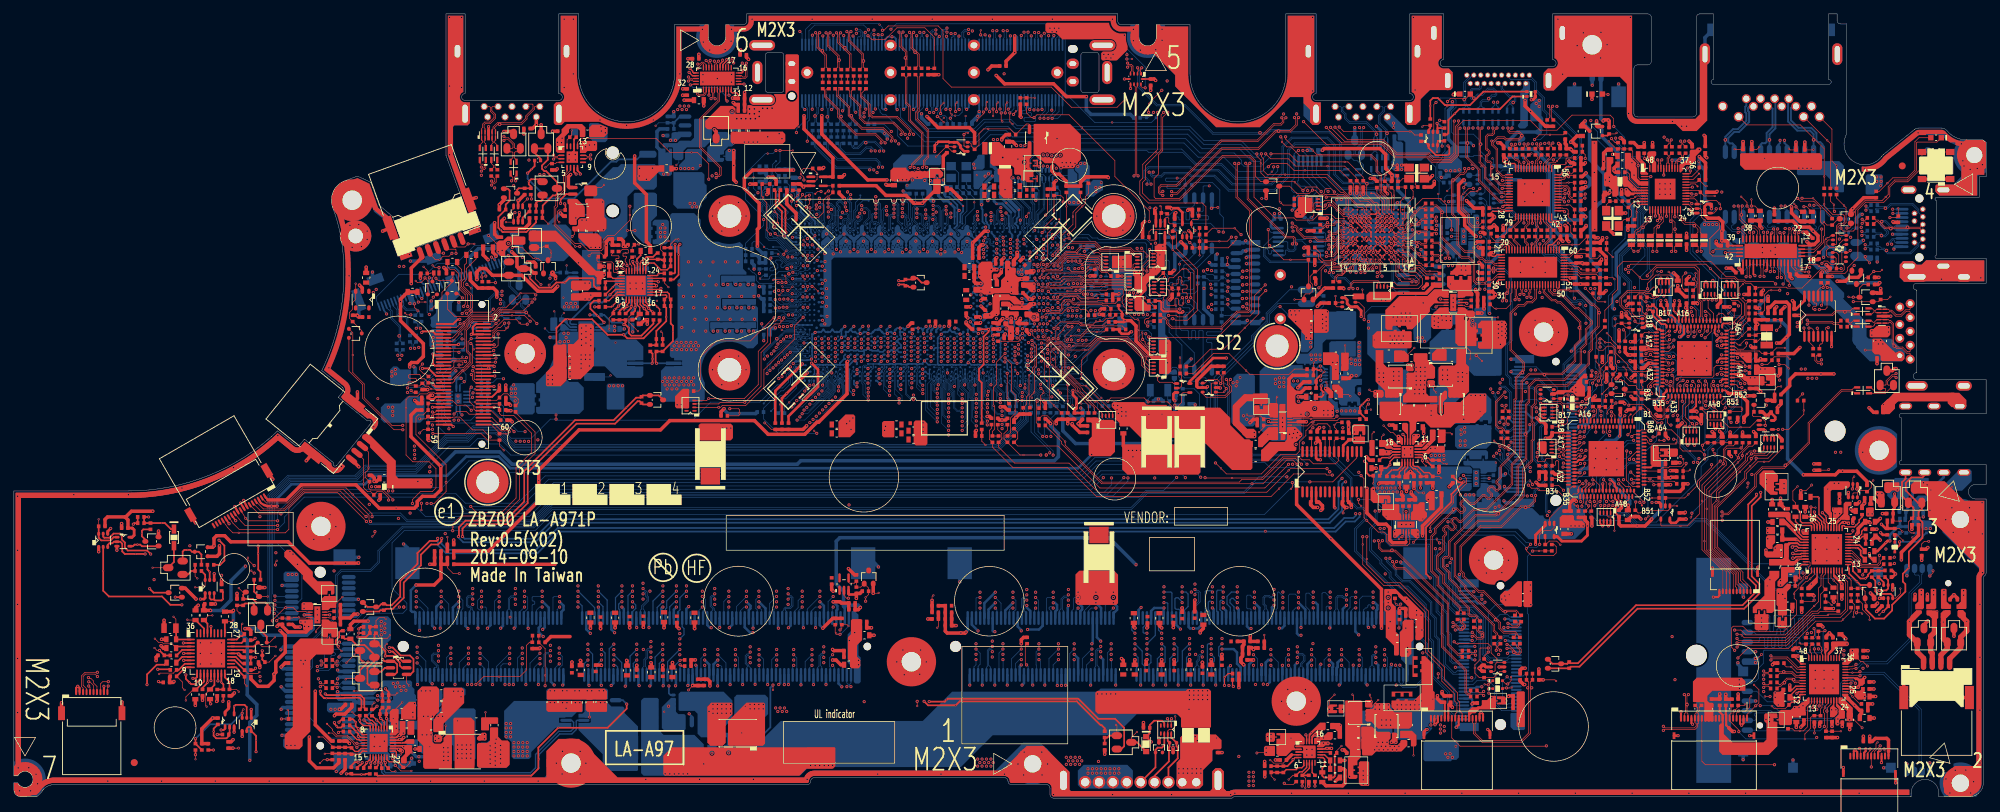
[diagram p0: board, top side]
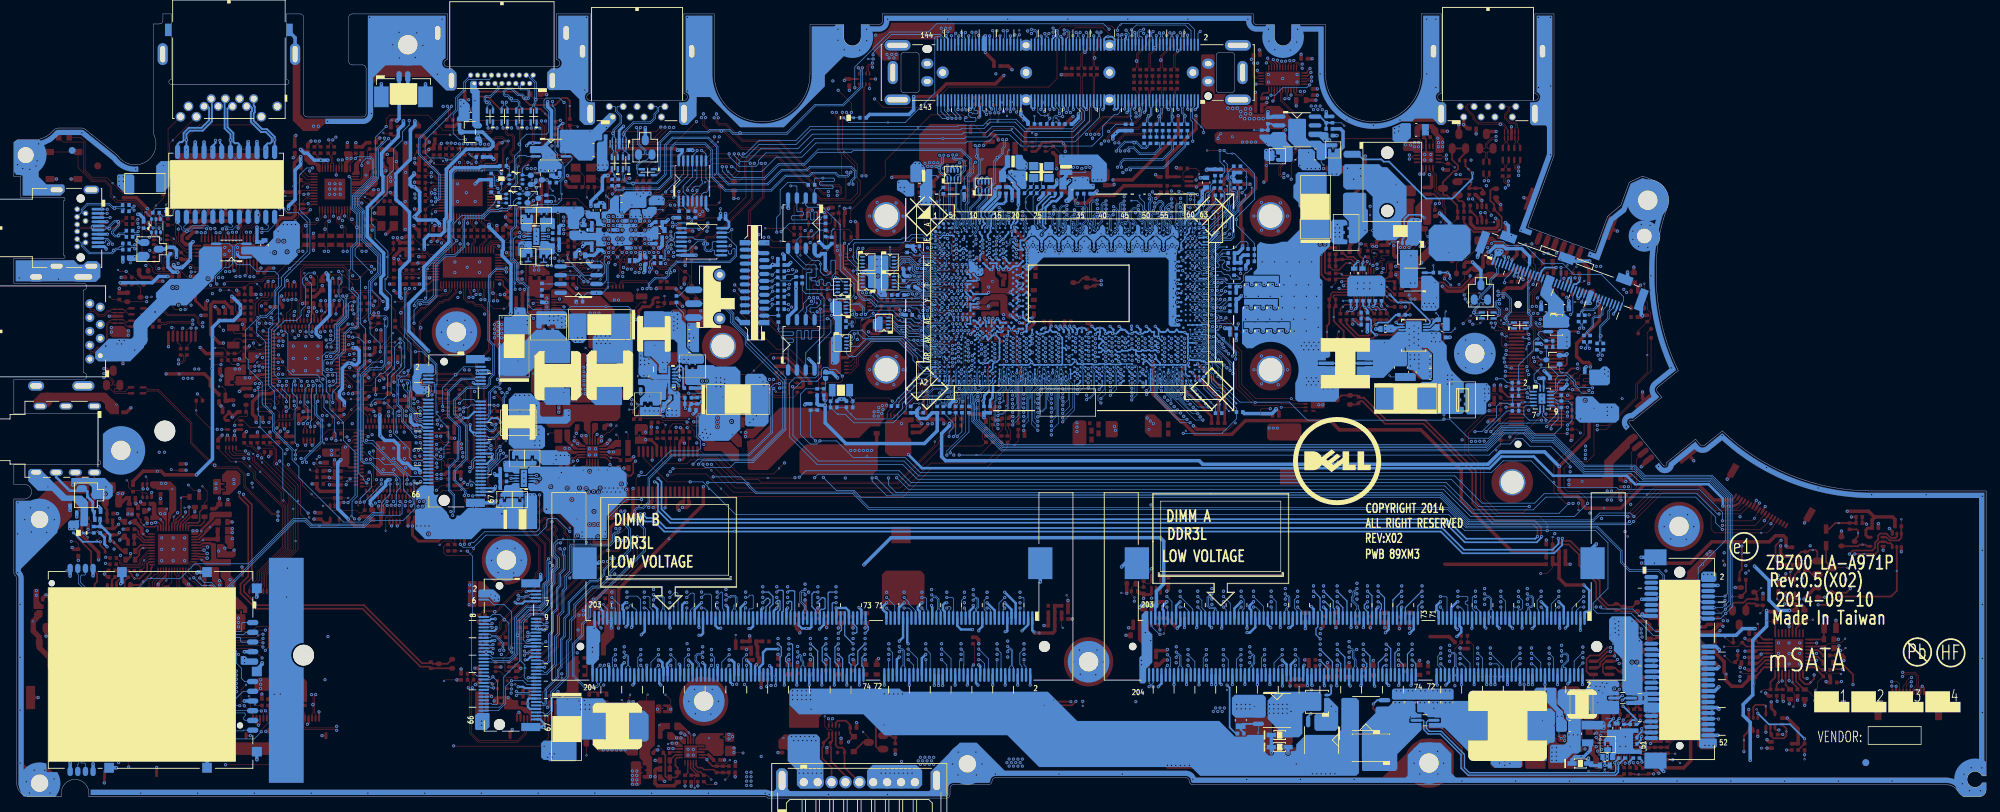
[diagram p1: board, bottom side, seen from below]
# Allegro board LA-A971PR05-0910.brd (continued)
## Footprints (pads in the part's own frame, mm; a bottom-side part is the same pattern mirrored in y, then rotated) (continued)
JUMP_43X39
  custom 0.191x0.191 smd: 1(0,0) 2(0.914,0)
JUMP_43X79
  custom 0.188x0.188 smd: 1(0,0) 2(1.1,0)
JUMP_43X79-NPM
  custom 0.188x0.188 smd: 1(0,0) 2(1.1,0)
JUMP_43X118
  custom 0.187x0.187 smd: 1(0,0) 2(1.1,0)
KC_FBMA-L1_2P-NPM
  rect 1.803x3.404 smd: 1(0,0) 2(3.8,0)
L2N7002WT1G_SC-70-3
  oval 0.711x0.889 smd: 1(0,0) 2(-0.65,-1.9) 3(0.65,-1.9)
L03ESDL5V0CC3-2_SOT23-3
  oval 1.016x1.524 smd: 1(0,0) 2(0.965,2.083) 3(-0.965,2.083)
L05ESDL5V0NA-4_SLP2510P8-10-9
  rect 0.203x0.686 smd: 1(0,0) 2(-0.5,0) 4(-1.5,0) 5(-2,0) 6(-2,-0.875) 7(-1.5,-0.875) 8(-0.5,-0.875) 9(0,-0.875)
  rect 0.406x1.549 smd: 3(-1,-0.437)
L30ESD24VC3-2_SOT23-3
  oval 1.016x1.524 smd: 1(0,0) 2(0.965,2.083) 3(-0.965,2.083)
L_5X5X3_M_2P
  rect 2.159x2.794 smd: 1(0,0) 2(4.35,0)
L_5X5X3_M_2P-NPM
  rect 2.159x2.794 smd: 1(0,0) 2(4.35,0)
LCN_AUF05-1922S10-0019_19P
  round 0.762 hole 0.508: 1(0,0) 2(0.5,1.2) 3(1,0) 4(1.5,1.2) 5(2,0) 6(2.5,1.2) 7(3,0) 8(3.5,1.2) 9(4,0) 10(4.5,1.2) 11(5,0) 12(5.5,1.2) 13(6,0) 14(6.5,1.2) 15(7,0) 16(7.5,1.2) 17(8,0) 18(8.5,1.2) 19(9,0)
  oval 1.397x2.794 hole 0.787x2.21: 20(-2.75,0.77) 21(11.75,0.77)
  oval 1.397x2.591 hole 0.787x2.007: 22(-4.75,-6.08) 23(13.75,-6.08)
LCN_DAN06-K4406-0103_204P
  round 1.092 hole 1.092 unplated: (-65.05,-4.1)
  round 1.6 hole 1.6 unplated: (1.75,-4.1)
  oval 0.356x2.007 smd: 1(0,0) 2(-0.3,-8.2) 3(-0.6,0) 4(-0.9,-8.2) 5(-1.2,0) 6(-1.5,-8.2) 7(-1.8,0) 8(-2.1,-8.2) 9(-2.4,0) 10(-2.7,-8.2) 11(-3,0) 12(-3.3,-8.2) 13(-3.6,0) 14(-3.9,-8.2) 15(-4.2,0) 16(-4.5,-8.2) 17(-4.8,0) 18(-5.1,-8.2) 19(-5.4,0) 20(-5.7,-8.2) 21(-6,0) 22(-6.3,-8.2) 23(-6.6,0) 24(-6.9,-8.2) 25(-7.2,0) 26(-7.5,-8.2) 27(-7.8,0) 28(-8.1,-8.2) 29(-8.4,0) 30(-8.7,-8.2) 31(-9,0) 32(-9.3,-8.2) 33(-9.6,0) 34(-9.9,-8.2) 35(-10.2,0) 36(-10.5,-8.2) 37(-10.8,0) 38(-11.1,-8.2) 39(-11.4,0) 40(-11.7,-8.2) 41(-12,0) 42(-12.3,-8.2) 43(-12.6,0) 44(-12.9,-8.2) 45(-13.2,0) 46(-13.5,-8.2) 47(-13.8,0) 48(-14.1,-8.2) 49(-14.4,0) 50(-14.7,-8.2) 51(-15,0) 52(-15.3,-8.2) 53(-15.6,0) 54(-15.9,-8.2) 55(-16.2,0) 56(-16.5,-8.2) 57(-16.8,0) 58(-17.1,-8.2) 59(-17.4,0) 60(-17.7,-8.2) 61(-18,0) 62(-18.3,-8.2) 63(-18.6,0) 64(-18.9,-8.2) 65(-19.2,0) 66(-19.5,-8.2) 67(-19.8,0) 68(-20.1,-8.2) 69(-20.4,0) 70(-20.7,-8.2) 71(-21,0) 72(-21.3,-8.2) 73(-24,0) 74(-24.3,-8.2) 75(-24.6,0) 76(-24.9,-8.2) 77(-25.2,0) 78(-25.5,-8.2) 79(-25.8,0) 80(-26.1,-8.2) 81(-26.4,0) 82(-26.7,-8.2) 83(-27,0) 84(-27.3,-8.2) 85(-27.6,0) 86(-27.9,-8.2) 87(-28.2,0) 88(-28.5,-8.2) 89(-28.8,0) 90(-29.1,-8.2) 91(-29.4,0) 92(-29.7,-8.2) 93(-30,0) 94(-30.3,-8.2) 95(-30.6,0) 96(-30.9,-8.2) 97(-31.2,0) 98(-31.5,-8.2) 99(-31.8,0) 100(-32.1,-8.2) 101(-32.4,0) 102(-32.7,-8.2) 103(-33,0) 104(-33.3,-8.2) 105(-33.6,0) 106(-33.9,-8.2) 107(-34.2,0) 108(-34.5,-8.2) 109(-34.8,0) 110(-35.1,-8.2) 111(-35.4,0) 112(-35.7,-8.2) 113(-36,0) 114(-36.3,-8.2) 115(-36.6,0) 116(-36.9,-8.2) 117(-37.2,0) 118(-37.5,-8.2) 119(-37.8,0) 120(-38.1,-8.2) 121(-38.4,0) 122(-38.7,-8.2) 123(-39,0) 124(-39.3,-8.2) 125(-39.6,0) 126(-39.9,-8.2) 127(-40.2,0) 128(-40.5,-8.2) 129(-40.8,0) 130(-41.1,-8.2) 131(-41.4,0) 132(-41.7,-8.2) 133(-42,0) 134(-42.3,-8.2) 135(-42.6,0) 136(-42.9,-8.2) 137(-43.2,0) 138(-43.5,-8.2) 139(-43.8,0) 140(-44.1,-8.2) 141(-44.4,0) 142(-44.7,-8.2) 143(-45,0) 144(-45.3,-8.2) 145(-45.6,0) 146(-45.9,-8.2) 147(-46.2,0) 148(-46.5,-8.2) 149(-46.8,0) 150(-47.1,-8.2) 151(-47.4,0) 152(-47.7,-8.2) 153(-48,0) 154(-48.3,-8.2) 155(-48.6,0) 156(-48.9,-8.2) 157(-49.2,0) 158(-49.5,-8.2) 159(-49.8,0) 160(-50.1,-8.2) 161(-50.4,0) 162(-50.7,-8.2) 163(-51,0) 164(-51.3,-8.2) 165(-51.6,0) 166(-51.9,-8.2) 167(-52.2,0) 168(-52.5,-8.2) 169(-52.8,0) 170(-53.1,-8.2) 171(-53.4,0) 172(-53.7,-8.2) 173(-54,0) 174(-54.3,-8.2) 175(-54.6,0) 176(-54.9,-8.2) 177(-55.2,0) 178(-55.5,-8.2) 179(-55.8,0) 180(-56.1,-8.2) 181(-56.4,0) 182(-56.7,-8.2) 183(-57,0) 184(-57.3,-8.2) 185(-57.6,0) 186(-57.9,-8.2) 187(-58.2,0) 188(-58.5,-8.2) 189(-58.8,0) 190(-59.1,-8.2) 191(-59.4,0) 192(-59.7,-8.2) 193(-60,0) 194(-60.3,-8.2) 195(-60.6,0) 196(-60.9,-8.2) 197(-61.2,0) 198(-61.5,-8.2) 199(-61.8,0) 200(-62.1,-8.2) 201(-62.4,0) 202(-62.7,-8.2) 203(-63,0) 204(-63.3,-8.2)
  rect 3.505x4.597 smd: 205(1.15,7.9) 206(-64.45,7.9)
LCN_DAN08-52406-0500_52P
  round 1.6 hole 1.6 unplated: (-0.7,4.1)
  round 1.092 hole 1.092 unplated: (24.3,4.1)
  oval 0.61x2.007 smd: 1(0,0) 2(0.4,8.2) 3(0.8,0) 4(1.2,8.2) 5(1.6,0) 6(2,8.2) 7(2.4,0) 8(2.8,8.2) 9(3.2,0) 10(3.6,8.2) 11(4,0) 12(4.4,8.2) 13(4.8,0) 14(5.2,8.2) 15(5.6,0) 16(6,8.2) 17(9.6,0) 18(10,8.2) 19(10.4,0) 20(10.8,8.2) 21(11.2,0) 22(11.6,8.2) 23(12,0) 24(12.4,8.2) 25(12.8,0) 26(13.2,8.2) 27(13.6,0) 28(14,8.2) 29(14.4,0) 30(14.8,8.2) 31(15.2,0) 32(15.6,8.2) 33(16,0) 34(16.4,8.2) 35(16.8,0) 36(17.2,8.2) 37(17.6,0) 38(18,8.2) 39(18.4,0) 40(18.8,8.2) 41(19.2,0) 42(19.6,8.2) 43(20,0) 44(20.4,8.2) 45(20.8,0) 46(21.2,8.2) 47(21.6,0) 48(22,8.2) 49(22.4,0) 50(22.8,8.2) 51(23.2,0) 52(23.6,8.2)
  rect 2.311x3.2 smd: 53(-2.85,0.6) 54(26.45,0.6)
LED_LTW-193ZDS5_2P
  rect 0.787x0.787 smd: 1(0,0) 2(1.5,0)
LED_LTW-295DSKS-5A_4P
  rect 0.508x0.406 smd: 1(0,0) 2(1.2,0) 3(0,0.7) 4(1.2,0.7)
LP2301ALT1G_SOT23-3
  oval 1.016x1.524 smd: 1(0,0) 2(0.965,2.083) 3(-0.965,2.083)
MEC5085-LZY_DQFN132_11X11
  oval 0.279x0.711 smd: A1(0,0) A2(0.5,0) A3(1,0) A4(1.5,0) A5(2,0) A6(2.5,0) A7(3,0) A8(3.5,0) A9(4,0) A10(4.5,0) A11(5,0) A12(5.5,0) A13(6,0) A14(6.5,0) A15(7,0) A16(7.5,0) A33(7.5,10.9) A34(7,10.9) A35(6.5,10.9) A36(6,10.9) A37(5.5,10.9) A38(5,10.9) A39(4.5,10.9) A40(4,10.9) A41(3.5,10.9) A42(3,10.9) A43(2.5,10.9) A44(2,10.9) A45(1.5,10.9) A46(1,10.9) A47(0.5,10.9) A48(0,10.9)
  oval 0.711x0.279 smd: A17(9.2,1.7) A18(9.2,2.2) A19(9.2,2.7) A20(9.2,3.2) A21(9.2,3.7) A22(9.2,4.2) A23(9.2,4.7) A24(9.2,5.2) A25(9.2,5.7) A26(9.2,6.2) A27(9.2,6.7) A28(9.2,7.2) A29(9.2,7.7) A30(9.2,8.2) A31(9.2,8.7) A32(9.2,9.2) A49(-1.7,9.2) A50(-1.7,8.7) A51(-1.7,8.2) A52(-1.7,7.7) A53(-1.7,7.2) A54(-1.7,6.7) A55(-1.7,6.2) A56(-1.7,5.7) A57(-1.7,5.2) A58(-1.7,4.7) A59(-1.7,4.2) A60(-1.7,3.7) A61(-1.7,3.2) A62(-1.7,2.7) A63(-1.7,2.2) A64(-1.7,1.7)
  oval 0.305x0.61 smd: B1(-0.25,0.85) B2(0.25,0.85) B3(0.75,0.85) B4(1.25,0.85) B5(1.75,0.85) B6(2.25,0.85) B7(2.75,0.85) B8(3.25,0.85) B9(3.75,0.85) B10(4.25,0.85) B11(4.75,0.85) B12(5.25,0.85) B13(5.75,0.85) B14(6.25,0.85) B15(6.75,0.85) B16(7.25,0.85) B17(7.75,0.85) B35(7.75,10.05) B36(7.25,10.05) B37(6.75,10.05) B38(6.25,10.05) B39(5.75,10.05) B40(5.25,10.05) B41(4.75,10.05) B42(4.25,10.05) B43(3.75,10.05) B44(3.25,10.05) B45(2.75,10.05) B46(2.25,10.05) B47(1.75,10.05) B48(1.25,10.05) B49(0.75,10.05) B50(0.25,10.05) B51(-0.25,10.05)
  oval 0.61x0.305 smd: B18(8.35,1.45) B19(8.35,1.95) B20(8.35,2.45) B21(8.35,2.95) B22(8.35,3.45) B23(8.35,3.95) B24(8.35,4.45) B25(8.35,4.95) B26(8.35,5.45) B27(8.35,5.95) B28(8.35,6.45) B29(8.35,6.95) B30(8.35,7.45) B31(8.35,7.95) B32(8.35,8.45) B33(8.35,8.95) B34(8.35,9.45) B52(-0.85,9.45) B53(-0.85,8.95) B54(-0.85,8.45) B55(-0.85,7.95) B56(-0.85,7.45) B57(-0.85,6.95) B58(-0.85,6.45) B59(-0.85,5.95) B60(-0.85,5.45) B61(-0.85,4.95) B62(-0.85,4.45) B63(-0.85,3.95) B64(-0.85,3.45) B65(-0.85,2.95) B66(-0.85,2.45) B67(-0.85,1.95) B68(-0.85,1.45)
  rect 5.004x5.004 smd: C1(3.75,5.45)
MHPC_NS692417_24P
  oval 0.762x2.057 smd: 1(0,0) 2(1.27,0) 3(2.54,0) 4(3.81,0) 5(5.08,0) 6(6.35,0) 7(7.62,0) 8(8.89,0) 9(10.16,0) 10(11.43,0) 11(12.7,0) 12(13.97,0) 13(13.97,9.365) 14(12.7,9.365) 15(11.43,9.365) 16(10.16,9.365) 17(8.89,9.365) 18(7.62,9.365) 19(6.35,9.365) 20(5.08,9.365) 21(3.81,9.365) 22(2.54,9.365) 23(1.27,9.365) 24(0,9.365)
MMBT3904WT1G_SC70-3
  oval 0.711x0.889 smd: 1(0,0) 2(0.65,1.9) 3(-0.65,1.9)
MMST3904-7-F_SOT323-3
  oval 0.711x0.889 smd: 1(0,0) 2(0.65,1.9) 3(-0.65,1.9)
MURAT_BLM15AG102SN1D_2P
  rect 0.457x0.508 smd: 1(0,0) 2(0.85,0)
MURAT_BLM15BB221SN1D_2P
  rect 0.508x0.762 smd: 1(0,0) 2(0.75,0)
MURAT_BLM15BD601SN1D_2P
  rect 0.508x0.762 smd: 1(0,0) 2(0.75,0)
MURAT_BLM15PX181SN1D_2P
  rect 0.508x0.762 smd: 1(0,0) 2(0.75,0)
MURAT_BLM15PX330SN1D_2P
  rect 0.508x0.762 smd: 1(0,0) 2(0.75,0)
MURAT_BLM15PX600SN1D_2P
  rect 0.457x0.508 smd: 1(0,0) 2(0.85,0)
MURAT_DLW21HN900HQ2L_4P
  rect 0.889x0.356 smd: 1(0,0) 2(1.7,0) 3(1.7,0.85) 4(0,0.85)
MURAT_LQM2MPN2R2NG0L_2P
  rect 0.787x1.803 smd: 1(0,0) 2(1.6,0)
NTGD4161PT1G_TSOP6
  oval 0.508x1.422 smd: 1(0,0) 2(0.95,0) 3(1.9,0) 4(1.9,2.35) 5(0.95,2.35) 6(0,2.35)
NTR4502PT1G_SOT23-3
  oval 1.016x1.524 smd: 1(0,0) 2(0.965,2.083) 3(-0.965,2.083)
NX3DV221GM_XQFN10U10_2X1P55
  oval 0.305x0.533 smd: 1(0,0)
  oval 0.254x0.533 smd: 2(0.526,0) 3(1.025,0) 4(1.526,0) 6(1.526,1.475) 7(1.025,1.475) 8(0.526,1.475) 9(0.025,1.475)
  oval 0.533x0.254 smd: 5(1.75,0.738) 10(-0.2,0.738)
OZ777FJ2LN_QFN48_6X6
  oval 0.203x0.889 smd: 1(0,0) 2(0.4,0) 3(0.8,0) 4(1.2,0) 5(1.6,0) 6(2,0) 7(2.4,0) 8(2.8,0) 9(3.2,0) 10(3.6,0) 11(4,0) 12(4.4,0) 25(4.4,6.1) 26(4,6.1) 27(3.6,6.1) 28(3.2,6.1) 29(2.8,6.1) 30(2.4,6.1) 31(2,6.1) 32(1.6,6.1) 33(1.2,6.1) 34(0.8,6.1) 35(0.4,6.1) 36(0,6.1)
  oval 0.889x0.203 smd: 13(5.25,0.85) 14(5.25,1.25) 15(5.25,1.65) 16(5.25,2.05) 17(5.25,2.45) 18(5.25,2.85) 19(5.25,3.25) 20(5.25,3.65) 21(5.25,4.05) 22(5.25,4.45) 23(5.25,4.85) 24(5.25,5.25) 37(-0.85,5.25) 38(-0.85,4.85) 39(-0.85,4.45) 40(-0.85,4.05) 41(-0.85,3.65) 42(-0.85,3.25) 43(-0.85,2.85) 44(-0.85,2.45) 45(-0.85,2.05) 46(-0.85,1.65) 47(-0.85,1.25) 48(-0.85,0.85)
  rect 4.343x4.343 smd: 49(2.2,3.05)
PANAS_ETQP3W2R2WFN_2P
  rect 2.362x3.505 smd: 1(0,0) 2(-6.05,0)
PANAS_ETQP4LR15AFM_4P
  custom 0.686x0.686 smd: 1(0,0) 4(8.357,0)
  rect 2.21x0.508 smd: 2(1.448,0) 3(6.909,0)
PDS5100H-13_POWERDI5-3
  rect 4.851x3.353 smd: 1(0,0)
  rect 1.397x1.397 smd: 2(3.982,-0.92) 3(3.982,0.92)
PI3C3125LEX_TSSOP14
  oval 0.381x1.626 smd: 1(0,0) 2(0.65,0) 3(1.3,0) 4(1.95,0) 5(2.6,0) 6(3.25,0) 7(3.9,0) 8(3.9,5.8) 9(3.25,5.8) 10(2.6,5.8) 11(1.95,5.8) 12(1.3,5.8) 13(0.65,5.8) 14(0,5.8)
PI3L720ZHEX_TQFN42_9X3P5
  oval 0.254x1.041 smd: 1(0,0) 2(0.5,0) 3(1,0) 4(1.5,0) 5(2,0) 6(2.5,0) 7(3,0) 8(3.5,0) 9(4,0) 10(4.5,0) 11(5,0) 12(5.5,0) 13(6,0) 14(6.5,0) 15(7,0) 16(7.5,0) 17(8,0) 22(8,3.45) 23(7.5,3.45) 24(7,3.45) 25(6.5,3.45) 26(6,3.45) 27(5.5,3.45) 28(5,3.45) 29(4.5,3.45) 30(4,3.45) 31(3.5,3.45) 32(3,3.45) 33(2.5,3.45) 34(2,3.45) 35(1.5,3.45) 36(1,3.45) 37(0.5,3.45) 38(0,3.45)
  oval 1.041x0.254 smd: 18(8.475,0.975) 19(8.475,1.475) 20(8.475,1.975) 21(8.475,2.475) 39(-0.475,2.475) 40(-0.475,1.975) 41(-0.475,1.475) 42(-0.475,0.975)
  rect 7.544x2.057 smd: 43(4,1.725)
PI3USB3102ZLEX_TQFN32_6X3
  oval 0.203x0.864 smd: 1(0,0) 2(0.4,0) 3(0.8,0) 4(1.2,0) 5(1.6,0) 6(2,0) 7(2.4,0) 8(2.8,0) 9(3.2,0) 10(3.6,0) 11(4,0) 17(4,3.126) 18(3.6,3.126) 19(3.2,3.126) 20(2.8,3.126) 21(2.4,3.126) 22(2,3.126) 23(1.6,3.126) 24(1.2,3.126) 25(0.8,3.126) 26(0.4,3.126) 27(0,3.126)
  oval 0.864x0.203 smd: 12(5.063,0.763) 13(5.063,1.163) 14(5.063,1.563) 15(5.063,1.963) 16(5.063,2.363) 28(-1.063,2.363) 29(-1.063,1.963) 30(-1.063,1.563) 31(-1.063,1.163) 32(-1.063,0.763)
  rect 5.004x2.007 smd: 33(2,1.563)
PS8338BQFN60GTR-A0_QFN60_5X9
  oval 0.203x1.016 smd: 1(0,0) 2(0.4,0) 3(0.8,0) 4(1.2,0) 5(1.6,0) 6(2,0) 7(2.4,0) 8(2.8,0) 9(3.2,0) 10(3.6,0) 11(4,0) 12(4.4,0) 13(4.8,0) 14(5.2,0) 15(5.6,0) 16(6,0) 17(6.4,0) 18(6.8,0) 19(7.2,0) 20(7.6,0) 31(7.6,4.975) 32(7.2,4.975) 33(6.8,4.975) 34(6.4,4.975) 35(6,4.975) 36(5.6,4.975) 37(5.2,4.975) 38(4.8,4.975) 39(4.4,4.975) 40(4,4.975) 41(3.6,4.975) 42(3.2,4.975) 43(2.8,4.975) 44(2.4,4.975) 45(2,4.975) 46(1.6,4.975) 47(1.2,4.975) 48(0.8,4.975) 49(0.4,4.975) 50(0,4.975)
  oval 1.016x0.203 smd: 21(8.288,0.688) 22(8.288,1.088) 23(8.288,1.488) 24(8.288,1.888) 25(8.288,2.288) 26(8.288,2.688) 27(8.288,3.088) 28(8.288,3.488) 29(8.288,3.888) 30(8.288,4.288) 51(-0.688,4.288) 52(-0.688,3.888) 53(-0.688,3.488) 54(-0.688,3.088) 55(-0.688,2.688) 56(-0.688,2.288) 57(-0.688,1.888) 58(-0.688,1.488) 59(-0.688,1.088) 60(-0.688,0.688)
  rect 7.01x2.997 smd: 61(3.8,2.488)
PS8339BQFN56GTR2-A0_QFN56_7X7
  oval 0.203x1.041 smd: 1(0,0) 2(0.4,0) 3(0.8,0) 4(1.2,0) 5(1.6,0) 6(2,0) 7(2.4,0) 8(2.8,0) 9(3.2,0) 10(3.6,0) 11(4,0) 12(4.4,0) 13(4.8,0) 14(5.2,0) 29(5.2,6.95) 30(4.8,6.95) 31(4.4,6.95) 32(4,6.95) 33(3.6,6.95) 34(3.2,6.95) 35(2.8,6.95) 36(2.4,6.95) 37(2,6.95) 38(1.6,6.95) 39(1.2,6.95) 40(0.8,6.95) 41(0.4,6.95) 42(0,6.95)
  oval 1.041x0.203 smd: 15(6.075,0.875) 16(6.075,1.275) 17(6.075,1.675) 18(6.075,2.075) 19(6.075,2.475) 20(6.075,2.875) 21(6.075,3.275) 22(6.075,3.675) 23(6.075,4.075) 24(6.075,4.475) 25(6.075,4.875) 26(6.075,5.275) 27(6.075,5.675) 28(6.075,6.075) 43(-0.875,6.075) 44(-0.875,5.675) 45(-0.875,5.275) 46(-0.875,4.875) 47(-0.875,4.475) 48(-0.875,4.075) 49(-0.875,3.675) 50(-0.875,3.275) 51(-0.875,2.875) 52(-0.875,2.475) 53(-0.875,2.075) 54(-0.875,1.675) 55(-0.875,1.275) 56(-0.875,0.875)
  rect 4.699x3.912 smd: 57(2.6,3.475)
R0402_0OHM
  rect 0.508x0.559 smd: 1(0,0) 2(0.914,0)
R0603_0OHM
  rect 0.635x0.889 smd: 1(0,0) 2(1.397,0)
R0805_0OHM
  rect 0.813x1.397 smd: 1(0,0) 2(1.702,0)
R_0402
  rect 0.508x0.559 smd: 1(0,0) 2(0.914,0)
R_0603
  rect 0.635x0.889 smd: 1(0,0) 2(1.397,0)
R_0805
  rect 0.813x1.397 smd: 1(0,0) 2(1.702,0)
R_1206
  rect 1.016x1.651 smd: 1(0,0) 2(2.667,0)
R_1206_4P-D
  custom 0.445x0.445 smd: 1(0,0) 4(5.004,0)
  custom 0.114x0.114 smd: 2(1.194,0) 3(3.81,0)
RB751S40T1G_SOD523-2
  rect 0.406x0.406 smd: 1(0,0) 2(1.4,0)
RB751V-40_SOD323-2
  rect 0.787x0.889 smd: 1(0,0) 2(2.14,0)
RP_0804_8P4R
  oval 0.66x0.254 smd: 1(0,0) 2(0,-0.5) 3(0,-1) 4(0,-1.5) 5(1.15,-1.5) 6(1.15,-1) 7(1.15,-0.5) 8(1.15,0)
RT8207MZQW_WQFN20_3X3
  oval 0.203x0.889 smd: 1(0,0) 2(0.4,0) 3(0.8,0) 4(1.2,0) 5(1.6,0) 11(1.6,3.1) 12(1.2,3.1) 13(0.8,3.1) 14(0.4,3.1) 15(0,3.1)
  oval 0.889x0.203 smd: 6(2.35,0.75) 7(2.35,1.15) 8(2.35,1.55) 9(2.35,1.95) 10(2.35,2.35) 16(-0.75,2.35) 17(-0.75,1.95) 18(-0.75,1.55) 19(-0.75,1.15) 20(-0.75,0.75)
  rect 1.702x1.702 smd: 21(0.8,1.55)
RT9818A-44GU3_SC70-3
  oval 0.61x0.787 smd: 1(0,0) 2(-0.65,-1.9) 3(0.65,-1.9)
SAMTE_BSH-030-01-L-D-A_60P
  round 1.016 hole 1.016 unplated: (-2.81,5.53) (17.316,5.53)
  oval 0.279x2.261 smd: 1(0,0) 2(0,5.728) 3(0.5,0) 4(0.5,5.728) 5(1,0) 6(1,5.728) 7(1.5,0) 8(1.5,5.728) 9(2,0) 10(2,5.728) 11(2.5,0) 12(2.5,5.728) 13(3,0) 14(3,5.728) 15(3.5,0) 16(3.5,5.728) 17(4,0) 18(4,5.728) 19(4.5,0) 20(4.5,5.728) 21(5,0) 22(5,5.728) 23(5.5,0) 24(5.5,5.728) 25(6,0) 26(6,5.728) 27(6.5,0) 28(6.5,5.728) 29(7,0) 30(7,5.728) 31(7.5,0) 32(7.5,5.728) 33(8,0) 34(8,5.728) 35(8.5,0) 36(8.5,5.728) 37(9,0) 38(9,5.728) 39(9.5,0) 40(9.5,5.728) 41(10,0) 42(10,5.728) 43(10.5,0) 44(10.5,5.728) 45(11,0) 46(11,5.728) 47(11.5,0) 48(11.5,5.728) 49(12,0) 50(12,5.728) 51(12.5,0) 52(12.5,5.728) 53(13,0) 54(13,5.728) 55(13.5,0) 56(13.5,5.728) 57(14,0) 58(14,5.728) 59(14.5,0) 60(14.5,5.728)
SANTA_130456-511_13P-T
  round 1.295 hole 0.889: 1(0,0) 2(1.02,1.1) 3(2.04,0) 4(3.06,1.1) 5(4.08,0) 6(5.1,1.1) 7(6.12,0) 8(7.14,1.1)
  round 1.397 hole 0.991: 9(-3.395,1.1) 10(-1.105,2.6) 11(8.245,2.6) 12(9.39,1.1) 13(10.535,2.6)
  oval 1.473x3.15 hole 0.711x2.388: 14(13.095,-6.42) 16(-5.955,-6.42)
  rect 0.889x1.803 smd: 15(12.32,-9.92) 17(-5.18,-9.92)
SANTA_373070-2_9P
  round 1.016 hole 0.711: 1(0,0) 2(-2.5,0) 3(-4.5,0) 4(-7,0) 5(-7.5,-1.5) 6(-5.5,-1.5) 7(-3.5,-1.5) 8(-1.5,-1.5) 9(0.5,-1.5)
  oval 1.397x3.2 hole 0.787x2.591: 10(-10.25,-0.47) 11(3.25,-0.47)
  oval 1.397x2.388 hole 0.787x1.803: 12(-11.35,-9.47) 13(4.35,-9.47)
SDMK0340L-7-F_SOD323-2
  rect 1.346x0.66 smd: 1(0,0) 2(2.4,0)
SHORTPADS
  custom 0.19x0.19 smd: 1(-0.483,0) 2(0.483,0)
SI2301CDS-T1-GE3_SOT23-3
  oval 1.016x1.524 smd: 1(0,0) 2(0.965,2.083) 3(-0.965,2.083)
SI3456DDV-T1-GE3_TSOP6
  oval 0.508x1.422 smd: 1(0,0) 2(0.95,0) 3(1.9,0) 4(1.9,2.44) 5(0.95,2.44) 6(0,2.44)
SI4835DDY-T1-GE3_SO8
  oval 0.635x1.727 smd: 1(0,0) 2(1.27,0) 3(2.54,0) 4(3.81,0) 5(3.81,5.285) 6(2.54,5.285) 7(1.27,5.285) 8(0,5.285)
SI7121DN-T1-GE3_POWERPAK8-5
  oval 0.406x0.991 smd: 1(0,0) 2(0.66,0) 3(1.32,0) 4(1.98,0)
  custom 0.559x0.559 smd: 5(0.99,2.247)
SI7716ADN-T1-GE3_POWERPAK8-5
  oval 0.406x0.991 smd: 1(0,0) 2(0.66,0) 3(1.32,0) 4(1.98,0)
  custom 0.559x0.559 smd: 5(0.99,2.247)
SINGA_2SJ3080-003111F_6P
  oval 0.991x1.905 hole 0.61x1.397: 1(0,0) 2(-9.55,5.5) 3(0,7.8) 4(-9.55,8.4) 5(-9.55,0) 6(-9.55,2.75) 7(0,4.1)
SIS412DN-T1-GE3_POWERPAK8-5
  oval 0.406x0.991 smd: 1(0,0) 2(0.66,0) 3(1.32,0) 4(1.98,0)
  custom 0.559x0.559 smd: 5(0.99,2.247)
SW_SKRBAAE010_4P
  rect 0.889x1.219 smd: 1(0,0) 2(3.9,0) 3(0,4.075) 4(3.9,4.075)
SW_SS3-CMFTQR9_3P
  oval 0.991x2.489 smd: 1(0,0) 2(2,0) 3(4,0)
  round 1.651 hole 0.889: 4(-0.15,-3.75) 5(6.15,-3.75)
SYX198DQNC_QFN10_3X3
  oval 0.254x0.61 smd: 1(0,0) 2(0.45,0) 3(0.9,0) 4(1.35,0) 5(1.8,0) 6(2.25,0)
  rect 1.168x0.254 smd: 7(2.19,-0.675)
  rect 0.914x2.007 smd: 8(2.065,-2)
  custom 0.482x0.482 smd: 9(1.103,-1.775)
  rect 0.787x1.143 smd: 10(0.113,-1.6)
T-SOL_156-2000302608_19P_NR-S
  round 0.889 hole 0.889 unplated: (-7.075,-28.925) (13.425,-1.825)
  oval 0.787x1.651 smd: 1(0,0) 2(1.4,0) 3(2.8,0) 4(4.2,0) 5(7.1,0) 6(9.9,0) 7(11.3,0) 8(12.7,0) 9(-1.4,0) 18(8.5,0) 19(14.1,0)
  oval 1.346x0.787 smd: 10(-9.2,-22.975) 11(-9.2,-24.075) 12(-9.2,-25.175) 13(-9.2,-26.275) 14(20.05,-26.275) 15(20.05,-25.175) 16(20.05,-24.075) 17(20.05,-22.975)
  rect 1.397x1.448 smd: 20(17.2,0.6) 21(5.65,0.6) 22(-6.35,0.6)
  rect 1.448x1.397 smd: 23(19.525,-6.575) 24(-8.675,-6.575) 25(19.525,-20.675) 26(-8.675,-18.825)
TAITW_PUBAUE-09FLBS1FF4H0_9P-T
  round 1.295 hole 0.711: 1(0,0) 2(-2.5,0) 3(-4.5,0) 4(-7,0) 5(-7.5,-1.5) 6(-5.5,-1.5) 7(-3.5,-1.5) 8(-1.5,-1.5) 9(0.5,-1.5)
  oval 1.397x3.2 hole 0.787x2.591: 10(4.35,-2.43) 11(-11.35,-2.43)
  oval 1.397x2.311 hole 0.787x1.702: 12(-11.35,-9.23) 13(4.35,-9.23)
TAIYO_BRC2012T4R7MD_2P
  rect 0.61x1.448 smd: 1(0,0) 2(1.6,0)
TAIYO_FBMJ4516HS720NT_2P
  rect 1.549x1.854 smd: 1(0,0) 2(3.95,0)
TC7SH08FU_SSOP5
  oval 0.406x0.787 smd: 1(0,0) 2(0.65,0) 3(1.3,0) 4(1.3,1.9) 5(0,1.9)
TOKO_FDVE1040-H-3R3M-P3_2P
  rect 3.81x3.988 smd: 1(0,0) 2(9.8,0)
TPC12
  round 0.305 smd: 1(0,0)
TPS2544RTER_WQFN16_3X3
  oval 0.254x0.889 smd: 1(0,0) 2(0.5,0) 3(1,0) 4(1.5,0) 9(1.5,3.1) 10(1,3.1) 11(0.5,3.1) 12(0,3.1)
  oval 0.889x0.254 smd: 5(2.3,0.8) 6(2.3,1.3) 7(2.3,1.8) 8(2.3,2.3) 13(-0.8,2.3) 14(-0.8,1.8) 15(-0.8,1.3) 16(-0.8,0.8)
  rect 1.651x1.651 smd: 17(0.75,1.55)
TPS22966DPUR_SON14_2X3
  oval 0.203x0.762 smd: 1(0,0) 2(0.4,0) 3(0.8,0) 4(1.2,0) 5(1.6,0) 6(2,0) 7(2.4,0) 8(2.4,2.05) 9(2,2.05) 10(1.6,2.05) 11(1.2,2.05) 12(0.8,2.05) 13(0.4,2.05) 14(0,2.05)
  rect 2.489x0.889 smd: 15(1.2,1.025)
TPS51285BRUKR_QFN20_3X3
  oval 0.203x1.016 smd: 1(0,0) 2(0.4,0) 3(0.8,0) 4(1.2,0) 5(1.6,0) 11(1.6,2.975) 12(1.2,2.975) 13(0.8,2.975) 14(0.4,2.975) 15(0,2.975)
  oval 1.016x0.203 smd: 6(2.288,0.688) 7(2.288,1.088) 8(2.288,1.488) 9(2.288,1.888) 10(2.288,2.288) 16(-0.688,2.288) 17(-0.688,1.888) 18(-0.688,1.488) 19(-0.688,1.088) 20(-0.688,0.688)
  rect 1.702x1.702 smd: 21(0.8,1.488)
TPS51622RSM_QFN32_4X4
  oval 0.203x0.914 smd: 1(0,0) 2(0.4,0) 3(0.8,0) 4(1.2,0) 5(1.6,0) 6(2,0) 7(2.4,0) 8(2.8,0) 17(2.8,4.077) 18(2.4,4.077) 19(2,4.077) 20(1.6,4.077) 21(1.2,4.077) 22(0.8,4.077) 23(0.4,4.077) 24(0,4.077)
  oval 0.914x0.203 smd: 9(3.438,0.639) 10(3.438,1.039) 11(3.438,1.438) 12(3.438,1.838) 13(3.438,2.239) 14(3.438,2.639) 15(3.438,3.039) 16(3.438,3.438) 25(-0.639,3.438) 26(-0.639,3.039) 27(-0.639,2.639) 28(-0.639,2.239) 29(-0.639,1.838) 30(-0.639,1.438) 31(-0.639,1.039) 32(-0.639,0.639)
  rect 2.794x2.794 smd: 33(1.4,2.039)
TS5A63157DCKR_SC70-6
  oval 0.406x0.889 smd: 1(0,0) 2(0.65,0) 3(1.3,0) 4(1.3,2.2) 5(0.65,2.2) 6(0,2.2)
TVNST52302AB0_SOT523-3
  oval 0.508x0.559 smd: 1(0,0) 2(-0.5,-1.4) 3(0.5,-1.4)
TYCO_2-1775293-2_2P
  oval 0.787x1.6 smd: 1(0,0) 2(-1.25,0)
  rect 2.108x2.997 smd: 3(2.55,2.9) 4(-3.8,2.9)
VMM3320BJGR_BGA_168P-NH
  round 0.279 smd: A1(0,0) A2(0.65,0) A3(1.3,0) A4(1.95,0) A5(2.6,0) A6(3.25,0) A7(3.9,0) A8(4.55,0) A9(5.2,0) A10(5.85,0) A11(6.5,0) A12(7.15,0) A13(7.8,0) A14(8.45,0) B1(0,-0.65) B2(0.65,-0.65) B3(1.3,-0.65) B4(1.95,-0.65) B5(2.6,-0.65) B6(3.25,-0.65) B7(3.9,-0.65) B8(4.55,-0.65) B9(5.2,-0.65) B10(5.85,-0.65) B11(6.5,-0.65) B12(7.15,-0.65) B13(7.8,-0.65) B14(8.45,-0.65) C1(0,-1.3) C2(0.65,-1.3) C3(1.3,-1.3) C4(1.95,-1.3) C5(2.6,-1.3) C6(3.25,-1.3) C7(3.9,-1.3) C8(4.55,-1.3) C9(5.2,-1.3) C10(5.85,-1.3) C11(6.5,-1.3) C12(7.15,-1.3) C13(7.8,-1.3) C14(8.45,-1.3) D1(0,-1.95) D2(0.65,-1.95) D3(1.3,-1.95) D4(1.95,-1.95) D5(2.6,-1.95) D6(3.25,-1.95) D7(3.9,-1.95) D8(4.55,-1.95) D9(5.2,-1.95) D10(5.85,-1.95) D11(6.5,-1.95) D12(7.15,-1.95) D13(7.8,-1.95) D14(8.45,-1.95) E1(0,-2.6) E2(0.65,-2.6) E3(1.3,-2.6) E4(1.95,-2.6) E5(2.6,-2.6) E6(3.25,-2.6) E7(3.9,-2.6) E8(4.55,-2.6) E9(5.2,-2.6) E10(5.85,-2.6) E11(6.5,-2.6) E12(7.15,-2.6) E13(7.8,-2.6) E14(8.45,-2.6) F1(0,-3.25) F2(0.65,-3.25) F3(1.3,-3.25) F4(1.95,-3.25) F5(2.6,-3.25) F6(3.25,-3.25) F7(3.9,-3.25) F8(4.55,-3.25) F9(5.2,-3.25) F10(5.85,-3.25) F11(6.5,-3.25) F12(7.15,-3.25) F13(7.8,-3.25) F14(8.45,-3.25) G1(0,-3.9) G2(0.65,-3.9) G3(1.3,-3.9) G4(1.95,-3.9) G5(2.6,-3.9) G6(3.25,-3.9) G7(3.9,-3.9) G8(4.55,-3.9) G9(5.2,-3.9) G10(5.85,-3.9) G11(6.5,-3.9) G12(7.15,-3.9) G13(7.8,-3.9) G14(8.45,-3.9) H1(0,-4.55) H2(0.65,-4.55) H3(1.3,-4.55) H4(1.95,-4.55) H5(2.6,-4.55) H6(3.25,-4.55) H7(3.9,-4.55) H8(4.55,-4.55) H9(5.2,-4.55) H10(5.85,-4.55) H11(6.5,-4.55) H12(7.15,-4.55) H13(7.8,-4.55) H14(8.45,-4.55) J1(0,-5.2) J2(0.65,-5.2) J3(1.3,-5.2) J4(1.95,-5.2) J5(2.6,-5.2) J6(3.25,-5.2) J7(3.9,-5.2) J8(4.55,-5.2) J9(5.2,-5.2) J10(5.85,-5.2) J11(6.5,-5.2) J12(7.15,-5.2) J13(7.8,-5.2) J14(8.45,-5.2) K1(0,-5.85) K2(0.65,-5.85) K3(1.3,-5.85) K4(1.95,-5.85) K5(2.6,-5.85) K6(3.25,-5.85) K7(3.9,-5.85) K8(4.55,-5.85) K9(5.2,-5.85) K10(5.85,-5.85) K11(6.5,-5.85) K12(7.15,-5.85) K13(7.8,-5.85) K14(8.45,-5.85) L1(0,-6.5) L2(0.65,-6.5) L3(1.3,-6.5) L4(1.95,-6.5) L5(2.6,-6.5) L6(3.25,-6.5) L7(3.9,-6.5) L8(4.55,-6.5) L9(5.2,-6.5) L10(5.85,-6.5) L11(6.5,-6.5) L12(7.15,-6.5) L13(7.8,-6.5) L14(8.45,-6.5) M1(0,-7.15) M2(0.65,-7.15) M3(1.3,-7.15) M4(1.95,-7.15) M5(2.6,-7.15) M6(3.25,-7.15) M7(3.9,-7.15) M8(4.55,-7.15) M9(5.2,-7.15) M10(5.85,-7.15) M11(6.5,-7.15) M12(7.15,-7.15) M13(7.8,-7.15) M14(8.45,-7.15)
W25Q32FVSSIQ_SO8
  oval 0.635x1.676 smd: 1(0,0) 2(1.27,0) 3(2.54,0) 4(3.81,0) 5(3.81,7.25) 6(2.54,7.25) 7(1.27,7.25) 8(0,7.25)
W25Q64FVSSIQ_SO8
  oval 0.635x1.676 smd: 1(0,0) 2(1.27,0) 3(2.54,0) 4(3.81,0) 5(3.81,7.25) 6(2.54,7.25) 7(1.27,7.25) 8(0,7.25)
W25X10BVSNIG_SO8
  oval 0.635x1.854 smd: 1(0,0) 2(1.27,0) 3(2.54,0) 4(3.81,0) 5(3.81,5.165) 6(2.54,5.165) 7(1.27,5.165) 8(0,5.165)
WGI217LM-QPN9-A2_QFN48_6X6
  oval 0.203x1.041 smd: 1(0,0) 2(0.4,0) 3(0.8,0) 4(1.2,0) 5(1.6,0) 6(2,0) 7(2.4,0) 8(2.8,0) 9(3.2,0) 10(3.6,0) 11(4,0) 12(4.4,0) 25(4.4,5.95) 26(4,5.95) 27(3.6,5.95) 28(3.2,5.95) 29(2.8,5.95) 30(2.4,5.95) 31(2,5.95) 32(1.6,5.95) 33(1.2,5.95) 34(0.8,5.95) 35(0.4,5.95) 36(0,5.95)
  oval 1.041x0.203 smd: 13(5.175,0.775) 14(5.175,1.175) 15(5.175,1.575) 16(5.175,1.975) 17(5.175,2.375) 18(5.175,2.775) 19(5.175,3.175) 20(5.175,3.575) 21(5.175,3.975) 22(5.175,4.375) 23(5.175,4.775) 24(5.175,5.175) 37(-0.775,5.175) 38(-0.775,4.775) 39(-0.775,4.375) 40(-0.775,3.975) 41(-0.775,3.575) 42(-0.775,3.175) 43(-0.775,2.775) 44(-0.775,2.375) 45(-0.775,1.975) 46(-0.775,1.575) 47(-0.775,1.175) 48(-0.775,0.775)
  rect 2.997x2.997 smd: 49(2.2,2.975)
Y_7V25000034_4P
  rect 1.397x1.194 smd: 1(0,0) 2(2.2,0) 3(2.2,1.8) 4(0,1.8)
Y_9H03220008_2P
  rect 0.991x1.803 smd: 1(0,0) 2(2.5,0)
Y_Q13FC135000040_2P
  rect 0.991x1.803 smd: 1(0,0) 2(2.5,0)
Y_X1E000021042600_4P
  rect 1.397x1.143 smd: 1(0,0) 2(2.2,0) 3(2.2,1.6) 4(0,1.6)
Y_X3G024000DC1H_4P
  rect 1.397x1.194 smd: 1(0,0) 2(2.2,0) 3(2.2,1.7) 4(0,1.7)

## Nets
0.675V_DDR_VTT_ON: CC110.1 PR210.1 QD1.2 RD9.2 RD14.2 UD1.4
1.05V_M_PWRGD: PR313.1 RC27.1
1.05V_MODPHY_EN: CZ25.1 QZ6.3 QZ10.3 RZ5.2
1.05V_MP_PWROK: PR313.2 PR315.2 PU300.2
1.5VSP: PC403.1 PC404.1 PJP401.1 PR402.1 PU400.3 PU400.4
1.35V_B+: PC200.1 PC201.1 PC203.1 PC206.1 PJP200.2 PQ200.5 PR206.1
1.35V_FB: PC213.1 PR205.1 PR209.1 PU200.6
3.3V_CAM_EN#: QZ1.2 RC174.1 UC1.AM4
3.3V_HDD_EN: RN6.2 RN7.1 UC1.K2 UZ8.5
3.3V_TP_EN: RPC3.7 UC1.L5
3.3V_TS_EN: QV7.2 RPC4.7 UC1.N7
3.3V_WWAN_EN: RZ40.2 UE1.B42 UZ2.3
+0.9V_LAN: CL3.1 CL4.1 CL8.1 CL9.1 CL10.1 CL11.1 CL12.1 LL1.2 UL1.8 UL1.11 UL1.16 UL1.22 UL1.37 UL1.40 UL1.43 UL1.46 UL1.47
+0.675V_DDR_VTT: CD24.1 CD25.1 CD26.1 CD27.1 CD28.1 CD29.1 CD57.1 CD58.1 CD59.1 CD60.1 CD61.1 CD62.1 JDIMM1.203 JDIMM1.204 JDIMM2.203 JDIMM2.204 PJP202.2
+0.675V_P: PC205.1 PJP202.1 PU200.2 PU200.20
+1.2V_LDO: CR9.2 CR10.2 CR13.2 CR18.2 CR19.2 CR21.2 CR22.2 UR1.1 UR1.10 UR1.28 UR1.31 UR1.36 UR1.41
+1.05V_M: CC39.1 CC61.1 CC62.1 PJP300.2 QZ6.1 QZ6.2 QZ6.5 QZ6.6 RC18.2 RC300.1 RPC21.5 RPC21.6 RPC21.7 RZ52.1 UC1.AE9 UC1.AF9 UC1.AG8 UC1.AG13 UC1.AG14 UZ7.1 UZ7.2
+1.05V_MODPHY: CZ38.1 LC1.1 LC2.1 PJP36.2 PJP51.1 QZ6.4
+1.05V_MODPHY_PCH: CC40.1 CC43.1 CC44.1 PJP51.2 UC1.K9 UC1.L10 UC1.M9
+1.05V_MP: PC304.1 PC305.1 PC306.1 PC307.1 PC308.1 PJP300.1 PL301.2 PR307.1
+1.05V_RUN: CC18.1 CC19.1 CC41.1 CC42.1 CC53.1 CC58.1 CC59.1 CC60.1 CC70.1 CC71.1 CC72.1 CC79.1 CC84.1 CC85.1 CE25.1 JXDP1.43 JXDP1.44 LC3.1 LC4.1 LC5.1 PJP23.1 PJP24.1 PJP36.1 RC117.1 RC124.1 RC125.1 RC126.1 RC127.1 RC196.2 RC197.1 RE70.1 RZ52.2 RZ53.1 UC1.AE8 UC1.AF22 UC1.AG16 UC1.AG17 UC1.H11 UC1.H15 UC1.J11 UC1.J17 UC1.N8 UC1.P9 UC1.R21 UC1.T21 UE2.B51 UV13.1 UV13.2
+1.5V_RUN: PJP401.2 RA3.1 UC1.J15
+1.5V_RUN_AUDIO: CA16.1 RA3.2 UA1.40
+1.05V_RUN_UZ7: CZ39.2 RZ53.2 UZ7.13 UZ7.14
+1.05V_RUN_VMM: LV22.1 LV23.1 PJP24.2 PJP28.1
+1.05V_VCCST: CC36.1 CC37.1 PC511.1 PJP23.2 PR527.1 PR528.1 PR529.1 RC25.1 RC114.1 RC116.1 RC199.1 RC202.2 RC204.1 RC208.1 UC1.AC22 UC1.AE22 UC1.AE23
+1.5V_VIN: PC401.1 PJP400.2 PU400.5 PU400.9
+1.05V_VMM_UV10: CV518.1 PJP28.2 UV13.13 UV13.14
+1.05V_VMM_VDD: CV82.1 CV83.1 CV84.1 CV85.1 CV86.1 CV87.1 CV88.1 CV89.1 LV22.2 UV8.C8 UV8.C9 UV8.D3 UV8.E3 UV8.E5 UV8.E6 UV8.E7 UV8.E8 UV8.E9 UV8.F12 UV8.G3 UV8.G12 UV8.H6 UV8.H7 UV8.H8 UV8.H9 UV8.J3
+1.05V_VMM_VDDTX: CV90.1 CV91.1 CV92.1 CV93.1 LV23.2 UV8.C6 UV8.C7 UV8.D12 UV8.E12 UV8.F3 UV8.J2 UV8.J10 UV8.K8 UV8.K9 UV8.K10
+1.8V_RUN_CARD: CR34.1 JSD1.14 UR1.24
+1.35V_MEM: CC23.2 CC25.1 CC26.1 CC27.1 CC28.1 CC29.1 CC30.1 CC31.1 CC32.1 CC33.1 CC34.1 CD2.1 CD3.1 CD4.1 CD7.1 CD8.1 CD9.1 CD10.1 CD11.1 CD12.1 CD13.1 CD14.1 CD15.1 CD16.1 CD17.1 CD18.1 CD19.1 CD20.1 CD30.1 CD37.1 CD38.1 CD39.1 CD40.1 CD41.1 CD42.1 CD43.1 CD44.1 CD45.1 CD46.1 CD47.1 CD48.1 CD49.1 CD50.1 CD51.1 CD52.1 CD53.1 JDIMM1.75 JDIMM1.76 JDIMM1.81 JDIMM1.82 JDIMM1.87 JDIMM1.88 JDIMM1.93 JDIMM1.94 JDIMM1.99 JDIMM1.100 JDIMM1.105 JDIMM1.106 JDIMM1.111 JDIMM1.112 JDIMM1.117 JDIMM1.118 JDIMM1.123 JDIMM1.124 JDIMM2.75 JDIMM2.76 JDIMM2.81 JDIMM2.82 JDIMM2.87 JDIMM2.88 JDIMM2.93 JDIMM2.94 JDIMM2.99 JDIMM2.100 JDIMM2.105 JDIMM2.106 JDIMM2.111 JDIMM2.112 JDIMM2.117 JDIMM2.118 JDIMM2.123 JDIMM2.124 PJP203.2 PJP204.2 QD1.1 RD2.1 RD4.1 RD18.1 RD22.1 UC1.AH26 UC1.AJ31 UC1.AJ33 UC1.AJ37 UC1.AN33 UC1.AP43 UC1.AR48 UC1.AY35 UC1.AY40 UC1.AY44 UC1.AY50 UD1.5
+1.35V_MEN_P: PC207.1 PC213.2 PC214.1 PJP201.2 PJP203.1 PJP204.1 PL200.1 PR205.2 PU200.5
+3.3V_ALW: C263.1 CC35.1 CE1.1 CE21.1 CV10.1 CZ28.1 CZ34.1 CZ48.1 JKBTP1.6 JSH1.12 PC310.1 PC805.2 PJP14.1 PJP15.1 PJP102.2 PR2.1 PR8.2 PR107.2 PR306.1 PR315.1 PR740.2 PR810.1 PR813.1 PR815.1 PR859.2 PR895.1 PU300.7 PU804.5 RC213.1 RC217.1 RE5.1 RE8.1 RE9.1 RE10.1 RE11.1 RE12.1 RE25.1 RE35.1 RE36.1 RE37.1 RE43.1 RE63.1 RE68.1 RE69.1 RE71.1 RE72.1 RE73.1 RE74.1 RE75.1 RE79.1 RE81.1 RE83.1 RE87.2 RE276.1 RPE3.7 RPE3.8 RPE4.5 RPE4.6 RPE4.7 RPE4.8 RPE5.7 RPE6.6 RPE6.7 RPE6.8 RPE7.5 RPE7.6 RPE7.7 RPE7.8 RPE9.5 RPE9.6 RPE9.7 RPE9.8 RV701.1 RZ22.1 RZ24.1 RZ31.1 UC8.5 UL3.1 UL3.2 UL3.6 UL3.7 UV24.4 UV24.5 UZ2.1 UZ2.2 UZ2.6 UZ2.7 UZ6.5 UZ7.6 UZ7.7 UZ8.1 UZ8.2 UZ9.6 UZ9.7 UZ10.5 UZ11.5
+3.3V_ALW2: PC100.2 PC810.2 PR103.2 PR819.2 PR829.1 PR846.1 PR855.1 PR864.1 PU100.3 PU806.5 R272.2 RE57.2 RZ16.1 UC6.5
+3.3V_ALW_PCH: CC57.1 CC63.1 JAPS1.1 PJP29.2 RC2.1 RC33.1 RC34.1 RC79.1 RC81.1 RC82.1 RC120.2 RC179.1 RC212.1 RC216.1 RC245.2 RPC5.1 RPC5.2 RPC5.3 RPC5.4 RPC7.1 RPC7.2 RPC7.3 RPC7.4 RPC10.1 RPC10.2 RPC10.3 RPC10.4 RPC14.5 RPC14.6 RPC14.7 RPC14.8 RPC19.5 RPC19.6 RPC19.7 RPC19.8 UC1.AA9 UC1.AC9 UC1.AE20 UC1.AE21 UC1.AH14
+3.3V_ALW_PCH_UZ7: CZ56.1 PJP29.1 UZ7.8 UZ7.9
+3.3V_ALW_UE1: CE2.1 CE3.1 CE4.1 CE5.1 CE6.1 PJP14.2 UE1.A17 UE1.A43 UE1.A54 UE1.B5 UE1.B30
+3.3V_ALW_UE2: CE13.1 CE14.1 CE15.1 CE16.1 CE17.1 CE18.1 CE19.1 CE20.1 CE22.1 CE23.1 PJP15.2 UE2.A11 UE2.A22 UE2.A26 UE2.A41 UE2.A52 UE2.A58 UE2.B3 UE2.B35
+3.3V_ALWP: PC113.1 PJP102.1 PL101.1 PR100.1
+3.3V_CAM: CZ1.1 JEDP1.11 QZ1.1
+3.3V_HDD: CN1.1 CN2.1 JMINI3.2 JMINI3.24 JMINI3.39 JMINI3.41 JMINI3.52 PJP20.2 RN1.1
+3.3V_HDD_UZ8: CZ43.1 PJP20.1 UZ8.8 UZ8.9
+3.3V_LAN: CL15.1 CL18.1 CL19.1 CL25.1 CL26.1 CL27.1 JLOM1.9 JLOM1.12 PJP12.1 RL1.1 RL2.1 RL4.2 RL5.1 RL6.1 RL8.1 RL29.1 RL30.1 UL2.5 UL4.1 UL4.4 UL4.8 UL4.14 UL4.21 UL4.30 UL4.39
+3.3V_LAN_OUT: CL7.1 RL8.2 UL1.4 UL1.5 UL1.15 UL1.19 UL1.29
+3.3V_LAN_UL3: CZ36.1 PJP12.2 UL3.13 UL3.14
+3.3V_M: CC54.1 JSPI1.16 PJP11.1 RC231.1 RZ54.2 RZ55.2 UC1.Y8
+3.3V_M_TPM: CZ4.1 CZ5.1 CZ6.1 CZ7.1 PJP11.2 UZ1.3 UZ1.10 UZ1.19 UZ1.24
+3.3V_M_UL3: CL23.1 RZ55.1 UL3.8 UL3.9
+3.3V_MMI: CR1.1 CR2.1 CR3.1 CR4.1 CR6.1 CR7.2 CR8.2 PJP26.2 RR6.1 RR15.1 UR1.9 UR1.11 UR1.13 UR1.23 UR1.27 UR1.42
+3.3V_RTC_LDO: PD3.3 PR103.1
+3.3V_RUN: CA7.1 CC17.1 CC64.1 CC66.1 CC69.1 CC85.2 CD31.1 CD32.1 CD63.1 CD64.1 CV61.1 CV62.1 CV66.1 CV69.1 CV510.1 CV511.1 CV600.1 CV601.1 CV602.1 CV603.1 CV604.1 CZ11.1 JDIMM1.199 JDIMM2.199 JEDP1.10 JLPDE1.1 JLPDE1.2 JUSH1.13 PJP10.1 PJP16.1 PJP22.2 PJP25.1 PJP26.1 PJP400.1 PR400.1 PR516.2 PR519.1 PU500.20 PU500.21 QC1.2 QC1.5 QV8.3 QZ1.3 RC66.1 RC68.1 RC95.1 RC122.1 RC155.2 RC156.2 RC158.1 RC160.1 RC163.1 RC164.1 RC176.1 RC180.1 RC247.1 RC302.1 RD27.2 RE48.1 RE51.1 RE67.1 RN3.1 RN4.1 RN6.1 RPC2.5 RPC2.6 RPC2.7 RPC2.8 RPC3.1 RPC3.2 RPC3.3 RPC3.4 RPC4.1 RPC4.2 RPC4.3 RPC4.4 RPC6.1 RPC6.2 RPC6.3 RPC6.4 RPC8.5 RPC8.6 RPC8.7 RPC8.8 RPC9.1 RPC9.2 RPC9.3 RPC9.4 RPC15.5 RPC15.6 RPC15.7 RPC15.8 RPC16.1 RPC16.2 RPC16.3 RPC16.4 RPC17.1 RPC17.2 RPC17.3 RPC17.4 RPC18.1 RPC18.2 RPC18.3 RPC18.4 RPC20.5 RPC20.8 RPE3.5 RPE3.6 RPE8.5 RPE8.6 RPE8.7 RPE8.8 RV6.1 RV8.2 RV51.1 RV54.1 RV55.1 RV56.1 RV57.1 RV58.1 RV60.1 RV68.1 RV501.1 RV507.1 RV551.1 RV555.1 RV601.1 RV602.1 RV603.1 RV604.1 RV605.1 RV610.1 RV611.1 RV612.1 RV613.1 RV614.1 RV615.1 RZ54.1 UC1.K14 UC1.K16 UC1.T9 UC1.U8 UC1.V8 UC1.W9 UC4.5 UC5.5 UC7.14 UV7.14 UV7.28 UV7.41 UV7.56 UV13.6 UV13.7 UV501.1 UV502.14 UV600.5 UV600.21 UV600.30 UV600.51 UV600.57 UZ8.6 UZ8.7
+3.3V_RUN_AUDIO: CA10.1 CA11.1 CA50.1 PJP10.2 RA1.1 RA4.1 RA18.1 RA26.1 RA29.1 RA38.2 RA45.2 UA1.3 UA1.9
+3.3V_RUN_CARD: CR31.1 JSD1.4 UR1.22
+3.3V_RUN_UZ9: CZ47.1 PJP22.1 UZ9.8 UZ9.9
+3.3V_RUN_VDDA: CV98.1 CV99.1 CV100.1 CV101.1 LV25.1 UV8.C10 UV8.H5 UV8.H12 UV8.J4 UV8.K6 UV8.K7
+3.3V_RUN_VDDIO: CV94.1 CV95.1 CV96.1 CV97.1 LV24.2 UV8.B5 UV8.B6 UV8.C3 UV8.C4 UV8.C11 UV8.C12 UV8.K3 UV8.K4 UV8.K11 UV8.K12
+3.3V_RUN_VMM: CV114.1 CV121.1 CV124.1 LV24.1 LV25.2 PJP25.2 PJP27.2 RPV1.5 RPV1.6 RPV1.7 RPV1.8 RPV2.5 RPV2.6 RPV2.7 RPV2.8 RV14.2 RV82.2 RV83.2 RV84.2 RV85.2 RV86.1 RV87.1 RV88.1 RV90.1 RV91.1 RV516.2 RV517.1 RV518.1 RV519.1 RV702.1 UV9.8 UV11.14 UV12.14
+3.3V_SPI: CC6.1 CC7.1 JSPI1.15 RC29.1 RC31.1 RC231.2 UC2.8 UC3.8
+3.3V_SUS: CI38.1 CI414.1 CI415.1 CI416.1 CI417.1 CI418.1 CI419.1 CI420.1 CZ12.1 JUSH1.8 JUSH1.9 JUSH1.10 PJP19.1 RZ8.1 RZ9.1 UI4.3 UI4.9 UI4.12 UI4.16 UI4.20 UI4.29 UI5.10
+3.3V_SUS_UZ8: CZ40.1 PJP19.2 UZ8.13 UZ8.14
+3.3V_TP: CZ27.1 JKBTP1.12 PJP16.2 RZ18.1 RZ19.1
+3.3V_TSP: CZ2.1 JEDP1.1 QV8.1
+3.3V_VMM_UV10: CV118.2 PJP27.1 UV13.8 UV13.9
+3.3V_WLAN: CZ15.1 CZ16.1 CZ17.2 CZ18.2 CZ19.1 CZ20.1 CZ66.1 JNGFF1.2 JNGFF1.4 JNGFF1.64 JNGFF1.66 PJP13.1 PJP41.1 QZ2.2 QZ2.5 RZ14.2 RZ15.2
+3.3V_WLAN_UZ2: CZ50.1 PJP13.2 PJP41.2 UZ2.8 UZ2.9
+3.3V_WWAN: CZ51.1 CZ52.1 CZ53.1 CZ54.1 CZ55.1 CZ57.1 JNGFF2.2 JNGFF2.4 JNGFF2.62 JNGFF2.64 JNGFF2.66 PJP32.1 PJP42.1 QZ11.2 RZ37.2 RZ39.1 RZ45.1 RZ45.2 RZ50.1
+3.3V_WWAN_UZ2: CZ24.1 PJP32.2 PJP42.2 UZ2.13 UZ2.14
+3V5V_PWR_SRC: PC101.1 PC102.1 PC105.1 PC106.1 PC117.1 PJP100.2 PL100.2 PQ100.5 PQ101.5 PU100.12
+5V_ALW: CI6.1 CI7.1 CI11.1 CI12.1 CI19.1 CI20.1 JLED1.6 LED7.2 LED7.4 PC400.1 PJP101.2 PR11.1 PR202.1 PR204.2 PR526.2 PR843.2 PU1.5 PU400.6 QZ9.3 QZ12.3 RD9.1 RI13.2 RZ5.1 RZ21.1 RZ32.2 UI1.2 UI1.3 UI2.2 UI2.3 UI3.1 UI3.7 UI3.8 UL3.4 UV13.4 UZ2.4 UZ7.4 UZ8.4 UZ9.1 UZ9.2 UZ9.4
+5V_ALW2: PC118.1 PU100.13
+5V_ALW_U41: CZ35.1 RZ21.2 UZ5.1
+5V_ALWP: PC115.1 PJP101.1 PL102.2 PR101.2 PU100.14
+5V_RUN: CE32.1 CV24.1 CZ10.1 CZ29.1 DE1.1 JFAN1.1 JKBTP1.5 JUSH1.14 PC509.2 PJP9.1 PJP21.1 PU501.2 QV501.2 RPE2.1 RPE2.2 RPE2.3 RPE2.4 UV10.1
+5V_RUN_AUDIO: LA5.2 PJP9.2 RA39.1
+5V_RUN_PVDD: CA45.1 CA46.1 CA47.1 CA48.1 RA39.2 UA1.41 UA1.46
+5V_RUN_UZ9: CZ44.1 PJP21.2 UZ9.13 UZ9.14
+5V_USB_CHG_PWR: CI1.1 CI3.1 JUSB1.1 UI3.12
+GND_CHASSIS: CL22.2 RL15.2 RL16.2 RL17.2 RL18.2
+V1.05S_APLLOPI: CC67.1 CC68.1 LC3.2 UC1.AA21 UC1.W21
+V1.05SP_B+: PC300.1 PC303.1 PC311.1 PJP302.2 PU300.8
+VCC_CORE: CC23.1 CC79.2 CC84.2 PC900.1 PC901.1 PC902.1 PC903.1 PC904.1 PC913.1 PC914.1 PC915.1 PC916.1 PC917.1 PC966.1 PL500.1 RC209.1 UC1.AB57 UC1.AD57 UC1.AG57 UC1.C24 UC1.C28 UC1.C32 UC1.C36 UC1.C40 UC1.C44 UC1.C48 UC1.C52 UC1.C56 UC1.E23 UC1.E25 UC1.E27 UC1.E29 UC1.E31 UC1.E33 UC1.E35 UC1.E37 UC1.E39 UC1.E41 UC1.E43 UC1.E45 UC1.E47 UC1.E49 UC1.E51 UC1.E53 UC1.E55 UC1.E57 UC1.F24 UC1.F28 UC1.F32 UC1.F36 UC1.F40 UC1.F44 UC1.F48 UC1.F52 UC1.F56 UC1.F59 UC1.G23 UC1.G25 UC1.G27 UC1.G29 UC1.G31 UC1.G33 UC1.G35 UC1.G37 UC1.G39 UC1.G41 UC1.G43 UC1.G45 UC1.G47 UC1.G49 UC1.G51 UC1.G53 UC1.G55 UC1.G57 UC1.H23 UC1.J23 UC1.K23 UC1.K57 UC1.L22 UC1.M23 UC1.M57 UC1.P57 UC1.U57 UC1.W57
+VCC_PWR_SRC: PC503.2 PC515.1 PC516.1 PC517.1 PC518.1 PC519.1 PC520.1 PC521.1 PJP500.2 PL501.2 PR511.1 PR518.1 PU501.5
+VCCIO_OUT: RC196.1 UC1.A59
+VCCIOA_OUT: RC133.1 UC1.E20
+VDDA_AVDD1: CA8.1 CA9.1 LA5.1 UA1.27
+VDDA_PVDD: CA17.1 CA18.1 RA4.2 UA1.38
GND: C33.2 C42.2 C43.2 C263.2 C310.2 C311.2 C316.2 C317.2 C318.2 C319.2 CA5.2 CA6.2 CA7.2 CA10.2 CA11.2 CA12.2 CA13.2 CA19.2 CA22.2 CA23.2 CA24.2 CA30.2 CA31.2 CA33.2 CA41.2 CA45.2 CA46.2 CA47.2 CA48.2 CA49.1 CA50.2 CA53.2 CC1.1 CC2.1 CC3.1 CC4.1 CC5.2 CC6.2 CC7.2 CC8.1 CC9.1 CC10.1 CC11.1 CC12.1 CC13.1 CC14.1 CC15.1 CC17.2 CC18.2 CC19.2 CC20.2 CC21.2 CC22.2 CC24.2 CC25.2 CC26.2 CC27.2 CC28.2 CC29.2 CC30.2 CC31.2 CC32.2 CC33.2 CC34.2 CC35.2 CC36.2 CC37.2 CC39.2 CC40.2 CC41.2 CC42.2 CC43.2 CC44.2 CC47.2 CC48.2 CC49.2 CC50.2 CC51.2 CC52.2 CC53.2 CC54.2 CC55.2 CC56.2 CC57.2 CC58.2 CC59.2 CC60.2 CC61.2 CC62.2 CC63.2 CC64.2 CC65.2 CC66.2 CC67.2 CC68.2 CC69.2 CC70.2 CC71.2 CC72.2 CC73.2 CC77.2 CC78.2 CC80.2 CC81.2 CC82.2 CC83.2 CC100.1 CC101.2 CC102.2 CC103.2 CC104.2 CC105.2 CC106.2 CC107.2 CC108.2 CC109.2 CC110.2 CC111.2 CC112.2 CD1.2 CD2.2 CD3.2 CD4.2 CD5.2 CD6.2 CD7.2 CD8.2 CD9.2 CD10.2 CD11.2 CD12.2 CD13.2 CD14.2 CD15.2 CD16.2 CD17.2 CD18.2 CD19.2 CD20.2 CD22.2 CD23.2 CD24.2 CD25.2 CD26.2 CD27.2 CD28.2 CD29.2 CD30.2 CD31.2 CD32.2 CD33.2 CD34.2 CD35.2 CD37.2 CD38.2 CD39.2 CD40.2 CD41.2 CD42.2 CD43.2 CD44.2 CD45.2 CD46.2 CD47.2 CD48.2 CD49.2 CD50.2 CD51.2 CD52.2 CD53.2 CD55.2 CD56.2 CD57.2 CD58.2 CD59.2 CD60.2 CD61.2 CD62.2 CD63.2 CD64.2 CE1.2 CE2.2 CE3.2 CE4.2 CE5.2 CE6.2 CE7.2 CE8.2 CE9.2 CE10.2 CE11.2 CE12.2 CE13.2 CE14.2 CE15.2 CE16.2 CE17.2 CE18.2 CE19.2 CE20.2 CE21.2 CE22.2 CE23.2 CE25.2 CE28.2 CE29.2 CE30.2 CE31.2 CE32.2 CE34.2 CE36.2 CE38.2 CE40.2 CE41.2 CE42.2 CE44.2 CE45.2 CI1.2 CI3.2 CI6.2 CI7.2 CI8.2 CI10.2 CI11.2 CI12.2 CI14.2 CI17.2 CI19.2 CI20.2 CI38.2 CI414.2 CI415.2 CI416.2 CI417.2 CI418.2 CI419.2 CI420.2 CL3.2 CL4.2 CL7.2 CL8.2 CL9.2 CL10.2 CL11.2 CL12.2 CL13.1 CL14.1 CL15.2 CL16.2 CL17.2 CL18.2 CL19.2 CL20.2 CL21.2 CL22.1 CL23.2 CL24.2 CL25.2 CL26.2 CL27.2 CMOS1.1 CN1.2 CN2.2 CR1.2 CR2.2 CR3.2 CR4.2 CR6.2 CR7.1 CR8.1 CR9.1 CR10.1 CR13.1 CR14.1 CR15.1 CR17.1 CR18.1 CR19.1 CR21.1 CR22.1 CR23.2 CR31.2 CR34.2 CR35.2 CV7.2 CV8.2 CV9.2 CV10.2 CV12.2 CV24.2 CV27.2 CV30.2 CV60.2 CV61.2 CV62.2 CV66.2 CV69.2 CV82.2 CV83.2 CV84.2 CV85.2 CV86.2 CV87.2 CV88.2 CV89.2 CV90.2 CV91.2 CV92.2 CV93.2 CV94.2 CV95.2 CV96.2 CV97.2 CV98.2 CV99.2 CV100.2 CV101.2 CV113.2 CV114.2 CV115.2 CV116.2 CV117.2 CV118.1 CV121.2 CV124.2 CV509.2 CV510.2 CV511.2 CV518.2 CV600.2 CV601.2 CV602.2 CV603.2 CV604.2 CV605.2 CZ1.2 CZ2.2 CZ4.2 CZ5.2 CZ6.2 CZ7.2 CZ9.2 CZ10.2 CZ11.2 CZ12.2 CZ15.2 CZ16.2 CZ17.1 CZ18.1 CZ19.2 CZ20.2 CZ23.2 CZ24.2 CZ25.2 CZ27.2 CZ28.2 CZ29.2 CZ30.2 CZ31.2 CZ34.2 CZ35.2 CZ36.2 CZ37.2 CZ38.2 CZ39.1 CZ40.2 CZ41.2 CZ42.2 CZ43.2 CZ44.2 CZ45.2 CZ46.2 CZ47.2 CZ48.2 CZ49.2 CZ50.2 CZ51.2 CZ52.2 CZ53.2 CZ54.2 CZ55.2 CZ56.2 CZ57.2 CZ60.2 CZ62.2 CZ63.2 CZ64.2 CZ65.2 CZ66.2 CZ68.2 D20.1 DA1.1 DA2.1 DA3.1 DA6.1 DA7.1 DE1.2 DI1.3 DI2.1 DI3.1 DI4.3 DI5.1 DI6.3 DV4.1 H1.1(TP-1) H2.1(TP-1) H3.1(TP-1) H4.1(TP-1) H5.1(TP-1) H6.1(TP-1) H7.1(TP-1) H8.1(TP-1) H9.1(TP-1) H10.1(TP-1) H11.1(TP-1) H12.1(TP-1) H13.1(TP-1) H14.1(TP-1) H15.1(TP-1) H16.1(TP-1) H17.1(TP-1) H18.1(TP-1) H19.1(TP-1) JAPS1.8 JAPS1.10 JAPS1.12 JAPS1.14 JAPS1.19 JAPS1.20 JDEG1.10 JDEG1.11 JDEG1.12 JDIMM1.2 JDIMM1.3 JDIMM1.8 JDIMM1.9 JDIMM1.11 JDIMM1.13 JDIMM1.14 JDIMM1.19 JDIMM1.20 JDIMM1.25 JDIMM1.26 JDIMM1.28 JDIMM1.31 JDIMM1.32 JDIMM1.37 JDIMM1.38 JDIMM1.43 JDIMM1.44 JDIMM1.46 JDIMM1.48 JDIMM1.49 JDIMM1.54 JDIMM1.55 JDIMM1.60 JDIMM1.61 JDIMM1.63 JDIMM1.65 JDIMM1.66 JDIMM1.71 JDIMM1.72 JDIMM1.127 JDIMM1.128 JDIMM1.133 JDIMM1.134 JDIMM1.136 JDIMM1.138 JDIMM1.139 JDIMM1.144 JDIMM1.145 JDIMM1.150 JDIMM1.151 JDIMM1.153 JDIMM1.155 JDIMM1.156 JDIMM1.161 JDIMM1.162 JDIMM1.167 JDIMM1.168 JDIMM1.170 JDIMM1.172 JDIMM1.173 JDIMM1.178 JDIMM1.179 JDIMM1.184 JDIMM1.185 JDIMM1.187 JDIMM1.189 JDIMM1.190 JDIMM1.195 JDIMM1.196 JDIMM1.205 JDIMM1.206 JDIMM2.2 JDIMM2.3 JDIMM2.8 JDIMM2.9 JDIMM2.11 JDIMM2.13 JDIMM2.14 JDIMM2.19 JDIMM2.20 JDIMM2.25 JDIMM2.26 JDIMM2.28 JDIMM2.31 JDIMM2.32 JDIMM2.37 JDIMM2.38 JDIMM2.43 JDIMM2.44 JDIMM2.46 JDIMM2.48 JDIMM2.49 JDIMM2.54 JDIMM2.55 JDIMM2.60 JDIMM2.61 JDIMM2.63 JDIMM2.65 JDIMM2.66 JDIMM2.71 JDIMM2.72 JDIMM2.127 JDIMM2.128 JDIMM2.133 JDIMM2.134 JDIMM2.136 JDIMM2.138 JDIMM2.139 JDIMM2.144 JDIMM2.145 JDIMM2.150 JDIMM2.151 JDIMM2.153 JDIMM2.155 JDIMM2.156 JDIMM2.161 JDIMM2.162 JDIMM2.167 JDIMM2.168 JDIMM2.170 JDIMM2.172 JDIMM2.173 JDIMM2.178 JDIMM2.179 JDIMM2.184 JDIMM2.185 JDIMM2.187 JDIMM2.189 JDIMM2.190 JDIMM2.195 JDIMM2.196 JDIMM2.205 JDIMM2.206 JDOCK1.1 JDOCK1.7 JDOCK1.8 JDOCK1.13 JDOCK1.14 JDOCK1.19 JDOCK1.20 JDOCK1.25 JDOCK1.26 JDOCK1.31 JDOCK1.32 JDOCK1.37 JDOCK1.38 JDOCK1.43 JDOCK1.44 JDOCK1.47 JDOCK1.49 JDOCK1.50 JDOCK1.51 JDOCK1.52 JDOCK1.55 JDOCK1.57 JDOCK1.58 JDOCK1.61 JDOCK1.63 JDOCK1.64 JDOCK1.69 JDOCK1.70 JDOCK1.75 JDOCK1.76 JDOCK1.81 JDOCK1.82 JDOCK1.87 JDOCK1.88 JDOCK1.91 JDOCK1.93 JDOCK1.94 JDOCK1.95 JDOCK1.96 JDOCK1.101 JDOCK1.102 JDOCK1.107 JDOCK1.108 JDOCK1.113 JDOCK1.114 JDOCK1.119 JDOCK1.120 JDOCK1.123 JDOCK1.125 JDOCK1.126 JDOCK1.131 JDOCK1.132 JDOCK1.137 JDOCK1.138 JDOCK1.145 JDOCK1.148 JDOCK1.151 JDOCK1.152 JDOCK1.153 JDOCK1.154 JDOCK1.155 JDOCK1.156 JDOCK1.157 JDOCK1.158 JDOCK1.159 JDOCK1.160 JDOCK1.161 JDOCK1.162 JEDP1.4 JEDP1.6 JEDP1.8 JEDP1.15 JEDP1.23 JEDP1.24 JEDP1.25 JEDP1.27 JEDP1.28 JEDP1.39 JEDP1.41 JEDP1.42 JEDP1.43 JEDP1.44 JEDP1.45 JFAN1.4 JFAN1.5 JFAN1.6 JHDMI1.2 JHDMI1.5 JHDMI1.8 JHDMI1.11 JHDMI1.17 JHDMI1.20 JHDMI1.21 JHDMI1.22 JHDMI1.23 JKBTP1.2 JKBTP1.3 JKBTP1.9 JKBTP1.15 JKBTP1.16 JKBTP1.17 JKBTP1.18 JLED1.7 JLED1.8 JLOM1.16 JLOM1.17 JLPDE1.9 JLPDE1.11 JLPDE1.12 JMDP1.1 JMDP1.7 JMDP1.8 JMDP1.13 JMDP1.14 JMDP1.19 JMDP1.21 JMDP1.22 JMDP1.23 JMDP1.24 JMINI3.4 JMINI3.9 JMINI3.15 JMINI3.18 JMINI3.21 JMINI3.26 JMINI3.27 JMINI3.29 JMINI3.34 JMINI3.35 JMINI3.37 JMINI3.40 JMINI3.50 JMINI3.53 JMINI3.54 JNGFF1.1 JNGFF1.7 JNGFF1.10 JNGFF1.15 JNGFF1.16 JNGFF1.21 JNGFF1.22 JNGFF1.25 JNGFF1.28 JNGFF1.31 JNGFF1.37 JNGFF1.43 JNGFF1.49 JNGFF1.55 JNGFF1.61 JNGFF1.67 JNGFF1.68 JNGFF1.69 JNGFF2.3 JNGFF2.5 JNGFF2.11 JNGFF2.19 JNGFF2.25 JNGFF2.31 JNGFF2.37 JNGFF2.43 JNGFF2.49 JNGFF2.63 JNGFF2.65 JNGFF2.68 JNGFF2.69 JRTC1.2 JRTC1.3 JRTC1.4 JSD1.3 JSD1.6 JSD1.10 JSD1.13 JSD1.17 JSD1.20 JSD1.21 JSD1.22 JSD1.23 JSD1.24 JSD1.25 JSD1.26 JSH1.2 JSH1.3 JSH1.5 JSH1.10 JSH1.13 JSH1.14 JSPI1.18 JSPI1.19 JSPI1.20 JSPI1.21 JSPI1.22 JSPI1.23 JSPI1.24 JSPK1.5 JSPK1.6 JTAG1.2 JUSB1.4 JUSB1.7 JUSB1.10 JUSB1.11 JUSB1.12 JUSB1.13 JUSB2.4 JUSB2.7 JUSB2.10 JUSB2.11 JUSB2.12 JUSB2.13 JUSB3.4 JUSB3.7 JUSB3.10 JUSB3.11 JUSB3.12 JUSB3.13 JUSH1.1 JUSH1.4 JUSH1.18 JUSH1.19 JUSH1.21 JUSH1.22 JXDP1.1 JXDP1.2 JXDP1.7 JXDP1.8 JXDP1.13 JXDP1.14 JXDP1.19 JXDP1.20 JXDP1.25 JXDP1.26 JXDP1.31 JXDP1.32 JXDP1.37 JXDP1.38 JXDP1.49 JXDP1.50 JXDP1.59 LED5.1 LED6.1 PBATT1.6 PBATT1.7 PBATT1.8 PBATT1.9 PBATT1.10 PBATT1.11 PC1.2 PC3.2 PC4.2 PC9.2 PC10.2 PC11.2 PC100.1 PC101.2 PC102.2 PC105.2 PC106.2 PC111.2 PC113.2 PC114.2 PC115.2 PC117.2 PC118.2 PC119.2 PC200.2 PC201.2 PC203.2 PC205.2 PC206.2 PC207.2 PC208.2 PC209.1 PC211.2 PC212.2 PC214.2 PC215.2 PC300.2 PC301.2 PC303.2 PC305.2 PC306.2 PC307.2 PC308.2 PC309.2 PC310.2 PC311.2 PC400.2 PC401.2 PC402.2 PC404.2 PC500.1 PC501.2 PC503.1 PC505.1 PC507.1 PC508.2 PC509.1 PC510.1 PC511.2 PC514.1 PC515.2 PC516.2 PC517.2 PC518.2 PC519.2 PC520.2 PC521.2 PC704.2 PC705.2 PC706.2 PC707.2 PC708.2 PC709.2 PC710.2 PC713.2 PC714.2 PC715.2 PC716.2 PC717.2 PC721.2 PC722.2 PC723.2 PC724.2 PC725.2 PC732.2 PC737.2 PC741.1 PC805.1 PC810.1 PC813.2 PC815.2 PC816.2 PC817.2 PC900.2 PC901.2 PC902.2 PC903.2 PC904.2 PC913.2 PC914.2 PC915.2 PC916.2 PC917.2 PC966.2 PD1.1 PD2.1 PD5.1 PJP1.2 PJP6.2 PJP701.2 PQ3.3 PQ6.6 PQ102.1 PQ102.2 PQ102.3 PQ103.1 PQ103.2 PQ103.3 PQ201.1 PQ201.2 PQ201.3 PQ704.3 PQ704.4 PQ704.5 PQ806.1 PQ806.4 PQ813.1 PQ813.4 PQ816.3 PQ817.1 PQ817.4 PQ832.3 PR12.1 PR15.2 PR16.2 PR18.2 PR102.1 PR104.2 PR105.1 PR106.1 PR114.2 PR209.2 PR303.2 PR308.2 PR310.2 PR401.2 PR403.2 PR505.1 PR506.1 PR507.1 PR508.1 PR509.1 PR510.1 PR513.2 PR525.2 PR745.2 PR814.1 PR844.2 PR858.2 PR874.2 PU1.2 PU100.21 PU200.1 PU200.3 PU200.14 PU200.21 PU300.9 PU400.1 PU500.19 PU500.22 PU500.29 PU500.33 PU501.3 PU501.9 PU700.22 PU800.5 PU800.14 PU800.23 PU800.32 PU800.37 PU804.3 PU806.3 QA1.3 QA3.1 QA3.4 QE2.1 QE2.4 QV2.3 QV7.3 QV9.3 QV10.3 QV502.3 QV700.1 QV700.4 QZ10.1 QZ10.4 R268.2 R271.2 RA35.2 RA36.2 RA37.2 RC21.2 RC80.2 RC91.1 RC123.2 RC128.1 RC129.1 RC130.2 RC131.2 RC132.2 RC139.1 RC140.2 RC141.1 RC142.1 RC152.2 RC171.2 RC174.2 RC175.2 RC178.2 RC183.2 RC184.2 RC185.2 RC186.1 RC187.2 RC188.2 RC189.2 RC190.2 RC191.2 RC198.2 RC218.2 RC240.2 RC241.2 RC242.2 RC243.2 RC303.2 RC304.2 RC305.2 RD6.2 RD7.2 RD14.1 RD15.1 RD16.1 RD20.2 RD21.2 RD24.2 RD25.2 RD28.2 RE17.1 RE20.1 RE21.1 RE24.2 RE55.1 RE56.1 RE58.2 RE65.2 RE77.2 RE78.2 RE82.1 RE85.2 RE86.1 RE88.2 RE277.1 RI14.1 RL3.1 RL9.2 RL12.2 RL13.2 RN7.2 RPC20.6 RPC20.7 RPE10.5 RPE10.6 RPE10.7 RPE10.8 RR2.1 RR5.2 RR8.2 RR11.2 RV1.2 RV2.2 RV3.1 RV50.2 RV52.2 RV61.2 RV62.2 RV63.2 RV64.2 RV65.2 RV66.2 RV67.1 RV73.2 RV74.2 RV75.2 RV76.2 RV77.2 RV78.2 RV79.2 RV89.2 RV100.2 RV502.1 RV503.1 RV504.2 RV505.1 RV508.1 RV509.1 RV550.2 RV554.1 RV600.2 RV606.1 RV607.1 RV608.1 RV609.1 RV616.2 RV617.2 RV618.2 RV619.2 RV620.2 RZ10.1 RZ27.2 RZ38.1 RZ40.1 RZ48.1 RZ48.2 ST1.1(TP-1) ST2.1(TP-1) ST3.1(TP-1) SW1.4 SW1.5 SW2.1 SW2.3 UA1.49 UC1.A11 UC1.A14 UC1.A18 UC1.A24 UC1.A28 UC1.A32 UC1.A36 UC1.A40 UC1.A44 UC1.A48 UC1.A52 UC1.A56 UC1.AA1 UC1.AA58 UC1.AB7 UC1.AB10 UC1.AB20 UC1.AB22 UC1.AC61 UC1.AD3 UC1.AD21 UC1.AD63 UC1.AE5 UC1.AE10 UC1.AE58 UC1.AF11 UC1.AF12 UC1.AF14 UC1.AF15 UC1.AF17 UC1.AF18 UC1.AG1 UC1.AG11 UC1.AG21 UC1.AG23 UC1.AG60 UC1.AG61 UC1.AG62 UC1.AG63 UC1.AH16 UC1.AH17 UC1.AH19 UC1.AH20 UC1.AH22 UC1.AH24 UC1.AH28 UC1.AH30 UC1.AH32 UC1.AH34 UC1.AH36 UC1.AH38 UC1.AH40 UC1.AH42 UC1.AH44 UC1.AH46 UC1.AH49 UC1.AH51 UC1.AH53 UC1.AH55 UC1.AH57 UC1.AJ13 UC1.AJ14 UC1.AJ23 UC1.AJ25 UC1.AJ27 UC1.AJ29 UC1.AJ35 UC1.AJ39 UC1.AJ41 UC1.AJ43 UC1.AJ45 UC1.AJ47 UC1.AJ50 UC1.AJ52 UC1.AJ54 UC1.AJ56 UC1.AJ58 UC1.AJ60 UC1.AJ63 UC1.AK3 UC1.AK23 UC1.AK52 UC1.AL10 UC1.AL13 UC1.AL17 UC1.AL20 UC1.AL22 UC1.AL23 UC1.AL26 UC1.AL29 UC1.AL31 UC1.AL33 UC1.AL36 UC1.AL39 UC1.AL40 UC1.AL45 UC1.AL46 UC1.AL51 UC1.AL52 UC1.AL54 UC1.AL57 UC1.AL60 UC1.AL61 UC1.AM1 UC1.AM17 UC1.AM23 UC1.AM31 UC1.AM52 UC1.AN7 UC1.AN17 UC1.AN23 UC1.AN31 UC1.AN32 UC1.AN35 UC1.AN36 UC1.AN39 UC1.AN40 UC1.AN42 UC1.AN43 UC1.AN45 UC1.AN46 UC1.AN48 UC1.AN49 UC1.AN51 UC1.AN52 UC1.AN60 UC1.AN63 UC1.AP3 UC1.AP10 UC1.AP17 UC1.AP20 UC1.AP22 UC1.AP23 UC1.AP26 UC1.AP29 UC1.AP31 UC1.AP38 UC1.AP39 UC1.AP48 UC1.AP52 UC1.AP54 UC1.AP57 UC1.AR5 UC1.AR11 UC1.AR15 UC1.AR17 UC1.AR23 UC1.AR31 UC1.AR33 UC1.AR39 UC1.AR43 UC1.AR49 UC1.AR52 UC1.AT13 UC1.AT35 UC1.AT37 UC1.AT40 UC1.AT42 UC1.AT43 UC1.AT46 UC1.AT49 UC1.AT61 UC1.AT62 UC1.AT63 UC1.AU1 UC1.AU16 UC1.AU18 UC1.AU20 UC1.AU22 UC1.AU24 UC1.AU26 UC1.AU28 UC1.AU30 UC1.AU33 UC1.AU51 UC1.AU53 UC1.AU55 UC1.AU57 UC1.AU59 UC1.AV8 UC1.AV14 UC1.AV16 UC1.AV20 UC1.AV24 UC1.AV28 UC1.AV33 UC1.AV34 UC1.AV36 UC1.AV39 UC1.AV41 UC1.AV43 UC1.AV46 UC1.AV49 UC1.AV51 UC1.AV55 UC1.AV59 UC1.AW4 UC1.AW16 UC1.AW24 UC1.AW33 UC1.AW35 UC1.AW37 UC1.AW40 UC1.AW42 UC1.AW44 UC1.AW47 UC1.AW50 UC1.AW51 UC1.AW59 UC1.AW60 UC1.AY4 UC1.AY6 UC1.AY11 UC1.AY16 UC1.AY18 UC1.AY22 UC1.AY24 UC1.AY26 UC1.AY30 UC1.AY33 UC1.AY51 UC1.AY53 UC1.AY57 UC1.AY59 UC1.B4 UC1.B20 UC1.B24 UC1.B26 UC1.B28 UC1.B32 UC1.B36 UC1.B40 UC1.B44 UC1.B48 UC1.B52 UC1.B56 UC1.B60 UC1.C11 UC1.C14 UC1.C18 UC1.C20 UC1.C25 UC1.C27 UC1.C38 UC1.C39 UC1.C57 UC1.D2 UC1.D5 UC1.D8 UC1.D12 UC1.D14 UC1.D18 UC1.D21 UC1.D23 UC1.D25 UC1.D26 UC1.D27 UC1.D29 UC1.D30 UC1.D31 UC1.D33 UC1.D34 UC1.D35 UC1.D37 UC1.D38 UC1.D39 UC1.D41 UC1.D42 UC1.D43 UC1.D45 UC1.D46 UC1.D47 UC1.D49 UC1.D50 UC1.D51 UC1.D53 UC1.D54 UC1.D55 UC1.D57 UC1.D59 UC1.D62 UC1.D63 UC1.E11 UC1.E17 UC1.F20 UC1.F26 UC1.F30 UC1.F34 UC1.F38 UC1.F42 UC1.F46 UC1.F50 UC1.F54 UC1.F58 UC1.F61 UC1.G3 UC1.G5 UC1.G6 UC1.G8 UC1.G18 UC1.G22 UC1.H13 UC1.H17 UC1.H57 UC1.J10 UC1.J22 UC1.J59 UC1.J63 UC1.K1 UC1.K12 UC1.L7 UC1.L13 UC1.L15 UC1.L17 UC1.L18 UC1.L20 UC1.L58 UC1.L61 UC1.M22 UC1.N3 UC1.N10 UC1.N21 UC1.P22 UC1.P59 UC1.P62 UC1.P63 UC1.R8 UC1.R10 UC1.R22 UC1.T1 UC1.T58 UC1.U9 UC1.U20 UC1.U22 UC1.U61 UC1.V3 UC1.V7 UC1.V10 UC1.V23 UC1.V58 UC1.W20 UC1.W22 UC1.Y10 UC1.Y59 UC1.Y63 UC2.4 UC3.4 UC4.3 UC5.3 UC6.3 UC7.7 UC7.15 UC8.3 UD1.3 UE1.B27 UE1.C1 UE2.B11 UE2.B18 UE2.B54 UE2.B60 UE2.B66 UE2.C1 UI1.1 UI2.1 UI3.14 UI3.17 UI4.11 UI4.21 UI4.28 UI4.33 UI5.5 UI5.6 UL1.49 UL2.3 UL3.11 UL3.15 UL4.43 UR1.49 UV7.26 UV7.35 UV7.38 UV7.43 UV7.57 UV8.C5 UV8.C13 UV8.C14 UV8.D4 UV8.D5 UV8.D6 UV8.D7 UV8.D8 UV8.D9 UV8.D10 UV8.D11 UV8.D13 UV8.D14 UV8.E4 UV8.E11 UV8.F4 UV8.F5 UV8.F6 UV8.F7 UV8.F8 UV8.F9 UV8.F10 UV8.F11 UV8.G4 UV8.G5 UV8.G6 UV8.G7 UV8.G8 UV8.G9 UV8.G10 UV8.G11 UV8.H4 UV8.H10 UV8.J5 UV8.J6 UV8.J7 UV8.J8 UV8.J9 UV8.J11 UV8.J12 UV8.K5 UV8.L6 UV8.L7 UV8.L8 UV9.4 UV10.2 UV11.7 UV12.7 UV13.11 UV13.15 UV24.2 UV501.2 UV502.7 UV600.11 UV600.19 UV600.52 UV600.61 UZ1.4 UZ1.8 UZ1.11 UZ1.18 UZ1.25 UZ2.11 UZ2.15 UZ5.2 UZ6.3 UZ7.11 UZ7.15 UZ8.11 UZ8.15 UZ9.11 UZ9.15 UZ10.3 UZ11.3 YL1.2 YL1.4 YV2.2 YV2.4
GNDA: CA1.2 CA2.2 CA3.2 CA4.2 CA8.2 CA9.2 CA16.2 CA17.2 CA18.2 CA25.2 CA26.2 CA35.1 CA51.2 CA52.2 JHP1.7 PJP6.1 QA2.1 QA2.4 RA2.2 RA35.1 RA36.1 RA37.1 RA44.2 UA1.26 UA1.37
GNDA_CHG: PC701.1 PC703.2 PC711.2 PC718.1 PC719.1 PC726.1 PC728.2 PC729.2 PJP701.1 PQ712.3 PR711.2 PR715.2 PR729.2 PR788.1 PU700.29
VCCSENSE: PR531.1 RC209.2 UC1.E63
VDD_1.35V: PC211.1 PR201.1 PR202.2 PU200.11
VSSSENSE: PR532.1 RC218.1 UC1.E62
3301_ACAV_IN_NB: PR848.1 PU800.24
3301_PWRSRC: PR860.1 PU800.15
+AUX_LDO: CR17.2 UR1.12
+BL_PWR_SRC: CV7.1 CV12.1 JEDP1.17 JEDP1.18 JEDP1.19 QV1.1 QV1.2 QV1.5 QV1.6
+CAP_LDO: CE7.1 UE1.B46
+COINCELL: JRTC1.1 PR1.1
+DC_IN: PC5.2 PC11.1 PL4.2 PQ4.1 PQ4.2 PQ4.3 PQ6.3 PR14.1 PR16.1 PR737.1 PR835.1
+DC_IN_SS: PC10.1 PD704.2 PD817.3 PQ4.5 PQ700.5 PR15.1 PR831.1
+DCIN: PC709.1 PR708.2 PU700.28
+DCIN_JACK: PC9.1 PJPDC1.2 PJPDC1.3 PL4.1
+DCPRRTC: CC52.1 UC1.AE7
+DIMM1_VREF_DQ: CD1.1 CD5.1 JDIMM1.1 RD4.2 RD5.1 RD6.1
+DIMM2_VREF_DQ: CD33.1 CD34.1 JDIMM2.1 RD22.2 RD23.1 RD24.1
+DOCK_PWR_BAR: C33.1 C317.1 C318.1 D20.2 D20.3 JDOCK1.146 JDOCK1.147 JDOCK1.149 JDOCK1.150 PD705.2 PD808.2 PD808.3 PQ810.5 PQ810.6 PQ810.7 PQ810.8 PQ826.5 PR814.2 PR832.2
+LCDVDD: CV8.1 CV9.1 JEDP1.30 JEDP1.31 UV24.1
+LOM_VCT: C316.1 JDOCK1.116 JDOCK1.118
+MIC1_VREF_OUT: DA4.2 DA5.2 UA1.30
+NBDOCK_DC_IN_SS: JDOCK1.41 PD817.2 PR863.2
+PBATT: PD702.2 PD800.2 PD800.3 PL1.2 PL2.2 PQ800.5 PQ800.6 PQ800.7 PQ800.8 PQ815.5 PQ815.6 PQ815.7 PQ815.8 PR723.2 PR838.2
+PCH_ASATA3PLL: CC55.1 CC56.1 LC2.2 RC17.2 UC1.A12 UC1.B11
+PCH_AUSB3PLL: CC47.1 CC51.1 LC1.2 RC149.1 UC1.B18 UC1.B27
+PCH_RTC_VCCSUS3_3: CC73.1 RC212.2 RC213.2 UC1.AH11
+PCH_VCC1P05: CC77.1 CC78.1 LC4.2 UC1.J18 UC1.K19
+PCH_VCCACLKPLL: CC81.1 CC82.1 LC5.2 RC69.2 UC1.A20
+PCH_VCCDSW: CC97.2 RC211.2 UC1.AG19 UC1.AG20
+PCH_VCCDSW3_3: CC80.1 CC97.1 JAPS1.3 JAPS1.7 RC92.1 RC153.2 RC216.2 RC217.2 RPC1.1 RPC1.2 RPC1.3 RPC1.4 UC1.AH10
+PCH_VCCDSW_R: CC65.1 RC211.1
+PWR_SRC: CV11.1 PC704.1 PC705.1 PC706.1 PC707.1 PC708.1 PJP100.1 PJP200.1 PJP302.1 PJP500.1 PL100.1 PL501.1 PL701.1 PR721.4 QV1.4 RV4.1
+PWR_SRC_AC: PC807.1 PD808.1 PJP700.1 PL700.2 PQ810.1 PQ810.2 PQ810.3 PR701.1 PR860.2
+RSVD_VCC3P3_1: RL6.2 UL1.1
+RTC_CELL: CC48.1 CC49.1 CC50.1 PC1.1 PD3.1 RA21.1 RC1.1 RC8.1 RC9.1 RC10.1 RC78.2 RE31.1 RE32.1 RE62.1 RPE5.5 RPE5.6 UC1.AG10
+RTC_CELL_VBAT: CE11.1 RE32.2 UE2.B64
+SD_IO_LDO: CR14.2 CR15.2 UR1.25
+SDC_IN: PC700.1 PQ700.1 PQ700.2 PQ700.3 PR701.4 PR710.2 PR847.1 PU700.3
+SIM_PWR: JNGFF2.28 JSH1.9
+SM_VREF_CA: CD36.1 RD19.2 UC1.AP49
+SM_VREF_CA_DIMM: CD22.1 CD23.1 CD55.1 CD56.1 JDIMM1.126 JDIMM2.126 RD18.2 RD19.1 RD20.1
+SM_VREF_DQ0: CD21.1 RD5.2 UC1.AR51
+SM_VREF_DQ1: CD54.1 RD23.2 UC1.AP51
+USB_RIGHT_PWR: CI8.1 CI10.1 JUSB2.1 UI2.6 UI2.7 UI2.8
+USB_SIDE_PWR: CI14.1 CI17.1 JUSB3.1 UI1.6 UI1.7 UI1.8
+V_DDR_REF: PC212.1 PU200.4
+VCHGR: PC722.1 PC723.1 PC724.1 PC725.1 PD800.1 PQ800.1 PQ800.2 PQ800.3 PR721.1
+VDISPLAY_VCC: CV509.1 JMDP1.20 UV501.3
+VHDMI_VCC: CV27.1 CV30.1 JHDMI1.18 RV7.2 RV9.2 UV10.3
+VLDOIN_1.35V: PJP201.1 PU200.19
+VR_CAP: CE31.1 UE2.B12
+VREFOUT: CA26.1 RA5.2 RA6.2 UA1.23
+Z4012: PD3.2 PR1.2
-DCIN_JACK: PJP1.1 PJPDC1.4 PJPDC1.5
/BATPRES: PR728.2 PR816.2 PU700.15
A_ON: RPE10.3 RZ42.1 UE2.A4 UL3.5
AC_DIS: PQ6.5 PQ712.2 PR828.1 UE2.A10
AC_PRESENT: RPC1.6 UC1.AJ8 UE2.A54
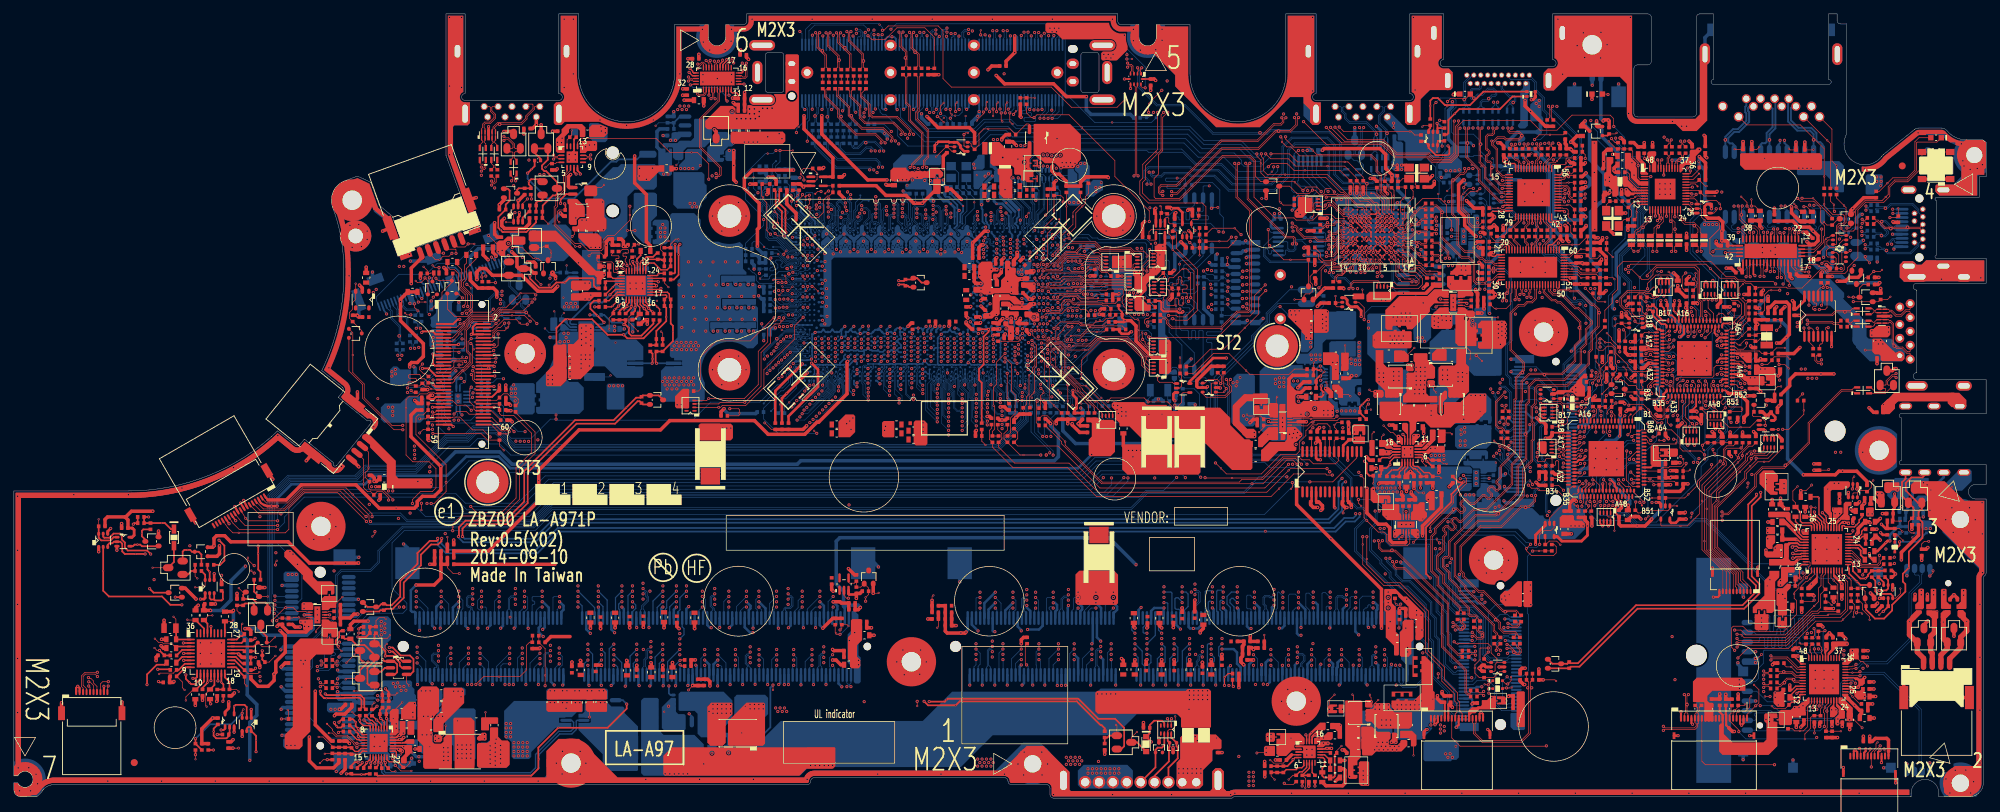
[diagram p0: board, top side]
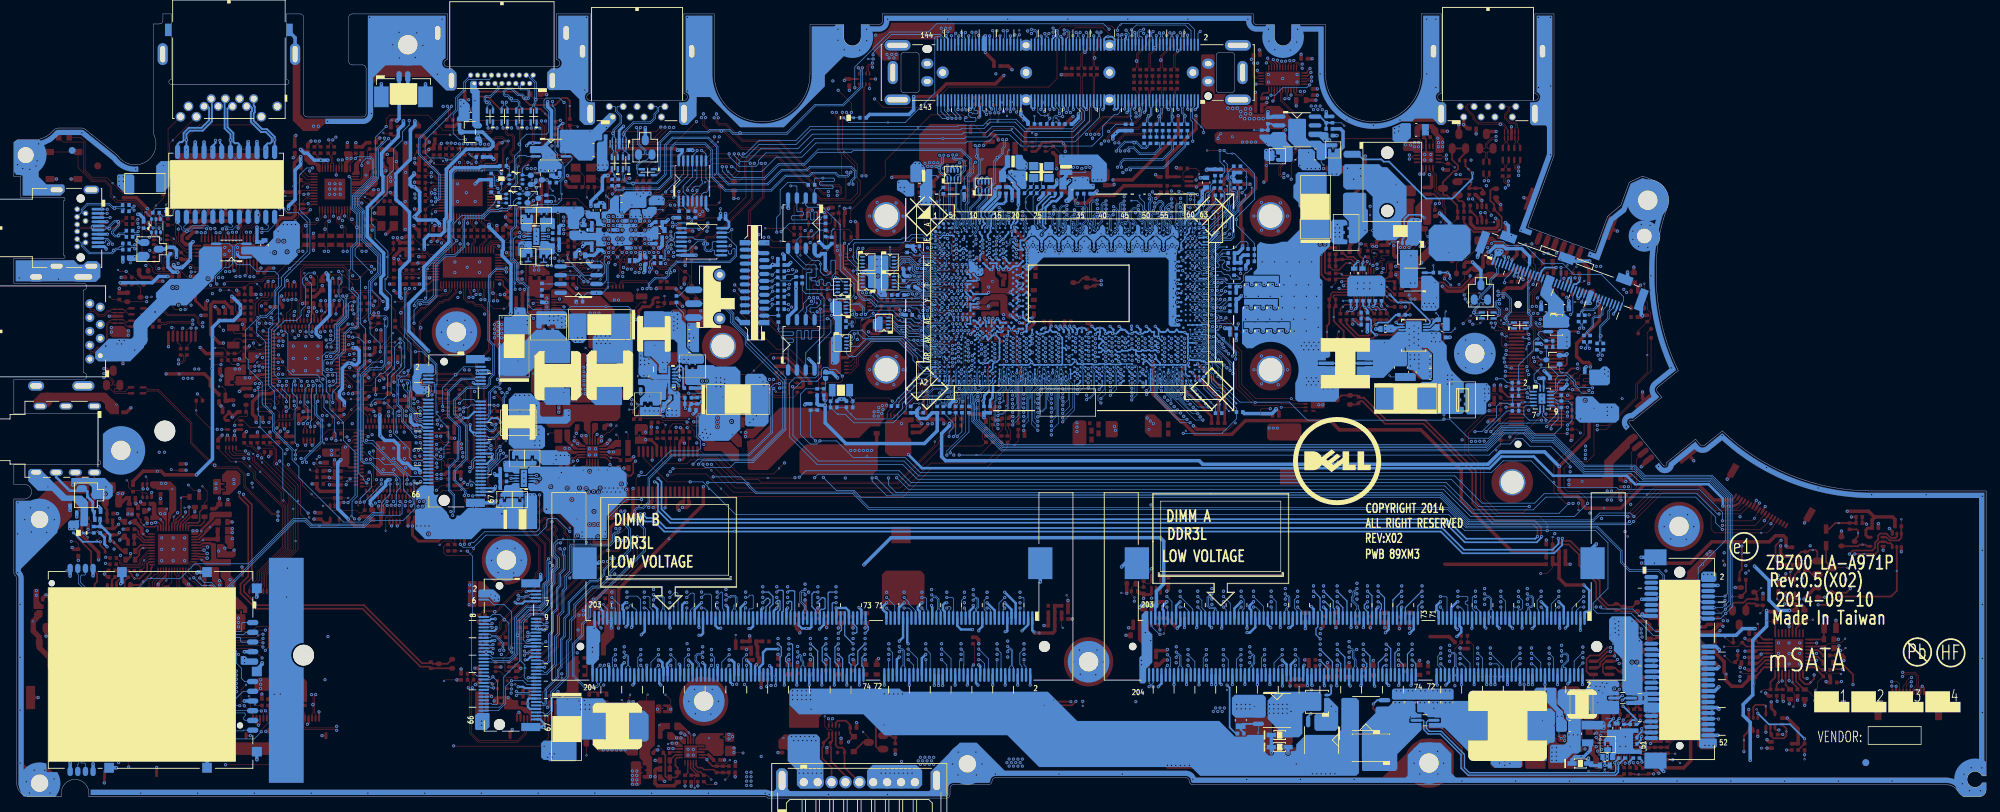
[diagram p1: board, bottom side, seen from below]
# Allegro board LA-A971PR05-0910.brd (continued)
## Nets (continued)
ACAV_DOCK_SRC#: JDOCK1.42 PR842.1 PR846.2
ACAV_IN: PQ712.1 PQ817.5 PR713.2 PR714.1 PR715.1 PR851.1 UE2.A64
ACAV_IN#: PQ817.3 PR864.2 PU806.2
ACAV_IN_NB: PR743.2 PR848.2 UE2.B20
ACAVDK_SRC: PR842.2 PU800.4
ACAVIN: PR851.2 PU800.8
ALW_PWRGD_3V_5V: PR108.1 RE283.2 RZ51.1
ALW_PWRGD_3V_5V_EC: RE283.1 UE2.A1
ALWON: PR113.1 UE2.A60
ANTCTL0: JNGFF2.51 RZ46.1
ANTCTL1: JNGFF2.53 RZ46.2
ANTCTL2: JNGFF2.55 RZ47.1
ANTCTL3: JNGFF2.57 RZ47.2
AUD_HP_NB_SENSE: CA41.1 DA2.3 JHP1.6 QA1.2 RA2.1 UE1.A41
AUD_HP_OUT_L: CA43.2 LA2.1 RA7.2 RA24.1
AUD_HP_OUT_L1: CA3.1 DA3.3 JHP1.1 LA2.2
AUD_HP_OUT_R: CA44.2 LA3.1 RA8.2 RA25.1
AUD_HP_OUT_R1: CA2.1 DA1.2 JHP1.2 LA3.2
AUD_NB_MUTE#: CA31.1 QA2.2 RA18.2 UA1.48 UE1.A39
AUD_OUT_L: RA7.1 UA1.33
AUD_OUT_R: RA8.1 UA1.32
AUD_PC_BEEP: CA27.2 CA28.2 UA1.12
AUD_SENSE_A: QA1.1 UA1.13
AUD_SENSE_B: RA27.1 RA28.1 RA38.1 UA1.14
AUX_EN_WOWL: RZ38.2 UE1.B67 UZ2.5 UZ11.1
B-RAMP: PR502.1 PR507.2 PU500.11
BAT1_LED#: QZ5.1 RZ44.1 UE2.B1
BAT1_LED#_Q: QZ5.6 RZ28.1
BAT2_LED#: QZ5.4 RZ43.1 UE2.A55
BAT2_LED#_Q: QZ5.3 RZ25.1
BATDRV#: PQ800.4 PR722.2
BATT_WHITE#: LED7.1 RZ25.2
BATT_WHITE_LED#: JLED1.5 RZ43.2
BATT_YELLOW#: LED7.3 RZ28.2
BATT_YELLOW_LED#: JLED1.4 RZ44.2
BBS_BIT: T109.1(TP-1) UC1.L8
BC_CLK_ECE1117: JKBTP1.10 UE2.A20
BC_CLK_ECE5048: UE1.A30 UE2.A43
BC_DAT_ECE1117: JKBTP1.8 RPE5.2 UE2.B21
BC_DAT_ECE5048: RE36.2 UE1.B31 UE2.B45
BC_INT#_ECE1117: JKBTP1.7 UE2.A19
BC_INT#_ECE5048: UE1.A29 UE2.A42
BCM5882_ALERT#: JUSH1.7 UE1.B62
BEEP: RA13.2 UE2.B19
BIA_PWM: DV1.1 LV1.2 RV1.1
BIA_PWM_EC: DV1.2 UE2.B25
BLUE_DOCK: JDOCK1.45 RV78.1 UV8.M8
BOARD_ID: CE40.1 RE79.2 UE2.B10
BOOT_1.35V: PR200.2 PU200.18
BOOT_1.35V_C: PC204.1 PR200.1
BQ24770_REGN: PC710.1 PR713.1 PR725.1 PR799.2 PU700.24
BREATH_LED#: JDOCK1.98 QZ7.4 RZ34.1 UE2.B57
BREATH_LED#_Q: LED3.1 QZ7.3
BREATH_WHITE_LED: LED3.2 RZ32.1
BREATH_WHITE_LED#: JLED1.2 RZ34.2
BST_3V: PR110.2 PU100.9
BST_3V_C: PC109.2 PR110.1
BST_5V: PR109.1 PU100.17
BST_5V_C: PC110.1 PR109.2
BST_+V1.05SP: PC302.1 PU300.6
BST_+V1.05SP_C: PC302.2 PR312.1
BT_LED#: JNGFF1.8 QZ2.4 RZ15.1
BT_RADIO_DIS#: DZ2.1 RE11.2 UE1.A13
BT_RADIO_DIS#_R: DZ2.2 JNGFF1.46
CAM_MIC_CBL_DET#: JEDP1.14 RPC16.5 UC1.F4
CD3301_DCIN: PC813.1 PR835.2 PU800.1
CD3301_SDC_IN: PR847.2 PU800.6
CD_PBATT_OFF: PR843.1 PU800.27
CFG0: JXDP1.9 RC183.1 UC1.AC60
CFG1: JXDP1.11 RC184.1 UC1.AC62
CFG2: JXDP1.15 UC1.AC63
CFG3: JXDP1.17 RC113.2 RC305.1 UC1.AA63
CFG3_R: JXDP1.60 RC113.1
CFG4: JXDP1.27 RC191.1 UC1.AA60
CFG5: JXDP1.29 UC1.Y62
CFG6: JXDP1.33 UC1.Y61
CFG7: JXDP1.35 UC1.Y60
CFG8: JXDP1.10 RC190.1 UC1.V62
CFG9: JXDP1.12 RC189.1 UC1.V61
CFG10: JXDP1.16 RC188.1 UC1.V60
CFG11: JXDP1.18 UC1.U60
CFG12: JXDP1.28 UC1.T63
CFG13: JXDP1.30 UC1.T62
CFG14: JXDP1.34 UC1.T61
CFG15: JXDP1.36 UC1.T60
CFG16: JXDP1.6 UC1.AA62
CFG17: JXDP1.4 UC1.AA61
CFG18: JXDP1.24 UC1.U63
CFG19: JXDP1.22 UC1.U62
CFG_RCOMP: RC185.1 UC1.V63
CHAGER_SRC: PC713.1 PC714.1 PC715.1 PC716.1 PC717.1 PC732.1 PJP700.2 PL700.1 PQ704.2
CHARGER_CELL_PIN: PR725.2 PR729.1 PU700.16
CHARGER_SMBCLK: PT2.1(TP-1) PU700.12 RPE6.3 UE2.B50
CHARGER_SMBDAT: PT1.1(TP-1) PU700.11 RPE6.2 UE2.A47
CHG_BTS: PR712.1 PU700.25
CHG_BTS_C: PC712.1 PR712.2
CHG_LGATE: PQ704.6 PU700.23
CHG_SNUB: PC721.1 PR726.1
CHG_SW: PC712.2 PL701.2 PQ704.7 PR726.2 PU700.27
CHG_UGATE: PQ704.1 PU700.26
CLK_27M_IN: CV115.1 RV80.1 UV8.K1 YV2.1
CLK_27M_OUT: RV80.2 RV81.2 UV8.L1
CLK_BIASREF: RC69.1 UC1.C26
CLK_DDC2_DOCK: JDOCK1.48 UV8.L4
CLK_KBD: JDOCK1.78 RPE2.8 UE2.A38
CLK_MSE: JDOCK1.71 RPE2.6 UE2.A39
CLK_PCI_DOCK: CC15.2 JDOCK1.121 R273.1 RC70.2
CLK_PCI_LPDEBUG: CC14.2 JLPDE1.10 JMINI3.19 RC67.2
CLK_PCI_MEC: CC13.2 RC74.2 RE66.1 UE2.A29
CLK_PCI_SIO: CC12.2 RC72.2 RE27.1 UE1.A28
CLK_PCIE_LAN: UC1.B42 UL1.44
CLK_PCIE_LAN#: UC1.C41 UL1.45
CLK_PCIE_MMI: UC1.C42 UR1.3
CLK_PCIE_MMI#: UC1.C43 UR1.2
CLK_PCIE_SATA: JNGFF2.47 UC1.A37
CLK_PCIE_SATA#: JNGFF2.45 UC1.B37
CLK_PCIE_WIGIG: JNGFF1.63 UC1.B39
CLK_PCIE_WIGIG#: JNGFF1.65 UC1.A39
CLK_PCIE_WLAN: JNGFF1.39 UC1.C37
CLK_PCIE_WLAN#: JNGFF1.41 UC1.B38
CLK_TP_SIO: CZ31.1 JKBTP1.14 RZ19.2 UE2.A37
CLKRUN#: RPC15.3 UC1.V5 UE1.B20 UE2.A32
CMPIN: PC737.1 PR737.2 PR738.1 PR745.1 PU700.13
CMPOUT: PC741.2 PR738.2 PR740.1 PR743.1 PU700.14
CONTACTLESS_DET#: JUSH1.17 RPC6.5 UC1.U6
CORE_BOOT: PC504.2 PU501.7
CORE_BOOT_C: PC504.1 PR517.2
CORE_BOOT_R: PR517.1 PU501.6
CORE_SNUB: PC508.1 PR522.2
CORE_SW: PL500.4 PR522.1 PU501.4
CPPE#: RC160.2 UC1.J1
CPU_DPB_AUX: CV79.1 RPC20.2 UC1.B5
CPU_DPB_AUX#: CV80.1 RPC20.1 UC1.C5
CPU_DPB_AUX#_C: CV80.2 UV7.51
CPU_DPB_AUX_C: CV79.2 UV7.52
CPU_DPB_CTRLCLK: RPC2.2 UC1.B9 UV7.50
CPU_DPB_CTRLDAT: RPC2.1 UC1.C9 UV7.49
CPU_DPC_AUX: CV512.2 RPC20.3 UC1.A6
CPU_DPC_AUX#: CV513.2 RPC20.4 UC1.B6
CPU_DPC_CTRLCLK: RPC2.3 UC1.D9 UV502.12
CPU_DPC_CTRLDAT: RPC2.4 UC1.D11 UV502.9
CPU_PWR_DEBUG#: JXDP1.45 RC197.2 RC198.1 UC1.H59
CPU_XDP_PRDY#: JXDP1.5 UC1.J62
CPU_XDP_PREQ#: JXDP1.3 RC126.2 UC1.K62
CPU_XDP_TCLK: JXDP1.57 RC112.1 RC119.1 RC128.2 UC1.E60
CPU_XDP_TDI: RC125.2 UC1.F63 UC7.6
CPU_XDP_TDO: RC127.2 UC1.F62 UC7.3
CPU_XDP_TMS: RC124.2 UC1.E61 UC7.8
CPU_XDP_TRST#: RC109.1 RC129.2 UC1.E59 UC7.11
CPUSB#: RPC4.6 UC1.K3
CS_1.35V: PR201.2 PU200.13
CSN1: PC502.1 PC513.1 PL500.2 PR514.2 PR515.2 PU500.18
CSP1: PC502.2 PC513.2 PH501.1 PR512.1 PR514.1 PU500.17
CSS_GC: PR702.1 PU800.10
CSSN_1: PQ701.3 PQ703.2 PR703.1 PR705.2 PR707.1
CSSP_1: PQ702.3 PQ703.5 PR703.2 PR704.2 PR706.1
D_CLKRUN#: JDOCK1.111 RPE8.4 UE1.A19
D_DLDRQ1#: JDOCK1.117 RPE8.2 UE1.B24
D_LAD0: JDOCK1.97 UE1.B29
D_LAD1: JDOCK1.99 UE1.B28
D_LAD2: JDOCK1.103 UE1.A25
D_LAD3: JDOCK1.105 UE1.A24
D_LFRAME#: JDOCK1.109 UE1.B23
D_SERIRQ: JDOCK1.115 RPE8.3 UE1.A20
DAI_12MHZ#: JDOCK1.89 R41.1 RA30.1
DAI_BCLK#: JDOCK1.77 R6.1 RA31.1
DAI_DI: JDOCK1.83 UA1.24
DAI_DO#: JDOCK1.85 RA32.1
DAI_LRCK#: JDOCK1.79 UA1.18
DAT_DDC2_DOCK: JDOCK1.46 UV8.M4
DAT_KBD: JDOCK1.80 RPE2.7 UE2.B41
DAT_MSE: JDOCK1.73 RPE2.5 UE2.B42
DAT_TP_SIO: CZ30.1 JKBTP1.13 RZ18.2 UE2.B40
DC_BLOCK_GC: PR700.2 PU800.7
DC_IN_SS: PR831.2 PU800.34
DC_TEST_A3_B3: UC1.A3 UC1.B3
DC_TEST_A4: RC192.1 UC1.A4
DC_TEST_A60: RC193.1 UC1.A60
DC_TEST_A61_B61: UC1.A61 UC1.B61
DC_TEST_A62: RC193.2 UC1.A62
DC_TEST_AV1: RC194.1 UC1.AV1
DC_TEST_AW1: RC194.2 UC1.AW1
DC_TEST_AW63: RC195.1 UC1.AW63
DC_TEST_AY2_AW2: UC1.AW2 UC1.AY2
DC_TEST_AY3_AW3: UC1.AW3 UC1.AY3
DC_TEST_AY60: RC195.2 UC1.AY60
DC_TEST_AY61_AW61: UC1.AW61 UC1.AY61
DC_TEST_AY62_AW62: UC1.AW62 UC1.AY62
DC_TEST_B62_B63: UC1.B62 UC1.B63
DC_TEST_C1_C2: UC1.C1 UC1.C2
DDI1_LANE_N0: CV72.1 UC1.C54
DDI1_LANE_N0_C: CV72.2 UV7.4
DDI1_LANE_N1: CV74.1 UC1.B58
DDI1_LANE_N1_C: CV74.2 UV7.7
DDI1_LANE_N2: CV76.1 UC1.B55
DDI1_LANE_N2_C: CV76.2 UV7.10
DDI1_LANE_N3: CV78.1 UC1.A57
DDI1_LANE_N3_C: CV78.2 UV7.13
DDI1_LANE_P0: CV71.1 UC1.C55
DDI1_LANE_P0_C: CV71.2 UV7.3
DDI1_LANE_P1: CV73.1 UC1.C58
DDI1_LANE_P1_C: CV73.2 UV7.6
DDI1_LANE_P2: CV75.1 UC1.A55
DDI1_LANE_P2_C: CV75.2 UV7.9
DDI1_LANE_P3: CV77.1 UC1.B57
DDI1_LANE_P3_C: CV77.2 UV7.12
DDI2_LANE_N0: CV508.2 UC1.C51
DDI2_LANE_N1: CV506.2 UC1.C53
DDI2_LANE_N2: CV504.2 UC1.C49
DDI2_LANE_N3: CV502.2 UC1.A53
DDI2_LANE_P0: CV507.2 UC1.C50
DDI2_LANE_P1: CV505.2 UC1.B54
DDI2_LANE_P2: CV503.2 UC1.B50
DDI2_LANE_P3: CV501.2 UC1.B53
DDR3_DRAMRST#: CD6.1 CD35.1 JDIMM1.30 JDIMM2.30 RD3.1
DDR3_DRAMRST#_CPU: CC101.1 RD2.2 RD3.2 UC1.AV15
DDR_A_BS0: JDIMM1.109 UC1.AU35
DDR_A_BS1: JDIMM1.108 UC1.AV35
DDR_A_BS2: JDIMM1.79 UC1.AY41
DDR_A_CAS#: JDIMM1.115 UC1.AU34
DDR_A_D0: JDIMM1.129 UC1.AH63
DDR_A_D1: JDIMM1.131 UC1.AH62
DDR_A_D2: JDIMM1.141 UC1.AK63
DDR_A_D3: JDIMM1.140 UC1.AK62
DDR_A_D4: JDIMM1.132 UC1.AH61
DDR_A_D5: JDIMM1.130 UC1.AH60
DDR_A_D6: JDIMM1.143 UC1.AK61
DDR_A_D7: JDIMM1.142 UC1.AK60
DDR_A_D8: JDIMM1.7 UC1.AM63
DDR_A_D9: JDIMM1.4 UC1.AM62
DDR_A_D10: JDIMM1.17 UC1.AP63
DDR_A_D11: JDIMM1.18 UC1.AP62
DDR_A_D12: JDIMM1.6 UC1.AM61
DDR_A_D13: JDIMM1.5 UC1.AM60
DDR_A_D14: JDIMM1.15 UC1.AP61
DDR_A_D15: JDIMM1.16 UC1.AP60
DDR_A_D16: JDIMM1.159 UC1.AP58
DDR_A_D17: JDIMM1.157 UC1.AR58
DDR_A_D18: JDIMM1.146 UC1.AM57
DDR_A_D19: JDIMM1.148 UC1.AK57
DDR_A_D20: JDIMM1.149 UC1.AL58
DDR_A_D21: JDIMM1.147 UC1.AK58
DDR_A_D22: JDIMM1.158 UC1.AR57
DDR_A_D23: JDIMM1.160 UC1.AN57
DDR_A_D24: JDIMM1.24 UC1.AP55
DDR_A_D25: JDIMM1.22 UC1.AR55
DDR_A_D26: JDIMM1.36 UC1.AM54
DDR_A_D27: JDIMM1.34 UC1.AK54
DDR_A_D28: JDIMM1.23 UC1.AL55
DDR_A_D29: JDIMM1.21 UC1.AK55
DDR_A_D30: JDIMM1.33 UC1.AR54
DDR_A_D31: JDIMM1.35 UC1.AN54
DDR_A_D32: JDIMM1.166 UC1.AY58
DDR_A_D33: JDIMM1.165 UC1.AW58
DDR_A_D34: JDIMM1.175 UC1.AY56
DDR_A_D35: JDIMM1.174 UC1.AW56
DDR_A_D36: JDIMM1.163 UC1.AV58
DDR_A_D37: JDIMM1.164 UC1.AU58
DDR_A_D38: JDIMM1.177 UC1.AV56
DDR_A_D39: JDIMM1.176 UC1.AU56
DDR_A_D40: JDIMM1.42 UC1.AY54
DDR_A_D41: JDIMM1.41 UC1.AW54
DDR_A_D42: JDIMM1.50 UC1.AY52
DDR_A_D43: JDIMM1.51 UC1.AW52
DDR_A_D44: JDIMM1.39 UC1.AV54
DDR_A_D45: JDIMM1.40 UC1.AU54
DDR_A_D46: JDIMM1.52 UC1.AV52
DDR_A_D47: JDIMM1.53 UC1.AU52
DDR_A_D48: JDIMM1.69 UC1.AK40
DDR_A_D49: JDIMM1.67 UC1.AK42
DDR_A_D50: JDIMM1.59 UC1.AM43
DDR_A_D51: JDIMM1.57 UC1.AM45
DDR_A_D52: JDIMM1.56 UC1.AK45
DDR_A_D53: JDIMM1.58 UC1.AK43
DDR_A_D54: JDIMM1.68 UC1.AM40
DDR_A_D55: JDIMM1.70 UC1.AM42
DDR_A_D56: JDIMM1.192 UC1.AM46
DDR_A_D57: JDIMM1.194 UC1.AK46
DDR_A_D58: JDIMM1.183 UC1.AM49
DDR_A_D59: JDIMM1.182 UC1.AK49
DDR_A_D60: JDIMM1.191 UC1.AM48
DDR_A_D61: JDIMM1.193 UC1.AK48
DDR_A_D62: JDIMM1.181 UC1.AM51
DDR_A_D63: JDIMM1.180 UC1.AK51
DDR_A_DQS0: JDIMM1.137 UC1.AJ62
DDR_A_DQS1: JDIMM1.12 UC1.AN61
DDR_A_DQS2: JDIMM1.154 UC1.AN58
DDR_A_DQS3: JDIMM1.29 UC1.AN55
DDR_A_DQS4: JDIMM1.171 UC1.AW57
DDR_A_DQS5: JDIMM1.47 UC1.AW53
DDR_A_DQS6: JDIMM1.64 UC1.AL42
DDR_A_DQS7: JDIMM1.188 UC1.AL49
DDR_A_DQS#0: JDIMM1.135 UC1.AJ61
DDR_A_DQS#1: JDIMM1.10 UC1.AN62
DDR_A_DQS#2: JDIMM1.152 UC1.AM58
DDR_A_DQS#3: JDIMM1.27 UC1.AM55
DDR_A_DQS#4: JDIMM1.169 UC1.AV57
DDR_A_DQS#5: JDIMM1.45 UC1.AV53
DDR_A_DQS#6: JDIMM1.62 UC1.AL43
DDR_A_DQS#7: JDIMM1.186 UC1.AL48
DDR_A_MA0: JDIMM1.98 UC1.AU36
DDR_A_MA1: JDIMM1.97 UC1.AY37
DDR_A_MA2: JDIMM1.96 UC1.AR38
DDR_A_MA3: JDIMM1.95 UC1.AP36
DDR_A_MA4: JDIMM1.92 UC1.AU39
DDR_A_MA5: JDIMM1.91 UC1.AR36
DDR_A_MA6: JDIMM1.90 UC1.AV40
DDR_A_MA7: JDIMM1.86 UC1.AW39
DDR_A_MA8: JDIMM1.89 UC1.AY39
DDR_A_MA9: JDIMM1.85 UC1.AU40
DDR_A_MA10: JDIMM1.107 UC1.AP35
DDR_A_MA11: JDIMM1.84 UC1.AW41
DDR_A_MA12: JDIMM1.83 UC1.AU41
DDR_A_MA13: JDIMM1.119 UC1.AR35
DDR_A_MA14: JDIMM1.80 UC1.AV42
DDR_A_MA15: JDIMM1.78 UC1.AU42
DDR_A_RAS#: JDIMM1.110 UC1.AY34
DDR_A_WE#: JDIMM1.113 UC1.AW34
DDR_B_BS0: JDIMM2.109 UC1.AL35
DDR_B_BS1: JDIMM2.108 UC1.AM36
DDR_B_BS2: JDIMM2.79 UC1.AU49
DDR_B_CAS#: JDIMM2.115 UC1.AM33
DDR_B_D0: JDIMM2.132 UC1.AY31
DDR_B_D1: JDIMM2.131 UC1.AW31
DDR_B_D2: JDIMM2.140 UC1.AY29
DDR_B_D3: JDIMM2.141 UC1.AW29
DDR_B_D4: JDIMM2.129 UC1.AV31
DDR_B_D5: JDIMM2.130 UC1.AU31
DDR_B_D6: JDIMM2.142 UC1.AV29
DDR_B_D7: JDIMM2.143 UC1.AU29
DDR_B_D8: JDIMM2.5 UC1.AY27
DDR_B_D9: JDIMM2.6 UC1.AW27
DDR_B_D10: JDIMM2.15 UC1.AY25
DDR_B_D11: JDIMM2.17 UC1.AW25
DDR_B_D12: JDIMM2.4 UC1.AV27
DDR_B_D13: JDIMM2.16 UC1.AU27
DDR_B_D14: JDIMM2.7 UC1.AV25
DDR_B_D15: JDIMM2.18 UC1.AU25
DDR_B_D16: JDIMM2.146 UC1.AM29
DDR_B_D17: JDIMM2.148 UC1.AK29
DDR_B_D18: JDIMM2.160 UC1.AL28
DDR_B_D19: JDIMM2.158 UC1.AK28
DDR_B_D20: JDIMM2.149 UC1.AR29
DDR_B_D21: JDIMM2.147 UC1.AN29
DDR_B_D22: JDIMM2.157 UC1.AR28
DDR_B_D23: JDIMM2.159 UC1.AP28
DDR_B_D24: JDIMM2.24 UC1.AN26
DDR_B_D25: JDIMM2.22 UC1.AR26
DDR_B_D26: JDIMM2.33 UC1.AR25
DDR_B_D27: JDIMM2.35 UC1.AP25
DDR_B_D28: JDIMM2.21 UC1.AK26
DDR_B_D29: JDIMM2.23 UC1.AM26
DDR_B_D30: JDIMM2.34 UC1.AK25
DDR_B_D31: JDIMM2.36 UC1.AL25
DDR_B_D32: JDIMM2.166 UC1.AY23
DDR_B_D33: JDIMM2.165 UC1.AW23
DDR_B_D34: JDIMM2.174 UC1.AY21
DDR_B_D35: JDIMM2.175 UC1.AW21
DDR_B_D36: JDIMM2.163 UC1.AV23
DDR_B_D37: JDIMM2.164 UC1.AU23
DDR_B_D38: JDIMM2.176 UC1.AV21
DDR_B_D39: JDIMM2.177 UC1.AU21
DDR_B_D40: JDIMM2.39 UC1.AY19
DDR_B_D41: JDIMM2.41 UC1.AW19
DDR_B_D42: JDIMM2.53 UC1.AY17
DDR_B_D43: JDIMM2.52 UC1.AW17
DDR_B_D44: JDIMM2.42 UC1.AV19
DDR_B_D45: JDIMM2.40 UC1.AU19
DDR_B_D46: JDIMM2.51 UC1.AV17
DDR_B_D47: JDIMM2.50 UC1.AU17
DDR_B_D48: JDIMM2.191 UC1.AR21
DDR_B_D49: JDIMM2.183 UC1.AR22
DDR_B_D50: JDIMM2.194 UC1.AL21
DDR_B_D51: JDIMM2.180 UC1.AM22
DDR_B_D52: JDIMM2.181 UC1.AN22
DDR_B_D53: JDIMM2.193 UC1.AP21
DDR_B_D54: JDIMM2.192 UC1.AK21
DDR_B_D55: JDIMM2.182 UC1.AK22
DDR_B_D56: JDIMM2.57 UC1.AN20
DDR_B_D57: JDIMM2.59 UC1.AR20
DDR_B_D58: JDIMM2.69 UC1.AK18
DDR_B_D59: JDIMM2.67 UC1.AL18
DDR_B_D60: JDIMM2.58 UC1.AK20
DDR_B_D61: JDIMM2.56 UC1.AM20
DDR_B_D62: JDIMM2.70 UC1.AR18
DDR_B_D63: JDIMM2.68 UC1.AP18
DDR_B_DQS0: JDIMM2.137 UC1.AV30
DDR_B_DQS1: JDIMM2.12 UC1.AW26
DDR_B_DQS2: JDIMM2.154 UC1.AM28
DDR_B_DQS3: JDIMM2.29 UC1.AM25
DDR_B_DQS4: JDIMM2.171 UC1.AV22
DDR_B_DQS5: JDIMM2.47 UC1.AW18
DDR_B_DQS6: JDIMM2.188 UC1.AM21
DDR_B_DQS7: JDIMM2.64 UC1.AM18
DDR_B_DQS#0: JDIMM2.135 UC1.AW30
DDR_B_DQS#1: JDIMM2.10 UC1.AV26
DDR_B_DQS#2: JDIMM2.152 UC1.AN28
DDR_B_DQS#3: JDIMM2.27 UC1.AN25
DDR_B_DQS#4: JDIMM2.169 UC1.AW22
DDR_B_DQS#5: JDIMM2.45 UC1.AV18
DDR_B_DQS#6: JDIMM2.186 UC1.AN21
DDR_B_DQS#7: JDIMM2.62 UC1.AN18
DDR_B_MA0: JDIMM2.98 UC1.AP40
DDR_B_MA1: JDIMM2.97 UC1.AR40
DDR_B_MA2: JDIMM2.96 UC1.AP42
DDR_B_MA3: JDIMM2.95 UC1.AR42
DDR_B_MA4: JDIMM2.92 UC1.AR45
DDR_B_MA5: JDIMM2.91 UC1.AP45
DDR_B_MA6: JDIMM2.90 UC1.AW46
DDR_B_MA7: JDIMM2.86 UC1.AY46
DDR_B_MA8: JDIMM2.89 UC1.AY47
DDR_B_MA9: JDIMM2.85 UC1.AU46
DDR_B_MA10: JDIMM2.107 UC1.AK36
DDR_B_MA11: JDIMM2.84 UC1.AV47
DDR_B_MA12: JDIMM2.83 UC1.AU47
DDR_B_MA13: JDIMM2.119 UC1.AK33
DDR_B_MA14: JDIMM2.80 UC1.AR46
DDR_B_MA15: JDIMM2.78 UC1.AP46
DDR_B_RAS#: JDIMM2.110 UC1.AM35
DDR_B_WE#: JDIMM2.113 UC1.AK35
DDR_CKE0_DIMMA: JDIMM1.73 UC1.AU43
DDR_CKE1_DIMMA: JDIMM1.74 UC1.AW43
DDR_CKE2_DIMMB: JDIMM2.73 UC1.AY49
DDR_CKE3_DIMMB: JDIMM2.74 UC1.AU50
DDR_CS0_DIMMA#: JDIMM1.114 UC1.AP33
DDR_CS1_DIMMA#: JDIMM1.121 UC1.AR32
DDR_CS2_DIMMB#: JDIMM2.114 UC1.AM32
DDR_CS3_DIMMB#: JDIMM2.121 UC1.AK32
DDR_PG_CTRL: CC109.1 UC1.AV61 UD1.2
DDR_XDP_WAN_SMBCLK: JDIMM1.202 JDIMM2.202 JXDP1.53 QC1.1 RN4.2
DDR_XDP_WAN_SMBDAT: JDIMM1.200 JDIMM2.200 JXDP1.51 QC1.4 RN3.2
DGPU_PWROK: RPC18.8 UC1.P4
DH_1.35V: PQ200.4 PU200.17
DIMM_DET: RC302.2 RC303.1 UC1.U4
DIS_BAT_PROCHOT#: PR812.1 UE1.B51
DISP_ON: DV2.1 JEDP1.22 RV2.1
DK_AC_OFF: PD815.3 PU800.25
DK_AC_OFF_EN: PR850.1 PU800.22
DK_CSS_GC: PR709.1 PU800.11
DK_PWRBAR: PR832.1 PU800.33
DL_1.35V: PQ201.4 PU200.15
DMIC0: CA6.1 JEDP1.7 UA1.47
DMIC_CLK: CA5.1 CA30.1 JEDP1.9 RA14.2
DMIC_CLK_L: RA14.1 UA1.2
DOCK_AC_OFF: JDOCK1.2 PD815.1 PR844.1
DOCK_AC_OFF_EC: PR850.2 PR858.1 UE1.A63
DOCK_DCIN_IS+: JDOCK1.134 PQ703.6
DOCK_DCIN_IS-: JDOCK1.136 PQ703.4
DOCK_DET#: D19.2 PQ817.2 PR853.1 R272.1 UE1.B41
DOCK_DET_R#: D19.1 JDOCK1.142 JDOCK1.144
DOCK_HP_DET: QA3.2 RA29.2 UE1.A7
DOCK_LOM_ACTLED_YEL#: JDOCK1.100 UL4.19
DOCK_LOM_SPD10LED_GRN#: JDOCK1.3 UL4.40
DOCK_LOM_SPD100LED_ORG#: JDOCK1.4 UL4.20
DOCK_LOM_TRD0+: JDOCK1.104 UL4.36
DOCK_LOM_TRD0-: JDOCK1.106 UL4.35
DOCK_LOM_TRD1+: JDOCK1.110 UL4.32
DOCK_LOM_TRD1-: JDOCK1.112 UL4.31
DOCK_LOM_TRD2+: JDOCK1.122 UL4.27
DOCK_LOM_TRD2-: JDOCK1.124 UL4.26
DOCK_LOM_TRD3+: JDOCK1.128 UL4.23
DOCK_LOM_TRD3-: JDOCK1.130 UL4.22
DOCK_MIC_DET: QA3.5 RA26.2 UE1.B8
DOCK_POR_RST#: JDOCK1.140 RE277.2 UE2.A21
DOCK_PSID: JDOCK1.135 PU1.1
DOCK_PWR_BTN#: CE44.1 JDOCK1.139 RE42.2
DOCK_PWR_SW#: CE45.1 RE42.1 RE62.2 UE2.A63
DOCK_SMB_ALERT#: JDOCK1.133 PQ1.3 RE9.2 UE1.A51
DOCK_SMB_CLK: JDOCK1.127 RPE3.1 UE2.B4
DOCK_SMB_DAT: JDOCK1.129 RPE3.2 UE2.A3
DOCK_USB3RN1: JDOCK1.84 UI4.22
DOCK_USB3RP1: JDOCK1.86 UI4.23
DOCK_USB3TN1: JDOCK1.90 UI4.24
DOCK_USB3TP1: JDOCK1.92 UI4.25
DOCK_USBP0+: JDOCK1.72 UI4.15
DOCK_USBP0-: JDOCK1.74 UI4.14
DOCK_USBP3+: JDOCK1.66 UI5.3
DOCK_USBP3-: JDOCK1.68 UI5.4
DOCKED: QV700.2 UE1.A38 UI4.10 UI4.32 UL4.13 UV13.3 UV13.5
DOCKED#: QV700.5 QV700.6 RV701.2
DOCKED_LIO_EN: UE1.B52 UI5.9
DPB_CA_DET: JDOCK1.6 QV9.2 RV508.2 UV8.M14 UV11.1 UV11.4
DPB_CA_DET#: QV9.1 RV90.2 UV11.10 UV11.13
DPB_DOCK_AUX: JDOCK1.34 UV11.3 UV11.11
DPB_DOCK_AUX#: JDOCK1.36 UV11.6 UV11.8
DPB_DOCK_HPD: C311.1 JDOCK1.40 R271.1 UV8.K14
DPB_DOCK_LANE_N0: JDOCK1.12 R261.1
DPB_DOCK_LANE_N1: JDOCK1.18 R256.1
DPB_DOCK_LANE_N2: JDOCK1.24 R264.1
DPB_DOCK_LANE_N3: JDOCK1.30 R267.1
DPB_DOCK_LANE_P0: JDOCK1.10 R260.1
DPB_DOCK_LANE_P1: JDOCK1.16 R254.1
DPB_DOCK_LANE_P2: JDOCK1.22 R262.1
DPB_DOCK_LANE_P3: JDOCK1.28 R258.1
DPB_HPD: RC142.2 UC1.C8 UV7.5
DPB_LANE_N0: C296.1 UV8.E14
DPB_LANE_N0_C: C296.2 R261.2
DPB_LANE_N1: C303.1 UV8.F14
DPB_LANE_N1_C: C303.2 R256.2
DPB_LANE_N2: C307.1 UV8.G14
DPB_LANE_N2_C: C307.2 R264.2
DPB_LANE_N3: C309.1 UV8.H14
DPB_LANE_N3_C: C309.2 R267.2
DPB_LANE_P0: C294.1 UV8.E13
DPB_LANE_P0_C: C294.2 R260.2
DPB_LANE_P1: C298.1 UV8.F13
DPB_LANE_P1_C: C298.2 R254.2
DPB_LANE_P2: C305.1 UV8.G13
DPB_LANE_P2_C: C305.2 R262.2
DPB_LANE_P3: C308.1 UV8.H13
DPB_LANE_P3_C: C308.2 R258.2
DPB_MB_P14: JMDP1.6 RV503.2
DPC_CA_DET: JDOCK1.5 QV10.2 RV509.2 UV8.A14 UV12.1 UV12.4
DPC_CA_DET#: QV10.1 RV91.2 UV12.10 UV12.13
DPC_DOCK_AUX: JDOCK1.33 UV12.3 UV12.11
DPC_DOCK_AUX#: JDOCK1.35 UV12.6 UV12.8
DPC_DOCK_HPD: C310.1 JDOCK1.39 R268.1 UV8.A6
DPC_DOCK_LANE_N0: JDOCK1.11 R252.2
DPC_DOCK_LANE_N1: JDOCK1.17 R255.2
DPC_DOCK_LANE_N2: JDOCK1.23 R263.2
DPC_DOCK_LANE_N3: JDOCK1.29 R266.2
DPC_DOCK_LANE_P0: JDOCK1.9 R259.2
DPC_DOCK_LANE_P1: JDOCK1.15 R253.2
DPC_DOCK_LANE_P2: JDOCK1.21 R257.2
DPC_DOCK_LANE_P3: JDOCK1.27 R265.2
DPC_HPD: QV501.3 UC1.A8
DPC_LANE_N0: C295.2 UV8.A7
DPC_LANE_N0_C: C295.1 R252.1
DPC_LANE_N1: C299.2 UV8.A8
DPC_LANE_N1_C: C299.1 R255.1
DPC_LANE_N2: C306.2 UV8.A9
DPC_LANE_N2_C: C306.1 R263.1
DPC_LANE_N3: C301.2 UV8.A10
DPC_LANE_N3_C: C301.1 R266.1
DPC_LANE_P0: C302.2 UV8.B7
DPC_LANE_P0_C: C302.1 R259.1
DPC_LANE_P1: C297.2 UV8.B8
DPC_LANE_P1_C: C297.1 R253.1
DPC_LANE_P2: C304.2 UV8.B9
DPC_LANE_P2_C: C304.1 R257.1
DPC_LANE_P3: C300.2 UV8.B10
DPC_LANE_P3_C: C300.1 R265.1
DSWODVREN: RC78.1 UC1.AW7
EC5048_TX: JDEG1.9 RE74.2 UE1.B2
EC_32KHZ_MEC5085: UE1.B35 UE2.B2 UZ11.2
EDP_BIA_PWM: DV1.3 UC1.B8
EDP_COMP: RC133.2 UC1.D20
EDP_CPU_AUX: CV2.1 UC1.B45
EDP_CPU_AUX#: CV1.1 UC1.A45
EDP_CPU_AUX#_C: CV1.2 JEDP1.33
EDP_CPU_AUX_C: CV2.2 JEDP1.34
EDP_CPU_HPD: JEDP1.26 RC141.2 UC1.D6
EDP_CPU_LANE_N0: CV4.1 UC1.C45
EDP_CPU_LANE_N0_C: CV4.2 JEDP1.36
EDP_CPU_LANE_N1: CV6.1 UC1.A47
EDP_CPU_LANE_N1_C: CV6.2 JEDP1.38
EDP_CPU_LANE_P0: CV3.1 UC1.B46
EDP_CPU_LANE_P0_C: CV3.2 JEDP1.35
EDP_CPU_LANE_P1: CV5.1 UC1.B47
EDP_CPU_LANE_P1_C: CV5.2 JEDP1.37
EN: PC119.1 PR113.2 PU100.6 PU100.20
EN_+V1.05SP: PR303.1 PU300.1 RZ41.2 RZ42.2
EN_DK_PWRBAR: PR857.1 PR874.1 PU800.17
EN_DOCK_PWR_BAR: PR857.2 UE1.B37
EN_I2S_NB_CODEC#: UA1.1 UE1.B36
EN_INVPWR: QV2.2 RE55.2 UE2.A25
EN_LCDPWR: DV3.1 RV3.2 UV24.3
ENVDD_PCH: DV3.3 RC139.2 UC1.C6 UE2.A7
ERC1: PC815.1 PU800.3
ERC2: PC817.1 PU800.13
ERC3: PC816.1 PU800.12
EXPRESS_DET#: T97.1(TP-1) UE1.B15
F-IMAX: PR503.1 PR508.2 PU500.10
FAN1_PWM: CE41.1 JFAN1.3 RE48.2 UE2.A24
FAN1_TACH: CE42.1 JFAN1.2 RE51.2 UE2.B22
FB_3V: PR100.2 PR102.2 PU100.4
FB_5V: PR101.1 PR104.1 PU100.2
FB_+V1.05SP: PR307.2 PR309.2 PR310.1 PU300.4
FFS_INT2: RC158.2 UC1.G2
FWP#: RE81.2 RE82.2 UE2.B65
GC6_EVENT#_Q: RPC16.7 UC1.R6
GFB: PR532.2 PU500.23
GPIO_PSID_SELECT: PU1.6 UE1.A6
GPU_GC6_FB_EN: RPC3.8 UC1.L6
GPU_SMBCLK: RPE3.4 UE2.B49
GPU_SMBDAT: RPE3.3 UE2.B48
GREEN_DOCK: JDOCK1.59 RV77.1 UV8.M7
H_CATERR#: RC114.2 UC1.K61
H_CPU_SVIDALRT#: RC207.1 UC1.L62
H_CPUPWRGD: CC83.1 RC103.1 RC123.1 UC1.C61
H_PROCHOT#: CC20.1 PC514.2 PR534.1 PR717.1 RC116.2 RC121.1 UE2.A46
H_PROCHOT#_R: RC121.2 UC1.K63
H_THERMTRIP#: QE4.3 RC25.2 RC161.1
H_THERMTRIP#_R: RC161.2 UC1.D60
H_VCCST_PWRGD: CC24.1 RC102.1 RC202.1 UC1.B59 UC8.4
H_VCCST_PWRGD_XDP: CC112.1 JXDP1.39 RC102.2 RC103.2
H_VR_EN: PR536.1 RC201.2 RE284.1 UC1.F60
H_VR_READY: PR539.2 RC199.2 RC201.1 UC1.C59
HDD_DET#: CC107.1 JMINI3.51 RPC18.6 UC1.U1
HDD_DEVSLP: JMINI3.44 RN1.2 UC1.L2
HDD_FALL_INT: RPC9.5 UC1.N4
HDMI_CEC: JHDMI1.13 RV8.1
HDMI_CLK_AUX: JHDMI1.15 RV7.1 UV7.48
HDMI_DAT_AUX#: JHDMI1.16 RV9.1 UV7.47
HDMI_HPD: JHDMI1.19 UV7.17
HDMI_LANE_N0: LV12.4 UV7.18
HDMI_LANE_N1: LV10.4 UV7.21
HDMI_LANE_N2: LV6.4 UV7.24
HDMI_LANE_N3: LV3.4 UV7.15
HDMI_LANE_P0: LV12.1 UV7.19
HDMI_LANE_P1: LV10.1 UV7.22
HDMI_LANE_P2: LV6.1 UV7.25
HDMI_LANE_P3: LV3.1 UV7.16
HOST_ALERT1_R_N: RC179.2 UC1.AD6
HOST_DEBUG_TX: JDEG1.8 RE73.2 UE2.B44
HSYNC_DOCK: JDOCK1.65 UV8.M9
HW_GPS_DISABLE2#: DZ6.1 RE12.2 UE1.A35
HW_GPS_DISABLE2#_R: DZ6.2 JNGFF2.18
I2C1_SCL_VMM: RPV2.2 UV8.A2
I2C1_SDA_VMM: RPV2.1 UV8.A1
I2S_BCLK: RA31.2 UA1.16
I2S_DO: RA32.2 UA1.17
I2S_MCLK: RA30.2 UA1.15
I_ADP: PR716.1 UE2.A12
I_BATT: PR718.1 RE64.2
I_SYS: PR720.1 UE2.A57
ILIM_SEL: RI13.1 UI3.4
ILMT_1.05V: PR306.2 PR308.1 PU300.3
IMON: PC500.2 PR501.1 PU500.13
INT_SPK_L+: CA22.1 LA6.1 UA1.42
INT_SPK_L-: CA23.1 LA7.1 UA1.43
INT_SPK_R+: CA19.1 LA8.1 UA1.45
INT_SPK_R-: CA24.1 LA9.1 UA1.44
INT_SPKR_L+: DA6.2 JSPK1.1 LA6.2
INT_SPKR_L-: DA6.3 JSPK1.2 LA7.2
INT_SPKR_R+: DA7.2 JSPK1.3 LA8.2
INT_SPKR_R-: DA7.3 JSPK1.4 LA9.2
INTRUDER#: RC9.2 UC1.AU6
IO_LDOSEL: RR6.2 RR8.1 UR1.18
IRQ_SERIRQ: RPC15.1 UC1.T4 UE1.B21 UE2.A28
JTAG_CLK: JDEG1.4 RPE7.2 UE2.B56
JTAG_RST#: CE30.1 JTAG1.1 RE63.2 RE65.1 UE2.B47
JTAG_TDI: JDEG1.2 RPE7.4 UE2.A51
JTAG_TDO: JDEG1.5 RPE7.1 UE2.B55
JTAG_TMS: JDEG1.3 RPE7.3 UE2.A53
KB_DET#: JKBTP1.1 RPC19.1 UC1.AT3
LAN_ACTLED_YEL#: QL1.6 RL14.1
LAN_ACTLED_YEL_R#: JLOM1.10 RL14.2
LAN_DISABLE#_R: RL5.2 RL7.2 RL9.1 UE1.B53 UL1.3
LAN_SMBCLK: RC30.1 UL1.28
LAN_SMBDATA: RC32.1 UL1.31
LAN_TEST_EN: RL12.1 UL1.30
LAN_TX0+: LL21.1 UL1.13
LAN_TX0+L: LL21.2 UL4.2
LAN_TX0-: LL22.1 UL1.14
LAN_TX0-L: LL22.2 UL4.3
LAN_TX1+: LL23.1 UL1.17
LAN_TX1+L: LL23.2 UL4.6
LAN_TX1-: LL24.1 UL1.18
LAN_TX1-L: LL24.2 UL4.7
LAN_TX2+: LL25.1 UL1.20
LAN_TX2+L: LL25.2 UL4.9
LAN_TX2-: LL26.1 UL1.21
LAN_TX2-L: LL26.2 UL4.10
LAN_TX3+: LL27.1 UL1.23
LAN_TX3+L: LL27.2 UL4.11
LAN_TX3-: LL28.1 UL1.24
LAN_TX3-L: LL28.2 UL4.12
LAN_WAKE#: RC153.1 UC1.AN5 UE2.B27 UL1.2
LANCLK_REQ#: RL4.1 RPC6.6 UC1.AD1 UL1.48
LCD_CBL_DET#: JEDP1.40 RPC4.5 UC1.J3
LCD_TST: JEDP1.29 RE20.2 UE1.A36
LCD_VCC_TEST_EN: DV3.2 UE1.A40
LED_10_GRN#: QL2.6 RL19.1
LED_10_GRN_R#: JLOM1.11 RL19.2
LED_100_ORG#: QL1.3 RL20.1
LED_100_ORG_R#: JLOM1.13 RL20.2
LED_SATA_DIAG_OUT#: DZ4.1 UE1.A10
LG_3V: PQ102.4 PU100.11
LG_5V: PQ103.4 PU100.15
LID_CL#: JSH1.11 RE26.1 UZ10.2
LID_CL_SIO#: CE8.1 RE25.2 RE26.2 UE1.B54
LOM_ACTLED_YEL#: UL1.26 UL4.15
LOM_SPD10LED_GRN#: UL1.25 UL2.2 UL4.42
LOM_SPD100LED_ORG#: UL1.27 UL2.1 UL4.16
LP_CTL: RV79.1 RV516.1 UV8.B2
LPC_LAD0: JLPDE1.3 JMINI3.16 UC1.AU14 UE1.A27 UE2.A30
LPC_LAD1: JLPDE1.4 JMINI3.14 UC1.AW12 UE1.A26 UE2.B32
LPC_LAD2: JLPDE1.5 JMINI3.12 UC1.AY12 UE1.B26 UE2.A31
LPC_LAD3: JLPDE1.6 JMINI3.10 UC1.AW11 UE1.B25 UE2.B33
LPC_LDRQ1#: RPE8.1 UE1.A22
LPC_LFRAME#: JLPDE1.7 JMINI3.8 UC1.AV12 UE1.A21 UE2.B31
M_CLK_DDR0: JDIMM1.101 UC1.AV37
M_CLK_DDR1: JDIMM1.102 UC1.AY36
M_CLK_DDR2: JDIMM2.101 UC1.AN38
M_CLK_DDR3: JDIMM2.102 UC1.AL38
M_CLK_DDR#0: JDIMM1.103 UC1.AU37
M_CLK_DDR#1: JDIMM1.104 UC1.AW36
M_CLK_DDR#2: JDIMM2.103 UC1.AM38
M_CLK_DDR#3: JDIMM2.104 UC1.AK38
M_ODT0: JDIMM1.116 RD10.2
M_ODT1: JDIMM1.120 RD11.2
M_ODT2: JDIMM2.116 RD12.2
M_ODT3: JDIMM2.120 RD13.2
MASK_BASE_LEDS#: QZ5.2 QZ5.5 QZ7.2 QZ7.5 QZ14.2 UZ10.4
MASK_SATA_LED#: QZ3.5 UE1.B9
MCARD_PCIE#_SATA: RPC6.7 UC1.AC1 UE2.B8
MCP_TESTLOW1: RC240.1 UC1.C35
MCP_TESTLOW2: RC241.1 UC1.C34
MCP_TESTLOW3: RC242.1 UC1.AK8
MCP_TESTLOW4: RC243.1 UC1.AL8
MDP_AUX#_C: JMDP1.18 RV501.2 UV502.6 UV502.8
MDP_AUX_C: JMDP1.16 RV502.2 UV502.3 UV502.11
MDP_CA_DET: JMDP1.4 QV502.2 RV504.1 UV502.1 UV502.4
MDP_CA_DET#: QV502.1 RV507.2 UV502.10 UV502.13
MDP_HPD: JMDP1.2 QV501.1 RV505.2
MDP_LANE_N0_C: CV508.1 JMDP1.5
MDP_LANE_N1_C: CV506.1 JMDP1.11
MDP_LANE_N2_C: CV504.1 JMDP1.17
MDP_LANE_N3_C: CV502.1 JMDP1.12
MDP_LANE_P0_C: CV507.1 JMDP1.3
MDP_LANE_P1_C: CV505.1 JMDP1.9
MDP_LANE_P2_C: CV503.1 JMDP1.15
MDP_LANE_P3_C: CV501.1 JMDP1.10
ME_FWP: RC11.1 RC301.1 SW1.3
ME_FWP_EC: RC301.2 SW1.1 UE2.B46
ME_RESET#: RC80.1 RC95.2 UC4.2
ME_SUS_PWR_ACK: RC79.2 UC1.AV4 UE2.A8
MEC_XTAL1: CE28.1 UE2.A61 YE1.1
MEC_XTAL2: CE29.1 RE61.2 YE1.2
MEC_XTAL2_R: RE61.1 UE2.A62
MEDIACARD_IRQ#: RPC5.8 UC1.AB6 UR1.16
MEDIACARD_PWREN: RR15.2 UR1.14
MEDIACARD_RST#: RPC5.7 UC1.AG6
MEM_SMBCLK: QC1.6 RPC14.3 UC1.AP2
MEM_SMBDATA: QC1.3 RPC14.4 UC1.AH1
MIC1_L: CA43.1 UA1.19
MIC1_R: CA44.1 UA1.20
MMICLK_REQ#: RPC18.7 UC1.U2 UR1.17
MPCIE_RST#: RPC18.5 UC1.V1
MPHYP_PWR_EN: QZ10.2 RC155.1 RC171.1 UC1.Y2
MPHYP_PWR_EN#: QZ10.5 QZ10.6 RZ16.2
MSATA_DEVSLP: JNGFF2.30 RZ39.2 UC1.P2
MSCLK: JDEG1.6 RE72.2 UE2.B43
MSDATA: JDEG1.7 RE75.2 RE86.2 UE2.A40
NB_LAN_TX0+: JLOM1.1 TL1.13
NB_LAN_TX0-: JLOM1.2 TL1.14
NB_LAN_TX1+: JLOM1.3 TL1.19
NB_LAN_TX1-: JLOM1.6 TL1.20
NB_LAN_TX2+: JLOM1.4 TL1.17
NB_LAN_TX2-: JLOM1.5 TL1.18
NB_LAN_TX3+: JLOM1.7 TL1.23
NB_LAN_TX3-: JLOM1.8 TL1.24
NB_PSID: PJPDC1.1 PL3.2
NB_PSID_TS5A63157: PR8.1 PR9.2 PU1.3
NFC_IRQ: RC175.1 UC1.AN3
NGFF_CONFIG_0: JNGFF2.13 RPE4.1 UE1.B12
NGFF_CONFIG_1: JNGFF2.61 RPE4.2 UE1.A18
NGFF_CONFIG_2: JNGFF2.67 RPE4.3 UE1.A44
NGFF_CONFIG_3: JNGFF2.1 RPE4.4 UE1.B34
O-USR: PR504.1 PR509.2 PU500.9
OCP-I: PR501.2 PR506.2 PR524.2 PU500.12
OUT1_CA_DET: RV606.2 UV600.43
OUT2_CA_DET: RV607.2 UV600.33
P33ALW: PR859.1 PU800.18
P33ALW2: PR855.2 PU800.9
PANEL_BKEN_EC: DV2.2 UE1.B38
PANEL_BKLEN: DV2.3 UC1.A9
PANEL_HDD_LED#: JLED1.3 QZ4.3
PBAT_PRES#: PD4.1 PR2.2 PR728.1 PRP2.3 PU804.1 UE2.A49
PBAT_PRES#_C: PBATT1.5 PD2.2 PRP2.6
PBAT_SMBCLK: PRP2.1 RE43.2 UE2.A56
PBAT_SMBCLK_C: PBATT1.3 PD1.2 PRP2.8
PBAT_SMBDAT: PRP2.2 RE37.2 UE2.B59
PBAT_SMBDAT_C: PBATT1.4 PD1.3 PRP2.7
PBATT+_C: PBATT1.1 PBATT1.2 PC3.1 PL1.1 PL2.1
PCH_ALW_ON: RPE10.4 UE2.A34 UZ7.5
PCH_AZ_BITCLK: RC23.2 UC1.AW8
PCH_AZ_CODEC_BITCLK: CC5.1 RA17.1 RC23.1 UA1.6
PCH_AZ_CODEC_RST#: RC22.1 UA1.11
PCH_AZ_CODEC_SDIN0: RA9.1 UC1.AY10
PCH_AZ_CODEC_SDOUT: RC19.1 UA1.5
PCH_AZ_CODEC_SYNC: RC20.1 UA1.10
PCH_AZ_RST#: RC22.2 UC1.AU8
PCH_AZ_SDIN0_R: RA9.2 UA1.8
PCH_AZ_SDOUT: RC11.2 RC19.2 UC1.AU11
PCH_AZ_SYNC: RC20.2 UC1.AV11
PCH_BATLOW#: RPC1.8 UC1.AN4
PCH_CL_CLK1: JNGFF1.34 UC1.AF2
PCH_CL_DATA1: JNGFF1.32 UC1.AD2
PCH_CL_RST1#: JNGFF1.30 UC1.AF4
PCH_DPWROK: UC1.AV5 UE2.A36
PCH_GPIO4: RPC8.4 UC1.F2
PCH_GPIO5: RPC8.3 UC1.F3
PCH_GPIO6: RPC8.1 UC1.G4
PCH_GPIO7: RPC8.2 UC1.F1
PCH_GPIO9: RPC5.6 UC1.AM3
PCH_GPIO10: T27.1(TP-1) UC1.AM2
PCH_GPIO14: T21.1(TP-1) UC1.AH4
PCH_GPIO16: RPC6.8 UC1.Y1
PCH_GPIO19: RC66.2 UC1.Y5
PCH_GPIO44: RPC19.4 UC1.AK4
PCH_GPIO46: RPC10.6 UC1.AG3
PCH_GPIO49: T22.1(TP-1) UC1.Y3
PCH_GPIO52: RPC3.6 UC1.L1
PCH_GPIO53: RC140.1 UC1.L4
PCH_GPIO57: RPC7.8 UC1.AP1
PCH_GPIO59: RC245.1 UC1.AT5
PCH_GPIO66: RC176.2 UC1.D3
PCH_GPIO67: RC163.2 UC1.E4
PCH_GPIO68: RC164.2 UC1.C3
PCH_GPIO69: RPC16.6 UC1.E2
PCH_GPIO73: RPC10.8 UC1.AU4
PCH_GPIO76: RPC17.5 UC1.P1
PCH_GPIO80: RPC17.7 UC1.N2
PCH_GPIO85: RPC4.8 UC1.N6
PCH_GPIO87: RPC16.8 UC1.R7
PCH_INTVRMEN: RC1.2 UC1.AV7
PCH_JTAG_JTAGX: RC18.1 RC112.2 RC115.2 UC1.AE63
PCH_JTAG_TCK: JXDP1.55 RC21.1 RC119.2 UC1.AE62
PCH_JTAG_TDI: JXDP1.56 RC99.1 RPC21.4 UC1.AD61
PCH_JTAG_TDO: RC98.1 RC118.2 RPC21.2 UC1.AE61
PCH_JTAG_TMS: JXDP1.58 RPC21.3 UC1.AD62 UC7.9
PCH_JTAG_TRST#: RC109.2 UC1.AU62
PCH_OPI_COMP: RC178.1 UC1.AW15
PCH_PCIE_RCOMP: RC149.2 UC1.A27
PCH_PCIE_WAKE#: RE274.2 RPC1.5 UC1.AJ5 UE2.A44
PCH_PLTRST#: CC104.1 RC87.2 RC88.2 RC89.2 RC219.2 UC1.AG7 UC5.1 UC5.2
PCH_PLTRST#_EC: CC103.1 JLPDE1.8 JMINI3.17 JNGFF1.44 JNGFF1.58 JNGFF2.42 RC106.1 RC304.1 UC5.4 UE1.B22 UE2.B30 UZ1.16
PCH_RSMRST#: RE88.1 UE2.A45 UZ6.1
PCH_RSMRST#_Q: RC91.2 UC1.AW6 UZ6.4
PCH_RTCRST#: CC4.2 CMOS1.2 JAPS1.9 RC8.2 UC1.AU7
PCH_RTCX1: RC4.2 RC7.1 UC1.AW5
PCH_RTCX1_R: CC1.2 RC4.1 YC1.1
PCH_RTCX2: CC2.2 RC7.2 UC1.AY5 YC1.2
PCH_SMB_ALERT#: RPC19.2 UC1.AN2
PCH_SPI_CLK: JSPI1.8 RC227.2 RZ26.1 UC1.AA3
PCH_SPI_CS0#: JSPI1.10 RC228.2 UC1.Y7
PCH_SPI_CS1#: JSPI1.2 RC224.2 UC1.Y4
PCH_SPI_CS2#: RZ17.1 UC1.AC2
PCH_SPI_CS2#_R: RZ17.2 UZ1.22
PCH_SPI_DIN: JSPI1.6 RC226.2 RZ30.1 UC1.AA4
PCH_SPI_DO: JSPI1.4 RC225.2 RZ29.1 UC1.AA2
PCH_SPI_DO2: JSPI1.12 RC229.2 UC1.Y6
PCH_SPI_DO3: JSPI1.14 RC230.2 UC1.AF1
PCI_CLK_LPC_0: RC72.1 RC74.1 UC1.AN15
PCI_CLK_LPC_1: RC67.1 RC70.1 UC1.AP15
PCIE_PRX_GLANTX_N3: CL2.2 UC1.G11
PCIE_PRX_GLANTX_N3_C: CL2.1 UL1.39
PCIE_PRX_GLANTX_P3: CL1.2 UC1.F11
PCIE_PRX_GLANTX_P3_C: CL1.1 UL1.38
PCIE_PRX_MMITX_N1: CR27.1 UC1.G17
PCIE_PRX_MMITX_N1_C: CR27.2 UR1.8
PCIE_PRX_MMITX_P1: CR26.1 UC1.F17
PCIE_PRX_MMITX_P1_C: CR26.2 UR1.7
PCIE_PRX_SATATX_N6_L0: JNGFF2.35 UC1.F5
PCIE_PRX_SATATX_N6_L1: JNGFF2.21 UC1.J6
PCIE_PRX_SATATX_P6_L0: JNGFF2.33 UC1.E5
PCIE_PRX_SATATX_P6_L1: JNGFF2.23 UC1.H6
PCIE_PRX_WIGIGTX_N5: JNGFF1.59 UC1.F10
PCIE_PRX_WIGIGTX_P5: JNGFF1.57 UC1.E10
PCIE_PRX_WLANTX_N4: JNGFF1.35 UC1.F13
PCIE_PRX_WLANTX_P4: JNGFF1.33 UC1.G13
PCIE_PTX_GLANRX_N3: CL6.1 UC1.C29
PCIE_PTX_GLANRX_N3_C: CL6.2 UL1.42
PCIE_PTX_GLANRX_P3: CL5.1 UC1.B30
PCIE_PTX_GLANRX_P3_C: CL5.2 UL1.41
PCIE_PTX_MMIRX_N1: CR25.1 UC1.C30
PCIE_PTX_MMIRX_N1_C: CR25.2 UR1.5
PCIE_PTX_MMIRX_P1: CR24.1 UC1.C31
PCIE_PTX_MMIRX_P1_C: CR24.2 UR1.6
PCIE_PTX_SATARX_N6_L0: CZ58.1 UC1.C17
PCIE_PTX_SATARX_N6_L0_C: CZ58.2 JNGFF2.39
PCIE_PTX_SATARX_N6_L1: CZ32.1 UC1.B14
PCIE_PTX_SATARX_N6_L1_C: CZ32.2 JNGFF2.27
PCIE_PTX_SATARX_P6_L0: CZ59.1 UC1.D17
PCIE_PTX_SATARX_P6_L0_C: CZ59.2 JNGFF2.41
PCIE_PTX_SATARX_P6_L1: CZ33.1 UC1.C15
PCIE_PTX_SATARX_P6_L1_C: CZ33.2 JNGFF2.29
PCIE_PTX_WIGIGRX_N5: CZ22.1 UC1.C23
PCIE_PTX_WIGIGRX_N5_C: CZ22.2 JNGFF1.53
PCIE_PTX_WIGIGRX_P5: CZ21.1 UC1.C22
PCIE_PTX_WIGIGRX_P5_C: CZ21.2 JNGFF1.51
PCIE_PTX_WLANRX_N4: CZ14.1 UC1.B29
PCIE_PTX_WLANRX_N4_C: CZ14.2 JNGFF1.29
PCIE_PTX_WLANRX_P4: CZ13.1 UC1.A29
PCIE_PTX_WLANRX_P4_C: CZ13.2 JNGFF1.27
PCIE_WAKE#: JNGFF1.47 JNGFF1.62 JNGFF2.46 RE274.1 RE275.2
PCIE_WAKE#_R: RE35.2 RE275.1 UE1.B10
PE_REXT: RR2.2 UR1.4
PECI_EC: RE60.2 UC1.N62
PECI_EC_R: RE60.1 UE2.A48
PGOOD_3V_5V: PR107.1 PR108.2 PU100.7
PLTRST_LAN#: RC89.1 UL1.36
PLTRST_MMI#: RC88.1 UR1.15
PLTRST_USH#: CZ68.1 JUSH1.15 RC87.1
PLTRST_VMM2320#: RC219.1 UV8.A13
PM_APWROK: RC26.1 UE2.A9
PM_APWROK_L: RC26.2 RC27.2 UC6.2
PM_APWROK_R: UC1.AB5 UC6.4
PM_LANPHY_ENABLE: RC92.2 RL7.1 UC1.AM7
PM_TEST_RST: CC100.2 RC300.2 UC1.AC4
POA_WAKE#: RPE5.3 UE2.B68
POWER_SW#_MB: CE10.1 JAPS1.11 RE33.2 SW2.2 SW2.4
POWER_SW_IN#: CE12.1 RE31.2 RE33.1 UE2.B67
PROC_OPI_RCOMP: RC187.1 UC1.AY15
PROCHOT_GATE: RE83.2 UE1.A50
PS8338_AUX: RV554.2 UV7.55 UV600.24
PS8338_AUX#: RV555.2 UV7.54 UV600.25
PS8338_CFG0: RV601.2 UV600.59
PS8338_HPD: UV7.32 UV600.3
PS8338_N0: CV607.1 UV7.39
PS8338_N0_C: CV607.2 UV600.7
PS8338_N1: CV609.1 UV7.36
PS8338_N1_C: CV609.2 UV600.10
PS8338_N2: CV611.1 UV7.33
PS8338_N2_C: CV611.2 UV600.13
PS8338_N3: CV613.1 UV7.30
PS8338_N3_C: CV613.2 UV600.16
PS8338_P0: CV606.1 UV7.40
PS8338_P0_C: CV606.2 UV600.6
PS8338_P1: CV608.1 UV7.37
PS8338_P1_C: CV608.2 UV600.9
PS8338_P2: CV610.1 UV7.34
PS8338_P2_C: CV610.2 UV600.12
PS8338_P3: CV612.1 UV7.31
PS8338_P3_C: CV612.2 UV600.15
PS8338_SW: RV602.2 UV600.18
PS8338B_P0: RV615.2 UV600.60
PS8338B_P1: RV100.1 RV603.2 UV600.1
PS8338B_PC10: RV614.2 RV620.1 UV600.56
PS8338B_PC11: RV613.2 RV619.1 UV600.55
PS8338B_PC20: RV612.2 RV618.1 UV600.54
PS8338B_PC21: RV611.2 RV617.1 UV600.53
PS8338B_PEQ: RV610.2 RV616.1 UV600.8
PS8339B_DP_CFG0: RV51.2 RV52.1 UV7.44
PS8339B_DP_CFG1: RV54.2 RV61.1 UV7.29
PS8339B_IN_CA_DET: RV68.2 UV7.11
PS8339B_INPUT_EQ: RV58.2 RV65.1 UV7.8
PS8339B_MODE: RV57.2 RV63.1 UV7.53
PS8339B_MODE_SW: RV550.1 RV551.2 UV7.45
PS8339B_OUT_CA_DET: RV67.2 UV7.42
PS8339B_TMDS_DDCBUF: RV60.2 RV66.1 UV7.2
PS8339B_TMDS_PRE: RV56.2 RV64.1 UV7.20
PS8339B_TMDS_RT: RV55.2 RV62.1 UV7.23
PS_ID: PU1.4 UE2.B24
PS_USBP0_D+: LI3.1 UI3.10
PS_USBP0_D-: LI3.4 UI3.11
PSID_DISABLE#: PR13.2 UE1.A37
PWM1: PU500.6 PU501.8
PWR_SRC_ON: CV11.2 QV1.3 RV4.2 RV5.1
RED_DOCK: JDOCK1.53 RV76.1 UV8.M6
REGCTL_PNP10: LL1.1 UL1.7
REM_DIODE1_N: CE24.1 CE35.1 QE3.3 UE2.B13
REM_DIODE1_P: CE24.2 CE35.2 QE3.1 QE3.2 UE2.A13
REM_DIODE2_N: CE26.1 CE37.2 CE46.2 QE5.3 QE7.1 QE7.2 UE2.B14
REM_DIODE2_P: CE26.2 CE37.1 CE46.1 QE5.1 QE5.2 QE7.3 UE2.A14
REM_DIODE4_N: CE27.1 CE39.1 QE6.3 UE2.A16
REM_DIODE4_P: CE27.2 CE39.2 QE6.1 QE6.2 UE2.B17
RES_BIAS: RL13.1 UL1.12
RESET_OUT#: CC102.1 RE56.2 UC1.AY7 UC8.2 UE2.B39
RING2: LA10.1 RA5.1 UA1.28
RING2_R: CA4.1 CA13.1 DA3.2 JHP1.3 LA10.2
RSMRST#: RZ22.2 RZ51.2 UZ5.3 UZ6.2
RUN_ON: QE2.2 RE279.2 RE280.2 RPE10.1 RZ41.1 UZ7.3 UZ9.3 UZ9.5
RUN_ON#: QE2.5 QE2.6 RE68.2
RUN_ON_EC: RE279.1 UE2.B9
RUNPWROK: QE2.3 RE67.2 UC7.1 UC7.4 UC7.10 UC7.13 UE1.A4 UE2.B26
S5_1.35V: PC215.1 PR207.2 PU200.8
SATA2_PCIE6_L1: RPC9.8 UC1.V6 UE1.A62
SATA_ACT#: QZ3.4 UC1.U3
SATA_COMP: RC17.1 UC1.C12
SATA_LED: LED6.2 RZ36.2
SATA_LED#: QZ12.2 QZ14.6
SATA_PRX_DKTX_N0: C313.2 JDOCK1.56
SATA_PRX_DKTX_N0_C: C313.1 UC1.J5
SATA_PRX_DKTX_P0: C312.2 JDOCK1.54
SATA_PRX_DKTX_P0_C: C312.1 UC1.H5
SATA_PRX_DTX_N1: CN4.2 UC1.J8
SATA_PRX_DTX_N1_C: CN4.1 JMINI3.25
SATA_PRX_DTX_P1: CN3.2 UC1.H8
SATA_PRX_DTX_P1_C: CN3.1 JMINI3.23
SATA_PTX_DKRX_N0: C315.1 JDOCK1.62
SATA_PTX_DKRX_N0_C: C315.2 UC1.B15
SATA_PTX_DKRX_P0: C314.1 JDOCK1.60
SATA_PTX_DKRX_P0_C: C314.2 UC1.A15
SATA_PTX_DRX_N1: CN5.2 UC1.A17
SATA_PTX_DRX_N1_C: CN5.1 JMINI3.31
SATA_PTX_DRX_P1: CN6.2 UC1.B17
SATA_PTX_DRX_P1_C: CN6.1 JMINI3.33
SATACLK_REQ#: JNGFF2.44 RC68.2 UC1.T2
SD/MMCCD#: CR35.1 JSD1.18 RR11.1 UR1.21
SD/MMCCLK: CR23.1 JSD1.5 RR1.2
SD/MMCCLK_R: RR1.1 UR1.43
SD/MMCCMD: JSD1.2 UR1.45
SD/MMCDAT0: JSD1.7 UR1.30 UR1.38
SD/MMCDAT1: JSD1.8 UR1.29 UR1.37
SD/MMCDAT2: RR4.1 UR1.48
SD/MMCDAT2_R: JSD1.9 RR4.2
SD/MMCDAT3: RR3.1 UR1.47
SD/MMCDAT3_R: JSD1.1 RR3.2
SD_REXT: RR5.1 UR1.26
SD_UHS2_D0N: JSD1.12 UR1.34
SD_UHS2_D0P: JSD1.11 UR1.35
SD_UHS2_D1N: JSD1.15 UR1.33
SD_UHS2_D1P: JSD1.16 UR1.32
SDWP: JSD1.19 UR1.20
SIO_EXT_SCI#: RC156.1 UC1.N5 UE2.A33
SIO_EXT_SMI#: RPC5.5 UC1.AG5 UE2.A6
SIO_EXT_WAKE#: RPC7.6 UC1.AU2 UE2.B5
SIO_PWRBTN#: JXDP1.41 UC1.AL7 UE2.B58
SIO_RCIN#: RPC15.4 UC1.V4 UE2.A27
SIO_SLP_A#: JAPS1.6 UC1.AL5 UC6.1 UE2.B28
SIO_SLP_LAN#: UC1.AJ7 UE2.B37 UL3.3
SIO_SLP_S0#: JAPS1.15 UC1.AF3
SIO_SLP_S3#: JAPS1.2 RE280.1 UC1.AT4 UE2.A35
SIO_SLP_S4#: JAPS1.5 RE282.1 T9.1(TP-1) UC1.AJ6 UE2.B36
SIO_SLP_S5#: JAPS1.4 T8.1(TP-1) UC1.AP5 UE2.A18
SIO_SLP_SUS#: UC1.AP4 UE2.B52
SIO_SLP_WLAN#: UC1.AM5 UE1.A14
SKIP#: PR520.2 PU500.7
SKIP#1: PR520.1 PU501.1
SL_BAT_PRES#: PR854.1 PU800.21
SLATE_MODE: RPC10.7 UC1.AL4
SLEEVE: LA11.1 QA2.3 RA6.1 UA1.29
SLEEVE_R: CA1.1 CA12.1 DA1.3 JHP1.4 LA11.2
SLEWA: PR500.1 PR510.2 PU500.15
SLICE_BAT_ON: PR845.2 RE17.2 UE1.A31
SLICE_BAT_PRES#: JDOCK1.141 JDOCK1.143 PR6.1 PR854.2 RE5.2 UE1.B33
SM_RCOMP0: RC130.1 UC1.AU60
SM_RCOMP1: RC131.1 UC1.AV60
SM_RCOMP2: RC132.1 UC1.AU61
SMART_DET#: T99.1(TP-1) UE1.A15
SML0_SMBCLK: RC30.2 RC33.2 UC1.AN1
SML0_SMBDATA: RC32.2 RC34.2 UC1.AK1
SML1_SMBCLK: RPC14.2 UC1.AU3 UE2.B6
SML1_SMBDATA: RPC14.1 UC1.AH3 UE2.A5
SNB_1.05V: PC301.1 PR305.2
SNUB_1.35V: PC208.1 PR203.2
SNUB_3V: PC111.1 PR111.2
SNUB_5V: PC114.1 PR112.2
SOFT_START_GC: PR17.2 PU800.2
SPI_CLK32: RC61.2 RPC12.7 UC3.6
SPI_CLK64: RC62.2 RPC11.6 UC2.6
SPI_CLKTPM: RZ26.2 RZ35.2 UZ1.21
SPI_DIN32: RPC12.5 UC3.2
SPI_DIN64: RPC11.8 UC2.2
SPI_DINTPM: RZ30.2 UZ1.26
SPI_DO32: RPC12.6 UC3.5
SPI_DO64: RPC11.7 UC2.5
SPI_DOTPM: RZ29.2 UZ1.23
SPI_PCH_CLK: JSPI1.7 RC227.1 RPC11.3 RPC12.2
SPI_PCH_CS0#: JSPI1.9 RC35.1 RC228.1
SPI_PCH_CS0#_R: RC35.2 UC2.1
SPI_PCH_CS1#: JSPI1.1 RC50.1 RC224.1
SPI_PCH_CS1#_R: RC50.2 UC3.1
SPI_PCH_DIN: JSPI1.5 RC226.1 RPC11.1 RPC12.4
SPI_PCH_DO: JSPI1.3 RC225.1 RPC11.2 RPC12.3
SPI_PCH_DO2: JSPI1.11 RC29.2 RC38.1 RC55.1 RC229.1
SPI_PCH_DO2_32: RC55.2 UC3.3
SPI_PCH_DO2_64: RC38.2 UC2.3
SPI_PCH_DO3: JSPI1.13 RC31.2 RC230.1 RPC11.4 RPC12.1
SPI_PCH_DO3_32: RPC12.8 UC3.7
SPI_PCH_DO3_64: RPC11.5 UC2.7
SPKR: RA12.2 RC180.2 UC1.V2
SRCDET: RV84.1 UV8.C2
SRTCRST#: CC3.2 RC10.2 UC1.AV6
STSTART_DCBLOCK_GC: PR811.2 PU800.16
SUS_ON: PR207.1 RE281.2 RE282.2 RPE10.2 UZ8.3
SUS_ON_EC: RE281.1 UE2.B23
SUS_STAT#/LPCPD#: RC82.2 UC1.AG4
SUSACK#: RC81.2 UC1.AK2 UE2.A23
SUSCLK: RC136.2 RZ56.1
SUSCLK_R: RC136.1 UC1.AE6
SW1: PC110.2 PL102.1 PQ101.1 PQ101.2 PQ101.3 PQ103.5 PR112.1 PU100.18
SW2: PC109.1 PL101.2 PQ100.1 PQ100.2 PQ100.3 PQ102.5 PR111.1 PU100.8
SW_1.35V: PC204.2 PL200.2 PQ200.1 PQ200.2 PQ200.3 PQ201.5 PR203.1 PU200.16
SW_10_GRN#: QL2.1 RL30.2 UL4.41
SW_100_ORG#: QL1.4 RL29.2 UL4.18
SW_+V1.05SP: PL301.1 PR305.1 PR312.2 PU300.10
SW_ACTLED_YEL#: QL1.1 UL4.17
SW_DPB_AUX: CV119.2 RV75.1 UV8.J13
SW_DPB_AUX#: CV120.2 RV82.1 UV8.J14
SW_DPB_AUX#_C: CV120.1 UV11.5
SW_DPB_AUX_C: CV119.1 UV11.2
SW_DPC_AUX: CV122.2 RV74.1 UV8.B11
SW_DPC_AUX#: CV123.2 RV85.1 UV8.A11
SW_DPC_AUX#_C: CV123.1 UV12.5
SW_DPC_AUX_C: CV122.1 UV12.2
SW_LAN_TX0+: TL1.12 UL4.38
SW_LAN_TX0-: TL1.11 UL4.37
SW_LAN_TX1+: TL1.6 UL4.34
SW_LAN_TX1-: TL1.5 UL4.33
SW_LAN_TX2+: TL1.8 UL4.29
SW_LAN_TX2-: TL1.7 UL4.28
SW_LAN_TX3+: TL1.2 UL4.25
SW_LAN_TX3-: TL1.1 UL4.24
SW_MDP_AUX#_C: CV513.1 UV502.5
SW_MDP_AUX_C: CV512.1 UV502.2
SW_USB3RN1: LI1.4 UI4.26
SW_USB3RP1: LI1.1 UI4.27
SW_USB3TN1: CI4.2 UI4.30
SW_USB3TP1: CI5.2 UI4.31
SW_USBP0+: UI3.3 UI4.19
SW_USBP0-: UI3.2 UI4.18
SW_USBP3+: LI4.1 UI5.1
SW_USBP3-: LI4.4 UI5.2
SYS_LED_MASK#: QL1.2 QL1.5 QL2.2 QZ3.2 RE21.2 UE1.B48 UZ10.1
SYS_PWROK: CC22.1 CC108.1 JXDP1.47 RC120.1 UC1.AG2 UE2.B7
SYS_RESET#: CC106.1 JAPS1.13 RC77.2 UC1.AC3 UC4.4
TDI_IREF: RC186.2 UC1.B12
TDI_XDP_R: RC99.2 RC118.1 UC7.5
TDO_XDP: JXDP1.52 RC98.2 RC115.1 RC117.2 UC7.2
THERMATRIP2#: CE36.1 QE4.1 RE69.2 UE2.B34
THERMATRIP3#: RPE6.1 UE2.A2
THSEL_STRAP: RE78.1 UE2.B29
TMDS_CON_CLK: JHDMI1.10 LV3.2
TMDS_CON_CLK#: JHDMI1.12 LV3.3
TMDS_CON_N0: JHDMI1.9 LV12.3
TMDS_CON_N1: JHDMI1.6 LV10.3
TMDS_CON_N2: JHDMI1.3 LV6.3
TMDS_CON_P0: JHDMI1.7 LV12.2
TMDS_CON_P1: JHDMI1.4 LV10.2
TMDS_CON_P2: JHDMI1.1 LV6.2
TOUCH_PANEL_INTR#: JEDP1.5 RPC3.5 UC1.P3
TOUCH_SCREEN_PD#: T96.1(TP-1) UE1.B55
TOUCHPAD_INTR#: RPC9.7 UC1.U7
TP_DC_TEST_B2: RC192.2 UC1.B2
TP_LAN_JTAG_TCK: RL2.2 UL1.35
TP_LAN_JTAG_TDI: T88.1(TP-1) UL1.32
TP_LAN_JTAG_TDO: T89.1(TP-1) UL1.34
TP_LAN_JTAG_TMS: RL1.2 UL1.33
TPM_PIRQ#: RC247.2 UC1.T3 UZ1.20
TRST#_XDP: JXDP1.54 UC7.12
UG_3V: PQ100.4 PU100.10
UG_5V: PQ101.4 PU100.16
UIM_CLK: CZ65.1 JNGFF2.24 JSH1.4
UIM_DATA: CZ63.1 JNGFF2.26 JSH1.8
UIM_DET: JNGFF2.58 JSH1.7
UIM_RESET: CZ64.1 JNGFF2.22 JSH1.6
USB3RN1: UC1.G20 UI4.5
USB3RN1_D-: DI1.1 DI1.9 JUSB1.5 LI1.3
USB3RN2: LI6.4 UC1.E18
USB3RN2_D-: DI4.1 DI4.9 JUSB3.5 LI6.3
USB3RN4: LI9.1 UC1.F15
USB3RN4_D-: DI6.1 DI6.9 JUSB2.5 LI9.2
USB3RP1: UC1.H20 UI4.4
USB3RP1_D+: DI1.2 DI1.8 JUSB1.6 LI1.2
USB3RP2: LI6.1 UC1.F18
USB3RP2_D+: DI4.2 DI4.8 JUSB3.6 LI6.2
USB3RP4: LI9.4 UC1.G15
USB3RP4_D+: DI6.2 DI6.8 JUSB2.6 LI9.3
USB3TN1: UC1.C33 UI4.2
USB3TN1_C: CI4.1 LI2.4
USB3TN1_D-: DI1.4 DI1.7 JUSB1.8 LI2.3
USB3TN2: CI16.2 UC1.B33
USB3TN2_C: CI16.1 LI5.4
USB3TN2_D-: DI4.4 DI4.7 JUSB3.8 LI5.3
USB3TN4: CI28.2 UC1.B31
USB3TN4_C: CI28.1 LI8.1
USB3TN4_D-: DI6.4 DI6.7 JUSB2.8 LI8.2
USB3TP1: UC1.B34 UI4.1
USB3TP1_C: CI5.1 LI2.1
USB3TP1_D+: DI1.5 DI1.6 JUSB1.9 LI2.2
USB3TP2: CI13.2 UC1.A33
USB3TP2_C: CI13.1 LI5.1
USB3TP2_D+: DI4.5 DI4.6 JUSB3.9 LI5.2
USB3TP4: CI27.2 UC1.A31
USB3TP4_C: CI27.1 LI8.4
USB3TP4_D+: DI6.5 DI6.6 JUSB2.9 LI8.3
USB_DB_DET#: T98.1(TP-1) UE1.A2
USB_OC0#: RPC19.3 UC1.AL3 UI3.13
USB_OC1#: RPC7.7 UC1.AT1 UI1.5
USB_OC2#: RPC10.5 UC1.AH2 UI2.5
USB_OC3#: RPC7.5 UC1.AV3
USB_PWR_EN1#: RPE9.2 UE1.B44 UI1.4
USB_PWR_EN2#: RPE9.3 UE1.A33 UI2.4
USB_PWR_SHR_EN#: RPE9.4 UE2.B38 UI3.6
USB_PWR_SHR_VBUS_EN: RPE9.1 UE1.B50 UI3.5
USBP0+: UC1.AM8 UI4.6
USBP0-: UC1.AN8 UI4.7
USBP0_R_D+: DI2.3 JUSB1.3 LI3.2
USBP0_R_D-: DI2.2 JUSB1.2 LI3.3
USBP1+: LI7.1 UC1.AT7
USBP1-: LI7.4 UC1.AR7
USBP1_R_D+: DI5.3 JUSB3.3 LI7.2
USBP1_R_D-: DI5.2 JUSB3.2 LI7.3
USBP2+: JNGFF1.3 UC1.AP8
USBP2-: JNGFF1.5 UC1.AR8
USBP3+: UC1.AT10 UI5.8
USBP3-: UC1.AR10 UI5.7
USBP3_D+: DI3.3 JUSB2.3 LI4.2
USBP3_D-: DI3.2 JUSB2.2 LI4.3
USBP4+: LV27.3 UC1.AL15
USBP4-: LV27.2 UC1.AM15
USBP4_D+: DV4.3 JEDP1.3 LV27.4
USBP4_D-: DV4.2 JEDP1.2 LV27.1
USBP5+: LZ1.1 UC1.AN13
USBP5-: LZ1.4 UC1.AM13
USBP5_D+: JEDP1.13 LZ1.2
USBP5_D-: JEDP1.12 LZ1.3
USBP6+: JUSH1.3 UC1.AN11
USBP6-: JUSH1.2 UC1.AP11
USBP7+: JNGFF2.7 UC1.AP13
USBP7-: JNGFF2.9 UC1.AR13
USBRBIAS: RC152.1 UC1.AJ10 UC1.AJ11
USH_DET#: JUSH1.20 RPC15.2 UC1.E3
USH_PWR_STATE#: JUSH1.16 RZ10.2 UE1.A34
USH_SMBCLK: JUSH1.5 RZ8.2 UE2.A50
USH_SMBDAT: JUSH1.6 RZ9.2 UE2.B53
VCI_IN2#: RPE5.4 UE2.B63
VCT_LAN_R1: RL3.2 UL1.6
VFB: PR531.2 PU500.24
VGA_ID: RE85.1 RE87.1 UE1.B59
VIDALERT_N: PR528.2 PU500.32 RC204.2 RC207.2
VIDSCLK: PR527.2 PU500.31 UC1.N63
VIDSOUT: PR529.2 PU500.1 RC208.2 UC1.L63
VMM2320_AUX: CV110.1 RV608.2 UV600.28
VMM2320_AUX#: CV111.1 RV604.2 UV600.29
VMM2320_AUX#_C: CV111.2 UV8.H2
VMM2320_AUX_C: CV110.2 UV8.H1
VMM2320_HPD: UV8.J1 UV600.38
VMM2320_N0: CV103.1 UV600.39
VMM2320_N0_C: CV103.2 UV8.G2
VMM2320_N1: CV105.1 UV600.36
VMM2320_N1_C: CV105.2 UV8.F2
VMM2320_N2: CV107.1 UV600.34
VMM2320_N2_C: CV107.2 UV8.E2
VMM2320_N3: CV109.1 UV600.31
VMM2320_N3_C: CV109.2 UV8.D2
VMM2320_P0: CV102.1 UV600.40
VMM2320_P0_C: CV102.2 UV8.G1
VMM2320_P1: CV104.1 UV600.37
VMM2320_P1_C: CV104.2 UV8.F1
VMM2320_P2: CV106.1 UV600.35
VMM2320_P2_C: CV106.2 UV8.E1
VMM2320_P3: CV108.1 UV600.32
VMM2320_P3_C: CV108.2 UV8.D1
VMM2320_VGA_DET: RV88.2 UV8.M3
VMM2320_VGA_IREF: RV89.1 UV8.M5
VMM2320_VGA_NC: T108.1(TP-1) UV8.L5
VMM_DPB_CTRLCLK: RPV1.1 UV8.K13 UV11.12
VMM_DPB_CTRLDAT: RPV1.2 UV8.L14 UV11.9
VMM_DPC_CTRLCLK: RPV2.3 UV8.B12 UV12.12
VMM_DPC_CTRLDAT: RPV2.4 UV8.A12 UV12.9
VMM_GPIO4: RV518.2 UV8.B14
VMM_GPIO5: RV519.2 UV8.B13
VMM_GPIO6: RV83.1 UV8.C1
VMM_GPIO7: RPV1.3 UV8.M12
VMM_GPIO8: RV14.1 UV8.M13
VMM_GPIO9: RV73.1 UV8.L3
VMM_SPI_CLK: UV8.B3 UV9.6
VMM_SPI_CS#: RV86.2 UV8.A4 UV9.1
VMM_SPI_DIN: UV8.B4 UV9.2
VMM_SPI_DO: UV8.A3 UV9.5
VMM_SPI_HOLD: RV87.2 UV9.7
VMM_SPI_WP#: RV517.2 UV8.B1 UV9.3
VR_HOT#: PR534.2 PU500.30
VREF: PC507.2 PH500.1 PR500.2 PR502.2 PR503.2 PR504.2 PR521.2 PU500.27
VSET_5085: CE38.1 RE77.1 UE2.A17
VSYNC_DOCK: JDOCK1.67 UV8.L9
WIGIG_32KHZ: JNGFF1.42 RZ56.2 RZ57.2
WIGIG_32KHZ_R: RZ57.1 UZ11.4
WIGIG_AUX: CV149.1 RV609.2 UV600.26
WIGIG_AUX#: CV150.1 RV605.2 UV600.27
WIGIG_AUX#_C: CV150.2 JNGFF1.12
WIGIG_AUX_C: CV149.2 JNGFF1.14
WIGIG_HPD: JNGFF1.23 UV600.48
WIGIG_LANE_N0: CV156.1 UV600.49
WIGIG_LANE_N0_C: CV156.2 JNGFF1.24
WIGIG_LANE_N1: CV152.1 UV600.46
WIGIG_LANE_N1_C: CV152.2 JNGFF1.18
WIGIG_LANE_N2: CV147.1 UV600.44
WIGIG_LANE_N2_C: CV147.2 JNGFF1.17
WIGIG_LANE_N3: CV145.1 UV600.41
WIGIG_LANE_N3_C: CV145.2 JNGFF1.11
WIGIG_LANE_P0: CV157.1 UV600.50
WIGIG_LANE_P0_C: CV157.2 JNGFF1.26
WIGIG_LANE_P1: CV153.1 UV600.47
WIGIG_LANE_P1_C: CV153.2 JNGFF1.20
WIGIG_LANE_P2: CV148.1 UV600.45
WIGIG_LANE_P2_C: CV148.2 JNGFF1.19
WIGIG_LANE_P3: CV146.1 UV600.42
WIGIG_LANE_P3_C: CV146.2 JNGFF1.13
WIGIGCLK_REQ#: JNGFF1.60 RPC9.6 UC1.U5
WIRELESS_LED#: QZ2.3 QZ2.6 QZ7.1 QZ11.6 RZ31.2 UE1.A47
WLAN_DISBL#: UE1.B68 UL2.4
WLAN_LED: LED5.2 RZ33.2
WLAN_LED#: JNGFF1.6 QZ2.1 RZ14.1
WLAN_WIGIG60GHZ_DIS#: DZ1.1 RE8.2 UE1.A1
WLAN_WIGIG60GHZ_DIS#_R: DZ1.2 JNGFF1.48
WLANCLK_REQ#: JNGFF1.45 RPC17.6 UC1.N1
WWAN_LED#: JNGFF2.10 QZ11.1 RZ37.1
WWAN_PWR_EN: JNGFF2.6 RZ50.2
WWAN_RADIO_DIS#: DZ5.1 RE10.2 UE1.A53
WWAN_RADIO_DIS#_R: DZ5.2 JNGFF2.8
WWAN_WAKE#: JNGFF2.15 RE276.2 UE1.B43
XDP_DBRESET#: CC21.1 CC105.1 JXDP1.48 RC77.1 RC122.2 UC4.1
XDP_OBS0_R: JXDP1.21 UC1.J60
XDP_OBS1_R: JXDP1.23 UC1.H60
XDP_OBS2_R: T10.1(TP-1) UC1.H61
XDP_OBS3_R: T11.1(TP-1) UC1.H62
XDP_OBS4_R: T12.1(TP-1) UC1.K59
XDP_OBS5_R: T13.1(TP-1) UC1.H63
XDP_OBS6_R: T14.1(TP-1) UC1.K60
XDP_OBS7_R: T15.1(TP-1) UC1.J61
XDP_RST#_R: CC111.1 JXDP1.46 RC106.2
XTAL24_IN: CC8.2 RC63.2 UC1.A25 YC2.3
XTAL24_OUT: RC63.1 RC65.1 UC1.B25
XTAL24_OUT_R: CC11.2 RC65.2 YC2.1
XTALI: CL14.2 RL11.2 UL1.10 YL1.1
XTALO: RL10.2 RL11.1 UL1.9
XTALO_R: CL13.2 RL10.1 YL1.3
Z2805: RL18.1 TL1.22
Z2806: RL16.1 TL1.16
Z2807: RL17.1 TL1.21
Z2808: RL15.1 TL1.15
N15115: T16.1(TP-1) UC1.AD4
N19253: T28.1(TP-1) UC1.AV63
N19255: T29.1(TP-1) UC1.AU63
N19263: T30.1(TP-1) UC1.C63
N19267: T31.1(TP-1) UC1.C62
N19275: T33.1(TP-1) UC1.A51
N19277: T34.1(TP-1) UC1.B51
N19281: T35.1(TP-1) UC1.L60
N21871: T74.1(TP-1) UC1.P60
N21873: T75.1(TP-1) UC1.P61
N21875: T76.1(TP-1) UC1.N59
N21877: T77.1(TP-1) UC1.N61
N29827: JDIMM1.197 RD15.2
N29829: JDIMM1.201 RD16.2
N33048: CD36.2 RD21.1
N33050: CD54.2 RD25.1
N33054: JDIMM2.197 RD28.1
N33058: JDIMM2.201 RD27.1
N40459: QV2.1 RV5.2
N70739: JDEG1.1 RE71.2
N70745: RE64.1 UE2.B61
N70747: CE34.1 RE66.2
N70757: RE57.1 RE58.1 UE2.A59
N73962: CZ45.1 UZ9.12
N73964: CZ46.1 UZ9.10
N75571: DZ3.2 DZ4.2 QZ3.1 QZ14.1 RZ24.2
N75591: QZ4.1 RZ27.1
N75595: DZ3.1 QZ3.3
N75597: QZ3.6 QZ4.2
N75599: QZ9.1 RZ33.1
N75603: QZ7.6 QZ9.2
N5261056: QD1.3 RD10.1 RD11.1 RD12.1 RD13.1
N10757881: CD21.2 RD7.1
N15438178: PD702.1 PD704.1 PD705.1 PR708.1
N15438627: PC711.1 PR710.1 PR711.1 PU700.6
N15439163: PR714.2 PU700.5
N15439291: PC718.2 PR716.2 PU700.7
N15439295: PC719.2 PR718.2 PU700.8
N15439512: PR720.2 PR788.2 PU700.9
N15440461: PR717.2 PU700.10
N15441413: PR722.1 PU700.18
N15441884: PC729.1 PR723.1 PU700.17
N15442134: PC726.2 PC727.1 PR721.3 PU700.20
N15442185: PC727.2 PC728.1 PR721.2 PU700.19
N17156946: PC5.1 PQ4.4 PQ6.4 PR14.2 PR17.1 PR18.1
N17156948: PQ6.1 PQ6.2
N17639884: PC505.2 PR519.2 PU500.2
N17640254: PC506.1 PR523.1 PR535.1 PU500.25
N17640267: PC512.1 PR535.2
N17640270: PC506.2 PC512.2 PR521.1 PR523.2 PU500.26
N17645088: PL500.3 PR512.2
N17680637: PR536.2 PU500.8
N17680665: PR516.1 PR539.1 PU500.3
N18325201: CL16.1 TL1.3
N18325205: CL17.1 TL1.4
N18325209: CL20.1 TL1.9
N18325213: CL21.1 TL1.10
N18328616: CL24.1 UL3.10
N18328720: CZ37.1 UL3.12
N18609334: QV7.1 QV8.2 RV6.2
N18731939: CV113.1 RV81.1 YV2.3
N19516037: CZ9.1 RZ35.1
N19540333: CZ23.1 UZ2.10
N19540335: CZ49.1 UZ2.12
N19544058: CC10.2 RC62.1
N19544059: CC9.2 RC61.1
N19638635: PR114.1 PU100.19
N19651849: CE9.1 RE27.2
N19651850: RE24.1 UE1.B19
N20106358: RV50.1 UV7.27
N20106372: CV60.1 UV7.1
N20249193: CA29.1 UA1.35
N20249194: CA29.2 UA1.36
N20249196: CA25.1 UA1.31
N20249200: CA27.1 RA12.1
N20249201: CA28.1 RA13.1
N20249202: QA2.5 QA2.6 RA21.2
N20249205: CA33.1 RA17.2
N20249232: DA5.1 RA25.2
N20249233: DA4.1 RA24.2
N20249314: QA3.3 RA27.2
N20249315: QA3.6 RA28.2
N20360585: CA49.2 UA1.34
N20361305: CA35.2 UA1.25
N20363962: CA51.1 RA44.1 UA1.21
N20363967: CA52.1 UA1.39
N20363972: CA53.1 UA1.7
N20711035: PC304.2 PR309.1
N20813044: PC809.2 PD813.1 PQ815.4 PQ826.4 PR818.1 PR822.1
N20813052: PC809.1 PQ815.1 PQ815.2 PQ815.3 PQ826.1 PQ826.2 PQ826.3 PR818.2
N20813067: PQ832.2 PR828.2
N20813069: PQ829.2 PQ832.1 PR830.2
N20813073: PD815.2 PQ829.1
N20813075: PQ829.3 PR830.1 PR895.2
N20813085: PC807.2 PQ810.4 PR811.1
N20813089: PQ813.5 PR853.2
N20826302: PC209.2 PR204.1 PU200.12
N20857922: PQ806.3 PR815.2 PR816.1
N20862119: PR518.2 PR524.1 PR525.1
N20899585: RV600.1 UV600.20
N20899609: CV605.1 UV600.17
N20935195: PR799.1 PU700.21
N20987678: PD817.1 PQ814.3 PR827.2
N20987955: PQ806.5 PQ806.6 PR813.2
N20988471: PQ817.6 PR819.1 PU806.1
N21132814: QZ12.1 RZ36.1
N21281743: CV116.1 UV13.12
N21281745: CV117.1 UV13.10
N21390508: C319.1 R273.2
N21390510: C43.1 R41.2
N21390512: C42.1 R6.2
N21414338: DA2.2 JHP1.5 RA1.2
N21423939: RC2.2 SW1.2
N21533765: JEDP1.21 LV1.1
N21656651: CZ41.1 UZ8.12
N21656676: CZ42.1 UZ8.10
N21889651: CZ62.1 UZ7.12
N21889653: CZ60.1 UZ7.10
N22916358: RA45.1 UA1.22
N23299527: RI14.2 UI3.16
N24321023: QE4.2 RE70.2 RE284.2
N24368370: QV700.3 RV702.2
N24544483: PD5.2 PD5.3 PL3.1 PQ2.1 PR7.1 PR10.2
N24571981: PC4.1 PQ1.2 PR6.2
N24571998: PD4.2 PQ1.1
N24573405: PQ700.4 PR700.1
N24606174: PC309.1 PU300.5
N48705653: PQ2.3 PR7.2 PR9.1
N48705663: PQ3.2 PR10.1 PR12.2
N48705665: PQ2.2 PQ3.1 PR11.2 PR13.1
N48708367: PR210.2 PU200.7
N48708425: PR206.2 PU200.9
N48716673: PR838.1 PU800.28
N48716693: PR845.1 PU800.26
N49522072: PC700.2 PQ701.2 PQ702.2 PR702.2
N49522215: PQ703.1 PQ703.3 PR706.2 PR707.2 PR709.2
N49522242: PC702.2 PC703.1 PR705.1 PU700.1
N49522275: PC701.2 PC702.1 PR704.1 PU700.2
N49522729: PQ701.1 PR701.2
N49522731: PQ702.1 PR701.3
N61500733: PR513.1 PU500.4
N61500909: PC510.2 PR526.1 PU500.28
N61500999: PH501.2 PR515.1
N61501245: PC501.1 PH500.2 PR505.2 PU500.14
N61501462: PR511.2 PU500.16
N66971793: PR105.2 PU100.5
N66972075: PR106.2 PU100.1
N78957489: PQ816.1 PR822.2
N78967043: PQ816.2 PU806.4
N78985854: PR810.2 PR812.2 PU804.2
N79002827: PQ806.2 PU804.4
N79023703: PR863.1 PU800.19
N79030038: PQ813.2 PQ813.3 PR829.2
N79030087: PQ813.6 PR826.2
N79030091: PQ814.2 PR826.1 PR827.1
N79030745: PD813.2 PQ814.1
N80905978: PC402.1 PR400.2 PR401.1 PU400.8
N80906026: PC403.2 PR402.2 PR403.1 PU400.2

Pads without a net: FD1 1; FD2 1; FD3 1; FD4 1; JAPS1 16 17 18; JDIMM1 77 122 125 198; JDIMM2 77 122 125 198; JEDP1 16 20 32; JHDMI1 14; JKBTP1 4 11; JLED1 1; JLOM1 14 15; JMINI3 1 3 5 6 7 11 13 20 22 28 30 32 36 38 42 43 45 46 47 48 49; JNGFF1 9 36 38 40 50 52 54 56; JNGFF2 12 14 16 17 20 32 34 36 38 40 48 50 52 54 56 59 60; JSH1 1; JSPI1 17; JUSH1 11 12; JXDP1 40 42; PD2 3; PRP2 4 5; PU200 10; PU400 7; PU500 5; PU700 4; PU800 20 29 30 31 35 36; QL2 3 4 5; QZ11 3 4 5; QZ14 3 4 5; RPC1 7; RPC17 8; RPC21 1 8; RPE5 1 8; RPE6 4 5; RPV1 4; UA1 4; UC1 A5 A21 A23 A35 A41 A43 A49 AA23 AA59 AB8 AB21 AB23 AC20 AC58 AC59 AD5 AD7 AD8 AD10 AD23 AD59 AD60 AE59 AE60 AF20 AG58 AH13 AL1 AL2 AL11 AL32 AM10 AM11 AN10 AP7 AP32 AT2 AU10 AU12 AU15 AU44 AV2 AV10 AV44 AV50 AV62 AW10 AW14 AW49 AY8 AY14 AY42 AY43 B21 B22 B23 B35 B41 B43 B49 C4 C21 C46 C47 D1 D15 D58 D61 E1 E6 E8 E13 E15 F6 F8 F22 G1 G10 H10 H18 H22 J2 J4 J13 J20 J21 J58 K4 K10 K18 K21 L3 L11 L59 M20 M21 N23 N58 N60 P20 R5 R20 R23 T23 T59 U10 U59 V21 V59 W23 Y20 Y22; UC8 1; UD1 1; UE1 A3 A5 A8 A9 A11 A12 A16 A23 A32 A42 A45 A46 A48 A49 A52 A55 A56 A57 A58 A59 A60 A61 A64 B1 B3 B4 B6 B7 B11 B13 B14 B16 B17 B18 B32 B39 B40 B45 B47 B49 B56 B57 B58 B60 B61 B63 B64 B65 B66; UE2 A15 B15 B16 B62; UI3 9 15; UI4 8 13 17; UL4 5; UR1 19 39 40 44 46; UV7 46; UV8 A5 E10 H3 H11 K2 L2 L10 L11 L12 L13 M1 M2 M10 M11; UV600 2 4 14 22 23 58; UZ1 1 2 5 6 7 9 12 13 14 15 17 27 28; YC2 2 4

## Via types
v1: diameter 0.305, hole 0.152, TOP to BOTTOM, 732 vias
v2: diameter 0.457, hole 0.203, TOP to BOTTOM, 5178 vias
v3: diameter 0.406, hole 0.203, TOP to BOTTOM, 132 vias
v4: diameter 0.508, hole 0.254, TOP to BOTTOM, 104 vias

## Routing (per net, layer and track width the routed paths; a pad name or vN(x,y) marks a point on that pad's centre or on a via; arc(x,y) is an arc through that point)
0.675V_DDR_VTT_ON: length 87.4
  TOP w0.102: PR210.1 184.15,1.94 183.06,1.94 v2(182.87,2.13) ; v2(122.61,28.37) 122.59,28.38 v1(122.59,28.9) 123.04,29.35 CC110.1 123.04,30.26 QD1.2 121.9,30.4 RD14.2 RD9.2 120.97,30.96 120.32,30.96 120.15,31.13 UD1.4
  IN2 w0.122: v2(182.87,2.13) 182.87,3.41 182.11,4.17 182.11,10.84 180.7,12.25 180.7,13.18 175.37,18.51 137.19,18.51 125.69,30.01 123.18,30.01 122.61,29.44 v2(122.61,28.37)
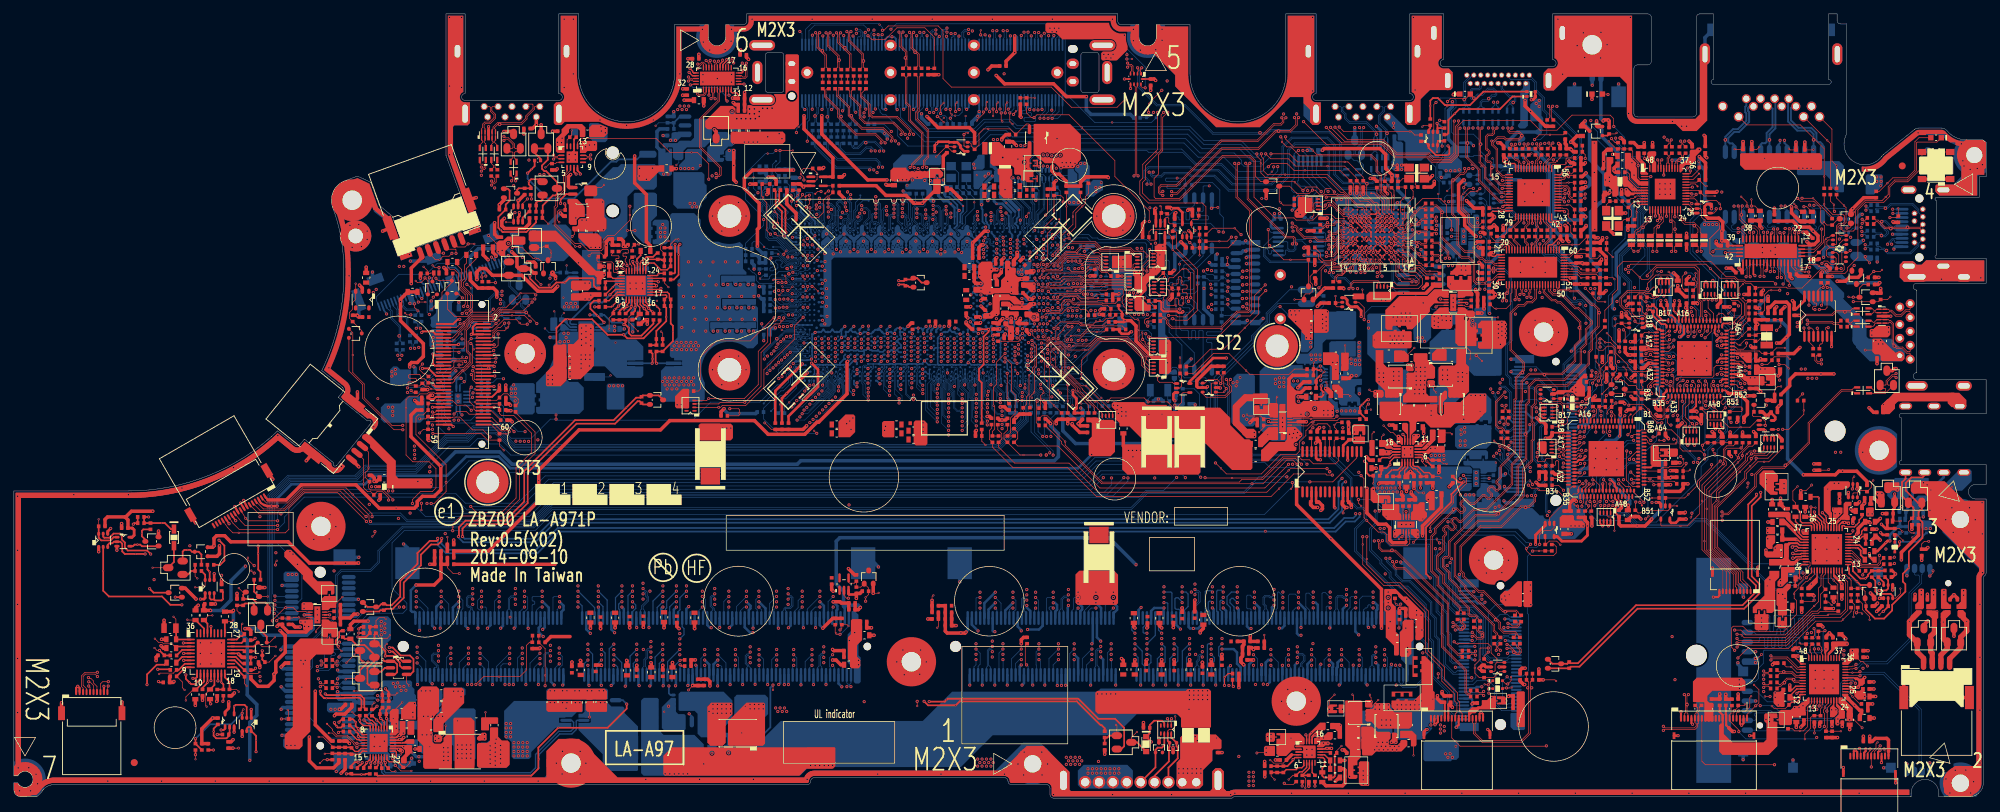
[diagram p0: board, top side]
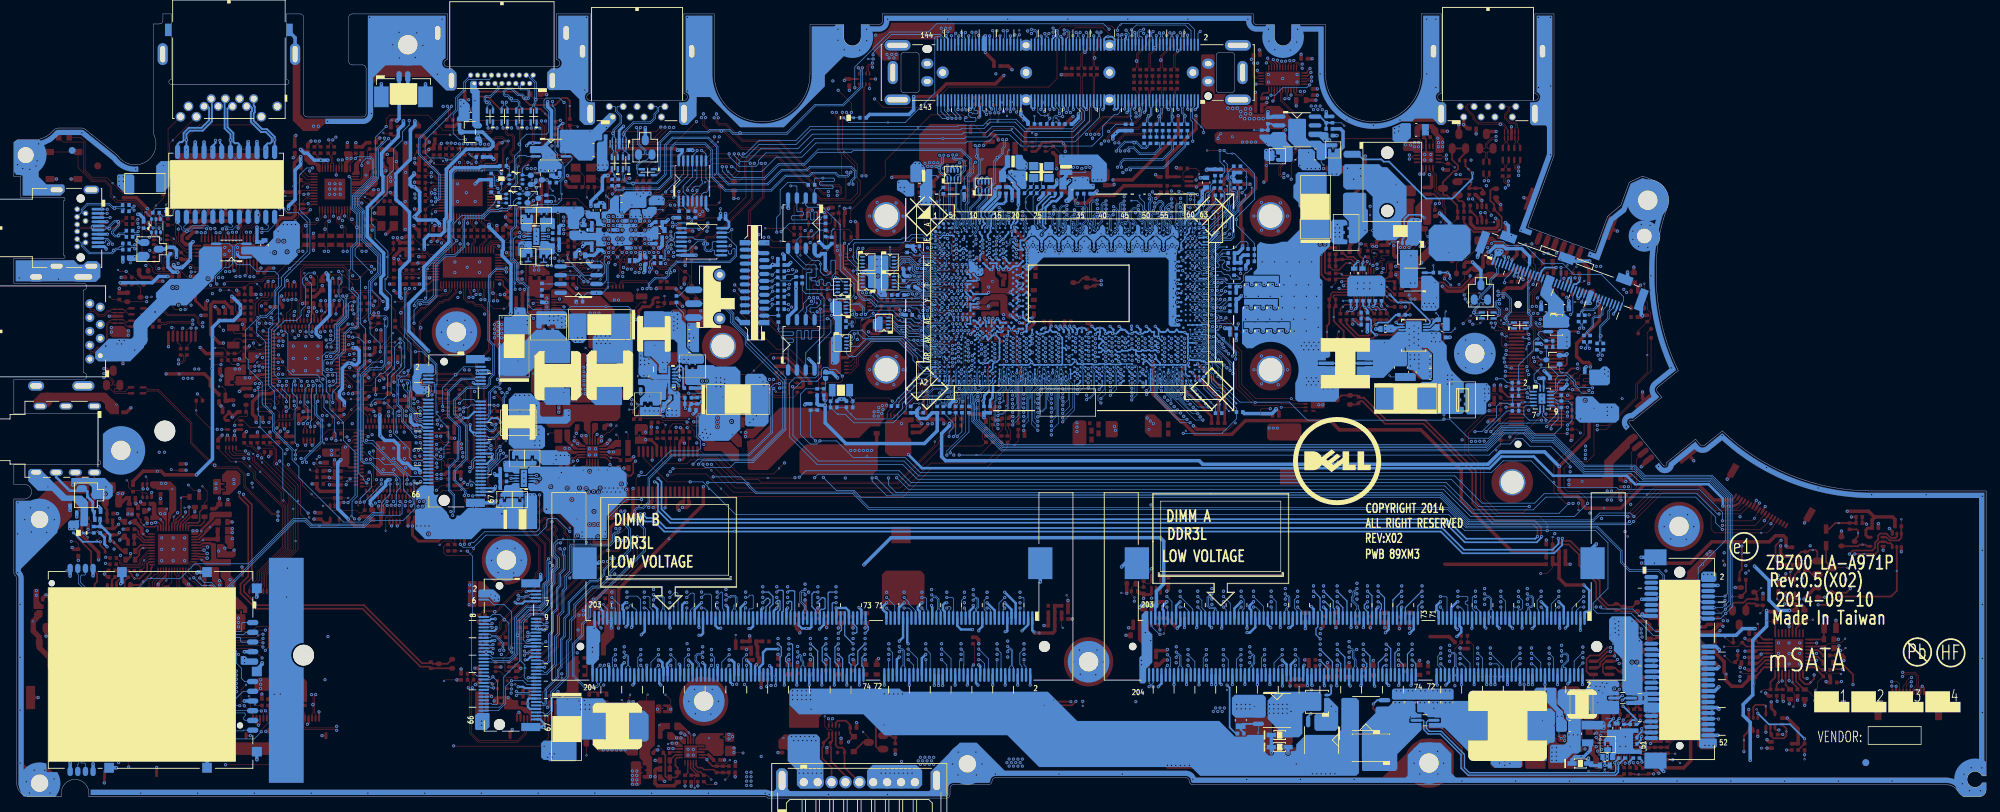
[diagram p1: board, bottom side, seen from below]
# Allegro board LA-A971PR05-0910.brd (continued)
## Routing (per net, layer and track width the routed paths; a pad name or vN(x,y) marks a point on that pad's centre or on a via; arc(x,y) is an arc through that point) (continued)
1.05V_M_PWRGD: length 20.1
  TOP w0.102: PR313.1 184.32,61.81 183.57,61.06 177.91,61.06 v1(177.37,61.6) 174.93,64.05 172.64,64.05 169.79,61.19 RC27.1
1.05V_MODPHY_EN: length 13.3
  TOP w0.102: QZ6.3 146.19,97.03 146.09,97.13 145.73,97.13 CZ25.1 143.38,96.43 v1(140.26,96.43) 139.6,96.43 138.93,95.76 138.93,94.12 RZ5.2 137.8,93.97 137.8,94.26 137.56,94.5 QZ10.3
1.05V_MP_PWROK: length 3.9
  TOP w0.102: PR313.2 187.07,62.72 v1(187.12,62.78)
  TOP w0.254: v2(188.13,61.66) 187.69,61.66 187.54,61.81 PR313.2 PR315.2
  BOTTOM w0.254: v2(188.13,61.66) 188.44,61.35 PU300.2
1.5VSP:
  vias: v1(103.62,94.34)
1.35V_B+: length 9.3
  TOP w0.102: PQ200.5 192.85,14.74 v1(192.67,14.92)
  TOP w0.254: PR206.1 v2(187.29,1.74)
  IN2 w0.254: v2(192.27,3.14) 192.27,2.4 191.61,1.74 v2(187.29,1.74)
1.35V_FB: length 6.8
  TOP w0.102: PR209.1 180.98,3.19 v1(181.5,2.67)
  TOP w0.203: PU200.6 185.69,4.67 185.39,4.37 184.85,4.37 184.58,4.1 183.15,4.1 PC213.1
  TOP w0.254: PC213.1 PR205.1 181,3.7 PR209.1
3.3V_CAM_EN#: length 128.2
  TOP w0.102: RC174.1 159.54,68.05 157.02,68.05 156.74,67.77 154.66,67.77 153.51,66.61 v1(152.17,66.61) 151.67,66.11 v2(151.67,66.02) ; v2(71.17,78.2) 71.27,78.09 QZ1.2
  IN2 w0.122: v2(151.67,66.02) 151.67,66.41 150.8,67.28 149.42,67.28 149.26,67.45 149.26,68.57 148.98,68.85 148.98,69.58 148.79,69.76 147.5,69.76 147.18,70.08 147.18,70.58 147.12,70.65 146.48,70.65 145.93,71.21 145.93,74.98 146.53,75.59 148.57,75.59 149.13,76.15 149.13,77.58 148.79,77.92 148.79,81.36 146.55,83.6 146.55,84.55 144.26,86.84 144.26,87.41 142.75,88.92 142.75,90.74 139.67,93.82 131.17,93.82 129.98,92.63 129.83,92.48 128.81,92.48 128.26,91.93 128.2,91.87 126.33,91.87 126.03,91.57 113.99,91.57 112.03,89.62 109.77,89.62 108.98,90.41 106.22,90.41 103.85,88.04 92.64,88.04 91.06,86.46 84.35,86.46 83.25,85.36 80.43,85.36 78.37,83.3 76.26,83.3 72.82,79.86 71.69,79.86 71.17,79.34 71.17,78.2 v2(71.17,78.2)
  BOTTOM w0.076: v2(151.67,66.02) 151.67,65.83 151.37,65.52 151.05,65.52 150.89,65.36 150.1,65.36 150.07,65.4 149.59,65.4 UC1.AM4
3.3V_HDD_EN: length 184.7
  TOP w0.102: UZ8.5 42.08,26 42.02,25.95 41.12,25.95 v1(41.01,26.06) 40.23,26.06 40.12,25.95 RN7.1 RN6.2 38.21,25.95 v2(37.83,25.56)
  IN2 w0.122: v2(37.83,25.56) 38.18,25.92 38.18,38.01 39.45,39.28 39.45,41.41 41.73,43.68 48.41,43.68 57.21,52.49 57.21,57.66 58.31,58.76 58.31,59.82 58.79,60.3 58.79,61.07 59.48,61.77 59.48,68.26 62.92,71.7 62.92,73.04 70.73,80.85 72.4,80.85 75.84,84.29 76.88,84.29 78.03,85.45 78.03,85.98 78.42,86.37 82.85,86.37 84.03,87.54 90.73,87.54 92.23,89.03 97.34,89.03 99.46,91.16 104.47,91.16 105.04,91.72 109.35,91.72 109.53,91.9 111.52,91.9 112.44,92.82 125.42,92.82 125.78,93.18 125.81,93.18 127.75,93.18 128.33,93.76 129.29,93.76 130.59,95.06 134.59,95.06 136.03,96.5 138.84,96.5 139.96,95.39 142.28,95.39 142.62,95.05 142.62,92.98 148.13,87.47 148.13,83.73 148.32,83.54 150.04,83.54 151.44,82.14 151.44,78.69 151.92,78.21 153.09,78.21 153.48,77.81 v2(153.48,77.39)
  BOTTOM w0.081: 152.07,77.91 151.77,77.91 151.37,77.51 151.05,77.51 UC1.K2
  BOTTOM w0.102: v2(153.48,77.39) 153.48,77.65 153.22,77.91 152.07,77.91
3.3V_TP_EN: length 17.5
  TOP w0.102: RPC3.7 162.23,77.5 162.36,77.63 162.36,78.14 162.13,78.37 161.38,78.37 160.7,79.05 156.47,79.05 155.64,79.88 151.44,79.88 v1(150.31,78.76) 149.92,78.37 149.92,77.97 148.87,76.91 v2(148.73,76.91)
  BOTTOM w0.081: UC1.L5 148.61,76.8 v2(148.73,76.91)
3.3V_TS_EN: length 115.7
  TOP w0.102: v2(147.49,75.96) 147.89,76.36 148.39,76.36 148.58,76.17 150.36,76.17 150.75,76.56 150.75,77.17 151.62,78.03 154.1,78.03 154.26,77.88 156.1,77.88 156.97,77 RPC4.7 ; QV7.2 76.24,77.01 75.49,77.76 v1(75.11,77.76) 74.73,77.76 73.16,79.32 v2(71.74,79.32)
  IN2 w0.081: v2(147.49,75.96) 147.49,76.34 147.82,76.68 147.82,77.25 148.02,77.45 148.39,77.45 148.6,77.67 148.6,80.67 148.28,81 147.75,81 147.69,81.06
  IN2 w0.122: v2(71.74,79.32) 71.96,79.54 72.85,79.54 76.36,83.05 78.48,83.05 80.46,85.03 83.28,85.03 84.45,86.21 91.16,86.21 92.74,87.79 103.95,87.79 106.33,90.16 108.87,90.16 109.67,89.37 112.14,89.37 114.09,91.32 126.14,91.32 126.43,91.62 128.3,91.62 128.37,91.69 128.91,92.23 129.94,92.23 130.23,92.52 131.28,93.57 139.57,93.57 142.5,90.64 142.5,88.79 143.82,87.48 143.82,86.81 146.19,84.43 146.19,82.56 147.69,81.06
  BOTTOM w0.081: v2(147.49,75.96) 147.31,75.79 UC1.N7
3.3V_WWAN_EN: length 53.7
  TOP w0.254: 208.65,45.5 v2(208.71,45.57) ; 208.65,45.5 206.93,43.78 206.93,42.66 203.28,39.01 v1(203.28,37.02) 203.28,32.32 v2(203.88,31.72) ; 208.65,45.5 207.96,45.5 RZ40.2
  TOP w0.305: UE1.B42 v2(228.72,45.28)
  IN3 w0.254: v2(228.72,45.28) 228.72,45.05 228.46,44.79 225.04,44.79 224.4,45.44 221.71,45.44 220.59,44.31 220.59,41.95 218.84,40.2 215.47,40.2 214.79,39.51 209.63,39.51 203.88,33.77 v2(203.88,31.72)
  BOTTOM w0.254: v2(208.71,45.57) 208.9,45.57 209,45.68 UZ2.3
+0.9V_LAN: length 11.1
  TOP w0.203: v2(236.59,83.22) 236.84,83.48 236.84,84.05 236.69,84.2 UL1.16 ; UL1.40 v2(238.69,91.92) ; UL1.11 234.04,85.96 v2(233.82,85.74) ; UL1.22 v2(239.09,83.77) ; UL1.43 v2(237.49,89.78)
  TOP w0.508: CL11.1 v2(240.78,81.38)
  BOTTOM w0.508: v2(242.62,93.45) 242.1,92.93 241.66,92.93 240.65,91.92 v2(238.69,91.92)
  vias: v2(229.67,89.46) v2(229.67,88.87) v2(232.09,87.67) v2(235.37,92.18) v2(235.95,92.18) v3(229.1,89.06)
+0.675V_DDR_VTT: length 91.7
  IN2 w1.524: 180.45,10.32 178.17,10.32 175.41,13.08 135.41,13.08 133.15,15.34 126.67,15.34 122.92,19.09
  IN3 w1.524: 200.9,19.85 200.9,18.83 199.7,17.63 183.38,17.63 181.03,15.28 181.03,10.58
  BOTTOM w0.356: JDIMM2.204 200.6,19.58 200.52,19.66 ; JDIMM2.203 200.3,24.55 v2(200.37,24.49)
  vias: v2(121.04,23.85) v2(121.59,19.85) v2(121.59,19.22) v2(180.45,8.86) v2(180.96,9.18) v2(180.96,8.55) v2(200.62,21.69) v2(200.62,21.06) v3(120.26,22.71)
+0.675V_P:
  vias: v1(183.83,8.65)
+1.2V_LDO: length 7.1
  TOP w0.102: v3(266.81,19.02) 266.18,19.66 265.86,19.66 265.28,20.24 CR19.2
  TOP w0.203: UR1.1 257.32,19.33 256.16,20.48 ; CR18.2 255.64,14.71 256.65,15.73 UR1.10
  TOP w0.508: CR21.2 v2(256.83,20.48)
  vias: v2(256.39,14.33) v2(263.88,22.21) v2(264.66,21.25) v2(265.47,15.98) v2(266.42,17.38)
+1.05V_M: length 101.5
  TOP w0.457: v2(156.34,70.31) 156.54,70.51 RC300.1
  IN3 w1.016: 95.87,55.79 95.87,55.03 102.6,48.3 148.07,48.3 152.96,43.41 174.74,43.41 182.93,51.6
  BOTTOM w0.229: UC1.AE9 UC1.AF9 v2(146.9,68.34) 146.9,68.05 146.72,67.87 UC1.AG8 ; UC1.AG14 143.15,68.92 v2(142.97,69.1) ; UC1.AG13 143.97,68.71 144.17,68.91 v2(144.17,69.15)
  vias: v2(95.48,56.68) v2(96.06,56.68) v2(150.9,91.56) v2(151.17,91.03) v2(151.49,91.56) v2(151.77,91.03) v2(152.1,91.56) v2(152.35,91.03) v2(152.75,91.46) v2(181.6,60.36) v2(181.6,59.73) v2(182.17,60.55) v2(182.17,59.92) v2(182.17,59.28) v2(182.8,60.55) v2(182.8,59.92) v2(182.8,59.28) v2(183.63,52.43) v2(184.01,51.92) v2(184.2,52.55) v2(184.39,53.12) v2(184.65,51.92) v2(184.77,52.68) v2(185.15,52.23) v3(150.17,95.03)
+1.05V_MODPHY:
  vias: v3(144.53,92.07)
+1.05V_MODPHY_PCH:
  vias: v2(144.58,75.79) v2(145.09,76.11) v2(145.09,75.48) v2(146.24,77.45) v3(146.95,81.81)
+1.05V_MP: length 10.7
  IN1 w0.254: v2(187.25,56.13) 185.34,58.04 185.34,62.46 v2(186.74,63.86)
  BOTTOM w0.254: PC304.1 PR307.1 187.31,56.2 v2(187.25,56.13)
  vias: v2(186.8,63.22) v2(187.38,63.86) v2(187.44,63.22) v2(188.01,63.86) v2(188.05,63.22) v2(188.39,69.7) v2(188.39,69) v2(188.39,68.36) v2(188.39,67.73) v2(188.9,69.32) v2(188.9,68.68) v2(188.9,68.05) v2(188.9,67.41) v3(189.09,70.08)
+1.5V_RUN: length 262.6
  TOP w0.508: v2(103.62,93.32) v3(103.62,91.16) 103.62,89.1 v2(103.97,88.75)
  IN3 w0.508: v2(103.97,88.75) 104.63,88.75 105.54,87.84 109.48,87.84 110.63,86.69 110.63,85.58 113.81,82.4 137.23,82.4 138.56,81.07 138.56,77.58 139.13,77.01 142.94,77.01 143.45,77.52 v2(143.45,77.9)
  IN3 w1.016: 104.51,93.51 107.62,93.51 109.99,95.88 111.4,95.88 112.28,96.76 122.21,96.76 123.36,97.92 130.11,97.92 130.95,97.08 152.82,97.08 153.48,96.41 165.52,96.41 171.35,90.58 178.95,90.58 180.23,91.86 191.64,91.86 192.71,92.93 197.62,92.93 197.89,93.2 202.89,93.2 205.32,95.63 216.1,95.63 216.27,95.8 221.66,95.8 222.06,95.39 225.15,95.39 227.15,93.38 228.83,93.38 229.29,93.84 232.92,93.84 233.63,93.13 236.56,93.13 236.76,92.94 238.9,92.94 239.56,92.28 239.56,90.2 239.86,89.89 239.86,84.22 242.92,81.17 246.22,81.17 247.38,80 247.38,75.86 249.03,74.21 252.07,74.21 253.38,72.9 253.38,71.69 252.89,71.2 252.89,69.59 254.6,67.88 254.6,63.74 255.88,62.46 255.88,42.89 253.35,40.36 253.35,38.52
  BOTTOM w0.254: UC1.J15 143.11,77.56 v2(143.45,77.9)
  vias: v2(102.98,93.32) v2(252.46,38.84) v2(252.46,38.25)
+1.05V_RUN: length 243.1
  TOP w0.254: 246.69,58.46 246.39,58.75 UE2.B51
  TOP w0.279: 69.76,58.65 69.67,58.65 68.84,57.82 JXDP1.44 ; CC19.1 59.86,57.51 60.44,57.51 60.75,57.82 JXDP1.43
  TOP w0.508: v2(69.89,59.51) CC18.1 69.76,58.65 ; RC117.1 71.5,54.46 v2(71.73,54.23) ; v2(139.15,68.52) 139.06,68.42 CC58.1 ; CC19.1 59.94,58.05 v2(60.25,58.05) ; v2(142.52,77.85) 142.18,77.52 CC59.1 ; v2(108.59,89.47) 109.32,89.47 109.73,89.06 RC197.1 ; v2(249.02,54.14) 249.05,54.17 CE25.1 249.54,55.33 249.54,57.11 248.37,58.29 246.85,58.29 246.69,58.46 ; RE70.1 229.27,60.03 v2(229.18,59.94) ; v2(139.19,74.13) 139.16,74.16 CC70.1 138.25,74.41 CC79.1 138.25,76.49 CC84.1 ; CC72.1 141.88,67.58 v2(141.9,67.6)
  IN2 w0.508: v2(113.14,89.39) 112.42,88.68 109.38,88.68 v2(108.59,89.47) 107.83,89.47 105.46,87.1 93.03,87.1 89.12,83.19 85.62,83.19 84.59,84.21 80.62,84.21 78.76,82.36 76.65,82.36 70.72,76.43 70,76.43 66.36,72.79 66.36,70.71 66.92,70.15 66.92,69.74 64.94,67.76 64.35,67.76 61.07,64.49 61.07,62.71 59.68,61.32 59.68,60.21 58.95,59.49 58.95,58.56 59.46,58.05 v2(60.25,58.05) ; v2(229.18,59.94) 229.27,60.03 229.27,67.42 226.92,69.77 226.92,71.32 224.82,73.43 224.82,75.84 221.04,79.62 221.04,80.55 220.27,81.33 214.75,81.33 214.74,81.32 213.44,81.32 211.86,82.91 v2(210.68,82.91)
  IN3 w1.016: 186.61,86.33 186.11,85.83 183.76,85.83 183.22,85.29 175.34,85.29 174.77,85.86 161.92,85.86 159.83,87.95 157.7,87.95 155.94,89.7 152.51,89.7 ; 195.96,86.54 196.7,86.54 197.29,85.95 197.77,85.95 198.79,84.93 199.95,84.93 200.48,84.39 201.63,84.39 201.82,84.59 205.22,84.59 205.59,84.21 206.59,84.21 207.39,83.41 209.73,83.41
  IN4 w0.508: v2(249.02,54.14) 248.38,54.77 246.81,54.77 246.18,54.14 243.86,54.14 243.04,54.97 240.91,54.97 240.11,55.77 237.3,55.77 237.09,55.98 236.02,55.98 234.75,57.25 232.34,57.25 232.08,57.51 231.02,57.51 229.18,59.35 v2(229.18,59.94) ; v2(69.89,59.51) 69.89,56.06 v2(71.73,54.23) 67.57,54.23 65.33,51.98 62.79,51.98 61.27,53.5 61.27,57.04 v2(60.25,58.05)
  BOTTOM w0.229: v2(146.84,69.3) 146.66,69.12 UC1.AE8 ; v2(142.51,78.44) 142.7,78.44 UC1.H15 ; v2(144.42,78.63) 144.68,78.37 144.68,78.36 UC1.H11 UC1.J11
  BOTTOM w0.254: UC1.AG17 141.53,67.98 v2(141.9,67.6) 142.28,67.99 UC1.AG16 ; UC1.AF22 139.08,68.44 v2(139.15,68.52) ; UC1.P9 146.21,75.31 146.39,75.49 UC1.N8 146.66,75.78 146.84,75.96 v2(146.84,75.96) ; UC1.J17 142.22,77.56 v2(142.52,77.85) ; UC1.T21 139.56,73.77 v2(139.19,74.13)
  BOTTOM w0.33: v2(139.19,74.13) 139.56,74.5 UC1.R21
  BOTTOM w0.508: RC127.1 RC125.1 108.22,89.1 v2(108.59,89.47) 108.3,89.76 RC124.1 RC126.1 ; v2(113.14,89.39) RC196.2
  vias: v2(127.33,89.1) v2(127.91,89.1) v2(128.5,89.1) v2(138.16,91.35) v2(138.29,90.78) v2(141.43,69.08) v2(147.57,90.97) v2(147.76,91.54) v2(153.15,91.03) v2(153.57,91.46) v2(154.15,91.46) v2(158.29,56.62) v2(158.8,55.97) v2(158.89,56.55) v2(158.98,55.41) v2(159.4,56.27) v2(159.49,55.7) v2(159.47,55.05) v2(160.08,55.66) v2(160.08,55.07) v2(210.68,83.54) v3(130.04,89.45)
+1.5V_RUN_AUDIO: length 3.1
  TOP w0.508: 254.56,38.58 CA16.1 254.62,37.31 256.46,37.31
  vias: v1(256.68,37.21)
+1.05V_RUN_UZ7:
  vias: v1(180.49,52.37)
+1.05V_RUN_VMM:
  vias: v3(203.26,85.01)
+1.05V_VCCST: length 123.5
  TOP w0.102: v3(82.79,78.14) 83.2,78.55 84.49,78.55 PR529.1
  TOP w0.508: CC36.1 132.78,87.74 v2(130.75,85.71) 129.53,85.71 128.4,86.84 125.53,86.84 124.13,88.24 RC202.2 ; v2(137.31,69.19) 137.08,69.42 CC37.1 ; v2(112.23,90.49) 106.33,90.49 105.14,89.31 105.14,87.86 107.28,85.72 107.28,82.21 107.03,81.97 v2(107.03,79.54) ; PR529.1 85.27,78.26 v2(85.27,79.6) 85.27,80.17 85.65,80.56 PC511.1 86.14,79.69 PR528.1 PR527.1
  IN1 w0.508: v2(107.03,79.54) 106.22,79.54 105.49,78.8 87.4,78.8 86.6,79.6 v2(85.27,79.6)
  IN2 w0.508: v2(137.31,69.19) 136.51,69.99 136.51,76.2 134.79,77.92 134.79,79.19 133.44,80.54 133.44,81.45 132.55,82.34 131.38,82.34 130.62,83.1 130.62,85.58 v2(130.75,85.71)
  IN3 w0.508: v2(112.23,90.49) 111.27,89.53 111.27,85.85 114.01,83.1 128.4,83.1 128.97,83.67 128.97,85.2 129.48,85.71 v2(130.75,85.71)
  BOTTOM w0.254: v2(137.31,69.19) 137.79,69.19 UC1.AE23 138.23,68.85 UC1.AE22 UC1.AC22
  BOTTOM w0.508: v2(112.23,90.49) 112.12,90.61 RC199.1 110.99,90.6 RC25.1 ; RC116.1 106.94,78.24 107.32,77.86 RC204.1 107.33,77.13 RC208.1 RC114.1 107.71,78.53 107.03,79.21 v2(107.03,79.54)
+1.5V_VIN: length 1.7
  BOTTOM w0.102: v1(95.38,91.24) 95.72,91.58 PC401.1
+1.05V_VMM_VDD: length 7.8
  TOP w0.203: UV8.E3 v2(198.94,79.91) 198.61,79.59 UV8.D3 ; UV8.F12 v2(192.44,80.56) ; UV8.E6 v2(196.99,79.91) ; UV8.E7 v2(196.34,79.91) ; UV8.E9 v2(195.04,80.56) 195.37,80.24 UV8.E8 ; UV8.G3 198.61,81.54 198.94,81.21 v2(198.94,81.21) ; UV8.C9 v2(194.39,78.61) ; UV8.G12 v2(192.44,81.86) ; UV8.H6 v2(196.99,82.51) ; UV8.H7 v2(196.34,82.51) ; UV8.H9 v2(194.39,82.51) ; UV8.J3 v2(198.94,83.16) ; v2(195.04,78.61) UV8.C8 ; UV8.H8 v2(195.04,82.51)
  TOP w0.254: v2(196.99,79.91) 197.31,80.24 UV8.E5
  vias: v1(193.73,81.19)
+1.05V_VMM_VDDTX: length 5.5
  TOP w0.203: v2(196.34,78.61) UV8.C7 ; UV8.J2 v2(198.94,82.51) ; UV8.E12 v2(192.44,79.91) ; UV8.F3 v2(198.94,80.56) ; UV8.D12 v2(193.09,79.91)
  TOP w0.254: UV8.J10 v2(193.74,83.16) ; UV8.K10 v2(193.74,83.81) ; UV8.K8 v2(195.04,83.81) ; UV8.K9 v2(194.39,83.81) ; v2(196.34,78.61) 196.66,78.94 UV8.C6
  BOTTOM w0.508: v2(192.44,79.91) 192.43,79.9 CV91.1
  vias: v1(195.12,84.43)
+1.8V_RUN_CARD: length 17.6
  TOP w0.102: v2(264.26,11.28) 264.9,11.28 v3(266.05,10.13)
  IN3 w0.508: v2(264.26,11.28) 265.73,9.82 271.07,9.82 v2(275.8,5.09)
  BOTTOM w0.508: JSD1.14 v2(275.8,5.09)
+1.35V_MEM: length 92.8
  TOP w0.508: RD2.1 77.3,23.28 80.06,23.28 ; RD4.1 77.9,33.7
  BOTTOM w0.178: v2(131.08,64.3) 131.34,64.56 UC1.AN33 ; v2(127.67,58.89) 127.25,59.32 UC1.AY40
  BOTTOM w0.203: v2(122,62.94) 122.32,63.26 UC1.AR48
  BOTTOM w0.229: UC1.AY50 120.95,60.03 120.92,60.01 120.92,59.64 121.3,59.27 v2(121.36,59.27)
  BOTTOM w0.254: UC1.AY35 130.4,59.92 v2(130.83,59.49) ; UC1.AY44 124.21,60.15 v2(124.67,59.69) ; UC1.AP43 125.18,63.91 v2(124.86,63.59)
  BOTTOM w0.279: UC1.AJ31 132.77,67.46 133.3,67.98 v2(133.3,68.02) ; UC1.AH26 135.78,67.74 v2(135.45,67.74) ; v2(129.32,66.9) 129.06,67.16 UC1.AJ37 ; UC1.AJ33 131.47,67.46 131.93,67.92 v2(131.93,68.02)
  BOTTOM w0.356: JDIMM1.75 82.4,24.32 v2(82.98,23.74) ; v2(91.54,16.16) 91.7,16.32 JDIMM1.106 ; JDIMM2.105 170.9,24.89 170.46,24.45 v2(169.79,24.45) 169.31,24.45 169.1,24.66 JDIMM2.99 ; v2(90.01,16.21) 89.9,16.32 JDIMM1.100 ; v2(173.91,21.47) 175.58,21.47 176.07,20.99 176.07,19.36 176.6,18.83 JDIMM2.124 ; v2(86.47,23.84) 86,24.31 JDIMM1.87 ; v2(175.12,19.09) 174.8,18.77 174.8,18.77 JDIMM2.118 ; v2(167.6,16.29) JDIMM2.94 ; JDIMM2.93 167.3,24.98 v2(167.93,24.35) ; JDIMM2.88 v2(165.8,16.29) ; v2(162.2,16.29) JDIMM2.76 ; JDIMM2.117 174.5,26.99 v2(174.08,27.4) ; v2(88.01,16.14) 88.1,16.22 JDIMM1.94 ; JDIMM1.123 96.8,27.25 v2(97.14,27.6) ; JDIMM1.82 84.5,16.32 v2(84.57,16.25) ; JDIMM1.88 86.3,16.55 v2(85.98,16.23) ; v2(173,16.29) JDIMM2.112 ; JDIMM1.105 91.4,24.6 v2(91.43,24.57) ; JDIMM2.111 172.7,27.23 v2(172.52,27.4) ; JDIMM1.93 87.8,27.25 v2(87.52,27.53) ; JDIMM1.111 93.2,27.31 v2(93.42,27.53) ; JDIMM2.81 163.7,26.96 164.14,27.4 v2(165.55,27.4) 165.5,27.35 JDIMM2.87 ; v2(164,16.29) JDIMM2.82 ; JDIMM1.112 93.5,16.23 v2(93.46,16.19) ; v2(176.1,27.4) 176.3,27.21 JDIMM2.123 ; JDIMM1.117 95,27.16 v2(95.37,27.53) ; v2(84.12,27.53) 84.2,27.45 JDIMM1.81 ; v2(95.24,16.19) 95.3,16.25 JDIMM1.118 ; JDIMM2.75 161.9,27.11 v2(162.26,27.47) ; JDIMM2.106 v2(171.2,16.29) ; JDIMM2.100 v2(169.4,16.29) ; v2(89.65,24.57) 89.6,24.62 JDIMM1.99 ; JDIMM1.124 97.1,16.31 v2(97.02,16.23) ; v2(82.79,16.25) 82.7,16.34 JDIMM1.76
  vias: v3(180.14,38.46)
+1.35V_MEN_P: length 43.3
  TOP w0.203: v2(184.14,5.56) 184.42,5.84 PU200.5
  TOP w0.254: PC214.1 PR205.2 PC213.2 183.31,4.61 184.14,5.44 v2(184.14,5.56)
  IN2 w0.254: v2(202.55,14.01) 202.55,14.96 201.85,15.66 190.42,15.66 183.82,9.05 183.82,6.01 184.14,5.69 v2(184.14,5.56)
  IN2 w0.762: v2(191.25,12.8) 191.25,14.39 191.69,14.83 201.54,14.83 201.79,14.58
  vias: v1(204.27,14.26) v2(199.12,13.44) v2(199.12,12.8) v2(199.76,13.44) v2(199.76,12.8) v2(200.39,13.44) v2(200.39,12.8) v2(201.03,13.44) v2(201.03,12.8) v2(201.66,13.44) v2(201.66,12.8) v2(201.79,14.07) v2(202.3,13.44) v2(202.3,12.8)
+3.3V_ALW: length 422.2
  TOP w0.102: v2(202.11,37.74) 202.11,37.52 v3(201.46,36.87)
  TOP w0.254: RPE3.8 243.32,74.16 v2(243.56,74.4) 243.82,74.15 RPE3.7 ; RPE4.5 219.94,56.29 v2(219.7,56.04) 219.96,55.79 RPE4.6 ; RPE7.6 252.9,52.04 v2(253.16,52.3) 253.4,52.06 RPE7.5 ; RPE9.8 229.84,39.52 v2(229.54,39.22) 229.34,39.41 RPE9.7 ; RPE9.5 228.34,39.59 v2(228.71,39.22) 228.84,39.35 RPE9.6 ; RPE6.8 245.71,53.65 v2(246.04,53.32) ; RPE6.6 244.71,53.44 v2(244.96,53.19) 245.21,53.44 RPE6.7 ; RPE7.7 252.4,52.04 v2(252.15,52.3) 251.9,52.06 RPE7.8 ; v2(246.56,74.46) 246.74,74.28 RPE5.7 ; RPE4.8 220.07,54.79 v2(219.63,55.22) 219.7,55.29 RPE4.7
  TOP w0.305: CZ28.1 206.48,13.49 JKBTP1.6 ; JSH1.12 269.85,6.71
  TOP w0.381: UZ10.5 238.38,39.84 238.56,39.66 239.23,39.66 CZ48.1 ; CZ34.1 252.95,55.5 253.54,54.9 253.54,54.58 253.38,54.42 UZ6.5 ; UC8.5 117.46,89.52 117.48,89.51 CC35.1
  TOP w0.406: v2(226.52,39.22) 226.52,37.88 225.67,37.03 222.82,37.03 222.17,37.68 UZ11.5 ; PU804.5 30.4,12.42 30.92,12.94 30.92,13.18
  TOP w0.508: PC805.2 31.24,8.11 v2(31.55,8.42) ; v2(241.18,75.15) 240.77,74.73 RE36.1 RE79.1 ; RV701.1 188.1,71.34 v2(187.63,70.87) ; RC217.1 153.52,53.64 v2(153.21,53.95) 153.8,54.54 RC213.1 ; RE81.1 254.35,70.23 v2(254.94,70.81) ; RE71.1 254.5,51.73 v2(253.92,52.3) ; PR315.1 184.09,60.92 183.54,60.38 183.54,59.32 ; v2(227.64,57.95) 227.32,57.62 RE11.1 RE35.1 ; CC35.1 117.89,92.25 113.74,96.41 v2(113.74,98.32) ; v2(232.08,55.72) 232.34,55.98 233.02,55.98 RE8.1 ; RE276.1 225.24,40.44 RE12.1 226.17,40.05 226.52,39.7 v2(226.52,39.22) ; v2(248.84,52.74) RE73.1 RE75.1 ; PR895.1 v2(32.12,29.5) ; v2(70.6,83.54) 70.24,83.18 70.24,82.46 70.62,82.08 73.52,82.08 74.22,82.78 PR8.2 ; PR740.2 46.78,5.11 46.03,4.36 43.55,4.36 42.53,5.37 v2(42.53,8.8) ; v2(207.07,13.09) 206.81,13.36 CZ28.1 ; v2(240.7,40.21) 240.69,40.19 CZ48.1 ; RE87.2 238.54,46.24 v2(238.48,46.17) RE9.1 RE10.1 ; 269.85,6.71 269.85,8.36 269.6,8.61 267.96,8.61 267.51,8.17 C263.1 v2(267.14,8.91) ; RE25.1 239.83,44.2 240.28,44.65 RE83.1 v2(240.98,45.28) ; RE69.1 233.17,57.49 v2(232.78,57.89) ; PR810.1 v2(28.6,11.53) 27.05,9.98 PR815.1 27.98,7.85 PR813.1 ; v2(250.43,52.81) 250.75,52.49 RE72.1 ; PR859.2 31.33,14.74 v2(31.74,15.15) ; RE5.1 219.56,45.06 v2(219.11,45.5) ; 184.58,58.46 185.28,58.46 185.92,59.09 PR306.1 ; 30.92,13.18 v2(30.92,13.87) ; RE74.1 247.06,52.12 RE63.1 v2(247.05,52.74) ; RE68.1 v2(231.43,69.96) ; PR107.2 205.16,46.97 v2(205.09,46.9) ; RZ22.1 251.7,55.66 v2(252.46,54.9) 252.46,55.13 CZ34.1 ; PR2.1 v2(162.6,10.88)
  IN1 w0.508: v2(70.6,83.54) 70.6,82.32 67.56,79.29 66.73,79.29 61.66,74.22 58.18,74.22 54.25,70.3 54.25,69.51 53.07,68.33 53.07,57.2 v2(53.9,56.32) ; v2(204.46,69.38) 202.74,71.1 198.58,71.1 197.5,70.01 193.98,70.01 193.13,70.87 v2(187.63,70.87)
  IN2 w0.508: v2(197.41,32.31) 194.35,32.31 193.11,33.55 166.33,33.55 154.03,45.85 154.03,49.3 153.21,50.12 v2(153.21,53.95) ; v2(266.05,84.11) 265.29,84.11 264.12,82.94 262.66,82.94 262.03,82.31 262.03,81.74 259.89,79.6 259.54,79.6 257.35,77.41 257.35,73.86 254.94,71.45 v2(254.94,70.81) ; v2(199,16.29) 201.94,16.29 203.44,14.79 203.44,13.86 204.2,13.09 v2(207.07,13.09)
  IN3 w0.508: v2(243.56,74.4) 242.49,75.48 241.48,75.48 241.18,75.18 v2(241.18,75.15) ; v2(32.12,29.5) 32.33,29.72 40.03,29.72 v2(41.77,27.98) ; v2(113.74,98.32) 113.12,97.7 111.95,97.7 111.04,96.79 109.63,96.79 108.01,95.16 103.26,95.16 101.3,93.2 99.74,93.2 98.11,91.57 93.58,91.57 90.88,88.87 84.26,88.87 82.63,87.25 73.55,87.25 73.19,86.89 73.19,85.81 72.7,85.32 71.62,85.32 70.6,84.3 v2(70.6,83.54)
  IN4 w2.032: 54.41,53.82 54.41,50.39 49.33,45.31 41.47,45.31
  IN4 w3.048: 109.72,10.58 104.89,10.58 103.19,8.88 83.73,8.88 81.33,11.28 76.92,11.28 74.4,13.8 65.89,13.8 64.95,12.86
  BOTTOM w0.508: RZ24.1 214.03,90.99 216.75,90.99 216.93,90.82 220.43,90.82 221.02,90.23 221.02,83.31 221.27,83.06 221.27,80.13 224.89,76.51 224.89,73.41 227.04,71.26 227.04,67.26 v2(224.19,64.41) ; v2(266.05,84.11) 265.8,84.11 265.23,83.54 RZ31.1
  vias: v2(41.77,27.34) v2(54.53,56.32) v2(54.53,55.74) v2(54.53,55.16) v2(109.65,12.99) v2(109.97,12.48) v2(110.29,12.99) v2(110.6,12.48) v2(110.92,12.99) v2(111.24,12.48) v2(188.56,55.84) v2(188.56,55.21) v2(189.15,55.85) v2(189.15,55.22) v2(189.79,55.85) v2(189.79,55.22) v2(196.33,44.68) v2(196.65,44.11) v2(196.96,44.68) v2(197.28,44.11) v2(197.6,44.68) v2(197.92,44.11) v2(198.21,44.68) v2(198.53,44.11) v2(198.74,38.39) v2(198.79,44.68) v2(198.81,37.76) v2(199.12,44.11) v2(202.11,38.33) v2(204.46,68.74) v2(204.46,68.11) v2(205.03,68.55) v2(205.03,67.92) v2(205.05,69.18) v2(205.54,69.51) v2(205.6,68.87) v2(206.17,69.44) v2(206.2,68.81) v2(206.81,69.44) v2(206.81,68.81) v2(238.17,50.11) v2(238.17,49.47) v2(251.45,61.82) v2(252.07,61.83) v3(52.39,57.57) v3(185.28,55.31)
+3.3V_ALW2: length 599.7
  TOP w0.203: PC100.2 200.2,46.52 200.2,47.22 200.62,47.64 PU100.3
  TOP w0.381: v2(174.55,63.41) 172.63,63.41 169.28,60.06 UC6.5
  TOP w0.406: PU806.5 17.02,37.59 17.31,37.88 17.31,38.65 17.07,38.89 17.06,38.89 17.03,38.91 PC810.2
  TOP w0.508: v2(125.68,89.08) 122.9,89.08 116.29,95.68 v2(116.29,98.34) ; PR855.1 22.42,17.46 PR864.1 22.91,16.67 v2(23.04,16.8) ; v2(196.86,24.5) 196.86,30.1 v3(189.59,37.38) 184.65,42.31 v2(184.65,44.87) ; v2(154.38,101.08) 151.5,101.08 149.66,102.92 142.61,102.92 v2(141.4,104.13) ; v2(257.1,64.93) 256.22,64.05 RE57.2 ; PR103.2 201.54,46.58 v2(201.03,47.09) 200.46,46.52 PC100.2 ; PC810.2 16.42,40.09 16,40.52 ; v2(20.47,19.81) 20.47,20.31 PR846.1 ; 16,40.52 13.48,40.52 13.12,40.16 PR819.2 ; 16,40.52 16.1,40.52 16.92,41.34 v2(19.99,41.34) ; RZ16.1 133.78,92.47 v2(133.78,90.69) ; PR829.1 v2(29.9,31.47)
  IN1 w0.508: v2(150.06,90.76) 150.06,90.65 149.69,90.28 146.41,90.28 146.05,90.64 142.56,90.64 140.98,92.22 134.09,92.22 133.78,91.91 v2(133.78,90.69) ; v2(201.03,47.09) 198.04,47.09 194.17,50.96 191.95,50.96 188.65,54.27 188.2,54.27 186.42,56.04 185.09,56.04 183.65,57.48 182.95,57.48 178.35,62.09 175.87,62.09 v2(174.55,63.41)
  IN2 w0.508: v2(20.18,31.48) 20.76,30.9 29.32,30.9 v2(29.9,31.47) ; v2(125.68,89.08) 126.71,90.11 133.53,90.11 133.78,90.36 v2(133.78,90.69) ; v2(213.96,74.08) 215.48,72.55 215.48,69.15 216.3,68.33 216.3,57.68 215.63,57.01 215.63,56.43 215,55.79 213.6,55.79 213.28,55.47 213.28,52.49 214.55,51.22 214.55,50.01 214.36,49.82 214.36,48.78 213.98,48.39 207.48,48.39 205.37,46.29 201.83,46.29 v2(201.03,47.09) ; v2(156.13,5.28) 156.23,5.18 175.5,5.18 v2(176.33,6.01) ; v2(184.65,44.87) 185.51,45.72 185.51,46.61 184.9,47.22 176.42,47.22 173.08,50.56 173.08,60.67 174.55,62.14 v2(174.55,63.41) 173.44,64.52 173.44,74.05 172.64,74.84 170.23,74.84 167.95,77.13 167.95,78.59 165.91,80.62 156.83,80.62 154.8,82.65 154.8,85.45 150.06,90.19 v2(150.06,90.76)
  IN3 w0.508: v2(176.33,6.01) 177.54,7.22 177.54,18.07 177.66,18.2 177.66,21.82 181.22,25.37 195.99,25.37 v2(196.86,24.5) ; v2(156.13,5.28) 157.58,5.28 158.27,5.97 158.27,9.97 156.32,11.91 140.48,11.91 136.41,15.98 126.8,15.98 119.75,23.02 119.75,24.7 117.59,26.86 50.71,26.86 49.76,25.9 47.29,25.9 43.85,22.47 36.75,22.47 32.82,26.4 31.02,26.4 30.21,27.21 30.21,31.15 v2(29.9,31.47) ; v2(141.4,104.13) 139.37,102.1 121.48,102.1 117.72,98.34 v2(116.29,98.34) ; v2(19.99,41.34) 19.99,39.45 19.46,38.91 19.46,36.4 20.68,35.18 20.68,33.38 20.18,32.88 v2(20.18,31.48) 20.18,20.1 v2(20.47,19.81) 23.04,17.25 v2(23.04,16.8)
  IN4 w0.508: v2(257.1,64.93) 257.1,65.58 253.64,69.04 251.98,69.04 250.09,70.94 250.09,72.43 247.97,74.55 247.97,75.02 247.28,75.7 245.75,75.7 245.17,76.28 242.98,76.28 241.7,77.56 238.28,77.56 238.07,77.77 236.32,77.77 235.78,77.23 232.07,77.23 230.91,76.07 222.94,76.07 221.98,75.12 215,75.12 v2(213.96,74.08)
  BOTTOM w0.508: R272.2 160.72,98.51 155.04,98.51 154.38,99.18 v2(154.38,101.08)
+3.3V_ALW_PCH: length 241.3
  TOP w0.254: RC82.1 159.52,70.01 159.03,70.51 RC179.1
  TOP w0.305: RC82.1 159.52,69.23 v2(159.96,68.8) ; JAPS1.1 36.57,42.96
  TOP w0.381: v2(159.96,68.8) 159.78,68.62 RC81.1
  TOP w0.508: RC2.1 148.55,54.66 v2(149.23,53.97) ; v2(150.04,53.95) 150.04,54.33 150.29,54.58 RC245.2 RC79.1 ; RC216.1 153.43,52.69 152.34,53.78 v2(152.34,53.95) ; 36.57,42.96 39.21,42.96 41.38,45.14 49.24,45.14 52.6,41.77 v1(55.03,41.77) 57.66,41.77 58.06,42.17 58.06,42.74 58.81,43.48 60.51,43.48 61.46,44.43 v2(61.46,47.79) 57.16,52.08 57.16,55.18 57.9,55.92 RC120.2 ; RC79.1 RC212.1 ; RC79.1 v2(151.7,53.95) ; 165.47,63.47 163.91,63.47 161.53,65.85 161.53,68.05 160.78,68.8 v2(159.96,68.8)
  TOP w1.016: 177.34,52.68 175.95,54.08 175.95,56.36 177.28,57.7 178.55,57.7
  IN3 w0.508: 141.99,66.91 141.99,60.81 144.47,58.34 144.47,57 147.5,53.97 v2(149.23,53.97)
  IN3 w1.016: 159.56,52.43 162.36,55.22 162.36,60.43 165.47,63.54 ; 159.56,52.43 159.56,49.19 161.34,47.41 161.34,46.01 162.67,44.68 173.03,44.68 177.09,48.74 177.09,51.85 177.66,52.43 ; 159.56,52.43 155.51,52.43 154.55,53.38 154.55,54.52 154.1,54.97 151.37,54.97
  BOTTOM w0.229: UC1.AE21 139.66,68.85 UC1.AE20 140.41,69.6 v2(140.48,69.6) ; v2(142.81,67.62) 143.12,67.3 UC1.AH14
  BOTTOM w0.254: UC1.AC9 UC1.AA9 145.25,71.2 v2(145.1,71.36)
  BOTTOM w0.508: v2(149.23,53.97) 149.23,53.65 150.36,52.53 150.36,49.2 149.77,48.62 113.27,48.62 112.76,48.11 71.7,48.11 69.92,49.89 63.55,49.89 v2(61.46,47.79)
  vias: v2(141.43,69.67) v2(165.98,65.57) v2(165.96,64.34) v2(166.06,62.72) v2(178.55,52.68) v2(178.59,52.09)
+3.3V_ALW_PCH_UZ7: length 1.5
  TOP w0.102: v1(181.85,57.82) 181.71,57.68 CZ56.1
+3.3V_ALW_UE1: length 57.7
  TOP w0.254: CE6.1 230.53,41.1 230.53,41.85 230.85,42.17 230.85,42.79 230.47,43.17 UE1.A43
  TOP w0.279: CE4.1 221.46,52.65 UE1.A17
  TOP w0.305: UE1.B30 224.62,46.9 225.42,46.9 v2(225.44,46.87) ; UE1.B5 231.22,52.26 v2(231.13,52.17) ; UE1.A54 235.65,47.65 236.08,48.08 CE2.1
  TOP w0.508: v2(231.25,55.22) 231.25,55.22 CE3.1 ; CE5.1 221.57,46.93 221.86,46.65 v2(222.4,46.65) ; CE6.1 231.06,39.48 231.32,39.22 v1(233.68,39.22) 234.81,39.22 235.7,40.11 235.7,40.14 v2(235.76,40.21) ; CE4.1 221.42,52.25 221.03,51.85 v2(220.46,51.85) ; CE2.1 v2(236.83,48.76)
  IN2 w0.508: v2(220.46,51.85) 220.75,51.56 220.75,49.17 222.4,47.52 v2(222.4,46.65)
  IN3 w0.305: v2(222.4,46.65) 222.4,46.81 222.75,47.15 224.71,47.15 224.99,46.87 v2(225.44,46.87)
  IN4 w0.508: v2(231.13,52.17) 231.59,52.17 232.82,50.95 234,50.95 234.37,50.58 v2(236.18,50.58)
  BOTTOM w0.508: v2(225.44,46.87) 225.44,47.18 225.75,47.49 226.51,47.49 227.25,48.23 227.89,48.23 228.52,48.87 228.52,50.84 229.22,51.54 230.49,51.54 v2(231.13,52.17) 231.22,52.26 231.22,55.18 v2(231.25,55.22) ; v2(236.83,48.76) 237.29,48.3 237.29,41.73 v2(235.76,40.21)
+3.3V_ALW_UE2: length 73.4
  TOP w0.279: UE2.B3 244.91,67.58 244.82,67.48 244.82,67.01 245.12,66.7 v2(245.15,66.7) ; CE19.1 242.16,56.47 UE2.A41 ; UE2.A11 240.66,69.7 240.91,69.96 240.91,70.45 240.72,70.65 v2(240.65,70.65) ; v2(235.62,62.66) 235.89,62.66 235.94,62.6 UE2.A26
  TOP w0.305: UE2.B35 237.91,58.66 237.45,58.2
  TOP w0.381: CE22.1 237.02,57.12 237.45,57.56 237.45,58.2
  TOP w0.508: CE19.1 242.18,55.75 v2(242.27,55.66) ; v2(236.33,56.62) 236.33,56.24 236.63,55.94 CE22.1 ; v2(235.62,62.66) 235.3,62.66 234.61,61.96 CE14.1 ; v2(247.02,70.79) 247,70.78 CE17.1 ; v2(240.65,70.65) 240.77,70.76 CE13.1
  IN1 w0.508: v2(247.02,70.79) 244.72,68.49 244.72,66.9 244.92,66.7 v2(245.15,66.7)
  IN2 w0.508: v2(247.02,70.79) 247.86,69.94 248.01,69.94 249.2,68.76 249.2,67.51 248.34,66.65 248.34,64.17 v2(248.89,63.61) 249.97,62.53 v2(249.97,60.56)
  IN3 w0.508: v2(240.65,70.65) 240.65,70.84 241.41,71.6 241.41,72.55 242.11,73.25 245.8,73.25 246.5,72.55 246.5,71.3 v2(247.02,70.79) ; v2(242.27,55.66) 242.29,55.69 243.42,55.69 244.27,54.84 246.3,54.84 248.02,56.55 249.61,56.55 250.19,57.14 250.19,58.79 250.61,59.21 v2(250.61,60.56)
  IN4 w0.508: v2(242.27,55.66) 241.4,55.66 240.66,56.4 237.57,56.4 237.35,56.62 v2(236.33,56.62)
  BOTTOM w0.508: v2(236.33,56.62) 236.33,57.12 237.03,57.82 237.03,58.58 236.62,58.99 236.62,61.92 235.88,62.66 v2(235.62,62.66) 235.26,62.66 235.06,62.46 234.56,62.46 234.21,62.81 234.21,64.53 234.56,64.88 v2(235.05,64.88)
  vias: v1(248.46,63.98)
+3.3V_ALWP: length 33.2
  TOP w0.102: v2(210.49,63.79) 210.53,63.79 v1(211.34,62.98)
  TOP w0.254: v2(202.48,44.68) PR100.1
  IN3 w0.254: v2(202.48,44.68) 204.19,46.39 205.85,46.39 207.76,48.3 211.33,48.3 213.42,50.38 213.42,50.97 215.63,53.19 215.63,60.32 214.36,61.59 214.36,62.46 213.03,63.79 v2(210.49,63.79)
+3.3V_CAM: length 16.8
  TOP w0.102: CZ1.1 75.11,74.78 v3(75.87,74.02)
  TOP w0.508: v2(71.68,78.71) 72.42,77.98 72.42,76.58 72.7,76.3 QZ1.1 74.16,76.3 74.8,75.65 CZ1.1
  BOTTOM w0.254: JEDP1.11 65.71,77.06
  BOTTOM w0.508: v2(71.68,78.71) 71.49,78.71 70.66,79.54 69.52,79.54 69.15,79.17 66.85,79.17 65.71,78.03 65.71,77.06
+3.3V_HDD: length 11.9
  TOP w0.508: v2(46.85,12.8) 47.05,12.8 CN1.1
  IN2 w2.032: 40.25,30.64 40.25,28.87 39.83,28.45 39.83,20.1
  vias: v2(39.29,7.59) v2(39.48,32.23) v2(39.88,7.59) v2(40.07,32.23) v2(40.46,7.59) v2(40.65,32.23) v2(41.33,19.85) v2(41.67,19.33) v2(41.94,19.85) v2(45.63,12.8) v2(46.24,12.8) v3(41.45,15.98)
+3.3V_HDD_UZ8: length 1.9
  TOP w0.102: UZ8.8 44.52,25.2 43.49,24.17 v1(43.49,23.91)
+3.3V_LAN: length 202.4
  TOP w0.254: UL4.21 258.76,79.6 CL15.1 ; CL26.1 247.38,79.61 247.4,79.6 UL4.39 ; v2(253.06,81.44) 253.06,81.41 252.89,81.24 UL4.30 ; UL4.1 248.89,75.83 CL25.1 ; CL19.1 255.39,75.76 UL4.14 ; v2(252.21,75.98) 252.39,76.17 UL4.8 ; v2(250.62,75.29) 250.39,75.51 UL4.4
  TOP w0.381: v2(244.36,84.92) 244.36,85.31 244.19,85.47 UL2.5 243.71,85.59 243.38,85.27 243.38,84.89
  TOP w0.457: RL8.1 230.58,92.76 v2(230.14,92.76)
  TOP w0.508: RL29.1 259.73,77.6 v2(258.5,77.6) ; v2(234.68,94.45) RL4.2 RL6.1 233.18,94.45 RL5.1 ; v2(243.31,95.49) 243.47,95.33 CL18.1 ; v2(258.12,80.17) 258.52,79.77 CL15.1 259.17,79.77 259.7,80.3 259.7,81.04 258.46,82.28 256.94,82.28 256.07,83.15 CL27.1 ; CL26.1 246.68,80.12 246.5,80.3 v2(245.86,80.3) v3(245.86,81.7) 245.99,81.83 245.99,83.01 245.43,83.57 243.88,83.57 243.41,84.04 243.41,84.86 243.38,84.89 ; RL30.1 261.44,76.31 v2(260.88,76.87) ; v2(248.34,76.36) 248.79,75.91 CL25.1 ; CL19.1 255.68,75.13 v2(255.96,74.85) ; RL1.1 RL2.1 243.51,91.54 v2(242.62,92.43)
  IN1 w0.508: v2(215.51,82.66) 215.49,82.66 215.49,81.98 218.52,78.95 223.81,78.95 224.87,80.01 231.98,80.01 232.46,80.49 242.18,80.49 242.53,80.85 245.31,80.85 v2(245.86,80.3)
  IN2 w0.508: v2(258.12,80.17) 255.83,77.89 255.83,77.19 ; v2(255.96,74.85) 255.96,76.17 255.83,76.3
  IN2 w1.524: JLOM1.12 259.08,99.99 260.66,99.99 261.67,98.97 261.67,97.38 260.72,96.43 245.99,96.43 ; 245.99,96.43 244.26,96.43 243.32,95.49 v2(243.31,95.49) ; 245.99,96.43 JLOM1.9
  IN3 w0.508: v2(253.06,81.44) 253.06,80.97 253.86,80.17 v2(258.12,80.17) ; v2(212.43,69.84) 212.43,70.73 212,71.16 210.05,71.16 209.03,70.14 204.46,70.14 203.82,70.78 199.44,70.78 198.94,70.27 195.93,70.27 195.43,70.78 188.46,70.78 186.04,68.36 186.04,62.84 187.38,61.51 187.38,59.21 187.88,58.7 187.88,54.97 188.52,54.33 188.9,54.33 189.41,53.82 189.41,51.03 190.68,49.76 192.14,49.76 194.81,47.09 194.81,45.69 195.69,44.81 v2(195.69,44.49)
  BOTTOM w0.508: v2(215.51,82.66) 215.51,82.28 213.47,80.24 213.47,79.02 213.61,78.87 213.61,78.16 212.34,76.89 212.34,69.93 v2(212.43,69.84) ; v2(242.62,92.43) 242.62,91.27 243.42,90.47 243.42,86.25 244.36,85.31 v2(244.36,84.92) ; v2(258.12,80.17) 258.5,79.79 v2(258.5,77.6) 259.66,76.43 260.62,76.43 260.88,76.69 v2(260.88,76.87)
+3.3V_LAN_OUT: length 2.8
  TOP w0.203: UL1.15 v2(236.29,83.87) ; UL1.29 241.43,87.16 v2(241.54,87.05) ; UL1.19 v2(237.89,83.84)
  vias: v2(232.92,91.57) v3(233.22,89.76)
+3.3V_LAN_UL3:
  vias: v1(197.54,40.61)
+3.3V_M: length 98.7
  TOP w0.508: CC54.1 146.16,71.9 v3(146.23,71.9) 146.58,71.9 v2(146.84,72.15)
  IN1 w0.508: v2(172.07,77.17) 172.4,77.5 176.68,77.5 177.16,77.02 v2(177.43,77.02)
  IN2 w0.508: v2(172.07,77.17) 172.21,77.17 174.07,75.31 174.07,64.84 175.18,63.73 175.18,62.01 179.95,57.25 179.95,51.03 181.03,49.95 186.11,49.95 186.74,50.58 186.74,51.47 187.06,51.79 192.01,51.79 v2(192.96,52.74) 193.6,52.11 193.6,48.53 192.94,47.87 192.94,44.49 194.7,42.72 203.29,42.72 v2(203.59,43.03)
  IN3 w0.508: v2(172.07,77.17) 171.61,77.17 167.48,73.04 166.65,73.04 165.09,71.48 153.85,71.48 152.72,72.6 151.77,72.6
  BOTTOM w0.254: v2(146.84,72.15) 146.66,71.98 UC1.Y8
  BOTTOM w0.508: RC231.1 172.44,76.81 v2(172.07,77.17) ; JSPI1.16 v2(177.43,77.02)
+3.3V_M_TPM: length 33.3
  TOP w0.102: v3(191.34,41.08) 191.34,41.34 v2(191.88,41.88)
  TOP w0.381: UZ1.19 191.35,50.8 CZ7.1 ; CZ4.1 186.8,42.78 UZ1.3 ; CZ6.1 188,51.47 188,51.21 188.1,51.11 UZ1.24 ; UZ1.10 191.35,42.76 CZ5.1
  TOP w0.508: v2(191.88,41.88) 191.63,41.88 191.24,42.28 CZ5.1 ; CZ4.1 186.66,42.28 187.06,41.88 v2(187.67,41.88) ; v2(187.38,51.16) 187.62,51.4 CZ6.1 ; CZ7.1 v2(192.96,51.65)
  IN2 w0.508: v2(192.96,51.65) 192.62,51.31 192.62,48.45 192.3,48.13 192.3,45.31 191.88,44.9 v2(191.88,41.88) 191.25,42.52 188.3,42.52 v2(187.67,41.88)
  IN4 w0.508: v2(187.38,51.16) 192.47,51.16 v2(192.96,51.65)
+3.3V_M_UL3:
  vias: v1(202.83,40.22)
+3.3V_MMI: length 5.3
  TOP w0.102: v2(259.18,10.26) v3(259.18,9.39)
  TOP w0.203: UR1.11 256.9,15.33 v2(256.67,15.09) ; UR1.9 256.49,16.13 255.96,15.6 CR2.1
  TOP w0.508: RR6.1 v2(259.18,10.26) ; CR2.1 v2(255.64,16.29)
  vias: v2(256.34,13.06) v2(256.97,13.06) v2(257.54,13.31) v2(260.85,21.5) v2(262.56,11.4) v2(262.56,10.77) v2(266.43,14.64)
+3.3V_RTC_LDO: length 89.6
  TOP w0.102: v2(201.54,44.61) 202.17,43.98 v3(202.93,43.98)
  TOP w0.508: PR103.1 v2(201.54,44.61) ; PD3.3 227.93,96.76 227.83,96.87 v2(227.83,97.57)
  IN2 w0.508: v2(201.54,44.61) 201.54,44.77 202.43,45.66 205.64,45.66 207.57,47.59 215.53,47.59 216.3,48.37 216.3,56.79 216.97,57.45 216.97,68.92 v2(216.14,69.74)
  IN4 w0.508: v2(230.4,70.5) 230.4,70.41 229.13,69.14 224.38,69.14 222.69,70.83 218.75,70.83 218.09,70.18 216.58,70.18 v2(216.14,69.74)
  BOTTOM w0.508: v2(230.4,70.5) 230.29,70.5 230.12,70.66 230.12,71.89 231.08,72.85 231.08,74.97 230.67,75.38 230.67,78.53 233.03,80.9 233.03,85.11 230.77,87.37 230.77,89.61 230.98,89.81 230.98,92.93 228.56,95.34 228.56,96.28 227.83,97.02 v2(227.83,97.57)
+3.3V_RUN: length 479.2
  TOP w0.203: 212.61,72.99 213.46,73.84 213.46,74.41 213.74,74.69 UV600.30 ; PU500.21 92.24,74.09 v2(92.51,73.82) 92.38,73.69 PU500.20 ; UV7.56 222.65,89.83 222.9,90.08 222.9,90.4 223.48,90.97 224.27,90.97 CV69.1 ; UV600.51 223.56,74.69 224.19,74.07 CV603.1 ; CV62.1 212.86,84.56 214.71,84.56 214.79,84.63 UV7.28 ; UV7.14 216.16,91.29 216.01,91.44 214.6,91.44 214.33,91.72 214.33,92.42 214.45,92.54 ; CV604.1 224.13,77.11 224.11,77.09 UV600.57 ; CV600.1 221.43,79.73 221,79.73 220.85,79.58 UV600.5 ; CV66.1 222.08,82.38 222.08,82.78 221.89,82.97 221.13,82.97 220.96,83.13 UV7.41 ; UV600.21 213.47,78.29 213.25,78.08 212.81,78.08 212.55,78.33 CV601.1
  TOP w0.254: RPE3.5 244.82,74.34 v2(244.56,74.59) 244.32,74.35 RPE3.6
  TOP w0.305: JLPDE1.1 8.96,15.88 v2(9.2,16.12) 9.46,15.85 JLPDE1.2 ; CZ11.1 245.55,12.41 245.98,11.98 JUSH1.13 245.98,10.22
  TOP w0.381: v2(159.08,72.68) 159,72.61 RC180.1 ; QC1.2 173.47,59.16 173.53,59.09 v2(173.69,59.09) ; UC4.5 165.69,79.81 v2(165.39,79.51) ; UV502.14 257.75,71.68 256.54,70.47 CV511.1 ; v2(171.82,59.28) 171.69,59.16 QC1.5 ; v2(166.65,84.91) 166.74,85 167.59,85 168.2,84.39 UC5.5
  TOP w0.406: 170.28,59.32 170.45,59.16 QC1.5
  TOP w0.508: RV56.1 212.69,82.22 v2(213.06,82.59) 213.49,82.16 RV54.1 ; v2(210.76,75.83) 210.92,75.67 RV605.1 ; RZ54.1 205.5,41.95 202.77,39.22 v2(202.77,37.79) ; RV611.1 v2(225.51,74.07) CV603.1 ; v2(210.43,79.96) 210.64,80.17 RV602.1 ; RV501.1 v2(261.73,75.17) ; RD27.2 199.44,27.28 v2(199.5,27.34) 200.23,27.34 CD63.1 CD64.1 ; v2(226.3,90.07) 226.29,90.07 225.79,89.57 RV555.1 ; v2(268.59,74.27) 268.34,74.02 RV507.1 ; v2(256.02,71.67) 256.27,71.41 CV511.1 ; RV58.1 224.49,93.13 v2(224.17,93.45) 224.03,93.59 RV60.1 223.48,94.14 223.32,94.3 RV8.2 ; RV613.1 v2(229.19,77.76) 229.19,78.02 228.35,78.85 RV610.1 RV615.1 RV601.1 ; v2(213,78.59) 212.63,78.59 CV601.1 ; RC180.1 RC66.1 ; v2(226.25,83.76) 226.15,83.86 RV551.1 RV51.1 ; RV57.1 225.71,87.92 226.08,87.92 v2(226.27,88.11) ; v2(157.53,89.41) 157.42,89.52 RC164.1 154.31,89.52 153.53,88.75 RC163.1 RC176.1 151.5,88.87 150.47,89.9 149.9,89.9 149.43,90.37 149.43,90.99 v2(149.53,91.1) ; RV55.1 212.49,83.1 v2(213.13,83.73) 212.8,84.06 CV62.1 ; CV602.1 212.9,72.11 213.27,72.48 v2(213.27,72.57) 212.85,72.99 RV604.1 ; v2(232.16,70.95) 232.47,71.27 RE67.1 ; v2(125.53,88.43) 125.65,88.31 CC85.2 ; RV612.1 v2(229.83,74.07) ; 170.28,59.32 170.28,60.16 172.34,62.22 RN3.1 RN4.1 ; CV61.1 214.45,92.39 214.81,92.04 v2(214.83,92.04) ; v2(142.13,76.14) 142.13,75.73 141.69,75.29 CC66.1 141.25,74.88 141.49,74.64 CC64.1 ; CV604.1 v2(225.75,77.11) 225.85,77.01 RV614.1 ; 42.52,24.41 42.05,23.94 39.47,23.94 38.65,24.76 RN6.1 38.16,25.03 v2(37.88,24.75) ; v2(71.54,55.83) 70.91,55.83 RC122.1 ; RE48.1 v2(232.65,63.86) 232.33,63.86 231.95,64.24 RE51.1 ; v2(78.28,73.76) 77.57,73.05 75.4,73.05 73.11,75.34 QZ1.3 68.89,75.34 67.91,76.31 67.13,76.31 66.61,75.79 CA7.1 66.61,74.76 v2(66.66,74.71) ; v2(228.05,80.75) 227.62,80.75 RV603.1 ; CV66.1 v2(222.64,82.52) ; v2(223.86,91.8) 224.11,91.54 224.47,91.54 CV69.1 ; v2(121.85,27.47) 121.53,27.15 CD32.1 CD31.1 ; v2(222.97,80.24) 222.64,80.57 CV600.1 ; RC156.2 154.95,75.27 v2(154.91,75.23) ; v2(166.65,84.91) 166.46,85.1 RC95.1
  IN1 w0.508: v2(84.98,75.42) 85.56,74.84 90.86,74.84 91.87,73.82 v2(92.51,73.82)
  IN1 w1.524: 253.1,25.95 253.1,27.05 248.29,31.86 248.29,46.32 249.75,47.78 251.17,47.78 256.18,52.79 256.18,59.13 257.04,59.98
  IN2 w0.457: v2(202.77,37.79) 208.14,37.79 210.55,40.2 213.57,40.2 217.58,44.21 219.7,44.21 220.81,45.31 220.81,47.9 219.88,48.84 219.88,50.03 219.53,50.37 219.48,50.37 v2(219.45,50.39)
  IN2 w0.508: v2(229.83,74.07) v2(231.83,74.07) 232.65,73.24 232.65,71.12 232.49,70.95 232.45,70.95 ; v2(187,22.26) 195.49,22.26 195.64,22.41 197.22,22.41 200.94,18.69 201.52,18.69 204.15,16.06 208.83,16.06 211.02,13.87 214.63,13.87 v2(214.77,14.01) ; v2(232.65,63.86) 233.32,64.53 233.32,67.06 232.68,67.7 232.68,70.72 232.45,70.95 ; 232.45,70.95 v2(232.16,70.95) ; v2(219.99,72.14) 220.02,72.14 223.53,68.62 223.53,61.98 221.65,60.1 221.65,59.2 220.37,57.93 220.37,53.67 219.45,52.75 v2(219.45,51.03) v2(219.45,50.39)
  IN3 w0.508: v2(199.5,27.34) 198.62,26.45 198.62,23.66 197.9,22.95 195.39,22.95 194.71,22.26 v2(187,22.26) ; v2(64.38,60.49) 64.06,60.17 64.06,58.87 67.71,55.22 70.54,55.22 71.15,55.83 v2(71.54,55.83) ; v2(223.86,91.8) 224.17,92.11 v2(224.17,93.45) 216.24,93.45 v2(214.83,92.04)
  IN4 w0.508: v2(159.08,72.68) 157.47,72.68 156.5,73.65 ; v2(223.86,91.8) 224.55,91.8 226.28,90.07 v2(226.3,90.07) ; v2(37.88,24.75) 35.14,24.75 33.45,23.06 33.45,19.67 32.25,18.47 23.69,18.47 23.04,17.82 13.34,17.82 12.33,16.81 12.33,16.03 11.75,15.44 9.83,15.44 9.2,16.08 v2(9.2,16.12) ; v2(244.56,74.59) 244.14,75.01 242.45,75.01 241.18,76.29 237.76,76.29 237.54,76.5 236.89,76.5 236.28,75.89 234.31,75.89 232.48,74.07 v2(231.83,74.07)
  BOTTOM w0.254: UC1.K14 UC1.K16 142.45,76.46 v2(142.13,76.14) ; v2(66.66,74.71) 66.85,74.9 66.85,75.44 66.66,75.93 ; UC1.W9 146.21,72.19 UC1.V8 146.84,72.81 v2(146.84,73.11) ; RPC2.5 143.57,89.14 v2(143.82,89.38) 144.07,89.12 RPC2.6 ; UC1.T9 v2(146.84,74.06) 146.66,73.88 UC1.U8 ; RPC2.7 v2(144.57,89.38) 144.64,89.38 145.07,88.95 RPC2.8 ; RPC20.5 148.02,90.68 148.17,90.83 v2(148.17,91.08) ; UC7.14 63.69,60.49 CC17.1 ; v2(149.53,91.1) 149.52,91.08 RPC20.8
  BOTTOM w0.356: v2(199.5,27.34) 199.1,26.94 JDIMM2.199 ; JDIMM1.199 119.6,27.47
  BOTTOM w0.508: v2(261.73,75.17) 263.07,75.17 263.97,74.27 v2(268.59,74.27) ; v2(226.3,90.07) 226.3,89.85 226.87,89.27 226.87,88.39 226.59,88.11 v2(226.27,88.11) 225.48,87.32 225.48,84.56 226.25,83.78 v2(226.25,83.76) 225.79,83.3 223.15,83.3 222.64,82.78 v2(222.64,82.52) ; CC17.1 v2(64.38,60.49) ; 119.43,27.8 121.52,27.8 v2(121.85,27.47) ; 119.43,27.8 119.43,27.63 119.6,27.47 ; 119.43,27.8 119.43,29.82 118.38,30.87 118.38,37.01 118.88,37.52 157.64,37.52 v2(161.53,33.63) ; RV68.1 215.18,92.38 v2(214.83,92.04) ; RC68.1 155.82,76.2 RC247.1 155.82,75.41 155.63,75.23 v2(154.91,75.23) ; 92.95,93.45 92.57,93.83 92.57,96.05 92.94,96.42 PR400.1 ; RC160.1 155.32,79.53 RC158.1 154.46,79.14 v2(154.1,78.78) ; UV501.1 262.06,79.1 261.8,79.36 CV510.1 260.86,79.36 260.5,79 v2(260.5,77.93)
  vias: v2(41.31,25.39) v2(41.83,24.75) v2(41.92,25.37) v2(42.43,24.71) v2(57.66,50.72) v2(57.67,50.11) v2(57.68,49.5) v2(57.7,48.92) v2(72.26,51.43) v2(72.89,51.42) v2(73.48,51.41) v2(74.09,51.4) v2(81.27,77.13) v2(93.52,89.92) v2(94.16,89.92) v2(159.07,77.6) v2(159.06,76.63) v2(159.66,77.6) v2(159.66,76.63) v2(161.29,75.69) v2(161.85,75.86) v2(165.37,78.93) v2(210.15,79.29) v2(213.69,68.24) v2(213.69,67.6) v2(213.69,66.97) v2(213.69,66.33) v2(214.2,68.55) v2(214.2,67.92) v2(214.2,67.28) v2(214.2,66.65) v2(214.72,68.24) v2(214.72,67.6) v2(214.72,66.97) v2(214.72,66.33) v2(252.21,11.34) v2(252.72,11.66) v2(252.72,11.02) v2(254.3,24.79) v2(254.93,24.79) v2(258.24,60.49) v2(258.85,60.49) v2(259.51,60.49) v3(213.98,65.38)
+3.3V_RUN_AUDIO: length 48.8
  TOP w0.381: RA38.2 270.37,32.8 v2(270.88,32.3) 270.43,31.85 RA26.1
  TOP w0.508: RA4.1 v2(253.1,43.03) ; RA45.2 v2(268.17,38.75) ; RA29.1 268.9,27.65 v2(268.15,26.9) ; RA1.1 273.22,39.38 v2(273.22,38.73)
  IN1 w0.508: v2(263.13,30.84) 267.39,30.84 268.85,32.3 v2(270.88,32.3) 272.5,33.92 272.5,37.97 273.22,38.68 v2(273.22,38.73)
  IN2 w0.508: v2(273.22,38.73) 273.1,38.85 268.28,38.85 v2(268.17,38.75)
  IN3 w0.508: v2(253.1,43.03) 252.52,43.03 251.38,41.88 251.38,34.72 251.71,34.38 251.71,30.57 252.92,29.36 v2(254.61,29.36) ; 263.32,29.88 266.31,26.9 v2(268.15,26.9)
  vias: v2(254.95,28.76) v2(258.75,30.84) v3(254,29.49)
+3.3V_RUN_CARD: length 16.9
  TOP w0.102: v2(250.69,20.1) 250.98,20.1 v3(251.57,20.7)
  IN3 w1.016: 261.48,11.47 254.5,11.47 250.69,15.28 250.69,18.64
  vias: v2(250.69,19.52) v2(261.67,12.72) v2(262.28,12.72)
+3.3V_RUN_UZ9: length 3.5
  TOP w0.102: 210.1,69.27 v1(213.64,69.27)
+3.3V_RUN_VDDA: length 7.3
  TOP w0.203: UV8.K7 v2(196.34,83.81) ; UV8.H5 v2(197.64,82.51) ; UV8.J4 v2(198.29,83.16) ; UV8.C10 v2(193.74,78.61) ; UV8.H12 v2(192.44,82.51) ; UV8.K6 v2(196.99,83.81)
  BOTTOM w0.102: CV101.1 198.22,86.33 v1(198.59,86.7)
  BOTTOM w0.457: CV98.1 191.71,83.02 192.05,82.67 192.11,82.67 192.27,82.51 v2(192.44,82.51)
  BOTTOM w0.508: LV25.1 194.04,77.44 193.74,77.75 v2(193.74,78.61)
+3.3V_RUN_VDDIO: length 10.2
  TOP w0.203: UV8.B6 v2(196.99,77.96) 197.31,78.29 UV8.B5 ; v2(198.29,78.61) UV8.C4 ; UV8.K12 v2(192.44,83.81) ; UV8.K11 v2(193.09,83.81) ; UV8.C12 v2(192.44,78.61) ; UV8.K3 198.61,83.49 v2(198.29,83.81) UV8.K4 ; UV8.C11 v2(193.09,78.61) ; v2(198.94,78.61) UV8.C3
  BOTTOM w0.102: 191.95,84.78 190.52,84.78 v1(190.42,84.68)
  BOTTOM w0.508: CV95.1 193.09,78.03 v2(193.09,78.61) ; CV94.1 200.38,78.21 199.81,78.78 CV97.1 199.29,78.97 v2(198.94,78.61)
+3.3V_RUN_VMM: length 45.2
  TOP w0.508: RV91.1 v2(187.26,76.76) ; v2(185.7,79.27) 185.78,79.35 RV518.1 RV519.1 ; RV82.2 186.22,81.75 v2(186.17,81.7) ; v2(191.44,73.41) 191.36,73.49 RV85.2 ; RV88.1 198.38,88.95 v2(198.38,89.71) 198.38,89.81 197.47,90.72 197.47,92.75 196.63,93.59 188.6,93.59 v2(188.37,93.36)
  IN4 w0.508: v2(200.84,85.25) 200.12,84.53 198.63,84.53 197.35,85.81 197.22,85.81 196.61,86.42 191.22,86.42 v2(191.07,86.27)
  IN4 w1.016: 185.98,84.49 189.85,84.49 190.68,85.32
  BOTTOM w0.381: CV124.1 187.71,93.01 188.18,92.54 UV11.14 ; UV12.14 181.17,82.12 180.96,82.33 180.96,82.98 CV121.1
  BOTTOM w0.508: v2(188.37,93.36) 188.34,93.38 CV124.1 ; v2(200.84,85.25) 200.84,85.97 199.19,87.62 199.19,89.38 198.86,89.71 v2(198.38,89.71) ; CV121.1 v2(181.46,84.23)
  vias: v2(184.75,84.52) v2(185.17,84.09) v2(190.42,86.21) v2(196.86,71.78) v2(197.47,71.76) v2(206.5,76.72) v2(207.09,76.72) v3(200.03,72.76)
+3.3V_SPI: length 26.1
  TOP w0.102: v2(174.68,76.89) v3(174.68,77.89)
  TOP w0.508: v2(166.99,76.05) 166.61,75.67 RC31.1
  IN2 w0.508: v2(171.31,73.44) 169.49,73.44 166.99,75.94 v2(166.99,76.05)
  IN3 w0.508: v2(174.68,76.89) 174.12,76.89 171.31,74.08 v2(171.31,73.44)
  BOTTOM w0.508: CC7.1 RC231.2 174.6,76.81 v2(174.68,76.89) 175.04,76.52 JSPI1.15 ; v2(166.99,76.05) 167.12,76.17 CC6.1 167.63,78.45 167.93,78.14 168.33,78.14 168.64,78.46 UC2.8 ; RC29.1 v2(171.31,73.44) 171.31,70.49 172.45,69.35 UC3.8
+3.3V_SUS: length 388.1
  TOP w0.203: v2(104.9,104.86) 104.9,104.61 104.78,104.48 UI4.16 ; UI4.20 102.06,105.7 102.62,106.26 v2(102.62,106.43) ; UI4.12 v2(105.11,102.88) ; v2(97.19,104.57) 97.68,104.08 UI4.29 ; v2(102.67,100.44) 102.46,100.65 UI4.9 ; v2(100.06,101.29) UI4.3
  TOP w0.254: CI38.1 UI5.10
  TOP w0.508: CI419.1 104.53,107.72 v2(104.61,107.8) ; v2(98.6,107.17) CI417.1 ; v2(96.48,100.57) CI420.1 ; CI414.1 CI416.1 CI415.1 v2(105.18,101.7) ; CI38.1 164.15,103.62 v2(164.35,103.42) ; CI418.1 v2(96.28,102.2)
  IN2 w1.016: 249.03,17.61 249.03,25.82 248.12,26.74 248.12,46.24 249.82,47.94 250.98,47.94 256.59,53.55 256.59,60.24 257.16,60.81
  IN3 w0.508: 164.53,100.35 164.53,103.24 v2(164.35,103.42)
  IN3 w1.016: 257.42,62.78 255.74,64.45 255.74,70.12 259.36,73.74 259.36,78.65 259.63,78.92 259.63,80.67 259.37,80.93 259.37,81.91 257.51,83.76 247.41,83.76 246.58,84.59 246.58,85.42 245.96,86.05 244.32,86.05 242.69,87.68 242.69,90.79 241.69,91.78 241.69,93.87 242.05,94.22 242.05,95 241.48,95.57 239.35,95.57 238.8,96.12 232.2,96.12 229.82,98.5 219.15,98.5 218.32,99.34 204.19,99.34 203.25,98.4 203.25,96.94 201.9,95.58 199.52,95.58 198.87,96.24 196.79,96.24 196.29,95.74 191.9,95.74 191.19,95.03 184.53,95.03 183.42,96.15 182,96.15 180.82,94.97 178.08,94.97 177.23,94.12 171.31,94.12 167.23,98.2 167.23,99.31 166.19,100.35 162.81,100.35 161.55,99.1 154.79,99.1 154.01,99.87 151.68,99.87 149.83,101.73 148.24,101.73 143.5,106.46 114.67,106.46 111.16,109.97 106.01,109.97 104.61,108.57 v2(104.61,107.8) ; 54.85,75.86 53.44,75.86 50.47,72.88 50.47,58.01 53.26,55.22 53.26,49.69 49.14,45.57 43.29,45.57 40.12,42.39 40.12,36.74 ; v2(102.67,100.44) 101.96,99.73 101.96,96.19 100.64,94.87 98.95,94.87 97.33,93.26 92.82,93.26 90.86,91.29 89.4,91.29 88.76,90.65 83.68,90.65 81.97,88.94 76.38,88.94
  IN4 w1.016: 57.07,76.49 58.73,76.49 59.8,77.57 64.5,77.57 68.31,81.38 68.31,86.4 65.74,88.97 65.74,91.38 66.6,92.24 69.11,92.24 70.32,91.03 75.3,91.03
  vias: v2(39.74,35.53) v2(40.18,35.15) v2(55.49,76.62) v2(56.12,76.62) v2(75.7,89.85) v2(76.3,89.86) v2(248.37,17.06) v2(248.39,16.41) v2(248.4,15.8) v2(257.29,61.82) v2(257.87,61.82) v3(40.82,33.69)
+3.3V_SUS_UZ8: length 1.7
  TOP w0.102: CZ40.1 46.17,27.86 v1(47.3,28.99)
+3.3V_TP: length 12
  TOP w0.102: v1(222,16.88) 221.83,17.04 v2(220.14,17.04)
  TOP w0.508: RZ18.1 v2(220.14,17.04) ; RZ19.1 216.83,16.87 217.32,16.37 v2(217.48,16.37)
  IN4 w0.508: v2(212.75,14.48) 213,14.48 213.79,15.26 216.37,15.26 v2(217.48,16.37) 218.15,17.04 v2(220.14,17.04)
+3.3V_TSP: length 2.3
  TOP w0.102: CZ2.1 69.47,79.91 v3(68.31,81.06)
  vias: v2(69.72,78.73) v2(70.28,78.9)
+3.3V_VMM_UV10: length 1.1
  BOTTOM w0.102: 206.31,79.01 v1(205.55,78.24)
+3.3V_WLAN: length 3.6
  TOP w0.432: RZ15.2 211.87,18.9 QZ2.5 ; QZ2.2 v2(213.79,18.9)
  TOP w0.508: RZ15.2 211.37,19.14 v2(210.93,18.71) 211.37,18.27 RZ14.2
  vias: v1(215.25,29.31) v2(204.03,49.38) v2(204.62,49.38) v2(205.22,49.38) v2(205.35,10.54) v2(205.35,9.96) v2(205.36,9.37) v2(205.85,49.38) v2(205.85,48.78) v2(205.91,10.32) v2(205.91,9.69) v2(214.17,28.68) v2(214.62,29.12) v2(214.74,28.55) v2(216.59,11.09) v2(216.59,10.49)
+3.3V_WLAN_UZ2:
  vias: v1(213.32,48.35)
+3.3V_WWAN: length 210
  TOP w0.508: RZ45.1 RZ45.2 55.65,71.89 v3(55.65,71.55) 55.65,68.78 58.94,65.49 58.94,63.64 58.06,62.76 57.24,62.76 56.97,62.5 v2(56.97,62.12)
  IN3 w0.508: v2(56.97,62.12) 56.97,61.1 58.7,59.38 58.7,58.85 59.25,58.3 59.25,53.21 57.04,51.01 57.04,44.09 57.71,43.42 65.28,43.42 69.35,39.34 183.46,39.34 186.62,42.49 193.05,42.49 193.42,42.13 201.1,42.13 201.92,41.32 212.01,41.32
  IN3 w1.524: 223.25,59.28 220.4,59.28 217.09,55.98 217.09,49.63 215.51,48.04
  vias: v2(213.09,41.31) v2(213.22,41.88) v2(213.79,42.07) v2(224.15,39.22) v2(224.33,58.76) v2(224.73,39.22) v2(224.82,59.14) v2(224.85,58.48) v2(225.32,39.22) v2(225.9,39.22)
+3V5V_PWR_SRC:
  vias: v1(211.06,55.73) v2(204.01,55.79) v2(204.01,55.16) v2(208.71,56.55) v2(208.71,55.92) v2(208.71,55.22) v2(208.71,54.58) v2(209.75,58.03) v2(210.39,58.03) v2(211.09,58.03) v2(211.71,58.05)
+5V_ALW: length 536.4
  TOP w0.203: UL3.4 200.4,36.93 ; UZ7.4 184.75,54.14 184.84,54.23 ; UZ8.4 v2(41.78,26.4)
  TOP w0.254: v2(81.53,89.92) 81.53,90.02 81.13,90.42 UI3.8 ; UI3.7 80.63,90.22 v2(80.94,89.92)
  TOP w0.381: v2(72.58,86.13) PU1.5 ; LED7.4 LED7.2 219,100.94 218.68,100.62 v2(218.43,100.62)
  TOP w0.508: v2(33.26,24.42) 33.83,24.42 34.09,24.16 PR843.2 ; RD9.1 121.01,32.18 v2(120.13,33.06) ; RZ5.1 138.29,95.87 137.54,96.62 133.03,96.62 v2(131.44,98.21) ; QZ9.3 264.44,84.68 v2(264.7,84.94) 266.28,86.51 RZ32.2 ; v2(57.2,74.14) 57.2,76.36 58.56,77.72 JLED1.6 ; PR204.2 191.43,4.21 191.61,4.04 v2(191.61,3.09) 191.61,2.13 191.25,1.78 188.87,1.78 PR202.1 ; v2(210.49,80.94) 210.42,80.94 208.84,82.52 208.84,83.79 207.96,84.67 207.96,88.37 208.65,89.05 v2(208.76,89.05) ; v2(72.58,86.13) 72.68,86.13 73.51,86.96 PR11.1 ; v2(194.77,44.63) 194.77,41.09 196.39,39.47 197.53,39.47 198.04,38.96 198.04,37.2 198.44,36.8 200.28,36.8 200.4,36.93 ; v2(89.36,92.52) 89.36,88.66 91.05,86.97 91.05,80.17 91.62,79.6 PR526.2 ; v2(261.99,61.12) v3(260.12,61.12) 256.46,61.12 255.63,60.29 255.63,59.41 RZ21.1 ; v2(78.21,90.66) 78.05,90.51 RI13.2 ; 184.84,54.23 v2(186.04,54.23)
  IN1 w0.508: v2(78.21,90.66) 75.64,90.66 72.58,87.61 v2(72.58,86.13) 71.95,86.13 69.96,84.15 69.96,82.59 67.39,80.01 66.55,80.01 62.37,75.83 58.51,75.83 57.2,74.52 v2(57.2,74.14) 54.25,71.2 54.22,71.2 52.38,69.35 52.38,56.93 53.92,55.38 53.92,49.46 48.81,44.35 48.81,37.88 46.72,35.79 46.72,29.37 45.33,27.98 43.36,27.98 v2(41.78,26.4) ; v2(218.43,100.62) 218.43,100.11 217.54,99.22 207.85,99.22 207.07,100 v2(207.07,100.35)
  IN2 w0.508: v2(191.61,3.09) 190.45,3.09 189.5,4.04 182.87,4.04 182.55,4.36 182.55,11.02 181.14,12.43 181.14,16.73 180.85,17.02 177.7,17.02 175.73,18.99 175.73,20.04 174.49,20.04 173.41,18.95 147.32,18.95 146.23,20.04 146.23,21.95 144.95,23.23 135.24,23.23 133.88,24.59 131.92,24.59 125.1,31.41 121.78,31.41 v2(120.13,33.06) ; v2(131.44,98.21) 131.15,97.91 125.98,97.91 124.83,99.06 124.83,99.73 124.13,100.43 121.59,100.43 118.35,97.19 110.56,97.19 108.54,95.16 102.01,95.16 101.07,94.22 95.79,94.22 v2(95.24,94.78) ; v2(198.55,69.32) 194.92,69.32 193.62,70.62 188.26,70.62 186.07,68.43 186.07,59.44 185.06,58.43 184.43,58.43 183.95,57.95 183.95,55.74 185.45,54.23 v2(186.04,54.23) 186.78,54.97 187.16,54.97 187.92,54.2 193.03,54.2 194.49,52.74 194.49,50.27 195.36,49.39 195.36,47.65 194.77,47.06 v2(194.77,44.63) 194.77,44 195.41,43.36 202.57,43.36 202.93,43.73 204.6,43.73 206.9,46.02 v2(208.2,46.02) ; v2(264.7,84.94) 263.34,83.58 260.93,83.58 260.13,84.38 260.13,85.65 258.22,87.57 246.09,87.57 v2(245.85,87.32)
  IN3 w0.508: v2(120.13,33.06) 55.11,33.06 53.26,31.22 48.31,31.22 45.26,28.17 43.55,28.17 v2(41.78,26.4) ; v2(264.7,84.94) 264.7,82.06 263.66,81.03 263.66,74.17 262.31,72.81 262.31,61.44 v2(261.99,61.12)
  BOTTOM w0.203: v2(208.2,46.02) 208.23,46.04 208.93,46.04 208.97,46.08 UZ2.4 ; UV13.4 v2(210.49,80.94)
  BOTTOM w0.457: QZ12.3 209.11,88.43 208.76,88.77 v2(208.76,89.05)
  BOTTOM w0.508: PU400.6 95.2,95.66 PC400.1 ; v2(207.07,100.35) 207.07,99.63 206.51,99.07 206.51,94.92 207.61,93.83 207.61,93.66 ; v2(33.26,24.42) 35.04,24.42 35.99,23.47 42.15,23.47 43.05,24.37 43.05,25.81 42.46,26.4 v2(41.78,26.4)
  vias: v2(78.23,94.5) v2(78.24,93.87) v2(78.83,94.45) v2(78.92,95.08) v2(78.85,93.85) v2(94.54,94.78) v2(95.56,99.21) v2(95.87,99.72) v2(96.19,99.21) v2(96.51,99.72) v2(96.83,99.21) v2(97.14,99.72) v2(149.14,110.93) v2(149.45,110.43) v2(149.77,110.93) v2(150.09,110.43) v2(150.42,110.93) v2(156.9,107.16) v2(157.21,106.65) v2(157.53,107.16) v2(157.91,106.65) v2(158.23,107.16) v2(159.86,109.93) v2(199.06,68.74) v2(199.19,69.32) v2(199.7,69.89) v2(199.7,68.74) v2(199.82,69.32) v2(200.33,69.89) v2(200.33,68.74) v2(200.46,69.32) v2(200.97,69.89) v2(200.97,68.74) v2(201.09,69.32) v2(206.17,90.4) v2(206.81,90.4) v2(207.44,90.4) v2(208.05,90.53) v2(243.37,82.65) v2(243.95,82.65) v2(244.54,82.65) v2(245.12,82.65) v3(198.67,70.8) v3(202.87,71.35)
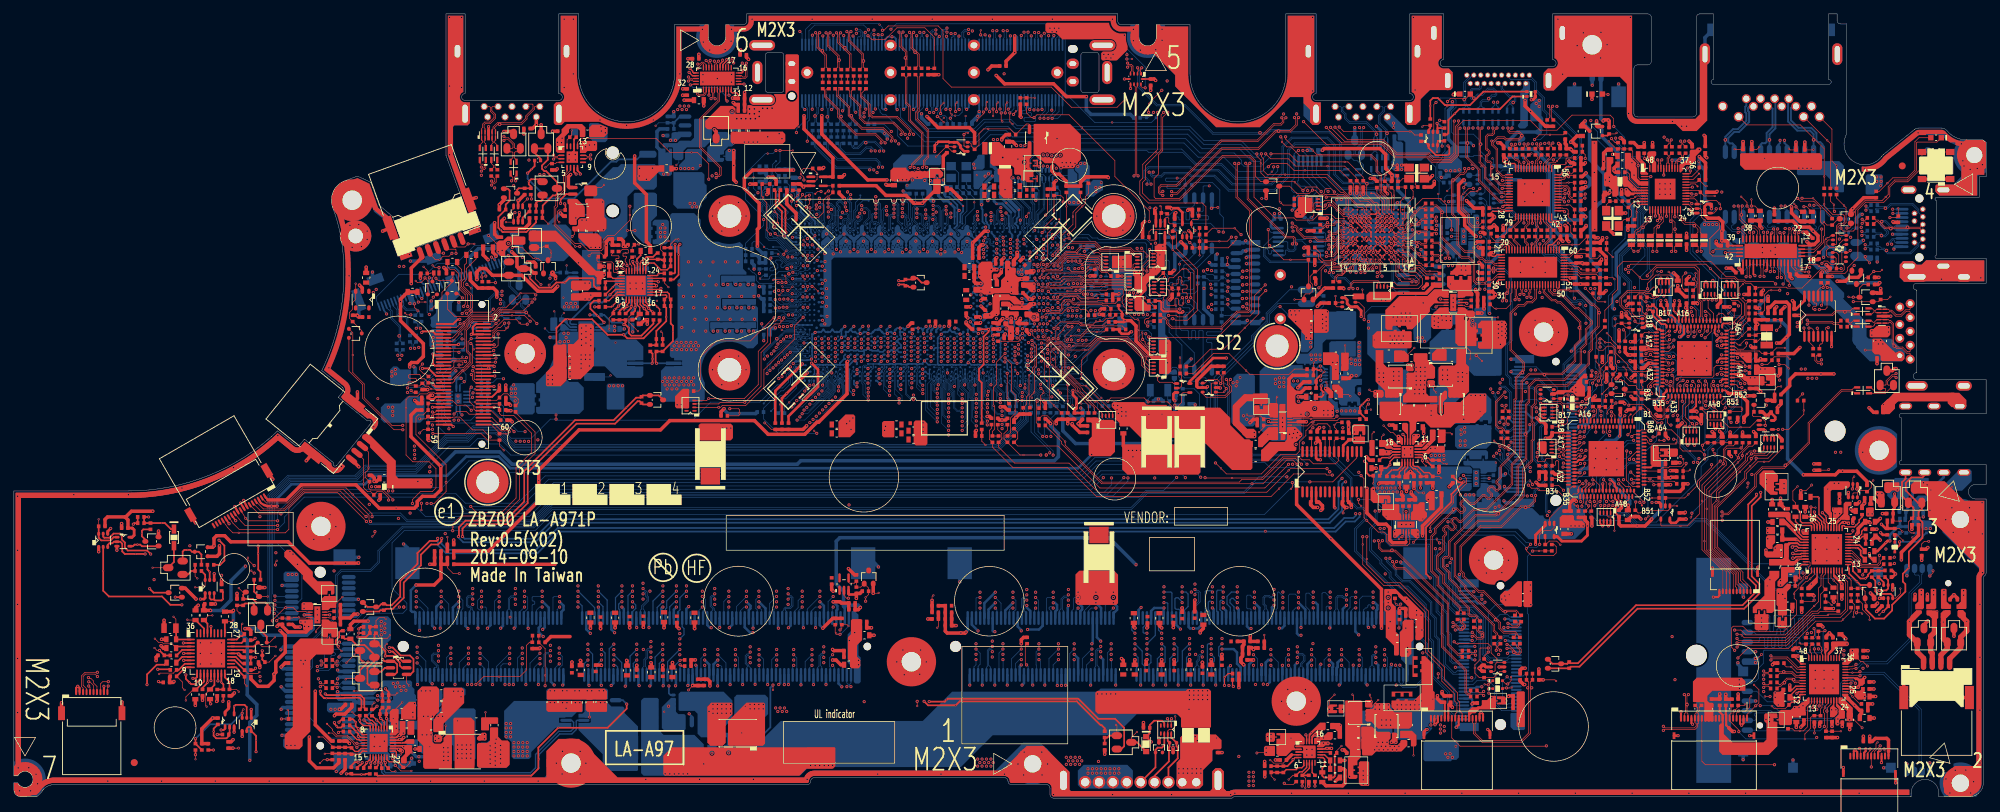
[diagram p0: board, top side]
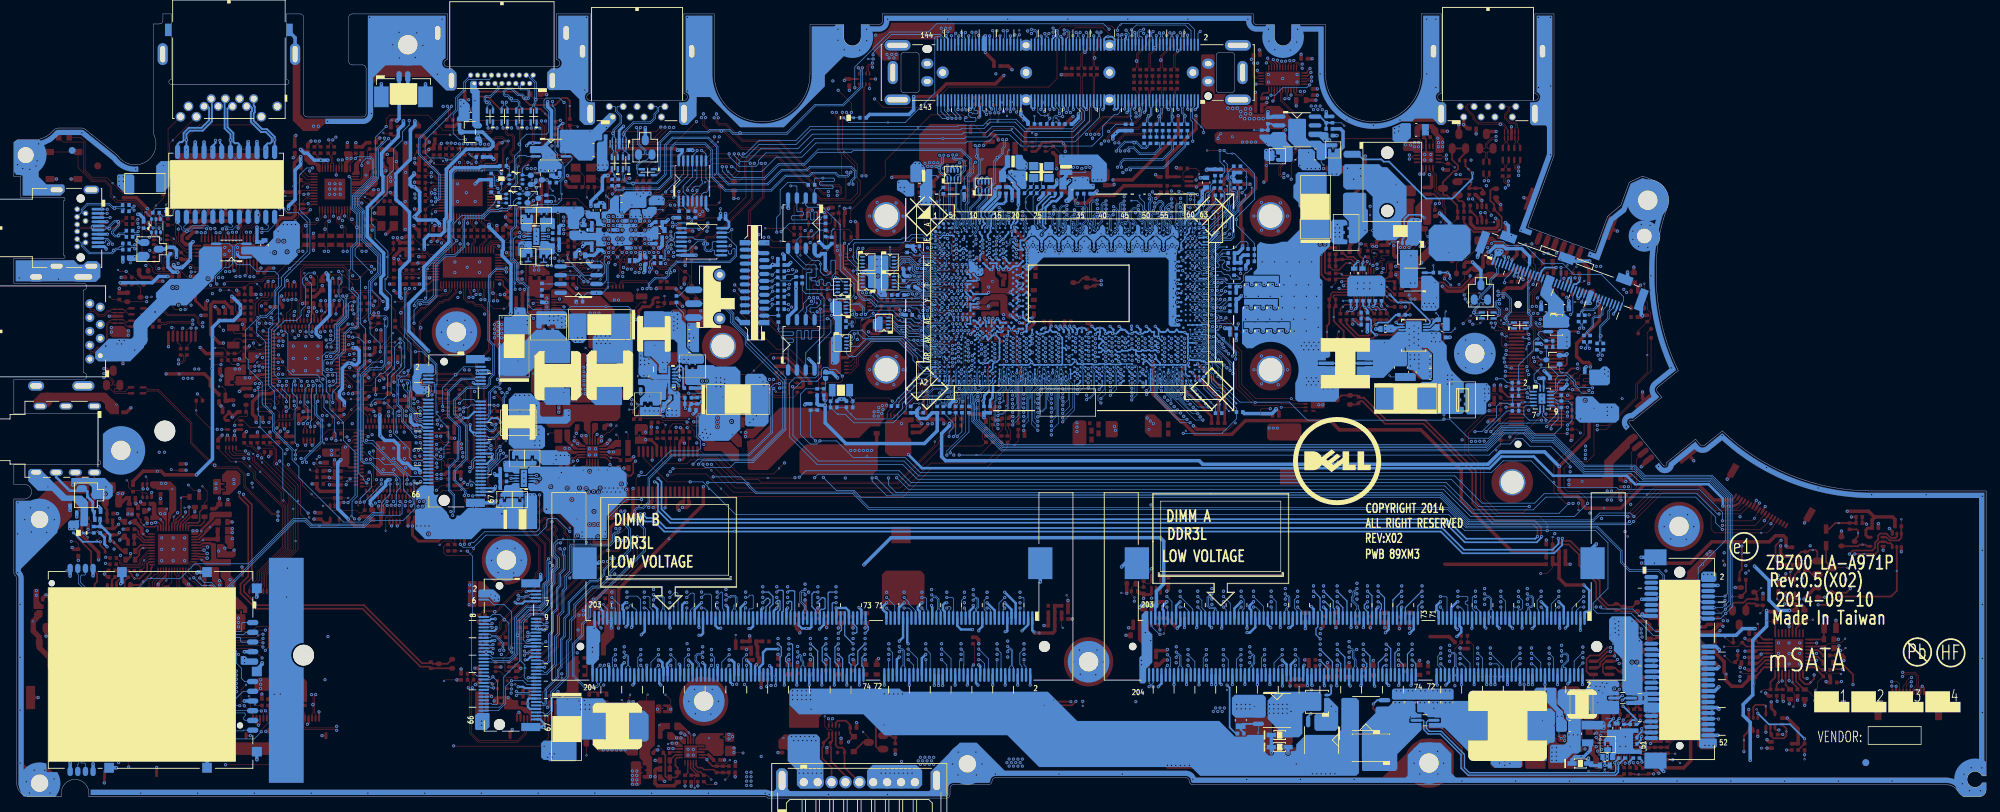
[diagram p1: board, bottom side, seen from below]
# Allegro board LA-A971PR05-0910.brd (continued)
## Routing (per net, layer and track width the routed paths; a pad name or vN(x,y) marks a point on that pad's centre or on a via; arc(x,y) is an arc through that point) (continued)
+5V_ALW_U41: length 3.9
  TOP w0.102: v1(254.38,59.32) 253.91,59.32 253.45,58.86 RZ21.2
  TOP w0.508: UZ5.1 252.97,57.32 253.1,57.2 CZ35.1 RZ21.2
+5V_ALWP: length 48.6
  TOP w0.203: v2(199.95,52.41) 200.22,52.14 PU100.14
  TOP w0.254: v2(199.5,44.68) 199.5,45.36 PR101.2
  IN2 w0.254: v2(195,68.68) 194.46,68.15 194.46,53.66 195.06,53.06 195.06,50.52 196.77,48.81 196.77,47.41 v2(199.5,44.68)
  IN3 w0.508: v2(195,67.73) 194.74,67.73 194.36,67.35 194.36,54.01 195.38,53 199.36,53 v2(199.95,52.41)
  vias: v1(195.82,66.01) v2(198.11,66.59) v2(198.11,65.51) v2(198.43,66.01) v2(198.74,66.59) v2(198.74,65.51) v2(199.06,66.01) v2(199.38,66.59) v2(199.38,65.51) v2(199.7,66.01) v2(200.01,66.59) v2(200.01,65.51)
+5V_RUN: length 522.7
  TOP w0.254: RPE2.2 241.21,51.1 v2(240.96,50.85) 240.71,51.09 RPE2.1 ; RPE2.4 242.21,51.15 v2(241.91,50.85) 241.71,51.04 RPE2.3
  TOP w0.305: CZ29.1 205.98,13.76 JKBTP1.5 ; 246.87,10.11 246.48,10.5 JUSH1.14 246.48,12.02 246.43,12.06 CZ10.1
  TOP w0.508: QV501.2 265.88,75.43 265.48,75.03 264.21,75.03 263.66,74.48 v2(262.46,74.48) ; v2(247.65,9.6) 247.39,9.6 246.88,10.11 246.87,10.11 ; CZ29.1 205.42,13.82 204.91,14.33 v2(204.91,14.76)
  IN1 w0.508: v2(252.26,56.62) 253.02,57.38 253.92,57.38 255,58.46 255,61.63 255.8,62.43 258.58,62.43 259.13,61.89 261.73,61.89 262.44,62.59 262.44,74.47 v2(262.46,74.48)
  IN2 w0.508: v2(204.91,14.76) 204.48,14.76 201.29,17.95 178.42,17.95 177.66,18.71 177.66,21.54 173.97,25.23 137.46,25.23 135.75,26.94 131.53,26.94 129.33,29.14 129.33,33.14 v2(120.22,42.25) ; v2(241.91,50.85) 242.66,51.6 244.03,51.6 244.4,51.97 249.09,51.97 249.8,52.68 249.8,54.15 v2(252.26,56.62) ; v2(251.57,24.68) 251.57,23.92 254.05,21.45 254.05,16.17 254.75,15.47 254.75,13.31 254.13,12.69 250.01,12.69 247.73,10.4 247.73,9.85 247.65,9.78 v2(247.65,9.6)
  IN2 w1.016: 209.04,74.61 207.56,73.13 205.16,73.13 203.12,71.09 198.75,71.09 198.55,70.9 194.96,70.9 194.07,71.79 188.96,71.79 188.52,72.24 180.26,72.24 178.87,70.84 178.87,67.67 178.36,67.16 178.36,63.66 180.39,61.63 184.07,61.63
  IN3 w0.508: v2(208.97,76.68) 209.4,76.68 212.93,80.21 214.62,80.21 215.67,79.16 224.76,79.16 v2(224.83,79.1) ; v2(241.91,50.85) 242.61,50.14 243.57,50.14 245.01,48.7 245.01,47.39 244.17,46.54 244.17,43.96 249.67,38.46 249.67,27.85 v2(251.57,25.95)
  IN3 w1.016: 85.59,67.6 84.32,66.33 84.32,54.08 96.15,42.25 v2(120.22,42.25) 176.12,42.25 181.09,47.22 186.74,47.22 187.19,47.66 187.19,49.44 186.49,50.14 186.49,52.55 184.9,54.14 184.9,55.85 185.79,56.74 185.79,59.66
  IN4 w0.508: v2(262.46,74.48) 263.69,75.72 263.69,76.69 261.67,78.71 258.31,78.71 257.31,77.72 251.7,77.72 249.99,79.44 246.2,79.44 246.01,79.63 244.71,79.63 243.59,80.75 240.55,80.75 240.2,81.1 233.39,81.1 231.77,79.49 225.22,79.49 v2(224.83,79.1) ; v2(241.91,50.85) v2(240.96,50.85)
  IN4 w1.016: 60.95,45.5 62.41,45.5 66.15,49.25 74.33,49.25 85.52,60.44 85.52,65.32 86.47,66.27
  BOTTOM w0.508: CV24.1 219.76,96.26 UV10.1 216.45,95.97 214.94,94.46 214.94,93.97 215.42,93.48 218.78,93.48 221.65,90.61 221.65,83.57 221.91,83.32 221.91,81.67 222.47,81.11 224.18,81.11 224.83,80.47 v2(224.83,79.1)
  vias: v2(60.06,45.82) v2(60.06,45.19) v2(86.47,67.98) v2(86.47,67.35) v2(184.2,60.11) v2(184.8,60.11) v2(208.36,76.68) v2(208.36,76.1) v2(208.99,76.07) v2(251.57,25.31) v3(58.15,45.63)
+5V_RUN_AUDIO: length 23.2
  TOP w0.508: LA5.2 265.38,42.39 v2(265.67,42.68)
  IN3 w0.508: v2(265.67,42.68) 265.67,42.14 266.09,41.72 266.09,35.25 263.89,33.06 254.37,33.06 v2(252.78,31.47)
  vias: v1(252.4,30.58)
+5V_RUN_PVDD:
  vias: v1(256.88,34.33)
+5V_USB_CHG_PWR: length 2.2
  TOP w0.508: CI3.1 74.66,96.48 v2(75.22,97.04) 75.2,97.06 JUSB1.1
  vias: v2(81.69,94.45) v2(81.71,93.85) v2(82.3,94.44) v2(82.3,93.85) v2(82.84,94.11) v3(83.59,94.14)
+GND_CHASSIS:
  vias: v1(252.02,92.18) v2(256.93,90.77) v2(257.52,90.75) v2(258.13,90.74) v2(258.71,90.74)
+V1.05S_APLLOPI: length 3.8
  TOP w0.508: CC68.1 139.47,71.97 v2(139.18,71.69)
  BOTTOM w0.102: v1(150.86,89.45) 151.12,89.7 LC3.2
  BOTTOM w0.254: v2(139.19,72.51) 139.56,72.14 UC1.W21 139.56,72.06 v2(139.18,71.69) 139.56,71.32 UC1.AA21
  vias: v2(151.96,85.83) v2(152.59,85.83) v2(153.21,85.83)
+V1.05SP_B+: length 1.9
  BOTTOM w0.102: 193.75,56.82 194.59,55.98 v1(195.34,55.98)
+VCC_CORE: length 65.6
  TOP w0.508: RC209.1 111.27,85.61 112.59,84.28 112.59,83.29
  BOTTOM w0.127: UC1.F40 127.45,79.91 ; UC1.F40 126.94,79.91 ; UC1.F40 126.94,79.4 ; UC1.F40 127.45,79.4 ; 124.91,79.1 125.15,79.1 UC1.G43 ; UC1.G25 136.86,79 136.86,79 ; UC1.G25 136.42,79.22 v2(136.42,78.61) ; UC1.G25 136.71,79.5 136.86,79.5 ; UC1.G25 136.44,79.41 136.44,79.74 ; 127.83,79.74 127.88,79.68 UC1.G39 ; 122.51,79 122.84,79.33 UC1.G47 ; 116.48,78.93 116.47,78.94 116.47,79.32 ; UC1.J23 UC1.H23 ; UC1.J23 137.76,77.79 ; UC1.J23 UC1.K23 ; UC1.H23 137.69,78.6 ; UC1.H23 138.13,79.02 138.17,79.07 UC1.G23 ; 131.89,79.04 131.8,79.04 UC1.G33 ; UC1.G49 121.37,79.21 121.37,78.83 v2(121.49,78.72) ; UC1.G49 121.71,79.1 121.99,79.1 ; UC1.G49 121.8,79.64 121.8,79.67 ; UC1.G49 121.37,79.44 121.37,79.82 ; UC1.G27 135.07,79.66 135.07,79.67 ; UC1.G27 135.47,79.26 v2(135.47,78.68) ; UC1.G27 135.53,79.45 135.53,79.77 ; UC1.G27 135.18,79.1 135.07,79.1 ; UC1.G55 117.83,79.33 117.56,79.06 ; UC1.G55 118,79.17 118,78.87 ; UC1.G55 117.85,79.34 117.56,79.63 ; UC1.G55 117.94,79.42 117.94,79.76 ; UC1.G39 127.48,79.33 127.45,79.29 ; UC1.G39 127.88,79.22 127.64,78.98 ; 131.47,79.76 131.47,79.38 UC1.G33 ; UC1.G43 125.1,79.6 ; UC1.G43 125.48,79.43 125.48,79.8 ; UC1.G43 125.5,79.2 125.5,78.84 v2(125.37,78.72) ; 132.63,79.59 132.9,79.33 UC1.G31 ; UC1.G51 120.48,79.45 120.48,79.76 ; UC1.G51 120.48,79.21 120.48,78.84 v2(120.36,78.72) ; UC1.G51 120.35,79.33 120.11,79.57 ; UC1.G51 120.36,79.32 120.1,79.06 ; UC1.G57 116.49,79.33 116.73,79.57 ; UC1.G57 116.29,79.51 116.29,79.69 ; UC1.G57 116.47,79.32 ; UC1.G41 126.39,79.44 126.39,79.72 126.46,79.8 ; UC1.G41 126.5,79.33 126.39,79.21 126.39,78.83 v2(126.5,78.72) ; UC1.G41 126.81,79.64 ; UC1.G41 126.66,79.17 126.94,79.17 ; UC1.M23 138.13,76.58 UC1.K23 ; UC1.M23 UC1.L22 UC1.K23 ; UC1.M23 137.71,76.17 ; 122.58,79.63 122.87,79.34 UC1.G47 ; 138.12,79.67 138.12,79.53 UC1.G23 ; 132.46,79.4 UC1.F32 ; UC1.F32 131.95,79.4 ; UC1.F32 131.95,79.91 ; UC1.F32 132.46,79.91 ; 123.87,79.8 123.87,79.45 UC1.G45 ; UC1.F28 134.46,79.91 ; UC1.F28 134.97,79.91 ; UC1.F28 134.46,79.4 ; UC1.F28 134.97,79.4 ; UC1.G23 137.69,79.1 137.54,79.1 ; UC1.G23 137.61,79.63 ; 134.31,79.67 134.31,79.61 UC1.G29 ; UC1.G47 122.99,79.45 122.99,79.77 ; UC1.G47 122.96,79.24 122.96,78.81 v2(122.87,78.72) ; UC1.F56 117.42,79.4 ; UC1.F56 117.42,79.91 ; UC1.F56 116.91,79.4 ; UC1.F56 116.91,79.91 ; UC1.F52 119.41,79.4 ; UC1.F52 119.92,79.4 ; UC1.F52 119.92,79.91 ; UC1.F52 119.41,79.91 ; UC1.F44 124.43,79.91 ; UC1.F44 124.94,79.4 ; UC1.F44 124.43,79.4 ; UC1.F44 124.94,79.91 ; v2(130.39,78.72) 130.56,78.89 130.56,79.16 UC1.G35 ; UC1.F24 136.97,79.91 ; UC1.F24 137.48,79.91 ; UC1.F24 137.48,79.4 ; UC1.F24 136.97,79.4 ; UC1.G31 132.88,79.33 132.56,79.01 ; UC1.G31 v2(132.9,78.72) ; UC1.G31 132.99,79.42 132.99,79.77 ; UC1.G33 131.52,79.33 131.47,79.28 131.47,78.77 v2(131.52,78.72) ; UC1.G33 131.75,79.56 ; UC1.G37 129.01,79.33 129.31,79.63 ; UC1.G37 v2(129.01,78.72) ; UC1.G37 128.93,79.41 128.93,79.76 ; UC1.G37 129.04,79.33 129.31,79.06 ; 133.9,79.8 133.9,79.45 UC1.G29 ; UC1.G45 123.9,79.23 123.9,78.81 v2(123.99,78.72) ; UC1.G45 124.22,79.1 124.46,79.1 ; UC1.G45 124.27,79.61 ; UC1.F36 129.44,79.91 ; UC1.F36 129.95,79.4 ; UC1.F36 129.95,79.91 ; UC1.F36 129.44,79.4 ; UC1.G35 130.05,79.67 130.05,79.67 ; UC1.G35 130.56,79.5 130.56,79.74 ; UC1.G35 130.1,79.04 129.92,79.04 ; 118.89,79.76 118.89,79.41 UC1.G53 ; UC1.K23 137.71,76.98 ; 119.27,79.06 119.01,79.33 UC1.G53 ; UC1.G29 134.25,79.1 134.43,79.1 ; UC1.G29 133.9,79.21 133.9,78.84 v2(134.02,78.72) ; UC1.F48 122.43,79.91 ; UC1.F48 121.92,79.91 ; UC1.F48 121.92,79.4 ; UC1.F48 122.43,79.4 ; 116.73,79.06 116.47,79.32 ; UC1.G53 119.27,79.62 119.27,79.63 ; UC1.G53 v2(118.98,78.72)
  BOTTOM w0.229: UC1.F59 115.22,79.42 v2(114.92,79.72)
  BOTTOM w0.254: v2(116.8,74.61) 116.71,74.7 UC1.P57 ; v2(116.99,72.14) 116.95,72.1 UC1.W57 ; UC1.M57 116.72,76 v2(116.73,76.01) ; v2(116.73,68.33) 116.6,68.2 UC1.AG57 ; v2(116.76,77.32) 116.75,77.3 UC1.K57 ; v2(116.99,70.87) 116.92,70.8 UC1.AB57 ; v2(116.99,73.41) 116.98,73.4 UC1.U57 ; v2(117.05,69.41) 116.96,69.5 UC1.AD57
  vias: v2(93.4,60.05) v2(93.71,60.55) v2(93.71,59.54) v2(94.03,60.05) v2(94.03,58.97) v2(94.35,60.55) v2(94.35,59.54) v2(94.73,64.62) v2(94.73,60.05) v2(94.73,58.97) v2(95.05,65.16) v2(95.05,60.55) v2(95.05,59.54) v2(95.43,65.67) v2(95.43,64.62) v2(95.43,60.05) v2(95.43,58.97) v2(95.75,65.16) v2(95.75,60.55) v2(95.75,59.54) v2(95.76,73.96) v2(96.14,70.66) v2(96.14,67.83) v2(96.06,65.67) v2(96.13,64.62) v2(96.13,60.05) v2(96.38,72.3) v2(96.44,65.16) v2(96.44,60.55) v2(96.44,59.54) v2(96.76,65.67) v2(96.83,64.62) v2(96.83,60.05) v2(97.09,77.26) v2(97.14,65.16) v2(97.14,60.55) v2(97.14,59.54) v2(97.54,73.96) v2(97.46,65.66) v2(97.52,64.62) v2(97.52,60.05) v2(97.84,72.3) v2(97.84,65.16) v2(97.84,60.55) v2(97.84,59.54) v2(97.86,70.66) v2(97.86,67.29) v2(98.03,69) v2(98.16,65.66) v2(98.22,64.62) v2(98.54,65.16) v2(98.87,77.26) v2(99.32,73.96) v2(99.62,72.3) v2(99.57,70.66) v2(99.6,67.29) v2(99.68,69) v2(100.65,77.26) v2(101.09,73.96) v2(101.29,70.66) v2(101.31,67.29) v2(101.4,72.3) v2(101.4,69) v2(102.43,77.26) v2(102.76,74) v2(103.05,72.3) v2(103,70.66) v2(103.02,67.29) v2(103.11,69) v2(104.21,77.26) v2(104.55,73.98) v2(104.71,70.66) v2(104.74,67.29) v2(104.76,72.3) v2(104.83,69) v2(106.38,73.98) v2(106.43,70.66) v2(106.54,72.3) v2(106.45,67.29) v2(106.6,69) v2(116.73,78.49) v2(117.94,78.42) v2(119.8,80.25) v2(122.31,80.25) v2(124.82,80.25) v2(127.33,80.25) v2(127.91,78.65) v2(129.83,80.25) v2(132.22,80.24) v2(133.43,78.4) v2(134.85,80.25) v2(137.21,80.23) v3(100.15,75.25)
+VCC_PWR_SRC: length 24.3
  TOP w0.254: PR511.1 92.95,68.57 90.64,66.26 88.29,66.26 v2(87.78,66.76) 85.47,66.76 83.24,69 v1(79.68,69) 79.36,69 78.09,67.73 78.09,64.62 78.28,64.43
  BOTTOM w0.254: v2(87.78,66.76) 87.95,66.76 88.52,67.33 88.52,68.85 88.77,69.1 PR518.1
  vias: v2(76.89,60.93) v2(76.89,60.3) v2(76.89,59.66) v2(77.52,60.93) v2(77.52,60.3) v2(77.52,59.66) v2(78.63,65.75) v2(79.17,66.98) v2(79.24,65.76) v2(79.49,66.36) v2(79.79,66.98) v2(79.82,65.81)
+VCCIO_OUT: length 6.9
  BOTTOM w0.305: UC1.A59 115.34,83.07 114.62,83.79 113.97,83.79 113.27,84.49 113.27,85.54
  BOTTOM w0.508: 113.27,85.54 113.27,85.83 112.83,86.28 v1(112.83,86.84) 112.83,87.44 RC196.1
+VCCIOA_OUT: length 4
  TOP w0.076: v2(139.51,79.71) 139.98,79.71 140.16,79.54 v1(140.16,79.3)
  TOP w0.508: v2(139.51,79.71) 139.29,79.71 138.93,79.35 RC133.1
  BOTTOM w0.254: UC1.E20 140.07,80.13 139.65,79.71 v2(139.51,79.71)
+VDDA_AVDD1:
  vias: v1(262.76,40.17)
+VDDA_PVDD:
  vias: v1(256.91,38.52)
GND: length 3986.5
  TOP w0.102: v2(180.26,6.58) 179.01,6.58 v3(178.93,6.5) ; v2(275.8,32.01) 276.26,32.47 v3(276.26,32.77) ; RC132.2 109.03,53.12 v3(108.09,54.06) ; v3(173.3,85.11) 172.52,85.11 v2(172.4,84.99) ; v2(31.53,7.2) v3(32.35,7.2)
  TOP w0.152: v2(195.69,78.61) 195.69,78.62 195.69,79.26 UV8.D7
  TOP w0.203: UV8.F8 UV8.G8 v2(195.04,81.86) ; UV8.F6 v2(196.99,80.56) 197.31,80.89 UV8.F5 ; v2(218.54,79.86) 218.45,79.77 UV600.11 ; UI4.11 103.26,101.76 103.41,101.61 104.05,101.61 104.27,101.39 CI415.2 ; UV8.G11 v2(193.09,81.86) ; UV8.G5 197.31,81.54 v2(196.99,81.86) UV8.G6 ; v2(197.64,78.61) UV8.C5 UV8.D6 ; UV8.J7 v2(196.34,83.16) ; UV8.D4 v2(198.29,79.26) ; UV8.H4 v2(198.29,82.51) ; UZ9.11 209.03,71.41 v2(209.16,71.28) ; v2(102.02,106.32) 102.02,106.15 101.66,105.78 UI4.21 ; UV600.19 215.25,79.51 214.98,79.78 214.32,79.78 v2(214.08,79.54) ; UV8.F4 v2(198.29,80.56) ; PU700.22 54.93,6.75 55.04,6.64 55.04,6.01 54.72,5.69 v2(54.53,5.69) v2(54.53,6.27) ; UV8.E11 193.41,80.24 v2(193.09,80.56) UV8.F11 ; UV8.J5 v2(197.64,83.16) ; v2(214.33,85.24) 214.52,85.43 UV7.26 ; UV8.D9 v2(194.39,79.26) ; UV8.J8 v2(195.04,83.16) ; UZ8.11 v2(45.45,26.4) ; PU500.19 92.99,73.29 v2(93.14,73.44) ; UV8.D5 v2(197.64,79.26) ; UI4.28 97.85,104.48 97.7,104.63 97.7,104.76 v2(97.32,105.14) ; UV8.D10 v2(193.74,79.26) 193.42,79.59 UV8.D11 ; v2(223.22,84.49) 223.08,84.63 UV7.43 ; UV8.F9 v2(194.39,80.56) 194.07,80.89 UV8.F10 ; UV8.D8 v2(195.04,79.26) ; UV8.F7 v2(196.34,80.56) ; UV8.K5 v2(197.64,83.81) ; UV600.52 223.91,75.09 v2(224.05,74.95) ; UL3.11 v2(200.4,41.3) ; UV7.38 v2(219.76,82.87) ; UV8.G4 v2(198.29,81.86) ; UV8.J12 v2(192.44,83.16) ; UV8.E4 v2(198.29,79.91) ; v2(193.09,83.16) UV8.J11 UV8.H10 ; UV8.L6 196.66,84.14 v2(196.34,84.46) UV8.L7 UV8.L8 ; v2(218.59,82.84) 218.56,82.86 UV7.35 ; UV8.G7 v2(196.34,81.86) ; UV8.G10 194.07,81.54 v2(194.39,81.86) UV8.G9 ; PU500.29 89.35,76.79 89.12,77.02 89.12,77.29 v2(89.09,77.32) ; v2(92.76,74.4) 92.66,74.49 PU500.22 ; v2(180.58,54.27) 180.7,54.14 UZ7.11 ; UV8.J9 v2(194.39,83.16) ; UV8.J6 v2(196.99,83.16)
  TOP w0.254: JAPS1.12 v2(31.93,39.98) ; UI3.17 80.38,93 80.63,93.25 UI3.14 80.63,94.93 RI14.1 ; v2(32.37,20.74) 32.26,20.85 PU800.23 ; PU800.32 v2(28.36,24.73) ; JXDP1.13 63.94,65.32 v2(64,65.37) ; RPE10.5 238.28,74.66 v2(238.02,74.92) 237.78,74.68 RPE10.6 ; UI5.6 v2(160.74,102.25) ; RPE10.8 236.78,74.61 v2(237.08,74.92) 237.28,74.72 RPE10.7 ; JAPS1.14 v2(30.98,39.53) ; PU800.14 v2(28.36,16.93) ; UV8.D14 191.14,79.26 v2(191.08,79.26) ; PU800.5 v2(24.44,20.85) ; UV8.C13 v2(191.79,78.61) ; UV8.D13 v2(191.79,79.26) ; UI5.5 v2(159.87,103.62) ; v2(191.14,78.61) UV8.C14
  TOP w0.279: JXDP1.2 66.51,68.32 66.07,67.88 66.07,67.05 v2(65.84,66.82) JXDP1.8 ; JXDP1.49 v2(60.26,56.32) ; JXDP1.20 69.03,63.82 v2(69.14,63.93) ; JXDP1.26 69.02,62.32 v2(69.14,62.2) ; JXDP1.14 v2(69.14,65.32) ; JXDP1.31 60.78,60.82 59.69,61.91 v2(58.8,61.91) ; JXDP1.1 63.23,68.32 63.9,68.98 v2(64.19,68.98) ; JXDP1.59 62.97,53.82 v2(63.25,53.54) ; v2(58.71,67.11) 58.86,67.25 60.28,67.25 60.71,66.82 JXDP1.7 ; JXDP1.25 60.58,62.32 60.35,62.55 v2(60.35,63.99) 60.53,63.82 JXDP1.19 ; JXDP1.32 v2(69.21,60.82) ; v2(69.12,56.32) JXDP1.50 ; JXDP1.38 v2(69.11,59.32)
  TOP w0.305: JUSH1.4 241.48,10.81 v2(241.64,10.64) ; JKBTP1.3 204.98,10.97 v2(204.57,10.57) 204.48,10.66 JKBTP1.2 ; v2(268.83,5.12) 268.85,5.13 JSH1.10 ; v2(241,67.17) 240.91,67.26 UE2.B11 ; UE1.B27 224.95,48.4 225.29,48.74 225.79,48.74 226.17,49.12 v2(226.17,49.25) ; UE2.B66 246.18,66.35 246.16,66.37 245.54,66.37 245.15,65.98 v2(245.15,65.82) ; v2(244.64,28.97) 245.29,28.97 245.5,29.18 JDEG1.10 ; JKBTP1.16 211.48,12.09 v2(211.2,12.37) 210.98,12.15 JKBTP1.15 ; v2(245.21,62.85) 245.21,62.97 245.59,63.35 246.5,63.35 UE2.B60 ; JSH1.5 266.35,6.56 266.56,6.77 v2(266.56,7.09) ; JLPDE1.9 v2(12.96,16.11) ; JSH1.2 264.85,6.77 v2(265.04,6.96) 265.35,6.64 JSH1.3 ; v2(168.26,70.08) 168.12,69.94 167.65,69.94 167.45,70.14 165.47,70.14 165.18,70.43 165.18,71.44 164.97,71.64 RC303.2 ; JXDP1.37 60.67,59.32 v2(60.35,59.64) ; v2(207.63,10.21) 207.98,10.56 JKBTP1.9 ; JAPS1.8 v2(32.63,42.52) ; UE2.B18 237.1,67.35 236.92,67.54 236.54,67.54 v2(235.78,68.3) ; JUSH1.19 248.98,10.78 v2(248.7,10.5) 248.48,10.73 JUSH1.18 ; JAPS1.10 v2(31.8,42.01) ; v2(245.65,60.03) 245.98,60.35 UE2.B54 ; JUSH1.1 v2(239.98,12.43) ; JUSH1.22 v2(249.85,9)
  TOP w0.381: RC175.2 RC174.2 159.13,67.23 159.47,66.9 160.45,66.9 160.73,67.18 v2(160.9,67.18) ; CZ5.2 192,42.8 UZ1.11 ; v2(167.12,57.23) 166.91,57.44 166.91,58.23 167.12,58.44 UC6.3 ; v2(190.17,41.82) 190.05,41.94 UZ1.8 ; v2(188.07,48.74) 187.69,48.74 187.45,48.99 UZ1.25 ; v2(251.08,33.3) 251,33.22 JDEG1.11 ; DI1.3 v2(68.33,96.73) ; RC152.2 141.06,66.76 v2(140.91,66.61) ; v2(169.12,81.75) 169.5,81.37 UC5.3 ; UC4.3 164.39,84.16 RC80.2 ; QZ10.1 136.79,93.2 136.26,93.73 136.26,94.03 135.79,94.5 QZ10.4 134.64,94.5 134.56,94.57 133.09,94.57 v3(132.81,94.29) 132.56,94.04 v2(132.56,93.15) ; RC140.2 v2(159.53,75.22) ; PQ806.1 v2(34.17,12.79) ; QE2.1 234.68,67.78 v2(235.19,68.3) ; UZ1.4 187.45,42.77 CZ4.2 ; YV2.2 200.48,91.21 v2(199.76,91.21) ; RV73.2 197.35,87.47 v2(197.75,87.06) ; UC8.3 113.85,88.22 v2(113.68,88.05) ; UZ1.18 192,48.71 v2(192.01,48.7) ; v2(72.76,84.37) 72.76,83.86 72.58,83.68 PU1.2 ; v2(212.17,9.89) 212.48,9.58 JKBTP1.18 ; RD14.1 121.12,29.34 120.25,29.34 120.15,29.44 UD1.3 ; UZ6.3 251.91,53.12 v2(252.12,52.91) ; UL2.3 241.72,84.29 v2(241.23,84.78) ; PQ813.4 v2(28.83,32.34) ; v2(26.85,28.68) 27.36,28.68 27.53,28.85 PQ813.1 ; UV502.7 v2(261.65,65.04)
  TOP w0.406: UZ10.3 237.08,42.38 236.84,42.62 v2(236.39,42.62) ; JSH1.13 v2(263.35,4.42) ; JKBTP1.17 202.98,9.57 203.3,9.89 v2(203.43,9.89) ; v2(13.93,38.86) 13.5,38.43 PQ817.4 ; DI4.3 v2(270.18,69.44) ; PU806.3 v2(14.82,35.71) ; PU804.3 v2(31.7,9.5) ; JSH1.14 v2(270.88,2.19) ; JUSH1.21 v2(239.56,9) ; 52.63,44.87 v2(52.07,44.87) ; QV700.4 191.6,72.1 191.92,71.78 191.92,71.25 192.37,70.8 QV700.1 193.37,70.8 193.94,70.23 v2(193.94,69.39) ; UZ11.3 220.42,39.28 219.05,37.91 v2(219.05,36.58)
  TOP w0.457: v2(199.12,91.21) 199.14,91.19 CV113.2 ; v2(57.73,7.09) PC710.2 ; JDEG1.12 244.5,33.12 v2(244.51,33.13) ; v2(156.24,69.73) 156.26,69.71 156.78,69.71 CC100.1 ; v2(142.24,54.48) 142.77,54.48 CC14.1 ; PQ806.4 v2(32.87,8.9) ; v2(232.07,69.89) 232.07,69.53 QE2.4 ; v2(261.93,27.33) 261.9,27.3 260.81,27.3 CA33.2 ; PQ817.1 v2(12.2,35.5) ; QA3.1 268.56,28.81 v2(268.55,28.79) ; PR745.2 47.94,8.23 v2(48.31,7.86) ; v2(270.45,30) QA3.4
  TOP w0.508: CE29.2 250.74,68.01 v2(251,68.27) 250.68,68.59 CE45.2 250.7,68.93 CE44.2 CE11.2 ; v2(255.89,85.19) 255.89,84.31 257.11,83.1 CL17.2 CL16.2 ; CV69.2 225.57,92.23 CV60.2 ; CV69.2 226.02,91.36 v2(226.21,91.54) ; CV69.2 225.57,90.48 RV554.1 ; PC301.2 192.2,60.49 v2(192.58,60.87) ; v2(173.91,20.71) 173.89,20.69 CD41.2 ; CD13.2 93.59,24.57 v2(93.59,24.56) ; RE56.1 239.66,53.56 v2(240.14,54.05) ; CD7.2 84.45,24.43 v2(84.46,24.42) ; v2(248,54.15) 248.13,54.28 CE25.2 ; CL12.2 229.35,93.45 228.84,92.94 v2(228.84,91.73) 228.84,90.79 CL3.2 ; RD6.2 CD5.2 CD1.2 v2(59.87,33.7) ; v2(192.52,41.88) 192.52,42.28 CZ5.2 ; JFAN1.4 v2(49.64,47.74) ; CZ25.2 142.8,95.61 142.2,95.01 v2(142.2,94.84) ; JSPK1.5 v2(280.42,14.49) ; CE40.2 242.26,71.34 v2(242.35,71.25) ; CC110.2 121.79,29.49 RD14.1 v2(121.27,28.78) ; v2(171.08,19.57) 171.09,19.55 CD42.2 ; RE78.2 233.27,61.01 v2(232.82,60.55) ; CZ12.2 CZ11.2 v2(245.55,15) ; v2(241.14,94.67) 241.59,94.21 CL9.2 ; v2(204.2,89.7) 203.76,89.25 YV2.4 ; v2(227.15,39.22) 227.15,40.35 RE20.1 ; UV24.2 50.15,73.51 v2(49.75,73.91) ; CI38.2 v2(163.64,101.98) ; CE19.2 242.24,54.84 242.9,54.18 ; v2(117.85,21.42) 118.02,21.25 CD25.2 CD24.2 ; v2(228.53,77.65) 228.53,77.5 228.3,77.27 RV619.2 RV620.2 ; CE10.2 249.77,72.59 CE12.2 v2(249.03,72.57) ; PQ816.3 v2(20.82,38.47) ; CC105.2 167.09,84.19 v2(167.26,84.35) ; v2(228.65,62.78) 228.66,62.79 CZ65.2 ; v2(226.23,84.89) 226.15,84.81 RV550.2 ; PC3.2 v2(173.91,6.57) ; v2(128.71,67.98) 129.18,68.45 CC27.2 ; CZ55.2 CZ51.2 223.96,41.53 223.96,42.5 224.4,42.94 224.73,42.94 v2(224.9,42.77) ; RE58.2 251.57,63.15 v2(251.43,63.29) 251.18,63.04 CE15.2 CE20.2 ; RV74.2 188.72,73.49 188.57,73.34 ; CZ35.2 254.37,56.79 v2(254.08,56.5) 253.86,56.28 CZ34.2 ; v2(217.54,18.72) 217.09,18.72 216.83,18.45 CZ31.2 ; PQ6.6 79.96,87.98 79.82,88.12 79.82,89.53 v2(80.14,89.85) ; v2(84.58,19.13) 84.55,19.17 CD10.2 ; CC104.2 168.72,79.44 168.02,80.14 v2(168.01,80.14) ; JLPDE1.11 v2(15.56,13.84) ; v2(231.06,67.47) RE277.1 ; CA30.2 v2(257.35,26.77) ; v2(245.36,72.35) 245.68,72.03 245.68,71.46 245.24,71.02 CE17.2 ; v2(211.65,70.5) 211.59,70.55 RV607.1 CV602.2 ; DA6.1 274.96,24.98 v2(275.5,25.53) ; CZ7.2 192.14,52.63 v2(192.14,53.45) 192.14,54.09 CZ9.2 ; CD45.2 159.69,19.85 v2(159.44,20.1) ; v2(226.29,57.53) 226.33,57.53 226.77,57.97 CZ52.2 CZ53.2 ; v2(142.34,69.09) 141.82,68.57 CC49.2 141.43,68.37 141.3,68.5 CC72.2 ; RV75.2 188.96,83.54 v2(189.03,83.6) ; v2(142.24,54.48) 141.87,54.48 CC13.1 ; v2(138.54,52.99) 138.42,52.87 CC65.2 ; v2(207.2,101.36) 207.29,101.45 LED6.1 ; v2(238.43,47.19) 239.3,47.19 RE85.2 ; C311.2 R271.2 v2(133.13,104.24) ; RL12.2 245.04,87.3 v2(245.16,87.42) ; CD12.2 97.97,24.45 v2(98,24.42) ; v2(100.19,16.17) 100.19,16.8 99.86,17.13 CD22.2 CD23.2 ; CD6.2 75.64,21.55 v2(75.72,21.63) ; v2(52.55,42.93) 52.73,43.1 CE41.2 ; v2(215.14,14.66) 215.21,14.73 CZ16.2 CZ17.1 CZ15.2 ; RC128.1 59.61,51.66 v2(59.74,51.54) ; CD52.2 161.34,19.92 v2(161.37,19.95) ; PC505.1 v2(84.98,76.63) ; v2(100.83,96.3) 101.08,96.05 D20.1 ; RD25.2 v2(131.56,25.81) ; CE6.2 231.4,41.83 v2(231.4,42.11) ; v2(209.11,86.08) 209.12,86.08 210.19,85.01 RV50.2 CV62.2 ; CD38.2 166.9,24.58 v2(166.9,24.58) ; CI420.2 v2(99.3,99.75) ; v2(229.73,87.29) 229.54,87.1 CL4.2 228.83,86.89 CL13.1 ; v2(91.7,19.52) 91.75,19.46 CD17.2 ; v2(247.23,49.21) 246.91,49.53 RE86.1 ; RN7.2 40.09,25.03 40.48,24.65 v2(41.2,24.65) ; CC15.1 143.97,54.55 v2(144.26,54.84) 144.76,55.34 RC243.2 RC242.2 ; v2(259.94,10.34) 259.94,10.83 RR8.2 ; CE14.2 RE55.1 232.77,62.91 v2(232.65,63.03) ; v2(187.4,74.07) 187.4,74.82 RV509.1 ; v2(140.49,72.9) 140.49,73.75 CC64.2 ; PC117.2 202.93,53.31 v2(202.93,52.55) ; v2(206.62,44.87) 207.12,45.38 RZ40.1 ; UZ5.2 v2(249.58,57.97) ; v2(246.43,14.96) CZ10.2 246.44,14.25 CZ68.2 ; RV61.2 v2(214.38,82.51) ; v2(78.66,84.3) 79.11,83.86 PR18.2 ; v2(137.73,70.84) 137.68,70.79 CC37.2 ; DA7.1 v2(279.27,23.33) ; CE38.2 RE77.2 v2(232.71,65.77) ; JLPDE1.12 v2(6.86,13.73) ; CD4.2 88.64,24.56 v2(88.65,24.55) ; v2(148.26,57.19) 148.48,56.97 RC91.1 ; CA10.2 v2(256.02,26.9) ; v2(222.36,94.32) 222.59,94.1 RV66.2 ; CE36.2 235.02,58.41 v2(235.15,58.27) ; v2(196.46,45.27) 196.62,45.44 PR106.1 PR104.2 ; C319.2 144.87,98.23 v2(144.98,98.11) ; CR35.2 RR11.2 v2(262.51,8.72) ; CD30.2 117.72,30.03 v2(117.94,29.82) ; CV115.2 204.08,88.05 204.46,88.43 v2(204.46,88.87) ; CD29.2 v2(123.82,23.46) ; QV502.3 268.15,72.82 268.21,72.76 RV504.2 v2(268.72,73.44) ; CC112.2 v2(59.56,58.86) ; v2(165.23,24.52) 164.9,24.85 CD47.2 ; PC1.2 224.99,95.4 v2(224.11,94.53) 224.35,94.53 RV65.2 ; v2(81.54,19.85) 81.59,19.8 CD19.2 ; v2(139.03,75.31) 139.05,75.29 CC66.2 ; JTAG1.2 245.91,52.5 v2(245.53,52.88) ; CZ62.2 CZ60.2 178.43,54.58 v2(177.95,54.11) ; JAPS1.19 v2(37.26,45.95) ; CD16.2 94.8,19.52 v2(94.81,19.53) ; CC48.2 143.56,68.55 v2(143.56,69.15) ; v2(263.7,22.97) 263.07,23.6 CR9.1 ; v2(270.5,83.05) 270.6,82.96 RV503.1 ; CD44.2 162.99,19.84 v2(163.1,19.95) ; CI418.2 v2(96.27,101.28) ; PC214.2 v2(180.05,5.28) ; v2(38.47,18.9) 39.04,19.47 CN2.2 ; v2(226.31,82.51) 226.31,82.37 225.83,81.89 RV52.2 RV67.1 ; v2(168.17,27.4) 168.17,27.4 CD40.2 ; v2(231.89,56.84) 231.68,57.04 CE3.2 ; 159.94,50.52 159.71,50.76 CC60.2 ; CI414.2 CI416.2 103.85,99.92 v2(103.54,100.23) ; PR874.2 29.27,14.02 v2(29.19,13.94) ; CR23.2 260.13,24.95 v2(260.4,24.68) ; CE13.2 240.57,72.26 239.66,73.16 CE31.2 v2(239.51,73.85) ; v2(201.16,44.11) 201.16,43.86 201.73,43.28 CL23.2 CL24.2 ; CN1.2 48.64,13.11 47.65,12.12 46.38,12.12 v2(46.14,11.87) ; v2(113.68,88.05) 113.21,88.51 RC123.2 113.02,88.51 CC83.2 ; RD24.2 CD34.2 CD33.2 v2(135.62,24.86) ; CR14.1 v2(267.8,11.54) ; v2(116.45,24.49) 117.86,25.9 RD16.1 RD15.1 ; 188.57,73.34 187.06,71.84 QV10.3 ; 188.57,73.34 v2(188.57,73.35) ; RD7.2 v2(63.31,37.19) ; CL10.2 v2(231.43,87.67) ; PR12.1 v2(69.89,85.51) 70.54,86.16 PQ3.3 ; v2(197.98,53.76) 198.55,53.76 PC118.2 ; CC106.2 162.47,82.77 v2(162.78,83.07) ; CA50.2 v2(263.13,28.68) ; 242.9,54.18 v2(242.9,53.95) ; 242.9,54.18 242.91,54.19 RE88.2 ; v2(245.05,80.24) 245.05,79.93 245.37,79.61 CL26.2 ; v2(142.71,66.87) 142.55,66.71 CC50.2 ; v2(93.4,19.13) 93.4,19.13 CD8.2 ; v2(105.95,88.45) 105.98,88.48 RC198.2 ; v2(164.37,84.99) 164.24,84.86 RC80.2 ; CD39.2 163.18,24.61 v2(163.1,24.52) ; v2(145.1,70.72) 145.1,70.73 CC52.2 ; CR22.1 v2(267.75,16.75) ; PC212.2 v2(181.6,5.5) ; RE82.1 253.47,70.5 v2(253.75,70.79) ; CC102.2 116.43,90.73 v2(116.57,90.87) ; CD11.2 80.32,19.59 v2(80.33,19.6) ; CI417.2 v2(97.03,106.54) ; DI5.1 270.4,61.59 270.69,61.89 v2(270.94,61.89) ; CE30.2 RE65.2 244.77,52.5 v2(244.46,52.81) ; v2(253.15,19.22) 253.38,19.46 RR2.1 ; CC19.2 CC22.2 58.15,56.87 v2(57.71,57.31) ; CZ42.2 48.39,25.96 48.94,26.51 v2(49.51,26.51) ; CZ42.2 CZ43.2 ; CZ42.2 CZ41.2 CZ40.2 ; RV100.2 228.29,80.05 RV616.2 228.35,80.14 228.68,80.47 v2(228.68,80.75) ; PC817.2 v2(27.15,14.11) ; CL11.2 v2(240.78,78.94) ; CC9.1 166.73,72.1 v2(166.42,71.79) ; CC35.2 119.24,89.51 v2(119.56,89.83) ; CL8.2 v2(235.89,94.46) ; PR308.2 185.66,59.98 v2(184.82,59.14) ; RV63.2 225.65,88.75 v2(226.23,88.75) ; RE17.1 CE5.2 220.45,46.98 CE9.2 v2(219.57,45.95) ; PC4.2 v2(157.02,6.32) ; v2(132.61,67.98) 132.67,68.03 CC26.2 ; v2(246.49,76.36) 247.24,76.36 CL25.2 ; v2(71.49,56.62) 71.29,56.81 CC21.2 70.82,56.82 CC111.2 ; v2(69.2,82.91) 69.2,81.25 69.63,80.82 CZ2.2 ; v2(21.18,21.96) 21.53,21.61 PC815.2 ; CA19.2 278.71,28.74 v2(279.27,29.3) 279.77,28.8 CA24.2 ; LED5.1 v2(227.17,100.69) ; CD15.2 82.99,24.49 v2(83,24.48) ; CE21.2 254.23,61.09 v2(253.97,60.84) ; RC132.2 RC131.2 RC130.2 113.59,53.12 v2(114.12,53.64) ; CC18.2 v2(70.8,59.51) ; CE18.2 CE16.2 251.01,59.02 v2(251.45,58.58) ; CD26.2 CD27.2 v2(123.45,24.54) ; CV603.2 224.08,74.98 v2(224.05,74.95) ; v2(259.12,29.15) 258.97,29.3 CA11.2 ; v2(210.91,77.2) 211.4,76.71 RV609.1 ; CR3.2 v2(267.75,15.73) ; CR13.1 v2(266.9,21.25) ; RL9.2 231.8,94.69 231.38,95.11 v2(231.22,95.11) ; v2(253.54,14.52) CR18.1 ; v2(89.66,19.13) 89.65,19.13 CD9.2 ; v2(251.61,82.14) 251.32,82.43 CL20.2 CL21.2 ; RV78.2 v2(192.39,87.16) ; v2(170.77,23.82) 170.77,24.01 171.22,24.46 CD46.2 ; v2(180.26,86.4) 180.26,87.51 QV9.3 ; PD1.1 v2(166.87,7.28) ; CZ47.2 v2(211.32,69.89) ; CC59.2 143.09,76.19 v2(143.15,76.14) ; CD3.2 90.61,24.62 v2(90.62,24.61) ; CC40.2 145.28,77.85 v2(145.28,77.92) ; CZ1.2 75.11,77 74.88,77.23 v2(73.92,77.23) ; CR34.2 v2(264.26,9.88) ; v2(267.99,14.65) CR1.2 ; CR19.1 v2(266.81,20.29) ; JLED1.8 v2(53.07,81.7) ; RC139.1 149.71,87.75 RC141.1 149.72,88.67 v2(150.02,88.97) ; v2(230.65,60.42) 231.18,60.94 CE34.2 ; v2(58.52,74.92) 58.52,75.54 RV1.2 ; CZ54.2 v2(224.21,38.07) ; v2(168.97,84.71) 169.08,84.81 RC304.2 CC103.2 ; JSPK1.6 v2(272.05,16.6) ; RC218.2 108.57,87.15 v2(108.4,86.98) ; PC119.2 v2(196.1,47.54) ; RV608.1 v2(210.74,74.78) ; CZ6.2 187.62,53.04 v2(187.95,53.37) ; CE23.2 v2(232.7,64.82) ; v2(260.32,75.79) 260.15,75.62 RV502.1 ; CE7.2 232.82,40.57 RE21.1 233.85,40.57 v2(234.2,40.22) ; v2(91.17,68.3) PC501.2 90.77,68.91 90.22,68.36 PC500.1 ; CE22.2 237.01,55.04 236.64,55.04 v2(236.38,55.29) ; CC28.2 134.67,68.11 v2(134.58,68.01) ; v2(257.55,81.54) 258.07,81.54 CL15.2 ; PR209.2 v2(180.06,3.07) ; CV604.2 v2(225.62,78.03) ; CD48.2 161.21,24.68 v2(161.37,24.52) ; v2(188.14,41.46) 188.37,41.69 188.37,42.14 187.86,42.65 CZ4.2 ; v2(117.85,19.9) 118.35,19.9 119.03,19.22 CD28.2 ; v2(219.2,54.79) 219.76,54.23 220.11,54.23 220.51,53.83 RE24.2 CE4.2 ; CD51.2 165.21,19.94 v2(165.23,19.95) ; RV617.2 RV618.2 228.3,72.82 RV606.1 228.8,72.73 v2(229.19,73.13) ; PC511.2 87.43,80.56 87.74,80.24 v2(87.74,79.5) 88.18,79.5 PC514.1 ; CE42.2 51.51,46.51 51.87,46.15 v2(51.87,45.63) 52.18,45.63 CE32.2 ; PC810.1 v2(15.51,39.56) ; PC209.1 v2(191.59,5.44) ; v2(184.87,57.82) PC309.2 ; CR7.1 v2(256.58,10.21) ; CR17.1 v2(253.99,13.44) ; C263.2 v2(266.23,8.91) ; RZ48.1 67.55,78.27 v2(68.25,77.57) ; v2(95.75,24.42) 95.43,24.73 CD2.2 ; CE28.2 250.23,64.92 v2(250,65.15) ; CD50.2 169.25,19.94 v2(169.24,19.95) ; QV7.3 77.97,75.18 v2(77.97,74.84) ; CV601.2 RV600.2 210.9,79.29 v2(210.78,79.4) ; CI3.2 v2(73.41,95.71) ; PC100.1 v2(200.46,44.17) ; RD28.2 197.85,29.7 v2(197.83,29.69) ; v2(61.9,76.45) 62.27,76.08 RV2.2 ; CA22.2 273.67,28.66 v2(273.67,29.36) ; CR4.2 260.9,23.35 v2(261.34,23.79) 261.85,23.29 CR10.1 ; CC58.2 139.04,69.34 v2(139.16,69.22) ; CZ30.2 v2(219.52,18.6) ; v2(102.22,56.11) 101.79,55.68 RC191.2 ; v2(140.1,54.99) 140.46,54.99 CC12.1 ; CL19.2 256.88,75.2 v2(258.49,75.2) ; JFAN1.6 v2(42.09,48.62) ; JAPS1.20 v2(26.15,39.66) ; v2(141.99,56.35) 142.04,56.4 142.58,56.4 143.05,55.93 CC101.2 ; CZ64.2 229.9,62.72 v2(229.92,62.7) 229.92,62.22 CZ63.2 ; CA49.1 v2(257.86,41.25) ; JFAN1.5 49.45,57.6 v2(49.45,58.52) ; v2(261.99,28.26) 261.99,28.28 261.93,28.35 CA53.2 ; CD56.2 178.42,19.92 v2(178.44,19.9) ; QA1.3 267.78,29.02 v2(267.25,29.55) ; v2(243.69,92.28) 243.47,92.49 CL18.2 ; PC211.2 190.77,2.97 v2(190.22,2.43) ; v2(202.88,73.47) 203.39,73.98 203.39,74.04 RV79.2 ; v2(238.18,51.79) 237.74,52.22 RZ38.1 ; v2(199.76,44.11) 199.76,43.73 199.96,43.53 CZ37.2 CZ36.2 ; RV77.2 v2(193.31,87.18) ; v2(117.94,28.29) 118.93,28.29 119.11,28.11 CD31.2 CD32.2 ; CV605.2 211.67,81.34 211.51,81.51 v2(211.09,81.51) ; v2(136.39,86.27) 134.92,87.74 CC36.2 ; PR102.1 PR105.1 v2(204.25,44.66) ; v2(195.25,89.3) 195.79,89.3 RV89.2 ; v2(232.02,84.3) 231.35,84.3 YL1.2 ; PC9.2 v2(95.36,90.72) ; v2(240.59,41.19) 240.51,41.1 CZ48.2 ; CC78.2 140.4,76.48 v2(140.7,76.17) ; CR31.2 v2(261.72,10.33) ; CI17.2 v2(268.2,62.6) ; CZ27.2 210.05,13.7 v2(209.92,13.58) ; v2(86.55,24.55) 86.54,24.56 CD14.2 ; CV61.2 214.45,93.94 213.97,94.42 v2(213.63,94.42) ; v2(194.25,87.03) 194.25,87.21 194.23,87.22 RV76.2 ; CE8.2 v2(238.48,45.16) ; PC737.2 PR745.2 ; CA13.2 267.7,55.59 v2(267.06,56.24) ; v2(194.68,49.19) 195.18,48.69 PR114.2 ; v2(232.33,81.83) CL14.1 RL13.2 ; CE2.2 v2(237.74,48.74) ; RA36.2 v2(274.63,34.26) ; PC206.2 191.86,6.58 191.49,6.95 v2(191.21,6.95) ; RZ48.2 68.95,78.64 69.39,78.19 v2(69.39,78.08) ; CV600.2 223.55,80.49 v2(223.85,80.19) ; JLED1.7 v2(66.54,86.52) ; CC57.2 139.81,70.29 v2(139.21,70.88) ; v2(35.4,18.81) 35.4,19.11 35.22,19.29 PR844.2 ; v2(223.29,82.52) 223.55,82.26 CV66.2 ; CE1.2 v2(239.83,48.33) ; CZ28.2 CZ29.2 205.59,15.06 v2(205.59,15.35) ; CL7.2 230.35,90.8 v2(230.35,90.4) 230.57,90.18 RL3.1 ; v2(257.22,10.23) 257.67,10.68 CR8.1 ; PQ832.3 v2(36.12,30.34) ; CD49.2 172.36,19.93 v2(172.35,19.95) ; CA7.2 65.7,74.6 66.8,73.49 CA5.2 CA6.2 69.02,73.49 69.52,73 v2(69.52,72.19) ; v2(167.01,19.95) 167.03,19.93 CD43.2 ; CV10.2 49.64,69.32 v2(49.45,69.51) 49.39,69.57 RV3.1 ; v2(210.41,73.3) 210.41,73.06 210.69,72.78 CZ44.2 CZ45.2 CZ46.2 ; PR858.2 32.83,20.28 v2(32.37,20.74) ; CA41.2 274.18,37.88 271.7,35.41 v2(271.7,34.33) ; v2(103.44,100.86) 103.85,100.86 103.9,100.81 CI415.2 ; v2(170.01,28.55) 169.98,28.51 CD37.2 ; CL27.2 v2(253.42,85) ; v2(119.53,86.4) 118.81,87.12 CC24.2 ; PD5.1 v2(75.9,97.01) ; v2(144.87,69.13) 144.87,68.93 CC73.2 144.58,68.38 CC80.2 ; RV505.1 v2(268.47,75.03) ; CI419.2 105.45,106.76 v2(105.75,106.45) ; CC68.2 139.65,72.88 v2(139.21,73.32) 139.14,73.25 CC70.2 ; CR6.2 v2(263.2,10.32) ; SW2.3 v2(275.66,89.2) ; v2(47.1,3.59) 47.67,4.16 PC741.1 ; v2(230.38,81.27) 230.29,81.27 229.21,82.34 YL1.4 ; CD35.2 145.35,23.16 145.01,22.83 v2(145.01,22.24) ; RZ10.1 v2(248.21,15) ; CD55.2 RD20.2 178.16,21.69 v2(178.44,21.42) 178.65,21.63 RD21.2 ; v2(256.97,21.63) 256.37,21.63 CR21.1 ; CA23.2 v2(275.45,29.37) ; v2(144.32,94.04) 143.78,94.59 CZ38.2 ; CV9.2 v2(50.71,76.5) ; CI19.2 v2(77.53,96.09) ; v2(88.2,19.85) 88.26,19.8 CD18.2 ; PR814.1 v2(29.01,27.98) ; PC813.2 v2(21.26,22.88) ; v2(140.22,104.95) 140.76,105.49 C316.2 ; PD2.1 v2(164.83,8.61) ; PC816.2 v2(26.12,13.36) ; SW2.1 v2(277.76,89.2) ; DI2.1 71.58,96.05 v2(70.54,96.05) ; v2(267.56,13.57) RR5.2 CR15.1 ; RA37.2 v2(259.09,48.16) ; PC215.2 v2(186.4,1.73) ; PC805.1 v2(31.53,7.2) ; CV511.2 v2(256.98,69.56)
  GND1 w0.203: JUSB2.4 190.69,98.83 ; JUSB2.4 190.69,97.45 ; JUSB2.4 191.23,97.6 ; JUSB2.4 191.23,98.68 ; JUSB2.4 190.15,98.68 ; JUSB2.4 190.15,97.6 ; JUSB2.4 190,98.14 ; JUSB2.4 191.38,98.14 ; H4.1 221.54,65.81 ; H4.1 218.86,65.81 ; H4.1 220.2,65.32 ; H4.1 218.86,68.49 ; H4.1 218.37,67.15 ; H4.1 221.54,68.49 ; H4.1 222.03,67.15 ; H4.1 220.2,68.98 ; JUSB1.4 68.89,98.14 ; JUSB1.4 68.2,98.83 ; JUSB1.4 68.74,98.68 ; JUSB1.4 68.74,97.61 ; JUSB1.4 68.2,97.46 ; JUSB1.4 67.66,98.68 ; JUSB1.4 67.66,97.61 ; JUSB1.4 67.51,98.14 ; H14.1 160.46,61.73 ; H14.1 158.32,63.86 ; H14.1 159.88,63.29 ; H14.1 159.88,60.17 ; H14.1 156.76,60.17 ; H14.1 156.76,63.29 ; H14.1 156.19,61.73 ; H14.1 158.32,59.6 ; SW1.4 183.3,69.09 ; SW1.4 182.3,70.1 ; SW1.4 182.3,68.09 ; SW1.4 181.54,69.86 ; SW1.4 183.06,69.86 ; SW1.4 181.54,68.33 ; SW1.4 181.3,69.09 ; SW1.4 183.06,68.33 ; 138.2,103.5 JDOCK1.157 ; JDOCK1.157 137.4,103.75 ; JDOCK1.157 137.4,105.35 ; JDOCK1.157 138.2,105.6 ; JDOCK1.157 137.15,104.55 ; JDOCK1.157 139,105.35 ; JDOCK1.157 139,103.75 ; JDOCK1.157 139.25,104.55 ; 154.64,108.48 JDOCK1.162 ; JDOCK1.162 158.76,108.48 ; JDOCK1.162 158.76,109.42 ; JDOCK1.162 158.76,107.53 ; JDOCK1.162 154.64,109.42 ; JDOCK1.162 156.7,109.42 ; 107.02,102.7 JDOCK1.145 ; JDOCK1.145 106.11,102.7 ; JDOCK1.145 106.11,104.55 ; JDOCK1.145 106.11,106.4 ; JDOCK1.145 107.02,106.4 ; JMDP1.24 272.75,88.43 ; JMDP1.24 274.06,87.66 ; JMDP1.24 274.06,88.43 ; JMDP1.24 272.75,86.88 ; JMDP1.24 271.44,88.43 ; JMDP1.24 271.44,86.88 ; JMDP1.24 271.44,87.66 ; JMDP1.7 274.05,82.69 ; JMDP1.7 273.13,82.69 ; JMDP1.7 273.59,82.57 ; JMDP1.7 274.17,83.16 ; JMDP1.7 274.05,83.62 ; JMDP1.7 273.13,83.62 ; JMDP1.7 273.01,83.16 ; 137.15,101.6 JDOCK1.153 ; JDOCK1.153 137.15,99.65 ; JDOCK1.153 137.15,100.62 ; JDOCK1.153 139.25,100.62 ; JDOCK1.153 139.25,99.65 ; JDOCK1.153 139.25,101.6 ; JDOCK1.153 138.2,99.65 ; JDOCK1.153 138.2,101.6 ; 203.52,111.72 JHDMI1.22 ; JHDMI1.22 205.28,108.78 ; JHDMI1.22 205.28,110.25 ; JHDMI1.22 204.4,111.72 ; JHDMI1.22 205.28,111.72 ; JHDMI1.22 203.52,108.78 ; JHDMI1.22 203.52,110.25 ; JHDMI1.22 204.4,108.78 ; 273.13,81.62 JMDP1.13 ; JMDP1.13 274.05,80.69 ; JMDP1.13 273.59,81.74 ; JMDP1.13 274.05,81.62 ; JMDP1.13 273.13,80.69 ; JMDP1.13 273.01,81.16 ; JMDP1.13 274.17,81.16 ; 62.97,106.24 JUSB1.12 ; JUSB1.12 63.85,106.24 ; JUSB1.12 62.97,108.99 ; JUSB1.12 63.85,108.99 ; JUSB1.12 62.97,107.61 ; 225.86,107.21 H18.1 ; H18.1 229.03,108.55 ; H18.1 228.54,109.89 ; H18.1 227.2,106.72 ; H18.1 228.54,107.21 ; H18.1 225.37,108.55 ; H18.1 227.2,110.38 ; H18.1 225.86,109.89 ; JUSB1.13 79.55,108.99 ; JUSB1.13 79.55,106.24 ; JUSB1.13 80.43,106.24 ; JUSB1.13 80.43,107.61 ; JUSB1.13 80.43,108.99 ; 101.44,63.29 H16.1 ; H16.1 101.44,60.17 ; H16.1 103,63.86 ; H16.1 100.86,61.73 ; H16.1 104.56,60.17 ; H16.1 104.56,63.29 ; H16.1 105.13,61.73 ; H16.1 103,59.6 ; 153.39,1.49 PBATT1.9 ; PBATT1.9 154.2,1.22 ; PBATT1.9 154.2,3.38 ; PBATT1.9 153.12,2.3 ; PBATT1.9 155.01,3.11 ; PBATT1.9 155.01,1.49 ; PBATT1.9 153.39,3.11 ; 193.65,99.1 JUSB2.7 ; JUSB2.7 194.88,99.64 ; JUSB2.7 194.19,98.95 ; JUSB2.7 194.73,99.1 ; JUSB2.7 193.5,99.64 ; 156.7,99.68 JDOCK1.154 ; JDOCK1.154 156.7,101.57 ; JDOCK1.154 158.76,101.57 ; JDOCK1.154 158.76,100.62 ; JDOCK1.154 154.64,100.62 ; JDOCK1.154 158.76,99.68 ; JDOCK1.154 154.64,99.68 ; 214.15,103.61 JHDMI1.11 ; JHDMI1.11 214.6,104.62 ; JHDMI1.11 213.7,104.62 ; JHDMI1.11 214.15,104.73 ; JHDMI1.11 213.7,103.72 ; JHDMI1.11 214.6,103.72 ; H6.1 184.6,15.8 ; H6.1 184.6,12.14 ; H6.1 183.26,15.31 ; H6.1 183.26,12.63 ; H6.1 185.94,12.63 ; H6.1 182.77,13.97 ; H6.1 185.94,15.31 ; H6.1 186.43,13.97 ; H12.1 50.53,86.15 ; H12.1 47.36,87.49 ; H12.1 48.7,84.32 ; H12.1 46.87,86.15 ; H12.1 48.7,87.98 ; H12.1 47.36,84.81 ; H12.1 50.04,87.49 ; H12.1 50.04,84.81 ; H17.1 73.6,65.88 ; H17.1 74.94,62.71 ; H17.1 73.6,62.22 ; H17.1 74.94,65.39 ; H17.1 72.26,62.71 ; H17.1 71.77,64.05 ; H17.1 72.26,65.39 ; H17.1 75.43,64.05 ; 205.52,101.82 JHDMI1.20 ; JHDMI1.20 205.52,103.4 ; JHDMI1.20 206.4,101.82 ; JHDMI1.20 207.28,104.98 ; JHDMI1.20 207.28,103.4 ; JHDMI1.20 207.28,101.82 ; JHDMI1.20 205.52,104.98 ; JHDMI1.20 206.4,104.98 ; 276.44,87.66 JMDP1.23 ; JMDP1.23 276.44,88.43 ; JMDP1.23 276.44,86.88 ; JMDP1.23 277.75,88.43 ; JMDP1.23 279.06,88.43 ; JMDP1.23 279.06,87.66 ; 278.52,40.15 H2.1 ; H2.1 281.44,41.39 ; H2.1 280.2,41.83 ; H2.1 280.2,38.47 ; H2.1 278.96,38.91 ; H2.1 281.44,38.91 ; H2.1 278.96,41.39 ; H2.1 281.88,40.15 ; H8.1 130.54,20.99 ; H8.1 127.37,19.65 ; H8.1 127.86,18.31 ; H8.1 131.03,19.65 ; H8.1 129.2,17.82 ; H8.1 130.54,18.31 ; H8.1 129.2,21.48 ; H8.1 127.86,20.99 ; 155.39,3.11 PBATT1.8 ; PBATT1.8 157.01,1.49 ; PBATT1.8 156.2,1.22 ; PBATT1.8 156.2,3.38 ; PBATT1.8 155.39,1.49 ; PBATT1.8 157.01,3.11 ; H5.1 214.34,32.96 ; H5.1 214.83,34.3 ; H5.1 213,36.13 ; H5.1 214.34,35.64 ; H5.1 211.66,32.96 ; H5.1 211.66,35.64 ; H5.1 211.17,34.3 ; H5.1 213,32.47 ; JUSB3.7 272.97,68.08 ; JUSB3.7 272.33,66.62 ; JUSB3.7 272.14,67.25 ; JUSB3.7 272.33,67.89 ; JUSB3.7 272.97,66.42 ; 105.64,100.62 JDOCK1.151 ; JDOCK1.151 107.7,101.57 ; JDOCK1.151 109.76,100.62 ; JDOCK1.151 109.76,99.68 ; JDOCK1.151 105.64,101.57 ; 276.44,76.66 JMDP1.21 ; JMDP1.21 277.75,75.88 ; JMDP1.21 276.44,75.88 ; JMDP1.21 276.44,77.43 ; JMDP1.21 279.06,76.66 ; JMDP1.21 279.06,75.88 ; PBATT1.11 173.33,4.43 ; PBATT1.11 174.3,0.67 ; PBATT1.11 174.3,2.55 ; PBATT1.11 172.35,0.67 ; PBATT1.11 172.35,4.43 ; PBATT1.11 173.33,0.67 ; PBATT1.11 172.35,2.55 ; PBATT1.11 174.3,4.43 ; 271.47,69.92 JUSB3.4 ; JUSB3.4 272.1,70.12 ; JUSB3.4 271.47,71.58 ; JUSB3.4 270.83,71.39 ; JUSB3.4 270.83,70.12 ; JUSB3.4 270.64,70.75 ; 200.06,96.83 JUSB2.11 ; JUSB2.11 201.82,96.83 ; JUSB2.11 200.06,98.61 ; JUSB2.11 201.82,98.61 ; JUSB2.11 200.94,96.83 ; JUSB2.11 201.82,100.39 ; 186.56,100.39 JUSB2.10 ; JUSB2.10 186.56,96.83 ; JUSB2.10 186.56,98.61 ; JUSB2.10 188.32,96.83 ; JUSB2.10 188.32,98.61 ; JUSB2.10 187.44,96.83 ; 274.33,84.39 JMDP1.1 ; JMDP1.1 274.33,85.32 ; JMDP1.1 275.37,84.86 ; JMDP1.1 275.25,84.39 ; JMDP1.1 274.79,85.44 ; JMDP1.1 274.21,84.86 ; JMDP1.1 275.25,85.32 ; 49.2,79.51 H19.1 ; H19.1 49.2,82.49 ; H19.1 48.1,79.9 ; H19.1 50.69,81 ; H19.1 47.71,81 ; H19.1 48.1,82.1 ; H19.1 50.3,82.1 ; H19.1 50.3,79.9 ; 180.33,63.63 ST2.1 ; ST2.1 183.37,66.67 ; ST2.1 181.85,67.23 ; ST2.1 179.77,65.15 ; ST2.1 180.33,66.67 ; ST2.1 183.37,63.63 ; ST2.1 181.85,63.07 ; ST2.1 183.93,65.15 ; JDOCK1.158 151,103.75 ; JDOCK1.158 150.2,103.5 ; JDOCK1.158 151.25,104.55 ; JDOCK1.158 149.4,103.75 ; JDOCK1.158 149.15,104.55 ; JDOCK1.158 150.2,105.6 ; JDOCK1.158 149.4,105.35 ; JDOCK1.158 151,105.35 ; 42.37,39.15 H10.1 ; H10.1 45.54,37.81 ; H10.1 45.54,40.49 ; H10.1 42.86,40.49 ; H10.1 46.03,39.15 ; H10.1 42.86,37.81 ; H10.1 44.2,37.32 ; H10.1 44.2,40.98 ; JUSB3.11 275.68,75.98 ; JUSB3.11 275.68,75.1 ; JUSB3.11 273.9,75.98 ; JUSB3.11 272.12,75.1 ; JUSB3.11 272.12,74.22 ; 68.21,43.44 ST3.1 ; ST3.1 68.21,47.6 ; ST3.1 66.69,47.04 ; ST3.1 66.69,44 ; ST3.1 69.73,44 ; ST3.1 70.29,45.52 ; ST3.1 66.13,45.52 ; ST3.1 69.73,47.04 ; JHDMI1.23 223.78,111.72 ; JHDMI1.23 222.9,111.72 ; JHDMI1.23 222.02,110.25 ; JHDMI1.23 223.78,110.25 ; JHDMI1.23 222.02,111.72 ; JHDMI1.23 222.9,108.78 ; JHDMI1.23 223.78,108.78 ; JHDMI1.23 222.02,108.78 ; JDOCK1.148 158.29,102.7 ; JDOCK1.148 158.29,104.55 ; JDOCK1.148 157.37,102.7 ; 103,81.74 H15.1 ; H15.1 104.56,85.43 ; H15.1 104.56,82.31 ; H15.1 101.44,85.43 ; H15.1 105.13,83.87 ; H15.1 101.44,82.31 ; H15.1 100.86,83.87 ; H15.1 103,86 ; JUSB3.10 275.68,59.4 ; JUSB3.10 272.12,59.4 ; JUSB3.10 272.12,60.28 ; H9.1 80.2,6.88 ; H9.1 82.03,5.05 ; H9.1 81.54,6.39 ; H9.1 78.86,6.39 ; H9.1 81.54,3.71 ; H9.1 78.37,5.05 ; H9.1 78.86,3.71 ; H9.1 80.2,3.22 ; PBATT1.10 151.08,4.43 ; PBATT1.10 152.05,2.55 ; PBATT1.10 151.08,0.67 ; PBATT1.10 150.1,2.55 ; PBATT1.10 150.1,4.43 ; PBATT1.10 150.1,0.67 ; PBATT1.10 152.05,0.67 ; 212.65,102.41 JHDMI1.8 ; JHDMI1.8 213.1,102.52 ; JHDMI1.8 213.1,103.42 ; JHDMI1.8 212.2,102.52 ; JHDMI1.8 212.65,103.53 ; JHDMI1.8 212.2,103.42 ; JUSB2.13 202.92,107.61 ; JUSB2.13 202.04,108.98 ; JUSB2.13 202.92,108.98 ; JUSB2.13 202.04,106.24 ; JUSB2.13 202.92,106.24 ; 77.57,96.84 JUSB1.11 ; JUSB1.11 78.45,96.84 ; JUSB1.11 79.33,96.84 ; JUSB1.11 79.33,98.61 ; JUSB1.11 77.57,98.61 ; JUSB1.11 79.33,100.39 ; 274.79,78.87 JMDP1.19 ; JMDP1.19 274.21,79.46 ; JMDP1.19 274.33,79.92 ; JMDP1.19 274.33,78.99 ; JMDP1.19 275.25,78.99 ; JMDP1.19 275.25,79.92 ; JMDP1.19 275.37,79.46 ; 220.02,101.82 JHDMI1.21 ; JHDMI1.21 220.9,101.82 ; JHDMI1.21 221.78,104.98 ; JHDMI1.21 221.78,101.82 ; JHDMI1.21 220.02,103.4 ; JHDMI1.21 220.02,104.98 ; JHDMI1.21 220.9,104.98 ; JHDMI1.21 221.78,103.4 ; 209.2,103.42 JHDMI1.2 ; JHDMI1.2 209.2,102.52 ; JHDMI1.2 210.1,102.52 ; JHDMI1.2 209.65,103.53 ; JHDMI1.2 209.65,102.41 ; JHDMI1.2 209.09,102.97 ; JHDMI1.2 210.1,103.42 ; JUSB3.13 282.03,59.84 ; JUSB3.13 282.03,59.4 ; JUSB3.13 279.37,59.4 ; H13.1 158.32,86 ; H13.1 158.32,81.74 ; H13.1 159.88,82.31 ; H13.1 156.76,85.43 ; H13.1 156.19,83.87 ; H13.1 156.76,82.31 ; H13.1 160.46,83.87 ; H13.1 159.88,85.43 ; JHDMI1.17 217.6,103.72 ; JHDMI1.17 216.7,103.72 ; JHDMI1.17 217.15,103.61 ; JHDMI1.17 217.15,104.73 ; JHDMI1.17 217.6,104.62 ; JHDMI1.17 216.7,104.62 ; PBATT1.7 159.01,1.49 ; PBATT1.7 158.2,1.22 ; PBATT1.7 157.39,1.49 ; PBATT1.7 157.39,3.11 ; PBATT1.7 159.01,3.11 ; PBATT1.7 158.2,3.38 ; JDOCK1.159 109.76,108.48 ; JDOCK1.159 105.64,109.42 ; JDOCK1.159 105.64,108.48 ; JDOCK1.159 107.7,109.42 ; JDOCK1.159 107.7,107.53 ; JDOCK1.159 109.76,109.42 ; JDOCK1.159 105.64,107.53 ; 125.4,103.75 JDOCK1.156 ; JDOCK1.156 126.2,105.6 ; JDOCK1.156 126.2,103.5 ; JDOCK1.156 127.25,104.55 ; JDOCK1.156 127,103.75 ; JDOCK1.156 125.4,105.35 ; JDOCK1.156 127,105.35 ; JDOCK1.156 125.15,104.55 ; 137.15,109.45 JDOCK1.161 ; JDOCK1.161 137.15,108.48 ; JDOCK1.161 138.2,107.5 ; JDOCK1.161 139.25,109.45 ; JDOCK1.161 137.15,107.5 ; JDOCK1.161 139.25,108.48 ; JDOCK1.161 139.25,107.5 ; JDOCK1.161 138.2,109.45 ; 125.15,108.48 JDOCK1.160 ; JDOCK1.160 126.2,107.5 ; JDOCK1.160 125.15,107.5 ; JDOCK1.160 125.15,109.45 ; JDOCK1.160 127.25,108.48 ; JDOCK1.160 127.25,107.5 ; JDOCK1.160 127.25,109.45 ; JDOCK1.160 126.2,109.45 ; H7.1 147.89,3.7 ; H7.1 144.97,4.94 ; H7.1 145.41,3.7 ; H7.1 147.89,6.18 ; H7.1 148.33,4.94 ; H7.1 146.65,6.62 ; H7.1 145.41,6.18 ; H7.1 146.65,3.26 ; 64.07,100.39 JUSB1.10 ; JUSB1.10 64.07,98.61 ; JUSB1.10 64.95,96.84 ; JUSB1.10 65.83,96.84 ; JUSB1.10 64.07,96.84 ; JUSB1.10 65.83,98.61 ; JDOCK1.155 115.25,104.55 ; JDOCK1.155 115,103.75 ; JDOCK1.155 114.2,105.6 ; JDOCK1.155 113.4,105.35 ; JDOCK1.155 113.15,104.55 ; JDOCK1.155 114.2,103.5 ; JDOCK1.155 115,105.35 ; JDOCK1.155 113.4,103.75 ; SW1.5 183.06,76.16 ; SW1.5 183.3,75.4 ; SW1.5 182.3,76.4 ; SW1.5 181.54,76.16 ; SW1.5 181.3,75.4 ; SW1.5 182.3,74.39 ; SW1.5 181.54,74.63 ; SW1.5 183.06,74.63 ; H3.1 281.88,2.15 ; H3.1 281.44,0.91 ; H3.1 281.44,3.39 ; H3.1 278.96,0.91 ; H3.1 278.52,2.15 ; H3.1 280.2,3.83 ; H3.1 278.96,3.39 ; 271.44,76.66 JMDP1.22 ; JMDP1.22 274.06,76.66 ; JMDP1.22 271.44,77.43 ; JMDP1.22 271.44,75.88 ; JMDP1.22 272.75,77.43 ; 186.34,106.24 JUSB2.12 ; JUSB2.12 186.34,108.98 ; JUSB2.12 185.46,107.61 ; JUSB2.12 185.46,108.98 ; JUSB2.12 185.46,106.24 ; 71.01,99.64 JUSB1.7 ; JUSB1.7 72.39,99.64 ; JUSB1.7 72.24,99.11 ; JUSB1.7 71.16,99.11 ; JUSB1.7 71.7,98.96 ; PBATT1.6 161.01,1.49 ; PBATT1.6 161.01,3.11 ; PBATT1.6 160.2,3.38 ; PBATT1.6 159.39,3.11 ; PBATT1.6 160.2,1.22 ; PBATT1.6 159.39,1.49 ; 281.03,93.82 H1.1 ; H1.1 282.2,91.06 ; H1.1 283.37,93.82 ; H1.1 283.37,91.48 ; H1.1 282.2,94.24 ; H1.1 281.03,91.48 ; H1.1 280.61,92.65 ; 125.15,101.6 JDOCK1.152 ; JDOCK1.152 125.15,99.65 ; JDOCK1.152 127.25,99.65 ; JDOCK1.152 126.2,99.65 ; JDOCK1.152 127.25,100.62 ; JDOCK1.152 127.25,101.6 ; JDOCK1.152 125.15,100.62 ; JDOCK1.152 126.2,101.6 ; 279.37,75.1 JUSB3.12 ; JUSB3.12 282.03,75.98 ; JUSB3.12 279.37,75.98 ; JUSB3.12 282.03,75.1 ; JUSB3.12 280.7,75.98 ; JHDMI1.5 211.6,104.62 ; JHDMI1.5 211.15,104.73 ; JHDMI1.5 210.7,104.62 ; JHDMI1.5 211.6,103.72 ; JHDMI1.5 210.7,103.72 ; JHDMI1.5 211.15,103.61
  IN1 w0.508: v2(257.86,41.25) 257.86,39.79 259.32,38.33 v2(259.32,37.5)
  GND2 w0.203: 114.2,103.5 JDOCK1.155 ; JDOCK1.155 113.15,104.55 ; JDOCK1.155 113.4,105.35 ; JDOCK1.155 114.2,105.6 ; JDOCK1.155 115.25,104.55 ; JDOCK1.155 113.4,103.75 ; JDOCK1.155 115,103.75 ; JDOCK1.155 115,105.35 ; 213.7,104.62 JHDMI1.11 ; JHDMI1.11 213.7,103.72 ; JHDMI1.11 214.6,104.62 ; JHDMI1.11 214.15,103.61 ; JHDMI1.11 214.15,104.73 ; JHDMI1.11 214.6,103.72 ; 204.4,108.78 JHDMI1.22 ; JHDMI1.22 204.4,111.72 ; JHDMI1.22 203.52,111.72 ; JHDMI1.22 203.52,110.25 ; JHDMI1.22 205.28,111.72 ; JHDMI1.22 205.28,108.78 ; JHDMI1.22 203.52,108.78 ; JHDMI1.22 205.28,110.25 ; 209.2,102.52 JHDMI1.2 ; JHDMI1.2 209.65,102.41 ; JHDMI1.2 209.09,102.97 ; JHDMI1.2 210.1,103.42 ; JHDMI1.2 209.2,103.42 ; JHDMI1.2 209.65,103.53 ; JHDMI1.2 210.1,102.52 ; JHDMI1.20 207.28,103.4 ; JHDMI1.20 206.4,104.98 ; JHDMI1.20 205.52,104.98 ; JHDMI1.20 205.52,101.82 ; JHDMI1.20 206.4,101.82 ; JHDMI1.20 207.28,104.98 ; JHDMI1.20 207.28,101.82 ; JHDMI1.20 205.52,103.4 ; 78.37,5.05 H9.1 ; H9.1 78.86,6.39 ; H9.1 82.03,5.05 ; H9.1 80.2,6.88 ; H9.1 80.2,3.22 ; H9.1 78.86,3.71 ; H9.1 81.54,3.71 ; H9.1 81.54,6.39 ; 185.46,108.98 JUSB2.12 ; JUSB2.12 185.46,107.61 ; JUSB2.12 186.34,106.24 ; JUSB2.12 185.46,106.24 ; JUSB2.12 186.34,108.98 ; JDOCK1.153 139.25,101.6 ; JDOCK1.153 138.2,99.65 ; JDOCK1.153 139.25,100.62 ; JDOCK1.153 137.15,100.62 ; JDOCK1.153 139.25,99.65 ; JDOCK1.153 137.15,99.65 ; JDOCK1.153 138.2,101.6 ; JDOCK1.153 137.15,101.6 ; JUSB3.11 275.68,75.1 ; JUSB3.11 273.9,75.98 ; JUSB3.11 272.12,75.1 ; JUSB3.11 275.68,75.98 ; JUSB3.11 272.12,74.22 ; JHDMI1.8 213.1,103.42 ; JHDMI1.8 212.2,102.52 ; JHDMI1.8 212.65,102.41 ; JHDMI1.8 212.2,103.42 ; JHDMI1.8 213.1,102.52 ; JHDMI1.8 212.65,103.53 ; 100.86,83.87 H15.1 ; H15.1 104.56,85.43 ; H15.1 101.44,85.43 ; H15.1 104.56,82.31 ; H15.1 103,81.74 ; H15.1 105.13,83.87 ; H15.1 103,86 ; H15.1 101.44,82.31 ; JMDP1.7 274.05,82.69 ; JMDP1.7 273.01,83.16 ; JMDP1.7 273.13,82.69 ; JMDP1.7 273.59,82.57 ; JMDP1.7 274.05,83.62 ; JMDP1.7 273.13,83.62 ; JMDP1.7 274.17,83.16 ; 274.79,78.87 JMDP1.19 ; JMDP1.19 274.33,78.99 ; JMDP1.19 275.37,79.46 ; JMDP1.19 275.25,79.92 ; JMDP1.19 275.25,78.99 ; JMDP1.19 274.33,79.92 ; JMDP1.19 274.21,79.46 ; JDOCK1.152 127.25,101.6 ; JDOCK1.152 126.2,99.65 ; JDOCK1.152 126.2,101.6 ; JDOCK1.152 125.15,101.6 ; JDOCK1.152 127.25,100.62 ; JDOCK1.152 125.15,100.62 ; JDOCK1.152 125.15,99.65 ; JDOCK1.152 127.25,99.65 ; 181.54,74.63 SW1.5 ; SW1.5 183.3,75.4 ; SW1.5 181.54,76.16 ; SW1.5 183.06,76.16 ; SW1.5 181.3,75.4 ; SW1.5 183.06,74.63 ; SW1.5 182.3,74.39 ; SW1.5 182.3,76.4 ; 105.64,101.57 JDOCK1.151 ; JDOCK1.151 109.76,99.68 ; JDOCK1.151 109.76,100.62 ; JDOCK1.151 105.64,100.62 ; JDOCK1.151 107.7,101.57 ; 276.44,87.66 JMDP1.23 ; JMDP1.23 276.44,86.88 ; JMDP1.23 279.06,88.43 ; JMDP1.23 279.06,87.66 ; JMDP1.23 277.75,88.43 ; JMDP1.23 276.44,88.43 ; 274.21,84.86 JMDP1.1 ; JMDP1.1 274.33,84.39 ; JMDP1.1 275.37,84.86 ; JMDP1.1 275.25,85.32 ; JMDP1.1 274.79,85.44 ; JMDP1.1 275.25,84.39 ; JMDP1.1 274.33,85.32 ; 222.02,111.72 JHDMI1.23 ; JHDMI1.23 222.9,108.78 ; JHDMI1.23 222.02,108.78 ; JHDMI1.23 222.9,111.72 ; JHDMI1.23 223.78,111.72 ; JHDMI1.23 223.78,108.78 ; JHDMI1.23 223.78,110.25 ; JHDMI1.23 222.02,110.25 ; 149.15,104.55 JDOCK1.158 ; JDOCK1.158 149.4,103.75 ; JDOCK1.158 151,105.35 ; JDOCK1.158 150.2,105.6 ; JDOCK1.158 150.2,103.5 ; JDOCK1.158 151,103.75 ; JDOCK1.158 151.25,104.55 ; JDOCK1.158 149.4,105.35 ; H13.1 159.88,85.43 ; H13.1 160.46,83.87 ; H13.1 156.76,85.43 ; H13.1 156.76,82.31 ; H13.1 158.32,81.74 ; H13.1 159.88,82.31 ; H13.1 158.32,86 ; H13.1 156.19,83.87 ; 125.4,103.75 JDOCK1.156 ; JDOCK1.156 126.2,103.5 ; JDOCK1.156 127,105.35 ; JDOCK1.156 125.4,105.35 ; JDOCK1.156 127.25,104.55 ; JDOCK1.156 125.15,104.55 ; JDOCK1.156 127,103.75 ; JDOCK1.156 126.2,105.6 ; PBATT1.6 160.2,3.38 ; PBATT1.6 161.01,1.49 ; PBATT1.6 161.01,3.11 ; PBATT1.6 159.39,1.49 ; PBATT1.6 159.39,3.11 ; PBATT1.6 160.2,1.22 ; 77.57,96.84 JUSB1.11 ; JUSB1.11 79.33,96.84 ; JUSB1.11 77.57,98.61 ; JUSB1.11 79.33,100.39 ; JUSB1.11 78.45,96.84 ; JUSB1.11 79.33,98.61 ; 272.33,66.62 JUSB3.7 ; JUSB3.7 272.14,67.25 ; JUSB3.7 272.97,68.08 ; JUSB3.7 272.33,67.89 ; JUSB3.7 272.97,66.42 ; 270.83,71.39 JUSB3.4 ; JUSB3.4 272.1,70.12 ; JUSB3.4 270.64,70.75 ; JUSB3.4 271.47,71.58 ; JUSB3.4 271.47,69.92 ; JUSB3.4 270.83,70.12 ; 271.44,87.66 JMDP1.24 ; JMDP1.24 272.75,88.43 ; JMDP1.24 274.06,87.66 ; JMDP1.24 271.44,88.43 ; JMDP1.24 274.06,88.43 ; JMDP1.24 271.44,86.88 ; JMDP1.24 272.75,86.88 ; JUSB1.7 72.39,99.64 ; JUSB1.7 71.7,98.96 ; JUSB1.7 71.01,99.64 ; JUSB1.7 71.16,99.11 ; JUSB1.7 72.24,99.11 ; 278.96,3.39 H3.1 ; H3.1 281.44,3.39 ; H3.1 278.52,2.15 ; H3.1 278.96,0.91 ; H3.1 281.44,0.91 ; H3.1 280.2,3.83 ; H3.1 281.88,2.15 ; H12.1 50.53,86.15 ; H12.1 48.7,84.32 ; H12.1 48.7,87.98 ; H12.1 47.36,87.49 ; H12.1 46.87,86.15 ; H12.1 50.04,84.81 ; H12.1 47.36,84.81 ; H12.1 50.04,87.49 ; 182.3,68.09 SW1.4 ; SW1.4 181.54,69.86 ; SW1.4 181.54,68.33 ; SW1.4 183.06,68.33 ; SW1.4 183.3,69.09 ; SW1.4 182.3,70.1 ; SW1.4 181.3,69.09 ; SW1.4 183.06,69.86 ; JUSB2.13 202.92,107.61 ; JUSB2.13 202.04,108.98 ; JUSB2.13 202.92,106.24 ; JUSB2.13 202.04,106.24 ; JUSB2.13 202.92,108.98 ; 154.64,108.48 JDOCK1.162 ; JDOCK1.162 158.76,107.53 ; JDOCK1.162 154.64,109.42 ; JDOCK1.162 158.76,108.48 ; JDOCK1.162 156.7,109.42 ; JDOCK1.162 158.76,109.42 ; 218.86,68.49 H4.1 ; H4.1 221.54,65.81 ; H4.1 218.86,65.81 ; H4.1 221.54,68.49 ; H4.1 222.03,67.15 ; H4.1 220.2,68.98 ; H4.1 220.2,65.32 ; H4.1 218.37,67.15 ; 137.4,103.75 JDOCK1.157 ; JDOCK1.157 137.15,104.55 ; JDOCK1.157 139,103.75 ; JDOCK1.157 139,105.35 ; JDOCK1.157 138.2,103.5 ; JDOCK1.157 138.2,105.6 ; JDOCK1.157 139.25,104.55 ; JDOCK1.157 137.4,105.35 ; JUSB2.4 191.23,98.68 ; JUSB2.4 190.69,98.83 ; JUSB2.4 191.38,98.14 ; JUSB2.4 191.23,97.6 ; JUSB2.4 190.15,98.68 ; JUSB2.4 190.15,97.6 ; JUSB2.4 190.69,97.45 ; JUSB2.4 190,98.14 ; 193.5,99.64 JUSB2.7 ; JUSB2.7 194.19,98.95 ; JUSB2.7 194.73,99.1 ; JUSB2.7 193.65,99.1 ; JUSB2.7 194.88,99.64 ; JMDP1.21 279.06,76.66 ; JMDP1.21 276.44,77.43 ; JMDP1.21 276.44,75.88 ; JMDP1.21 279.06,75.88 ; JMDP1.21 277.75,75.88 ; JMDP1.21 276.44,76.66 ; H19.1 50.3,82.1 ; H19.1 48.1,79.9 ; H19.1 49.2,82.49 ; H19.1 49.2,79.51 ; H19.1 50.69,81 ; H19.1 47.71,81 ; H19.1 50.3,79.9 ; H19.1 48.1,82.1 ; H2.1 280.2,41.83 ; H2.1 278.52,40.15 ; H2.1 278.96,41.39 ; H2.1 278.96,38.91 ; H2.1 280.2,38.47 ; H2.1 281.44,38.91 ; H2.1 281.88,40.15 ; H2.1 281.44,41.39 ; 273.13,80.69 JMDP1.13 ; JMDP1.13 273.01,81.16 ; JMDP1.13 273.13,81.62 ; JMDP1.13 274.17,81.16 ; JMDP1.13 274.05,81.62 ; JMDP1.13 273.59,81.74 ; JMDP1.13 274.05,80.69 ; PBATT1.10 152.05,0.67 ; PBATT1.10 152.05,2.55 ; PBATT1.10 150.1,2.55 ; PBATT1.10 150.1,0.67 ; PBATT1.10 150.1,4.43 ; PBATT1.10 151.08,4.43 ; PBATT1.10 151.08,0.67 ; 180.33,63.63 ST2.1 ; ST2.1 183.37,63.63 ; ST2.1 181.85,63.07 ; ST2.1 181.85,67.23 ; ST2.1 183.93,65.15 ; ST2.1 183.37,66.67 ; ST2.1 180.33,66.67 ; ST2.1 179.77,65.15 ; JDOCK1.148 158.29,102.7 ; JDOCK1.148 157.37,102.7 ; JDOCK1.148 158.29,104.55 ; 145.41,3.7 H7.1 ; H7.1 146.65,6.62 ; H7.1 148.33,4.94 ; H7.1 147.89,3.7 ; H7.1 146.65,3.26 ; H7.1 144.97,4.94 ; H7.1 145.41,6.18 ; H7.1 147.89,6.18 ; 67.51,98.14 JUSB1.4 ; JUSB1.4 68.2,98.83 ; JUSB1.4 68.74,98.68 ; JUSB1.4 68.74,97.61 ; JUSB1.4 67.66,97.61 ; JUSB1.4 68.89,98.14 ; JUSB1.4 67.66,98.68 ; JUSB1.4 68.2,97.46 ; JUSB1.13 80.43,107.61 ; JUSB1.13 80.43,108.99 ; JUSB1.13 79.55,106.24 ; JUSB1.13 80.43,106.24 ; JUSB1.13 79.55,108.99 ; 154.64,100.62 JDOCK1.154 ; JDOCK1.154 158.76,100.62 ; JDOCK1.154 158.76,99.68 ; JDOCK1.154 156.7,99.68 ; JDOCK1.154 154.64,99.68 ; JDOCK1.154 158.76,101.57 ; JDOCK1.154 156.7,101.57 ; JUSB3.13 282.03,59.84 ; JUSB3.13 282.03,59.4 ; JUSB3.13 279.37,59.4 ; 225.37,108.55 H18.1 ; H18.1 227.2,106.72 ; H18.1 225.86,107.21 ; H18.1 228.54,109.89 ; H18.1 227.2,110.38 ; H18.1 225.86,109.89 ; H18.1 229.03,108.55 ; H18.1 228.54,107.21 ; 107.02,102.7 JDOCK1.145 ; JDOCK1.145 106.11,106.4 ; JDOCK1.145 107.02,106.4 ; JDOCK1.145 106.11,102.7 ; JDOCK1.145 106.11,104.55 ; ST3.1 69.73,44 ; ST3.1 66.69,47.04 ; ST3.1 66.69,44 ; ST3.1 70.29,45.52 ; ST3.1 69.73,47.04 ; ST3.1 66.13,45.52 ; ST3.1 68.21,43.44 ; ST3.1 68.21,47.6 ; 216.7,104.62 JHDMI1.17 ; JHDMI1.17 217.6,104.62 ; JHDMI1.17 216.7,103.72 ; JHDMI1.17 217.15,103.61 ; JHDMI1.17 217.15,104.73 ; JHDMI1.17 217.6,103.72 ; JUSB1.10 65.83,96.84 ; JUSB1.10 64.07,100.39 ; JUSB1.10 64.07,98.61 ; JUSB1.10 65.83,98.61 ; JUSB1.10 64.95,96.84 ; JUSB1.10 64.07,96.84 ; 105.64,109.42 JDOCK1.159 ; JDOCK1.159 105.64,108.48 ; JDOCK1.159 109.76,108.48 ; JDOCK1.159 107.7,107.53 ; JDOCK1.159 105.64,107.53 ; JDOCK1.159 107.7,109.42 ; JDOCK1.159 109.76,109.42 ; PBATT1.7 159.01,1.49 ; PBATT1.7 158.2,3.38 ; PBATT1.7 159.01,3.11 ; PBATT1.7 157.39,3.11 ; PBATT1.7 158.2,1.22 ; PBATT1.7 157.39,1.49 ; 272.12,59.4 JUSB3.10 ; JUSB3.10 275.68,59.4 ; JUSB3.10 272.12,60.28 ; H1.1 282.2,94.24 ; H1.1 281.03,91.48 ; H1.1 281.03,93.82 ; H1.1 283.37,91.48 ; H1.1 283.37,93.82 ; H1.1 280.61,92.65 ; H1.1 282.2,91.06 ; JUSB2.11 201.82,100.39 ; JUSB2.11 200.06,98.61 ; JUSB2.11 201.82,98.61 ; JUSB2.11 200.94,96.83 ; JUSB2.11 200.06,96.83 ; JUSB2.11 201.82,96.83 ; 211.17,34.3 H5.1 ; H5.1 211.66,35.64 ; H5.1 214.34,32.96 ; H5.1 213,32.47 ; H5.1 211.66,32.96 ; H5.1 214.34,35.64 ; H5.1 213,36.13 ; H5.1 214.83,34.3 ; JDOCK1.160 127.25,109.45 ; JDOCK1.160 126.2,109.45 ; JDOCK1.160 126.2,107.5 ; JDOCK1.160 127.25,108.48 ; JDOCK1.160 127.25,107.5 ; JDOCK1.160 125.15,108.48 ; JDOCK1.160 125.15,109.45 ; JDOCK1.160 125.15,107.5 ; 210.7,103.72 JHDMI1.5 ; JHDMI1.5 211.15,104.73 ; JHDMI1.5 211.6,103.72 ; JHDMI1.5 211.6,104.62 ; JHDMI1.5 211.15,103.61 ; JHDMI1.5 210.7,104.62 ; JUSB3.12 282.03,75.1 ; JUSB3.12 279.37,75.98 ; JUSB3.12 282.03,75.98 ; JUSB3.12 279.37,75.1 ; JUSB3.12 280.7,75.98 ; H6.1 185.94,12.63 ; H6.1 185.94,15.31 ; H6.1 183.26,15.31 ; H6.1 182.77,13.97 ; H6.1 184.6,12.14 ; H6.1 186.43,13.97 ; H6.1 183.26,12.63 ; H6.1 184.6,15.8 ; 173.33,0.67 PBATT1.11 ; PBATT1.11 174.3,0.67 ; PBATT1.11 172.35,0.67 ; PBATT1.11 174.3,4.43 ; PBATT1.11 174.3,2.55 ; PBATT1.11 173.33,4.43 ; PBATT1.11 172.35,2.55 ; PBATT1.11 172.35,4.43 ; 220.02,104.98 JHDMI1.21 ; JHDMI1.21 220.9,104.98 ; JHDMI1.21 221.78,101.82 ; JHDMI1.21 220.02,103.4 ; JHDMI1.21 220.9,101.82 ; JHDMI1.21 221.78,103.4 ; JHDMI1.21 221.78,104.98 ; JHDMI1.21 220.02,101.82 ; H10.1 44.2,40.98 ; H10.1 42.86,37.81 ; H10.1 45.54,40.49 ; H10.1 42.86,40.49 ; H10.1 42.37,39.15 ; H10.1 44.2,37.32 ; H10.1 46.03,39.15 ; H10.1 45.54,37.81 ; 156.76,60.17 H14.1 ; H14.1 159.88,60.17 ; H14.1 159.88,63.29 ; H14.1 158.32,63.86 ; H14.1 160.46,61.73 ; H14.1 156.19,61.73 ; H14.1 158.32,59.6 ; H14.1 156.76,63.29 ; H8.1 131.03,19.65 ; H8.1 129.2,17.82 ; H8.1 127.86,20.99 ; H8.1 127.37,19.65 ; H8.1 129.2,21.48 ; H8.1 127.86,18.31 ; H8.1 130.54,20.99 ; H8.1 130.54,18.31 ; PBATT1.9 155.01,1.49 ; PBATT1.9 155.01,3.11 ; PBATT1.9 153.39,3.11 ; PBATT1.9 154.2,1.22 ; PBATT1.9 154.2,3.38 ; PBATT1.9 153.39,1.49 ; PBATT1.9 153.12,2.3 ; JDOCK1.161 139.25,109.45 ; JDOCK1.161 137.15,108.48 ; JDOCK1.161 138.2,109.45 ; JDOCK1.161 137.15,107.5 ; JDOCK1.161 139.25,107.5 ; JDOCK1.161 139.25,108.48 ; JDOCK1.161 138.2,107.5 ; JDOCK1.161 137.15,109.45 ; JUSB1.12 63.85,108.99 ; JUSB1.12 63.85,106.24 ; JUSB1.12 62.97,108.99 ; JUSB1.12 62.97,106.24 ; JUSB1.12 62.97,107.61 ; H17.1 75.43,64.05 ; H17.1 73.6,65.88 ; H17.1 73.6,62.22 ; H17.1 72.26,62.71 ; H17.1 72.26,65.39 ; H17.1 74.94,65.39 ; H17.1 74.94,62.71 ; H17.1 71.77,64.05 ; H16.1 105.13,61.73 ; H16.1 103,59.6 ; H16.1 103,63.86 ; H16.1 100.86,61.73 ; H16.1 104.56,63.29 ; H16.1 101.44,60.17 ; H16.1 101.44,63.29 ; H16.1 104.56,60.17 ; JMDP1.22 272.75,77.43 ; JMDP1.22 271.44,77.43 ; JMDP1.22 271.44,76.66 ; JMDP1.22 274.06,76.66 ; JMDP1.22 271.44,75.88 ; 156.2,1.22 PBATT1.8 ; PBATT1.8 157.01,3.11 ; PBATT1.8 156.2,3.38 ; PBATT1.8 157.01,1.49 ; PBATT1.8 155.39,1.49 ; PBATT1.8 155.39,3.11 ; 187.44,96.83 JUSB2.10 ; JUSB2.10 188.32,98.61 ; JUSB2.10 188.32,96.83 ; JUSB2.10 186.56,100.39 ; JUSB2.10 186.56,98.61 ; JUSB2.10 186.56,96.83
  VCC w0.203: 127.86,18.31 H8.1 ; H8.1 130.54,20.99 ; H8.1 129.2,21.48 ; H8.1 131.03,19.65 ; H8.1 130.54,18.31 ; H8.1 127.86,20.99 ; H8.1 127.37,19.65 ; H8.1 129.2,17.82 ; 271.44,76.66 JMDP1.22 ; JMDP1.22 274.06,76.66 ; JMDP1.22 271.44,77.43 ; JMDP1.22 271.44,75.88 ; JMDP1.22 272.75,77.43 ; JUSB2.4 191.23,98.68 ; JUSB2.4 190,98.14 ; JUSB2.4 191.38,98.14 ; JUSB2.4 190.15,97.6 ; JUSB2.4 190.69,97.45 ; JUSB2.4 190.69,98.83 ; JUSB2.4 191.23,97.6 ; JUSB2.4 190.15,98.68 ; JHDMI1.5 211.6,103.72 ; JHDMI1.5 210.7,103.72 ; JHDMI1.5 211.15,103.61 ; 71.7,98.96 JUSB1.7 ; JUSB1.7 72.24,99.11 ; JUSB1.7 71.16,99.11 ; 270.83,70.12 JUSB3.4 ; JUSB3.4 270.64,70.75 ; JUSB3.4 270.83,71.39 ; JUSB3.4 271.47,69.92 ; JUSB3.4 272.1,70.12 ; JUSB3.4 271.47,71.58 ; 272.12,75.1 JUSB3.11 ; JUSB3.11 272.12,74.22 ; JUSB3.11 273.9,75.98 ; JUSB3.11 275.68,75.98 ; JHDMI1.20 207.28,101.82 ; JHDMI1.20 205.52,101.82 ; JHDMI1.20 207.28,103.4 ; JHDMI1.20 205.52,103.4 ; JHDMI1.20 206.4,101.82 ; 200.06,98.61 JUSB2.11 ; JUSB2.11 200.06,96.83 ; JUSB2.11 201.82,98.61 ; JUSB2.11 201.82,96.83 ; JUSB2.11 200.94,96.83 ; JUSB2.13 202.92,107.61 ; JUSB2.13 202.92,108.98 ; JUSB2.13 202.04,106.24 ; JUSB2.13 202.92,106.24 ; JUSB2.13 202.04,108.98 ; 273.13,82.69 JMDP1.7 ; JMDP1.7 274.05,83.62 ; JMDP1.7 273.59,82.57 ; JMDP1.7 274.17,83.16 ; JMDP1.7 273.01,83.16 ; JMDP1.7 273.13,83.62 ; JMDP1.7 274.05,82.69 ; 185.46,107.61 JUSB2.12 ; JUSB2.12 185.46,108.98 ; JUSB2.12 186.34,108.98 ; JUSB2.12 185.46,106.24 ; JUSB2.12 186.34,106.24 ; 225.86,109.89 H18.1 ; H18.1 227.2,106.72 ; H18.1 227.2,110.38 ; H18.1 229.03,108.55 ; H18.1 228.54,109.89 ; H18.1 225.37,108.55 ; H18.1 225.86,107.21 ; H18.1 228.54,107.21 ; JHDMI1.2 210.1,103.42 ; JHDMI1.2 209.65,102.41 ; JHDMI1.2 209.09,102.97 ; JHDMI1.2 209.2,102.52 ; JHDMI1.2 209.2,103.42 ; JHDMI1.2 209.65,103.53 ; JHDMI1.2 210.1,102.52 ; JMDP1.13 274.05,80.69 ; JMDP1.13 274.17,81.16 ; JMDP1.13 273.01,81.16 ; JMDP1.13 274.05,81.62 ; JMDP1.13 273.59,81.74 ; JMDP1.13 273.13,81.62 ; JMDP1.13 273.13,80.69 ; 216.7,103.72 JHDMI1.17 ; JHDMI1.17 217.15,103.61 ; JHDMI1.17 217.6,103.72 ; JUSB3.13 282.03,59.84 ; JUSB3.13 282.03,59.4 ; JUSB3.13 279.37,59.4 ; ST3.1 70.29,45.52 ; ST3.1 68.21,43.44 ; ST3.1 66.13,45.52 ; ST3.1 66.69,44 ; ST3.1 69.73,47.04 ; ST3.1 68.21,47.6 ; ST3.1 69.73,44 ; JMDP1.1 275.37,84.86 ; JMDP1.1 274.79,85.44 ; JMDP1.1 275.25,84.39 ; JMDP1.1 275.25,85.32 ; JMDP1.1 274.33,84.39 ; JMDP1.1 274.21,84.86 ; JMDP1.1 274.33,85.32 ; JHDMI1.23 223.78,110.25 ; JHDMI1.23 222.9,108.78 ; JHDMI1.23 222.9,111.72 ; JHDMI1.23 223.78,108.78 ; JHDMI1.23 223.78,111.72 ; JUSB3.12 282.03,75.98 ; JUSB3.12 280.7,75.98 ; JUSB3.12 279.37,75.98 ; 276.44,75.88 JMDP1.21 ; JMDP1.21 279.06,76.66 ; JMDP1.21 277.75,75.88 ; JMDP1.21 279.06,75.88 ; JMDP1.21 276.44,76.66 ; 212.2,103.42 JHDMI1.8 ; JHDMI1.8 212.2,102.52 ; JHDMI1.8 213.1,102.52 ; JHDMI1.8 212.65,102.41 ; JHDMI1.8 213.1,103.42 ; JHDMI1.8 212.65,103.53 ; JUSB1.11 79.33,96.84 ; JUSB1.11 77.57,98.61 ; JUSB1.11 79.33,98.61 ; JUSB1.11 77.57,96.84 ; JUSB1.11 78.45,96.84 ; JUSB1.10 65.83,96.84 ; JUSB1.10 65.83,98.61 ; JUSB1.10 64.07,96.84 ; JUSB1.10 64.07,98.61 ; JUSB1.10 64.95,96.84 ; 220.9,101.82 JHDMI1.21 ; JHDMI1.21 220.02,101.82 ; JHDMI1.21 221.78,103.4 ; JHDMI1.21 220.02,103.4 ; JHDMI1.21 221.78,101.82 ; JUSB1.4 68.74,98.68 ; JUSB1.4 68.89,98.14 ; JUSB1.4 68.74,97.61 ; JUSB1.4 67.51,98.14 ; JUSB1.4 67.66,97.61 ; JUSB1.4 68.2,98.83 ; JUSB1.4 67.66,98.68 ; JUSB1.4 68.2,97.46 ; 186.56,98.61 JUSB2.10 ; JUSB2.10 186.56,96.83 ; JUSB2.10 188.32,96.83 ; JUSB2.10 188.32,98.61 ; JUSB2.10 187.44,96.83 ; 203.52,108.78 JHDMI1.22 ; JHDMI1.22 203.52,110.25 ; JHDMI1.22 204.4,108.78 ; JHDMI1.22 203.52,111.72 ; JHDMI1.22 204.4,111.72 ; 272.14,67.25 JUSB3.7 ; JUSB3.7 272.33,67.89 ; JUSB3.7 272.33,66.62 ; JMDP1.24 274.06,88.43 ; JMDP1.24 271.44,87.66 ; JMDP1.24 271.44,88.43 ; JMDP1.24 272.75,86.88 ; JMDP1.24 272.75,88.43 ; JMDP1.24 274.06,87.66 ; JMDP1.24 271.44,86.88 ; 272.12,60.28 JUSB3.10 ; JUSB3.10 275.68,59.4 ; JUSB3.10 272.12,59.4 ; 274.33,78.99 JMDP1.19 ; JMDP1.19 275.25,78.99 ; JMDP1.19 274.79,78.87 ; JMDP1.19 274.33,79.92 ; JMDP1.19 275.25,79.92 ; JMDP1.19 275.37,79.46 ; JMDP1.19 274.21,79.46 ; JMDP1.23 279.06,87.66 ; JMDP1.23 279.06,88.43 ; JMDP1.23 276.44,87.66 ; JMDP1.23 277.75,88.43 ; JMDP1.23 276.44,88.43 ; JHDMI1.11 214.6,103.72 ; JHDMI1.11 214.15,103.61 ; JHDMI1.11 213.7,103.72 ; 78.86,3.71 H9.1 ; H9.1 78.86,6.39 ; H9.1 80.2,6.88 ; H9.1 78.37,5.05 ; H9.1 80.2,3.22 ; JUSB1.13 79.55,108.99 ; JUSB1.13 79.55,106.24 ; JUSB1.13 79.99,108.99 ; 63.41,106.24 JUSB1.12 ; JUSB1.12 63.85,108.99 ; JUSB1.12 63.85,106.24 ; 193.65,99.1 JUSB2.7 ; JUSB2.7 194.19,98.95 ; JUSB2.7 194.73,99.1
  IN4 w0.508: v2(262.22,49.83) v2(262.98,49.83) v2(266.14,49.83)
  GND3 w0.203: PBATT1.7 158.2,3.38 ; PBATT1.7 158.2,1.22 ; PBATT1.7 157.39,3.11 ; PBATT1.7 157.39,1.49 ; PBATT1.7 159.01,1.49 ; PBATT1.7 159.01,3.11 ; 274.33,78.99 JMDP1.19 ; JMDP1.19 274.21,79.46 ; JMDP1.19 275.25,79.92 ; JMDP1.19 275.37,79.46 ; JMDP1.19 275.25,78.99 ; JMDP1.19 274.33,79.92 ; JMDP1.19 274.79,78.87 ; H10.1 46.03,39.15 ; H10.1 44.2,40.98 ; H10.1 42.86,40.49 ; H10.1 42.86,37.81 ; H10.1 45.54,40.49 ; H10.1 42.37,39.15 ; H10.1 45.54,37.81 ; H10.1 44.2,37.32 ; 187.44,96.83 JUSB2.10 ; JUSB2.10 188.32,98.61 ; JUSB2.10 186.56,100.39 ; JUSB2.10 188.32,96.83 ; JUSB2.10 186.56,96.83 ; JUSB2.10 186.56,98.61 ; 62.97,108.99 JUSB1.12 ; JUSB1.12 62.97,107.61 ; JUSB1.12 62.97,106.24 ; JUSB1.12 63.85,108.99 ; JUSB1.12 63.85,106.24 ; JUSB3.13 282.03,59.4 ; JUSB3.13 282.03,59.84 ; JUSB3.13 279.37,59.4 ; JHDMI1.17 217.15,104.73 ; JHDMI1.17 217.15,103.61 ; JHDMI1.17 216.7,104.62 ; JHDMI1.17 216.7,103.72 ; JHDMI1.17 217.6,103.72 ; JHDMI1.17 217.6,104.62 ; 153.39,1.49 PBATT1.9 ; PBATT1.9 154.2,1.22 ; PBATT1.9 155.01,1.49 ; PBATT1.9 153.12,2.3 ; PBATT1.9 155.01,3.11 ; PBATT1.9 153.39,3.11 ; PBATT1.9 154.2,3.38 ; H18.1 228.54,109.89 ; H18.1 229.03,108.55 ; H18.1 227.2,106.72 ; H18.1 225.86,107.21 ; H18.1 225.86,109.89 ; H18.1 228.54,107.21 ; H18.1 227.2,110.38 ; H18.1 225.37,108.55 ; 125.15,101.6 JDOCK1.152 ; JDOCK1.152 125.15,99.65 ; JDOCK1.152 126.2,101.6 ; JDOCK1.152 127.25,100.62 ; JDOCK1.152 127.25,99.65 ; JDOCK1.152 126.2,99.65 ; JDOCK1.152 127.25,101.6 ; JDOCK1.152 125.15,100.62 ; JHDMI1.20 207.28,101.82 ; JHDMI1.20 205.52,103.4 ; JHDMI1.20 206.4,101.82 ; JHDMI1.20 207.28,104.98 ; JHDMI1.20 205.52,101.82 ; JHDMI1.20 205.52,104.98 ; JHDMI1.20 207.28,103.4 ; JHDMI1.20 206.4,104.98 ; 209.65,102.41 JHDMI1.2 ; JHDMI1.2 209.2,103.42 ; JHDMI1.2 210.1,103.42 ; JHDMI1.2 210.1,102.52 ; JHDMI1.2 209.65,103.53 ; JHDMI1.2 209.09,102.97 ; JHDMI1.2 209.2,102.52 ; 127.37,19.65 H8.1 ; H8.1 130.54,18.31 ; H8.1 127.86,18.31 ; H8.1 127.86,20.99 ; H8.1 130.54,20.99 ; H8.1 129.2,21.48 ; H8.1 129.2,17.82 ; H8.1 131.03,19.65 ; PBATT1.10 152.05,2.55 ; PBATT1.10 151.08,0.67 ; PBATT1.10 150.1,2.55 ; PBATT1.10 152.05,0.67 ; PBATT1.10 150.1,4.43 ; PBATT1.10 151.08,4.43 ; PBATT1.10 150.1,0.67 ; H3.1 281.44,0.91 ; H3.1 281.44,3.39 ; H3.1 281.88,2.15 ; H3.1 278.96,3.39 ; H3.1 278.96,0.91 ; H3.1 278.52,2.15 ; H3.1 280.2,3.83 ; SW1.4 183.06,69.86 ; SW1.4 182.3,68.09 ; SW1.4 182.3,70.1 ; SW1.4 183.06,68.33 ; SW1.4 181.54,69.86 ; SW1.4 181.3,69.09 ; SW1.4 183.3,69.09 ; SW1.4 181.54,68.33 ; 273.01,81.16 JMDP1.13 ; JMDP1.13 273.59,81.74 ; JMDP1.13 274.05,81.62 ; JMDP1.13 273.13,80.69 ; JMDP1.13 274.17,81.16 ; JMDP1.13 273.13,81.62 ; JMDP1.13 274.05,80.69 ; JMDP1.21 279.06,76.66 ; JMDP1.21 276.44,76.66 ; JMDP1.21 276.44,75.88 ; JMDP1.21 277.75,75.88 ; JMDP1.21 276.44,77.43 ; JMDP1.21 279.06,75.88 ; H2.1 281.44,41.39 ; H2.1 281.44,38.91 ; H2.1 278.52,40.15 ; H2.1 280.2,41.83 ; H2.1 281.88,40.15 ; H2.1 280.2,38.47 ; H2.1 278.96,38.91 ; H2.1 278.96,41.39 ; JDOCK1.156 127.25,104.55 ; JDOCK1.156 127,105.35 ; JDOCK1.156 126.2,105.6 ; JDOCK1.156 125.4,103.75 ; JDOCK1.156 126.2,103.5 ; JDOCK1.156 125.4,105.35 ; JDOCK1.156 127,103.75 ; JDOCK1.156 125.15,104.55 ; 64.07,100.39 JUSB1.10 ; JUSB1.10 64.95,96.84 ; JUSB1.10 65.83,98.61 ; JUSB1.10 64.07,98.61 ; JUSB1.10 65.83,96.84 ; JUSB1.10 64.07,96.84 ; JDOCK1.151 107.7,101.57 ; JDOCK1.151 105.64,100.62 ; JDOCK1.151 109.76,99.68 ; JDOCK1.151 109.76,100.62 ; JDOCK1.151 105.64,101.57 ; 145.41,3.7 H7.1 ; H7.1 146.65,3.26 ; H7.1 146.65,6.62 ; H7.1 147.89,3.7 ; H7.1 147.89,6.18 ; H7.1 148.33,4.94 ; H7.1 144.97,4.94 ; H7.1 145.41,6.18 ; H15.1 104.56,85.43 ; H15.1 105.13,83.87 ; H15.1 104.56,82.31 ; H15.1 101.44,82.31 ; H15.1 103,81.74 ; H15.1 103,86 ; H15.1 100.86,83.87 ; H15.1 101.44,85.43 ; JDOCK1.157 139,105.35 ; JDOCK1.157 139,103.75 ; JDOCK1.157 139.25,104.55 ; JDOCK1.157 137.4,105.35 ; JDOCK1.157 137.15,104.55 ; JDOCK1.157 138.2,103.5 ; JDOCK1.157 137.4,103.75 ; JDOCK1.157 138.2,105.6 ; 78.86,6.39 H9.1 ; H9.1 82.03,5.05 ; H9.1 80.2,6.88 ; H9.1 78.37,5.05 ; H9.1 81.54,6.39 ; H9.1 78.86,3.71 ; H9.1 80.2,3.22 ; H9.1 81.54,3.71 ; 77.57,96.84 JUSB1.11 ; JUSB1.11 79.33,98.61 ; JUSB1.11 79.33,100.39 ; JUSB1.11 78.45,96.84 ; JUSB1.11 77.57,98.61 ; JUSB1.11 79.33,96.84 ; 218.86,65.81 H4.1 ; H4.1 222.03,67.15 ; H4.1 220.2,65.32 ; H4.1 221.54,65.81 ; H4.1 221.54,68.49 ; H4.1 220.2,68.98 ; H4.1 218.37,67.15 ; H4.1 218.86,68.49 ; JUSB2.4 190.69,98.83 ; JUSB2.4 191.38,98.14 ; JUSB2.4 190.15,98.68 ; JUSB2.4 190,98.14 ; JUSB2.4 190.15,97.6 ; JUSB2.4 191.23,97.6 ; JUSB2.4 190.69,97.45 ; JUSB2.4 191.23,98.68 ; JUSB2.12 186.34,108.98 ; JUSB2.12 186.34,106.24 ; JUSB2.12 185.46,108.98 ; JUSB2.12 185.46,107.61 ; JUSB2.12 185.46,106.24 ; PBATT1.11 174.3,4.43 ; PBATT1.11 172.35,4.43 ; PBATT1.11 173.33,0.67 ; PBATT1.11 172.35,2.55 ; PBATT1.11 174.3,2.55 ; PBATT1.11 173.33,4.43 ; PBATT1.11 174.3,0.67 ; PBATT1.11 172.35,0.67 ; 137.15,108.48 JDOCK1.161 ; JDOCK1.161 138.2,107.5 ; JDOCK1.161 137.15,107.5 ; JDOCK1.161 139.25,108.48 ; JDOCK1.161 139.25,109.45 ; JDOCK1.161 137.15,109.45 ; JDOCK1.161 139.25,107.5 ; JDOCK1.161 138.2,109.45 ; JUSB3.11 273.9,75.98 ; JUSB3.11 275.68,75.98 ; JUSB3.11 272.12,74.22 ; JUSB3.11 272.12,75.1 ; JUSB3.11 275.68,75.1 ; 279.37,75.1 JUSB3.12 ; JUSB3.12 280.7,75.98 ; JUSB3.12 282.03,75.98 ; JUSB3.12 279.37,75.98 ; JUSB3.12 282.03,75.1 ; JUSB2.7 194.88,99.64 ; JUSB2.7 194.19,98.95 ; JUSB2.7 193.65,99.1 ; JUSB2.7 193.5,99.64 ; JUSB2.7 194.73,99.1 ; 106.11,102.7 JDOCK1.145 ; JDOCK1.145 107.02,106.4 ; JDOCK1.145 106.11,106.4 ; JDOCK1.145 107.02,102.7 ; JDOCK1.145 106.11,104.55 ; JUSB1.13 79.55,108.99 ; JUSB1.13 79.55,106.24 ; JUSB1.13 80.43,108.99 ; JUSB1.13 80.43,106.24 ; JUSB1.13 80.43,107.61 ; JDOCK1.154 156.7,101.57 ; JDOCK1.154 158.76,101.57 ; JDOCK1.154 158.76,100.62 ; JDOCK1.154 158.76,99.68 ; JDOCK1.154 154.64,99.68 ; JDOCK1.154 154.64,100.62 ; JDOCK1.154 156.7,99.68 ; 276.44,87.66 JMDP1.23 ; JMDP1.23 279.06,88.43 ; JMDP1.23 276.44,86.88 ; JMDP1.23 277.75,88.43 ; JMDP1.23 279.06,87.66 ; JMDP1.23 276.44,88.43 ; 212.65,102.41 JHDMI1.8 ; JHDMI1.8 213.1,103.42 ; JHDMI1.8 212.2,102.52 ; JHDMI1.8 212.65,103.53 ; JHDMI1.8 212.2,103.42 ; JHDMI1.8 213.1,102.52 ; H12.1 50.04,87.49 ; H12.1 47.36,87.49 ; H12.1 48.7,84.32 ; H12.1 46.87,86.15 ; H12.1 48.7,87.98 ; H12.1 47.36,84.81 ; H12.1 50.04,84.81 ; H12.1 50.53,86.15 ; JDOCK1.162 158.76,107.53 ; JDOCK1.162 158.76,108.48 ; JDOCK1.162 156.7,109.42 ; JDOCK1.162 154.64,108.48 ; JDOCK1.162 158.76,109.42 ; JDOCK1.162 154.64,109.42 ; 68.21,43.44 ST3.1 ; ST3.1 66.69,44 ; ST3.1 66.13,45.52 ; ST3.1 69.73,47.04 ; ST3.1 68.21,47.6 ; ST3.1 70.29,45.52 ; ST3.1 69.73,44 ; ST3.1 66.69,47.04 ; 107.7,107.53 JDOCK1.159 ; JDOCK1.159 109.76,108.48 ; JDOCK1.159 107.7,109.42 ; JDOCK1.159 109.76,109.42 ; JDOCK1.159 105.64,108.48 ; JDOCK1.159 105.64,107.53 ; JDOCK1.159 105.64,109.42 ; 200.06,98.61 JUSB2.11 ; JUSB2.11 201.82,98.61 ; JUSB2.11 200.94,96.83 ; JUSB2.11 201.82,100.39 ; JUSB2.11 200.06,96.83 ; JUSB2.11 201.82,96.83 ; JHDMI1.21 221.78,104.98 ; JHDMI1.21 220.02,104.98 ; JHDMI1.21 221.78,103.4 ; JHDMI1.21 221.78,101.82 ; JHDMI1.21 220.9,104.98 ; JHDMI1.21 220.02,103.4 ; JHDMI1.21 220.02,101.82 ; JHDMI1.21 220.9,101.82 ; 156.76,63.29 H14.1 ; H14.1 159.88,60.17 ; H14.1 158.32,59.6 ; H14.1 156.19,61.73 ; H14.1 158.32,63.86 ; H14.1 160.46,61.73 ; H14.1 156.76,60.17 ; H14.1 159.88,63.29 ; JDOCK1.158 151,103.75 ; JDOCK1.158 151,105.35 ; JDOCK1.158 149.15,104.55 ; JDOCK1.158 149.4,103.75 ; JDOCK1.158 150.2,105.6 ; JDOCK1.158 151.25,104.55 ; JDOCK1.158 149.4,105.35 ; JDOCK1.158 150.2,103.5 ; 270.64,70.75 JUSB3.4 ; JUSB3.4 270.83,71.39 ; JUSB3.4 271.47,71.58 ; JUSB3.4 270.83,70.12 ; JUSB3.4 272.1,70.12 ; JUSB3.4 271.47,69.92 ; 273.13,82.69 JMDP1.7 ; JMDP1.7 274.17,83.16 ; JMDP1.7 273.59,82.57 ; JMDP1.7 273.13,83.62 ; JMDP1.7 274.05,83.62 ; JMDP1.7 273.01,83.16 ; JMDP1.7 274.05,82.69 ; JHDMI1.22 205.28,108.78 ; JHDMI1.22 205.28,111.72 ; JHDMI1.22 204.4,111.72 ; JHDMI1.22 203.52,110.25 ; JHDMI1.22 203.52,111.72 ; JHDMI1.22 203.52,108.78 ; JHDMI1.22 204.4,108.78 ; JHDMI1.22 205.28,110.25 ; 158.32,81.74 H13.1 ; H13.1 160.46,83.87 ; H13.1 156.76,85.43 ; H13.1 158.32,86 ; H13.1 159.88,85.43 ; H13.1 159.88,82.31 ; H13.1 156.19,83.87 ; H13.1 156.76,82.31 ; 71.01,99.64 JUSB1.7 ; JUSB1.7 71.16,99.11 ; JUSB1.7 71.7,98.96 ; JUSB1.7 72.24,99.11 ; JUSB1.7 72.39,99.64 ; JDOCK1.153 139.25,100.62 ; JDOCK1.153 137.15,99.65 ; JDOCK1.153 139.25,101.6 ; JDOCK1.153 139.25,99.65 ; JDOCK1.153 137.15,100.62 ; JDOCK1.153 138.2,99.65 ; JDOCK1.153 137.15,101.6 ; JDOCK1.153 138.2,101.6 ; SW1.5 183.06,76.16 ; SW1.5 182.3,76.4 ; SW1.5 181.54,76.16 ; SW1.5 181.54,74.63 ; SW1.5 181.3,75.4 ; SW1.5 182.3,74.39 ; SW1.5 183.06,74.63 ; SW1.5 183.3,75.4 ; PBATT1.8 157.01,1.49 ; PBATT1.8 156.2,1.22 ; PBATT1.8 155.39,3.11 ; PBATT1.8 156.2,3.38 ; PBATT1.8 157.01,3.11 ; PBATT1.8 155.39,1.49 ; 281.03,91.48 H1.1 ; H1.1 282.2,91.06 ; H1.1 282.2,94.24 ; H1.1 280.61,92.65 ; H1.1 281.03,93.82 ; H1.1 283.37,91.48 ; H1.1 283.37,93.82 ; 180.33,66.67 ST2.1 ; ST2.1 183.93,65.15 ; ST2.1 181.85,67.23 ; ST2.1 181.85,63.07 ; ST2.1 180.33,63.63 ; ST2.1 183.37,63.63 ; ST2.1 179.77,65.15 ; ST2.1 183.37,66.67 ; 47.71,81 H19.1 ; H19.1 48.1,82.1 ; H19.1 49.2,82.49 ; H19.1 48.1,79.9 ; H19.1 50.3,82.1 ; H19.1 50.3,79.9 ; H19.1 49.2,79.51 ; H19.1 50.69,81 ; JUSB2.13 202.92,107.61 ; JUSB2.13 202.92,106.24 ; JUSB2.13 202.92,108.98 ; JUSB2.13 202.04,106.24 ; JUSB2.13 202.04,108.98 ; H17.1 74.94,65.39 ; H17.1 73.6,65.88 ; H17.1 72.26,65.39 ; H17.1 71.77,64.05 ; H17.1 73.6,62.22 ; H17.1 75.43,64.05 ; H17.1 72.26,62.71 ; H17.1 74.94,62.71 ; 272.12,59.4 JUSB3.10 ; JUSB3.10 275.68,59.4 ; JUSB3.10 272.12,60.28 ; JHDMI1.11 214.6,103.72 ; JHDMI1.11 214.15,104.73 ; JHDMI1.11 213.7,103.72 ; JHDMI1.11 214.6,104.62 ; JHDMI1.11 214.15,103.61 ; JHDMI1.11 213.7,104.62 ; 183.26,12.63 H6.1 ; H6.1 184.6,15.8 ; H6.1 184.6,12.14 ; H6.1 185.94,12.63 ; H6.1 185.94,15.31 ; H6.1 183.26,15.31 ; H6.1 186.43,13.97 ; H6.1 182.77,13.97 ; 274.21,84.86 JMDP1.1 ; JMDP1.1 275.25,84.39 ; JMDP1.1 274.79,85.44 ; JMDP1.1 275.37,84.86 ; JMDP1.1 274.33,85.32 ; JMDP1.1 275.25,85.32 ; JMDP1.1 274.33,84.39 ; JHDMI1.5 211.6,103.72 ; JHDMI1.5 211.15,104.73 ; JHDMI1.5 210.7,104.62 ; JHDMI1.5 210.7,103.72 ; JHDMI1.5 211.6,104.62 ; JHDMI1.5 211.15,103.61 ; H16.1 104.56,63.29 ; H16.1 101.44,60.17 ; H16.1 103,63.86 ; H16.1 103,59.6 ; H16.1 105.13,61.73 ; H16.1 101.44,63.29 ; H16.1 104.56,60.17 ; H16.1 100.86,61.73 ; JDOCK1.160 127.25,109.45 ; JDOCK1.160 126.2,107.5 ; JDOCK1.160 127.25,108.48 ; JDOCK1.160 125.15,109.45 ; JDOCK1.160 125.15,108.48 ; JDOCK1.160 125.15,107.5 ; JDOCK1.160 126.2,109.45 ; JDOCK1.160 127.25,107.5 ; JUSB1.4 68.74,97.61 ; JUSB1.4 67.66,97.61 ; JUSB1.4 68.89,98.14 ; JUSB1.4 68.74,98.68 ; JUSB1.4 67.66,98.68 ; JUSB1.4 68.2,98.83 ; JUSB1.4 67.51,98.14 ; JUSB1.4 68.2,97.46 ; 271.44,86.88 JMDP1.24 ; JMDP1.24 271.44,88.43 ; JMDP1.24 274.06,87.66 ; JMDP1.24 272.75,86.88 ; JMDP1.24 274.06,88.43 ; JMDP1.24 271.44,87.66 ; JMDP1.24 272.75,88.43 ; 271.44,77.43 JMDP1.22 ; JMDP1.22 271.44,75.88 ; JMDP1.22 271.44,76.66 ; JMDP1.22 272.75,77.43 ; JMDP1.22 274.06,76.66 ; 114.2,103.5 JDOCK1.155 ; JDOCK1.155 113.4,103.75 ; JDOCK1.155 115,105.35 ; JDOCK1.155 115,103.75 ; JDOCK1.155 114.2,105.6 ; JDOCK1.155 113.4,105.35 ; JDOCK1.155 115.25,104.55 ; JDOCK1.155 113.15,104.55 ; 160.2,1.22 PBATT1.6 ; PBATT1.6 161.01,1.49 ; PBATT1.6 159.39,1.49 ; PBATT1.6 161.01,3.11 ; PBATT1.6 160.2,3.38 ; PBATT1.6 159.39,3.11 ; H5.1 214.34,32.96 ; H5.1 211.66,35.64 ; H5.1 211.17,34.3 ; H5.1 213,32.47 ; H5.1 214.83,34.3 ; H5.1 211.66,32.96 ; H5.1 213,36.13 ; H5.1 214.34,35.64 ; JDOCK1.148 158.29,104.55 ; JDOCK1.148 158.29,102.7 ; JDOCK1.148 157.37,102.7 ; 272.97,66.42 JUSB3.7 ; JUSB3.7 272.97,68.08 ; JUSB3.7 272.33,66.62 ; JUSB3.7 272.33,67.89 ; JUSB3.7 272.14,67.25 ; 222.02,110.25 JHDMI1.23 ; JHDMI1.23 223.78,110.25 ; JHDMI1.23 223.78,108.78 ; JHDMI1.23 222.02,108.78 ; JHDMI1.23 222.02,111.72 ; JHDMI1.23 222.9,111.72 ; JHDMI1.23 222.9,108.78 ; JHDMI1.23 223.78,111.72
  BOTTOM w0.076: UC1.AY26 135.58,59.56 135.38,59.37 v2(135.38,59.31)
  BOTTOM w0.102: v2(69.14,62.2) 68.92,61.99 v3(68.33,61.99) ; v3(110.16,95.74) 110.57,95.34 v2(110.57,95.02) ; 61.49,9.73 61.49,8.94 v3(61.16,8.61) ; v2(213.63,94.42) 213.36,94.69 v3(212.73,94.69) ; v2(77.97,74.84) v3(77.05,73.93) ; v3(163.52,85.06) 163.57,85.01 164.34,85.01 v2(164.37,84.99) ; v2(180.26,86.4) v3(179.62,86.4) ; v2(87.74,79.5) v3(88.32,79.5) ; v2(182.18,84.25) v3(182.18,84.94)
  BOTTOM w0.127: 126.91,62.49 126.86,62.45 126.86,61.97 126.5,61.6 UC1.AV41 ; 125.24,62.49 125.29,62.44 125.29,61.97 124.92,61.6 UC1.AV43 ; UC1.AV46 123.35,61.6 123.71,61.97 123.71,62.23 123.7,62.25 123.7,62.56 ; UC1.AV39 128.07,61.6 128.44,61.97 128.44,62.47 128.42,62.49 ; UC1.AV36 129.65,61.6 130.01,61.97 130.01,62.42 129.94,62.49
  BOTTOM w0.152: v2(148.6,69.29) 148.96,69.65 148.96,69.74 149.16,69.93 149.55,69.93 149.88,69.6 UC1.AD3
  BOTTOM w0.178: UC1.AU30 132.63,62.43 132.61,62.45 UC1.AU33 ; v2(142.11,59.47) 142.11,60.42 UC1.AY16 142.02,60.51 UC1.AW16 UC1.AV16 ; v2(118.72,59.27) 118.72,59.63 118.91,59.82 UC1.AY53 ; UC1.D2 150.52,80.7 150.14,81.09 149.63,81.09 v2(149.51,81.21) ; 128.42,62.49 128.67,62.49 ; UC1.AJ63 112.93,66.81 112.24,66.81 111.98,66.55 v2(111.76,66.55) ; UC1.AV24 UC1.AW24 UC1.AY24 136.93,59.62 v2(136.85,59.54) ; UC1.AT46 UC1.AT43 ; v2(112.1,69.62) 112.6,69.62 UC1.AD63 ; v2(131.08,63) 130.81,62.73 UC1.AT35 ; v2(111.75,64.24) 111.91,64.39 UC1.AN63 ; v2(112.02,71.73) 112.14,71.85 UC1.Y63 ; UC1.AR52 119.46,63.46 119.46,63.71 UC1.AP52 ; UC1.AY30 133.14,59.63 v2(133.07,59.56) ; UC1.AY18 140.71,59.62 v2(140.64,59.55) ; UC1.AY33 UC1.AW33 ; UC1.AW33 131.79,61.72 UC1.AV33 ; UC1.AW33 131.55,61.13 UC1.AV34 ; UC1.AY57 116.48,59.57 v2(116.41,59.5) ; UC1.AY59 115.16,59.57 v2(115.12,59.54) ; v2(114.92,75.22) 114.92,75.11 UC1.P59 ; v2(120.84,58.15) 120.26,58.73 UC1.AY51 UC1.AW51 UC1.AV51 ; UC1.AV59 UC1.AW59 ; UC1.AY22 138.28,59.59 v2(138.34,59.53)
  BOTTOM w0.203: UC1.B52 UC1.A52 ; UC1.J63 112.16,77.85 v2(112.04,77.97) ; v2(149.61,63.23) 149.94,63.56 UC1.AP3 ; UC1.A56 UC1.B56 ; UC1.AY6 147.87,59.71 v2(147.79,59.63) ; v2(147.94,64.94) 147.75,64.94 UC1.AN7 ; v2(149.52,59.45) 149.32,59.65 UC1.AY4 149.27,60.2 UC1.AW4 ; UC1.U61 113.92,73.42 v2(113.62,73.72) ; v2(149.67,72.19) 149.67,72.33 UC1.V3 ; UC1.AN49 121.34,64.56 121.23,64.45 120.86,64.45 120.75,64.56 UC1.AN51 120.41,64.56 120.28,64.43 119.9,64.43 119.77,64.56 UC1.AN52 ; v2(113.62,70.73) 113.62,70.62 113.92,70.32 UC1.AC61 ; UC1.A44 UC1.B44 ; v2(148.6,69.29) 148.6,68.83 UC1.AE5 ; UC1.AM1 151.75,65.07 v2(151.91,65.22) ; UC1.N3 149.94,75.48 v2(150.24,75.18) ; v2(151.77,77.34) 151.59,77.34 151.3,77.06 UC1.K1 ; UC1.AK3 149.94,66.56 v2(149.59,66.21) ; UC1.AW60 114.92,60.8 UC1.AW59 ; UC1.F58 115.87,80.04 115.34,80.56 UC1.D59 ; UC1.T1 v2(151.82,74.06) ; v2(113.62,79.72) 113.92,79.42 UC1.F61 ; UV13.11 v2(206.94,80.94)
  BOTTOM w0.229: v2(145.28,77.92) 145.64,77.56 UC1.J10 ; UC1.M22 138.64,75.7 v2(139.03,75.31) ; v2(129.24,61.1) 128.94,60.8 UC1.AW37 ; UC1.AH40 127.15,67.72 v2(127.57,67.72) ; v2(120.92,79.07) 120.92,79.07 UC1.F50 ; UC1.W22 138.54,72.51 UC1.V23 138.13,72.9 v2(137.75,72.52) ; 137.63,65.86 UC1.AL23 ; 137.63,65.86 v2(137.3,66.19) 137.63,66.51 ; 137.63,65.86 v2(137.3,65.54) 137.63,65.21 UC1.AM23 ; UC1.AV55 117.7,61.3 v2(117.73,61.27) ; v2(128.44,79.07) 128.45,79.07 UC1.F38 ; UC1.AL33 131.34,65.86 v2(131.08,65.6) ; UC1.AK23 137.63,66.51 ; 137.63,66.51 v2(137.3,66.84) 137.32,66.86 UC1.AH24 ; v2(135.4,63.59) 135.72,63.91 UC1.AP26 ; UC1.AP54 118.57,63.91 v2(118.24,63.59) ; UC1.AF15 142.75,68.68 v2(142.34,69.09) 141.93,68.68 UC1.AF17 ; UC1.AL22 138.47,65.86 v2(138.15,65.54) ; UC1.AH32 132.01,67.37 v2(132.01,66.84) ; UC1.AN48 122.68,64.56 v2(122.95,64.84) 123.22,64.56 UC1.AN46 123.55,64.45 124.26,64.45 UC1.AN45 124.63,64.3 125.09,64.3 UC1.AN43 ; UC1.AN48 UC1.AP48 122.29,63.91 v2(121.96,63.58) ; UC1.AN48 122.22,64.39 121.66,64.39 UC1.AN49 ; UC1.F30 133.46,79.07 v2(133.46,79.07) ; UC1.AV49 121.47,61.15 v2(121.36,61.15) 121.01,60.8 UC1.AW50 ; UC1.F46 123.43,79.07 v2(123.43,79.07) ; v2(143.48,78.61) 143.88,78.21 UC1.H13 ; UC1.D18 141.14,80.88 141.48,80.54 v2(141.48,80.54) 141.6,80.54 UC1.E17 ; UC1.AH22 139.26,67.63 UC1.AG21 139.29,67.21 v2(139.46,67.04) 139.72,67.3 UC1.AH20 ; UC1.AJ29 133.82,67.16 v2(133.49,66.84) 132.98,66.33 UC1.AL31 UC1.AM31 UC1.AN31 ; UC1.AJ39 127.57,66.69 127.7,66.56 UC1.AL39 ; UC1.AJ39 127.93,67.16 128.22,66.88 v2(128.22,66.84) ; UC1.AJ39 v2(127.57,67.72) ; UC1.AJ41 125.98,67.16 v2(125.74,66.93) ; v2(140.05,63.59) 140.38,63.91 UC1.AP20 ; UC1.AN35 130.45,64.56 v2(130.12,64.24) ; UC1.AV14 142.99,61.87 142.99,62.52 v2(142.65,62.86) ; UC1.AJ45 123.44,66.93 v2(122.95,66.93) 122.72,67.16 UC1.AJ47 122.37,67.16 122.13,66.93 v2(121.83,66.93) ; v2(130.95,79.07) 130.95,79.07 UC1.F34 ; UC1.AJ43 125.21,66.93 v2(125.74,66.93) ; UC1.AV39 127.95,61.45 v2(127.66,61.15) 127.3,60.8 UC1.AW40 ; v2(127.57,67.72) 127.99,67.72 UC1.AH38 ; UC1.AP22 138.47,63.91 v2(138.15,63.59) ; v2(145.19,66.3) 145.48,66 UC1.AL10 ; UC1.AU24 136.45,62.43 136.4,62.47 136.1,62.47 136.06,62.43 UC1.AU26 135.2,62.43 135.16,62.47 134.85,62.47 134.81,62.43 UC1.AU28 133.91,62.43 133.87,62.47 133.56,62.47 133.52,62.43 UC1.AU30 132.98,62.59 UC1.AR31 UC1.AP31 UC1.AN31 ; UC1.AG60 UC1.AG61 UC1.AG62 UC1.AG63 112.85,68.26 112.09,68.26 v2(111.91,68.08) ; UC1.AW35 130.75,61.15 v2(130.81,61.15) 130.81,61.16 131.1,61.45 UC1.AV34 ; v2(139.03,75.31) 138.66,74.95 UC1.P22 ; v2(139.03,75.31) 139.07,75.35 UC1.N21 ; UC1.AL52 119.53,65.86 119.21,65.54 v2(119.21,65.54) 119.54,65.21 119.6,65.21 ; v2(119.17,64.31) 119.26,64.31 119.51,64.56 UC1.AN52 ; v2(142.65,62.86) 142.4,62.86 142.02,63.23 UC1.AR17 UC1.AP17 UC1.AN17 UC1.AM17 UC1.AL17 142.02,66.2 142.71,66.89 v2(142.71,66.87) ; v2(142.65,62.86) 142.89,62.86 UC1.AR15 143.34,63.08 UC1.AT13 143.76,62.66 v2(144.4,62.66) 144.76,62.66 145.02,62.92 UC1.AR11 ; UC1.AJ60 114.89,66.45 114.94,66.41 114.94,66.1 114.89,66.06 UC1.AL60 ; UC1.AL54 118.65,65.86 v2(119.14,66.35) ; v2(135.96,79.07) 135.97,79.07 UC1.F26 ; UC1.AP38 128.54,63.91 v2(128.22,63.59) UC1.AR39 ; UC1.AH42 125.62,67.04 v2(125.74,66.93) ; UC1.AN36 129.34,64.56 v2(129.17,64.39) ; UC1.AL20 140.44,65.86 v2(140.05,65.47) ; UC1.AL29 133.82,65.86 v2(133.49,65.54) ; UC1.AV8 146.31,61.45 v2(145.99,61.77) ; UC1.AH34 130.59,67.72 v2(130.17,67.72) ; UC1.AH34 v2(131.31,67.98) ; UC1.AH34 130.82,67.06 v2(130.98,66.91) ; UC1.AV46 123.29,61.45 v2(122.93,61.1) 122.64,60.8 UC1.AW47 ; UC1.AF11 145.5,68.81 145.68,68.81 145.68,68.82 UC1.AE10 ; UC1.AF11 144.78,68.09 ; UC1.AF11 144.81,68.87 144.81,69.06 v2(144.87,69.13) ; UC1.D5 148.68,81.05 148.69,81.05 148.74,81.09 149.39,81.09 v2(149.51,81.21) ; UC1.U20 140.07,73.32 v2(140.49,72.9) 140.1,72.51 UC1.W20 ; v2(134.58,68.01) 134.72,67.86 UC1.AH28 ; v2(144.87,59.46) UC1.AY11 ; v2(143.56,69.15) UC1.AF14 ; v2(142.71,66.87) 142.93,66.65 UC1.AJ14 143.15,66.52 UC1.AL13 143.79,66.12 143.79,66.47 UC1.AJ13 144.06,66.65 v2(144.42,66.3) ; v2(142.71,66.87) 142.34,67.24 UC1.AH16 142.16,67.12 141.71,67.12 UC1.AH17 ; UC1.AJ25 136.67,67.06 136.47,66.86 v2(136.21,66.86) 136.13,66.93 135.61,66.93 UC1.AJ27 ; v2(116.37,74.17) 116.25,74.05 UC1.T58 ; v2(119.14,66.35) 119.3,66.51 UC1.AK52 119.77,66.62 UC1.AJ52 ; v2(119.14,66.35) 119.12,66.37 UC1.AH53 ; UC1.AE58 v2(116.42,68.85) ; v2(130.17,67.72) 129.76,67.72 UC1.AH36 ; v2(130.17,67.72) UC1.AJ35 ; v2(113.63,76.71) 113.92,76.42 UC1.L61 ; UC1.AL60 UC1.AL61 113.77,65.61 v2(113.73,65.57) ; UC1.AL60 114.89,65.24 114.94,65.19 114.94,64.81 114.89,64.76 UC1.AN60 114.89,63.91 114.94,63.87 114.94,63.4 v2(114.81,63.27) ; v2(146.77,71.22) 146.93,71.22 147.31,70.84 UC1.AB7 ; UC1.AN31 132.65,64.89 132.42,64.66 UC1.AN32 ; UC1.AU59 115.61,62.43 115.65,62.47 115.96,62.47 116,62.43 UC1.AU57 116.86,62.43 116.9,62.47 117.2,62.47 117.25,62.43 UC1.AU55 118.15,62.43 118.19,62.47 118.5,62.47 118.54,62.43 UC1.AU53 119.39,62.43 119.44,62.47 119.7,62.47 119.74,62.47 119.79,62.42 119.88,62.33 120.17,62.33 UC1.AU51 ; UC1.AL46 123.71,65.59 v2(123.9,65.59) 124.1,65.59 124.37,65.86 UC1.AL45 ; UC1.E11 144.78,80.16 144.54,80.4 v2(144.41,80.4) 144.51,80.49 UC1.D12 ; UC1.AG11 144.78,68.09 ; 144.78,68.09 UC1.AF12 ; UC1.R22 138.64,73.9 v2(139.21,73.32) UC1.U22 ; v2(133.49,63.59) 133.82,63.91 UC1.AP29 ; v2(119.16,64.91) 119.3,64.91 119.6,65.21 ; 119.6,65.21 UC1.AM52 ; UC1.AR33 131.34,63.26 v2(131.08,63) 131.63,62.45 UC1.AU33 ; v2(118.41,79.07) 118.42,79.07 UC1.F54 ; UC1.AL57 116.66,65.86 v2(116.34,65.54) ; v2(135.4,65.54) 135.72,65.86 UC1.AL26 ; UC1.AP10 145.63,64.05 v2(145.94,63.74) ; v2(116.34,63.59) 116.66,63.91 UC1.AP57 ; UC1.AB20 140.41,71.23 v2(140.53,71.23) ; v2(125.93,79.07) 125.94,79.07 UC1.F42 ; v2(134.39,61.27) 134.36,61.3 UC1.AV28 ; UC1.AW42 125.75,60.8 v2(126.09,61.14) 126.4,61.45 UC1.AV41 ; UC1.AH49 121.72,67.04 v2(121.83,66.93) ; UC1.AN23 137.63,64.56 v2(137.3,64.24) 137.63,63.91 UC1.AP23 ; v2(121.83,66.93) 121.37,66.93 121.14,67.16 UC1.AJ50 ; v2(141.48,78.53) 141.64,78.53 141.97,78.21 UC1.H17 ; UC1.AL36 129.34,65.86 v2(129.17,65.69) ; UC1.AP39 127.44,64.24 UC1.AN40 ; UC1.AV20 139.49,61.3 v2(139.53,61.27) ; UC1.AG1 151.62,68.06 v2(151.77,67.92) ; UC1.AA58 v2(116.42,71.45) ; v2(120.09,65.54) 120.42,65.86 UC1.AL51 ; UC1.AR43 125.18,63.26 v2(124.86,62.94) 124.51,62.59 UC1.AT43 124.58,62.49 126.01,62.49 UC1.AT42 126.47,62.56 126.54,62.49 126.91,62.49 126.97,62.56 UC1.AT40 127.73,62.49 128.66,62.49 128.74,62.56 UC1.AT37 129.87,62.56 129.94,62.49 130.31,62.49 130.38,62.56 UC1.AT35 ; UC1.AN40 127.44,64.89 UC1.AN39 ; UC1.AN40 127.05,64.56 v2(126.72,64.24) 126.4,64.56 UC1.AN42 ; v2(140.67,83.24) 140.64,83.2 UC1.A18 ; v2(137.38,62.74) 137.5,62.74 137.81,62.43 UC1.AU22 138.65,62.43 138.69,62.47 139,62.47 139.04,62.43 UC1.AU20 139.94,62.43 139.99,62.47 140.29,62.47 140.34,62.43 UC1.AU18 141.19,62.43 141.23,62.47 141.54,62.47 141.58,62.43 UC1.AU16 ; v2(116.42,72.75) UC1.V58 ; v2(139.21,70.88) UC1.AB22 ; UC1.AW44 124.17,60.8 v2(124.52,61.14) 124.66,61.14 124.92,61.4 UC1.AV43
  BOTTOM w0.254: JDOCK1.75 132.95,99.68 132.78,99.51 v2(132.78,99.24) ; UC1.D18 140.74,81.4 UC1.C18 ; UC1.G18 141.02,78.84 141.33,78.53 v2(141.48,78.53) ; UC1.AU1 151.71,62.12 v2(151.84,61.99) ; JDOCK1.102 v2(140.45,109.83) ; v2(122.63,99.28) 122.63,99.32 122.45,99.5 JDOCK1.37 ; UC1.AN39 127.7,65.27 UC1.AL40 ; v2(149.7,109.89) 149.7,109.68 149.45,109.43 JDOCK1.138 ; UC1.AJ29 134.4,67.16 UC1.AH28 135.05,67.16 UC1.AJ27 ; UC1.D8 147.09,80.65 v2(147.24,80.49) ; UC1.AA1 151.64,71.06 v2(151.76,71.18) ; v2(144.98,98.11) 144.83,98.27 144.83,99.61 144.95,99.72 JDOCK1.119 ; UC1.AH51 120.09,67.16 UC1.AJ52 ; UC1.AH51 120.74,67.16 UC1.AJ50 ; UC1.AH51 v2(120.91,67.98) ; UC1.U9 145.77,72.66 UC1.V10 143.83,72.63 v2(143.59,72.87) ; UC1.J59 115.22,77.85 114.89,78.17 v2(114.89,78.16) ; v2(121.08,63.01) 121.33,62.76 UC1.AT49 ; v2(121.08,63.01) 121.33,63.26 UC1.AR49 ; v2(121.08,63.01) 120.85,63.01 UC1.AU51 ; JDOCK1.61 129.45,99.26 v2(129.49,99.22) 129.95,99.69 JDOCK1.63 ; UC1.AH19 140.76,67.26 140.76,66.76 v2(140.91,66.61) ; UC1.AF18 UC1.AF17 ; UC1.G8 147.06,79.18 v2(147.18,79.18) 147.37,79.18 UC1.G6 147.91,78.86 v2(148.22,79.17) 148.54,78.86 UC1.G5 ; v2(64.5,55.22) 64.19,55.53 UC7.7 ; v2(147.4,76.9) 147.31,76.8 UC1.L7 ; JDOCK1.43 123.95,99.35 v2(124.01,99.3) ; UC1.F54 UC1.D54 ; JEDP1.27 58.92,72.36 v2(58.73,71.98) 58.7,71.98 58.41,72.27 JEDP1.28 ; UC1.H57 116.16,78.68 v2(115.74,79.1) 115.87,79.23 UC1.F58 ; UC1.AH32 v2(132.61,67.98) ; JDOCK1.87 135.95,99.34 v2(136.07,99.22) ; v2(120.8,109.81) 120.95,109.66 JDOCK1.32 ; JDOCK1.101 v2(140.45,98.91) ; UC1.AR5 148.4,63.34 v2(148.81,63.34) ; v2(213.9,54.14) 213.9,54.37 214.29,54.77 215.13,54.77 215.75,54.15 JNGFF2.25 ; UC1.AL40 127.44,66.19 UC1.AL39 ; UC1.AL40 126.72,65.47 126.72,65.47 v2(126.7,65.48) ; JDOCK1.113 143.45,99.58 v2(143.14,99.27) ; UC1.AJ43 124.64,67.49 UC1.AH44 ; UC1.R8 UC1.R10 145.33,74.54 v2(145.09,74.78) 145.77,75.46 UC1.N10 ; JDOCK1.132 147.95,109.76 v2(147.88,109.83) ; v2(61.9,76.45) 63.51,76.45 63.98,75.98 63.98,75.96 JEDP1.15 ; RPC20.6 148.52,90.67 148.77,90.92 v2(148.77,91.03) 149.02,90.78 RPC20.7 ; UC1.AH49 v2(122.21,67.98) ; JDOCK1.64 v2(129.95,109.85) ; JDOCK1.47 124.95,99.42 125.13,99.24 v2(125.52,99.24) 125.45,99.31 JDOCK1.49 ; UC1.P62 UC1.P63 v2(112.09,74.85) ; v2(123.81,110.02) 123.81,109.58 123.95,109.44 JDOCK1.44 ; JEDP1.25 59.31,74.06 58.96,74.06 58.52,74.46 v2(58.52,74.92) ; UC1.AR23 137.7,63.26 137.38,62.93 v2(137.38,62.74) 137.06,62.43 UC1.AU24 ; v2(147.63,72.11) 147.31,72.43 UC1.V7 ; v2(133.21,109.76) 132.95,109.5 JDOCK1.76 ; UC1.B20 139.53,82.28 v2(139.88,82.28) 139.88,81.99 139.73,81.85 UC1.C20 ; v2(136.04,109.8) 135.95,109.71 JDOCK1.88 ; UC1.D46 UC1.F46 ; v2(124.81,67.98) UC1.AH44 ; UC1.AH44 123.99,67.49 UC1.AJ45 ; v2(114.81,63.27) 114.68,63.14 UC1.AT61 114.19,63.09 UC1.AT62 113.08,63.09 112.92,62.93 UC1.AT63 112.48,62.93 v2(112.17,62.62) ; v2(53.65,69.76) 53.27,70.3 JEDP1.39 ; UC1.L17 141.52,76.17 v2(141.49,76.17) 141.48,76.17 UC1.L18 140.7,76.31 v2(140.7,76.17) 140.46,76.17 UC1.L20 ; JDOCK1.107 v2(141.95,99.29) ; JEDP1.6 68.25,77.35 v2(68.25,77.57) ; UC1.B48 UC1.A48 ; UC1.G3 149.94,78.54 v2(150.3,78.18) ; UC1.AH30 v2(133.91,67.98) ; UC1.D34 UC1.F34 ; UC1.AH40 126.78,67.35 v2(126.78,66.94) 126.5,66.94 UC1.AJ41 ; JEDP1.4 69.27,77.51 69.27,77.95 v2(69.39,78.08) ; JDOCK1.1 113.45,99.61 v2(113.85,99.21) ; JDOCK1.91 136.95,99.44 v2(137.15,99.24) 137.45,99.54 JDOCK1.93 ; UC1.B4 148.9,82.13 v2(148.86,82.17) ; JDOCK1.123 145.95,99.5 v2(146.23,99.22) 146.23,99.35 146.45,99.57 JDOCK1.125 ; UC1.D12 144.86,81.35 144.86,81.56 UC1.C11 ; v2(146.45,109.83) JDOCK1.126 ; JDOCK1.120 144.95,109.82 v2(145.02,109.89) ; v2(134.25,109.77) 134.25,109.56 134.45,109.36 JDOCK1.82 ; UZ2.11 v2(212.35,46.08) ; UC1.D26 UC1.F26 ; v2(145.1,71.99) 145.46,71.99 UC1.Y10 ; UC1.AU59 UC1.AV59 ; JDOCK1.51 126.95,99.4 v2(127.15,99.2) ; UC1.AU53 118.91,62.69 119.48,63.26 UC1.AR52 ; v2(119.28,99.03) 119.45,99.2 JDOCK1.25 ; UC1.B40 UC1.A40 ; v2(134.16,99.24) 134.16,99.35 134.45,99.64 JDOCK1.81 ; v2(114.93,72.2) 114.93,72.16 115.22,71.88 UC1.Y59 ; JDOCK1.131 147.95,99.27 v2(148.01,99.22) ; JDOCK1.58 v2(128.45,109.84) ; JDOCK1.19 117.95,99.46 v2(117.71,99.22) ; JDOCK1.31 120.95,99.06 v2(121.18,98.82) ; UC1.B28 UC1.A28 ; v2(139.16,69.22) 139.56,69.62 UC1.AD21 ; JDOCK1.7 114.95,99.29 v2(114.92,99.26) ; UC1.D59 115.34,80.9 114.73,81.51 114.73,81.97 UC1.B60 ; UC1.D50 UC1.F50 ; v2(112.07,80.8) UC1.D63 112.67,80.74 UC1.D62 ; JDOCK1.57 128.45,99.61 v2(128.09,99.25) 127.95,99.39 JDOCK1.55 ; JDOCK1.14 v2(116.45,109.83) ; v2(123.02,68.01) UC1.AH46 ; v2(128.71,67.98) UC1.AH38 ; JDOCK1.52 126.95,109.43 126.68,109.7 v2(126.4,109.7) 125.78,109.7 125.45,109.37 JDOCK1.50 ; UC1.K12 143.91,76.63 UC1.L13 143.38,76.14 v2(143.15,76.14) 142.93,76.36 UC1.L15 ; v2(143.45,80.5) 143.72,80.77 UC1.D14 143.72,81.18 UC1.C14 143.33,81.6 143.33,82.31 143.21,82.42 UC1.A14 143.21,83.91 v2(142.81,84.31) ; UC1.AH42 v2(126.11,67.98) ; JDOCK1.114 v2(143.45,109.83) ; v2(67.93,75.22) 67.93,75.35 JEDP1.8 ; v2(137.67,68.63) 138.13,68.17 UC1.AG23 UC1.AJ23 138.5,67.22 138.78,66.94 v2(138.84,66.94) ; JDOCK1.13 116.45,99.35 v2(116.32,99.22) ; v2(122.56,110.34) 122.45,110.23 JDOCK1.38 ; UC1.AN42 126.1,64.36 125.92,64.36 125.84,64.29 v2(125.86,64.29) ; UC1.F38 UC1.D38 ; JDOCK1.26 v2(119.45,109.87) ; UC1.AJ60 115.06,66.82 v2(115.34,67.1) 115.4,67.16 UC1.AJ58 116.19,67.16 UC1.AH57 116.84,67.16 UC1.AJ56 117.49,67.16 UC1.AH55 118.14,67.16 UC1.AJ54 118.79,67.16 UC1.AH53 v2(119.61,67.98) ; JDOCK1.69 131.45,99.28 v2(131.39,99.23) ; v2(131.45,109.85) JDOCK1.70 ; JDOCK1.137 149.45,99.18 v2(149.4,99.13) ; JDOCK1.8 v2(114.95,109.93) ; v2(144.88,83.29) UC1.A11 ; JDOCK1.20 v2(117.95,109.91) ; JEDP1.24 59.74,74.33 59.74,74.9 v2(59.8,74.97) 60.09,74.97 JEDP1.23 ; v2(138.95,98.93) JDOCK1.95 ; UC1.F42 UC1.D42 ; UC1.AB10 145.1,70.73 v2(145.1,70.72) ; UC1.D23 138.51,80.35 UC1.D21 139.01,79.38 UC1.G22 139.55,79.01 v2(139.58,79.04) 140.05,79.51 UC1.F20 ; JDOCK1.108 v2(141.95,109.83) ; UC1.B24 UC1.A24 ; UC1.D30 UC1.F30
  BOTTOM w0.279: UC1.L20 139.99,76.65 139.38,76.65 UC1.J22 ; v2(116.39,76.65) UC1.L58
  BOTTOM w0.305: JNGFF1.49 210.38,15.85 210.57,16.04 v2(211.32,16.04) ; JNGFF2.65 214.98,44.15 214.55,44.57 v2(214.55,44.92) 214.82,44.65 JNGFF2.63 ; v2(211.76,28.23) 211.57,28.04 210.68,28.04 210.37,28.35 JNGFF1.7 ; JNGFF2.11 217.59,59.65 v2(217.79,59.86) ; JNGFF1.16 215.25,24.1 215.24,24.09 214.74,24.09 214.48,24.36 v2(214.48,24.59) ; JNGFF2.31 217.83,52.65 218.22,53.05 v2(218.22,53.81) ; JNGFF1.22 215.25,22.6 215.15,22.71 v2(214.68,22.71) ; v2(210.3,19.91) 209.98,19.91 209.55,20.35 JNGFF1.31 ; JNGFF2.49 215.8,48.15 215.03,48.92 v2(215.03,49.52) 215.16,49.65 JNGFF2.43 ; v2(207.51,18.85) JNGFF1.37 ; JNGFF1.55 209.77,14.35 209.92,14.2 v2(209.92,13.58) 209.92,13.18 209.59,12.85 JNGFF1.61 ; JNGFF1.21 209.54,22.85 209.66,22.72 v2(209.92,22.72) ; v2(219.2,54.79) 218.48,54.79 217.62,55.65 JNGFF2.19 ; v2(214.62,25.82) 215.19,25.82 215.41,25.6 JNGFF1.10 ; JNGFF1.15 207.94,24.35 207.82,24.23 v2(207.49,24.23) ; JNGFF1.25 v2(210.3,21.85) ; v2(210.15,29.74) 210.04,29.85 JNGFF1.1 ; JNGFF1.43 v2(209.86,17.35) ; JNGFF2.37 215.66,51.15 v2(215.51,51.3) ; v2(215,20.87) 215.23,21.1 JNGFF1.28 ; JNGFF2.3 215.71,61.65 v2(215.51,61.44) 215.8,61.15 JNGFF2.5 ; JNGFF1.67 208.15,11.35 207.63,10.83 207.63,10.25
  BOTTOM w0.356: v2(150.2,16.23) JDIMM2.44 ; JDIMM2.38 v2(148.4,16.29) ; v2(98.16,19.15) 98.3,19.01 JDIMM1.128 ; v2(185.28,23.47) 184.96,23.47 184.7,23.73 JDIMM2.151 ; JDIMM1.178 v2(113.3,16.32) ; JDIMM1.20 v2(63.5,16.36) ; v2(184.75,19.52) 184.4,19.17 JDIMM2.150 ; JDIMM1.196 118.7,16.52 v2(119.18,16.04) ; JDIMM1.151 105.2,24.62 105.97,23.85 v2(106.39,23.85) ; v2(138.78,24.1) 137.9,24.98 JDIMM2.3 ; v2(99.44,19.9) 100.1,19.24 JDIMM1.134 ; JDIMM2.48 v2(151.4,16.26) ; JDIMM2.187 195.5,24.98 v2(195.8,24.68) ; JDIMM2.179 193.1,24.01 v2(193.59,23.52) ; JDIMM2.66 156.8,19.98 v2(156.44,20.34) ; JDIMM1.153 105.8,27.11 106.03,27.34 106.03,27.71 v2(105.45,28.29) ; v2(100.38,24.55) 100.19,24.55 99.8,24.95 JDIMM1.133 ; v2(72.01,24.49) 72.2,24.68 JDIMM1.49 ; JDIMM1.170 v2(110.9,16.36) ; v2(141.27,29.67) 139.7,28.1 JDIMM2.9 ; JDIMM2.49 151.7,27.41 v2(151.8,27.77) ; v2(178.57,28.17) 179.3,27.43 JDIMM2.133 ; JDIMM1.189 116.6,27.71 v2(116.02,28.29) ; JDIMM2.61 155.3,22.37 ; v2(107.24,28.29) 108.2,27.33 JDIMM1.161 ; JDIMM2.156 186.2,19.3 v2(186.8,19.9) ; v2(117.94,28.29) 118.54,27.69 118.54,27.19 118.4,27.04 JDIMM1.195 ; JDIMM1.14 v2(61.7,16.36) ; JDIMM1.71 78.8,26.82 79.12,27.15 79.12,27.73 78.56,28.29 v2(78.56,28.29) ; JDIMM1.31 v2(66.8,24.49) ; JDIMM2.155 185.9,27.18 v2(184.92,28.17) ; v2(61.37,24.49) 61.4,24.51 JDIMM1.13 ; JDIMM1.61 75.8,24.8 75.55,24.54 75.55,23.92 v2(76.19,23.28) ; JDIMM1.168 110.3,16.57 v2(110.1,16.37) ; JDIMM1.28 v2(65.9,16.36) ; JDIMM1.48 v2(71.9,16.36) ; v2(145.91,24.29) 147.56,24.29 148.1,24.83 JDIMM2.37 ; JDIMM1.156 v2(106.7,16.39) ; v2(149.61,28.15) 149.85,28.15 150.16,27.83 150.16,27.15 149.9,26.88 JDIMM2.43 ; v2(61.51,28.29) 60.8,27.58 JDIMM1.11 ; JDIMM1.185 v2(115.4,24.57) ; v2(191.83,27.78) 191.3,27.25 JDIMM2.173 ; JDIMM1.46 v2(71.3,16.36) ; JDIMM2.26 144.8,18.98 v2(145.01,19.19) ; JDIMM1.167 110,24.53 v2(110.05,24.48) ; v2(111.49,24.55) 111.8,24.86 JDIMM1.173 ; JDIMM2.172 191,16.52 v2(190.78,16.3) ; v2(65.3,16.36) JDIMM1.26 ; JDIMM2.168 189.8,18.81 189.89,18.91 189.89,19.34 v2(189.34,19.9) ; JDIMM2.63 155.9,23.17 v2(156.44,22.62) ; v2(74.04,24.47) 74,24.51 JDIMM1.55 ; JDIMM1.65 77,27.44 76.15,28.29 v2(76.04,28.29) ; v2(60.21,16.47) 59.9,16.78 JDIMM1.8 ; JDIMM2.162 188,19.17 v2(188.13,19.29) ; v2(76.12,24.32) 76.4,24.59 JDIMM1.63 ; v2(143.81,28.15) 142.7,27.04 JDIMM2.19 ; JDIMM2.72 v2(158.6,16.29) ; JDIMM2.13 140.9,24.1 141.03,23.98 v2(141.21,23.98) ; JDIMM2.128 177.8,19.26 v2(178.44,19.9) ; JDIMM1.60 v2(75.5,16.36) ; JDIMM2.184 194.6,16.52 v2(194.81,16.31) ; JDIMM2.190 196.4,19.16 v2(196.04,19.52) ; v2(77.78,16.29) 77.3,16.77 JDIMM1.66 ; JDIMM2.178 v2(192.8,19.15) ; JDIMM1.187 116,24.94 v2(116.45,24.49) ; v2(67.1,16.36) JDIMM1.32 ; JDIMM2.134 v2(179.6,19.21) ; JDIMM2.161 187.7,27.85 187.38,28.17 v2(187.04,28.17) ; v2(65.36,24.44) 65,24.8 JDIMM1.25 ; v2(102.98,24.55) 103.4,24.96 JDIMM1.145 ; v2(146.66,16.29) 146.6,16.35 JDIMM2.32 ; JDIMM2.46 v2(150.8,16.23) ; v2(64.05,28.29) 64.04,28.29 63.2,27.46 JDIMM1.19 ; JDIMM1.9 60.2,24.86 v2(60.57,24.49) ; JDIMM1.2 v2(58.1,16.37) ; JDIMM2.195 v2(197.9,24.5) ; JDIMM1.179 113.6,24.6 v2(113.65,24.55) ; JDIMM2.167 189.5,24.6 v2(189.42,24.52) ; JDIMM2.144 v2(182.6,19.13) ; JDIMM1.172 v2(111.5,16.36) ; JDIMM2.25 144.5,24.73 145.01,24.22 v2(145.01,24.1) ; v2(101.33,19.9) 100.7,19.27 JDIMM1.136 ; JDIMM1.139 v2(101.6,24.59) ; JDIMM1.138 v2(101.3,16.17) ; v2(70.07,24.49) 70.4,24.82 JDIMM1.43 ; JDIMM2.55 153.5,26.92 153.77,27.19 153.77,27.56 v2(153.19,28.15) ; JDIMM1.155 v2(106.4,24.49) ; v2(181.4,27.78) 181.1,27.49 JDIMM2.139 ; v2(155.75,28.15) 156.5,27.4 JDIMM2.65 ; JDIMM2.153 185.3,24.61 v2(185.28,24.59) ; JDIMM1.3 v2(58.4,24.17) ; JDIMM2.54 153.2,20.15 v2(152.63,20.72) ; v2(108.5,16.36) JDIMM1.162 ; JDIMM2.14 v2(141.2,16.29) ; v2(182.16,24.49) 182.55,24.49 182.9,24.84 JDIMM2.145 ; JDIMM1.190 v2(116.9,16.36) ; JDIMM1.38 v2(68.9,16.36) ; JDIMM2.8 v2(139.4,16.29) ; v2(115.1,16.36) JDIMM1.184 ; v2(158.27,28.15) 158.8,27.61 158.8,27.14 158.3,26.64 JDIMM2.71 ; JDIMM2.2 v2(137.6,16.29) ; JDIMM2.31 146.3,26.97 145.8,27.47 v2(145.8,27.77) ; JDIMM2.127 177.5,24.75 177.81,24.44 v2(178.09,24.44) ; v2(70.7,16.36) JDIMM1.44 ; v2(79,16.29) 79.1,16.39 JDIMM1.72 ; JDIMM1.37 68.6,24.91 v2(68.17,24.48) ; JDIMM2.11 140.3,27.18 v2(141.27,28.15) ; JDIMM2.28 145.4,16.57 v2(145.12,16.29) ; JDIMM1.127 v2(98,24.42) ; JDIMM2.60 v2(155,16.29) ; v2(198.3,19.28) 198.3,19.02 198.2,18.93 JDIMM2.196 ; v2(73.7,16.36) JDIMM1.54 ; JDIMM2.138 180.8,16.72 v2(180.44,16.36) ; JDIMM2.20 v2(143,16.29)
  BOTTOM w0.381: v2(155.16,72.59) 155.26,72.49 RC171.2 ; CC4.1 167.31,57.42 v2(167.12,57.23) ; JDIMM2.170 190.4,18.75 190.55,18.9 190.55,19.53 190.92,19.9 ; v2(195.66,28.17) 195.89,28.17 196.27,27.79 196.27,27.22 196.1,27.05 JDIMM2.189 ; v2(195,24.6) 194.9,24.7 JDIMM2.185 ; v2(180.94,19.9) 180.56,19.9 180.2,19.53 JDIMM2.136 ; v2(184.01,84.72) 184.28,84.99 UV11.7 ; v2(186.17,55.35) 186.04,55.35 185.71,55.68 PR310.2 ; v2(104.9,16.36) JDIMM1.150 ; v2(210.11,94) 209.69,94.42 UI2.1 ; JDIMM1.144 v2(103.1,16.36) ; v2(251.7,78.59) 251.7,78.27 251.36,77.93 UI1.1
  BOTTOM w0.406: DI6.3 196.76,96.19 v2(196.14,96.81) ; JMDP1.14 v2(270.43,81.26) ; JMDP1.8 v2(270.5,83.05)
  BOTTOM w0.457: RZ27.2 206.55,85.97 v2(206.53,85.94) ; v2(156.24,69.73) 155.94,69.73 155.83,69.62 CC108.2 ; CC107.2 154,73.49 153.78,73.49 v2(153.45,73.16)
  BOTTOM w0.508: DV4.1 72.72,76.03 v2(73.92,77.23) ; 207.63,10.25 v2(207.63,10.21) 207.67,10.25 JNGFF1.69 ; JMINI3.35 46.89,15.05 v2(46.6,15.34) 46.58,15.33 46.58,14.5 46.84,14.25 JMINI3.37 ; v2(78.66,84.3) 77.2,82.84 ST1.1 ; v2(196.99,81.86) 197.01,81.89 CV88.2 ; JMINI3.21 47.13,20.65 v2(46.81,20.33) ; v2(107.32,73.71) RC189.2 RC190.2 ; CC2.1 165.11,57.5 v2(164.75,57.5) 164.36,57.5 CC1.1 ; CV117.2 205.41,79.62 CV118.1 v2(205.4,78.9) ; CC5.2 149.21,56.7 148.73,57.19 v2(148.26,57.19) ; v2(38.47,18.9) 38.72,18.65 JMINI3.26 ; JNGFF2.68 v2(215.51,63.25) ; JSD1.26 268.35,31.08 v2(268.53,30.9) ; JSD1.6 v2(250.74,14) ; v2(73.21,77.94) 73.21,78.14 73.14,78.21 JEDP1.41 ; CV7.2 60.06,71.6 v2(60.09,71.63) ; PC402.2 PR401.2 v2(94.98,98.91) ; JSD1.13 v2(275.8,32.01) ; v2(89.08,67.18) 89.05,67.21 PR525.2 ; JMINI3.4 v2(38.6,30.65) ; CC17.2 62.78,60.74 v2(63.62,61.57) ; RC240.2 128.38,87.1 v2(128,87.48) ; CV85.2 195.64,79.26 v2(195.04,79.26) ; JNGFF2.69 214.78,42.55 v2(214.49,42.84) ; JEDP1.43 59.98,77.38 v2(57.07,77.38) ; CV8.2 57.79,61.94 v2(57.58,62.14) ; v2(173.22,78.4) 173.01,78.19 CC7.2 ; CI12.2 205.33,89.59 v2(205.47,89.45) 206.15,89.45 CI11.2 ; v2(125.72,94.97) 125.72,95.35 v3(125.3,95.76) 124.89,96.18 R268.2 C310.2 ; RC187.2 RC178.2 v2(144.26,54.84) ; CC109.2 106.78,55.41 102.78,55.41 102.22,55.97 v2(102.22,56.11) ; v2(106.56,76.22) 106.56,76.78 106.25,77.09 CC20.2 ; JRTC1.2 v2(227.2,102.72) ; JLOM1.16 243.42,109.58 244.2,110.35 JLOM1.17 ; UV9.4 200.76,76.62 201.27,77.13 v2(201.27,77.39) ; JDIMM2.205 v2(136.15,31.15) ; JEDP1.42 68.76,82.46 v2(69.2,82.91) ; v2(165.34,60.55) 166.1,61.32 166.95,61.32 CMOS1.1 ; UC3.4 168.64,62.46 v2(169.47,63.28) ; v2(49.45,69.51) 49.64,69.69 JEDP1.45 ; UV501.2 265.82,80.06 266.13,80.37 v2(266.24,80.37) ; v2(184.82,59.14) 184.89,59.08 PR303.2 ; CZ50.2 CZ23.2 ; CZ23.2 CZ49.2 CZ24.2 ; CZ23.2 214.51,46.52 v2(214.72,46.73) ; RC241.2 131.73,86.65 v2(132.36,86.02) ; v2(51.61,75.79) 51.61,75.17 JEDP1.44 ; JSD1.3 v2(250.72,21.09) ; PU400.1 102.74,98.2 102.85,98.09 PR403.2 v2(103.38,98.91) ; JMINI3.34 39.06,15.45 v2(38.47,16.04) ; CI6.2 248.07,80.12 CI7.2 v2(248.91,82.27) ; v2(138.95,98.93) 138.95,98.46 v3(138.74,98.25) 138.72,98.25 137.91,97.43 C43.2 ; JSPI1.23 177.04,80.02 v2(177.32,80.3) 177.6,80.02 JSPI1.24 ; v2(147.1,86.14) RC142.1 ; JMINI3.40 38.72,13.05 v2(38.47,12.8) ; v2(193.22,75.74) 193.09,75.86 193.09,76.86 CV95.2 ; CV87.2 201.89,83.27 v2(201.83,83.33) ; QV2.3 60.54,63.81 v2(60.35,63.99) ; JSD1.21 248.93,18.55 248.17,19.3 v2(248.17,19.51) ; CV97.2 CV89.2 201.6,79.92 v2(202.04,79.48) ; v2(208.08,32.24) 208.08,31.48 208.61,30.95 JNGFF1.68 ; v2(46.6,18.45) 46.8,18.25 JMINI3.27 ; v2(196.34,83.16) 195.75,83.16 CV84.2 ; v2(190.47,55.74) 190.47,56.06 190.26,56.27 PC310.2 189.41,57.53 PC311.2 ; v2(207.19,71.41) 207.84,71.41 CV114.2 ; CV82.2 190.58,82.2 CV98.2 190.06,83.02 v2(189.73,83.35) ; v2(179.82,69.13) 179.21,68.52 JSPI1.22 ; CV90.2 199.56,85.79 v2(199.15,85.79) 198.91,85.55 CV100.2 ; CV116.2 205.4,81.43 CV518.2 205.21,82.52 v2(204.78,82.52) ; v2(256.1,5.5) JSD1.23 ; v2(124.45,33.31) 123.91,33.85 JDIMM1.206 ; CV509.2 v2(268.22,77.25) ; RC305.2 64.13,65.51 v2(64,65.37) ; RC186.1 140.61,88.06 140.21,87.65 CC82.2 v2(140.21,86.09) ; JRTC1.4 v2(224.65,102.91) ; JMINI3.9 v2(49.58,28.65) ; v2(182.18,84.25) 182.18,83.67 CV121.2 ; CV93.2 CV86.2 v2(201.32,81.87) ; v2(216.75,94.27) 216.75,94.69 UV10.2 ; JMINI3.53 v2(49.65,34.7) ; v2(46.6,17.18) 46.86,17.45 JMINI3.29 ; v2(257.54,32.45) 257.42,32.57 JSD1.24 ; CC8.1 135.74,86.92 v2(136.39,86.27) ; PC509.1 v2(87.87,67.6) ; CV12.2 64.05,70.6 v2(64.05,71.46) ; CA12.2 v2(275.81,41.46) ; JSD1.25 v2(269.15,4.37) ; v2(77.18,66.41) 77.2,66.38 PC503.1 ; JSD1.20 v2(248.93,5.54) ; RV62.2 RV64.2 216.89,89.1 v2(217.49,88.5) ; JSD1.17 v2(272.5,4.93) ; CV124.2 186.23,93.38 v2(186.17,93.32) ; RC185.2 RC21.2 109.54,67.67 v2(109.62,67.76) ; JSPI1.20 177.52,79.02 v2(177.34,78.84) 176.96,78.84 176.64,78.52 JSPI1.19 ; CC3.1 169.9,56.82 v2(170.05,56.67) ; v2(177.41,77.88) 177.55,78.02 JSPI1.18 ; v2(49.51,26.51) 49.24,26.25 JMINI3.15 ; v2(172.4,84.99) 172.45,85.05 UC2.4 ; v2(202.55,79.03) 203.06,78.52 CV94.2 ; v2(46.41,3.85) 47.6,5.04 JMINI3.54 ; v2(107.19,72.37) 107.64,71.93 RC188.2 RC184.2 RC183.2 ; v2(260.32,75.79) 261.01,75.79 261.72,76.5 261.72,78.08 CV510.2 ; v2(191.08,79.26) 190.91,79.26 190.58,79.6 CV91.2 CV83.2 ; JDIMM2.206 199.8,33.85 v2(199.64,34.01) ; JMINI3.18 38.89,21.85 v2(38.42,21.37) ; JRTC1.3 v2(231,102.91) ; DI3.1 v2(193.01,96.61) ; JMINI3.50 v2(38.59,9.05) ; C42.2 131.52,97.14 130.65,98.01 v2(130.65,98.6) ; v2(60.35,59.64) 60.35,59.5 60.86,58.99 RC129.1 ; v2(56.1,36.61) 56.65,36.06 JDIMM1.205 ; JSD1.10 v2(272.5,32.04) ; PC300.2 v2(193.68,58.27) ; v2(189.03,83.6) 188.98,83.65 RV508.1 ; v2(177.55,68.83) 177.23,68.52 JSPI1.21 ; JSD1.22 248.93,29.01 v2(248.98,28.96) ; PC400.2 v2(93.45,95.47) ; v2(168.01,80.14) 167.95,80.14 167.17,79.36 CC6.2 166.71,79.36 CC10.1 ; UV12.7 v2(185.71,78.22)
  vias: v2(0.53,43.5) v2(0.53,35.7) v2(0.53,27.91) v2(0.53,20.12) v2(0.53,12.33) v2(0.62,4.36) v2(0.81,1.05) v2(2.15,4.38) v2(2.4,1.05) v2(3.19,3.44) v2(3.42,2.07) v2(8.62,43.73) v2(13.51,2.45) v2(16.48,43.73) v2(21.26,2.45) v2(24.19,44.68) v2(26.84,22.38) v2(26.84,20.85) v2(26.84,19.33) v2(28.36,22.38) v2(28.36,20.85) v2(28.36,19.33) v2(29,2.45) v2(29.89,22.38) v2(29.89,20.85) v2(29.89,19.33) v2(31.61,47.63) v2(36.75,2.45) v2(37.99,52.24) v2(42.09,39.12) v2(42.98,40.84) v2(43.17,37.28) v2(43.68,27.22) v2(43.68,26.4) v2(43.68,25.56) v2(43.68,18.96) v2(43.84,17.18) v2(44.49,2.45) v2(45.35,62) v2(45.39,37.35) v2(45.52,40.84) v2(46.34,39.12) v2(47.17,47.79) v2(48.24,75.26) v2(48.37,82.52) v2(48.69,79.35) v2(49.64,82.65) v2(50.03,79.48) v2(50.85,81.7) v2(50.85,80.49) v2(51.8,53.5) v2(52.24,2.45) v2(55.55,63.22) v2(56.12,27.53) v2(56.95,78.33) v2(57.43,12.36) v2(57.43,11.69) v2(57.92,29.82) v2(57.92,28.29) v2(58.05,21.76) v2(58.05,20.24) v2(58.28,64.93) v2(59.87,47.03) v2(59.98,2.45) v2(61.12,22.02) v2(61.12,19.73) v2(61.07,11.79) v2(61.51,29.82) v2(61.71,11.79) v2(62.09,38.11) v2(62.71,112.49) v2(62.71,102.6) v2(62.71,92.7) v2(62.9,21.63) v2(62.9,20.11) v2(63.3,15.4) v2(63.93,57.95) v2(63.94,57.19) v2(63.93,15.4) v2(64.05,29.82) v2(64.44,112.49) v2(64.44,102.4) v2(64.57,15.4) v2(65.44,21.63) v2(65.44,20.11) v2(66.05,30.2) v2(66.05,27.91) v2(66.94,81.82) v2(67.1,21.63) v2(67.1,20.11) v2(67.3,89.74) v2(67.32,29.82) v2(67.32,28.29) v2(67.73,2.45) v2(68.55,7.53) v2(68.55,6.9) v2(68.55,6.26) v2(68.55,5.63) v2(68.55,4.99) v2(69.2,87.92) v2(69.29,7.9) v2(69.29,7.26) v2(69.29,6.63) v2(69.29,5.99) v2(69.29,5.36) v2(69.29,4.72) v2(69.86,29.82) v2(69.86,28.29) v2(70.05,7.58) v2(70.05,6.95) v2(70.05,6.31) v2(70.05,5.68) v2(70.05,5.04) v2(71.17,64.05) v2(71.37,21.63) v2(71.37,20.11) v2(71.93,88.24) v2(72.19,65.95) v2(72.19,30.2) v2(72.19,27.91) v2(72.5,61.89) v2(73.18,21.63) v2(73.18,20.11) v2(73.5,29.82) v2(73.5,28.29) v2(74.92,66.01) v2(74.92,62.01) v2(75.47,2.45) v2(75.72,20.11) v2(76,64.05) v2(76.04,29.82) v2(77.23,22.02) v2(77.23,19.73) v2(77.2,15.47) v2(77.84,15.47) v2(78.09,5.02) v2(78.5,21.63) v2(78.5,20.11) v2(78.92,3.47) v2(78.98,15.47) v2(78.98,6.74) v2(79.21,112.24) v2(79.21,102.4) v2(79.62,15.47) v2(79.93,92.75) v2(79.92,91.93) v2(80.06,63.22) v2(80.06,62.59) v2(80.06,61.44) v2(80.06,60.81) v2(80.54,112.24) v2(80.54,104.35) v2(80.81,92.75) v2(80.82,91.95) v2(80.76,15.47) v2(81.2,30.58) v2(81.2,29.05) v2(81.2,27.53) v2(81.39,15.47) v2(81.52,6.74) v2(81.52,3.47) v2(81.65,63.86) v2(81.65,63.22) v2(81.65,62.59) v2(81.65,61.95) v2(81.71,67.73) v2(81.71,66.9) v2(81.71,66.08) v2(81.71,65.25) v2(82.22,71.92) v2(82.35,68.05) v2(82.35,67.22) v2(82.35,66.4) v2(82.35,65.57) v2(82.28,63.86) v2(82.28,63.22) v2(82.34,5.02) v2(82.54,15.47) v2(82.62,22.18) v2(82.62,20.66) v2(82.62,19.13) v2(82.8,71.92) v2(82.92,63.86) v2(82.92,63.22) v2(83.05,72.49) v2(83.05,67.67) v2(83.05,66.84) v2(83.05,66.01) v2(83.05,65.19) v2(83.07,79.34) v2(83.17,15.47) v2(83.72,79.35) v2(84.12,30.58) v2(84.12,29.05) v2(84.32,79.35) v2(84.25,15.47) v2(84.37,97.71) v2(84.51,96.75) v2(84.57,96.11) v2(84.58,22.18) v2(84.58,20.66) v2(84.89,15.47) v2(85.14,96.49) v2(85.14,95.86) v2(85.71,59.41) v2(86.35,59.41) v2(86.36,21.42) v2(86.36,19.9) v2(86.79,76.3) v2(86.98,59.41) v2(87.52,30.58) v2(87.52,29.05) v2(87.62,59.41) v2(87.68,76.94) v2(88.2,96.94) v2(88.7,74.21) v2(88.73,73.38) v2(89.05,30.58) v2(89.05,29.05) v2(89.05,27.53) v2(89.55,74.21) v2(89.58,73.39) v2(89.66,22.18) v2(89.66,20.66) v2(90.48,74.21) v2(90.51,73.38) v2(90.57,30.96) v2(90.57,28.67) v2(90.61,21.42) v2(90.96,2.7) v2(91.56,29.82) v2(91.7,22.56) v2(91.7,20.28) v2(92.03,97.71) v2(93.08,82.14) v2(93.08,81.51) v2(93.08,80.87) v2(93.4,82.65) v2(93.42,30.58) v2(93.42,29.05) v2(93.4,22.18) v2(93.4,20.66) v2(93.71,82.14) v2(93.71,81.51) v2(93.71,80.87) v2(95.37,30.58) v2(95.37,29.05) v2(95.86,104.35) v2(95.86,23.71) v2(95.86,22.18) v2(95.86,20.66) v2(95.97,90.72) v2(96.56,90.72) v2(96.82,30.58) v2(96.82,29.05) v2(97.14,90.72) v2(97.33,85.7) v2(97.73,90.72) v2(97.65,85.19) v2(97.97,85.7) v2(98.29,85.19) v2(98.7,2.7) v2(99.11,110.78) v2(99.1,29.82) v2(99.1,28.29) v2(99.24,108.94) v2(99.19,104.25) v2(99.19,103.19) v2(99.44,21.42) v2(100.17,107.78) v2(100.52,89.66) v2(100.57,83.87) v2(100.57,61.73) v2(100.68,67.29) v2(100.88,30.2) v2(100.88,27.91) v2(101.26,103.68) v2(101.33,21.42) v2(101.58,85.77) v2(101.58,63.63) v2(101.9,81.71) v2(101.9,59.57) v2(102.03,53.31) v2(102.11,74.03) v2(102.39,107.85) v2(102.36,70.66) v2(102.39,67.29) v2(102.62,53.31) v2(102.91,29.82) v2(102.91,28.29) v2(103.24,109.07) v2(103.2,53.31) v2(103.3,110.78) v2(103.31,104.28) v2(103.3,103.16) v2(103.91,74) v2(103.87,21.42) v2(103.87,19.9) v2(104.08,70.66) v2(104.1,67.29) v2(104.32,85.83) v2(104.32,81.83) v2(104.32,63.69) v2(104.32,59.69) v2(105.14,94.53) v2(105.39,83.87) v2(105.39,61.73) v2(105.45,29.82) v2(105.7,73.99) v2(105.78,94.53) v2(105.79,70.66) v2(105.82,67.29) v2(105.99,21.8) v2(105.99,19.52) v2(106.26,112.24) v2(106.41,94.53) v2(106.45,2.7) v2(107.05,94.53) v2(107.24,29.82) v2(107.26,21.42) v2(107.26,19.9) v2(109.05,64.03) v2(109.29,62) v2(109.78,29.82) v2(109.78,28.29) v2(109.8,21.42) v2(109.8,19.9) v2(109.98,65.43) v2(110.51,63.12) v2(110.94,61.36) v2(111.3,76.3) v2(111.45,30.2) v2(111.45,27.91) v2(111.56,75.54) v2(112.25,21.42) v2(112.25,19.9) v2(112.33,56.81) v2(113.14,54.93) v2(113.55,58.14) v2(113.48,29.82) v2(113.48,28.29) v2(114.14,56.31) v2(114.19,2.7) v2(114.91,112.24) v2(114.88,21.42) v2(114.88,19.9) v2(115.39,57.75) v2(115.51,85.45) v2(115.5,55.02) v2(115.95,86.43) v2(116.02,29.82) v2(116.58,21.8) v2(116.58,19.52) v2(116.88,56.4) v2(117.01,81.31) v2(117.27,86.33) v2(117.67,84.82) v2(118.26,57.78) v2(119.49,81.29) v2(119.88,84.65) v2(119.88,53.95) v2(120,87.35) v2(120.32,54.33) v2(120.76,54.77) v2(122.42,84.35) v2(122.38,81.3) v2(122.99,58.49) v2(123.55,112.24) v2(124.07,86.65) v2(124.08,84.88) v2(124.26,90.14) v2(124.33,3.46) v2(124.87,81.29) v2(125.34,53) v2(125.46,53.57) v2(125.67,84.06) v2(126.07,59.32) v2(126.69,84.88) v2(127.09,19.62) v2(127.37,94.27) v2(127.39,81.3) v2(127.89,84.94) v2(127.98,21.34) v2(128.17,17.78) v2(128.64,95.1) v2(129.34,89.06) v2(129.9,81.3) v2(130.01,84.89) v2(130.16,90.72) v2(130.39,17.85) v2(130.52,21.34) v2(130.88,54.08) v2(130.88,53.45) v2(130.88,52.81) v2(131.12,89) v2(131.24,84.75) v2(131.34,19.62) v2(132.2,112.24) v2(132.41,81.3) v2(132.77,84.44) v2(132.92,57.75) v2(132.93,56.01) v2(133.47,3.46) v2(134.24,84.17) v2(134.55,56.2) v2(134.55,53.64) v2(134.55,52.34) v2(134.92,81.3) v2(136.51,56.89) v2(136.51,54.94) v2(137.42,81.3) v2(137.97,110.54) v2(138.54,56.89) v2(138.52,55) v2(138.5,22.24) v2(138.5,20.72) v2(138.76,83.34) v2(139.07,29.67) v2(139.07,28.15) v2(139.81,89.62) v2(140.14,56.81) v2(140.3,89.95) v2(140.85,112.24) v2(140.84,22.62) v2(140.84,20.34) v2(142.37,22.24) v2(142.37,20.72) v2(142.6,3.46) v2(143.59,73.63) v2(143.64,70.91) v2(143.81,29.67) v2(144.54,4.91) v2(144.61,65.34) v2(145.01,20.72) v2(145.34,3.34) v2(145.43,6.63) v2(145.8,30.05) v2(146.04,65.64) v2(147.07,29.67) v2(147.07,28.15) v2(147.55,22.24) v2(147.55,20.72) v2(147.97,6.63) v2(148.01,3.34) v2(148.61,49.44) v2(148.79,4.91) v2(149.4,92.56) v2(149.49,112.24) v2(149.61,29.67) v2(149.65,0.51) v2(150.36,22.24) v2(150.36,20.72) v2(151.8,30.05) v2(152.63,22.24) v2(153.04,70.28) v2(152.97,69.45) v2(153.19,29.67) v2(154.61,4.23) v2(154.61,3.59) v2(155.17,22.24) v2(155.17,20.72) v2(155.25,4.23) v2(155.25,3.59) v2(155.74,87.97) v2(155.74,87.39) v2(155.75,29.67) v2(155.89,83.87) v2(155.89,61.73) v2(155.88,4.23) v2(155.88,3.59) v2(156.33,87.97) v2(156.52,4.23) v2(156.52,3.59) v2(156.91,85.77) v2(156.91,63.63) v2(157.23,81.71) v2(157.23,59.57) v2(157.15,4.23) v2(157.15,3.59) v2(157.79,4.23) v2(157.79,3.59) v2(157.95,22.24) v2(157.95,20.72) v2(158.14,112.24) v2(158.15,0.51) v2(158.27,29.67) v2(158.42,4.23) v2(158.42,3.59) v2(159.06,4.23) v2(159.06,3.59) v2(159.64,85.83) v2(159.64,81.83) v2(159.64,63.69) v2(159.64,59.69) v2(160.44,50.1) v2(160.72,83.87) v2(160.72,61.73) v2(161.03,50.1) v2(161.15,110.78) v2(161.15,109.13) v2(161.37,23) v2(161.37,21.47) v2(161.61,50.1) v2(162.15,107.77) v2(162.22,50.1) v2(162.83,50.1) v2(163.1,23) v2(163.1,21.47) v2(163.44,50.1) v2(164.37,107.83) v2(165.23,23) v2(165.23,21.47) v2(165.28,110.78) v2(165.28,109.19) v2(165.55,30.45) v2(165.55,28.93) v2(166.65,0.51) v2(167.01,23) v2(167.01,21.47) v2(168.17,30.45) v2(168.17,28.93) v2(169.09,71.6) v2(169.24,23) v2(169.24,21.47) v2(169.5,29.69) v2(170.01,30.83) v2(170.1,20.71) v2(171.08,21.86) v2(171.81,76.16) v2(171.95,70.74) v2(172.35,23) v2(172.35,21.47) v2(172.52,30.45) v2(172.52,28.93) v2(173.91,23) v2(174.08,30.45) v2(174.08,28.93) v2(174.9,16.23) v2(175.15,0.51) v2(175.5,59.85) v2(175.75,0.71) v2(175.95,59.41) v2(176.07,59.98) v2(176.1,30.45) v2(176.1,28.93) v2(176.81,75.04) v2(176.84,71.98) v2(176.9,75.92) v2(176.87,73.95) v2(176.9,73) v2(176.92,70.81) v2(177.03,55.09) v2(177.47,54.58) v2(178.57,29.69) v2(180.26,7.21) v2(180.94,21.42) v2(181.4,30.07) v2(182.49,13.94) v2(182.63,54.78) v2(182.63,54.14) v2(182.63,53.51) v2(182.67,29.69) v2(182.67,28.17) v2(182.77,98.58) v2(183.38,15.66) v2(183.48,21.42) v2(183.48,19.9) v2(183.57,12.1) v2(183.76,70.21) v2(183.88,69.63) v2(183.92,0.71) v2(184.14,81.7) v2(184.07,48.11) v2(184.39,70.21) v2(184.52,69.63) v2(184.52,68.68) v2(184.65,98.59) v2(184.75,21.8) v2(184.92,29.69) v2(185.03,70.21) v2(185.79,12.17) v2(185.92,15.66) v2(186.11,7.02) v2(186.11,6.2) v2(186.74,68.17) v2(186.74,67.54) v2(186.68,66.9) v2(186.68,66.27) v2(186.68,65.63) v2(186.68,65) v2(186.74,13.94) v2(186.8,21.42) v2(186.94,112.49) v2(186.94,101.89) v2(186.87,7.02) v2(186.87,6.2) v2(187.04,29.69) v2(188.81,75.98) v2(189.03,7.15) v2(189.34,21.42) v2(189.41,47.03) v2(189.48,29.69) v2(189.48,28.17) v2(189.66,78.68) v2(189.66,7.15) v2(189.92,80.81) v2(191.12,21.42) v2(191.12,19.9) v2(191.83,30.07) v2(192.09,0.71) v2(192.49,63.27) v2(192.52,62.61) v2(193.1,63.09) v2(193.1,62.46) v2(193.22,60.87) v2(193.16,29.69) v2(193.16,28.17) v2(193.41,73.41) v2(193.64,65) v2(193.64,64.36) v2(193.64,63.73) v2(193.66,65.62) v2(193.71,63.09) v2(193.71,62.46) v2(193.66,21.42) v2(193.66,19.9) v2(194.93,85.45) v2(195.66,29.69) v2(195.83,37.06) v2(195.89,6.96) v2(196.04,21.8) v2(196.14,76.46) v2(196.2,7.47) v2(196.39,8.04) v2(196.52,6.96) v2(196.84,7.47) v2(196.94,75.21) v2(197.03,8.04) v2(197.16,6.96) v2(197.31,21.42) v2(197.31,19.9) v2(197.47,7.47) v2(197.66,8.04) v2(197.83,28.17) v2(197.79,6.96) v2(198.11,7.47) v2(198.43,6.96) v2(198.53,91.21) v2(198.74,7.47) v2(199.06,6.96) v2(199.38,7.47) v2(199.78,90.6) v2(199.77,39.42) v2(200.18,50.34) v2(200.18,49.45) v2(200.26,0.71) v2(200.4,39.42) v2(201.04,39.42) v2(201.07,50.34) v2(201.07,49.45) v2(201.46,112.49) v2(201.71,102.03) v2(201.66,58.9) v2(201.66,58.27) v2(201.85,62.08) v2(201.85,61.44) v2(201.85,60.81) v2(201.85,60.17) v2(201.85,59.54) v2(201.92,27.03) v2(201.92,26.39) v2(202.11,66.33) v2(202.3,58.9) v2(202.3,58.27) v2(202.43,65.82) v2(202.49,62.08) v2(202.49,61.44) v2(202.49,60.81) v2(202.49,60.17) v2(202.49,59.54) v2(202.57,26.36) v2(202.74,66.33) v2(202.68,24.23) v2(202.93,58.9) v2(202.93,58.27) v2(203.06,65.82) v2(203.12,62.08) v2(203.12,61.44) v2(203.12,60.81) v2(203.09,60.17) v2(203.09,59.54) v2(206.11,6.39) v2(206.43,5.88) v2(206.74,6.39) v2(207.06,5.88) v2(207.19,72.05) v2(207.19,70.78) v2(208.43,0.71) v2(208.7,81.71) v2(208.7,80.94) v2(208.7,80.18) v2(208.99,43.69) v2(209.58,43.69) v2(210.05,96.56) v2(210.02,90.72) v2(209.99,68.81) v2(210.01,68.21) v2(210.16,43.69) v2(210.49,46.9) v2(210.49,46.08) v2(210.49,45.31) v2(210.89,34.27) v2(211.78,35.99) v2(211.97,32.43) v2(212.27,96.56) v2(212.59,58.95) v2(213.73,20.7) v2(214.19,32.5) v2(214.29,60.35) v2(214.32,35.99) v2(214.36,96.56) v2(215.14,34.27) v2(216.6,0.71) v2(216.87,77.25) v2(216.87,75.73) v2(217.49,85.96) v2(218.09,67.12) v2(218.3,30.71) v2(218.3,29.82) v2(218.36,27.88) v2(218.59,94.27) v2(218.65,76.49) v2(218.76,87.23) v2(218.98,68.84) v2(219.14,100.1) v2(219.17,65.28) v2(219.29,49.78) v2(219.57,100.49) v2(219.57,99.67) v2(220.03,88.5) v2(220.03,85.96) v2(220.36,94.34) v2(220.43,77.25) v2(220.43,75.73) v2(221.39,65.35) v2(221.52,68.84) v2(222.11,99.67) v2(222.26,112.24) v2(222.34,67.12) v2(223.79,86.02) v2(224.77,0.71) v2(225.03,108.43) v2(225.92,110.27) v2(226.11,106.72) v2(227.5,94.39) v2(227.51,90.16) v2(227.51,47.6) v2(227.57,85.97) v2(227.57,81.95) v2(227.69,50.43) v2(227.69,48.9) v2(228.4,106.65) v2(228.46,110.34) v2(229.22,50.43) v2(229.22,48.9) v2(229.22,47.32) v2(229.35,108.56) v2(230.74,50.43) v2(230.74,48.9) v2(230.74,47.32) v2(232.44,98.65) v2(232.69,112.49) v2(232.94,0.71) v2(236.93,88.52) v2(236.93,87.76) v2(236.93,87) v2(237.55,95.24) v2(237.68,88.52) v2(237.69,87.76) v2(237.71,86.99) v2(238.44,87.77) v2(238.45,88.52) v2(238.45,87) v2(238.75,97.51) v2(240.08,96.81) v2(240.13,65.13) v2(240.13,63.35) v2(240.13,61.58) v2(240.78,96.81) v2(241.11,0.71) v2(241.91,65.13) v2(241.91,63.35) v2(241.91,61.58) v2(242.56,48.93) v2(243.69,65.13) v2(243.69,63.35) v2(243.69,61.58) v2(245.92,40.06) v2(247.61,85.29) v2(249.28,0.71) v2(251.7,79.35) v2(251.88,17.13) v2(251.88,15.35) v2(252.23,45.9) v2(252.23,45.31) v2(252.21,35.72) v2(252.89,78.85) v2(253.54,79.35) v2(253.54,78.33) v2(253.54,36.02) v2(253.54,15.15) v2(254.31,31.34) v2(254.31,30.71) v2(254.43,35.6) v2(254.98,82.08) v2(257.45,0.71) v2(258.75,23.85) v2(259.32,35.85) v2(259.32,34.2) v2(259.31,18.4) v2(259.31,17.13) v2(259.31,15.86) v2(259.77,21.5) v2(260.58,18.4) v2(260.58,17.13) v2(260.58,15.86) v2(260.97,37.5) v2(260.97,35.85) v2(260.97,34.2) v2(261.85,18.4) v2(261.85,17.13) v2(261.85,15.86) v2(262.62,37.5) v2(262.62,35.85) v2(262.62,34.2) v2(263.26,20.04) v2(265.62,0.71) v2(265.93,82.24) v2(266.18,18.71) v2(266.37,90.65) v2(267.45,67.35) v2(267.45,66.71) v2(268.15,89.51) v2(268.15,88.87) v2(268.78,89.51) v2(268.78,88.87) v2(269.86,67.79) v2(269.86,67.16) v2(270.65,44.84) v2(271.11,44.4) v2(274.12,95.86) v2(274.89,45.44) v2(275.41,45.14) v2(277.48,74.78) v2(278.09,40.12) v2(278.12,2.77) v2(278.69,0.74) v2(278.98,41.84) v2(279.17,38.28) v2(279.46,4.01) v2(280.34,94.27) v2(280.56,91.83) v2(280.72,91.08) v2(280.98,4.04) v2(281.39,38.34) v2(281.52,41.84) v2(281.61,90.59) v2(281.67,0.74) v2(282.11,2.36) v2(282.34,40.12) v2(282.63,90.72) v2(283.01,27.91) v2(283.01,20.29) v2(283.01,12.67) v2(283.01,5.05) v2(283.14,74.96) v2(283.32,42.58) v2(283.38,91.27) v2(283.36,38.07) v2(283.39,32.49) v3(57.68,13.63) v3(64.36,14.6) v3(69.42,8.5) v3(71.43,26.07) v3(82.86,62.27) v3(87.05,74.02) v3(98.79,91.16) v3(108.51,95.29) v3(120.51,53.12) v3(128.58,88.3) v3(140.83,89.64) v3(143.05,74.46) v3(156.52,88.68) v3(161.09,49.19) v3(176.52,60.62) v3(186.04,66.33) v3(193.73,86.72) v3(198.11,25.44) v3(198.93,90.59) v3(200.5,28.66) v3(207.57,7.47) v3(222.94,104.3) v3(268.72,88.24)
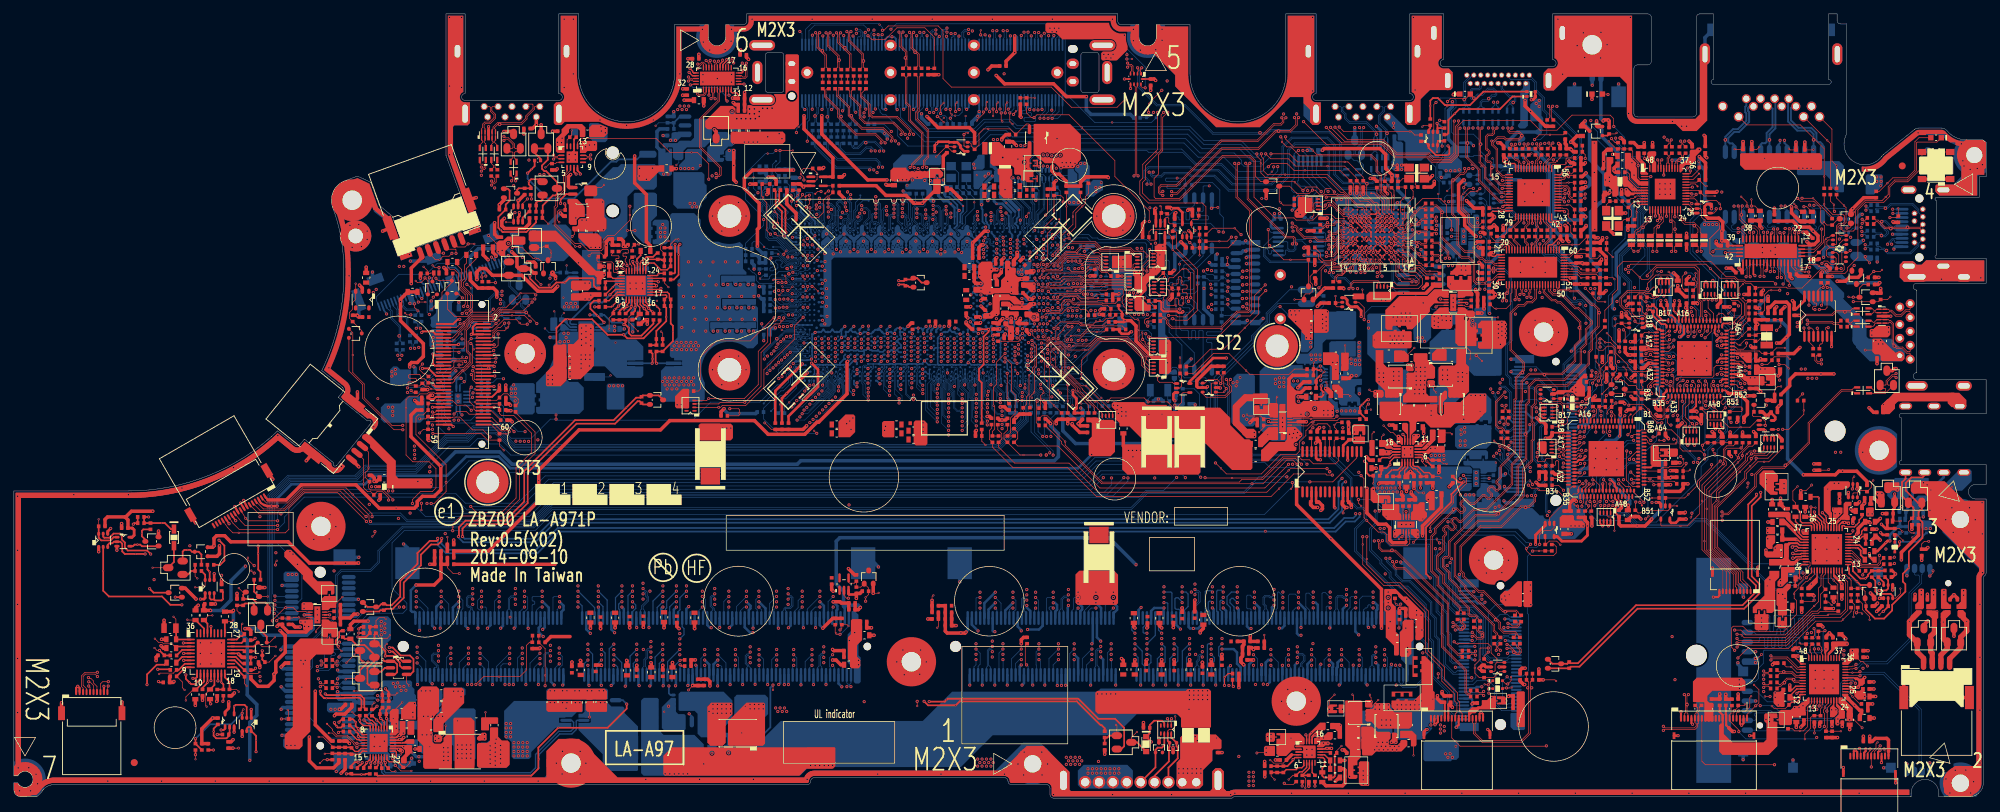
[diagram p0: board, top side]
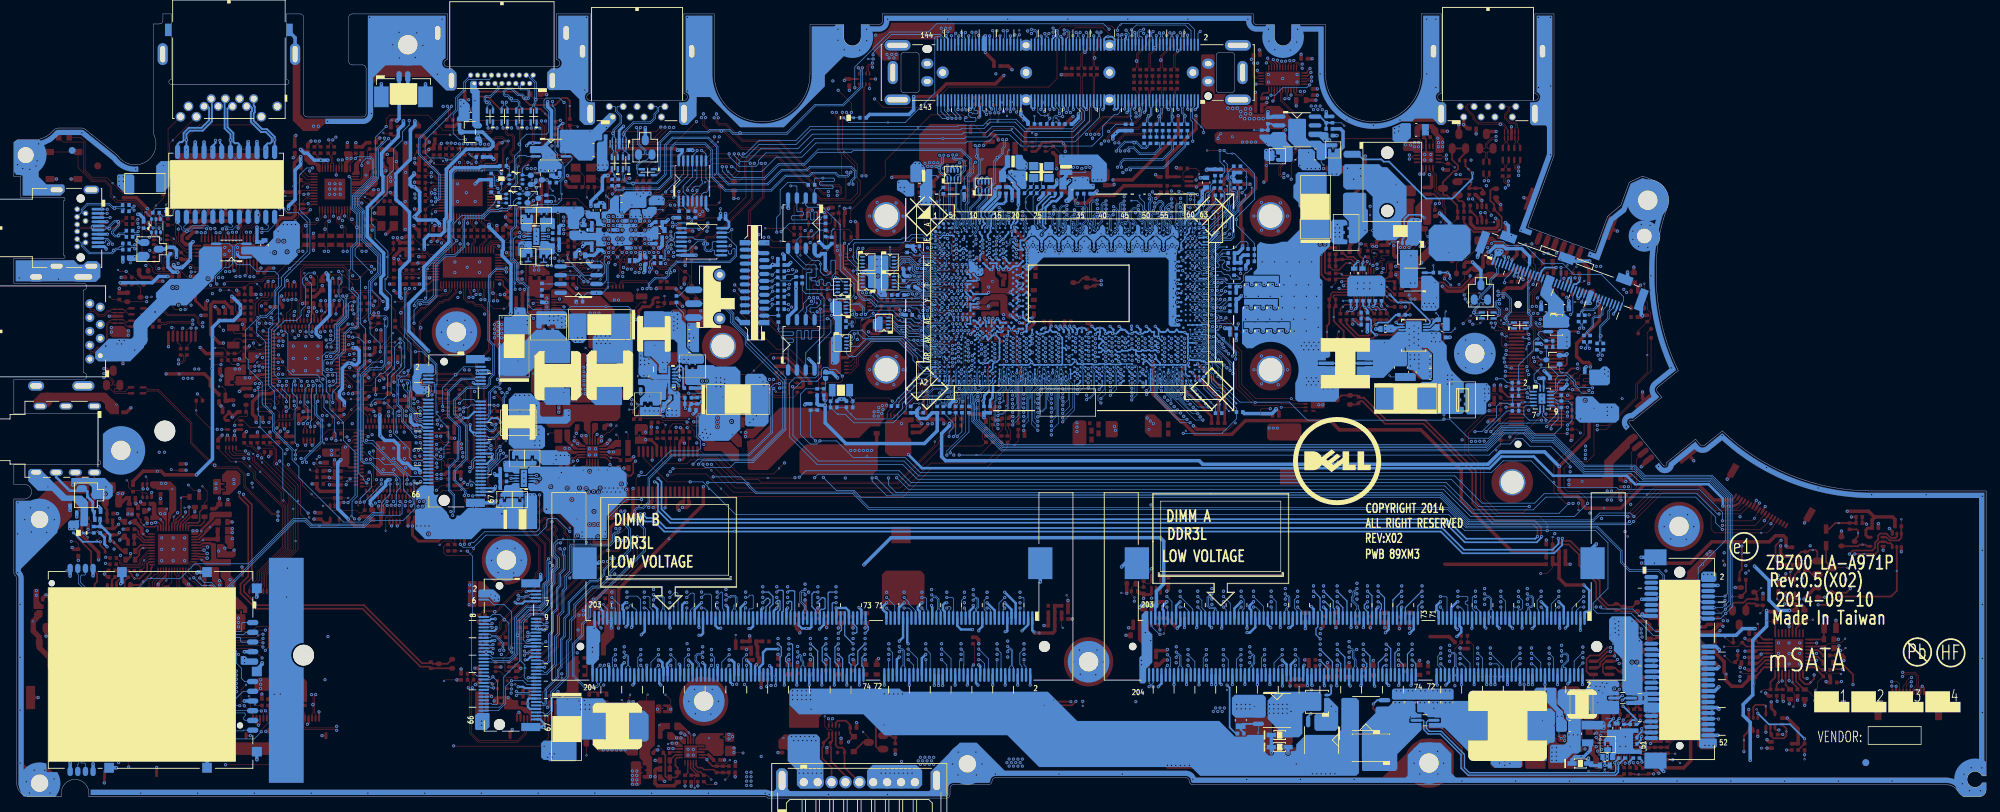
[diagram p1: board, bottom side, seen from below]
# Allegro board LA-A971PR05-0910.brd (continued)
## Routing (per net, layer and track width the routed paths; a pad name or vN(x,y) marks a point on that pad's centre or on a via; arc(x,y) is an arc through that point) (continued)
GNDA: length 63.2
  TOP w0.102: v2(257.23,44.3) 257.98,44.3 v3(258.79,45.11) ; RA37.1 261.15,47.24 v3(261.25,47.35) ; v3(275.64,36.99) 275.01,36.99 274.63,36.61 RA36.1
  TOP w0.432: QA2.4 v2(264.07,44.04) ; v2(265.29,44.55) 265.37,44.63 QA2.1
  TOP w0.508: v2(264.72,39.6) 264.72,40.19 CA8.2 ; CA35.1 266.04,42.14 v2(266.33,42.43) 266.41,42.51 CA4.2 ; RA37.1 v2(259.12,47.24) ; CA9.2 264.68,41.38 v2(264.43,41.63) ; v2(275.51,36.11) 275.27,35.86 RA36.1 ; v2(268.27,28.09) 267.84,27.66 RA2.2 ; CA3.2 v2(268.97,41) ; CA17.2 254.93,41.71 CA18.2 v2(254.31,43.22) ; CA26.2 268.17,39.81 v2(268.67,40.31) ; RA44.2 267.47,37.2 CA51.2 268.15,37.69 v2(268.66,37.19) ; CA52.2 v2(252.49,39.79) ; CA16.2 v2(252.46,37.38) ; CA25.2 v2(257.23,44.3)
  GND1 w0.203: 275.27,56.48 JHP1.7 ; JHP1.7 276.4,57.15 ; JHP1.7 275.27,57.15 ; JHP1.7 277.54,55.81 ; JHP1.7 276.4,55.81 ; JHP1.7 277.54,57.15 ; JHP1.7 275.27,55.81 ; JHP1.7 277.54,56.48
  GND2 w0.203: JHP1.7 277.54,55.81 ; JHP1.7 275.27,55.81 ; JHP1.7 277.54,56.48 ; JHP1.7 275.27,57.15 ; JHP1.7 276.4,55.81 ; JHP1.7 277.54,57.15 ; JHP1.7 275.27,56.48 ; JHP1.7 276.4,57.15
  IN2 w0.508: v2(269.48,35.89) 269.48,28.68 268.9,28.09 v2(268.27,28.09)
  VCC w0.203: JHP1.7 277.54,56.48 ; JHP1.7 275.27,56.48 ; JHP1.7 276.4,57.15 ; JHP1.7 277.54,57.15 ; JHP1.7 275.27,57.15
  GND3 w0.203: 275.27,57.15 JHP1.7 ; JHP1.7 275.27,56.48 ; JHP1.7 276.4,57.15 ; JHP1.7 275.27,55.81 ; JHP1.7 276.4,55.81 ; JHP1.7 277.54,56.48 ; JHP1.7 277.54,57.15 ; JHP1.7 277.54,55.81
  BOTTOM w0.508: CA1.2 v2(274.85,40.53) ; CA2.2 271.42,41.71 v2(271.73,42.01)
  vias: v2(254.81,45.31) v2(254.81,44.61) v2(257.54,38.52) v2(258.13,38.52) v2(263.51,39.73) v2(264.08,39.6)
GNDA_CHG: length 43.7
  TOP w0.508: v2(26.21,28.69) 26.21,28.7 24.66,30.25 PQ712.3
  IN2 w0.508: v2(26.21,28.69) 26.21,28.98 26.66,29.43 30.34,29.43 32.5,27.27 34.05,27.27 37.81,23.51 37.81,18.45 39.22,17.04 39.22,15.94 48.88,6.27 50.7,6.27 v2(51.87,7.44)
  BOTTOM w0.102: PC703.2 55.39,9.53 v1(55.45,9.59)
  vias: v2(51.93,8.84) v2(52.69,7.44) v2(53.33,8.2)
VCCSENSE: length 31.7
  TOP w0.254: RC209.2 110.18,87.43 110.18,85.71 111.06,84.82 v1(111.06,83.6) 111.06,81.58 v2(111.13,81.52) ; v2(95.17,79.8) 95.17,75.73 95.05,75.61 PR531.1
  IN1 w0.254: v2(111.13,81.52) 111.13,81.71 110.49,82.34 106.87,82.34 104.57,80.04 97.92,80.04 97.33,80.62 95.97,80.62 95.17,79.82 v2(95.17,79.8)
  BOTTOM w0.203: UC1.E63 112.1,80.13 111.01,81.22 111.01,81.4 v2(111.13,81.52)
VDD_1.35V: length 10
  TOP w0.102: v1(191.11,7.52) 190.42,6.83 PR201.1
  TOP w0.203: PU200.11 188.44,5.84 188.67,5.61 188.67,5.44
  TOP w0.254: PR201.1 190.13,6.22 190.13,3.15 189.95,2.97 PC211.1 188.6,2.97 188.34,3.23 PR202.2 188.34,4.34 188.67,4.67 188.67,5.44
VSSSENSE: length 32.4
  TOP w0.254: PR532.1 94.99,74.72 95.68,75.41 v1(95.68,78.33) 95.68,79.61 v2(95.87,79.8) ; v2(110.56,81.52) 110.56,84.54 109.67,85.43 109.67,87.43 RC218.1
  IN1 w0.254: v2(110.56,81.52) 110.56,81.58 110.3,81.83 107.19,81.83 104.89,79.53 97.66,79.53 97.08,80.11 96.18,80.11 v2(95.87,79.8)
  BOTTOM w0.203: v2(110.56,81.52) 110.7,81.38 110.7,81.1 112.08,79.72 112.89,79.72 UC1.E62
3301_ACAV_IN_NB: length 2
  TOP w0.254: PR848.1 33,21.35 PU800.24
3301_PWRSRC: length 5.3
  TOP w0.102: v1(27.75,13.18) 27.61,13.32 27.61,15.04 PR860.1
  TOP w0.254: PU800.15 28.86,16.29 PR860.1
+AUX_LDO: length 5.8
  TOP w0.102: v1(253.05,13.26) 253.38,12.93 255.02,12.93 CR17.2
  TOP w0.203: CR17.2 255.91,13.82 256.64,13.82 257.09,14.27 257.09,14.87 257.14,14.93 UR1.12
+BL_PWR_SRC: length 2.3
  BOTTOM w0.102: QV1.2 63.7,68.17 63.97,67.89 64.47,67.89 64.8,68.22 v3(64.8,68.52)
+CAP_LDO: length 7.9
  TOP w0.305: UE1.B46 230.72,44.67 230.42,44.97 230.42,45.32 229.87,45.87 v2(229.76,45.87)
  TOP w0.508: CE7.1 232.39,41.53 v2(232.39,42.2)
  BOTTOM w0.508: v2(232.39,42.2) 232.59,42.4 232.59,42.84 230.38,45.05 230.38,45.56 230.07,45.87 v2(229.76,45.87)
+COINCELL: length 8.5
  TOP w0.508: v2(228.78,97.57) 228.93,97.73 229.49,97.73 v1(229.53,97.69) 229.64,97.58 PR1.1
  BOTTOM w0.508: JRTC1.1 228.45,97.9 v2(228.78,97.57)
+DC_IN: length 130.2
  TOP w0.102: PR14.1 80.7,81.25 v3(80.37,80.92)
  TOP w0.508: PR737.1 45.71,8.23 43.38,10.55 v2(43.38,15.4) ; PR835.1 v2(21.62,25.63)
  IN2 w0.508: v2(43.38,15.4) 43.04,15.4 42.47,15.98 42.47,18.26 42.66,18.45 42.66,21.95 47.93,27.22 47.93,33.92 49.68,35.67 50.53,35.67 54.66,39.8 54.66,41.75 57.52,44.61 57.52,47.65 59.07,49.2 59.07,56.15 60.05,57.12 60.63,57.12 61.27,57.76 61.27,60.19 61.71,60.64 61.71,64.23 64.61,67.13 65.21,67.13 68.39,70.31 68.39,72.48 69.93,74.02 69.93,74.53 72.02,76.62 74.18,76.62 75.68,78.12 75.68,80.49 76.76,81.57 80.06,81.57 v2(81.78,83.29)
  IN3 w0.508: v2(43.38,15.4) 35.06,15.4 32.55,17.92 27.3,17.92 26.02,16.64 24.98,16.64 22.78,18.83 22.78,24.46 v2(21.62,25.63)
  vias: v2(82.41,83.29) v3(84.76,85.89) v3(84.89,81.89)
+DC_IN_SS: length 186.6
  TOP w0.508: v2(26.53,27.79) 26.15,27.41 PR831.1 ; PD817.3 28.6,36.15 v2(28.8,36.35) 28.8,37.44 29.17,37.81 30.34,37.81 31.22,36.93 39.48,36.93 42.56,33.86 v3(47.74,33.86) 49.58,33.86 v2(49.61,33.88)
  IN1 w0.508: v2(58.34,5.31) 59.45,5.31 61.34,3.42 74.23,3.42 78.82,8 81.66,8 83.19,6.47 v2(100.49,6.47) ; v2(28.8,36.35) 28.8,33.57 27.46,32.22 27.46,28.21 27.04,27.79 v2(26.53,27.79)
  IN2 w0.508: v2(49.61,33.88) 50.81,33.88 56.02,39.09 56.02,42.21 58.15,44.35 58.15,47.38 61.14,50.37 61.14,56.25 62.15,57.26 62.15,58.71 63.42,59.98 63.42,60.45 67.3,64.32 67.3,65.06 68.34,66.1 69.79,66.1 74.12,70.43 76.35,70.43 80.12,74.21 v2(82.22,74.21) ; v2(26.53,27.79) 28.88,25.44 34.09,25.44 36.46,23.06 36.46,16.71 49.64,3.53 57.59,3.53 58.34,4.28 v2(58.34,5.31)
  BOTTOM w0.508: v2(100.49,6.47) PD704.2
  vias: v2(82.84,74.21)
+DCIN: length 2
  TOP w0.102: v1(55.91,13.79) 54.95,12.84 PC709.1
  vias: v2(55.04,10.71) v2(55.04,10.07)
+DCIN_JACK:
  vias: v2(90.03,89.64) v3(90.07,90.74) v3(91.05,89.17) v3(91.92,90.77)
+DCPRRTC: length 0.5
  BOTTOM w0.229: UC1.AE7 147.31,69.22 v2(147.38,69.3)
  vias: v1(147.24,69.8)
+DIMM1_VREF_DQ: length 17.9
  TOP w0.102: v3(64.12,32.36) 63.23,32.36 62.4,33.19 RD4.2
  TOP w0.508: CD1.1 61.47,31.68 60.5,30.71 v2(57.9,30.71) ; CD1.1 CD5.1 RD6.1 ; CD1.1 RD4.2 RD5.1
  BOTTOM w0.356: v2(57.9,30.71) 57.14,29.95 57.14,27.03 57.33,26.83 57.65,26.83 57.8,26.68 JDIMM1.1
+DIMM2_VREF_DQ: length 9.9
  TOP w0.508: v2(137.06,23.92) 136.92,23.79 v3(136.32,23.79) 134.35,23.79 134.07,24.07 CD33.1 CD34.1 RD24.1 RD22.2 RD23.1
  BOTTOM w0.356: JDIMM2.1 137.3,24.17 v2(137.06,23.92)
+DOCK_PWR_BAR: length 11.2
  TOP w0.508: v2(28.3,27.04) 28.28,27.05 PR832.2 27.36,27.86 PR814.2
  BOTTOM w0.508: v2(28.3,27.04) 29.74,27.04 31.24,28.54 31.24,31.33 v2(33.34,33.43)
  vias: v2(100.64,13.5) v2(100.64,12.86) v2(100.64,12.23) v2(101.27,13.5) v2(101.27,12.86) v2(101.27,12.23) v2(101.91,13.5) v2(101.91,12.86) v2(101.91,12.23) v2(102.54,13.5) v2(102.54,12.86) v2(102.54,12.23) v2(103.18,13.5) v2(103.18,12.86) v2(103.18,12.23) v3(100.06,12.48) v4(104.06,97.9) v4(104.7,97.9) v4(105.36,97.89) v4(105.89,99.3) v4(105.89,98.61) v4(106.03,97.89) v4(106.59,99.3) v4(106.59,98.61) v4(106.73,97.89) v4(107.29,98.92) v4(107.29,98.22) v4(107.8,99.4) v4(108.46,99.38) v4(109.14,99.42)
+LCDVDD: length 10.3
  TOP w0.102: v2(57.65,71.22) 57.65,70.71 v3(58.15,70.21)
  IN4 w1.016: 56.19,70.97 54.15,68.94 54.15,63.28 54.53,62.9
  vias: v2(51.74,72.86) v2(52.16,73.3) v2(54.41,61.44) v2(54.41,60.81) v2(54.92,61.76) v2(54.92,61.12) v2(57.01,71.28)
+LOM_VCT: length 4.9
  TOP w0.508: C316.1 142.83,106.19 v3(144.07,107.43) v2(144.07,109.83)
+MIC1_VREF_OUT: length 21.8
  TOP w0.203: v2(260.33,41.12) v1(260.89,40.56) 260.89,39.8 261.17,39.52 UA1.30
  TOP w0.254: DA4.2 270.75,35.73 271.45,36.42 v2(271.45,36.93)
  IN4 w0.254: v2(271.45,36.93) 270.65,37.73 264.81,37.73 262.94,39.6 261.4,39.6 260.33,40.67 v2(260.33,41.12)
  BOTTOM w0.254: v2(271.45,36.93) 273.98,36.93 275.26,38.21 DA5.2
+NBDOCK_DC_IN_SS: length 170.7
  TOP w0.508: v2(29.59,36.35) 29.59,35.2 29.23,34.85 PD817.2 ; PR863.2 34.11,17.16 35.15,16.12 36.61,16.12 37.45,16.96 v3(37.45,17.86) 37.45,17.87 37.71,18.12 37.71,19.66 39.05,21.01 39.05,23.41 v2(38.32,24.14)
  IN2 w0.508: v2(123.68,98.79) 123.68,98.31 121.93,96.56 111.02,96.56 109.21,94.74 108.38,93.92 104.73,93.92 104.12,94.53 102.27,94.53 101.33,93.59 93.34,93.59 90.74,90.99 88.97,90.99 88.48,90.5 83.86,90.5 81.93,88.57 76.68,88.57 75.05,86.94 72.23,86.94 68.59,83.31 68.59,81.45 61.19,74.05 58.2,74.05 55.49,71.33 55.49,65.71 53.8,64.03 53.8,59.19 55.14,57.84 55.14,54.86 54.27,53.99 54.27,51.23 47.91,44.87 36.31,44.87 34.02,42.58 34.02,40.3 30.07,36.35 v2(29.59,36.35)
  IN4 w0.508: v2(29.59,36.35) 32.82,36.35 37.85,31.32 37.85,30.37 38.58,29.63 38.58,24.41 v2(38.32,24.14)
  BOTTOM w0.254: JDOCK1.41 123.45,99.01 v2(123.68,98.79)
+PBATT: length 99.1
  TOP w0.508: v2(31.6,27.04) 31.43,26.87 PR838.2
  IN3 w0.508: v2(57.25,5.75) 55.37,3.87 49.12,3.87 48.37,4.62 34.79,4.62 v2(33.96,5.45)
  IN3 w0.762: v2(99.3,4.93) 95.3,8.93 78.98,8.93 73.88,3.82 58.19,3.82 57.25,4.76 v2(57.25,5.75)
  BOTTOM w0.508: v2(33.96,5.45) 33.96,10.92 34.96,11.92 34.96,13.5 33.59,14.87 33.59,22.77 31.6,24.76 v2(31.6,27.04) ; v2(57.25,5.75) 57.25,5.03 PD702.2 56.93,4.71 PR723.2
  vias: v2(93.75,3.52) v2(94.41,3.49) v2(95.07,3.48) v2(95.72,3.5) v2(96.34,3.49) v2(96.98,3.49) v2(114.68,4.71) v2(115.34,4.7) v2(115.99,4.7) v2(116.65,4.7) v2(117.26,4.71) v2(117.84,4.72) v2(155.99,15.01) v2(156.63,15.01) v2(157.26,15.01) v2(157.9,15.01) v2(158.6,15.01) v2(169.22,15.47) v2(169.22,14.83) v2(169.22,14.2) v2(169.85,15.47) v2(169.85,14.83) v2(169.85,14.2) v2(170.49,15.47) v2(170.49,14.83) v2(170.49,14.2) v2(171.12,15.47) v2(171.12,14.83) v2(171.12,14.2) v2(171.82,15.47) v2(171.82,14.83) v2(171.82,14.2) v3(169.15,12.8)
+PCH_ASATA3PLL: length 7.6
  BOTTOM w0.254: UC1.B11 144.55,82.36 UC1.A12 144.35,83 144.35,83.49 144.66,83.79 v1(144.66,84.77)
  BOTTOM w0.508: RC17.2 142.29,88.06 v2(142.67,87.68) 142.67,86.75 v1(144.66,84.77)
+PCH_AUSB3PLL: length 8.5
  BOTTOM w0.254: RC149.1 134,86.74 134.1,86.64 134.62,86.64 135.81,85.45 135.81,84.95 v2(136.07,84.68) 135.81,84.42 135.81,82.53 UC1.B27 ; v2(139.91,84.01) 139.91,83.13 140.1,82.94 140.1,82.77 140.37,82.5 UC1.B18
  vias: v1(138.61,89.76)
+PCH_RTC_VCCSUS3_3: length 18.5
  TOP w0.381: v2(152.45,58.75) 152.45,58.08 152.96,57.57 v1(152.96,56.62) 152.96,56.16 152.66,55.85 RC212.2 RC213.2
  TOP w0.508: CC73.1 144.45,67.02 v2(144.42,66.99)
  IN3 w0.381: 145.16,65.58 145.21,65.53 145.21,61.1 146.01,60.3 149.81,60.3 151.08,59.03 152.18,59.03 v2(152.45,58.75)
  BOTTOM w0.229: v2(144.42,66.99) 144.73,67.3 144.77,67.3
  BOTTOM w0.254: UC1.AH11 144.77,67.3
+PCH_VCC1P05: length 25.4
  TOP w0.508: CC78.1 141.32,77.72 v2(141.48,77.88)
  IN2 w0.508: v2(131.94,89) 135.5,85.45 135.5,81.06 139.4,77.16 140.75,77.16 v2(141.48,77.88)
  BOTTOM w0.102: v1(129.67,90.28) 129.78,90.17 LC4.2
  BOTTOM w0.229: UC1.K19 140.66,77.08 141.02,77.44 UC1.J18 141.02,77.66 141.25,77.88 v2(141.48,77.88)
  BOTTOM w0.508: LC4.2 132.45,89.64 132.89,89.19 CC77.1 132.39,88.56 v2(131.94,89)
+PCH_VCCACLKPLL: length 21.8
  IN2 w0.508: v2(133.78,89.06) 133.78,88.43 135.24,86.97 137.85,86.97 v2(139.31,85.51)
  BOTTOM w0.102: LC5.2 140.87,93.17 v1(140.67,93.37)
  BOTTOM w0.254: UC1.A20 139.43,83.07 139.43,84.81 139.31,84.94 v2(139.31,85.51)
  BOTTOM w0.508: RC69.2 134.15,88.06 133.78,88.43 v2(133.78,89.06) ; v2(139.31,85.51) 139.29,85.52 CC82.1 139.29,87.65 139.94,88.3 139.94,88.68 140.83,89.57 CC81.1 141.59,90.4 140.87,91.12 LC5.2
+PCH_VCCDSW: length 16.9
  TOP w0.254: CC97.2 140.28,67.56 v2(140.31,67.54) 140.31,67.2 139.59,66.49 139.59,62.49 138.93,61.82 138.93,60.24 139.32,59.85 v1(139.32,56.24) RC211.2
  BOTTOM w0.229: UC1.AG20 139.9,67.94 v2(140.31,67.54) 140.72,67.94 UC1.AG19
+PCH_VCCDSW3_3: length 161.6
  TOP w0.305: 35.99,42.24 35.55,42.52 JAPS1.3 ; JAPS1.7 v2(33.07,42.9)
  TOP w0.381: v2(37.9,42.07) v3(37.07,42.07) 36.51,42.07 35.99,42.24
  TOP w0.508: CC97.1 137.9,67.56 137.07,68.39 v2(137.07,68.6) ; v2(146.19,66.83) 145.78,67.25 CC80.1
  IN3 w0.254: v2(146.19,66.83) 145.85,67.18 145.85,67.8 145.49,68.16 142.56,68.16 141.9,68.82 141.9,70.12 141.68,70.33 137.77,70.33 136.82,69.38 136.82,68.86 v2(137.07,68.6)
  IN3 w0.381: v2(33.07,42.9) 33.9,42.07 v2(37.9,42.07)
  IN3 w0.508: 151.02,65.57 151.02,61.65 156.12,56.54 v2(156.12,53.96)
  BOTTOM w0.254: UC1.AH10 145.72,67.3 v2(146.19,66.83)
  BOTTOM w0.381: v2(37.9,42.07) 37.9,43.17 39.96,45.24 50.53,45.24 51.75,46.46 62.34,46.46 65.1,49.21 69.78,49.21 71.46,47.54 153.18,47.54 v2(155.15,49.5)
+PCH_VCCDSW_R: length 2.5
  TOP w0.102: v1(139.87,50.89) 139.33,51.42 CC65.1
  TOP w0.254: RC211.1 139.32,52.19 CC65.1
+PWR_SRC: length 45.7
  IN2 w3.048: 52.25,27.53 52.25,28.9 58.81,35.47 58.81,38.48 63.49,43.15 63.49,50.35 66.68,53.55
  IN4 w1.27: 194.3,55.79 201.92,55.79 204.71,53 206.81,53
  vias: v2(60.35,66.4) v2(60.35,65.76) v2(60.35,65.13) v2(70.87,10.74) v2(70.87,10.11) v2(70.87,9.47) v2(70.87,8.84) v2(71.5,10.74) v2(71.5,10.11) v2(71.5,9.47) v2(71.5,8.84) v2(71.6,58.97) v2(71.6,58.33) v2(71.93,59.54) v2(71.98,7.99) v2(71.98,7.35) v2(71.98,6.72) v2(71.98,6.08) v2(72.19,58.97) v2(72.19,58.33) v2(72.16,57.24) v2(72.62,7.99) v2(72.62,7.35) v2(72.62,6.72) v2(72.62,6.08) v2(73.25,7.99) v2(73.25,7.35) v2(73.25,6.72) v2(73.25,6.08) v2(73.89,7.99) v2(73.89,7.35) v2(73.89,6.72) v2(73.89,6.08) v2(77.2,13.75) v2(77.84,13.75) v2(78.98,13.75) v2(79.62,13.75) v2(80.82,13.75) v2(81.46,13.75) v2(138.74,5.63) v2(138.74,4.61) v2(139.05,5.12) v2(139.37,5.63) v2(139.37,4.61) v2(139.69,5.12) v2(140.01,5.63) v2(140.01,4.61) v2(140.32,5.12) v2(140.64,5.63) v2(140.64,4.61) v2(140.96,5.12) v2(151.5,5.88) v2(151.5,4.86) v2(151.82,5.37) v2(152.13,5.88) v2(152.13,4.86) v2(152.45,5.37) v2(152.77,5.88) v2(152.77,4.86) v2(153.09,5.37) v2(153.4,5.88) v2(153.4,4.86) v2(153.72,5.37) v2(177.79,3.72) v2(177.79,3.09) v2(177.79,2.45) v2(177.79,1.82) v2(178.42,3.72) v2(178.42,3.09) v2(178.42,2.45) v2(178.42,1.82) v2(191.12,55.79) v2(191.76,55.79) v2(192.39,55.79) v2(193.03,55.79) v2(194.23,3.91) v2(194.23,3.28) v2(194.23,2.64) v2(194.23,2.01) v2(194.87,3.91) v2(194.87,3.28) v2(194.87,2.64) v2(194.87,2.01) v2(208.2,51.47) v2(208.2,50.84) v2(208.33,53.06) v2(208.33,52.43) v2(208.84,53.38) v2(208.84,52.74) v2(208.9,51.47) v2(208.9,50.84) v3(79.49,12.93)
+PWR_SRC_AC: length 29.5
  TOP w0.254: v2(28.33,13.59) 28.23,13.68 PR860.2
  IN3 w0.254: v2(28.33,13.59) 28.33,14.08 28.76,14.52 30.96,14.52 32.1,13.37 47.73,13.37 50.89,16.53 v2(54.61,16.53)
  vias: v1(105.27,13.22) v2(54.93,16.03) v2(55.25,16.6) v2(55.56,16.09) v2(55.74,15.52) v2(56.15,16.09) v2(56.43,15.54) v2(105.97,13.5) v2(105.97,12.86) v2(106.6,13.5) v2(106.6,12.86) v2(107.24,13.5) v2(107.24,12.86) v2(107.87,13.5) v2(107.87,12.86)
+RSVD_VCC3P3_1:
  vias: v1(234.09,91.93)
+RTC_CELL: length 244.1
  TOP w0.254: RPE5.6 247.24,74.4 v2(247.31,74.47) 247.74,74.03 RPE5.5
  TOP w0.508: RA21.1 266.75,45.63 265.28,47.1 v3(263.25,47.1) 262.71,47.1 262.19,46.58 v2(257.61,46.58) ; RE62.1 250.81,70.59 v2(251.29,70.59) ; RE32.1 v2(252.51,72.3) ; RE31.1 251.56,72.92 v2(251.83,73.19) ; v2(226.17,97.57) 225.71,97.11 PC1.1 226.13,96.8 PD3.1
  IN3 w0.381: v2(143.49,66.98) 143.49,67.34 143.8,67.64 v2(145.17,67.64)
  IN3 w0.508: v2(153.57,56.21) 151.9,56.21 149.66,58.46 146.99,58.46 145.33,60.12 144.59,60.12 143.83,60.88 143.83,61.89 143.49,62.23 v2(143.49,66.98) ; v2(251.83,73.19) 248.58,73.19 v2(247.31,74.47) ; v2(167.12,56.62) 168.52,56.62 169.07,56.06 182.38,56.06 183.44,57.12 183.44,61.25 182.77,61.92 180.42,61.92 178.42,63.92 178.42,68.81 181.51,71.89 188.13,71.89 188.3,71.72 195.74,71.72 196.3,71.15 198.49,71.15 199.11,71.77 204.34,71.77 205.35,72.79 208.29,72.79 209.14,71.93 212.12,71.93 213.06,70.99 215.11,70.99 215.48,71.36 215.48,72.75 216.86,74.12 221.74,74.12 223.22,72.64 224.92,72.64 225.5,72.06 228.13,72.06 v2(228.14,72.05)
  IN4 w0.508: v2(247.31,74.47) 247.31,74.73 246.96,75.07 245.49,75.07 244.91,75.65 242.71,75.65 241.44,76.92 238.02,76.92 237.81,77.14 236.62,77.14 236.02,76.53 234.05,76.53 232.22,74.7 229.32,74.7 228.33,73.71 228.33,72.24 v2(228.14,72.05) ; v2(252.51,72.3) 252.51,72.5 v2(251.83,73.19)
  BOTTOM w0.229: UC1.AG10 145.51,67.99 v2(145.17,67.64)
  BOTTOM w0.508: RC78.2 153.94,55.52 RC9.1 ; RC78.2 153.92,55.86 v2(153.57,56.21) ; RC78.2 153.92,55.1 153.53,54.71 152.51,54.71 151.7,55.52 RC1.1 150.99,52.93 152.83,51.09 164.14,51.09 167.12,54.08 v2(167.12,56.62) 168.06,56.62 RC10.1 RC8.1 ; v2(252.51,72.3) 251.29,71.08 v2(251.29,70.59) 251.29,69.79 252.27,68.81 254.31,68.81 255.32,67.79 255.32,48.87 v2(257.61,46.58) ; v2(228.14,72.05) 228.36,72.27 228.36,76.1 226.95,77.51 226.95,84.43 228.24,85.72 228.33,85.72 228.91,86.29 228.91,89.96 226.82,92.05 226.82,96.3 226.17,96.95 v2(226.17,97.57)
+RTC_CELL_VBAT: length 21.4
  TOP w0.305: v2(245.83,65.19) 245.99,65.35 UE2.B64
  TOP w0.508: CE11.1 RE32.2 252.78,70.71 253.54,71.48 255.17,71.48 255.58,71.07 255.58,66.82 v1(255.13,66.37) 254.32,65.57 v2(253.73,65.57)
  IN1 w0.508: v2(253.73,65.57) 253.73,64.54 253.18,63.98 250.06,63.98 249.25,64.79 246.54,64.79 246.13,65.19 v2(245.83,65.19)
+SD_IO_LDO: length 3.8
  TOP w0.508: 264.02,14.33 v1(264.97,13.37) 265.73,12.62 CR15.2 265.96,12.2 265.72,11.96 CR14.2
+SDC_IN: length 64.4
  TOP w0.203: PU700.3 52.9,10.58 v2(52.23,11.25) 51.62,11.86 PR710.2
  TOP w0.254: v2(19.16,16.36) 19.16,17.82 20.56,19.21 21.68,19.21 PR847.1
  TOP w0.508: v2(50.98,25.5) 48.95,25.5 48.44,24.99 PC700.1
  IN2 w0.254: v2(52.23,11.25) 52.23,11.82 49.05,15 49.05,22.05 49.66,22.66 v2(49.91,22.66)
  IN3 w0.254: v2(19.16,16.36) 24.69,10.83 34.44,10.83 38.86,6.41 41.19,6.41 43.29,8.52 47.51,8.52 49,10.01 49,11.14 49.71,11.85 50.79,11.85 51.39,11.25 v2(52.23,11.25)
  vias: v1(79.11,72.11) v2(52.88,25.44) v2(52.88,24.8) v2(52.88,24.17) v2(52.88,23.53) v2(53.39,25.12) v2(53.39,24.49) v2(53.39,23.85) v2(79.24,70.78) v2(79.55,71.28) v2(79.87,70.78) v2(80.19,71.28) v2(80.51,70.78) v2(80.82,71.28) v2(81.14,70.78)
+SIM_PWR: length 109.5
  TOP w0.102: v3(244.86,49.62) 244.58,49.9 v2(244.58,50.24)
  TOP w0.305: v2(268.63,6.91) 268.35,6.63 JSH1.9
  IN1 w0.508: v2(244.58,50.24) 245.01,49.81 245.01,47.56 244.17,46.72 244.17,39.7 245.33,38.54 245.33,28.46 236.12,19.25 236.12,6.3 238.53,3.89 255.59,3.89 257.69,5.99 267.71,5.99 v2(268.63,6.91)
  IN4 w0.508: v2(244.58,50.24) 243.14,51.68 240.42,51.68 239.16,52.93 237.11,52.93 236.73,53.31 234.43,53.31 234.24,53.5 227.51,53.5 226.79,54.22 v2(226.79,55.22)
  BOTTOM w0.254: 225.79,53.76 225.35,53.76 224.99,53.4 JNGFF2.28
  BOTTOM w0.508: 225.79,53.76 226.3,53.76 226.79,54.25 v2(226.79,55.22)
+SM_VREF_CA: length 86
  TOP w0.508: v2(178,23.39) 177.96,23.35 RD19.2 CD36.1
  IN2 w0.508: v2(178,23.39) 174.61,26.77 138.1,26.77 133.53,31.34 133.53,33.57 122.16,44.93 122.16,61.95 121.84,62.27
  BOTTOM w0.279: v2(121.04,63.62) 121.34,63.91 UC1.AP49
+SM_VREF_CA_DIMM: length 92.4
  TOP w0.102: v3(97.1,15.58) 97.7,16.18 v2(97.7,16.22)
  TOP w0.508: v2(177.03,19.22) 177.02,19.22 176.61,19.63 CD56.1 176.61,20.19 176.86,20.45 CD55.1 RD20.1 176.86,21.92 177.05,22.11 RD19.1 RD18.2 ; v2(97.7,16.22) 97.7,16.22 CD23.1 CD22.1
  IN4 w0.508: v2(177.03,19.22) 177.03,18.45 176.58,18.01 159.78,18.01 159.1,17.33 135.04,17.33 132.62,14.92 99.01,14.92 v2(97.7,16.22)
  BOTTOM w0.356: JDIMM2.126 177.2,19.04 v2(177.03,19.22) ; JDIMM1.126 v2(97.7,16.22)
+SM_VREF_DQ0: length 76.5
  TOP w0.508: RD5.2 CD21.1 68.3,35.6 75.55,42.85 v1(75.55,45.76) 75.55,47.25 81.36,53.06 93.08,53.06 94.41,54.39 106.6,54.39 108.57,52.43 113.85,52.43 115.61,54.18 115.86,54.18 119.93,58.26 119.93,62.85 v2(120.01,62.94)
  BOTTOM w0.254: UC1.AR51 120.16,62.94 v2(120.01,62.94)
+SM_VREF_DQ1: length 44.2
  TOP w0.102: v1(132.36,29.22) 132.17,29.03 v2(132.17,28.49)
  TOP w0.508: CD54.1 RD23.2 v2(132.17,28.49)
  IN2 w0.508: v2(120.09,63.59) 119.79,63.59 119.34,63.14 119.34,57.43 119.11,57.2 119.11,45.69 132.17,32.64 v2(132.17,28.49)
  BOTTOM w0.254: v2(120.09,63.59) 120.42,63.91 UC1.AP51
+USB_RIGHT_PWR: length 0.7
  TOP w0.102: v2(198.6,97.27) v3(198.6,96.61)
+USB_SIDE_PWR: length 11
  TOP w0.102: CI14.1 v3(266.5,64.55)
  BOTTOM w2.032: 261.73,72.11 265.67,68.17 265.67,66.08 266.5,65.25
  vias: v2(268.02,65.95) v2(268.4,65.44) v2(268.72,65.95) v2(269.04,65.44)
+V_DDR_REF: length 4.8
  TOP w0.102: v1(180.85,5.47) 180.91,5.47 181.34,5.04 182.74,5.04 183.19,5.49 PC212.1
  TOP w0.203: PU200.4 183.93,6.24
  TOP w0.508: 183.93,6.24 PC212.1
+VCHGR: length 1.4
  TOP w0.102: PC722.1 v3(82.87,11.67)
  vias: v2(83.81,13.75) v2(84.44,13.75) v2(85.08,13.75)
+VDISPLAY_VCC: length 7.1
  TOP w0.102: v2(266.51,78.02) 266.51,77.75 v3(267.13,77.13)
  IN2 w0.508: v2(266.51,78.02) 267.51,78.02 268.6,79.1 v2(270.62,79.1)
  BOTTOM w0.406: JMDP1.20 270.85,79.46 270.62,79.23 v2(270.62,79.1)
+VHDMI_VCC: length 6
  TOP w0.508: v2(217.54,100.49) 217.54,99.73 v3(218.33,98.94) 220.47,96.8 RV9.2 RV7.2
+VLDOIN_1.35V: length 8.8
  TOP w0.102: v1(190.11,14.91) 189.34,14.15 v2(189.34,12.8)
  TOP w0.203: PU200.19 186.09,9.01 v2(185.98,9.12)
  IN2 w0.762: v2(185.98,9.12) 185.98,10.01 188.77,12.8 v2(189.34,12.8)
+VR_CAP: length 14.6
  TOP w0.102: v1(238.2,75.82) 238.35,75.67 v2(238.94,75.67)
  TOP w0.305: v2(239.76,66.47) 239.95,66.47 240.41,66.92 UE2.B12
  TOP w0.508: v2(238.94,75.67) 239.51,75.09 CE31.1
  BOTTOM w0.508: v2(238.94,75.67) 238.69,75.42 238.69,74.71 238.43,74.45 238.43,69.57 240.38,67.62 240.38,66.92 239.93,66.47 v2(239.76,66.47)
+VREFOUT: length 12.1
  TOP w0.203: UA1.23 264.87,37.65 v1(265.27,38.05)
  TOP w0.508: RA5.2 v2(262.79,43.17) RA6.2 ; v2(267.2,39.66) 267.04,39.81 CA26.1 266.45,39.81 265.48,38.85 265.48,38.26 v1(265.27,38.05)
  IN4 w0.508: v2(267.2,39.66) 266.88,39.66 266.31,40.23 266.31,41.03 264.17,43.17 v2(262.79,43.17)
+Z4012: length 2.2
  TOP w0.102: PR1.2 230.56,95.71 v1(230.72,95.87)
  TOP w0.254: PR1.2 229.39,95.46 PD3.2
-DCIN_JACK: length 1.1
  TOP w0.102: v2(89.4,81.8) v3(88.32,81.8)
/BATPRES: length 28.5
  TOP w0.102: v2(26.14,6.25) v1(26.14,5.6)
  TOP w0.203: v2(50.79,5.12) 51.14,5.47 51.23,5.47 51.3,5.54 PU700.15
  TOP w0.254: v2(50.79,5.12) 50.79,4.99 50.36,4.56 PR728.2 ; PR816.2 v2(26.14,6.25)
  IN3 w0.254: v2(50.79,5.12) 50.79,5.19 49.95,6.03 26.35,6.03 v2(26.14,6.25)
A_ON: length 129.3
  TOP w0.102: RPE10.3 237.78,72.62 v2(237.5,72.35) ; UE2.A4 244.16,69.66 243.7,70.12 v2(243.48,70.12) ; RZ42.1 194.67,56.46 v2(194.98,56.78) ; v2(193.93,46.47) 194.34,46.05 194.34,40.39 v3(194.75,39.98) 196.41,38.33 197.22,38.33 197.61,37.93 197.61,37.02 198.26,36.37 200.57,36.37 200.94,36.74 200.94,37.65 200.8,37.79 UL3.5
  IN1 w0.084: v2(194.98,56.78) 194.8,56.6 190,56.6 188.25,58.34 v2(186.77,58.34)
  IN2 w0.122: v2(243.48,70.12) 242.71,70.12 239.64,73.19 238.34,73.19 v2(237.5,72.35)
  IN4 w0.084: v2(237.5,72.35) 237.67,72.51 237.67,73.06 236.78,73.95 235.16,73.95 234.75,73.54 234.75,72.67 232.63,70.56 231.86,70.56 231.27,71.15 229.94,71.15 228.57,69.77 224.65,69.77 222.95,71.47 218.48,71.47 217.83,70.81 212.56,70.81 211.06,72.32 209.32,72.32 208.74,72.89 205.16,72.89 203.87,71.6 199.21,71.6 198.36,70.75 188.38,70.75 188.05,70.42 186.96,70.42 185.41,68.87 185.41,59.7 v2(186.77,58.34)
  BOTTOM w0.102: v2(186.77,58.34) 184.79,58.34 184.46,58.01 184.46,56.11 185.6,54.97 185.6,52.04 185.09,51.54 185.09,50.39 185.45,50.04 189.37,50.04 192.94,46.47 v2(193.93,46.47)
AC_DIS: length 297.5
  TOP w0.102: v2(241.47,70.09) 241.47,70.01 241.16,69.7 UE2.A10
  TOP w0.254: PQ712.2 v2(23.23,28.95) ; PR828.1 35.5,32.6 35.17,32.93 v1(35.17,35.24) v2(35.17,36.32) ; v2(78.7,85.7) 78.7,86.24 79.49,87.03 PQ6.5
  IN2 w0.254: v2(35.17,36.32) 32.64,33.79 32.64,32.23 30.4,30 25.5,30 24.46,28.95 v2(23.23,28.95)
  IN3 w0.122: v2(241.47,70.09) 241.08,69.7 239.55,69.7 238.21,71.03 238.21,72.46 236.08,74.58 236.08,76.78 234.98,77.89 234.98,79.38 234.34,80.02 232.73,80.02 232.23,79.52 228.32,79.52 225.98,81.86 225.64,81.86 223.8,83.7 223.07,83.7 222.08,84.69 217.58,84.69 216.07,86.2 213.83,86.2 213.54,86.49 210.47,86.49 209.69,87.27 208.1,87.27 207.28,88.1 202.35,88.1 202.01,88.45 200.03,88.45 199.3,89.18 199.3,90.08 198.64,90.73 198.04,90.73 197.62,91.16 193.33,91.16 192.34,90.17 184.41,90.17 183.11,88.86 170.46,88.86 164.61,94.72 152.58,94.72 152.08,95.22 144.32,95.22 144.23,95.31 138.68,95.31 138.09,94.71 131.73,94.71 131.69,94.68 131.26,94.24 130.85,93.83 128.79,93.83 126.99,95.64 126.79,95.64 126.78,95.64 123.7,95.64 121.89,93.82 111.39,93.82 109.45,91.88 100.24,91.88 97.25,88.89 93.16,88.89 91.94,87.67 84.73,87.67 83.12,86.05 79.05,86.05 v2(78.7,85.7)
  IN3 w0.254: v2(35.17,36.32) 38.19,36.32 39.93,34.58 42.06,34.58 43.23,35.75 46.06,35.75 48.6,38.3 48.6,41.09 51.1,43.59 51.56,43.59 53.96,45.98 53.96,47.4 54.28,47.72 54.28,54.11 55.17,55 55.17,56.62 54.98,56.81 53.62,56.81 51.53,58.9 51.53,70.75 58.54,77.76 65.78,77.76 70.43,82.41 72.19,82.41 74.68,84.9 76.07,84.9 76.3,85.13 77.84,85.13 78.41,85.7 v2(78.7,85.7)
AC_PRESENT: length 165.1
  TOP w0.081: v2(146.44,67.41) 146.63,67.21 146.63,66.71 147.31,66.04 148.44,66.04 148.75,65.73 149.04,65.73 149.45,65.32 150.44,65.32 151.24,64.52 151.24,61.54 153.82,58.97
  TOP w0.102: RPC1.6 157.67,55.42 155.98,57.11 v1(155.59,57.11) 155.58,57.11 153.82,58.87 153.82,58.97 ; UE2.A54 248.05,62.1 v2(248.07,62.08)
  IN1 w0.084: v2(248.07,62.08) 246.9,63.26 244.35,63.26 242.03,65.57 242.03,65.63 241.41,66.25 241.41,67.73 242.04,68.35 242.04,70.67 240.6,72.11 240.58,72.11 240.13,72.56 238.93,72.56 238.5,72.99 235.62,72.99 235.37,72.74 231.74,72.74 231.19,72.2 231.19,70.64 226.65,66.09 226.65,64.03 220.59,57.97 219.61,57.97 217.39,55.75 217.39,53.55 215.91,52.07 215.91,49.83 214.69,48.61 213.94,48.61 213.4,48.07 211.61,48.07 211.05,47.51 210.19,47.51 209.79,47.11 207.41,47.11 205.6,45.29 197.33,45.29 196.58,46.05 194.87,46.05 194.47,45.65 193.59,45.65 189.04,50.2 183.8,50.2 181.75,52.25 181.75,54.03 178.77,57.01 172.04,57.01 171.77,57.28 169.07,57.28 168.4,57.95 166.98,57.95 166.13,57.1 163.57,57.1 162,58.67 162,62.61 159.28,65.33 156.93,65.33 152.85,61.25 148.51,61.25 147.16,62.59 147.16,65.86 146.6,66.43 146.6,67.25 v2(146.44,67.41)
  BOTTOM w0.081: UC1.AJ8 146.44,67.13 v2(146.44,67.41)
ACAV_DOCK_SRC#: length 168.9
  TOP w0.102: v2(20.96,21.28) 20.59,21.28 v1(20.24,21.63)
  TOP w0.254: v2(20.96,21.28) 21.65,20.59 PR846.2 21.67,20.56 PR842.1
  IN1 w0.254: v2(20.96,21.28) 20.43,21.81 20.43,29.06 23.1,31.72 23.1,34.14 v2(25.32,36.36)
  IN2 w0.122: v2(25.32,36.36) 27.99,39.03 28.23,39.03 35.66,46.46 46.87,46.46 53.01,52.6 53.01,64.45 54.47,65.91 54.47,72.87 59.11,77.51 63.67,77.51 67.65,81.49 67.65,84.21 70.99,87.55 70.99,89.77 73.61,92.38 74.52,92.38 75.57,91.34 78.52,91.34 79.24,90.63 82.49,90.63 83.6,91.74 87.52,91.74 89.23,93.46 90.72,93.46 94.31,97.05 107.65,97.05 108.93,98.34 110.96,98.34 113.54,100.91 117.41,100.91 123.39,106.9 123.39,110.24 v2(123.81,110.65)
  BOTTOM w0.102: JDOCK1.42 123.45,109.68 123.37,109.77 123.37,110.21 v2(123.81,110.65)
ACAV_IN: length 371.8
  TOP w0.102: v2(248.02,67.32) 247.81,67.1 UE2.A64
  TOP w0.254: v2(44.82,15.02) 45,14.85 v1(47.03,14.85) 49.9,14.85 50.43,14.32 50.43,13.04 PR714.1 ; PQ712.1 20.1,29.6 v2(19.53,30.17) ; v2(19.69,35.17) 19.18,35.67 16.4,35.67 15.98,36.09 15.98,36.82 15.53,37.27 15.53,37.86 15.28,38.11 14.35,38.11 13.75,37.52 13.02,37.52 12.85,37.68 PQ817.5 ; v2(20.7,18.57) 22.42,18.57 PR851.1 ; 48.57,4.43 48.57,4.67 49.07,5.17 v2(49.56,5.17)
  IN1 w0.254: v2(51.16,42.32) 50.22,41.38 50.22,37.72 47.92,35.43 47.92,26.57 45.35,24 45.35,15.55 v2(44.82,15.02) 44.82,8.8 46.34,7.28 48.57,7.28 49.56,6.28 v2(49.56,5.17)
  IN3 w0.122: v2(248.02,67.32) 247.41,67.32 246.13,68.6 237.23,68.6 236.3,69.53 236.3,71.47 235.57,72.2 235.57,72.83 235.83,73.1 235.83,76.66 234.72,77.77 234.72,79.26 234.21,79.77 232.84,79.77 232.33,79.27 228.22,79.27 225.87,81.61 225.54,81.61 223.7,83.45 222.96,83.45 221.98,84.43 217.49,84.43 215.97,85.95 213.73,85.95 213.43,86.24 210.37,86.24 209.59,87.02 208,87.02 207.17,87.85 202.25,87.85 201.9,88.2 199.93,88.2 199.05,89.07 199.05,89.97 198.54,90.49 197.94,90.49 197.52,90.91 193.43,90.91 192.45,89.92 184.51,89.92 183.21,88.62 170.36,88.62 164.51,94.46 152.45,94.46 151.94,94.97 143.34,94.97 142.8,94.43 142.43,94.43 142.03,94.43 142.03,94.43 141.19,94.43 131.8,94.43 131.5,94.14 131.5,94.13 130.95,93.58 128.69,93.58 126.89,95.39 123.81,95.39 121.99,93.57 111.51,93.57 109.57,91.63 100.34,91.63 97.35,88.64 93.26,88.64 92.03,87.41 84.83,87.41 83.22,85.8 80.48,85.8 79.43,84.75 78.5,84.75 77.51,83.76 74.9,83.76 72.86,81.72 70.72,81.72 65.94,76.94 58.7,76.94 52.23,70.46 52.23,59.81 53.26,58.78 54.64,58.78 55.17,58.24 55.17,57.93 55.93,57.17 55.93,54.78 54.97,53.82 54.97,47.44 54.65,47.12 54.65,45.65 51.33,42.32 v2(51.16,42.32)
  IN3 w0.254: v2(19.69,35.17) 19.53,35.01 v2(19.53,30.17) 19.42,30.06 19.42,19.71 20.56,18.57 v2(20.7,18.57) 21.64,17.63 21.64,16.8 22.43,16.01 26.12,16.01 27.51,17.41 32.34,17.41 34.85,14.9 44.69,14.9 v2(44.82,15.02)
  BOTTOM w0.254: PR715.1 49.56,5.44 v2(49.56,5.17)
ACAV_IN#: length 27.2
  TOP w0.254: PQ817.3 13.5,36.48 13.75,36.73 14.17,36.73 14.39,36.94 PU806.2 15.32,36.94 15.6,36.66 15.6,35.55 15.96,35.18 v1(17.54,35.18) v2(18.9,35.18) ; PR864.2 20.94,16.67 v2(20.82,16.8)
  IN3 w0.254: v2(20.82,16.8) 19,18.62 19,35.08 v2(18.9,35.18)
ACAV_IN_NB: length 306.6
  TOP w0.102: v2(45.1,5.54) 44.54,5.54 v1(44.06,5.05) ; UE2.B20 237.62,66.35 237.95,66.69 v2(238.29,66.69)
  TOP w0.254: PR743.2 v2(45.1,5.54) ; PR848.2 v2(34.71,21.17)
  IN1 w0.254: v2(34.71,21.17) 34.71,21.87 35.87,23.02 35.87,28.36 36.63,29.12 36.63,34.05 37.71,35.13 v2(37.71,35.36)
  IN2 w0.254: v2(34.71,21.17) 35.94,19.94 35.94,16.41 40.25,12.1 40.25,9.75 44.46,5.54 v2(45.1,5.54)
  IN3 w0.122: v2(37.71,35.36) 37.82,35.36 39.36,33.82 42.6,33.82 43.62,34.84 46.19,34.84 49.3,37.95 49.3,40.8 50.38,41.88 52.25,41.88 54.18,43.82 54.71,43.82 55.4,44.51 55.4,46.81 55.72,47.13 55.72,51.59 56.69,52.56 56.69,57.46 55.93,58.22 55.93,58.61 55,59.54 53.77,59.54 52.97,60.34 52.97,70.04 56.23,73.3 56.95,73.3 57.77,74.12 57.77,74.95 58.36,75.54 65.6,75.54 70.99,80.94 73.49,80.94 75.5,82.95 78.86,82.95 80.91,85 83.82,85 85.47,86.65 92.6,86.65 93.75,87.79 97.6,87.79 100.68,90.87 109.87,90.87 111.24,92.23 111.58,92.58 111.82,92.82 111.82,92.82 131.38,92.82 132.24,93.68 141.5,93.68 143.66,93.68 143.9,93.44 146.65,93.44 147.28,94.06 147.42,94.21 151.53,94.21 152.04,93.7 164.19,93.7 164.34,93.55 170.04,87.86 183.51,87.86 184.82,89.17 193.47,89.17 194.38,90.08 196.99,90.08 199.62,87.45 201.35,87.45 201.7,87.1 206.87,87.1 208.51,85.46 213.16,85.46 214.27,84.35 216.51,84.35 217.18,83.68 220.85,83.68 222.49,82.04 224.05,82.04 225.23,80.87 225.55,80.87 227.99,78.43 232.95,78.43 234.19,77.19 234.19,70.46 234.54,70.11 234.54,68.1 235.1,67.53 236.53,67.53 237.37,66.69 v2(238.29,66.69)
ACAVDK_SRC: length 2.4
  TOP w0.254: PU800.4 24.22,21.35 PR842.2
ACAVIN: length 5.2
  TOP w0.102: v1(20.9,17.88) 21.03,18.01 22.96,18.01 PR851.2
  TOP w0.254: PU800.8 24.6,19.35 23.72,18.48 PR851.2
ALW_PWRGD_3V_5V: length 97.4
  TOP w0.102: RE283.2 247.9,71.27 v2(248.26,70.92) ; RZ51.1 256.74,57.51 v2(257.48,58.24)
  TOP w0.254: PR108.1 204.17,47.78 v2(203.39,48.56)
  IN2 w0.122: v2(213.89,72.54) 213.65,72.3 213.65,70.35 215.71,68.3 215.71,65.46 215,64.75 215,59.09 215.32,58.78 215.32,57.67 214.77,57.12 213.67,57.12 212.84,56.3 212.84,49.89 211.79,48.84 207.29,48.84 206.25,47.79 205.28,47.79 204.51,48.56 v2(203.39,48.56)
  IN4 w0.084: v2(257.48,58.24) 256.25,59.47 256.25,65.77 253.4,68.62 251.81,68.62 249.56,70.87 248.31,70.87 v2(248.26,70.92) 245.97,73.21 238.12,73.21 236.95,74.37 234.98,74.37 232.88,72.26 230.47,72.26 228.4,70.19 225.75,70.19 222.17,73.77 216.98,73.77 215.56,72.35 214.09,72.35 v2(213.89,72.54)
ALW_PWRGD_3V_5V_EC: length 4.9
  TOP w0.102: UE2.A1 245.66,69.12 245.8,69.26 245.98,69.26 246.42,68.82 247.13,68.82 247.64,69.33 RE283.1 247.31,70.36 v1(246.77,69.82)
ALWON: length 122.6
  TOP w0.102: v1(195.68,45.34) PR113.1 ; v2(249.42,65.57) 249.42,65.13 248.97,64.68 248.15,64.68 247.88,64.95 247.86,64.95 247.7,65.1 UE2.A60
  TOP w0.254: v2(194.42,48.55) 194.74,48.23 194.74,46.84 195.12,46.46 PR113.1
  IN2 w0.122: v2(211.04,73.33) 211.23,73.14 211.23,72.66 208.9,70.33 199,70.33 198.87,70.2 194.67,70.2 193.81,71.06 188.71,71.06 188.23,71.54 187.17,71.54 185.63,69.99 185.63,59.95 185.29,59.61 184.7,59.61 183.19,58.09 183.19,51.09 183.76,50.52 185.92,50.52 186.23,50.84 186.23,51.66 187.31,52.74 192.14,52.74 192.58,53.19 193.35,53.19 194.04,52.49 194.04,49 194.42,48.61 v2(194.42,48.55)
  IN4 w0.084: v2(211.04,73.33) 211.23,73.14 211.23,72.8 211.89,72.14 215.65,72.14 217.07,73.56 222.09,73.56 225.66,69.98 228.48,69.98 230.55,72.05 232.96,72.05 235.07,74.16 236.87,74.16 238.03,73 245.58,73 248.34,70.23 249.2,70.23 250.3,69.13 250.3,66.59 249.42,65.7 v2(249.42,65.57)
ANTCTL0: length 208.1
  TOP w0.102: v2(64.74,70.85) 64.74,70.96 64.97,71.19 64.97,72.52 64,73.5 64,75.57 63.4,76.17 62.79,76.17 62.41,76.56 RZ46.1 ; v1(213.07,51.5) 213.11,51.5 v2(213.92,50.69)
  IN3 w0.122: v2(213.92,50.69) 214.24,50.36 214.24,49.15 212.18,47.09 211.32,47.09 211,46.77 211,43.54 209.58,42.11 202.77,42.11 202.06,42.82 194.82,42.82 193.96,43.68 186.38,43.68 182.86,40.16 95.91,40.16 83.75,52.32 70.11,52.32 69.73,52.7 62.54,52.7 61.81,53.44 61.81,57.57 58.34,61.04 58.34,62.43 57.94,62.83 56.7,62.83 56.36,63.17 56.36,63.88 55.68,64.57 55.68,67.54 58.34,70.21 60.63,70.21 61.27,70.85 v2(64.74,70.85)
  BOTTOM w0.102: v2(213.92,50.69) 214.52,50.09 214.52,48.97 215.83,47.65 JNGFF2.51
ANTCTL1: length 202
  TOP w0.102: v2(65.32,70.84) 65.32,72.5 64.22,73.6 64.22,74.57 64.44,74.78 v1(64.44,75.67) 64.44,76.18 63.81,76.81 RZ46.2
  IN3 w0.122: v2(213.83,50.11) 213.83,50.11 213.83,49.09 212.14,47.41 210.11,47.41 209.66,46.96 209.66,45.06 208.84,44.23 207.92,44.23 206.05,42.36 202.96,42.36 202.26,43.07 194.95,43.07 194.09,43.93 186.12,43.93 182.68,40.49 95.94,40.49 83.19,53.24 69.55,53.24 68.75,54.03 66.33,54.03 64.47,55.9 63.94,55.9 62.06,57.78 62.06,59.28 59.3,62.04 59.3,63.37 58.9,63.77 56.83,63.77 55.99,64.6 55.99,67.47 57.44,68.92 59.69,68.92 61.18,70.4 64.89,70.4 v2(65.32,70.84)
  BOTTOM w0.102: JNGFF2.53 215.72,47.15 215.61,47.26 215.61,47.55 214.29,48.87 214.29,49.65 v2(213.83,50.11)
ANTCTL2: length 201.9
  TOP w0.102: RZ47.1 65.14,77.08 64.88,76.83 64.88,74.9 64.45,74.47 64.45,73.69 65.73,72.41 65.73,70.67 65.39,70.33 65.04,70.33 v2(64.52,69.82)
  IN3 w0.122: v2(213.41,49.7) 213.44,49.67 213.44,49.05 212.09,47.71 210.03,47.71 209.41,47.09 209.41,45.25 208.64,44.48 207.81,44.48 205.94,42.61 203.16,42.61 202.45,43.32 195.12,43.32 194.25,44.18 185.93,44.18 182.74,41 95.78,41 83.29,53.48 69.65,53.48 68.86,54.28 66.43,54.28 64.57,56.14 64.04,56.14 62.31,57.88 62.31,59.41 59.55,62.17 59.55,63.47 59.55,63.48 59.01,64.02 56.94,64.02 56.31,64.64 56.31,67.35 57.61,68.65 59.77,68.65 60.95,69.82 v2(64.52,69.82)
  BOTTOM w0.102: v2(213.41,49.7) 213.75,49.7 v1(213.94,49.5) 213.94,48.89 215.38,47.46 215.38,47.17 215.9,46.65 JNGFF2.55
ANTCTL3: length 200.5
  TOP w0.102: v2(65.16,69.86) 65.24,69.86 66.03,70.64 66.03,72.44 64.69,73.77 64.69,74.27 65.14,74.71 65.14,76.3 v1(65.65,76.81) 66.54,77.7 RZ47.2
  IN3 w0.122: v2(213.02,49.27) 213.02,48.99 212.01,47.98 209.86,47.98 209.16,47.28 209.16,45.38 208.51,44.73 207.71,44.73 206.67,43.69 195.1,43.69 194.36,44.43 185.73,44.43 182.54,41.24 95.89,41.24 83.4,53.73 69.76,53.73 68.96,54.53 66.54,54.53 64.67,56.39 64.15,56.39 62.56,57.99 62.56,59.54 59.8,62.29 59.8,63.57 59.11,64.26 57.05,64.26 56.63,64.68 56.63,67.22 57.77,68.36 59.84,68.36 60.88,69.4 64.69,69.4 v2(65.16,69.86)
  BOTTOM w0.102: v2(213.02,49.27) 213.35,48.93 213.47,48.93 215.15,47.26 215.15,46.72 215.72,46.15 JNGFF2.57
AUD_HP_NB_SENSE: length 77.4
  TOP w0.102: v2(230.18,42.77) 229.8,42.77 229.47,43.1 UE1.A41 ; RA2.1 266.61,28.09 266.48,28.22 QA1.2 266.48,29.77 v2(266.05,30.2)
  TOP w0.254: RA2.1 266.61,27.16 267.91,25.87 269.2,25.87 270.37,27.04 270.37,27.85 272.28,29.76 272.28,30.84 271.92,31.19 271.92,32.32 v1(272.78,33.18) 272.78,35.53 274.74,37.49 274.74,39.75 CA41.1 274.18,41.24 274.64,41.69 DA2.3 274.09,42.56 272.33,44.32 272.33,45.39 273.15,46.21 274.75,46.21 275.05,46.52 JHP1.6
  BOTTOM w0.102: v2(230.18,42.77) 230.75,42.2 230.75,41.14 230.94,40.94 232.14,40.94 233.62,39.47 241.02,39.47 241.82,40.27 243.67,40.27 250.18,33.77 257.85,33.77 259.96,31.66 264.59,31.66 v2(266.05,30.2)
AUD_HP_OUT_L: length 11.3
  TOP w0.102: v1(271.86,38.4) 271.41,38.85 RA24.1
  TOP w0.381: CA43.2 267.59,34.35 267.09,34.85 v2(267.09,35.24) ; LA2.1 269.68,38.85 RA7.2 ; v2(268.82,39.47) 269.44,38.85 RA7.2 ; RA7.2 RA24.1
  IN1 w0.381: v2(268.82,39.47) 268.11,39.47 267.44,38.8 267.44,35.58 v2(267.09,35.24)
AUD_HP_OUT_L1: length 25.4
  TOP w0.102: v1(271.58,39.92) LA2.2
  TOP w0.381: LA2.2 270.51,40 CA3.1 270.51,41.62 270.74,41.85 DA3.3 v2(270.74,43.83)
  IN3 w0.381: v2(270.74,43.83) 269.8,43.83 265.16,48.46 265.16,52.31 269.33,56.48 JHP1.1
AUD_HP_OUT_R: length 7.6
  TOP w0.381: v2(270.05,37.06) 269.72,37.06 269.47,36.8 ; CA44.2 268.25,35.58 269.47,36.8 ; v1(269.47,36.82) 269.47,36.8
  BOTTOM w0.381: RA8.2 271.26,39.13 270.05,37.92 v2(270.05,37.06) ; RA8.2 271.49,39.15 LA3.1 ; RA8.2 RA25.1
AUD_HP_OUT_R1: length 10.7
  BOTTOM w0.381: JHP1.2 277.8,46.24 v1(275.95,44.39) 275.84,44.28 274.42,44.28 DA1.2 273.77,44.6 273.32,44.14 273.32,43.43 272.57,42.68 272.57,41.46 CA2.1 272.34,40.26 LA3.2
AUD_NB_MUTE#: length 62.8
  TOP w0.102: v1(264.91,46.33) 264.72,46.14 264.72,45.25 ; v2(228.32,42.75) 228.47,42.9 UE1.A39
  TOP w0.203: UA1.48 257.38,33.65 257.04,33.31 257.04,31.83 v2(257.15,31.71) 256.48,31.71 CA31.1 256.46,31.15 256.41,31.1 RA18.2
  TOP w0.254: 264.72,45.25 264.72,44.61 v2(264.66,44.55)
  IN1 w0.254: v2(257.15,31.71) 257.04,31.83 257.04,41.76 259.83,44.55 v2(264.66,44.55)
  BOTTOM w0.102: v2(228.32,42.75) 228.02,42.46 228.02,41.03 228.33,40.72 232.05,40.72 233.52,39.24 241.11,39.24 241.91,40.04 243.58,40.04 253.45,30.17 254.53,30.17 255.44,31.09 256.53,31.09 v2(257.15,31.71)
AUD_OUT_L: length 17
  TOP w0.102: v1(259.33,41.85) 258.79,41.85 v2(258.69,41.95)
  TOP w0.203: UA1.33 259.97,39.27 259.9,39.34 259.9,39.63 258.69,40.85 v2(258.69,41.95)
  TOP w0.381: RA7.1 269.02,37.93 v2(268.72,38.24)
  IN4 w0.381: v2(268.72,38.24) 268.66,38.18 267.08,38.18 266.31,38.95 266.31,38.96 263.32,41.95 v2(258.69,41.95)
AUD_OUT_R: length 18.7
  TOP w0.203: v2(259.19,41.24) 259.19,40.93 v1(259.57,40.55) 260.23,39.88 260.23,39.47 260.37,39.33 UA1.32
  IN4 w0.381: v2(259.19,41.24) 259.19,41 261.16,39.03 262.88,39.03 265.37,36.54 269.75,36.54 270.07,36.22 v2(270.48,36.22)
  BOTTOM w0.381: RA8.1 271.48,38.18 270.85,37.55 270.85,36.59 v2(270.48,36.22)
AUD_PC_BEEP: length 4.3
  TOP w0.102: UA1.12 263.17,32.36 263.31,32.22 263.63,32.22 v1(264.12,31.72) 264.47,31.38 CA27.2 CA28.2
AUD_SENSE_A: length 5
  TOP w0.203: 264.17,33.08 264.17,33.11 264.02,33.26 UA1.13
  TOP w0.254: 264.17,33.08 264.17,32.36 v1(265.32,31.22) 265.83,30.71 QA1.1
AUD_SENSE_B: length 7.5
  TOP w0.203: 264.72,33.77 264.44,34.05 UA1.14
  TOP w0.254: RA38.1 269.29,32.75 RA28.1 RA27.1 267.45,32.74 266.88,32.17 266.88,31.99 v1(266.54,31.65) 265.8,31.65 264.72,32.73 264.72,33.77
AUX_EN_WOWL: length 85.8
  TOP w0.102: RZ38.2 236.32,52.04 v2(235.95,52.04) ; v2(232.91,52.1) 233.21,52.4 UE1.B67 ; UZ11.1 221.72,39.02 221.26,38.56 220.24,38.56 219.63,37.95 v2(219.63,36.56) ; v2(203.89,38.42) v1(203.89,38.95) 203.89,39.19 207.23,42.54 207.23,43.48 209.12,45.36 209.12,46.04 v2(208.66,46.5)
  IN3 w0.122: v2(232.91,52.1) 232.53,51.73 229.61,51.73 229.29,52.06 229.29,52.07 229.29,53 228.59,53.7 226.94,53.7 226.43,54.2 224.65,54.2 224.14,54.71 224.14,55.82 222.52,57.44 221.66,57.44 220.05,55.82 220.05,55.05 218.3,53.3 218.3,49.19 216.98,47.86 216.98,46.63 216.52,46.17 216.52,43.25 214.09,40.82 209.09,40.82 207.35,39.09 205.16,39.09 204.48,38.42 v2(203.89,38.42)
  IN4 w0.084: v2(232.91,52.1) 232.96,52.04 v2(235.95,52.04)
  BOTTOM w0.102: UZ2.5 209.01,46.48 208.99,46.5 v2(208.66,46.5) ; v2(219.63,36.56) 219.63,36.55 219.23,36.14 217.69,36.14 215.94,37.9 208.46,37.9 207.19,39.17 207.19,40.08 206.96,40.31 205.78,40.31 v2(203.89,38.42)
B-RAMP: length 4.5
  TOP w0.203: PU500.11 88.95,70.94 v2(88.85,70.84)
  TOP w0.254: PR502.1 88.85,70.62 v2(88.85,70.84)
  BOTTOM w0.102: v1(87.81,70.37) 88.46,70.37 88.85,70.77 v2(88.85,70.84)
  BOTTOM w0.254: PR507.2 88.81,70.88 v2(88.85,70.84)
BAT1_LED#: length 69.7
  TOP w0.254: RZ44.1 203.07,94.64 QZ5.1 203.63,93.7 204.69,92.65 v1(206.44,92.65) 206.63,92.84 206.63,93.79 v2(206.44,93.98) ; UE2.B1 245.91,68.24 246.06,68.4 v2(247.03,68.4)
  IN3 w0.254: v2(247.03,68.4) 247.03,68.65 248.76,70.37 248.76,71.4 248.48,71.68 247.86,71.68 247.35,72.2 247.35,72.45 245.42,74.38 245.42,78.56 244.08,79.9 237.09,79.9 234.35,82.64 234.35,83.48 231.43,86.4 229.29,86.4 228.78,86.91 228.78,89.89 228.02,90.65 223.73,90.65 221.85,92.53 217.07,92.53 215.19,90.65 213.37,90.65 211.28,92.75 207.68,92.75 206.45,93.98 v2(206.44,93.98)
BAT1_LED#_Q: length 2.3
  TOP w0.102: RZ28.1 202.93,96.94 v1(202.74,96.75)
  TOP w0.254: RZ28.1 203.89,96.56 203.63,96.3 QZ5.6
BAT2_LED#: length 78.5
  TOP w0.254: v2(248.63,62.26) 248.28,62.6 UE2.A55 ; v2(204.86,97.21) 204.92,97.16 QZ5.4 204.93,96.54 RZ43.1
  IN3 w0.254: v2(248.63,62.26) 248.63,62.5 250.52,64.39 250.52,70.81 249.26,72.07 248.01,72.07 247.73,72.35 247.73,72.61 245.8,74.54 245.8,78.72 244.21,80.3 237.22,80.3 234.73,82.79 234.73,83.63 231.56,86.8 229.53,86.8 229.16,87.18 229.16,90.08 228.21,91.03 223.89,91.03 222.01,92.91 216.92,92.91 215.04,91.03 213.56,91.03 211.47,93.13 208.14,93.13 206.74,94.53 206.17,94.53 v2(205.6,93.95)
  BOTTOM w0.254: v2(204.86,97.21) 205.01,97.21 v1(205.6,96.62) v2(205.6,93.95)
BAT2_LED#_Q: length 2.6
  TOP w0.102: QZ5.3 204.93,93.77 204.85,93.69 v1(204.85,93.1)
  TOP w0.254: QZ5.3 204.97,94.7 RZ25.1
BATDRV#: length 44.5
  TOP w0.254: v2(88.21,13.55) 88.21,12.89 85.46,10.13 v1(78.35,10.13) 75.49,7.28 75.49,4.25 74.46,3.23 52.36,3.23 PR722.2
  BOTTOM w0.254: v2(88.21,13.55) 87.66,14.11 PQ800.4
BATT_WHITE#: length 15.3
  TOP w0.254: RZ25.2 206.31,95.62 206.49,95.8 206.49,97.7 v1(207.41,98.62) 208.08,99.29 213.92,99.29 215.73,101.1 LED7.1
BATT_WHITE_LED#: length 167.2
  TOP w0.102: 59.74,78.92 59.93,78.33 60.69,77.57 v1(61.27,77.57) 61.77,78.08 62.63,78.08 v2(63.06,78.5) ; RZ43.2 205.71,97.66 v2(205.23,97.66)
  IN3 w0.122: v2(63.06,78.5) 63.56,79 65.87,79 68.24,81.37 68.24,82.57 73.37,87.69 82.45,87.69 84.14,89.38 89.19,89.38 89.86,90.06 91.44,90.06 93.4,92.02 97.93,92.02 99.56,93.64 101.12,93.64 103.08,95.6 107.83,95.6 109.45,97.23 110.85,97.23 111.77,98.15 112.92,98.15 113.55,98.78 116.57,98.78 120.33,102.54 139.19,102.54 141.22,104.57 141.58,104.57 146.16,99.99 149.18,99.99 151,98.16 153.13,98.16 153.94,97.36 166.03,97.36 170.88,92.51 177.66,92.51 178.65,93.5 181.32,93.5 182.02,92.8 191.25,92.8 192.32,93.87 197.22,93.87 197.5,94.14 202.5,94.14 205.44,97.08 205.44,97.46 v2(205.23,97.66)
BATT_YELLOW#: length 17.9
  TOP w0.254: LED7.3 211.54,101.8 209.6,99.86 205.99,99.86 204.98,100.88 204.27,100.88 203.89,100.49 v1(203.89,99.73) RZ28.2
BATT_YELLOW_LED#: length 164.9
  TOP w0.102: v2(190.78,96.7) 191.42,96.06 v1(200.98,96.06) 201.15,96.06 201.65,95.55 RZ44.2 ; v2(163.35,98.81) 163.35,100.1 v2(165.24,101.99) ; v2(61.84,78.52) 61.27,78.52 JLED1.4
  IN3 w0.122: v2(163.35,98.81) 162.4,97.86 154.26,97.86 153.46,98.66 151.21,98.66 149.38,100.48 147.02,100.48 142.57,104.93 141.23,104.93 139.08,102.79 120.15,102.79 117.16,99.8 113.84,99.8 112.43,98.4 111.67,98.4 110.75,97.48 109.35,97.48 107.72,95.85 102.97,95.85 101.01,93.89 99.45,93.89 97.83,92.26 93.29,92.26 91.33,90.31 89.76,90.31 89.08,89.63 84.03,89.63 82.35,87.94 73.26,87.94 67.99,82.67 67.99,81.48 65.77,79.25 63.2,79.25 62.47,78.52 v2(61.84,78.52) ; v2(190.78,96.7) 190.78,96.68 190.04,95.95 184.6,95.95 183.7,96.85 181.71,96.85 180.53,95.66 177.79,95.66 176.94,94.82 171.6,94.82 167.95,98.47 167.95,99.58 165.54,101.99 v2(165.24,101.99)
BBS_BIT: length 9.7
  TOP w0.102: T109.1 150.48,83.08 148.82,81.42 148.82,77.88 148.26,77.32 148.03,77.32 147.79,77.09 147.79,76.72 147.56,76.49 147.26,76.49 v2(146.84,76.92)
  BOTTOM w0.081: v2(146.84,76.92) 146.66,76.74 UC1.L8
BC_CLK_ECE1117: length 97.4
  TOP w0.102: v2(194.75,37.67) v1(194.75,34.45) 194.75,33.65 197.37,31.03 199.54,31.03 203.61,26.96 203.61,21.2 205.95,18.85 205.95,17.03 207.81,15.17 207.81,14.15 208.13,13.83 208.13,12.53 208.48,12.18 JKBTP1.10 ; v2(235.11,65.5) 235.45,65.83 235.97,65.83 236.2,65.6 UE2.A20
  IN1 w0.084: v2(194.75,37.67) 195.22,37.67 195.45,37.89 197.85,37.89 198.58,37.15 203.78,37.15 205.34,38.72 207.13,38.72 209.02,40.6 213.66,40.6 217.76,44.7 218.88,44.7 219.99,45.81 219.99,47.39 221.25,48.65 221.25,50.26 222.74,51.76 223.21,51.76 224.79,53.34 229.21,53.34 230.37,54.5 230.37,56.1 232.72,58.45 232.72,58.94 233.22,59.45 233.22,60.93 235.34,63.05 236.55,63.05 237.45,63.96 237.45,65.82 237.26,66.01 235.63,66.01 v2(235.11,65.5)
BC_CLK_ECE5048: length 31.8
  TOP w0.102: v2(223,46.04) 223.11,46.15 UE1.A30 ; v2(243.53,56.55) 243.16,56.92 UE2.A43
  IN1 w0.084: v2(243.53,56.55) 243.11,56.12 240.48,56.12 239.05,57.55 237.89,57.55 237.41,57.08 237.41,55.54 236.72,54.84 236.72,51.92 235.76,50.96 235.76,49.69 234.48,48.41 231.36,48.41 231.07,48.12 228.59,48.12 227.67,47.2 227.24,47.2 226.51,46.48 224.74,46.48 224.33,46.07 223.03,46.07 v2(223,46.04)
BC_DAT_ECE1117: length 115.5
  TOP w0.102: JKBTP1.8 207.48,12.15 207.72,12.39 207.72,13.66 207.4,13.98 207.4,15 205.55,16.86 205.55,18.69 203.2,21.03 203.2,26.8 199.37,30.63 197.2,30.63 194.17,33.66 v1(194.17,36.55) v2(194.17,37.67) ; v2(238.34,66.07) 238.12,65.85 UE2.B21 ; RPE5.2 246.74,72.24 247.28,71.7 248.18,71.7 248.7,71.18 248.7,69.75 247.64,68.68 v2(247.64,68.43)
  IN1 w0.084: v2(238.34,66.07) 237.84,65.57 237.84,63.74 235.7,61.6 234.51,61.6 233.61,60.7 233.61,59.29 233.35,59.02 233.35,56.74 232.78,56.17 231.19,56.17 230.81,55.79 230.81,54.39 230.12,53.7 230.12,52.04 229.93,51.85 226.81,51.85 226.62,51.66 224.97,51.66 224.67,51.37 222.9,51.37 221.64,50.1 221.64,48.48 220.38,47.22 220.38,45.65 219.04,44.31 217.92,44.31 213.82,40.21 209.18,40.21 207.29,38.33 205.5,38.33 203.94,36.76 198.08,36.76 197.35,37.5 195.61,37.5 195.31,37.2 194.63,37.2 v2(194.17,37.67)
  IN4 w0.084: v2(247.64,68.43) 246.93,67.72 240.71,67.72 240.4,67.41 240.4,66.27 240.14,66.01 239.64,66.01 239.13,66.52 238.75,66.52 238.34,66.11 v2(238.34,66.07)
BC_DAT_ECE5048: length 58.8
  TOP w0.102: v2(240.65,75.67) 240.16,75.17 240.16,73.5 240.47,73.18 RE36.2 ; UE1.B31 225.67,46.4 226.11,46.84 v2(226.11,46.87) ; v2(242.52,60.07) 242.65,60.07 242.91,59.81 UE2.B45
  IN1 w0.084: v2(226.11,46.87) 226.21,46.87 227.44,48.1 228,48.1 228.41,48.51 230.91,48.51 231.65,49.25 233.92,49.25 234.94,50.27 234.94,51.85 236.14,53.06 236.14,54.2 235.77,54.58 235.77,56.82 236.02,57.07 236.63,57.07 237.5,57.94 240.03,57.94 241.45,56.51 242.67,56.51 243.06,56.9 243.06,56.92 243.07,56.93 243.07,58.78 242.91,58.93 242.91,59.68 v2(242.52,60.07)
  BOTTOM w0.102: v2(240.65,75.67) 241.51,75.67 242.37,74.81 242.37,74.14 241.95,73.72 241.95,70.88 242.56,70.27 242.56,69.51 243.26,68.81 244.9,68.81 246.44,67.26 246.44,61.1 245.85,60.5 242.95,60.5 v2(242.52,60.07)
BC_INT#_ECE1117: length 89.6
  TOP w0.102: v2(220.6,7.53) 220.55,7.48 208.18,7.48 206.98,8.68 JKBTP1.7 ; v1(235.31,40.61) 235.29,40.61 234.91,40.23 v2(234.87,40.23) ; v2(235.13,66.41) 235.44,66.1 UE2.A19
  IN1 w0.084: v2(220.6,7.53) 220.6,32.51 221.38,33.29 226.92,33.29 233.04,39.41 234.05,39.41 v2(234.87,40.23)
  BOTTOM w0.102: v2(234.87,40.23) 235.22,40.58 235.22,42.74 234.48,43.48 234.48,61.65 233.52,62.62 233.52,65.63 234.3,66.41 v2(235.13,66.41)
BC_INT#_ECE5048: length 29.8
  TOP w0.102: v2(242.66,57.07) UE2.A42 ; UE1.A29 223.02,46.65 v2(223.01,46.65)
  IN1 w0.084: v2(223.01,46.65) 223.38,46.65 224.08,47.35 226.09,47.35 227.24,48.49 227.84,48.49 228.75,49.4 230.98,49.4 232.02,50.44 233.66,50.44 234.49,51.26 234.49,53.92 235.22,54.65 235.22,56.96 235.71,57.46 236.47,57.46 237.68,58.66 241.06,58.66 v2(242.66,57.07)
BCM5882_ALERT#: length 79.6
  TOP w0.102: v2(232.57,48.81) 232.57,48.91 233.56,49.9 UE1.B62 ; JUSH1.7 242.98,5.32 243.48,4.81 v2(253.44,4.81) ; v2(252.81,14.64) v1(252.06,14.64)
  IN4 w0.084: v2(253.44,4.81) 253.42,4.84 253.42,11.98 252.81,12.59 v2(252.81,14.64) 252.81,15.75 254.18,17.12 254.18,21.57 253.03,22.72 253.03,27.62 250.01,30.63 250.01,41.75 243.78,47.98 241.58,47.98 240.83,48.73 238.32,48.73 237.84,49.21 232.96,49.21 v2(232.57,48.81)
BEEP: length 64.7
  TOP w0.102: v2(238.31,67.29) 238.1,67.29 237.66,66.85 UE2.B19 ; v1(266.05,26.58) 265.93,26.71 v2(265.23,26.71) 265.42,26.9 RA13.2
  IN3 w0.122: v2(265.23,26.71) 264.59,26.07 254.75,26.07 250.5,30.33 250.5,38.25 247.51,41.24 247.51,48.17 244.02,51.66 244.02,53.44 243.07,54.39 241.54,54.39 240.96,54.98 240.96,55.78 242.11,56.93 242.11,57.31 242.94,58.14 242.94,60.49 242.49,60.93 241.61,60.93 241.19,61.35 241.19,63.19 239.57,64.81 239.57,66.04 v2(238.31,67.29)
BIA_PWM: length 3.5
  TOP w0.102: DV1.1 60.25,74.98 60.45,75.18 LV1.2 60,75.67 59.93,75.6 RV1.1 59.5,76.03 v1(58.97,76.57)
BIA_PWM_EC: length 215.1
  TOP w0.102: UE2.B25 238.08,63.85 v2(238.3,63.63) ; v1(57.84,74.52) 58.09,74.27 58.6,74.27 59.17,74.84 v2(59.17,74.97) 59.6,74.54 DV1.2
  IN3 w0.122: v2(238.3,63.63) 239.32,64.66 239.32,65.37 239.15,65.54 238.16,65.54 236.42,67.28 235,67.28 234.29,68 234.29,70.01 233.94,70.35 233.94,77.09 232.85,78.18 227.88,78.18 225.44,80.62 225.13,80.62 223.95,81.79 222.39,81.79 220.75,83.43 217.08,83.43 216.41,84.1 214.16,84.1 213.06,85.21 208.41,85.21 206.77,86.84 201.6,86.84 201.24,87.2 199.52,87.2 196.89,89.83 194.48,89.83 193.58,88.92 184.93,88.92 183.61,87.6 169.94,87.6 164.09,93.45 151.94,93.45 151.43,93.96 147.53,93.96 146.9,93.34 146.76,93.19 143.78,93.19 143.54,93.43 141.62,93.43 133.72,93.43 132.85,92.57 112.34,92.57 112.34,92.57 111.92,92.57 111.92,92.57 111.49,92.13 109.96,90.61 103.4,90.61 100.33,87.55 93.85,87.55 92.64,86.33 85.51,86.33 83.93,84.75 81.01,84.75 78.97,82.7 76.33,82.7 70.52,76.9 67.31,76.9 65.7,75.29 63.36,75.29 62.53,74.46 59.68,74.46 v2(59.17,74.97)
BLUE_DOCK: length 82.8
  TOP w0.102: UV8.M8 195.36,85.59 194.93,86.02 193.79,86.02 192.85,86.96 192.85,88.49 RV78.1 190.89,90.45 v1(185.85,90.45) 184.26,90.45 183.26,91.45 181.05,91.45 180.58,90.98 v2(180.59,90.98)
  BOTTOM w0.102: v2(180.59,90.98) 180.36,90.98 179.65,90.27 176.24,90.27 174.16,92.35 170.48,92.35 168.43,94.4 146.86,94.4 146.61,94.65 143.5,94.65 142.57,95.58 140.55,95.58 138.93,93.95 128.69,93.95 127.17,95.47 127.17,96.82 125.52,98.46 125.08,98.46 124.69,98.86 124.69,99.11 124.45,99.35 JDOCK1.45
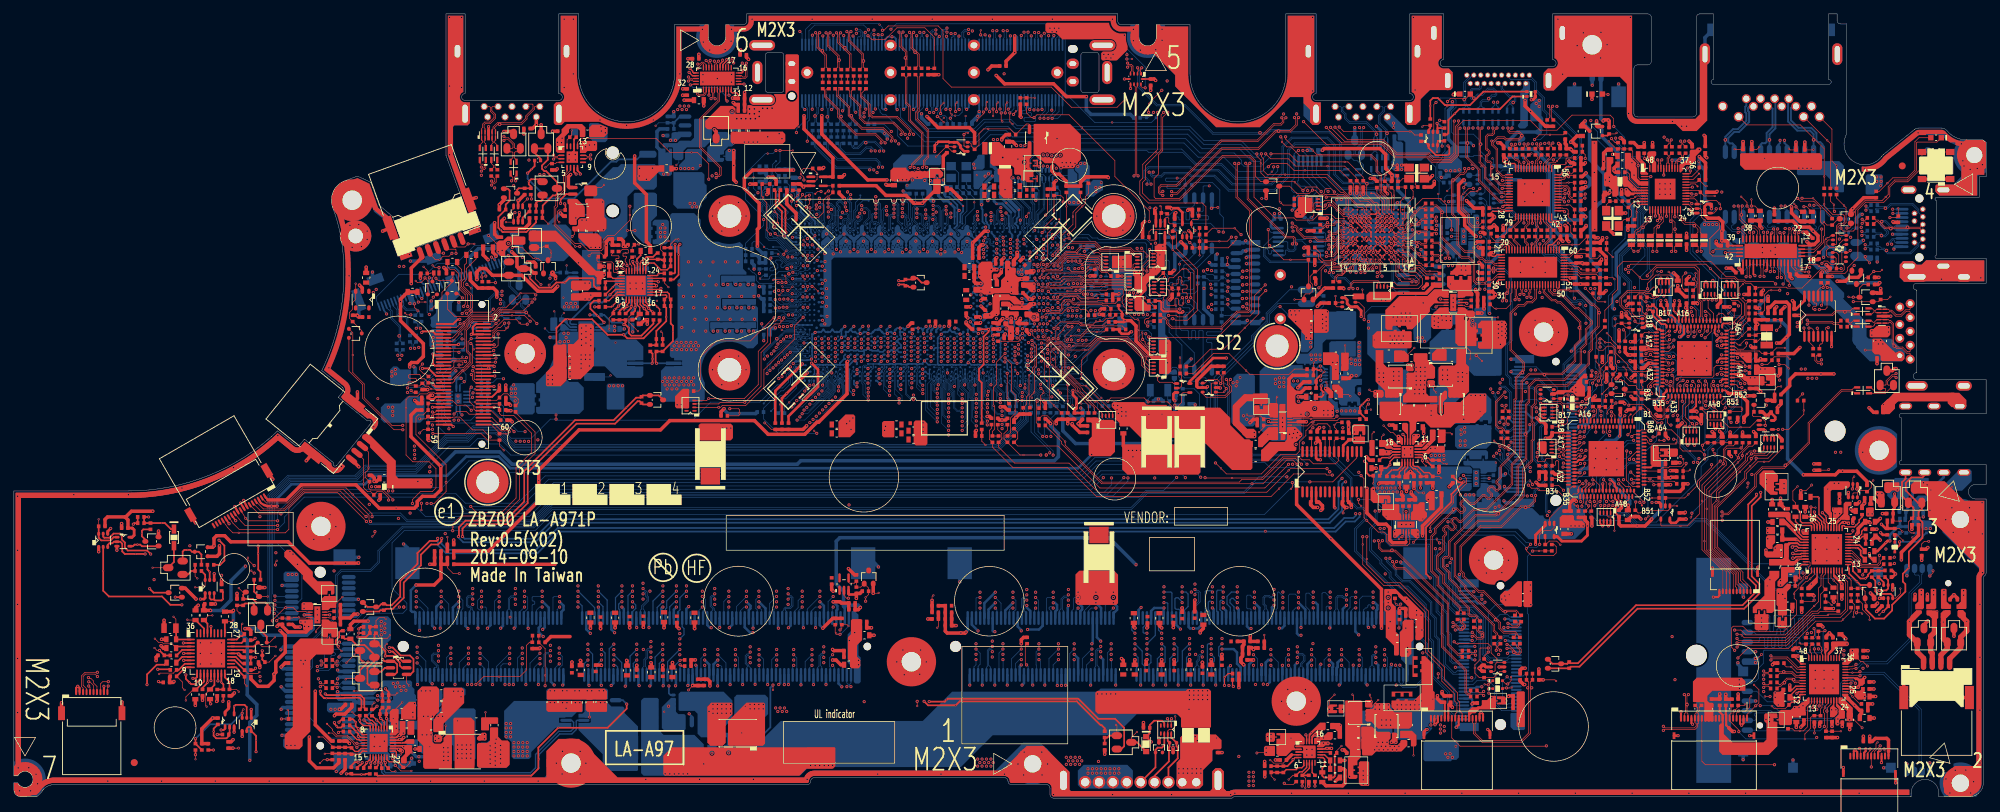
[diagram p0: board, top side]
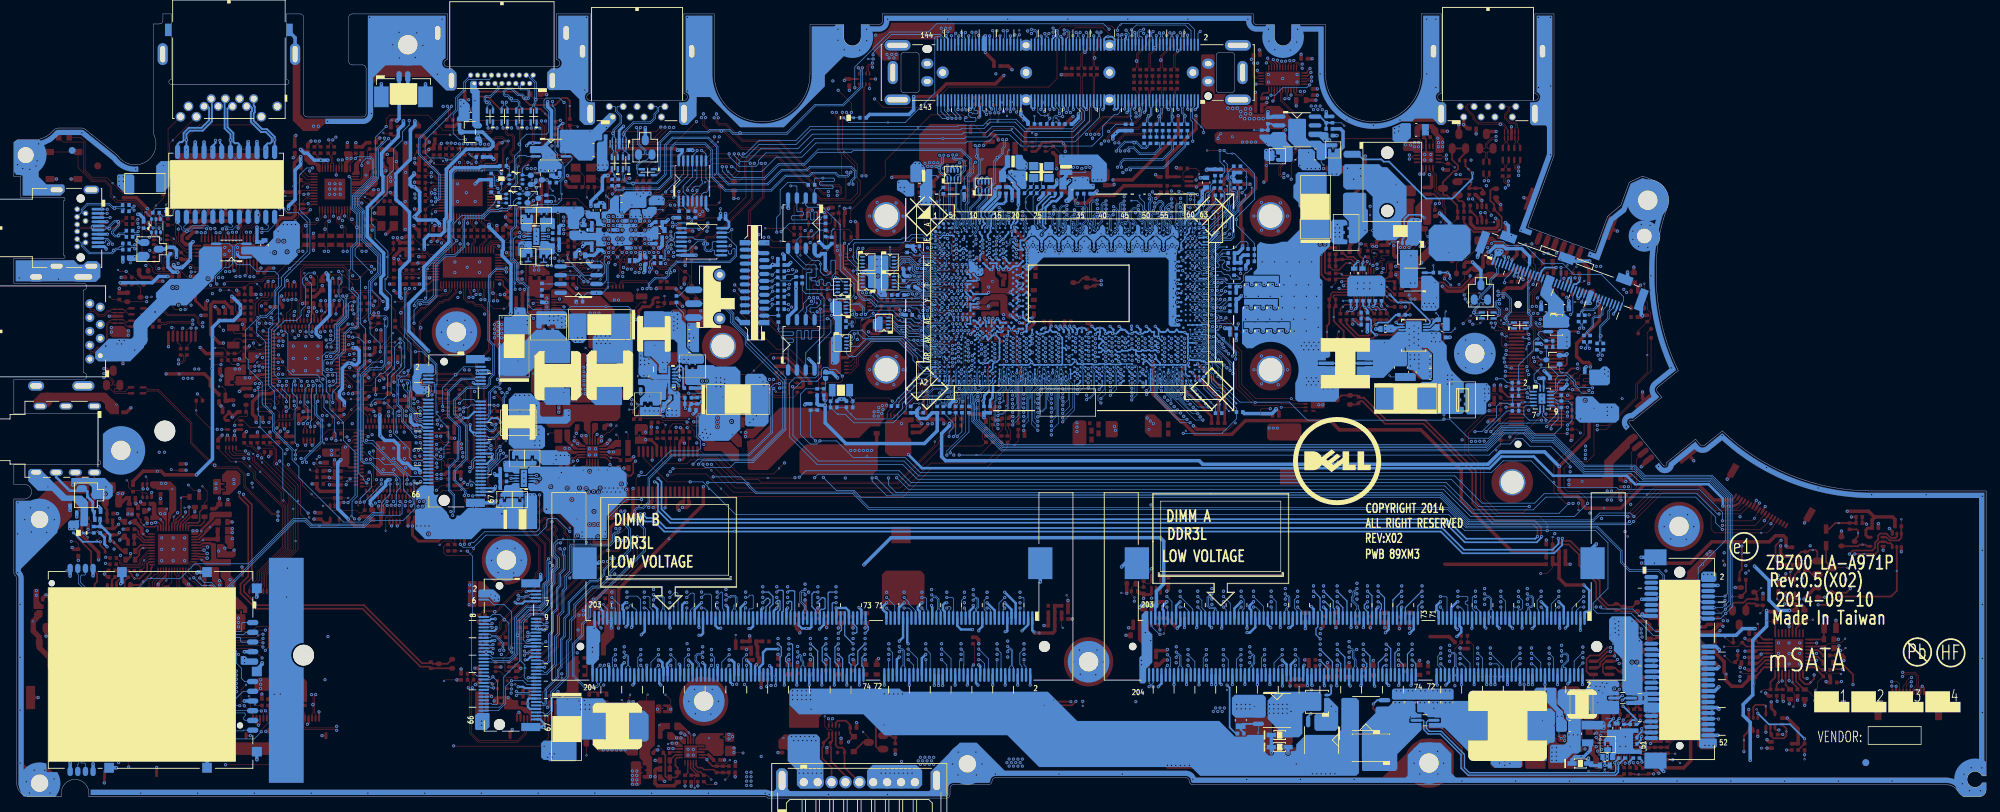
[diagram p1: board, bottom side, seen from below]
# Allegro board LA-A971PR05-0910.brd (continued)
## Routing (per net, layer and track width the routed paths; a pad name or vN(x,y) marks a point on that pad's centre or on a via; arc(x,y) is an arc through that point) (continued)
BOARD_ID: length 14.5
  TOP w0.102: CE40.1 RE79.2 242.18,73.64 242.18,74.43 v2(241.8,74.8) 241.8,74.85 242.07,75.12 v1(242.07,75.63) ; v2(240.99,66.52) 241.09,66.52 241.41,66.84 UE2.B10
  BOTTOM w0.102: v2(240.99,66.52) 241.1,66.52 241.43,66.85 241.43,68.22 241.06,68.59 241.06,74.06 v2(241.8,74.8)
BOOT_1.35V:
  vias: v1(186.74,9.44)
BOOT_1.35V_C:
  vias: v1(190.97,10.5)
BQ24770_REGN: length 15.2
  TOP w0.254: v2(47.87,3.49) 47.89,3.52 PR713.1 48.68,3.4 v1(50.03,3.4) 50.57,3.4 50.66,3.49 PR725.1
  IN1 w0.254: v2(47.87,3.49) 53.48,3.49 53.98,3.99 53.98,6.84 54.72,7.59 55.93,7.59 v2(56.12,7.4)
BREATH_LED#: length 192.4
  TOP w0.102: v2(139.17,109.98) 139.17,110.62 v1(139.18,110.63) ; v2(245.78,61.89) 246.23,61.89 246.26,61.85 UE2.B57 ; v2(208.18,96.53) 207.98,96.33 207.98,92.64 206.91,91.58 204.13,91.58 203.45,92.26 198.79,92.26 196.88,94.18 188.94,94.18 v2(185.65,97.47)
  IN2 w0.122: v2(208.18,96.53) 208.18,96.79 208.75,97.36 218.33,97.36 220.64,95.05 224.65,95.05 226.8,92.9 228.6,92.9 231.51,89.99 236.59,89.99 237.29,89.29 239.22,89.29 239.69,88.82 239.69,86.74 240.35,86.08 243.14,86.08 243.27,86.2 246.11,86.2 246.51,86.6 255.96,86.6 256.63,85.93 258.01,85.93 v2(258.5,85.45) 258.81,85.13 258.81,79.92 256.53,77.63 256.53,74.25 255.75,73.47 255.51,73.47 254.5,72.46 254.5,63.22 254.51,63.21 254.51,60.57 v2(254.18,60.24)
  IN4 w0.084: v2(139.17,109.98) 140.07,109.08 152.96,109.08 153.66,109.78 157.94,109.78 159.32,108.39 159.32,104.51 159.68,104.15 166.33,104.15 166.56,103.92 166.56,101.93 172.67,95.81 179.42,95.81 182.68,99.07 185.19,99.07 185.42,98.84 185.42,97.7 v2(185.65,97.47) ; v2(254.18,60.24) 252.21,60.24 249.73,62.71 247.38,62.71 246.56,61.89 v2(245.78,61.89)
  BOTTOM w0.102: v2(139.17,109.98) 139.45,109.7 JDOCK1.98 ; QZ7.4 262.8,83.72 262.99,83.91 RZ34.1 262.5,83.86 261.29,83.86 260.97,84.18 260.97,84.68 260.66,85 258.94,85 v2(258.5,85.45)
BREATH_LED#_Q: length 25.6
  TOP w0.102: v2(263,82.14) 263,82.06 263.37,81.7 264.78,81.7 265.1,82.02 265.1,84.73 266.45,86.08 268.91,86.08 v1(269.45,86.62) 269.81,86.98 269.81,88.12 270.75,89.06 272.55,89.06 273.88,90.38 273.88,94.42 273.98,94.52 276.82,94.52 LED3.1
  BOTTOM w0.102: v2(263,82.14) 263,81.98 262.8,81.78 QZ7.3
BREATH_WHITE_LED: length 13.5
  TOP w0.102: RZ32.1 268.52,87.43 v1(269.69,88.6) 270.47,89.38 272.54,89.38 273.65,90.49 273.65,94.58 274.23,95.16 275.93,95.16 LED3.2
BREATH_WHITE_LED#: length 250.5
  TOP w0.102: JLED1.2 63.55,79.74 63.88,79.41 64.95,79.41 v2(65.39,79.86) v1(66.28,79.86)
  IN2 w0.122: v2(255.32,72.69) 256.91,74.28 256.91,77.59 259.1,79.78 259.1,85.39 v2(259.12,85.41)
  IN3 w0.122: v2(65.39,79.86) 66.02,79.86 67.74,81.58 67.74,82.77 73.16,88.19 82.24,88.19 83.99,89.94 89.04,89.94 89.66,90.56 91.23,90.56 93.19,92.51 97.72,92.51 99.35,94.14 100.91,94.14 102.87,96.1 107.54,96.1 109.17,97.73 110.59,97.73 111.52,98.65 112.33,98.65 113.73,100.05 117.06,100.05 120.04,103.04 138.98,103.04 141.12,105.18 143.45,105.18 147.84,100.78 149.44,100.78 151.31,98.91 153.59,98.91 154.4,98.1 162.02,98.1 163.16,99.24 164.81,99.24 165.06,98.98 165.06,98.42 165.25,98.23 165.86,98.23 171.01,93.08 177.53,93.08 178.47,94.02 191.77,94.02 192.22,94.48 197.13,94.48 197.29,94.64 202.29,94.64 204.2,96.55 204.2,97.94 204.65,98.39 217.92,98.39 218.76,97.56 221.59,97.56 222.33,96.81 228.43,96.81 229.13,96.11 230.88,96.11 231.81,95.18 235.99,95.18 237.28,93.89 239.28,93.89 240.5,92.67 240.5,90.61 240.8,90.31 240.8,84.61 243.31,82.11 246.61,82.11 251.18,77.54 253.35,77.54 255.1,75.79 255.1,72.91 v2(255.32,72.69)
  BOTTOM w0.102: RZ34.2 263.91,84.54 263.47,84.98 261,84.98 260.57,85.41 v2(259.12,85.41)
BST_3V:
  vias: v1(203.57,50.84)
BST_3V_C: length 1.5
  TOP w0.102: v1(207.01,52.44) 206.82,52.62 PR110.1 205.59,52.62
BST_5V: length 1.4
  TOP w0.102: PR109.1 196.89,52.08 v1(197.18,52.37)
BST_5V_C: length 1.8
  TOP w0.102: PR109.2 195.49,52.47 v1(195.76,52.74)
BST_+V1.05SP: length 1
  TOP w0.102: v1(188.9,59.92) 189.03,59.79 189.03,59.22 v2(188.84,59.03)
BST_+V1.05SP_C: length 1.5
  TOP w0.102: PC302.2 192.14,58.14 v1(192.39,57.89)
BT_LED#: length 11.1
  TOP w0.102: QZ2.4 212.14,19.55 RZ15.1 211.63,20.45 v2(212.23,21.04)
  BOTTOM w0.102: v2(212.23,21.04) 212.65,21.46 212.65,25.18 213.92,26.45 215.01,26.45 215.36,26.1 JNGFF1.8
BT_RADIO_DIS#: length 69.4
  TOP w0.102: DZ2.1 212.3,16.34 v2(212.24,16.34) 211.77,16.34 v1(211.71,16.4) ; RE11.2 227.39,56.41 227.83,55.98 227.83,55.49 v2(227.43,55.09) 226.97,54.63 UE1.A13
  IN3 w0.122: v2(212.24,16.34) 211.76,16.81 211.76,17.12 212.01,17.37 213.09,17.37 215.85,20.13 215.85,31.99 220.73,36.87 227.83,36.87 232.54,41.58 236.09,41.58 236.83,42.32 236.83,47.05 235.19,48.68 235.19,50.2 236.4,51.41 236.4,52.74 v2(235.19,53.95)
  IN4 w0.084: v2(235.19,53.95) 228.02,53.95 227.43,54.54 v2(227.43,55.09)
BT_RADIO_DIS#_R: length 3.5
  TOP w0.102: DZ2.2 214.76,16.45 v2(215.04,16.45) 215.52,16.93 v1(215.52,17.45)
  BOTTOM w0.102: v2(215.04,16.45) 215.19,16.6 JNGFF1.46
CAM_MIC_CBL_DET#: length 122.8
  TOP w0.102: v2(163.48,79.03) 163.48,78.74 163.77,78.45 RPC16.5 ; v1(65.84,73.44) 65.27,74.02 v2(65.2,74.02)
  IN1 w0.084: v2(149.53,79.67) 151,78.2 163.11,78.2 163.48,78.57 v2(163.48,79.03)
  IN2 w0.081: 146.99,84.94 146.99,83.79 148.14,82.64 149.05,82.64 149.97,81.71 149.97,80.48 149.53,80.04 v2(149.53,79.67)
  IN2 w0.122: v2(65.2,74.02) 65.21,74.02 65.21,74.7 66.73,76.22 68.42,76.22 70.73,78.52 70.73,80.13 70.95,80.36 72.61,80.36 76.05,83.79 77.21,83.79 78.63,85.21 79.44,85.21 80.09,85.86 83.05,85.86 84.23,87.04 90.94,87.04 92.43,88.53 102.76,88.53 103.73,89.51 104.58,89.51 105.99,90.92 109.73,90.92 109.97,91.16 112.86,91.16 113.78,92.07 125.78,92.07 126.12,92.42 128.04,92.42 128.06,92.43 128.6,92.98 129.63,92.98 130.97,94.32 139.88,94.32 143.25,90.95 143.25,89.13 144.99,87.39 144.99,86.94 146.99,84.94
  BOTTOM w0.081: v2(149.53,79.67) 149.29,79.44 UC1.F4
  BOTTOM w0.102: JEDP1.14 v2(65.2,74.02)
CD3301_DCIN: length 5.5
  TOP w0.102: PR835.2 23.32,25.79 v1(22.97,26.14)
  TOP w0.254: PR835.2 23.35,24.45 PC813.1 23.38,22.85 PU800.1
CD3301_SDC_IN: length 2.4
  TOP w0.254: PR847.2 24.21,20.35 PU800.6
CD_PBATT_OFF: length 3.9
  TOP w0.102: PR843.1 32.75,24.07 32.75,24.99 v1(32.88,25.12)
  TOP w0.254: PU800.27 32.07,22.85 32.56,23.34 32.87,23.34 PR843.1
CFG0: length 68.2
  TOP w0.102: v2(74.98,71.92) 73.19,71.92 v1(72.45,71.18) 71.69,70.42 69.88,70.42 68.85,69.39 65.9,69.39 64.88,68.37 64.88,68.1 63.1,66.32 JXDP1.9
  IN2 w0.122: v2(74.98,71.92) 75.65,71.92 75.84,72.11 75.84,74.25 79.16,77.57 88.61,77.57 88.93,77.89 105.7,77.89 107.83,75.75 107.83,71.8 109.49,70.14 111.3,70.14 111.51,69.94 v2(111.51,69.62)
  BOTTOM w0.076: UC1.AC60 114.2,69.95 113.87,69.95 113.8,70.02 113.79,70.02 113.75,70.06 113,70.06 112.85,69.91 112.4,69.91 112.3,70.01 111.9,70.01 v2(111.51,69.62)
  BOTTOM w0.102: RC183.1 108.94,70.06 110.77,70.06 111.21,69.62 v2(111.51,69.62)
CFG1: length 65
  TOP w0.102: v2(74.6,71.48) v1(74.11,70.99) 73.31,70.19 69.97,70.19 68.94,69.16 66,69.16 65.11,68.27 65.11,68.01 64.06,66.95 64.06,66.78 63.1,65.82 JXDP1.11
  IN2 w0.122: v2(74.6,71.48) 74.18,71.89 74.18,72.93 79.06,77.81 88.51,77.81 88.83,78.14 105.8,78.14 108.08,75.86 108.08,71.9 109.37,70.61 v2(109.62,70.61)
  BOTTOM w0.076: 110.84,70.25 111,70.08 111.54,70.08 111.65,70.19 112.36,70.19 112.47,70.07 112.5,70.07 112.73,70.07 112.75,70.07 113.03,70.35 UC1.AC62
  BOTTOM w0.081: 109.93,70.3 109.99,70.25 110.84,70.25
  BOTTOM w0.102: 109.93,70.3 v2(109.62,70.61) 109.2,71.04 RC184.1
CFG2: length 64.3
  TOP w0.102: JXDP1.15 64.71,64.82 64.92,65.03 64.92,67.49 65.34,67.91 65.34,68.18 66.09,68.93 69.04,68.93 70.07,69.96 73.72,69.96 v1(74.19,69.49) 75.27,68.42 v2(75.27,68.38)
  IN4 w0.084: v2(75.27,68.38) 75.54,68.38 85.08,77.93 104.41,77.93 104.97,77.37 106.41,77.37 107.93,75.86 107.93,72.33 109.1,71.16 110.32,71.16 v2(110.73,70.74)
  BOTTOM w0.076: UC1.AC63 111.12,70.35
  BOTTOM w0.081: 111.12,70.35 v2(110.73,70.74)
CFG3: length 89.6
  TOP w0.102: v2(64.07,64.23) 63.98,64.32 JXDP1.17 ; v1(70.52,50.11) 69.9,50.74 RC113.2 68.2,51.59 67.25,52.54 v2(60.32,52.54)
  IN2 w0.122: v2(110.24,71.88) 110.24,71.67 109.99,71.42 109.43,71.42 108.58,72.27 108.58,76.06 106.01,78.64 88.63,78.64 88.3,78.31 78.85,78.31 73.15,72.61 73.15,72.28 69.82,68.94 69.82,68.22 69.13,67.54 69.13,67.52 65.84,64.23 v2(64.07,64.23) 63.17,64.23 62.15,63.22 62.15,60.46 61.71,60.01 61.71,57.44 60.7,56.43 60.7,52.92 v2(60.32,52.54)
  BOTTOM w0.076: v2(110.24,71.88) 110.81,71.32 111.46,71.32 111.8,70.97 112.49,70.97 UC1.AA63
  BOTTOM w0.102: RC305.1 64.42,64.59 v2(64.07,64.23)
CFG3_R: length 4
  TOP w0.102: v1(70.9,52.46) 70.87,52.5 RC113.1 69.9,52.61 68.69,53.82 JXDP1.60
CFG4: length 83.8
  TOP w0.102: v2(103.05,56.11) 104.32,56.11 104.45,55.98 v1(104.45,55.47) 104.45,55.22 104.32,55.09 RC191.1 ; JXDP1.27 62.91,61.82 63.33,62.24 63.33,62.77 63.42,62.86 64.51,62.86 64.64,62.74 64.64,62.54 64.51,62.41 v2(64.07,62.41)
  IN1 w0.084: v2(103.05,56.11) 102.65,55.71 100.92,55.71 97.62,52.41 71.41,52.41 70.47,51.47 68.27,51.47 67.23,52.51 67.23,53.61 67.32,53.69 68.42,53.69 68.5,53.78 68.5,54.2 68.42,54.28 67.32,54.28 67.23,54.37 67.23,54.79 67.32,54.87 68.42,54.87 68.5,54.96 68.5,55.38 68.42,55.47 67.32,55.47 67.23,55.55 67.23,59.79 66.48,60.54 65.78,60.54 64.07,62.25 v2(64.07,62.41)
  IN2 w0.122: v2(103.05,56.11) 104.98,56.11 113.05,64.17 113.05,67.19 114.27,68.41 v2(114.27,70.73)
  BOTTOM w0.081: UC1.AA60 114.57,71.03 v2(114.27,70.73)
CFG5: length 67.5
  TOP w0.102: JXDP1.29 62.78,61.32 63.47,62.01 64.69,62.01 65.55,62.87 65.55,63.89 65.15,64.29 65.15,67.39 65.72,67.96 65.72,68.23 66.19,68.7 69.13,68.7 69.99,69.56 v1(71.72,69.56) 73.48,69.56 v2(74.32,68.71)
  IN4 w0.084: v2(74.32,68.71) 74.6,68.99 75.55,68.99 84.9,78.35 104.59,78.35 105.14,77.79 106.59,77.79 108.5,75.87 108.5,73.16 109.25,72.41 111.2,72.41 111.42,72.19 v2(111.42,71.92)
  BOTTOM w0.076: UC1.Y62 113.03,71.85 112.91,71.73 112.91,71.73 112.74,71.56 112.74,71.56 112.72,71.55 112.41,71.55 112.2,71.34 111.91,71.34 111.42,71.83 v2(111.42,71.92)
CFG6: length 69.2
  TOP w0.102: JXDP1.33 63.13,60.32 64.59,61.78 64.79,61.78 65.24,62.23 65.78,62.77 65.78,63.98 65.38,64.39 65.38,65.75 v2(65.83,66.2)
  IN2 w0.122: v2(65.83,66.2) 66.05,66.43 66.05,66.44 71.22,71.6 71.22,75.19 72.21,76.18 74.36,76.18 78.23,80.05 87.79,80.05 88.45,79.38 106.61,79.38 106.61,79.37 106.86,79.12 106.89,79.12 113.58,72.44 v2(113.58,72.22)
  BOTTOM w0.081: v2(113.58,72.22) 113.61,72.22 113.92,71.91 UC1.Y61
  BOTTOM w0.102: v2(65.83,66.2) 66.5,66.2 v1(66.7,66.41)
CFG7: length 71.7
  TOP w0.102: JXDP1.35 63.15,59.82 63.43,60.1 63.43,60.3 64.69,61.55 64.88,61.55 65.46,62.13 66.01,62.68 66.01,65.28 v2(65.78,65.51)
  IN2 w0.122: v2(110.82,71.91) 110.12,72.61 109.32,72.61 109.08,72.85 109.08,76.27 106.21,79.13 88.42,79.13 88.1,78.81 77.34,78.81 74.46,75.93 72.31,75.93 71.47,75.09 71.47,71.5 66.42,66.45 66.42,66.14 v2(65.78,65.51)
  BOTTOM w0.076: UC1.Y60 114.27,71.52 113.8,71.52 113.76,71.56 112.97,71.56 112.81,71.39 112.8,71.39 112.79,71.38 112.48,71.38 112.27,71.17 111.84,71.17 111.46,71.55 111.18,71.55 v2(110.82,71.91)
  BOTTOM w0.102: v1(66.2,64.66) 66.2,65.09 v2(65.78,65.51)
CFG8: length 63.5
  TOP w0.102: JXDP1.10 68.75,66.32 68.95,66.52 68.95,67.05 69.73,67.83 70.04,67.83 v2(70.65,68.44)
  IN4 w0.084: v2(70.65,68.44) 71.02,68.06 72.81,68.06 74.16,69.41 75.19,69.41 77.01,71.23 77.01,74.08 76.56,74.53 76.56,75.15 77.86,76.45 81.2,76.45 81.81,77.06 81.97,77.06 82.41,76.62 82.59,76.62 82.82,76.86 82.82,77.04 81.89,77.97 81.89,78.09 82.12,78.32 82.24,78.32 83.2,77.36 83.32,77.36 84.73,78.77 104.76,78.77 105.32,78.21 106.76,78.21 108.93,76.05 108.93,73.97 109.5,73.4 v2(109.5,73.03)
  BOTTOM w0.076: UC1.V62 112.81,72.14 112.5,72.14 112.48,72.12 111.81,72.12 111.55,72.38 111.11,72.38
  BOTTOM w0.102: 111.11,72.38 110.14,72.38 v2(109.5,73.03) 109.06,73.03 RC190.1 ; v1(70.87,67.74) 70.65,67.96 v2(70.65,68.44)
CFG9: length 63.7
  TOP w0.102: JXDP1.12 68.88,65.82 69.18,66.12 69.18,66.95 69.57,67.35 70.64,67.35 v1(71.12,67.83) 71.24,67.95 v2(71.24,68.46)
  IN4 w0.084: v2(71.24,68.46) 71.43,68.65 73.1,68.65 74.08,69.62 75.1,69.62 76.79,71.32 76.79,73.99 76.34,74.45 76.34,75.23 77.78,76.66 80.1,76.66 82.09,78.65 82.36,78.65 83.28,77.73 83.39,77.73 83.62,77.96 83.62,78.08 83.14,78.56 83.14,78.68 83.37,78.91 83.48,78.91 83.97,78.42 84.09,78.42 84.64,78.98 104.85,78.98 105.41,78.42 106.85,78.42 109.14,76.13 109.14,74.06 110.06,73.14 v2(110.08,73.14)
  BOTTOM w0.076: UC1.V61 113.66,72.89 113.15,72.89 112.91,72.66 112.91,72.48 112.75,72.32 112.75,72.32 112.73,72.32 112.5,72.32 112.5,72.32 112.26,72.32 112.23,72.29 111.88,72.29 111.55,72.62 110.98,72.62 110.98,72.62 110.6,72.62 v2(110.08,73.14)
  BOTTOM w0.081: 109.93,73.29 v2(110.08,73.14)
  BOTTOM w0.102: 109.93,73.29 109.51,73.71 RC189.1
CFG10: length 67.8
  TOP w0.102: v2(69.71,66.89) 69.71,65.25 69.37,64.91 68.86,64.91 68.77,64.82 JXDP1.16
  IN2 w0.081: v2(110.18,70.66) 110.18,70.91 110.05,71.04 109.88,71.04
  IN2 w0.122: 109.88,71.04 109.46,71.04 109.46,71.04 108.33,72.17 108.33,75.96 105.9,78.39 88.73,78.39 88.41,78.06 78.96,78.06 73.4,72.51 73.4,72.18 72.22,71 72.22,70.82 72.78,70.27 72.78,70.1 72.5,69.82 72.33,69.82 71.78,70.38 71.6,70.38 71.33,70.11 71.33,69.93 71.89,69.38 71.89,69.21 71.61,68.93 71.44,68.93 70.89,69.49 70.71,69.49 70.16,68.93 70.16,67.33 v2(69.71,66.89)
  IN4 w0.089: v2(114.18,72.21) 114.18,72 112.45,70.27 110.56,70.27 v2(110.18,70.66)
  BOTTOM w0.081: 109.93,70.9 v2(110.18,70.66) ; v2(114.18,72.21) 114.18,72.25 114.57,72.63 UC1.V60
  BOTTOM w0.102: RC188.1 108.91,71.93 109.93,70.9 ; v1(69.02,66.53) 69.36,66.53 v2(69.71,66.89)
CFG11: length 64
  TOP w0.076: v2(110.69,73.15) 110.69,72.98 v1(110.19,72.48)
  TOP w0.102: v2(69.08,64.51) 68.89,64.32 JXDP1.18
  IN4 w0.084: v2(69.08,64.51) 68.74,64.84 68.74,66.48 70.25,67.99 70.25,68.6 70.5,68.86 73.01,68.86 73.99,69.83 75.01,69.83 76.58,71.41 76.58,73.91 76.12,74.37 76.12,75.31 77.81,77 80.14,77 83.16,80.02 88.16,80.02 88.99,79.19 104.94,79.19 105.45,78.68 106.92,78.68 109.35,76.25 109.35,74.15 109.86,73.63 110.2,73.63 v2(110.69,73.15)
  BOTTOM w0.076: v2(110.69,73.15) 111.05,72.78 111.58,72.78 111.88,73.08 112.24,73.08 112.43,72.89 112.81,72.89 112.97,73.06 113.76,73.06 113.83,72.98 114.24,72.98 UC1.U60
CFG12: length 72.9
  TOP w0.076: v1(111,75.27) 111.13,75.14 v2(111.13,74.29)
  TOP w0.102: JXDP1.28 66.46,61.82 v2(66.11,62.17)
  IN4 w0.084: v2(111.13,74.29) 111.13,74.47 110.3,75.3 110.3,77.3 107.63,79.97 100.78,79.97 95.11,85.65 91.03,85.65 88.79,83.4 84.33,83.4 82.88,81.96 76.98,81.96 75.48,80.46 75.48,74.1 75.95,73.63 75.95,71.67 74.75,70.47 73.73,70.47 72.75,69.49 70.24,69.49 69.55,68.79 69.23,68.79 67.62,67.17 67.62,63.67 v2(66.11,62.17)
  BOTTOM w0.076: v2(111.13,74.29) 111.41,74.02 111.72,74.02 111.72,74.01 111.86,74.01 111.86,74.02 112.53,74.02 UC1.T63
CFG13: length 66.5
  TOP w0.076: v2(110.57,74.29) 110.57,74.55 110.37,74.75 109.88,74.75
  TOP w0.102: JXDP1.30 69.02,61.32 v2(69.2,61.51) ; 109.88,74.75 109.42,74.75 v1(109.32,74.65)
  IN4 w0.084: v2(69.2,61.51) 68.32,62.39 68.32,66.65 69.83,68.16 69.83,68.78 70.33,69.28 72.84,69.28 73.81,70.25 74.84,70.25 76.16,71.58 76.16,73.72 75.69,74.19 75.69,75.48 77.64,77.42 79.97,77.42 82.99,80.45 95.92,80.45 96.76,79.61 105.13,79.61 105.63,79.11 107.1,79.11 110.01,76.2 110.01,74.85 v2(110.57,74.29)
  BOTTOM w0.076: v2(110.57,74.29) 111.08,73.79 112.96,73.79
  BOTTOM w0.081: UC1.T62 112.96,73.79
CFG14: length 77.6
  TOP w0.076: v2(114.26,73.72) 114.26,73.35 v1(113.98,73.08)
  TOP w0.102: v2(66.04,61.59) 66.26,61.37 66.26,60.38 66.33,60.32 JXDP1.34
  IN4 w0.084: v2(114.26,73.72) 114.26,73.93 114.02,74.17 111.79,74.17 110.64,75.31 110.64,77.26 107.71,80.19 100.86,80.19 95.19,85.86 85.67,85.86 84.13,84.31 84.13,83.54 82.77,82.19 76.9,82.19 75.2,80.49 75.2,74.07 75.74,73.54 75.74,71.75 74.66,70.68 73.64,70.68 72.66,69.7 70.16,69.7 69.46,69 69.15,69 67.36,67.22 67.36,64.01 65.71,62.36 65.71,61.92 v2(66.04,61.59)
  BOTTOM w0.081: UC1.T61 114.26,73.79 v2(114.26,73.72)
CFG15: length 79.5
  TOP w0.076: v2(114.89,73.72) 115.06,73.72 v1(115.75,73.04)
  TOP w0.102: v2(65.85,61.03) 66.04,60.85 66.04,60.28 66.5,59.82 JXDP1.36
  IN4 w0.084: v2(114.89,73.72) 114.19,74.42 111.78,74.42 110.89,75.31 110.89,77.32 107.8,80.4 100.95,80.4 95.29,86.07 85.58,86.07 83.87,84.36 83.87,83.6 82.66,82.4 76.81,82.4 74.99,80.57 74.99,73.96 75.53,73.43 75.53,71.84 74.57,70.89 73.55,70.89 72.58,69.91 70.07,69.91 69.37,69.22 69.06,69.22 67.15,67.31 67.15,64.1 65.5,62.45 65.5,61.38 v2(65.85,61.03)
  BOTTOM w0.081: v2(114.89,73.72) 114.89,73.81 UC1.T60
CFG16: length 56.1
  TOP w0.102: JXDP1.6 68.9,67.32 70.51,68.94 72.34,68.94 v1(72.8,68.48) 72.99,68.29 v2(73.9,68.29)
  IN4 w0.084: v2(73.9,68.29) 74.01,68.17 74.5,68.17 75.11,68.78 75.63,68.78 84.99,78.14 104.5,78.14 105.06,77.58 106.5,77.58 108.18,75.9 108.18,72.44 109.21,71.41 110.6,71.41 v2(111.28,70.73)
  BOTTOM w0.076: UC1.AA62 113.21,71.04 113.21,71.05 112.81,70.64 111.36,70.64 v2(111.28,70.73)
CFG17: length 57.9
  TOP w0.102: v1(69.84,68.85) 69.4,68.41 v2(69.4,68.4) 68.82,67.82 JXDP1.4
  IN2 w0.122: v2(109.6,71.84) 109.6,71.98 108.83,72.75 108.83,76.17 106.11,78.88 88.52,78.88 88.2,78.56 78.75,78.56 72.91,72.72 72.91,72.38 69.4,68.88 v2(69.4,68.4)
  BOTTOM w0.076: UC1.AA61 113.64,71.14 113.39,71.39 113.15,71.39 112.97,71.22 112.97,71.05 112.74,70.81 111.71,70.81 111.41,71.11 110.33,71.11 109.93,71.51
  BOTTOM w0.102: 109.93,71.51 v2(109.6,71.84)
CFG18: length 62.7
  TOP w0.102: JXDP1.24 68.65,62.82 v2(69.32,62.82)
  IN4 w0.084: v2(69.32,62.82) 68.53,63.61 68.53,66.57 70.04,68.08 70.04,68.69 70.42,69.07 72.93,69.07 73.9,70.04 74.92,70.04 76.37,71.49 76.37,73.82 75.91,74.28 75.91,75.39 77.73,77.21 80.06,77.21 83.08,80.24 88.25,80.24 89.08,79.4 105.03,79.4 105.54,78.89 107.01,78.89 109.58,76.33 109.58,74.73 v2(110.01,74.29)
  BOTTOM w0.076: v2(110.01,74.29) 110.05,74.29 v1(110.63,73.71) 110.78,73.56 112.41,73.56
  BOTTOM w0.081: UC1.U63 112.41,73.56
CFG19: length 61.9
  TOP w0.076: v1(112.08,73.7) 111.53,73.15 v2(111.39,73.15)
  TOP w0.102: JXDP1.22 69.31,63.32 v2(69.39,63.4)
  IN4 w0.084: v2(69.39,63.4) 69.92,63.93 69.92,66.51 71.27,67.85 72.9,67.85 74.25,69.2 75.27,69.2 77.22,71.14 77.22,74.17 76.77,74.61 76.77,75.06 77.95,76.24 82.5,76.24 84.82,78.56 104.67,78.56 105.23,78 106.67,78 108.72,75.96 108.72,73.24 109.34,72.62 110.86,72.62 v2(111.39,73.15)
  BOTTOM w0.076: UC1.U62 113.03,73.35 112.74,73.06 112.5,73.06 112.25,73.31 111.54,73.31 v2(111.39,73.15)
CFG_RCOMP: length 12.1
  IN2 w0.381: v2(107.94,65.91) 109.01,66.98 109.01,68.23 109.4,68.62 112,68.62 112.76,69.38 112.76,72.07 112.15,72.68 v2(112.04,72.68)
  BOTTOM w0.178: UC1.V63 112.12,72.6 v2(112.04,72.68)
  BOTTOM w0.381: RC185.1 v2(107.94,65.91)
CHAGER_SRC:
  vias: v1(59.87,7.4) v2(58.65,15.46) v2(58.79,9.12) v2(58.98,11.79) v2(59.28,15.46) v2(59.42,9.12) v2(59.61,11.79) v2(59.92,15.46) v2(60.06,9.12) v2(60.25,11.79) v2(61.86,7.26) v2(61.87,6.64) v2(61.87,6.03) v2(61.87,5.42) v2(62.48,7.25) v2(62.5,6.62) v2(62.51,6.01) v2(62.5,5.42)
CHARGER_CELL_PIN: length 2.7
  TOP w0.203: PU700.16 51.7,5.46 51.37,5.13 v2(51.37,5.03)
  TOP w0.254: v2(51.37,5.03) 51.37,4.55 PR725.2
  BOTTOM w0.254: PR729.1 50.83,5.78 51.37,5.23 v2(51.37,5.03)
CHARGER_SMBCLK: length 251.8
  TOP w0.102: PU700.12 49.61,7.55 v2(49.37,7.31) 49.37,7.31 48.92,7.76 48.92,7.85 47.94,8.83 46.41,8.83 45.86,9.37 PT2.1 ; v2(244.71,55.73) RPE6.3 ; v2(245.27,59.45) 245.41,59.32 UE2.B50
  IN1 w0.084: v2(244.71,55.73) 244.52,55.92 244.34,55.92 244.15,55.73 244.15,54.16 242.22,52.23 241.78,52.23 239.38,49.83 239.38,44.74 238.15,43.51 233.37,43.51 233.05,43.19 233.05,42 232.36,41.31 224.03,41.31 219.97,37.25 210.87,37.25 209.28,35.67 209.28,32.3 205.36,28.38 205.36,20.39 200.34,15.36 190.19,15.36 185.88,11.05 181.86,11.05 176.22,16.69 136.13,16.69 132.66,13.23 118.92,13.23 114.39,17.76 52.36,17.76 51.03,16.43 51.03,10.57 50.56,10.11 50.56,8 50.12,7.56 49.62,7.56 v2(49.37,7.31)
  BOTTOM w0.102: v2(244.71,55.73) 244.25,56.18 244.25,57.93 245.27,58.95 v2(245.27,59.45)
CHARGER_SMBDAT: length 249.9
  TOP w0.102: PT1.1 45.86,9.92 45.86,9.71 46.52,9.05 48.01,9.05 49.17,7.9 v2(49.37,7.9) 49.45,7.82 49.89,7.82 50.01,7.95 PU700.11 ; UE2.A47 245.16,56.8 v2(244.72,56.36) 245.21,55.87 RPE6.2
  IN1 w0.084: v2(244.72,56.36) 244.48,56.13 244.25,56.13 243.93,55.81 243.93,54.25 242.13,52.45 241.7,52.45 239.17,49.92 239.17,44.83 238.07,43.73 233.29,43.73 232.84,43.28 232.84,42.09 232.27,41.52 223.94,41.52 219.88,37.46 210.78,37.46 209.07,35.75 209.07,32.38 205.15,28.46 205.15,20.47 200.25,15.57 190.1,15.57 185.79,11.26 181.94,11.26 176.3,16.9 136.04,16.9 132.58,13.44 119.01,13.44 114.48,17.97 52.27,17.97 50.82,16.51 50.82,10.66 50.35,10.19 50.35,8.09 50.03,7.77 49.5,7.77 v2(49.37,7.9)
CHG_BTS:
  vias: v1(55.78,7.95)
CHG_LGATE: length 15.1
  TOP w0.102: v1(55.66,6.27) 55.93,6.54 v2(55.93,6.77)
  IN4 w1.016: 55.8,4.74 56.39,4.15 66.4,4.15 67.23,4.99 67.23,7.51
  vias: v2(55.36,7.02) v2(67.74,9.18) v2(67.74,8.55)
CHG_SNUB: length 1.7
  TOP w0.102: v1(67.88,12.37) PR726.1
CHG_SW: length 7.6
  IN1 w0.889: 63.37,8.56 61.67,10.26 56.88,10.26 56.57,9.94
  vias: v1(63.87,11.14) v2(55.49,9.04) v2(56.06,9.37) v2(63.87,7.66) v2(63.87,7.02) v2(63.87,6.39) v2(63.87,5.75) v2(64.5,7.66) v2(64.5,7.02) v2(64.5,6.39) v2(64.5,5.75) v2(65.14,7.66) v2(65.14,7.02) v2(65.14,6.39) v2(65.14,5.75) v2(65.77,7.66) v2(65.77,7.02) v2(65.77,6.39) v2(65.77,5.75)
CHG_UGATE: length 5.2
  TOP w0.102: PQ704.1 61.42,8.61 62.15,9.35 v1(62.15,10.44)
  IN4 w1.016: 57.07,8.48 57.84,8.48 58.34,7.98 59.87,7.98
  vias: v2(55.55,8.46) v2(56.12,8.74) v2(60.67,8.91) v2(60.67,8.29)
CLK_27M_IN: length 9.7
  TOP w0.102: YV2.1 201.79,89.61 201.79,88.35 CV115.1 RV80.1 201.23,87.67 201.42,87.48 v1(201.42,86.55) 201.42,86.47 200.2,85.26 200.2,83.64 200.06,83.49 UV8.K1
CLK_27M_OUT: length 5.4
  TOP w0.102: RV81.2 199.34,88.05 RV80.2 200.32,86.72 v1(200,86.41) 199.62,86.02 199.62,84.43 UV8.L1
CLK_BIASREF: length 7.3
  BOTTOM w0.102: UC1.C26 135.97,81.36 135.61,81.72 135.61,81.92 136.2,82.51 136.2,82.97
  BOTTOM w0.254: 136.2,82.97 136.26,83.03 136.26,84.18 136.64,84.56 v1(136.64,85.32) 134.86,87.1 RC69.1
CLK_DDC2_DOCK: length 94.1
  TOP w0.102: v2(182.36,95.29) 182.55,95.1 v1(182.55,94.53) 183.24,93.83 183.83,93.83 185.13,92.53 195.27,92.53 196.08,91.73 196.08,90.27 196.66,89.69 196.66,87.22 197.64,86.24 197.64,84.46 UV8.L4
  IN1 w0.084: v2(124.99,110.01) 124.26,109.27 124.26,103.82 124.8,103.28 145.83,103.28 147.12,102 151.3,102 153.81,99.48 160,99.48 160.54,100.02 167.91,100.02 172.21,95.72 181.93,95.72 v2(182.36,95.29)
  BOTTOM w0.102: JDOCK1.48 124.95,109.6 124.81,109.74 124.81,109.83 v2(124.99,110.01)
CLK_KBD: length 166.8
  TOP w0.102: UE2.A38 240.66,57 240.17,56.51 240.17,54.64 240.77,54.04 240.77,53.77 v2(240.58,53.58) 240.71,53.44 RPE2.8
  IN2 w0.122: v2(134.32,110.95) 134.4,110.86 136.18,110.86 136.84,110.2 136.84,107.98 137.66,107.16 141.12,107.16 147.39,100.89 149.69,100.89 150.83,99.76 151.28,99.76 153.96,97.08 166.94,97.08 173.07,90.95 178.94,90.95 180.03,92.04 188.86,92.04 189.44,92.62 204.38,92.62 205.52,91.48 210.28,91.48 213.23,88.53 214.52,88.53 216.63,86.41 216.63,86.09 217.4,85.32 221.71,85.32 223.09,83.94 224.19,83.94 227.8,80.33 238.79,80.33 240.75,78.37 241.73,78.37 246.88,73.22 246.88,71.44 246.43,71 246.43,68.36 247.38,67.42 247.38,55.74 245.53,53.89 244.95,53.89 243.56,52.49 241.18,52.49 240.72,52.96 240.72,53.43 v2(240.58,53.58)
  BOTTOM w0.102: JDOCK1.78 133.45,109.36 133.62,109.52 133.62,109.93 133.49,110.06 133.49,110.54 133.71,110.76 134.12,110.76 v2(134.32,110.95)
CLK_MSE: length 163.2
  TOP w0.102: UE2.A39 241.16,56.8 240.65,56.3 240.65,54.84 241.35,54.14 241.44,54.14 v2(241.62,53.95) 241.85,53.73 241.85,53.32 241.71,53.19 RPE2.6
  IN2 w0.122: v2(241.62,53.95) 241.62,53.93 242.3,53.25 243.25,53.25 244.71,54.71 245.29,54.71 245.92,55.35 245.92,56.81 246.63,57.51 246.63,67.04 245.66,68.01 245.66,71.3 246.12,71.77 246.12,72.86 245.73,73.25 243.86,73.25 243.11,74.01 241.66,74.01 237.98,77.68 236.04,77.68 234.2,79.53 227.45,79.53 223.79,83.19 222.69,83.19 221.31,84.57 216.42,84.57 214.96,86.02 213.99,86.02 210.26,89.76 206.1,89.76 203.99,91.87 191.96,91.87 191.38,91.29 184.45,91.29 183.37,90.2 172.76,90.2 166.63,96.33 153.64,96.33 150.97,99.01 150.52,99.01 149.54,99.99 147.16,99.99 143.66,103.49 134.51,103.49 132.07,101.05 132.07,99.04 v2(131.82,98.79)
  BOTTOM w0.102: JDOCK1.71 131.95,99.68 132.09,99.54 132.09,99.06 v2(131.82,98.79)
CLK_PCI_DOCK: length 128.2
  TOP w0.102: CC15.2 144.5,52.7 144.5,51.8 143.97,51.27 RC70.2 144.5,50.74 150.27,50.74 156.32,44.69 180.08,44.69 v2(183.48,48.09) ; R273.1 145.77,98.73 146.44,98.06 v2(146.85,98.06) 147.26,98.46 151.88,98.46 v1(153.72,96.62) 158.48,91.86 158.48,89.57 163.44,84.62 v2(163.44,83.08)
  IN4 w0.084: v2(183.48,48.09) 182.55,49.03 182.55,52.87 183.06,53.38 183.06,54.91 179.25,58.72 179.25,60.36 176.49,63.12 176.49,67.84 175.4,68.93 175.4,72.17 175.08,72.49 174.55,72.49 174.18,72.86 174.18,75.87 168.55,81.51 166.87,81.51 165.42,82.96 163.56,82.96 v2(163.44,83.08)
  BOTTOM w0.102: v2(146.85,98.06) 146.96,98.06 147.09,97.93 147.09,97.62 146.96,97.5 145.54,97.5 145.41,97.63 145.41,97.96 145.5,98.05 146.13,98.05 146.48,98.4 146.48,98.65 146.32,98.82 146.08,98.82 145.86,98.6 145.25,98.6 145.14,98.72 145.14,98.97 145.26,99.1 145.56,99.1 145.66,99.2 145.66,99.41 145.45,99.62 JDOCK1.121
CLK_PCI_LPDEBUG: length 180.5
  TOP w0.102: v2(147.82,49.44) v1(145.34,49.44) 144.85,49.44 RC67.2 143.01,51.27 142.52,51.76 142.52,52.53 143.01,53.02 CC14.2 ; JLPDE1.10 13.46,16.04 v2(13.58,16.15)
  IN3 w0.122: v2(43.69,18.36) 43.35,18.36 42.61,17.62 37.38,17.62 36.65,16.89 v2(35.45,16.89)
  IN4 w0.084: v2(35.45,16.89) 31.03,16.89 29.31,15.18 18.49,15.18 17.51,16.15 v2(13.58,16.15) ; v2(55.49,27.53) 57.12,29.17 57.12,39.53 59.07,41.47 59.07,44.21 59.25,44.39 59.25,47.11 v2(59.87,47.73)
  BOTTOM w0.102: v2(55.49,27.53) 55.21,27.25 50.86,27.25 47.62,24.02 46.06,24.02 44.69,22.64 44.69,18.91 44.49,18.71 44.03,18.71 v2(43.69,18.36) 45.26,18.36 45.63,18.73 45.63,20.42 45.76,20.55 46.14,20.55 46.27,20.67 46.27,20.84 46.14,20.97 45.56,20.97 45.43,21.09 45.43,21.32 45.56,21.45 JMINI3.19 ; v2(147.82,49.44) 147.8,49.43 71.53,49.43 69.93,51.03 68.5,51.03 67.71,51.82 66.76,51.82 65.65,50.7 62.68,50.7 59.87,47.89 v2(59.87,47.73)
CLK_PCI_MEC: length 117.3
  TOP w0.102: UE2.A29 235.92,61.1 234.87,60.05 RE66.1 234.3,59.47 234.49,59.28 234.49,58.97 234.37,58.84 233.86,58.84 233.6,59.09 233.6,59.32 233.48,59.44 232.43,59.44 231.71,60.16 v2(231.26,60.16) ; v2(189.03,47.47) 183.75,47.47 v1(183.5,47.22) 180.36,44.08 156.07,44.08 151.88,48.27 144.06,48.27 141.75,50.58 RC74.2 142.2,51.72 142.2,52.53 141.63,53.1 CC13.2
  IN4 w0.084: v2(231.26,60.16) 231.26,60.53 230.83,60.96 230.15,60.96 229.54,61.57 228.38,61.57 227.97,61.98 226.98,61.98 223.05,58.05 223.05,57.05 222.77,56.76 222.77,55.73 214.75,47.72 214.1,47.72 212.95,46.57 212.28,46.57 211.54,45.83 211.54,45.35 210.87,44.68 206.99,44.68 205.96,43.65 195.15,43.65 194.12,44.68 191.26,44.68 190.61,45.32 190.61,46.58 189.73,47.47 v2(189.03,47.47)
CLK_PCI_SIO: length 99.7
  TOP w0.102: v2(189.79,46.54) 189,46.54 188.84,46.71 184.22,46.71 v1(182.12,44.6) 180.99,43.47 155.82,43.47 151.63,47.66 143.78,47.66 140.86,50.58 RC72.2 140.42,51.7 140.42,52.98 140.72,53.28 CC12.2 ; UE1.A28 222.5,47.15 222.37,47.28 222.37,48.49 222.25,48.62 222.05,48.62 221.92,48.49 221.92,48.01 221.79,47.89 RE27.1 221.42,48.81 221.29,48.93 220.59,48.93 220.46,48.81 220.46,48.64 220.33,48.51 219.42,48.51 219.29,48.64 v2(219.29,49.19)
  IN4 w0.084: v2(189.79,46.54) 189.79,45.31 191.02,44.09 193.88,44.09 194.9,43.06 200.95,43.06 201.38,42.63 205.78,42.63 207.24,44.09 211.31,44.09 214.35,47.13 215,47.13 217.2,49.33 219.15,49.33 v2(219.29,49.19)
CLK_PCIE_LAN: length 127.4
  TOP w0.102: UL1.44 237.09,91.35 237.05,91.4 237.05,91.8 v2(237.2,91.96)
  IN1 w0.084: v2(126.69,84.28) 126.9,84.07 127.14,84.07 127.26,84.18 127.26,86.35 127.88,86.97 128.06,86.97 131.89,90.81 131.89,91.74 134.28,94.13 138.46,94.13 140.51,96.18 149.55,96.18 149.55,96.18 150.99,96.18 152.41,94.76 167.62,94.76 172.82,89.55 183.09,89.55 184.3,90.75 185.84,90.75 186.31,91.23 195.91,91.23 197.23,92.55 204.08,92.55 204.63,91.99 211.81,91.99 212.73,91.08 227.2,91.08 228.48,92.36 230.54,92.36 230.94,92.77 236.54,92.77 236.98,92.33 236.98,92.19 v2(237.2,91.96)
  BOTTOM w0.102: v2(126.69,84.28) 126.52,84.12 126.26,84.12 125.96,83.81 125.96,81.88 125.93,81.86 125.93,81.81 UC1.B42
CLK_PCIE_LAN#: length 127.1
  TOP w0.102: v2(236.62,91.96) 236.78,91.8 236.78,91.41 236.69,91.33 UL1.45
  IN1 w0.084: v2(126.69,83.7) 126.88,83.89 127.21,83.89 127.43,84.11 127.43,86.28 127.95,86.8 128.13,86.8 132.07,90.73 132.07,91.67 134.35,93.95 138.53,93.95 140.58,96 149.62,96 150.92,96 152.33,94.59 167.54,94.59 172.75,89.38 183.16,89.38 184.37,90.58 185.91,90.58 186.38,91.06 195.98,91.06 197.3,92.37 204.01,92.37 204.56,91.82 211.74,91.82 212.65,90.91 227.27,90.91 228.55,92.19 230.61,92.19 231.01,92.6 236.47,92.6 236.81,92.26 236.81,92.15 v2(236.62,91.96)
  BOTTOM w0.102: UC1.C41 126.5,81.7 126.21,81.99 126.21,83.71 126.37,83.87 126.52,83.87 v2(126.69,83.7)
CLK_PCIE_MMI: length 202.1
  TOP w0.102: UR1.3 257.04,18.53 256.99,18.57 256.69,18.57 255.2,20.06 253.07,20.06 v2(252.92,19.91)
  IN4 w0.084: v2(252.92,19.91) 252.67,20.17 252.54,20.17 252.32,20.39 252.32,27.41 249.38,30.35 249.38,41.48 243.56,47.3 239.4,47.3 239,47.7 234.08,47.7 233.61,48.17 232.11,48.17 230.69,49.59 227.44,49.59 226.46,50.56 224.3,50.56 223.44,51.43 222.45,51.43 222.22,51.19 221.63,51.19 221.2,50.77 221.2,49.07 220.05,47.92 218.67,47.92 218.49,48.1 217.78,48.1 214.99,45.32 214.28,45.32 211.61,42.65 207.54,42.65 206.29,41.4 200.87,41.4 200.44,41.83 193.14,41.83 192.68,42.28 188.88,42.28 185.79,45.38 185.79,46.33 184.79,47.33 183.02,47.33 181.72,48.62 181.72,54.66 178.48,57.91 178.48,60.04 175.72,62.8 175.72,67.07 174.17,68.63 174.17,71.79 173.41,72.54 173.41,75.56 172.37,76.6 170.69,76.6 165.1,82.19 162.65,82.19 162.09,82.75 162.09,85.27 159.84,87.52 156.8,87.52 155.93,86.65 154.48,86.65 154.19,86.94 148.86,86.94 147.99,87.82 144,87.82 142.77,89.05 138.65,89.05 137.97,88.37 128.25,88.37 126.16,86.27 126.16,85 126.02,84.86 125.82,84.86 v2(125.61,84.64)
  BOTTOM w0.081: v2(125.61,84.64) 125.43,84.82 125.34,84.82 125.15,84.63 125.15,83.22 125.08,83.15 125.08,82.71 125.14,82.59 125.14,82.37 125.12,82.28 125.11,82.27 125.09,82.22 125.08,82.22 125.08,82.21 125.08,82.08 125.11,81.98 125.32,81.77 125.5,81.77 125.67,81.6 125.75,81.46 UC1.C42
CLK_PCIE_MMI#: length 201.9
  TOP w0.102: v2(252.92,20.5) 253.09,20.33 255.31,20.33 256.8,18.84 256.98,18.84 257.07,18.93 UR1.2
  IN4 w0.084: v2(125.61,85.23) 125.8,85.03 125.95,85.03 125.99,85.07 125.99,86.35 128.18,88.54 137.89,88.54 138.58,89.22 142.84,89.22 144.07,87.99 148.06,87.99 148.94,87.12 154.26,87.12 154.55,86.82 155.86,86.82 156.73,87.69 159.91,87.69 162.26,85.34 162.26,82.83 162.72,82.37 165.17,82.37 170.76,76.78 172.44,76.78 173.59,75.63 173.59,72.62 174.34,71.86 174.34,68.7 175.9,67.14 175.9,62.87 178.65,60.12 178.65,57.98 181.9,54.73 181.9,48.69 183.09,47.5 184.86,47.5 185.96,46.4 185.96,45.45 188.96,42.45 192.76,42.45 193.21,42 200.51,42 200.94,41.57 206.22,41.57 207.47,42.83 211.54,42.83 214.2,45.49 214.92,45.49 217.7,48.28 218.56,48.28 218.75,48.09 219.98,48.09 221.03,49.14 221.03,50.84 221.56,51.36 222.14,51.36 222.38,51.6 223.51,51.6 224.37,50.74 226.53,50.74 227.51,49.76 230.76,49.76 232.18,48.34 233.68,48.34 234.16,47.87 239.07,47.87 239.47,47.47 243.63,47.47 249.55,41.55 249.55,30.42 252.49,27.48 252.49,20.46 252.61,20.34 252.76,20.34 v2(252.92,20.5)
  BOTTOM w0.081: v2(125.61,85.23) 125.43,85.05 125.25,85.05 124.92,84.72 124.92,83.31 124.92,83.31 124.92,82.68 124.98,82.5 124.98,82.4 124.93,82.28 124.93,82.27 124.92,82.24 124.92,82.06 124.96,81.9 125.06,81.75 UC1.C43
CLK_PCIE_SATA: length 132
  IN4 w0.084: v2(127.96,85.59) 128.15,85.79 129.36,85.79 130.63,87.05 138.46,87.05 139.18,87.77 141.74,87.77 142.48,87.03 143.25,87.03 143.74,86.54 147.36,86.54 148.24,85.67 150.26,85.67 150.91,85.02 152.67,85.02 157.32,80.36 165.12,80.36 171.77,73.71 171.77,72.16 172.07,71.86 172.27,71.86 172.89,71.23 172.89,68.1 173.81,67.18 173.81,62.91 177.21,59.52 177.21,57.36 179.71,54.85 179.71,54.19 180.33,53.58 180.33,48.21 188.77,39.77 195.63,39.77 195.98,40.12 198.19,40.12 198.8,40.73 206.52,40.73 207.81,42.02 211.88,42.02 213.92,44.06 214.64,44.06 217.87,47.3 218.03,47.3 v2(218.28,47.05)
  BOTTOM w0.081: 128.78,84.87 128.78,84.86 128.79,84.85 128.79,83.56 128.96,83.39 128.96,83.2 128.83,83.07 128.7,83.07 128.64,83.01 128.64,82.7 128.8,82.54 128.88,82.54 129.01,82.67 UC1.A37
  BOTTOM w0.102: 128.78,84.87 128.78,85.69 128.56,85.91 128.27,85.91 v2(127.96,85.59) ; JNGFF2.47 217.57,48.65 217.73,48.49 217.73,47.6 v2(218.28,47.05)
CLK_PCIE_SATA#: length 132.3
  IN4 w0.084: v2(127.96,86.18) 128.17,85.96 129.29,85.96 130.56,87.22 138.38,87.22 139.11,87.95 141.81,87.95 142.55,87.21 143.32,87.21 143.82,86.71 147.44,86.71 148.31,85.84 150.33,85.84 150.98,85.19 152.74,85.19 157.39,80.54 165.19,80.54 171.94,73.78 171.94,72.23 172.14,72.03 172.34,72.03 173.07,71.31 173.07,68.17 173.99,67.25 173.99,62.98 177.38,59.59 177.38,57.43 179.88,54.92 179.88,54.27 180.5,53.65 180.5,48.29 188.84,39.95 195.56,39.95 195.91,40.29 198.11,40.29 198.73,40.91 206.45,40.91 207.73,42.19 211.81,42.19 213.85,44.23 214.56,44.23 217.8,47.47 218.11,47.47 v2(218.28,47.64)
  BOTTOM w0.081: UC1.B37 129.01,82.32 129.34,82.65 129.34,82.91 129.21,83.03 129.21,83.49 129.03,83.67 129.03,84.85 129.04,84.86 129.04,84.87
  BOTTOM w0.102: v2(127.96,86.18) 128.67,86.18 129.04,85.8 129.04,84.87 ; JNGFF2.45 217.45,49.15 218,48.6 218,47.71 218.07,47.64 v2(218.28,47.64)
CLK_PCIE_WIGIG: length 145.5
  IN4 w0.084: v2(126.69,85.47) 126.8,85.58 127.25,85.58 127.49,85.82 127.49,86.4 127.82,86.73 129.29,86.73 130.25,87.69 138.19,87.69 138.91,88.41 142.5,88.41 143.73,87.18 147.73,87.18 148.6,86.31 153.65,86.31 154.2,85.76 155.95,85.76 157.07,86.88 159.57,86.88 161.45,85.01 161.45,82.49 162.38,81.56 164.82,81.56 171.67,74.71 172.28,74.71 172.78,74.22 172.78,72.28 173.53,71.52 173.53,68.36 175.09,66.81 175.09,62.54 177.84,59.78 177.84,57.64 181.03,54.46 181.03,48.42 182.75,46.69 183.4,46.69 185.13,44.96 185.31,44.96 189.85,40.41 195.05,40.41 195.39,40.76 196.16,40.76 196.35,40.95 196.35,41.17 v2(196.54,41.36)
  BOTTOM w0.081: UC1.B39 127.88,82.34 127.15,83.07 127.15,83.95 127.14,83.96 127.14,83.98
  BOTTOM w0.102: 127.14,83.98 127.14,85.44 127,85.58 126.8,85.58 v2(126.69,85.47) ; JNGFF1.63 207.77,12.35 207.54,12.12 207.17,12.12 206.62,12.67 206.62,15.32 204.38,17.56 204.38,22.58 203.92,23.04 203.92,25.61 203.29,26.24 203.29,27.91 200.65,30.55 199.58,30.55 198.23,31.89 198.23,32.55 196.91,33.87 196.91,34.28 195.43,35.77 195.43,38.74 196.22,39.53 196.22,41.05 v2(196.54,41.36)
CLK_PCIE_WIGIG#: length 145.3
  IN4 w0.084: v2(126.69,86.05) 126.98,85.75 127.18,85.75 127.31,85.89 127.31,86.47 127.75,86.91 129.22,86.91 130.18,87.86 138.12,87.86 138.84,88.58 142.57,88.58 143.8,87.35 147.8,87.35 148.67,86.48 153.72,86.48 154.27,85.94 155.88,85.94 157,87.06 159.64,87.06 161.62,85.08 161.62,82.56 162.45,81.73 164.9,81.73 171.74,74.89 172.35,74.89 172.95,74.29 172.95,72.35 173.7,71.6 173.7,68.43 175.26,66.88 175.26,62.61 178.02,59.85 178.02,57.71 181.2,54.53 181.2,48.49 182.82,46.87 183.47,46.87 185.21,45.13 185.38,45.13 189.92,40.58 194.97,40.58 195.32,40.93 196.09,40.93 196.18,41.02 196.18,41.14 v2(195.96,41.36)
  BOTTOM w0.081: 127.39,83.98 127.39,83.96 127.38,83.95 127.38,83.17 127.77,82.78 UC1.A39
  BOTTOM w0.102: JNGFF1.65 207.06,11.85 206.35,12.56 206.35,15.21 204.11,17.45 204.11,22.47 203.66,22.93 203.66,25.5 203.02,26.13 203.02,27.8 200.54,30.28 199.47,30.28 197.97,31.78 197.97,32.44 196.64,33.76 196.64,34.17 195.16,35.66 195.16,38.85 195.96,39.64 v2(195.96,41.36) ; 127.39,83.98 127.39,85.54 127.11,85.83 126.9,85.83 v2(126.69,86.05)
CLK_PCIE_WLAN: length 135.8
  IN4 w0.084: v2(197.26,38.87) 197.26,39.5 197.1,39.66 196.18,39.66 195.83,39.31 188.58,39.31 179.8,48.08 179.8,53.39 179.16,54.03 179.16,54.74 175.69,58.21 175.69,58.84 174.82,59.71 174.56,59.71 173.35,60.92 173.35,66.98 171.41,68.92 171.41,71.71 171.27,71.86 171.27,72.91 169.48,74.7 169.48,75.35 167.01,77.81 165.92,77.81 163.93,79.8 157.23,79.8 152.66,84.37 150.86,84.37 150.06,85.17 146.69,85.17 146.12,85.74 144.02,85.74 143.18,86.59 142.16,86.59 141.44,87.31 139.38,87.31 138.47,86.4 137.21,86.4 136.69,85.88 136.21,85.88 135.5,86.59 130.82,86.59 128.47,84.24 128.01,84.24 v2(127.89,84.36)
  BOTTOM w0.081: 128.55,83.67 128.55,83.66 128.54,83.65 128.54,83.35 128.45,83.26 128.45,82.65 128.69,82.4 128.69,81.98 128.77,81.91 128.77,81.72 UC1.C37
  BOTTOM w0.102: v2(197.26,38.87) 196.94,38.55 196.94,38.41 197.01,38.34 197.4,38.34 197.73,38.01 197.73,37.06 198.19,36.59 203.71,36.59 203.95,36.36 203.95,32.65 204.59,32.01 204.59,30.34 204.99,29.94 204.99,26.95 205.63,26.32 205.63,23.75 206.1,23.28 206.1,19.29 207.27,18.12 207.54,18.12 207.77,18.35 JNGFF1.39 ; 128.55,83.67 128.55,83.92 128.28,84.2 128.06,84.2 v2(127.89,84.36)
CLK_PCIE_WLAN#: length 135.9
  IN4 w0.084: v2(196.67,38.87) 197.08,39.28 197.08,39.42 197.03,39.48 196.25,39.48 195.9,39.14 188.5,39.14 179.63,48.01 179.63,53.32 178.99,53.96 178.99,54.67 175.52,58.14 175.52,58.77 174.75,59.54 174.49,59.54 173.18,60.85 173.18,66.91 171.24,68.85 171.24,71.64 171.09,71.78 171.09,72.84 169.3,74.63 169.3,75.27 166.94,77.64 165.85,77.64 163.86,79.62 157.16,79.62 152.59,84.19 150.79,84.19 149.98,85 146.62,85 146.05,85.57 143.95,85.57 143.11,86.42 142.09,86.42 141.37,87.14 139.45,87.14 138.54,86.22 137.28,86.22 136.76,85.71 136.13,85.71 135.43,86.41 130.89,86.41 128.55,84.07 128.18,84.07 v2(127.89,83.78)
  BOTTOM w0.081: 128.29,83.67 128.29,83.66 128.3,83.65 128.3,83.45 128.2,83.36 128.2,82.55 128.45,82.3 128.45,82.21 128.38,82.14 128.3,82.14 128.03,81.88 128.03,81.76 128.15,81.64 128.28,81.64 UC1.B38
  BOTTOM w0.102: JNGFF1.41 207.16,17.85 205.83,19.18 205.83,23.17 205.36,23.64 205.36,26.2 204.72,26.84 204.72,29.83 204.33,30.23 204.33,31.9 203.68,32.54 203.68,36.25 203.6,36.33 198.08,36.33 197.46,36.95 197.46,37.9 197.29,38.07 196.9,38.07 196.67,38.3 v2(196.67,38.87) ; v2(127.89,83.78) 128.05,83.93 128.17,83.93 128.29,83.81 128.29,83.67
CLK_TP_SIO: length 78.7
  TOP w0.102: v2(240.16,57.19) UE2.A37 ; CZ31.1 RZ19.2 218.06,16.73 218.06,16.05 v2(217.91,15.9) 218.06,15.74 218.06,9.39 216.95,8.28 211.45,8.28 210.34,9.38 210.34,10.72 210.48,10.86 JKBTP1.14
  IN1 w0.084: v2(217.91,15.9) 218.06,16.05 218.06,18.83 219.09,19.85 219.09,32.38 220.68,33.97 226.64,33.97 234.07,41.4 237.65,41.4 241.98,45.72 241.98,48.18 v2(241.78,48.38)
  BOTTOM w0.102: v2(240.16,57.19) 240.34,57.01 240.34,55.35 239.48,54.5 239.48,51.31 241.9,48.89 241.9,48.49 v2(241.78,48.38)
CLKRUN#: length 147.5
  TOP w0.076: v2(148.02,73.11) 148.29,73.37 149.18,73.37 149.21,73.39 152.27,73.39
  TOP w0.102: UE1.B20 225.27,51.9 v2(225.46,52.09) ; RPC15.3 160.47,70.84 160.26,71.06 160.26,71.28 160.02,71.52 160.02,72.05 160.18,72.21 160.18,73.4 159.74,73.84 157.16,73.84 157.02,73.7 v1(155.5,73.7) 154.18,73.7 154.01,73.53 152.41,73.53 152.27,73.39 ; UE2.A32 236.07,59.6 236.02,59.56 236.02,59.35 236.42,58.94 v2(236.42,58.27)
  IN3 w0.081: 154.36,73.49 153.9,73.49 153.82,73.57 152.4,73.57 152.19,73.36 148.28,73.36 v2(148.02,73.11)
  IN3 w0.122: v2(236.42,58.27) 235.93,58.76 233.67,58.76 230.31,62.12 229.63,62.12 229.22,62.53 229.22,66.01 228.83,66.41 228.83,72.36 228.45,72.75 225.79,72.75 225.2,73.33 223.5,73.33 222.02,74.82 216.57,74.82 215.11,73.35 212.81,73.35 212.08,72.62 209.43,72.62 208.57,73.48 204.96,73.48 203.95,72.47 188.62,72.47 188.49,72.6 187.05,72.6 182.96,76.68 178.74,76.68 177.96,77.46 176.09,77.46 175.57,77.98 171.44,77.98 169.19,75.73 167.47,75.73 164.98,73.25 162.78,73.25 162.54,73.49 154.36,73.49
  IN4 w0.084: v2(236.42,58.27) 236,58.69 230.43,58.69 229.76,59.36 229.76,59.95 229.17,60.54 227.24,60.54 225.68,58.98 225.68,58.2 223.75,56.26 223.75,53.8 v2(225.46,52.09)
  BOTTOM w0.081: UC1.V5 148.61,72.63 148.5,72.63 v2(148.02,73.11)
CMPIN: length 7.7
  TOP w0.102: PR737.2 45.91,7.42 44.51,8.81 v1(43.88,8.81)
  TOP w0.203: PU700.13 50,7.15 49.58,6.73 49.1,6.73 PR738.1
  TOP w0.254: PR737.2 PC737.1 PR745.1 48.51,7.32 PR738.1
CMPOUT: length 6
  TOP w0.102: v1(44.76,6.39) 44.82,6.45 PR743.1
  TOP w0.203: PU700.14 50.17,6.75 49.75,6.32 PR738.2
  TOP w0.254: PR743.1 45.87,6.42 PR740.1 PC741.2 48.49,6.42 PR738.2
CONTACTLESS_DET#: length 169.6
  TOP w0.102: JUSH1.17 247.98,12.25 v2(248.29,12.56) 249.3,12.56 249.89,13.14 249.89,14.49 v1(250.08,14.68)
  IN1 w0.076: 150.37,74.56 150.86,75.06 153.63,75.06
  IN1 w0.084: v2(162.46,75.53) 162.45,75.53 162,75.08 161.31,75.08 160.23,75.08 159.65,75.67 156.26,75.67 155.16,74.56 154.42,74.56 153.92,75.06 153.63,75.06 ; v2(148.12,74.08) 148.6,74.56 150.37,74.56
  IN3 w0.122: v2(248.29,12.56) 249.07,13.34 249.07,23.44 247.19,25.31 247.19,36.99 242.29,41.88 241.61,41.88 238.94,44.55 238.94,50.39 239.34,50.79 239.34,51.92 237.87,53.39 237.87,55.07 237.09,55.85 237.09,59.58 236.71,59.96 234.56,59.96 230.34,64.19 230.34,67.58 229.41,68.5 229.41,71.11 229.42,71.11 229.42,72.02 229.64,72.24 229.64,73.29 228.44,74.48 227.05,74.48 223.57,77.97 216.43,77.97 213.78,75.32 210.58,75.32 209.98,74.72 204.88,74.72 204.28,75.32 199.82,75.32 198.2,73.71 194.74,73.71 194.12,74.33 190.87,74.33 190.39,74.81 188.69,74.81 187.66,75.84 185.56,75.84 183.48,77.93 180.6,77.93 177.82,80.72 177.15,80.72 176.43,80 171.7,80 169.31,77.61 165.88,77.61 163.8,75.53 v2(162.46,75.53)
  BOTTOM w0.081: UC1.U6 148.08,73.7 148.08,74.04 v2(148.12,74.08)
  BOTTOM w0.102: RPC6.5 162.07,75.15 v2(162.46,75.53)
CORE_BOOT: length 1.1
  BOTTOM w0.102: v1(79.17,69.89) 78.8,69.52 PC504.2
CORE_BOOT_C: length 1.3
  BOTTOM w0.102: v1(77.78,70.14) 77.89,70.03 PC504.1
CORE_BOOT_R: length 3.1
  BOTTOM w0.102: PR517.1 78.87,67.8 78.17,67.09 77.01,67.09 v1(76.44,67.67)
CORE_SNUB: length 1.7
  BOTTOM w0.102: v1(85.89,60.91) 85.67,60.69 PR522.2
CORE_SW:
  vias: v1(86.6,65.63)
CPPE#: length 4.4
  BOTTOM w0.102: RC160.2 154.74,78.62 v1(154.36,78.23) 154.26,78.14 151.68,78.14 151.35,77.81 UC1.J1
CPU_DPB_AUX: length 95.7
  TOP w0.102: CV79.1 226.06,86.91 v2(226.2,87.04)
  IN1 w0.091: v2(226.2,87.04) 226.16,87.04 225.78,86.66 225.22,86.66 224.05,85.49 221.99,85.49 219.52,87.97 215.96,87.97 215.39,88.54 207.43,88.54 206.54,87.65 199.77,87.65 199.01,88.41 197.11,88.41 196.62,88.9 194.86,88.9 194.47,89.3 187.24,89.3 186.76,88.82 185.1,88.82 183.89,87.62 172.02,87.62 166.81,92.83 151.4,92.83 151,93.22 150.47,93.22 150.25,93 150.25,92.84 v2(150.04,92.63)
  BOTTOM w0.081: UC1.B5 148.14,82.1 148.28,82.1 148.33,82.15 148.33,82.35 148.28,82.41 148.22,82.41 148.17,82.46 148.17,83.08 149.13,84.04 149.13,85.52 149.12,85.53 149.12,85.54
  BOTTOM w0.102: v2(150.04,92.63) 150.1,92.58 150.1,91.48 150.51,91.07 150.51,90.28 150.05,89.83 149.28,89.83 149.02,89.57 RPC20.2 149.02,88.88 149.12,88.77 149.12,85.54
CPU_DPB_AUX#: length 95.5
  TOP w0.102: v2(226.16,86.46) 225.95,86.46 225.58,86.09 CV80.1
  IN1 w0.091: v2(226.16,86.46) 226.13,86.49 225.29,86.49 224.12,85.32 221.92,85.32 219.44,87.79 215.89,87.79 215.32,88.37 207.5,88.37 206.62,87.48 199.7,87.48 198.94,88.24 197.04,88.24 196.55,88.73 194.79,88.73 194.4,89.12 187.31,89.12 186.84,88.65 185.17,88.65 183.96,87.44 171.95,87.44 166.74,92.65 151.33,92.65 150.93,93.05 150.55,93.05 150.42,92.93 150.42,92.84 v2(150.63,92.63)
  BOTTOM w0.081: UC1.C5 148.5,81.61 148.5,82.46 148.37,82.6 148.37,83 149.33,83.96 149.33,85.51 149.34,85.52 149.34,85.54
  BOTTOM w0.102: v2(150.63,92.63) 150.32,92.32 150.32,91.57 150.74,91.15 v4(150.74,90.84) 150.74,90.21 150.14,89.61 149.59,89.61 149.52,89.53 RPC20.1 149.52,88.81 149.34,88.63 149.34,85.54
CPU_DPB_AUX#_C: length 4
  TOP w0.102: CV80.2 224.38,86.31 224.14,86.31 223.77,86.68 v4(223.77,87.21) 223.77,87.77 223.45,88.09 223.12,88.09 222.87,87.83 UV7.51
CPU_DPB_AUX_C: length 4
  TOP w0.102: UV7.52 222.92,88.23 222.99,88.3 223.54,88.3 223.98,87.86 223.98,87.49 224,87.48 224,86.94 223.98,86.93 223.98,86.77 224.23,86.52 224.32,86.52 224.67,86.87 CV79.2
CPU_DPB_CTRLCLK: length 99.9
  TOP w0.102: UV7.50 223.05,87.43 v2(223.29,87.67)
  IN1 w0.091: v2(223.29,87.67) 223.03,87.41 222.36,87.41 220.07,89.7 207.68,89.7 206.28,88.3 200.07,88.3 199.24,89.13 197.53,89.13 196.71,89.94 186.93,89.94 186.46,89.47 184.83,89.47 183.63,88.26 172.29,88.26 167.08,93.47 151.66,93.47 151.27,93.87 146.63,93.87 145.81,94.69 145.34,94.69 145.14,94.49 145.14,94.25 v2(144.94,94.04)
  BOTTOM w0.081: 146.13,84.92 146.13,84.48 146.26,84.35 146.26,83.6 146.08,83.43 146.08,82.66 145.56,82.14 UC1.B9
  BOTTOM w0.102: v2(144.94,94.04) 145.12,93.86 145.12,92.77 145.1,92.75 145.1,92.29 144.81,92 144.81,89.86 145.58,89.09 145.58,88.22 145.47,88.11 144.77,88.11 144.57,87.92 RPC2.2 144.57,87.23 144.74,87.06 144.74,86.31 146.13,84.92
CPU_DPB_CTRLDAT: length 99.6
  TOP w0.102: v2(223.29,87.08) 223.23,87.03 UV7.49
  IN1 w0.091: v2(223.29,87.08) 223.13,87.24 222.29,87.24 220,89.53 207.75,89.53 206.35,88.13 200,88.13 199.17,88.96 197.45,88.96 196.64,89.77 187,89.77 186.53,89.3 184.9,89.3 183.7,88.09 172.22,88.09 167.01,93.3 151.59,93.3 151.2,93.7 146.56,93.7 145.74,94.51 145.41,94.51 145.32,94.42 145.32,94.25 v2(145.52,94.04)
  BOTTOM w0.081: 146.28,85.08 146.29,85.06 146.29,85.05 146.33,85.01 146.33,84.84 146.32,84.83 146.32,84.56 146.45,84.43 146.45,83.51 146.25,83.31 146.25,82.59 145.89,82.23 UC1.C9
  BOTTOM w0.102: 146.28,85.08 144.96,86.4 144.96,86.98 145.07,87.1 RPC2.1 145.07,87.85 145.15,87.92 145.58,87.92 145.8,88.13 145.8,89.18 145.02,89.95 145.02,91.91 145.34,92.23 v4(145.34,92.49) 145.34,93.86 v2(145.52,94.04)
CPU_DPC_AUX: length 150.8
  TOP w0.102: v2(260.2,62.57) 260.12,62.65 259.64,62.65 259.25,63.04 259.25,63.6 CV512.2
  IN1 w0.091: v2(260.2,62.57) 260.95,62.57 261.16,62.78 261.16,66.96 259.99,68.13 259.99,68.85 257.08,71.76 257.08,77.29 254.44,79.92 247.45,79.92 245.67,81.7 242.53,81.7 239.04,85.19 232.65,85.19 231.95,85.89 228.17,85.89 226.68,84.4 225.5,84.4 225.19,84.09 221.09,84.09 217.86,87.32 208.44,87.32 208.13,87.01 199.34,87.01 198.62,87.73 196.7,87.73 196.18,88.25 194.55,88.25 194.15,88.65 187.54,88.65 187.07,88.18 185.37,88.18 184.16,86.97 171.76,86.97 166.55,92.18 159.85,92.18 159.8,92.13 148.81,92.13 148.58,92.37 148.58,92.5 v2(148.76,92.68)
  BOTTOM w0.081: UC1.A6 147.49,82.65 147.6,82.55 147.72,82.55 147.83,82.66 147.83,83.01 147.5,83.34 147.5,84.05 148.39,84.93 148.39,85.54
  BOTTOM w0.102: 148.39,85.54 148.39,88.62 148.52,88.75 RPC20.3 148.52,89.51 148.2,89.83 147.87,89.83 147.17,90.53 147.17,91.62 147.5,91.95 148.58,91.95 148.76,92.13 v2(148.76,92.68)
CPU_DPC_AUX#: length 150.7
  TOP w0.102: v2(260.2,63.15) 259.91,62.86 259.73,62.86 259.46,63.13 259.46,63.74 259.56,63.84 CV513.2
  IN1 w0.091: v2(148.18,92.68) 148.4,92.46 148.4,92.29 148.74,91.96 159.87,91.96 159.92,92.01 166.47,92.01 171.68,86.8 184.23,86.8 185.44,88.01 187.14,88.01 187.62,88.48 194.08,88.48 194.48,88.08 196.11,88.08 196.63,87.56 198.54,87.56 199.27,86.84 208.2,86.84 208.51,87.15 217.79,87.15 221.02,83.92 225.26,83.92 225.57,84.23 226.75,84.23 228.24,85.72 231.88,85.72 232.58,85.02 238.97,85.02 242.46,81.53 245.6,81.53 247.37,79.75 254.37,79.75 256.91,77.21 256.91,71.69 259.82,68.78 259.82,68.06 260.99,66.89 260.99,62.85 260.88,62.74 260.61,62.74 v2(260.2,63.15)
  BOTTOM w0.081: 148.17,85.54 148.17,85.53 148.18,85.52 148.18,85.45 148.19,85.44 148.19,85.01 147.31,84.13 147.31,83.06 147.17,82.92 147.17,82.59 147.31,82.46 147.31,82.32 UC1.B6
  BOTTOM w0.102: v2(148.18,92.68) 148.55,92.32 148.55,92.22 148.49,92.16 147.41,92.16 146.95,91.71 146.95,90.44 147.78,89.61 147.94,89.61 148.02,89.53 RPC20.4 148.02,88.75 148.17,88.59 148.17,85.54
CPU_DPC_CTRLCLK: length 154.2
  TOP w0.102: v2(259.26,70.4) 259,70.4 258.92,70.48 258.92,70.71 259.05,70.84 259.39,70.84 259.51,70.97 259.51,71.22 259.39,71.35 259.19,71.35 259.05,71.49 UV502.12
  IN1 w0.091: v2(141.59,94.89) 141.42,95.06 141.42,95.25 141.53,95.36 150.65,95.36 152.07,93.94 167.28,93.94 172.49,88.73 183.43,88.73 184.64,89.94 186.24,89.94 186.72,90.41 196.54,90.41 197.85,91.73 203.75,91.73 204.3,91.18 211.48,91.18 212.39,90.27 221.69,90.27 224.43,87.53 228.6,87.53 229.43,86.71 235.13,86.71 235.87,85.97 238.93,85.97 241.85,83.05 245.29,83.05 247.94,80.41 254.63,80.41 257.56,77.47 257.56,73.37 259.64,71.3 259.64,70.71 259.33,70.4 v2(259.26,70.4)
  BOTTOM w0.081: 145.05,85.34 145.05,85.34 145.05,85.32 145.28,85.09 145.28,83.68 145.5,83.47 145.5,82.53 145.24,82.26 145.24,82.01 145.53,81.72 145.53,81.55 146.08,80.99 UC1.D9
  BOTTOM w0.102: 145.05,85.34 143.97,86.42 143.97,86.99 144.07,87.1 RPC2.3 144.07,87.79 143.82,88.05 143.49,88.05 142.86,88.67 142.86,91.78 v4(142.34,92.3) 141.72,92.93 141.72,93.64 141.4,93.95 141.4,94.71 v2(141.59,94.89)
CPU_DPC_CTRLDAT: length 154.3
  TOP w0.102: UV502.9 261,70.68 260.72,70.4 v2(259.89,70.4)
  IN1 w0.091: v2(141,94.89) 141.24,95.14 141.24,95.32 141.46,95.53 150.72,95.53 152.14,94.12 167.35,94.12 172.56,88.91 183.36,88.91 184.56,90.11 186.17,90.11 186.65,90.59 196.46,90.59 197.78,91.9 203.82,91.9 204.37,91.35 211.55,91.35 212.46,90.44 221.77,90.44 224.5,87.71 228.68,87.71 229.5,86.89 235.2,86.89 235.94,86.14 239,86.14 241.92,83.23 245.36,83.23 248.01,80.58 254.7,80.58 257.73,77.54 257.73,73.44 259.81,71.37 259.81,70.48 v2(259.89,70.4)
  BOTTOM w0.081: UC1.D11 145.45,80.94 145.57,80.94 145.66,81.03 145.66,81.14 145.33,81.47 145.33,81.64 145.04,81.93 145.04,82.35 145.3,82.61 145.3,83.38 145.09,83.6 145.09,85.01 144.96,85.14 144.92,85.18 144.9,85.18 144.89,85.19
  BOTTOM w0.102: 144.89,85.19 143.75,86.33 143.75,86.92 143.57,87.1 RPC2.4 143.57,87.66 142.65,88.58 142.65,91.69 142.41,91.93 142.38,91.93 141.99,92.33 141.99,92.35 141.5,92.84 141.5,93.55 141.19,93.86 141.19,94.71 v2(141,94.89)
CPU_PWR_DEBUG#: length 93.8
  TOP w0.102: JXDP1.45 63.1,57.32 63.81,56.62 65.11,56.62 v2(65.84,55.89) ; RC197.2 107.72,88.49 RC198.1 107.63,88.4 107.63,86.77 v1(107.81,86.59) 107.81,86.36 108.38,85.79 108.38,81.79 v2(108.91,81.26)
  IN4 w0.084: v2(108.91,81.26) 106.67,83.5 106.67,84.89 104.38,87.18 100.41,87.18 100.15,86.91 85.23,86.91 83.12,84.8 80.6,84.8 79.16,83.37 76.59,83.37 74.15,80.92 74.15,78.02 73.14,77.01 73.14,71.38 72.3,70.54 69.81,70.54 69.11,69.85 68.8,69.85 66.52,67.57 66.52,65.51 65.64,64.62 65.44,64.62 64.53,63.71 64.53,62.82 65.29,62.05 65.29,60.94 66.6,59.63 66.6,56.24 66.25,55.89 v2(65.84,55.89)
  BOTTOM w0.076: UC1.H59 114.93,78.92 113.86,78.92 113.74,79.04 112.94,79.04 112.8,78.9 111.86,78.9 111.86,78.9
  BOTTOM w0.081: 111.86,78.9 110.85,79.91
  BOTTOM w0.102: v2(108.91,81.26) 109.34,80.83 109.93,80.83 110.85,79.91
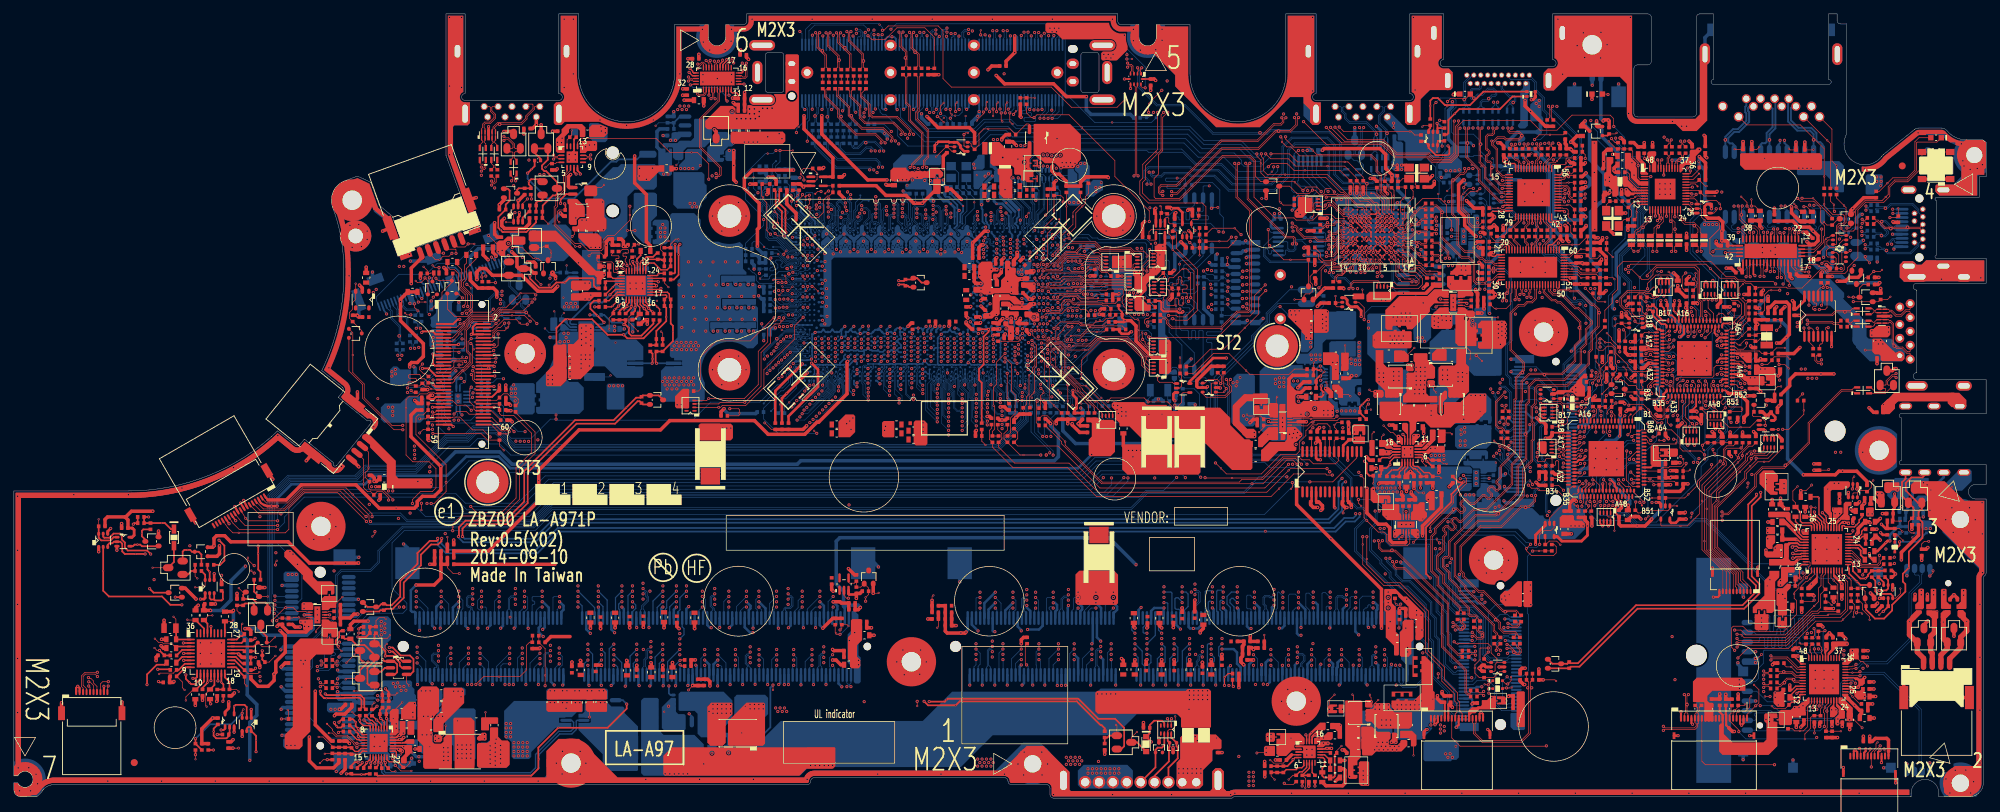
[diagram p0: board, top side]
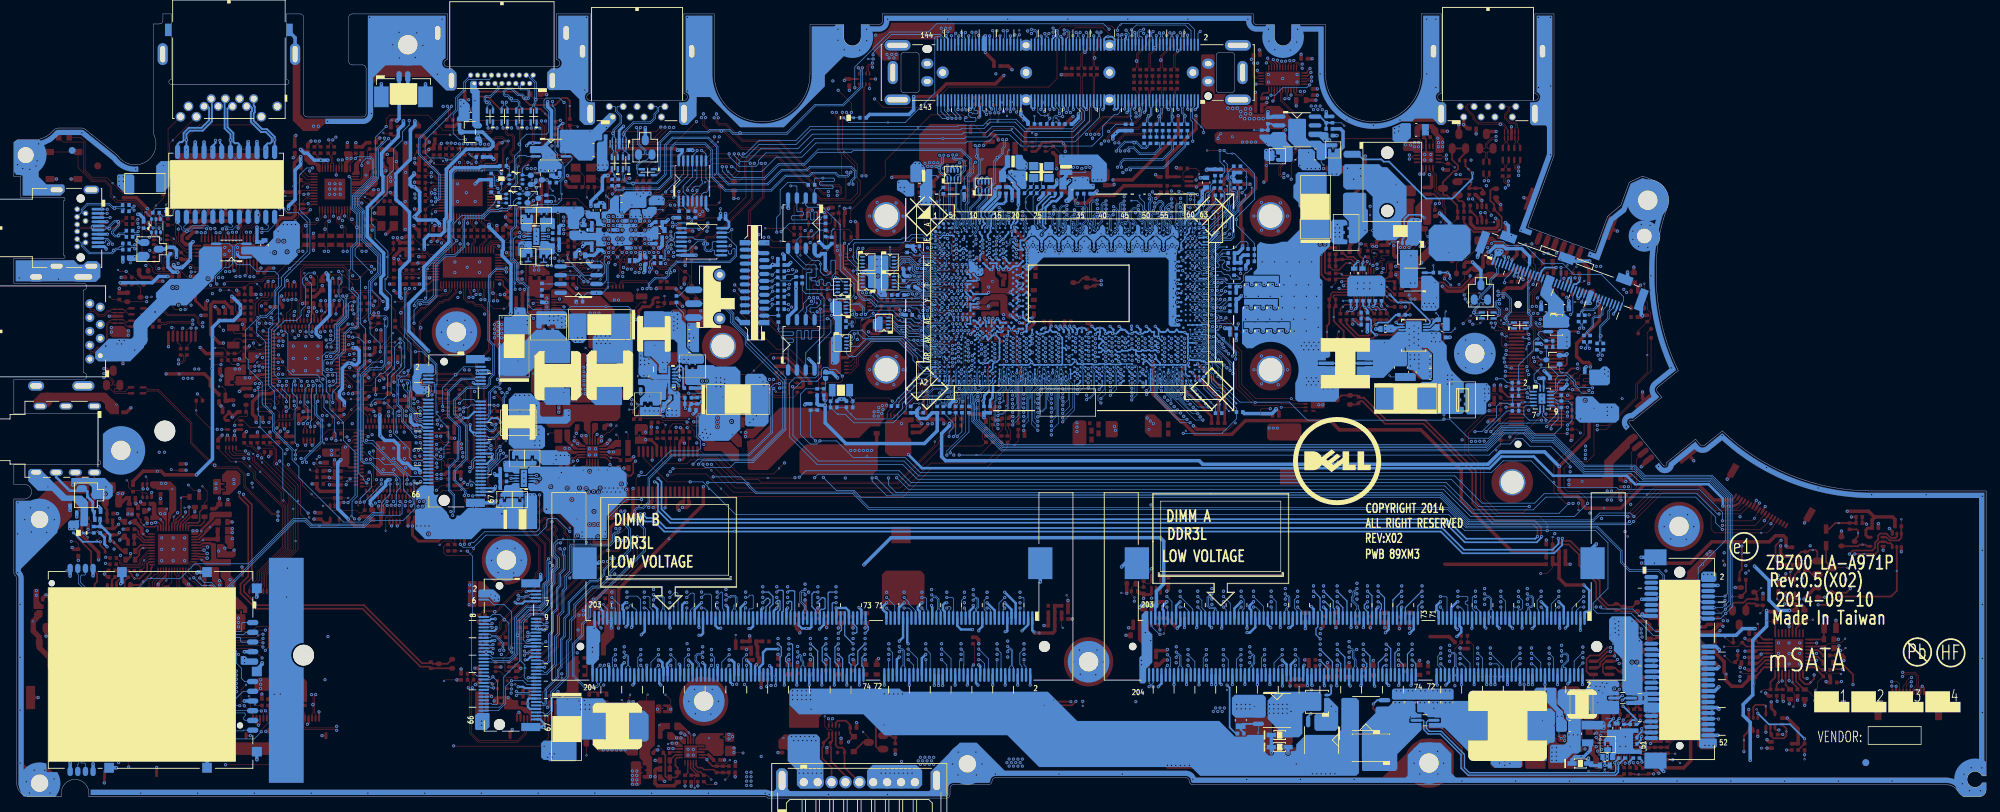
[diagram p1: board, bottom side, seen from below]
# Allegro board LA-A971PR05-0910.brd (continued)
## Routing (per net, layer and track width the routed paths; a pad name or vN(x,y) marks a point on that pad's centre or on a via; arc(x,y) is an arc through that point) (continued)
CPU_XDP_PRDY#: length 69.1
  TOP w0.102: JXDP1.5 63.78,67.32 64.66,68.2 64.66,68.46 65.81,69.62 68.75,69.62 69.78,70.65 70.82,70.65 v1(72.93,72.76) 74.86,72.76 v2(75.12,72.5)
  IN4 w0.084: v2(111.4,77.98) 111.31,77.89 110.62,77.89 107.89,80.62 101.04,80.62 95.37,86.28 85.49,86.28 83.62,84.4 83.62,83.67 82.56,82.61 76.73,82.61 74.78,80.66 74.78,72.84 v2(75.12,72.5)
  BOTTOM w0.076: UC1.J62 113.03,77.85 112.76,77.57 112.74,77.55 111.83,77.55 v2(111.4,77.98)
CPU_XDP_PREQ#: length 78.7
  TOP w0.102: JXDP1.3 63.7,67.82 v2(64.25,68.36)
  IN1 w0.084: v2(64.25,68.36) 64.43,68.36 65.1,69.03 66.8,69.03 68.23,70.45 68.23,70.78 68.69,71.24 69.34,71.24 69.98,70.59 70.88,70.59 72.4,72.12 72.4,74.48 79.07,81.15 79.07,84.1 80.75,85.78 83.26,85.78 84.96,87.48 93.25,87.48 94.28,88.51 101.97,88.51 102.73,89.27 104.57,89.27 106.61,87.23 v2(107.11,87.23)
  IN2 w0.122: v2(107.11,87.23) 108.45,85.9 108.45,78.33 v2(108.96,77.82)
  BOTTOM w0.076: UC1.K62 113.27,76.9 112.99,76.63 112.37,76.63 112.12,76.88 111.23,76.88 110.09,78.02 109.88,78.02
  BOTTOM w0.102: v2(107.11,87.23) 106.48,87.86 v1(106.48,89.45) 106.48,90.19 RC126.2 ; 109.88,78.02 109.16,78.02 v2(108.96,77.82)
CPU_XDP_TCLK: length 94.1
  TOP w0.102: RC128.2 RC119.1 59.78,54.23 60.66,54.23 60.75,54.32 JXDP1.57 ; RC128.2 58.93,53.14 v3(58.41,52.62) ; RC128.2 v2(60.25,53.14)
  IN1 w0.084: v2(60.25,53.14) 61.76,54.65 61.76,64 63.93,66.17 v2(64.51,66.17) 64.51,66.65 65.69,67.83 67.4,67.83 68.83,69.26 70.94,69.26 73.39,71.71 73.39,73.38 80.28,80.27 80.28,83.6 81.25,84.58 83.76,84.58 85.45,86.27 93.74,86.27 94.78,87.31 104.74,87.31 107.39,84.66 111.7,84.66 114.23,82.14 v2(114.23,80.62)
  BOTTOM w0.081: UC1.E60 114.57,80.28 v2(114.23,80.62)
  BOTTOM w0.102: v2(64.51,66.17) 64.82,66.17 65.18,65.81 65.18,64.52 67.3,62.39 RC112.1
CPU_XDP_TDI: length 87
  TOP w0.102: v3(109.53,82.33) 109.39,82.47 v2(109.39,83.06)
  IN1 w0.084: v2(64,54.46) 63.55,54.9 63.23,54.9 62.64,55.5 62.64,63.37 65.29,66.02 65.29,66.83 65.87,67.41 67.58,67.41 69,68.83 71.11,68.83 73.81,71.53 73.81,73.2 83.49,82.88 83.49,83.71 85.63,85.85 93.91,85.85 94.95,86.88 104.57,86.88 107.21,84.24 108.2,84.24 v2(109.39,83.06)
  BOTTOM w0.081: 109.88,82.02 110.09,81.81 110.09,81.28 112.02,79.34 UC1.F63
  BOTTOM w0.102: RC125.2 107.75,87.45 107.75,86.01 108.51,85.24 108.51,84.62 109.39,83.75 v2(109.39,83.06) 109.39,82.51 109.88,82.02 ; v2(64,54.46) 65.77,54.46 66.54,55.22 66.54,56.3 66.27,56.57 UC7.6
CPU_XDP_TDO: length 86.7
  TOP w0.076: v3(110.99,81) 109.93,81 109.88,81.05
  TOP w0.102: v2(109.58,81.35) 109.88,81.05
  IN4 w0.084: v2(109.58,81.35) 108.85,82.08 108.45,82.08 106.92,83.6 106.92,84.93 104.47,87.39 99.68,87.39 99.42,87.13 85.15,87.13 83.03,85.01 80.51,85.01 79.07,83.58 76.51,83.58 73.94,81.01 73.94,78.11 72.92,77.09 72.92,71.47 72.21,70.76 69.8,70.76 69.39,71.16 68.54,71.16 64.91,67.53 64.91,64.39 64.32,63.79 64.32,62.73 65.08,61.97 65.08,60.85 66.35,59.58 66.35,58.65 v2(66.09,58.39)
  BOTTOM w0.076: 113.02,79.34 112.73,79.06 112.03,79.06 111.93,79.15
  BOTTOM w0.081: 109.88,81.05 110.03,81.05 111.93,79.15 ; UC1.F62 113.02,79.34
  BOTTOM w0.102: UC7.3 65.7,58.07 66.03,58.39 v2(66.09,58.39) ; 109.88,81.05 v2(109.58,81.35) 108.98,81.95 108.98,83.83 108.26,84.55 108.26,85.18 107.52,85.91 107.52,87.74 RC127.2
CPU_XDP_TMS: length 90.3
  TOP w0.076: 109.88,84.14 109.92,84.09 v2(109.92,82.82)
  TOP w0.102: v3(109.53,84.49) 109.88,84.14
  IN1 w0.076: 109.88,83.14 109.88,82.87 v2(109.92,82.82)
  IN1 w0.084: 109.88,83.14 108.56,84.45 107.3,84.45 104.66,87.1 94.86,87.1 93.83,86.06 85.54,86.06 83.28,83.8 83.28,82.97 73.6,73.29 73.6,71.62 71.02,69.05 68.91,69.05 67.49,67.62 65.78,67.62 65.08,66.92 65.08,66.14 64.7,65.77 63.83,65.77 62.43,64.37 62.43,55.26 63.23,54.46 v2(63.36,54.46)
  BOTTOM w0.081: 111.78,81.52 112.04,81.25 112.22,81.25 112.34,81.13 112.75,81.13 112.76,81.13 112.93,81.13 113.01,81.05 113.39,81.05 113.72,80.72 113.72,80.33 UC1.E61
  BOTTOM w0.102: RC124.2 109,90.34 109,89.84 109.04,89.8 109.04,89.2 108.71,88.87 108.71,87.57 108.57,87.43 108.14,87.43 107.98,87.26 107.98,86.1 108.8,85.28 108.8,84.65 109.92,83.53 v2(109.92,82.82) 110.16,82.59 110.71,82.59 111.78,81.52 ; UC7.8 63.69,55.6 63.87,55.42 63.87,55.09 63.36,54.58 v2(63.36,54.46)
CPU_XDP_TRST#: length 89.4
  TOP w0.076: v3(115.32,81.06) 115.32,81.05 v2(114.88,80.62)
  IN1 w0.084: v2(60.25,53.76) 61.55,55.06 61.55,64.08 65.51,68.04 67.22,68.04 68.65,69.47 70.85,69.47 73.18,71.8 73.18,73.46 80.07,80.35 80.07,83.69 81.16,84.79 83.67,84.79 85.36,86.48 93.65,86.48 94.69,87.52 104.83,87.52 107.47,84.87 112.19,84.87 114.88,82.18 v2(114.88,80.62)
  BOTTOM w0.081: v2(114.88,80.62) 115.22,80.28 UC1.E59
  BOTTOM w0.102: UC7.11 62.09,57.57 61.73,57.21 RC109.1 ; RC109.1 60.14,57.21 59.61,56.68 59.61,54.39 v2(60.25,53.76) ; RC109.1 RC129.2
CPUSB#: length 8.7
  TOP w0.102: v2(150.31,76.68) 150.31,77.05 151.6,78.35 v1(153.49,78.35) 154.14,78.35 154.37,78.12 156.25,78.12 156.86,77.5 RPC4.6
  BOTTOM w0.081: UC1.K3 149.94,77.05 v2(150.31,76.68)
CS_1.35V: length 1.5
  TOP w0.203: PR201.2 189.38,6.64 PU200.13
CSN1: length 17.1
  TOP w0.203: PC502.1 94.35,72.06 94.35,72.62 94.07,72.89 PU500.18
  TOP w0.254: PC502.1 PC513.1 94.55,68.38 94.87,68.06 v1(94.87,67.18) 94.87,65.84 PR515.2 PR514.2 92.38,64.24 92.38,62.79 v2(92.51,62.66)
  BOTTOM w0.254: PL500.2 v2(92.51,62.66)
CSP1: length 11.3
  TOP w0.203: PU500.17 93.84,72.49 93.97,72.36 93.97,72.19 PC502.2
  TOP w0.254: PR512.1 PR514.1 92.48,65.29 PH501.1 92.48,67.31 93.9,68.73 v1(93.9,69.32) 93.9,70.64 PC513.2 PC502.2
CSS_GC: length 27.9
  TOP w0.102: v2(46.69,21.88) 46.69,21.66 v1(47.17,21.18)
  TOP w0.254: PR702.1 47.05,24.12 46.83,23.89 46.83,23.22 46.34,22.73 46.34,22.23 v2(46.69,21.88) ; PU800.10 26.36,17.46 26.15,17.25 v2(25.77,17.25)
  IN3 w0.254: v2(25.77,17.25) 26.95,18.43 33.74,18.43 34.7,19.38 39.97,19.38 41.29,20.7 44.68,20.7 45.86,21.88 v2(46.69,21.88)
CSSN_1: length 20
  TOP w0.102: PR703.1 54.88,14.85 v1(55.19,15.16)
  TOP w0.254: PQ703.2 53.4,18.77 52.86,18.23 PQ701.3 51.9,19.06 52.25,19.41 v2(52.82,19.41) ; PR705.2 53.95,14.85 PR703.1 53.95,15.29 v2(53.49,15.75) ; PR707.1 v2(49.64,23.79)
  IN1 w0.254: v2(52.82,19.41) 52.11,20.12 50.9,20.12 48.94,22.08 48.94,23.47 49.25,23.79 v2(49.64,23.79)
  IN4 w0.254: v2(53.49,15.75) 52.44,16.8 52.44,19.21 52.63,19.41 v2(52.82,19.41)
CSSP_1: length 19
  TOP w0.102: v1(54.13,23.48) 54.13,23.42 53.75,23.04 52.74,23.04 52.45,23.33 52.45,23.44 PR706.1
  TOP w0.254: PR706.1 51.9,23.55 PQ702.3 52.41,22.23 53.47,21.16 v2(53.47,20.48) 54.6,20.48 55.55,19.53 55.55,19.09 55.87,18.77 PQ703.5 ; v2(52.81,15.68) 53.03,15.46 PR703.2 53.06,14.82 PR704.2
  IN4 w0.254: v2(53.47,20.48) 52.57,20.48 52.06,19.98 52.06,16.43 v2(52.81,15.68)
D_CLKRUN#: length 126.6
  TOP w0.102: UE1.A19 222.96,51.65 v2(222.46,52.15) 222.46,51.63 222.1,51.27 RPE8.4 ; v2(142.71,98.73) 142.71,99.96 v1(142.99,100.24)
  IN2 w0.122: v2(222.46,52.15) 222.46,52.08 222.87,51.66 223.32,51.66 224.17,52.51 224.17,57.2 225.3,58.33 225.3,61.36 226.54,62.6 226.54,64.52 225.87,65.19 225.87,68.67 223.45,71.09 223.45,73.77 221.54,75.68 221.54,77.43 220.81,78.17 214.74,78.17 212.47,80.44 210.2,80.44 209.95,80.69 209.95,81.54 206.08,85.41 201.62,85.41 200.93,86.11 199.98,86.11 199.63,86.45 199.2,86.45 197.32,88.33 194.93,88.33 194.72,88.54 185.94,88.54 184.72,87.31 171.49,87.31 165.21,93.58 152.51,93.58 150.84,95.25 150.83,95.25 150.69,95.4 145.44,95.4 142.71,98.13 v2(142.71,98.73)
  BOTTOM w0.102: v2(142.71,98.73) 142.71,99.42 142.95,99.66 JDOCK1.111
D_DLDRQ1#: length 129.2
  TOP w0.102: v2(143.9,98.51) 143.9,98.61 v1(144.26,98.97) ; UE1.B24 224.92,49.9 225.14,50.12 v2(225.66,50.12) ; v2(222.44,50.29) 222.42,50.27 RPE8.2
  IN2 w0.122: v2(143.9,98.51) 143.9,97.64 145.64,95.9 150.89,95.9 151.04,95.75 152.71,94.08 165.42,94.08 171.69,87.81 184.51,87.81 185.74,89.04 194.93,89.04 195.14,88.83 197.53,88.83 199.41,86.95 199.93,86.95 200.27,86.6 201.13,86.6 201.38,86.36 207.17,86.36 209.22,84.3 209.22,83.11 210.12,82.21 211.57,82.21 213.44,80.35 214.76,80.35 216.4,78.7 220.98,78.7 222.04,77.64 222.04,75.88 223.95,73.98 223.95,71.29 225.9,69.34 226.38,69.34 227.1,68.62 227.1,62.45 225.82,61.18 225.82,58.14 224.66,56.98 224.66,51.12 v2(225.66,50.12)
  IN4 w0.084: v2(222.44,50.29) 222.88,49.85 223.73,49.85 224.02,49.57 225.11,49.57 v2(225.66,50.12)
  BOTTOM w0.102: JDOCK1.117 144.45,99.07 143.9,98.52 v2(143.9,98.51)
D_LAD0: length 135.5
  TOP w0.102: v2(139.58,98.85) 139.58,98.61 v1(138.61,97.64) ; UE1.B29 225.69,47.4 226.12,47.83 v2(226.12,48.24)
  IN2 w0.122: v2(139.58,98.85) 139.58,97.81 140.7,96.68 142.75,96.68 143.9,95.53 143.9,93.78 144.06,93.63 151.06,93.63 152.09,92.59 164.8,92.59 171.16,86.23 177.47,86.23 178.13,85.57 186.55,85.57 186.9,85.92 189.55,85.92 190.31,86.69 192.1,86.69 192.17,86.62 196.07,86.62 198.34,84.34 205.74,84.34 207.44,82.64 207.44,80.04 209.61,77.87 213.63,77.87 216.67,74.84 220.95,74.84 222.45,73.34 222.45,70.68 224.87,68.25 224.87,62.34 222.34,59.81 222.34,57.21 221.2,56.06 221.2,49.4 222.04,48.55 222.71,48.55 222.95,48.79 223.96,48.79 224.96,47.79 225.87,47.79 226.12,48.04 v2(226.12,48.24)
  BOTTOM w0.102: JDOCK1.97 139.45,98.99 v2(139.58,98.85)
D_LAD1: length 131.9
  TOP w0.102: v1(140.07,100.3) 139.97,100.2 v2(139.97,99.29) ; UE1.B28 225.21,47.9 v2(225.52,48.21)
  IN2 w0.122: v2(139.97,99.29) 140.01,99.26 140.01,98.15 141.05,97.1 142.68,97.1 145.2,94.59 150.44,94.59 150.53,94.51 152.2,92.84 164.91,92.84 171.26,86.48 177.57,86.48 178.23,85.82 186.44,85.82 186.79,86.17 189.45,86.17 190.21,86.94 190.49,86.94 191.34,87.79 194.41,87.79 194.62,87.58 195.45,87.58 198.44,84.59 205.84,84.59 207.69,82.74 207.69,80.14 209.71,78.12 213.74,78.12 216.77,75.09 221.07,75.09 222.7,73.46 222.7,70.78 225.12,68.36 225.12,62.24 222.59,59.71 222.59,55.42 221.45,54.27 221.45,49.5 222.14,48.8 222.61,48.8 222.85,49.04 224.7,49.04 v2(225.52,48.21)
  BOTTOM w0.102: JDOCK1.99 139.95,99.31 v2(139.97,99.29)
D_LAD2: length 129.5
  TOP w0.102: UE1.A25 223.41,48.65 223.16,48.9 222.82,48.9 v2(222.47,49.25) ; v2(140.95,99.29) v1(140.95,98.28)
  IN2 w0.122: v2(222.47,49.25) 222.04,49.25 221.69,49.6 221.69,54.17 222.84,55.31 222.84,59.6 225.37,62.14 225.37,68.46 222.95,70.88 222.95,73.57 221.04,75.47 221.04,77.23 220.6,77.67 214.54,77.67 213.15,79.06 211.56,79.06 210.87,78.37 209.81,78.37 207.94,80.24 207.94,82.84 205.95,84.84 198.55,84.84 195.55,87.83 194.72,87.83 194.51,88.04 188,88.04 187.62,87.66 187.62,87.36 186.34,86.07 181.18,86.07 180.44,86.81 171.28,86.81 165.01,93.09 152.3,93.09 150.63,94.76 150.54,94.84 145.29,94.84 142.49,97.64 141.46,97.64 140.95,98.15 v2(140.95,99.29)
  BOTTOM w0.102: JDOCK1.103 140.95,99.3 v2(140.95,99.29)
D_LAD3: length 128.8
  TOP w0.102: v1(141.66,100.24) 141.45,100.03 v2(141.45,98.91) ; v2(223.04,49.45) 223.35,49.15 UE1.A24
  IN2 w0.122: v2(223.04,49.45) 222.83,49.67 222.2,49.67 221.94,49.93 221.94,54.03 223.09,55.17 223.09,59.5 225.62,62.03 225.62,68.56 223.2,70.99 223.2,73.67 221.29,75.58 221.29,77.33 220.7,77.92 214.64,77.92 213.25,79.31 211.42,79.31 210.92,78.82 209.96,78.82 209.7,79.08 209.7,81.44 205.97,85.16 201.52,85.16 200.88,85.8 199.91,85.8 199.5,86.21 197.53,86.21 195.66,88.08 194.83,88.08 194.62,88.29 187.87,88.29 187.38,87.79 187.38,87.46 186.24,86.32 181.28,86.32 180.54,87.06 171.38,87.06 165.11,93.34 152.4,93.34 150.73,95.01 150.64,95.1 145.39,95.1 142.6,97.89 141.72,97.89 141.45,98.16 v2(141.45,98.91)
  BOTTOM w0.102: JDOCK1.105 v2(141.45,98.91)
D_LFRAME#: length 128.2
  TOP w0.102: UE1.B23 225.21,50.4 v2(226.01,51.2) ; v1(142.29,97.51) 142.12,97.68 v2(142.12,98.73)
  IN2 w0.122: v2(142.12,98.73) 142.12,98.8 142.61,99.29 142.61,99.55 142.75,99.69 143.31,99.69 144.32,98.68 144.32,97.58 145.75,96.15 151,96.15 151.14,96 152.82,94.33 165.52,94.33 171.8,88.06 184.41,88.06 185.63,89.29 192.35,89.29 192.78,89.72 196.99,89.72 199.51,87.2 200.03,87.2 200.38,86.85 201.4,86.85 201.6,86.65 207.22,86.65 209.47,84.41 209.47,83.22 210.22,82.46 211.67,82.46 213.54,80.6 214.86,80.6 216.5,78.96 221.08,78.96 222.29,77.74 222.29,75.99 224.19,74.08 224.19,71.4 226.01,69.59 226.48,69.59 227.35,68.72 227.35,62.35 226.09,61.09 226.09,58.05 224.91,56.88 224.91,51.97 225.22,51.66 225.79,51.66 226.01,51.45 v2(226.01,51.2)
  BOTTOM w0.102: JDOCK1.109 142.45,99.06 v2(142.12,98.73)
D_SERIRQ: length 125.9
  TOP w0.102: v2(143.36,98.73) 143.36,97.52 v1(143.75,97.13) ; UE1.A20 223.25,51.15 v2(223.07,50.97) 222.82,51.22 222.37,51.22 222.09,50.93 221.83,50.93 221.66,50.77 RPE8.3
  IN2 w0.122: v2(223.07,50.97) 224.41,52.32 224.41,57.09 225.56,58.24 225.56,61.27 226.85,62.56 226.85,68.52 226.28,69.09 225.8,69.09 223.7,71.19 223.7,73.88 221.79,75.78 221.79,77.54 220.91,78.42 216.33,78.42 214.66,80.1 213.33,80.1 211.47,81.97 209.88,81.97 206.17,85.67 201.71,85.67 201.03,86.36 200.17,86.36 199.82,86.7 199.3,86.7 197.43,88.58 195.03,88.58 194.82,88.79 185.84,88.79 184.61,87.56 171.59,87.56 165.32,93.83 152.61,93.83 150.94,95.5 150.79,95.65 145.54,95.65 143.36,97.83 v2(143.36,98.73)
  BOTTOM w0.102: JDOCK1.115 143.95,99.32 143.36,98.73 v2(143.36,98.73)
DAI_12MHZ#: length 216.5
  TOP w0.102: RA30.1 266.14,32.33 v2(266.14,32.16)
  IN1 w0.084: v2(266.14,32.16) 265.93,31.94 262.34,31.94 259.99,29.59 255.79,29.59 255.07,30.31 253.38,30.31 250.36,33.33 250.36,44.61 257.92,52.17 257.92,54.53 263.61,60.22 263.61,75 262.01,76.59 262.01,77.37 258.6,80.79 258.6,82.12 257.55,83.17 246.74,83.17 245.43,84.48 244.17,84.48 243.08,85.57 243.08,87.4 242.55,87.93 242.55,88.44 240.21,90.78 240.21,91.7 239.11,92.8 238.79,92.8 237.19,94.4 236.72,94.4 236.25,94.87 232.69,94.87 232.44,94.61 229.78,94.61 229.35,95.05 223.7,95.05 222.35,93.7 212.45,93.7 211.61,94.54 205.4,94.54 205.08,94.22 184.4,94.22 183.59,93.41 180.95,93.41 180.31,94.05 171.61,94.05 168.68,96.98 153.33,96.98 150.38,99.93 139.11,99.93 137.15,97.97 v2(134.8,97.97)
  BOTTOM w0.102: JDOCK1.89 136.45,99.67 136.51,99.61 136.51,98.84 136,98.34 v1(135.5,98.34) 135.16,98.34 v2(134.8,97.97) 134.8,97.75 135.2,97.34 R41.1
DAI_BCLK#: length 225
  TOP w0.102: v2(270.7,33.81) 270.6,33.71 RA31.1 ; v1(133.85,97.38) 133.02,98.21 v2(132.93,98.21)
  IN1 w0.084: v2(132.93,98.21) 133.62,98.21 133.87,98.46 135.87,98.46 136.58,99.17 136.58,101 137.29,101.71 144.11,101.71 145.42,100.41 150.56,100.41 153.52,97.44 168.87,97.44 171.8,94.51 180.5,94.51 181.14,93.87 183.39,93.87 184.2,94.68 204.82,94.68 205.14,95 216.72,95 217.25,95.53 231.42,95.53 231.62,95.33 236.44,95.33 236.91,94.86 237.38,94.86 238.98,93.26 239.3,93.26 243.01,89.55 243.01,88.12 243.55,87.59 243.55,86.32 243.84,86.03 245.25,86.03 247.65,83.63 257.74,83.63 259.11,82.27 259.11,80.94 264.07,75.97 264.07,60.03 258.38,54.34 258.38,51.93 252.65,46.2 252.65,44.65 250.83,42.82 250.83,35.39 256.16,30.06 259.7,30.06 262.05,32.41 265.28,32.41 265.56,32.69 268.12,32.69 269.51,34.07 270.44,34.07 v2(270.7,33.81)
  BOTTOM w0.102: JDOCK1.77 133.45,99.63 133.19,99.36 133.19,99.01 132.96,98.78 132.96,98.23 v2(132.93,98.21) 133.54,98.21 133.69,98.36 134.01,98.36 134.3,98.07 134.3,97.57 134.35,97.52 R6.1
DAI_DI: length 216
  TOP w0.102: v2(134.78,99.24) 134.78,98.72 v1(135.01,98.49) ; v2(264.72,38.52) 264.72,38.31 264.47,38.05 UA1.24
  IN1 w0.084: v2(134.78,99.24) 134.78,100.96 136.26,102.44 144.47,102.44 145.76,101.15 150.95,101.15 153.95,98.15 169.18,98.15 172.04,95.29 180.98,95.29 181.6,94.68 183.01,94.68 183.8,95.47 204.35,95.47 204.61,95.74 216.35,95.74 216.87,96.26 231.69,96.26 231.88,96.07 238.58,96.07 239.44,95.22 239.44,94.13 243.73,89.84 243.73,88.45 244.55,87.63 244.55,86.87 244.61,86.81 245.49,86.81 247.91,84.39 258.17,84.39 259.84,82.73 259.84,81.22 265.39,75.67 265.39,60.35 259.09,54.05 259.09,51.51 253.5,45.92 253.5,44.35 251.66,42.51 251.66,35.7 256.15,31.22 258.05,31.22 258.37,31.53 259.16,31.53 261.8,34.18 261.8,35.9 264.41,38.52 v2(264.72,38.52)
  BOTTOM w0.102: JDOCK1.83 134.95,99.41 v2(134.78,99.24)
DAI_DO#: length 219.3
  TOP w0.102: v2(270.69,34.71) 270.59,34.61 RA32.1 ; v2(135.56,98.93) 135.56,100.05 v1(135.75,100.24)
  IN1 w0.084: v2(135.56,98.93) 135.56,100.98 136.6,102.02 144.3,102.02 145.59,100.72 150.78,100.72 153.77,97.73 169.01,97.73 171.86,94.87 180.77,94.87 181.39,94.26 183.19,94.26 183.98,95.05 204.52,95.05 204.79,95.31 216.52,95.31 217.05,95.84 231.52,95.84 231.7,95.65 238.41,95.65 239.01,95.05 239.01,93.96 243.31,89.66 243.31,88.28 244.13,87.45 244.13,86.7 244.44,86.39 245.32,86.39 247.74,83.97 258,83.97 259.41,82.55 259.41,81.05 264.38,76.08 264.38,59.93 258.67,54.22 258.67,51.72 253,46.05 253,44.56 251.17,42.74 251.17,35.51 256.27,30.4 259.59,30.4 261.99,32.8 265.27,32.8 265.44,32.98 268,32.98 269.41,34.38 270.36,34.38 v2(270.69,34.71)
  BOTTOM w0.102: v2(135.56,98.93) 135.45,99.04 JDOCK1.85
DAI_LRCK#: length 227.1
  TOP w0.102: UA1.18 264.55,35.65 265.85,34.35 265.85,33.84 266.01,33.68 268.24,33.68 268.49,33.93 268.49,34.91 v2(268.55,34.98) ; v1(133.85,100.18) 133.4,99.73 v2(133.4,98.65)
  IN1 w0.084: v2(268.55,34.98) 268.49,34.91 268.49,33.9 268.14,33.54 265.57,33.54 265.09,33.06 261.54,33.06 259.77,31.28 258.43,31.28 258.12,30.96 256.08,30.96 251.42,35.62 251.42,42.67 253.25,44.5 253.25,45.99 258.88,51.62 258.88,54.14 265.18,60.43 265.18,75.58 259.62,81.13 259.62,82.64 258.08,84.18 247.83,84.18 245.41,86.6 244.52,86.6 244.34,86.78 244.34,87.54 243.52,88.36 243.52,89.75 239.23,94.05 239.23,95.13 238.49,95.86 231.79,95.86 231.6,96.05 216.96,96.05 216.44,95.52 204.7,95.52 204.43,95.26 183.89,95.26 183.1,94.47 181.51,94.47 180.9,95.08 171.95,95.08 169.09,97.94 153.86,97.94 150.86,100.94 145.67,100.94 144.39,102.23 136.47,102.23 135.17,100.94 135.17,99.03 134.93,98.78 133.78,98.78 133.65,98.65 v2(133.4,98.65)
  BOTTOM w0.102: v2(133.4,98.65) 133.53,98.78 133.53,99.21 133.95,99.63 JDOCK1.79
DAT_DDC2_DOCK: length 93.9
  TOP w0.102: v2(183.06,95.29) 183.06,94.97 184.23,93.8 186.49,93.8 v1(186.98,93.3) 187.52,92.76 195.37,92.76 196.3,91.83 196.3,90.37 196.89,89.78 196.89,87.31 197.96,86.24 UV8.M4
  IN1 w0.084: v2(183.06,95.29) 182.66,94.89 181.69,94.89 181.07,95.51 172.13,95.51 167.82,99.81 160.63,99.81 160.09,99.27 153.72,99.27 151.21,101.78 147.03,101.78 145.75,103.07 124.71,103.07 124.05,103.73 124.05,109.65 v2(124.41,110.01)
  BOTTOM w0.102: JDOCK1.46 124.45,109.6 124.59,109.74 124.59,109.83 v2(124.41,110.01)
DAT_KBD: length 167.1
  TOP w0.102: RPE2.7 v2(241.21,53.5) ; UE2.B41 240.91,59.36 v2(240.82,59.45)
  IN2 w0.122: v2(241.21,53.5) 241.07,53.5 240.97,53.41 240.97,53.06 241.29,52.74 243.46,52.74 244.85,54.13 245.42,54.13 247.13,55.84 247.13,67.31 246.18,68.26 246.18,71.1 246.63,71.54 246.63,73.12 241.63,78.12 240.65,78.12 238.69,80.08 227.7,80.08 224.08,83.69 222.99,83.69 221.61,85.07 217.3,85.07 216.38,85.98 216.38,86.31 214.41,88.28 213.13,88.28 210.18,91.23 205.42,91.23 204.27,92.37 189.55,92.37 188.96,91.79 180.13,91.79 179.04,90.71 172.97,90.71 166.84,96.84 153.85,96.84 151.18,99.51 150.72,99.51 149.59,100.65 147.28,100.65 141.02,106.91 137.56,106.91 136.59,107.88 136.59,110.1 136.09,110.6 134.55,110.6 v2(134.32,110.37)
  BOTTOM w0.102: v2(240.82,59.45) 240.82,59.27 241.06,59.03 241.06,54.47 241.21,54.31 v2(241.21,53.5) ; JDOCK1.80 133.95,109.37 133.85,109.47 133.85,110.03 133.72,110.15 133.72,110.45 133.8,110.53 134.14,110.53 134.32,110.35 v2(134.32,110.37)
DAT_MSE: length 163.6
  TOP w0.102: UE2.B42 241.41,59.4 v2(241.48,59.47) ; RPE2.5 242.21,53.19 242.08,53.32 242.08,53.78 v2(242.26,53.95)
  IN2 w0.122: v2(242.26,53.95) 242.26,53.65 242.41,53.5 243.15,53.5 244.61,54.96 245.18,54.96 245.67,55.45 245.67,56.91 246.38,57.61 246.38,66.94 245.41,67.91 245.41,71.41 245.87,71.87 245.87,72.76 245.63,73 243.76,73 243,73.76 241.55,73.76 237.88,77.43 235.94,77.43 234.1,79.28 227.35,79.28 223.69,82.94 222.58,82.94 221.21,84.32 216.31,84.32 214.86,85.78 213.89,85.78 210.15,89.51 206,89.51 203.89,91.62 192.06,91.62 191.48,91.04 184.56,91.04 183.47,89.95 172.65,89.95 166.52,96.08 153.54,96.08 150.87,98.76 150.41,98.76 149.43,99.74 147.05,99.74 143.55,103.24 134.61,103.24 132.32,100.94 132.32,98.88 v2(132.4,98.79)
  BOTTOM w0.102: v2(241.48,59.47) 242,58.95 242,56.78 241.57,56.35 241.57,54.64 v2(242.26,53.95) ; v2(132.4,98.79) 132.31,98.88 132.31,99.54 132.45,99.68 JDOCK1.73
DAT_TP_SIO: length 83.6
  TOP w0.102: JKBTP1.13 209.98,10.86 210.12,10.72 210.12,9.29 211.35,8.05 217.04,8.05 218.29,9.3 218.29,15.69 v2(218.49,15.9) 218.29,16.1 218.29,16.73 RZ18.2 CZ30.1 ; UE2.B40 240.41,59.62 240.83,60.05 v2(240.92,60.05)
  IN1 w0.084: v2(242.37,48.38) 242.19,48.2 242.19,45.63 237.74,41.19 234.16,41.19 226.73,33.76 220.76,33.76 219.3,32.29 219.3,19.76 218.28,18.74 218.28,16.11 v2(218.49,15.9)
  BOTTOM w0.102: v2(242.37,48.38) 242.13,48.62 242.13,48.99 239.71,51.4 239.71,54.4 240.58,55.26 240.58,58.09 240.34,58.33 240.34,59.56 240.82,60.05 v2(240.92,60.05)
DC_BLOCK_GC: length 113.6
  TOP w0.254: PU800.7 v2(24.44,19.85)
  IN3 w0.254: v2(24.44,19.85) 25.07,20.48 25.07,23.44 21.07,27.44 21.07,32.33 22.18,33.44 29.93,33.44 31.36,34.87 37.73,34.87 39.23,33.38 42.72,33.38 43.61,34.26 46.13,34.26 49.63,37.77 49.63,40.65 50.52,41.54 54.06,41.54 56.53,44.01 56.53,51.22 58.74,53.42 58.74,58.09 58.19,58.64 58.19,59.13 56.46,60.85 56.46,61.04 54.15,63.35 54.15,68.23 56.57,70.65 59.8,70.65 61.71,72.55 66.65,72.55 68.85,74.76 77.02,74.76 v2(77.17,74.9)
  BOTTOM w0.254: PR700.2 v1(77.52,75.73) 77.17,75.38 v2(77.17,74.9)
DC_IN_SS: length 3.6
  TOP w0.102: v1(24.96,25.72) 25.02,25.65 PR831.2
  TOP w0.254: PR831.2 27.36,24.44 PU800.34
DC_TEST_A3_B3: length 0.7
  BOTTOM w0.081: UC1.B3 149.99,82.66 UC1.A3
DC_TEST_A4: length 4.6
  BOTTOM w0.081: UC1.A4 150.1,83.53 150.1,85.54
  BOTTOM w0.102: 150.1,85.54 RC192.1
DC_TEST_A60: length 5.8
  BOTTOM w0.102: UC1.A60 114.14,83.16 113.72,83.16 110.95,85.93 RC193.1
DC_TEST_A61_B61: length 0.7
  BOTTOM w0.081: UC1.B61 113.86,82.19 UC1.A61
DC_TEST_A62: length 5.4
  BOTTOM w0.102: UC1.A62 113.21,83.35 110.04,86.52 RC193.2
DC_TEST_AV1: length 8.8
  BOTTOM w0.102: RC194.1 157.59,56.49 156.83,57.25 156.83,57.38 v1(156.53,57.68) 154.48,59.73 154.48,60.3 153.66,61.12 151.71,61.12 151.38,61.46 UC1.AV1
DC_TEST_AW1: length 7.4
  BOTTOM w0.102: RC194.2 156.52,56.67 156.52,57.04 v1(154.94,58.61) 153.76,59.79 152.58,59.79 151.63,60.74 UC1.AW1
DC_TEST_AW63: length 6.6
  BOTTOM w0.102: RC195.1 110.3,55.75 v1(110.3,56.73) 110.3,57.13 110.7,57.53 111.1,57.53 112.62,59.04 UC1.AW63
DC_TEST_AY2_AW2: length 0.7
  BOTTOM w0.081: UC1.AW2 150.58,60.27 UC1.AY2
DC_TEST_AY3_AW3: length 0.7
  BOTTOM w0.081: UC1.AW3 149.98,60.76 UC1.AY3
DC_TEST_AY60: length 6.2
  BOTTOM w0.102: RC195.2 110.93,56.36 v1(111.6,57.03) 114.5,59.92 UC1.AY60
DC_TEST_AY61_AW61: length 0.7
  BOTTOM w0.081: UC1.AW61 113.84,60.72 UC1.AY61
DC_TEST_AY62_AW62: length 0.7
  BOTTOM w0.081: UC1.AY62 113.18,60.72 UC1.AW62
DC_TEST_B62_B63: length 0.7
  BOTTOM w0.081: UC1.B63 112.75,82.05 UC1.B62
DC_TEST_C1_C2: length 0.7
  BOTTOM w0.081: UC1.C1 151.12,81.52 UC1.C2
DDI1_LANE_N0: length 131.2
  TOP w0.102: CV72.1 221.13,93.93 221.13,94.2 v2(220.95,94.39)
  IN4 w0.091: v2(220.95,94.39) 221.15,94.19 221.15,93.37 220.87,93.1 214.84,93.1 213.99,92.24 194.41,92.24 193.72,91.55 184.3,91.55 184.16,91.68 180.16,91.68 179.25,90.77 175.44,90.77 175.28,90.93 175.28,91.7 175.08,91.89 174.63,91.89 174.43,91.7 174.43,90.86 174.34,90.77 174.03,90.77 173.94,90.86 173.94,91.89 173.74,92.08 171.36,92.08 167,96.44 156.35,96.44 156.24,96.55 154.39,96.55 152.33,98.61 150.73,98.61 148.91,100.44 147.82,100.44 146.49,101.77 128.91,101.77 125.98,98.84 124.58,98.84 122.86,97.12 122.58,97.12 118.75,93.29 118.75,84.75 118.03,84.03 117.48,84.03 117.24,84.27 v2(117.24,84.47)
  BOTTOM w0.076: UC1.C54 118.14,81.6 117.97,81.77 117.8,81.77 117.59,81.98 117.56,82.08 117.56,82.21 117.58,82.27 117.58,82.27 117.6,82.28 117.62,82.37 117.62,82.59 117.5,82.84 117.5,83.04 117.85,83.4 117.85,84.16 117.62,84.39 117.32,84.39 v2(117.24,84.47)
DDI1_LANE_N0_C: length 2.5
  TOP w0.102: UV7.4 220.16,91.4 221.06,92.3 221.06,92.42 CV72.2
DDI1_LANE_N1: length 131.1
  TOP w0.102: v2(219.2,94.28) 219.38,94.09 219.38,93.96 CV74.1
  IN4 w0.091: v2(219.2,94.28) 219.44,94.52 219.44,95.14 219.07,95.51 206.59,95.51 205.09,94.01 171.92,94.01 167.73,98.2 157.07,98.2 156.96,98.31 155.12,98.31 153.06,100.37 151.46,100.37 149.64,102.2 148.57,102.2 145.17,105.6 129.87,105.6 127.18,102.91 124.7,102.91 115.12,93.32 115.12,84.6 115.3,84.42 115.38,84.42 115.48,84.51 115.64,84.51 115.75,84.62 115.75,84.81 115.65,84.91 v2(115.5,84.91)
  BOTTOM w0.076: v2(115.5,84.91) 115.78,84.63 115.93,84.63 116.19,84.37 116.19,83.22 116.02,83.05 116.02,82.23 116.19,82.06 116.19,81.63 116.13,81.57 116.01,81.57 115.91,81.67 UC1.B58
DDI1_LANE_N1_C: length 2.3
  TOP w0.102: UV7.7 218.96,91.38 219.06,91.48 219.06,91.87 219.39,92.2 219.39,92.31 CV74.2
DDI1_LANE_N2: length 131.1
  TOP w0.102: CV76.1 217.51,93.92 217.51,94.14 v2(217.39,94.26)
  IN4 w0.091: v2(117.21,85.75) 117.21,85.69 117.53,85.36 117.88,85.36 118.11,85.59 118.11,88.44 117.98,88.57 116.83,88.57 116.6,88.8 116.6,89.28 116.83,89.51 117.58,89.51 117.67,89.6 117.67,93.12 122.31,97.76 122.55,97.76 123,98.21 123,99.12 125.65,101.77 128,101.77 128.64,102.42 146.77,102.42 148.11,101.08 149.17,101.08 151,99.26 152.6,99.26 154.66,97.19 156.5,97.19 156.61,97.08 167.26,97.08 171.63,92.72 178.28,92.72 178.51,92.5 178.51,91.54 178.64,91.41 178.98,91.41 179.11,91.54 179.11,92.13 179.3,92.33 184.43,92.33 184.5,92.26 193.51,92.26 194.14,92.89 212.08,92.89 212.21,93.02 212.21,94.16 212.43,94.39 212.92,94.39 213.15,94.16 213.15,93.02 213.28,92.89 213.62,92.89 213.75,93.02 213.75,93.91 214.04,94.2 214.89,94.2 215.35,93.74 217.44,93.74 217.61,93.91 217.61,94.04 v2(217.39,94.26)
  BOTTOM w0.081: UC1.B55 117.94,82.21 117.98,82.21 118.33,82.57 118.33,83.01 118.26,83.08 118.26,83.97 118.28,83.98 118.28,83.99
  BOTTOM w0.102: 118.28,83.99 118.28,85.08 117.68,85.67 117.28,85.67 v2(117.21,85.75)
DDI1_LANE_N2_C: length 2.4
  TOP w0.102: UV7.10 217.76,91.23 217.93,91.39 217.93,91.63 217.44,92.11 217.44,92.41 CV76.2
DDI1_LANE_N3: length 131.1
  TOP w0.102: v2(215.55,94.21) 215.67,94.1 215.67,93.93 CV78.1
  IN4 w0.091: v2(116,85.13) 116,85.31 116.35,85.66 116.5,85.66 116.77,85.92 116.77,87.78 116.55,88 116.26,88 116.13,88.13 116.13,89.91 116.26,90.03 116.97,90.03 117.2,90.26 117.2,91.31 117.01,91.5 116.51,91.5 116.38,91.63 116.38,91.97 116.51,92.1 117.01,92.1 117.2,92.29 117.2,93.59 121.97,98.36 121.97,99.19 125.03,102.24 127.8,102.24 128.44,102.89 146.97,102.89 148.3,101.55 149.37,101.55 151.2,99.73 152.79,99.73 154.86,97.66 156.7,97.66 156.8,97.56 167.46,97.56 171.65,93.36 184.06,93.36 184.68,92.75 193.33,92.75 193.95,93.36 206.96,93.36 207.15,93.55 207.15,94.74 207.28,94.86 207.63,94.86 207.75,94.74 207.75,93.55 207.95,93.36 208.51,93.36 208.7,93.55 208.7,94.65 208.83,94.78 209.17,94.78 209.3,94.65 209.3,93.59 209.53,93.36 210.46,93.36 210.68,93.59 210.68,94.74 210.81,94.86 215.68,94.86 215.91,94.63 215.91,94.57 v2(215.55,94.21)
  BOTTOM w0.076: 116.49,84.44 116.49,83.27 116.19,82.97 116.19,82.55 116.26,82.48 116.38,82.48 116.47,82.57 UC1.A57
  BOTTOM w0.102: 116.49,84.44 116.48,84.45 116.48,85.36 116.36,85.48 116.17,85.48 115.95,85.27 115.95,85.18 v2(116,85.13)
DDI1_LANE_N3_C: length 2.6
  TOP w0.102: CV78.2 216.14,91.87 216.36,91.87 216.56,91.67 UV7.13
DDI1_LANE_P0: length 131.3
  TOP w0.102: CV71.1 221.35,93.93 221.35,94.2 v2(221.53,94.39)
  IN4 w0.091: v2(117.24,83.72) 117.38,83.86 118.11,83.86 118.92,84.67 118.92,93.22 122.65,96.94 122.93,96.94 124.65,98.67 126.05,98.67 128.98,101.6 146.42,101.6 147.75,100.26 148.84,100.26 150.66,98.44 152.26,98.44 154.32,96.37 156.17,96.37 156.28,96.27 166.92,96.27 171.29,91.91 173.67,91.91 173.76,91.81 173.76,90.79 173.96,90.59 174.41,90.59 174.61,90.79 174.61,91.62 174.7,91.72 175.01,91.72 175.1,91.62 175.1,90.86 175.37,90.59 179.32,90.59 180.24,91.51 184.09,91.51 184.22,91.37 193.79,91.37 194.48,92.07 214.06,92.07 214.92,92.92 220.94,92.92 221.32,93.3 221.32,94.18 v2(221.53,94.39)
  BOTTOM w0.076: v2(117.24,83.72) 117.09,83.87 117.09,83.99 117.2,84.1 117.4,84.1 117.49,84.19 117.54,84.19 117.65,84.08 117.65,83.48 117.31,83.13 117.31,82.76 117.39,82.68 117.46,82.5 117.46,82.4 117.41,82.28 117.41,82.27 117.39,82.24 117.39,82.06 117.44,81.9 117.59,81.67 117.59,81.57 117.53,81.52 117.53,81.45 117.63,81.36 117.73,81.36 UC1.C55
DDI1_LANE_P0_C: length 2.4
  TOP w0.102: CV71.2 221.32,92.31 221.32,92.25 220.56,91.5 UV7.3
DDI1_LANE_P1: length 131.2
  TOP w0.102: CV73.1 219.6,93.9 219.6,94.09 v2(219.78,94.28)
  IN4 w0.091: v2(219.78,94.28) 219.62,94.44 219.62,95.21 219.14,95.68 206.52,95.68 205.01,94.18 171.99,94.18 167.8,98.37 157.14,98.37 157.03,98.48 155.2,98.48 153.13,100.55 151.54,100.55 149.71,102.37 148.64,102.37 145.24,105.77 129.8,105.77 127.11,103.08 124.63,103.08 114.95,93.4 114.95,84.53 115.23,84.25 115.43,84.25 v2(115.57,84.11)
  BOTTOM w0.076: UC1.C58 115.91,81.37 115.57,81.71 115.57,81.96 115.71,82.1 115.72,82.1 115.83,82.21 115.83,83.13 116,83.3 116,84.29 115.85,84.44 115.64,84.44 115.57,84.37 v2(115.57,84.11)
DDI1_LANE_P1_C: length 2.3
  TOP w0.102: UV7.6 219.36,91.38 219.27,91.48 219.27,91.78 219.6,92.11 219.6,92.38 CV73.2
DDI1_LANE_P2: length 131.1
  TOP w0.102: CV75.1 217.72,93.94 217.72,94.01 v2(217.97,94.26)
  IN4 w0.091: v2(117.21,85.16) 117.24,85.19 117.95,85.19 118.28,85.52 118.28,88.51 118.05,88.74 116.9,88.74 116.77,88.87 116.77,89.21 116.9,89.34 117.65,89.34 117.85,89.53 117.85,93.05 122.38,97.59 122.62,97.59 123.17,98.14 123.17,99.05 125.72,101.6 128.07,101.6 128.71,102.24 146.7,102.24 148.03,100.91 149.1,100.91 150.93,99.08 152.52,99.08 154.59,97.02 156.43,97.02 156.54,96.91 167.19,96.91 171.55,92.55 178.21,92.55 178.34,92.42 178.34,91.47 178.57,91.24 179.05,91.24 179.28,91.47 179.28,92.06 179.37,92.15 184.36,92.15 184.43,92.08 193.58,92.08 194.22,92.72 212.15,92.72 212.38,92.95 212.38,94.09 212.51,94.22 212.85,94.22 212.98,94.09 212.98,92.95 213.21,92.72 213.7,92.72 213.92,92.95 213.92,93.84 214.11,94.03 214.82,94.03 215.28,93.57 217.51,93.57 217.78,93.84 217.78,94.07 v2(217.97,94.26)
  BOTTOM w0.081: UC1.A55 117.79,82.72 117.79,82.47 117.85,82.41 117.9,82.41 118.13,82.65 118.13,82.93 118.07,83 118.07,83.97 118.06,83.98 118.06,83.99
  BOTTOM w0.102: 118.06,83.99 118.06,84.99 117.59,85.46 117.48,85.46 117.37,85.35 117.3,85.35 117.21,85.25 v2(117.21,85.16)
DDI1_LANE_P2_C: length 2.3
  TOP w0.102: UV7.9 218.16,91.27 218.14,91.29 218.14,91.72 217.66,92.2 217.66,92.27 CV75.2
DDI1_LANE_P3: length 131
  TOP w0.102: v2(216.14,94.21) 215.92,94 215.92,93.9 CV77.1
  IN4 w0.091: v2(216.14,94.21) 216.08,94.27 216.08,94.71 215.75,95.04 210.74,95.04 210.51,94.81 210.51,93.66 210.38,93.53 209.6,93.53 209.47,93.66 209.47,94.72 209.24,94.95 208.75,94.95 208.53,94.72 208.53,93.63 208.43,93.53 208.02,93.53 207.93,93.63 207.93,94.81 207.7,95.04 207.21,95.04 206.98,94.81 206.98,93.63 206.89,93.53 193.88,93.53 193.26,92.92 184.75,92.92 184.13,93.53 171.73,93.53 167.53,97.73 156.88,97.73 156.77,97.84 154.93,97.84 152.86,99.9 151.27,99.9 149.44,101.73 148.37,101.73 147.04,103.06 128.37,103.06 127.73,102.42 124.95,102.42 121.8,99.26 121.8,98.43 117.03,93.66 117.03,92.36 116.94,92.27 116.44,92.27 116.21,92.05 116.21,91.56 116.44,91.33 116.94,91.33 117.03,91.24 117.03,90.33 116.9,90.21 116.18,90.21 115.96,89.98 115.96,88.06 116.18,87.83 116.47,87.83 116.59,87.71 116.59,85.99 116.43,85.83 v2(115.95,85.83)
  BOTTOM w0.076: 116.7,84.61 116.7,84.6 116.7,83.21
  BOTTOM w0.081: 116.7,83.21 116.7,83.2 116.7,83.03 116.75,82.97 116.75,82.58 116.47,82.29 UC1.B57 ; 116.7,84.61 116.7,84.62
  BOTTOM w0.102: 116.7,84.62 116.7,85.45 116.45,85.7 116.08,85.7 v2(115.95,85.83)
DDI1_LANE_P3_C: length 2.6
  TOP w0.102: CV77.2 216.05,92.5 216.05,92.27 216.23,92.09 216.45,92.09 216.78,91.76 216.78,91.57 216.96,91.38 UV7.12
DDI2_LANE_N0: length 173.6
  IN4 w0.091: v2(266.6,85.3) 266.4,85.11 266.1,85.11 264.93,83.94 246.15,83.94 245.59,84.51 243.55,84.51 241.81,86.25 235.27,86.25 234.55,86.97 230.86,86.97 228.51,89.32 225.56,89.32 225.12,88.89 222.22,88.89 221.38,89.72 218.18,89.72 217.68,90.22 215.49,90.22 214.9,89.63 206.23,89.63 204.64,88.04 199.44,88.04 197.36,90.12 172.4,90.12 166.73,95.79 156.08,95.79 155.98,95.9 154.13,95.9 152.08,97.95 150.48,97.95 149.7,98.73 145.33,98.73 144.19,99.87 139.7,99.87 139.49,99.65 137.67,99.65 136.87,100.46 129.86,100.46 128.2,98.8 126.94,98.8 126.34,98.19 124.85,98.19 123.13,96.47 122.97,96.47 120.5,94 120.5,87.82 120.91,87.41 120.91,86.88 120.75,86.72 120.68,86.72 v2(120.45,86.95)
  BOTTOM w0.081: UC1.C51 120.04,81.75 119.95,81.9 119.9,82.06 119.9,82.24 119.91,82.28 119.92,82.28 119.96,82.4 119.96,82.54 119.87,82.73 119.87,83 120.36,83.48 120.36,84.46 120.35,84.47 120.35,84.54 120.34,84.55 120.34,84.56
  BOTTOM w0.102: 120.34,84.56 120.33,84.56 120.33,85.69 120.04,85.99 120.04,86.54 v2(120.45,86.95) ; v2(266.6,85.3) 266.78,85.12 266.99,85.12 CV508.2
DDI2_LANE_N1: length 173.7
  TOP w0.102: CV506.2 266.48,83.03 266.27,83.03 v2(266.06,82.82)
  IN4 w0.091: v2(119.7,85.18) 119.92,85.4 120.59,85.4 121.84,86.65 121.84,87.73 121.32,88.26 121.32,93.66 123.32,95.66 123.47,95.66 125.19,97.38 126.68,97.38 127.28,97.98 128.54,97.98 128.84,98.28 129.97,98.28 130.23,98.54 130.23,99.29 130.58,99.64 136.22,99.64 136.51,99.35 136.51,98.97 136.82,98.67 138.4,98.67 138.79,98.28 141.27,98.28 141.6,97.95 143.72,97.95 144.16,97.51 146.29,97.51 146.67,97.13 151.74,97.13 153.79,95.08 155.64,95.08 155.75,94.98 166.39,94.98 172.06,89.3 194.12,89.3 194.7,88.73 197.56,88.73 199.07,87.23 204.98,87.23 206.13,88.38 214.87,88.38 215.89,89.39 217.35,89.39 217.84,88.9 220.65,88.9 221.48,88.07 225.48,88.07 226.05,87.49 228.44,87.49 229.78,86.16 234.11,86.16 235.65,84.62 239.13,84.62 240.08,83.67 245.17,83.67 245.79,83.05 265.82,83.05 v2(266.06,82.82)
  BOTTOM w0.081: 118.71,83.92 118.71,83.91 118.7,83.9 118.7,81.96 118.71,81.95 118.71,81.75 UC1.C53
  BOTTOM w0.102: v2(119.7,85.18) 118.97,85.9 118.79,85.9 118.59,85.69 118.59,85.51 118.92,85.18 118.92,84.75 118.71,84.53 118.71,83.92
DDI2_LANE_N2: length 172.3
  IN4 w0.091: v2(266.5,79.75) 266.33,79.58 257.56,79.58 256.85,80.29 246.68,80.29 245.37,81.6 242.37,81.6 242.02,81.96 233.03,81.96 231.42,80.34 226.52,80.34 220.1,86.76 215.83,86.76 214.97,85.9 212.34,85.9 211.5,86.74 206.13,86.74 205.5,86.11 200.43,86.11 199.71,85.39 198.98,85.39 197.7,86.66 197.58,86.66 196.64,87.61 193.98,87.61 193.4,88.19 171.6,88.19 165.93,93.86 155.29,93.86 155.18,93.97 153.32,93.97 151.35,95.94 146.24,95.94 146.05,96.14 143.96,96.14 143.26,96.83 140.93,96.83 140.61,97.16 138.33,97.16 137.94,97.55 134.18,97.55 133.8,97.16 129.35,97.16 129.05,96.86 127.88,96.86 126.68,95.66 125.05,95.66 123.94,94.54 123.78,94.54 122.43,93.19 122.43,88.8 123.05,88.18 123.05,84.05 122.93,83.93 121.84,83.93 121.75,84.02 v2(121.75,84.27)
  BOTTOM w0.081: UC1.C49 121.49,81.65 121.2,81.93 121.2,82.89 121.4,83.1 121.78,83.1 122.1,83.41 122.1,83.93 v2(121.75,84.27)
  BOTTOM w0.102: v2(266.5,79.75) 266.66,79.58 266.97,79.58 CV504.2
DDI2_LANE_N3: length 172
  IN4 w0.091: v2(119.06,83.67) 119.24,83.86 119.96,83.86 122.49,86.39 122.49,88.03 121.96,88.56 121.96,93.39 123.58,95.01 123.74,95.01 125.46,96.73 126.94,96.73 127.55,97.33 128.85,97.33 129.15,97.63 133.6,97.63 134.34,98.37 135.33,98.37 135.68,98.02 138.14,98.02 138.52,97.63 140.8,97.63 141.13,97.31 143.45,97.31 143.93,96.83 146.02,96.83 146.44,96.42 151.54,96.42 153.52,94.44 155.38,94.44 155.48,94.33 166.12,94.33 171.8,88.66 193.62,88.66 194.2,88.08 197.3,88.08 198.8,86.58 205.25,86.58 205.88,87.21 215.32,87.21 215.77,87.67 220.49,87.67 222.83,85.34 228.25,85.34 228.42,85.51 231.96,85.51 234.82,82.65 242,82.65 242.57,82.08 245.56,82.08 246.88,80.76 260.84,80.76 261.03,80.96 261.03,81.2 261.17,81.33 261.35,81.33 261.49,81.2 261.49,80.96 261.68,80.76 262.04,80.76 262.56,81.28 265.81,81.28 v2(266.02,81.07)
  BOTTOM w0.081: v2(119.06,83.67) 118.93,83.8 118.93,83.93 119.05,84.05 119.49,84.05 119.54,84.1 119.87,84.1 119.99,83.97 119.99,83.64 119.83,83.48 119.49,83.48 119.3,83.29 119.3,82.78 119.14,82.62 119.03,82.62 118.98,82.67 UC1.A53
  BOTTOM w0.102: 266.8,80.87 266.44,81.24 266.18,81.24 v2(266.02,81.07)
DDI2_LANE_P0: length 173.5
  IN4 w0.091: v2(120.45,86.36) 120.63,86.54 120.82,86.54 121.08,86.81 121.08,87.48 120.67,87.89 120.67,93.93 123.05,96.3 123.2,96.3 124.92,98.02 126.41,98.02 127.01,98.63 128.27,98.63 129.93,100.29 136.79,100.29 137.6,99.48 139.56,99.48 139.78,99.69 144.12,99.69 145.26,98.56 149.63,98.56 150.41,97.77 152.01,97.77 154.05,95.73 155.9,95.73 156.01,95.62 166.66,95.62 172.33,89.95 197.29,89.95 199.36,87.87 204.71,87.87 206.3,89.46 214.97,89.46 215.56,90.05 217.61,90.05 218.11,89.55 221.31,89.55 222.14,88.71 225.19,88.71 225.63,89.15 228.44,89.15 230.79,86.8 234.48,86.8 235.2,86.08 241.74,86.08 243.48,84.34 245.51,84.34 246.08,83.77 265,83.77 266.17,84.94 266.38,84.94 v2(266.6,84.72)
  BOTTOM w0.081: 120.55,84.56 120.55,83.4 120.07,82.92 120.07,82.71 120.13,82.59 120.13,82.37 120.1,82.28 120.1,82.28 120.09,82.27 120.07,82.21 120.07,82.08 120.1,81.98 120.3,81.77 120.48,81.77 120.81,81.44 120.85,81.44 120.92,81.37 UC1.C50
  BOTTOM w0.102: 120.55,84.56 120.55,84.56 120.55,85.78 120.26,86.08 120.26,86.27 120.35,86.36 v2(120.45,86.36) ; CV507.2 266.99,84.9 266.78,84.9 v2(266.6,84.72)
DDI2_LANE_P1: length 173.6
  TOP w0.102: v2(266.06,83.4) 266.21,83.25 266.45,83.25 CV505.2
  IN4 w0.091: v2(266.06,83.4) 265.88,83.22 245.86,83.22 245.24,83.84 240.15,83.84 239.2,84.79 235.72,84.79 234.18,86.33 229.85,86.33 228.51,87.67 226.12,87.67 225.55,88.24 221.56,88.24 220.72,89.07 217.91,89.07 217.42,89.57 215.82,89.57 214.8,88.55 206.06,88.55 204.91,87.4 199.14,87.4 197.64,88.9 194.77,88.9 194.19,89.48 172.13,89.48 166.46,95.15 155.82,95.15 155.71,95.26 153.86,95.26 151.81,97.3 146.74,97.3 146.36,97.68 144.23,97.68 143.79,98.12 141.67,98.12 141.34,98.45 138.86,98.45 138.48,98.84 136.89,98.84 136.68,99.05 136.68,99.42 136.29,99.81 130.51,99.81 130.05,99.36 130.05,98.61 129.89,98.45 128.77,98.45 128.47,98.15 127.21,98.15 126.61,97.55 125.12,97.55 123.4,95.83 123.24,95.83 121.14,93.73 121.14,88.19 121.67,87.66 121.67,86.73 120.52,85.57 119.89,85.57 v2(119.7,85.76)
  BOTTOM w0.081: 118.49,83.92 118.49,83.91 118.5,83.9 118.5,82.29 118.22,82.01 118.22,81.87 118.29,81.8 UC1.B54
  BOTTOM w0.102: v2(119.7,85.76) 119.42,85.76 119.06,86.12 118.7,86.12 118.37,85.78 118.37,85.42 118.71,85.09 118.71,84.84 118.49,84.62 118.49,83.92
DDI2_LANE_P2: length 172.3
  IN4 w0.091: v2(121.5,83.75) 123,83.75 123.23,83.98 123.23,88.25 122.61,88.87 122.61,93.12 123.85,94.37 124.01,94.37 125.12,95.48 126.75,95.48 127.96,96.69 129.12,96.69 129.42,96.99 133.87,96.99 134.25,97.38 137.87,97.38 138.26,96.99 140.53,96.99 140.86,96.66 143.19,96.66 143.88,95.96 145.98,95.96 146.17,95.77 151.27,95.77 153.25,93.79 155.11,93.79 155.22,93.69 165.85,93.69 171.53,88.01 193.33,88.01 193.91,87.43 196.57,87.43 197.51,86.49 197.63,86.49 198.91,85.21 199.78,85.21 200.5,85.94 205.57,85.94 206.2,86.57 211.43,86.57 212.27,85.72 215.04,85.72 215.9,86.59 220.03,86.59 226.44,80.17 231.49,80.17 233.1,81.78 241.95,81.78 242.3,81.43 245.3,81.43 246.61,80.12 256.77,80.12 257.49,79.4 266.26,79.4 v2(266.5,79.16)
  BOTTOM w0.081: UC1.B50 120.88,81.76 120.73,81.76 120.63,81.86 120.63,82.06 120.7,82.13 120.93,82.13 121.01,82.21 121.01,82.98 121.32,83.29 121.7,83.29 121.9,83.49 121.9,83.81 121.83,83.88 121.62,83.88 v2(121.5,83.75)
  BOTTOM w0.102: CV503.2 266.97,79.37 266.7,79.37 v2(266.5,79.16)
DDI2_LANE_P3: length 172
  IN4 w0.091: v2(266.02,81.66) 265.81,81.45 262.49,81.45 261.97,80.94 261.75,80.94 261.66,81.03 261.66,81.27 261.43,81.5 261.09,81.5 260.86,81.27 260.86,81.03 260.77,80.94 246.95,80.94 245.64,82.25 242.64,82.25 242.07,82.82 234.89,82.82 232.03,85.68 228.35,85.68 228.18,85.51 222.9,85.51 220.57,87.84 215.7,87.84 215.24,87.38 205.81,87.38 205.17,86.75 198.87,86.75 197.37,88.25 194.28,88.25 193.7,88.83 171.87,88.83 166.19,94.5 155.55,94.5 155.45,94.61 153.59,94.61 151.61,96.59 146.51,96.59 146.1,97 144,97 143.52,97.48 141.2,97.48 140.87,97.81 138.6,97.81 138.21,98.19 135.76,98.19 135.41,98.54 134.27,98.54 133.53,97.81 129.08,97.81 128.78,97.51 127.48,97.51 126.87,96.9 125.38,96.9 123.67,95.19 123.51,95.19 121.79,93.46 121.79,88.48 122.32,87.96 122.32,86.46 119.89,84.03 119.45,84.03 119.26,84.22 v2(119.26,84.41)
  BOTTOM w0.081: v2(119.26,84.41) 119.37,84.29 119.95,84.29 120.19,84.06 120.19,83.56 119.91,83.28 119.57,83.28 119.5,83.21 119.5,82.7 118.98,82.18 UC1.B53
  BOTTOM w0.102: v2(266.02,81.66) 266.22,81.45 266.49,81.45 CV501.2
DDR3_DRAMRST#: length 101.9
  TOP w0.102: CD35.1 145.59,22 145.59,19.38 v2(145.78,19.19) ; v2(66.5,16.38) 67.62,17.5 v1(69.84,17.5) 72.82,17.5 73.77,18.45 73.77,22.01 74.23,22.46 CD6.1 74.65,22.49 RD3.1
  IN4 w0.084: v2(66.5,16.38) 67.32,17.21 96.07,17.21 96.42,16.86 101.88,16.86 103.19,15.55 132.36,15.55 134.77,17.96 144.96,17.96 145.78,18.78 v2(145.78,19.19)
  BOTTOM w0.102: v2(145.78,19.19) 146,18.97 JDIMM2.30 ; v2(66.5,16.38) JDIMM1.30
DDR3_DRAMRST#_CPU: length 159.2
  TOP w0.102: CC101.1 142.99,57.11 v2(142.99,61.21) ; v2(76.47,16.2) v1(76.47,17.69) 76.47,21.53 RD2.2 75.57,22.45 RD3.2
  IN4 w0.084: v2(76.47,16.2) 77.27,16.99 95.99,16.99 96.33,16.65 101.79,16.65 103.1,15.34 132.45,15.34 134.86,17.75 158.93,17.75 160.52,19.34 160.52,35.41 148.21,47.71 148.21,49.61 148.01,49.82 148.01,51.62 147.69,51.94 147.69,54.08 144.77,57 144.77,59.05 144.45,59.37 144.45,59.92 144.84,60.3 144.84,60.48 144.57,60.75 144.39,60.75 143.94,60.29 143.76,60.29 143.56,60.49 143.56,60.67 143.88,61 143.88,61.6 143.98,61.7 144.32,61.7 144.45,61.82 144.45,62.08 144.32,62.2 143.75,62.2 143.62,62.33 143.62,64.05 143.5,64.17 143.18,64.17 143.05,64.05 143.05,62.52 142.93,62.39 142.35,62.39 142.23,62.26 142.23,62.03 142.35,61.9 143.24,61.9 143.37,61.77 143.37,61.32 143.26,61.21 v2(142.99,61.21)
  BOTTOM w0.081: UC1.AV15 142.75,61.45 v2(142.99,61.21)
DDR_A_BS0: length 76.1
  IN4 w0.089: v2(130.83,58.29) 130.83,55.01 129.88,54.06 129.88,51.37
  IN4 w0.132: v2(93.42,28.29) 93.42,28.22 92.96,27.76 92.96,24.27 93.08,24.14 94.22,24.14 94.35,24.27 94.35,25.12 94.22,25.25 93.72,25.25 93.59,25.38 93.59,25.66 93.72,25.79 94.22,25.79 94.35,25.92 94.35,26.27 94.22,26.4 93.62,26.4 93.49,26.53 93.49,26.81 93.62,26.94 94.22,26.94 94.35,27.07 94.35,27.35 94.22,27.48 93.96,27.48 93.83,27.6 93.83,27.93 93.96,28.06 94.22,28.06 94.38,28.22 94.38,30.8 95.02,31.44 112.06,31.44 114.52,33.9 116.01,33.9 129.88,47.78 129.88,51.37
  BOTTOM w0.076: v2(130.83,58.29) 129.94,59.19 129.94,61.32 130.1,61.49 130.1,61.76 130.35,62 UC1.AU35
  BOTTOM w0.17: JDIMM1.109 92.6,27.47 v2(93.42,28.29)
DDR_A_BS1: length 75.8
  IN4 w0.089: v2(130.83,58.85) 131.19,58.49 131.19,54.99 130.29,54.09 130.29,51.37
  IN4 w0.132: 130.29,51.37 130.29,47.6 115.99,33.3 115.8,33.3 115.61,33.49 115.43,33.49 115.23,33.29 115.23,33.11 115.42,32.92 115.42,32.73 115.23,32.54 115.04,32.54 114.48,33.1 114.3,33.1 114.04,32.84 114.04,32.65 114.6,32.09 114.6,31.91 114.4,31.71 114.22,31.71 113.66,32.27 113.47,32.27 113.28,32.07 113.28,31.89 113.75,31.41 113.75,31.23 113.55,31.03 113.37,31.03 112.89,31.51 112.71,31.51 112.23,31.03 95.22,31.03 94.79,30.61 94.79,24.04 93.95,23.19 93.95,21.97 v2(93.4,21.42)
  BOTTOM w0.076: UC1.AV35 130.1,61.16 130.1,59.58 v2(130.83,58.85)
  BOTTOM w0.17: JDIMM1.108 92.3,20.32 v2(93.4,21.42)
DDR_A_BS2: length 73.6
  IN4 w0.089: v2(126.07,59.88) 125.65,59.88 125.56,59.78 125.56,57.39 120.39,52.23 120.39,51.37
  IN4 w0.132: v2(81.2,29.82) 81.2,29.69 81.33,29.57 81.56,29.57 81.69,29.69 81.69,30.69 81.2,31.17 81.2,31.32 89.38,39.49 98.63,39.49 98.76,39.62 98.76,40.07 98.89,40.2 99.17,40.2 99.3,40.07 99.3,39.62 99.42,39.49 99.71,39.49 99.84,39.62 99.84,40.07 99.96,40.2 100.25,40.2 100.37,40.07 100.37,39.62 100.5,39.49 100.79,39.49 100.91,39.62 100.91,40.07 101.04,40.2 101.32,40.2 101.45,40.07 101.45,39.62 101.58,39.49 101.86,39.49 101.99,39.62 101.99,40.07 102.12,40.2 102.4,40.2 102.53,40.07 102.53,39.62 102.65,39.49 102.94,39.49 103.07,39.62 103.07,40.07 103.19,40.2 103.48,40.2 103.6,40.07 103.6,39.62 103.73,39.49 104.02,39.49 104.14,39.62 104.14,40.07 104.27,40.2 104.55,40.2 104.68,40.07 104.68,39.62 104.81,39.49 105.09,39.49 105.22,39.62 105.22,40.07 105.35,40.2 109.39,40.2 120.39,51.2 120.39,51.37
  BOTTOM w0.081: UC1.AY41 126.34,60.15 v2(126.07,59.88)
  BOTTOM w0.17: JDIMM1.79 83.6,27.44 81.23,29.82 v2(81.2,29.82)
DDR_A_CAS#: length 75.4
  IN4 w0.089: 131.53,51.37 131.53,52.1 132.1,52.67 132.1,60.52 v2(130.82,61.8)
  IN4 w0.132: v2(95.37,28.29) 95.68,27.98 96.59,27.98 96.72,27.85 96.72,27.41 96.59,27.28 95.71,27.28 95.59,27.15 95.59,26.82 95.71,26.69 96.09,26.69 96.22,26.56 96.22,26.15 96.09,26.03 95.33,26.03 95.2,25.9 95.2,25.55 95.33,25.42 96.63,25.42 96.76,25.55 96.76,26.56 96.88,26.69 97.6,26.69 97.73,26.82 97.73,28.09 97.86,28.22 98.14,28.22 98.27,28.09 98.27,26.82 98.4,26.69 113.9,26.69 114.31,27.11 114.31,29.88 131.53,47.09 131.53,51.37
  BOTTOM w0.081: v2(130.82,61.8) 131.12,62.1 UC1.AU34
  BOTTOM w0.17: JDIMM1.115 94.4,27.56 95.13,28.29 v2(95.37,28.29)
DDR_A_D0: length 59.1
  IN1 w0.084: v2(99.1,27.53) 99.1,26.9 98.98,26.77 98.73,26.77 98.6,26.9 98.6,30.09 98.73,30.21 99.32,30.21 99.44,30.34 99.44,30.58 99.32,30.7 98.83,30.7 98.7,30.83 98.7,31.07 98.83,31.19 99.32,31.19 99.44,31.32 99.44,31.56 99.32,31.68 98.83,31.68 98.7,31.81 98.7,32.05 98.83,32.17 99.32,32.17 99.44,32.3 99.44,32.54 99.32,32.66 98.83,32.66 98.7,32.79 98.7,33.03 98.83,33.15 99.32,33.15 99.44,33.28 99.44,33.52 99.32,33.65 98.83,33.65 98.7,33.77 98.7,38.88 98.83,39 99.32,39 99.44,39.13 99.44,39.37 99.32,39.49 98.83,39.49 98.7,39.62 98.7,39.86 98.83,39.98 99.32,39.98 99.44,40.11 99.44,40.35 99.32,40.47 98.83,40.47 98.7,40.6 98.7,40.87 98.83,41 99.32,41 99.44,41.12 99.44,41.89 103.85,46.3 103.85,57.7 106.37,60.22 106.37,63.72 110.21,67.56 v2(110.21,67.95)
  BOTTOM w0.076: UC1.AH63 112.45,67.5 112.32,67.37 110.64,67.37 v1(110.54,67.47) 110.21,67.81 v2(110.21,67.95)
  BOTTOM w0.102: JDIMM1.129 98.6,27.03 v2(99.1,27.53)
DDR_A_D1: length 59.7
  IN1 w0.084: v2(110.77,67.95) 110.77,67.66 106.69,63.58 106.69,60.09 104.15,57.55 104.15,46.17 99.74,41.77 99.74,38.81 99.62,38.68 99.13,38.68 99,38.56 99,38.32 99.13,38.19 99.62,38.19 99.74,38.06 99.74,37.83 99.62,37.7 99.13,37.7 99,37.57 99,37.34 99.13,37.21 99.62,37.21 99.74,37.08 99.74,36.71 99.62,36.59 99.13,36.59 99,36.46 99,36.22 99.13,36.1 100.18,36.1 100.3,35.97 100.3,35.73 100.18,35.61 99.13,35.61 99,35.48 99,35.24 99.13,35.12 100.18,35.12 100.3,34.99 100.3,34.73 100.18,34.6 99.13,34.6 99,34.48 99,34.24 99.13,34.11 100.18,34.11 100.3,33.99 100.3,33.75 100.18,33.62 99.87,33.62 99.74,33.5 99.74,28.99 99.62,28.87 99.29,28.87 v2(99.1,29.05)
  BOTTOM w0.076: v2(110.77,67.95) 111.15,67.56 112.18,67.56 112.42,67.79 112.69,67.79 112.86,67.7 113.07,67.5 UC1.AH62
  BOTTOM w0.102: JDIMM1.131 99.2,27.02 99.53,27.35 99.53,28.62 v2(99.1,29.05)
DDR_A_D2: length 58
  IN1 w0.084: v2(102.91,29.05) 103.5,29.05 103.63,29.18 103.63,30.13 103.5,30.26 102.79,30.26 102.66,30.38 102.66,30.62 102.79,30.75 103.5,30.75 103.63,30.87 103.63,31.11 103.5,31.24 102.79,31.24 102.66,31.36 102.66,31.6 102.79,31.73 103.5,31.73 103.63,31.85 103.63,32.09 103.5,32.22 102.79,32.22 102.66,32.34 102.66,32.58 102.79,32.71 103.5,32.71 103.63,32.83 103.63,33.07 103.5,33.2 102.79,33.2 102.66,33.32 102.66,33.56 102.79,33.69 103.5,33.69 103.63,33.81 103.63,34.16 103.54,34.24 102.75,34.24 102.66,34.32 102.66,34.65 102.75,34.73 103.54,34.73 103.63,34.81 103.63,35.14 103.54,35.22 103.11,35.22 102.98,35.35 102.98,35.58 103.11,35.71 103.54,35.71 103.63,35.79 103.63,42.12 106.55,45.03 106.55,56.45 109.43,59.34 109.43,60.77 112.72,64.06 112.72,64.94 111.87,65.78 v2(110.4,65.78)
  BOTTOM w0.076: UC1.AK63 112.49,66.02 112.22,66.02 111.98,65.78 110.4,65.78 v2(110.4,65.78)
  BOTTOM w0.102: JDIMM1.141 102.2,28.34 v2(102.91,29.05)
DDR_A_D3: length 58.9
  IN1 w0.084: v2(101.33,19.13) 102.36,20.17 102.36,35.39 103.33,36.35 103.33,42.27 106.23,45.17 106.23,56.59 109.11,59.47 109.11,60.73 112.46,64.08 112.46,64.69 112.21,64.94 v2(109.73,64.94)
  BOTTOM w0.076: v2(109.73,64.94) 110.12,64.94 110.79,65.61 112.04,65.61 112.29,65.86 112.74,65.86 113.03,66.15 UC1.AK62
  BOTTOM w0.102: v2(101.33,19.13) 101.73,19.13 101.9,18.96 JDIMM1.140
DDR_A_D4: length 60.1
  IN1 w0.084: v2(99.44,19.13) 99.04,19.53 99.04,25.14 100.06,26.16 100.06,32.26 100.15,32.34 100.48,32.34 100.6,32.47 100.6,32.71 100.48,32.83 100.15,32.83 100.06,32.92 100.06,33.24 100.15,33.32 100.48,33.32 100.6,33.45 100.6,36.27 100.48,36.4 100.19,36.4 100.06,36.53 100.06,41.54 104.45,45.93 104.45,57.4 107.01,59.96 107.01,63.44 111.34,67.78 v2(111.34,67.95)
  BOTTOM w0.076: UC1.AH61 113.54,67.88 112.88,67.88 112.73,67.96 112.35,67.96 112.11,67.72 111.56,67.72 v2(111.34,67.95)
  BOTTOM w0.102: v2(99.44,19.13) 99.5,19.07 JDIMM1.132
DDR_A_D5: length 60.5
  IN1 w0.084: v2(111.22,66.5) 111.14,66.59 110.61,66.59 107.32,63.3 107.32,59.83 104.75,57.25 104.75,45.78 100.38,41.41 100.38,36.82 100.51,36.7 100.78,36.7 100.9,36.57 100.9,32.05 100.82,31.97 100.46,31.97 100.38,31.88 100.38,31.56 100.46,31.48 100.82,31.48 100.9,31.39 100.9,31.07 100.82,30.99 100.46,30.99 100.38,30.9 100.38,25.44 99.98,25.04 99.98,21.2 v2(99.44,20.66)
  BOTTOM w0.076: v2(111.22,66.5) 111.53,66.2 111.93,66.2 112.08,66.35 112.17,66.35 112.41,66.59 112.74,66.59 112.77,66.58 112.77,66.58 112.88,66.53 113.01,66.53 113.11,66.58 113.11,66.58 113.16,66.61 113.37,66.61 113.42,66.58 113.42,66.58 113.51,66.54 113.53,66.53 113.71,66.53 113.73,66.55 114.11,66.55 114.12,66.53 114.36,66.53 114.57,66.74 UC1.AH60
  BOTTOM w0.102: v2(99.44,20.66) 98.9,20.12 JDIMM1.130
DDR_A_D6: length 59.1
  IN1 w0.084: v2(110.81,66.14) 110.87,66.08 112.09,66.08 112.98,65.19 112.98,64.04 109.72,60.78 109.72,59.17 106.85,56.3 106.85,44.89 103.93,41.97 103.93,24.42 103.8,24.29 103.56,24.29 103.44,24.42 103.44,25.46 103.35,25.55 102.75,25.55 102.66,25.63 102.66,25.95 102.75,26.04 103.35,26.04 103.44,26.12 103.44,26.44 103.35,26.53 102.75,26.53 102.66,26.61 102.66,26.93 102.75,27.02 103.35,27.02 103.44,27.1 103.44,27.4 103.31,27.53 v2(102.91,27.53)
  BOTTOM w0.076: UC1.AK61 113.57,66.26 113.44,66.39 113.33,66.44 113.21,66.44 113.04,66.36 112.84,66.36 112.7,66.43 112.48,66.43 112.24,66.19 112.15,66.19 111.92,65.95 111,65.95 v2(110.81,66.14)
  BOTTOM w0.102: JDIMM1.143 102.8,27.42 v2(102.91,27.53)
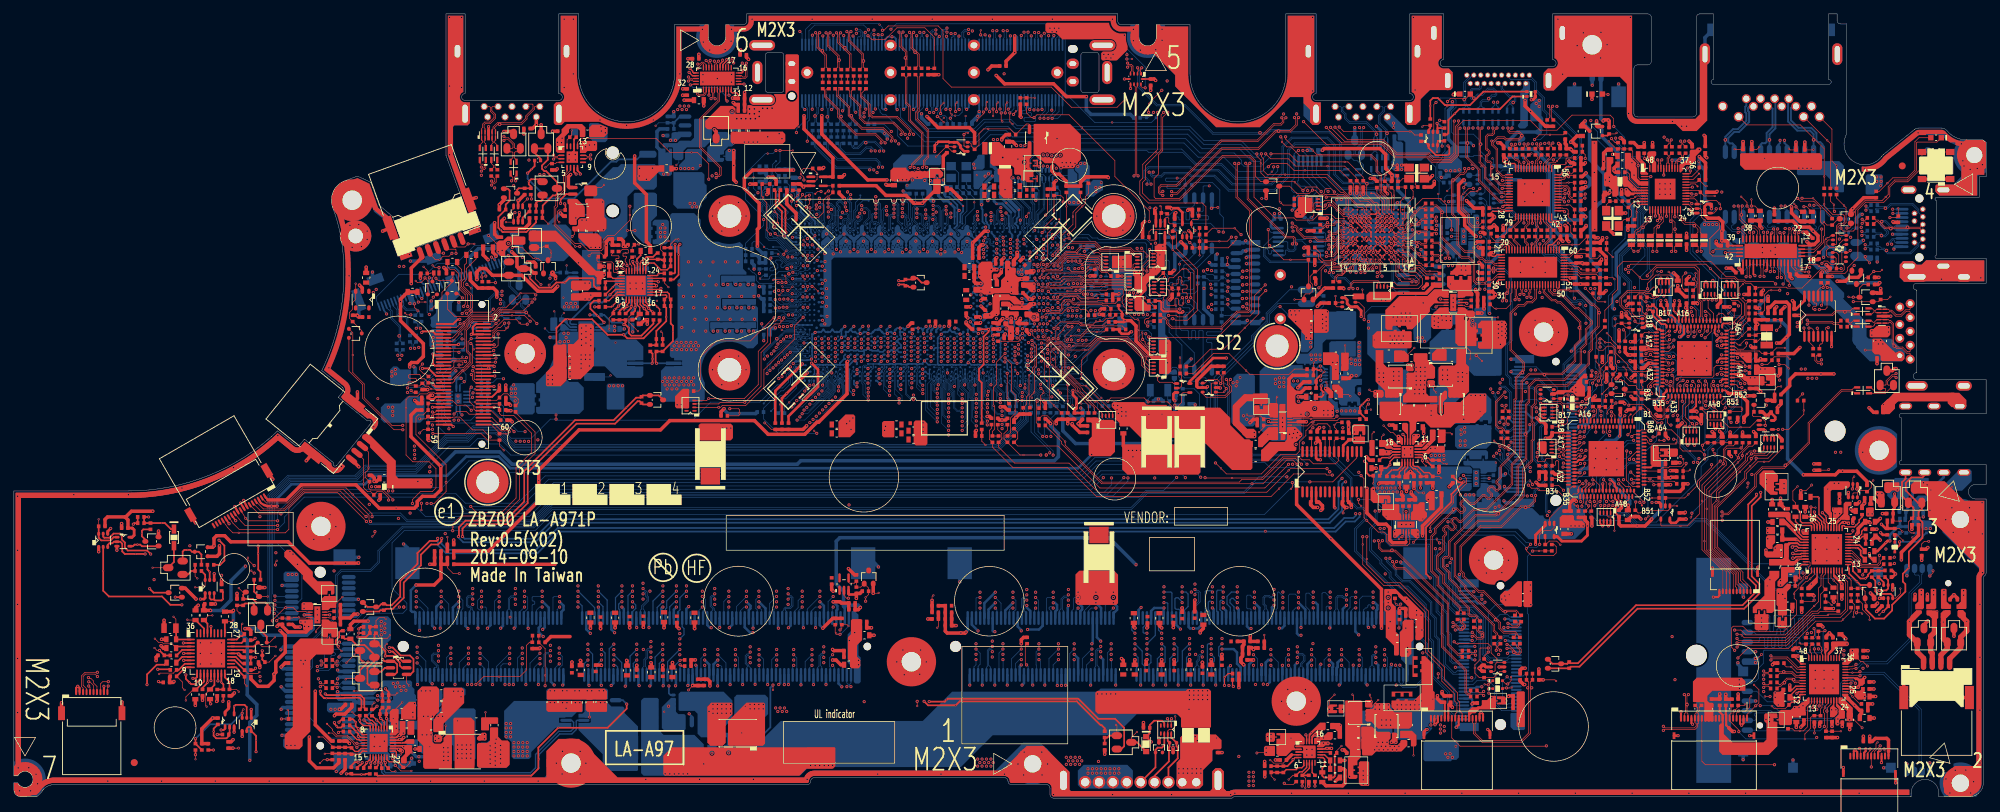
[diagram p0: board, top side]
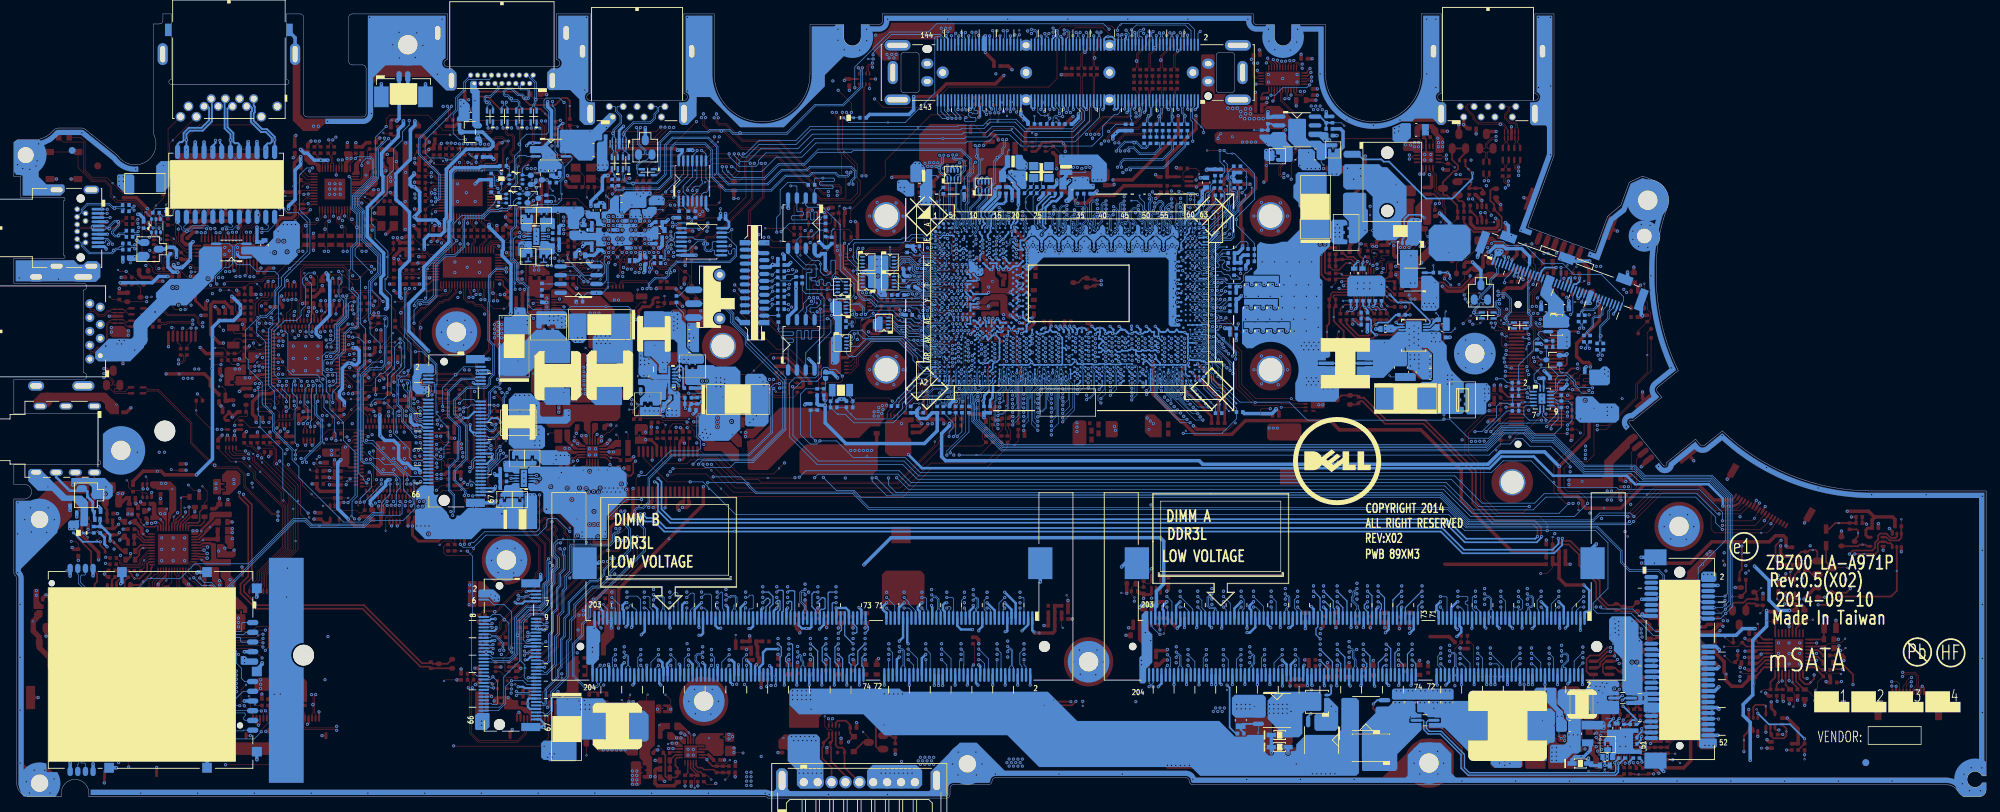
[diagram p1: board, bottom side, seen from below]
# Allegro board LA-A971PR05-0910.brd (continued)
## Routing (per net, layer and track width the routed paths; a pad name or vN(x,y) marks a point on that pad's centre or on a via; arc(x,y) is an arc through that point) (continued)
DDR_A_D7: length 60.5
  IN1 w0.084: v2(101.33,20.66) 102.06,21.39 102.06,35.51 103.03,36.47 103.03,42.41 105.91,45.3 105.91,56.72 108.8,59.6 108.8,60.84 110.44,62.48 110.59,62.48 112.11,64 112.11,64.39 111.81,64.68 110.2,64.68 109.95,64.43 v2(109.41,64.43)
  BOTTOM w0.076: UC1.AK60 114.33,66.26 114.04,65.96 113.49,65.96 113.39,65.86 112.97,65.86 112.81,65.69 112.36,65.69 112.11,65.45 110.99,65.45 110.25,64.7 110.06,64.7 109.79,64.43 v2(109.41,64.43)
  BOTTOM w0.102: JDIMM1.142 102.5,19.49 v2(101.33,20.66)
DDR_A_D8: length 84.6
  IN4 w0.084: v2(57.92,29.05) 58.19,29.05 58.32,28.93 58.32,27.96 58.44,27.83 58.91,27.83 59.04,27.96 59.04,29.48 58.95,29.56 58.44,29.56 58.32,29.69 58.32,29.93 58.44,30.05 58.95,30.05 59.04,30.14 59.04,30.46 58.95,30.55 58.42,30.55 58.3,30.67 58.3,30.91 58.42,31.04 58.95,31.04 59.04,31.12 59.04,31.6 64.7,37.27 64.82,37.27 64.95,37.13 65.07,37.13 65.3,37.36 65.3,37.48 65.17,37.61 65.17,37.73 65.39,37.96 65.51,37.96 65.65,37.82 65.77,37.82 65.99,38.05 65.99,38.17 65.86,38.31 65.86,38.42 66.09,38.65 66.21,38.65 66.34,38.52 66.46,38.52 66.69,38.75 66.69,38.87 66.55,39 66.55,39.12 66.78,39.35 66.9,39.35 67.03,39.21 67.15,39.21 67.38,39.44 67.38,39.56 67.25,39.69 67.25,39.81 67.48,40.04 67.59,40.04 67.73,39.91 67.85,39.91 68.08,40.13 68.08,40.25 67.94,40.39 67.94,40.51 68.17,40.73 68.29,40.73 68.42,40.6 68.54,40.6 68.77,40.83 68.77,40.95 68.63,41.08 68.63,41.2 68.86,41.43 68.98,41.43 69.12,41.29 69.23,41.29 69.46,41.52 69.46,41.64 69.38,41.72 69.38,41.9 69.55,42.07 69.73,42.07 69.81,41.99 69.93,41.99 70.16,42.21 70.16,42.33 70.07,42.42 70.07,42.59 70.24,42.76 70.42,42.76 70.5,42.68 70.62,42.68 84.22,56.28 100.25,56.28 101.41,57.44 104.16,57.44 107.09,60.37 107.09,61.04 108.86,62.8 110.06,62.8 v2(110.08,62.79)
  BOTTOM w0.076: v2(110.08,62.79) 110.08,63.44 110.59,63.96 110.59,64.22 110.6,64.22 110.6,64.25 111.29,64.94 112.34,64.94 112.34,64.94 112.49,64.94 UC1.AM63
  BOTTOM w0.102: JDIMM1.7 59.6,27.37 v2(57.92,29.05)
DDR_A_D9: length 85.4
  IN4 w0.084: v2(58.05,19.48) 59.19,19.48 59.31,19.6 59.31,19.98 59.23,20.07 58.53,20.07 58.44,20.15 58.44,20.47 58.53,20.56 59.23,20.56 59.31,20.64 59.31,24.74 59.94,25.37 59.94,31.15 64.35,35.56 64.78,35.56 84.6,55.38 100.62,55.38 101.77,56.52 104.53,56.52 108.83,60.83 v2(108.83,61.63)
  BOTTOM w0.076: 108.99,62.64 108.99,62.86 110.42,64.29 110.43,64.29 110.43,64.29 110.43,64.32 111.22,65.1 112.24,65.1 112.5,65.36 112.74,65.36 113.03,65.07 UC1.AM62
  BOTTOM w0.102: v2(108.83,61.63) 108.83,62.48 108.99,62.64 ; JDIMM1.4 58.7,18.82 v2(58.05,19.48)
DDR_A_D10: length 83.6
  IN4 w0.084: v2(61.51,29.05) 62.05,29.05 62.18,29.18 62.18,30.05 70.89,38.76 70.89,38.88 70.7,39.07 70.7,39.25 70.87,39.42 71.05,39.42 71.24,39.23 71.36,39.23 71.58,39.46 71.58,39.57 71.28,39.88 71.28,40 71.51,40.23 71.63,40.23 71.93,39.92 72.05,39.92 72.28,40.15 72.28,40.27 71.97,40.57 71.97,40.69 72.2,40.92 72.32,40.92 72.62,40.61 72.74,40.61 72.97,40.84 72.97,40.96 72.67,41.27 72.67,41.39 72.89,41.61 73.01,41.61 73.32,41.31 73.44,41.31 73.7,41.58 73.7,41.76 73.43,42.03 73.43,42.15 73.66,42.38 73.78,42.38 74.05,42.1 74.23,42.1 74.4,42.27 74.4,42.45 74.12,42.73 74.12,42.84 74.35,43.07 74.47,43.07 74.75,42.8 74.92,42.8 75.09,42.96 75.09,43.14 74.82,43.42 74.82,43.54 75.04,43.77 75.16,43.77 75.44,43.49 75.62,43.49 75.79,43.66 75.79,43.84 75.51,44.11 75.51,44.23 75.74,44.46 75.86,44.46 76.13,44.18 76.31,44.18 76.48,44.35 76.48,44.53 76.2,44.81 76.2,44.92 76.43,45.15 76.55,45.15 76.83,44.88 77,44.88 77.17,45.04 77.17,45.22 76.9,45.5 76.9,45.62 77.13,45.85 77.24,45.85 77.52,45.57 77.7,45.57 77.87,45.74 77.87,45.92 77.59,46.19 77.59,46.31 77.82,46.54 77.94,46.54 78.21,46.26 78.39,46.26 78.56,46.43 78.56,46.61 78.28,46.89 78.28,47 78.51,47.23 78.63,47.23 78.91,46.96 79.08,46.96 79.25,47.12 79.25,47.3 78.98,47.58 78.98,47.7 79.21,47.93 79.32,47.93 79.6,47.65 79.78,47.65 79.94,47.82 79.94,48 79.67,48.27 79.67,48.39 85.2,53.92 101.23,53.92 101.77,54.46 104.71,54.46 110.56,60.32 v2(110.56,60.75)
  BOTTOM w0.076: v2(110.56,60.75) 110.56,62.04 112.25,63.72 UC1.AP63
  BOTTOM w0.102: JDIMM1.17 62.6,27.97 v2(61.51,29.05)
DDR_A_D11: length 84.4
  IN4 w0.084: v2(111.35,61.77) 111.35,60.65 104.86,54.16 101.9,54.16 101.35,53.62 85.33,53.62 80.24,48.54 80.24,47.69 62.5,29.94 62.5,23.02 62.41,22.93 61.73,22.93 61.65,22.85 61.65,22.53 61.73,22.44 62.41,22.44 62.5,22.36 62.5,22.05 62.37,21.93 61.84,21.93 61.71,21.8 61.71,21.56 61.84,21.44 62.37,21.44 62.5,21.31 62.5,21.07 62.37,20.95 61.84,20.95 61.71,20.82 61.71,20.58 61.84,20.46 62.37,20.46 62.5,20.33 62.5,20.09 62.37,19.97 61.84,19.97 61.71,19.84 61.71,19.48 61.84,19.35 v2(62.9,19.35)
  BOTTOM w0.081: v2(111.35,61.77) 111.35,62.56 112.22,63.43 112.74,63.43 113.03,63.72 UC1.AP62
  BOTTOM w0.102: JDIMM1.18 62.9,19.35 v2(62.9,19.35)
DDR_A_D12: length 85.8
  IN4 w0.084: v2(58.05,21) 58.87,21 58.99,21.12 58.99,21.54 58.91,21.63 58.53,21.63 58.44,21.71 58.44,22.03 58.53,22.12 58.91,22.12 58.99,22.2 58.99,24.85 59.64,25.49 59.64,31.3 64.2,35.86 64.65,35.86 84.47,55.68 100.5,55.68 101.64,56.82 104.4,56.82 104.67,57.09 108.43,60.86 108.43,61.17 v2(108.43,61.17)
  BOTTOM w0.076: 108.99,63.11 109.88,63.99 109.88,64.02 111.13,65.27 112.17,65.27 112.43,65.53 112.81,65.53 112.97,65.36 113.39,65.36 113.79,64.96 UC1.AM61
  BOTTOM w0.102: JDIMM1.6 59.3,19.74 v2(58.05,21) ; 108.99,63.11 108.43,62.54 v2(108.43,61.17)
DDR_A_D13: length 86.3
  IN4 w0.084: v2(109.69,62.4) 108.91,62.4 107.41,60.9 107.41,60.26 104.27,57.12 101.52,57.12 100.38,55.98 84.35,55.98 64.53,36.16 64.05,36.16 59.34,31.45 59.34,25.61 59.21,25.49 57.71,25.49 57.58,25.61 57.58,25.88 57.71,26.01 58.72,26.01 58.85,26.14 58.85,26.47 58.76,26.56 57.65,26.56 57.52,26.69 57.52,26.92 57.65,27.05 58.76,27.05 58.85,27.13 58.85,27.4 58.72,27.53 v2(57.92,27.53)
  BOTTOM w0.076: v2(109.69,62.4) 110.21,62.4 110.48,62.68 110.74,62.68 112.24,64.18 112.71,64.18 112.87,64.1 113.01,64.1 113.12,64.15 113.17,64.18 113.37,64.18 113.49,64.12 113.53,64.1 114.36,64.1 114.57,64.31 UC1.AM60
  BOTTOM w0.102: v2(57.92,27.53) 58.48,27.53 59,27.01 JDIMM1.5
DDR_A_D14: length 84.6
  IN4 w0.084: v2(110.1,60.45) 108.99,59.34 108.99,59.17 104.59,54.76 101.65,54.76 101.11,54.22 85.08,54.22 70.1,39.25 70.1,39.13 70.41,38.82 70.41,38.71 70.18,38.48 70.06,38.48 69.75,38.78 69.64,38.78 69.41,38.55 69.41,38.43 69.71,38.13 69.71,38.01 69.48,37.78 69.37,37.78 69.06,38.09 68.94,38.09 68.71,37.86 68.71,37.74 69.02,37.44 69.02,37.32 68.79,37.09 68.67,37.09 68.37,37.39 68.25,37.39 68.02,37.17 68.02,37.05 68.32,36.74 68.32,36.63 68.1,36.4 67.98,36.4 67.67,36.7 67.56,36.7 67.33,36.47 67.33,36.35 67.63,36.05 67.63,35.93 67.4,35.7 67.28,35.7 66.98,36.01 66.86,36.01 66.63,35.78 66.63,35.66 66.94,35.36 66.94,35.24 66.71,35.01 66.59,35.01 66.29,35.31 66.17,35.31 65.94,35.09 65.94,34.97 66.24,34.66 66.24,34.54 66.02,34.32 65.9,34.32 65.59,34.62 65.48,34.62 65.25,34.39 65.25,34.27 65.55,33.97 65.55,33.85 65.32,33.62 65.2,33.62 64.9,33.93 64.78,33.93 64.55,33.7 64.55,33.58 64.86,33.28 64.86,33.16 64.63,32.93 64.51,32.93 64.21,33.23 64.09,33.23 63.86,33.01 63.86,32.89 64.16,32.58 64.16,32.46 63.94,32.24 63.82,32.24 63.51,32.54 63.4,32.54 63.09,32.23 63.09,32.12 63.4,31.81 63.4,31.69 63.17,31.46 63.05,31.46 62.74,31.77 62.63,31.77 62.25,31.4 62.25,31.28 62.56,30.98 62.56,30.86 62.33,30.63 62.21,30.63 61.91,30.93 61.79,30.93 61.1,30.24 61.1,27.95 v2(61.51,27.53)
  BOTTOM w0.076: v2(110.1,60.45) 110.1,61.81 112.3,64.01 112.67,64.01 112.83,63.93 113.04,63.93 113.21,64.01 113.33,64.01 113.44,63.96 113.68,63.72 UC1.AP61
  BOTTOM w0.102: v2(61.51,27.53) 61.7,27.53 62,27.23 JDIMM1.15
DDR_A_D15: length 85.1
  IN4 w0.084: v2(111.79,62.14) 111.79,60.64 105.01,53.86 102.02,53.86 101.48,53.32 85.45,53.32 80.54,48.42 80.54,47.57 62.81,29.84 62.81,24.09 62.9,24.01 63.74,24.01 63.87,23.88 63.87,23.65 63.74,23.52 62.9,23.52 62.81,23.44 62.81,23.11 62.9,23.03 63.74,23.03 63.87,22.9 63.87,22.67 63.74,22.54 62.9,22.54 62.81,22.46 62.81,22.16 62.94,22.03 63.61,22.03 63.74,21.9 63.74,21 63.61,20.87 v2(62.9,20.87)
  BOTTOM w0.081: UC1.AP60 114.34,63.49 114.11,63.49 114.04,63.43 112.98,63.43 112.82,63.26 112.29,63.26 111.79,62.76 v2(111.79,62.14)
  BOTTOM w0.102: JDIMM1.16 62.3,20.28 v2(62.9,20.87)
DDR_A_D16: length 53.7
  IN1 w0.084: v2(115.39,63.59) 115.76,63.21 115.76,61.89 114.59,60.72 114.23,60.72 110.67,57.16 110.67,54.96 109.77,54.06 109.77,43.73 108.18,42.14 108.18,31.16 108.1,31.08 107.61,31.08 107.49,30.95 107.49,30.72 107.61,30.59 108.1,30.59 108.18,30.51 108.18,28.64 108.1,28.56 107.76,28.56 107.64,28.43 107.64,28.19 107.76,28.07 108.1,28.07 108.18,27.98 108.18,23.86 108.05,23.73 107.82,23.73 107.69,23.86 107.69,25.49 107.61,25.58 107.31,25.58 107.19,25.71 107.19,25.94 107.31,26.07 107.61,26.07 107.69,26.15 107.69,26.47 107.61,26.56 107.31,26.56 107.19,26.69 107.19,26.92 107.31,27.05 107.61,27.05 107.69,27.13 107.69,27.4 107.56,27.53 v2(107.24,27.53)
  BOTTOM w0.081: UC1.AP58 115.71,63.91 v2(115.39,63.59)
  BOTTOM w0.102: JDIMM1.159 107.6,27.17 v2(107.24,27.53)
DDR_A_D17: length 53
  IN1 w0.084: v2(107.24,29.05) 107.82,29.05 107.88,29.12 107.88,30.08 107.75,30.21 107.31,30.21 107.19,30.33 107.19,31.38 107.27,31.46 107.8,31.46 107.88,31.55 107.88,31.87 107.8,31.95 107.27,31.95 107.19,32.04 107.19,32.36 107.27,32.44 107.8,32.44 107.88,32.53 107.88,32.85 107.8,32.93 107.27,32.93 107.19,33.02 107.19,33.34 107.27,33.42 107.8,33.42 107.88,33.51 107.88,33.83 107.8,33.92 107.27,33.92 107.19,34 107.19,34.32 107.27,34.41 107.8,34.41 107.88,34.49 107.88,34.81 107.8,34.9 107.27,34.9 107.19,34.98 107.19,35.3 107.27,35.39 107.8,35.39 107.88,35.47 107.88,35.79 107.8,35.88 107.27,35.88 107.19,35.96 107.19,36.28 107.27,36.37 107.8,36.37 107.88,36.45 107.88,36.77 107.8,36.86 107.27,36.86 107.19,36.94 107.19,37.26 107.27,37.35 107.8,37.35 107.88,37.43 107.88,37.75 107.8,37.84 107.27,37.84 107.19,37.92 107.19,38.24 107.27,38.33 107.8,38.33 107.88,38.41 107.88,38.73 107.8,38.82 107.27,38.82 107.19,38.9 107.19,39.22 107.27,39.31 107.8,39.31 107.88,39.39 107.88,39.71 107.8,39.8 107.62,39.8 107.49,39.92 107.49,40.16 107.62,40.29 107.8,40.29 107.88,40.37 107.88,42.26 109.45,43.83 109.45,54.16 110.49,55.2 110.49,57.25 114.14,60.9 114.52,60.9 115.39,61.76 v2(115.39,62.94)
  BOTTOM w0.081: UC1.AR58 115.71,63.26 v2(115.39,62.94)
  BOTTOM w0.102: v2(107.24,29.05) 106.81,28.62 106.81,27.31 107,27.12 JDIMM1.157
DDR_A_D18: length 56.4
  IN1 w0.084: v2(116.34,64.89) 115.77,65.45 115.77,66.33 115.54,66.56 115.21,66.56 114.7,66.05 114.7,65.24 112.75,63.3 112.75,61.99 110.7,59.93 110.7,59.07 109.3,57.67 109.3,57.47 107.64,55.8 107.64,44.53 104.74,41.63 104.74,20 v2(103.87,19.13)
  BOTTOM w0.081: v2(116.34,64.89) 116.66,65.21 UC1.AM57
  BOTTOM w0.102: JDIMM1.146 103.7,18.97 v2(103.87,19.13)
DDR_A_D19: length 57.4
  IN1 w0.084: v2(116.29,66.19) 115.74,66.73 115.07,66.73 114.45,66.11 114.45,65.25 112.57,63.38 112.57,62.15 110.43,60.01 110.43,59.2 107.34,56.1 107.34,44.68 104.42,41.76 104.42,22.5 104.33,22.41 103.75,22.41 103.62,22.29 103.62,22.05 103.75,21.92 104.33,21.92 104.42,21.84 104.42,20.79 104.29,20.66 v2(103.87,20.66)
  BOTTOM w0.081: UC1.AK57 116.61,66.51 v2(116.29,66.19)
  BOTTOM w0.102: v2(103.87,20.66) 104.3,20.23 JDIMM1.148
DDR_A_D20: length 55.7
  IN1 w0.084: v2(115.4,65.54) 115.4,65.41 113.12,63.13 113.12,61.63 111.15,59.66 111.15,58.94 109.76,57.54 109.76,57.02 108.24,55.5 108.24,44.26 105.99,42.02 105.99,23.7 105.87,23.57 105.12,23.57 105.03,23.66 105.03,23.98 105.12,24.06 105.38,24.06 105.5,24.19 105.5,24.43 105.38,24.55 105.12,24.55 105.03,24.64 105.03,24.96 105.12,25.04 105.38,25.04 105.5,25.17 105.5,25.41 105.38,25.53 105.12,25.53 105.03,25.62 105.03,25.94 105.12,26.03 105.38,26.03 105.5,26.15 105.5,26.39 105.38,26.52 105.12,26.52 105.03,26.6 105.03,26.92 105.12,27.01 105.37,27.01 105.45,27.09 v2(105.45,27.53)
  BOTTOM w0.081: UC1.AL58 115.72,65.86 v2(115.4,65.54)
  BOTTOM w0.102: JDIMM1.149 104.6,27.01 105.12,27.53 v2(105.45,27.53)
DDR_A_D21: length 56.6
  IN1 w0.084: v2(105.45,29.05) 105.16,29.05 105.03,29.18 105.03,30.17 105.16,30.3 105.57,30.3 105.69,30.42 105.69,30.66 105.57,30.79 105.14,30.79 105.05,30.87 105.05,31.19 105.14,31.28 105.57,31.28 105.69,31.4 105.69,31.64 105.57,31.77 105.14,31.77 105.05,31.85 105.05,32.17 105.14,32.26 105.57,32.26 105.69,32.39 105.69,32.62 105.57,32.75 105.14,32.75 105.05,32.83 105.05,33.15 105.14,33.24 105.57,33.24 105.69,33.37 105.69,33.6 105.57,33.73 105.14,33.73 105.05,33.81 105.05,34.14 105.14,34.22 105.57,34.22 105.69,34.35 105.69,34.58 105.57,34.71 105.14,34.71 105.05,34.79 105.05,35.12 105.14,35.2 105.57,35.2 105.69,35.33 105.69,35.56 105.57,35.69 105.14,35.69 105.05,35.77 105.05,36.1 105.14,36.18 105.57,36.18 105.69,36.31 105.69,36.54 105.57,36.67 105.14,36.67 105.05,36.75 105.05,37.08 105.14,37.16 105.57,37.16 105.69,37.29 105.69,37.52 105.57,37.65 105.14,37.65 105.05,37.73 105.05,38.06 105.14,38.14 105.57,38.14 105.69,38.27 105.69,38.5 105.57,38.63 105.14,38.63 105.05,38.71 105.05,39.04 105.14,39.12 105.57,39.12 105.69,39.25 105.69,39.48 105.57,39.61 105.14,39.61 105.05,39.7 105.05,40.11 105.18,40.23 105.57,40.23 105.69,40.36 105.69,42.14 107.94,44.38 107.94,55.65 109.54,57.26 109.54,57.62 110.93,59 110.93,59.79 112.93,61.8 112.93,63.21 114.96,65.23 114.96,65.76 v2(115.39,66.19)
  BOTTOM w0.081: UC1.AK58 115.71,66.51 v2(115.39,66.19)
  BOTTOM w0.102: v2(105.45,29.05) 104,27.6 JDIMM1.147
DDR_A_D22: length 53.9
  IN1 w0.084: v2(116.34,62.94) 116.57,62.7 116.57,62.2 114.71,60.34 114.37,60.34 111.03,57 111.03,54.56 110.4,53.94 110.4,43.49 108.78,41.87 108.78,24.74 108.91,24.61 109.4,24.61 109.53,24.49 109.53,22.42 109.4,22.29 108.91,22.29 108.78,22.16 108.78,20.24 108.7,20.15 107.75,20.15 107.66,20.07 107.66,19.75 107.75,19.66 108.7,19.66 108.78,19.58 108.78,19.26 108.65,19.13 v2(107.26,19.13)
  BOTTOM w0.081: v2(116.34,62.94) 116.66,63.26 UC1.AR57
  BOTTOM w0.102: v2(107.26,19.13) 107.3,19.1 JDIMM1.158
DDR_A_D23: length 55.5
  IN1 w0.084: v2(107.26,20.66) 108.35,20.66 108.48,20.79 108.48,21.08 108.35,21.21 107.79,21.21 107.66,21.33 107.66,21.57 107.79,21.7 108.4,21.7 108.48,21.78 108.48,22.67 108.56,22.76 109.06,22.76 109.14,22.84 109.14,23.16 109.06,23.25 108.56,23.25 108.48,23.33 108.48,23.65 108.56,23.74 109.06,23.74 109.14,23.82 109.14,24.14 109.06,24.23 108.56,24.23 108.48,24.31 108.48,41.99 110.09,43.6 110.09,53.95 110.85,54.71 110.85,57.07 114.29,60.52 114.64,60.52 115.96,61.84 115.96,63.86 v2(116.34,64.24)
  BOTTOM w0.081: UC1.AN57 116.66,64.56 v2(116.34,64.24)
  BOTTOM w0.102: v2(107.26,20.66) 107.9,20.02 JDIMM1.160
DDR_A_D24: length 80.2
  IN4 w0.084: v2(117.29,63.63) 116.91,63.25 116.91,62.76 115.04,60.88 113.88,60.88 105.23,52.23 86.78,52.23 64.95,30.41 64.95,19.83 v2(65.44,19.35)
  BOTTOM w0.081: v2(117.29,63.63) 117.57,63.91 UC1.AP55
  BOTTOM w0.102: v2(65.44,19.35) 65.29,19.35 64.7,18.76 JDIMM1.24
DDR_A_D25: length 79.6
  IN4 w0.084: v2(65.44,20.87) 65.84,21.27 65.84,24.52 65.27,25.09 65.27,30.28 86.93,51.93 105.38,51.93 114.15,60.71 115.11,60.71 117.28,62.88 v2(117.28,62.94)
  BOTTOM w0.081: UC1.AR55 117.62,63.26 117.29,62.93 v2(117.28,62.94)
  BOTTOM w0.102: JDIMM1.22 64.1,19.54 v2(65.44,20.87)
DDR_A_D26: length 82.1
  IN4 w0.084: v2(67.1,20.87) 68.67,22.44 68.67,31.16 86.3,48.79 92.86,48.79 94.24,50.17 106.24,50.17 111.62,55.55 111.92,55.55 116.29,59.93 117.34,59.93 118.83,61.42 118.83,63.77 118.62,63.98 118.62,65.16 v2(118.24,65.54)
  BOTTOM w0.081: v2(118.24,65.54) 118.57,65.21 UC1.AM54
  BOTTOM w0.102: JDIMM1.36 68.3,19.67 v2(67.1,20.87)
DDR_A_D27: length 83.1
  IN4 w0.084: v2(67.1,19.35) 67.37,19.35 68.97,20.95 68.97,31.04 86.42,48.49 92.98,48.49 94.36,49.87 106.39,49.87 111.12,54.61 111.69,54.61 116.14,59.06 117.18,59.06 119.08,60.96 119.08,63.88 118.79,64.17 118.79,65.65 v2(118.26,66.19)
  BOTTOM w0.081: UC1.AK54 118.58,66.51 v2(118.26,66.19)
  BOTTOM w0.102: v2(67.1,19.35) 67.7,18.75 JDIMM1.34
DDR_A_D28: length 81.7
  IN4 w0.084: v2(117.29,65.54) 116.74,64.98 116.74,62.83 115.63,61.72 114.15,61.72 109.88,57.45 109.88,57.44 109.18,56.74 104.97,52.53 86.63,52.53 86.32,52.23 86.2,52.23 85.93,52.5 85.75,52.5 85.58,52.34 85.58,52.16 85.86,51.88 85.86,51.76 85.63,51.53 85.51,51.53 85.23,51.81 85.05,51.81 84.89,51.64 84.89,51.46 85.16,51.19 85.16,51.07 84.93,50.84 84.82,50.84 84.54,51.12 84.36,51.12 84.19,50.95 84.19,50.77 84.47,50.49 84.47,50.38 84.24,50.15 84.12,50.15 83.85,50.42 83.67,50.42 83.5,50.26 83.5,50.08 83.78,49.8 83.78,49.68 83.55,49.45 83.43,49.45 83.15,49.73 82.97,49.73 82.81,49.56 82.81,49.38 83.08,49.11 83.08,48.99 82.85,48.76 82.74,48.76 82.46,49.04 82.28,49.04 82.11,48.87 82.11,48.69 82.39,48.41 82.39,48.3 82.16,48.07 82.04,48.07 81.77,48.34 81.59,48.34 81.42,48.17 81.42,48 81.7,47.72 81.7,47.6 64.63,30.54 64.63,28.8 64.51,28.67 64.18,28.67 64.05,28.8 v2(64.05,29.05)
  BOTTOM w0.081: v2(117.29,65.54) 117.62,65.86 UC1.AL55
  BOTTOM w0.102: JDIMM1.23 64.4,27.07 64.63,27.3 64.63,28.48 v2(64.05,29.05)
DDR_A_D29: length 82.6
  IN4 w0.084: v2(64.05,27.53) 64.05,24.99 63.93,24.87 63.54,24.87 63.41,24.99 63.41,29.74 81.03,47.36 81.03,48.21 85.65,52.83 104.82,52.83 109.65,57.66 114.07,62.08 115.05,62.08 115.77,62.79 115.77,66.51 116.02,66.77 117.03,66.77 117.24,66.55 v2(117.24,66.19)
  BOTTOM w0.081: UC1.AK55 117.57,66.51 v2(117.24,66.19)
  BOTTOM w0.102: v2(64.05,27.53) 63.8,27.28 JDIMM1.21
DDR_A_D30: length 80.2
  IN4 w0.084: v2(67.32,29.05) 67.32,28.8 67.44,28.67 67.94,28.67 68.07,28.8 68.07,30.12 67.99,30.21 67.39,30.21 67.26,30.33 67.26,30.57 67.39,30.7 67.99,30.7 68.07,30.78 68.07,31.44 86.02,49.39 90.4,49.39 90.52,49.52 90.52,50.69 90.61,50.77 90.93,50.77 91.01,50.69 91.01,49.52 91.14,49.39 91.38,49.39 91.5,49.52 91.5,50.69 91.59,50.77 91.91,50.77 91.99,50.69 91.99,49.52 92.12,49.39 92.36,49.39 92.48,49.52 92.48,50.69 92.57,50.77 92.89,50.77 92.97,50.69 92.97,50.25 93.1,50.12 93.34,50.12 93.46,50.25 93.46,50.69 93.55,50.77 105.94,50.77 107.65,52.48 111.28,56.11 111.28,56.74 114.49,59.95 115.81,59.95 118.24,62.39 v2(118.24,62.94)
  BOTTOM w0.081: UC1.AR54 118.57,63.26 v2(118.24,62.94)
  BOTTOM w0.102: JDIMM1.33 67.4,27.05 67.33,27.12 67,27.12 66.73,27.4 66.73,28.46 v2(67.32,29.05)
DDR_A_D31: length 81.4
  IN4 w0.084: v2(118.24,64.24) 118.24,64.11 118.63,63.73 118.63,61.51 117.25,60.13 116.24,60.13 111.99,55.88 111.5,55.88 106.09,50.47 94.12,50.47 92.73,49.09 86.15,49.09 68.37,31.31 68.37,25.71 68.24,25.58 66.75,25.58 66.66,25.66 66.66,25.98 66.75,26.07 67.75,26.07 67.88,26.2 67.88,26.43 67.75,26.56 66.75,26.56 66.66,26.64 66.66,26.96 66.75,27.05 67.75,27.05 67.88,27.18 67.88,27.4 67.75,27.53 v2(67.32,27.53)
  BOTTOM w0.081: UC1.AN54 118.57,64.56 v2(118.24,64.24)
  BOTTOM w0.102: v2(67.32,27.53) 67.87,27.53 68,27.4 68,26.72 JDIMM1.35
DDR_A_D32: length 46.8
  IN1 w0.084: v2(109.8,19.13) 109.41,19.53 109.41,21.69 109.53,21.82 110.5,21.82 110.62,21.94 110.62,27.85 110.53,27.95 110.53,40.66 111.6,41.74 111.6,56.72 113.54,58.66 v2(113.84,58.66)
  BOTTOM w0.076: UC1.AY58 115.69,60.03 115.69,59.33 115.02,58.66 v2(113.84,58.66)
  BOTTOM w0.102: JDIMM1.166 109.7,19.03 v2(109.8,19.13)
DDR_A_D33: length 47.9
  IN1 w0.084: v2(114.19,59.08) 113.71,59.08 111.38,56.76 111.38,54.14 111.3,54.06 111.3,41.89 110.23,40.81 110.23,33.94 110.15,33.86 109.91,33.86 109.78,33.73 109.78,33.49 109.91,33.37 110.15,33.37 110.23,33.28 110.23,32.96 110.15,32.88 109.65,32.88 109.57,32.79 109.57,32.47 109.65,32.39 110.15,32.39 110.23,32.3 110.23,31.98 110.15,31.9 109.65,31.9 109.57,31.81 109.57,31.49 109.65,31.41 110.15,31.41 110.23,31.32 110.23,31 110.15,30.92 109.65,30.92 109.57,30.83 109.57,30.51 109.65,30.43 110.15,30.43 110.23,30.34 110.23,27.82 110.32,27.73 110.32,25.01 110.2,24.88 109.91,24.88 109.78,25.01 v2(109.78,27.53)
  BOTTOM w0.076: v2(114.19,59.08) 115.21,59.08 115.51,59.39 115.51,60.51 UC1.AW58
  BOTTOM w0.102: JDIMM1.165 109.4,27.15 v2(109.78,27.53)
DDR_A_D34: length 47.7
  IN1 w0.084: v2(113.48,29.05) 113.77,29.05 113.9,29.18 113.9,30.21 113.82,30.3 113.42,30.3 113.29,30.42 113.29,30.66 113.42,30.79 113.82,30.79 113.9,30.87 113.9,31.19 113.82,31.28 113.42,31.28 113.29,31.4 113.29,31.64 113.42,31.77 113.82,31.77 113.9,31.85 113.9,32.17 113.82,32.26 113.42,32.26 113.29,32.39 113.29,32.62 113.42,32.75 113.82,32.75 113.9,32.83 113.9,33.15 113.82,33.24 113.42,33.24 113.29,33.37 113.29,33.6 113.42,33.73 113.82,33.73 113.9,33.81 113.9,34.14 113.82,34.22 113.42,34.22 113.29,34.35 113.29,34.58 113.42,34.71 113.82,34.71 113.9,34.79 113.9,35.12 113.82,35.2 113.42,35.2 113.29,35.33 113.29,35.56 113.42,35.69 113.82,35.69 113.9,35.77 113.9,36.07 113.77,36.19 113.42,36.19 113.29,36.32 113.29,36.58 113.39,36.68 113.77,36.68 113.9,36.81 113.9,37.07 113.8,37.18 113.42,37.18 113.29,37.3 113.29,37.56 113.39,37.67 113.77,37.67 113.9,37.79 113.9,38.05 113.8,38.16 113.42,38.16 113.29,38.28 113.29,38.54 113.39,38.65 113.77,38.65 113.9,38.77 113.9,39.08 113.82,39.17 113.37,39.17 113.29,39.25 113.29,39.57 113.37,39.66 113.82,39.66 113.9,39.74 113.9,40.02 113.77,40.15 113.42,40.15 113.29,40.27 113.29,40.51 113.42,40.64 113.77,40.64 113.9,40.76 113.9,52.58 113.48,53 113.48,53.99 115.85,56.36 v2(115.85,58.21)
  BOTTOM w0.076: UC1.AY56 117.16,59.97 117.14,59.95 117.14,59.07 116.77,58.71 116.77,58.57 116.44,58.24 115.88,58.24 v2(115.85,58.21)
  BOTTOM w0.102: v2(113.48,29.05) 112.89,28.46 112.89,27.44 112.4,26.95 JDIMM1.175
DDR_A_D35: length 48.8
  IN1 w0.084: v2(112.25,19.13) 112.83,19.71 112.83,23.18 112.7,23.31 112.4,23.31 112.32,23.4 112.32,23.72 112.4,23.8 113.34,23.8 113.46,23.93 113.46,24.17 113.34,24.29 112.4,24.29 112.32,24.38 112.32,28.15 112.99,28.83 112.99,40.63 113.6,41.24 113.6,52.44 113.25,52.79 113.25,54.13 114.96,55.84 114.96,57.26 v2(114.93,57.29)
  BOTTOM w0.076: v2(114.93,57.29) 115.45,57.29 116.24,58.08 116.51,58.08 116.93,58.5 116.93,58.64 117.3,59.01 117.3,59.88 117.45,60.03 117.45,60.27 117.16,60.56 UC1.AW56
  BOTTOM w0.102: v2(112.25,19.13) 112.1,18.99 JDIMM1.174
DDR_A_D36: length 48.6
  IN1 w0.084: v2(114.57,59.47) 113.84,59.47 111.2,56.84 111.2,54.27 111,54.06 111,42.37 110.87,42.24 109.84,42.24 109.72,42.11 109.72,41.88 109.84,41.75 110.25,41.75 110.38,41.62 110.38,41.39 110.25,41.26 109.35,41.26 109.27,41.17 109.27,40.68 109.35,40.6 109.85,40.6 109.93,40.52 109.93,40.19 109.85,40.11 109.35,40.11 109.27,40.03 109.27,39.58 109.35,39.5 109.8,39.5 109.93,39.37 109.93,39.14 109.8,39.01 109.35,39.01 109.27,38.93 109.27,38.6 109.35,38.52 109.8,38.52 109.93,38.39 109.93,38.16 109.8,38.03 109.35,38.03 109.27,37.95 109.27,37.62 109.35,37.54 109.8,37.54 109.93,37.41 109.93,37.18 109.8,37.05 109.35,37.05 109.27,36.97 109.27,36.64 109.35,36.56 109.8,36.56 109.93,36.43 109.93,36.2 109.8,36.07 109.35,36.07 109.27,35.99 109.27,35.66 109.35,35.58 109.8,35.58 109.93,35.45 109.93,35.22 109.8,35.09 109.35,35.09 109.27,35 109.27,34.68 109.35,34.6 109.74,34.6 109.87,34.47 109.87,34.24 109.74,34.11 109.35,34.11 109.27,34.02 109.27,29.56 v2(109.78,29.05)
  BOTTOM w0.076: v2(114.57,59.47) 114.57,59.63 114.82,59.88 114.82,60.36 115.3,60.83 115.37,60.83 115.54,61 115.54,61.07 115.58,61.12 115.58,61.23 UC1.AV58
  BOTTOM w0.102: v2(109.78,29.05) 108.8,28.07 JDIMM1.163
DDR_A_D37: length 49.7
  IN1 w0.084: v2(109.8,20.66) 110.92,21.78 110.92,27.98 110.83,28.07 110.83,40.54 111.92,41.63 111.92,56.32 v2(111.96,56.36)
  BOTTOM w0.076: UC1.AU58 116.57,62.1 116.57,62.1 116.61,62.1 116.77,61.94 116.77,61.59 116.76,61.57 116.76,61.33 116.77,61.31 116.77,61.06 116.77,61.04 116.72,60.95 116.7,60.9 116.7,60.7 116.72,60.65 116.77,60.55 116.77,60.55 116.78,60.54 116.78,60.41 116.73,60.3 116.72,60.3 116.7,60.25 116.7,59.96 116.81,59.85 116.81,59.34 116.58,59.11 116.21,59.11 113.46,56.36 v2(111.96,56.36)
  BOTTOM w0.102: v2(109.8,20.66) 109.1,19.95 JDIMM1.164
DDR_A_D38: length 49.3
  IN1 w0.084: v2(113.48,27.53) 113.71,27.3 113.71,27.09 113.63,27.01 112.74,27.01 112.62,26.88 112.62,26.64 112.74,26.52 113.63,26.52 113.71,26.43 113.71,26.11 113.63,26.03 112.74,26.03 112.62,25.9 112.62,24.8 112.74,24.68 113.02,24.68 113.14,24.8 113.14,25.41 113.27,25.54 113.63,25.54 113.71,25.45 113.71,25.07 113.84,24.94 114.07,24.94 114.2,25.07 114.2,52.71 113.72,53.19 113.72,53.89 117.27,57.44 117.27,57.71 v2(116.31,58.67)
  BOTTOM w0.076: v2(116.31,58.67) 116.59,58.95 116.65,58.95 116.97,59.27 116.97,59.92 116.87,60.03 116.87,60.21 116.92,60.32 116.94,60.34 116.94,60.58 116.92,60.63 116.88,60.72 116.87,60.72 116.87,60.73 116.87,60.87 116.89,60.92 116.92,60.97 117.05,61.11 UC1.AV56
  BOTTOM w0.102: JDIMM1.177 113,27.05 v2(113.48,27.53)
DDR_A_D39: length 50.4
  IN1 w0.084: v2(114.58,56.77) 114.58,55.8 113.03,54.25 113.03,52.62 113.3,52.36 113.3,41.37 112.67,40.74 112.67,28.96 112.02,28.3 112.02,23.41 111.89,23.28 111.68,23.28 111.56,23.15 111.56,22.73 111.68,22.6 112.44,22.6 112.53,22.52 112.53,22.2 112.44,22.11 111.68,22.11 111.56,21.99 111.56,20.79 111.68,20.66 v2(112.25,20.66)
  BOTTOM w0.076: v2(114.58,56.77) 115.16,56.77 116.23,57.83 116.5,57.83 117.1,58.43 117.1,58.57 117.47,58.94 117.47,59.81 117.62,59.96 117.62,60.76 117.34,61.03 117.34,61.32 117.34,61.33 117.34,61.57 117.18,61.74 117.18,61.97 UC1.AU56
  BOTTOM w0.102: v2(112.25,20.66) 112.7,20.21 JDIMM1.176
DDR_A_D40: length 75.2
  IN4 w0.084: v2(71.37,19.35) 70.61,20.1 70.61,22.51 70.82,22.72 70.82,31.35 86.87,47.4 96.95,47.4 98.34,48.78 107.04,48.78 112.73,54.47 v2(112.74,54.47)
  BOTTOM w0.076: UC1.AY54 118.11,60.02 118.11,59.75 117.96,59.61 117.96,58.73 117.6,58.36 117.6,58.23 113.84,54.47 v2(112.74,54.47)
  BOTTOM w0.102: JDIMM1.42 70.1,19.05 70.4,19.35 v2(71.37,19.35)
DDR_A_D41: length 76
  IN4 w0.084: v2(113.47,55.39) 113.07,55.39 111.8,54.12 111.8,53.99 106.89,49.08 98.21,49.08 96.83,47.7 86.75,47.7 70.52,31.47 70.52,24.22 70.39,24.09 69.77,24.09 69.65,24.22 69.65,25.13 69.77,25.26 69.94,25.26 70.03,25.34 70.03,25.67 69.94,25.75 69.54,25.75 69.46,25.83 69.46,26.31 69.59,26.44 69.92,26.44 70.03,26.55 70.03,26.8 69.9,26.93 69.57,26.93 69.46,27.04 69.46,27.4 69.59,27.53 v2(69.86,27.53)
  BOTTOM w0.076: v2(113.47,55.39) 114.25,55.39 116.27,57.41 116.54,57.41 117.43,58.3 117.43,58.43 117.8,58.8 117.8,59.68 117.95,59.82 117.95,60.27 118.24,60.56 UC1.AW54
  BOTTOM w0.102: JDIMM1.41 69.8,27.47 v2(69.86,27.53)
DDR_A_D42: length 75.7
  IN4 w0.084: v2(115.96,55.48) 115.43,55.48 113.74,53.8 113.74,52.89 107.88,47.02 104.33,47.02 102.95,45.64 87.63,45.64 73.08,31.09 73.08,27.77 72.78,27.48 72.78,23.75 72.87,23.66 73.56,23.66 73.65,23.57 73.65,23.26 73.56,23.17 72.87,23.17 72.78,23.08 72.78,21.27 v2(73.18,20.87)
  BOTTOM w0.076: v2(115.96,55.48) 116.63,55.48 116.93,55.78 117.16,55.78 119.44,58.06 119.44,59.52 119.46,59.54 119.46,60.02 UC1.AY52
  BOTTOM w0.102: JDIMM1.50 72.5,20.19 v2(73.18,20.87)
DDR_A_D43: length 76.7
  IN4 w0.084: v2(73.5,27.53) 73.9,27.53 73.99,27.44 73.99,27.09 73.9,27 73.17,27 73.08,26.92 73.08,26.6 73.17,26.51 73.9,26.51 73.99,26.43 73.99,26.11 73.9,26.02 73.17,26.02 73.08,25.94 73.08,25.63 73.18,25.53 73.51,25.53 73.64,25.41 73.64,24.2 73.76,24.08 74.35,24.08 74.48,24.2 74.48,31.62 87.88,45.02 106.77,45.02 114.44,52.69 114.44,52.98 115.04,53.58 v2(115.04,54.56)
  BOTTOM w0.076: UC1.AW52 119.8,60.58 119.8,60.37 119.83,60.32 119.84,60.29 119.88,60.2 119.88,59.73 119.61,59.45 119.61,57.99 116.18,54.56 v2(115.04,54.56)
  BOTTOM w0.102: JDIMM1.51 72.8,26.83 v2(73.5,27.53)
DDR_A_D44: length 76.3
  IN4 w0.084: v2(113.74,55.91) 113.27,55.91 111.33,53.97 111.33,53.97 109.84,52.48 107.45,50.09 106.74,49.38 97.51,49.38 97.43,49.3 97.43,48.72 97.3,48.59 97.06,48.59 96.94,48.72 96.94,49.3 96.85,49.38 96.53,49.38 96.44,49.3 96.44,48.13 96.32,48 96.08,48 95.95,48.13 95.95,49.3 95.87,49.38 95.55,49.38 95.46,49.3 95.46,48.13 95.34,48 95.1,48 94.97,48.13 94.97,49.3 94.89,49.38 94.57,49.38 94.48,49.3 94.48,48.13 94.36,48 86.62,48 70.22,31.6 70.22,31.32 70.09,31.19 69.82,31.19 69.69,31.07 69.69,30.83 69.82,30.7 70.09,30.7 70.22,30.58 70.22,30.34 70.09,30.21 69.59,30.21 69.46,30.09 69.46,29.18 69.59,29.05 v2(69.86,29.05)
  BOTTOM w0.076: v2(113.74,55.91) 114.54,55.91 116.22,57.59 116.49,57.59 117.26,58.37 117.26,58.5 117.63,58.87 117.63,59.74 117.78,59.89 117.78,60.76 118.34,61.32 UC1.AV54
  BOTTOM w0.102: JDIMM1.39 69.2,28.4 v2(69.86,29.05)
DDR_A_D45: length 77.8
  IN4 w0.084: v2(71.37,20.87) 70.94,21.3 70.94,22.41 71.12,22.59 71.12,31.22 87,47.1 97.08,47.1 98.46,48.48 107.19,48.48 107.77,49.07 110.51,51.81 112.62,53.91 112.69,53.91 117.47,58.68 v2(118.7,58.68)
  BOTTOM w0.076: v2(118.7,58.68) 119.11,59.1 119.11,59.72 119.13,59.74 119.13,60.25 119.16,60.3 119.16,60.31 119.21,60.41 119.21,60.54 119.2,60.55 119.2,60.55 119.15,60.65 119.13,60.7 119.13,60.9 119.17,60.99 119.2,61.04 119.21,61.06 119.21,61.9 119,62.1 UC1.AU54
  BOTTOM w0.102: JDIMM1.40 69.5,19 v2(71.37,20.87)
DDR_A_D46: length 76.9
  IN4 w0.084: v2(116.42,55.94) 115.63,55.94 113.41,53.72 113.41,53.01 107.73,47.32 104.21,47.32 102.82,45.94 87.48,45.94 72.75,31.21 72.75,27.89 72.47,27.61 72.47,21.57 72.38,21.48 71.89,21.48 71.8,21.4 71.8,21.13 71.89,21.04 72.38,21.04 72.47,20.95 72.47,19.48 72.59,19.35 v2(73.18,19.35)
  BOTTOM w0.076: v2(116.42,55.94) 117.09,55.94 119.28,58.13 119.28,59.59 119.3,59.61 119.3,60.21 119.35,60.32 119.37,60.37 119.37,60.58 119.35,60.63 119.31,60.72 119.3,60.72 119.3,60.73 119.3,60.87 119.32,60.92 119.35,60.97 119.48,61.11 UC1.AV52
  BOTTOM w0.102: v2(73.18,19.35) 73.1,19.26 JDIMM1.52
DDR_A_D47: length 77.6
  IN4 w0.084: v2(114.58,54.1) 114.58,53.51 114.06,53 114.06,52.76 108.03,46.72 107.34,46.72 107.25,46.64 107.25,45.93 107.13,45.8 106.89,45.8 106.76,45.93 106.76,46.64 106.68,46.72 106.36,46.72 106.27,46.64 106.27,45.45 106.15,45.32 105.91,45.32 105.78,45.45 105.78,46.64 105.7,46.72 105.38,46.72 105.29,46.64 105.29,45.45 105.17,45.32 104.93,45.32 104.8,45.45 104.8,46.52 104.68,46.65 104.44,46.65 104.31,46.52 104.31,45.45 104.19,45.32 87.73,45.32 74.18,31.77 74.18,30.83 74.05,30.7 73.5,30.7 73.38,30.58 73.38,30.34 73.5,30.21 74.05,30.21 74.18,30.09 74.18,28.8 74.05,28.67 73.63,28.67 73.5,28.8 v2(73.5,29.05)
  BOTTOM w0.076: v2(114.58,54.1) 115.96,54.1 119.77,57.91 119.77,59.38 119.77,59.38 120.05,59.66 120.05,60.25 120.02,60.3 120.02,60.3 120,60.35 119.97,60.4 119.97,61.72 UC1.AU52
  BOTTOM w0.102: JDIMM1.53 73.4,26.73 73.96,27.3 73.96,28.93 73.84,29.05 v2(73.5,29.05)
DDR_A_D48: length 85.4
  IN4 w0.084: v2(126.73,66.23) 126.79,66.23 127.31,65.71 127.31,62.76 126.71,62.16 124.39,62.16 124,61.77 124,57.15 122.41,55.55 120.91,55.55 118.71,53.36 118.71,51.77 108.48,41.54 98.33,41.54 97.62,40.83 88.62,40.83 79.7,31.91 79.7,24.7 79.57,24.57 78.53,24.57 78.44,24.65 78.44,24.98 78.53,25.06 79.13,25.06 79.21,25.14 79.21,25.47 79.13,25.55 78.53,25.55 78.44,25.63 78.44,25.96 78.53,26.04 79.13,26.04 79.21,26.12 79.21,26.45 79.13,26.53 78.53,26.53 78.44,26.61 78.44,26.94 78.53,27.02 79.13,27.02 79.21,27.1 79.21,27.4 79.08,27.53 v2(78.56,27.53)
  BOTTOM w0.081: v2(126.73,66.23) 127.01,66.51 UC1.AK40
  BOTTOM w0.102: v2(78.56,27.53) 78.2,27.17 JDIMM1.69
DDR_A_D49: length 84.7
  IN4 w0.084: v2(125.81,66.24) 126.19,65.86 126.88,65.86 127.11,65.63 127.11,62.81 126.68,62.38 124.36,62.38 123.75,61.77 123.75,57.23 122.45,55.93 120.83,55.93 118.4,53.49 118.4,51.87 108.36,41.84 97.92,41.84 97.79,41.71 97.79,41.42 97.66,41.29 97.43,41.29 97.3,41.42 97.3,41.71 97.17,41.84 96.94,41.84 96.81,41.71 96.81,41.26 96.68,41.13 96.45,41.13 96.32,41.26 96.32,41.71 96.19,41.84 95.96,41.84 95.83,41.71 95.83,41.26 95.7,41.13 95.46,41.13 95.34,41.26 95.34,41.71 95.21,41.84 94.97,41.84 94.85,41.71 94.85,41.26 94.72,41.13 94.48,41.13 94.36,41.26 94.36,41.5 94.23,41.63 93.99,41.63 93.87,41.5 93.87,41.26 93.74,41.13 88.5,41.13 79.4,32.04 79.4,31.14 79.27,31.01 78.57,31.01 78.44,30.89 78.44,30.65 78.57,30.52 79.27,30.52 79.4,30.4 79.4,30.16 79.27,30.03 78.57,30.03 78.44,29.91 78.44,29.67 78.57,29.54 79.27,29.54 79.4,29.42 79.4,28.8 79.27,28.68 78.68,28.68 78.56,28.8 v2(78.56,29.05)
  BOTTOM w0.081: UC1.AK42 126.08,66.51 v2(125.81,66.24)
  BOTTOM w0.102: v2(78.56,29.05) 77.77,29.05 77.6,28.88 JDIMM1.67
DDR_A_D50: length 82.6
  IN4 w0.084: v2(76.04,27.53) 75.74,27.53 75.61,27.4 75.61,27.11 75.74,26.98 76.02,26.98 76.15,26.85 76.15,26.62 76.02,26.49 75.74,26.49 75.61,26.36 75.61,26.13 75.74,26 76.02,26 76.15,25.87 76.15,25.55 76.02,25.43 75.76,25.43 75.68,25.34 75.68,23.85 75.81,23.72 76.51,23.72 76.64,23.85 76.64,31.81 87.72,42.89 92.76,42.89 93.49,43.62 107.58,43.62 116.56,52.6 116.56,54.25 119.79,57.48 119.79,58.56 120.94,59.72 120.94,61.81 121.32,62.19 121.76,62.19 122.39,62.81 122.39,63.71 122.76,64.08 123.35,64.08 123.84,64.56 124.37,64.56 v2(124.8,64.99)
  BOTTOM w0.081: UC1.AM43 125.05,65.21 124.87,65.02 124.83,65.02 v2(124.8,64.99)
  BOTTOM w0.102: JDIMM1.59 75.2,27.06 75.67,27.53 v2(76.04,27.53)
DDR_A_D51: length 81.8
  IN4 w0.084: v2(123.9,64.94) 123.26,64.3 122.55,64.3 122.2,63.96 121.8,63.96 121.5,63.66 121.5,62.87 120.74,62.11 120.74,60.36 120.43,60.05 120.43,59.93 120.57,59.78 120.57,59.66 120.35,59.44 120.23,59.44 120.08,59.58 119.96,59.58 119.56,59.18 119.56,57.67 116.24,54.36 116.24,52.72 107.45,43.93 93.08,43.93 92.95,43.81 92.95,43.53 92.83,43.4 92.59,43.4 92.46,43.53 92.46,43.81 92.34,43.93 92.1,43.93 91.97,43.81 91.97,43.32 91.85,43.19 91.61,43.19 91.48,43.32 91.48,43.81 91.35,43.93 91.12,43.93 90.99,43.81 90.99,43.32 90.86,43.19 90.63,43.19 90.5,43.32 90.5,43.81 90.37,43.93 90.14,43.93 90.01,43.81 90.01,43.32 89.88,43.19 89.65,43.19 89.52,43.32 89.52,43.81 89.39,43.93 89.16,43.93 89.03,43.81 89.03,43.32 88.9,43.19 88.67,43.19 88.54,43.32 88.54,43.65 88.41,43.78 88.18,43.78 88.05,43.65 88.05,43.32 87.92,43.19 87.59,43.19 76.34,31.94 76.34,31.32 76.21,31.19 75.74,31.19 75.61,31.07 75.61,30.83 75.74,30.7 76.21,30.7 76.34,30.58 76.34,30.34 76.21,30.21 75.76,30.21 75.63,30.09 75.63,28.75 75.71,28.67 75.92,28.67 76.04,28.8 v2(76.04,29.05)
  BOTTOM w0.081: v2(123.9,64.94) 124.17,65.21 UC1.AM45
  BOTTOM w0.102: v2(76.04,29.05) 74.73,29.05 74.6,28.93 74.6,28.5 74.7,28.4 74.85,28.4 74.98,28.27 74.98,28.01 74.85,27.89 74.7,27.89 74.6,27.79 JDIMM1.57
DDR_A_D52: length 82.8
  IN4 w0.084: v2(75.72,20.87) 75.39,20.87 75.31,20.95 75.31,22.21 75.4,22.3 75.56,22.3 75.68,22.42 75.68,22.66 75.56,22.79 75.4,22.79 75.31,22.88 75.31,31.34 88.21,44.23 107.28,44.23 115.04,52 115.04,52.7 115.93,53.59 115.93,54.33 119.33,57.73 119.33,59.36 120.51,60.54 120.51,62.27 120.69,62.44 120.69,63.78 121.04,64.13 122.13,64.13 122.48,64.48 123.19,64.48 123.43,64.72 123.43,65.7 v2(123.92,66.18)
  BOTTOM w0.081: v2(123.92,66.18) 124.25,66.51 UC1.AK45
  BOTTOM w0.102: v2(75.72,20.87) 74.3,19.45 JDIMM1.56
DDR_A_D53: length 84
  IN4 w0.084: v2(75.72,19.35) 74.97,20.1 74.97,31.42 88.09,44.53 107.13,44.53 114.64,52.04 114.64,52.76 115.52,53.64 115.52,54.21 119.13,57.82 119.13,59.57 120.22,60.66 120.22,62.42 120.51,62.72 120.51,63.85 120.97,64.3 121.97,64.3 122.48,64.81 122.48,66.2 122.82,66.54 124.49,66.54 v2(124.8,66.23)
  BOTTOM w0.081: UC1.AK43 125.08,66.51 v2(124.8,66.23)
  BOTTOM w0.102: JDIMM1.58 74.9,18.84 75.41,19.35 v2(75.72,19.35)
DDR_A_D54: length 83.7
  IN4 w0.084: v2(126.72,64.86) 126.29,64.43 126.29,62.97 125.89,62.56 124.29,62.56 123.55,61.82 123.55,57.35 122.41,56.21 120.68,56.21 118.08,53.61 118.08,51.98 117.47,51.37 108.23,42.14 94.08,42.14 93.37,41.43 88.35,41.43 78.14,31.23 78.14,24.4 78.27,24.27 79.55,24.27 79.68,24.14 79.68,19.48 79.55,19.35 v2(78.5,19.35)
  BOTTOM w0.081: UC1.AM40 127.07,65.21 v2(126.72,64.86)
  BOTTOM w0.102: v2(78.5,19.35) 77.9,18.75 JDIMM1.68
DDR_A_D55: length 83.6
  IN4 w0.084: v2(125.81,64.98) 125.81,64.97 124.78,63.94 124.67,63.94 124.48,63.75 124.48,63.03 123.32,61.87 123.32,61.7 123.09,61.47 122.79,61.47 122.52,61.2 122.52,57.23 121.91,56.62 120.68,56.62 117.76,53.7 117.76,52.09 108.13,42.45 93.97,42.45 93.25,41.73 88.2,41.73 77.8,31.33 77.8,24.1 77.93,23.97 79.25,23.97 79.38,23.84 79.38,23.53 79.25,23.41 78.79,23.41 78.66,23.28 78.66,23 78.79,22.87 79.25,22.87 79.38,22.74 79.38,21 79.25,20.87 v2(78.5,20.87)
  BOTTOM w0.081: UC1.AM42 126.04,65.21 v2(125.81,64.98)
  BOTTOM w0.102: v2(78.5,20.87) 78.93,20.44 78.93,19.17 78.5,18.74 JDIMM1.70
DDR_A_D56: length 58.9
  IN1 w0.084: v2(117.85,20.66) 117.85,20.4 117.72,20.28 117.42,20.28 117.29,20.4 117.29,21.7 117.42,21.83 119.29,21.83 119.41,21.96 119.41,22.2 119.29,22.32 117.93,22.32 117.8,22.45 117.8,23.6 117.93,23.72 118.29,23.72 118.42,23.6 118.42,22.94 118.54,22.81 119.24,22.81 119.37,22.94 119.37,42.36 118.24,43.49 118.24,53.92 120.25,55.93 120.25,62.05 120.81,62.61 121.19,62.61 121.54,62.96 121.54,63.69 122,64.15 122.04,64.15 122.55,64.66 122.55,65.09 v2(122.95,65.49)
  BOTTOM w0.081: v2(122.95,65.49) 123.22,65.21 UC1.AM46
  BOTTOM w0.102: v2(117.85,20.66) 117.42,20.23 117.42,18.96 117.5,18.88 JDIMM1.192
DDR_A_D57: length 58.8
  IN1 w0.084: v2(122.95,66.14) 123.33,65.76 123.33,64.68 122.36,63.71 122.36,62.79 122.35,62.78 122.35,62.76 122.03,62.44 120.89,62.44 120.44,61.99 120.44,55.74 118.54,53.85 118.54,43.61 119.71,42.44 119.71,21.22 119.59,21.1 118.73,21.1 118.61,20.97 118.61,20.73 118.73,20.61 119.59,20.61 119.71,20.48 119.71,20.24 119.59,20.12 118.37,20.12 118.25,19.99 118.25,19.75 118.37,19.62 119.59,19.62 119.71,19.5 119.71,19.26 119.59,19.13 v2(117.85,19.13)
  BOTTOM w0.081: v2(122.95,66.14) 123.33,66.51 UC1.AK46
  BOTTOM w0.102: v2(117.85,19.13) 118.1,18.88 JDIMM1.194
DDR_A_D58: length 56.4
  IN1 w0.084: v2(116.02,27.53) 116.02,25.56 116.15,25.44 116.61,25.44 116.74,25.56 116.74,35.45 116.61,35.58 115.84,35.58 115.71,35.71 115.71,36.13 115.8,36.21 116.62,36.21 116.75,36.34 116.75,36.58 116.62,36.7 115.8,36.7 115.71,36.79 115.71,37.11 115.8,37.19 116.4,37.19 116.48,37.28 116.48,37.6 116.4,37.68 115.8,37.68 115.71,37.77 115.71,38.09 115.8,38.17 116.4,38.17 116.48,38.26 116.48,38.58 116.4,38.66 115.8,38.66 115.71,38.75 115.71,39.07 115.8,39.15 116.4,39.15 116.48,39.24 116.48,39.56 116.4,39.64 115.8,39.64 115.71,39.73 115.71,40.05 115.8,40.13 116.4,40.13 116.48,40.22 116.48,40.54 116.4,40.62 115.8,40.62 115.71,40.71 115.71,41.03 115.8,41.11 116.4,41.11 116.48,41.2 116.48,54.04 119.27,56.83 119.27,61.76 119.07,61.96 119.07,63.69 119.88,64.5 120.14,64.5 120.55,64.91 v2(121.05,64.91)
  BOTTOM w0.081: UC1.AM49 121.35,65.21 v2(121.05,64.91)
  BOTTOM w0.102: v2(116.02,27.53) 115.37,27.53 114.8,26.96 114.8,26.03 JDIMM1.183
DDR_A_D59: length 55.8
  IN1 w0.084: v2(121.05,66.17) 120.34,66.88 118.2,66.88 117.66,66.34 117.66,62.24 118.12,61.78 118.12,58.46 118.62,57.97 118.62,57.37 114.81,53.57 114.81,24.99 114.19,24.36 114.19,19.83 v2(114.88,19.13)
  BOTTOM w0.081: v2(121.05,66.17) 121.39,66.51 UC1.AK49
  BOTTOM w0.102: v2(114.88,19.13) 114.5,18.75 JDIMM1.182
DDR_A_D60: length 58
  IN1 w0.084: v2(117.94,29.05) 118.57,29.05 118.66,29.14 118.66,30.2 118.53,30.33 118.07,30.33 117.94,30.45 117.94,30.78 118.02,30.86 118.59,30.86 118.68,30.95 118.68,31.27 118.59,31.35 118.02,31.35 117.94,31.44 117.94,31.76 118.02,31.84 118.59,31.84 118.68,31.93 118.68,32.25 118.59,32.33 118.02,32.33 117.94,32.42 117.94,32.74 118.02,32.82 118.59,32.82 118.68,32.91 118.68,33.23 118.59,33.31 118.02,33.31 117.94,33.4 117.94,33.72 118.02,33.8 118.59,33.8 118.68,33.89 118.68,34.21 118.59,34.29 118.02,34.29 117.94,34.38 117.94,34.7 118.02,34.78 118.59,34.78 118.68,34.87 118.68,35.19 118.59,35.27 118.02,35.27 117.94,35.36 117.94,35.68 118.02,35.76 118.59,35.76 118.68,35.85 118.68,36.17 118.59,36.25 118.02,36.25 117.94,36.34 117.94,36.66 118.02,36.74 118.59,36.74 118.68,36.83 118.68,37.15 118.59,37.23 117.77,37.23 117.64,37.36 117.64,37.6 117.77,37.72 118.59,37.72 118.68,37.81 118.68,38.13 118.59,38.22 117.77,38.22 117.64,38.34 117.64,38.7 117.72,38.78 118.59,38.78 118.68,38.87 118.68,39.19 118.59,39.27 117.72,39.27 117.64,39.36 117.64,39.68 117.72,39.76 118.59,39.76 118.68,39.85 118.68,40.17 118.59,40.25 117.72,40.25 117.64,40.34 117.64,53.97 119.87,56.2 119.87,62.24 120.47,62.85 120.47,63.81 120.83,64.16 121.45,64.16 122,64.71 v2(122,64.89)
  BOTTOM w0.081: UC1.AM48 122.32,65.21 v2(122,64.89)
  BOTTOM w0.102: JDIMM1.191 117.2,28.32 v2(117.94,29.05)
DDR_A_D61: length 57.3
  IN1 w0.084: v2(122,66.12) 122.26,66.12 122.37,66.01 122.37,64.73 121.98,64.34 121.91,64.34 121.56,63.98 120.9,63.98 120.9,63.98 120.69,63.77 120.69,63.77 120.65,63.73 120.65,62.75 120.04,62.14 120.04,56.04 117.94,53.94 117.94,42.64 118.07,42.51 118.79,42.51 118.92,42.39 118.92,42.15 118.79,42.02 118.07,42.02 117.94,41.9 117.94,41.66 118.07,41.53 118.92,41.53 119.05,41.41 119.05,41.17 118.92,41.04 118.07,41.04 117.94,40.92 117.94,40.68 118.07,40.55 118.85,40.55 118.98,40.43 118.98,28.66 118.89,28.57 118.42,28.57 118.34,28.48 118.34,28.16 118.42,28.07 118.89,28.07 118.98,27.98 118.98,24.83 118.85,24.7 118.61,24.7 118.48,24.83 118.48,25.49 118.39,25.58 117.99,25.58 117.91,25.66 117.91,25.98 117.99,26.07 118.39,26.07 118.48,26.15 118.48,26.47 118.39,26.56 117.99,26.56 117.91,26.64 117.91,26.96 117.99,27.05 118.39,27.05 118.48,27.13 118.48,27.4 118.35,27.53 v2(117.94,27.53)
  BOTTOM w0.081: UC1.AK48 122.39,66.51 v2(122,66.12)
  BOTTOM w0.102: v2(117.94,27.53) 117.8,27.39 JDIMM1.193
DDR_A_D62: length 55
  IN1 w0.084: v2(120.06,64.94) 119.61,65.39 119.61,65.73 119.45,65.9 118.98,65.9 118.7,65.62 118.7,62.05 119.08,61.67 119.08,56.97 116.18,54.07 116.18,42 115.41,41.23 115.41,35.41 115.54,35.28 116.31,35.28 116.44,35.15 116.44,34.84 116.36,34.75 115.5,34.75 115.41,34.67 115.41,34.35 115.5,34.26 116.36,34.26 116.44,34.18 116.44,33.86 116.36,33.77 115.5,33.77 115.41,33.69 115.41,33.37 115.5,33.28 116.36,33.28 116.44,33.2 116.44,32.88 116.36,32.79 115.5,32.79 115.41,32.71 115.41,32.39 115.5,32.3 116.36,32.3 116.44,32.22 116.44,31.9 116.36,31.81 115.5,31.81 115.41,31.73 115.41,31.41 115.5,31.32 116.36,31.32 116.44,31.24 116.44,30.92 116.36,30.83 115.5,30.83 115.41,30.75 115.41,30.43 115.5,30.34 116.36,30.34 116.44,30.26 116.44,29.47 v2(116.02,29.05)
  BOTTOM w0.081: v2(120.06,64.94) 120.33,65.21 UC1.AM51
  BOTTOM w0.102: JDIMM1.181 114.2,27.23 v2(116.02,29.05)
DDR_A_D63: length 54.5
  IN1 w0.084: v2(120.09,66.19) 119.57,66.71 118.27,66.71 117.83,66.27 117.83,62.36 118.3,61.89 118.3,58.56 118.79,58.08 118.79,57.05 115.11,53.37 115.11,24.84 114.49,24.22 114.49,21.06 v2(114.88,20.66)
  BOTTOM w0.081: UC1.AK51 120.18,66.19 v2(120.09,66.19)
  BOTTOM w0.102: v2(114.88,20.66) 113.9,19.67 JDIMM1.180
DDR_A_DQS0: length 59.5
  IN1 w0.091: v2(100.88,28.67) 100.88,28.93 101,29.05 101.39,29.05 101.57,29.23 101.57,36.31 101.66,36.4 102.25,36.4 102.48,36.63 102.48,37.01 102.25,37.24 101.17,37.24 101.05,37.37 101.05,37.61 101.17,37.74 102.31,37.74 102.53,37.97 102.53,38.36 102.31,38.58 101.17,38.58 101.05,38.71 101.05,38.95 101.17,39.08 102.31,39.08 102.53,39.31 102.53,39.7 102.31,39.92 101.59,39.92 101.46,40.05 101.46,40.3 101.59,40.42 102.31,40.42 102.53,40.65 102.53,41.04 102.31,41.27 101.69,41.27 101.57,41.39 101.57,41.66 101.7,41.78 102.25,41.78 102.48,42.01 102.48,42.56 105.42,45.5 105.42,56.92 108.03,59.53 108.03,61.47 108.78,62.22 108.78,62.81 108.44,63.16 108.44,63.65 v2(108.48,63.69)
  BOTTOM w0.076: 110.62,66.73 110.93,67.04 112.7,67.04 112.77,67.07 112.77,67.07 112.88,67.12 113.01,67.12 113.11,67.07 113.11,67.07 113.16,67.04 113.36,67.04 113.53,67.12 113.66,67.12 113.76,67.07 113.84,66.99 113.84,66.9 113.77,66.82 UC1.AJ62
  BOTTOM w0.081: 110.62,66.73 110.62,66.72 110.61,66.7
  BOTTOM w0.102: v2(108.48,63.69) 108.28,63.69 108.07,63.9 108.07,64.17 109.73,65.82 109.78,65.82 110.15,66.19 110.15,66.24 110.61,66.7 ; JDIMM1.137 101,26.91 100.8,27.11 100.8,27.35 100.42,27.73 100.42,28.9 100.55,29.03 100.77,29.03 100.88,28.92 v2(100.88,28.67)
DDR_A_DQS1: length 85
  IN4 w0.091: v2(61.12,20.49) 60.91,20.7 60.61,20.7 60,21.32 60,24.73 60.43,25.16 60.43,30.52 84.8,54.89 100.83,54.89 101.37,55.43 104.14,55.43 111.45,62.74 111.45,63.2 111.16,63.49 v2(110.95,63.49)
  BOTTOM w0.076: UC1.AN61 114.02,64.62 113.78,64.62 113.62,64.78 113.2,64.78 113.04,64.85 112.84,64.85 112.7,64.79 112.68,64.78 112.41,64.78 112.41,64.77 111.38,64.77 110.82,64.21 110.82,63.85 110.95,63.72 v2(110.95,63.49)
  BOTTOM w0.102: JDIMM1.12 61.1,18.81 61.07,18.84 61.07,19.09 60.31,19.86 60.31,20.52 60.49,20.71 60.9,20.71 v2(61.12,20.49)
DDR_A_DQS2: length 55
  IN1 w0.091: v2(115.39,64.24) 115.39,64.37 115.28,64.48 114.97,64.48 114.33,63.84 114.33,62.06 113.02,60.74 113.02,60.18 110.21,57.37 110.21,55.62 108.96,54.37 108.96,44.04 106.69,41.77 106.69,25.01 106.97,24.73 106.97,23.34 107.08,23.24 107.76,23.24 107.99,23.01 107.99,22.44 107.76,22.21 106.87,22.21 106.77,22.11 106.77,20.83 106.58,20.64 106.07,20.64 105.99,20.56 v2(105.99,20.28)
  BOTTOM w0.081: UC1.AN58 115.71,64.56 v2(115.39,64.24)
  BOTTOM w0.102: JDIMM1.154 106.1,18.71 105.78,19.03 105.78,19.15 105.48,19.46 105.48,20.42 105.61,20.56 105.71,20.56 v2(105.99,20.28)
DDR_A_DQS3: length 80.8
  IN4 w0.091: v2(66.05,28.67) 66.05,28.86 66.23,29.05 66.66,29.05 66.87,29.26 66.87,29.93 66.62,30.18 66.62,30.67 67.15,31.19 67.34,31.19 67.58,31.43 67.58,31.64 85.82,49.88 87.11,49.88 87.35,50.12 87.35,51.14 87.47,51.27 87.72,51.27 87.84,51.14 87.84,50.08 88.04,49.88 88.5,49.88 88.69,50.08 88.69,51.18 88.78,51.27 89.09,51.27 89.19,51.18 89.19,50.08 89.38,49.88 89.84,49.88 90.03,50.08 90.03,51.18 90.12,51.27 105.74,51.27 110.71,56.24 110.71,56.6 114.29,60.17 115.75,60.17 117.82,62.25 117.82,64.48 117.89,64.55 117.89,64.81 117.97,64.89 v2(118.24,64.89)
  BOTTOM w0.081: v2(118.24,64.89) 118.01,64.89 UC1.AN55
  BOTTOM w0.102: JDIMM1.29 66.2,26.92 65.97,27.15 65.97,27.41 65.72,27.66 65.48,27.66 65.33,27.8 65.33,28.83 65.46,28.96 65.96,28.96 66.05,28.88 v2(66.05,28.67)
DDR_A_DQS4: length 48.5
  IN1 w0.091: v2(112.69,57.28) 112.93,57.28 113.14,57.06 113.14,56.35 112.19,55.4 112.19,52.63 112.63,52.18 112.63,41.65 112,41.02 112,39.75 111.91,39.66 111.63,39.66 111.4,39.43 111.4,39.04 111.63,38.81 111.91,38.81 112,38.72 112,38.41 111.91,38.32 111.55,38.32 111.32,38.09 111.32,37.7 111.55,37.47 111.91,37.47 112,37.38 112,37.07 111.91,36.98 111.55,36.98 111.32,36.75 111.32,36.36 111.55,36.13 111.91,36.13 112,36.04 112,35.73 111.91,35.63 111.55,35.63 111.32,35.41 111.32,35.02 111.55,34.79 111.91,34.79 112,34.7 112,34.38 111.91,34.29 111.55,34.29 111.32,34.07 111.32,33.68 111.55,33.45 111.91,33.45 112,33.36 112,33.04 111.91,32.95 111.55,32.95 111.32,32.72 111.32,32.34 111.55,32.11 111.91,32.11 112,32.02 112,31.7 111.91,31.61 111.55,31.61 111.32,31.38 111.32,31 111.55,30.77 111.91,30.77 112,30.68 112,29.24 111.9,29.14 111.75,29.14 v2(111.45,29.44)
  BOTTOM w0.076: UC1.AW57 116.48,61.3 116.4,61.38 116.32,61.38 116.23,61.3 116.19,61.19 116.19,61.06 116.26,60.89 116.26,60.7 116.24,60.65 116.24,60.65 116.2,60.56 116.19,60.54 116.19,60.41 116.21,60.35 116.24,60.3 116.24,60.3 116.26,60.25 116.26,59.96 116.02,59.72 116.02,59.17 114.88,58.04 114.64,58.04 113.76,57.16 113.23,57.16 113.07,57.32 112.73,57.32 v2(112.69,57.28)
  BOTTOM w0.102: JDIMM1.171 111.2,26.93 111.05,27.08 111.05,27.25 111.11,27.31 111.78,27.31 112.15,27.68 112.15,28.91 111.91,29.15 111.74,29.15 v2(111.45,29.44)
DDR_A_DQS5: length 76.6
  IN4 w0.091: v2(72.19,28.67) 72.19,28.92 72.06,29.05 71.81,29.05 71.61,29.25 71.61,31.02 87.2,46.61 97.65,46.61 97.77,46.73 97.77,47.1 98,47.33 98.39,47.33 98.62,47.1 98.62,46.73 98.74,46.61 98.99,46.61 99.11,46.73 99.11,47.76 99.34,47.99 99.73,47.99 99.96,47.76 99.96,46.73 100.08,46.61 100.33,46.61 100.46,46.73 100.46,47.8 100.65,47.99 101.11,47.99 101.3,47.8 101.3,46.73 101.43,46.61 101.67,46.61 101.8,46.73 101.8,47.8 101.99,47.99 102.45,47.99 102.64,47.8 102.64,47.35 102.77,47.22 103.01,47.22 103.14,47.35 103.14,47.8 103.33,47.99 107.4,47.99 112.45,53.04 112.45,53.3 116.71,57.57 117.15,57.57 117.53,57.19 117.67,57.19 v2(117.8,57.32)
  BOTTOM w0.076: UC1.AW53 118.69,60.91 118.69,60.7 118.67,60.65 118.67,60.65 118.63,60.56 118.62,60.54 118.62,60.4 118.64,60.35 118.66,60.3 118.67,60.3 118.67,60.3 118.69,60.25 118.69,59.94 118.44,59.68 118.44,59.55 118.3,59.41 118.3,58.59 117.93,58.22 117.93,58.09 117.38,57.54 117.38,57.38 117.51,57.25 117.73,57.25 v2(117.8,57.32)
  BOTTOM w0.102: v2(72.19,28.67) 71.93,28.93 71.62,28.93 71.36,28.68 71.36,27.22 71.6,26.98 JDIMM1.47
DDR_A_DQS6: length 83.5
  IN4 w0.091: v2(125.81,65.59) 125.64,65.59 125.43,65.38 125.43,64.84 124.81,64.22 123.98,64.22 123.56,63.79 123.56,62.65 123.3,62.39 122.67,62.39 122.16,61.89 122.16,57.62 121.79,57.25 120.38,57.25 117.24,54.11 117.24,52.27 107.92,42.95 93.77,42.95 93.04,42.22 87.99,42.22 77.31,31.54 77.31,23.89 78.02,23.18 78.02,20.99 77.82,20.79 77.53,20.79 v2(77.23,20.49)
  BOTTOM w0.081: UC1.AL42 126.08,65.86 v2(125.81,65.59)
  BOTTOM w0.102: JDIMM1.64 76.7,18.79 76.49,19.01 76.49,20.62 76.67,20.8 76.92,20.8 v2(77.23,20.49)
DDR_A_DQS7: length 56.7
  IN1 w0.091: v2(121.05,65.56) 121.42,65.19 121.42,64.75 121.21,64.54 120.55,64.54 120.18,64.18 119.91,64.18 119.33,63.59 119.33,61.98 119.44,61.87 119.44,61.84 119.45,61.83 119.45,56.76 119.44,56.75 119.44,56.49 116.97,54.02 116.97,37.05 117.24,36.78 117.24,24.2 117.11,24.07 116.25,24.07 116.02,23.84 116.02,23.26 116.25,23.03 117.01,23.03 117.14,22.91 117.14,22.54 117.01,22.42 115.59,22.42 115.32,22.14 115.32,21 115.59,20.72 116.33,20.72 116.58,20.48 v2(116.58,20.28)
  BOTTOM w0.081: v2(121.05,65.56) 121.35,65.86 UC1.AL49
  BOTTOM w0.102: v2(116.58,20.28) 116.58,20.49 116.46,20.61 116.27,20.61 116.09,20.43 116.09,19.1 116.3,18.9 JDIMM1.188
DDR_A_DQS#0: length 59.5
  IN1 w0.091: v2(108.03,63.27) 108.08,63.27 108.61,62.74 108.61,62.29 107.85,61.54 107.85,59.6 105.24,56.99 105.24,45.57 102.3,42.63 102.3,42.08 102.18,41.96 101.63,41.96 101.4,41.73 101.4,41.32 101.62,41.09 102.23,41.09 102.36,40.97 102.36,40.72 102.23,40.6 101.52,40.6 101.29,40.37 101.29,39.98 101.52,39.75 102.23,39.75 102.36,39.63 102.36,39.38 102.23,39.25 101.1,39.25 100.87,39.03 100.87,38.64 101.1,38.41 102.23,38.41 102.36,38.28 102.36,38.04 102.23,37.91 101.1,37.91 100.87,37.68 100.87,37.3 101.1,37.07 102.18,37.07 102.31,36.94 102.31,36.7 102.18,36.57 101.59,36.57 101.4,36.38 101.4,29.3 101.32,29.23 101.09,29.23 v2(100.88,29.44)
  BOTTOM w0.076: UC1.AJ61 114.09,66.82 114.01,66.91 114.01,67.06 113.92,67.15 113.86,67.21 113.69,67.29 113.49,67.29 113.43,67.26 113.32,67.21 113.2,67.21 113.16,67.23 113.16,67.23 113.04,67.28 112.84,67.28 112.79,67.26 112.79,67.26 112.68,67.21 110.86,67.21 110.5,66.85
  BOTTOM w0.081: 110.47,66.84 110.49,66.85 110.5,66.85
  BOTTOM w0.102: v2(108.03,63.27) 108.03,63.66 107.88,63.82 107.88,64.25 v4(109.82,66.19) 110.47,66.84 ; v2(100.88,29.44) 100.67,29.22 100.47,29.22 100.23,28.98 100.23,27.65 100.61,27.27 100.61,27.1 100.4,26.9 JDIMM1.135
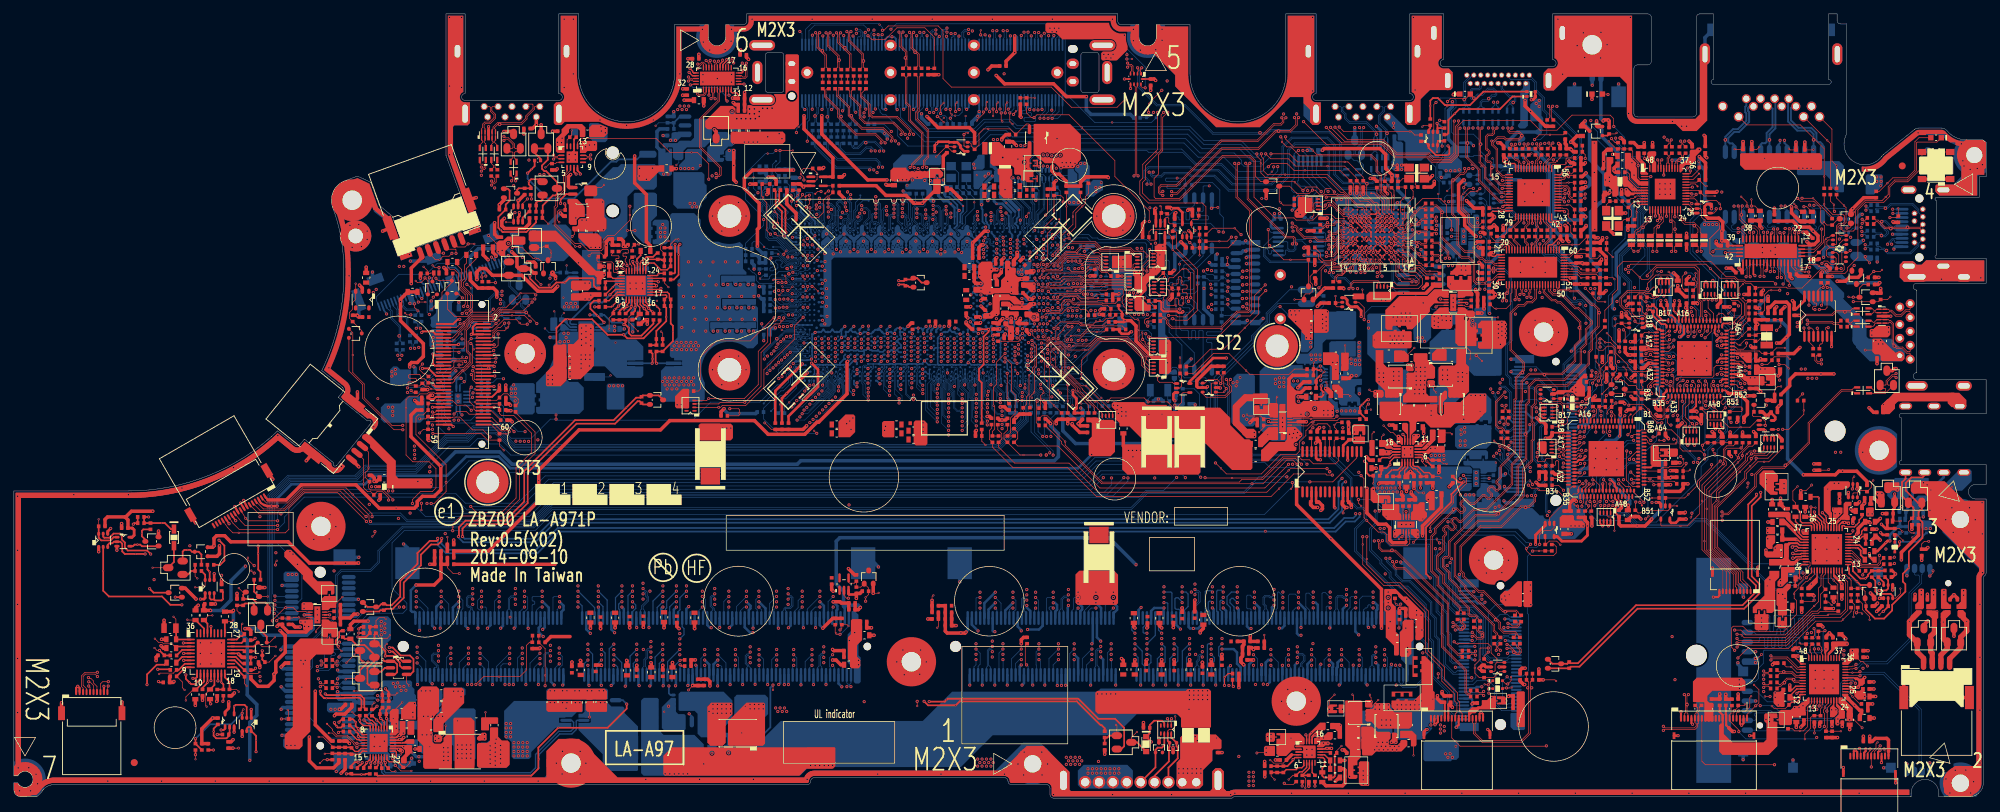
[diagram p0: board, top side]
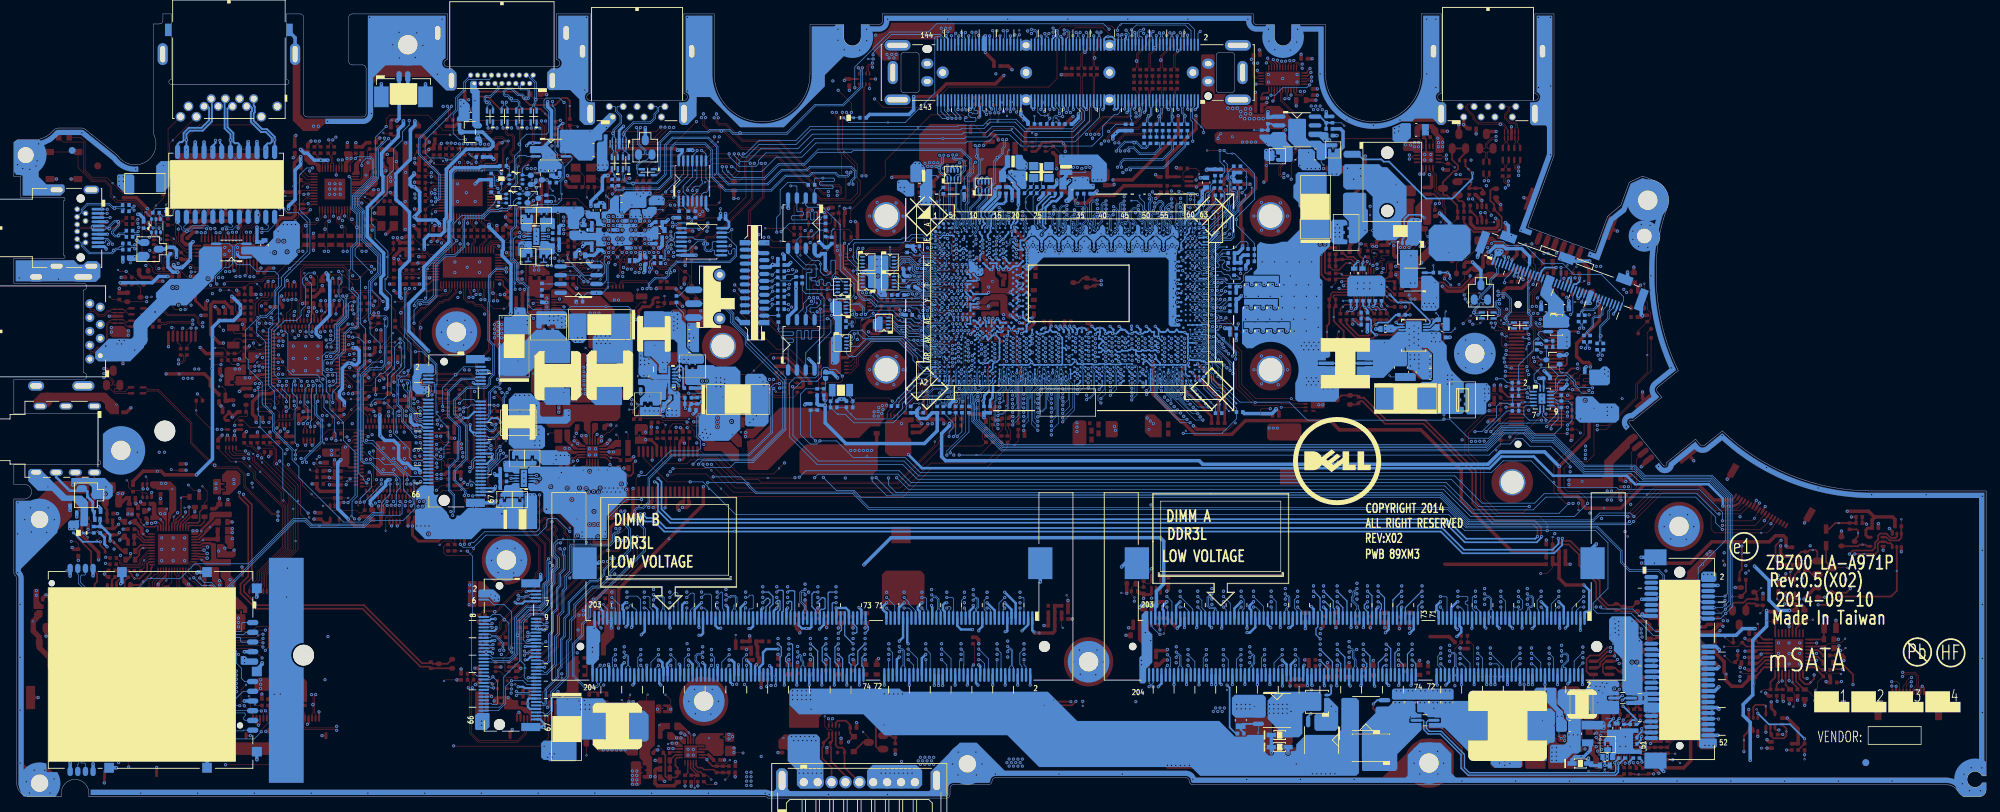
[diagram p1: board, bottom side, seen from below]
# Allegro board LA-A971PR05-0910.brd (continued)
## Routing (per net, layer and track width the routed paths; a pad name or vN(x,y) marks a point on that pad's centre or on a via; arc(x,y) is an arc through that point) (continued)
DDR_A_DQS#1: length 84.9
  IN4 w0.091: v2(61.12,21.25) 61.12,20.99 61,20.87 60.68,20.87 60.17,21.39 60.17,24.65 60.6,25.09 60.6,30.45 84.87,54.72 100.9,54.72 101.44,55.26 104.21,55.26 111.62,62.67 111.62,63.27 111.3,63.59 111.3,63.84 v2(111.34,63.87)
  BOTTOM w0.076: v2(111.34,63.87) 111.05,63.87 111,63.93 111,64.14 111.47,64.61 112.71,64.61 112.76,64.64 112.85,64.68 112.88,64.69 113.01,64.69 113.03,64.68 113.11,64.64 113.17,64.61 113.53,64.61 113.64,64.51 113.64,64.44 UC1.AN62
  BOTTOM w0.102: JDIMM1.10 60.5,18.79 60.56,18.84 60.81,18.84 60.88,18.91 60.88,19.01 60.11,19.78 60.11,20.6 60.41,20.9 61.02,20.9 61.12,21 v2(61.12,21.25)
DDR_A_DQS#2: length 54.9
  IN1 w0.091: v2(105.99,21.04) 106.22,20.81 106.51,20.81 106.6,20.91 106.6,22.18 106.8,22.38 107.69,22.38 107.81,22.51 107.81,22.94 107.69,23.06 107.01,23.06 106.8,23.27 106.8,24.65 106.52,24.94 106.52,41.85 108.79,44.11 108.79,54.44 110.04,55.69 110.04,57.44 112.84,60.25 112.84,60.82 114.16,62.13 114.16,63.91 114.9,64.65 115.15,64.65 v2(115.39,64.89)
  BOTTOM w0.081: UC1.AM58 115.71,65.21 v2(115.39,64.89)
  BOTTOM w0.102: JDIMM1.152 105.5,18.83 105.59,18.92 105.59,19.07 105.27,19.39 105.27,20.51 105.53,20.76 105.71,20.76 v2(105.99,21.04)
DDR_A_DQS#3: length 80.8
  IN4 w0.091: v2(66.05,29.44) 66.26,29.22 66.59,29.22 66.7,29.33 66.7,29.86 66.45,30.11 66.45,30.74 67.07,31.36 67.26,31.36 67.4,31.5 67.4,31.71 85.75,50.06 87.04,50.06 87.17,50.19 87.17,51.21 87.4,51.44 87.79,51.44 88.02,51.21 88.02,50.15 88.11,50.06 88.42,50.06 88.52,50.15 88.52,51.25 88.71,51.44 89.17,51.44 89.36,51.25 89.36,50.15 89.45,50.06 89.77,50.06 89.86,50.15 89.86,51.25 90.05,51.44 105.66,51.44 110.54,56.32 110.54,56.67 114.22,60.34 115.68,60.34 117.65,62.32 117.65,64.55 117.72,64.62 117.72,64.94 117.64,65.01 117.42,65.01 v2(117.29,64.89)
  BOTTOM w0.081: UC1.AM55 117.68,65.08 117.48,64.89 v2(117.29,64.89)
  BOTTOM w0.102: JDIMM1.27 65.6,26.96 65.78,27.14 65.78,27.33 65.64,27.47 65.4,27.47 65.14,27.72 65.14,28.91 65.38,29.15 65.96,29.15 66.05,29.24 v2(66.05,29.44)
DDR_A_DQS#4: length 48.5
  IN1 w0.091: v2(111.45,28.67) 111.74,28.97 111.97,28.97 112.18,29.17 112.18,30.75 111.98,30.94 111.62,30.94 111.5,31.07 111.5,31.31 111.62,31.44 111.98,31.44 112.18,31.63 112.18,32.09 111.98,32.28 111.62,32.28 111.5,32.41 111.5,32.65 111.62,32.78 111.98,32.78 112.18,32.97 112.18,33.43 111.98,33.62 111.62,33.62 111.5,33.75 111.5,33.99 111.62,34.12 111.98,34.12 112.18,34.31 112.18,34.77 111.98,34.96 111.62,34.96 111.5,35.09 111.5,35.33 111.62,35.46 111.98,35.46 112.18,35.65 112.18,36.11 111.98,36.3 111.62,36.3 111.5,36.43 111.5,36.68 111.62,36.8 111.98,36.8 112.18,37 112.18,37.45 111.98,37.65 111.62,37.65 111.5,37.77 111.5,38.02 111.62,38.14 111.98,38.14 112.18,38.34 112.18,38.79 111.98,38.99 111.7,38.99 111.57,39.11 111.57,39.36 111.7,39.49 111.98,39.49 112.18,39.68 112.18,40.95 112.81,41.57 112.81,52.26 112.36,52.7 112.36,55.33 113.32,56.28 113.32,57.13 113.03,57.42 113.03,57.62 v2(113.15,57.74)
  BOTTOM w0.076: UC1.AV57 116.48,61.62 116.4,61.54 116.25,61.54 116.16,61.45 116.1,61.39 116.02,61.23 116.02,61.03 116.05,60.96 116.1,60.86 116.1,60.73 116.08,60.69 116.08,60.69 116.02,60.58 116.02,60.37 116.05,60.32 116.05,60.32 116.1,60.21 116.1,60.03 115.85,59.78 115.85,59.26 114.81,58.22 114.56,58.22 113.69,57.34 113.31,57.34 113.15,57.5 v2(113.15,57.74)
  BOTTOM w0.102: v2(111.45,28.67) 111.73,28.95 111.83,28.95 111.96,28.83 111.96,27.76 111.7,27.5 111.03,27.5 110.86,27.33 110.86,27.15 110.6,26.89 JDIMM1.169
DDR_A_DQS#5: length 76.7
  IN4 w0.091: v2(72.19,29.44) 71.97,29.22 71.89,29.22 71.79,29.32 71.79,30.95 87.27,46.43 97.72,46.43 97.95,46.66 97.95,47.03 98.07,47.15 98.32,47.15 98.44,47.03 98.44,46.66 98.67,46.43 99.06,46.43 99.29,46.66 99.29,47.69 99.41,47.82 99.66,47.82 99.78,47.69 99.78,46.66 100.01,46.43 100.4,46.43 100.63,46.66 100.63,47.73 100.72,47.82 101.03,47.82 101.13,47.73 101.13,46.66 101.35,46.43 101.74,46.43 101.97,46.66 101.97,47.73 102.06,47.82 102.38,47.82 102.47,47.73 102.47,47.27 102.7,47.05 103.08,47.05 103.31,47.27 103.31,47.73 103.4,47.82 107.47,47.82 112.62,52.97 112.62,53.23 116.78,57.4 117.08,57.4 117.34,57.14 v2(117.34,56.86)
  BOTTOM w0.076: v2(117.34,56.86) 117.34,57.18 117.21,57.31 117.21,57.61 117.76,58.16 117.76,58.3 118.13,58.66 118.13,59.48 118.28,59.63 118.28,59.75 118.53,60 118.53,60.2 118.49,60.29 118.45,60.37 118.45,60.58 118.51,60.69 118.51,60.69 118.53,60.73 118.53,61.22 118.64,61.33 118.64,61.5 UC1.AV53
  BOTTOM w0.102: JDIMM1.45 71,27.04 71.17,27.22 71.17,28.76 71.54,29.13 71.88,29.13 v2(72.19,29.44)
DDR_A_DQS#6: length 83.5
  IN4 w0.091: v2(77.23,21.25) 77.52,20.96 77.74,20.96 77.85,21.06 77.85,23.11 77.13,23.82 77.13,31.61 87.92,42.4 92.97,42.4 93.69,43.12 107.85,43.12 117.07,52.34 117.07,54.18 120.31,57.42 121.72,57.42 121.99,57.7 121.99,61.96 122.6,62.57 123.23,62.57 123.38,62.72 123.38,63.86 123.91,64.39 124.73,64.39 125.26,64.91 125.26,65.39 124.98,65.66 v2(124.86,65.66)
  BOTTOM w0.081: v2(124.86,65.66) 125.05,65.86 UC1.AL43
  BOTTOM w0.102: JDIMM1.62 76.1,18.81 76.3,19.01 76.3,20.7 76.59,21 76.97,21 v2(77.23,21.25)
DDR_A_DQS#7: length 56.7
  IN1 w0.091: v2(122,65.54) 121.94,65.6 121.55,65.6 121.48,65.52 121.48,65.38 121.59,65.26 121.59,64.68 121.28,64.37 120.62,64.37 120.26,64.01 119.98,64.01 119.5,63.52 119.5,62.07 119.61,61.96 119.61,61.91 119.62,61.9 119.62,56.69 119.61,56.68 119.61,56.41 117.15,53.95 117.15,37.12 117.41,36.85 117.41,24.13 117.18,23.89 116.32,23.89 116.19,23.77 116.19,23.33 116.32,23.21 117.08,23.21 117.31,22.98 117.31,22.47 117.08,22.24 115.66,22.24 115.49,22.07 115.49,21.07 115.66,20.89 116.43,20.89 v2(116.58,21.04)
  BOTTOM w0.081: v2(122,65.54) 122.32,65.86 UC1.AL48
  BOTTOM w0.102: v2(116.58,21.04) 116.58,20.98 116.41,20.8 116.19,20.8 115.9,20.51 115.9,19.02 115.7,18.82 JDIMM1.186
DDR_A_MA0: length 74.2
  IN4 w0.084: 126.77,51.37 126.77,51.64
  IN4 w0.089: 126.77,51.64 126.92,51.79 126.92,54.17 128.68,55.93 128.68,61.32 v2(129.24,61.89)
  IN4 w0.132: 126.77,51.37 126.77,49.07 125.8,48.1 124.31,48.1 110.77,34.56 92.4,34.56 88.62,30.77 88.62,26.19 90.09,24.73 90.09,20.32 v2(89.66,19.9)
  BOTTOM w0.081: v2(129.24,61.89) 129.46,62.1 UC1.AU36
  BOTTOM w0.17: JDIMM1.98 89.3,18.78 89.16,18.92 89.16,19.4 v2(89.66,19.9)
DDR_A_MA1: length 74.9
  IN4 w0.084: 127.59,51.37 127.59,54.16
  IN4 w0.089: 127.59,54.16 129.06,55.63 129.06,58.94 v2(129.24,59.12)
  IN4 w0.132: v2(89.05,28.29) 89.34,28.29 89.47,28.17 89.47,26.34 89.6,26.22 89.96,26.22 90.09,26.08 90.09,25.31 90.22,25.18 90.5,25.18 90.63,25.31 90.63,26.08 90.76,26.22 91.05,26.22 91.17,26.09 91.17,25.31 91.3,25.18 91.62,25.18 91.75,25.31 91.75,26.63 91.62,26.75 90.18,26.75 90.05,26.88 90.05,31.04 92.75,33.73 111.11,33.73 121.29,43.92 121.58,43.92 122.02,43.47 122.34,43.47 127.59,48.73 127.59,51.37
  BOTTOM w0.081: v2(129.24,59.12) 128.82,59.54 UC1.AY37
  BOTTOM w0.17: JDIMM1.97 89,26.82 89.51,27.34 89.51,27.83 v2(89.05,28.29)
DDR_A_MA2: length 77.6
  IN4 w0.089: 126.11,53.12 126.11,54.28 128.15,56.31 128.15,57.89 127.31,58.72 127.31,59.69 127.65,60.03 127.7,60.03 128.22,60.55 v2(128.22,62.94)
  IN4 w0.132: v2(89.66,21.42) 87.77,23.31 87.38,23.31 86.97,23.72 86.97,26.71 86.45,27.23 86.45,31.32 87.76,32.63 88.74,32.63 91.89,35.79 110.26,35.79 124.19,49.73 124.19,52.11 124.59,52.51 125.5,52.51 126.11,53.12
  BOTTOM w0.081: v2(128.22,62.94) 128.54,63.26 UC1.AR38
  BOTTOM w0.17: v2(89.66,21.42) 88.7,20.46 JDIMM1.96
DDR_A_MA3: length 75.8
  IN4 w0.089: v2(129.17,63.74) 129.57,63.34 129.57,62.71 129.65,62.62 129.65,61.73 129.42,61.49 129.11,61.49 128.86,61.24 128.86,55.78 127.36,54.28
  IN4 w0.132: v2(89.05,29.82) 89.3,29.57 89.52,29.57 89.64,29.68 89.64,31.21 92.57,34.14 110.94,34.14 121.44,44.64 121.62,44.64 122.18,44.08 122.36,44.08 122.57,44.28 122.57,44.46 122,45.02 122,45.21 122.2,45.4 122.38,45.4 122.95,44.84 123.13,44.84 123.33,45.04 123.33,45.22 122.77,45.78 122.77,45.97 122.96,46.16 123.15,46.16 123.71,45.6 123.89,45.6 124.09,45.8 124.09,45.98 123.53,46.55 123.53,46.73 123.72,46.93 123.91,46.93 124.47,46.37 124.65,46.37 124.85,46.57 124.85,46.75 124.29,47.31 124.29,47.49 124.48,47.69 124.67,47.69 125.23,47.13 125.41,47.13 127.18,48.9 127.18,54.1 127.36,54.28
  BOTTOM w0.081: v2(129.17,63.74) 129.34,63.91 UC1.AP36
  BOTTOM w0.17: v2(89.05,29.82) 88.4,29.17 JDIMM1.95
DDR_A_MA4: length 75.4
  IN4 w0.089: v2(127.66,61.85) 126.95,61.15 126.95,58.57 127.79,57.73 127.79,56.77 123.37,52.35
  IN4 w0.132: 123.37,52.35 123.37,50.07 109.92,36.61 91.55,36.61 88.39,33.46 87.42,33.46 85.52,31.56 85.52,20.79 85.65,20.66 v2(86.36,20.66)
  BOTTOM w0.081: UC1.AU39 127.91,62.1 v2(127.66,61.85)
  BOTTOM w0.17: JDIMM1.92 87.5,19.52 v2(86.36,20.66)
DDR_A_MA5: length 76.7
  IN4 w0.084: 126.36,51.67 126.36,51.37
  IN4 w0.089: 126.36,51.67 126.67,51.98 126.67,54.23 128.5,56.06 128.5,62.18 129.17,62.85 v2(129.17,63.09)
  IN4 w0.132: v2(87.52,28.29) 87.1,27.87 87.1,27.16 87.42,26.84 87.42,23.85 87.55,23.72 88.08,23.72 88.21,23.85 88.21,30.94 92.23,34.97 110.6,34.97 124.14,48.51 125.63,48.51 126.36,49.24 126.36,51.37
  BOTTOM w0.081: v2(129.17,63.09) 129.34,63.26 UC1.AR36
  BOTTOM w0.17: v2(87.52,28.29) 87.4,28.29 87.06,27.94 87.06,27.28 87.2,27.14 JDIMM1.91
DDR_A_MA6: length 76.2
  IN4 w0.089: v2(127.43,56.93) 127.43,56.83 122.96,52.36
  IN4 w0.132: 122.96,52.36 122.96,50.24 109.74,37.02 91.38,37.02 88.22,33.87 87.25,33.87 85.11,31.73 85.11,20.37 85.23,20.25 85.81,20.25 85.94,20.12 85.94,19.81 85.81,19.68 85.2,19.68 85.08,19.56 85.08,19.26 85.2,19.13 v2(86.36,19.13)
  BOTTOM w0.076: UC1.AV40 126.95,61.16 126.95,58.87 127.85,57.98 127.85,57.35 v2(127.43,56.93)
  BOTTOM w0.17: JDIMM1.90 86.9,18.9 86.66,19.13 v2(86.36,19.13)
DDR_A_MA7: length 75.7
  IN4 w0.089: 123.78,51.85 123.78,52.44 127.97,56.62 127.97,57.81 127.13,58.65 127.13,59.98 v2(127.66,60.5)
  IN4 w0.132: v2(86.36,22.18) 87.55,22.18 87.68,22.31 87.68,22.71 87.55,22.83 86.06,22.83 85.93,22.96 85.93,31.39 87.59,33.05 88.56,33.05 91.72,36.2 110.09,36.2 123.78,49.9 123.78,51.85
  BOTTOM w0.081: UC1.AW39 127.95,60.8 v2(127.66,60.5)
  BOTTOM w0.17: v2(86.36,22.18) 85.7,21.53 JDIMM1.86
DDR_A_MA8: length 74.1
  IN4 w0.089: 126.23,52.17 126.39,52.34 126.39,54.25 128.32,56.18 128.32,59.34 128.12,59.55 v2(127.67,59.55)
  IN4 w0.132: v2(87.52,29.82) 87.52,29.59 87.4,29.46 86.97,29.46 86.86,29.58 86.86,31.15 87.17,31.46 87.35,31.46 87.65,31.17 87.83,31.17 88.03,31.36 88.03,31.55 87.73,31.84 87.73,32.03 87.93,32.22 88.12,32.22 88.41,31.93 88.61,31.93 92.06,35.38 110.43,35.38 123.97,48.92 125.46,48.92 125.59,49.05 125.59,49.33 125.46,49.46 124.73,49.46 124.61,49.59 124.61,49.87 124.73,50 125.82,50 125.95,50.13 125.95,50.41 125.82,50.54 124.73,50.54 124.61,50.67 124.61,50.95 124.73,51.08 125.81,51.08 125.95,51.21 125.95,51.48 125.81,51.62 124.73,51.62 124.61,51.74 124.61,52.04 124.73,52.17 126.23,52.17
  BOTTOM w0.081: v2(127.67,59.55) 127.67,59.75 UC1.AY39
  BOTTOM w0.17: v2(87.52,29.82) 86.6,28.89 JDIMM1.89
DDR_A_MA9: length 75.6
  IN4 w0.089: v2(127.43,57.56) 127.43,57.82 127.3,57.95 127.11,57.95 126.98,57.82 126.98,56.81 122.55,52.38
  IN4 w0.132: v2(84.12,29.82) 84.12,29.58 84.25,29.46 84.57,29.46 84.7,29.58 84.7,30.71 84.19,31.22 84.19,31.39 87.37,34.58 87.55,34.58 87.85,34.28 88.02,34.28 88.23,34.48 88.23,34.66 87.93,34.95 87.93,35.14 88.13,35.33 88.32,35.33 88.62,35.03 88.8,35.03 89,35.23 89,35.41 88.7,35.71 88.7,35.9 88.89,36.1 89.08,36.1 89.38,35.79 89.56,35.79 89.76,35.99 89.76,36.17 89.45,36.48 89.45,36.66 89.66,36.87 89.84,36.87 90.16,36.55 90.32,36.55 91.21,37.44 106.39,37.44 106.52,37.56 106.52,38.01 106.65,38.14 106.93,38.14 107.06,38.01 107.06,37.56 107.19,37.44 107.47,37.44 107.6,37.56 107.6,38.01 107.73,38.14 108,38.14 108.14,38.01 108.14,37.56 108.26,37.44 108.55,37.44 108.68,37.56 108.68,38.01 108.81,38.14 109.08,38.14 109.21,38.01 109.21,37.61 109.34,37.49 109.63,37.49 109.75,37.61 109.75,38.01 109.88,38.14 110.28,38.14 122.55,50.41 122.55,52.38
  BOTTOM w0.076: v2(127.43,57.56) 126.79,58.2 126.79,61.32 126.79,61.33 126.79,61.41 127.2,61.81 UC1.AU40
  BOTTOM w0.17: JDIMM1.85 85.4,28.54 v2(84.12,29.82)
DDR_A_MA10: length 75.4
  IN4 w0.089: v2(130.12,63.59) 129.83,63.59 129.75,63.51 129.75,62.78 129.93,62.6 129.93,60.32 130.43,59.82 130.43,58.11 130.53,58.01 130.53,55.09 129.47,54.03 129.47,51.37
  IN4 w0.132: 129.47,51.37 129.47,47.95 119.65,38.12 119.46,38.12 119.12,38.46 118.94,38.46 118.74,38.26 118.74,38.08 119.08,37.74 119.08,37.56 118.89,37.36 118.7,37.36 118.14,37.92 117.96,37.92 117.76,37.72 117.76,37.54 118.32,36.98 118.32,36.79 118.13,36.6 117.94,36.6 117.38,37.16 117.2,37.16 117,36.96 117,36.78 117.56,36.22 117.56,36.03 117.36,35.84 117.18,35.84 116.61,36.4 116.44,36.4 116.23,36.2 116.23,36.02 116.8,35.46 116.8,35.27 116.6,35.08 116.41,35.08 115.85,35.64 115.67,35.64 115.47,35.44 115.47,35.26 116.03,34.69 116.03,34.51 115.84,34.31 115.65,34.31 115.09,34.87 114.91,34.87 111.89,31.85 94.8,31.85 93.97,31.03 93.97,29.61 93.82,29.46 93.55,29.46 93.42,29.59 v2(93.42,29.82)
  BOTTOM w0.081: v2(130.12,63.59) 130.45,63.91 UC1.AP35
  BOTTOM w0.17: JDIMM1.107 92,28.4 v2(93.42,29.82)
DDR_A_MA11: length 74.6
  IN4 w0.089: v2(126.09,60.49) 126.6,59.99 126.6,57.24 121.73,52.37
  IN4 w0.132: 121.73,52.37 121.73,50.79 109.9,38.97 106.31,38.97 105.61,38.26 89.89,38.26 82.92,31.29 82.92,25.15 83.05,25.03 83.9,25.03 84.03,24.9 84.03,21.5 84.11,21.42 v2(84.58,21.42)
  BOTTOM w0.081: UC1.AW41 126.4,60.8 v2(126.09,60.49)
  BOTTOM w0.17: v2(84.58,21.42) 85.1,20.9 JDIMM1.84
DDR_A_MA12: length 74.9
  IN4 w0.089: v2(126.08,61.79) 126.77,61.09 126.77,57.01 122.14,52.37
  IN4 w0.132: v2(84.12,28.29) 84.57,28.29 84.7,28.17 84.7,27.24 84.57,27.11 84,27.11 83.87,26.98 83.87,26.64 84,26.51 84.56,26.51 84.7,26.38 84.7,26.1 84.56,25.97 84,25.97 83.87,25.84 83.87,25.56 83.74,25.44 83.46,25.44 83.33,25.56 83.33,31.12 90.06,37.85 105.78,37.85 106.48,38.55 110.07,38.55 122.14,50.62 122.14,52.37
  BOTTOM w0.081: UC1.AU41 126.39,62.1 v2(126.08,61.79)
  BOTTOM w0.17: JDIMM1.83 84.8,27.62 v2(84.12,28.29)
DDR_A_MA13: length 75.9
  IN4 w0.089: 130.71,51.37 130.71,52.02 131.4,52.71 131.4,59.46 130.97,59.89 130.86,59.89 130.2,60.55 130.2,62.86 v2(130.12,62.94)
  IN4 w0.132: 130.71,51.37 130.71,47.43 113.89,30.62 105.12,30.62 105,30.49 105,29.31 104.87,29.18 104.59,29.18 104.46,29.31 104.46,30.49 104.33,30.62 104.05,30.62 103.92,30.49 103.92,29.31 103.79,29.18 103.51,29.18 103.38,29.31 103.38,30.49 103.26,30.62 102.1,30.62 101.97,30.49 101.97,29.25 101.85,29.12 101.56,29.12 101.43,29.25 101.43,30.49 101.3,30.62 100.33,30.62 100.19,30.49 100.19,29.25 100.07,29.12 99.78,29.12 99.66,29.25 99.66,30.49 99.52,30.62 98.81,30.62 98.68,30.49 98.68,29.31 98.55,29.18 98.27,29.18 98.14,29.31 98.14,30.49 98.02,30.62 97.65,30.62 97.52,30.49 97.52,29.94 97.4,29.82 v2(96.82,29.82)
  BOTTOM w0.081: v2(130.12,62.94) 130.45,63.26 UC1.AR35
  BOTTOM w0.17: JDIMM1.119 95.6,26.85 95.88,27.13 95.88,28.87 v2(96.82,29.82)
DDR_A_MA14: length 74.9
  IN4 w0.089: 121.31,52.36 126.42,57.47 126.42,58.33 v2(126.05,58.69)
  IN4 w0.132: v2(84.58,19.9) 83.62,20.86 83.62,22.51 82.51,23.62 82.51,31.46 89.72,38.67 105.43,38.67 106.14,39.38 109.73,39.38 121.31,50.96 121.31,52.36
  BOTTOM w0.081: v2(126.05,58.69) 125.37,59.37 125.37,61.15 UC1.AV42
  BOTTOM w0.17: JDIMM1.80 83.9,19.22 v2(84.58,19.9)
DDR_A_MA15: length 75.4
  IN4 w0.089: v2(126.05,58.04) 126.05,57.51 120.9,52.36
  IN4 w0.132: v2(82.62,21.42) 83.21,22 83.21,22.34 82.1,23.45 82.1,31.63 89.55,39.08 105.26,39.08 105.97,39.79 109.56,39.79 120.9,51.13 120.9,52.36
  BOTTOM w0.081: v2(126.05,58.04) 126.05,58.03 125.2,58.88 125.2,61.32 125.3,61.41 125.3,61.59 125.62,61.91 UC1.AU42
  BOTTOM w0.17: v2(82.62,21.42) 83.3,20.74 JDIMM1.78
DDR_A_RAS#: length 75.3
  IN4 w0.132: v2(132.92,54.22) 132.92,53.16 131.94,52.17 131.94,46.92 114.73,29.71 114.73,26.93 114.07,26.28 97.29,26.28 97.17,26.15 97.17,25.14 97.04,25.01 95.33,25.01 95.2,24.88 95.2,22.29 95.08,22.16 94.48,22.16 94.36,22.03 94.36,21.75 94.48,21.62 95.08,21.62 95.2,21.49 95.2,21.21 95.08,21.08 93.97,21.08 93.84,20.95 93.84,20.67 93.97,20.54 95.08,20.54 95.2,20.42 95.2,20.08 95.08,19.95 93.46,19.95 v2(93.4,19.9)
  BOTTOM w0.081: v2(132.92,54.22) 131.22,55.92 UC1.AY34
  BOTTOM w0.17: JDIMM1.110 92.9,19.4 v2(93.4,19.9)
DDR_A_WE#: length 76.4
  IN4 w0.089: 131.12,51.37 131.12,52.11 131.83,52.82 131.83,59.82 131.15,60.49 v2(130.82,60.49)
  IN4 w0.132: 131.12,51.37 131.12,47.26 113.9,30.05 113.9,27.28 113.73,27.1 106.68,27.1 106.54,27.23 106.54,28.36 106.42,28.49 106.13,28.49 106.01,28.36 106.01,27.23 105.87,27.1 104.07,27.1 103.94,27.23 103.94,28.23 103.81,28.36 103.53,28.36 103.4,28.23 103.4,27.23 103.28,27.1 102.15,27.1 102.02,27.23 102.02,28.23 101.89,28.36 101.61,28.36 101.48,28.23 101.48,27.23 101.35,27.1 100.34,27.1 100.2,27.23 100.2,28.23 100.08,28.36 99.79,28.36 99.67,28.23 99.67,27.23 99.53,27.1 98.81,27.1 98.68,27.23 98.68,28.51 98.55,28.63 96.52,28.63 96.4,28.76 96.4,29.69 96.27,29.82 v2(95.37,29.82)
  BOTTOM w0.081: UC1.AW34 131.12,60.8 v2(130.82,60.49)
  BOTTOM w0.17: JDIMM1.113 93.8,27.25 93.97,27.42 93.97,28.42 v2(95.37,29.82)
DDR_B_BS0: length 96.6
  IN1 w0.089: 127.82,51.37 127.82,54.36 128.35,54.89 128.35,62.33 128.59,62.57 128.59,66.97 128.96,67.34 129.52,67.34 129.73,67.13 129.73,65.93 v2(130.12,65.54)
  IN1 w0.132: 127.82,51.37 127.82,47.61 140.04,35.39 166.16,35.39 167.17,34.38 168.61,34.38 170.29,32.7 170.29,32.09 171.13,31.26 171.13,29.65 170.71,29.23 170.71,28.23 170.6,28.12 169.72,28.12 169.59,28 169.59,27.71 169.72,27.59 170.58,27.59 170.71,27.46 170.71,27.17 170.58,27.05 169.72,27.05 169.59,26.92 169.59,25.7 169.72,25.57 171.01,25.57 171.14,25.44 171.14,24.06 171.4,23.8 172.07,23.8 172.33,23.53 172.68,23.53 173.47,24.32 173.47,26.11 173.35,26.24 172.67,26.24 172.54,26.36 172.54,26.79 172.1,27.23 172.1,28.04 172.23,28.17 v2(172.52,28.17)
  BOTTOM w0.081: v2(130.12,65.54) 130.45,65.86 UC1.AL35
  BOTTOM w0.17: v2(172.52,28.17) 172.32,28.37 172.07,28.37 171.93,28.23 171.93,27.17 172.1,27 JDIMM2.109
DDR_B_BS1: length 97.1
  IN1 w0.089: 128.65,51.37 128.65,54.15 129.12,54.63 129.12,58.47 129.23,58.57 129.73,58.57 129.86,58.7 129.86,61.88 129.56,62.18 129.56,64.91 129.43,65.04 v2(129.17,65.04)
  IN1 w0.132: 128.65,51.37 128.65,47.95 140.39,36.21 166.5,36.21 167.51,35.21 168.95,35.21 171.12,33.04 171.12,32.45 172.95,30.62 172.95,26.72 173.03,26.65 173.68,26.65 173.88,26.44 173.88,25.66 174.01,25.53 174.3,25.53 174.42,25.66 174.42,26.44 174.55,26.57 175.91,26.57 176.04,26.44 176.04,24.66 175.91,24.53 175.63,24.53 175.5,24.66 175.5,25.9 175.37,26.03 175.09,26.03 174.96,25.9 174.96,25.12 174.83,24.99 174.01,24.99 173.88,24.87 173.88,24.58 174.01,24.45 174.8,24.45 174.93,24.33 174.93,24.04 174.8,23.92 173.65,23.92 172.99,23.26 172.99,22 172.87,21.88 172.47,21.88 172.35,22 v2(172.35,22.24)
  BOTTOM w0.081: v2(129.17,65.04) 129.34,65.21 UC1.AM36
  BOTTOM w0.17: JDIMM2.108 171.8,22.09 171.94,22.24 v2(172.35,22.24)
DDR_B_BS2: length 92.5
  IN1 w0.089: 120.93,51.37 120.93,52.48 122.17,53.73 122.17,61.63 122.08,61.72 v2(121.37,61.72)
  IN1 w0.132: v2(163.1,23.76) 162.7,23.76 162.62,23.85 162.62,25.62 162.47,25.77 160.86,25.77 159.78,24.7 146.84,24.7 145.96,25.57 138.54,25.57 132.47,31.64 132.47,31.83 133.12,32.48 133.12,32.67 132.93,32.86 132.74,32.86 132.09,32.21 131.9,32.21 131.71,32.41 131.71,32.59 132.36,33.24 132.36,33.43 132.16,33.63 131.98,33.63 131.33,32.97 131.14,32.97 130.95,33.17 130.95,33.36 131.6,34.01 131.6,34.19 131.4,34.39 131.22,34.39 130.56,33.74 130.38,33.74 130.18,33.93 130.18,34.12 130.83,34.77 130.83,34.96 130.59,35.2 130.41,35.2 129.76,34.55 129.57,34.55 129.37,34.74 129.37,34.93 130.03,35.58 130.03,35.76 129.83,35.96 129.64,35.96 128.99,35.31 128.81,35.31 128.61,35.5 128.61,35.69 129.26,36.34 129.26,36.53 129.07,36.72 128.88,36.72 128.23,36.07 128.04,36.07 127.85,36.26 127.85,36.45 128.5,37.1 128.5,37.29 128.31,37.48 128.12,37.48 127.47,36.83 127.28,36.83 127.09,37.03 127.09,37.21 127.74,37.86 127.74,38.05 127.47,38.32 127.29,38.32 126.64,37.66 126.45,37.66 126.26,37.86 126.26,38.05 126.91,38.7 126.91,38.88 120.93,44.86 120.93,51.37
  BOTTOM w0.081: v2(121.37,61.72) 121.37,61.79 121.68,62.1 UC1.AU49
  BOTTOM w0.17: v2(163.1,23.76) 162.7,23.76 162.55,23.91 162.55,24.61 163.1,25.16 JDIMM2.79
DDR_B_CAS#: length 96.7
  IN1 w0.089: v2(131.08,64.95) 130.81,64.95 130.69,64.83 130.69,62.73 130.43,62.47 130.43,56.64 130.34,56.55 130.03,56.55 129.95,56.48 129.95,56.29 130.05,56.18 130.7,56.18 130.81,56.07 130.81,55.92 130.72,55.83 129.97,55.83 129.86,55.72 129.86,55.57 129.97,55.47 130.74,55.47 130.81,55.4 130.81,55.09 130.69,54.97 130.04,54.97 129.91,54.84 129.91,54.58 130.1,54.39 130.1,54.08 130.04,54.01 129.72,54.01 129.59,53.89 129.59,53.7 129.72,53.57 130.04,53.57 130.16,53.44 130.16,52.74 130.54,52.36 130.54,51.37
  IN1 w0.132: 130.54,51.37 130.54,47.81 139.93,38.42 144.85,38.42 144.98,38.29 144.98,37.57 145.11,37.45 145.39,37.45 145.52,37.57 145.52,38.29 145.65,38.42 145.93,38.42 146.06,38.29 146.06,37.57 146.18,37.45 146.47,37.45 146.6,37.57 146.6,38.29 146.72,38.42 147.01,38.42 147.13,38.29 147.13,37.57 147.26,37.45 147.55,37.45 147.67,37.57 147.67,38.29 147.8,38.42 148.08,38.42 148.21,38.29 148.21,37.57 148.34,37.45 148.62,37.45 148.75,37.57 148.75,38.29 148.88,38.42 149.16,38.42 149.29,38.29 149.29,37.57 149.42,37.45 149.7,37.45 149.83,37.57 149.83,38.29 149.95,38.42 150.24,38.42 150.37,38.29 150.37,37.57 150.49,37.45 150.78,37.45 150.9,37.57 150.9,38.29 151.03,38.42 151.32,38.42 151.44,38.29 151.44,37.57 151.57,37.45 151.85,37.45 151.98,37.57 151.98,38.29 152.11,38.42 152.39,38.42 152.52,38.29 152.52,37.57 152.65,37.45 167.46,37.45 167.59,37.32 167.59,36.87 167.72,36.75 168,36.75 168.13,36.87 168.13,37.32 168.25,37.45 168.54,37.45 168.67,37.32 168.67,36.57 168.79,36.44 169.54,36.44 175.26,30.72 175.26,29.95 175.68,29.53 175.68,27.57 175.5,27.39 174.69,27.39 174.08,28 v2(174.08,28.17)
  BOTTOM w0.081: v2(131.08,64.95) 131.34,65.21 UC1.AM33
  BOTTOM w0.17: v2(174.08,28.17) 174.08,28.36 173.95,28.5 173.75,28.5 173.62,28.37 173.62,27.15 173.9,26.87 JDIMM2.115
DDR_B_D0: length 79.7
  IN1 w0.084: v2(178.44,20.66) 179.36,21.58 179.36,30.55 177.09,32.82 176.49,32.82 169.51,39.8 154.34,39.8 152.31,41.82 139.9,41.82 132.92,48.79 132.92,52.94 133.47,53.49 133.47,56.08 v2(132.92,56.62)
  BOTTOM w0.076: UC1.AY31 132.47,60.02 132.08,59.63 132.08,57.47 v2(132.92,56.62)
  BOTTOM w0.102: v2(178.44,20.66) 179,20.1 JDIMM2.132
DDR_B_D1: length 80.8
  IN1 w0.084: v2(132.92,55.43) 133.21,55.43 133.3,55.35 133.3,53.56 132.61,52.87 132.61,48.66 139.75,41.52 152.19,41.52 154.21,39.5 169.39,39.5 176.36,32.52 176.97,32.52 179.06,30.43 179.06,23.28 178.93,23.15 178.7,23.15 178.57,23.28 v2(178.57,27.4)
  BOTTOM w0.076: UC1.AW31 132.47,60.6 132.27,60.4 132.27,60.38 132.19,60.23 132.19,60.11 132.18,60.09 132.18,59.96 131.92,59.7 131.92,56.44 v2(132.92,55.43)
  BOTTOM w0.102: v2(178.57,27.4) 178.7,27.27 JDIMM2.131
DDR_B_D2: length 79.9
  IN1 w0.084: v2(180.94,19.13) 181.64,19.83 181.64,26.47 182.26,27.09 182.26,30.2 177.87,34.58 177.22,34.58 170.11,41.68 154.94,41.68 153.04,43.58 140.68,43.58 134.78,49.48 134.78,52.04 134.92,52.18 134.92,53.92 v2(134.55,54.29)
  BOTTOM w0.076: UC1.AY29 133.82,59.14 133.7,59.02 133.7,55.14 v2(134.55,54.29)
  BOTTOM w0.102: JDIMM2.140 181.4,18.67 v2(180.94,19.13)
DDR_B_D3: length 81.2
  IN1 w0.084: v2(182.67,28.93) 182.67,28.68 182.79,28.55 182.94,28.55 183.07,28.68 183.07,29.85 177.84,35.08 177.72,35.08 177.53,34.88 177.35,34.88 177.18,35.05 177.18,35.23 177.38,35.42 177.38,35.54 177.15,35.77 177.03,35.77 176.83,35.57 176.65,35.57 176.48,35.74 176.48,35.92 176.68,36.12 176.68,36.24 176.45,36.46 176.34,36.46 176.14,36.26 175.96,36.26 175.79,36.43 175.79,36.61 175.99,36.81 175.99,36.93 175.76,37.16 175.64,37.16 175.44,36.96 175.26,36.96 175.1,37.13 175.1,37.31 175.3,37.5 175.3,37.62 175.07,37.85 174.95,37.85 174.75,37.65 174.57,37.65 174.4,37.82 174.4,38 174.6,38.2 174.6,38.32 174.37,38.55 174.26,38.55 174.06,38.35 173.88,38.35 173.71,38.51 173.71,38.69 173.91,38.89 173.91,39.01 173.68,39.24 173.56,39.24 173.36,39.04 173.18,39.04 173.02,39.21 173.02,39.39 173.1,39.47 173.1,39.65 172.93,39.82 172.75,39.82 172.67,39.73 172.49,39.73 170.24,41.98 155.06,41.98 153.16,43.88 140.83,43.88 135.09,49.61 135.09,51.35 135.1,51.36 135.1,55.25 134.99,55.36 134.87,55.36 134.55,55.04 v2(134.55,54.94)
  BOTTOM w0.076: v2(134.55,54.94) 134.15,54.94 133.87,55.22 133.87,58.94 133.99,59.05 133.99,59.9 134.11,60.03 134.11,60.27 133.82,60.56 UC1.AW29
  BOTTOM w0.102: JDIMM2.141 181.7,27.18 181.91,27.39 181.91,29.63 181.98,29.7 182.08,29.7 182.67,29.11 v2(182.67,28.93)
DDR_B_D4: length 81.1
  IN1 w0.084: v2(132.92,54.78) 132.29,54.15 132.29,48.53 139.6,41.22 150.08,41.22 150.16,41.14 150.16,40.66 150.29,40.53 150.52,40.53 150.65,40.66 150.65,41.14 150.74,41.22 151.06,41.22 151.14,41.14 151.14,40.29 151.27,40.17 151.51,40.17 151.63,40.29 151.63,41.1 151.76,41.22 152,41.22 152.12,41.1 152.12,40.29 152.25,40.17 153.12,40.17 154.09,39.2 169.26,39.2 176.42,32.04 176.54,32.04 176.72,32.22 176.84,32.22 177.07,31.99 177.07,31.88 176.89,31.69 176.89,31.57 177.12,31.35 177.23,31.35 177.42,31.53 177.54,31.53 177.76,31.3 177.76,31.18 177.61,31.03 177.61,30.85 177.78,30.68 177.96,30.68 178.11,30.84 178.23,30.84 178.68,30.39 178.68,30.21 178.55,30.09 178.12,30.09 177.99,29.96 177.99,28.67 178.12,28.54 178.44,28.54 178.57,28.67 v2(178.57,28.93)
  BOTTOM w0.076: UC1.AV31 132.09,61.07 132.09,60.4 132.03,60.3 132.03,60.3 132.01,60.26 131.94,60.12 131.47,59.65 131.47,56.24 v2(132.92,54.78)
  BOTTOM w0.102: JDIMM2.129 178.1,27.15 177.97,27.28 177.6,27.28 177.47,27.41 177.47,29.12 177.6,29.25 177.98,29.25 178.11,29.12 178.11,29.05 178.23,28.93 v2(178.57,28.93)
DDR_B_D5: length 82.4
  IN1 w0.084: v2(132.88,57.19) 133.7,56.37 133.7,53.48 133.24,53.02 133.24,48.92 140.05,42.12 152.43,42.12 154.46,40.1 169.64,40.1 176.61,33.12 177.27,33.12 179.66,30.73 179.66,20.36 v2(178.44,19.13)
  BOTTOM w0.076: v2(132.88,57.19) 132.9,57.19 133.37,57.65 133.37,59.2 133.47,59.3 133.47,59.71 133.36,59.81 133.36,60.25 133.39,60.3 133.39,60.3 133.39,60.3 133.44,60.41 133.44,60.54 133.36,60.7 133.36,60.9 133.39,60.95 133.43,61.04 133.44,61.06 133.44,61.25 133.42,61.26 133.42,61.64 133.44,61.65 133.44,61.9 133.23,62.1 UC1.AU31
  BOTTOM w0.102: v2(178.44,19.13) 178.4,19.1 JDIMM2.130
DDR_B_D6: length 81.7
  IN1 w0.084: v2(134.55,52.99) 134.16,52.6 134.16,52.14 134.46,51.84 134.46,49.35 140.53,43.28 152.92,43.28 154.81,41.38 169.99,41.38 177.09,34.28 177.75,34.28 181.96,30.07 181.96,27.21 181.34,26.6 181.34,21.06 v2(180.94,20.66)
  BOTTOM w0.076: v2(134.55,52.99) 133.53,54.01 133.53,59.09 133.63,59.19 133.63,59.78 133.53,59.88 133.53,60.21 133.58,60.32 133.6,60.37 133.6,60.58 133.55,60.7 133.54,60.71 133.54,60.89 133.58,60.97 133.71,61.11 UC1.AV29
  BOTTOM w0.102: JDIMM2.142 182,19.6 v2(180.94,20.66)
DDR_B_D7: length 82.1
  IN1 w0.084: v2(182.67,27.4) 182.67,26.71 182.58,26.62 182.21,26.62 182.09,26.5 182.09,26.26 182.21,26.13 182.58,26.13 182.67,26.05 182.67,25.73 182.58,25.64 182.06,25.64 181.94,25.52 181.94,25.28 182.06,25.15 182.58,25.15 182.67,25.07 182.67,24.8 182.79,24.68 183.24,24.68 183.37,24.8 183.37,29.98 173.23,40.12 172.53,40.12 172.18,40.47 170.36,42.28 155.19,42.28 153.29,44.18 140.98,44.18 135.43,49.73 135.43,55.35 135.19,55.59 v2(134.55,55.59)
  BOTTOM w0.076: v2(134.55,55.59) 134.04,56.1 134.04,58.85 134.15,58.96 134.15,59.83 134.28,59.96 134.28,60.34 134.11,60.5 134.11,60.92 134.01,61.03 134.01,61.6 133.71,61.89 UC1.AU29
  BOTTOM w0.102: JDIMM2.143 182.3,27.04 v2(182.67,27.4)
DDR_B_D8: length 48.3
  IN4 w0.084: v2(134.55,56.89) 134.99,56.45 134.99,52.08 134.51,51.61 134.51,34.5 134.72,34.29 134.72,34.17 134.42,33.87 134.42,33.69 134.59,33.52 134.77,33.52 135.07,33.82 135.19,33.82 135.42,33.6 135.42,33.48 134.42,32.48 134.42,32.3 134.59,32.14 134.77,32.14 135.76,33.13 135.88,33.13 136.11,32.9 136.11,32.78 135.03,31.7 135.03,31.52 135.19,31.35 135.37,31.35 136.46,32.44 136.58,32.44 136.8,32.21 136.8,32.09 136.38,31.67 136.38,31.49 136.55,31.32 136.73,31.32 137.12,31.71 137.3,31.71 137.52,31.49 137.52,31.31 136.52,30.31 136.52,30.02 138.25,28.3 138.46,28.3 v2(139.07,28.91)
  BOTTOM w0.076: UC1.AY27 134.77,60.02 134.77,59.75 134.66,59.64 134.66,58.91 135.11,58.46 135.11,57.45 v2(134.55,56.89)
  BOTTOM w0.102: v2(139.07,28.91) 138.59,28.91 138.5,28.81 JDIMM2.5
DDR_B_D9: length 49.4
  IN4 w0.084: v2(134.55,57.54) 134.16,57.15 134.16,51.83 134.12,51.79 134.12,32 138.01,28.12 138.01,27.83 138.13,27.7 138.55,27.7 138.68,27.57 138.68,27.32 138.56,27.21 138.13,27.21 138.01,27.08 138.01,26.83 138.12,26.72 138.65,26.72 138.77,26.59 138.77,26.34 138.66,26.23 138.13,26.23 138.01,26.1 138.01,25.85 138.12,25.74 138.65,25.74 138.77,25.61 138.77,25.04 139.18,24.63 139.18,21.61 139.05,21.48 v2(138.5,21.48)
  BOTTOM w0.076: v2(134.55,57.54) 134.94,57.93 134.94,58.37 134.49,58.82 134.49,59.71 134.61,59.82 134.61,60.27 134.9,60.56 UC1.AW27
  BOTTOM w0.102: v2(138.5,21.48) 139.09,20.88 139.09,19.29 138.8,19 JDIMM2.6
DDR_B_D10: length 48.5
  IN4 w0.084: v2(136.51,54.29) 135.81,53.59 135.81,52.08 136.04,51.85 136.04,35.04 140.73,30.35 140.73,23.6 140.86,23.47 141.63,23.47 141.76,23.6 141.76,24.23 141.63,24.36 141.4,24.36 141.27,24.49 141.27,24.74 141.4,24.87 141.63,24.87 141.76,24.99 141.76,25.25 141.63,25.37 141.4,25.37 141.27,25.5 141.27,25.75 141.4,25.88 141.63,25.88 141.76,26 141.76,26.24 141.63,26.37 141.35,26.37 141.22,26.49 141.22,26.73 141.35,26.86 141.63,26.86 141.76,26.98 141.76,27.26 141.63,27.38 v2(141.27,27.38)
  BOTTOM w0.076: UC1.AY25 136.15,60.05 136.15,59.25 136.15,59.09 136.42,58.82 136.44,58.82 136.93,58.32 v1(136.93,57.12) 136.93,54.72 v2(136.51,54.29)
  BOTTOM w0.102: v2(141.27,27.38) 141.5,27.15 JDIMM2.15
DDR_B_D11: length 49.3
  IN4 w0.084: v2(136.51,53.64) 136.12,53.26 136.12,52.2 136.34,51.98 136.34,36.23 136.59,35.97 136.59,35.85 136.34,35.59 136.34,35.41 136.5,35.25 136.68,35.25 137,35.57 137.18,35.57 137.43,35.33 137.43,35.15 136.95,34.67 136.95,34.55 137.18,34.32 137.3,34.32 137.77,34.8 137.95,34.8 138.12,34.63 138.12,34.45 137.64,33.98 137.64,33.86 137.87,33.63 137.99,33.63 138.47,34.11 138.65,34.11 138.81,33.94 138.81,33.76 138.34,33.28 138.34,33.17 138.57,32.94 138.68,32.94 139.16,33.41 139.34,33.41 139.51,33.25 139.51,33.07 139.03,32.59 139.03,32.47 139.26,32.24 139.38,32.24 139.85,32.72 140.03,32.72 140.2,32.55 140.2,32.37 139.72,31.9 139.72,31.78 139.95,31.55 140.07,31.55 140.55,32.03 140.73,32.03 140.89,31.86 140.89,31.68 140.42,31.2 140.42,31.09 140.65,30.86 140.76,30.86 141.24,31.33 141.42,31.33 141.59,31.17 141.59,30.99 141.11,30.51 141.11,30.39 141.67,29.83 141.67,29.31 v2(141.27,28.91)
  BOTTOM w0.076: UC1.AW25 136.47,60.58 136.47,60.37 136.51,60.28 136.51,60.28 136.54,60.21 136.54,60.03 136.32,59.8 136.32,59.29 137.25,58.36 137.25,54.38 v2(136.51,53.64)
  BOTTOM w0.102: v2(141.27,28.91) 142.1,28.08 JDIMM2.17
DDR_B_D12: length 50.1
  IN4 w0.084: v2(134.55,58.19) 133.91,57.55 133.91,52.08 133.76,51.93 133.76,31.94 137.71,27.99 137.71,25.44 137.79,25.35 138.16,25.35 138.29,25.23 138.29,24.99 138.16,24.86 137.79,24.86 137.71,24.78 137.71,24.46 137.79,24.37 138.3,24.37 138.39,24.29 138.39,23.97 138.3,23.88 137.79,23.88 137.71,23.8 137.71,23.48 137.79,23.39 138.29,23.39 138.42,23.27 138.42,23.03 138.29,22.9 137.85,22.9 137.72,22.78 137.72,20.08 137.85,19.96 v2(138.5,19.96)
  BOTTOM w0.076: UC1.AV27 135.01,61.32 134.61,60.92 134.61,60.51 134.44,60.35 134.44,59.89 134.32,59.76 134.32,58.43 v2(134.55,58.19)
  BOTTOM w0.102: JDIMM2.4 138.2,18.91 138.5,19.21 v2(138.5,19.96)
DDR_B_D13: length 50.5
  IN4 w0.084: v2(142.37,21.48) 142.67,21.48 142.8,21.35 142.8,20.99 142.93,20.87 143.24,20.87 143.37,20.99 143.37,21.8 142.43,22.74 142.43,31.17 136.95,36.65 136.95,57.09 v2(136.51,57.54)
  BOTTOM w0.076: v2(136.51,57.54) 135.79,58.25 135.79,60.25 135.87,60.41 135.87,60.54 135.82,60.65 135.82,60.65 135.79,60.7 135.79,60.9 135.82,60.95 135.86,61.04 135.87,61.06 135.87,61.9 135.66,62.1 UC1.AU27
  BOTTOM w0.102: v2(142.37,21.48) 141.8,20.91 JDIMM2.16
DDR_B_D14: length 50
  IN4 w0.084: v2(136.51,58.19) 135.17,56.85 135.17,51.94 134.83,51.61 134.83,34.6 137.98,31.46 137.98,31.34 136.89,30.25 136.89,30.07 137.06,29.91 137.24,29.91 138.33,30.99 138.44,30.99 138.67,30.76 138.67,30.65 137.59,29.56 137.59,29.38 137.75,29.21 137.93,29.21 139.02,30.3 139.14,30.3 139.57,29.87 139.57,25.18 139.44,25.06 139.2,25.06 139.07,25.18 v2(139.07,27.38)
  BOTTOM w0.076: v2(136.51,58.19) 135.96,58.74 135.96,60.21 136.01,60.31 136.04,60.34 136.04,60.58 136.01,60.63 135.96,60.73 135.96,60.74 135.96,60.87 136.01,60.97 136.25,61.21 UC1.AV25
  BOTTOM w0.102: v2(139.07,27.38) 139.1,27.36 JDIMM2.7
DDR_B_D15: length 51
  IN4 w0.084: v2(142.37,19.96) 141.46,19.96 141.34,20.08 141.34,20.52 141.42,20.61 141.85,20.61 141.97,20.73 141.97,20.97 141.85,21.1 141.42,21.1 141.34,21.18 141.34,21.56 141.42,21.64 141.72,21.64 141.85,21.77 141.85,22 141.72,22.13 141.42,22.13 141.34,22.21 141.34,22.77 141.46,22.9 141.93,22.9 142.06,23.02 142.06,31.12 136.65,36.52 136.65,52.11 136.51,52.26 v2(136.51,52.99)
  BOTTOM w0.076: UC1.AU25 136.54,61.81 136.54,61.06 136.63,60.97 136.63,60.42 136.67,60.34 136.69,60.3 136.69,60.3 136.71,60.25 136.71,59.96 136.48,59.73 136.48,59.36 137.44,58.4 137.44,53.92 v2(136.51,52.99)
  BOTTOM w0.102: JDIMM2.18 142.4,19.93 v2(142.37,19.96)
DDR_B_D16: length 88.4
  IN1 w0.084: v2(183.48,20.66) 184.09,20.66 184.22,20.79 184.22,21.08 184.09,21.21 183.96,21.21 183.88,21.29 183.88,21.62 183.96,21.7 184.09,21.7 184.22,21.83 184.22,22.2 184.13,22.29 183.51,22.29 183.38,22.41 183.38,22.65 183.51,22.78 184.13,22.78 184.22,22.86 184.22,30.24 173.55,40.91 172.86,40.91 172.74,41.03 170.69,43.07 155.51,43.07 153.62,44.97 141.33,44.97 136.28,50.02 136.28,51.89 135.78,52.4 135.78,55.49 135.1,56.17 135.1,58.42 134.87,58.65 134.87,58.65 132.89,60.63 132.89,64.29 v2(133.49,64.89)
  BOTTOM w0.081: UC1.AM29 133.82,65.21 v2(133.49,64.89)
  BOTTOM w0.102: v2(183.48,20.66) 183.05,20.23 183.05,18.86 183.2,18.71 JDIMM2.146
DDR_B_D17: length 90.3
  IN1 w0.084: v2(133.49,66.19) 132.7,65.4 132.7,60.57 134.93,58.35 134.93,56.1 135.6,55.42 135.6,52.3 135.94,51.96 135.94,49.91 141.18,44.67 153.49,44.67 155.39,42.77 170.57,42.77 172.53,40.81 172.73,40.61 173.43,40.61 183.9,30.14 183.9,24.29 183.77,24.17 182.74,24.17 182.61,24.04 182.61,23.78 182.74,23.65 183.79,23.65 183.92,23.52 183.92,23.29 183.79,23.16 183.21,23.16 183.08,23.03 183.08,19.53 v2(183.48,19.13)
  BOTTOM w0.081: UC1.AK29 133.82,66.51 v2(133.49,66.19)
  BOTTOM w0.102: v2(183.48,19.13) 183.8,18.81 JDIMM2.148
DDR_B_D18: length 89.2
  IN1 w0.084: v2(186.8,20.66) 187.47,20.66 187.59,20.79 187.59,21.91 188.07,22.39 188.07,30.45 183.29,35.24 182.56,35.24 172.37,45.43 156.49,45.43 154.59,47.33 146.61,47.33 146.2,47.73 142.1,47.73 138.81,51.02 138.81,51.63 137.79,52.66 137.79,60.02 135.02,62.78 135.02,65.69 134.92,65.79 134.55,65.79 134.44,65.69 v2(134.44,65.54)
  BOTTOM w0.081: v2(134.44,65.54) 134.77,65.86 UC1.AL28
  BOTTOM w0.102: v2(186.8,20.66) 187.4,20.06 JDIMM2.160
DDR_B_D19: length 90
  IN1 w0.084: v2(186.8,19.13) 187.91,20.25 187.91,21.77 188.39,22.26 188.39,30.56 183.41,35.54 182.68,35.54 172.49,45.73 156.62,45.73 154.72,47.63 146.73,47.63 146.33,48.03 142.25,48.03 139.13,51.15 139.13,51.6 137.96,52.77 137.96,60.18 135.79,62.36 135.79,66.27 135.5,66.56 134.77,66.56 v2(134.39,66.19)
  BOTTOM w0.081: v2(134.39,66.19) 134.72,66.51 UC1.AK28
  BOTTOM w0.102: JDIMM2.158 v2(186.8,19.13)
DDR_B_D20: length 86.4
  IN1 w0.084: v2(184.92,27.4) 184.65,27.4 184.52,27.28 184.52,24.31 184.65,24.18 185.56,24.18 185.69,24.31 185.69,24.97 185.61,25.06 185.14,25.06 185.01,25.18 185.01,25.42 185.14,25.55 185.61,25.55 185.69,25.63 185.69,25.95 185.61,26.04 185.14,26.04 185.01,26.16 185.01,26.4 185.14,26.53 185.61,26.53 185.69,26.61 185.69,29.62 171.64,43.67 155.76,43.67 153.86,45.57 145.88,45.57 145.47,45.97 141.22,45.97 136.92,50.28 136.92,51.89 136.15,52.65 136.15,58.68 135.8,59.03 135.8,59.46 134.86,60.4 134.86,60.61 134.6,60.87 134.23,60.87 133.49,61.6 v2(133.49,62.94)
  BOTTOM w0.081: UC1.AR29 133.82,63.26 v2(133.49,62.94)
  BOTTOM w0.102: JDIMM2.149 184.1,26.99 184.51,27.4 v2(184.92,27.4)
DDR_B_D21: length 88
  IN1 w0.084: v2(184.92,28.93) 184.79,28.8 184.65,28.8 184.52,28.93 184.52,29.85 184.71,30.04 184.71,30.18 173.53,41.35 173.41,41.35 173.26,41.21 173.08,41.21 172.92,41.37 172.92,41.55 173.07,41.7 173.07,41.82 172.84,42.05 172.72,42.05 172.52,41.85 172.34,41.85 172.17,42.01 172.17,42.19 172.37,42.39 172.37,42.51 172.14,42.74 172.03,42.74 171.83,42.54 171.65,42.54 171.48,42.71 171.48,42.89 171.62,43.03 171.62,43.21 171.45,43.37 171.25,43.37 171.1,43.23 170.96,43.23 170.81,43.37 155.64,43.37 153.74,45.27 145.52,45.27 145.43,45.36 145.43,45.59 145.35,45.67 145.03,45.67 144.94,45.59 144.94,45.36 144.86,45.27 144.54,45.27 144.45,45.36 144.45,45.59 144.37,45.67 144.05,45.67 143.96,45.59 143.96,45.37 143.86,45.27 143.49,45.27 143.39,45.37 143.39,45.57 143.29,45.67 143,45.67 142.9,45.57 142.9,45.37 142.8,45.27 142.51,45.27 142.41,45.37 142.41,45.57 142.31,45.67 142.02,45.67 141.92,45.57 141.92,45.37 141.82,45.27 141.53,45.27 141.43,45.37 141.43,45.59 141.35,45.67 141.08,45.67 136.6,50.15 136.6,51.96 135.97,52.58 135.97,55.88 135.83,56.02 135.52,56.02 135.32,56.22 135.32,56.42 135.41,56.52 135.9,56.52 135.97,56.6 135.97,56.92 135.88,57.01 135.39,57.01 135.32,57.09 135.32,57.43 135.4,57.51 135.9,57.51 135.97,57.59 135.97,57.92 135.87,58.03 135.41,58.03 135.32,58.12 135.32,58.45 134.09,59.68 134.09,59.79 134.45,60.15 134.45,60.33 134.28,60.5 134.1,60.5 133.76,60.16 133.61,60.16 133.12,60.65 133.12,60.8 133.53,61.21 133.53,61.32 133.08,61.76 133.08,64.05 133.27,64.24 v2(133.49,64.24)
  BOTTOM w0.081: v2(133.49,64.24) 133.82,64.56 UC1.AN29
  BOTTOM w0.102: JDIMM2.147 183.5,29.23 183.67,29.4 184.45,29.4 v2(184.92,28.93)
DDR_B_D22: length 86.4
  IN1 w0.084: v2(134.44,62.94) 134.44,62.86 135.42,61.89 135.42,61.77 135.29,61.64 135.29,61.52 135.52,61.29 135.64,61.29 135.77,61.43 135.88,61.43 136.34,60.96 136.34,60.85 135.86,60.37 135.86,60.25 136.09,60.02 136.21,60.02 136.69,60.5 136.81,60.5 137.43,59.88 137.43,59.5 137.08,59.16 137.08,58.99 137.43,58.65 137.43,52.49 138.18,51.74 138.18,50.75 141.8,47.13 145.96,47.13 146.36,46.73 154.34,46.73 156.24,44.83 172.12,44.83 182.61,34.34 182.73,34.34 182.98,34.58 183.1,34.58 183.32,34.36 183.32,34.24 183.08,33.99 183.08,33.87 183.31,33.65 183.43,33.65 183.67,33.89 183.79,33.89 184.02,33.66 184.02,33.54 183.77,33.3 183.77,33.18 184,32.95 184.12,32.95 184.36,33.2 184.48,33.2 184.71,32.97 184.71,32.85 184.47,32.6 184.47,32.49 184.69,32.26 184.81,32.26 185.06,32.5 185.18,32.5 185.4,32.28 185.4,32.16 185.16,31.91 185.16,31.79 185.39,31.56 185.51,31.56 185.75,31.81 185.87,31.81 186.1,31.58 186.1,31.46 185.85,31.22 185.85,31.1 186.08,30.87 186.2,30.87 186.44,31.12 186.56,31.12 186.79,30.89 186.79,30.77 186.55,30.52 186.55,30.41 186.77,30.18 186.89,30.18 187.14,30.42 187.26,30.42 187.44,30.24 187.44,28.87 187.38,28.8 187.16,28.8 v2(187.04,28.93)
  BOTTOM w0.081: UC1.AR28 134.77,63.26 v2(134.44,62.94)
  BOTTOM w0.102: v2(187.04,28.93) 186.43,29.53 186.09,29.53 185.98,29.42 185.98,27.61 186.5,27.08 JDIMM2.157
DDR_B_D23: length 87.4
  IN1 w0.084: v2(134.44,63.59) 134.84,63.19 134.84,62.71 137.61,59.94 137.61,52.56 138.5,51.67 138.5,50.88 141.95,47.43 146.08,47.43 146.48,47.03 154.47,47.03 156.37,45.13 172.24,45.13 182.43,34.94 183.16,34.94 187.76,30.35 187.76,23.47 187.63,23.34 187.39,23.34 187.27,23.47 187.27,24.35 187.18,24.43 186.96,24.43 186.88,24.51 186.88,24.84 186.96,24.92 187.18,24.92 187.27,25 187.27,25.33 187.18,25.41 186.96,25.41 186.88,25.49 186.88,25.82 186.96,25.9 187.18,25.9 187.27,25.98 187.27,26.31 187.18,26.39 186.96,26.39 186.88,26.47 186.88,26.8 186.96,26.88 187.18,26.88 187.27,26.96 187.27,27.18 v2(187.04,27.4)
  BOTTOM w0.081: UC1.AP28 134.77,63.91 v2(134.44,63.59)
  BOTTOM w0.102: v2(187.04,27.4) 187.1,27.34 JDIMM2.159
DDR_B_D24: length 52.2
  IN4 w0.084: v2(145.01,19.96) 144.37,19.96 144.22,20.1 144.22,29.82 143.54,30.5 143.54,31.6 142.76,32.38 142.76,33.56 138.04,38.28 138.04,52.07 137.53,52.58 137.53,58.32 136.45,59.41 136.45,60.36 135.04,61.77 135.04,63.88 v2(135.4,64.24)
  BOTTOM w0.081: UC1.AN26 135.72,64.56 v2(135.4,64.24)
  BOTTOM w0.102: JDIMM2.24 144.2,19.41 144.75,19.96 v2(145.01,19.96)
DDR_B_D25: length 51.2
  IN4 w0.084: v2(135.4,62.94) 135.4,61.65 137.23,59.82 137.23,58.88 137.71,58.4 137.71,52.65 138.34,52.01 138.34,38.43 143.06,33.71 143.06,32.51 143.84,31.73 143.84,30.63 144.57,29.9 144.57,23.63 144.71,23.49 145.03,23.49 145.17,23.34 145.17,23.08 145.03,22.93 144.71,22.93 144.57,22.79 144.57,21.93 v2(145.01,21.48)
  BOTTOM w0.081: UC1.AR26 135.72,63.26 v2(135.4,62.94)
  BOTTOM w0.102: JDIMM2.22 143.6,20.07 v2(145.01,21.48)
DDR_B_D26: length 50.5
  IN4 w0.084: v2(136.35,62.94) 136.35,62.05 138.91,59.48 138.91,52.89 139.5,52.3 139.5,40.31 143.18,36.63 143.18,36.3 142.74,35.85 142.74,35.72 146.87,31.58 146.87,30.45 146.38,29.96 146.38,27.35 146.29,27.26 145.34,27.26 145.21,27.14 145.21,26.9 145.34,26.77 146.25,26.77 146.38,26.64 146.38,26.41 146.25,26.28 145.34,26.28 145.21,26.15 145.21,25.92 145.34,25.79 146.95,25.79 147.07,25.92 v2(147.07,27.38)
  BOTTOM w0.081: v2(136.35,62.94) 136.67,63.26 UC1.AR25
  BOTTOM w0.102: JDIMM2.33 146.9,27.21 v2(147.07,27.38)
DDR_B_D27: length 51.5
  IN4 w0.084: v2(136.35,63.59) 136.75,63.19 136.75,61.97 139.14,59.58 139.14,53.01 139.8,52.35 139.8,40.45 143.74,36.52 143.74,36.4 143.2,35.86 143.2,35.68 143.37,35.51 143.55,35.51 144.09,36.05 144.21,36.05 144.43,35.82 144.43,35.7 143.89,35.17 143.89,34.99 144.06,34.82 144.24,34.82 144.78,35.36 144.9,35.36 145.13,35.13 145.13,35.01 144.59,34.47 144.59,34.29 144.75,34.12 144.93,34.12 145.47,34.66 145.59,34.66 145.82,34.44 145.82,34.32 145.28,33.78 145.28,33.6 145.45,33.43 145.63,33.43 146.15,33.95 146.33,33.95 146.5,33.78 146.5,33.6 145.98,33.08 145.98,32.9 146.35,32.53 146.53,32.53 146.83,32.82 147,32.82 147.17,32.66 147.17,32.48 146.85,32.15 146.85,32.03 147.17,31.71 147.17,30.33 146.68,29.84 146.68,29.31 v2(147.07,28.91)
  BOTTOM w0.081: v2(136.35,63.59) 136.67,63.91 UC1.AP25
  BOTTOM w0.102: v2(147.07,28.91) 147.5,28.48 JDIMM2.35
DDR_B_D28: length 53.9
  IN4 w0.084: v2(135.35,66.19) 134.93,66.6 134.18,66.6 133.98,66.4 133.98,62.34 136,60.31 136,59.28 137.19,58.1 137.19,52.2 137.44,51.94 137.44,36.85 142.92,31.37 142.92,24.29 143.05,24.17 143.68,24.17 143.81,24.29 v2(143.81,27.38)
  BOTTOM w0.081: v2(135.35,66.19) 135.67,66.51 UC1.AK26
  BOTTOM w0.102: JDIMM2.21 143.3,27.13 143.55,27.38 v2(143.81,27.38)
DDR_B_D29: length 53
  IN4 w0.084: v2(135.4,64.89) 134.87,64.35 134.87,61.69 136.28,60.28 136.28,59.33 137.36,58.24 137.36,52.4 137.74,52.02 137.74,38.15 138.18,37.71 138.18,37.42 137.83,37.07 137.83,36.89 138.03,36.69 138.21,36.69 138.65,37.13 138.77,37.13 138.99,36.9 138.99,36.78 138.52,36.31 138.52,36.19 138.75,35.97 138.87,35.97 139.34,36.44 139.46,36.44 139.69,36.21 139.69,36.09 139.22,35.62 139.22,35.5 139.45,35.27 139.56,35.27 140.03,35.74 140.15,35.74 140.38,35.51 140.38,35.4 139.91,34.93 139.91,34.81 140.14,34.58 140.26,34.58 140.73,35.05 140.85,35.05 141.07,34.82 141.07,34.7 140.6,34.23 140.6,34.11 140.83,33.89 140.95,33.89 141.42,34.36 141.54,34.36 141.77,34.13 141.77,34.01 141.3,33.54 141.3,33.42 141.53,33.19 141.64,33.19 142.11,33.66 142.23,33.66 142.46,33.43 142.46,33.32 141.99,32.85 141.99,32.73 143.24,31.48 143.24,29.12 143.45,28.91 v2(143.81,28.91)
  BOTTOM w0.081: v2(135.4,64.89) 135.72,65.21 UC1.AM26
  BOTTOM w0.102: JDIMM2.23 143.9,26.87 144.13,27.09 144.13,27.09 144.24,27.21 144.24,28.48 v2(143.81,28.91)
DDR_B_D30: length 54.2
  IN4 w0.084: v2(136.3,66.19) 136.88,65.6 136.88,65.34 137.75,64.48 137.75,61.66 139.62,59.78 139.62,53.17 140.4,52.39 140.4,40.75 147.95,33.2 147.95,21.88 v2(147.55,21.48)
  BOTTOM w0.081: v2(136.3,66.19) 136.62,66.51 UC1.AK25
  BOTTOM w0.102: JDIMM2.34 147.2,19.13 147.15,19.18 147.15,21.07 v2(147.55,21.48)
DDR_B_D31: length 53.8
  IN4 w0.084: v2(147.55,19.96) 147.05,19.96 146.93,20.08 146.93,22.83 147.47,23.38 147.47,33.23 140.1,40.6 140.1,52.38 139.38,53.1 139.38,59.68 136.98,62.08 136.98,63.25 136.81,63.42 136.81,65.08 v2(136.35,65.54)
  BOTTOM w0.081: UC1.AL25 136.67,65.86 v2(136.35,65.54)
  BOTTOM w0.102: v2(147.55,19.96) 147.8,19.71 JDIMM2.36
DDR_B_D32: length 82.3
  IN1 w0.084: v2(189.34,19.13) 188.96,19.13 188.88,19.22 188.88,23.64 189.25,24.01 189.57,24.01 190.44,24.88 190.44,28.3 190.24,28.5 190.24,30.25 183.86,36.63 183.13,36.63 172.94,46.82 172.51,46.82 172.09,47.24 156.65,47.24 155.17,48.72 147.18,48.72 146.78,49.12 142.91,49.12 139.08,52.95 139.08,54.24 138.89,54.44 138.89,55.24 v2(138.54,55.59)
  BOTTOM w0.076: UC1.AY23 137.6,59.89 137.61,59.88 137.61,59.17 137.94,58.84 137.94,57.8 138.14,57.59 138.14,55.98 v2(138.54,55.59)
  BOTTOM w0.102: JDIMM2.166 189.2,18.99 v2(189.34,19.13)
DDR_B_D33: length 83.5
  IN1 w0.084: v2(138.54,54.34) 138.91,53.97 138.91,52.67 142.76,48.82 146.66,48.82 147.06,48.42 155.04,48.42 156.53,46.94 171.97,46.94 172.39,46.52 172.82,46.52 183.01,36.33 183.74,36.33 189.92,30.15 189.92,28.4 190.14,28.17 190.14,25.05 190.02,24.92 189.01,24.92 188.88,25.05 188.88,25.28 189.01,25.41 189.52,25.41 189.65,25.54 189.65,25.77 189.52,25.9 189.01,25.9 188.88,26.03 188.88,26.26 189.01,26.39 189.52,26.39 189.65,26.52 189.65,26.77 189.52,26.9 189.01,26.9 188.88,27.03 188.88,27.28 189.01,27.4 v2(189.48,27.4)
  BOTTOM w0.076: v2(138.54,54.34) 137.98,54.9 137.98,55.91 137.98,55.92 137.98,57.52 137.77,57.73 137.77,58.78 137.45,59.1 137.45,59.81 137.31,59.95 137.31,60.22 137.39,60.36 137.4,60.39 137.6,60.59 UC1.AW23
  BOTTOM w0.102: JDIMM2.165 188.9,27.53 189.03,27.66 189.22,27.66 v2(189.48,27.4)
DDR_B_D34: length 82.3
  IN1 w0.084: v2(191.12,19.13) 191.12,19.24 191.87,19.99 191.87,26.73 192.63,27.48 192.63,30.36 180.49,42.49 179.76,42.49 173.25,49 157.59,49 155.7,50.88 152.47,50.88 152.2,51.16 143.39,51.16 142.56,51.99 142.29,51.99 140.51,53.77 140.51,53.94 v2(140.14,54.32)
  BOTTOM w0.076: v2(140.14,54.32) 139.24,55.22 139.24,58.52 139.08,58.67 139.08,60.02 UC1.AY21
  BOTTOM w0.102: JDIMM2.174 191.6,18.65 v2(191.12,19.13)
DDR_B_D35: length 83.2
  IN1 w0.076: 152.49,51.37 152.39,51.47 143.5,51.47
  IN1 w0.084: v2(140.14,55.6) 141.58,55.6 141.71,55.48 141.71,55.17 141.63,55.09 140.77,55.09 140.64,54.97 140.64,54.73 140.77,54.6 141.63,54.6 141.71,54.52 141.71,54.19 141.63,54.11 140.96,54.11 140.83,53.99 140.83,53.75 140.96,53.62 141.63,53.62 141.71,53.54 141.71,52.88 142.33,52.26 142.71,52.26 143.5,51.47 ; v2(193.16,28.93) 193.16,28.73 193.43,28.46 193.63,28.46 193.71,28.54 193.71,29.69 180.3,43.1 180.18,43.1 179.97,42.89 179.79,42.89 179.62,43.06 179.62,43.24 179.84,43.45 179.84,43.57 179.61,43.8 179.49,43.8 179.28,43.58 179.1,43.58 178.93,43.75 178.93,43.93 179.14,44.14 179.14,44.26 178.92,44.49 178.8,44.49 178.58,44.28 178.4,44.28 178.24,44.44 178.24,44.62 178.32,44.71 178.32,44.89 178.15,45.05 177.97,45.05 177.89,44.97 177.71,44.97 173.38,49.3 157.8,49.3 155.91,51.18 152.68,51.18 152.49,51.37
  BOTTOM w0.076: v2(140.14,55.6) 139.4,56.34 139.4,58.59 139.25,58.74 139.25,60.27 138.95,60.56 UC1.AW21
  BOTTOM w0.102: v2(193.16,28.93) 193.03,29.05 192.52,29.05 192.34,28.88 192.34,27.47 191.9,27.03 JDIMM2.175
DDR_B_D36: length 84
  IN1 w0.084: v2(138.54,53.64) 138.16,53.26 138.16,52.84 138.81,52.19 138.94,52.19 142.61,48.52 146.53,48.52 146.93,48.12 154.92,48.12 156.4,46.64 157.05,46.64 157.18,46.51 157.18,46.35 157.31,46.22 157.54,46.22 157.67,46.35 157.67,46.51 157.8,46.64 158.21,46.64 158.33,46.51 158.33,46.35 158.46,46.22 158.7,46.22 158.82,46.35 158.82,46.51 158.95,46.64 160.61,46.64 160.7,46.56 160.7,46.35 160.83,46.22 161.06,46.22 161.19,46.35 161.19,46.56 161.27,46.64 161.59,46.64 161.68,46.56 161.68,46.35 161.81,46.22 162.04,46.22 162.17,46.35 162.17,46.56 162.25,46.64 163.27,46.64 163.4,46.51 163.4,46.41 163.53,46.29 163.76,46.29 163.89,46.41 163.89,46.51 164.02,46.64 164.47,46.64 164.55,46.56 164.55,46.35 164.68,46.22 164.92,46.22 165.04,46.35 165.04,46.56 165.13,46.64 165.45,46.64 165.53,46.56 165.53,46.35 165.66,46.22 165.9,46.22 166.02,46.35 166.02,46.56 166.11,46.64 166.43,46.64 166.51,46.56 166.51,46.35 166.64,46.22 166.88,46.22 167,46.35 167,46.56 167.09,46.64 167.66,46.64 167.74,46.56 167.74,46.35 167.87,46.22 168.11,46.22 168.23,46.35 168.23,46.56 168.32,46.64 168.91,46.64 168.99,46.56 168.99,46.35 169.12,46.22 169.35,46.22 169.48,46.35 169.48,46.56 169.56,46.64 169.89,46.64 169.97,46.56 169.97,46.35 170.1,46.22 170.33,46.22 170.46,46.35 170.46,46.56 170.54,46.64 171.84,46.64 171.95,46.54 171.95,46.33 172.05,46.22 172.69,46.22 182.89,36.03 183.61,36.03 189.09,30.55 189.09,30.2 188.88,29.99 188.88,28.67 189.01,28.54 189.35,28.54 189.48,28.67 v2(189.48,28.93)
  BOTTOM w0.076: UC1.AV23 137.22,61.07 137.22,60.4 137.17,60.3 137.17,60.3 137.15,60.26 137.15,59.88 137.28,59.74 137.28,59.03 137.61,58.71 137.61,57.66 137.8,57.47 137.8,54.38 v2(138.54,53.64)
  BOTTOM w0.102: JDIMM2.163 188.3,29.47 188.46,29.63 188.78,29.63 v2(189.48,28.93)
DDR_B_D37: length 84.9
  IN1 w0.084: v2(189.34,20.66) 189.92,21.24 189.92,23.94 190.74,24.76 190.74,28.42 190.56,28.61 190.56,30.36 183.99,36.93 183.26,36.93 173.07,47.12 172.64,47.12 172.22,47.54 156.77,47.54 155.29,49.02 147.31,49.02 146.9,49.42 143.06,49.42 139.28,53.21 139.28,54.3 139.06,54.52 139.06,55.72 v2(138.54,56.24)
  BOTTOM w0.076: UC1.AU23 138.37,62.1 138.64,61.82 138.64,61.66 138.55,61.57 138.55,61.26 138.57,61.25 138.57,61.06 138.56,61.04 138.5,60.9 138.5,60.7 138.52,60.65 138.52,60.65 138.57,60.54 138.57,60.41 138.52,60.3 138.52,60.3 138.5,60.25 138.5,59.96 138.73,59.73 138.73,58.56 138.91,58.38 138.91,56.38 138.77,56.24 v2(138.54,56.24)
  BOTTOM w0.102: v2(189.34,20.66) 188.6,19.92 JDIMM2.164
DDR_B_D38: length 83.8
  IN1 w0.084: v2(191.12,20.66) 191.52,21.06 191.52,26.87 192.33,27.68 192.33,30.23 180.37,42.19 179.64,42.19 173.13,48.7 157.46,48.7 155.58,50.58 152.26,50.58 152.01,50.84 143.29,50.84 142.37,51.75 142.15,51.75 140.14,53.77 v2(140.12,53.77)
  BOTTOM w0.076: v2(140.12,53.77) 140.12,53.79 139.07,54.84 139.07,58.45 138.91,58.61 138.91,59.78 138.66,60.03 138.66,60.21 138.71,60.31 138.74,60.34 138.74,60.58 138.71,60.63 138.71,60.63 138.66,60.73 138.66,60.74 138.66,60.87 138.69,60.92 138.71,60.97 138.85,61.11 UC1.AV21
  BOTTOM w0.102: v2(191.12,20.66) 192.2,19.58 JDIMM2.176
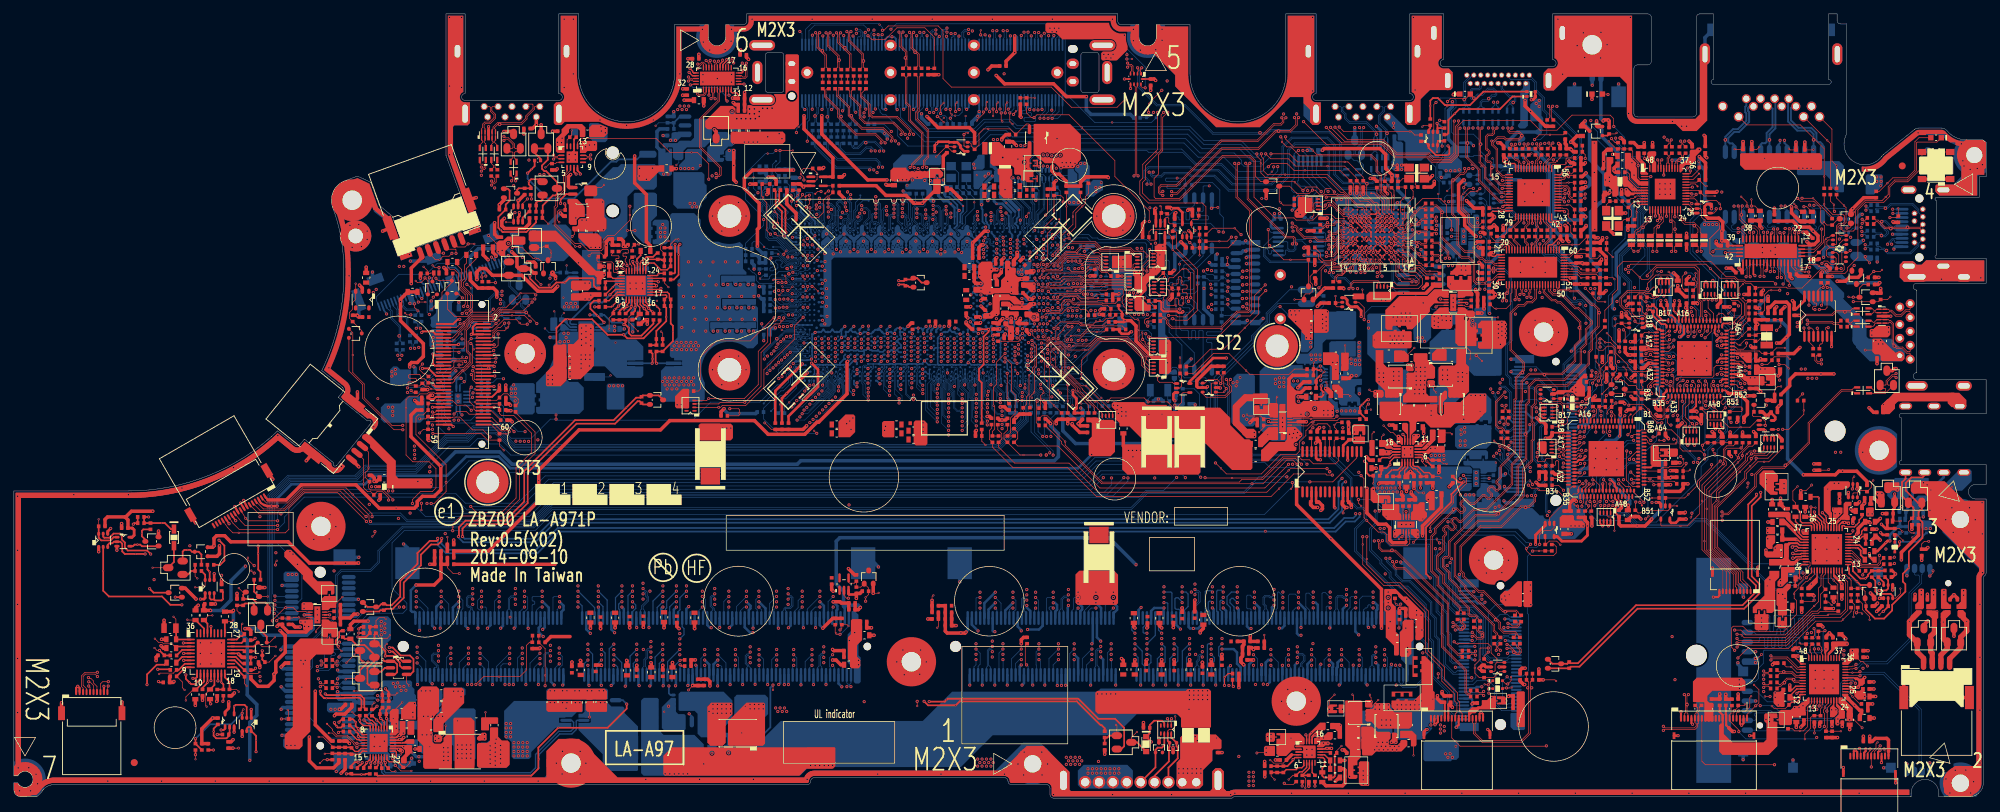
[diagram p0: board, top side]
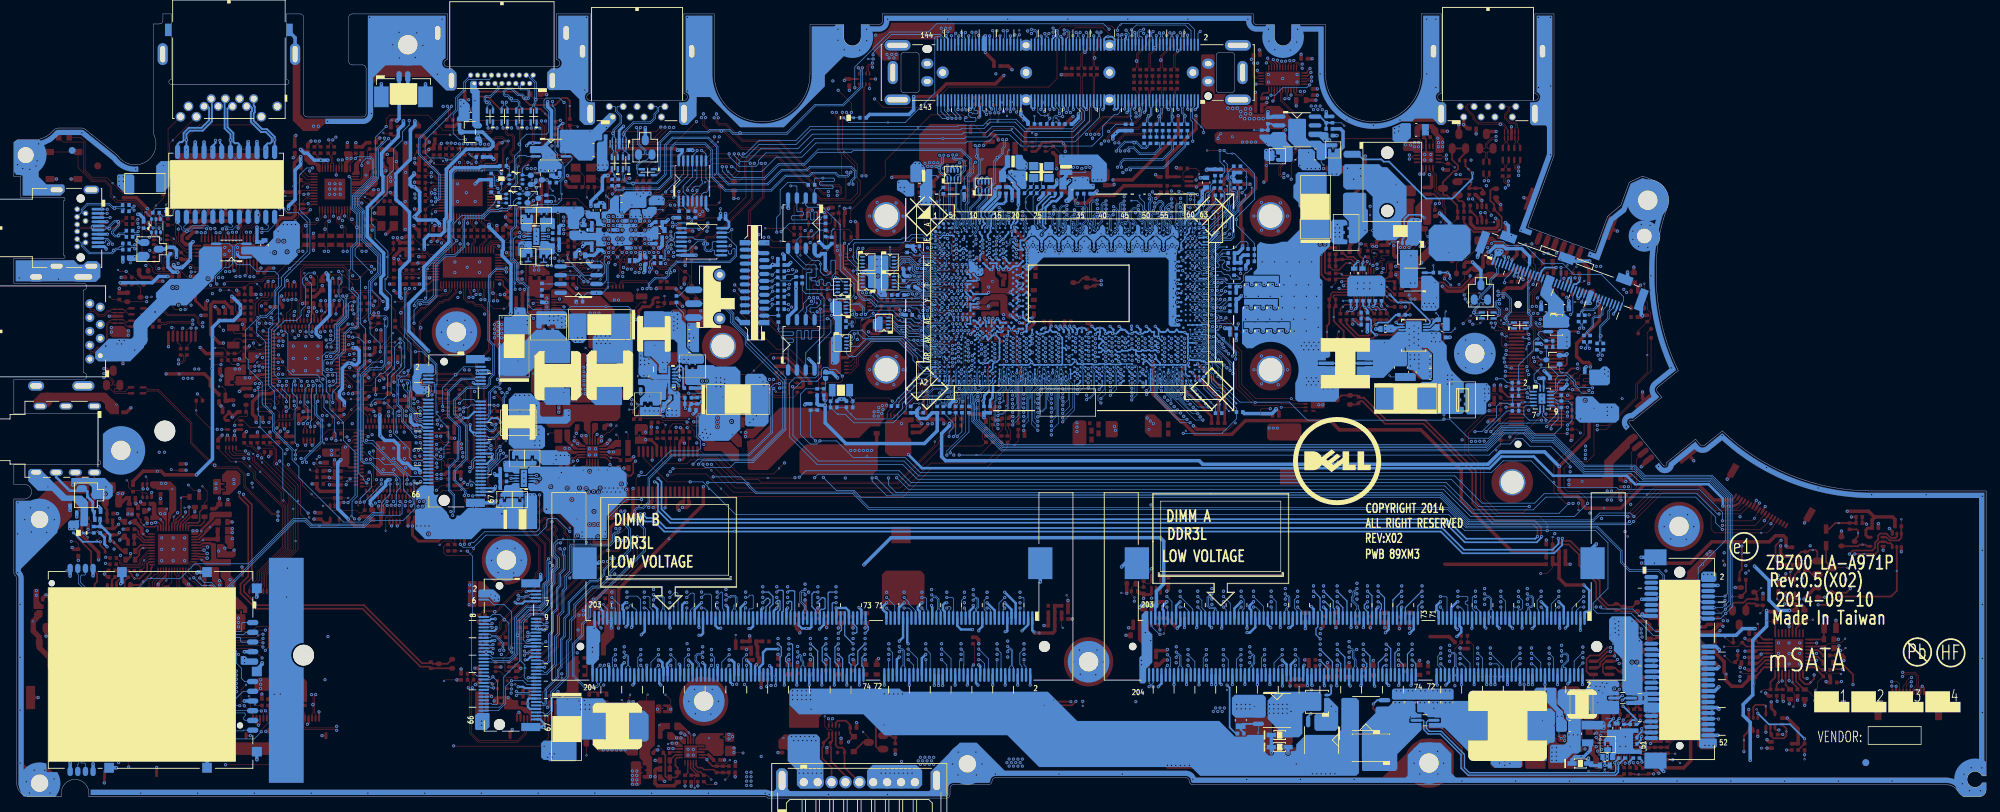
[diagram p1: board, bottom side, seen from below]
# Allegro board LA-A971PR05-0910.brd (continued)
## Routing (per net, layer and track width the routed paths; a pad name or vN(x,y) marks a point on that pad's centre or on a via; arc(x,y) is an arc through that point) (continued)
DDR_B_D39: length 84.1
  IN1 w0.084: v2(193.16,27.4) 192.99,27.4 192.19,26.6 192.19,24.76 192.29,24.66 192.56,24.66 192.66,24.76 192.66,26.2 193.7,27.24 193.7,28.08 194.03,28.41 194.03,29.8 178.48,45.35 177.75,45.35 173.5,49.6 157.92,49.6 156.04,51.48 152.82,51.48 152.58,51.73 143.75,51.73 142.99,52.49 142.41,52.49 141.88,53.01 141.88,55.9 141.53,56.25 v2(140.14,56.25)
  BOTTOM w0.076: v2(140.14,56.25) 139.57,56.82 139.57,58.65 139.41,58.81 139.41,60.34 139.25,60.5 139.25,60.92 139.12,61.05 139.12,61.31 139.14,61.33 139.14,61.57 138.85,61.86 UC1.AU21
  BOTTOM w0.102: JDIMM2.177 192.5,27 192.91,27.4 v2(193.16,27.4)
DDR_B_D40: length 48.5
  IN4 w0.084: v2(149.61,28.91) 149.61,28.71 150.04,28.28 150.04,27.72 150.17,27.6 150.44,27.6 150.57,27.72 150.57,28.61 150.16,29.02 150.16,29.94 150.03,30.07 149.17,30.07 149.04,30.19 149.04,30.43 149.17,30.56 150.03,30.56 150.16,30.68 150.16,30.92 150.03,31.05 149.17,31.05 149.04,31.18 149.04,31.41 149.17,31.54 150.03,31.54 150.16,31.67 150.16,31.9 150.03,32.03 149.17,32.03 149.04,32.16 149.04,32.39 149.17,32.52 149.74,32.52 149.86,32.65 149.86,32.88 149.74,33.01 149.17,33.01 149.04,33.14 149.04,33.71 141.49,41.26 141.49,52.34 140.99,52.84 140.99,57.88 v2(140.27,58.61)
  BOTTOM w0.076: UC1.AY19 139.91,60.02 139.91,59.13 140.27,58.77 v2(140.27,58.61)
  BOTTOM w0.102: JDIMM2.39 148.7,27.02 148.64,27.08 148.64,28.78 148.77,28.91 v2(149.61,28.91)
DDR_B_D41: length 49.1
  IN4 w0.084: v2(140.15,58.06) 140.8,57.41 140.8,52.73 141.19,52.33 141.19,41.11 148.74,33.56 148.74,23.15 148.83,23.06 149.47,23.06 149.61,23.21 v2(149.61,27.38)
  BOTTOM w0.076: v2(140.15,58.06) 139.9,58.31 139.9,58.79 139.74,58.95 139.74,60.67 139.87,60.8 UC1.AW19
  BOTTOM w0.102: JDIMM2.41 149.3,26.99 149.02,27.27 149.02,27.45 149.19,27.63 149.37,27.63 v2(149.61,27.38)
DDR_B_D42: length 47.9
  IN4 w0.084: v2(141.99,58.19) 142.55,57.64 142.55,56.36 142.84,56.07 142.84,54.35 143.85,53.33 143.85,43.73 151.06,36.52 151.06,35.02 152.57,33.52 152.57,31.28 153.91,29.94 153.91,23.6 153.78,23.47 153.32,23.47 153.19,23.6 v2(153.19,27.38)
  BOTTOM w0.076: UC1.AY17 141.38,59.83 141.37,59.81 141.37,59 141.99,58.38 v2(141.99,58.19)
  BOTTOM w0.102: JDIMM2.53 152.9,27.1 v2(153.19,27.38)
DDR_B_D43: length 48.6
  IN4 w0.084: v2(152.63,19.96) 153.03,20.36 153.03,22.69 152.77,22.95 152.77,30.07 151.97,30.87 151.97,33.27 147.18,38.05 147.18,39.5 143.25,43.43 143.25,53.12 142.52,53.85 v2(142.25,53.85)
  BOTTOM w0.076: UC1.AW17 141.38,60.54 141.62,60.31 141.63,60.3 141.64,60.27 141.65,60.26 141.68,60.21 141.68,60.03 141.55,59.9 141.55,59.19 142.39,58.35 142.39,57.31 142.64,57.05 142.64,54.24 142.25,53.85 v2(142.25,53.85)
  BOTTOM w0.102: JDIMM2.52 152.6,19.92 v2(152.63,19.96)
DDR_B_D44: length 49.5
  IN4 w0.084: v2(140.18,57.44) 140.55,57.07 140.55,52.71 140.89,52.36 140.89,40.96 148.44,33.41 148.44,20.62 149.11,19.96 v2(150.36,19.96)
  BOTTOM w0.076: UC1.AV19 140.14,61.32 139.58,60.76 139.58,58.88 139.73,58.72 139.73,57.89 v2(140.18,57.44)
  BOTTOM w0.102: v2(150.36,19.96) 149.6,19.19 JDIMM2.42
DDR_B_D45: length 50.8
  IN4 w0.084: v2(141.99,56.97) 141.3,56.29 141.3,52.79 141.79,52.3 141.79,41.38 150.48,32.69 150.48,29.13 150.87,28.74 150.87,21.98 v2(150.36,21.48)
  BOTTOM w0.076: v2(141.99,56.97) 141.67,56.97 v1(141.43,57.21) 141.43,58.43 141.04,58.82 141.04,59.8 140.93,59.91 140.93,60.25 141,60.41 141,60.54 140.95,60.65 140.95,60.64 140.95,60.65 140.93,60.7 140.93,60.9 140.95,60.95 140.98,61.02 141,61.06 141,61.9 140.8,62.1 UC1.AU19
  BOTTOM w0.102: JDIMM2.40 149,20.12 v2(150.36,21.48)
DDR_B_D46: length 49.2
  IN4 w0.084: v2(141.99,57.56) 142.08,57.56 142.37,57.26 142.37,56.29 142.63,56.03 142.63,54.14 143.55,53.23 143.55,43.58 148.1,39.03 148.1,38.91 147.52,38.32 147.52,38.14 147.68,37.98 147.86,37.98 148.45,38.56 148.57,38.56 148.8,38.33 148.8,38.22 148.21,37.63 148.21,37.45 148.38,37.28 148.56,37.28 149.14,37.87 149.26,37.87 149.49,37.64 149.49,37.52 148.9,36.94 148.9,36.76 149.07,36.59 149.25,36.59 149.84,37.18 149.96,37.18 150.18,36.95 150.18,36.83 149.6,36.24 149.6,36.06 149.76,35.9 149.94,35.9 150.42,36.37 150.6,36.37 150.77,36.2 150.77,36.02 150.29,35.55 150.29,35.37 152.27,33.39 152.27,31.15 153.59,29.83 153.59,29.31 v2(153.19,28.91)
  BOTTOM w0.076: v2(141.99,57.56) 141.6,57.95 141.6,58.49 141.2,58.89 141.2,59.87 141.09,59.98 141.09,60.21 141.14,60.32 141.17,60.37 141.17,60.58 141.14,60.63 141.14,60.63 141.11,60.72 141.1,60.72 141.09,60.74 141.09,60.87 141.14,60.97 141.38,61.21 UC1.AV17
  BOTTOM w0.102: JDIMM2.51 152.3,27.02 152.54,27.26 152.54,28.78 152.67,28.91 v2(153.19,28.91)
DDR_B_D47: length 50.1
  IN4 w0.084: v2(152.63,21.48) 152.23,21.88 152.23,27.06 152.28,27.1 152.28,30.13 151.67,30.74 151.67,33.15 146.88,37.93 146.88,39.35 142.95,43.28 142.95,52.91 142.62,53.24 v2(142.24,53.24)
  BOTTOM w0.076: v2(142.24,53.24) 142.81,53.8 142.81,57.12 142.55,57.38 142.55,58.42 141.72,59.26 141.72,59.84 141.85,59.96 141.85,60.24 141.82,60.3 141.81,60.3 141.8,60.34 141.68,60.6 141.68,61.81 UC1.AU17
  BOTTOM w0.102: JDIMM2.50 152,20.85 v2(152.63,21.48)
DDR_B_D48: length 88
  IN1 w0.084: v2(139.1,62.94) 139.1,62.79 140.26,61.63 140.45,61.63 140.71,61.89 140.88,61.89 141.09,61.69 141.09,61.51 140.85,61.28 140.85,61.1 141.02,60.93 141.2,60.93 141.35,61.08 141.53,61.08 141.7,60.91 141.7,60.73 141.58,60.62 141.58,60.44 141.75,60.27 141.93,60.27 142.16,60.5 142.27,60.5 143.82,58.96 143.82,57.17 146.55,54.43 147.06,54.43 147.15,54.34 147.15,53.97 147.23,53.89 147.55,53.89 147.64,53.97 147.64,54.34 147.72,54.43 148.04,54.43 148.13,54.34 148.13,53.97 148.21,53.89 148.54,53.89 148.62,53.97 148.62,54.34 148.7,54.43 150.39,54.43 150.47,54.34 150.47,53.84 150.56,53.76 150.88,53.76 150.96,53.84 150.96,54.34 151.05,54.43 153.95,54.43 154.03,54.34 154.03,54.16 154.16,54.03 154.39,54.03 154.52,54.16 154.52,54.34 154.6,54.43 154.93,54.43 155.01,54.34 155.01,54.16 155.14,54.03 155.37,54.03 155.5,54.16 155.5,54.34 155.58,54.43 156.7,54.43 158.54,52.59 169.36,52.59 169.48,52.46 169.48,52.28 169.61,52.15 169.85,52.15 169.97,52.28 169.97,52.46 170.1,52.59 170.34,52.59 170.46,52.46 170.46,52.25 170.55,52.17 170.87,52.17 170.95,52.25 170.95,52.46 171.08,52.59 171.32,52.59 171.44,52.46 171.44,52.28 171.57,52.15 171.81,52.15 171.94,52.28 171.94,52.46 172.06,52.59 172.3,52.59 172.43,52.46 172.43,52.28 172.55,52.15 172.79,52.15 172.92,52.28 172.92,52.46 173.04,52.59 173.28,52.59 173.41,52.46 173.41,52.28 173.53,52.15 173.77,52.15 173.9,52.28 173.9,52.46 174.02,52.59 174.26,52.59 174.39,52.46 174.39,52.28 174.51,52.15 175.41,52.15 197.25,30.3 197.25,28.68 197.39,28.54 197.7,28.54 197.83,28.67 v2(197.83,28.93)
  BOTTOM w0.081: v2(139.1,62.94) 139.43,63.26 UC1.AR21
  BOTTOM w0.102: v2(197.83,28.93) 196.7,27.8 JDIMM2.191
DDR_B_D49: length 89.1
  IN1 w0.084: v2(138.15,62.94) 138.15,62.12 139.37,60.9 140.07,60.9 141.28,59.69 141.87,59.1 142.37,59.1 143.23,58.23 143.23,56.68 146.79,53.12 153.02,53.12 153.28,52.87 156.61,52.87 158.06,51.43 167.18,51.43 167.62,50.99 174.92,50.99 196.06,29.85 196.06,26.72 195.4,26.05 195.4,23.28 195.27,23.15 194.69,23.15 194.56,23.28 194.56,26.3 v2(195.66,27.4)
  BOTTOM w0.081: UC1.AR22 138.47,63.26 v2(138.15,62.94)
  BOTTOM w0.102: v2(195.66,27.4) 195.45,27.4 195.33,27.53 195.33,27.73 195.2,27.85 195.02,27.85 194.9,27.73 194.9,27.57 194.74,27.4 194.57,27.4 194.3,27.13 JDIMM2.183
DDR_B_D50: length 91.4
  IN1 w0.084: v2(139.1,65.54) 139.65,64.98 139.65,62.81 140.18,62.28 140.98,62.28 144.23,59.03 144.23,57.32 146.52,55.03 156.95,55.03 158.79,53.19 175.32,53.19 198.64,29.87 198.64,22.72 198.55,22.64 197.47,22.64 197.35,22.51 197.35,22.28 197.47,22.15 197.85,22.15 197.98,22.02 197.98,21.33 v2(197.31,20.66)
  BOTTOM w0.081: UC1.AL21 139.43,65.86 v2(139.1,65.54)
  BOTTOM w0.102: JDIMM2.194 197.6,18.81 197.75,18.96 197.75,20.23 v2(197.31,20.66)
DDR_B_D51: length 91.6
  IN1 w0.084: v2(138.15,64.89) 137.43,64.89 136.93,64.39 136.93,62.04 137.5,61.47 138.2,61.47 140.92,58.75 142.22,58.75 142.83,58.14 142.83,55.35 145.43,52.74 152.77,52.74 153.24,52.27 156.37,52.27 157.82,50.81 163.71,50.81 164.13,50.39 173.83,50.39 178.08,46.14 178.83,46.14 194.84,30.14 194.84,27.08 194.24,26.49 194.24,24.75 194.16,24.67 193.57,24.67 193.49,24.58 193.49,24.26 193.57,24.18 194.16,24.18 194.24,24.09 194.24,19.28 194.1,19.13 v2(193.66,19.13)
  BOTTOM w0.081: UC1.AM22 138.47,65.21 v2(138.15,64.89)
  BOTTOM w0.102: JDIMM2.180 193.4,18.88 v2(193.66,19.13)
DDR_B_D52: length 90.4
  IN1 w0.084: v2(195.66,28.93) 195.66,28.66 195.55,28.55 195.27,28.55 195.14,28.68 195.14,30.28 178.61,46.81 178.49,46.81 178.25,46.57 178.07,46.57 177.91,46.74 177.91,46.92 178.15,47.16 178.15,47.34 177.98,47.51 177.8,47.51 177.55,47.25 177.43,47.25 177.21,47.48 177.21,47.6 177.46,47.85 177.46,48.03 177.29,48.2 177.11,48.2 176.86,47.95 176.74,47.95 176.51,48.18 176.51,48.29 176.76,48.55 176.76,48.73 176.6,48.89 176.42,48.89 176.17,48.64 176.05,48.64 175.82,48.87 175.82,48.99 176.07,49.24 176.07,49.42 175.9,49.59 175.72,49.59 175.48,49.34 175.3,49.34 175.07,49.58 175.07,49.7 175.37,50 175.37,50.12 175.14,50.35 175.02,50.35 174.72,50.04 174.6,50.04 173.95,50.69 167.31,50.69 167.18,50.82 167.18,51 167.06,51.13 166.77,51.13 166.65,51 166.65,50.82 166.52,50.69 166.28,50.69 166.15,50.82 166.15,51.04 166.07,51.13 165.75,51.13 165.66,51.04 165.66,50.82 165.54,50.69 165.3,50.69 165.17,50.82 165.17,51.04 165.09,51.13 164.77,51.13 164.68,51.04 164.68,50.82 164.56,50.69 164.32,50.69 164.19,50.82 164.19,51.04 164.11,51.13 157.93,51.13 156.49,52.57 153.26,52.57 152.9,52.93 146.55,52.93 145.51,53.97 145.39,53.97 145.07,53.65 144.95,53.65 144.73,53.87 144.73,53.99 145.05,54.31 145.05,54.43 144.82,54.66 144.7,54.66 144.38,54.34 144.25,54.34 143.03,55.56 143.03,58.19 142.3,58.92 141.8,58.92 140,60.72 139.3,60.72 137.77,62.25 137.77,64.07 137.95,64.25 v2(138.12,64.25)
  BOTTOM w0.081: v2(138.12,64.25) 138.43,64.56 UC1.AN22
  BOTTOM w0.102: v2(195.66,28.93) 195.49,29.1 194.16,29.1 193.7,28.65 JDIMM2.181
DDR_B_D53: length 89.3
  IN1 w0.084: v2(139.1,63.59) 139.47,63.21 139.47,62.74 140.11,62.1 140.92,62.1 144.01,59.01 144.01,57.25 146.53,54.73 156.82,54.73 158.66,52.89 175.19,52.89 198.32,29.76 198.32,23.15 198.19,23.02 197.39,23.02 197.26,23.15 197.26,25.88 197.83,26.45 v2(197.83,27.4)
  BOTTOM w0.081: v2(139.1,63.59) 139.43,63.91 UC1.AP21
  BOTTOM w0.102: JDIMM2.193 197.3,27.32 197.38,27.4 v2(197.83,27.4)
DDR_B_D54: length 91.5
  IN1 w0.084: v2(197.31,19.13) 197.71,19.53 197.71,20.63 197.88,20.8 198.6,20.8 198.96,21.16 198.96,29.97 175.44,53.49 158.91,53.49 157.07,55.33 146.5,55.33 144.46,57.36 144.46,59.05 140.96,62.55 140.67,62.55 140.43,62.8 140.43,65.72 140.26,65.89 139.34,65.89 v2(139.1,66.12)
  BOTTOM w0.081: UC1.AK21 139.49,66.51 v2(139.1,66.12)
  BOTTOM w0.102: JDIMM2.192 197,18.82 v2(197.31,19.13)
DDR_B_D55: length 92.2
  IN1 w0.084: v2(193.66,20.66) 193.19,21.13 193.19,22.47 193.27,22.55 193.6,22.55 193.73,22.68 193.73,22.92 193.6,23.04 193.27,23.04 193.19,23.13 193.19,25.88 194.52,27.21 194.52,30 178.68,45.84 177.95,45.84 173.71,50.09 164.01,50.09 163.59,50.51 157.7,50.51 156.24,51.97 153.16,51.97 152.64,52.49 145.26,52.49 142.62,55.13 142.62,58.09 142.14,58.57 140.86,58.57 138.13,61.3 137.42,61.3 136.75,61.97 136.75,64.45 137.77,65.48 137.77,65.81 v2(138.15,66.19)
  BOTTOM w0.081: UC1.AK22 138.47,66.51 v2(138.15,66.19)
  BOTTOM w0.102: JDIMM2.182 194,18.82 194.09,18.91 194.09,20.23 v2(193.66,20.66)
DDR_B_D56: length 56.9
  IN4 w0.084: v2(140.05,64.24) 139.69,63.88 139.69,61.98 141.71,59.96 141.71,59.31 141.96,59.05 142.35,59.05 143.12,58.28 143.12,56.62 143.52,56.21 143.52,54.78 144.98,53.32 144.98,44.2 152.72,36.46 152.72,36.34 152.15,35.77 152.15,35.59 152.32,35.43 152.5,35.43 153.06,35.99 153.18,35.99 153.41,35.76 153.41,35.64 152.79,35.02 152.79,34.84 152.95,34.67 153.13,34.67 153.76,35.3 153.88,35.3 154.1,35.07 154.1,34.95 153.47,34.31 153.47,34.16 153.66,33.97 153.66,32.65 153.78,32.52 154.23,32.52 154.36,32.39 154.36,32.16 154.23,32.03 153.85,32.03 153.72,31.9 153.72,31.67 153.85,31.54 155.77,31.54 155.9,31.41 155.9,31.18 155.77,31.05 154.83,31.05 154.7,30.92 154.7,30.68 154.83,30.56 155.77,30.56 155.9,30.43 155.9,30.19 155.77,30.07 155.27,30.07 155.14,29.94 155.14,28.64 155.24,28.53 155.65,28.53 155.75,28.64 v2(155.75,28.91)
  BOTTOM w0.081: v2(140.05,64.24) 140.38,64.56 UC1.AN20
  BOTTOM w0.102: JDIMM2.57 154.1,27.01 155.14,28.05 155.14,28.29 v2(155.75,28.91)
DDR_B_D57: length 55.6
  IN4 w0.084: v2(155.75,27.38) 155.75,26.07 155.88,25.95 156.12,25.95 156.24,26.07 156.24,31.67 156.07,31.84 154.8,31.84 154.67,31.97 154.67,32.2 154.8,32.33 156.11,32.33 156.24,32.46 156.24,32.69 156.11,32.82 154.08,32.82 153.96,32.95 153.96,33.18 154.08,33.31 155.82,33.31 155.94,33.44 155.94,33.67 155.82,33.8 154.63,33.8 154.48,33.95 154.48,35.15 154.23,35.39 145.28,44.35 145.28,54.52 144.01,55.79 144.01,56.03 143.31,56.73 143.31,58.37 142.6,59.08 142.6,59.55 140.05,62.09 v2(140.05,62.94)
  BOTTOM w0.081: v2(140.05,62.94) 140.38,63.26 UC1.AR20
  BOTTOM w0.102: v2(155.75,27.38) 155.08,27.38 154.7,27 JDIMM2.59
DDR_B_D58: length 57.8
  IN4 w0.084: v2(140.97,66.06) 141.43,65.59 141.43,65.38 141.84,64.98 141.84,61.81 143.79,59.86 143.79,59.51 144.45,58.85 144.45,57.07 147.42,54.1 147.42,45.71 156.8,36.33 156.8,36.21 156.71,36.11 156.71,35.94 156.87,35.77 157.05,35.77 157.15,35.86 157.27,35.86 157.49,35.63 157.49,35.52 157.4,35.42 157.4,35.24 157.57,35.08 157.75,35.08 157.84,35.17 157.96,35.17 158.19,34.94 158.19,34.82 158.1,34.74 158.1,34.56 159,33.66 159,23.6 158.87,23.47 158.4,23.47 158.27,23.6 v2(158.27,27.38)
  BOTTOM w0.081: v2(140.97,66.06) 141.4,66.48 UC1.AK18
  BOTTOM w0.102: v2(158.27,27.38) 157.7,26.82 JDIMM2.69
DDR_B_D59: length 57.4
  IN4 w0.084: v2(158.27,28.91) 158.54,28.91 158.68,29.05 158.68,30.12 158.6,30.21 158.23,30.21 158.15,30.29 158.15,30.61 158.23,30.7 158.6,30.7 158.68,30.78 158.68,31.1 158.6,31.19 158.23,31.19 158.15,31.27 158.15,31.59 158.23,31.68 158.6,31.68 158.68,31.76 158.68,32.08 158.6,32.17 158.23,32.17 158.15,32.25 158.15,32.57 158.23,32.66 158.6,32.66 158.68,32.74 158.68,33.06 158.55,33.18 158.28,33.18 158.15,33.31 158.15,34.07 156.2,36.02 156.2,36.14 156.32,36.26 156.32,36.38 156.09,36.61 155.98,36.61 155.85,36.49 155.73,36.49 155.51,36.71 155.51,36.83 155.63,36.96 155.63,37.07 155.4,37.3 155.28,37.3 155.16,37.18 155.04,37.18 154.81,37.41 154.81,37.53 154.94,37.65 154.94,37.77 154.71,38 154.59,38 154.47,37.87 154.35,37.87 154.12,38.1 154.12,38.22 154.24,38.34 154.24,38.46 154.01,38.69 153.9,38.69 153.77,38.57 153.65,38.57 153.43,38.79 153.43,38.91 153.55,39.04 153.55,39.15 153.32,39.38 153.2,39.38 153.08,39.26 152.96,39.26 152.73,39.49 152.73,39.61 152.86,39.73 152.86,39.85 152.63,40.08 152.51,40.08 152.39,39.95 152.27,39.95 151.98,40.24 151.98,40.36 152.11,40.48 152.11,40.6 151.88,40.83 151.76,40.83 151.63,40.7 151.52,40.7 151.29,40.93 151.29,41.05 151.41,41.17 151.41,41.29 151.18,41.52 151.07,41.52 150.94,41.4 150.82,41.4 150.59,41.62 150.59,41.74 150.72,41.87 150.72,41.99 150.49,42.21 150.37,42.21 150.25,42.09 150.13,42.09 149.9,42.32 149.9,42.44 150.03,42.56 150.03,42.68 149.8,42.91 149.68,42.91 149.55,42.78 149.44,42.78 149.21,43.01 149.21,43.13 149.33,43.25 149.33,43.37 149.1,43.6 148.99,43.6 148.86,43.48 148.74,43.48 148.51,43.7 148.51,43.82 148.64,43.95 148.64,44.07 148.41,44.29 148.29,44.29 148.17,44.17 148.05,44.17 147.82,44.4 147.82,44.52 147.95,44.64 147.95,44.76 147.72,44.99 147.6,44.99 147.49,44.88 147.31,44.88 147.15,45.04 147.15,45.22 147.26,45.33 147.26,45.45 147.08,45.62 147.08,54.19 144.22,57.05 144.22,58.83 143.59,59.46 143.59,59.81 141.63,61.77 141.63,64.85 v2(141.01,65.47)
  BOTTOM w0.081: v2(141.01,65.47) 141.39,65.86 UC1.AL18
  BOTTOM w0.102: JDIMM2.67 157.1,27.74 v2(158.27,28.91)
DDR_B_D60: length 58.4
  IN4 w0.084: v2(155.17,19.96) 154.4,20.73 154.4,30.14 153.06,31.48 153.06,33.72 151.56,35.22 151.56,36.72 144.34,43.93 144.34,53.26 143.12,54.49 143.12,56.11 142.74,56.49 142.74,58.08 142.17,58.65 141.74,58.65 141.3,59.08 141.3,59.66 140.11,60.86 139.35,60.86 138.67,61.53 138.67,66.2 138.95,66.48 139.82,66.48 v2(140.05,66.25)
  BOTTOM w0.081: v2(140.05,66.25) 140.31,66.51 UC1.AK20
  BOTTOM w0.102: v2(155.17,19.96) 154.4,19.18 JDIMM2.58
DDR_B_D61: length 57.6
  IN4 w0.084: v2(155.17,21.48) 154.82,21.48 154.7,21.61 154.7,23.15 154.78,23.24 155.24,23.24 155.37,23.36 155.37,23.6 155.24,23.73 154.78,23.73 154.7,23.81 154.7,24.13 154.78,24.22 155.24,24.22 155.37,24.34 155.37,24.58 155.24,24.71 154.78,24.71 154.7,24.79 154.7,30.27 153.36,31.61 153.36,33.85 151.85,35.35 151.85,36.87 144.66,44.06 144.66,53.4 143.32,54.73 143.32,56.16 142.94,56.53 142.94,58.15 142.24,58.85 141.86,58.85 141.51,59.21 141.51,59.91 139.52,61.9 139.52,64.35 v2(140.05,64.89)
  BOTTOM w0.081: UC1.AM20 140.38,65.21 v2(140.05,64.89)
  BOTTOM w0.102: JDIMM2.56 153.8,20.11 v2(155.17,21.48)
DDR_B_D62: length 54.1
  IN4 w0.084: v2(141.01,62.94) 141.01,61.91 143.24,59.67 143.24,59.32 143.88,58.69 143.88,56.91 146.44,54.34 146.44,44.88 157.53,33.79 157.53,23.98 157.4,23.85 157.15,23.85 157.02,23.72 157.02,22.78 157.15,22.65 157.45,22.65 157.53,22.56 157.53,22.24 157.45,22.16 157.21,22.16 157.09,22.03 157.09,21.79 157.21,21.67 157.45,21.67 157.53,21.58 157.53,20.38 v2(157.95,19.96)
  BOTTOM w0.081: UC1.AR18 141.33,63.26 v2(141.01,62.94)
  BOTTOM w0.102: v2(157.95,19.96) 158,19.91 JDIMM2.70
DDR_B_D63: length 55.1
  IN4 w0.084: v2(157.95,21.48) 158.29,21.48 158.42,21.61 158.42,22.8 158.29,22.93 157.56,22.93 157.43,23.05 157.43,23.29 157.56,23.42 157.72,23.42 157.85,23.54 157.85,33.92 146.76,45.01 146.76,54.27 144.05,56.98 144.05,58.76 143.42,59.39 143.42,59.74 141.4,61.76 141.4,63.19 v2(141.01,63.59)
  BOTTOM w0.081: v2(141.01,63.59) 141.33,63.91 UC1.AP18
  BOTTOM w0.102: JDIMM2.68 157.4,20.93 v2(157.95,21.48)
DDR_B_DQS0: length 80.9
  IN1 w0.091: v2(132.92,58.33) 133.1,58.5 133.43,58.5 133.6,58.67 133.71,58.67 133.97,58.4 133.97,53.37 133.74,53.13 133.74,49.13 140.25,42.62 152.64,42.62 154.54,40.72 169.71,40.72 176.82,33.62 177.47,33.62 180.15,30.93 180.15,26.95 180.38,26.73 180.77,26.73 181,26.95 181,28.66 181.11,28.77 181.17,28.77 v2(181.4,28.55)
  BOTTOM w0.081: v2(132.92,58.33) 132.77,58.49 132.55,58.49 132.3,58.73 132.3,59.54 132.76,60 132.76,60.21 132.71,60.32 132.71,60.32 132.69,60.37 132.69,60.58 132.74,60.69 132.74,60.69 132.76,60.73 132.76,61.22 132.92,61.37 132.92,61.55 UC1.AV30
  BOTTOM w0.102: JDIMM2.137 180.5,27.06 180.27,27.29 180.27,27.73 180,27.99 180,28.85 180.14,29 180.66,29 180.79,28.86 181.08,28.86 v2(181.4,28.55)
DDR_B_DQS1: length 49.5
  IN4 w0.091: v2(136.51,56.24) 136.51,56.05 136.4,55.94 136.07,55.94 135.37,55.24 135.37,34.77 140.06,30.07 140.06,21.71 140.3,21.47 140.7,21.47 140.84,21.33 v2(140.84,21.1)
  BOTTOM w0.076: UC1.AW26 135.36,60.91 135.36,60.7 135.33,60.65 135.33,60.65 135.29,60.56 135.28,60.54 135.28,60.41 135.31,60.35 135.33,60.3 135.33,60.3 135.36,60.25 135.36,59.83 134.99,59.47 134.99,59.09 135.45,58.63 135.45,56.26 135.82,55.89 136.16,55.89 v2(136.51,56.24)
  BOTTOM w0.102: v2(140.84,21.1) 140.84,21.34 140.75,21.43 140.52,21.43 140.31,21.22 140.31,19.15 140.6,18.86 JDIMM2.12
DDR_B_DQS2: length 88.4
  IN1 w0.091: v2(134.44,64.89) 134.44,64.88 134.22,64.65 134.04,64.65 133.86,64.46 133.86,62.34 135.07,61.13 135.07,60.48 136.91,58.64 136.91,52.51 137.47,51.96 137.47,50.52 141.52,46.47 145.68,46.47 146.08,46.06 154.07,46.06 155.97,44.17 171.84,44.17 186.21,29.79 186.21,21.79 185.23,20.8 184.99,20.8 v2(184.75,21.04)
  BOTTOM w0.081: UC1.AM28 134.77,65.21 v2(134.44,64.89)
  BOTTOM w0.102: JDIMM2.154 185.6,18.77 185.6,18.77 185.41,18.96 185.41,19.34 185.85,19.78 185.85,20.52 185.55,20.82 184.97,20.82 v2(184.75,21.04)
DDR_B_DQS3: length 52.7
  IN4 w0.091: v2(145.8,28.53) 145.51,28.82 145.31,28.82 145.14,28.99 145.14,30.46 145.05,30.55 144.61,30.55 144.38,30.78 144.38,31.17 144.61,31.4 145.54,31.4 145.67,31.52 145.67,31.84 145.54,31.97 144.3,31.97 143.55,32.71 143.55,33.91 141.86,35.6 141.86,35.92 142.31,36.37 142.31,36.55 142.1,36.76 141.92,36.76 141.47,36.32 141.15,36.32 140.88,36.59 140.88,36.91 141.32,37.36 141.32,37.54 141.15,37.71 140.97,37.71 140.52,37.27 140.2,37.27 139.93,37.54 139.93,37.86 140.38,38.31 140.38,38.49 140.2,38.66 140.02,38.66 139.58,38.22 139.25,38.22 138.98,38.49 138.98,38.81 139.39,39.22 139.39,39.48 138.84,40.03 138.84,51.88 137.99,52.73 137.99,58.64 137.61,59.02 137.61,59.89 135.79,61.71 135.79,64.46 135.98,64.65 136.22,64.65 136.35,64.78 v2(136.35,64.89)
  BOTTOM w0.081: v2(136.35,64.89) 136.67,65.21 UC1.AM25
  BOTTOM w0.102: v2(145.8,28.53) 145.59,28.74 145.36,28.74 145.25,28.63 145.25,27.53 145.51,27.27 145.51,26.95 145.7,26.76 JDIMM2.29
DDR_B_DQS4: length 83.5
  IN1 w0.091: v2(191.83,28.55) 191.6,28.78 191.27,28.78 191.06,29 191.06,29.68 191.2,29.83 191.2,30.41 183.89,37.73 183.76,37.73 183.62,37.59 183.3,37.59 183.02,37.86 183.02,38.19 183.16,38.33 183.16,38.46 182.94,38.68 182.81,38.68 182.67,38.54 182.35,38.54 182.07,38.81 182.07,39.14 182.21,39.28 182.21,39.4 181.99,39.63 181.86,39.63 181.72,39.49 181.4,39.49 181.12,39.76 181.12,40.09 181.26,40.22 181.26,40.35 181.04,40.58 180.91,40.58 180.77,40.44 180.45,40.44 180.18,40.71 180.18,41.03 180.31,41.17 180.31,41.3 180.09,41.52 179.96,41.52 179.82,41.39 179.5,41.39 173.27,47.62 172.84,47.62 172.42,48.03 157.18,48.03 155.3,49.92 154.89,49.92 154.8,49.83 154.8,49.73 154.59,49.51 154.16,49.51 153.93,49.74 153.93,49.81 153.83,49.92 153.46,49.92 153.37,49.82 153.37,49.74 153.14,49.51 152.76,49.51 152.53,49.74 152.53,49.82 152.44,49.92 152.12,49.92 152.03,49.82 152.03,49.74 151.8,49.51 151.42,49.51 151.19,49.74 151.19,49.82 151.1,49.92 150.78,49.92 150.69,49.82 150.69,49.74 150.46,49.51 150.08,49.51 149.85,49.74 149.85,49.82 149.5,50.17 143.01,50.17 140.29,52.89 140.06,52.89 139.51,53.43 139.51,56.09 139.32,56.28 139.32,57 139.62,57.29 139.62,57.91 139.51,58.02 139.24,58.02 138.93,57.72 138.72,57.72 v2(138.54,57.54)
  BOTTOM w0.076: UC1.AV22 138.28,61.78 137.88,61.38 137.88,61.37 137.82,61.23 137.82,61.02 137.84,60.97 137.89,60.85 137.89,60.73 137.84,60.62 137.84,60.63 137.82,60.58 137.82,60.37 137.84,60.32 137.84,60.32 137.89,60.21 137.89,60.03 137.78,59.91 137.78,59.3 138.1,58.98 138.1,57.98 v2(138.54,57.54)
  BOTTOM w0.102: JDIMM2.171 190.7,27.07 190.49,27.28 190.49,28.85 190.63,28.99 191.17,28.99 191.38,28.78 191.59,28.78 v2(191.83,28.55)
DDR_B_DQS5: length 49.3
  IN4 w0.091: v2(142.25,55.77) 142.25,55.57 142.15,55.47 141.85,55.47 141.61,55.24 141.61,53.05 142.29,52.38 142.29,43.01 142.69,42.61 142.69,42.48 142.29,42.08 142.29,41.75 142.56,41.48 142.88,41.48 143.28,41.88 143.41,41.88 143.63,41.66 143.63,41.53 143.15,41.04 143.15,40.72 143.42,40.45 143.75,40.45 144.23,40.93 144.36,40.93 144.58,40.71 144.58,40.58 144.1,40.09 144.1,39.77 144.37,39.5 144.7,39.5 145.18,39.98 145.31,39.98 145.53,39.76 145.53,39.63 145.05,39.14 145.05,38.82 145.32,38.55 145.64,38.55 145.86,38.77 146.04,38.77 146.22,38.59 146.22,38.41 146,38.2 146,37.87 151,32.87 151,29.3 151.4,28.91 151.65,28.91 151.79,28.77 v2(151.79,28.53)
  BOTTOM w0.076: v2(142.25,55.77) 142.25,55.61 142.09,55.46 141.6,55.46 140.88,56.18 140.88,58.78 140.26,59.4 140.26,59.73 140.49,59.96 140.49,60.25 140.47,60.3 140.46,60.3 140.41,60.41 140.41,60.54 140.42,60.56 140.46,60.65 140.47,60.65 140.49,60.7 140.49,60.91 UC1.AW18
  BOTTOM w0.102: JDIMM2.47 151.1,26.98 150.93,27.15 150.93,28.62 151.24,28.93 151.5,28.93 151.79,28.64 v2(151.79,28.53)
DDR_B_DQS6: length 89.9
  IN1 w0.091: v2(196.04,20.28) 195.76,20.56 195.68,20.56 195.47,20.77 195.47,22.14 196.2,22.87 196.2,26.06 196.59,26.45 196.59,30.03 175.13,51.48 169.33,51.48 168.9,51.92 158.26,51.92 156.82,53.37 146.91,53.37 143.43,56.84 143.43,58.76 142.3,59.89 141.43,59.89 139.45,61.87 139.44,61.87 139.43,61.88 139.12,61.88 138.54,62.46 138.54,64.46 138.72,64.63 138.96,64.63 139.08,64.76 v2(139.08,64.96)
  BOTTOM w0.081: v2(139.08,64.96) 139.33,65.21 UC1.AM21
  BOTTOM w0.102: v2(196.04,20.28) 196.04,20.41 195.93,20.52 195.74,20.52 195.6,20.38 195.6,19.1 195.8,18.9 JDIMM2.188
DDR_B_DQS7: length 56.4
  IN4 w0.091: v2(156.44,21.1) 156.44,21.23 156.35,21.32 156.09,21.32 155.86,21.54 155.86,24.97 156.74,25.84 156.74,33.61 145.77,44.57 145.77,54.52 143.52,56.77 143.52,58.51 142.88,59.15 142.88,59.53 140.42,61.99 140.42,64.46 140.6,64.64 140.76,64.64 v2(141.01,64.89)
  BOTTOM w0.081: v2(141.01,64.89) 141.33,65.21 UC1.AM18
  BOTTOM w0.102: JDIMM2.64 156.2,18.87 155.92,19.15 155.92,21.2 156.03,21.32 156.23,21.32 v2(156.44,21.1)
DDR_B_DQS#0: length 80.8
  IN1 w0.091: v2(181.4,29.31) 181.46,29.24 181.46,29.06 181.34,28.94 181.04,28.94 180.82,28.73 180.82,27.03 180.7,26.9 180.45,26.9 180.33,27.03 180.33,31.01 177.54,33.79 176.89,33.79 169.79,40.89 154.61,40.89 152.71,42.79 140.32,42.79 133.91,49.2 133.91,53.06 134.15,53.3 134.15,58.48 133.78,58.84 133.53,58.84 133.36,58.67 133.04,58.67 132.92,58.79 v2(132.92,58.98)
  BOTTOM w0.081: v2(132.92,58.98) 132.92,58.8 132.8,58.68 132.61,58.68 132.49,58.79 132.49,59.5 132.93,59.94 132.93,60.25 132.9,60.3 132.9,60.3 132.85,60.41 132.85,60.54 132.9,60.65 132.9,60.65 132.93,60.7 132.93,61.02 133.03,61.13 UC1.AW30
  BOTTOM w0.102: v2(181.4,29.31) 181.15,29.06 180.87,29.06 180.74,29.19 180.06,29.19 179.81,28.93 179.81,27.91 180.07,27.65 180.07,27.22 179.9,27.04 JDIMM2.135
DDR_B_DQS#1: length 49.5
  IN4 w0.091: v2(140.84,21.86) 140.63,21.65 140.37,21.65 140.24,21.78 140.24,30.14 135.54,34.84 135.54,55.15 136.15,55.76 136.34,55.76 v2(136.51,55.59)
  BOTTOM w0.076: UC1.AV26 135.35,61.55 135.35,61.37 135.19,61.22 135.19,60.73 135.17,60.69 135.17,60.69 135.12,60.58 135.12,60.37 135.14,60.32 135.14,60.32 135.19,60.21 135.19,59.9 134.82,59.53 134.82,59.02 135.28,58.56 135.28,56.19 135.75,55.73 136.37,55.73 v2(136.51,55.59)
  BOTTOM w0.102: JDIMM2.10 140,18.85 140.12,18.97 140.12,21.3 140.44,21.62 140.67,21.62 140.84,21.79 v2(140.84,21.86)
DDR_B_DQS#2: length 88.4
  IN1 w0.091: v2(184.75,20.28) 184.75,20.47 184.9,20.63 185.3,20.63 186.39,21.72 186.39,29.87 171.91,44.34 156.04,44.34 154.14,46.24 146.15,46.24 145.75,46.64 141.59,46.64 137.64,50.59 137.64,52.03 137.08,52.58 137.08,58.71 135.24,60.55 135.24,61.2 134.03,62.42 134.03,64.39 134.11,64.48 134.2,64.48 v2(134.44,64.24)
  BOTTOM w0.081: v2(134.44,64.24) 134.77,64.56 UC1.AN28
  BOTTOM w0.102: JDIMM2.152 185,18.8 185.22,19.02 185.22,19.42 185.66,19.86 185.66,20.44 185.47,20.63 184.88,20.63 184.75,20.5 v2(184.75,20.28)
DDR_B_DQS#3: length 52.6
  IN4 w0.091: v2(136.35,64.24) 136.35,64.34 136.21,64.48 136.05,64.48 135.96,64.39 135.96,61.78 137.78,59.96 137.78,59.09 138.16,58.72 138.16,52.8 139.01,51.95 139.01,40.1 139.56,39.55 139.56,39.15 139.15,38.74 139.15,38.56 139.32,38.39 139.5,38.39 139.95,38.83 140.27,38.83 140.55,38.56 140.55,38.24 140.1,37.79 140.1,37.61 140.27,37.44 140.45,37.44 140.9,37.89 141.22,37.89 141.5,37.61 141.5,37.29 141.05,36.84 141.05,36.66 141.22,36.49 141.4,36.49 141.85,36.94 142.17,36.94 142.49,36.62 142.49,36.3 142.04,35.85 142.04,35.68 143.73,33.99 143.73,32.78 144.37,32.14 145.62,32.14 145.84,31.91 145.84,31.45 145.62,31.22 144.68,31.22 144.56,31.1 144.56,30.85 144.68,30.73 145.12,30.73 145.31,30.53 145.31,29.07 145.38,28.99 145.51,28.99 v2(145.8,29.29)
  BOTTOM w0.081: UC1.AN25 136.52,64.56 136.35,64.39 v2(136.35,64.24)
  BOTTOM w0.102: v2(145.8,29.29) 145.44,28.93 145.28,28.93 145.06,28.71 145.06,27.45 145.31,27.19 145.31,26.92 145.1,26.71 JDIMM2.27
DDR_B_DQS#4: length 83.5
  IN1 w0.091: v2(191.83,29.31) 191.83,29.13 191.66,28.95 191.34,28.95 191.23,29.07 191.23,29.61 191.38,29.76 191.38,30.48 183.96,37.9 183.69,37.9 183.55,37.76 183.37,37.76 183.19,37.94 183.19,38.12 183.33,38.25 183.33,38.53 183.01,38.85 182.74,38.85 182.6,38.71 182.42,38.71 182.25,38.89 182.25,39.07 182.38,39.2 182.38,39.48 182.06,39.8 181.79,39.8 181.65,39.66 181.47,39.66 181.3,39.83 181.3,40.01 181.43,40.15 181.43,40.43 181.11,40.75 180.84,40.75 180.7,40.61 180.52,40.61 180.35,40.78 180.35,40.96 180.49,41.1 180.49,41.37 180.16,41.7 179.89,41.7 179.75,41.56 179.57,41.56 173.34,47.79 172.91,47.79 172.49,48.21 157.26,48.21 155.37,50.09 154.81,50.09 154.63,49.91 154.63,49.8 154.52,49.69 154.23,49.69 154.1,49.81 154.1,49.89 153.9,50.09 153.39,50.09 153.2,49.9 153.2,49.81 153.07,49.69 152.83,49.69 152.7,49.81 152.7,49.9 152.51,50.09 152.05,50.09 151.86,49.9 151.86,49.81 151.73,49.69 151.49,49.69 151.36,49.81 151.36,49.9 151.17,50.09 150.71,50.09 150.52,49.9 150.52,49.81 150.39,49.69 150.15,49.69 150.02,49.81 150.02,49.9 149.57,50.34 143.08,50.34 140.37,53.06 140.13,53.06 139.69,53.5 139.69,56.16 139.5,56.35 139.5,56.93 139.79,57.22 139.79,57.98 139.58,58.19 139.16,58.19 138.86,57.89 138.63,57.89 138.54,57.98 v2(138.54,58.19)
  BOTTOM w0.076: UC1.AW22 138.28,61.25 138.2,61.33 138.06,61.33 138.03,61.3 137.98,61.19 137.98,61.06 138.03,60.95 138.06,60.89 138.06,60.7 138.04,60.65 138.03,60.65 137.99,60.56 137.98,60.54 137.98,60.41 138.01,60.35 138.03,60.3 138.04,60.3 138.04,60.3 138.04,60.3 138.06,60.25 138.06,59.96 137.94,59.84 137.94,59.37 138.27,59.04 138.27,58.33 138.41,58.19 v2(138.54,58.19)
  BOTTOM w0.102: v2(191.83,29.31) 191.83,29.07 191.74,28.98 191.46,28.98 191.25,29.18 190.55,29.18 190.3,28.93 190.3,27.19 190.1,27 JDIMM2.169
DDR_B_DQS#5: length 49.4
  IN4 w0.091: v2(151.79,29.29) 151.57,29.08 151.47,29.08 151.17,29.37 151.17,32.94 146.17,37.94 146.17,38.12 146.39,38.34 146.39,38.67 146.11,38.94 145.79,38.94 145.57,38.72 145.39,38.72 145.22,38.89 145.22,39.07 145.71,39.56 145.71,39.83 145.38,40.15 145.11,40.15 144.62,39.67 144.44,39.67 144.27,39.84 144.27,40.02 144.76,40.51 144.76,40.78 144.43,41.1 144.16,41.1 143.67,40.62 143.5,40.62 143.32,40.79 143.32,40.97 143.81,41.46 143.81,41.73 143.48,42.05 143.21,42.05 142.81,41.65 142.63,41.65 142.46,41.82 142.46,42 142.86,42.4 142.86,42.68 142.46,43.08 142.46,52.45 141.78,53.12 141.78,55.17 141.92,55.3 142.06,55.3 v2(142.25,55.12)
  BOTTOM w0.076: UC1.AV18 140.48,61.55 140.48,61.37 140.33,61.22 140.33,60.73 140.31,60.69 140.3,60.69 140.25,60.58 140.25,60.37 140.27,60.32 140.28,60.32 140.33,60.21 140.33,60.03 140.09,59.79 140.09,59.33 140.7,58.71 140.7,56.11 141.53,55.28 142.08,55.28 v2(142.25,55.12)
  BOTTOM w0.102: JDIMM2.45 150.5,27.03 150.74,27.27 150.74,28.7 151.16,29.12 151.62,29.12 v2(151.79,29.29)
DDR_B_DQS#6: length 89.8
  IN1 w0.091: v2(139.1,64.2) 139.1,64.33 138.97,64.46 138.79,64.46 138.71,64.38 138.71,62.53 139.2,62.05 139.5,62.05 139.51,62.04 139.52,62.04 141.5,60.07 142.38,60.07 143.61,58.83 143.61,56.91 146.98,53.54 156.89,53.54 158.33,52.09 168.97,52.09 169.41,51.66 175.2,51.66 196.76,30.1 196.76,26.38 196.37,25.99 196.37,22.8 195.64,22.06 195.64,20.84 195.75,20.73 195.97,20.73 196.04,20.81 v2(196.04,21.04)
  BOTTOM w0.081: UC1.AN21 139.46,64.56 v2(139.1,64.2)
  BOTTOM w0.102: JDIMM2.186 195.2,18.89 195.41,19.1 195.41,20.46 195.66,20.71 195.95,20.71 196.04,20.81 v2(196.04,21.04)
DDR_B_DQS#7: length 56.4
  IN4 w0.091: v2(156.44,21.86) 156.44,21.59 156.35,21.5 156.16,21.5 156.04,21.62 156.04,24.9 156.91,25.77 156.91,33.68 145.94,44.65 145.94,54.59 143.69,56.84 143.69,58.58 143.05,59.22 143.05,59.6 140.59,62.06 140.59,64.38 140.67,64.47 140.77,64.47 v2(141.01,64.24)
  BOTTOM w0.081: v2(141.01,64.24) 141.33,64.56 UC1.AN18
  BOTTOM w0.102: JDIMM2.62 155.6,18.86 155.73,18.99 155.73,21.28 155.95,21.51 156.32,21.51 156.44,21.63 v2(156.44,21.86)
DDR_B_MA0: length 81.8
  IN1 w0.089: 125.04,51.37 125.04,52.13 124.97,52.2 124.97,58.62 125.21,58.86 125.21,62.84 125.34,62.96 125.34,63.04 125.62,63.32 126.02,63.32 126.28,63.59 v2(126.72,63.59)
  IN1 w0.132: 125.04,51.37 125.04,46.57 138.92,32.69 148.31,32.69 148.85,32.15 152.87,32.15 153.16,31.86 159.69,31.86 159.86,31.7 166.07,31.7 166.8,30.97 166.8,26.08 169.67,23.21 169.67,21.16 169.67,21.16 169.67,21.13 v2(169.24,20.71)
  BOTTOM w0.081: v2(126.72,63.59) 127.05,63.91 UC1.AP40
  BOTTOM w0.17: JDIMM2.98 168.8,20.27 v2(169.24,20.71)
DDR_B_MA1: length 81.3
  IN1 w0.089: 125.87,51.37 125.87,52.37 126.05,52.55 126.05,57.24 125.67,57.62 125.67,62.28 126.32,62.94 v2(126.72,62.94)
  IN1 w0.132: 125.87,51.37 125.87,46.91 139.27,33.51 153.48,33.51 153.61,33.38 153.61,32.81 153.74,32.69 154.02,32.69 154.15,32.81 154.15,33.38 154.28,33.51 154.56,33.51 154.69,33.38 154.69,32.81 154.81,32.69 155.1,32.69 155.23,32.81 155.23,33.38 155.35,33.51 155.64,33.51 155.76,33.38 155.76,32.81 155.89,32.69 156.18,32.69 156.3,32.81 156.3,33.38 156.43,33.51 156.71,33.51 156.84,33.38 156.84,32.81 156.97,32.69 157.25,32.69 157.38,32.81 157.38,33.38 157.51,33.51 157.79,33.51 157.92,33.38 157.92,32.81 158.05,32.69 158.33,32.69 158.46,32.81 158.46,33.38 158.58,33.51 158.87,33.51 159,33.38 159,32.81 159.12,32.69 159.41,32.69 159.53,32.81 159.53,33.12 159.66,33.25 159.95,33.25 160.07,33.12 160.07,32.65 160.2,32.52 166.41,32.52 167.88,31.05 167.88,30.84 167.62,30.57 167.62,29.46 167.75,29.33 168.04,29.33 168.17,29.46 v2(168.17,29.69)
  BOTTOM w0.081: v2(126.72,62.94) 127.05,63.26 UC1.AR40
  BOTTOM w0.17: v2(168.17,29.69) 168.74,29.69 169.02,29.4 169.02,27.61 168.5,27.09 JDIMM2.97
DDR_B_MA2: length 84.2
  IN1 w0.089: 124.63,52.01 124.63,59.16 124.11,59.69 124.11,62.29 124.44,62.62 124.44,63.73 124.65,63.95 125.61,63.95 v2(125.83,63.73)
  IN1 w0.132: v2(169.24,22.24) 168.83,22.24 168.52,22.55 168.52,22.83 168.87,23.18 168.87,23.43 168.32,23.98 168.13,23.98 168.01,23.86 167.24,23.86 167.12,23.98 167.12,24.17 167.33,24.37 167.33,24.97 166.38,25.91 166.38,30.8 165.9,31.28 159.69,31.28 159.52,31.45 152.98,31.45 152.7,31.74 148.68,31.74 148.14,32.28 138.75,32.28 124.63,46.4 124.63,52.01
  BOTTOM w0.081: v2(125.83,63.73) 126.01,63.91 UC1.AP42
  BOTTOM w0.17: v2(169.24,22.24) 168.2,21.19 JDIMM2.96
DDR_B_MA3: length 83.3
  IN1 w0.089: v2(125.75,62.94) 125.44,62.63 125.44,54.39 125.84,53.99 125.84,52.74 125.46,52.35 125.46,51.37
  IN1 w0.132: v2(168.17,28.17) 167.86,28.17 167.75,28.05 167.75,26.96 167.87,26.83 168.25,26.83 168.38,26.71 168.38,25.81 168.2,25.63 167.83,25.63 167.21,26.26 167.21,31.14 166.24,32.11 160.03,32.11 159.86,32.28 153.33,32.28 153.2,32.4 153.2,32.97 153.07,33.1 152.79,33.1 152.66,32.97 152.66,32.69 152.53,32.56 152.25,32.56 152.12,32.69 152.12,32.97 151.99,33.1 151.71,33.1 151.58,32.97 151.58,32.69 151.46,32.56 151.17,32.56 151.04,32.69 151.04,32.97 150.92,33.1 150.64,33.1 150.51,32.97 150.51,32.69 150.37,32.56 150.1,32.56 149.97,32.69 149.97,32.97 149.84,33.1 149.56,33.1 149.43,32.97 149.43,32.69 149.3,32.56 149.02,32.56 148.89,32.69 148.89,32.97 148.76,33.1 139.09,33.1 125.46,46.74 125.46,51.37
  BOTTOM w0.081: v2(125.75,62.94) 125.98,62.94 UC1.AR42
  BOTTOM w0.17: JDIMM2.95 167.9,27 167.69,27.21 167.31,27.21 167.13,27.38 167.13,28.71 167.3,28.87 167.59,28.87 168.17,28.29 v2(168.17,28.17)
DDR_B_MA4: length 88.3
  IN1 w0.089: 124.22,51.37 124.22,52.13 124.38,52.3 124.38,59.05 123.93,59.51 v2(123.93,63.04)
  IN1 w0.132: v2(167.01,22.24) 167.31,22.24 167.44,22.11 167.44,20.41 167.56,20.28 168.7,20.28 168.82,20.41 168.82,20.69 168.7,20.82 168.12,20.82 167.98,20.95 167.98,21.23 168.12,21.36 168.6,21.36 168.72,21.48 168.72,21.77 168.6,21.9 168.12,21.9 167.98,22.03 167.98,22.88 168.13,23.03 168.13,23.28 167.97,23.45 166.61,23.45 166.48,23.58 166.48,25.23 165.97,25.74 165.97,30.63 165.73,30.87 159.52,30.87 159.35,31.04 152.81,31.04 152.53,31.33 148.51,31.33 147.97,31.86 138.58,31.86 124.22,46.23 124.22,51.37
  BOTTOM w0.081: UC1.AR45 124.15,63.26 v2(123.93,63.04)
  BOTTOM w0.17: JDIMM2.92 167,19.21 167.54,19.75 167.54,21.71 v2(167.01,22.24)
DDR_B_MA5: length 87.1
  IN1 w0.089: 123.81,51.37 123.81,52.39 124.19,52.78 124.19,58.94 123.7,59.43 123.7,62.1 123.58,62.23 123.47,62.23 123.34,62.35 123.34,63.79 123.47,63.92 123.7,63.92 v2(123.95,63.67)
  IN1 w0.132: 123.81,51.37 123.81,46.06 138.41,31.45 147.8,31.45 148.34,30.91 152.36,30.91 152.64,30.63 158.95,30.63 159.12,30.46 159.63,30.46 159.76,30.33 159.76,29.88 159.63,29.76 159.23,29.76 159.1,29.63 159.1,29.25 159.23,29.13 160.17,29.13 160.3,29.26 160.3,30.33 160.43,30.46 160.71,30.46 160.84,30.33 160.84,29.25 160.96,29.13 161.25,29.13 161.38,29.25 161.38,30.33 161.5,30.46 161.79,30.46 161.91,30.33 161.91,29.25 162.04,29.13 162.33,29.13 162.45,29.25 162.45,30.33 162.58,30.46 162.86,30.46 162.99,30.33 162.99,29.25 163.12,29.13 163.4,29.13 163.53,29.25 163.53,30.33 163.66,30.46 163.94,30.46 164.07,30.33 164.07,28.83 164.2,28.7 164.48,28.7 164.61,28.83 164.61,30.33 164.73,30.46 165.02,30.46 165.15,30.33 165.15,29.82 165.27,29.69 v2(165.55,29.69)
  BOTTOM w0.081: UC1.AP45 124.19,63.91 v2(123.95,63.67)
  BOTTOM w0.17: v2(165.55,29.69) 166.55,29.69 166.7,29.54 JDIMM2.91
DDR_B_MA6: length 91.9
  IN1 w0.089: 122.99,51.37 122.99,52.43 123.69,53.14 123.69,58.86 123.12,59.43 122.79,59.43 122.57,59.65 122.57,60.08 v2(122.93,60.45)
  IN1 w0.132: v2(167.01,20.71) 166.51,21.21 166.51,22.15 166.07,22.59 166.07,25.06 165.56,25.57 165.56,26.8 164.48,27.88 163.73,27.88 163.31,28.3 158.82,28.3 158.69,28.18 158.69,26.88 158.56,26.75 154.38,26.75 154.25,26.89 154.25,27.5 154.12,27.63 153.83,27.63 153.71,27.5 153.71,26.89 153.58,26.75 152.89,26.75 152.77,26.88 152.77,29.61 152.64,29.74 152.35,29.74 152.22,29.61 152.22,26.88 152.09,26.75 151.49,26.75 151.36,26.88 151.36,27.7 151.24,27.83 150.42,27.83 150.29,27.96 150.29,28.24 150.42,28.37 151.24,28.37 151.36,28.49 151.36,28.78 151.24,28.91 150.16,28.91 150.04,29.03 150.04,29.32 150.16,29.44 151.24,29.44 151.36,29.57 151.36,29.96 151.24,30.09 148,30.09 147.46,30.63 138.07,30.63 122.99,45.71 122.99,51.37
  BOTTOM w0.081: UC1.AW46 123.29,60.8 v2(122.93,60.45)
  BOTTOM w0.17: v2(167.01,20.71) 166.4,20.1 JDIMM2.90
DDR_B_MA7: length 91.3
  IN1 w0.089: 122.57,51.37 122.57,52.42 123.42,53.26 123.42,58.6 v2(122.97,59.05)
  IN1 w0.132: 122.57,51.37 122.57,45.54 137.9,30.22 144.96,30.22 145.36,29.81 145.36,27.44 145.59,27.22 146.65,27.22 147.52,26.34 148.53,26.34 148.65,26.47 148.65,26.83 148.52,26.96 147.82,26.96 147.69,27.09 147.69,27.37 147.82,27.5 148.52,27.5 148.65,27.63 148.65,27.94 148.53,28.06 147.69,28.06 147.56,28.19 147.56,28.48 147.69,28.6 148.53,28.6 148.65,28.73 148.65,29.01 148.53,29.14 147.69,29.14 147.56,29.27 147.56,29.55 147.69,29.68 149.07,29.68 149.19,29.55 149.19,27.09 149.32,26.96 150.08,26.96 150.2,27.09 150.2,27.29 150.33,27.42 150.8,27.42 150.93,27.29 150.93,26.47 151.05,26.34 158.98,26.34 159.1,26.47 159.1,27.76 159.23,27.89 163.13,27.89 163.56,27.47 164.31,27.47 165.15,26.63 165.15,25.4 165.65,24.89 165.65,22.66 v2(165.23,22.24)
  BOTTOM w0.081: v2(122.97,59.05) 123.35,59.42 UC1.AY46
  BOTTOM w0.17: JDIMM2.86 165.2,19.08 165.71,19.59 165.71,21.75 v2(165.23,22.24)
DDR_B_MA8: length 89.9
  IN1 w0.089: v2(122.94,59.8) 123.3,59.8 123.45,59.65 123.45,59.37 123.97,58.85 123.97,52.93 123.4,52.36 123.4,51.37
  IN1 w0.132: v2(165.55,28.17) 165.23,28.49 164.96,28.49 164.77,28.29 163.9,28.29 163.48,28.71 158.82,28.71 158.69,28.84 158.69,30.09 158.56,30.22 157.97,30.22 157.85,30.09 157.85,27.29 157.72,27.16 157.4,27.16 157.28,27.29 157.28,30.09 157.15,30.22 156.84,30.22 156.71,30.09 156.71,27.29 156.59,27.16 156.3,27.16 156.18,27.29 156.18,30.09 156.05,30.22 155.46,30.22 155.33,30.09 155.33,27.29 155.21,27.16 154.92,27.16 154.79,27.29 154.79,30.09 154.67,30.22 154.38,30.22 154.26,30.09 154.26,28.17 154.13,28.04 153.84,28.04 153.72,28.17 153.72,30.09 153.59,30.22 152.47,30.22 152.19,30.5 148.17,30.5 147.63,31.04 138.24,31.04 123.4,45.89 123.4,51.37
  BOTTOM w0.081: v2(122.94,59.8) 122.59,60.15 UC1.AY47
  BOTTOM w0.17: v2(165.55,28.17) 165.98,28.17 166.1,28.04 JDIMM2.89
DDR_B_MA9: length 93.3
  IN1 w0.089: 122.16,51.37 122.16,52.42 122.99,53.26 v2(122.99,57.37)
  IN1 w0.132: 122.16,51.37 122.16,45.37 135.7,31.84 135.7,31.01 136,30.7 136.83,30.7 137.73,29.81 138.48,29.81 138.65,29.64 138.65,27.21 138.9,26.96 139.75,26.96 139.88,27.09 139.88,29.68 140.01,29.81 140.51,29.81 140.64,29.68 140.64,27.09 140.77,26.96 141.56,26.96 141.69,27.09 141.69,29.68 141.82,29.81 143.24,29.81 143.37,29.68 143.37,27.09 143.5,26.96 144.1,26.96 144.23,27.09 144.23,28.93 144.36,29.06 144.83,29.06 144.95,28.93 144.95,27.09 145.24,26.8 146.48,26.8 147.35,25.93 159.23,25.93 159.51,26.22 159.51,27.34 159.65,27.48 161.65,27.48 162.08,27.05 164.15,27.05 164.74,26.46 164.74,24.41 165.23,23.93 v2(165.23,23.76)
  BOTTOM w0.081: UC1.AU46 123.23,62.26 122.77,62.26 122.64,62.39 122.35,62.39 122.13,62.17 122.13,61.36 122.05,61.28 122.05,59.77 122.23,59.6 122.23,58.14 v2(122.99,57.37)
  BOTTOM w0.17: JDIMM2.85 164.9,24.92 164.77,24.8 164.77,24.21 v2(165.23,23.76)
DDR_B_MA10: length 96.2
  IN1 w0.089: 128.23,51.37 128.23,54.28 128.77,54.82 128.77,66.49 128.87,66.59 129.02,66.59 129.15,66.46 v2(129.15,66.34)
  IN1 w0.132: v2(172.52,29.69) 172.52,29.69 172.39,29.82 172.21,29.82 172.08,29.69 172.08,29.01 171.69,28.62 171.69,27.06 172.13,26.62 172.13,25.95 172.25,25.82 172.93,25.82 173.06,25.7 173.06,25.41 172.93,25.29 172.25,25.29 172.13,25.16 172.13,24.87 172.25,24.75 172.92,24.75 173.04,24.62 173.04,24.48 172.61,24.04 172.41,24.04 172.24,24.21 171.7,24.21 171.55,24.36 171.55,25.96 171.42,26.09 170.13,26.09 170,26.21 170,26.5 170.13,26.62 170.99,26.62 171.12,26.75 171.12,29.06 171.54,29.48 171.54,30.17 171.67,30.3 171.97,30.3 172.1,30.42 172.1,30.71 171.97,30.83 171.67,30.83 171.54,30.96 171.54,31.43 170.7,32.26 170.7,32.87 168.78,34.8 167.34,34.8 166.33,35.8 140.22,35.8 128.23,47.78 128.23,51.37
  BOTTOM w0.081: UC1.AK36 129.32,66.51 v2(129.15,66.34)
  BOTTOM w0.17: JDIMM2.107 171.5,29.75 171.63,29.88 172.33,29.88 v2(172.52,29.69)
DDR_B_MA11: length 92.2
  IN1 w0.089: 121.75,51.37 121.75,52.43 122.71,53.39 122.71,56.78 122.6,56.9 122.6,57.53 v2(122.99,57.93)
  IN1 w0.132: v2(165.23,20.71) 164.8,20.71 164.64,20.87 164.64,23.93 164.33,24.24 164.33,26.28 164.01,26.6 161.71,26.6 161.58,26.72 161.58,26.94 161.46,27.07 161.17,27.07 161.05,26.94 161.05,26.72 160.92,26.6 160.58,26.6 160.45,26.72 160.45,26.94 160.33,27.07 160.05,27.07 159.93,26.94 159.93,26 159.44,25.52 147.18,25.52 146.3,26.39 143.06,26.39 142.77,26.68 142.77,29.27 142.65,29.4 142.36,29.4 142.24,29.27 142.24,26.52 142.11,26.39 138.89,26.39 137.78,27.5 137.78,27.69 138.24,28.15 138.24,28.33 138.04,28.53 137.86,28.53 137.4,28.07 137.21,28.07 137.01,28.26 137.01,28.45 137.67,29.11 137.67,29.29 137.47,29.49 137.29,29.49 136.63,28.83 136.45,28.83 136.25,29.03 136.25,29.21 136.91,29.87 136.91,30.05 136.71,30.25 136.53,30.25 135.87,29.59 135.69,29.59 135.44,29.84 135.44,30.02 135.69,30.26 135.69,30.44 135.29,30.84 135.29,31.67 121.75,45.2 121.75,51.37
  BOTTOM w0.081: UC1.AV47 122.23,61.15 122.23,59.96 122.54,59.65 122.54,58.38 v2(122.99,57.93)
  BOTTOM w0.17: JDIMM2.84 164.6,20.09 v2(165.23,20.71)
DDR_B_MA12: length 89
  IN1 w0.089: 121.34,51.37 121.34,52.45 122.43,53.54 122.43,56.7 122.37,56.76 122.37,61.46 122.81,61.9 v2(122.95,61.9)
  IN1 w0.132: v2(163.1,22.24) 163.56,21.77 163.56,20.61 163.69,20.48 164.1,20.48 164.23,20.61 164.23,22.55 164.1,22.67 163.65,22.67 163.52,22.8 163.52,23.09 163.65,23.21 164.1,23.21 164.23,23.34 164.23,23.72 164.1,23.85 163.75,23.85 163.63,23.98 163.63,24.95 163.5,25.08 163.15,25.08 163.03,25.2 163.03,25.49 163.15,25.61 163.76,25.61 163.89,25.74 163.89,26.06 163.76,26.19 160.69,26.19 159.61,25.11 147.01,25.11 146.13,25.98 138.71,25.98 134.72,29.98 134.72,30.16 134.95,30.4 134.95,30.59 134.76,30.78 134.57,30.78 134.34,30.55 134.15,30.55 133.96,30.74 133.96,30.93 134.61,31.58 134.61,31.76 134.36,32.01 134.18,32.01 133.53,31.36 133.34,31.36 133.15,31.55 133.15,31.74 133.8,32.39 133.8,32.58 121.34,45.03 121.34,51.37
  BOTTOM w0.081: v2(122.95,61.9) 122.9,61.9 122.69,62.1 UC1.AU47
  BOTTOM w0.17: JDIMM2.83 164.3,23.44 v2(163.1,22.24)
DDR_B_MA13: length 97
  IN1 w0.089: 130.95,51.37 130.95,52.21 130.4,52.76 130.4,54.19 131,54.79 131,56.35 131.12,56.47 131.34,56.47 131.45,56.57 131.45,56.72 131.34,56.82 130.73,56.82 130.66,56.9 130.66,57.1 130.74,57.18 131.34,57.18 131.45,57.28 131.45,57.43 131.34,57.54 130.72,57.54 130.66,57.59 130.66,57.82 130.73,57.89 131.34,57.89 131.45,57.99 131.45,66.06 131.26,66.25 v2(131.05,66.25)
  IN1 w0.132: v2(176.1,29.69) 175.68,30.12 175.68,30.89 168.71,37.86 153.53,37.86 152.56,38.83 149.54,38.83 149.35,39.02 149.35,39.58 149.22,39.71 148.93,39.71 148.81,39.58 148.81,38.91 148.68,38.78 148.4,38.78 148.27,38.91 148.27,39.75 148.14,39.89 147.86,39.89 147.73,39.75 147.73,38.91 147.6,38.78 147.32,38.78 147.19,38.91 147.19,39.75 147.06,39.89 146.79,39.89 146.65,39.75 146.65,38.91 146.53,38.78 146.24,38.78 146.11,38.91 146.11,39.75 145.98,39.89 145.71,39.89 145.58,39.75 145.58,38.91 145.45,38.78 145.16,38.78 145.04,38.91 145.04,39.75 144.91,39.89 144.63,39.89 144.5,39.75 144.5,38.96 144.37,38.83 144.09,38.83 143.96,38.96 143.96,39.75 143.83,39.89 143.55,39.89 143.42,39.75 143.42,38.96 143.3,38.83 143.01,38.83 142.88,38.96 142.88,39.75 142.75,39.89 142.48,39.89 142.35,39.75 142.35,38.96 142.22,38.83 141.93,38.83 141.81,38.96 141.81,39.75 141.67,39.89 141.4,39.89 141.27,39.75 141.27,38.96 141.14,38.83 140.86,38.83 140.73,38.96 140.73,39.75 140.6,39.89 140.32,39.89 140.19,39.75 140.19,39.28 140.06,39.15 139.78,39.15 139.65,39.28 139.65,39.75 139.52,39.89 139.04,39.89 130.95,47.98 130.95,51.37
  BOTTOM w0.081: UC1.AK33 131.32,66.51 v2(131.05,66.25)
  BOTTOM w0.17: JDIMM2.119 175.1,27.49 174.63,27.96 174.63,29.06 175.26,29.69 v2(176.1,29.69)
DDR_B_MA14: length 93.6
  IN1 w0.089: 120.52,51.37 120.52,52.61 121.97,54.06 121.97,60.42 121.69,60.71 121.18,60.71 120.99,60.9 120.99,61.92 121.16,62.09 122.22,62.09 122.91,62.78 v2(122.91,63.07)
  IN1 w0.132: v2(163.1,20.71) 162.67,20.71 162.55,20.59 162.55,19.79 162.42,19.66 161.98,19.66 161.85,19.79 161.85,21.16 161.98,21.28 162.54,21.28 162.68,21.42 162.68,21.69 162.54,21.82 161.92,21.82 161.79,21.95 161.79,22.23 161.92,22.36 162.54,22.36 162.68,22.49 162.68,22.77 162.54,22.9 162.34,22.9 162.2,23.03 162.2,25.13 161.98,25.36 161.03,25.36 159.95,24.28 146.67,24.28 145.79,25.16 138.37,25.16 125.58,37.95 125.58,38.14 126.23,38.79 126.23,38.98 126.04,39.17 125.85,39.17 125.2,38.52 125.01,38.52 124.82,38.71 124.82,38.9 125.47,39.55 125.47,39.74 125.27,39.93 125.09,39.93 124.44,39.28 124.25,39.28 124.06,39.48 124.06,39.66 124.71,40.31 124.71,40.5 124.51,40.7 124.33,40.7 123.67,40.04 123.49,40.04 123.29,40.24 123.29,40.43 123.94,41.08 123.94,41.26 120.52,44.69 120.52,51.37
  BOTTOM w0.081: UC1.AR46 123.25,63.07 v2(122.91,63.07)
  BOTTOM w0.17: v2(163.1,20.71) 163.46,20.71 163.68,20.5 163.68,19.53 163.4,19.25 JDIMM2.80
DDR_B_MA15: length 94.5
  IN1 w0.089: v2(122.93,63.72) 122.54,63.33 122.54,62.69 122.12,62.26 121.03,62.26 120.76,62 120.76,60.81 121.1,60.47 121.62,60.47 121.77,60.32 121.77,54.3 120.11,52.63 120.11,51.37
  IN1 w0.132: 120.11,51.37 120.11,44.52 122.88,41.74 122.88,40.01 138.14,24.75 141.77,24.75 141.89,24.62 141.89,24 142.02,23.87 142.3,23.87 142.43,24 142.43,24.62 142.56,24.75 142.84,24.75 142.97,24.62 142.97,24 143.1,23.87 143.38,23.87 143.51,24 143.51,24.62 143.64,24.75 143.92,24.75 144.05,24.62 144.05,24 144.17,23.87 144.46,23.87 144.59,24 144.59,24.62 144.71,24.75 145.34,24.75 145.47,24.62 145.47,24 145.59,23.87 159.87,23.87 160,23.75 160,23.42 159.87,23.29 159.32,23.29 159.2,23.16 159.2,22.88 159.32,22.75 159.87,22.75 160,22.63 160,22.26 159.87,22.14 159.32,22.14 159.2,22.01 159.2,21.66 159.32,21.54 160.41,21.54 160.54,21.66 160.54,24.29 161.2,24.95 161.68,24.95 161.79,24.84 161.79,22.82 161.37,22.4 v2(161.37,22.24)
  BOTTOM w0.081: v2(122.93,63.72) 123.25,63.72 UC1.AP46
  BOTTOM w0.17: v2(161.37,22.24) 162.42,21.19 162.42,19.34 162.8,18.96 JDIMM2.78
DDR_B_RAS#: length 97.1
  IN1 w0.084: 129.06,51.37 129.06,54.16 129.42,54.52
  IN1 w0.089: 129.42,54.52 129.42,56.52 130.05,57.16 130.05,61.94 129.74,62.25 129.74,64.46 130.12,64.84 v2(130.12,64.89)
  IN1 w0.132: 129.06,51.37 129.06,48.12 140.56,36.62 166.67,36.62 167.68,35.62 169.12,35.62 171.53,33.22 171.53,32.62 173.41,30.75 173.41,27.17 173.52,27.06 173.84,27.06 173.92,26.98 176.08,26.98 176.45,26.61 176.45,24.49 175.43,23.47 173.78,23.47 173.41,23.09 173.41,21.5 173.09,21.18 173.09,20.42 173.22,20.29 175.25,20.29 175.37,20.16 175.37,19.66 175.25,19.53 171.72,19.53 171.59,19.66 171.59,20.59 171.72,20.71 v2(172.35,20.71)
  BOTTOM w0.081: v2(130.12,64.89) 130.45,65.21 UC1.AM35
  BOTTOM w0.17: JDIMM2.110 172.4,19.35 172.81,19.76 172.81,20.25 v2(172.35,20.71)
DDR_B_WE#: length 96.2
  IN1 w0.089: 130.04,52.49 129.34,52.49 129.27,52.55 129.27,53.98 129.68,54.39 129.68,56.5 130.24,57.06 130.24,62.53 130.51,62.8 130.51,65.13 130.67,65.28 130.67,66.4 130.54,66.52 130.23,66.52 130.1,66.4 v2(130.1,66.19)
  IN1 w0.132: v2(174.08,29.69) 174.68,29.1 174.68,27.99 174.8,27.86 175.14,27.86 175.27,27.99 175.27,29.36 174.8,29.82 174.8,30.6 174.23,31.17 174.05,31.17 173.89,31.02 173.71,31.02 173.51,31.22 173.51,31.4 173.66,31.55 173.66,31.74 173.47,31.93 173.28,31.93 173.13,31.78 172.95,31.78 172.75,31.98 172.75,32.16 172.9,32.32 172.9,32.5 172.71,32.7 172.52,32.7 172.37,32.54 172.19,32.54 171.99,32.75 171.99,32.93 172.14,33.08 172.14,33.26 169.37,36.03 167.85,36.03 166.84,37.04 144.7,37.04 144.57,37.16 144.57,37.88 144.44,38.01 144.16,38.01 144.03,37.88 144.03,37.16 143.9,37.04 143.62,37.04 143.49,37.16 143.49,37.88 143.37,38.01 143.08,38.01 142.95,37.88 142.95,37.16 142.83,37.04 142.54,37.04 142.42,37.16 142.42,37.88 142.29,38.01 142,38.01 141.88,37.88 141.88,37.16 141.75,37.04 141.47,37.04 141.34,37.16 141.34,37.88 141.21,38.01 140.93,38.01 140.8,37.88 140.8,37.5 140.67,37.38 140.39,37.38 140.26,37.5 140.26,37.88 140.13,38.01 139.76,38.01 130.13,47.63 130.13,48.06 130,48.2 129.6,48.2 129.47,48.32 129.47,48.61 129.6,48.74 130,48.74 130.13,48.87 130.13,49.14 130,49.27 129.6,49.27 129.47,49.4 129.47,49.69 129.6,49.81 130,49.81 130.13,49.94 130.13,50.22 130,50.35 129.6,50.35 129.47,50.48 129.47,50.76 129.6,50.89 130,50.89 130.13,51.02 130.13,51.3 130,51.43 129.53,51.43 129.4,51.55 129.4,51.84 129.53,51.97 130.04,51.97 130.16,52.09 130.16,52.36 130.04,52.49
  BOTTOM w0.081: v2(130.1,66.19) 130.43,66.51 UC1.AK35
  BOTTOM w0.17: v2(174.08,29.69) 174.08,29.69 173.81,29.95 173.29,29.95 173.14,29.81 173.14,26.95 173.3,26.79 JDIMM2.113
DDR_CKE0_DIMMA: length 74.4
  IN4 w0.089: v2(124.54,61.79) 125.28,61.05 125.28,57.49 119.98,52.2
  IN4 w0.132: 119.98,52.2 119.98,51.37 109.22,40.61 98.71,40.61 98.01,39.9 89.21,39.9 80.72,31.42 80.72,25.07 80.85,24.95 81.52,24.95 81.65,25.07 81.65,27.84 v2(81.2,28.29)
  BOTTOM w0.081: UC1.AU43 124.85,62.1 v2(124.54,61.79)
  BOTTOM w0.17: v2(81.2,28.29) 81.8,27.69 JDIMM1.73
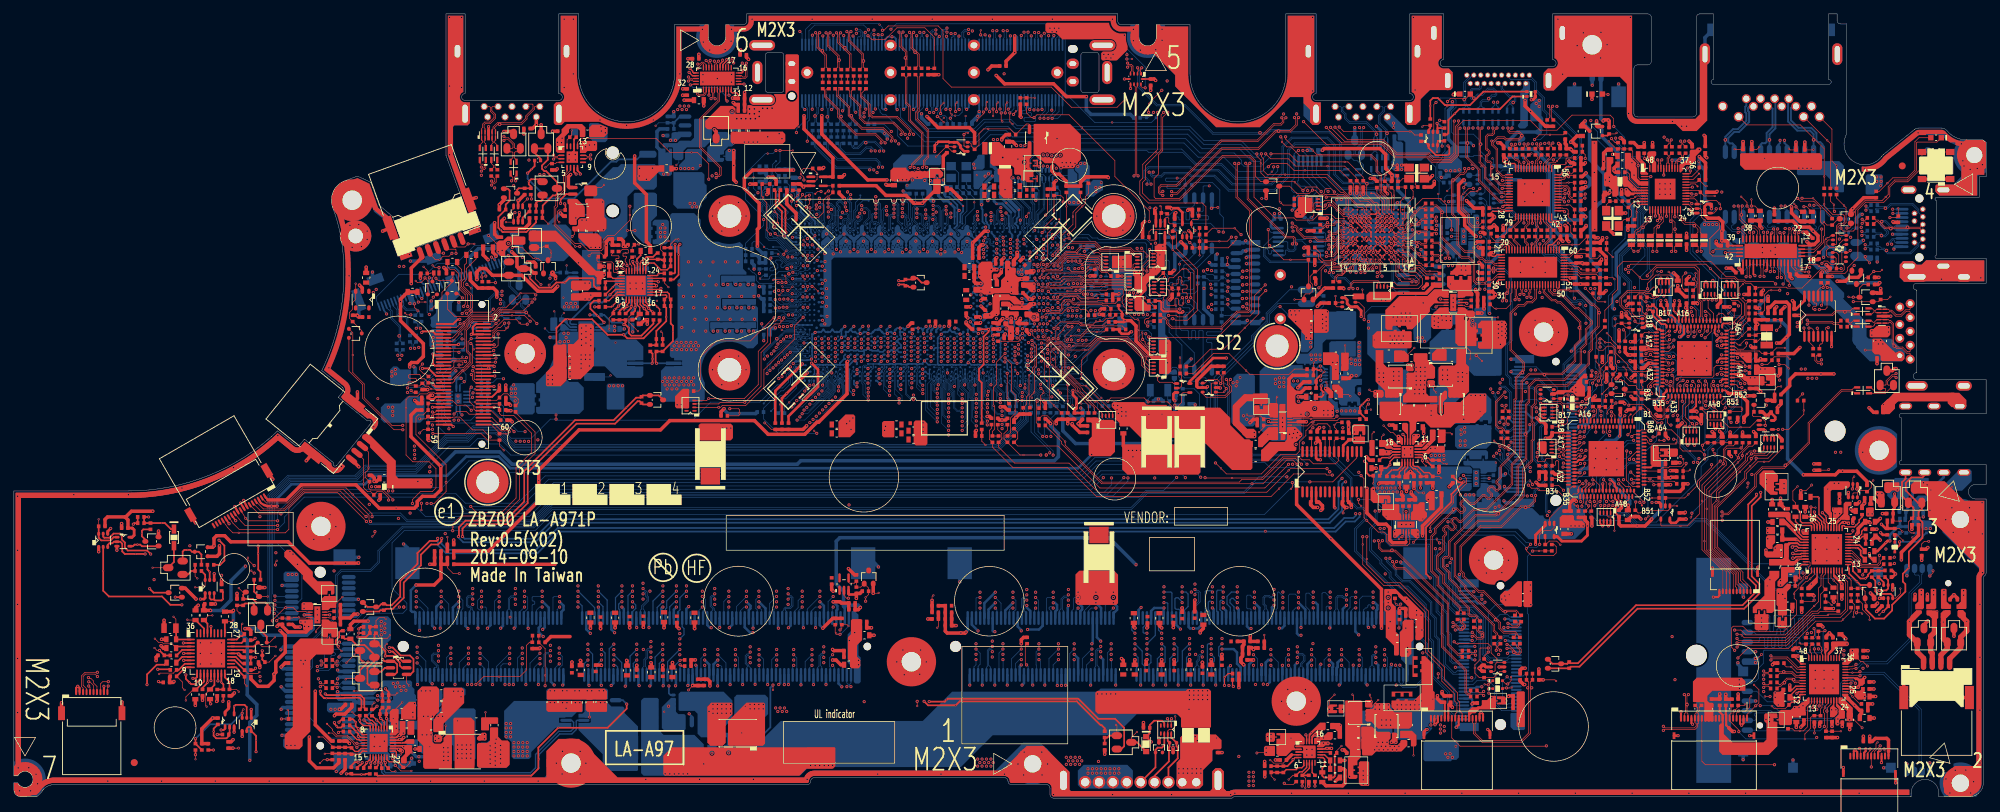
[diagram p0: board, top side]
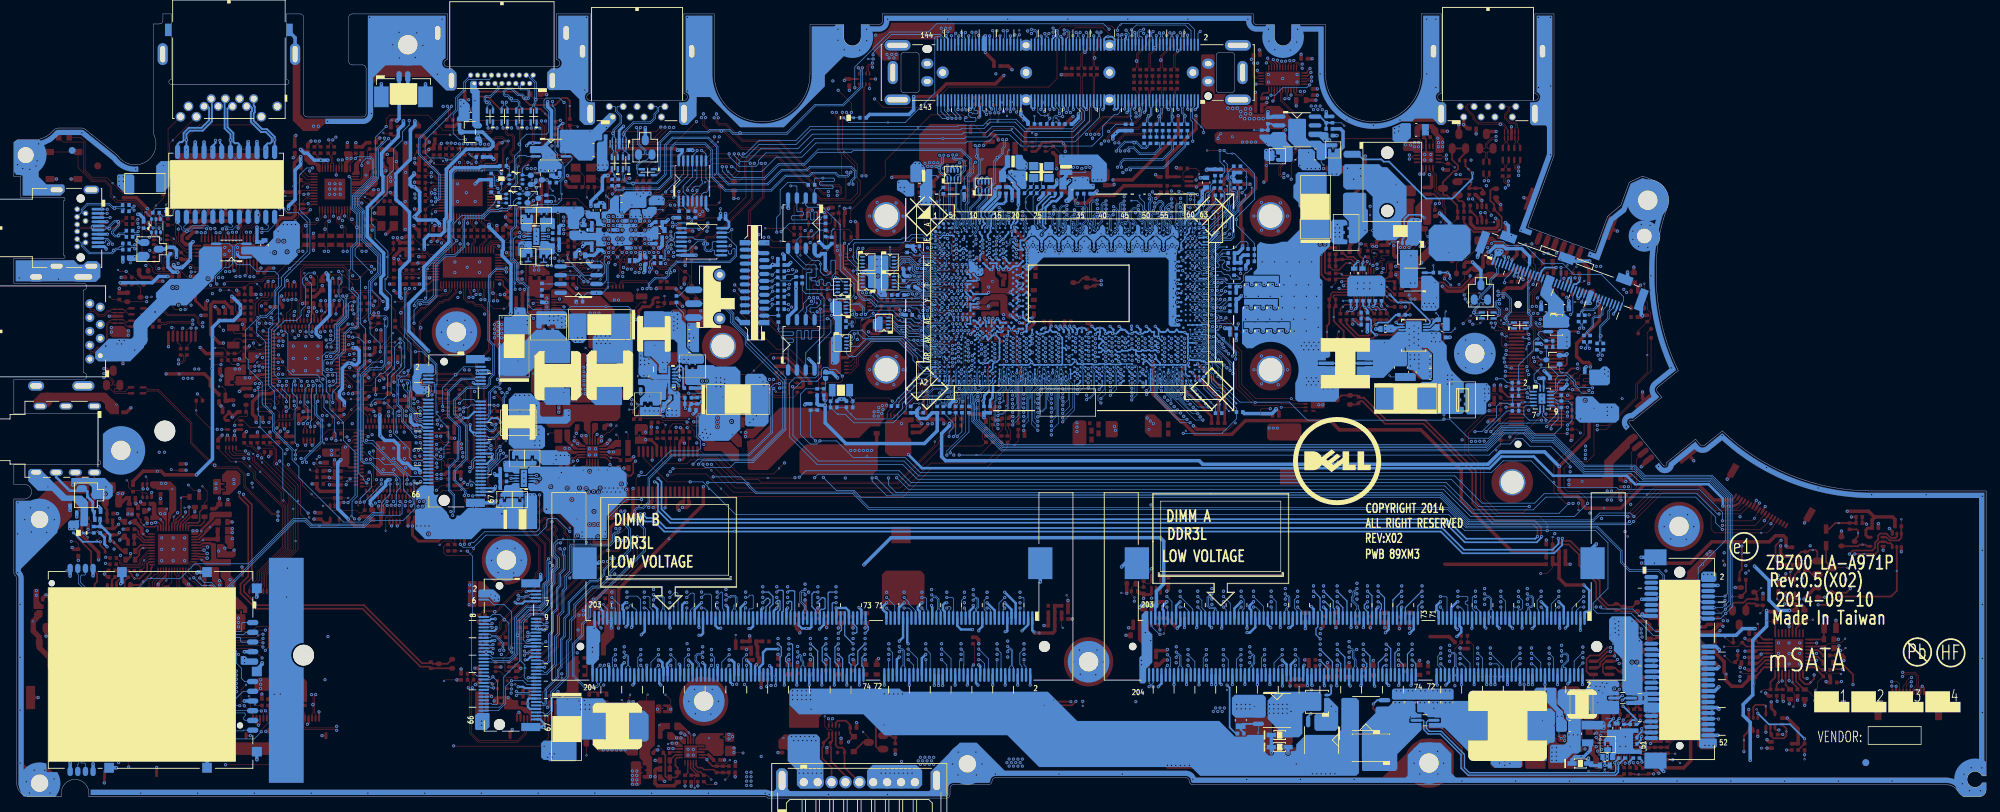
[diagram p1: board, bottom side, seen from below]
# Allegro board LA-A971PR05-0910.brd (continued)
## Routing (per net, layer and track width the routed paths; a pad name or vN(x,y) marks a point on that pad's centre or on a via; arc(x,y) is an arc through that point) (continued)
DDR_CKE1_DIMMA: length 74.1
  IN4 w0.089: v2(124.53,60.52) 124.31,60.29 124.31,56.9 119.57,52.16
  IN4 w0.132: 119.57,52.16 119.57,51.55 109.04,41.02 98.54,41.02 97.84,40.32 89.04,40.32 80.31,31.59 80.31,24.9 81.44,23.78 81.44,21.08 v2(82.62,19.9)
  BOTTOM w0.081: v2(124.53,60.52) 124.82,60.8 UC1.AW43
  BOTTOM w0.17: JDIMM1.74 82.1,19.37 v2(82.62,19.9)
DDR_CKE2_DIMMB: length 77.1
  IN1 w0.089: v2(121.37,59.82) 120.99,59.45 120.99,59.13 121.5,58.62 121.5,54.5 119.69,52.7 119.69,51.37
  IN1 w0.132: 119.69,51.37 119.69,44.35 122.47,41.57 122.47,39.82 138.82,23.46 139.81,23.46 139.94,23.59 139.94,24.21 140.07,24.34 140.35,24.34 140.48,24.21 140.48,23.59 140.61,23.46 158.66,23.46 158.78,23.33 158.78,21.25 158.91,21.12 160.82,21.12 160.95,21.25 160.95,23.63 161.08,23.76 v2(161.37,23.76)
  BOTTOM w0.081: v2(121.37,59.82) 121.69,60.15 UC1.AY49
  BOTTOM w0.17: JDIMM2.73 161.3,25.09 160.92,24.71 160.92,24.21 v2(161.37,23.76)
DDR_CKE3_DIMMB: length 78.5
  IN1 w0.089: 119.28,51.37 119.28,52.71 121.21,54.63 121.21,58.39 v2(120.89,58.71)
  IN1 w0.132: 119.28,51.37 119.28,44.18 122.06,41.4 122.06,39.65 138.66,23.04 156.84,23.04 156.97,22.92 156.97,22.01 157.09,21.88 157.38,21.88 157.51,22.01 157.51,22.92 157.63,23.04 158.25,23.04 158.37,22.92 158.37,20.84 158.5,20.71 v2(161.37,20.71)
  BOTTOM w0.081: UC1.AU50 120.84,61.76 120.65,61.57 120.65,61.4 120.63,61.13 120.57,61.07 120.52,60.98 120.49,60.9 120.49,60.7 120.51,60.64 120.56,60.54 120.56,60.41 120.49,60.25 120.49,59.11 v2(120.89,58.71)
  BOTTOM w0.17: v2(161.37,20.71) 161.82,20.26 161.82,19.05 161.6,18.83 JDIMM2.74
DDR_CS0_DIMMA#: length 76.8
  IN4 w0.089: v2(132,63.65) 132.45,63.2 132.45,61.53 133.68,60.3 133.68,53 132.76,52.08 132.76,51.37
  IN4 w0.132: 132.76,51.37 132.76,46.58 116.51,30.33 116.51,27.42 114.54,25.46 98.55,25.46 98.42,25.33 98.42,24.95 98.55,24.82 99.68,24.82 99.81,24.69 99.81,24.41 99.68,24.28 98.55,24.28 98.42,24.15 98.42,21.55 98.29,21.42 v2(95.86,21.42)
  BOTTOM w0.081: UC1.AP33 131.74,63.91 v2(132,63.65)
  BOTTOM w0.17: v2(95.86,21.42) 94.1,19.66 JDIMM1.114
DDR_CS1_DIMMA#: length 77.6
  IN4 w0.089: 132.35,51.37 132.35,52.14 133.46,53.25 133.46,59.97 132.03,61.4 v2(132.03,62.96)
  IN4 w0.132: v2(95.86,22.94) 96.15,22.94 96.28,22.82 96.28,22.02 96.41,21.9 96.69,21.9 96.82,22.02 96.82,22.82 96.94,22.94 97.27,22.94 97.4,22.82 97.4,22.01 97.52,21.88 97.9,21.88 98.01,21.99 98.01,23.47 97.88,23.6 96.4,23.6 96.28,23.72 96.28,24.01 96.4,24.14 97.45,24.14 97.58,24.26 97.58,25.74 97.71,25.87 114.24,25.87 115.14,26.76 115.14,29.54 132.35,46.75 132.35,51.37
  BOTTOM w0.081: UC1.AR32 132.12,62.96 v2(132.03,62.96)
  BOTTOM w0.17: JDIMM1.121 96.2,24.68 96.46,24.42 96.46,23.55 v2(95.86,22.94)
DDR_CS2_DIMMB#: length 85.5
  IN1 w0.089: 131.78,52.66 131.78,54.16 132.02,54.41 132.02,62.41 132.45,62.84 132.45,64.49 132.04,64.89 v2(132.04,64.9)
  IN1 w0.132: v2(173.91,22.24) 174.78,22.24 177.47,24.93 177.47,30.26 169.05,38.68 153.87,38.68 152.9,39.65 150.44,39.65 149.38,40.71 139.38,40.71 131.78,48.32 131.78,52.66
  BOTTOM w0.081: v2(132.04,64.9) 132.36,65.21 UC1.AM32
  BOTTOM w0.17: JDIMM2.114 173.6,20.35 173.43,20.52 173.43,21.76 v2(173.91,22.24)
DDR_CS3_DIMMB#: length 83.8
  IN1 w0.089: 131.36,51.37 131.36,54.21 131.66,54.5 131.66,54.78 131.58,54.86 131.26,54.86 131.19,54.93 131.19,55.24 131.26,55.31 131.59,55.31 131.64,55.36 131.64,55.6 131.58,55.66 131.27,55.66 131.19,55.74 131.19,56.12 131.26,56.18 131.58,56.18 131.64,56.25 131.64,65.94 v2(131.98,66.28)
  IN1 w0.132: v2(176.1,28.17) 176.4,28.17 176.52,28.04 176.52,27.12 176.65,26.99 176.94,26.99 177.06,27.12 177.06,28.66 176.93,28.79 176.66,28.79 176.52,28.92 176.52,29.2 176.66,29.33 176.94,29.33 177.06,29.46 177.06,29.82 176.94,29.95 176.71,29.95 176.58,30.07 176.58,30.57 168.88,38.27 153.7,38.27 152.73,39.24 150.27,39.24 149.21,40.3 139.21,40.3 131.36,48.15 131.36,51.37
  BOTTOM w0.081: UC1.AK32 132.21,66.51 v2(131.98,66.28)
  BOTTOM w0.17: v2(176.1,28.17) 176.1,28.19 175.5,28.79 175.29,28.79 175.06,28.56 175.06,28.14 175.64,27.56 175.64,27.07 175.7,27.01 JDIMM2.121
DDR_PG_CTRL: length 47
  TOP w0.076: v2(115.57,52.56) 115.55,52.56 115.19,52.92 v1(115.19,52.93)
  TOP w0.102: UD1.2 119.5,29.18 119.88,28.8 v2(120.13,28.8)
  IN2 w0.081: 115.57,51.37 v2(115.57,52.56)
  IN2 w0.122: v2(120.13,28.8) 115.57,33.36 115.57,51.37
  BOTTOM w0.081: 111.78,60.93 111.78,61.07 112.48,61.77 112.75,61.77 112.79,61.81 113.86,61.81 UC1.AV61
  BOTTOM w0.102: v2(115.57,52.56) 109.99,52.56 107.91,54.64 CC109.1 107.91,56.18 110.42,58.69 110.77,58.69 111.78,59.7 111.78,60.93
DDR_XDP_WAN_SMBCLK: length 264.1
  TOP w0.102: RN4.2 174.05,61.19 174.05,59.99 174.17,59.88 174.17,59.37 v2(174.52,59.01) 174.52,58.87 v1(174.24,58.58) 174.13,58.47 173.34,58.47 173.31,58.51 QC1.1 ; JXDP1.53 60.75,55.32 60.7,55.27 60.47,55.27 v2(60.25,55.05)
  IN1 w0.084: v2(199.5,19.15) 199.31,18.96 199.31,18.52 198.81,18.02 178.05,18.02 177.82,18.25 133.34,18.25 130.22,15.13 124.05,15.13 122.39,16.78 120.57,16.78 120.26,16.46 120.26,16.3 v2(120.49,16.06)
  IN4 w0.084: v2(120.49,16.06) 120.31,16.25 120.31,17.07 119.84,17.53 96.96,17.53 96.62,17.88 58.34,17.88 57.39,18.83 57.39,24.61 54.65,27.35 54.65,40.62 58.64,44.61 58.64,47.58 59.11,48.04 59.11,54.58 59.74,55.22 60.07,55.22 v2(60.25,55.05)
  BOTTOM w0.102: v2(120.49,16.06) 120.31,16.24 120.31,16.41 120.5,16.6 JDIMM1.202 ; v2(174.52,59.01) 174.7,58.83 174.7,52.65 178.02,49.33 189.08,49.33 192.38,46.02 192.38,42.6 193.31,41.67 194.19,41.67 194.42,41.43 194.42,40.28 193.01,38.86 193.01,35.56 200.9,27.66 200.9,26.03 201.93,25 201.93,23.47 203.28,22.13 203.28,17.72 201.72,16.17 200.02,16.17 199.82,16.36 199.82,16.48 200,16.66 JDIMM2.202 200,18.66 v2(199.5,19.15)
DDR_XDP_WAN_SMBDAT: length 267.4
  TOP w0.102: v2(60.25,55.63) 60.38,55.5 60.53,55.5 60.85,55.82 JXDP1.51 ; RN3.2 173.33,61.3 173.83,60.81 173.83,59.83 v2(173.72,59.73) 173.72,59.82 173.24,60.3 171.95,60.3 171.45,59.81 QC1.4
  IN1 w0.084: v2(119.91,16.06) 120.05,16.2 120.05,16.55 120.49,16.99 122.48,16.99 124.13,15.34 130.13,15.34 133.25,18.46 177.9,18.46 178.14,18.23 198.73,18.23 199.1,18.6 199.1,18.94 v2(198.89,19.15)
  IN4 w0.084: v2(119.91,16.06) 120.09,16.25 120.09,16.98 119.75,17.32 96.88,17.32 96.53,17.67 58.26,17.67 57.18,18.75 57.18,24.52 54.44,27.27 54.44,40.71 58.43,44.7 58.43,47.66 58.9,48.13 58.9,54.67 59.66,55.43 60.05,55.43 v2(60.25,55.63)
  BOTTOM w0.102: v2(119.91,16.06) 120.09,16.24 120.09,16.41 119.9,16.6 JDIMM1.200 ; v2(173.72,59.73) 174.38,59.73 174.93,59.18 174.93,52.74 178.12,49.55 189.17,49.55 192.61,46.12 192.61,42.69 193.4,41.9 194.28,41.9 194.65,41.53 194.65,40.18 193.24,38.77 193.24,35.65 201.13,27.76 201.13,26.13 202.16,25.09 202.16,23.56 203.51,22.22 203.51,17.63 201.82,15.94 199.92,15.94 199.59,16.27 199.59,16.52 199.4,16.72 JDIMM2.200 199.4,18.65 v2(198.89,19.15)
DGPU_PWROK: length 10.9
  BOTTOM w0.076: UC1.P4 149.6,74.46 150.02,74.46 150.13,74.35 150.88,74.35 151.05,74.52 151.37,74.52 151.45,74.6 151.46,74.6 151.48,74.63 151.85,74.63 152.71,75.48
  BOTTOM w0.081: 152.71,75.48 153.02,75.48 153.11,75.57 153.82,75.57
  BOTTOM w0.102: RPC18.8 157.23,75.79 156.68,76.34 156.68,76.38 155.9,77.16 v1(155.68,77.16) 155.04,77.16 154.52,76.65 154.52,75.99 154.19,75.66 153.98,75.66 153.88,75.57 153.82,75.57
DH_1.35V: length 8
  TOP w0.102: v1(195.2,14.9) 195.2,14.64 195.38,14.46 v2(195.38,13.88)
  IN4 w1.016: 188.36,10.23 189.41,11.28 192.33,11.28 194.11,13.06
  vias: v2(187.31,9.12) v2(187.88,9.37) v2(194.74,13.88)
DIMM_DET: length 20.5
  TOP w0.102: v2(162.71,72.1) 162.74,72.07 162.74,72.07 163.17,71.64 RC303.1 163.39,71.64 RC302.2 ; v1(151.63,73.05) 152.78,73.05 v2(152.9,73.16)
  IN4 w0.076: 154.36,73.41 153.94,73.41 153.81,73.55 153.18,73.55 152.9,73.26 v2(152.9,73.16)
  IN4 w0.084: 154.36,73.41 155.5,73.41 157.04,71.86 159.55,71.86 159.78,72.1 159.78,73.09 160.25,73.56 162.07,73.56 162.71,72.91 v2(162.71,72.1)
  BOTTOM w0.076: v2(152.9,73.16) 152.73,73 151.83,73 151.68,72.85 150.1,72.85 150.05,72.9 149.66,72.9 149.29,73.26 UC1.U4
DIS_BAT_PROCHOT#: length 253.2
  TOP w0.102: v2(234.64,42.62) 233.22,44.04 UE1.B51 ; v2(34.6,32.42) 34.52,32.42 v1(34.16,32.78)
  TOP w0.254: PR812.1 v2(29.27,9.17)
  IN1 w0.254: v2(34.6,32.42) 34.6,24.36 33.07,22.83 33.07,14.58 29.27,10.78 v2(29.27,9.17)
  IN3 w0.122: v2(234.64,42.62) 234.64,42.63 233.52,43.74 224.41,43.74 223.89,43.22 223.89,42.07 220.37,38.56 210.07,38.56 205.66,34.15 205.66,32.21 202.91,29.46 200.2,29.46 199.96,29.7 199.96,30.78 200.2,31.03 200.2,34.84 196.71,38.33 196.39,38.33 195.48,39.24 187.08,39.24 185.42,37.58 67.64,37.58 64.61,40.61 58.66,40.61 57.79,41.49 55.6,41.49 54.49,40.37 53.3,40.37 50.86,37.93 50.86,37.36 47.14,33.64 47.14,32.32 45.66,30.84 39.36,30.84 37.77,32.42 v2(34.6,32.42)
DISP_ON: length 10
  TOP w0.102: v2(60.76,74.9) 61.1,74.56 DV2.1 ; RV2.1 63.18,75.04 63.04,74.9 DV2.1 ; DV2.1 63.04,74.31 61.62,72.88 61.62,71.98 v1(60.1,70.46)
  BOTTOM w0.102: v2(60.76,74.9) 60.69,74.84 60.69,74.78 JEDP1.22
DK_AC_OFF: length 7
  TOP w0.102: v1(37.72,21.82) 35.74,21.82 35.1,22.45 PD815.3
  TOP w0.254: PD815.3 34.54,21.85 PU800.25
DK_AC_OFF_EN: length 2.3
  TOP w0.254: PU800.22 31.93,20.35 32.89,19.39 PR850.1
DK_CSS_GC: length 32.5
  TOP w0.254: PR709.1 49.95,24.68 v2(49.64,24.37) ; v2(24.75,17.75) 24.75,17.18 v1(25.26,16.67) 25.51,16.42 26.09,16.42 26.86,17.2 PU800.11
  IN3 w0.254: v2(49.64,24.37) 47.74,24.37 44.45,21.08 41.13,21.08 39.81,19.76 34.54,19.76 33.59,18.81 26.79,18.81 25.74,17.75 v2(24.75,17.75)
DK_PWRBAR: length 3.6
  TOP w0.102: v1(28.56,26.33) 28.03,26.33 PR832.1
  TOP w0.254: PU800.33 27.86,25.14 PR832.1
DL_1.35V: length 9
  TOP w0.102: v1(189.71,7.8) 189.6,7.91 v2(189.15,7.91)
  IN4 w1.016: 190.3,7.91 194.3,7.91 195.31,8.93 198.3,8.93
  vias: v2(188.51,7.92) v2(198.3,8.04) v2(198.93,8.04)
DMIC0: length 292.6
  TOP w0.102: v2(69.32,74.27) 68.45,74.27 CA6.1 ; v2(247.7,21.3) 247.24,21.75 247.24,24.51 247.5,24.76 248.88,24.76 249.64,24 254.78,24 255.8,25.02 255.8,25.66 256.59,26.45 256.59,28.49 256.27,28.8 v1(256.27,29.44) 256.27,29.63 256.85,30.2 256.85,30.78 257.56,31.49 257.56,31.89 258.31,32.64 258.31,33.25 258.56,33.5 258.56,33.95 258.45,34.05 UA1.47
  IN4 w0.084: v2(247.7,21.3) 244.21,17.8 215.99,17.8 215.24,17.06 214.54,17.06 214.06,17.54 210.96,17.54 210.08,16.66 203.05,16.66 201.74,17.97 182.62,17.97 179.92,15.28 178.36,15.28 176.77,16.87 135.41,16.87 133,14.45 98.23,14.45 95.9,16.78 77.69,16.78 76.71,15.8 65.19,15.8 63.78,17.21 57.31,17.21 54.79,19.73 54.79,25.82 53.75,26.86 53.75,40.69 57.95,44.9 57.95,47.84 58.43,48.32 58.43,54.91 59.3,55.78 59.3,57.99 59.97,58.66 59.97,59.05 59.88,59.14 59.88,60.82 59.95,60.89 59.95,68.37 64.96,73.38 68.43,73.38 v2(69.32,74.27)
  BOTTOM w0.102: JEDP1.7 68.33,75.73 69.32,74.73 v2(69.32,74.27)
DMIC_CLK: length 286.3
  TOP w0.102: RA14.2 CA30.1 258.92,28.31 v2(259.14,28.54) ; v1(67.56,75.67) 67.36,75.46 v2(67.36,75.09) 67.42,75.03 CA5.1
  IN1 w0.084: v2(259.14,28.54) 256.18,28.54 254.87,29.85 253.19,29.85 249.9,33.14 249.9,44.82 257.45,52.38 257.45,54.73 263.14,60.41 263.14,74.8 261.54,76.4 261.54,76.8 260.85,77.49 260.23,77.49 257.54,80.18 257.54,80.74 258.05,81.25 258.05,81.91 257.26,82.7 246.55,82.7 245.25,84 243.99,84 242.62,85.37 242.62,87.2 242.08,87.74 242.08,88.21 239.7,90.59 239.7,91.55 238.92,92.33 238.59,92.33 237,93.93 223.32,93.93 222.59,93.2 205.04,93.2 204.49,93.76 187.19,93.76 185.54,92.11 183.21,92.11 182.68,91.58 180.11,91.58 179.47,90.94 177.14,90.94 176.79,91.3 176.79,91.93 176.43,92.29 170.88,92.29 167.95,95.22 152.6,95.22 151.18,96.64 149.36,96.64 139.52,96.64 138.99,96.11 127.13,96.11 126.68,95.66 116.47,95.66 114.7,93.88 102.97,93.88 102.21,93.13 91.92,93.13 89.14,90.35 83.77,90.35 82.07,88.65 78.15,88.65 75.74,86.24 75.74,83.89 71.12,79.26 71.12,78.73 68.55,76.16 68.31,76.16 67.36,75.21 v2(67.36,75.09)
  BOTTOM w0.102: JEDP1.9 67.36,75.46 v2(67.36,75.09)
DMIC_CLK_L: length 3.5
  TOP w0.102: RA14.1 257.35,30.6 257.97,31.22 258.18,31.22 v1(258.58,31.62) 259.17,32.21 UA1.2
DOCK_AC_OFF: length 153.9
  TOP w0.102: PR844.1 36.74,19.6 v1(37.64,20.5)
  TOP w0.254: PR844.1 35.75,19.98 PD815.1 v2(35.75,21.23)
  IN1 w0.084: v2(113.14,110.46) 113.14,107.97 115.47,105.65 115.47,103.19 114.35,102.07 114.35,96.88 113.89,96.42 108.89,96.42 108.31,95.83 103.01,95.83 102.46,95.29 94.42,95.29 93.57,94.44 89.89,94.44 87.11,91.66 83.34,91.66 82.41,90.73 79.71,90.73 79.01,90.03 77.62,90.03 75.43,87.83 74.1,87.83 73.01,86.74 73.01,85.06 73.18,84.9 73.18,84.17 67.82,78.82 66.85,78.82 61.71,73.67 58.23,73.67 54.72,70.17 54.72,69.38 53.75,68.41 53.75,58.93 54.95,57.73 54.95,54.97 54.35,54.36 54.35,49.28 49.24,44.17 49.24,37.7 47.15,35.61 47.15,29.2 44.5,26.55 44.5,24.93 43.49,23.91 39.17,23.91 36.49,21.23 v2(35.75,21.23)
  BOTTOM w0.102: v2(113.14,110.46) 113.45,110.16 JDOCK1.2
DOCK_AC_OFF_EC: length 243.2
  TOP w0.102: UE1.A63 235.02,52.15 v2(235.64,51.54) ; v2(37.66,33.6) 37.66,34.02 v1(37.85,34.21)
  TOP w0.254: v2(34.79,20.28) PR858.1 PR850.2
  IN1 w0.254: v2(37.66,33.6) 37.01,32.95 37.01,28.96 36.25,28.2 36.25,22.87 35.19,21.81 35.19,20.69 v2(34.79,20.28)
  IN3 w0.122: v2(37.66,33.6) 37.66,32.92 39.48,31.09 45.54,31.09 46.89,32.44 46.89,33.81 50.57,37.49 50.57,38.02 53.2,40.65 54.42,40.65 55.5,41.74 57.92,41.74 58.79,40.87 64.7,40.87 67.74,37.83 185.23,37.83 186.89,39.49 198.59,39.49 202.04,36.03 202.04,32.97 203.71,31.3 204.05,31.3 204.9,32.15 204.9,34.34 209.76,39.2 220,39.2 223.25,42.46 223.25,43.54 224.2,44.48 232.76,44.48 233.93,45.65 233.93,49.39 235.45,50.91 235.45,51.29 235.64,51.47 v2(235.64,51.54)
DOCK_DCIN_IS+: length 179.7
  TOP w0.102: v2(54.09,21.12) 53.95,21.12 53.42,21.65 53.42,21.95 v1(53.7,22.22)
  TOP w0.254: v2(54.09,21.12) 54.54,21.12 55.93,19.72 PQ703.6
  IN1 w0.254: v2(148.32,110.21) 147.21,111.33 134.97,111.33 134.74,111.56 134.12,111.56 133.9,111.33 115.51,111.33 114.44,110.26 114.44,107.67 116.18,105.93 116.18,102.94 115.81,102.57 115.81,97.07 113.74,95 111.67,95 110.92,95.74 109.17,95.74 108.48,95.05 103.2,95.05 101.88,93.73 91.5,93.73 88.68,90.91 83.55,90.91 81.85,89.2 77.88,89.2 75.13,86.46 75.13,85.04 68.14,78.04 67.07,78.04 61.69,72.66 60.09,72.66 59.6,72.17 59.6,71.21 58.59,70.19 56.93,70.19 54.75,68.01 54.75,63.22 55.98,61.99 55.98,54.64 55.37,54.03 55.37,45.63 56.27,44.73 56.27,39.22 54.25,37.2 54.25,22.38 54.55,22.08 54.55,21.46 54.2,21.12 v2(54.09,21.12)
  BOTTOM w0.102: v2(148.32,110.21) 148.45,110.08 JDOCK1.134
DOCK_DCIN_IS-: length 185.4
  TOP w0.102: v1(56.91,16.22) 56.53,16.59 PQ703.4
  TOP w0.254: v2(54.04,21.7) 54.53,21.7 55.68,20.55 57.01,20.55 57.52,20.04 57.52,18.26 57.08,17.82 PQ703.4
  IN1 w0.254: v2(54.04,21.7) 53.87,21.86 53.87,37.43 55.85,39.41 55.85,44.53 54.98,45.4 54.98,54.24 55.58,54.84 55.58,61.8 54.36,63.02 54.36,68.21 56.74,70.6 58.39,70.6 59.21,71.41 59.21,72.34 60,73.13 61.58,73.13 66.9,78.45 67.98,78.45 73.5,83.96 73.5,85 73.31,85.19 73.31,86.53 74.14,87.36 75.37,87.36 77.71,89.7 79.1,89.7 79.81,90.41 82.51,90.41 83.42,91.31 87.33,91.31 90.16,94.14 101.74,94.14 103.06,95.47 108.36,95.47 109.01,96.12 111.08,96.12 111.8,95.4 113.46,95.4 115.43,97.37 115.43,102.73 115.8,103.1 115.8,105.77 114.05,107.52 114.05,110.54 115.23,111.72 133.75,111.72 133.97,111.94 134.9,111.94 135.12,111.72 147.5,111.72 148.95,110.27 v2(148.95,109.86)
  BOTTOM w0.102: JDOCK1.136 v2(148.95,109.86)
DOCK_DET#: length 355.5
  TOP w0.102: v2(227.28,45.86) 227.47,45.86 228.22,45.11 UE1.B41
  TOP w0.254: PQ817.2 12.85,36.19 v1(12.85,32.74) 12.85,29.88 13.68,29.06 21.32,29.06 22.52,27.85 v2(24.18,27.85) ; v2(29.53,37.16) 30.3,36.38 30.3,34.23 29.69,33.62 PR853.1
  IN1 w0.254: v2(24.18,27.85) 24.63,28.3 24.63,33.5 28.28,37.16 v2(29.53,37.16)
  IN2 w0.122: v2(29.53,37.16) 30.12,37.76 30.85,37.76 33.58,40.49 33.58,43.09 36,45.51 46.28,45.51 53.36,52.59 53.36,64.44 54.72,65.81 54.72,72.42 57.68,75.38 61.9,75.38 67.96,81.44 67.96,84.17 71.18,87.39 74.87,87.39 76.5,89.01 81.71,89.01 83.64,90.94 88.3,90.94 88.79,91.43 90.56,91.43 94.35,95.22 95.42,95.22 95.98,94.67 100.89,94.67 101.83,95.61 108.35,95.61 110.39,97.64 117.24,97.64 121.33,101.73 132.04,101.73 136.14,105.83 141.08,105.83 v2(142.55,104.37)
  IN3 w0.122: v2(230.57,95.1) 230.1,95.56 228.44,95.56 227.67,96.33 222.46,96.33 221.48,97.31 218.66,97.31 217.82,98.14 204.75,98.14 204.44,97.84 204.44,96.44 202.39,94.39 197.39,94.39 197.24,94.23 192.33,94.23 191.87,93.77 181.46,93.77 181.43,93.75 178.55,93.75 177.6,92.8 170.94,92.8 165.76,97.98 164.69,97.98 164.05,98.63 v2(164.05,98.81) 162.85,97.61 154.07,97.61 153.26,98.41 151.1,98.41 149.28,100.24 146.27,100.24 142.55,103.96 v2(142.55,104.37)
  BOTTOM w0.102: v2(230.57,95.1) 230.57,94.77 231.65,93.69 231.65,89.35 234.45,86.54 234.45,85.29 233.69,84.52 233.69,80.52 231.35,78.18 231.35,75.64 232.59,74.4 232.59,69.83 232.23,69.48 230.34,69.48 230.07,69.22 230.07,68.01 230.34,67.74 230.34,62.4 231.05,61.7 232.59,61.7 233.57,60.72 233.57,51.39 233.33,51.15 232.38,51.15 229.5,48.27 229.07,48.27 227.28,46.47 v2(227.28,45.86) ; v2(164.05,98.81) 163.27,98.03 D19.2 R272.1
DOCK_DET_R#: length 26.4
  BOTTOM w0.102: 150.95,109.75 150.62,109.75 150.45,109.58 JDOCK1.142 ; 150.95,109.75 JDOCK1.144 ; 150.95,109.75 151.17,109.75 151.33,109.59 151.33,101.61 155.59,97.36 v1(158.09,97.36) 163.76,97.36 D19.1
DOCK_HP_DET: length 66
  TOP w0.102: v1(268.52,26.42) 269,26.9 v2(269.1,26.9) ; UE1.A7 v2(229.97,55.08)
  TOP w0.254: QA3.2 269.8,27.67 RA29.2 269.81,27.61 v2(269.1,26.9)
  IN1 w0.084: v2(269.1,26.9) 269.1,27.41 268.85,27.66 265.61,27.66 265.43,27.83 253.88,27.83 249.22,32.5 249.22,45.67 v2(250.18,46.63)
  IN4 w0.084: v2(250.18,46.63) 249.98,46.63 247.84,48.77 247.84,49.87 247.29,50.42 246.1,50.42 243.79,52.73 240.85,52.73 239.02,54.57 237.86,54.57 237.54,54.89 236.15,54.89 234.87,56.17 231.06,56.17 v2(229.97,55.08)
DOCK_LOM_ACTLED_YEL#: length 156.2
  TOP w0.102: UL4.19 259.02,78.6 260.46,80.04 260.46,80.87 260.64,81.05 260.64,82.45 260.09,83 260.09,85.01 259.1,86 257.18,86 v2(256.78,86.4) ; v2(190.17,96.67) 191.97,94.87 197.16,94.87 199.08,92.95 203.73,92.95 204.42,92.26 206.62,92.26 207.29,92.94 207.29,97.5 v2(207.35,97.56)
  IN2 w0.122: v2(256.78,86.4) 256.33,86.85 246.4,86.85 246.01,86.46 243.17,86.46 243.04,86.33 240.46,86.33 239.94,86.85 239.94,88.92 238.62,90.25 231.61,90.25 228.71,93.15 226.9,93.15 224.75,95.3 220.74,95.3 218.43,97.61 208.65,97.61 208.15,97.12 207.8,97.12 v2(207.35,97.56)
  IN3 w0.122: v2(190.17,96.67) 190.17,96.48 189.9,96.21 184.69,96.21 183.81,97.1 181.61,97.1 180.43,95.91 177.69,95.91 176.84,95.06 171.7,95.06 168.2,98.57 168.2,99.69 165.21,102.68 165.21,104.43 163.89,105.74 161.69,105.74 v1(160.93,106.5) v2(160.21,106.5)
  IN4 w0.084: v2(160.21,106.5) 159.55,107.16 159.55,108.49 158.03,110.01 153.56,110.01 152.86,109.31 140.4,109.31 139.8,109.91 v2(139.8,109.98)
  BOTTOM w0.102: v2(139.8,109.98) 139.95,109.83 JDOCK1.100 ; v2(160.21,106.5) v1(160.93,106.5)
DOCK_LOM_SPD10LED_GRN#: length 153
  TOP w0.102: UL4.40 244.95,79.1 v2(244.57,78.72)
  IN3 w0.122: v2(112.65,95.9) 122.33,95.9 123.65,97.22 129.83,97.22 130.66,96.39 145.13,96.39 145.25,96.27 152.61,96.27 153.16,95.72 165.02,95.72 170.84,89.89 182.72,89.89 184,91.16 191.93,91.16 193,92.23 197.9,92.23 198.18,92.5 205.03,92.5 205.55,91.98 209.73,91.98 213.18,88.53 216.14,88.53 218.01,86.65 220.62,86.65 221.83,85.44 223.67,85.44 224.66,84.45 226.5,84.45 227,83.95 227,81.89 227.41,81.48 229.53,81.48 230.24,80.77 235.76,80.77 237.12,79.4 243.82,79.4 244.5,78.72 v2(244.57,78.72)
  BOTTOM w0.102: JDOCK1.3 113.95,99.69 114.26,99.38 114.26,98.02 v1(112.97,96.73) 112.65,96.4 v2(112.65,95.9)
DOCK_LOM_SPD100LED_ORG#: length 188
  TOP w0.102: v2(160.01,100.75) 158.8,99.54 152.24,99.54 149.33,102.45 134.96,102.45 133.74,103.67 133.74,110.57 133.05,111.26 125.87,111.26 125.25,110.64 v2(125.03,110.64) ; UL4.20 259.2,79.1 260.23,80.13 v2(260.23,81.99) ; v2(207.95,97.57) 207.95,97.24 207.52,96.8 207.52,92.84 206.71,92.04 204.32,92.04 203.64,92.72 198.98,92.72 197.07,94.64 191.54,94.64 v2(189.54,96.65)
  IN2 w0.122: v2(207.95,97.57) 208.24,97.87 218.54,97.87 220.85,95.55 224.85,95.55 227,93.4 228.82,93.4 231.71,90.51 238.73,90.51 240.2,89.05 240.2,86.95 240.57,86.58 242.94,86.58 243.07,86.71 245.9,86.71 246.3,87.11 258.05,87.11 259.69,85.47 259.69,84.19 260.23,83.65 v2(260.23,81.99)
  IN3 w0.122: v2(189.54,96.65) 189.13,97.05 188.63,97.05 188.34,96.77 184.84,96.77 184.01,97.59 181.4,97.59 180.22,96.41 177.48,96.41 176.63,95.56 171.91,95.56 168.69,98.78 168.69,100 166.01,102.68 v2(166.01,103.34)
  IN4 w0.084: v2(166.01,103.34) 165.62,103.34 163.73,101.45 160.71,101.45 v2(160.01,100.75)
  BOTTOM w0.102: v2(125.03,110.64) 125.03,111.03 v1(124.61,111.45) 124.44,111.62 114.8,111.62 113.95,110.77 JDOCK1.4
DOCK_LOM_TRD0+: length 127.6
  TOP w0.089: v2(249.85,81.54) 249.99,81.41 249.99,81.11 249.89,81.02 UL4.36
  IN2 w0.102: v2(249.85,81.54) 250.05,81.74 250.05,81.97 249.35,82.68 247.8,82.68 246.65,81.52 242.85,81.52 242.05,80.72 240.37,80.72 239.95,81.14 236.13,81.14 231.97,85.31 225.38,85.31 225.07,85 223.15,85 221.63,86.52 217.45,86.52 211.79,92.18 205.7,92.18 204.63,93.24 189.19,93.24 188.6,92.66 183.72,92.66 183.13,93.24 171.66,93.24 167.2,97.7 154.21,97.7 151.54,100.38 151.08,100.38 149.95,101.51 148.94,101.51 141.02,109.43 141.02,110.46 141.01,110.47 141.01,110.48 v2(140.91,110.58)
  BOTTOM w0.089: v2(140.91,110.58) 141.02,110.47 141.02,109.52 140.95,109.45 JDOCK1.104
DOCK_LOM_TRD0-: length 127.7
  TOP w0.089: v2(250.44,81.54) 250.3,81.41 250.3,81.16 250.39,81.07 UL4.35
  IN2 w0.102: v2(250.44,81.54) 250.3,81.67 250.3,82.08 249.45,82.93 247.7,82.93 246.54,81.77 242.75,81.77 241.95,80.97 240.48,80.97 240.06,81.39 236.24,81.39 232.07,85.56 225.27,85.56 224.97,85.25 223.26,85.25 221.73,86.78 217.55,86.78 211.9,92.43 205.8,92.43 204.74,93.5 189.08,93.5 188.5,92.91 183.82,92.91 183.24,93.5 171.76,93.5 167.3,97.96 154.32,97.96 151.64,100.63 151.19,100.63 150.05,101.77 149.05,101.77 141.28,109.54 141.28,110.36 v2(141.49,110.58)
  BOTTOM w0.089: JDOCK1.106 141.45,109.44 141.34,109.55 141.34,110.43 v2(141.49,110.58)
DOCK_LOM_TRD1+: length 128.6
  TOP w0.089: v2(251.85,81.54) 251.95,81.44 251.95,81.08 251.89,81.02 UL4.32
  IN2 w0.102: v2(251.85,81.54) 252.02,81.71 252.02,82.3 250.78,83.54 247.33,83.54 246.88,83.08 243.12,83.08 242.33,82.3 236.27,82.3 232.19,86.38 227.44,86.38 226.37,87.45 224.57,87.45 222.51,89.51 216.27,89.51 212.46,93.32 207.68,93.32 206.6,94.4 204.25,94.4 203.95,94.11 172.01,94.11 166.69,99.43 163.39,99.43 162.53,98.57 154.57,98.57 151.9,101.24 151.44,101.24 150.31,102.38 149.3,102.38 144.65,107.02 144.65,108.5 144.19,108.97 143.33,108.97 142.55,109.75 142.55,110.44 v2(142.41,110.58)
  BOTTOM w0.089: v2(142.41,110.58) 142.55,110.44 142.55,109.58 142.45,109.49 JDOCK1.110
DOCK_LOM_TRD1-: length 128.6
  TOP w0.089: v2(252.44,81.54) 252.28,81.38 252.28,81.02 252.39,80.9 UL4.31
  IN2 w0.102: v2(252.44,81.54) 252.27,81.71 252.27,82.41 250.89,83.79 247.23,83.79 246.77,83.34 243.01,83.34 242.22,82.55 236.38,82.55 232.29,86.63 227.55,86.63 226.48,87.7 224.68,87.7 222.62,89.76 216.38,89.76 212.57,93.57 207.79,93.57 206.71,94.65 204.14,94.65 203.85,94.36 172.12,94.36 166.8,99.68 163.28,99.68 162.42,98.82 154.68,98.82 152,101.5 151.55,101.5 150.41,102.63 149.4,102.63 144.91,107.13 144.91,108.61 144.3,109.22 143.43,109.22 142.8,109.85 142.8,110.39 v2(142.99,110.58)
  BOTTOM w0.089: JDOCK1.112 142.95,109.51 142.86,109.6 142.86,110.45 v2(142.99,110.58)
DOCK_LOM_TRD2+: length 128.5
  TOP w0.089: UL4.27 254.39,81.15 254.43,81.19 254.43,81.27 v2(254.23,81.48)
  IN2 w0.102: v2(145.41,110.36) 145.59,110.18 145.59,107.31 149.66,103.24 150.67,103.24 151.8,102.11 152.25,102.11 154.93,99.43 162.16,99.43 163.03,100.3 167.04,100.3 172.37,94.97 180.69,94.97 181.41,95.69 184.39,95.69 185.11,94.97 203.42,94.97 203.71,95.26 206.97,95.26 207.76,94.47 212.53,94.47 214.38,92.62 219.35,92.62 221.39,90.59 224,90.59 225.27,89.32 226.5,89.32 227.63,88.19 232.2,88.19 236.1,84.29 239.2,84.29 240.3,83.2 241.82,83.2 242.59,83.96 246.33,83.96 246.77,84.4 251.14,84.4 252.89,82.65 253.83,82.65 254.32,82.16 254.32,81.57 v2(254.23,81.48)
  BOTTOM w0.089: v2(145.41,110.36) 145.54,110.23 145.54,109.72 145.45,109.63 JDOCK1.122
DOCK_LOM_TRD2-: length 128.5
  TOP w0.089: v2(254.81,81.48) 254.75,81.42 254.75,81.21 254.89,81.06 UL4.26
  IN2 w0.102: v2(254.81,81.48) 254.57,81.72 254.57,82.26 253.93,82.91 253,82.91 251.25,84.66 246.67,84.66 246.22,84.21 242.48,84.21 241.72,83.45 240.4,83.45 239.31,84.54 236.21,84.54 232.31,88.44 227.74,88.44 226.61,89.57 225.38,89.57 224.11,90.84 221.49,90.84 219.46,92.87 214.49,92.87 212.63,94.73 207.86,94.73 207.08,95.52 203.61,95.52 203.31,95.22 185.22,95.22 184.49,95.95 181.31,95.95 180.58,95.22 172.48,95.22 167.14,100.56 162.92,100.56 162.05,99.69 155.03,99.69 152.36,102.36 151.91,102.36 150.77,103.5 149.76,103.5 145.85,107.41 145.85,110.22 v2(145.99,110.36)
  BOTTOM w0.089: JDOCK1.124 145.95,109.63 145.86,109.72 145.86,110.23 v2(145.99,110.36)
DOCK_LOM_TRD3+: length 132
  TOP w0.089: UL4.23 256.39,81.13 256.46,81.2 256.46,81.37 v2(256.35,81.48)
  IN2 w0.102: v2(256.35,81.48) 256.59,81.72 256.59,82.4 255.48,83.51 253.25,83.51 251.04,85.72 247.37,85.72 246.98,85.33 244.06,85.33 243.56,84.84 242.23,84.84 241.5,84.11 240.71,84.11 239.61,85.22 236.5,85.22 232.64,89.08 230.68,89.08 228.93,90.83 225.62,90.83 222.94,93.51 215.29,93.51 213.33,95.47 208,95.47 207.34,96.13 203.24,96.13 202.95,95.83 185.87,95.83 185.12,96.58 180.84,96.58 180.09,95.83 172.73,95.83 167.35,101.22 160.82,101.22 159.18,102.85 159.18,108.94 158.38,109.74 151.66,109.74 150.74,108.81 147.79,108.81 147.12,109.48 147.12,110.13 v2(146.93,110.31)
  BOTTOM w0.089: v2(146.93,110.31) 147.05,110.19 147.05,109.58 146.95,109.47 JDOCK1.128
DOCK_LOM_TRD3-: length 131.9
  TOP w0.089: UL4.22 256.89,81.02 256.78,81.13 256.78,81.33 v2(256.94,81.48)
  IN2 w0.102: v2(256.94,81.48) 256.85,81.57 256.85,82.51 255.58,83.77 253.36,83.77 251.15,85.98 247.27,85.98 246.88,85.58 243.95,85.58 243.46,85.09 242.12,85.09 241.4,84.37 240.82,84.37 239.71,85.47 236.6,85.47 232.74,89.33 230.79,89.33 229.04,91.08 225.72,91.08 223.04,93.76 215.39,93.76 213.44,95.72 208.11,95.72 207.45,96.38 203.14,96.38 202.84,96.09 185.98,96.09 185.23,96.84 180.73,96.84 179.98,96.09 172.84,96.09 167.45,101.47 160.92,101.47 159.44,102.96 159.44,109.04 158.48,109.99 151.56,109.99 150.63,109.07 147.89,109.07 147.37,109.59 147.37,110.17 v2(147.51,110.31)
  BOTTOM w0.089: JDOCK1.130 147.45,109.51 147.37,109.58 147.37,110.17 v2(147.51,110.31)
DOCK_MIC_DET: length 62.5
  TOP w0.102: UE1.B8 v2(229.72,52.83) ; v2(249.62,45.39) 249.62,44.87 v1(249.52,44.77)
  TOP w0.254: RA26.2 269.8,31.39 QA3.5 269.8,30.19 269.54,29.93 v2(268.52,29.93)
  IN1 w0.084: v2(268.52,29.93) 268.5,29.95 266.56,29.95 265.8,29.18 262.03,29.18 260.89,28.04 253.97,28.04 249.43,32.59 249.43,45.19 v2(249.62,45.39)
  IN4 w0.084: v2(229.72,52.83) 236.62,52.83 236.94,52.51 238.99,52.51 240.53,50.97 240.53,50.58 240.75,50.36 243.85,50.36 244.46,49.75 245.37,49.75 249.62,45.5 v2(249.62,45.39)
DOCK_POR_RST#: length 146.6
  TOP w0.102: UE2.A21 235.95,65.1 v2(235.71,65.35) ; v2(231.17,64.31) 231.17,64.88 RE277.2 229.96,66.09 229.96,66.34 v1(229.31,66.99) ; v2(230.3,96.77) 230.24,96.84 230.24,97.96 229.78,98.41 224.29,98.41 222.12,96.24 219.68,96.24 218.29,97.64 208.67,97.64 207.75,96.71 207.75,92.73 206.82,91.81 204.23,91.81 203.54,92.49 198.89,92.49 196.97,94.41 191.15,94.41 v2(188.93,96.63)
  IN3 w0.122: v2(188.93,96.63) 188.81,96.52 184.74,96.52 183.91,97.34 181.51,97.34 180.32,96.16 177.59,96.16 176.74,95.31 171.8,95.31 168.45,98.67 168.45,99.79 165.46,102.78 165.46,104.53 164,105.99 161.82,105.99 160.71,107.11 v2(160.22,107.11)
  IN4 w0.084: v2(235.71,65.35) 235.71,64.69 235.5,64.48 233.95,64.48 233.78,64.31 v2(231.17,64.31)
  BOTTOM w0.102: v2(160.22,107.11) 160.22,107.4 157.6,110.02 150.55,110.02 149.95,109.42 JDOCK1.140 ; v2(231.17,64.31) 231.17,65.48 232.63,66.94 232.63,68.64 232.82,68.83 232.82,74.49 231.58,75.73 231.58,78.08 233.92,80.43 233.92,84.43 234.68,85.19 234.68,86.64 231.88,89.44 231.88,95.2 v2(230.3,96.77)
DOCK_PSID: length 94.6
  TOP w0.102: v1(70.83,82.99) 71.86,82.99 PU1.1 71.93,84.17 v2(72.12,84.37)
  IN2 w0.122: v2(148.28,97.95) 147.73,97.39 146.41,97.39 146.01,97.79 146.01,98.5 145.56,98.95 145.56,99.92 143.11,102.37 137.57,102.37 136.62,101.42 136.62,99.13 136,98.51 135.29,98.51 135.08,98.73 134.42,98.73 132.75,97.05 127.16,97.05 126.99,97.22 123.57,97.22 122.21,95.86 113.78,95.86 113.57,95.86 112.04,94.33 111.84,94.33 111.56,94.05 109.49,94.05 109.28,93.84 108.67,93.23 104.45,93.23 103.84,93.84 102.84,93.84 101.9,92.9 93.63,92.9 90.78,90.05 89.75,90.05 89.21,89.51 83.88,89.51 82.25,87.88 77.32,87.88 74.9,85.46 72.9,85.46 72.12,84.68 v2(72.12,84.37)
  BOTTOM w0.102: JDOCK1.135 148.95,98.97 148.28,98.3 v2(148.28,97.95)
DOCK_PWR_BTN#: length 136.3
  TOP w0.102: RE42.2 251.55,69.83 CE44.1 252.02,70.3 252.02,72.55 252.65,73.18 v1(252.97,73.18) v2(254.19,73.18)
  IN3 w0.122: v2(254.19,73.18) 254.19,74.17 254.85,74.83 254.85,75.18 252.77,77.25 251.11,77.25 246.51,81.86 243.2,81.86 240.56,84.51 240.56,90.18 240.25,90.49 240.25,92.57 239.19,93.63 237.04,93.63 236.85,93.83 233.97,93.83 233.26,94.54 229.11,94.54 227.57,96.09 222.35,96.09 221.46,96.97 205.68,96.97 202.6,93.89 197.6,93.89 197.33,93.62 192.42,93.62 191.35,92.55 181.92,92.55 181.22,93.25 178.76,93.25 177.76,92.25 170.75,92.25 165.9,97.11 153.8,97.11 153,97.91 150.9,97.91 150.41,98.4 149.32,98.4 v2(148.87,97.95)
  BOTTOM w0.102: v2(148.87,97.95) 149.5,98.58 149.5,98.65 149.95,99.1 JDOCK1.139
DOCK_PWR_SW#: length 5.4
  TOP w0.102: UE2.A63 247.91,66.6 248.84,67.54 v1(248.84,67.94) 249.77,68.87 CE45.1 RE42.1 RE62.2
DOCK_SMB_ALERT#: length 455
  TOP w0.102: RE9.2 235.69,46.17 v2(235.5,45.99) 235.34,46.15 UE1.A51
  TOP w0.254: PQ1.3 159.42,7.07 159.82,7.47 159.82,10.13 158.52,11.43 156.11,11.43 153.21,14.33 134.42,14.33 v1(134.23,14.13) 133.99,13.9 v2(131.75,13.9)
  IN1 w0.084: v2(131.75,13.9) 132.38,13.9 135.85,17.37 176.52,17.37 178.61,15.27 180.36,15.27 181.8,16.71 200.73,16.71 204.69,20.67 204.69,29.41 208.18,32.9 208.18,35.51 210.59,37.93 219.69,37.93 223.96,42.2 223.96,43.5 224.82,44.36 227.95,44.36 228.31,44.72 228.31,45.98 228.67,46.33 233.11,46.33 233.46,45.99 v2(235.5,45.99)
  IN2 w0.122: v2(29.9,32.11) 34.5,36.71 34.5,41.53 37.39,44.43 48.1,44.43 54.71,51.04 54.71,53.8 55.59,54.68 55.59,58.02 55.33,58.28 55.33,61.93 54.59,62.67 54.59,64.2 55.93,65.53 55.93,71.14 58.27,73.48 61.25,73.48 69.83,82.07 69.83,83.93 71.62,85.71 74.8,85.71 77.21,88.13 82.15,88.13 83.78,89.76 88.95,89.76 89.49,90.3 90.68,90.3 93.52,93.15 101.8,93.15 102.74,94.09 103.94,94.09 104.55,93.47 108.56,93.47 109.24,94.15 109.39,94.3 111.46,94.3 111.74,94.58 111.94,94.58 113.47,96.11 113.47,96.11 113.88,96.11 113.88,96.11 122.11,96.11 123.47,97.47 127.1,97.47 127.26,97.3 132.64,97.3 133.85,98.5 133.85,98.84 133.72,98.97 133.72,100.37 135.97,102.62 143.21,102.62 145.81,100.02 145.81,99.05 146.33,98.53 146.33,97.82 146.51,97.64 147.38,97.64 v2(147.7,97.96)
  IN3 w0.254: v2(131.75,13.9) 130.18,15.47 123.43,15.47 119.3,19.6 119.3,22.42 118.24,23.48 118.24,25.49 117.39,26.34 50.91,26.34 49.97,25.4 47.56,25.4 44.12,21.96 40.93,21.96 39.77,20.8 37.7,20.8 32.75,25.76 30.38,25.76 29.71,26.43 29.71,29.31 29.26,29.76 29.26,31.61 29.76,32.11 v2(29.9,32.11)
  BOTTOM w0.102: JDOCK1.133 148.45,99.03 147.7,98.28 v2(147.7,97.96)
DOCK_SMB_CLK: length 121
  TOP w0.102: v2(243.45,66.33) 243.45,66.34 244.33,67.23 244.33,67.61 244.41,67.69 UE2.B4 ; RPE3.1 243.32,72.24 243.38,72.17 243.38,71.91 v2(243.3,71.82)
  IN2 w0.122: v2(146.84,99.16) 146.99,99.01 146.99,98.75 147.27,98.46 149.64,98.46 150.1,98.01 150.55,98.01 151.56,97 151.56,97 153.23,95.33 166.06,95.33 172.19,89.2 183.78,89.2 184.87,90.29 191.93,90.29 192.42,90.77 197.99,90.77 199.07,89.69 199.07,89.06 199.92,88.2 205.52,88.2 205.66,88.34 207.12,88.34 208.58,86.89 211.71,86.89 214.14,84.46 215.11,84.46 216,83.57 219.72,83.57 221.52,81.76 223.77,81.76 227.02,78.51 232.17,78.51 234,76.68 236.98,76.68 238.69,74.97 239.28,74.97 241.31,72.94 242.58,72.94 243.45,72.07 243.45,71.98 v2(243.3,71.82) 243.68,71.44 243.9,71.44 244.16,71.19 244.16,68.56 243.19,67.6 243.19,67.04 243.45,66.79 v2(243.45,66.33)
  BOTTOM w0.102: JDOCK1.127 146.95,99.61 147.05,99.5 147.05,99.38 v2(146.84,99.16)
DOCK_SMB_DAT: length 115.8
  TOP w0.102: RPE3.2 243.82,72.24 243.7,72.12 243.7,72.04 v2(243.89,71.86) 243.89,70.61 244.66,69.84 UE2.A3
  IN2 w0.122: v2(243.89,71.86) 243.71,72.03 243.71,72.16 242.68,73.19 241.41,73.19 239.38,75.22 238.79,75.22 237.08,76.93 234.11,76.93 232.27,78.76 227.13,78.76 223.88,82.01 221.63,82.01 219.82,83.81 216.11,83.81 215.21,84.71 214.24,84.71 211.82,87.13 208.68,87.13 207.23,88.59 205.56,88.59 205.42,88.45 200.03,88.45 199.31,89.16 199.31,89.8 198.09,91.02 192.32,91.02 191.83,90.54 184.76,90.54 183.68,89.45 172.29,89.45 166.16,95.58 153.33,95.58 151.66,97.25 150.66,98.26 150.2,98.26 149.75,98.71 147.37,98.71 147.24,98.85 147.24,98.98 v2(147.42,99.16)
  BOTTOM w0.102: v2(147.42,99.16) 147.32,99.26 147.32,99.5 147.45,99.63 JDOCK1.129
DOCK_USB3RN1: length 51.4
  TOP w0.102: v2(101.41,106.19) 101.41,106.19 101.14,105.92 101.14,105.8 101.26,105.69 UI4.22
  IN4 w0.091: v2(134.91,110.17) 135.32,109.76 135.32,109.14 134.15,107.97 128.96,107.97 128.26,107.27 120.18,107.27 110.17,97.26 103.87,97.26 103.56,97.58 103.56,98.12 104.18,98.74 104.18,101.21 102.68,102.71 102.68,103.85 101,105.53 101,105.77 v2(101.41,106.19)
  BOTTOM w0.102: JDOCK1.84 134.95,109.59 135.01,109.65 135.14,109.65 135.23,109.74 135.23,109.85 v2(134.91,110.17)
DOCK_USB3RP1: length 51.3
  TOP w0.102: v2(100.83,106.19) 100.93,106.09 100.93,105.7 100.86,105.63 UI4.23
  IN4 w0.091: v2(135.49,110.17) 135.49,110.17 135.49,109.07 134.22,107.8 129.04,107.8 128.34,107.1 120.25,107.1 110.24,97.09 103.8,97.09 103.38,97.51 103.38,98.19 104.01,98.81 104.01,101.14 102.51,102.64 102.51,103.78 100.83,105.46 100.83,106.18 v2(100.83,106.19)
  BOTTOM w0.102: JDOCK1.86 135.45,109.46 135.45,109.46 135.45,110.12 v2(135.49,110.17)
DOCK_USB3TN1: length 56.2
  TOP w0.102: v2(100.23,106.28) 100.18,106.22 100.18,106.04 100.46,105.76 UI4.24
  IN4 w0.091: v2(100.23,106.28) 100.05,106.09 100.05,103.71 102.22,101.54 102.22,97.86 103.46,96.62 110.44,96.62 120.45,106.63 128.53,106.63 129.2,107.3 135.62,107.3 136.67,108.35 136.67,110.29 136.93,110.55 137.22,110.55 v2(137.42,110.76)
  BOTTOM w0.102: JDOCK1.90 136.45,110.33 136.88,110.76 v2(137.42,110.76)
DOCK_USB3TP1: length 56.4
  TOP w0.102: v2(99.65,106.28) 99.96,105.96 99.96,105.95 100.06,105.85 UI4.25
  IN4 w0.091: v2(137.42,110.17) 137.22,110.38 137,110.38 136.84,110.22 136.84,108.28 135.69,107.12 129.27,107.12 128.6,106.45 120.52,106.45 110.51,96.44 103.39,96.44 102.05,97.79 102.05,101.47 99.88,103.64 99.88,106.05 v2(99.65,106.28)
  BOTTOM w0.102: v2(137.42,110.17) 137.07,110.53 136.96,110.53 136.73,110.3 136.73,109.66 136.95,109.44 JDOCK1.92
DOCK_USBP0+: length 38.3
  TOP w0.102: v2(104.86,105.9) 105.32,105.44 105.32,104.05 105.17,103.9 104.94,103.9 104.76,104.08 UI4.15
  IN4 w0.091: v2(132.72,110.69) 132.51,110.48 132.01,110.48 131.06,111.44 107.51,111.44 105.04,108.97 105.04,106.09 v2(104.86,105.9)
  BOTTOM w0.102: JDOCK1.72 131.95,110.44 132.2,110.69 v2(132.72,110.69)
DOCK_USBP0-: length 38.1
  TOP w0.102: UI4.14 105.26,103.68 105.54,103.96 105.54,105.53 105.44,105.63 v2(105.44,105.9)
  IN4 w0.091: v2(132.72,110.1) 132.51,110.31 131.94,110.31 130.99,111.26 107.59,111.26 105.21,108.89 105.21,106.13 v2(105.44,105.9)
  BOTTOM w0.102: JDOCK1.74 132.45,109.35 132.45,109.35 132.45,109.41 132.32,109.54 132.26,109.54 132.17,109.63 132.17,110.35 132.29,110.47 132.35,110.47 v2(132.72,110.1)
DOCK_USBP3+: length 39.2
  TOP w0.102: UI5.3 161.24,104.6 161.1,104.74 161.1,105.48 160.86,105.71 160.51,105.71 v2(160.31,105.91)
  IN1 w0.091: v2(160.31,105.91) 160.51,105.71 160.76,105.71 160.95,105.91 160.95,106.95 158.23,109.67 154.5,109.67 153.84,109.01 139.18,109.01 138.65,109.54 137.35,109.54 136.9,109.09 130.91,109.09 130.61,109.39 130.61,110.13 v2(130.41,110.33)
  BOTTOM w0.102: JDOCK1.66 130.45,109.6 130.59,109.74 130.59,110.15 v2(130.41,110.33)
DOCK_USBP3-: length 39.1
  TOP w0.102: v2(160.31,105.32) 160.49,105.5 160.77,105.5 160.88,105.39 160.88,104.78 160.74,104.64 UI5.4
  IN1 w0.091: v2(160.31,105.32) 160.31,105.33 160.52,105.54 160.73,105.54 160.74,105.54 160.83,105.54 161.13,105.84 161.13,107.02 158.31,109.84 154.43,109.84 153.77,109.18 139.26,109.18 138.72,109.71 137.27,109.71 136.82,109.27 130.98,109.27 130.79,109.46 130.79,110.13 v2(130.99,110.33)
  BOTTOM w0.102: v2(130.99,110.33) 130.81,110.15 130.81,109.74 130.95,109.6 JDOCK1.68
DOCKED: length 339.3
  TOP w0.102: UI4.10 102.86,101.37 v2(102.95,101.28) ; v2(227.57,42.14) 227.91,42.48 227.91,43.05 227.97,43.11 UE1.A38 ; v2(97.37,102.77) 97.63,102.77 97.74,102.88 UI4.32 ; QV700.2 193.6,71.45 194.37,70.68 v2(194.37,68.95) ; UL4.13 254.89,75.39 255,75.29 255,74.84 v1(255.32,74.52) 255.58,74.27 v2(255.58,73.89)
  IN2 w0.122: v2(227.57,42.14) 228.17,41.54 230.27,41.54 230.62,41.88 230.62,42.85 231,43.23 238.23,43.23 239.91,44.91 239.91,46.22 241.37,47.68 241.37,48.55 242.89,50.08 243.13,50.08 244.58,51.53 249.75,51.53 251.15,52.94 251.15,54.89 253.12,56.85 253.12,62.59 254.17,63.64 254.17,72.48 v2(255.58,73.89)
  IN3 w0.122: v2(255.58,73.89) 255.51,73.95 255.51,75.73 253.45,77.79 251.28,77.79 246.71,82.36 246.15,82.36 245.16,83.35 243.26,83.35 241.12,85.48 241.12,88.52 241.99,89.39 241.99,90.5 240.81,91.68 240.81,92.71 239.37,94.16 237.37,94.16 236.1,95.43 231.91,95.43 230.99,96.35 229.24,96.35 228.53,97.06 222.44,97.06 221.69,97.8 218.87,97.8 218.03,98.64 204.48,98.64 203.95,98.11 203.95,96.65 202.19,94.89 197.19,94.89 197.03,94.73 192.12,94.73 191.66,94.27 178.37,94.27 177.45,93.36 171.09,93.36 166.52,97.92 166.52,99 166.03,99.49 162.99,99.49 161.85,98.35 154.5,98.35 153.69,99.16 151.41,99.16 149.54,101.03 147.95,101.03 143.27,105.71 135.5,105.71 133.07,103.29 119.94,103.29 116.96,100.3 113.63,100.3 112.23,98.9 111.42,98.9 110.49,97.97 109.07,97.97 107.44,96.35 104.03,96.35 103.49,96.89 103.49,98.26 104.11,98.88 104.11,100.8 103.63,101.28 v2(102.95,101.28)
  IN4 w0.084: v2(211.13,80.87) 213.73,80.87 215.93,78.67 222.5,78.67 222.97,78.2 224.85,78.2 225.48,78.83 232.08,78.83 233.72,80.47 239.93,80.47 240.28,80.12 243.07,80.12 244.13,79.06 244.13,78.59 244.52,78.2 249.82,78.2 251.26,76.76 253.97,76.76 255.51,75.22 255.51,73.95 v2(255.58,73.89)
  BOTTOM w0.102: v2(102.95,101.28) 102.35,101.28 101.27,102.36 97.78,102.36 v2(97.37,102.77) ; v2(194.37,68.95) 194.46,69.04 194.46,69.85 195.44,70.83 203.73,70.83 204.19,70.37 209.18,70.37 209.77,70.95 209.77,73.57 210.55,74.36 210.98,74.36 211.34,74.72 211.34,77.14 211.98,77.77 211.98,80.58 211.68,80.87 v2(211.13,80.87) ; UV13.5 210.17,80.54 210.22,80.49 210.75,80.49 v2(211.13,80.87) ; v2(211.13,80.87) 210.56,81.44 210.34,81.44 210.24,81.34 UV13.3
DOCKED#: length 3.4
  TOP w0.102: RV701.2 190.25,70.99 190.44,70.8 QV700.6 ; RV701.2 190.53,71.34 190.64,71.45 QV700.5 ; RV701.2 v1(190.25,72.34)
DOCKED_LIO_EN: length 400.2
  TOP w0.102: UE1.B52 233.01,44.9 232.11,45.81 232.11,49.5 232.17,49.57 v2(232.17,50.02) ; v2(162.85,102.35) 162.46,102.35 162.24,102.57 UI5.9
  IN1 w0.084: v2(74.14,91.94) 73.09,91.94 70.54,89.38 70.54,87.88 68.17,85.52 68.17,82.03 66.94,80.81 65.71,80.81 64.12,79.22 61.77,79.22 60.38,77.83 59.21,77.83 51.63,70.25 51.63,56.09 52.87,54.85 52.87,49.89 47.76,44.78 47.76,38.32 46.09,36.65 v2(46.09,32.74)
  IN2 w0.122: v2(74.14,91.94) 74.56,91.94 75.41,91.08 78.41,91.08 79.16,90.33 82.56,90.33 83.66,91.43 87.65,91.43 89.38,93.16 91.79,93.16 95.4,96.77 107.83,96.77 109.08,98.02 111.09,98.02 113.69,100.62 117.52,100.62 123.69,106.79 123.69,108.09 126.25,110.65 v2(126.25,110.79)
  IN3 w0.122: v2(232.17,50.02) 230.71,51.48 229.49,51.48 228.39,52.57 228.39,53 227.95,53.44 226.81,53.44 226.36,53.89 224.52,53.89 223.83,54.58 223.83,55.78 222.49,57.12 221.9,57.12 220.3,55.52 220.3,54.94 218.58,53.22 218.58,49.07 217.23,47.72 217.23,46.52 216.78,46.07 216.78,43.15 214.2,40.57 209.19,40.57 207.46,38.84 205.5,38.84 204.56,37.91 203.8,37.91 203.34,38.37 203.34,38.41 201.26,40.49 186.05,40.49 184.46,38.9 68.08,38.9 65.1,41.88 62.09,41.88 61.07,42.9 55.96,42.9 54.28,41.22 50.65,41.22 49.96,40.54 49.96,37.63 46.09,33.76 v2(46.09,32.74)
  BOTTOM w0.102: v2(162.85,102.35) 162.85,105.35 157.8,110.4 152.27,110.4 151.09,111.58 127.03,111.58 v2(126.25,110.79)
DPB_CA_DET: length 117.5
  TOP w0.102: v2(166.09,98.81) 165.37,98.09 165.37,93.28 164.78,92.7 164.78,89.94 164.14,89.29 164.14,86.61 164.35,86.4 167.75,86.4 173.95,92.6 177.97,92.6 178.74,91.83 178.74,89.59 179.51,88.83 QV9.2 184.31,88.83 v1(184.39,88.74) v2(185.57,87.57) 186.05,88.05 187.55,88.05 v2(188.18,87.41) ; UV8.M14 191.77,85.09 191.77,86.34 191.47,86.64 188.96,86.64 v2(188.91,86.59)
  IN1 w0.084: v2(166.09,98.81) 165.3,99.6 160.71,99.6 160.17,99.06 153.63,99.06 151.12,101.57 146.95,101.57 145.66,102.86 124.62,102.86 123.37,104.11 123.37,110.35 v2(123.01,110.71)
  IN2 w0.122: v2(188.91,86.59) 188.18,87.32 v2(188.18,87.41)
  BOTTOM w0.102: v2(185.57,87.57) 185.57,87.32 185.95,86.94 186.15,86.94 186.23,86.86 UV11.4 ; RV508.2 188.14,84.97 188.18,85.01 UV11.1 v2(188.18,87.41) ; v2(123.01,110.71) 122.33,111.39 115.28,111.39 114.45,110.56 JDOCK1.6
DPB_CA_DET#: length 24.6
  TOP w0.102: v2(190.08,87.33) 189.55,87.86 188.9,87.86 188.65,87.6 188.65,87.22 188.4,86.97 187.95,86.97 187.31,87.6 v2(186.93,87.6) 186.42,87.1 184.71,87.1 183.63,88.18 QV9.1 182.14,86.02 v1(182.35,85.81) 182.72,85.45 RV90.2
  BOTTOM w0.102: v2(190.08,87.33) 190.08,87.39 187.53,89.94 UV11.13 ; UV11.10 185.58,89.3 186.93,87.95 v2(186.93,87.6)
DPB_DOCK_AUX: length 89.8
  IN1 w0.091: v2(121.27,110.19) 121.74,110.19 121.82,110.12 121.82,104.21 124.94,101.09 124.94,98.56 126.17,97.33 137.85,97.33 138.43,97.91 144.15,97.91 144.8,98.56 150.84,98.56 153.06,96.34 168.41,96.34 171.34,93.4 177.23,93.4 178.58,92.05 182.49,92.05 183.01,92.57 185,92.57 185.33,92.9 185.33,93.09 v2(185.55,93.32)
  BOTTOM w0.102: v2(121.27,110.19) 121.58,110.5 121.75,110.5 121.93,110.33 121.93,109.85 121.78,109.7 121.55,109.7 121.45,109.6 JDOCK1.34 ; v2(185.55,93.32) 185.55,93.2 186.23,92.52 UV11.11 186.23,89.51 187.57,88.18 187.57,87.38 186.88,86.69 UV11.3
DPB_DOCK_AUX#: length 89.7
  IN1 w0.091: v2(184.92,93.32) 185.03,93.32 185.15,93.19 185.15,92.98 184.92,92.75 182.94,92.75 182.41,92.22 178.65,92.22 177.3,93.58 171.41,93.58 168.48,96.51 153.13,96.51 150.91,98.73 144.73,98.73 144.08,98.08 138.35,98.08 137.77,97.5 126.24,97.5 125.11,98.63 125.11,101.16 121.99,104.28 121.99,110.19 121.81,110.37 121.68,110.37 v2(121.27,110.78)
  BOTTOM w0.102: UV11.6 184.93,86.94 184.58,87.29 184.2,87.29 183.95,87.54 183.95,88.95 184.28,89.29 UV11.8 184.28,92.81 184.79,93.32 v2(184.92,93.32) ; JDOCK1.36 121.95,109.57 122.15,109.76 122.15,110.42 121.84,110.72 121.33,110.72 v2(121.27,110.78)
DPB_DOCK_HPD: length 120.8
  TOP w0.102: C311.1 R271.1 132.49,109.64 131.13,111 127.11,111 125.44,109.32 v1(123.81,109.32) 123.48,109.32 v2(122.95,109.86) ; v2(165.51,98.81) 165.14,98.44 165.14,93.38 162.9,91.14 162.9,89.16 162.48,88.74 162.48,87.15 163.47,86.17 167.84,86.17 174.04,92.37 177.88,92.37 178.52,91.73 178.52,86.59 181.51,83.6 184.26,83.6 184.58,83.29 187.01,83.29 187.84,84.11 189.66,84.11 190.29,83.49 UV8.K14
  IN1 w0.084: v2(122.95,109.86) 122.95,104.23 124.53,102.65 145.57,102.65 146.86,101.36 151.03,101.36 153.55,98.85 160.26,98.85 160.8,99.39 164.92,99.39 v2(165.51,98.81)
  BOTTOM w0.102: v2(122.95,109.86) JDOCK1.40
DPB_DOCK_LANE_N0: length 7.9
  TOP w0.102: R261.1 116.95,105.34 116.95,107.1 v4(116.38,107.67) 116,108.05 115.81,108.24 115.81,110.11 v2(115.99,110.29)
  BOTTOM w0.102: JDOCK1.12 115.95,109.6 115.81,109.74 115.81,110.11 v2(115.99,110.29)
DPB_DOCK_LANE_N1: length 8
  TOP w0.102: v2(117.49,110.28) 117.3,110.09 117.3,108.46 118.8,106.97 v4(118.8,106.34) 118.8,105.27 R256.1
  BOTTOM w0.102: v2(117.49,110.28) 117.31,110.09 117.31,109.74 117.45,109.6 JDOCK1.18
DPB_DOCK_LANE_N2: length 8.1
  TOP w0.102: R264.1 120.51,105.34 120.51,107.23 v4(119.62,108.11) 118.8,108.93 118.8,110.07 v2(119,110.27)
  BOTTOM w0.102: v2(119,110.27) 118.81,110.08 118.81,109.74 118.95,109.6 JDOCK1.24
DPB_DOCK_LANE_N3: length 8.5
  TOP w0.102: R267.1 122.29,105.34 v4(122.29,106.21) 122.29,107.23 120.33,109.19 120.33,110.28 v2(120.49,110.45)
  BOTTOM w0.102: v2(120.49,110.45) 120.35,110.31 120.31,110.26 120.31,109.74 120.45,109.6 JDOCK1.30
DPB_DOCK_LANE_P0: length 7.9
  TOP w0.102: v2(115.41,110.29) 115.6,110.1 115.6,108.15 116.03,107.71 116.03,107.69 116.41,107.32 116.43,107.32 116.74,107.01 116.74,105.27 R260.1
  BOTTOM w0.102: JDOCK1.10 115.45,109.6 115.59,109.74 115.59,110.11 v2(115.41,110.29)
DPB_DOCK_LANE_P1: length 8
  TOP w0.102: v2(116.91,110.28) 117.09,110.1 117.09,108.37 118.58,106.88 118.58,106.61 118.57,106.6 118.57,106.07 118.58,106.06 118.58,105.33 R254.1
  BOTTOM w0.102: JDOCK1.16 116.95,109.6 117.09,109.74 117.09,110.09 v2(116.91,110.28)
DPB_DOCK_LANE_P2: length 8.1
  TOP w0.102: R262.1 120.29,105.27 120.29,107.14 120.18,107.25 119.66,107.77 119.65,107.77 119.27,108.14 119.27,108.16 118.59,108.84 118.59,110.1 v2(118.41,110.27)
  BOTTOM w0.102: JDOCK1.22 118.45,109.6 118.6,109.75 118.6,110.08 v2(118.41,110.27)
DPB_DOCK_LANE_P3: length 8.5
  TOP w0.102: R258.1 122.07,105.27 122.07,105.93 122.06,105.94 122.06,106.48 122.07,106.49 122.07,107.14 120.11,109.1 120.11,110.24 v2(119.91,110.45)
  BOTTOM w0.102: v2(119.91,110.45) 120.09,110.26 120.09,109.74 119.95,109.6 JDOCK1.28
DPB_HPD: length 90.1
  TOP w0.102: UV7.5 v2(219.76,91.6)
  IN4 w0.084: v2(219.76,91.6) 218.91,92.45 216.98,92.45 216.13,91.6 194.68,91.6 193.88,90.8 182.12,90.8 v2(181.93,90.99)
  BOTTOM w0.081: 147.56,85.54 147.56,84.87 147.13,84.44 147.13,83.16 147,83.03 147,82.65 146.71,82.36 UC1.C8
  BOTTOM w0.102: 147.56,85.54 147.56,87.54 RC142.2 147.1,89.42 146.34,90.18 146.34,92.03 147.61,93.29 163.09,93.29 163.33,93.05 v1(164.38,93.05) 168.23,93.05 170.08,91.21 173.76,91.21 175.79,89.18 180.75,89.18 181.93,90.36 v2(181.93,90.99)
DPB_LANE_N0: length 91.1
  TOP w0.102: UV8.E14 191.34,80.37 191.27,80.37 191.16,80.26 191.16,80 191.05,79.9 190.86,79.9 190.34,79.38 190.34,78.71 189.9,78.27 189.31,78.27 v2(188.94,78.64) ; C296.1 117.02,102.21 116.89,102.08 116.89,101.13 118.8,99.22 118.8,98.21 121.25,95.76 124.08,95.76 v2(125.42,94.42)
  IN4 w0.091: v2(125.42,94.42) 125.13,94.13 125.13,94.03 125.26,93.89 125.46,93.89 126.59,92.76 130.44,92.76 132.26,94.58 139.44,94.58 140.78,93.24 142.24,93.24 142.5,92.97 147.26,92.97 148.5,91.73 149.9,91.73 151,90.63 153.9,90.63 154.55,91.28 164.86,91.28 170.57,85.57 177.72,85.57 181.82,81.47 182.74,81.47 183.71,80.49 184.9,80.49 185.22,80.17 185.22,79.03 185.41,78.84 187.88,78.84 188.4,78.33 188.63,78.33 v2(188.94,78.64)
DPB_LANE_N0_C: length 0.9
  TOP w0.102: R261.2 C296.2
DPB_LANE_N1: length 87.8
  TOP w0.102: v2(189.29,79.72) 189.48,79.54 189.86,79.54 191.11,80.79 191.36,80.79 UV8.F14 ; v2(126.89,94.68) 126.52,95.05 126.52,95.26 125.2,96.58 122.14,96.58 120.32,98.4 120.32,99.61 118.67,101.26 118.67,102.34 118.74,102.4 118.91,102.4 C303.1
  IN4 w0.091: v2(126.89,94.68) 126.48,94.27 126.48,94.13 127.21,93.4 130.17,93.4 131.99,95.23 139.8,95.23 141.15,93.88 142.5,93.88 142.74,93.64 150.91,93.64 152.52,92.03 154.39,92.03 154.5,91.92 165.12,91.92 170.83,86.21 177.99,86.21 182.09,82.11 183,82.11 183.98,81.13 185.34,81.13 185.92,80.56 185.92,80.14 186.51,79.54 188.38,79.54 188.61,79.31 188.88,79.31 v2(189.29,79.72)
DPB_LANE_N1_C: length 0.9
  TOP w0.102: R256.2 C303.2
DPB_LANE_N2: length 85.6
  TOP w0.102: UV8.G14 191.46,81.61 191.36,81.72 191.09,81.72 191,81.62 191,81.51 191.1,81.41 191.1,81.26 191.03,81.2 190.89,81.2 190.12,80.43 187.76,80.43 187.31,80.87 185.79,80.87 184.84,81.82 184.84,82.21 184.55,82.49 184.38,82.49 v2(184.01,82.86) ; v2(128.3,95.64) 128.05,95.9 128.05,96.03 126.78,97.3 126.67,97.41 122.56,97.41 121.91,98.06 121.91,99.8 120.54,101.16 120.54,101.88 C307.1
  IN4 w0.091: v2(184.01,82.86) 183.66,82.51 183.52,82.51 183.27,82.76 182.36,82.76 178.26,86.86 171.1,86.86 165.39,92.57 154.76,92.57 154.65,92.68 152.79,92.68 150.81,94.65 145.71,94.65 145.51,94.85 143.42,94.85 142.72,95.54 140.4,95.54 140.07,95.87 137.79,95.87 137.41,96.26 134.72,96.26 134.33,95.87 131.72,95.87 130.37,94.52 128.39,94.52 128.02,94.89 128.02,95.36 v2(128.3,95.64)
DPB_LANE_N2_C: length 0.9
  TOP w0.102: R264.2 C307.2
DPB_LANE_N3: length 82.9
  TOP w0.102: v2(189.33,81.59) 189.49,81.43 190.23,81.43 190.87,82.07 190.87,82.46 190.93,82.52 191.11,82.52 191.44,82.19 UV8.H14 ; C309.1 122.06,101.61 122.06,101.17 123.25,99.98 123.25,98.64 123.65,98.23 127.15,98.23 129.13,96.26 129.13,96.01 v2(129.5,95.64)
  IN4 w0.091: v2(129.5,95.64) 129.19,95.34 129.19,95.29 129.32,95.16 130.1,95.16 131.46,96.52 134.06,96.52 134.45,96.9 137.67,96.9 138.06,96.52 140.34,96.52 140.66,96.19 142.99,96.19 143.69,95.49 145.78,95.49 145.97,95.3 151.08,95.3 153.06,93.32 154.92,93.32 155.03,93.21 165.66,93.21 171.37,87.5 180.65,87.5 185.27,82.89 186.16,82.89 187.72,81.33 189.06,81.33 v2(189.33,81.59)
DPB_LANE_N3_C: length 0.9
  TOP w0.102: R267.2 C309.2
DPB_LANE_P0: length 91.2
  TOP w0.102: UV8.E13 191.83,79.96 191.42,79.96 191.13,79.67 190.93,79.67 190.55,79.29 190.55,78.62 189.99,78.06 v2(188.94,78.06) ; C294.1 116.68,101.97 116.68,101.04 118.58,99.13 118.58,98.12 119.95,96.75 121.16,95.54 123.99,95.54 124.83,94.7 v2(124.83,94.42)
  IN4 w0.091: v2(124.83,94.42) 124.96,94.3 124.96,93.95 125.19,93.72 125.38,93.72 126.52,92.59 130.51,92.59 132.33,94.41 139.36,94.41 140.71,93.07 142.16,93.07 142.43,92.8 147.19,92.8 148.43,91.56 149.83,91.56 150.93,90.46 153.97,90.46 154.62,91.11 164.79,91.11 170.49,85.4 177.65,85.4 181.75,81.29 182.66,81.29 183.64,80.32 184.83,80.32 185.04,80.1 185.04,78.96 185.34,78.67 187.81,78.67 188.33,78.15 188.84,78.15 v2(188.94,78.06)
DPB_LANE_P0_C: length 0.9
  TOP w0.102: R260.2 C294.2
DPB_LANE_P1: length 87.8
  TOP w0.102: C298.1 118.45,101.97 118.45,101.17 120.1,99.52 120.1,98.31 122.05,96.37 125.12,96.37 126.31,95.18 v2(126.31,94.68) ; UV8.F13 191.8,80.57 191.2,80.57 189.95,79.32 189.48,79.32 v2(189.29,79.14)
  IN4 w0.091: v2(126.31,94.68) 126.31,94.06 127.14,93.23 130.24,93.23 132.06,95.05 139.73,95.05 141.07,93.71 142.43,93.71 142.67,93.47 150.84,93.47 152.45,91.86 154.32,91.86 154.43,91.75 165.05,91.75 170.76,86.04 177.92,86.04 182.02,81.94 182.93,81.94 183.91,80.96 185.27,80.96 185.74,80.48 185.74,80.06 186.44,79.37 188.31,79.37 188.54,79.14 v2(189.29,79.14)
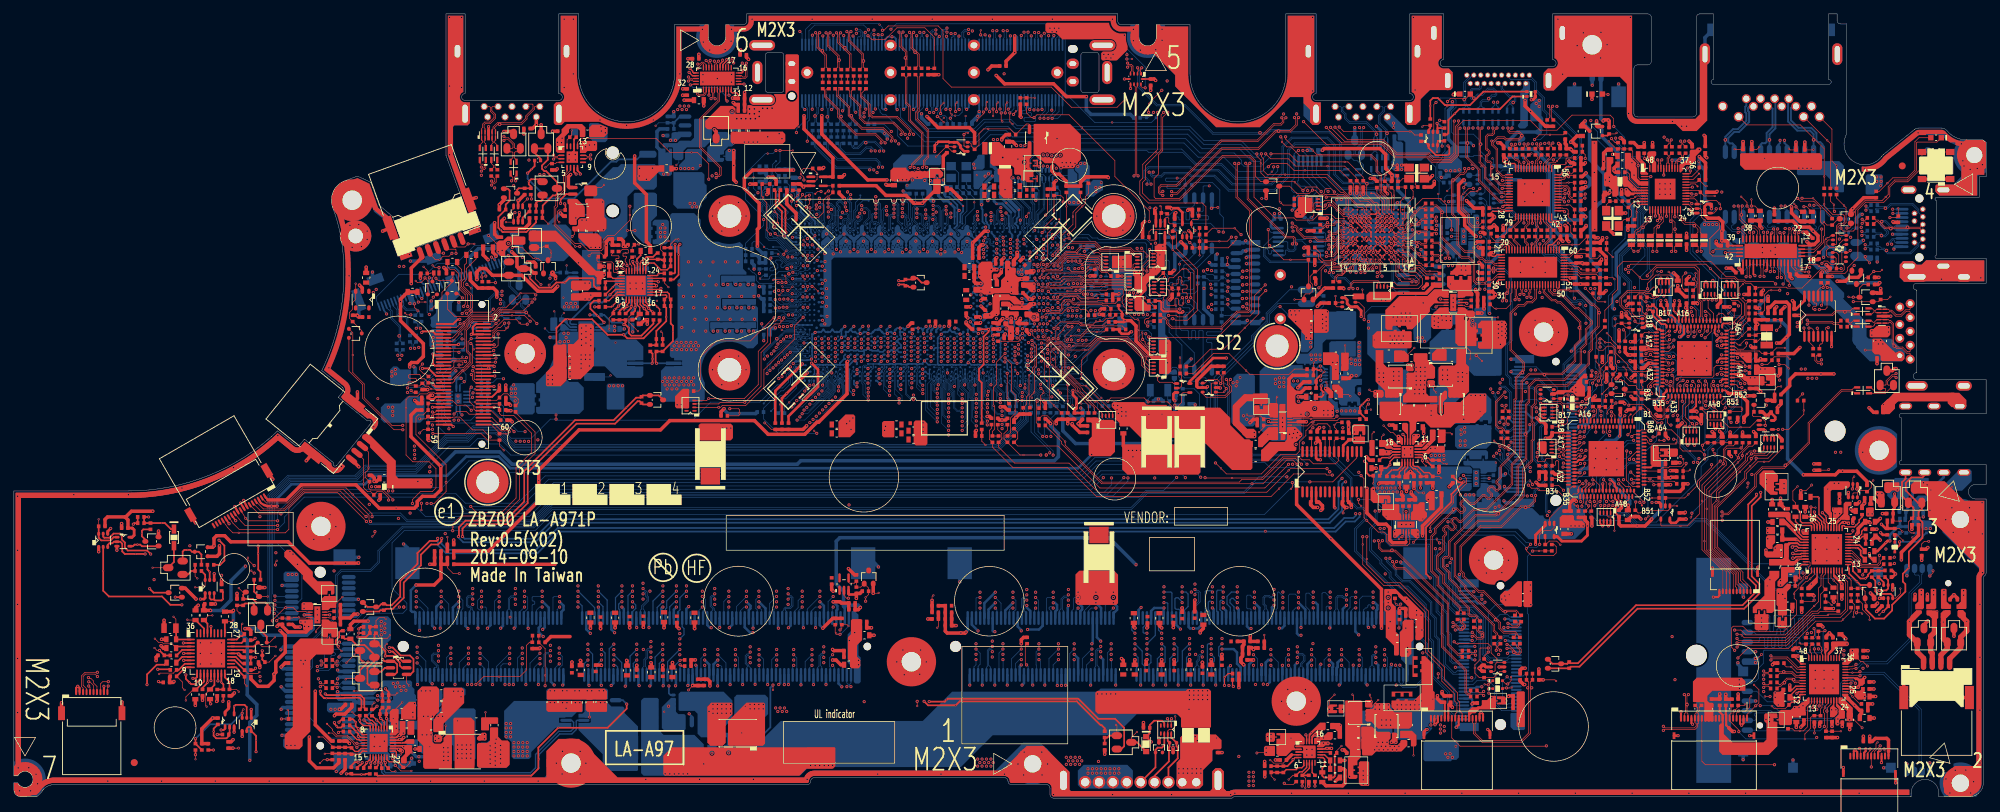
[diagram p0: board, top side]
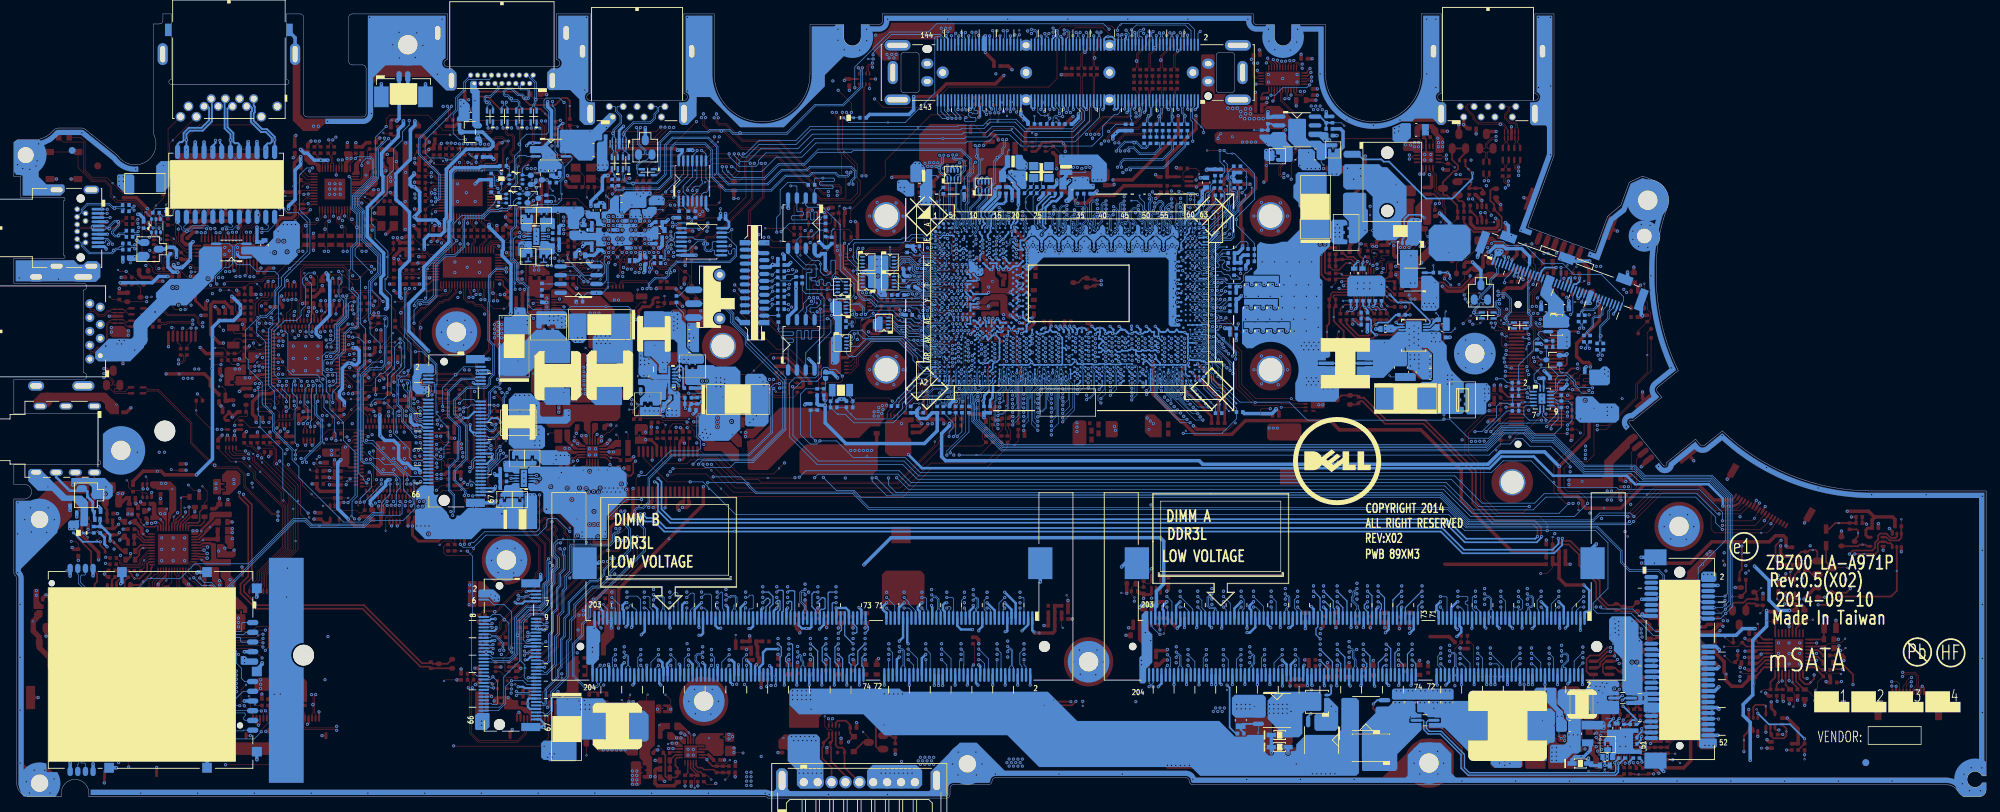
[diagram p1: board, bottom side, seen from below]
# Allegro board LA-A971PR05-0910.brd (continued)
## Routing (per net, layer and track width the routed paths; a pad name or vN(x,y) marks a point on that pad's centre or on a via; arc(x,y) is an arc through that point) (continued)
DPB_LANE_P1_C: length 0.9
  TOP w0.102: R254.2 C298.2
DPB_LANE_P2: length 85.7
  TOP w0.102: v2(184.01,82.27) 184.46,82.27 184.62,82.12 184.62,81.73 185.7,80.66 187.22,80.66 187.67,80.21 190.21,80.21 190.97,80.98 191.12,80.98 191.38,81.24 191.81,81.24 UV8.G13 ; C305.1 120.33,101.88 120.33,101.07 121.69,99.71 121.69,97.97 122.47,97.19 126.58,97.19 126.63,97.15 127.83,95.94 127.83,95.75 v2(127.72,95.64)
  IN4 w0.091: v2(127.72,95.64) 127.85,95.51 127.85,94.82 128.32,94.34 130.44,94.34 131.8,95.7 134.4,95.7 134.79,96.09 137.33,96.09 137.72,95.7 140,95.7 140.33,95.37 142.65,95.37 143.35,94.67 145.44,94.67 145.64,94.48 150.74,94.48 152.72,92.5 154.58,92.5 154.69,92.4 165.32,92.4 171.03,86.69 178.19,86.69 182.29,82.59 183.2,82.59 183.45,82.33 183.95,82.33 v2(184.01,82.27)
DPB_LANE_P2_C: length 0.9
  TOP w0.102: R262.2 C305.2
DPB_LANE_P3: length 83
  TOP w0.102: v2(128.91,95.64) 128.91,96.17 127.06,98.02 123.56,98.02 123.04,98.55 123.04,99.89 121.84,101.08 121.84,102.14 C308.1 ; UV8.H13 191.86,82.19 191.58,81.91 191.02,81.91 190.32,81.22 189.54,81.22 v2(189.33,81.01)
  IN4 w0.091: v2(189.33,81.01) 189.19,81.15 187.65,81.15 186.09,82.71 185.2,82.71 180.58,87.33 171.3,87.33 165.59,93.04 154.95,93.04 154.85,93.15 152.98,93.15 151.01,95.13 145.9,95.13 145.71,95.32 143.62,95.32 142.92,96.02 140.59,96.02 140.27,96.34 137.99,96.34 137.6,96.73 134.52,96.73 134.13,96.34 131.53,96.34 130.17,94.99 129.25,94.99 129.02,95.22 129.02,95.53 v2(128.91,95.64)
DPB_LANE_P3_C: length 0.9
  TOP w0.102: R258.2 C308.2
DPB_MB_P14: length 4.2
  TOP w0.102: v1(271.26,85) RV503.2 271.04,83.66 v2(270.05,83.66)
  BOTTOM w0.102: JMDP1.6 v2(270.05,83.66)
DPC_CA_DET: length 111.1
  TOP w0.102: UV8.A14 191.44,77.64 190.82,77.02 v2(190.11,77.02) 190.05,76.96 188.67,76.96 187.57,75.86 RV509.2 186.59,75.17 186.59,74.37 186.91,74.05 186.91,73.04 186.52,72.65 185.95,72.65 185.71,72.41 QV10.2 v1(184.35,71.84)
  IN2 w0.122: v2(114.21,94.65) 122.81,94.65 123.54,95.39 127.24,95.39 128.09,94.53 129.01,94.53 130.28,95.81 134.28,95.81 135.72,97.25 139.15,97.25 140.27,96.13 142.59,96.13 143.37,95.36 143.37,93.51 143.75,93.13 146.67,93.13 147.71,92.09 163.84,92.09 171.82,84.11 179.44,84.11 182.61,80.94 184.26,80.94 v2(185.28,81.95)
  IN4 w0.084: v2(190.11,77.02) 190.06,77.07 190.06,79.62 189.44,80.24 v2(186.61,80.24) 186.61,80.62 v2(185.28,81.95)
  BOTTOM w0.102: v2(185.28,81.95) 185.45,82.12 UV12.1 ; v2(186.61,80.24) 186.68,80.17 UV12.4 ; v2(114.21,94.65) 114.21,97.41 114.49,97.69 114.49,99.58 114.45,99.62 JDOCK1.5
DPC_CA_DET#: length 15.5
  TOP w0.102: v2(180.56,81.91) 180.56,79.81 v2(180.77,79.6) 182.8,77.57 v1(183.76,77.57) RV91.2 186.35,75.35 186.36,75.34 QV10.1
  BOTTOM w0.102: v2(180.56,81.91) 181,81.47 UV12.13 ; UV12.10 180.85,79.52 v2(180.77,79.6)
DPC_DOCK_AUX: length 86.1
  TOP w0.102: v2(184.05,79.86) 184.23,80.04 184.23,80.62 184.13,80.72 183.1,80.72 177.53,86.29 177.53,91.27 v2(177.32,91.48)
  IN1 w0.091: v2(122.38,98.16) 122.79,98.57 123.01,98.57 124.9,96.68 138.11,96.68 138.69,97.26 151.22,97.26 152.79,95.69 168.14,95.69 171.08,92.76 176.96,92.76 177.73,91.99 177.73,91.89 v2(177.32,91.48)
  BOTTOM w0.102: JDOCK1.33 121.45,99.19 121.59,99.05 121.59,98.4 121.83,98.16 v2(122.38,98.16) ; UV12.11 183.25,80.17 183.38,80.05 183.38,79.22 183.63,78.97 184.15,78.97 184.33,79.15 184.33,79.58 184.19,79.72 v2(184.05,79.86) 184.28,80.09 184.28,80.25 184.52,80.49 185.85,80.49 186.18,80.82 UV12.3
DPC_DOCK_AUX#: length 86.1
  TOP w0.102: v2(177.91,91.48) 177.74,91.32 177.74,86.38 183.19,80.94 184.22,80.94 184.45,80.71 184.45,80.04 v2(184.63,79.86)
  IN1 w0.091: v2(122.38,98.75) 123.08,98.75 124.97,96.86 138.04,96.86 138.62,97.44 151.29,97.44 152.86,95.86 168.21,95.86 171.15,92.93 177.03,92.93 177.91,92.06 v2(177.91,91.48)
  BOTTOM w0.102: UV12.8 182.89,78.22 183.06,78.4 183.06,78.9 183.12,78.97 183.32,78.97 183.54,78.75 184.24,78.75 184.54,79.06 184.54,79.77 v2(184.63,79.86) 184.49,80 184.49,80.16 184.61,80.28 185.45,80.28 186.85,78.87 UV12.6 ; JDOCK1.35 121.95,99.54 121.88,99.47 121.73,99.47 121.67,99.41 121.67,99.28 121.81,99.14 121.81,98.49 121.92,98.38 122.01,98.38 v2(122.38,98.75)
DPC_DOCK_HPD: length 96.4
  TOP w0.102: UV8.A6 196.66,77.53 197.32,76.87 v2(197.36,76.87)
  IN2 w0.122: v2(197.36,76.87) 197.36,75.04 197.05,74.73 191.55,74.73 189.34,76.94 189.09,76.94 188.27,77.76 188.27,84.43 187.38,85.32 178.03,85.32 177.37,85.98 171.06,85.98 164.7,92.34 151.99,92.34 150.95,93.38 143.96,93.38 143.62,93.72 143.62,95.46 142.7,96.38 140.37,96.38 139.25,97.5 135.62,97.5 134.18,96.06 v2(126.3,96.06)
  BOTTOM w0.102: JDOCK1.39 122.95,99.55 123.15,99.35 v1(123.15,98.27) 123.15,97.87 122.98,97.7 C310.1 R268.1 125.27,97.09 v2(126.3,96.06)
DPC_DOCK_LANE_N0: length 3.8
  BOTTOM w0.102: R252.2 115.52,97.43 115.52,97.95 115.54,97.97 115.54,98.42 115.8,98.68 115.8,99.5 115.95,99.65 JDOCK1.11
DPC_DOCK_LANE_N1: length 3.7
  BOTTOM w0.102: JDOCK1.17 117.45,99.54 117.3,99.4 117.3,98.44 117.32,98.42 117.32,97.85 117.3,97.83 117.3,97.43 R255.2
DPC_DOCK_LANE_N2: length 3.8
  BOTTOM w0.102: JDOCK1.23 118.95,99.5 118.8,99.35 118.8,98.78 119.08,98.5 v4(119.08,98.21) 119.08,97.43 R263.2
DPC_DOCK_LANE_N3: length 3.9
  BOTTOM w0.102: R266.2 120.86,97.43 120.86,98.01 v4(120.55,98.31) 120.3,98.56 120.3,99.45 120.45,99.6 JDOCK1.29
DPC_DOCK_LANE_P0: length 3.8
  BOTTOM w0.102: JDOCK1.9 115.45,99.61 115.6,99.47 115.6,98.78 115.31,98.5 v4(115.31,98.28) 115.31,97.43 R259.2
DPC_DOCK_LANE_P1: length 3.7
  BOTTOM w0.102: JDOCK1.15 116.95,99.5 117.09,99.36 v4(117.09,98.16) 117.09,97.43 R253.2
DPC_DOCK_LANE_P2: length 3.8
  BOTTOM w0.102: R257.2 118.87,97.43 118.87,97.91 118.85,97.93 118.85,98.43 118.6,98.69 118.6,99.35 118.45,99.5 JDOCK1.21
DPC_DOCK_LANE_P3: length 3.9
  BOTTOM w0.102: JDOCK1.27 119.95,99.6 120.09,99.46 120.09,98.45 120.39,98.15 120.64,97.9 120.64,97.43 R265.2
DPC_HPD: length 154.9
  TOP w0.102: QV501.3 264.58,76.41 v2(264.91,76.75)
  IN4 w0.084: v2(264.91,76.75) 265.8,76.75 267.39,78.33 267.39,85.51 266.94,85.95 266.28,85.95 264.74,84.41 264.34,84.41 263.76,84.99 260.45,84.99 259.88,84.41 257.87,84.41 255.55,86.74 250.54,86.74 249.71,85.91 244.35,85.91 241.14,89.13 239.83,89.13 238.5,90.45 233.93,90.45 233.57,90.82 231.32,90.82 231.21,90.92 226.17,90.92 224.8,92.3 223.48,92.3 222.11,90.92 218.67,90.92 217.34,92.24 217.06,92.24 216.21,91.39 206.46,91.39 204.33,89.26 204.3,89.26 204.01,88.98 204.01,88.62 203.91,88.51 199.82,88.51 199.25,89.08 199.25,89.57 198.23,90.59 181.71,90.59 v2(181.34,90.96)
  BOTTOM w0.081: 146.96,85.54 146.96,83.37 146.71,83.11 UC1.A8
  BOTTOM w0.102: v2(181.34,90.96) 181.34,90.52 v1(181.08,90.26) 180.23,89.41 175.88,89.41 173.85,91.44 170.17,91.44 168.09,93.52 147.51,93.52 146.11,92.12 146.11,90.09 146.63,89.57 146.63,85.91 146.96,85.58 146.96,85.54
DPC_LANE_N0: length 96.9
  TOP w0.102: v2(196.26,75.73) 196.46,75.73 196.54,75.82 196.54,77.05 196.35,77.25 196.2,77.25 196.14,77.19 196.03,77.19 195.95,77.27 195.95,77.57 UV8.A7
  IN4 w0.091: v2(196.26,75.73) 196.26,75.73 194.57,74.04 188.36,74.04 187.47,74.93 185.62,74.93 182.4,78.15 180.61,78.15 176.1,82.66 166.81,82.66 165.74,83.73 164.78,83.73 160.17,88.34 156.78,88.34 156.57,88.55 155.51,88.55 154.89,87.93 149.03,87.93 148.33,88.63 146.13,88.63 144.81,89.96 141.31,89.96 140.61,90.66 139.71,90.66 138.37,92 133.99,92 131.66,89.67 123.72,89.67 123.36,90.02 123.36,90.12 v2(123.78,90.53)
  BOTTOM w0.102: C295.2 115.67,94.53 115.5,94.53 115.43,94.46 115.43,93.94 118.44,90.93 123.37,90.93 v2(123.78,90.53)
DPC_LANE_N0_C: length 0.9
  BOTTOM w0.102: C295.1 R252.1
DPC_LANE_N1: length 93.8
  TOP w0.102: v2(195.02,76.22) 195.64,76.84 195.64,77 195.45,77.2 195.35,77.2 195.26,77.28 195.26,77.54 UV8.A8
  IN4 w0.091: v2(195.02,76.22) 195.04,76.22 195.33,75.93 195.33,75.71 194.3,74.68 188.63,74.68 187.74,75.57 185.89,75.57 182.67,78.79 180.88,78.79 176.37,83.3 167.07,83.3 164.74,85.64 163.79,85.64 160.44,88.98 157.29,88.98 157.07,89.19 155.24,89.19 154.62,88.57 149.3,88.57 148.6,89.28 146.4,89.28 145.07,90.6 141.58,90.6 140.88,91.3 139.98,91.3 138.63,92.65 133.72,92.65 131.39,90.31 124.9,90.31 124.7,90.51 124.7,90.57 v2(125.04,90.91)
  BOTTOM w0.102: v2(125.04,90.91) 124.67,91.28 124.67,91.64 124.17,92.14 118.58,92.14 117.21,93.51 117.21,94.44 117.3,94.53 117.45,94.53 C299.2
DPC_LANE_N1_C: length 0.9
  BOTTOM w0.102: C299.1 R255.1
DPC_LANE_N2: length 90.9
  TOP w0.102: v2(193.9,75.73) 194.27,76.1 194.27,76.32 194.86,76.91 194.86,77.26 194.77,77.35 194.65,77.35 194.54,77.46 194.54,77.57 194.62,77.64 UV8.A9
  IN4 w0.091: v2(193.9,75.73) 194.11,75.52 194.11,75.4 194.03,75.33 188.9,75.33 188.01,76.22 186.16,76.22 182.2,80.18 180.41,80.18 176.64,83.95 168.48,83.95 166.14,86.28 164.05,86.28 160.71,89.63 158.18,89.63 157.82,89.99 155.12,89.99 154.47,89.34 150.47,89.34 150.09,89.71 149.07,89.71 148.86,89.92 146.67,89.92 145.34,91.25 141.85,91.25 141.14,91.95 140.24,91.95 138.9,93.29 133.45,93.29 131.62,91.46 125.4,91.46 125.12,91.74 124.12,91.74 123.58,92.28 123.58,92.84 v2(123.99,93.26)
  BOTTOM w0.102: v2(123.99,93.26) 123.42,93.83 122.67,93.83 121.81,92.96 119.72,92.96 118.99,93.7 118.99,94.4 119.05,94.46 119.29,94.46 C306.2
DPC_LANE_N2_C: length 0.9
  BOTTOM w0.102: C306.1 R263.1
DPC_LANE_N3: length 87.4
  TOP w0.102: v2(193.7,76.87) 193.84,76.72 193.95,76.72 194.21,76.98 194.21,77.22 194.11,77.32 193.87,77.32 193.73,77.46 193.73,77.87 193.81,77.96 193.91,77.96 194.06,77.81 UV8.A10
  IN4 w0.091: v2(193.7,76.87) 193.29,76.45 193.14,76.45 192.63,76.96 191.61,76.96 191.07,76.43 189.22,76.43 187.82,77.82 185.47,77.82 182.47,80.82 180.69,80.82 176.92,84.59 170.63,84.59 165.84,89.38 163.41,89.38 162.16,90.63 154.85,90.63 154.2,89.98 150.74,89.98 150.36,90.36 149.56,90.36 149.35,90.57 147.35,90.57 145.59,92.32 141.88,92.32 141.61,92.59 140.51,92.59 139.17,93.94 132.53,93.94 130.7,92.11 125.72,92.11 125.44,92.39 125.19,92.39 124.87,92.7 124.87,92.91 v2(125.2,93.23)
  BOTTOM w0.102: v2(125.2,93.23) 125.01,93.42 125.01,93.64 124,94.65 122.95,94.65 122.94,94.67 122.31,94.67 122.3,94.65 121.44,93.79 120.98,93.79 120.86,93.91 120.86,94 C301.2
DPC_LANE_N3_C: length 0.9
  BOTTOM w0.102: R266.1 C301.1
DPC_LANE_P0: length 96.9
  TOP w0.102: UV8.B7 196.38,77.92 196.38,77.52 196.76,77.14 196.76,75.65 v2(196.26,75.15)
  IN4 w0.091: v2(196.26,75.15) 195.92,75.15 194.64,73.87 188.29,73.87 187.4,74.76 185.55,74.76 182.33,77.98 180.54,77.98 176.03,82.48 166.73,82.48 165.66,83.56 164.71,83.56 160.1,88.16 156.71,88.16 156.5,88.38 155.58,88.38 154.96,87.75 148.96,87.75 148.26,88.46 146.06,88.46 144.74,89.78 141.24,89.78 140.54,90.48 139.64,90.48 138.29,91.83 134.06,91.83 131.73,89.5 123.64,89.5 123.19,89.95 v2(123.19,90.53)
  BOTTOM w0.102: C302.2 115.22,94.1 115.22,93.85 118.35,90.72 123,90.72 v2(123.19,90.53)
DPC_LANE_P0_C: length 0.9
  BOTTOM w0.102: C302.1 R259.1
DPC_LANE_P1: length 93.9
  TOP w0.102: UV8.B8 195.64,78.01 195.64,77.31 195.86,77.09 195.86,76.75 195.6,76.49 v2(195.6,76.22)
  IN4 w0.091: v2(195.6,76.22) 195.5,76.12 195.5,75.64 194.37,74.51 188.56,74.51 187.67,75.4 185.82,75.4 182.6,78.62 180.81,78.62 176.3,83.13 167,83.13 164.67,85.46 163.71,85.46 160.37,88.81 157.22,88.81 157,89.02 155.31,89.02 154.69,88.4 149.23,88.4 148.53,89.1 146.33,89.1 145,90.43 141.51,90.43 140.8,91.13 139.9,91.13 138.56,92.47 133.79,92.47 131.46,90.14 124.83,90.14 124.53,90.44 124.53,90.83 v2(124.45,90.91)
  BOTTOM w0.102: C297.2 116.99,94.1 116.99,93.42 118.49,91.92 124.08,91.92 124.45,91.55 v2(124.45,90.91)
DPC_LANE_P1_C: length 0.9
  BOTTOM w0.102: C297.1 R253.1
DPC_LANE_P2: length 91
  TOP w0.102: UV8.B9 194.71,78.03 195.07,77.67 195.07,76.82 194.48,76.23 v2(194.48,75.73)
  IN4 w0.091: v2(123.41,93.26) 123.41,92.21 124.05,91.57 125.04,91.57 125.33,91.28 131.69,91.28 133.52,93.12 138.83,93.12 140.17,91.77 141.07,91.77 141.77,91.07 145.27,91.07 146.6,89.75 148.79,89.75 149,89.54 150.02,89.54 150.4,89.16 154.54,89.16 155.19,89.82 157.75,89.82 158.11,89.45 160.64,89.45 163.98,86.11 166.07,86.11 168.4,83.78 176.56,83.78 180.34,80 182.13,80 186.09,76.05 187.94,76.05 188.83,75.16 194.1,75.16 194.28,75.33 194.28,75.53 v2(194.48,75.73)
  BOTTOM w0.102: v2(123.41,93.26) 123.41,93.53 123.33,93.61 122.76,93.61 121.9,92.75 119.63,92.75 118.77,93.61 118.77,94.1 C304.2
DPC_LANE_P2_C: length 0.9
  BOTTOM w0.102: C304.1 R257.1
DPC_LANE_P3: length 87.4
  TOP w0.102: v2(193.7,76.28) 193.93,76.51 194.03,76.51 194.42,76.9 194.42,77.31 194.34,77.39 194.34,78.01 UV8.B10
  IN4 w0.091: v2(124.61,93.23) 124.7,93.15 124.7,92.63 125.12,92.21 125.37,92.21 125.65,91.94 130.78,91.94 132.6,93.76 139.1,93.76 140.44,92.42 141.54,92.42 141.81,92.15 145.52,92.15 147.27,90.39 149.28,90.39 149.49,90.19 150.29,90.19 150.66,89.81 154.28,89.81 154.93,90.46 162.09,90.46 163.34,89.21 165.77,89.21 170.56,84.42 176.84,84.42 180.61,80.65 182.4,80.65 185.4,77.65 187.75,77.65 189.15,76.26 191.14,76.26 191.68,76.79 192.56,76.79 193.07,76.28 v2(193.7,76.28)
  BOTTOM w0.102: v2(124.61,93.23) 124.8,93.42 124.8,93.55 123.91,94.44 v4(122.63,94.44) 122.39,94.44 121.53,93.57 120.89,93.57 120.64,93.82 120.64,94.01 C300.2
DPC_LANE_P3_C: length 0.9
  BOTTOM w0.102: C300.1 R265.1
DSWODVREN: length 10
  BOTTOM w0.076: UC1.AW7 147.41,60.51 147.41,60.02 147.24,59.84 147.24,59.1 147.68,58.66 148.59,58.66 148.81,58.44 149.84,58.44 150.45,57.82 152.12,57.82 152.39,57.55 v1(152.39,56.59) 152.39,56.16 RC78.1
EC5048_TX: length 42.8
  TOP w0.102: UE1.B2 232.72,52.75 v2(232.33,52.36) ; JDEG1.9 246,32.79 243,35.79 v1(243,42.84) 243,45.11 v2(246.07,48.18) 246.07,50.27 246.57,50.76 247.51,50.76 RE74.2
  IN4 w0.084: v2(232.33,52.36) 232.52,52.55 236.6,52.55 236.85,52.3 238.9,52.3 240.32,50.88 240.32,50.39 240.56,50.15 243.76,50.15 244.38,49.54 245.25,49.54 246.07,48.72 v2(246.07,48.18)
EC_32KHZ_MEC5085: length 47.3
  TOP w0.102: v2(245.4,67.29) 245.41,67.3 UE2.B2 ; v1(236.83,51.56) 236.86,51.54 v2(237.54,51.54) ; v2(225.86,45.31) 225.71,45.31 225.22,44.82 UE1.B35 225.22,44.05 225.01,43.84 224.52,43.84 221.07,40.39 UZ11.2
  IN1 w0.084: v2(237.54,51.54) 237.67,51.41 237.67,50.2 235.02,47.56 232.4,47.56 231.64,46.8 228.48,46.8 228.17,46.5 227.85,46.17 227.85,44.91 227.76,44.83 226.34,44.83 v2(225.86,45.31)
  BOTTOM w0.102: v2(237.54,51.54) 237.54,52.55 237.78,52.79 237.78,54.77 239.27,56.27 239.27,57.87 239.43,58.04 239.43,59.64 239.87,60.07 239.87,60.63 240.22,60.99 243.83,60.99 244.46,61.62 244.46,66.9 244.85,67.29 v2(245.4,67.29)
EDP_BIA_PWM: length 105.1
  TOP w0.102: v2(60.38,72.17) 60.78,72.58 DV1.3
  IN3 w0.122: v2(60.38,72.17) 61.27,73.06 66.72,73.06 69.55,75.9 73.69,75.9 80.41,82.62 83.09,82.62 83.6,83.13 91.28,83.13 94.38,86.24 100.84,86.24 103.93,89.33 107.38,89.33 108.18,88.53 109.65,88.53 109.67,88.56 112.44,91.32 133.37,91.32 134.21,92.16 142.92,92.16 143.19,91.89 145.2,91.89 v2(145.47,91.63)
  BOTTOM w0.081: UC1.B8 146.42,82.2 146.42,83.09 146.67,83.35 146.67,84.81 146.68,84.82 146.68,85.54
  BOTTOM w0.102: v2(145.47,91.63) 145.78,91.31 v1(145.78,90.72) 145.78,90.1 146.41,89.47 146.41,85.81 146.68,85.54
EDP_COMP: length 5.8
  TOP w0.508: RC133.2 v1(138.01,79.99) 139.7,81.69 v2(140.24,81.69)
  BOTTOM w0.254: UC1.D20 v2(140.24,81.69)
EDP_CPU_AUX: length 88.7
  IN1 w0.091: v2(124.08,86.04) 123.99,85.95 123.74,85.95 123.57,86.12 123.57,87.03 121.21,89.38 118.88,89.38 115.59,92.66 92.12,92.66 89.33,89.88 83.96,89.88 82.26,88.18 78.35,88.18 76.27,86.1 76.27,82.72 69.09,75.55 68.84,75.55 67.56,74.27 66.21,74.27 65.78,74.7 64.55,74.7 61.08,71.23 60.42,71.23 57.96,68.77 57.96,67.74 v2(57.93,67.7)
  BOTTOM w0.081: UC1.B45 123.99,82.37 124.34,82.71 124.53,82.71 124.72,82.9 124.72,84.85 124.73,84.86 124.73,84.87
  BOTTOM w0.102: v2(57.93,67.7) 58.09,67.87 58.09,68.35 CV2.1 ; 124.73,84.87 124.73,85.62 124.52,85.83 124.3,85.83 v2(124.08,86.04)
EDP_CPU_AUX#: length 88.6
  IN1 w0.091: v2(124.08,85.46) 123.76,85.78 123.67,85.78 123.4,86.05 123.4,86.96 121.14,89.21 118.8,89.21 115.52,92.49 92.19,92.49 89.4,89.71 84.03,89.71 82.34,88.01 78.42,88.01 76.44,86.03 76.44,82.65 69.16,75.37 68.91,75.37 67.63,74.1 66.14,74.1 65.71,74.52 64.62,74.52 61.16,71.05 60.49,71.05 58.14,68.7 58.14,68.08 v2(58.51,67.7)
  BOTTOM w0.081: UC1.A45 123.87,82.65 123.75,82.65 123.69,82.71 123.69,82.97 123.81,83.1 124.13,83.1 124.32,82.91 124.45,82.91 124.52,82.98 124.52,84.84 124.51,84.85 124.51,84.87
  BOTTOM w0.102: v2(58.51,67.7) 58.31,67.91 58.31,68.31 CV1.1 ; v2(124.08,85.46) 124.24,85.61 124.43,85.61 124.51,85.53 124.51,84.87
EDP_CPU_AUX#_C: length 4.4
  BOTTOM w0.102: CV1.2 58.35,69.9 58.35,70.14 58.01,70.47 56.54,70.47 56.32,70.7 56.08,70.93 56.08,70.94 56.07,70.97 56.06,71.02 56.14,71.2 JEDP1.33
EDP_CPU_AUX_C: length 4.3
  BOTTOM w0.102: JEDP1.34 55.67,71.03 55.85,70.94 55.86,70.93 55.88,70.88 55.88,70.87 55.9,70.8 56.17,70.54 56.45,70.26 57.92,70.26 58.13,70.05 58.13,69.94 CV2.2
EDP_CPU_HPD: length 121.9
  TOP w0.102: v2(148.01,81.49) 148.3,81.78 148.3,82.24 149.72,83.67 v1(149.72,84.68) RC141.2 150.72,86.83 151.05,86.5 v2(151.05,85.89)
  IN2 w0.122: v2(59.8,69.7) 59.8,70.05 61.79,72.03 61.79,72.61 70.53,81.35 71.75,81.35 74.68,84.28 75.13,84.28 75.72,84.87 77.73,86.88 82.66,86.88 83.83,88.05 90.54,88.05 93.21,90.72 94.35,90.72 94.91,90.15 97.75,90.15 99.25,91.65 104.26,91.65 104.83,92.22 109.14,92.22 109.32,92.4 111.32,92.4 112.25,93.34 122.55,93.34 123.13,93.92 123.34,93.92 123.34,93.92 125.79,93.92 125.99,93.71 127.58,93.71 128.15,94.29 129.11,94.29 130.39,95.56 134.39,95.56 135.83,97 139.04,97 140.16,95.88 142.49,95.88 143.12,95.26 143.12,93.19 150.42,85.89 v2(151.05,85.89)
  BOTTOM w0.076: UC1.D6 147.88,81.35 v2(148.01,81.49)
  BOTTOM w0.102: 59.14,73.19 59.43,72.41 59.49,72.35 59.49,70.01 v2(59.8,69.7)
EDP_CPU_LANE_N0: length 91.4
  IN1 w0.091: v2(57.1,64.81) 57.1,65.71 57.97,66.59 58.81,66.59 59.13,66.91 59.13,68.36 64.27,73.5 67.74,73.5 69.12,74.89 69.34,74.89 76.92,82.47 76.92,85.84 78.62,87.54 82.53,87.54 84.23,89.23 90.34,89.23 93.12,92.02 114.45,92.02 117.73,88.74 120.95,88.74 122.92,86.76 122.92,85.83 123.5,85.25 123.5,84.23 123.61,84.11 123.91,84.11 v2(124.07,84.27)
  BOTTOM w0.076: UC1.C45 123.36,81.48 123.15,81.69 123.15,82.96 123.41,83.22 123.41,84.08 123.6,84.26 124.06,84.26 v2(124.07,84.27)
  BOTTOM w0.102: CV4.1 57.3,65.46 57.3,65.01 v2(57.1,64.81)
EDP_CPU_LANE_N0_C: length 6.5
  BOTTOM w0.102: CV4.2 57.37,67.02 57.37,67.08 56.5,67.94 56.5,69.06 56.31,69.25 55.59,69.25 55.14,69.7 55.14,70.37 54.67,70.84 54.67,70.84 JEDP1.36
EDP_CPU_LANE_N1: length 91
  IN1 w0.091: v2(122.04,85.37) 121.7,85.37 121.49,85.57 121.49,87.28 120.68,88.09 117.35,88.09 114.09,91.35 93.71,91.35 90.95,88.59 84.5,88.59 82.8,86.89 78.88,86.89 78.05,86.05 78.05,85.33 77.6,84.88 77.6,81.74 71.07,75.21 70.83,75.21 69.49,73.87 69.02,73.87 68,72.85 64.54,72.85 59.78,68.09 59.78,66.48 58.92,65.62 58.92,64.52 58.69,64.29 56.68,64.29 56.46,64.51 55.64,64.51 55.36,64.24 55.36,63.9 v2(55.26,63.8)
  BOTTOM w0.076: v2(122.04,85.37) 122.31,85.09 122.78,85.09 123.24,84.63 123.24,83.59 122.54,82.89 122.54,82.77 122.66,82.65 122.8,82.65 122.87,82.71 UC1.A47
  BOTTOM w0.102: CV6.1 55.44,64.27 55.44,63.99 v2(55.26,63.8)
EDP_CPU_LANE_N1_C: length 6.6
  BOTTOM w0.102: CV6.2 55.46,65.87 v4(55.46,66.6) 55.46,67.88 54.24,69.1 54.24,70.1 53.97,70.37 53.92,70.37 53.74,70.55 JEDP1.38
EDP_CPU_LANE_P0: length 91.2
  IN1 w0.091: v2(57.68,64.81) 57.27,65.22 57.27,65.64 58.04,66.41 58.88,66.41 59.3,66.83 59.3,68.29 64.34,73.33 67.81,73.33 69.19,74.71 69.42,74.71 77.1,82.4 77.1,85.77 78.69,87.36 82.6,87.36 84.3,89.06 90.41,89.06 93.19,91.85 114.37,91.85 117.66,88.56 120.88,88.56 122.75,86.69 122.75,85.75 123.32,85.18 123.32,84.16 123.54,83.94 123.85,83.94 v2(124.07,83.72)
  BOTTOM w0.076: UC1.B46 123.43,81.76 123.53,81.67 123.79,81.67 123.88,81.76 123.88,81.85 123.72,82.01 123.72,82.07 123.64,82.14 123.56,82.14 123.5,82.08 123.4,82.08 123.34,82.14 123.34,82.88 123.6,83.14 123.6,84 123.67,84.07 123.77,84.07 124.07,83.77 v2(124.07,83.72)
  BOTTOM w0.102: v2(57.68,64.81) 57.52,64.97 57.52,65.37 CV3.1
EDP_CPU_LANE_P0_C: length 6.6
  BOTTOM w0.102: 54.91,71.65 55.23,70.71 55.23,70.59 55.36,70.46 55.36,69.79 55.68,69.47 56.4,69.47 56.72,69.15 56.72,68.03 57.58,67.17 57.58,66.98 CV3.2
EDP_CPU_LANE_P1: length 91.1
  IN1 w0.091: v2(55.84,63.8) 55.53,64.11 55.53,64.16 55.71,64.34 56.39,64.34 56.61,64.12 58.76,64.12 59.09,64.45 59.09,65.55 59.95,66.41 59.95,68.02 64.61,72.68 68.07,72.68 69.09,73.7 69.56,73.7 70.9,75.04 71.14,75.04 77.78,81.67 77.78,84.81 78.22,85.25 78.22,85.98 78.96,86.72 82.87,86.72 84.57,88.42 91.02,88.42 93.79,91.18 114.02,91.18 117.27,87.92 120.61,87.92 121.32,87.21 121.32,85.5 v2(122.04,84.78)
  BOTTOM w0.076: UC1.B47 122.87,82.28 122.69,82.46 122.58,82.46 122.35,82.69 122.35,82.97 123.05,83.67 123.05,84.55 122.7,84.9 122.16,84.9 v2(122.04,84.78)
  BOTTOM w0.102: CV5.1 55.66,64.27 55.66,63.99 v2(55.84,63.8)
EDP_CPU_LANE_P1_C: length 6.6
  BOTTOM w0.102: CV5.2 55.68,65.84 55.68,66.32 55.69,66.33 55.69,66.86 55.68,66.88 55.68,67.97 54.46,69.19 54.46,70.19 54.19,70.46 54.19,70.71 JEDP1.37
EN: length 11.3
  TOP w0.102: v1(203.25,47.88) 202.76,48.37 v2(202.76,48.63)
  TOP w0.203: v2(198.09,48.04) 198.09,48.49 198.69,49.09 PU100.20 ; PU100.6 202.62,49.09 202.76,48.95 v2(202.76,48.63)
  TOP w0.254: v2(198.09,48.04) 197.59,47.54 PC119.1 196.82,46.68 PR113.2
  IN1 w0.254: v2(202.76,48.63) 202.17,48.04 v2(198.09,48.04)
EN_+V1.05SP: length 19.8
  TOP w0.254: RZ41.2 193.75,55.52 RZ42.2 193.75,56.37 v1(194.17,56.79) 194.78,57.4 v2(194.98,57.4)
  IN1 w0.254: v2(188.07,62.25) 188.38,62.25 189.36,61.28 189.36,57.66 190.12,56.9 194.22,56.9 194.73,57.4 v2(194.98,57.4)
  BOTTOM w0.254: PU300.1 188.72,61.8 188.27,62.25 v2(188.07,62.25) 187.88,62.25 187.57,61.94 187.57,59.26 PR303.1
EN_DK_PWRBAR: length 3.3
  TOP w0.254: PR874.1 PR857.1 30.16,16.38 v1(29.86,16.67) PU800.17
EN_DOCK_PWR_BAR: length 237.8
  TOP w0.102: v2(226.75,45.28) 226.75,45.15 226.22,44.61 UE1.B37 ; v1(33.68,34.65) 33.68,34.37 34.54,33.5 v2(34.6,33.5)
  TOP w0.254: v2(30.08,13.95) 30.16,14.03 PR857.2
  IN1 w0.254: v2(30.08,13.95) 30.08,16.16 31.36,17.44 31.36,23.91 33.33,25.88 33.33,32.23 v2(34.6,33.5)
  IN3 w0.122: v2(34.6,33.5) 35.11,34.01 38.08,34.01 38.53,33.57 38.53,32.42 39.55,31.41 45.45,31.41 46.58,32.54 46.58,33.88 50.29,37.59 50.29,38.16 53.05,40.92 54.34,40.92 55.4,41.99 58.05,41.99 58.92,41.12 64.8,41.12 67.85,38.08 184.96,38.08 186.62,39.74 198.85,39.74 201.94,36.66 204.37,36.66 205.81,38.09 207.76,38.09 209.5,39.83 214.59,39.83 215.32,40.55 218.62,40.55 220.02,41.95 220.02,44.42 220.71,45.12 220.71,46.53 222.88,48.69 223.94,48.69 225.1,47.54 226.03,47.54 226.75,46.82 v2(226.75,45.28)
EN_I2S_NB_CODEC#: length 45.3
  TOP w0.102: v2(226.3,45.69) 226.34,45.65 226.34,45.11 226.04,44.81 225.92,44.81 225.72,44.61 UE1.B36 ; UA1.1 258.77,32.52 v2(258.01,31.75)
  BOTTOM w0.102: v2(226.3,45.69) 226.3,43.34 226.17,43.22 226.17,41.69 227.89,39.98 232.46,39.98 233.43,39.01 241.21,39.01 242.01,39.81 243.48,39.81 253.35,29.95 254.62,29.95 255.32,30.64 256.9,30.64 v2(258.01,31.75)
EN_INVPWR: length 237
  TOP w0.102: RE55.2 234.63,62.91 v2(234.92,63.2) 235.65,63.2 235.75,63.1 UE2.A25
  IN3 w0.122: v2(56.65,59.11) 55.66,60.11 53.96,60.11 53.54,60.53 53.54,68.61 55.67,70.73 55.67,71.05 57.42,72.8 60,72.8 60.76,73.56 62.34,73.56 63.57,74.79 65.91,74.79 67.51,76.4 70.73,76.4 76.53,82.21 79.24,82.21 80.22,83.19 81.09,83.19 81.6,83.7 83.58,83.7 85.7,85.82 92.83,85.82 94.06,87.05 100.56,87.05 103.63,90.11 110.17,90.11 111.98,91.93 112.13,92.07 133.06,92.07 133.92,92.93 143.33,92.93 143.58,92.68 146.99,92.68 147.73,93.42 151.22,93.42 151.69,92.95 163.88,92.95 169.75,87.09 183.79,87.09 184.98,88.27 187.53,88.27 187.68,88.42 197.59,88.42 199.31,86.7 199.53,86.7 200.03,86.2 205.29,86.2 206.09,85.41 207.09,85.41 207.79,84.71 212.85,84.71 213.96,83.61 215.61,83.61 217.07,82.15 221.33,82.15 222.18,81.29 223.74,81.29 224.92,80.12 225.21,80.12 227.01,78.32 227.01,78.17 228.4,76.78 231.28,76.78 232.05,77.55 232.77,77.55 233.44,76.89 233.44,74.68 231.22,72.45 231.22,70.35 230.94,70.08 230.94,69.66 232.77,67.84 232.77,66.69 233.77,65.69 233.77,63.75 234.32,63.2 v2(234.92,63.2)
  BOTTOM w0.102: QV2.2 61.39,61.57 v1(61.11,61.28) 60.34,61.28 59.14,60.08 59.14,59.61 58.71,59.18 56.72,59.18 v2(56.65,59.11)
EN_LCDPWR: length 8.3
  TOP w0.102: DV3.1 50.07,67.35 RV3.2 48.31,69.11 48.31,69.99 48.73,70.41 48.73,71.39 49.2,71.86 UV24.3 v1(49.2,74.13)
ENVDD_PCH: length 267.7
  TOP w0.102: RC139.2 148.78,84.26 v2(148.53,84) ; UE2.A7 242.66,69.32 242.79,69.44 242.79,71.43 242.43,71.78 242.43,75.93 241.88,76.48 236.51,76.48 235.95,75.91 235.95,75.43 235.26,74.74 234.34,74.74 v1(234.05,75.03) 232.88,76.2 v2(232,76.2) ; DV3.3 48.22,61.55 50.2,59.58 50.2,57.59 54.71,53.09 55.97,53.09 v2(55.98,53.07)
  IN2 w0.122: v2(55.98,53.07) 56.83,53.92 56.83,57.66 58.01,58.84 58.01,63.51 59.23,64.73 59.23,68.36 62.67,71.8 62.67,73.14 70.63,81.1 72.3,81.1 72.45,81.25 77.82,86.62 82.75,86.62 83.93,87.79 90.64,87.79 92.12,89.28 97.23,89.28 99.36,91.4 104.37,91.4 104.72,91.76 104.93,91.97 109.24,91.97 109.42,92.15 111.42,92.15 112.36,93.09 122.65,93.09 123.24,93.67 125.68,93.67 125.91,93.45 127.66,93.45 128.25,94.04 129.21,94.04 130.49,95.31 134.49,95.31 135.93,96.75 138.94,96.75 140.06,95.64 142.39,95.64 142.87,95.15 142.87,93.09 148.46,87.49 148.46,84.07 v2(148.53,84)
  IN3 w0.122: v2(148.53,84) 148.53,85.32 149.73,86.52 153.47,86.52 154.48,85.51 154.48,81.57 156.45,79.6 160.58,79.6 162.1,81.13 174.61,81.13 175.35,81.86 177.73,81.86 180.91,78.68 183.79,78.68 185.18,77.28 188.34,77.28 189.45,76.17 190.08,76.17 191.18,75.07 194.43,75.07 195.05,74.46 197.89,74.46 199.51,76.07 204.59,76.07 205.19,75.47 209.1,75.47 210.41,76.78 211.8,76.78 213.73,78.72 223.93,78.72 225.07,77.57 226.52,77.57 228.05,76.03 231.84,76.03 v2(232,76.2)
  BOTTOM w0.081: UC1.C6 147.47,81.91 148,82.44 148,83.48 v2(148.53,84)
ERC1: length 5.9
  TOP w0.102: PC815.1 23.35,21.66 22.77,22.24 21.54,22.24 21.35,22.43 20.84,22.43 v1(20.29,22.97)
  TOP w0.254: PU800.3 23.59,21.85 PC815.1
ERC2: length 2.6
  TOP w0.254: PC817.1 27.15,15.9 27.86,16.61 v1(27.86,16.67) PU800.13
ERC3: length 5.2
  TOP w0.102: v1(24.75,14.07) 24.75,14.58 25.82,15.64 PC816.1 26.21,15.64
  TOP w0.254: PU800.12 27.36,16.8 26.21,15.64
EXPRESS_DET#: length 4.1
  TOP w0.102: v2(226.03,52.78) 226.22,52.96 UE1.B15 ; T97.1 225.25,55.32 v2(225.41,55.16)
  IN4 w0.084: v2(225.41,55.16) 225.41,53.39 v2(226.03,52.78)
F-IMAX: length 5.8
  TOP w0.203: PU500.10 88.55,71.4 88.27,71.11 v2(88.27,70.84)
  TOP w0.254: v2(88.27,70.84) 88.01,70.58 87.61,70.58 87.17,70.14 PR503.1
  BOTTOM w0.102: v2(88.27,70.84) 87.64,70.84 87.21,70.41 v1(86.46,70.41)
  BOTTOM w0.254: PR508.2 87.92,71.19 v2(88.27,70.84)
FAN1_PWM: length 260.8
  TOP w0.102: RE48.2 234.56,63.61 235.27,63.61 v2(235.58,63.92) 235.89,63.6 UE2.A24 ; v2(53.94,42.95) 53.94,43.28 53.06,44.16 52.27,44.16 CE41.1 51.36,44.16 50.91,44.16 50.34,44.73 v1(50.34,45.31) 50.34,48.8 JFAN1.3
  IN3 w0.122: v2(53.94,42.95) 54.43,43.45 55.02,43.45 55.65,44.08 55.65,46.7 55.97,47.02 55.97,51.45 58.17,53.66 58.17,57.75 57.89,58.03 56.48,58.03 56.21,58.29 56.21,58.78 55.2,59.79 53.9,59.79 53.29,60.4 53.29,68.71 55.42,70.84 55.42,71.72 56.75,73.05 59.7,73.05 60.46,73.81 62.23,73.81 63.46,75.04 65.8,75.04 67.41,76.65 70.62,76.65 76.43,82.46 79.07,82.46 81.11,84.5 84.03,84.5 85.61,86.09 92.74,86.09 93.95,87.3 100.44,87.3 103.5,90.36 110.07,90.36 111.73,92.03 112.03,92.32 112.03,92.32 132.96,92.32 133.82,93.18 143.44,93.18 143.67,92.94 146.86,92.94 147.15,93.23 147.63,93.71 151.32,93.71 151.83,93.2 163.99,93.2 169.84,87.35 183.71,87.35 185.03,88.67 197.69,88.67 199.41,86.95 201.07,86.95 201.5,86.52 206.74,86.52 208.3,84.96 212.96,84.96 214.06,83.85 215.71,83.85 217.17,82.4 221.43,82.4 222.29,81.54 223.85,81.54 225.02,80.37 225.32,80.37 227.26,78.43 227.26,78.28 228.51,77.03 231.18,77.03 231.95,77.8 232.88,77.8 233.69,76.98 233.69,74.58 231.47,72.35 231.47,71.02 232.12,70.37 232.67,70.37 233.78,69.26 233.78,67.75 234.5,67.04 234.5,64.84 234.88,64.46 235.23,64.46 235.58,64.11 v2(235.58,63.92)
FAN1_TACH: length 264.7
  TOP w0.102: v2(54.55,42.97) 54.55,43.04 53.21,44.39 51.36,44.39 51.04,44.7 51.04,45.16 51.19,45.31 CE42.1 50.57,46.21 50.57,46.88 51.04,47.35 v1(51.04,47.6) 51.04,49.86 JFAN1.2 ; v2(238.96,66.01) 238.36,65.41 237.75,65.41 237.7,65.35 UE2.B22 ; v2(231.7,67.47) 231.95,67.23 RE51.2
  IN3 w0.122: v2(54.55,42.97) 54.98,42.97 55.9,43.88 55.9,46.6 56.22,46.92 56.22,51.35 58.42,53.55 58.42,57.93 57.75,58.61 57.75,58.86 56.22,60.39 54.23,60.39 53.84,60.79 53.84,68.43 56.06,70.65 56.06,71.09 57.52,72.55 60.1,72.55 60.86,73.31 66.61,73.31 69.45,76.15 70.83,76.15 76.64,81.96 79.4,81.96 80.31,82.87 82.98,82.87 83.5,83.38 91.17,83.38 94.28,86.49 100.74,86.49 103.83,89.58 107.48,89.58 108.28,88.78 109.54,88.78 112.34,91.57 133.27,91.57 134.1,92.41 143.02,92.41 143.29,92.14 150.89,92.14 151.19,92.44 163.67,92.44 169.52,86.59 169.55,86.59 175.03,86.59 175.63,85.98 182.93,85.98 183.47,86.52 184.44,86.52 185.04,87.12 187.09,87.12 187.88,87.92 196.3,87.92 197.58,86.65 198.66,86.65 199.1,86.21 199.32,86.21 199.86,85.67 205.12,85.67 205.88,84.91 206.88,84.91 207.58,84.21 210.67,84.21 211.81,83.06 214.45,83.06 215.86,81.65 221.12,81.65 221.98,80.8 223.06,80.8 223.41,80.45 223.41,79.79 223.6,79.6 225.03,79.6 226.51,78.12 226.51,77.97 228.2,76.28 231.49,76.28 232.24,77.04 232.59,77.04 232.94,76.68 232.94,75.61 232.38,75.06 231.86,75.06 230.65,73.84 230.65,72.54 229.92,71.81 229.92,68.93 230.91,67.93 231.24,67.93 v2(231.7,67.47)
  IN4 w0.084: v2(231.7,67.47) 231.89,67.67 236.18,67.67 238.22,65.63 238.58,65.63 v2(238.96,66.01)
FB_3V: length 3.7
  TOP w0.203: PU100.4 201.02,47.9 201.46,47.46 201.74,47.46 v1(201.95,47.25) 202.48,46.72 PR100.2
  TOP w0.254: PR100.2 PR102.2
FB_5V: length 3.3
  TOP w0.203: PU100.2 200.22,47.74 v1(199.78,47.31) 199.43,46.95 PR101.1
  TOP w0.254: PR101.1 PR104.1
FB_+V1.05SP: length 9.2
  IN2 w0.254: v2(184.9,57.19) 187.12,57.19 187.69,57.76 187.69,59.8 v2(188.1,60.21)
  BOTTOM w0.254: PU300.4 188.49,60.45 188.25,60.21 v2(188.1,60.21) ; PR310.1 186.63,56.58 PR307.2 186.39,56.79 PR309.2 185.29,56.79 v2(184.9,57.19)
FFS_INT2: length 3.9
  BOTTOM w0.102: UC1.G2 150.89,78.26 151.44,78.26 151.71,78.53 v1(153.09,78.53) 153.55,78.99 RC158.2
FWP#: length 13.5
  TOP w0.102: UE2.B65 245.76,65.85 v2(245.75,65.86) ; v2(253.73,67.41) v1(254.28,67.96) 254.35,68.03 RE81.2 RE82.2
  IN1 w0.084: v2(253.73,67.41) 253.73,68.08 253.13,68.68 249.95,68.68 247.13,65.86 v2(245.75,65.86)
GC6_EVENT#_Q: length 19.3
  TOP w0.102: v2(147.7,74.98) 147.7,75.14 v1(148.02,75.46) ; RPC16.7 163.25,77.45 162.52,76.72 v2(162.52,76.11)
  IN1 w0.084: v2(147.7,74.98) 148.07,75.35 148.51,75.35 148.81,75.64 154.08,75.64 154.36,75.92 160.12,75.92 160.73,76.53 162.1,76.53 v2(162.52,76.11)
  BOTTOM w0.081: UC1.R6 147.7,74.79 v2(147.7,74.98)
GFB: length 3.4
  TOP w0.102: v1(94.22,73.63) 93.62,74.23 PR532.2
  TOP w0.203: PU500.23 93.45,74.89 PR532.2
GPIO_PSID_SELECT: length 242.1
  TOP w0.102: v2(71.23,83.98) 71.23,84.24 71.93,84.94 PU1.6 ; v1(56.31,69.89) 56.57,69.63 v2(57.14,69.63) ; v2(229.96,55.66) 230.47,55.16 UE1.A6
  IN3 w0.122: v2(229.96,55.66) 228.88,54.58 225.29,54.58 224.84,55.03 224.84,57.38 225.54,58.08 225.54,59.47 224.78,60.24 219.82,60.24 215.95,56.36 215.95,49.83 215.13,49.01 214.45,49.01 212.28,46.84 211.51,46.84 211.32,46.65 211.32,43.47 209.71,41.86 202.57,41.86 201.87,42.57 194.72,42.57 193.86,43.43 186.64,43.43 183.12,39.92 95.81,39.92 83.65,52.07 70.01,52.07 69.63,52.45 62.44,52.45 61.56,53.34 61.56,57.46 58.09,60.93 58.09,62.33 57.84,62.59 55.42,62.59 54.47,63.54 54.47,66.96 v2(57.14,69.63)
  IN4 w0.084: v2(71.23,83.98) 71.23,83.3 61,73.06 60.38,73.06 58.91,71.6 58.91,71.41 v2(57.14,69.63)
GPU_GC6_FB_EN: length 16.1
  TOP w0.102: v2(148.18,76.9) 148.55,76.53 148.95,76.53 149.52,77.1 149.77,77.1 151.45,78.78 152.82,78.78 153.59,79.55 v1(154.09,79.55) 155.63,79.55 156.36,78.82 160.61,78.82 161.42,78 RPC3.8
  BOTTOM w0.081: v2(148.18,76.9) 147.96,76.68 UC1.L6
GPU_SMBCLK: length 14.6
  TOP w0.102: v2(245.05,71.76) 244.92,71.89 244.87,71.94 244.87,72.19 244.82,72.24 RPE3.4 ; v2(244.69,59.47) 244.69,59.36 244.91,59.14 UE2.B49
  IN2 w0.122: v2(245.05,71.76) 244.91,71.62 244.91,67.86 244.73,67.68 244.73,60.81 245.16,60.38 245.16,59.94 v2(244.69,59.47)
GPU_SMBDAT: length 14.6
  TOP w0.102: UE2.B48 244.41,59.12 244.28,59.24 244.28,59.69 v2(244.65,60.05) ; RPE3.3 244.32,72.32 244.64,71.99 244.64,71.94 v2(244.47,71.76)
  IN2 w0.122: v2(244.47,71.76) 244.66,71.57 244.66,67.96 244.48,67.78 244.48,60.7 244.76,60.42 244.76,60.16 v2(244.65,60.05)
GREEN_DOCK: length 79.2
  TOP w0.102: UV8.M7 196.01,85.38 195.12,86.27 194.4,86.27 193.78,86.89 193.78,88.48 RV77.1 193.31,89.32 191.57,91.06 v1(189.09,91.06) 184.52,91.06 183.45,92.13 180.91,92.13 v2(180.2,92.84)
  BOTTOM w0.102: JDOCK1.59 128.95,99.6 129.08,99.47 129.08,97.51 131.41,95.17 138.42,95.17 140.05,96.8 143.08,96.8 144,95.87 147.17,95.87 147.37,95.67 168.95,95.67 171.05,93.57 176.39,93.57 178.24,91.72 179.32,91.72 180.2,92.59 v2(180.2,92.84)
H_CATERR#: length 6.1
  BOTTOM w0.076: v1(110.04,78.37) 111.36,77.05 112.23,77.05 112.48,76.8 112.79,76.8 112.94,76.96 112.94,77.28 113.05,77.39 113.66,77.39 UC1.K61
  BOTTOM w0.102: v1(110.04,78.37) 109.88,78.53 RC114.2
H_CPU_SVIDALRT#: length 7.8
  BOTTOM w0.102: RC207.1 107.87,75.34 v1(107.4,74.87) 107.49,74.78 108.64,74.78 108.76,74.9 108.76,75.09 109.08,75.41 109.65,75.41 110.1,75.86 111.37,75.86 111.49,75.98 111.81,75.98 111.98,76.15 112.28,76.15 112.45,75.98 112.9,75.98 UC1.L62
H_CPUPWRGD: length 83.4
  TOP w0.102: v2(57.18,58.75) 57.46,58.47 RC103.1 ; RC123.1 113.02,87.59 ; 113.02,87.59 CC83.1 ; 113.02,87.59 113.02,87.1 v2(111.95,86.02)
  IN1 w0.084: v2(57.18,58.75) 58.03,58.75 59.01,59.73 59.01,60.65 60.95,62.59 60.95,64.33 65.26,68.64 66.96,68.64 68.61,70.29 68.61,70.62 68.85,70.85 69.18,70.85 69.82,70.21 71.04,70.21 72.79,71.96 72.79,74.32 79.46,80.99 79.46,83.94 80.91,85.39 83.42,85.39 85.11,87.08 93.4,87.08 94.44,88.12 105.08,88.12 107.11,86.09 111.89,86.09 v2(111.95,86.02)
  BOTTOM w0.076: UC1.C61 114.24,81.96 114.26,81.98 114.26,82.3 114.4,82.44 114.75,82.44 114.85,82.54 114.85,82.92 114.41,83.35 113.78,83.35 111.95,85.18 111.95,85.54
  BOTTOM w0.102: 111.95,85.54 v2(111.95,86.02)
H_PROCHOT#: length 337.9
  TOP w0.102: v2(89.97,79.86) 89.84,79.73 PC514.2 89,79.41 PR534.1 ; UE2.A46 v2(244.66,57.12) ; v2(46.72,9.46) 46.86,9.6 PR717.1
  IN1 w0.084: v2(46.72,9.46) 48.15,9.46 49.14,10.45 49.14,17.19 50.78,18.83 56.34,18.83 57.25,19.75 57.25,22.67 54.83,25.09 54.83,37.07 59.07,41.31 59.07,48.2 66.63,55.77 66.63,59.54 66.24,59.94 65.54,59.94 64.35,61.12 63.5,61.12 63.22,61.41 63.22,62.82 65.34,64.94 66.03,64.94 67.19,66.11 69.51,66.11 74.2,70.8 74.2,73.04 81.4,80.24 89.59,80.24 v2(89.97,79.86) 90.16,79.67 93.57,79.67 95.11,81.21 97.46,81.21 98.16,80.51 104.37,80.51 107.23,83.36 v2(107.93,83.36)
  IN4 w0.084: v2(109.7,93.32) 110.1,93.71 114.05,93.71 118.5,98.16 118.5,100.93 123.55,105.98 128.8,105.98 129.44,106.63 145.6,106.63 149,103.23 150.07,103.23 151.89,101.4 153.49,101.4 155.35,99.54 159.88,99.54 160.64,100.3 167.63,100.3 172.51,95.43 180.36,95.43 181.15,96.21 185.01,96.21 185.79,95.43 203.7,95.43 206.63,98.36 227.71,98.36 228.24,97.83 228.24,95.89 230.18,93.95 231.1,93.95 232.43,92.62 239.1,92.62 v2(240.93,90.8)
  BOTTOM w0.102: CC20.1 RC116.2 RC121.1 105.34,79.96 107.93,82.55 v2(107.93,83.36) 107.93,83.64 105.3,86.27 105.3,89.98 108.19,92.87 v1(108.51,92.87) 109.26,92.87 v2(109.7,93.32) ; v2(240.93,90.8) 241.77,90.8 242.76,89.81 242.76,84.76 241.29,83.29 241.29,78.57 244.97,74.89 244.97,73.7 245.8,72.87 245.8,68.48 246.85,67.43 246.85,59.64 244.66,57.45 v2(244.66,57.12)
H_PROCHOT#_R: length 8.8
  BOTTOM w0.076: UC1.K63 112.49,77.22 111.56,77.22 111.41,77.37 111.28,77.37 110.45,78.19 110.45,78.46 109.88,79.04
  BOTTOM w0.102: RC121.2 106.25,79.96 106.53,80.24 107.25,80.24 108,79.49 v1(108,79.41) 108.2,79.21 108.45,79.21 108.6,79.06 109.86,79.06 109.88,79.04
H_THERMTRIP#: length 184.2
  TOP w0.102: v2(110.28,93.32) v1(112.13,93.32) ; QE4.3 231.67,58.29 v2(231.83,58.13)
  IN4 w0.084: v2(110.28,93.32) 114.2,93.32 118.89,98 118.89,100.77 123.72,105.6 128.96,105.6 129.6,106.24 145.44,106.24 148.83,102.84 149.9,102.84 151.73,101.02 153.33,101.02 155.19,99.15 160.04,99.15 160.8,99.92 167.47,99.92 172.35,95.04 180.52,95.04 181.31,95.82 184.85,95.82 185.63,95.04 203.86,95.04 206.79,97.97 226.67,97.97 v2(227,97.64)
  BOTTOM w0.102: RC161.1 110.2,89.59 RC25.2 109.64,90.14 109.64,91.06 110.28,91.7 v2(110.28,93.32) ; v2(227,97.64) 227,96.98 227.95,96.03 227.95,94.84 229.27,93.52 229.27,90.49 230.16,89.6 230.16,87.12 232.42,84.86 232.42,82.8 231.93,82.31 231.93,80.65 230.06,78.79 230.06,75.13 230.47,74.72 230.47,73.32 229.51,72.36 229.51,62.36 230.68,61.19 231.13,61.19 231.83,60.49 v2(231.83,58.13)
H_THERMTRIP#_R: length 13.1
  BOTTOM w0.081: UC1.D60 114.37,80.98 113.93,81.42 113.93,81.65 113.6,81.98 113.6,82.23 113.44,82.38 113.03,82.38 112.76,82.65
  BOTTOM w0.102: 112.76,82.65 112.14,82.65 111.94,82.86 111.94,83.08 112.4,83.54 112.4,83.72 112.22,83.9 112.04,83.9 111.49,83.35 111.38,83.35 110.99,83.74 110.99,83.88 111.44,84.34 111.44,84.48 111.23,84.7 111.08,84.7 110.63,84.24 110.48,84.24 109.91,84.82 109.91,85.86 109.58,86.19 109.58,87.22 110.2,87.84 RC161.2
H_VCCST_PWRGD: length 98.6
  TOP w0.102: RC102.1 59.22,61.21 58.91,61.21 58.38,61.74 58.38,62.1 58.81,62.53 v2(58.81,62.55) ; v2(114.58,85.06) 114.58,83.95 114.86,83.67 115.81,83.67 116.51,84.37 116.51,86.15 117.12,86.75 117.36,86.75 CC24.1 RC202.1 117.88,88.22 UC8.4
  IN1 w0.089: v2(58.81,62.55) 59.87,63.6 59.87,64.08 60.2,64.41 60.37,64.41 61.71,65.76 61.71,69.12 63.64,71.05 64.22,71.05 65.39,72.21 68.27,72.21 69.29,73.23 69.75,73.23 69.96,73.44 70.7,73.44 78.26,81.01 78.26,84.51 78.63,84.87 79.19,84.87 80.56,86.25 83.07,86.25 84.77,87.95 92.91,87.95 94.32,89.36 98.46,89.36 99.49,90.39 104.57,90.39 106.85,88.11 111.3,88.11 114.35,85.06 v2(114.58,85.06)
  BOTTOM w0.076: UC1.B59 115.24,82.13 115.18,82.19 115.18,82.4 115.24,82.46 115.53,82.46 115.66,82.59 115.66,83.19 115.84,83.37 115.84,83.59 115.76,83.67 115.56,83.67 115.44,83.55 115.26,83.55 114.99,83.81 114.99,83.99 115.18,84.18 115.18,84.56 115.05,84.68 114.8,84.68 114.67,84.56 114.67,84.13 114.62,84.07 114.22,84.07 114.1,84.2 114.1,84.49
  BOTTOM w0.102: v2(114.58,85.06) 114.9,85.06 115.03,85.19 115.03,87.16 114.9,87.29 114.1,87.29 113.97,87.16 v1(113.97,86.21) 113.97,85.41 113.56,85 113.56,84.75 113.69,84.62 113.97,84.62 114.1,84.49
H_VCCST_PWRGD_XDP: length 12.8
  TOP w0.102: JXDP1.39 60.78,58.82 60.66,58.94 v1(60.07,58.94) 59.65,59.36 59.23,59.36 58.81,59.78 CC112.1 58.39,59.38 RC103.2 57.72,59.52 56.8,59.52 56.72,59.6 56.72,59.85 56.84,59.98 57.84,59.98 57.96,60.11 57.96,60.36 57.84,60.49 56.95,60.49 56.82,60.62 56.82,60.93 56.95,61.06 58.38,61.06 58.51,60.93 58.51,60.57 58.66,60.41 59.11,60.41 RC102.2
H_VR_EN: length 419.9
  TOP w0.076: v2(114.27,79.72) 114.27,79.8 v1(113.68,80.39)
  TOP w0.102: v2(253.61,74.09) 253.28,74.42 249.33,74.42 249.09,74.66 248.2,74.66 247.73,75.13 246.47,75.13 244.26,77.34 231.66,77.34 230.82,76.5 230.82,73.27 230.09,72.53 230.09,71.35 229.02,70.28 RE284.1
  TOP w0.254: PR536.1 v2(83.61,70.78)
  IN1 w0.084: v2(253.61,74.09) 253.92,74.09 254.86,73.15 256.11,73.15 256.44,72.82 256.44,71.5 259.07,68.87 259.07,63.77 258.15,62.86 255.63,62.86 254.58,61.81 254.58,58.63 253.75,57.8 252.85,57.8 251.31,56.26 251.31,51.6 249.48,49.77 249.48,48.82 247.23,46.58 247.23,19.57 245.24,17.58 239.62,17.58 v2(239.12,17.07) ; v2(83.61,70.78) 84.38,71.55 84.38,76.87 85.89,78.38 91.7,78.38 92,78.08 107.11,78.08 108.19,79.16 113.71,79.16 v2(114.27,79.72) 114.73,80.17 115.18,80.17 115.43,80.43 115.43,83.24 113.73,84.94 ; v2(122.4,13.9) 120.27,13.9 115.74,18.43 58.21,18.43 57.65,19 57.65,22.82 56.59,23.88 56.59,38.29 69.04,50.74 74.54,50.74 v2(75.43,51.62)
  IN1 w0.089: v2(111.88,86.79) 111.88,86.79 113.73,84.94
  IN4 w0.084: v2(75.43,51.62) 75.43,53.02 73.34,55.1 73.34,59.18 70.68,61.84 70.68,66.37 71.53,67.22 74.97,67.22 77.46,69.71 81.67,69.71 82.75,70.78 v2(83.61,70.78) ; v2(122.4,13.9) 129.05,13.9 129.51,13.44 132.41,13.44 132.53,13.56 176.77,13.56 178.27,15.07 180.01,15.07 182.63,17.69 201.72,17.69 202.96,16.45 210.17,16.45 211.05,17.33 213.97,17.33 214.45,16.84 215.33,16.84 216.08,17.59 238.59,17.59 v2(239.12,17.07)
  BOTTOM w0.081: UC1.F60 114.57,79.42 v2(114.27,79.72)
  BOTTOM w0.102: RC201.2 111.1,87.82 111.88,87.04 v2(111.88,86.79)
H_VR_READY: length 69.5
  TOP w0.254: PR539.2 83.86,73.45 83.49,73.82 83.49,74.78 83.36,74.91 79.94,74.91 v1(79.33,74.3) 78.1,74.3 77.36,73.56 75.61,73.56 74.28,74.88 v2(74.28,75.25)
  IN1 w0.089: v2(112.65,85.38) 110.13,85.38 109.81,85.7 106.95,85.7 104.92,87.73 94.6,87.73 93.56,86.69 85.28,86.69 83.58,85 81.08,85 79.85,83.78 79.85,80.44 74.66,75.25 v2(74.28,75.25)
  BOTTOM w0.076: UC1.C59 115.06,81.76 115.06,81.88 115.01,81.92 115.01,82.98 114.48,83.51 113.85,83.51 112.65,84.71 v2(112.65,85.38)
  BOTTOM w0.081: 112.5,85.54 v2(112.65,85.38)
  BOTTOM w0.102: RC199.2 111,88.93 RC201.1 111.63,88.3 111.63,87.61 111.95,87.29 112.13,87.29 112.38,87.03 112.38,85.65 112.5,85.54
HDD_DET#: length 235.2
  TOP w0.102: v1(183.85,44.56) 184.03,44.75 v2(184.03,45.46)
  IN2 w0.122: v2(153.1,74.11) 153.54,74.55 154.61,74.55 154.83,74.33 162.41,74.33 167.31,69.43 167.31,67.09 166.48,66.27 166.48,62.65 169.29,59.84 169.29,55 171.34,52.94 171.34,48.74 174.63,45.46 v2(184.03,45.46)
  BOTTOM w0.076: 153.78,74.52 153.81,74.52 153.82,74.51 ; v2(153.1,74.11) 152.76,73.77 152.55,73.77 152.13,73.35 151.29,73.35 UC1.U1
  BOTTOM w0.081: 153.78,74.52 153.51,74.52 v2(153.1,74.11)
  BOTTOM w0.102: 153.82,74.51 154.02,74.31 154.48,74.31 CC107.1 155.21,73.58 156.27,73.58 156.84,74.15 RPC18.6 ; JMINI3.51 45.54,8.65 41.81,12.38 41.81,17.7 42.98,18.87 42.98,22.58 46.53,26.14 46.53,32.04 47.17,32.68 51.36,32.68 52.63,33.95 52.63,35.56 56.01,38.94 74.86,38.94 77.52,41.61 160.87,41.61 163.13,43.88 177.12,43.88 178.7,45.46 v2(184.03,45.46)
HDD_DEVSLP: length 228.5
  TOP w0.102: v1(39.42,12.7) 39.54,12.59 RN1.2 v2(38.51,11.4)
  IN2 w0.122: v2(152.31,77.39) 152.76,76.94 154.02,76.94 154.74,76.21 159.74,76.21 161.13,74.83 164.32,74.83 167.25,71.91 167.25,70.33 167.82,69.76 167.82,66.78 166.99,65.95 166.99,62.9 170.04,59.86 170.04,57.33 172.24,55.14 172.24,49.62 175.56,46.3 v2(183.23,46.3)
  BOTTOM w0.076: v2(152.31,77.39) 152.31,77.24 151.94,76.87 151.47,76.87 151.29,76.69 151.05,76.69 150.67,76.31 UC1.L2
  BOTTOM w0.102: v2(38.51,11.4) 38.56,11.45 JMINI3.44 41.18,11.45 41.58,11.85 41.58,17.79 42.75,18.96 42.75,22.67 46.3,26.23 46.3,32.14 47.07,32.91 51.26,32.91 52.4,34.04 52.4,35.65 55.92,39.17 74.76,39.17 77.43,41.84 160.77,41.84 163.04,44.11 177.03,44.11 179.21,46.3 v2(183.23,46.3)
HDD_FALL_INT: length 12.2
  TOP w0.102: v2(149.61,75.12) 149.95,74.78 150.57,74.78 150.92,75.13 v1(153.62,75.13) 153.85,75.13 154.23,74.75 159.72,74.75 160.11,75.15 RPC9.5
  BOTTOM w0.081: v2(149.61,75.12) 149.29,75.43 UC1.N4
HDMI_CEC: length 19.4
  TOP w0.102: v2(218.9,94.89) 219.58,95.58 v1(221.12,95.58) 223.02,95.58 RV8.1
  BOTTOM w0.102: JHDMI1.13 215.15,103.84 215.44,103.54 218.45,103.54 218.92,103.08 218.92,102 220.07,100.84 220.07,99.1 220.66,98.51 220.66,95.81 219.75,94.89 v2(218.9,94.89)
HDMI_CLK_AUX: length 28.4
  TOP w0.102: RV7.1 221.31,98.01 221.31,99.5 v2(221.5,99.69) ; v2(223.2,86.5) 223.14,86.44 222.91,86.44 222.71,86.63 UV7.48
  IN4 w0.091: v2(221.5,99.69) 221.29,99.9 221.29,100.35 220.85,100.79 220.4,100.79 219.17,102.03 219.17,103.12 218.83,103.46 218.18,103.46 217.97,103.67 217.36,103.67 217.21,103.52 216.8,103.52 JHDMI1.15
  BOTTOM w0.102: v2(223.2,86.5) 222.99,86.28 222.91,86.28 222.75,86.45 222.75,89.8 225.65,92.71 225.65,95.05 221.31,99.39 221.31,99.51 v2(221.5,99.69)
HDMI_DAT_AUX#: length 27.9
  TOP w0.102: v2(220.91,99.69) 221.09,99.51 221.09,98.09 RV9.1 ; v2(223.2,85.91) 222.91,86.21 222.26,86.21 UV7.47
  IN4 w0.091: JHDMI1.16 217.03,103.35 217.28,103.35 217.43,103.5 217.9,103.5 218.11,103.29 218.75,103.29 219,103.04 219,101.96 220.33,100.62 220.78,100.62 221.12,100.28 221.12,99.9 v2(220.91,99.69)
  BOTTOM w0.102: v2(220.91,99.69) 221.1,99.51 221.1,99.3 225.44,94.96 225.44,92.8 222.53,89.89 222.53,86.36 222.82,86.07 223.05,86.07 v2(223.2,85.91)
HDMI_HPD: length 30
  TOP w0.102: v2(214.27,89) 214.3,89.03 UV7.17
  IN3 w0.122: v2(214.27,89) 218.66,89 v2(221.62,91.96)
  BOTTOM w0.102: v1(219.63,93.71) 219.63,93.24 220.92,91.96 v2(221.62,91.96) 221.89,92.24 224.02,92.24 224.7,92.92 224.7,94.79 220.3,99.19 220.3,100.94 219.15,102.09 219.15,103.17 JHDMI1.19
HDMI_LANE_N0: length 12.7
  TOP w0.102: UV7.18 214.61,88.63 214.46,88.48 214.03,88.48 212.75,89.76 212.75,90.63 212.76,90.64 v4(212.76,90.87) 212.76,91.16 212.75,91.17 212.75,91.58 212.53,91.8 212.2,91.8 212.05,91.95 212.05,92.46 212.15,92.56 212.21,92.56 212.48,92.84 212.48,93.22 212.21,93.5 212.15,93.5 212.05,93.6 212.05,95.27 212.24,95.47 212.85,95.47 213.12,95.73 213.12,96.2 213.3,96.37 213.31,96.37 v2(213.49,96.55)
  BOTTOM w0.102: v2(213.49,96.55) 213.49,96.7 213.7,96.91 LV12.4
HDMI_LANE_N1: length 12.8
  TOP w0.102: v2(211.33,96.55) 211.13,96.35 211.13,94.49 211.14,94.47 v4(211.14,94.23) 211.14,93.9 211.13,93.89 211.13,91.67 211.9,90.89 211.9,89.45 214.01,87.34 214.52,87.34 214.61,87.43 UV7.21
  BOTTOM w0.102: v2(211.33,96.55) 211.33,96.55 211.6,96.82 LV10.4
HDMI_LANE_N2: length 14.8
  TOP w0.102: v2(209.43,96.55) 209.22,96.35 209.22,94.61 209.23,94.6 v4(209.23,94.39) 209.23,94.08 209.22,94.07 209.22,92.4 211.05,90.57 211.05,88.98 213.93,86.09 214.47,86.09 214.61,86.23 UV7.24
  BOTTOM w0.102: v2(209.43,96.55) 209.35,96.63 209.35,96.81 209.5,96.97 LV6.4
HDMI_LANE_N3: length 15
  TOP w0.102: v2(215.65,96.55) 215.64,96.55 215.29,96.2 215.29,96.11 215.38,96.02 216.74,96.02 217.08,95.68 v4(217.08,95.45) 217.08,95.17 216.74,94.83 214.71,94.83 214.46,95.07 213.63,95.07 212.93,94.37 212.93,94.2 213.59,93.53 213.59,90.44 214.34,89.69 214.59,89.69 214.74,89.83 UV7.15
  BOTTOM w0.102: LV3.4 215.79,96.97 215.57,96.75 215.57,96.63 v2(215.65,96.55)
HDMI_LANE_P0: length 12.8
  TOP w0.102: UV7.19 214.61,88.23 214.58,88.26 213.94,88.26 212.53,89.67 212.53,91.49 212.45,91.58 212.11,91.58 211.84,91.86 211.84,92.55 212.06,92.78 212.12,92.78 212.27,92.92 212.27,93.14 212.12,93.28 212.06,93.28 211.84,93.51 211.84,95.36 212.15,95.68 212.76,95.68 212.91,95.82 v2(212.91,96.55)
  BOTTOM w0.102: v2(212.91,96.55) 212.85,96.61 LV12.1
HDMI_LANE_P1: length 13
  TOP w0.102: v2(210.75,96.55) 210.91,96.4 210.91,91.58 211.68,90.8 211.68,89.36 213.92,87.12 214.52,87.12 214.61,87.03 UV7.22
  BOTTOM w0.102: LV10.1 v2(210.75,96.55)
HDMI_LANE_P2: length 15.1
  TOP w0.102: UV7.25 214.61,85.83 214.56,85.88 214.56,85.88 213.84,85.88 210.83,88.89 210.83,90.48 209,92.31 209,96.39 v2(208.84,96.55)
  BOTTOM w0.102: v2(208.84,96.55) 208.65,96.74 LV6.1
HDMI_LANE_P3: length 15.1
  TOP w0.102: UV7.16 214.73,89.43 214.69,89.47 214.25,89.47 213.37,90.35 213.37,93.45 212.71,94.11 212.71,94.46 213.54,95.29 214.55,95.29 214.8,95.05 216.65,95.05 216.85,95.25 216.85,95.61 216.65,95.81 215.29,95.81 215.07,96.02 215.07,96.54 v2(215.06,96.55)
  BOTTOM w0.102: v2(215.06,96.55) 214.94,96.68 LV3.1
HOST_ALERT1_R_N: length 13.4
  TOP w0.102: RC179.2 159.03,71.77 158.51,71.25 156.78,71.25 156.68,71.35 152.51,71.35 152.03,71.83 151.33,71.83 v1(151.12,71.61) 150.82,71.32 150.82,70.61 150.48,70.27 149.4,70.27 148.99,70.68 148.67,70.68 v2(148.24,70.25)
  BOTTOM w0.081: v2(148.24,70.25) 147.96,69.97 UC1.AD6
HOST_DEBUG_TX: length 43.2
  TOP w0.102: UE2.B44 242.41,59.32 v2(242.49,59.41) ; JDEG1.8 246.5,32.61 243.36,35.76 v1(243.36,37.03) 243.36,44.86 246.49,47.99 246.49,48.44 246.3,48.63 246.3,50.16 246.56,50.42 248.59,50.42 v2(248.63,50.45) 248.84,50.67 RE73.2
  IN4 w0.084: v2(242.49,59.41) 243.06,58.85 243.06,56.23 244.3,54.98 245.83,54.98 246.53,55.68 248.67,55.68 249.96,54.39 249.96,51.79 248.63,50.45 v2(248.63,50.45)
HSYNC_DOCK: length 76.4
  TOP w0.102: UV8.M9 194.71,85.11 194.21,85.61 193.31,85.61 189.08,89.84 v1(182.99,89.84) 180.44,89.84 179.91,90.37 179.91,92.1 179.58,92.43 v2(179.58,92.84)
  BOTTOM w0.102: JDOCK1.65 130.45,99.61 129.77,98.93 129.77,97.68 131.41,96.03 138.42,96.03 139.79,97.41 143.33,97.41 144.26,96.48 147.51,96.48 147.69,96.3 169.18,96.3 171.29,94.19 176.63,94.19 178.47,92.35 179.02,92.35 179.51,92.84 v2(179.58,92.84)
HW_GPS_DISABLE2#: length 27.5
  TOP w0.102: RE12.2 226.7,41.89 v2(226.7,42.11) 226.62,42.11 v1(226.3,42.43) 226.3,42.68 226.47,42.85 UE1.A35 ; DZ6.1 224.27,55.77 v2(225.41,55.77)
  IN4 w0.084: v2(232.72,49.81) 232.53,49.62 232,49.62 231.15,50.48 231.15,50.58 230.43,51.3 227.65,51.3 226.55,52.41 226.55,53.23 225.86,53.92 225.86,55.32 v2(225.41,55.77)
  BOTTOM w0.102: v2(226.7,42.11) 226.43,42.38 226.43,43.03 227.83,44.42 227.83,46.7 229.17,48.04 230.52,48.04 231.41,48.93 232.08,48.93 232.72,49.57 v2(232.72,49.81)
HW_GPS_DISABLE2#_R: length 2.2
  TOP w0.102: DZ6.2 225.55,56.4 v2(225.65,56.3)
  BOTTOM w0.102: v2(225.65,56.3) 225.29,56.3 224.89,55.9 JNGFF2.18
I2C1_SCL_VMM: length 11.1
  TOP w0.102: UV8.A2 199.47,77.43 199.47,76.33 v1(199.76,76.05) 200.51,75.29 201.66,75.29 202.27,74.68 202.27,74.22 201.97,73.91 199.1,73.91 198.74,74.27 197.47,74.27 197.21,74.01 RPV2.2
I2C1_SDA_VMM: length 10.8
  TOP w0.102: UV8.A1 199.91,76.66 200.79,75.78 201.86,75.78 v1(202.45,75.18) 202.77,74.86 202.77,74.02 202.17,73.42 198.81,73.42 198.52,73.7 RPV2.1
I2S_BCLK: length 6.3
  TOP w0.102: RA31.2 268.68,33.22 265.77,33.22 265.39,33.6 265.39,34.01 v1(265.15,34.25) 264.55,34.85 UA1.16
I2S_DO: length 6.9
  TOP w0.102: RA32.2 268.72,34.18 268.72,33.81 268.36,33.45 265.91,33.45 265.62,33.74 265.62,34.25 264.62,35.25 UA1.17
I2S_MCLK: length 2.6
  TOP w0.102: UA1.15 264.48,34.45 265.16,33.77 265.16,33.24 RA30.2
I_ADP: length 288.5
  TOP w0.102: UE2.A12 240.16,69.2 240.31,69.34 v2(240.31,70.11)
  TOP w0.254: v2(44.12,15.4) 44.12,14.93 44.65,14.4 v1(45.01,14.4) 47.56,14.4 47.63,14.46 49.75,14.46 50.04,14.17 50.04,13.05 PR716.1
  IN1 w0.254: v2(51.49,44.87) 49.53,42.92 49.53,37.58 47.54,35.59 47.54,26.73 44.97,24.16 44.97,15.87 44.5,15.4 v2(44.12,15.4)
  IN3 w0.122: v2(51.49,44.87) 51.42,44.93 51.42,46.65 53.96,49.19 53.96,55.54 51.21,58.28 51.21,70.88 58.41,78.08 65.65,78.08 70.3,82.73 72.06,82.73 74.55,85.21 75.81,85.21 76.89,86.3 83.01,86.3 84.63,87.92 91.84,87.92 93.05,89.14 97.14,89.14 100.18,92.18 107.97,92.18 109.89,94.1 112.9,94.1 113.87,95.07 122.66,95.07 124.07,96.48 129.52,96.48 130.35,95.64 133.13,95.64 133.81,94.96 137.98,94.96 138.58,95.56 144.33,95.56 144.42,95.48 152.2,95.48 152.71,94.97 164.71,94.97 170.54,89.14 183.03,89.14 184.31,90.42 192.24,90.42 193.23,91.4 198.14,91.4 198.46,91.73 204.74,91.73 205.29,91.18 205.29,90.34 207.2,88.43 207.3,88.43 208.2,87.52 209.79,87.52 209.96,87.35 210.26,87.35 210.55,87.64 210.55,87.96 210.85,88.26 212.4,88.26 213.3,87.35 215.27,87.35 217.68,84.94 222.19,84.94 223.17,83.95 223.9,83.95 225.74,82.11 226.08,82.11 228.42,79.77 232.13,79.77 232.63,80.27 234.44,80.27 235.24,79.47 235.24,77.99 236.33,76.9 236.33,74.69 238.62,72.4 238.62,71.41 239.32,70.71 239.83,70.71 240.31,70.23 v2(240.31,70.11)
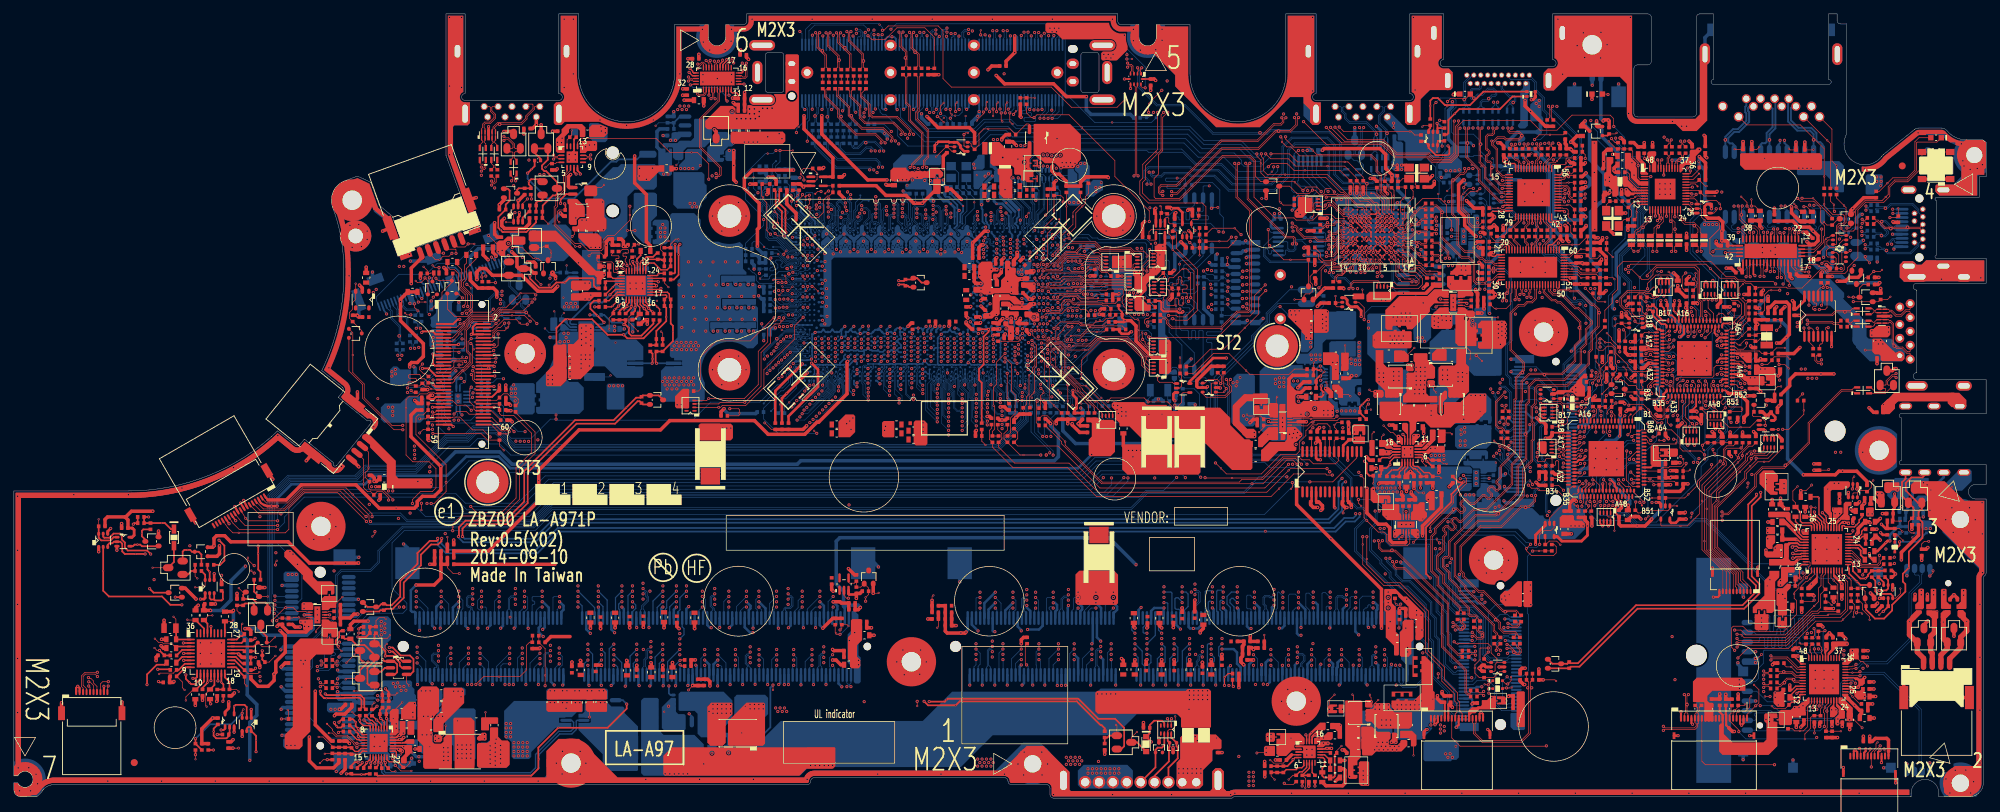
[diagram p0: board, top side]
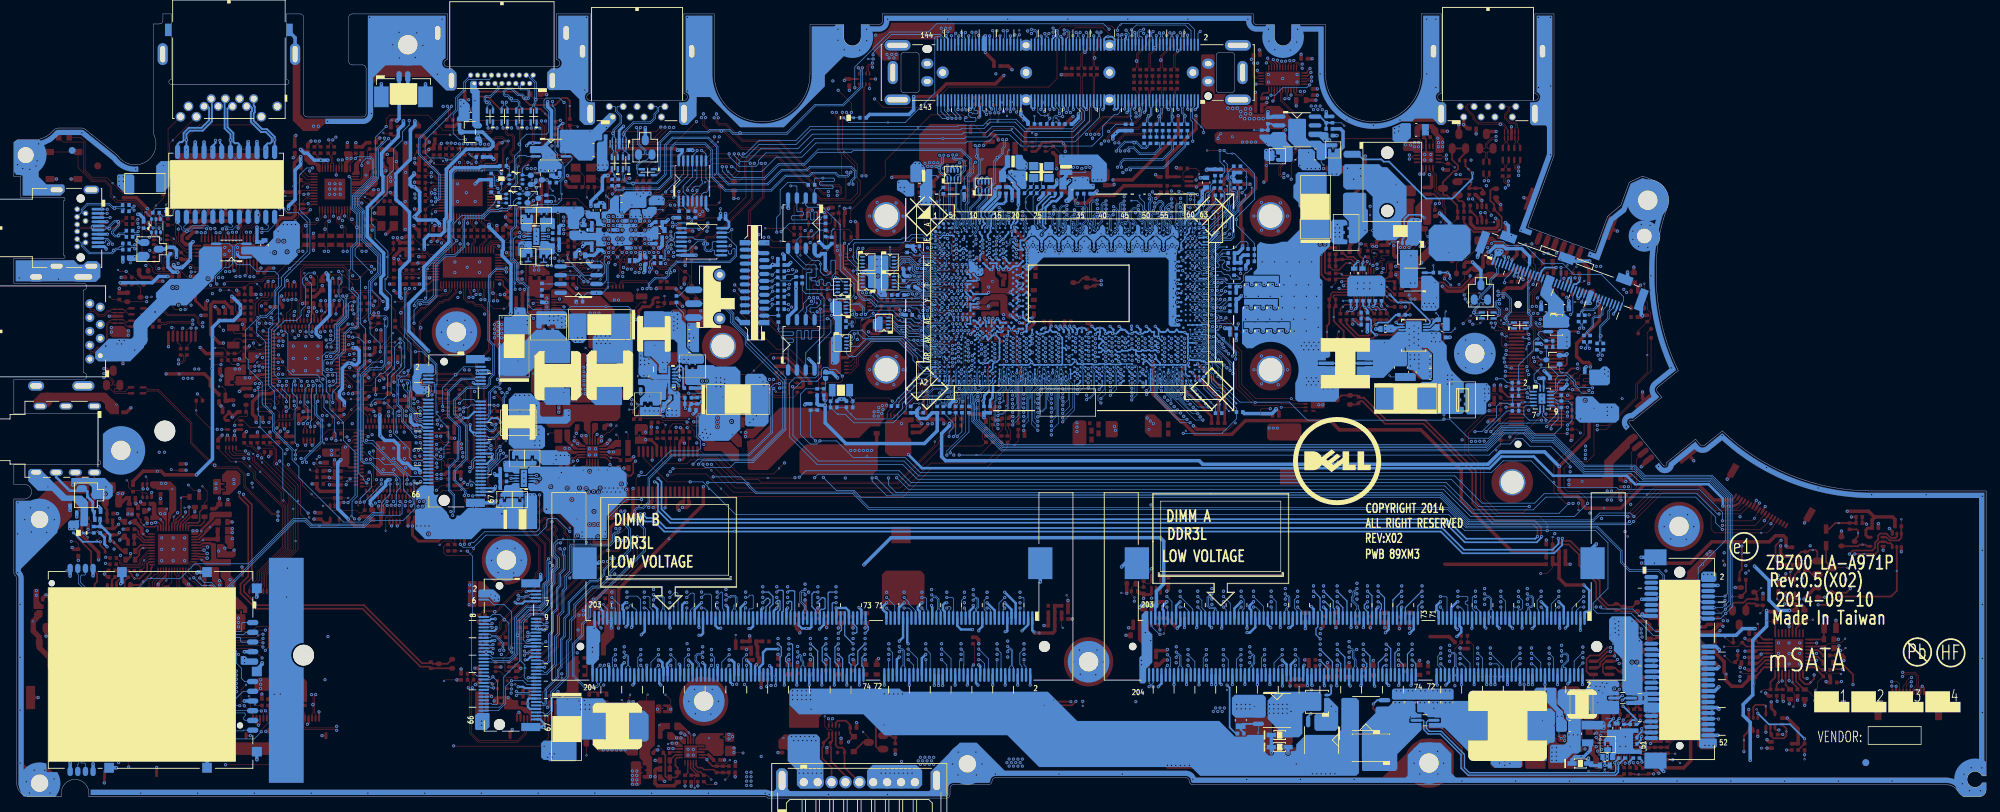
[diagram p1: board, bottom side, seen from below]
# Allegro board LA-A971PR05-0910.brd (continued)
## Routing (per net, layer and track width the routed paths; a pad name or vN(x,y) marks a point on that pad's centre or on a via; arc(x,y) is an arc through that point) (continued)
I_BATT: length 305.5
  TOP w0.102: v1(255.49,61.91) 254.93,62.47 v2(254.09,62.47) 253.99,62.57 RE64.2
  TOP w0.254: v2(46.79,10.93) 47.23,11.38 PR718.1
  IN1 w0.084: v2(54.53,44.26) 53.36,43.09 53.36,42.45 52.84,41.92 52.84,40.41 50.88,38.44 50.88,37.67 48.56,35.35 48.56,13.3 46.79,11.53 v2(46.79,10.93)
  IN3 w0.122: v2(54.53,44.26) 55.15,44.88 55.15,46.91 55.47,47.23 55.47,51.7 56.44,52.67 56.44,54.55 56.44,54.56 56.44,57.36 55.68,58.13 55.68,58.49 54.88,59.28 53.65,59.28 52.72,60.21 52.72,70.25 58.26,75.79 65.49,75.79 70.93,81.22 73.07,81.22 75.07,83.22 78.73,83.22 80.75,85.25 83.37,85.25 85.02,86.9 92.23,86.9 93.47,88.14 97.55,88.14 100.54,91.13 109.77,91.13 111.72,93.07 122.2,93.07 122.8,93.67 125.35,93.67 125.81,93.21 125.96,93.07 131.14,93.07 132,93.93 141.4,93.93 141.4,93.93 141.82,93.93 143.01,93.93 143.3,94.22 143.54,94.46 151.69,94.46 152.2,93.95 164.31,93.95 170.16,88.11 183.41,88.11 184.72,89.42 192.65,89.42 193.56,90.32 197.1,90.32 199.72,87.7 201.7,87.7 202.04,87.35 206.97,87.35 207.79,86.52 209.35,86.52 210.13,85.74 213.23,85.74 214.37,84.6 216.61,84.6 217.28,83.93 221.78,83.93 222.75,82.96 223.49,82.96 225.33,81.11 225.67,81.11 228.07,78.71 232.49,78.71 233.05,79.27 233.96,79.27 234.21,79.02 234.21,77.53 234.44,77.3 234.44,72.62 235.8,71.26 235.8,69.33 237.03,68.1 245.92,68.1 246.74,67.28 246.74,61.74 247.42,61.06 249.29,61.06 249.63,61.41 253.32,61.41 254.09,62.18 v2(254.09,62.47)
I_SYS: length 297.6
  TOP w0.102: v2(248.13,63.47) 247.99,63.6 UE2.A57
  TOP w0.254: v2(46.14,10.88) 46.14,10.7 46.47,10.38 v1(46.47,10.32) 46.62,10.17 47.1,10.17 PR720.1
  IN1 w0.084: v2(53.92,44.26) 53.15,43.49 53.15,42.53 52.63,42.01 52.63,40.53 50.62,38.52 50.62,37.71 48.35,35.44 48.35,13.39 46.14,11.18 v2(46.14,10.88)
  IN3 w0.122: v2(248.13,63.47) 247.52,63.47 247,63.98 247,67.38 246.03,68.35 237.13,68.35 236.05,69.43 236.05,71.36 235.32,72.1 235.32,72.94 235.59,73.2 235.59,76.53 234.46,77.65 234.46,79.16 234.1,79.52 232.94,79.52 232.38,78.96 228.17,78.96 225.77,81.36 225.43,81.36 223.59,83.2 222.86,83.2 221.88,84.18 217.38,84.18 215.87,85.7 213.62,85.7 213.33,85.99 210.27,85.99 209.48,86.77 207.9,86.77 207.07,87.6 202.15,87.6 201.8,87.95 199.83,87.95 198.8,88.97 198.8,89.87 198.44,90.24 197.83,90.24 197.5,90.57 193.45,90.57 192.55,89.67 184.62,89.67 183.31,88.37 170.25,88.37 164.41,94.21 152.32,94.21 151.82,94.71 143.43,94.71 143.05,94.32 142.9,94.18 141.93,94.18 132.11,94.18 131.9,94.18 131.04,93.32 126.06,93.32 125.45,93.92 122.69,93.92 122.1,93.32 111.61,93.32 109.67,91.38 100.44,91.38 97.45,88.39 93.36,88.39 92.13,87.16 84.93,87.16 83.32,85.56 80.62,85.56 78.57,83.51 75,83.51 72.96,81.47 70.82,81.47 65.39,76.04 58.15,76.04 52.47,70.36 52.47,60.01 53.45,59.03 54.76,59.03 55.42,58.37 55.42,58.03 56.19,57.26 56.19,54.66 55.22,53.7 55.22,47.33 54.9,47.01 54.9,45.24 v2(53.92,44.26)
ILIM_SEL: length 2.6
  TOP w0.102: v1(76.49,90.88) 76.58,90.88 77.13,91.43 RI13.1 77.97,91.43 78.16,91.62 UI3.4
ILMT_1.05V: length 3.8
  TOP w0.102: 188.09,60.87 188.09,60.88 v1(188.65,61.44)
  TOP w0.254: 188.09,60.87 v2(188.09,60.81) 187.93,60.81 187.45,60.32 PR308.1 PR306.2
  BOTTOM w0.254: PU300.3 188.18,60.9 v2(188.09,60.81)
IMON: length 3.7
  TOP w0.203: PU500.13 89.75,71.05 90.09,70.71 PC500.2
  TOP w0.254: PR501.1 89.24,68.91 PC500.2
INT_SPK_L+: length 25.8
  TOP w0.203: UA1.42 256.9,36.05 256.65,36.3 256.15,36.3 v4(256.02,36.17)
  IN4 w0.762: 274.47,28.32 272.03,25.88 267.83,25.88 267.2,26.52 267.2,27.87 264.34,30.72 264.34,31.47 262.94,32.87 259.61,32.87 258.58,33.9 258.58,35.7 258.23,36.05
  vias: v2(274.57,29.93) v2(274.57,29.3)
INT_SPK_L-: length 27.9
  TOP w0.203: v4(256.53,35.72) 256.6,35.65 UA1.43
  IN4 w0.762: 276.25,27.83 273.29,24.87 267.32,24.87 266.18,26.01 266.18,27.45 263.87,29.76 263.17,29.76 261.07,31.85 259.19,31.85 257.29,33.75 257.29,35.47
  vias: v2(276.35,29.91) v2(276.35,29.3)
INT_SPK_R+: length 34.4
  TOP w0.203: v4(256.08,34.58) 256.34,34.58 256.53,34.77 257.27,34.77 257.35,34.85 UA1.45
  IN4 w0.762: 277.83,28.31 277.83,24.91 276.03,23.11 267.41,23.11 264.43,26.09 262.12,26.09 260.43,27.79 258.82,27.79 256.4,30.2 256.4,32.78 255.77,33.41 255.77,33.88
  vias: v2(277.83,29.92) v2(277.81,29.3)
INT_SPK_R-: length 40.3
  TOP w0.203: UA1.44 257.29,35.25 257.19,35.15 256.18,35.15 v4(256.08,35.25)
  IN4 w0.762: 280.75,28.33 280.75,26.39 276.45,22.1 266.99,22.1 264.01,25.08 261.7,25.08 260.01,26.77 258.4,26.77 255.38,29.78 255.38,32.36 254.69,33.06 254.69,34.77 255.26,35.34
  vias: v2(280.66,29.9) v2(280.67,29.23)
INT_SPKR_L+: length 7.7
  TOP w0.762: JSPK1.1 274.9,20.15 273.99,21.06 DA6.2 272.86,23.55 v1(272.86,25.42) 273.43,26
INT_SPKR_L-: length 6.6
  TOP w0.762: JSPK1.2 276.15,20.88 275.92,21.11 DA6.3 275.92,23.34 276.45,23.88 276.45,25.74
  vias: v1(276.85,26.9)
INT_SPKR_R+: length 7.3
  TOP w0.762: JSPK1.3 277.4,20.63 278.31,21.54 DA7.2 277.75,22.97 v1(277.75,25.36) 277.75,26.07
INT_SPKR_R-: length 7.8
  TOP w0.762: 280.58,26 v1(281.11,25.46) 281.11,24.08 280.24,23.2 DA7.3 280.24,21.69 278.65,20.1 JSPK1.4
INTRUDER#: length 10.8
  BOTTOM w0.076: UC1.AU6 148.26,61.75 148.26,61.28 148.16,61.19 148.16,60.27 148.16,60.27 148.16,60.03 148.16,59.32 148.88,58.6 149.91,58.6 150.52,57.99 152.18,57.99 153.32,56.85 v1(153.64,56.85) 153.82,56.85
  BOTTOM w0.102: 153.82,56.85 154.38,56.85 RC9.2
IO_LDOSEL: length 7.3
  TOP w0.102: v1(257.81,8.5) 257.81,9.25 258.64,10.07 258.64,11.58 258.92,11.87 RR6.2 RR8.1 260.07,12.85 260.27,13.05 260.27,13.46 260.38,13.56 UR1.18
IRQ_SERIRQ: length 127.2
  TOP w0.102: v2(228.32,66.17) 228.56,66.17 v1(229.07,65.66) 229.81,65.66 230.59,64.87 230.59,64.13 232.34,62.39 232.34,62.11 232.97,61.48 234.98,61.48 235.1,61.6 UE2.A28 ; UE1.B21 224.96,51.4 225.22,51.66 225.63,51.66 v2(226.04,52.08) ; v2(161.18,72.82) 161.18,72.01 161.01,71.84 RPC15.1
  IN2 w0.081: v2(148.88,74.99) 149.56,75.67 150.38,75.67 150.69,75.36 150.69,73.49 151.74,72.44 153.1,72.44 153.62,71.92 153.82,71.92
  IN2 w0.122: v2(161.18,72.82) 160.5,72.14 156.74,72.14 156.52,71.92 153.82,71.92
  IN3 w0.122: v2(161.18,72.82) 161.18,72.96 161.45,73.24 162.44,73.24 162.67,73 165.09,73 165.57,73.48 167.29,73.48 171.54,77.73 175.47,77.73 176.76,76.44 182.86,76.44 186.95,72.35 188.38,72.35 188.51,72.22 204.12,72.22 205.13,73.23 208.47,73.23 209.33,72.37 212.19,72.37 212.91,73.1 215.21,73.1 216.67,74.56 221.92,74.56 223.4,73.09 225.1,73.09 225.69,72.5 228.34,72.5 228.58,72.26 228.58,66.6 228.32,66.34 v2(228.32,66.17)
  BOTTOM w0.081: UC1.T4 149.29,74.21 148.88,74.63 v2(148.88,74.99)
  BOTTOM w0.102: v2(228.32,66.17) 228.24,66.17 227.64,65.57 227.64,62.03 228.76,60.9 228.76,56.62 228.06,55.92 228.06,54.25 226.62,52.81 226.62,52.65 v2(226.04,52.08)
JTAG_CLK: length 42.4
  TOP w0.102: RPE7.2 252.4,50.02 252,49.61 v2(250.11,49.61) 249.57,49.06 249.57,48.67 245.11,44.21 v1(245.11,42.89) 244.54,42.32 244.54,35.87 248.03,32.38 248.03,30.8 248.5,30.33 JDEG1.4 ; UE2.B56 246.18,61.35 246.05,61.48 245.62,61.48 v2(245.19,61.06)
  IN4 w0.084: v2(245.19,61.06) 247.75,58.5 247.75,56.9 250.83,53.82 250.83,52.12 250.11,51.41 v2(250.11,49.61)
JTAG_RST#: length 16.4
  TOP w0.102: v2(243.49,60.1) 243.8,59.78 243.8,59.04 243.91,58.93 UE2.B47 ; v1(243.28,50.16) 243.07,50.38 v2(243.07,50.84) 243.44,51.21 CE30.1 RE65.1 244.79,51.19 JTAG1.1 245.93,51.21 RE63.2
  BOTTOM w0.102: v2(243.07,50.84) 243.43,51.2 243.43,56.06 243.13,56.36 243.13,57.69 243.8,58.37 243.8,59.78 v2(243.49,60.1)
JTAG_TDI: length 41.3
  TOP w0.102: RPE7.4 253.4,49.87 252.51,48.98 v2(250.79,48.98) 250.79,48.67 v1(249.94,47.82) 249.16,47.04 249.16,46.13 245,41.97 245,36.11 248.54,32.57 248.54,31.36 249.5,30.39 JDEG1.2 ; UE2.A51 248.37,60.6 249.16,59.81 v2(249.16,59.73)
  IN4 w0.084: v2(249.16,59.73) 249.98,58.91 249.98,55.56 251.51,54.04 251.51,49.69 v2(250.79,48.98)
JTAG_TDO: length 40.8
  TOP w0.102: RPE7.1 251.9,50.09 251.84,50.02 v2(250.56,50.02) 249.88,50.02 v1(249.46,49.59) 249.24,49.37 249.24,48.66 244.31,43.73 244.31,35.78 247.8,32.29 247.8,30.48 248,30.28 JDEG1.5 ; UE2.B55 246.33,60.85 246.11,61.07 v2(245.83,61.07)
  IN4 w0.084: v2(250.56,50.02) 250.56,51.56 251.09,52.08 251.09,53.86 247.96,56.99 247.96,58.94 v2(245.83,61.07)
JTAG_TMS: length 42.8
  TOP w0.102: UE2.A53 247.85,61.6 247.88,61.58 v2(248.58,61.58) ; JDEG1.3 249,30.28 248.25,31.03 248.25,32.48 244.77,35.97 244.77,42.06 245.44,42.73 245.44,44.02 v1(248.44,47.02) 250.09,48.67 v2(250.09,48.93) 250.54,49.38 252.34,49.38 252.9,49.94 RPE7.3
  IN4 w0.084: v2(250.09,48.93) 251.3,50.14 251.3,53.95 248.17,57.08 248.17,61.17 v2(248.58,61.58)
KB_DET#: length 103.3
  TOP w0.102: v2(205.04,17.91) v1(205.04,17.33) ; JKBTP1.1 v2(203.98,10.54)
  IN1 w0.084: v2(203.98,10.54) 203.98,16.86 v2(205.04,17.91)
  IN2 w0.122: v2(154.34,65.99) 154.34,60.67 156.82,58.19 159.19,58.19 164.71,52.68 164.71,46.61 v2(164.22,46.13)
  IN4 w0.084: v2(164.22,46.13) 164.22,45.04 168.48,40.78 170.61,40.78 179.82,31.57 179.82,25.25 182.87,22.2 186.17,22.2 187.05,23.08 191.59,23.08 192.01,22.66 198.05,22.66 202.8,17.91 v2(205.04,17.91)
  BOTTOM w0.076: 153.82,65.34 153.67,65.19 153.08,65.19 152.13,64.24 151.56,64.24 151.35,64.02 151.03,64.02 150.86,63.86 150.43,63.86 150.24,63.67 150.24,63.29 149.94,62.99 UC1.AT3
  BOTTOM w0.102: RPC19.1 157.29,67.74 156.41,66.86 155.84,66.86 154.96,65.99 v2(154.34,65.99) 154.34,65.86 153.82,65.34
LAN_ACTLED_YEL#: length 10.5
  TOP w0.102: QL1.6 262.29,79.78 262.35,79.83 262.35,82.44 262.69,82.78 263.27,82.78 263.51,83.03 263.51,83.88 263.3,84.1 261.81,84.1 260.59,85.32 v1(260.59,85.57) RL14.1
LAN_ACTLED_YEL_R#: length 19.9
  TOP w0.102: JLOM1.10 249.45,97 257.16,97 260.59,93.57 v1(260.59,89.57) RL14.2
LAN_DISABLE#_R: length 62.1
  TOP w0.102: v1(229.58,94.64) 230.68,93.54 RL7.2 RL9.1 232.69,93.54 RL5.2 233.03,93.2 233.03,92.3 233.81,91.52 v2(233.81,91.15) 233.81,89.44 234.09,89.16 UL1.3 ; UE1.B53 v2(233.09,45.4)
  BOTTOM w0.102: v2(233.09,45.4) 233.54,45.85 233.54,46.09 234.25,46.8 234.25,61.56 233.29,62.52 233.29,67.64 233.99,68.34 233.99,74.98 235.12,76.11 235.12,79.27 234.38,80.01 234.38,84.24 235.14,85 235.14,86.82 232.33,89.63 232.33,91.89 232.62,92.17 233.23,92.17 233.81,91.58 v2(233.81,91.15)
LAN_SMBCLK: length 110.8
  TOP w0.102: RC30.1 165.37,69.3 165.74,69.3 166.14,68.9 166.14,68.47 166.72,67.89 173.76,67.89 176.04,70.17 177.64,70.17 177.9,70.43 177.9,84.57 175.92,86.55 175.92,91.28 v2(175.74,91.46) ; UL1.28 241.22,86.76 241.37,86.61 241.82,86.61 242.15,86.94 v2(242.15,86.99)
  IN1 w0.084: v2(242.15,86.99) 242.15,87.01 241.62,87.54 241.12,87.54 237.84,90.82 237.84,92.13 236.73,93.24 226.19,93.24 225.47,92.53 204.76,92.53 204.27,93.01 197.04,93.01 195.72,91.69 186.11,91.69 185.64,91.22 184.07,91.22 182.99,90.14 176.69,90.14 175.92,90.91 175.92,91.28 v2(175.74,91.46)
LAN_SMBDATA: length 109.2
  TOP w0.102: UL1.31 241.54,87.96 v2(241.62,88.03) ; RC32.1 165.37,69.07 165.64,69.07 165.91,68.8 165.91,68.37 166.62,67.67 173.86,67.67 176.14,69.95 177.73,69.95 178.13,70.34 178.13,84.66 176.15,86.64 176.15,91.28 v2(176.32,91.46)
  IN1 w0.084: v2(176.32,91.46) 176.13,91.27 176.13,90.99 176.77,90.35 182.91,90.35 183.98,91.43 185.55,91.43 186.02,91.9 195.63,91.9 196.95,93.22 204.36,93.22 204.85,92.74 225.38,92.74 226.1,93.45 236.82,93.45 238.05,92.22 238.05,90.91 240.92,88.03 v2(241.62,88.03)
LAN_TEST_EN: length 4.5
  TOP w0.102: v1(244.84,86.77) 243.31,86.77 RL12.1 242.52,87.55 241.42,87.55 241.41,87.56 UL1.30
LAN_TX0+: length 5.2
  TOP w0.089: UL1.13 235.49,84.21 235.55,84.16 235.55,83.71 v4(235.24,83.4) 233.8,81.97 233.63,81.97 233.27,81.61 233.27,81.18 233.1,81.01 LL21.1
LAN_TX0+L: length 21.4
  TOP w0.089: v2(233.2,78.79) 232.84,79.15 LL21.2 ; v2(249.35,75.13) 249.49,75.26 249.49,76.37 249.39,76.46 UL4.2
  IN1 w0.084: v2(249.35,75.13) 249.45,75.23 249.45,75.34 249.3,75.49 247.03,75.49 246.96,75.42 241.48,75.42 240.79,76.11 237.82,76.11 237.37,76.56 234.97,76.56 233.38,78.16 233.38,78.62 v2(233.2,78.79)
LAN_TX0-: length 5.3
  TOP w0.089: UL1.14 235.89,84.19 235.86,84.16 235.86,83.58 v4(234.52,82.23) 233.93,81.65 233.76,81.65 233.59,81.48 233.59,81.2 233.79,81.01 LL22.1
LAN_TX0-L: length 21.4
  TOP w0.089: v2(233.79,78.79) 234.2,79.2 LL22.2 ; UL4.3 249.89,76.46 249.8,76.37 249.8,75.26 v2(249.94,75.13)
  IN1 w0.084: v2(233.79,78.79) 233.76,78.76 233.76,78.31 235.13,76.94 237.53,76.94 237.98,76.49 240.95,76.49 241.64,75.81 246.8,75.81 246.87,75.87 249.46,75.87 249.83,75.5 249.83,75.23 v2(249.94,75.13)
LAN_TX1+: length 4.5
  TOP w0.089: UL1.17 237.09,84.18 237.13,84.14 v4(237.13,83.58) 237.13,83.2 236.09,82.16 236.09,81.38 235.72,81.01 LL23.1
LAN_TX1+L: length 21
  TOP w0.089: UL4.6 251.39,76.46 251.49,76.37 251.49,75.3 v2(251.35,75.17) ; v2(235.92,78.78) 235.92,79.37 LL23.2
  IN1 w0.084: v2(235.92,78.78) 236.06,78.64 236.06,78.18 236.66,77.57 237.99,77.57 238.47,77.09 241.24,77.09 241.93,76.4 245.95,76.4 246.32,76.77 249.4,76.77 250.49,75.68 251.27,75.68 251.45,75.5 251.45,75.27 v2(251.35,75.17)
LAN_TX1-: length 4.6
  TOP w0.089: 236.72,82.33 237.45,83.06 237.45,84.13 237.49,84.18 UL1.18 ; 236.72,82.33 v4(236.72,82.33) ; 236.72,82.33 236.41,82.02 236.41,81.32 236.72,81.01 LL24.1
LAN_TX1-L: length 21
  TOP w0.089: UL4.7 251.89,76.46 251.8,76.37 251.8,75.3 v2(251.94,75.17) ; v2(236.5,78.78) 236.5,79.32 LL24.2
  IN1 w0.084: v2(236.5,78.78) 236.44,78.71 236.44,78.34 236.82,77.95 238.14,77.95 238.63,77.47 241.4,77.47 242.09,76.78 245.79,76.78 246.16,77.15 249.56,77.15 250.65,76.06 251.43,76.06 251.83,75.66 251.83,75.27 v2(251.94,75.17)
LAN_TX2+: length 4.2
  TOP w0.089: UL1.20 238.29,84.07 238.33,84.03 238.33,83.3 v4(238.52,83.12) 238.8,82.84 238.8,81.52 LL25.1
LAN_TX2+L: length 18.8
  TOP w0.089: LL25.2 238.52,79.73 238.76,79.49 238.76,78.91 v2(238.63,78.78) ; v2(252.84,75.87) 252.97,76 252.97,76.48 252.89,76.56 UL4.9
  IN1 w0.084: v2(252.84,75.87) 252.94,75.97 252.94,76.13 252.41,76.66 250.89,76.66 249.81,77.74 245.91,77.74 245.55,77.38 242.34,77.38 241.65,78.07 239.08,78.07 238.75,78.4 238.75,78.65 v2(238.63,78.78)
LAN_TX2-: length 4.2
  TOP w0.089: UL1.21 238.69,84.07 238.65,84.03 238.65,83.42 239.12,82.96 v4(239.12,81.98) 239.12,81.54 LL26.1
LAN_TX2-L: length 18.9
  TOP w0.089: LL26.2 239.34,79.73 239.08,79.46 239.08,78.91 v2(239.21,78.78) ; UL4.10 253.39,76.56 253.29,76.45 253.29,76 v2(253.42,75.87)
  IN1 w0.084: v2(253.42,75.87) 253.32,75.97 253.32,76.29 252.57,77.04 251.05,77.04 249.97,78.12 245.75,78.12 245.39,77.76 242.49,77.76 241.81,78.45 239.24,78.45 239.13,78.55 239.13,78.69 v2(239.21,78.78)
LAN_TX3+: length 5.9
  TOP w0.089: LL27.1 242.42,81.53 242.42,81.96 v4(241.89,82.48) 241.73,82.65 240.52,82.65 239.53,83.64 239.53,84.03 239.49,84.07 UL1.23
LAN_TX3+L: length 18.5
  TOP w0.089: UL4.11 253.89,76.46 253.98,76.37 253.98,75.14 v2(253.85,75) ; v2(242.31,78.79) 242.44,78.92 242.44,79.5 242.21,79.73 LL27.2
  IN1 w0.084: v2(242.31,78.79) 242.74,78.36 243.61,78.36 244.42,79.18 245.14,79.18 245.32,79 246.57,79 246.85,78.71 250.24,78.71 251.32,77.63 252.81,77.63 254.01,76.43 254.01,75.62 253.86,75.47 253.86,75.01 v2(253.85,75)
LAN_TX3-: length 5.9
  TOP w0.089: LL28.1 242.74,81.55 242.74,82.09 241.86,82.97 240.65,82.97 v4(240.22,83.4) 239.85,83.77 239.85,84.03 239.89,84.07 UL1.24
LAN_TX3-L: length 18.4
  TOP w0.089: LL28.2 243.07,79.73 242.76,79.41 242.76,78.92 v2(242.89,78.79) ; UL4.12 254.39,76.46 254.3,76.36 254.3,75.13 v2(254.43,75)
  IN1 w0.084: v2(242.89,78.79) 242.94,78.74 243.45,78.74 244.27,79.56 245.3,79.56 245.48,79.38 246.73,79.38 247.01,79.1 250.4,79.1 251.48,78.02 252.97,78.02 254.4,76.59 254.4,75.47 254.24,75.31 254.24,75.19 v2(254.43,75)
LAN_WAKE#: length 154.9
  TOP w0.081: 153.82,57.5 152.82,58.5 152.82,59.04 v1(149.5,62.36) 149.21,62.65 149.21,64.26 v2(148.81,64.66)
  TOP w0.102: RC153.1 154.68,56.64 153.82,57.5 ; UE2.B27 238.03,62.85 v2(238.2,62.69) ; UL1.2 v2(235.64,89.56)
  IN1 w0.084: v2(148.81,64.66) 149.17,64.3 150.49,64.3 151,64.81 152.13,64.81 152.73,65.4 154.43,65.4 156.2,67.17 160.01,67.17 164.06,63.12 166.52,63.12 169.51,60.13 173.89,60.13 174.28,59.73 174.29,59.73 174.36,59.66 174.8,59.66 175.5,58.97 179.51,58.97 182.35,56.13 183.09,56.13 184.21,55.01 184.21,54.55 186.69,52.07 188.06,52.07 193.18,46.95 v2(193.6,46.95)
  IN4 w0.084: v2(193.6,46.95) 194.01,46.95 195.05,45.91 196.79,45.91 197.4,45.29 205.73,45.29 207.95,47.51 212.76,47.51 214.63,49.39 214.63,49.69 214.82,49.88 214.82,51.17 215.35,51.7 217.59,51.7 220.44,54.54 220.44,56.58 226.64,62.78 228.02,62.78 228.43,63.19 230,63.19 230.4,62.79 230.4,62.68 231.53,61.56 236.11,61.56 237.25,62.69 v2(238.2,62.69)
  BOTTOM w0.081: UC1.AN5 148.38,64.66 v2(148.81,64.66)
  BOTTOM w0.102: v2(238.2,62.69) 236.41,64.48 236.41,66.9 235.48,67.83 234.78,67.83 234.49,68.12 234.49,72.15 235.65,73.3 235.65,76.03 235.41,76.28 235.41,79.34 234.61,80.14 234.61,84.15 235.37,84.91 235.37,89.29 v2(235.64,89.56)
LANCLK_REQ#: length 121.4
  TOP w0.102: RL4.1 234.68,92.22 v2(234.75,92.16) 235.49,91.41 UL1.48
  IN3 w0.122: v2(232.42,75.77) 232.4,75.79 226.46,75.79 223.77,78.47 213.83,78.47 211.88,76.52 210.5,76.52 209.2,75.22 205.09,75.22 204.49,75.82 199.61,75.82 198,74.21 194.95,74.21 194.33,74.83 191.08,74.83 190.59,75.31 188.89,75.31 187.86,76.34 185.77,76.34 183.68,78.43 180.81,78.43 177.62,81.62 175.45,81.62 174.71,80.87 167.06,80.87 166.15,79.97 v2(164.33,79.97)
  BOTTOM w0.081: 152.67,69.83 151.59,69.83 151.32,69.56 UC1.AD1
  BOTTOM w0.102: v2(234.75,92.16) 234.51,92.4 232.52,92.4 232.11,91.99 232.11,89.54 234.91,86.73 234.91,85.1 234.15,84.34 234.15,79.73 234.79,79.1 234.79,78.13 v2(232.42,75.77) ; 152.67,69.83 153.38,69.83 153.6,70.05 153.6,70.3 153.93,70.63 154.6,70.63 154.76,70.78 159.88,70.78 160.78,71.69 161.64,71.69 162.47,72.52 162.47,74.41 ; 162.47,74.41 162.23,74.65 RPC6.6 ; 162.47,74.41 v1(164.31,76.25) 164.45,76.39 164.45,79.84 v2(164.33,79.97)
LCD_CBL_DET#: length 130.4
  TOP w0.102: v2(149.72,76.68) 149.72,76.76 151.55,78.59 152.96,78.59 153.59,79.22 154.91,79.22 v1(155.54,78.6) 156.17,78.6 156.77,78 RPC4.5
  IN2 w0.122: v2(149.72,76.68) 149.34,77.06 149.34,77.67 149.11,77.9 149.11,81.34 146.8,83.65 146.8,84.68 144.74,86.74 144.74,87.28 143,89.02 143,90.84 139.78,94.07 131.07,94.07 129.73,92.73 128.71,92.73 128.13,92.15 126.23,92.15 125.9,91.82 113.89,91.82 112.97,90.91 110.1,90.91 109.86,90.66 106.13,90.66 104.69,89.22 103.84,89.22 102.9,88.29 92.54,88.29 91.04,86.79 84.33,86.79 83.15,85.61 80.34,85.61 79.69,84.96 78.74,84.96 78.15,84.37 78.15,84.1 77.6,83.55 76.15,83.55 72.71,80.11 71.34,80.11 v2(71.17,79.93)
  BOTTOM w0.081: UC1.J3 149.66,77.49 149.66,76.74 v2(149.72,76.68)
  BOTTOM w0.102: v2(71.17,79.93) 70.93,80.17 69.52,80.17 68.95,79.6 66.28,79.6 63.74,77.06 60.95,77.06 59.36,75.48 55.42,75.48 52.18,72.24 52.18,71.73 JEDP1.40
LCD_TST: length 227.1
  TOP w0.102: v1(59.23,71.48) v2(58.22,71.48) ; UE1.A36 226.97,43.12 226.87,43.03 v2(226.87,42.73) 227.13,42.48 227.13,41.43 RE20.2
  IN1 w0.084: v2(55.36,40.3) 55.36,44.58 54.56,45.38 54.56,54.27 55.16,54.88 55.16,57.82 53.96,59.02 53.96,68.32 54.94,69.29 54.94,70.08 56.65,71.79 57.9,71.79 v2(58.22,71.48)
  IN3 w0.122: v2(55.36,40.3) 55.93,39.73 64.44,39.73 67.81,36.36 185.94,36.36 188.08,38.5 194.51,38.5 195.17,37.84 195.17,33.42 199.87,28.71 203.22,28.71 206.64,32.13 206.64,32.5 211.95,37.81 220.89,37.81 223.7,40.61 225.16,40.61 226.24,41.69 226.24,42.46 226.52,42.73 v2(226.87,42.73)
  BOTTOM w0.102: JEDP1.29 v2(58.22,71.48)
LCD_VCC_TEST_EN: length 222.2
  TOP w0.102: DV3.2 48.78,67.06 v1(48.78,63.84) 48.78,61.32 50.43,59.67 50.43,57.69 54.41,53.71 v2(55.97,53.71) ; v2(229.25,42.74) 228.97,43.02 UE1.A40
  IN1 w0.084: v2(57.04,41.07) 56.72,41.39 56.72,44.74 56.43,45.03 56.43,53.25 v2(55.97,53.71)
  IN3 w0.122: v2(57.04,41.07) 57.81,40.3 64.57,40.3 67.75,37.12 185.5,37.12 187.37,38.99 195.28,38.99 196.27,38.01 196.68,38.01 197.42,37.27 197.42,35.86 196.9,35.34 196.9,33.82 199.7,31.03 199.7,29.61 200.1,29.21 203.02,29.21 205.91,32.1 205.91,34.05 210.17,38.31 220.57,38.31 224.14,41.88 224.14,43.03 224.55,43.43 228.56,43.43 v2(229.25,42.74)
LED_10_GRN#: length 10.2
  TOP w0.102: v2(264.34,78.9) 264.05,78.61 QL2.6 ; RL19.1 261.48,86.02 v1(261.99,85.51) 261.99,84.63 v2(262.08,84.54)
  IN1 w0.084: v2(262.08,84.54) 262.38,84.54 263.45,83.48 263.45,79.79 v2(264.34,78.9)
LED_10_GRN_R#: length 11.9
  TOP w0.102: RL19.2 261.48,94.32 v1(261.03,94.77) JLOM1.11
LED_100_ORG#: length 8.3
  TOP w0.102: QL1.3 262.87,81.08 262.58,81.37 262.58,82.31 262.81,82.55 263.36,82.55 263.74,82.93 263.74,85.09 v1(263.45,85.38) 262.37,86.46 RL20.1
LED_100_ORG_R#: length 11.3
  TOP w0.102: RL20.2 v1(262.37,91.13) 261.71,91.8 261.71,96.39 JLOM1.13
LED_SATA_DIAG_OUT#: length 46.6
  TOP w0.102: UE1.A10 v2(228.47,55.13)
  IN3 w0.122: v2(228.47,55.13) 227.89,55.7 227.89,57.06 227.12,57.83 227.12,58.57 224.89,60.8 224.89,65.34 225.29,65.73 225.29,70.72 224.64,71.37 v2(224.64,72.03)
  BOTTOM w0.102: v2(224.64,72.03) 224.46,72.21 224.46,76.33 220.84,79.95 220.84,82.88 220.59,83.13 220.59,90.05 220.26,90.39 v1(216.55,90.39) 216.43,90.5 214.27,90.5 DZ4.1
LG_3V: length 6
  TOP w0.102: v2(204.33,59.41) 204.33,58.85 v1(204.74,58.44)
  IN1 w1.016: 201.85,53.06 201.85,55.41 203.63,57.19
  vias: v2(201.54,52.23) v2(202.17,52.23) v2(203.7,59.41)
LG_5V: length 12.2
  TOP w0.102: v2(199.31,52.11) 199.1,52.11 198.54,52.67 198.18,52.67 v1(197.17,53.68)
  IN1 w1.016: 200.97,61.44 200.71,61.19 200.71,57.31 198.93,55.54 198.93,52.87
  vias: v2(199.31,51.47) v2(200.65,62.39) v2(201.28,62.39)
LID_CL#: length 93.2
  TOP w0.102: UZ10.2 237.73,43.24 RE26.1 240.52,43.25 v1(241.05,43.78) 242.35,45.08 242.35,45.68 244.39,47.71 v2(244.39,48.04) ; JSH1.11 269.35,6.96 v2(269.23,7.09)
  IN1 w0.084: v2(269.23,7.09) 269.23,6.91 267.88,5.56 257.86,5.56 255.77,3.47 238.35,3.47 235.62,6.2 235.62,19.35 243.5,27.22 243.5,47 244.39,47.89 v2(244.39,48.04)
LID_CL_SIO#: length 8.3
  TOP w0.102: v2(236.06,45.16) 236.07,45.16 CE8.1 RE25.2 RE26.2 v1(235.77,43.25) ; UE1.B54 232.89,45.9 v2(232.85,45.94)
  IN4 w0.084: v2(236.06,45.16) 236.06,45.34 235.83,45.57 233.6,45.57 233.24,45.94 v2(232.85,45.94)
LOM_ACTLED_YEL#: length 29.3
  TOP w0.102: v2(241.54,85.66) 241.24,85.96 UL1.26 ; UL4.15 255.89,76.55 256.51,75.94 257.32,75.94 257.43,75.83 v1(257.81,75.83) 258.34,75.83 v2(258.37,75.81)
  IN3 w0.122: v2(241.54,85.66) 243.4,83.8 245.9,83.8 246.92,82.78 257.01,82.78 258.37,81.41 258.37,80.56 258.56,80.37 258.56,79.87 257.71,79.02 257.71,76.47 v2(258.37,75.81)
LOM_SPD10LED_GRN#: length 16
  TOP w0.102: UL4.42 244.57,78.1 244.13,78.54 244.13,80.63 245.53,82.03 245.53,82.84 245.26,83.11 243.54,83.11 v1(243.4,83.25) 242.94,83.71 242.94,84.77 242.77,84.94 UL2.2 241.68,84.94 241.07,85.56 UL1.25
LOM_SPD100LED_ORG#: length 30.1
  TOP w0.102: UL1.27 241.96,86.36 242.29,86.03 UL2.1 243.09,85.59 243.6,86.1 245.07,86.1 v1(245.52,85.65) 245.65,85.53 v2(245.65,84.92) ; v2(258.5,76.45) 258.16,76.45 257.92,76.21 256.65,76.21 256.39,76.47 UL4.16
  IN3 w0.122: v2(245.65,84.92) 245.65,84.4 246.98,83.07 257.22,83.07 258.67,81.62 258.67,80.64 258.92,80.39 258.92,79.71 257.96,78.75 257.96,76.99 v2(258.5,76.45)
LP_CTL: length 6.9
  TOP w0.102: UV8.B2 199.59,77.96 200.01,77.96 200.26,77.71 200.26,76.88 200.88,76.26 v1(201.22,76.26) 202.06,76.26 203.38,74.94 RV79.1 RV516.1
LPC_LAD0: length 298.2
  TOP w0.076: v2(145.13,57.33) 144.64,57.33 v1(144.49,57.17)
  TOP w0.102: v2(223,47.7) 223.04,47.65 UE1.A27 ; UE2.A30 236.28,60.6 235.15,59.47 235.15,59.19 235.76,58.57 v2(235.76,58.29) ; JLPDE1.3 9.96,15.84 9.74,16.05 9.74,17.63 10.23,18.12 v2(12.01,18.12)
  IN1 w0.084: v2(235.76,58.29) 235.73,58.29 234.8,57.35 234.8,54.82 234.05,54.08 234.05,51.47 233.45,50.87 231.86,50.87 230.81,49.82 227.67,49.82 226.49,48.64 224.78,48.64 223.84,47.7 v2(223,47.7) 222.59,47.7 221.61,46.71 221.61,44.4 216.19,38.98 209.69,38.98 205.83,35.12 194.91,35.12 188.93,41.1 188.93,43.75 185.91,46.77 183,46.77 177.94,51.83 177.94,52.27 176.13,54.08 159.16,54.08 157.32,55.92 154.43,55.92 153.78,56.57 145.88,56.57 v2(145.13,57.33)
  IN4 w0.084: v2(37.48,26.61) 34.45,26.61 31.23,23.39 16.61,23.39 12.01,18.8 v2(12.01,18.12)
  BOTTOM w0.076: UC1.AU14 143.71,61.81 143.71,60.79 143.66,60.74 143.66,59.82 143.83,59.65 143.83,59.05 144.58,58.3 144.58,57.87 v2(145.13,57.33)
  BOTTOM w0.102: v2(145.13,57.33) 144.96,57.16 144.96,54.54 141.37,50.95 72.16,50.95 69.71,53.4 66.2,53.4 65.01,52.22 62.04,52.22 57.8,47.98 50.57,47.98 49.11,46.52 39.43,46.52 36.56,43.65 36.56,27.53 v2(37.48,26.61) 38.25,25.85 JMINI3.16
LPC_LAD1: length 297.7
  TOP w0.102: v2(12.03,17.53) 11.68,17.87 10.3,17.87 9.97,17.54 9.97,16.26 10.46,15.77 JLPDE1.4 ; UE2.B32 237.65,60.35 v2(237.92,60.08) ; UE1.A26 223.18,48.15 v2(223.05,48.28)
  IN1 w0.084: v2(237.92,60.08) 236.56,58.72 235.04,58.72 234.59,58.27 234.59,54.99 233.79,54.2 233.79,51.54 233.38,51.12 230.88,51.12 229.78,50.03 227.58,50.03 226.4,48.85 224.7,48.85 224.12,48.28 v2(223.05,48.28) 222.9,48.13 222.73,48.13 221.4,46.8 221.4,44.49 218.56,41.65 216.94,41.65 214.49,39.19 209.6,39.19 205.74,35.33 195,35.33 189.14,41.19 189.14,43.85 186.01,46.98 183.14,46.98 178.15,51.97 178.15,52.36 176.22,54.29 159.25,54.29 157.41,56.13 154.52,56.13 153.87,56.78 146.24,56.78 v2(145.14,57.88)
  IN4 w0.084: v2(37.52,27.22) 34.76,27.22 31.14,23.6 16.52,23.6 11.61,18.69 11.61,17.94 v2(12.03,17.53)
  BOTTOM w0.076: UC1.AW12 144,60.8 143.82,60.62 143.82,60.04 144,59.85 144,59.31 144.75,58.56 144.75,58.48 144.77,58.46 144.77,58.25 v2(145.14,57.88)
  BOTTOM w0.102: JMINI3.14 38.09,26.65 v2(37.52,27.22) 36.79,27.95 36.79,43.55 39.53,46.29 49.21,46.29 50.67,47.75 57.9,47.75 62.14,51.99 65.11,51.99 66.29,53.17 69.61,53.17 72.06,50.72 141.47,50.72 145.31,54.57 v1(145.31,56.03) 145.31,56.99 145.5,57.18 145.5,57.51 v2(145.14,57.88)
LPC_LAD2: length 292.1
  TOP w0.102: v2(225.48,49.29) 225.26,49.29 224.87,48.9 UE1.B26 ; v2(10.77,16.15) 10.96,15.97 JLPDE1.5 ; v2(235.61,59.3) 235.61,59.56 236.16,60.1 UE2.A31
  IN1 w0.084: v2(145.16,58.42) 145.8,57.78 148.22,57.78 149.01,56.99 153.96,56.99 154.57,56.38 157.45,56.38 159.33,54.51 176.3,54.51 177.64,53.17 178.63,53.17 179.13,52.67 179.13,51.29 183.23,47.19 186.09,47.19 189.35,43.93 189.35,41.28 195.08,35.54 205.65,35.54 209.52,39.4 214.36,39.4 216.85,41.89 218.5,41.89 221.19,44.58 221.19,46.89 222.54,48.24 222.54,48.43 222.96,48.84 223.3,48.84 223.74,49.29 v2(225.48,49.29) 225.88,49.69 226.51,49.69 226.75,49.93 226.75,50.08 227.7,51.03 230.43,51.03 230.75,51.35 231.32,51.35 231.83,51.85 231.83,53.4 234.37,55.95 234.37,58.35 235.32,59.3 v2(235.61,59.3)
  IN4 w0.084: v2(10.77,16.15) 10.77,16.17 11.39,16.79 11.39,18.77 16.44,23.81 31.05,23.81 35.07,27.83 v2(37.56,27.83)
  BOTTOM w0.076: v2(145.16,58.42) 145.12,58.42 144.26,59.28 144.26,60.01 UC1.AY12
  BOTTOM w0.102: v2(145.16,58.42) 145.71,57.88 145.71,57.07 145.62,56.98 145.62,56.75 145.62,54.55 141.56,50.49 71.97,50.49 69.52,52.95 66.39,52.95 65.2,51.76 62.23,51.76 57.88,47.41 50.65,47.41 49.3,46.06 39.62,46.06 37.02,43.46 37.02,28.37 v2(37.56,27.83) 37.94,27.45 JMINI3.12
LPC_LAD3: length 300.8
  TOP w0.076: v2(145.53,59.1) v1(145.53,59.66)
  TOP w0.102: v2(226.3,50.11) 225.88,49.69 225.2,49.69 224.9,49.4 UE1.B25 ; v2(10.77,16.76) 10.92,16.76 11.46,16.23 JLPDE1.6 ; UE2.B33 237.54,59.85 237.8,59.6 238.02,59.6 238.24,59.82 238.31,59.82 v2(238.52,60.04)
  IN1 w0.084: v2(238.52,60.04) 238.52,60.1 238.12,60.5 237.76,60.5 236.95,59.69 235.42,59.69 234.16,58.44 234.16,56.04 231.62,53.49 231.62,51.94 231.26,51.59 230.59,51.59 230.24,51.24 227.43,51.24 v2(226.3,50.11) 225.89,50.52 224.67,50.52 223.21,49.06 222.87,49.06 222.33,48.51 222.33,48.33 220.98,46.98 220.98,44.66 218.45,42.14 216.76,42.14 214.24,39.61 209.43,39.61 206.15,36.34 204.37,36.34 204.2,36.17 194.76,36.17 189.56,41.36 189.56,44.02 186.18,47.4 183.31,47.4 179.34,51.38 179.34,52.75 178.72,53.38 177.73,53.38 176.39,54.72 161.58,54.72 159.28,57.01 158.13,57.01 157.71,56.59 154.65,56.59 154.01,57.23 149.17,57.23 148.2,58.2 146.42,58.2 v2(145.53,59.1)
  IN4 w0.084: v2(37.58,28.5) 35.44,28.5 30.97,24.03 16.35,24.03 11.15,18.83 11.15,17.14 v2(10.77,16.76)
  BOTTOM w0.081: UC1.AW11 144.87,60.6 145.17,60.31 145.17,59.71 145.53,59.34 v2(145.53,59.1)
  BOTTOM w0.102: v2(37.58,28.5) 37.83,28.25 JMINI3.10 40.96,28.25 41.45,28.74 41.45,33.18 37.48,37.16 37.48,43.27 39.81,45.6 49.92,45.6 51.14,46.82 57.94,46.82 62.42,51.31 65.39,51.31 66.57,52.49 69.33,52.49 71.78,50.04 141.75,50.04 146,54.29 146,56.75 146.19,56.94 146.19,58.19 145.53,58.84 v2(145.53,59.1)
LPC_LDRQ1#: length 2.7
  TOP w0.102: UE1.A22 223.46,50.15 223.16,49.86 v1(222.72,49.86) 222.52,49.66 221.73,49.66 221.62,49.77 RPE8.1
LPC_LFRAME#: length 298.7
  TOP w0.076: v1(144.13,61.73) 144.48,61.38 v2(144.48,61.18)
  TOP w0.102: v2(223.03,50.3) 223.38,50.65 UE1.A21 ; UE2.B31 237.64,60.85 237.74,60.95 v2(238.03,60.95) ; JLPDE1.7 11.96,16.1 11.44,16.61 11.44,16.89 11.09,17.25 10.86,17.25 v2(10.73,17.37)
  IN1 w0.084: v2(144.48,61.18) 144.48,60.96 146.93,58.52 148.13,58.52 149.21,57.44 154.1,57.44 154.74,56.8 157.62,56.8 158.04,57.22 159.98,57.22 162.28,54.93 176.48,54.93 177.81,53.59 178.8,53.59 179.55,52.84 179.55,51.46 183.4,47.61 186.27,47.61 189.77,44.11 189.77,41.45 194.85,36.38 204.1,36.38 205.67,37.94 207.45,37.94 209.34,39.83 214.11,39.83 216.66,42.38 218.39,42.38 220.77,44.75 220.77,47.06 222.05,48.34 222.05,49.5 222.19,49.65 222.68,49.65 223.03,50 v2(223.03,50.3) 223.5,50.77 226.43,50.77 227.12,51.46 230.09,51.46 230.51,51.88 230.51,52.68 233.95,56.12 233.95,58.53 235.33,59.9 236.87,59.9 237.91,60.95 v2(238.03,60.95)
  IN4 w0.084: v2(37.58,29.11) 35.75,29.11 30.88,24.24 16.26,24.24 10.73,18.71 v2(10.73,17.37)
  BOTTOM w0.076: v2(144.48,61.18) 144.48,59.76 144.45,59.73 144.45,59.35
  BOTTOM w0.081: UC1.AV12 144.21,61.45 v2(144.48,61.18)
  BOTTOM w0.102: 144.45,59.35 144.96,58.84 145.27,58.84 145.96,58.14 145.96,56.98 145.81,56.83 145.81,54.42 141.66,50.27 71.87,50.27 69.42,52.72 66.48,52.72 65.3,51.54 62.33,51.54 57.85,47.05 50.62,47.05 49.4,45.83 39.72,45.83 37.25,43.36 37.25,29.44 v2(37.58,29.11) 37.64,29.05 JMINI3.8
M_CLK_DDR0: length 76.4
  IN4 w0.091: v2(129.49,58.07) 129.91,57.65 129.91,55.71 128.28,54.09 128.28,48.44 122.34,42.5 122.02,42.5 121.5,43.02 121.37,43.02 121.15,42.79 121.15,42.66 121.67,42.15 121.67,41.82 121.39,41.55 121.07,41.55 120.79,41.83 120.61,41.83 120.44,41.65 120.44,41.47 120.72,41.2 120.72,40.87 120.44,40.6 120.12,40.6 119.6,41.12 119.47,41.12 119.25,40.9 119.25,40.77 119.76,40.26 119.76,39.94 119.48,39.66 119.16,39.66 118.65,40.17 118.52,40.17 111.4,33.04 94.3,33.04 93.84,32.58 93.56,32.58 93.15,32.98 92.97,32.98 92.8,32.81 92.8,32.63 93.21,32.22 93.21,31.95 92.89,31.63 92.61,31.63 92.21,32.03 92.03,32.03 91.85,31.86 91.85,31.68 92.26,31.27 92.26,31 91.81,30.55 91.81,30.38 92.17,30.01 92.17,28.84 91.94,28.61 91.17,28.61 90.94,28.84 90.94,29.74 90.87,29.81 90.8,29.81 90.57,29.58 v2(90.57,29.44)
  BOTTOM w0.081: v2(129.49,58.07) 129.49,57.91 129.35,57.76 128.99,57.76 128.53,58.23 128.53,61.16 UC1.AV37
  BOTTOM w0.102: JDIMM1.101 90.2,27.09 90.36,27.25 90.36,27.72 91.15,28.5 91.15,28.89 90.95,29.09 90.95,29.61 90.85,29.71 90.68,29.71 90.57,29.6 v2(90.57,29.44)
M_CLK_DDR1: length 74.8
  IN4 w0.091: v2(129.25,59.82) 129.25,60.04 129.32,60.11 129.54,60.11 129.91,59.74 129.91,58.07 130.1,57.88 130.1,55.41 128.78,54.09 128.78,48.23 119.7,39.15 118.21,39.15 111.6,32.54 94.51,32.54 92.72,30.75 92.72,28.49 92.34,28.12 90.8,28.12 90.57,27.89 90.57,27.5 90.8,27.27 92.14,27.27 92.26,27.15 92.26,21.62 92.14,21.49 92.01,21.49 v2(91.7,21.8)
  BOTTOM w0.081: UC1.AY36 129.57,60.15 v2(129.25,59.82)
  BOTTOM w0.102: JDIMM1.102 90.5,18.8 90.69,18.99 90.69,19.97 90.99,20.27 90.99,21.29 91.23,21.52 91.42,21.52 v2(91.7,21.8)
M_CLK_DDR2: length 86.8
  IN1 w0.091: v2(128.22,64.24) 128,64.45 127.83,64.45 127.75,64.37 127.75,62.52 127.24,62.02 127.24,58.52 128.02,57.74 128.02,56.43 127.83,56.23 127.38,56.23 127.29,56.14 127.29,55.83 127.38,55.74 127.83,55.74 128.02,55.54 128.02,55.09 127.83,54.89 127.43,54.89 127.31,54.77 127.31,47.4 139.83,34.87 160.62,34.87 160.81,34.68 160.81,34.31 160.94,34.18 161.18,34.18 161.31,34.31 161.31,34.68 161.5,34.87 161.96,34.87 162.15,34.68 162.15,34.01 162.28,33.88 162.52,33.88 162.65,34.01 162.65,34.68 162.84,34.87 163.3,34.87 163.49,34.68 163.49,34.01 163.62,33.88 163.86,33.88 163.99,34.01 163.99,34.64 164.22,34.87 164.61,34.87 164.83,34.64 164.83,34.01 164.96,33.88 165.21,33.88 165.33,34.01 165.33,34.64 165.56,34.87 165.95,34.87 166.18,34.64 166.18,34.01 166.3,33.88 167.05,33.88 167.64,33.29 167.75,33.29 168.2,33.74 168.52,33.74 168.83,33.44 168.83,33.11 168.37,32.66 168.37,32.48 168.54,32.31 168.72,32.31 169.18,32.76 169.5,32.76 169.77,32.49 169.77,32.17 169.32,31.71 169.32,31.53 169.49,31.36 169.67,31.36 169.85,31.53 170.12,31.53 170.61,31.04 170.61,29.86 170.42,29.67 170.21,29.67 170.01,29.47 v2(170.01,29.31)
  BOTTOM w0.081: UC1.AN38 128.54,64.56 v2(128.22,64.24)
  BOTTOM w0.102: v2(170.01,29.31) 170.01,29.52 170.17,29.68 170.44,29.68 170.55,29.57 170.55,28.36 169.89,27.71 169.89,27.19 169.7,27 JDIMM2.101
M_CLK_DDR3: length 87.8
  IN1 w0.091: v2(171.08,21.09) 171.08,20.84 170.99,20.76 170.79,20.76 170.67,20.89 170.67,21.26 170.49,21.44 170.49,22.21 170.61,22.34 171.72,22.34 171.94,22.56 171.94,23.03 171.69,23.28 170.49,23.28 170.36,23.41 170.36,24.82 170.13,25.05 169.21,25.05 169.07,25.19 169.07,30.83 166.69,33.21 160.96,33.21 159.97,34.2 139.55,34.2 126.63,47.12 126.63,57.15 126.85,57.37 126.85,62.19 127.31,62.64 127.31,64.93 127.66,65.29 127.66,65.61 127.79,65.74 128.18,65.74 128.22,65.7 v2(128.22,65.54)
  BOTTOM w0.081: v2(128.22,65.54) 128.54,65.86 UC1.AL38
  BOTTOM w0.102: JDIMM2.102 170,18.86 170.2,19.06 170.2,19.72 170.46,19.97 170.46,20.49 170.69,20.72 170.9,20.72 171.08,20.9 v2(171.08,21.09)
M_CLK_DDR#0: length 76.4
  IN4 w0.091: v2(129.49,57.42) 129.74,57.17 129.74,55.78 128.11,54.16 128.11,48.51 122.27,42.67 122.09,42.67 121.57,43.19 121.3,43.19 120.98,42.87 120.98,42.59 121.49,42.07 121.49,41.89 121.32,41.72 121.14,41.72 120.86,42 120.54,42 120.27,41.73 120.27,41.4 120.55,41.13 120.55,40.95 120.37,40.77 120.19,40.77 119.67,41.29 119.4,41.29 119.08,40.97 119.08,40.69 119.59,40.19 119.59,40.01 119.41,39.83 119.23,39.83 118.73,40.34 118.45,40.34 111.32,33.21 94.23,33.21 93.76,32.75 93.63,32.75 93.23,33.16 92.9,33.16 92.63,32.88 92.63,32.56 93.04,32.15 93.04,32.02 92.82,31.8 92.69,31.8 92.28,32.21 91.95,32.21 91.68,31.93 91.68,31.61 92.09,31.2 92.09,31.07 91.64,30.62 91.64,30.31 92,29.94 92,28.91 91.87,28.79 91.24,28.79 91.11,28.91 91.11,29.81 90.94,29.98 90.78,29.98 90.57,30.19 v2(90.57,30.2)
  BOTTOM w0.081: v2(129.49,57.42) 129.31,57.6 128.93,57.6 128.36,58.16 128.36,61.31 128.53,61.47 128.53,61.57 128.77,61.81 UC1.AU37
  BOTTOM w0.102: JDIMM1.103 90.8,27.03 90.58,27.25 90.58,27.63 91.36,28.41 91.36,28.98 91.16,29.18 91.16,29.7 90.93,29.93 90.84,29.93 v2(90.57,30.2)
M_CLK_DDR#1: length 74.9
  IN4 w0.091: v2(129.25,60.47) 129.44,60.28 129.61,60.28 130.08,59.81 130.08,58.14 130.27,57.95 130.27,55.34 128.95,54.02 128.95,48.16 119.77,38.98 118.28,38.98 111.67,32.37 94.58,32.37 92.89,30.68 92.89,28.42 92.41,27.94 90.87,27.94 90.74,27.82 90.74,27.57 90.87,27.45 92.21,27.45 92.44,27.22 92.44,21.55 92.21,21.32 91.98,21.32 v2(91.7,21.04)
  BOTTOM w0.081: UC1.AW36 129.57,60.8 v2(129.25,60.47)
  BOTTOM w0.102: v2(91.7,21.04) 91.43,21.31 91.32,21.31 91.21,21.2 91.21,20.18 90.91,19.88 90.91,18.99 91.1,18.79 JDIMM1.104
M_CLK_DDR#2: length 86.8
  IN1 w0.091: v2(170.01,30.07) 170.24,29.84 170.35,29.84 170.44,29.94 170.44,30.97 170.05,31.36 169.92,31.36 169.74,31.19 169.42,31.19 169.15,31.46 169.15,31.78 169.6,32.24 169.6,32.42 169.43,32.59 169.25,32.59 168.8,32.14 168.47,32.14 168.2,32.41 168.2,32.73 168.65,33.19 168.65,33.37 168.45,33.57 168.27,33.57 167.82,33.12 167.56,33.12 166.98,33.71 166.23,33.71 166,33.94 166,34.57 165.88,34.7 165.63,34.7 165.5,34.57 165.5,33.94 165.28,33.71 164.89,33.71 164.66,33.94 164.66,34.57 164.53,34.7 164.29,34.7 164.16,34.57 164.16,33.94 163.94,33.71 163.55,33.71 163.32,33.94 163.32,34.61 163.23,34.7 162.91,34.7 162.82,34.61 162.82,33.94 162.59,33.71 162.21,33.71 161.98,33.94 161.98,34.61 161.89,34.7 161.57,34.7 161.48,34.61 161.48,34.24 161.25,34.01 160.87,34.01 160.64,34.24 160.64,34.61 160.55,34.7 139.76,34.7 127.13,47.33 127.13,54.84 127.36,55.07 127.76,55.07 127.85,55.16 127.85,55.47 127.76,55.56 127.31,55.56 127.11,55.76 127.11,56.21 127.31,56.41 127.76,56.41 127.85,56.5 127.85,57.67 127.07,58.45 127.07,62.09 127.58,62.6 127.58,64.44 127.76,64.62 127.95,64.62 128.22,64.89 v2(128.22,64.89)
  BOTTOM w0.081: UC1.AM38 128.54,65.21 v2(128.22,64.89)
  BOTTOM w0.102: v2(170.01,30.07) 170.18,29.9 170.53,29.9 170.76,29.66 170.76,28.28 170.1,27.62 170.1,27.19 170.3,26.99 JDIMM2.103
M_CLK_DDR#3: length 87.8
  IN1 w0.091: v2(128.22,66.19) 128.28,66.13 128.28,66.02 128.18,65.91 127.72,65.91 127.48,65.68 127.48,65.36 127.13,65.01 127.13,62.71 126.68,62.26 126.68,57.44 126.46,57.22 126.46,47.05 139.48,34.03 159.9,34.03 160.89,33.04 166.62,33.04 168.9,30.76 168.9,25.12 169.14,24.88 170.06,24.88 170.19,24.75 170.19,23.33 170.42,23.11 171.62,23.11 171.77,22.95 171.77,22.64 171.64,22.51 170.54,22.51 170.31,22.28 170.31,21.37 170.49,21.18 170.49,20.81 170.72,20.59 170.82,20.59 v2(171.08,20.33)
  BOTTOM w0.081: UC1.AK38 128.54,66.51 v2(128.22,66.19)
  BOTTOM w0.102: v2(171.08,20.33) 170.9,20.51 170.78,20.51 170.67,20.4 170.67,19.88 170.41,19.63 170.41,19.15 170.6,18.97 JDIMM2.104
M_ODT0: length 3.3
  TOP w0.17: RD10.2 95.95,19.92 v2(95.89,19.85)
  BOTTOM w0.17: JDIMM1.116 94.7,18.66 v2(95.89,19.85)
M_ODT1: length 2.2
  TOP w0.17: RD11.2 96.09,19.03 v2(95.9,19.21)
  BOTTOM w0.17: JDIMM1.120 v2(95.9,19.21)
M_ODT2: length 4.1
  TOP w0.17: v2(174.27,16.23) v1(174.27,17.41) 174.8,17.94 RD12.2
  BOTTOM w0.17: v2(174.27,16.23) 174.2,16.3 JDIMM2.116
M_ODT3: length 2.7
  TOP w0.17: v2(175.54,16.09) 175.43,16.2 RD13.2
  BOTTOM w0.17: v2(175.54,16.09) 175.54,16.2 175.4,16.34 JDIMM2.120
MASK_BASE_LEDS#: length 156
  TOP w0.102: UZ10.4 237.08,39.36 237.22,39.22 v1(239.9,39.22) 240.89,39.22 242.62,40.94 242.62,45.55 v2(245.64,48.57) ; QZ5.2 QZ5.5 204.28,96.3 204.39,96.42 204.39,99.92 v2(204.71,100.24)
  IN2 w0.122: v2(245.64,48.57) 248.1,51.03 249.95,51.03 251.65,52.73 251.65,54.68 255.89,58.92 255.89,69.7 259,72.81 259,73.76 259.37,74.13 259.37,77.55 262.38,80.56 v2(262.78,80.56)
  IN3 w0.122: v2(262.78,80.56) 260.75,82.58 259.72,82.58 257.14,85.17 257.14,85.41 256.33,86.21 248.59,86.21 248.06,86.74 244.61,86.74 243.38,87.97 243.38,91.08 243.23,91.23 243.23,94.88 241.74,96.37 239.54,96.37 239.08,96.82 232.49,96.82 230.11,99.2 219.44,99.2 218.56,100.08 214.68,100.08 213.88,100.88 205.35,100.88 v2(204.71,100.24)
  BOTTOM w0.102: QZ14.2 212.12,89.13 211.86,89.38 211.86,92.46 211,93.32 211,94.78 210.11,95.67 207.24,95.67 206.95,95.96 206.95,98.89 207.59,99.54 207.59,100.56 207.28,100.88 205.35,100.88 v2(204.71,100.24) ; QZ7.5 QZ7.2 263.45,81.24 262.78,80.57 v2(262.78,80.56)
MASK_SATA_LED#: length 49.4
  TOP w0.102: UE1.B9 229.22,52.71 229.67,52.26 229.7,52.26 v2(229.7,52.25)
  IN3 w0.122: v2(229.7,52.25) 229.7,52.26 229.67,52.26 229.67,52.25 229.69,52.25 229.73,52.2 230.15,52.2 230.49,52.55 230.49,55.77 227.8,58.46 227.58,58.46 225.14,60.91 225.14,65.24 225.54,65.64 225.54,71.06 v2(225.43,71.17)
  BOTTOM w0.102: v2(225.43,71.17) 224.13,71.17 223,72.3 223,76.75 221.67,78.08 220.36,78.08 219.02,79.41 219.02,83.25 218.78,83.5 216.32,83.5 215.34,84.48 214.06,84.48 213.92,84.62 v1(213.83,84.62) 212.91,84.62 212.01,85.51 212.01,85.95 211.57,86.4 QZ3.5
MCARD_PCIE#_SATA: length 149
  TOP w0.102: v2(241.85,66.49) 241.94,66.49 242.26,66.81 242.26,67.5 242.41,67.64 UE2.B8
  IN2 w0.081: 153.52,69.9 152.73,69.9 v2(152.4,70.23)
  IN2 w0.122: 153.52,69.9 153.78,69.9 157.05,66.62 159.21,66.62 162.41,63.42 162.41,57.51 166.9,53.03 166.9,51.02 168.13,49.79 168.13,45.4 174.26,39.27 194.69,39.27 195.61,40.19 201,40.19 201.58,40.77 206.73,40.77 208.09,42.13 211.64,42.13 214,44.49 215.94,44.49 217.52,46.07 218.22,46.07 218.81,46.66 218.81,48.09 218.26,48.65 218.26,53.25 218.64,53.64 218.64,54 218.28,54.35 218.28,56.01 219.63,57.36 219.63,61.08 v2(219.02,61.7)
  IN4 w0.084: v2(219.02,61.7) 219.02,62.8 220.52,64.3 222.56,64.3 225.32,67.07 232.01,67.07 232.4,67.45 236.09,67.45 238.13,65.42 239.29,65.42 239.45,65.57 240.88,65.57 241.81,66.49 v2(241.85,66.49)
  BOTTOM w0.081: v2(152.4,70.23) 152.04,70.59 151.52,70.59 UC1.AC1
  BOTTOM w0.102: RPC6.7 162.18,74.15 162.24,74.08 162.24,72.62 161.55,71.92 160.61,71.92 159.7,71.01 v1(153.29,71.01) 153.19,71.01 v2(152.4,70.23)
MCP_TESTLOW1: length 6.3
  BOTTOM w0.076: 129.38,85.08 129.78,85.48 129.78,85.54
  BOTTOM w0.081: UC1.C35 130.07,81.75 129.98,81.9 129.93,82.06 129.93,82.24 129.94,82.28 129.95,82.28 129.99,82.4 129.99,82.5 129.93,82.67 129.93,82.67 129.38,83.22 129.38,85.08
  BOTTOM w0.102: 129.78,85.54 v1(129.78,85.88) 129.78,86.99 RC240.1
MCP_TESTLOW2: length 8
  BOTTOM w0.076: 129.87,85.28 131,85.28 131.17,85.45 131.17,85.54
  BOTTOM w0.081: UC1.C34 130.68,81.6 130.51,81.77 130.33,81.77 130.14,81.97 130.13,81.98 130.1,82.08 130.1,82.21 130.13,82.28 130.13,82.28 130.14,82.3 130.16,82.37 130.16,82.53 130.12,82.64 130.11,82.69 130.05,82.84 129.61,83.29 129.61,85.02 129.87,85.28
  BOTTOM w0.102: 131.17,85.54 131.17,86.11 v1(131.13,86.14) 130.81,86.46 RC241.1
MCP_TESTLOW3: length 10.9
  TOP w0.102: RC242.1 146.24,57.82 v1(146.88,58.46) 146.94,58.52 146.94,61.95 147.22,62.23 147.22,65.26 v2(146.54,65.94)
  BOTTOM w0.081: v2(146.54,65.94) 146.94,66.33 UC1.AK8
MCP_TESTLOW4: length 10.4
  TOP w0.102: RC243.1 145.74,56.71 145.74,57.79 146.13,58.18 v1(146.13,60.93) 146.65,61.45 146.65,62 146.96,62.32 146.96,64.93 v2(146.57,65.32)
  BOTTOM w0.081: UC1.AL8 146.93,65.68 v2(146.57,65.32)
MDP_AUX#_C: length 26.5
  TOP w0.102: UV502.6 261,67.32 260.78,67.54 260.78,67.72 260.85,67.79 v2(261.16,67.79) ; RV501.2 260.78,73.94 260.78,73.82 v2(261.04,73.57) 261.48,73.57 261.65,73.4 UV502.8
  IN2 w0.114: v2(261.16,67.79) 260.91,67.79 259.96,68.74 259.96,69.38 260.84,70.26 260.84,73.38 v2(261.04,73.57)
  IN4 w0.091: v2(270.3,79.81) 270.1,79.61 270.1,79.33 268.53,77.76 268.08,77.76 263.95,73.63 262.09,73.63 261.69,74.03 260.92,74.03 260.85,73.95 260.85,73.76 v2(261.04,73.57)
  BOTTOM w0.102: JMDP1.18 270.81,80.05 270.69,80.17 270.69,80.38 270.62,80.44 270.5,80.44 270.14,80.08 270.14,79.97 v2(270.3,79.81)
MDP_AUX_C: length 26.5
  TOP w0.102: UV502.11 259.7,73.19 260.08,73.57 v2(260.45,73.57) 260.53,73.65 260.53,73.88 RV502.2 ; UV502.3 259.05,67.44 258.76,67.73 v2(258.4,67.73)
  IN2 w0.114: v2(260.45,73.57) 260.65,73.38 260.65,70.35 259.77,69.47 259.77,69.1 v2(258.4,67.73)
  IN4 w0.091: v2(269.72,79.81) 269.93,79.6 269.93,79.4 268.46,77.93 268.01,77.93 263.88,73.8 262.17,73.8 261.77,74.2 260.85,74.2 260.67,74.02 260.67,73.79 v2(260.45,73.57)
  BOTTOM w0.102: v2(269.72,79.81) 269.93,80.02 269.93,80.17 270.41,80.66 JMDP1.16
MDP_CA_DET: length 37.4
  TOP w0.102: UV502.4 259.7,67.61 v2(259.6,67.71) ; v2(257.67,67.73) 257.75,67.65 UV502.1 ; v2(264.78,71.54) 264.8,71.52 QV502.2 268.4,71.52 RV504.1 269.72,71.84 v1(270.12,72.24)
  IN4 w0.084: v2(257.67,67.73) 258.18,67.22 259.11,67.22 v2(259.6,67.71) 260.38,67.71 262.24,69.57 262.24,71.03 262.75,71.54 v2(264.78,71.54) 268.34,71.54 269.48,72.68 269.48,76.75 271.58,78.84 271.58,83.16 v2(270.48,84.26)
  BOTTOM w0.102: JMDP1.4 v2(270.48,84.26)
MDP_CA_DET#: length 14
  TOP w0.102: v1(264.08,72.24) 264.15,72.17 v2(264.78,72.17) QV502.1 265.67,73.51 266.18,74.02 RV507.2 ; UV502.10 260.35,71.17 v2(260.21,71.03) ; UV502.13 v2(258.4,71.03)
  IN4 w0.084: v2(264.78,72.17) 262.75,72.17 261.61,71.03 v2(260.21,71.03) v2(258.4,71.03)
MDP_HPD: length 17.3
  TOP w0.102: v1(268.91,76.11) 268.69,75.89 v2(267.74,75.89) 267.71,75.89 266.93,75.11 RV505.2 266.55,75.03 265.6,74.08 QV501.1
  IN2 w0.122: v2(267.74,75.89) 268.43,75.89 271.45,78.9 271.45,83.98 270.58,84.86 v2(270.45,84.86)
  BOTTOM w0.102: JMDP1.2 v2(270.45,84.86)
MDP_LANE_N0_C: length 7.9
  BOTTOM w0.102: JMDP1.5 274.21,84.34 274.21,84.84 273.36,85.68 270.11,85.68 269.66,85.23 268.47,85.23 268.24,85.45 CV508.1
MDP_LANE_N1_C: length 7.8
  TOP w0.102: CV506.1 268.07,83.07 268.26,83.07 269.28,82.05 v4(270.18,82.05) 272.31,82.05 272.33,82.03 272.86,82.03 272.87,82.05 274.4,82.05 JMDP1.11
MDP_LANE_N2_C: length 7.9
  BOTTOM w0.102: JMDP1.17 273.65,80.12 273.89,80.12 273.99,80.02 273.99,79.65 272.99,78.65 269.82,78.65 v4(269.55,78.91) 269.22,79.25 268.85,79.25 268.61,79.49 268.2,79.49 268.1,79.59 268.1,79.79 CV504.1
MDP_LANE_N3_C: length 7.9
  BOTTOM w0.102: CV502.1 268.05,81.21 268.68,81.21 v4(268.83,81.05) 269.01,80.88 269.38,80.88 269.82,81.32 269.82,81.67 269.09,82.4 268.9,82.59 268.9,82.77 269.17,83.04 269.35,83.04 270.34,82.05 270.66,82.05 270.85,81.86 JMDP1.12
MDP_LANE_P0_C: length 7.9
  BOTTOM w0.102: JMDP1.3 273.65,84.19 273.92,84.19 273.99,84.26 273.99,84.75 273.27,85.46 270.2,85.46 269.73,85 v4(269.41,85) 268.08,85 267.99,84.91 267.99,84.82 CV507.1
MDP_LANE_P1_C: length 7.8
  TOP w0.102: CV505.1 268.03,83.29 268.35,83.29 269.37,82.26 269.83,82.26 269.85,82.28 270.44,82.28 270.46,82.26 v4(272.59,82.26) 274.4,82.26 JMDP1.9
MDP_LANE_P2_C: length 7.9
  BOTTOM w0.102: CV503.1 269.11,79.03 269.71,78.43 273.08,78.43 274.21,79.56 274.21,79.97 JMDP1.15
MDP_LANE_P3_C: length 7.9
  BOTTOM w0.102: JMDP1.10 270.81,82.46 270.62,82.26 270.43,82.26 269.44,83.25 269.06,83.25 v4(268.88,83.07) 268.69,82.88 268.69,82.5 268.94,82.25 269.33,81.86 269.34,81.86 269.61,81.58 269.61,81.41 269.29,81.09 269.12,81.09 268.78,81.43 268.05,81.43 CV501.1
ME_FWP: length 85.9
  TOP w0.102: v2(184.71,48.11) 184.11,48.7 183.21,48.7 179.81,45.3 v3(178.22,45.3) 156.58,45.3 150.83,51.05 150.83,51.35 RC11.1
  BOTTOM w0.102: v2(184.71,48.11) 184.71,47.98 184.39,47.66 180.77,47.66 180.07,48.36 177.47,48.36 172.77,53.06 172.77,60.62 178.17,66.01 178.17,66.61 180.26,68.71 180.26,69.89 183.62,73.24 SW1.3 187.27,73.24 188.15,72.36 RC301.1
ME_FWP_EC: length 115.1
  TOP w0.102: UE2.B46 243.41,59.32 243.39,59.34 v2(243.39,59.52)
  IN4 w0.084: v2(186.14,48.11) 190.38,48.11 192.8,45.69 196.7,45.69 197.32,45.08 205.82,45.08 208.04,47.3 212.84,47.3 213.86,48.31 214.51,48.31 220.65,54.45 220.65,56.49 226.73,62.57 228.22,62.57 228.59,62.2 229.74,62.2 230.37,61.58 231.21,61.58 231.44,61.35 236.75,61.35 237.57,62.17 240.49,62.17 241.73,60.93 242.37,60.93 242.92,60.38 242.92,59.99 v2(243.39,59.52)
  BOTTOM w0.102: v2(186.14,48.11) 185.41,48.84 177.63,48.84 173.23,53.25 173.23,59.93 178.63,65.33 178.63,66.42 180.72,68.52 180.72,69.7 181.85,70.83 v2(182.27,70.83) 183.36,69.74 183.36,69.49 183.67,69.19 184.78,69.19 184.84,69.24 SW1.1 187.3,69.24 187.52,69.46 187.52,69.91 188.52,70.92 RC301.2
ME_RESET#: length 3.5
  TOP w0.102: UC4.2 165.04,84.2 RC80.1 ; v1(165.05,85.31) 165.15,85.2 RC80.1 ; RC80.1 165.89,84.31 RC95.2
ME_SUS_PWR_ACK: length 132.4
  TOP w0.102: v2(241.47,70.67) 241.77,70.67 242.16,70.29 UE2.A8 ; v2(151.7,59.56) v1(151.7,57.25) RC79.2
  IN1 w0.084: v2(151.7,59.56) 151.7,59.81 157.01,65.11 159.2,65.11 161.74,62.58 161.74,58.64 163.48,56.89 166.22,56.89 167.06,57.74 168.31,57.74 168.98,57.07 171.68,57.07 171.95,56.8 178.69,56.8 181.54,53.94 181.54,52.16 183.71,49.99 188.95,49.99 193.5,45.44 194.55,45.44 194.95,45.84 196.49,45.84 197.25,45.08 205.68,45.08 207.5,46.9 209.88,46.9 210.28,47.3 211.14,47.3 211.7,47.86 213.49,47.86 214.03,48.4 214.77,48.4 216.12,49.74 216.12,51.98 217.6,53.46 217.6,55.66 219.7,57.76 220.67,57.76 226.87,63.96 226.87,66.02 231.4,70.55 231.4,72.11 231.83,72.53 235.46,72.53 235.71,72.78 238.41,72.78 238.84,72.35 240.04,72.35 241.47,70.92 v2(241.47,70.67)
  BOTTOM w0.081: 149.65,59.94 149.65,60.01 149.65,60.01 149.65,60.29 149.65,60.29 149.65,60.62 149.59,60.67 149.59,61 149.27,61.32 UC1.AV4
  BOTTOM w0.102: 149.65,59.94 150.03,59.56 v2(151.7,59.56)
MEC_XTAL1: length 6.5
  TOP w0.102: YE1.1 252.32,65.9 252.04,66.18 251.36,66.18 251.02,65.84 CE28.1 250.42,66.1 249.25,66.1 248.53,65.38 v1(248.53,65.29) 248.22,65.29 248.08,65.43 248.06,65.43 247.88,65.6 UE2.A61
MEC_XTAL2: length 3.4
  TOP w0.102: YE1.2 252.32,67.14 252.15,66.97 250.99,66.97 CE29.1 RE61.2
MEC_XTAL2_R: length 3.1
  TOP w0.102: RE61.1 249.78,67.61 v1(248.8,66.63) 248.27,66.1 UE2.A62
MEDIACARD_IRQ#: length 188.3
  TOP w0.102: v2(160.2,69.86) 160.45,69.86 161.34,68.97 v1(161.77,68.97) 161.98,68.77 161.98,66.01 163.68,64.31 RPC5.8 ; UR1.16 259.58,13.6 259.44,13.46 259.44,12.88 v2(259.52,12.79)
  IN1 w0.084: v2(160.2,69.86) 158.92,68.58 151.66,68.58 150.48,69.76 148.07,69.76 147.63,70.21 v2(147.63,70.27)
  IN4 w0.084: v2(251.38,13.32) 250.83,12.76 248.79,12.76 247.76,13.79 247.76,20.47 249.14,21.85 249.14,26.38 247.2,28.31 247.2,40.58 243.97,43.81 225.08,43.81 224.09,44.8 222,44.8 220.08,42.88 217.52,40.32 215.44,40.32 214.75,39.63 209.67,39.63 206.49,36.45 206.49,35.14 205.27,33.93 201.01,33.93 199.41,32.32 198.09,32.32 197.47,31.7 193.35,31.7 192.89,32.17 187.23,32.17 170.17,49.22 170.17,52.4 168.59,53.98 165.2,53.98 162.4,56.78 162.4,60.32 164.06,61.98 164.06,70.33 163.61,70.78 160.88,70.78 160.2,70.09 v2(160.2,69.86)
  BOTTOM w0.081: v2(147.63,70.27) 147.96,70.6 UC1.AB6
  BOTTOM w0.102: v2(259.52,12.79) 259.37,12.64 253.95,12.64 253.26,13.32 v2(251.38,13.32)
MEDIACARD_PWREN: length 7.2
  TOP w0.102: UR1.14 258.78,13.68 258.18,13.08 258.18,10.26 257.61,9.69 v1(257.09,9.69) 256.32,9.69 256.02,9.99 RR15.2
MEDIACARD_RST#: length 20.1
  TOP w0.102: RPC5.7 163.5,64.81 162.84,65.47 162.84,65.73 v2(162.48,66.09) 162.48,66.31 162.42,66.37 v1(162.42,67.09)
  IN1 w0.084: v2(162.48,66.09) 161.79,66.79 161.79,67.07 161.26,67.6 155.8,67.6 154.83,66.63 150,66.63 148.64,67.98 148.58,67.98 v2(148.22,68.34)
  BOTTOM w0.081: v2(148.22,68.34) 148.22,68.13 147.96,67.87 UC1.AG6
MEM_SMBCLK: length 44.1
  TOP w0.102: QC1.6 171.12,58.26 171.63,57.76 174.42,57.76 175.25,58.58 175.25,59.35 174.93,59.67 174.93,60.13 v2(175.12,60.32)
  IN1 w0.084: v2(161.92,69.67) 161.72,69.48 161.72,68.91 163.04,67.6 163.31,67.6 164.73,66.18 169.48,66.18 174.94,60.72 174.94,60.5 v2(175.12,60.32)
  IN4 w0.084: v2(161.92,69.67) 160.61,68.36 153.21,68.36 152.6,67.75 152.6,65.34 151.86,64.6 151.86,64.45 151.82,64.4 v2(151.82,63.86)
  BOTTOM w0.081: v2(151.82,63.86) 151.12,63.86 150.83,63.57 UC1.AP2
  BOTTOM w0.102: v2(161.92,69.67) 161.73,69.86 161.73,70.6 162.23,71.09 163.56,71.09 163.69,70.96 RPC14.3
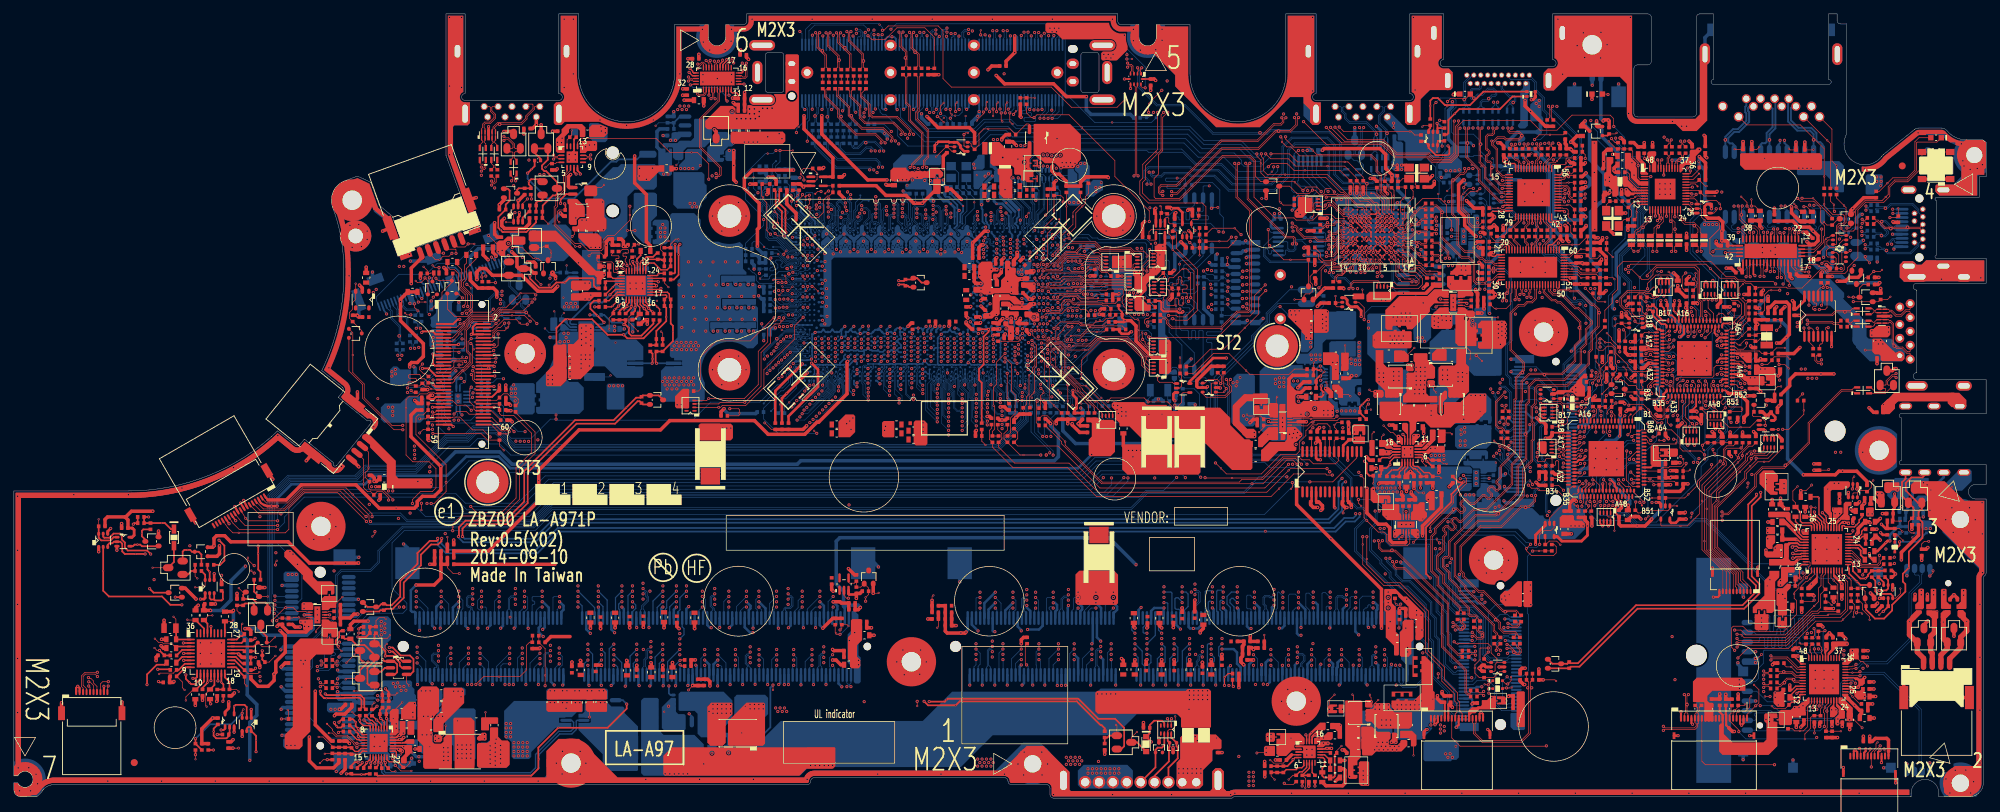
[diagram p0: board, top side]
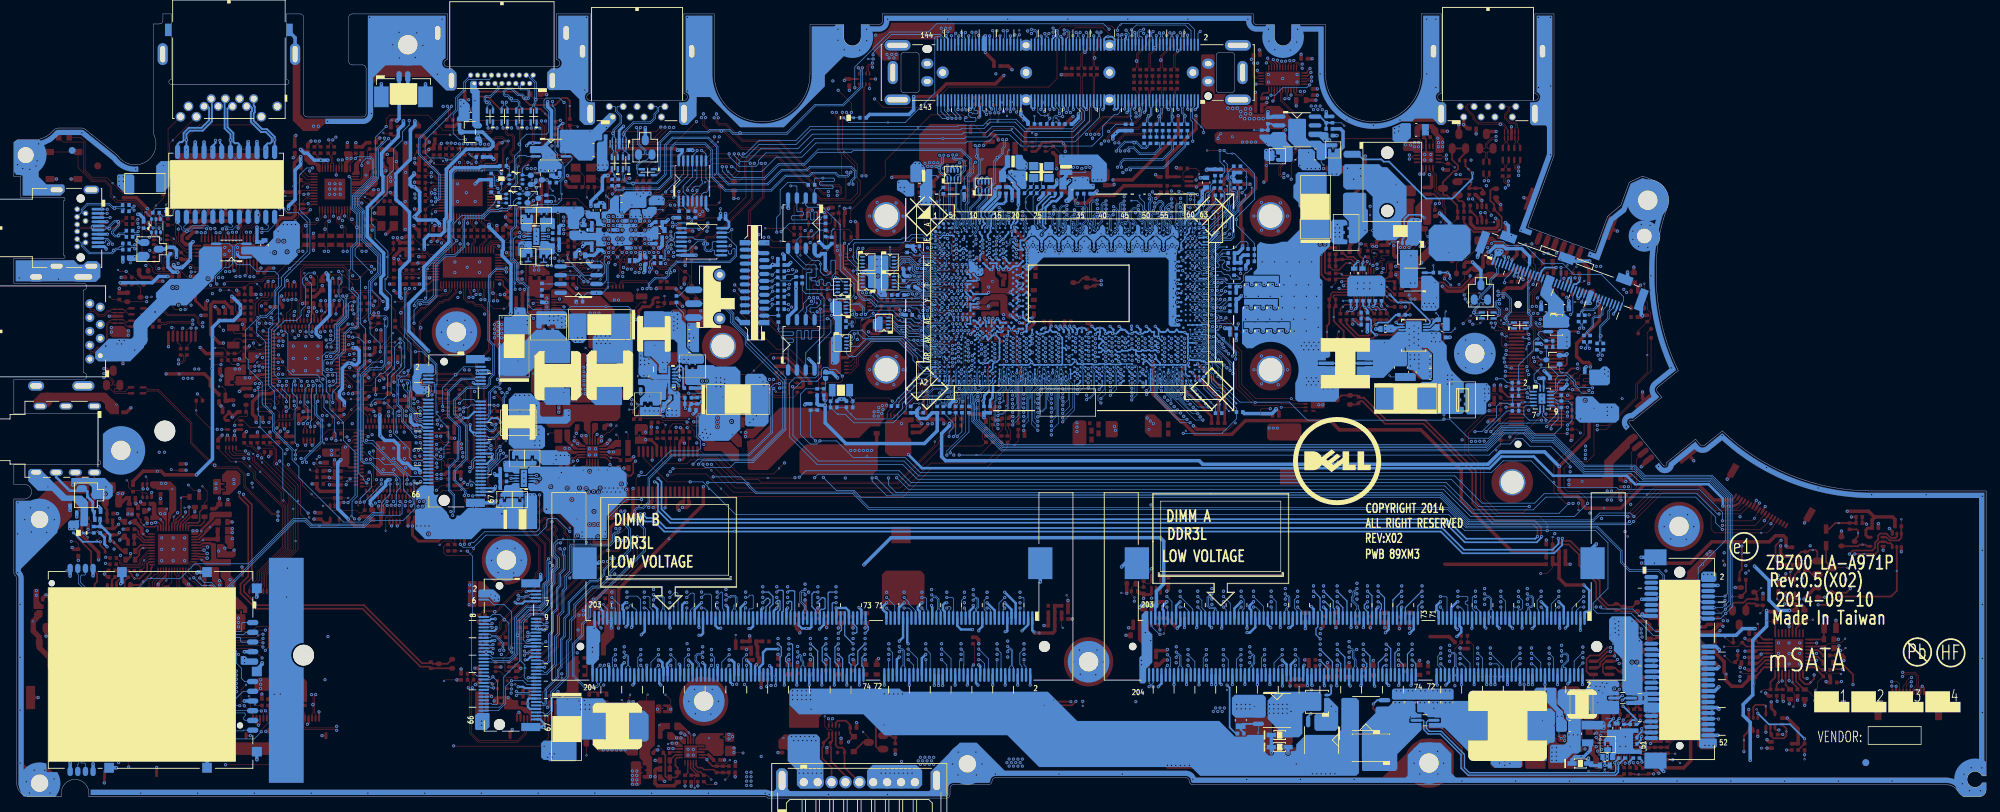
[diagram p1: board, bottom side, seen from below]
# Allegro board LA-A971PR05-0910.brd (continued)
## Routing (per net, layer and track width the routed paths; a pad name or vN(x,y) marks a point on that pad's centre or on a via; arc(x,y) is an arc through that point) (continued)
MEM_SMBDATA: length 40.5
  TOP w0.102: v2(174.54,60.32) 174.7,60.16 174.7,59.58 175.02,59.26 175.02,58.68 174.33,57.99 172.71,57.99 172.39,58.31 172.39,59.73 172.47,59.81 QC1.3
  IN1 w0.084: v2(161.32,69.67) 161.51,69.48 161.51,68.83 162.95,67.39 163.22,67.39 164.64,65.97 169.4,65.97 174.73,60.64 174.73,60.52 v2(174.54,60.32)
  BOTTOM w0.076: UC1.AH1 152.17,67.32 153.34,68.49 153.64,68.49 v1(153.67,68.47) 153.72,68.52 153.82,68.52
  BOTTOM w0.102: RPC14.4 163.81,71.46 163.67,71.32 162.14,71.32 161.5,70.69 161.5,69.86 v2(161.32,69.67) 160.69,70.3 157.4,70.3 156.41,69.32 156.11,69.32 155.85,69.06 154.72,69.06 154.18,68.52 153.82,68.52
MIC1_L: length 3.6
  TOP w0.203: UA1.19 265.22,36.05 265.27,36 v1(265.27,36.03)
  TOP w0.254: v1(265.27,36.03) 265.48,36.03 265.85,35.66 265.85,35.03 266.45,34.43 CA43.1
MIC1_R: length 2.8
  TOP w0.203: UA1.20 265.18,36.45
  TOP w0.254: CA44.1 266.42,35.7 265.67,36.45 265.18,36.45
MMICLK_REQ#: length 173.7
  TOP w0.102: v2(259.87,13.28) 259.98,13.39 UR1.17
  IN3 w0.081: 153.82,76.94 152.51,76.94 152.26,76.68 152.26,74.43 v2(152.55,74.15)
  IN3 w0.122: 153.82,76.94 154.96,78.08 169.43,78.08 171.6,80.25 176.33,80.25 177.04,80.97 177.92,80.97 180.71,78.18 183.58,78.18 185.67,76.09 187.76,76.09 188.79,75.06 190.49,75.06 190.97,74.58 194.23,74.58 194.84,73.96 198.1,73.96 199.71,75.57 204.38,75.57 204.98,74.97 209.31,74.97 210.6,76.27 212.03,76.27 213.98,78.22 223.67,78.22 227.16,74.73 228.54,74.73 229.89,73.39 229.89,72.13 229.67,71.91 229.67,68.6 230.58,67.68 230.58,64.3 234.67,60.21 236.81,60.21 237.33,59.69 237.33,55.96 238.12,55.18 238.12,53.49 239.58,52.03 239.58,50.69 239.19,50.29 239.19,44.65 241.71,42.13 242.4,42.13 247.44,37.09 247.44,25.42 251.59,21.26 251.59,19.77 253.8,17.56 255.58,17.56 v2(259.87,13.28)
  BOTTOM w0.076: v2(152.55,74.15) 152.55,74 152.06,73.52 151.51,73.52 151.44,73.59 150.87,73.59 UC1.U2
  BOTTOM w0.081: 153.82,74.75 153.14,74.75 v2(152.55,74.15)
  BOTTOM w0.102: RPC18.7 157.02,74.65 156.48,74.12 155.46,74.12 155.02,74.56 154.09,74.56 153.91,74.75 153.82,74.75
MPCIE_RST#: length 6.4
  BOTTOM w0.076: 153.89,73.05 154.36,73.05 ; UC1.V1 151.63,72.56 151.86,72.79 153.63,72.79
  BOTTOM w0.081: 153.63,72.79 153.89,73.05
  BOTTOM w0.102: 154.36,73.05 154.62,73.05 154.8,73.23 156.35,73.23 156.78,73.65 RPC18.5
MPHYP_PWR_EN: length 44.7
  TOP w0.102: QZ10.2 136.94,93.85 136.77,94.02 v2(136.77,95.63) 137,95.86 v1(137.34,95.86)
  IN2 w0.122: v2(154.56,72.63) 154.56,72.76 153.69,73.63 151.56,73.63 151.05,74.14 151.05,81.18 149.14,83.1 148.23,83.1 147.63,83.7 147.63,86.33 145.49,88.47 145.49,89.41 140.01,94.89 139.75,94.89 138.63,96.01 137.15,96.01 v2(136.77,95.63)
  BOTTOM w0.076: 153.82,72.21 153.62,72.21 153.37,72.46 152.06,72.46 151.7,72.1 150.89,72.1 UC1.Y2
  BOTTOM w0.102: RC155.1 156.69,72.49 ; 156.69,72.49 156.19,73 154.93,73 v2(154.56,72.63) 154.14,72.21 153.82,72.21 ; 156.69,72.49 RC171.1
MPHYP_PWR_EN#: length 4.6
  TOP w0.102: RZ16.2 135.02,93.2 QZ10.6 ; RZ16.2 134.25,93.91 v1(132.77,92.43) ; RZ16.2 134.9,93.91 134.96,93.85 QZ10.5
MSATA_DEVSLP: length 112.9
  TOP w0.102: RZ39.2 227.08,61.47 v2(227.17,61.56)
  IN3 w0.081: 153.82,75.82 153.19,75.82 v2(152.73,76.29)
  IN3 w0.122: v2(227.57,73.41) 223.26,77.72 216.53,77.72 213.06,74.25 209.21,74.25 208.99,74.47 204.78,74.47 204.18,75.07 199.92,75.07 198.31,73.46 194.64,73.46 194.02,74.08 190.77,74.08 190.28,74.56 188.59,74.56 187.55,75.59 185.46,75.59 183.38,77.68 180.5,77.68 178.43,79.76 171.81,79.76 169.41,77.36 165.98,77.36 163.73,75.12 161.84,75.12 161.53,74.81 157.81,74.81 156.79,75.82 153.82,75.82
  BOTTOM w0.076: UC1.P2 151.04,75.25 151.04,75.25 151.05,75.27 151.73,75.27 152.73,76.26 v2(152.73,76.29)
  BOTTOM w0.102: v2(227.57,73.41) 227.7,73.28 227.7,66.46 226.74,65.5 226.74,61.98 v2(227.17,61.56) 227.17,61.1 227.46,60.81 228.04,60.81 228.51,60.34 228.51,56.69 227.83,56.01 227.83,54.34 226.68,53.19 225.22,53.19 224.94,52.9 JNGFF2.30
MSCLK: length 45.9
  TOP w0.102: v2(241.67,60.05) 241.68,60.05 242.06,59.66 242.06,59.18 241.91,59.03 UE2.B43 ; RE72.2 250.25,50.71 249.78,50.71 248.81,49.73 v2(248.81,49.35) 248.81,49 v1(248.18,48.37) 244.02,44.21 244.02,35.74 247.5,32.26 JDEG1.6
  IN4 w0.084: v2(248.81,49.35) 248.81,49.68 248.23,50.26 248.23,50.62 249.75,52.15 249.75,54.3 248.58,55.47 246.61,55.47 245.91,54.77 244.22,54.77 242.05,56.94 242.05,59.6 241.67,59.98 v2(241.67,60.05)
MSDATA: length 42.9
  TOP w0.102: JDEG1.7 247,32.44 243.69,35.75 v1(243.69,41.68) 243.69,44.47 v2(248.25,49.03) ; RE86.2 247.83,49.45 v2(248.25,49.03) ; v2(248.25,49.03) 248.25,49.5 249.8,51.05 RE75.2 ; UE2.A40 241.66,57.13 v2(241.6,57.07)
  IN4 w0.084: v2(248.25,49.03) 248.25,49.94 247.91,50.28 247.91,50.6 249.54,52.23 249.54,54.21 248.49,55.26 246.7,55.26 246,54.56 244.13,54.56 241.62,57.07 v2(241.6,57.07)
NB_LAN_TX0+: length 9.5
  BOTTOM w0.279: JLOM1.1 249.38,99.76 249.23,99.61 249.23,98.83 249.38,98.68 249.38,97.6 248.17,96.39 247.47,96.39 246.37,95.29 v4(246.37,94.84) TL1.13
NB_LAN_TX0-: length 9.5
  BOTTOM w0.279: JLOM1.2 249.87,99.68 249.63,99.44 249.63,99 249.79,98.84 249.79,97.43 248.34,95.99 247.64,95.99 246.77,95.12 246.77,94.56 247,94.34 247.38,94.34 247.64,94.08 TL1.14
NB_LAN_TX1+: length 9.6
  IN4 w0.241: JLOM1.3 251.42,99.43 252.02,98.83 252.02,97.1 252.88,96.24 253.8,96.24 254.38,95.66 254.38,94.92 v2(254.24,94.78)
  BOTTOM w0.279: v2(254.24,94.78) 254.24,94.4 253.99,94.14 TL1.19
NB_LAN_TX1-: length 9.6
  IN4 w0.241: v2(254.88,94.78) 254.75,94.91 254.75,95.81 253.95,96.61 253.03,96.61 252.39,97.25 252.39,98.36 253.71,99.68 JLOM1.6
  BOTTOM w0.279: v2(254.88,94.78) 254.88,94.4 255.26,94.02 TL1.20
NB_LAN_TX2+: length 8.1
  BOTTOM w0.279: TL1.17 251.45,94.18 251.64,94.37 252.11,94.37 252.31,94.56 252.31,95.83 253.16,96.68 253.16,99.34 252.82,99.68 JLOM1.4
NB_LAN_TX2-: length 8.1
  BOTTOM w0.279: JLOM1.5 253.57,100.67 253.57,96.51 252.72,95.67 v4(252.72,94.84) TL1.18
NB_LAN_TX3+: length 10.3
  BOTTOM w0.279: JLOM1.7 255.39,100.67 255.39,97.5 256.72,96.18 258.56,96.18 259.07,95.67 v4(259.07,94.84) TL1.23
NB_LAN_TX3-: length 10.3
  BOTTOM w0.279: JLOM1.8 256.02,99.68 255.8,99.46 255.8,97.67 256.89,96.58 258.72,96.58 259.47,95.83 259.47,94.75 259.7,94.53 260.02,94.53 260.34,94.21 TL1.24
NB_PSID: length 24.3
  TOP w0.254: PL3.2 74.96,91.07 v1(74.53,90.63) v2(73.95,90.06)
  BOTTOM w0.254: PJPDC1.1 90.46,92.8 89.7,92.04 87.05,92.04 86.72,91.71 85.94,91.71 80.63,86.4 76.8,86.4 73.95,89.25 v2(73.95,90.06)
NB_PSID_TS5A63157: length 2.8
  TOP w0.254: PR9.2 74.26,84.55 PR8.1 74.1,84.51 73.23,83.63 PU1.3
NFC_IRQ: length 9.2
  TOP w0.102: RC175.1 156.94,67.18 v1(155.89,67.18) 154.43,67.18 v2(153.19,65.94)
  BOTTOM w0.076: UC1.AN3 150.2,64.02 150.79,64.02 150.93,64.15 150.93,64.41 151.12,64.61 152.03,64.61 153.02,65.6 153.02,65.7 153.19,65.86 v2(153.19,65.94)
NGFF_CONFIG_0: length 18.1
  TOP w0.102: RPE4.1 222,54.79 v2(222.92,53.87) 223.37,53.87 223.63,54.14 223.63,54.71 222.94,55.41 v1(222.94,55.64) 222.94,56.51 222.56,56.9 v2(219.76,56.9) ; UE1.B12 227.72,52.75 v2(227.71,52.74)
  IN3 w0.122: v2(227.71,52.74) 226.65,52.74 226.02,53.37 223.42,53.37 v2(222.92,53.87)
  BOTTOM w0.102: v2(219.76,56.9) 219.21,57.44 217.73,57.44 217.44,57.15 JNGFF2.13
NGFF_CONFIG_1: length 17
  TOP w0.102: v1(218.21,45.76) 218.59,45.37 v2(218.59,45.18) ; v2(222.96,54.46) 222.13,55.29 RPE4.2 ; UE1.A18 v2(223.04,52.15)
  IN2 w0.122: v2(223.04,52.15) 223.04,53.15 223.4,53.5 223.4,54.02 v2(222.96,54.46)
  IN3 w0.122: v2(218.59,45.18) 218.59,45.86 221.63,48.9 221.63,50.62 223.04,52.03 v2(223.04,52.15)
  BOTTOM w0.102: v2(218.59,45.18) 218.21,45.57 217.83,45.57 217.41,45.15 JNGFF2.61
NGFF_CONFIG_2: length 35.8
  TOP w0.102: v2(222.16,55.87) 222.08,55.79 RPE4.3 ; UE1.A44 230.97,43.11 v2(231.33,42.75)
  IN1 w0.084: v2(231.7,45.88) 231.7,44.04 231.33,43.67 v2(231.33,42.75)
  IN3 w0.122: v2(217.86,43.54) 217.48,43.92 217.48,45.63 221.03,49.19 221.03,54.33 222.16,55.46 v2(222.16,55.87)
  IN4 w0.084: v2(231.7,45.88) 231.31,46.27 225.1,46.27 224.47,45.64 221.65,45.64 220.04,44.04 218.17,44.04 217.86,43.73 v2(217.86,43.54)
  BOTTOM w0.102: JNGFF2.67 217.74,43.65 v2(217.86,43.54)
NGFF_CONFIG_3: length 31.7
  TOP w0.102: RPE4.4 222.01,56.29 v2(222.17,56.45) ; UE1.B34 224.3,44.9 223.95,44.55 223.95,43.92 223.67,43.64 222.89,43.64 222.23,44.3 219.63,44.3 v1(219.48,44.46) 219.28,44.65 218.46,44.65 v2(218.02,45.1)
  IN3 w0.122: v2(218.02,45.1) 218.02,45.73 221.35,49.06 221.35,53.89 222.62,55.16 222.62,56.03 222.2,56.45 v2(222.17,56.45)
  BOTTOM w0.102: JNGFF2.1 219.14,62.15 222.17,59.12 v2(222.17,56.45)
O-USR: length 6.4
  TOP w0.102: PR504.1 86.28,69.77 85.69,69.18 v1(85.69,67.54)
  TOP w0.203: PU500.9 88.15,71.5 87.87,71.22 87.36,71.22 v2(87.05,70.9)
  TOP w0.254: PR504.1 86.28,70.14 v2(87.05,70.9)
  BOTTOM w0.254: v2(87.05,70.9) 87.03,70.92 PR509.2
OCP-I: length 7.5
  TOP w0.102: PR501.2 88.53,69.34 88.53,68.58 v1(89.83,67.28)
  TOP w0.203: PU500.12 89.35,71.33 89.42,71.26 v2(89.42,70.71)
  TOP w0.254: v2(89.42,70.71) 89.42,70.23 PR501.2
  BOTTOM w0.254: PR524.2 89.05,70.34 v2(89.42,70.71) 89.7,70.99 PR506.2
OUT1_CA_DET: length 12
  TOP w0.102: v2(226.21,73.46) 226.93,72.73 RV606.2 227.3,72.24 228.03,71.51 v1(229.06,71.51) ; UV600.43 v2(219.65,72.86)
  IN1 w0.084: v2(226.21,73.46) 226.13,73.53 220.33,73.53 v2(219.65,72.86)
OUT2_CA_DET: length 6.4
  TOP w0.102: UV600.33 215.65,72.86 215.48,72.68 215.48,71.2 214.8,70.52 v1(213.38,70.52) 213.14,70.52 RV607.2
P33ALW: length 4
  TOP w0.102: PR859.1 32.06,15.66 v1(32.37,15.34)
  TOP w0.254: PU800.18 30.36,17.41 31.03,16.74 PR859.1
P33ALW2: length 5
  TOP w0.102: v1(24.56,15.6) 24.24,15.91 24.24,16.73 PR855.2
  TOP w0.254: PU800.9 24.73,18.85 PR855.2
PANEL_BKEN_EC: length 229.2
  TOP w0.102: v2(227.34,45.28) 226.72,44.65 UE1.B38 ; v2(58.67,42.48) v1(58.67,41.51) ; v2(69.01,70.45) 68.58,70.02 65.89,70.02 65.26,69.39 63.48,69.39 62.39,70.47 DV2.2
  IN1 w0.084: v2(69.01,70.45) 69.01,70.14 67.13,68.25 65.42,68.25 61.34,64.17 61.34,62.41 59.4,60.48 59.4,59.44 58.67,58.7 v2(58.67,42.48)
  IN3 w0.122: v2(58.67,42.48) 59.77,41.38 64.9,41.38 67.95,38.33 184.77,38.33 186.43,39.99 201.06,39.99 201.6,39.45 201.6,37.66 202.36,36.91 204.27,36.91 205.7,38.34 207.66,38.34 209.39,40.08 214.46,40.08 215.19,40.8 218.49,40.8 219.76,42.07 219.76,44.55 220.46,45.25 220.46,46.63 222.78,48.94 224.17,48.94 224.39,48.72 226.44,48.72 226.99,48.16 226.99,47.28 227.7,46.58 227.7,45.63 v2(227.34,45.28)
PANEL_BKLEN: length 100.7
  TOP w0.076: v1(146.06,84.29) 145.75,83.98 v2(145.75,83.79)
  TOP w0.102: DV2.3 63.93,72.71 v2(64.57,72.07)
  IN2 w0.122: v2(64.57,72.07) 65.62,73.12 65.62,74.76 66.83,75.97 68.78,75.97 69.75,76.94 70.6,76.94 76.46,82.8 78.58,82.8 80.57,84.78 83.38,84.78 84.55,85.95 91.26,85.95 92.84,87.54 104.1,87.54 106.47,89.91 108.77,89.91 109.57,89.12 112.24,89.12 113.36,90.24 121.81,90.24 122.42,89.64 124.82,89.64 126.55,91.37 128.41,91.37 128.47,91.44 128.47,91.44 129.02,91.98 130.04,91.98 130.48,92.42 130.48,92.42 130.79,92.74 132.99,92.74 133.58,93.32 139.47,93.32 142.25,90.53 142.25,88.69 143.32,87.62 143.32,86.83 144.89,85.25 144.89,84.65 v2(145.75,83.79)
  BOTTOM w0.081: UC1.A9 145.75,82.82 v2(145.75,83.79)
PANEL_HDD_LED#: length 165.3
  TOP w0.102: JLED1.3 62.43,79.1 63.55,79.1 63.64,79.01 v2(63.64,78.49) ; v1(209.05,88.45) 209.04,88.45 208.7,88.11 v2(208.7,87.96)
  IN3 w0.122: v2(63.64,78.49) 65.71,78.49 70.24,83.02 72,83.02 74.45,85.46 75.7,85.46 76.79,86.55 82.91,86.55 84.53,88.18 91.74,88.18 92.95,89.38 97.04,89.38 100.08,92.43 107.87,92.43 109.79,94.34 112.8,94.34 113.77,95.32 122.56,95.32 123.97,96.72 129.62,96.72 130.46,95.89 133.23,95.89 133.91,95.21 137.88,95.21 138.54,95.87 144.94,95.87 145.04,95.77 152.29,95.77 152.84,95.22 164.81,95.22 170.64,89.39 182.93,89.39 184.2,90.66 192.14,90.66 193.2,91.73 198.11,91.73 198.38,92 204.82,92 205.54,91.29 205.54,90.44 207.3,88.68 207.4,88.68 208.12,87.96 v2(208.7,87.96)
  BOTTOM w0.102: v2(208.7,87.96) 208.7,87.45 209.97,86.18 QZ4.3
PBAT_PRES#: length 292.3
  TOP w0.102: v2(248.73,59.16) 248.27,59.16 248.08,59.36 248.08,59.41 247.89,59.6 UE2.A49 ; v1(241.39,40.44) 241.54,40.59 v2(241.54,41.06)
  TOP w0.254: v2(29.83,9.82) 30.21,9.82 30.4,10.01 PU804.1 ; v2(163.75,8.09) PD4.1 163.51,9.38 PR2.2 163.51,10.53 164.14,11.15 165.28,11.15 165.6,10.83 PRP2.3 ; v2(50.14,5.12) 50.14,5.02 49.86,4.74 49.76,4.74 49.44,4.42 PR728.1
  IN1 w0.254: v2(163.75,8.09) 163.75,12.29 162.29,13.75 152.9,13.75 151.18,15.47 135.68,15.47 132.89,12.68 118.05,12.68 113.54,17.18 52.65,17.18 51.61,16.14 51.61,10.07 51.11,9.57 51.11,6.52 50.14,5.55 v2(50.14,5.12)
  IN3 w0.122: v2(241.54,41.06) 241.25,40.77 232.79,40.77 227.93,35.92 220.92,35.92 216.59,31.59 216.59,18.27 215.37,17.04 214.48,17.04 212.56,15.13 v2(212.32,15.13)
  IN4 w0.084: v2(212.32,15.13) 212.32,14.93 211.77,14.39 211.26,14.39 209.63,16.03 202.6,16.03 201.15,17.48 182.76,17.48 178.59,13.31 165.91,13.31 163.75,11.15 v2(163.75,8.09)
  IN4 w0.254: v2(29.83,9.82) 29.9,9.75 29.9,7.09 32.56,4.42 49.77,4.42 50.14,4.79 v2(50.14,5.12)
  BOTTOM w0.102: v2(241.54,41.06) 245.18,44.7 245.18,50.16 248.46,53.44 248.46,54.97 248.73,55.24 v2(248.73,59.16)
PBAT_PRES#_C: length 8.8
  TOP w0.254: PRP2.6 165.6,7.6 165.28,7.28 164.64,7.28 164.33,6.97 PD2.2 164.33,4.43 PBATT1.5
PBAT_SMBCLK: length 121.6
  TOP w0.102: v2(166.64,11.44) 166.46,11.26 166.46,11.04 166.6,10.9 PRP2.1 ; UE2.A56 247.75,63.1 247.9,62.96 248.69,62.96 v1(248.88,62.77) 249.21,62.44 v2(249.21,62.21) 249.77,62.21 RE43.2
  IN1 w0.084: v2(249.21,62.21) 249.45,61.97 249.69,61.97 250.01,61.66 250.01,61.35 249.1,60.45 244.3,60.45 244.25,60.41 244.25,59.11 245.61,57.76 245.61,54.51 242.52,51.42 242.52,50.05 241.32,48.85 241.32,47.78 240.58,47.05 240.58,44.99 237.57,41.97 233.98,41.97 232.64,40.64 224.31,40.64 221.88,38.2 221.88,37.59 215.19,30.9 215.19,30.25 208.45,23.51 207.15,23.51 206.04,22.4 206.04,20.11 200.62,14.69 190.57,14.69 186.26,10.37 181.58,10.37 179.78,12.17 166.79,12.17 166.45,11.84 166.45,11.63 v2(166.64,11.44)
PBAT_SMBCLK_C: length 7.9
  TOP w0.254: PRP2.8 166.6,8.74 PD1.2 167.37,7.47 167.54,7.29 167.54,5.73 166.2,4.39 PBATT1.3
PBAT_SMBDAT: length 123.8
  TOP w0.102: UE2.B59 245.91,62.85 v2(245.85,62.79) ; v2(249.21,61.58) 249.52,61.58 RE37.2 ; PRP2.2 166.1,10.9 166.23,11.03 166.23,11.27 v2(166.06,11.44)
  IN1 w0.084: v2(166.06,11.44) 166.24,11.63 166.24,11.93 166.7,12.38 179.87,12.38 181.66,10.59 186.18,10.59 190.49,14.9 200.53,14.9 205.83,20.19 205.83,22.49 207.06,23.72 208.36,23.72 214.98,30.34 214.98,30.99 221.67,37.67 221.67,38.29 224.22,40.85 232.55,40.85 233.89,42.19 237.48,42.19 240.37,45.08 240.37,47.13 241.11,47.87 241.11,48.94 242.31,50.14 242.31,51.51 245.39,54.6 245.39,57.67 244.04,59.02 244.04,60.5 244.21,60.66 249.02,60.66 249.8,61.44 249.8,61.57 249.61,61.76 249.39,61.76 v2(249.21,61.58) 248.81,61.18 247.47,61.18 v2(245.85,62.79)
PBAT_SMBDAT_C: length 11.2
  TOP w0.102: PRP2.7 166.1,9.69 166.32,9.91 166.74,9.91 167.17,10.34 v1(167.17,11.79)
  TOP w0.254: PBATT1.4 164.2,3.23 166.27,5.3 166.27,7.31 166.37,7.41 PD1.3 166.1,8.24 PRP2.7
PBATT+_C:
  vias: v1(173.11,8.66) v2(167.69,4.23) v2(167.69,3.59) v2(168.33,4.23) v2(168.33,3.59) v2(168.45,8.29) v2(168.77,8.86) v2(168.96,4.23) v2(168.96,3.59) v2(169.09,8.29) v2(169.41,8.86) v2(169.6,4.23) v2(169.6,3.59) v2(169.72,8.29) v2(170.04,8.86) v2(170.23,4.23) v2(170.23,3.59) v2(170.36,8.29) v2(170.68,8.86) v2(170.87,4.23) v2(170.87,3.59) v2(170.99,8.29) v2(171.31,8.86) v2(171.63,8.29) v2(171.95,8.86)
PCH_ALW_ON: length 107.2
  TOP w0.102: UZ7.5 184.1,54.54 184.21,54.66 v1(186.72,54.66) 190.08,54.66 v2(190.46,55.04) ; RPE10.4 238.28,73.42 238.81,73.95 238.81,74.9 238.34,75.37 236.36,75.37 235.17,74.18 v2(235.17,73.4) ; v2(238,57.01) 238.06,57.01 238.66,57.61 UE2.A34
  IN4 w0.084: v2(190.46,55.04) 189.78,54.35 188.81,54.35 187.7,55.47 187.7,58.77 185.62,60.85 185.62,68.78 187.05,70.21 188.14,70.21 188.47,70.54 198.49,70.54 199.3,71.35 203.91,71.35 205.24,72.68 208.66,72.68 209.23,72.11 210.97,72.11 212.48,70.6 217.91,70.6 218.57,71.26 222.86,71.26 224.56,69.56 228.66,69.56 230.03,70.93 231.19,70.93 231.78,70.34 232.72,70.34 235.17,72.8 v2(235.17,73.4)
  BOTTOM w0.102: v2(235.17,73.4) 234.26,72.49 234.26,68.02 234.68,67.6 235.38,67.6 236.18,66.8 236.18,64.38 237.05,63.51 237.05,59.45 238,58.51 v2(238,57.01)
PCH_AZ_BITCLK: length 5.4
  BOTTOM w0.076: RC23.2 147.82,56.95 147.82,57.2 147.33,57.68 147.33,58.05 146.48,58.9 146.48,59.64 146.39,59.73 146.39,59.73 146.08,60.05 146.08,60.51 UC1.AW8
PCH_AZ_CODEC_BITCLK: length 141.3
  TOP w0.102: v2(248.04,23.61) 248.58,23.61 v1(248.74,23.45) 249.07,23.11 255,23.11 258.83,26.94 259.6,26.94 260.08,27.42 260.08,29.39 RA17.1 260.44,30.43 260.44,31.97 260.77,32.3 UA1.6
  IN4 w0.084: v2(148.65,52.1) 148.65,51.68 149.78,50.55 150.73,50.55 153.16,48.12 164.32,48.12 166.04,46.4 166.04,45.65 169.59,42.11 171.16,42.11 183.21,30.06 183.21,27.16 185.35,25.02 193.56,25.02 194.49,24.09 200.79,24.09 201.73,25.02 203.96,25.02 205.35,26.41 212.86,26.41 213.59,27.15 245.62,27.15 248.16,24.61 248.16,23.72 v2(248.04,23.61)
  BOTTOM w0.081: RC23.1 CC5.1
  BOTTOM w0.102: RC23.1 148.32,52.43 v2(148.65,52.1)
PCH_AZ_CODEC_RST#: length 146.6
  TOP w0.102: v2(248.06,21.77) 248.32,22.03 255.22,22.03 259.19,26.01 262.9,26.01 263.98,27.09 263.98,31.18 263.44,31.72 263.39,31.72 262.77,32.34 UA1.11
  IN4 w0.084: v2(248.06,21.77) 248.46,22.17 248.46,24.83 245.85,27.43 213.47,27.43 212.74,26.7 205.23,26.7 203.84,25.31 185.47,25.31 183.5,27.28 183.5,30.18 171.28,42.39 169.71,42.39 166.33,45.77 166.33,46.52 164.44,48.41 153.28,48.41 150.85,50.84 149.9,50.84 149.28,51.46 v2(149.28,52.11)
  BOTTOM w0.102: v2(149.28,52.11) 149.28,52.74 148.7,53.31 148.7,54.13 RC22.1
PCH_AZ_CODEC_SDIN0: length 145.4
  TOP w0.102: v2(248.04,23) 248.04,22.95 248.28,22.71 255.03,22.71 258.96,26.63 259.73,26.63 259.99,26.9 262.57,26.9 RA9.1
  IN4 w0.084: v2(149.6,49.42) 151.05,49.42 152.92,47.55 164.08,47.55 165.47,46.16 165.47,45.41 169.35,41.53 170.92,41.53 180.57,31.89 180.57,26.64 184.18,23.02 185.47,23.02 186.28,23.83 189.8,23.83 190.35,24.39 193.38,24.39 194.25,23.52 203.27,23.52 205.59,25.84 213.09,25.84 213.83,26.57 244.38,26.57 247.96,23 v2(248.04,23)
  BOTTOM w0.076: UC1.AY10 145.62,59.82 146.1,59.34 146.1,58.79 146.94,57.95 146.94,52.67 149.6,50.01 v2(149.6,49.42)
PCH_AZ_CODEC_SDOUT: length 140.5
  TOP w0.102: v2(247.7,24.21) 248.61,24.21 249.3,23.52 254.98,23.52 v1(259.16,27.7) 259.78,28.32 259.78,30.28 260.13,30.63 260.13,32.09 260.37,32.33 UA1.5
  IN4 w0.084: v2(247.7,24.21) 245.05,26.86 213.71,26.86 212.97,26.13 205.47,26.13 203.15,23.8 194.37,23.8 193.5,24.67 190.23,24.67 189.68,24.12 183.61,24.12 180.86,26.88 180.86,32.01 171.04,41.82 169.47,41.82 165.76,45.53 165.76,46.28 164.2,47.84 153.04,47.84 150.61,50.27 149.66,50.27 148.1,51.82 v2(148.1,52.12)
  BOTTOM w0.102: v2(148.1,52.12) 147.43,52.79 RC19.1
PCH_AZ_CODEC_SYNC: length 148.6
  TOP w0.102: UA1.10 262.37,32.36 263.68,31.05 263.68,27.22 262.98,26.52 261.24,26.52 v1(261.12,26.4) 261.05,26.33 259.08,26.33 255.16,22.4 248.07,22.4 v2(248.04,22.38)
  IN4 w0.084: v2(149.11,49.76) 149.11,49.32 149.41,49.03 151.04,49.03 152.8,47.26 163.96,47.26 165.18,46.04 165.18,45.29 169.23,41.25 170.81,41.25 180.28,31.77 180.28,25.44 183.02,22.71 185.92,22.71 186.76,23.55 191.78,23.55 192.2,23.13 203.66,23.13 204.2,23.66 207.51,23.66 209.4,25.55 213.21,25.55 213.95,26.29 244.13,26.29 v2(248.04,22.38)
  BOTTOM w0.102: v2(149.11,49.76) 149.11,50.07 146.42,52.76 RC20.1
PCH_AZ_RST#: length 8
  BOTTOM w0.076: UC1.AU8 146.77,61.74 146.77,61.37 146.68,61.28 146.68,58.94 147.55,58.07 147.55,57.72 147.71,57.56 v1(147.88,57.56) 147.9,57.58 148.88,57.58 150.02,56.44 RC22.2
PCH_AZ_SDIN0_R: length 5.4
  TOP w0.102: UA1.8 261.57,31.75 v1(261.97,31.36) 262.55,30.77 262.55,27.93 RA9.2
PCH_AZ_SDOUT: length 10.6
  TOP w0.102: v2(147.31,57.19) 147.17,57.05 147.17,54.1 RC11.2
  BOTTOM w0.076: UC1.AU11 145.25,61.76 145.25,61.39 145.33,61.3 145.33,60.69 145.54,60.47 145.78,60.47 145.91,60.34 145.91,59.98 146.23,59.66 146.23,59.66 146.29,59.6 146.29,58.85 147.14,58 147.14,57.35 v2(147.31,57.19)
  BOTTOM w0.102: v2(147.31,57.19) 147.43,57.06 RC19.2
PCH_AZ_SYNC: length 5.7
  BOTTOM w0.076: RC20.2 146.42,56.72 146.55,56.84 v1(146.55,57.7) 146.55,58.09 145.91,58.72 145.91,59.29 145.34,59.86 145.34,60.38 145.17,60.56 145.17,61.19 UC1.AV11
PCH_BATLOW#: length 14
  TOP w0.081: 153.82,58.3 153.47,58.65 153.47,58.97 150.86,61.57 v1(150.86,62.01) 150.86,64.63 150.42,65.07 150.1,65.07 v2(149.72,64.69)
  TOP w0.102: 153.82,58.3 156.67,55.45 RPC1.8
  BOTTOM w0.081: UC1.AN4 149.31,64.28 v2(149.72,64.69)
PCH_CL_CLK1: length 106.3
  IN4 w0.084: v2(206.33,33.52) 206.06,33.52 205.62,33.08 203.57,33.08 203.44,32.95 203.44,31.61 203.31,31.48 203.02,31.48 202.89,31.61 202.89,32.95 202.77,33.08 202.53,33.08 202.4,32.95 202.4,31.61 202.28,31.48 202.04,31.48 201.91,31.61 201.91,32.42 201.79,32.55 201.55,32.55 201.42,32.42 201.42,31.61 201.3,31.48 198.15,31.48 197.73,31.07 192.79,31.07 192.54,31.32 186.88,31.32 169.33,48.87 169.33,52.05 168.24,53.14 163.16,53.14 158.58,57.72 156.91,57.72 154.55,60.08 154.55,61.7 153.6,62.64 151.19,62.64 150.87,62.96 150.87,68.63 v2(150.31,69.19)
  BOTTOM w0.081: UC1.AF2 150.31,69.1 v2(150.31,69.19)
  BOTTOM w0.102: v2(206.33,33.52) 206.71,33.14 206.71,31.22 207.29,30.65 207.29,28.02 207.42,27.89 208.08,27.23 209.78,27.23 211.36,25.66 211.36,20.7 212.45,19.6 JNGFF1.34
PCH_CL_DATA1: length 105
  IN4 w0.084: v2(206.75,33.93) 206.17,33.93 205.53,33.29 201.34,33.29 201.21,33.17 201.21,31.82 201.08,31.69 200.8,31.69 200.67,31.82 200.67,32.2 200.54,32.32 200.31,32.32 200.18,32.2 200.18,31.82 200.05,31.69 198.06,31.69 197.65,31.28 192.88,31.28 192.63,31.53 186.97,31.53 169.54,48.96 169.54,52.14 168.33,53.35 163.24,53.35 158.67,57.93 157.27,57.93 154.8,60.39 154.8,61.89 153.77,62.91 151.42,62.91 151.12,63.22 151.12,70.08 151.27,70.23 v2(151.78,70.23)
  BOTTOM w0.081: v2(151.78,70.23) 151.65,70.23 151.34,69.92 151.15,69.92 150.8,69.56 UC1.AD2
  BOTTOM w0.102: JNGFF1.32 215.21,20.1 214.94,19.83 212.55,19.83 211.59,20.79 211.59,25.94 210.07,27.46 208.18,27.46 207.51,28.12 207.51,30.74 206.94,31.31 206.94,33.73 v2(206.75,33.93)
PCH_CL_RST1#: length 107.2
  IN4 w0.084: v2(206.93,34.48) 206.42,34.48 205.44,33.5 201.19,33.5 199.59,31.9 197.97,31.9 197.56,31.49 192.97,31.49 192.71,31.75 187.05,31.75 169.75,49.05 169.75,52.22 168.42,53.56 163.33,53.56 158.75,58.14 157.35,58.14 155.05,60.44 155.05,62.14 154.04,63.16 151.8,63.16 151.29,63.66 151.29,68.54 151.56,68.81 152.96,68.81 v2(153.59,69.44)
  BOTTOM w0.076: UC1.AF4 149.61,68.45 150.03,68.45 150.13,68.36 150.79,68.36 150.96,68.52 151.91,68.52 151.94,68.55 152.29,68.55
  BOTTOM w0.081: 152.29,68.55 152.8,69.06 153.21,69.06 v2(153.59,69.44)
  BOTTOM w0.102: JNGFF1.30 215.37,20.6 214.96,20.19 212.51,20.19 211.81,20.89 211.81,26.04 210.16,27.69 208.27,27.69 207.74,28.21 207.74,30.84 207.17,31.41 207.17,34.25 v2(206.93,34.48)
PCH_DPWROK: length 125.6
  TOP w0.076: v2(150.64,58.37) 150.64,58.43 v1(150.29,58.78)
  TOP w0.102: v2(238.84,55.11) 238.84,55.18 239.66,56 UE2.A36
  IN2 w0.122: v2(150.64,58.37) 150.64,57.91 152.76,55.79 153.93,55.79 155.21,54.52 155.21,52.87 156.32,51.75 156.32,45.97 167.04,35.25 193.82,35.25 193.93,35.14 200.72,35.14 202.09,33.77 204.78,33.77 205.95,32.6 206.73,32.6 211.65,37.53 220.7,37.53 224.33,41.16 224.33,43.03 225.16,43.85 228.08,43.85 228.96,44.74 233.16,44.74 233.92,45.5 233.92,46.73 237.1,49.9 237.1,53.38 237.62,53.9 237.62,54.58 238.15,55.11 v2(238.84,55.11)
  BOTTOM w0.076: v2(150.64,58.37) 150.24,58.77 148.97,58.77 148.33,59.41 148.33,59.96 148.33,61.04 148.58,61.29 UC1.AV5
PCH_GPIO4: length 19.4
  BOTTOM w0.081: 153.82,81.2 153.07,81.2 151.81,79.94 151.01,79.94 150.59,79.52 UC1.F2
  BOTTOM w0.102: 153.82,81.2 154.72,81.2 155.22,80.71 155.98,80.71 156.2,80.49 163.04,80.49 v1(163.68,79.85) 163.89,79.65 163.89,77.72 162.69,76.52 162.35,76.52 162.34,76.5 RPC8.4
PCH_GPIO5: length 18.4
  BOTTOM w0.081: UC1.F3 150.18,79.27 150.43,79.02 150.8,79.02 150.88,79.1 150.88,79.56 151.05,79.73 151.92,79.73 152.91,80.72 153.82,80.72
  BOTTOM w0.102: RPC8.3 161.97,77 161.98,77 162.49,77 163.07,77.59 v1(163.07,78.02) 163.07,79.78 162.84,80.01 155.91,80.01 155.69,80.23 155.02,80.23 154.52,80.72 153.82,80.72
PCH_GPIO6: length 15.3
  IN2 w0.122: v2(161.69,79.21) 161.37,78.9 155.44,78.9 154.46,79.88 152.97,79.88 v2(152.39,79.29)
  BOTTOM w0.081: v2(152.39,79.29) 152.03,78.94 151.53,78.94 151.44,78.84 150.29,78.84 150.17,78.97 149.67,78.97 UC1.G4
  BOTTOM w0.102: v2(161.69,79.21) 161.69,79.04 162.17,78.56 162.17,78.19 161.98,78 RPC8.1
PCH_GPIO7: length 15.2
  IN2 w0.122: v2(151.82,79.34) 151.82,79.03 152.07,78.78 153.02,78.78 153.44,79.19 154.43,79.19 155.31,78.32 161.9,78.32 162.34,78.76 v2(162.34,79.22)
  BOTTOM w0.076: UC1.F1 v2(151.82,79.34)
  BOTTOM w0.102: v2(162.34,79.22) 162.59,78.97 162.59,77.79 162.31,77.5 RPC8.2
PCH_GPIO9: length 17.5
  TOP w0.076: v2(150.3,64.69) v1(150.3,64.17)
  TOP w0.102: RPC5.6 163.59,65.31 v2(163.4,65.5)
  IN1 w0.084: v2(150.3,64.69) 150.5,64.89 150.5,65.7 151.21,66.42 154.92,66.42 155.89,67.39 160.09,67.39 162.16,65.32 163.22,65.32 v2(163.4,65.5)
  BOTTOM w0.081: UC1.AM3 149.94,65.05 v2(150.3,64.69)
PCH_GPIO10: length 6.9
  BOTTOM w0.076: 153.82,66.97 153.62,66.97 153.24,66.59 152.9,66.59 152.61,66.3 152.61,65.76 152.47,65.62 151.75,65.62 151.49,65.36 151.44,65.36 151.44,65.36 151.12,65.36 150.96,65.19 150.95,65.19 150.95,65.19 150.95,65.19 150.83,65.07 UC1.AM2
  BOTTOM w0.102: 153.82,66.97 155.11,66.97 155.64,67.5 T27.1
PCH_GPIO14: length 1.5
  TOP w0.076: T21.1 149.06,67.4 v2(148.7,67.4)
  BOTTOM w0.076: v2(148.7,67.4) 148.83,67.28 UC1.AH4
PCH_GPIO16: length 11.8
  BOTTOM w0.076: 153.82,71.98 153.56,71.98 153.25,72.3 152.13,72.3 151.64,71.81 UC1.Y1
  BOTTOM w0.102: 153.82,71.98 v1(154.62,71.98) 159.24,71.98 160.01,72.75 160.01,73.19 160.07,73.25 160.99,73.25 161.38,73.65 RPC6.8
PCH_GPIO19: length 9.6
  TOP w0.102: RC66.2 156.08,71.72 155.97,71.6 153.57,71.6 v1(153.16,72.01) 152.9,72.28 151.16,72.28 150.69,71.81 149.14,71.81 v2(148.83,72.11)
  BOTTOM w0.081: v2(148.83,72.11) 148.83,71.9 UC1.Y5
PCH_GPIO44: length 10.1
  BOTTOM w0.076: UC1.AK4 149.6,66.91 150.05,66.91 150.11,66.85 152.21,66.85 153.15,67.79 153.47,67.79 153.73,67.53 153.82,67.53
  BOTTOM w0.102: 153.82,67.53 154.57,67.53 v1(154.92,67.87) 155.14,68.1 156.57,68.1 157.71,69.24 RPC19.4
PCH_GPIO46: length 19.7
  TOP w0.081: v2(150.31,67.69) 149.95,67.34 149.95,66.01 150.13,65.83 150.79,65.83 151.77,64.85 152.11,64.85 152.41,65.15 v1(152.5,65.15) 153.82,65.15
  TOP w0.102: RPC10.6 163.35,62.26 162.84,62.78 162.84,63.6 160.19,66.25 156.03,66.25 154.92,65.15 153.82,65.15
  BOTTOM w0.081: v2(150.31,67.69) 149.94,68.06 UC1.AG3
PCH_GPIO49: length 6.7
  TOP w0.102: v2(150.24,72.18) 150.54,72.48 153.14,72.48 153.67,71.95 155.97,71.95 T22.1
  BOTTOM w0.081: UC1.Y3 149.94,71.88 v2(150.24,72.18)
PCH_GPIO52: length 12.7
  TOP w0.102: RPC3.6 161.27,77 161.1,76.83 161.1,76.39 160.88,76.17 156.82,76.17 156.51,76.48 156.51,76.82 156.02,77.3 v1(155.65,77.3) 154.12,77.3 153.82,77 153.25,77 v2(152.86,77.39)
  BOTTOM w0.076: UC1.L1 151.24,76.41 151.54,76.7 152.12,76.7 152.51,77.09 152.8,77.09 152.86,77.15 v2(152.86,77.39)
PCH_GPIO53: length 10.2
  TOP w0.102: v2(151.77,76.35) 152.22,75.89 154.01,75.89 v1(154.6,76.48) 154.8,76.68 155.9,76.68 156.05,76.53 156.05,76.29 156.63,75.72 157.43,75.72 RC140.1
  BOTTOM w0.076: UC1.L4 149.59,75.98 150.83,75.98 150.87,76.01 151.44,76.01 v2(151.77,76.35)
PCH_GPIO57: length 15.3
  BOTTOM w0.076: UC1.AP1 151.36,63.45 152.05,63.45 152.96,64.36 153.4,64.36 153.82,64.78
  BOTTOM w0.102: RPC7.8 163.82,66.32 163.74,66.4 163.74,66.92 163.25,67.41 v1(161.79,67.41) 160.86,66.48 155.8,66.48 154.1,64.78 153.82,64.78
PCH_GPIO59: length 8.3
  TOP w0.081: v2(148.77,62.24) 149.03,61.98 149.03,57.27 v1(149.74,56.57) RC245.1
  BOTTOM w0.076: UC1.AT5 148.34,62.67 v2(148.77,62.24)
PCH_GPIO66: length 8
  TOP w0.102: v2(149.49,80.62) 151.51,82.64 v1(151.51,85.25) 151.51,87.26 RC176.2
  BOTTOM w0.081: v2(149.49,80.62) 149.61,80.74 UC1.D3
PCH_GPIO67: length 13.3
  TOP w0.102: v2(149.55,78.19) 149.55,78.42 150.84,79.72 150.84,81.06 152.45,82.68 v1(152.45,83.79) 152.45,84.43 153.72,85.7 153.72,86.33 153.53,86.52 RC163.2
  BOTTOM w0.081: UC1.E4 148.97,79.77 148.97,78.47 149.25,78.19 v2(149.55,78.19)
PCH_GPIO68: length 10.7
  TOP w0.102: v2(151.82,81.24) 152.86,82.28 152.86,84.33 v1(153.78,85.25) 154.23,85.7 154.23,86.65 154.67,87.1 RC164.2
  BOTTOM w0.081: UC1.C3 150.09,81.48 150.5,81.07 150.82,81.07 150.98,81.24 v2(151.82,81.24)
PCH_GPIO69: length 15.8
  TOP w0.102: RPC16.6 163.5,77.95 162.64,78.81 161.27,78.81 160.79,79.28 156.56,79.28 155.68,80.16 152.4,80.16 v2(151.88,80.68) 151.44,80.68 v1(151.18,80.43)
  BOTTOM w0.081: v2(151.88,80.68) 151.78,80.59 150.9,80.59 150.59,80.28 UC1.E2
PCH_GPIO73: length 22.1
  TOP w0.102: v2(153.66,60.49) v1(153.66,61.06) 153.66,63.09 156.36,65.8 160,65.8 162.36,63.44 162.36,62.33 163.42,61.26 RPC10.8
  BOTTOM w0.076: v2(153.66,60.49) 152.58,60.49 152.13,60.93 151.63,60.93 151.43,61.13 150.42,61.13 150.36,61.19 149.78,61.19 149.59,61.38 149.59,61.95 149.41,62.13 UC1.AU4
PCH_GPIO76: length 11.3
  BOTTOM w0.076: UC1.P1 151.78,74.81 152.65,75.67
  BOTTOM w0.081: 153.82,75.86 153.75,75.8 153.09,75.8 152.97,75.67 152.65,75.67
  BOTTOM w0.102: 153.82,75.86 153.88,75.92 154.13,75.92 154.29,76.09 154.29,76.75 155.07,77.52 155.87,77.52 156.94,76.45 RPC17.5 157.64,76.45 157.79,76.59 v1(157.79,79.37)
PCH_GPIO80: length 8.2
  BOTTOM w0.076: UC1.N2 150.75,75.56 151.05,75.85 151.82,75.85 152.14,76.18 152.14,76.49 152.58,76.93 153.01,76.93 153.09,77 153.42,77
  BOTTOM w0.102: 153.42,77 153.52,76.9 v1(153.76,76.9) 153.77,76.9 154.89,78.02 156.24,78.02 156.8,77.45 RPC17.7
PCH_GPIO85: length 11.7
  TOP w0.102: v2(148.14,75.96) 150.72,75.96 v1(150.87,76.11) 150.99,76.23 150.99,77.13 151.66,77.8 154.01,77.8 154.18,77.63 156.01,77.63 156.74,76.91 156.74,76.6 156.83,76.5 RPC4.8
  BOTTOM w0.081: v2(148.14,75.96) 147.96,75.79 UC1.N6
PCH_GPIO87: length 20.3
  TOP w0.102: v2(146.97,74.93) 146.97,74.68 v1(147.19,74.46) ; v2(163.09,75.95) 163.09,76.52 163.51,76.95 RPC16.8
  IN1 w0.084: v2(146.97,74.93) 147.58,75.54 148.32,75.54 148.64,75.86 154,75.86 154.28,76.14 160.04,76.14 160.64,76.75 162.74,76.75 163.09,76.4 v2(163.09,75.95)
  BOTTOM w0.081: v2(146.97,74.93) 147.31,74.59 UC1.R7
PCH_INTVRMEN: length 7.8
  BOTTOM w0.076: UC1.AV7 147.08,61.22 146.84,60.97 146.84,59.01 148.07,57.78 148.94,57.78 149.9,56.82 150.61,56.82 RC1.2
PCH_JTAG_JTAGX: length 81.6
  TOP w0.102: v2(109.44,69.21) 109.35,69.21 106.03,65.89 101.14,65.89 98.86,63.6 98.86,58.97 98.54,58.65 RC18.1
  IN4 w0.084: v2(109.44,69.21) 109.44,69.21 108.7,69.95 108.7,71.26 107.72,72.25 107.72,75.77 106.33,77.16 104.88,77.16 104.32,77.71 85.17,77.71 74.88,67.43 71.44,67.43 70.47,66.46 v2(70.47,60.43)
  BOTTOM w0.076: 109.88,68.81 v1(110.41,68.81) 110.54,68.81 110.68,68.67 112.43,68.67 UC1.AE63
  BOTTOM w0.102: v2(70.47,60.43) 69.49,60.43 68.93,59.86 RC112.2 RC115.2 ; v2(109.44,69.21) 109.84,68.81 109.88,68.81
PCH_JTAG_TCK: length 69
  TOP w0.102: v2(68.56,52.04) 67.53,53.06 66.03,53.06 64.19,54.9 63.19,54.9 63.11,54.82 JXDP1.55 60.6,54.82 60.42,54.64 59.95,54.64 RC119.2 59.28,54.65 v3(58.41,54.65)
  IN1 w0.084: v2(68.56,52.04) 70.11,53.59 72.71,53.59 73.28,54.17 96.92,54.17 98.58,55.84 98.58,63.64 101.04,66.09 105.91,66.09 107.65,67.83 v2(107.65,68.34)
  BOTTOM w0.076: UC1.AE62 112.92,68.5 111.64,68.5 111.53,68.39 110.16,68.39
  BOTTOM w0.102: 110.16,68.39 108.66,68.39 RC21.1 107.65,67.96 v2(107.65,68.34)
PCH_JTAG_TDI: length 86.1
  TOP w0.102: JXDP1.56 68.84,54.82 70.32,53.34 71.46,53.34 v2(72,52.81) ; v2(110.16,69.25) 109.65,68.74 109.46,68.74 108.51,67.79 108.51,65.74 107.15,64.38 107.15,59.57 105.14,57.57 v3(100.01,57.57) 99.75,57.3 RPC21.4
  IN1 w0.084: v2(72,52.81) 73.02,52.81 73.42,53.2 97.32,53.2 99.49,55.38 99.49,63.28 101.46,65.25 106.17,65.25 108.57,67.65 108.57,68.3 109.08,68.81 109.72,68.81 v2(110.16,69.25)
  BOTTOM w0.076: UC1.AD61 113.66,69.9 113.16,69.9 112.97,69.7 112.97,69.48 112.79,69.3 112.43,69.3 112.43,69.3 112.42,69.3 112.25,69.13 111.37,69.13
  BOTTOM w0.081: 111.37,69.13 110.87,69.63 110.55,69.63
  BOTTOM w0.102: v2(110.16,69.25) 110.17,69.25 110.55,69.63 ; v2(72,52.81) 69.01,55.79 RC99.1
PCH_JTAG_TDO: length 85.3
  TOP w0.102: RPC21.2 v3(101.46,56.3) 101.71,56.3 101.96,56.55 105.34,56.55 107.96,59.18 107.96,61.72 112.38,66.14 112.38,68.05 v2(113.62,69.28)
  IN1 w0.084: v2(113.62,69.28) 113.07,69.28 112.64,68.85 111.68,68.85 111.18,68.35 109.39,68.35 109.12,68.07 109.12,67.65 106.28,64.81 101.59,64.81 99.94,63.16 99.94,55.27 97.48,52.81 73.59,52.81 v2(73.58,52.81)
  BOTTOM w0.081: v2(113.62,69.28) 113.65,69.24 113.92,68.98 UC1.AE61
  BOTTOM w0.102: RC98.1 68.2,57.94 RC118.2 68.63,56.68 68.86,56.91 69.99,56.91 70.47,56.43 70.47,54.91 72.57,52.81 v2(73.58,52.81)
PCH_JTAG_TMS: length 93.7
  TOP w0.102: JXDP1.58 68.77,54.32 70.15,52.93 71.17,52.93 v2(71.3,52.81) ; RPC21.3 101.46,56.8 101.65,57 v3(105.21,57) 107.56,59.35 107.56,64.21 108.92,65.57 108.92,67.62 109.61,68.31 110.18,68.31 110.8,68.93 v2(110.8,69.2)
  IN1 w0.084: v2(110.8,69.2) 110.3,69.7 109.02,69.7 108.08,68.76 108.08,67.71 106.07,65.7 101.21,65.7 99.05,63.54 99.05,55.64 97.11,53.7 73.37,53.7 72.87,53.2 71.7,53.2 v2(71.3,52.81)
  BOTTOM w0.076: v2(110.8,69.2) 111.16,68.83 112.18,68.83 112.32,68.97 112.32,68.97 112.48,69.13 112.5,69.13 112.51,69.13 112.86,69.13 113.13,69.41 113.13,69.41 113.27,69.55 UC1.AD62
  BOTTOM w0.102: v2(71.3,52.81) 70.07,54.04 65.95,54.04 65.93,54.05 63.07,54.05 62.02,55.1 62.02,56.42 62.17,56.57 UC7.9
PCH_JTAG_TRST#: length 62.4
  TOP w0.102: v2(78.04,54.61) v3(78.04,55.22)
  BOTTOM w0.081: 111.17,60.81 111.17,60.98 112.27,62.08 112.27,62.21 112.52,62.46 112.92,62.46 UC1.AU62
  BOTTOM w0.102: 111.17,60.81 111.17,60.22 110.49,59.54 109.87,59.54 107.39,57.06 100.29,57.06 97.69,54.46 78.19,54.46 v2(78.04,54.61) 77.23,54.61 74.47,51.85 71.58,51.85 69.8,53.63 66.1,53.63 64.92,52.45 62.16,52.45 61.15,53.46 RC109.2
PCH_OPI_COMP: length 5.1
  BOTTOM w0.081: UC1.AW15 142.62,60.79
  BOTTOM w0.152: 143.53,58.68 143.53,59.54 143.02,60.04 143.02,60.39 142.62,60.79
  BOTTOM w0.381: 143.53,58.68 144.21,58 144.21,57.49 144.3,57.4 v1(144.3,57.35) 144.3,56.48 RC178.1
PCH_PCIE_RCOMP: length 5.7
  BOTTOM w0.203: UC1.A27 135.4,83.78
  BOTTOM w0.305: 135.4,85.1 135.4,83.79 135.4,83.78
  BOTTOM w0.381: RC149.2 133.09,86.78 133.85,86.02 134.48,86.02 v1(134.86,85.64) 135.4,85.1
PCH_PCIE_WAKE#: length 158.8
  TOP w0.081: 153.82,59.41 153.66,59.41 151.44,61.63 151.44,64.7 150.65,65.49 149.52,65.49 149.11,65.9 148.82,65.9 148.56,66.16 148.56,66.62 148.07,67.11 v2(148.07,67.4)
  TOP w0.102: 153.82,59.41 v1(154.33,59.41) 154.36,59.41 158.17,55.61 RPC1.5 ; v2(243.57,57.19) 243.66,57.28 UE2.A44 ; RE274.2 229.08,57.87 v2(229.22,58.01)
  IN1 w0.084: v2(148.07,67.4) 148.07,67.09 147.81,66.83 147.81,66.3 147.38,65.87 147.38,62.62 148.56,61.44 149.85,61.44 151,62.59 153.53,62.59 156.74,65.8 159.47,65.8 162.47,62.8 162.47,61.84 164.2,60.11 167.01,60.11 169.37,57.75 172.49,57.75 172.76,57.47 178.97,57.47 182.22,54.22 182.22,52.44 183.69,50.96 v2(184.58,50.96)
  IN4 w0.084: v2(184.58,50.96) 185.28,51.66 186.04,51.66 186.42,51.28 186.42,50.84 187.66,49.6 190.2,49.6 191.93,47.88 194.39,47.88 195.44,46.83 197.18,46.83 197.79,46.22 205.35,46.22 207.57,48.44 211.59,48.44 213.52,50.37 213.52,51.19 217.56,55.23 217.56,57.64 218.64,58.72 219.73,58.72 226.01,65.01 v2(228.33,65.01) 229.05,65.01 230.12,66.08 232.34,66.08 232.53,66.27 233.41,66.27 233.67,66.01 236.22,66.01 237,65.23 237,64.79 237.75,64.05 240.21,64.05 244.21,60.05 244.21,59.47 243.57,58.83 v2(243.57,57.19)
  BOTTOM w0.081: v2(148.07,67.4) 148.07,67.37 148.53,66.92 UC1.AJ5
  BOTTOM w0.102: v2(228.33,65.01) 228.14,64.81 228.14,62.2 229.6,60.74 229.6,58.39 v2(229.22,58.01)
PCH_PLTRST#: length 42.8
  TOP w0.102: RC88.2 RC87.2 RC219.2 RC89.2 ; RC88.2 CC104.1 169.63,79.69 v2(169.28,80.05) 168.85,80.48 UC5.2 168.85,81.43 168.71,81.57 168.39,81.57 168.2,81.38 UC5.1 ; RC88.2 v1(170.68,78.21)
  IN1 w0.084: v2(169.28,80.05) 167.04,77.81 160.77,77.81 160.09,77.13 157.79,77.13 157.59,76.94 151.24,76.94 150.99,77.19 149.66,77.19 148.9,76.43 146.74,76.43 146.29,75.98 146.29,69.06 146.55,68.81 147.19,68.81 v2(147.67,68.33)
  BOTTOM w0.081: v2(147.67,68.33) 147.67,68.33 147.67,68.23 UC1.AG7
PCH_PLTRST#_EC: length 417.5
  TOP w0.102: RC304.1 CC103.1 170.56,83.49 170.43,83.36 169.67,83.36 169.5,83.19 UC5.4 169.5,82.29 v2(170,81.78) ; RC106.1 72.23,55.56 75.02,52.76 75.02,49.67 72.77,47.42 72.77,43.04 70.4,40.66 64.36,40.66 63.17,39.47 v1(63.17,39.09) v2(63.17,38.54) ; v2(238.8,61.77) 238.8,61.6 238.56,61.35 UE2.B30 ; UE1.B22 225.09,50.9 v2(225.41,51.22) ; v2(13.59,16.78) 12.78,16.78 12.46,16.46 JLPDE1.8 ; v2(186.55,45.57) 189.85,45.57 193.3,49.02 UZ1.16
  IN1 w0.084: v2(202.81,20.93) 203.19,21.31 203.19,27.62 196.23,34.58 194.9,34.58 188.54,40.94 188.54,42.96 186.55,44.95 v2(186.55,45.57)
  IN3 w0.122: v2(35.43,17.53) 36.3,17.53 37.02,18.25 42.06,18.25 44.02,20.21 44.89,20.21 46.06,21.37 46.94,21.37 47.23,21.67 47.23,22.11 v2(46.86,22.48)
  IN4 w0.084: v2(238.8,61.77) 238.38,61.35 237.71,61.35 236.46,60.11 235.62,60.11 235.04,59.53 230.73,59.53 229.33,60.93 227.07,60.93 225.26,59.11 225.26,58.33 223.36,56.43 223.36,53.53 225.41,51.48 v2(225.41,51.22) 224.59,51.22 223.26,52.55 221.98,52.55 220.57,51.13 220.57,49.36 219.8,48.59 218.9,48.59 218.75,48.74 217.45,48.74 214.66,45.95 214.01,45.95 211.35,43.29 207.28,43.29 206.02,42.04 201.13,42.04 200.7,42.47 194.66,42.47 193.63,43.49 188.62,43.49 v2(186.55,45.57) 186.55,46.65 185.74,47.46 185.74,48.66 185.47,48.93 183.76,48.93 183.19,49.5 183.19,52.62 183.69,53.12 183.69,55.11 179.84,58.97 179.84,60.61 177.09,63.35 177.09,68.08 175.99,69.17 175.99,77.59 174.68,78.91 174.68,81.64 174.3,82.02 170.23,82.02 v2(170,81.78) ; v2(214.95,17.48) 214.24,18.19 207.33,18.19 205.73,19.79 203.95,19.79 v2(202.81,20.93) ; v2(35.43,17.53) 30.82,17.53 29.07,15.77 18.74,15.77 17.73,16.78 v2(13.59,16.78)
  BOTTOM w0.102: JNGFF1.44 215.33,17.1 v2(214.95,17.48) 214.27,16.81 214.27,13.61 214.38,13.51 215.04,13.51 215.13,13.6 JNGFF1.58 ; JNGFF2.42 224.89,49.9 225.29,50.29 225.29,51.1 v2(225.41,51.22) ; v2(186.55,45.57) 184.71,45.57 180.02,40.87 77.36,40.87 75.02,38.54 v2(63.17,38.54) 56.18,38.54 54.43,36.79 54.43,30.22 56.57,28.09 56.57,27.22 55.99,26.64 51.11,26.64 47.87,23.41 46.98,23.41 46.66,23.09 46.66,22.68 v2(46.86,22.48) 47.09,22.25 JMINI3.17
PCH_RSMRST#: length 13.3
  TOP w0.102: UZ6.1 250.91,54.42 249.94,53.44 v1(248.59,53.44) 246.9,53.44 245.86,54.48 243.88,54.48 243.64,54.72 243.64,55.36 242.91,56.08 RE88.1 243.24,56.16 243.38,56.02 243.83,56.02 244.16,56.35 UE2.A45
PCH_RSMRST#_Q: length 148.1
  TOP w0.102: UZ6.4 v2(253.98,53.12) ; RC91.2 147.75,56.37 147.75,57.95 v1(148.21,58.41) 148.21,58.66 v2(147.83,59.04)
  IN2 w0.122: v2(253.98,53.12) 253.03,53.12 252.72,52.81 252.72,51.85 252.08,51.22 250.85,51.22 249.29,49.66 249.29,48.9 247.17,46.78 247.17,32.8 245.9,31.53 218.43,31.53 216.62,29.73 212.48,29.73 210.67,31.55 205.58,31.55 204.63,32.5 198.47,32.5 197.97,33 194.64,33 193.4,34.24 166.62,34.24 154.73,46.13 154.73,51.92 154.2,52.45 154.2,54.1 153.85,54.45 152.71,54.45 150.86,56.3 150.04,56.3 147.83,58.51 v2(147.83,59.04)
  BOTTOM w0.076: v2(147.83,59.04) 147.42,59.45 147.42,59.79 147.58,59.95 147.58,60.51 UC1.AW6
PCH_RTCRST#: length 182.8
  TOP w0.102: JAPS1.9 v3(33.35,40.32) 33.72,39.95 v2(37.96,39.95)
  IN4 w0.084: v2(167.88,51.47) 167.1,52.25 159.97,52.25 151.29,60.93 148.27,60.93 v2(147.49,61.71)
  BOTTOM w0.081: UC1.AU7 147.11,62.1 147.49,61.72 v2(147.49,61.71)
  BOTTOM w0.102: CMOS1.2 167.06,59.23 CC4.2 RC8.2 169.9,58.98 170.68,58.2 170.68,52.43 169.28,51.03 168.33,51.03 v2(167.88,51.47) 165.49,51.47 163.07,49.06 155.58,49.06 153.44,46.91 71.2,46.91 69.53,48.59 65.49,48.59 61.68,44.78 53.2,44.78 52.88,44.46 41.24,44.46 37.96,41.19 v2(37.96,39.95)
PCH_RTCX1: length 21.3
  BOTTOM w0.076: UC1.AW5 148.98,60.44 148.98,59.45 149.33,59.1 151.6,59.1 152.31,58.39 153.82,58.39
  BOTTOM w0.102: RC7.1 RC4.2 164.05,55.96 v1(163.38,55.29) 162.73,54.64 157.45,54.64 155.98,56.1 155.98,56.88 154.47,58.39 153.82,58.39
PCH_RTCX1_R: length 2.7
  BOTTOM w0.102: YC1.1 163.6,57.83 163.14,57.37 CC1.2 RC4.1
PCH_RTCX2: length 24.5
  BOTTOM w0.076: 153.82,57.81 152.94,57.81 152.67,58.08 152.33,58.08 151.47,58.93 149.25,58.93 148.8,59.37 148.8,60 UC1.AY5
  BOTTOM w0.102: 153.82,57.81 154.36,57.81 155.45,56.73 155.45,55.95 157.32,54.08 162.98,54.08 164.22,55.32 v1(165.27,55.32) 165.36,55.32 RC7.2 CC2.2 166.1,57.42 YC1.2
PCH_SMB_ALERT#: length 9.4
  BOTTOM w0.076: UC1.AN2 151.05,64.77 151.96,64.77 152.78,65.59 152.78,66.14 152.97,66.33 153.31,66.33 153.5,66.52 153.82,66.52
  BOTTOM w0.102: RPC19.2 157.41,68.24 156.31,67.14 155.74,67.14 155.12,66.52 153.82,66.52
PCH_SPI_CLK: length 61.1
  TOP w0.102: RZ26.1 v2(191.3,53.38)
  IN1 w0.084: v2(150.29,71.42) 150.49,71.42 151.75,72.68 152.96,72.68 153.46,72.18 156.19,72.18 157.69,73.68 162.58,73.68 163.29,74.4 164.52,74.4 164.9,74.02 171.56,74.02 172.12,73.46 v2(172.36,73.46) 173.22,73.46 173.77,74.02 175.12,74.02 175.74,73.4 177.11,73.4 v2(177.49,73.02)
  IN4 w0.084: v2(177.49,73.02) 178.83,71.68 178.83,68.89 178.59,68.66 178.59,63.72 181.16,61.15 181.16,59.52 185.25,55.42 185.41,55.42 185.96,54.87 187.09,54.87 188.07,53.89 188.76,53.89 189.59,53.06 190.98,53.06 v2(191.3,53.38)
  BOTTOM w0.081: v2(150.29,71.42) 149.96,71.1 UC1.AA3
  BOTTOM w0.102: v2(172.36,73.46) 172.7,73.13 RC227.2 ; JSPI1.8 v2(177.49,73.02)
PCH_SPI_CS0#: length 35.3
  IN1 w0.084: v2(177.47,74.02) 177,74.49 175.77,74.49 175.37,74.89 173.99,74.89 173.14,74.04 v2(172.26,74.04) 171.76,74.54 165.19,74.54 164.79,74.94 163.18,74.94 162.39,74.15 156.96,74.15 156.45,73.63 150.58,73.63 149.21,72.26 149.21,71.92 148.99,71.7 148.04,71.7 v2(147.56,71.22)
  BOTTOM w0.081: v2(147.56,71.22) 147.31,71.48 UC1.Y7
  BOTTOM w0.102: JSPI1.10 v2(177.47,74.02) ; RC228.2 172.99,74.04 v2(172.26,74.04)
PCH_SPI_CS1#: length 38.5
  IN1 w0.084: v2(148.84,71.23) 148.84,70.7 149.28,70.27 151.24,70.27 151.69,70.71 158.12,70.71 158.78,71.37 164,71.37 164.96,70.42 167.06,70.42 167.9,69.57 170.19,69.57 170.31,69.7 170.31,70.46 170.44,70.58 170.68,70.58 170.8,70.46 170.8,69.44 170.93,69.32 171.17,69.32 171.29,69.44 171.29,70.35 171.42,70.48 171.66,70.48 171.78,70.35 171.78,69.44 171.91,69.32 172.28,69.32 172.4,69.44 v2(172.4,70.37) 173.05,70.37 173.18,70.24 177.13,70.24 v2(177.47,70.58)
  BOTTOM w0.081: UC1.Y4 149.29,71.68 v2(148.84,71.23)
  BOTTOM w0.102: v2(172.4,70.37) 172.92,70.37 RC224.2 ; JSPI1.2 178.03,70.02 v2(177.47,70.58)
PCH_SPI_CS2#: length 68
  TOP w0.102: RZ17.1 189.46,53.52 189.04,53.93 187.71,53.93 187.55,53.78 186.82,53.78 185.98,52.94 185.98,52.23 185.03,51.28 185.03,49.95 184.6,49.52 182.37,49.52 179.57,46.71 174.56,46.71 v1(173.76,47.51) v2(172.97,48.3)
  IN4 w0.084: v2(150.31,70.69) 150.46,70.69 152.44,72.68 153.51,72.68 153.89,73.05 155.33,73.05 156.86,71.53 159.77,71.53 160.12,71.88 160.12,72.95 160.39,73.22 161.93,73.22 162.27,72.88 162.27,71.72 162.43,71.55 163.91,71.55 164.82,70.65 164.82,67.07 165.45,66.43 166.09,66.43 166.76,65.76 166.76,58.54 167.52,57.79 167.52,56.13 170.97,52.67 170.97,50.29 v2(172.97,48.3)
  BOTTOM w0.081: v2(150.31,70.69) 150.59,70.4 UC1.AC2
PCH_SPI_CS2#_R: length 1.9
  TOP w0.102: RZ17.2 189.4,51.79 UZ1.22
PCH_SPI_DIN: length 56.7
  TOP w0.102: RZ30.1 186.66,53.05 v2(186.99,53.37)
  IN1 w0.084: v2(177.43,72.02) 176.92,72.53 v2(172.34,72.53) 170.87,72.53 170.36,73.04 162.44,73.04 162.26,73.22 157.88,73.22 156.33,71.67 153.34,71.67 152.58,72.43 151.94,72.43 150.57,71.05 149.89,71.05 v2(149.52,70.69)
  IN4 w0.084: v2(186.99,53.37) 185.82,53.37 184.85,54.35 184.85,55.17 180.69,59.32 180.69,60.96 177.94,63.71 177.94,71.51 v2(177.43,72.02)
  BOTTOM w0.081: UC1.AA4 149.29,70.91 v2(149.52,70.69)
  BOTTOM w0.102: JSPI1.6 v2(177.43,72.02) ; RC226.2 172.71,72.53 v2(172.34,72.53)
PCH_SPI_DO: length 58.6
  TOP w0.102: RZ29.1 v2(188.57,53.43)
  IN1 w0.084: v2(177.47,71.22) 176.45,71.22 175.94,70.71 174.43,70.71 174,71.14 v2(172.4,71.14) 170.34,71.14 169.79,70.59 168.37,70.59 168.07,70.88 165.15,70.88 164.2,71.84 163.64,71.84 162.9,72.58 162.44,72.58 161.7,71.84 158.59,71.84 157.95,71.2 152.79,71.2 152.53,71.46 v2(152.53,71.89)
  IN4 w0.084: v2(188.57,53.43) 188.57,53.43 188.05,52.91 185.63,52.91 184.38,54.15 184.38,54.97 180.23,59.13 180.23,60.77 177.48,63.51 177.48,68.24 176.38,69.34 176.38,70.9 176.7,71.22 v2(177.47,71.22)
  BOTTOM w0.081: v2(152.53,71.89) 152.22,71.58 151.54,71.58 151.32,71.36 151.13,71.36 150.99,71.36 150.95,71.32
  BOTTOM w0.084: 150.95,71.32 150.69,71.06 UC1.AA2
  BOTTOM w0.102: RC225.2 172.8,71.14 v2(172.4,71.14) ; JSPI1.4 177.67,71.02 v2(177.47,71.22)
PCH_SPI_DO2: length 36.5
  IN1 w0.076: 150.12,73.63 151.27,74.79 153.53,74.79 153.79,74.52
  IN1 w0.084: v2(177.42,75.02) 177,75.44 176.02,75.44 175.63,75.84 173.22,75.84 172.93,75.55 171.65,75.55 v2(171.25,75.95) 170.66,76.54 164.83,76.54 163.7,75.41 162.99,75.41 162.19,74.61 156.77,74.61 156.26,74.1 154.22,74.1 153.79,74.52 ; v2(148.26,72.11) 148.68,72.53 149.21,72.53 150.12,73.44 150.12,73.63
  BOTTOM w0.081: v2(148.26,72.11) 148.26,71.98 UC1.Y6
  BOTTOM w0.102: RC229.2 172.61,75.44 171.77,75.44 v2(171.25,75.95) ; JSPI1.12 v2(177.42,75.02)
PCH_SPI_DO3: length 43.2
  IN1 w0.084: v2(152.36,69.46) 152.76,69.87 154.06,69.87 154.88,69.05 157.11,69.05 158.97,70.91 163.81,70.91 164.76,69.95 166.86,69.95 168.11,68.71 176.53,68.71 178.11,70.29 178.11,75.4 v2(177.49,76.02) 177.19,76.32 172.69,76.32 v2(172.39,76.02)
  BOTTOM w0.076: v2(152.36,69.46) 151.84,68.94 151.37,68.94 UC1.AF1
  BOTTOM w0.102: JSPI1.14 v2(177.49,76.02) ; RC230.2 172.49,75.92 v2(172.39,76.02)
PCI_CLK_LPC_0: length 14.2
  TOP w0.102: RC74.1 RC72.1 140.86,52.85 141.19,53.17 141.19,56.39 v1(141.02,56.55) 141.02,59.19 141.43,59.6 141.43,62.82 v2(142.68,64.07)
  BOTTOM w0.081: UC1.AN15 142.99,64.38 v2(142.68,64.07)
PCI_CLK_LPC_1: length 13.8
  TOP w0.102: RC70.1 RC67.1 143.46,52.63 143.46,54.77 144.13,55.45 v1(144.13,55.83) 144.13,58.14 143.59,58.68 143.59,62.52 142.68,63.43 v2(142.67,63.43)
  BOTTOM w0.081: UC1.AP15 142.97,63.73 v2(142.67,63.43)
PCIE_PRX_GLANTX_N3: length 114.7
  TOP w0.102: v2(165.38,86.84) 165.22,87.01 164.97,87.01 164.74,87.24 164.74,88.02 165.1,88.38 167.31,88.38 173.76,94.83 178.98,94.83 181.34,97.19 182.33,97.19 182.59,97.45 182.59,97.96 v2(182.51,98.03) ; CL2.2 239.75,93.85 240.02,94.12 240.02,94.58 v2(239.93,94.67)
  IN1 w0.091: v2(144.41,79.29) 144.6,79.48 144.83,79.48 145.01,79.65 145.01,80.67 145.42,81.08 146.06,81.08 148.09,83.11 154.03,83.11 156.54,80.6 159.58,80.6 161.72,82.75 161.72,84 163.85,86.13 164.19,86.13 165.09,87.04 165.19,87.04 v2(165.38,86.84) ; v2(182.51,98.03) 182.72,97.83 182.72,97.37 182.91,97.18 184.72,97.18 185.89,96.01 203.9,96.01 204.32,96.43 204.99,96.43 206.84,98.28 230.37,98.28 232.11,96.54 238.92,96.54 239.93,95.54 v2(239.93,94.67)
  BOTTOM w0.081: v2(144.41,79.29) 144.83,78.87 UC1.G11
PCIE_PRX_GLANTX_N3_C: length 2.9
  TOP w0.102: CL2.1 240.12,92.56 240.12,92.46 239.99,92.33 239.8,92.33 239.18,91.71 239.18,91.5 239.09,91.41 UL1.39
PCIE_PRX_GLANTX_P3: length 114.7
  TOP w0.102: CL1.2 240.64,93.85 240.23,94.26 240.23,94.39 v2(240.51,94.67) ; v2(165.38,87.43) 165.18,87.22 165.06,87.22 164.96,87.32 164.96,87.93 165.19,88.16 167.4,88.16 173.85,94.61 179.07,94.61 181.43,96.98 182.42,96.98 182.8,97.36 182.8,97.74 v2(183.1,98.03)
  IN1 w0.091: v2(165.38,87.43) 165.17,87.21 165.02,87.21 164.11,86.3 163.78,86.3 161.55,84.07 161.55,82.82 159.51,80.78 156.61,80.78 154.1,83.29 148.02,83.29 145.98,81.25 145.35,81.25 144.84,80.74 144.84,79.73 144.76,79.65 144.6,79.65 v2(144.41,79.83) ; v2(240.51,94.67) 240.1,95.08 240.1,95.61 239,96.72 232.18,96.72 230.44,98.45 206.77,98.45 204.92,96.6 204.25,96.6 203.83,96.18 185.96,96.18 184.79,97.35 182.98,97.35 182.89,97.44 182.89,97.82 v2(183.1,98.03)
  BOTTOM w0.081: UC1.F11 144.74,79.51 v2(144.41,79.83)
PCIE_PRX_GLANTX_P3_C: length 2.9
  TOP w0.102: CL1.1 240.34,92.63 240.34,92.37 240.08,92.11 239.91,92.11 v4(239.71,91.91) 239.4,91.6 239.4,91.5 239.49,91.41 UL1.38
PCIE_PRX_MMITX_N1: length 174.5
  TOP w0.102: v2(251.88,15.95) 252.07,16.13 252.54,16.13 CR27.1
  IN4 w0.091: v2(251.88,15.95) 251.66,16.17 250.88,16.17 250.09,16.95 250.09,26.7 248.09,28.7 248.09,40.95 243.14,45.9 240.09,45.9 239.77,45.58 236.48,45.58 235.65,46.41 232.07,46.41 231.74,46.74 227.43,46.74 226.88,47.28 224.6,47.28 224.44,47.12 221.94,47.12 219.32,44.51 217.97,44.51 214.2,40.73 209.22,40.73 206.08,37.59 204.47,37.59 203.29,36.41 188.41,36.41 176.6,48.22 176.6,53.54 171.24,58.9 171.24,66.11 169.31,68.05 169.31,70.57 168.35,71.53 167.9,71.53 167.56,71.87 167.56,73.64 165.58,75.62 165.13,75.62 163.58,77.17 161.09,77.17 160.95,77.03 158.77,77.03 158.11,77.69 156.36,77.69 151.95,82.1 150.21,82.1 149.72,82.59 143.63,82.59 142.02,80.98 142.02,79.65 141.8,79.42 141.53,79.42 141.47,79.37 v2(141.47,79.09)
  BOTTOM w0.081: UC1.G17 141.98,79.03 141.84,79.16 141.54,79.16 v2(141.47,79.09)
PCIE_PRX_MMITX_N1_C: length 4.5
  TOP w0.102: CR27.2 254.13,16.13 254.35,16.13 254.65,16.42 254.67,16.42 v4(254.87,16.62) 255.05,16.81 255.05,16.83 255.3,17.07 255.88,17.07 256.29,16.66 256.94,16.66 257.07,16.53 UR1.8
PCIE_PRX_MMITX_P1: length 174.4
  TOP w0.102: v2(251.88,16.53) 252.07,16.34 252.54,16.34 CR26.1
  IN4 w0.091: v2(141.47,79.92) 141.47,79.66 141.54,79.59 141.73,79.59 141.85,79.72 141.85,81.05 143.56,82.76 149.79,82.76 150.28,82.27 152.02,82.27 156.43,77.86 158.18,77.86 158.84,77.2 160.88,77.2 161.01,77.34 163.66,77.34 165.2,75.79 165.65,75.79 167.74,73.71 167.74,71.94 167.97,71.7 168.42,71.7 169.48,70.64 169.48,68.12 171.42,66.18 171.42,58.97 176.77,53.62 176.77,48.3 188.48,36.58 203.22,36.58 204.4,37.76 206,37.76 209.14,40.9 214.13,40.9 217.9,44.68 219.25,44.68 221.87,47.29 224.37,47.29 224.53,47.45 226.95,47.45 227.5,46.91 231.82,46.91 232.14,46.58 235.72,46.58 236.55,45.76 239.7,45.76 240.02,46.08 243.21,46.08 248.26,41.02 248.26,28.78 250.27,26.77 250.27,17.02 250.95,16.34 251.69,16.34 v2(251.88,16.53)
  BOTTOM w0.081: UC1.F17 141.84,79.51 141.47,79.87 v2(141.47,79.92)
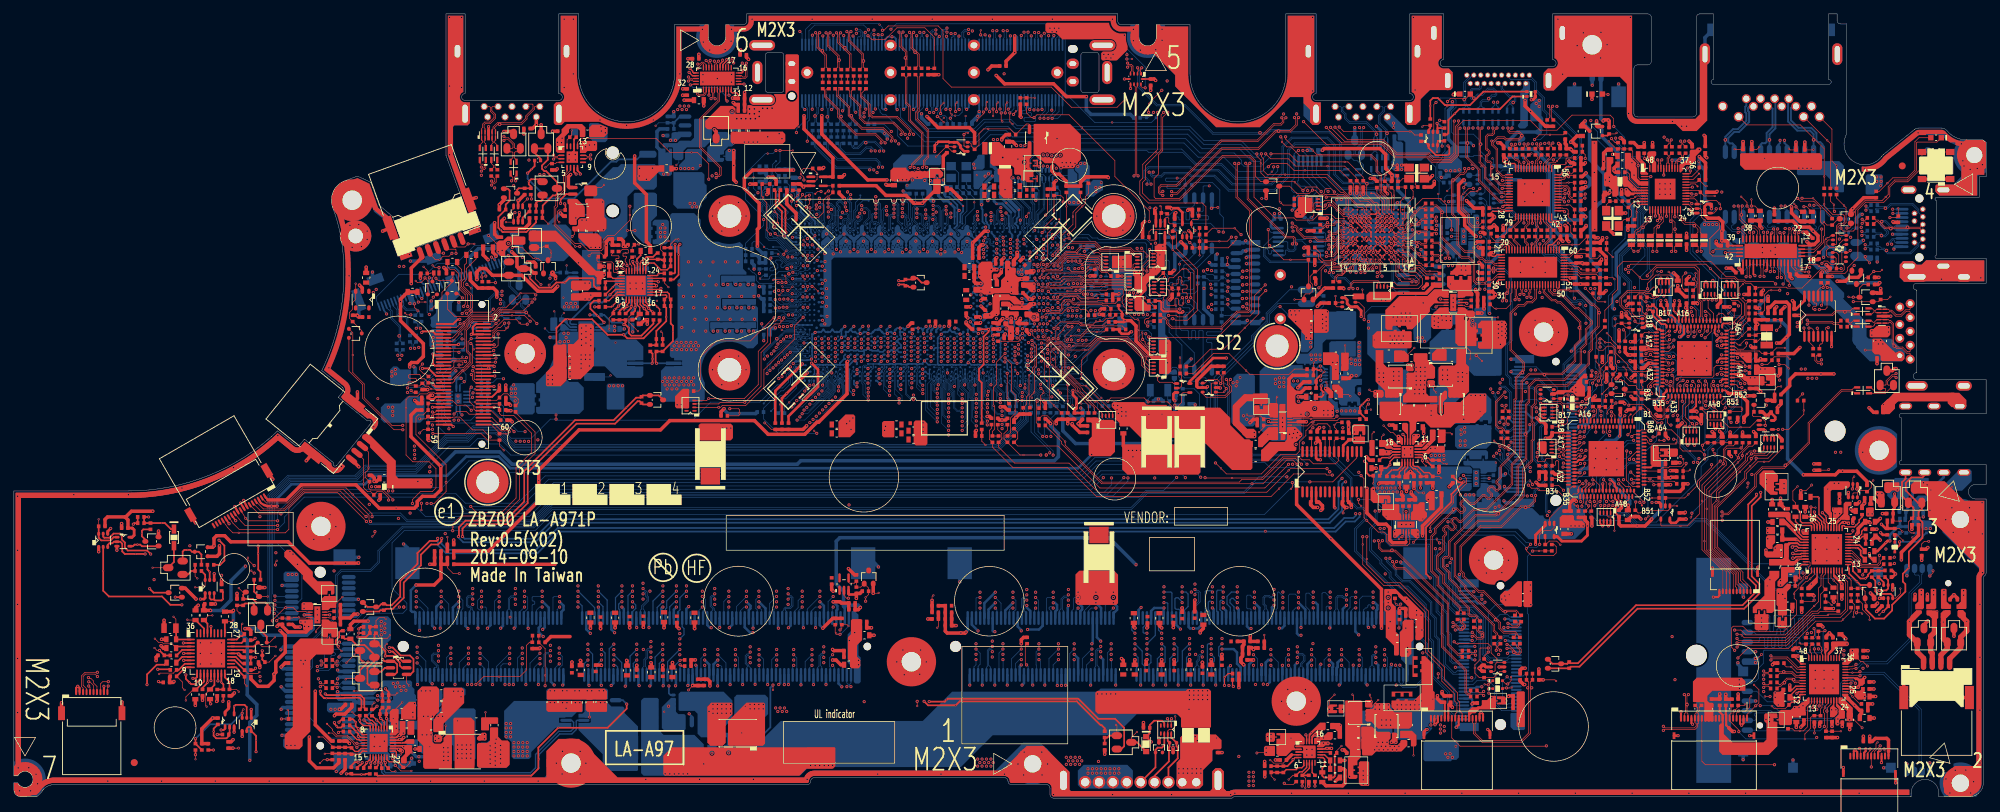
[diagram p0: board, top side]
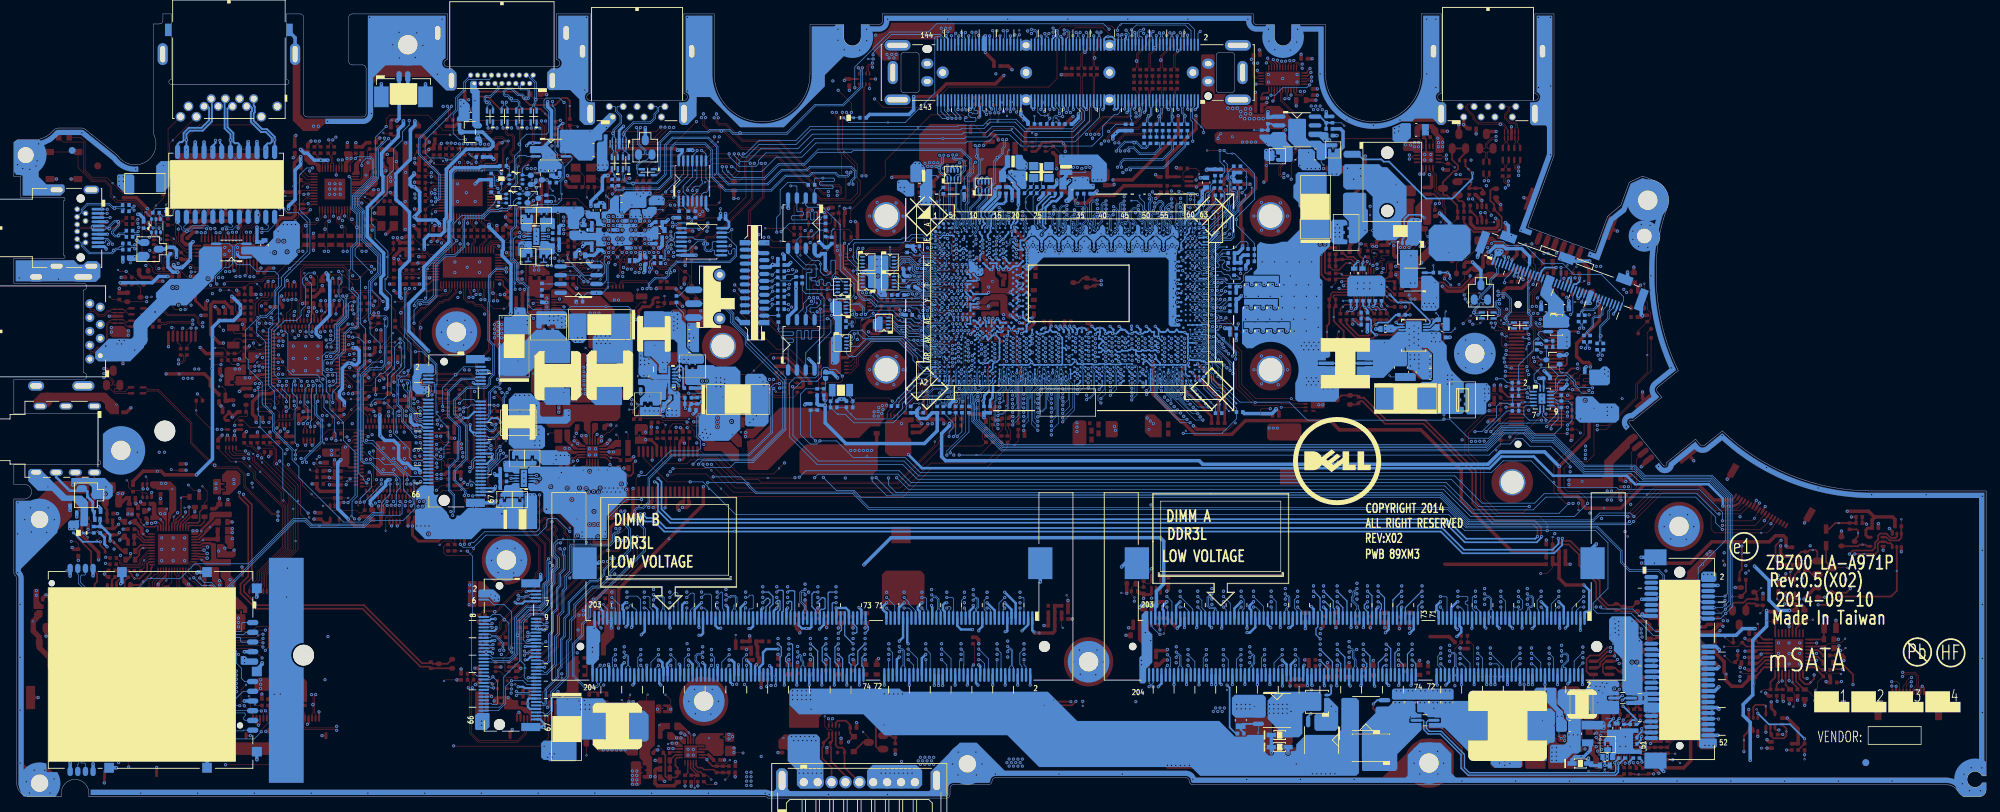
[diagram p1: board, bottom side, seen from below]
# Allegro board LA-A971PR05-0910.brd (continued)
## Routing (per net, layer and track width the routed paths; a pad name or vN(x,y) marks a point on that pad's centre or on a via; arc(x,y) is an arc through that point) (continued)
PCIE_PRX_MMITX_P1_C: length 4.5
  TOP w0.102: UR1.7 257.07,16.93 257.02,16.87 256.4,16.87 v4(256.2,17.07) 255.99,17.28 255.21,17.28 254.7,16.78 254.26,16.34 254.14,16.34 CR26.2
PCIE_PRX_SATATX_N6_L0: length 94.9
  IN1 w0.091: v2(212.9,58.43) 212.94,58.39 213.09,58.39 213.28,58.58 213.28,58.8 213,59.07 213,60.13 214.19,61.32 214.19,63.21 212.27,65.13 212.27,67.28 208.33,71.22 208.33,71.48 207.19,72.61 205.52,72.61 203.27,74.86 200.72,74.86 198.47,72.62 193.95,72.62 193.73,72.84 190.23,72.84 187.53,75.54 186.62,75.54 181.82,80.34 178.97,80.34 177.12,82.19 165.91,82.19 164.76,81.04 162.76,81.04 160.38,78.67 154.99,78.67 154.1,79.56 152.81,79.56 152.31,80.07 148.55,80.07 v2(148.24,79.76)
  BOTTOM w0.081: v2(148.24,79.76) 148.39,79.76 UC1.F5
  BOTTOM w0.102: v2(212.9,58.43) 213.07,58.26 213.07,57.86 213.28,57.65 213.28,53.21 214.78,51.71 215.67,51.71 215.72,51.65 JNGFF2.35
PCIE_PRX_SATATX_N6_L1: length 98.3
  IN1 w0.091: v2(147.21,77.92) 147.21,77.97 147.44,78.2 147.65,78.2 147.82,78.37 147.82,80.68 148.08,80.94 148.59,80.94 149.35,81.71 153.31,81.71 155.7,79.31 160.11,79.31 162.49,81.69 164.5,81.69 165.64,82.83 177.8,82.83 179.38,81.25 181.82,81.25 186.89,76.18 187.8,76.18 190.13,73.85 193.63,73.85 194.22,73.27 198.21,73.27 200.45,75.51 203.54,75.51 205.79,73.26 207.75,73.26 209.77,71.24 211.67,71.24 213.11,69.8 213.11,65.31 214.93,63.49 214.93,59.78 214.57,59.41 213.88,59.41 213.8,59.49 213.8,59.71 v2(213.93,59.84)
  BOTTOM w0.081: UC1.J6 147.57,77.56 v2(147.21,77.92)
  BOTTOM w0.102: v2(213.93,59.84) 213.93,59.53 214.1,59.36 214.67,59.36 215.53,58.5 215.53,55.44 215.82,55.15 JNGFF2.21
PCIE_PRX_SATATX_P6_L0: length 95
  IN1 w0.091: v2(213.66,58.43) 213.45,58.64 213.45,58.87 213.17,59.15 213.17,60.06 214.36,61.25 214.36,63.28 212.44,65.21 212.44,67.36 208.5,71.29 208.5,71.55 207.26,72.79 205.59,72.79 203.34,75.04 200.65,75.04 198.4,72.79 194.02,72.79 193.8,73.01 190.3,73.01 187.6,75.71 186.7,75.71 181.89,80.51 179.04,80.51 177.19,82.36 165.83,82.36 164.69,81.22 162.69,81.22 160.31,78.84 155.06,78.84 154.17,79.73 152.89,79.73 152.38,80.24 148.52,80.24 v2(148.24,80.52)
  BOTTOM w0.081: UC1.E5 148.6,80.16 v2(148.24,80.52)
  BOTTOM w0.102: v2(213.66,58.43) 213.41,58.43 213.28,58.31 213.28,57.95 213.49,57.74 213.49,53.3 214.87,51.92 215.59,51.92 215.63,51.97 215.63,52.08 215.7,52.15 JNGFF2.33
PCIE_PRX_SATATX_P6_L1: length 98.3
  IN1 w0.091: v2(213.93,58.98) 214.18,59.24 214.64,59.24 215.11,59.7 215.11,63.56 213.28,65.39 213.28,69.87 211.74,71.41 209.84,71.41 207.83,73.43 205.86,73.43 203.61,75.68 200.38,75.68 198.14,73.44 194.29,73.44 193.7,74.02 190.2,74.02 187.87,76.36 186.96,76.36 181.89,81.43 179.45,81.43 177.87,83 165.57,83 164.42,81.86 162.42,81.86 160.04,79.49 155.77,79.49 153.38,81.88 149.28,81.88 148.51,81.12 148.01,81.12 147.65,80.75 147.65,78.45 147.57,78.37 147.39,78.37 v2(147.21,78.55)
  BOTTOM w0.081: v2(147.21,78.55) 147.56,78.21 UC1.H6
  BOTTOM w0.102: v2(213.93,58.98) 214.09,59.14 214.58,59.14 215.31,58.41 215.31,55.35 215.62,55.04 215.62,54.79 215.76,54.65 JNGFF2.23
PCIE_PRX_WIGIGTX_N5: length 111
  IN4 w0.091: v2(145.42,79.86) 145.74,80.19 145.93,80.19 146.62,80.89 148.5,80.89 148.77,80.62 148.77,79.22 149.28,78.71 150.3,78.71 150.82,78.2 150.82,77.36 151.45,76.73 154.02,76.73 154.35,76.4 157.22,76.4 158.98,74.64 159.76,74.64 160.04,74.92 163.68,74.92 165.49,73.12 165.49,71.92 166.8,70.6 166.89,70.6 167.91,69.59 167.91,67.62 169.95,65.58 169.95,58.36 175.31,53.01 175.31,47.69 187.88,35.12 197.83,35.12 197.91,35.04 197.91,34.97 v2(197.5,34.56)
  BOTTOM w0.076: v2(145.42,79.86) 145.77,79.51 UC1.F10
  BOTTOM w0.102: v2(197.5,34.56) 197.56,34.5 197.56,34.08 198.84,32.8 198.84,32.15 199.83,31.16 200.9,31.16 203.9,28.16 203.9,26.5 204.53,25.86 204.53,23.29 205,22.82 205,18.84 205.45,18.39 205.45,17.41 207.23,15.63 207.23,13.59 207.46,13.35 JNGFF1.59
PCIE_PRX_WIGIGTX_P5: length 111.1
  IN4 w0.091: v2(145.37,80.52) 145.53,80.37 145.85,80.37 146.55,81.06 148.57,81.06 148.94,80.69 148.94,79.29 149.35,78.89 150.37,78.89 150.99,78.27 150.99,77.43 151.52,76.9 154.09,76.9 154.42,76.57 157.29,76.57 159.06,74.81 159.69,74.81 159.97,75.09 163.75,75.09 165.66,73.19 165.66,71.99 166.87,70.78 166.96,70.78 168.08,69.66 168.08,67.69 170.13,65.65 170.13,58.43 175.48,53.08 175.48,47.76 187.95,35.29 197.91,35.29 198.08,35.12 v2(198.08,34.56)
  BOTTOM w0.081: v2(145.37,80.52) 145.43,80.52 UC1.E10
  BOTTOM w0.102: JNGFF1.57 207.91,13.85 207.82,13.76 207.82,13.69 207.7,13.57 207.63,13.57 207.63,13.57 207.55,13.57 207.44,13.68 207.44,15.72 205.66,17.5 205.66,18.48 205.22,18.93 205.22,22.91 204.75,23.38 204.75,25.95 204.11,26.59 204.11,28.25 200.99,31.37 199.92,31.37 199.06,32.24 199.06,32.89 197.78,34.17 197.78,34.26 198.07,34.56 v2(198.08,34.56)
PCIE_PRX_WLANTX_N4: length 114.1
  IN4 w0.091: v2(204.62,35.94) 204.7,35.94 205.05,35.59 205.05,35.5 204.74,35.2 199.12,35.2 198.39,35.94 188.22,35.94 176.13,48.03 176.13,53.35 170.77,58.7 170.77,65.92 168.84,67.85 168.84,70.37 168.15,71.06 167.66,71.06 167,71.72 167,72.89 163.19,76.69 161.43,76.69 160.65,75.92 158.86,75.92 157.56,77.22 155.03,77.22 153.59,78.65 153.59,79.35 152.66,80.28 151.25,80.28 149.77,81.76 148.63,81.76 148.33,82.06 146.54,82.06 145.65,81.17 144.38,81.17 143.83,80.63 143.83,79.67 143.76,79.6 143.56,79.6 143.44,79.72 v2(143.44,79.9)
  BOTTOM w0.081: UC1.F13 143.81,79.51 143.44,79.87 v2(143.44,79.9)
  BOTTOM w0.102: v2(204.62,35.94) 204.7,35.86 204.7,35.13 204.56,34.99 204.56,32.9 205.2,32.26 205.2,30.59 205.6,30.19 205.6,27.2 206.24,26.57 206.24,24 206.71,23.53 206.71,19.76 207.12,19.35 JNGFF1.35
PCIE_PRX_WLANTX_P4: length 114.1
  IN4 w0.091: v2(205.28,35.94) 205.22,35.88 205.22,35.43 204.81,35.03 199.05,35.03 198.31,35.76 188.14,35.76 175.95,47.96 175.95,53.28 170.6,58.63 170.6,65.84 168.66,67.78 168.66,70.3 168.08,70.88 167.58,70.88 166.82,71.65 166.82,72.82 163.12,76.52 161.5,76.52 160.72,75.75 158.79,75.75 157.49,77.05 154.95,77.05 153.42,78.58 153.42,79.28 152.59,80.11 151.18,80.11 149.7,81.59 148.56,81.59 148.26,81.89 146.61,81.89 145.72,81 144.45,81 144.01,80.56 144.01,79.6 143.83,79.43 143.6,79.43 143.46,79.29 v2(143.46,79.22)
  BOTTOM w0.081: UC1.G13 143.88,78.86 143.88,78.91 143.56,79.22 v2(143.46,79.22)
  BOTTOM w0.102: JNGFF1.33 207.82,19.85 207.74,19.76 207.74,19.62 207.68,19.57 207.21,19.57 206.92,19.85 206.92,23.62 206.45,24.09 206.45,26.66 205.82,27.29 205.82,30.28 205.42,30.68 205.42,32.35 204.77,32.99 204.77,34.9 204.92,35.04 204.92,35.57 v2(205.28,35.94)
PCIE_PTX_GLANRX_N3: length 133.1
  TOP w0.102: CL6.1 238.27,94.34 238.27,94.57 v2(238,94.84) ; v2(184.93,98.06) 184.74,97.87 184.74,96.97 183.74,95.97 181.69,95.97 179.2,93.48 173.93,93.48 167.46,87.02 166.85,87.02 v2(166.65,86.82)
  IN1 w0.091: v2(134.19,84.71) 134.32,84.84 135.15,84.84 136.58,83.41 137.4,83.41 138.74,82.08 138.74,77.76 139.22,77.28 143.96,77.28 146.86,80.18 146.86,80.87 148.52,82.53 153.4,82.53 155.97,79.96 159.85,79.96 162.37,82.48 162.37,83.73 164.1,85.46 165.1,85.46 166.21,86.57 166.21,86.97 166.29,87.05 166.42,87.05 v2(166.65,86.82)
  IN4 w0.091: v2(184.93,98.06) 184.72,97.85 184.72,97.66 186.32,96.07 202.82,96.07 205.76,99 228.97,99 234.04,93.93 237.96,93.93 238.2,94.17 238.2,94.63 v2(238,94.84)
  BOTTOM w0.081: UC1.C29 133.88,81.48 133.78,81.57 133.78,81.92 133.74,81.96 133.74,84.53 133.92,84.71 v2(134.19,84.71)
PCIE_PTX_GLANRX_N3_C: length 2.5
  TOP w0.102: UL1.42 237.89,91.41 237.98,91.5 237.98,92.23 238.15,92.39 238.15,92.56 CL6.2
PCIE_PTX_GLANRX_P3: length 133.2
  TOP w0.102: v2(184.34,98.06) 184.53,97.87 184.53,97.06 183.65,96.19 181.6,96.19 179.11,93.7 173.84,93.7 167.37,87.24 166.82,87.24 v2(166.65,87.41) ; v2(238.58,94.84) 238.49,94.75 238.49,94.03 CL5.1
  IN1 w0.091: v2(134.19,85.26) 134.44,85.01 135.22,85.01 136.65,83.59 137.47,83.59 138.91,82.15 138.91,77.83 139.29,77.45 143.89,77.45 146.69,80.26 146.69,80.94 148.45,82.7 153.47,82.7 156.04,80.13 159.77,80.13 162.19,82.55 162.19,83.8 164.03,85.64 165.02,85.64 166.03,86.64 166.03,87.04 166.22,87.22 166.47,87.22 v2(166.65,87.41)
  IN4 w0.091: v2(184.34,98.06) 184.55,97.85 184.55,97.59 186.25,95.89 202.9,95.89 205.83,98.83 228.89,98.83 233.97,93.76 238.03,93.76 238.38,94.1 238.38,94.63 v2(238.58,94.84)
  BOTTOM w0.081: UC1.B30 133.55,81.89 133.55,84.61 v2(134.19,85.26)
PCIE_PTX_GLANRX_P3_C: length 2.4
  TOP w0.102: UL1.41 238.29,91.41 238.2,91.5 238.2,92.14 238.37,92.3 238.37,92.63 CL5.2
PCIE_PTX_MMIRX_N1: length 187.6
  TOP w0.102: v2(251.88,18.31) 252.07,18.12 252.54,18.12 CR25.1
  IN4 w0.091: v2(251.88,18.31) 251.69,18.12 251.48,18.12 251.38,18.21 251.38,24.15 251.11,24.43 251.11,27.95 248.91,30.16 248.91,41.29 243.41,46.79 236.53,46.79 236.09,47.23 233.89,47.23 233.41,47.7 231.33,47.7 230.53,48.5 226.95,48.5 226.6,48.85 224.86,48.85 224.86,48.85 221.65,48.85 218.56,45.76 217.86,45.76 215.51,43.41 213.94,43.41 212.07,41.55 208.79,41.55 206.63,39.39 205.34,39.39 204.69,40.04 199.45,40.04 197.8,38.4 196.39,38.4 196.12,38.67 188.31,38.67 179.16,47.81 179.16,53.02 178.52,53.66 178.52,54.47 176.13,56.87 175.34,56.87 173.29,58.93 173.29,60 172.71,60.58 172.71,66.72 170.77,68.65 170.77,71.4 170.62,71.55 170.62,72.64 168.83,74.43 168.83,75.08 166.75,77.17 165.65,77.17 164.19,78.63 161.42,78.63 160.89,79.15 156.96,79.15 152.26,83.86 150.55,83.86 149.85,84.56 146.36,84.56 145.91,85 143.82,85 142.74,86.08 141.7,86.08 141.11,86.67 139.65,86.67 138.66,85.68 138.09,85.68 137.64,85.24 135.9,85.24 135,86.13 133.93,86.13 133.46,85.67 133.46,84.31 132.88,83.73 132.7,83.73 v2(132.31,84.12)
  BOTTOM w0.081: UC1.C30 133.19,81.6 133.02,81.77 132.84,81.77 132.63,81.98 132.6,82.08 132.6,82.21 132.63,82.27 132.64,82.28 132.64,82.28 132.67,82.37 132.67,82.53 132.6,82.73 132.6,82.73 132.6,82.89 132.85,83.14 132.85,83.63 132.52,83.96 132.47,83.96 v2(132.31,84.12)
PCIE_PTX_MMIRX_N1_C: length 4.1
  TOP w0.102: UR1.5 257.07,17.73 256.99,17.64 256.56,17.64 256.01,18.2 v4(254.77,18.2) 254.06,18.2 CR25.2
PCIE_PTX_MMIRX_P1: length 187.5
  TOP w0.102: v2(251.88,17.72) 252.07,17.91 252.54,17.91 CR24.1
  IN4 w0.091: v2(251.88,17.72) 251.66,17.94 251.41,17.94 251.21,18.14 251.21,24.08 250.94,24.36 250.94,27.88 248.73,30.09 248.73,41.22 243.34,46.61 236.46,46.61 236.02,47.06 233.82,47.06 233.34,47.53 231.26,47.53 230.46,48.33 226.88,48.33 226.53,48.68 224.79,48.68 224.79,48.68 221.72,48.68 218.63,45.58 217.93,45.58 215.59,43.24 214.01,43.24 212.14,41.38 208.86,41.38 206.71,39.22 205.27,39.22 204.62,39.87 199.52,39.87 197.88,38.22 196.32,38.22 196.05,38.49 188.24,38.49 178.99,47.74 178.99,52.95 178.35,53.59 178.35,54.4 176.06,56.7 175.27,56.7 173.11,58.85 173.11,59.93 172.53,60.51 172.53,66.65 170.6,68.58 170.6,71.33 170.45,71.48 170.45,72.57 168.66,74.36 168.66,75.01 166.68,76.99 165.58,76.99 164.12,78.46 161.34,78.46 160.82,78.98 156.89,78.98 152.19,83.68 150.47,83.68 149.78,84.38 146.28,84.38 145.84,84.83 143.74,84.83 142.66,85.91 141.62,85.91 141.04,86.49 139.72,86.49 138.74,85.51 138.16,85.51 137.71,85.06 135.82,85.06 134.93,85.96 134,85.96 133.64,85.6 133.64,84.24 132.96,83.56 132.46,83.56 v2(132.29,83.39)
  BOTTOM w0.081: UC1.C31 132.58,81.75 132.48,81.9 132.44,82.06 132.44,82.24 132.45,82.28 132.45,82.28 132.5,82.4 132.5,82.5 132.44,82.67 132.44,82.67 132.41,82.76 132.41,82.98 132.66,83.23 132.66,83.55 132.44,83.76 132.06,83.76 132,83.71 132,83.48 132.09,83.39 v2(132.29,83.39)
PCIE_PTX_MMIRX_P1_C: length 4.2
  TOP w0.102: UR1.6 257.07,17.33 256.97,17.43 256.47,17.43 255.92,17.98 255.11,17.98 255.09,17.97 254.46,17.97 254.44,17.98 254.21,17.98 CR24.2
PCIE_PTX_SATARX_N6_L0: length 108
  TOP w0.102: v2(214.78,57.72) 214.52,57.99 214.4,57.99 213.47,57.06 213.47,53.76 213.77,53.47 214.21,53.47 214.57,53.11 214.57,52.93 214.74,52.76 CZ58.1
  IN1 w0.091: v2(214.78,57.72) 215.56,57.72 216.08,58.24 216.08,64.54 215.7,64.92 215.7,68.6 212.23,72.06 210.11,72.06 208.1,74.08 206.17,74.08 203.92,76.33 200.11,76.33 197.87,74.08 194.62,74.08 194.04,74.67 191.81,74.67 189.91,76.57 188.67,76.57 186.36,78.87 186.36,79.44 184.95,80.86 184.26,80.86 182.4,82.71 179.18,82.71 178.17,83.73 171.35,83.73 167,88.07 164.97,88.07 163.96,87.06 157,87.06 154.54,84.6 147.36,84.6 146.75,83.99 146.75,83.24 145.53,82.02 143.96,82.02 142.91,80.97 142.91,80.53 142.85,80.47 142.76,80.47 142.61,80.62 142.56,80.62 v2(142.39,80.8)
  BOTTOM w0.081: v2(142.39,80.8) 142.39,80.94 141.74,81.58 UC1.C17
PCIE_PTX_SATARX_N6_L0_C: length 3.9
  TOP w0.102: CZ58.2 214.73,51.84 214.57,51.68 214.57,50.69 214.71,50.55 214.97,50.55 v2(215.22,50.79)
  BOTTOM w0.102: v2(215.22,50.79) 215.47,50.55 215.62,50.55 215.72,50.65 JNGFF2.39
PCIE_PTX_SATARX_N6_L1: length 105.7
  TOP w0.102: v2(214.8,56.59) 214.75,56.55 214.75,56.07 215.08,55.74 CZ32.1
  IN1 w0.091: v2(214.8,56.59) 214.64,56.74 214.64,56.98 214.7,57.04 215.83,57.04 216.73,57.94 216.73,64.85 216.4,65.18 216.4,68.81 212.46,72.75 210.34,72.75 208.36,74.72 206.55,74.72 204.29,76.97 199.8,76.97 197.56,74.73 194.89,74.73 194.31,75.31 192.19,75.31 190.95,76.55 190.95,77 190.36,77.59 188.56,77.59 187.63,78.52 187.63,81.05 185.25,83.43 179.42,83.43 178.42,84.43 171.56,84.43 167.27,88.72 164.7,88.72 163.69,87.71 156.73,87.71 154.32,85.3 146.65,85.3 146.34,84.98 145.02,84.98 143.97,83.93 v2(142.24,83.93)
  BOTTOM w0.081: v2(142.24,83.93) 142.44,83.74 142.64,83.74 142.83,83.54 142.83,82.59 142.6,82.36 142.6,82.15 142.67,82.08 142.89,82.08 UC1.B14
PCIE_PTX_SATARX_N6_L1_C: length 4.3
  TOP w0.102: v2(215.09,53.88) 215.08,53.88 214.87,54.09 214.87,54.57 215.13,54.83 CZ32.2
  BOTTOM w0.102: JNGFF2.27 215.98,53.65 215.38,53.05 214.93,53.05 214.72,53.26 214.72,53.51 v2(215.09,53.88)
PCIE_PTX_SATARX_P6_L0: length 107.9
  TOP w0.102: v2(214.63,58.51) 214.33,58.2 214.31,58.2 213.26,57.15 213.26,53.67 213.68,53.25 214.12,53.25 214.35,53.02 214.35,52.97 214.13,52.76 CZ59.1
  IN1 w0.091: v2(214.63,58.51) 214.48,58.36 214.48,58.28 214.63,58.13 214.96,58.13 215.19,57.9 215.49,57.9 215.91,58.32 215.91,64.47 215.52,64.85 215.52,68.52 212.16,71.89 210.04,71.89 208.02,73.9 206.1,73.9 203.85,76.15 200.18,76.15 197.94,73.91 194.55,73.91 193.97,74.49 191.74,74.49 189.84,76.4 188.6,76.4 186.19,78.8 186.19,79.37 184.87,80.68 184.19,80.68 182.33,82.54 179.11,82.54 178.1,83.56 171.27,83.56 166.93,87.9 165.04,87.9 164.03,86.89 157.07,86.89 154.61,84.43 147.43,84.43 146.93,83.92 146.93,83.17 145.6,81.84 144.03,81.84 143.09,80.9 143.09,80.46 142.93,80.3 142.51,80.3 v2(142.46,80.25)
  BOTTOM w0.081: v2(142.46,80.25) 142.43,80.25 142.18,80.5 142.01,80.5 141.78,80.73 141.78,80.84 UC1.D17
PCIE_PTX_SATARX_P6_L0_C: length 4
  TOP w0.102: v2(215.22,50.21) 215.1,50.33 214.62,50.33 214.35,50.6 214.35,51.6 CZ59.2
  BOTTOM w0.102: JNGFF2.41 215.8,50.15 215.62,50.33 215.34,50.33 v2(215.22,50.21)
PCIE_PTX_SATARX_P6_L1: length 105.6
  TOP w0.102: CZ33.1 214.54,55.97 214.54,56.27 v2(214.21,56.59)
  IN1 w0.091: v2(214.21,56.59) 214.47,56.85 214.47,57.05 214.63,57.21 215.76,57.21 216.55,58.01 216.55,64.78 216.22,65.11 216.22,68.74 212.39,72.57 210.27,72.57 208.29,74.55 206.47,74.55 204.22,76.8 199.88,76.8 197.63,74.56 194.82,74.56 194.24,75.14 192.12,75.14 190.78,76.48 190.78,76.92 190.28,77.42 188.48,77.42 187.46,78.45 187.46,80.98 185.18,83.26 179.35,83.26 178.35,84.26 171.49,84.26 167.2,88.55 164.78,88.55 163.76,87.53 156.8,87.53 154.39,85.13 146.73,85.13 146.41,84.81 145.09,84.81 144.04,83.76 142.58,83.76 142.42,83.6 142.39,83.6 142.24,83.45 v2(142.24,83.36)
  BOTTOM w0.081: v2(142.24,83.36) 142.43,83.54 142.56,83.54 142.64,83.46 142.64,82.67 142.41,82.44 142.41,82.07 142.55,81.93 142.55,81.79 142.5,81.75 UC1.C15
PCIE_PTX_SATARX_P6_L1_C: length 4.3
  TOP w0.102: v2(214.5,53.88) 214.66,54.03 214.66,54.47 CZ33.2
  BOTTOM w0.102: v2(214.5,53.88) 214.5,53.17 214.84,52.83 215.47,52.83 215.79,53.15 JNGFF2.29
PCIE_PTX_WIGIGRX_N5: length 127.3
  TOP w0.102: v2(198.45,34.08) 198.55,33.98 198.55,33.37 198.92,33.01 200.15,33.01 205.51,27.65 205.51,21.76 208.88,18.39 208.88,15.23 209.23,14.88 209.46,14.88 CZ22.1
  IN4 w0.091: v2(198.45,34.08) 198.68,33.86 198.68,33.76 198.55,33.63 198.23,33.63 198.04,33.83 197.32,33.83 196.5,34.65 187.68,34.65 174.84,47.49 174.84,52.81 169.05,58.6 169.05,65.81 167.44,67.43 167.44,69.39 166.7,70.13 166.6,70.13 164.52,72.21 164.52,72.68 163.9,73.3 163.39,73.3 162.33,74.36 160.18,74.36 159.99,74.17 158.76,74.17 157.07,75.86 149.85,75.86 149.34,76.36 149.34,77.19 149.06,77.47 147.08,77.47 146.8,77.75 146.8,79.09 146.55,79.34 145.95,79.34 144.1,77.49 141.31,77.49 141.08,77.72 141.08,80.85 141.85,81.62 141.85,84.1 141.01,84.94 140.07,84.94 139.19,84.06 139.05,84.06 138.71,84.4 v2(138.71,84.52)
  BOTTOM w0.081: v2(138.71,84.52) 138.71,84.41 138.11,83.82 138.11,83.13 138.36,82.87 138.36,82.59 138.13,82.35 138.13,81.95 138.29,81.79 138.29,81.71 UC1.C23
PCIE_PTX_WIGIGRX_N5_C: length 4.2
  TOP w0.102: v2(211.57,14.79) 211.38,14.97 210.95,14.97 CZ22.2
  BOTTOM w0.102: JNGFF1.53 209.62,14.85 209.76,14.99 211.36,14.99 v2(211.57,14.79)
PCIE_PTX_WIGIGRX_P5: length 127.3
  TOP w0.102: CZ21.1 209.7,15.18 209.61,15.09 209.32,15.09 209.09,15.32 209.09,18.48 205.72,21.85 205.72,27.74 200.24,33.22 199,33.22 198.77,33.46 198.77,33.82 v2(199.04,34.08)
  IN4 w0.091: v2(199.04,34.08) 198.85,33.9 198.85,33.69 198.62,33.46 198.16,33.46 197.97,33.65 197.25,33.65 196.43,34.47 187.61,34.47 174.66,47.42 174.66,52.74 168.88,58.52 168.88,65.74 167.26,67.35 167.26,69.32 166.63,69.96 166.53,69.96 164.35,72.14 164.35,72.61 163.83,73.13 163.32,73.13 162.26,74.19 160.25,74.19 160.06,73.99 158.69,73.99 157,75.68 149.78,75.68 149.17,76.29 149.17,77.12 148.99,77.3 147.01,77.3 146.63,77.68 146.63,79.01 146.48,79.17 146.02,79.17 144.17,77.32 141.23,77.32 140.9,77.65 140.9,80.93 141.67,81.7 141.67,84.03 140.94,84.76 140.14,84.76 139.27,83.89 v2(138.71,83.89)
  BOTTOM w0.081: UC1.C22 138.48,81.08 138.48,81.88 138.32,82.03 138.32,82.27 138.56,82.51 138.56,82.95 138.31,83.21 138.31,83.74 138.46,83.89 v2(138.71,83.89)
PCIE_PTX_WIGIGRX_P5_C: length 4.1
  TOP w0.102: v2(211.57,15.37) 211.38,15.19 210.95,15.19 CZ21.2
  BOTTOM w0.102: v2(211.57,15.37) 211.41,15.21 209.76,15.21 209.62,15.35 JNGFF1.51
PCIE_PTX_WLANRX_N4: length 118.4
  TOP w0.102: CZ14.1 208.25,20.59 207.84,20.59 206.33,22.1 206.33,27.99 198.83,35.5 198.11,35.5 198.1,35.51 196.94,35.51 196.42,36.03 v2(196.42,37.1)
  IN4 w0.091: v2(134.87,83.71) 135.28,84.12 135.62,84.12 135.81,83.94 137.5,83.94 138.44,84.88 139.5,84.88 139.9,85.27 141.61,85.27 141.78,85.45 142.29,85.45 143.61,84.13 144.59,84.13 145.47,83.26 150,83.26 150.42,82.84 152.12,82.84 156.63,78.34 160.41,78.34 160.94,77.81 163.85,77.81 165.31,76.35 165.76,76.35 169.81,72.3 169.81,71.21 169.95,71.07 169.95,68.31 171.89,66.38 171.89,60.24 172.41,59.72 172.41,58.65 177.24,53.81 177.24,48.49 188.68,37.05 195.05,37.05 195.57,37.58 196.64,37.58 196.73,37.49 196.73,37.41 v2(196.42,37.1)
  BOTTOM w0.076: UC1.B29 134.02,82.26 134.48,82.71 134.48,83.64 134.55,83.71 v2(134.87,83.71)
PCIE_PTX_WLANRX_N4_C: length 3.1
  TOP w0.102: CZ14.2 209.8,20.74 210.26,20.74 v2(210.4,20.59)
  BOTTOM w0.102: v2(210.4,20.59) 210.22,20.78 209.89,20.78 209.68,20.99 209.6,20.99 209.46,20.85 JNGFF1.29
PCIE_PTX_WLANRX_P4: length 118.4
  TOP w0.102: CZ13.1 208.49,20.92 208.37,20.81 207.93,20.81 206.55,22.19 206.55,28.08 198.91,35.72 v4(198.37,35.72) 197.03,35.72 196.63,36.12 196.63,36.73 v2(197,37.1)
  IN4 w0.091: v2(197,37.1) 196.9,37.2 196.9,37.57 196.72,37.75 195.5,37.75 194.97,37.23 188.75,37.23 177.42,48.56 177.42,53.88 172.58,58.72 172.58,59.79 172.06,60.31 172.06,66.45 170.13,68.39 170.13,71.14 169.98,71.28 169.98,72.38 165.83,76.52 165.39,76.52 163.92,77.99 161.01,77.99 160.48,78.51 156.7,78.51 152.19,83.01 150.49,83.01 150.07,83.43 145.54,83.43 144.67,84.3 143.68,84.3 142.36,85.62 141.71,85.62 141.54,85.45 139.82,85.45 139.43,85.05 138.37,85.05 137.43,84.11 135.88,84.11 135.69,84.29 v2(134.87,84.29)
  BOTTOM w0.076: v2(134.87,84.29) 134.29,83.72 134.29,82.79 134.21,82.71 134.09,82.71 UC1.A29
PCIE_PTX_WLANRX_P4_C: length 3.1
  TOP w0.102: CZ13.2 209.69,20.95 210.18,20.95 v2(210.4,21.18)
  BOTTOM w0.102: v2(210.4,21.18) 210.22,20.99 209.98,20.99 209.77,21.21 209.58,21.21 209.43,21.35 JNGFF1.27
PCIE_WAKE#: length 88.5
  TOP w0.102: RE275.2 230.04,56.36 v2(230.61,56.94) ; RE275.2 229.98,56.36 229.37,55.75 v1(229.37,55.42) ; RE275.2 RE274.1
  IN3 w0.122: v2(212.28,16.92) 213.08,16.92 216.1,19.93 216.1,31.86 220.79,36.55 227.86,36.55 232.64,41.33 236.19,41.33 237.07,42.21 237.07,47.37 236.33,48.11 236.33,49.76 236.65,50.08 236.65,54.01 235.26,55.41 234.81,55.41 233.16,57.06 232.46,57.06 232.24,57.28 230.96,57.28 v2(230.61,56.94)
  BOTTOM w0.102: JNGFF2.46 224.87,48.9 225.1,48.68 226.56,48.68 227,49.12 227,50.33 229.22,52.55 229.22,55.92 230.24,56.94 v2(230.61,56.94) ; JNGFF1.47 210.03,16.35 210.6,16.92 v2(212.28,16.92) 213.16,16.04 213.16,13.61 214.16,12.6 JNGFF1.62
PCIE_WAKE#_R: length 5.8
  TOP w0.102: RE275.1 229.03,56.41 RE35.2 228.21,56.02 v2(228.47,55.75) ; v2(228.81,52.74) 228.72,52.84 UE1.B10
  BOTTOM w0.102: v2(228.81,52.74) 228.87,52.81 228.87,55.63 228.75,55.75 v2(228.47,55.75)
PE_REXT: length 3.4
  TOP w0.102: RR2.2 254.8,19.25 255.14,18.91 v1(255.85,18.91) 256.64,18.13 UR1.4
PECI_EC: length 211.9
  TOP w0.076: v1(113.84,74.75) 113.59,75.01 v2(113.59,75.22)
  TOP w0.102: v2(247.19,54.14) 246.99,54.34 RE60.2
  IN1 w0.084: v2(247.19,54.14) 247.19,53.92 242.96,49.68 242.96,27.54 v2(238.7,23.28)
  IN2 w0.122: v2(113.59,75.22) 114.35,74.46 115.21,74.46 115.51,74.16 115.51,68.63 114.44,67.57 114.44,64.24 112.98,62.78 112.98,61.25 111.51,59.78 111.51,54.13 112.51,53.12 116.51,53.12 117.4,52.23 117.4,46.32 130.1,33.62 130.1,29.46 131.85,27.71 136.07,27.71 137.78,26 174.29,26 177.68,22.62 186.26,22.62 186.68,23.03 195.17,23.03 195.36,23.23 197.5,23.23 201.26,19.47 201.84,19.47 204.44,16.87 211.24,16.87 212.32,17.94 216.09,17.94 221.45,23.3 238.67,23.3 v2(238.7,23.28)
  BOTTOM w0.076: v2(113.59,75.22) 113.59,75.27 UC1.N62
PECI_EC_R: length 10.9
  TOP w0.102: RE60.1 248.65,55.68 248.78,55.81 v1(248.78,56.04) 248.78,56.24 248.65,56.36 246.98,56.36 246.86,56.49 246.86,56.74 246.98,56.87 248.07,56.87 248.2,57 248.2,57.38 248.07,57.51 246.88,57.51 246.12,56.75 245.94,56.75 245.74,56.95 245.74,57.13 246.18,57.57 246.18,57.78 246.05,57.9 UE2.A48
PGOOD_3V_5V: length 4.7
  TOP w0.102: PR107.1 205.24,48.69 205.77,48.17 v1(206.26,48.17)
  TOP w0.203: PR108.2 203.9,48.7 203.57,49.03 203.15,49.03 202.68,49.49 PU100.7
  TOP w0.254: PR107.1 205.15,48.7 PR108.2
PLTRST_LAN#: length 110.1
  TOP w0.102: UL1.36 241.25,89.96 241.35,90.06 241.35,90.35 v2(241.32,90.37) ; v2(164.63,98.81) 164.63,93.45 162.5,91.31 162.5,89.33 162.08,88.91 162.08,86.98 163.31,85.75 v1(170.31,85.75) 171.07,85.75 171.59,85.23 RC89.1
  IN4 w0.084: v2(241.32,90.37) 240.14,90.37 239.68,90.84 235.07,90.84 233.67,92.24 232.27,92.24 230.94,93.57 230.02,93.57 226.46,97.13 206.5,97.13 204.02,94.65 172.19,94.65 167.31,99.53 165.35,99.53 v2(164.63,98.81)
PLTRST_MMI#: length 166
  TOP w0.102: UR1.15 259.18,13.64 258.95,13.41 v2(258.95,13.06) ; RC88.1 174.81,79.29 v1(175.5,79.98) 175.92,80.41 v2(175.92,80.8)
  IN4 w0.084: v2(258.95,13.06) 257.42,14.59 257.42,24.02 255.59,25.84 255.59,27.37 252.28,30.68 252.28,34.59 251.63,35.23 251.63,40.49 252.69,41.54 252.69,43.8 259.46,50.57 259.46,54.91 261.29,56.74 261.29,63.54 258.88,65.95 258.13,65.95 253.87,70.21 253.71,70.21 248.95,74.96 248.95,76.7 248.05,77.6 244.22,77.6 243.45,78.37 243.45,78.89 242.82,79.52 240.02,79.52 239.67,79.87 235.44,79.87 233.79,78.22 227.46,78.22 226.83,77.6 222.73,77.6 222.25,78.07 215.6,78.07 215.18,77.65 208.41,77.65 207.7,78.36 206.02,78.36 205.74,78.08 203.38,78.08 198.72,73.42 195.49,73.42 194.52,72.46 188.35,72.46 188.11,72.7 183.26,72.7 179.46,76.49 179.31,76.49 178.32,77.48 177.2,77.48 175.92,78.76 v2(175.92,80.8)
PLTRST_USH#: length 184.3
  TOP w0.102: v2(248.3,9.58) 248.3,9.82 246.98,11.14 JUSH1.15 246.98,12.02 247.19,12.23 247.19,13.22 CZ68.1 ; RC87.1 v1(173.53,80.25) 174.67,80.25 v2(175.26,80.83)
  IN4 w0.084: v2(175.26,80.83) 175.26,78.87 176.58,77.55 176.58,77 177.09,76.49 178.76,76.49 179.15,76.1 179.3,76.1 183.1,72.31 187.95,72.31 188.19,72.07 194.7,72.07 195.67,73.04 203.44,73.04 204.83,74.43 209.03,74.43 209.95,75.35 210.96,75.35 212.57,76.95 215.03,76.95 215.76,77.68 221.36,77.68 222.37,76.67 230.67,76.67 231.82,77.83 234.07,77.83 235.72,79.48 239.47,79.48 240.79,78.16 241.96,78.16 242.9,77.21 246.93,77.21 248.57,75.57 248.57,74.8 253.73,69.64 253.89,69.64 257.97,65.56 258.72,65.56 260.9,63.38 260.9,56.9 259.07,55.07 259.07,50.85 252.3,44.08 252.3,41.7 251.25,40.65 251.25,35.07 251.89,34.43 251.89,30.52 255.16,27.25 255.16,25.55 256.08,24.62 256.08,15.4 255.7,15.02 255.7,12.86 259.51,9.05 v2(259.51,8.74)
  BOTTOM w0.102: v2(248.3,9.58) 248.3,9.54 249.3,8.53 259.31,8.53 v2(259.51,8.74)
PLTRST_VMM2320#: length 28.9
  TOP w0.102: v2(176.65,81.2) v1(175.73,82.12) 172.51,82.12 RC219.1 ; v2(187.85,73.53) 188.18,73.86 188.18,76.07 188.84,76.73 189.84,76.73 189.93,76.64 190.72,76.64 191.32,77.24 191.69,77.24 192.09,77.64 UV8.A13
  IN4 w0.084: v2(176.65,81.2) 176.65,78.77 177.15,78.28 178.35,78.28 179.44,77.19 182.45,77.19 185.44,74.21 185.93,74.21 186.6,73.53 v2(187.85,73.53)
PM_APWROK: length 86
  TOP w0.102: v2(241.64,69.53) 241.66,69.51 UE2.A9 ; RC26.1 169.72,62.2 172.2,64.68 174.1,64.68 v1(177.18,67.76) 179.18,69.76 179.18,72.11 v2(180.2,73.13)
  IN2 w0.122: v2(233.28,73.57) 234.81,72.03 235.55,72.03 235.92,71.67 236.33,71.67 236.78,71.22 237.29,71.22 238.98,69.53 v2(241.64,69.53)
  IN4 w0.084: v2(180.2,73.13) 180.98,73.13 182.64,71.46 187.6,71.46 187.84,71.22 198.04,71.22 198.96,72.13 203.74,72.13 205.18,73.57 209.38,73.57 209.62,73.81 212.78,73.81 213.47,73.13 214.39,73.13 215.5,74.23 222.37,74.23 224.15,72.45 225.36,72.45 226.64,71.16 228.51,71.16 230.07,72.73 232.44,72.73 v2(233.28,73.57)
PM_APWROK_L: length 5
  TOP w0.102: v1(167.87,63.49) RC26.2 RC27.2 168.07,60.98 168.07,59.36 167.81,59.09 UC6.2
PM_APWROK_R: length 34.7
  TOP w0.102: v2(157.46,57.21) 157.92,57.66 162.71,57.66 v3(163.28,57.09) 166.07,57.09 166.95,56.21 167.29,56.21 168.07,56.99 168.07,58.2 168.31,58.44 UC6.4
  IN4 w0.084: v2(157.46,57.21) 157.47,57.21 157.47,57.2 156.77,57.2 154.04,59.93 154.04,60.81 153.36,61.48 151.7,61.48 150.7,62.49 150.7,67.98 150.38,68.3 149.78,68.3 149.21,68.87 149.21,70.47 148.84,70.84 148.63,70.84 v2(148.21,71.26)
  BOTTOM w0.081: v2(148.21,71.26) 148.21,71.12 UC1.AB5
PM_LANPHY_ENABLE: length 156
  TOP w0.081: v2(147.92,65.56) 148.97,65.56 149.3,65.23 149.3,64.52 149.97,63.84 149.97,62.2 153.11,59.06 v1(153.11,58.68) 153.82,57.97
  TOP w0.102: v2(229.97,95.03) 229.97,94.98 230.5,94.46 RL7.1 ; RC92.2 155.55,56.24 153.82,57.97
  IN1 w0.084: v2(147.92,65.56) 148.34,65.15 148.34,62.15 148.67,61.82 149.54,61.82 150.81,63.09 153.09,63.09 153.35,63.35 153.35,63.72 156.37,66.74 159.84,66.74 164.86,61.72 166.71,61.72 169.76,58.67 172.87,58.67 173.14,58.4 179.48,58.4 182.17,55.71 182.91,55.71 183.79,54.84 183.79,54.37 186.51,51.65 187.89,51.65 193.68,45.86 194.38,45.86 194.78,46.26 196.66,46.26 197.42,45.5 205.51,45.5 207.32,47.32 209.71,47.32 210.11,47.72 210.96,47.72 211.52,48.28 213.31,48.28 214.58,49.55 214.58,51.04 217.18,53.63 217.18,55.84 219.52,58.18 220.5,58.18 225.65,63.33 225.65,66.82 230.38,71.56 v2(230.76,71.56)
  BOTTOM w0.081: v2(147.92,65.56) 147.71,65.35 UC1.AM7
  BOTTOM w0.102: v2(230.76,71.56) 232.36,73.16 232.36,74.3 231.12,75.54 231.12,78.27 233.46,80.62 233.46,84.62 234.23,85.38 234.23,86.45 231.42,89.25 231.42,93.59 v2(229.97,95.03)
PM_TEST_RST: length 12.1
  TOP w0.102: v2(148.81,70.22) 149.03,70.22 149.23,70.02 150.51,70.02 151.01,70.53 151.01,71.08 151.57,71.64 151.95,71.64 152.47,71.12 156.59,71.12 156.69,71.02 157.4,71.02 RC300.2 157.91,69.77 CC100.2
  BOTTOM w0.076: v2(148.81,70.22) 148.86,70.27 UC1.AC4
POA_WAKE#: length 8
  TOP w0.102: UE2.B68 246.8,67.35 247.04,67.6 247.42,67.6 248.08,68.26 248.08,68.55 v1(248.81,69.28) 249.11,69.58 249.11,71.35 248.35,72.11 247.45,72.11 247.24,72.32 RPE5.3
POWER_SW#_MB: length 314.8
  TOP w0.102: SW2.2 SW2.4 274.66,90.85 272.62,88.81 270.82,88.81 270.03,88.03 270.03,86.72 269.16,85.85 266.55,85.85 265.44,84.75 265.44,77.91 263.97,76.44 263.97,76 263.59,75.62 261.02,75.62 260.76,75.88 260.76,76 260.53,76.22 260.13,76.22 257.39,73.48 255.27,73.48 255.13,73.62 251.18,73.62 251.07,73.51 CE10.1 ; CE10.1 250.68,72.59 RE33.2 ; CE10.1 250.01,74.19 249.24,74.19 249,74.43 248.11,74.43 247.64,74.9 245.61,74.9 v3(244.22,76.29) 243.57,76.94 232.73,76.94 v2(232.41,76.62) ; v2(37.96,39.29) 33.27,39.29 32.73,39.83 JAPS1.11
  IN2 w0.122: v2(37.96,39.29) 38.93,39.29 39.2,39.57 39.2,41.51 41.62,43.93 48.3,43.93 55.21,50.84 55.21,53.6 56.15,54.54 56.15,58.17 55.83,58.49 55.83,61.9 56.26,62.33 56.26,65.09 57.26,66.09 57.26,68.21 61.29,72.24 61.29,72.82 70.37,81.9 71.41,81.9 74.29,84.78 74.93,84.78 77.52,87.38 82.46,87.38 83.63,88.56 90.34,88.56 93.94,92.15 104.06,92.15 104.27,92.36 104.63,92.73 108.92,92.73 109.09,92.9 111.11,92.9 112.05,93.83 112.25,93.83 113.77,95.35 122.8,95.35 124.17,96.72 126.79,96.72 126.96,96.56 133.97,96.56 135.42,98 137.41,98 137.85,98.44 137.85,99.07 138.38,99.6 138.76,99.6 139.34,100.19 144.59,100.19 145.06,99.71 145.06,98.74 145.51,98.29 145.51,97.58 146.45,96.65 151.2,96.65 151.35,96.5 153.02,94.83 165.73,94.83 172,88.56 184.2,88.56 185.43,89.78 192.14,89.78 192.58,90.22 197.2,90.22 199.72,87.7 201.38,87.7 201.86,87.22 207.36,87.22 209.77,84.81 213.08,84.81 215.07,82.82 215.07,82.29 215.3,82.05 220.52,82.05 221.74,80.84 221.74,79.9 224.94,76.7 232.33,76.7 v2(232.41,76.62)
POWER_SW_IN#: length 10.6
  TOP w0.102: RE31.2 RE33.1 CE12.1 ; v2(248.59,68.43) 249.34,69.18 249.34,71.22 CE12.1 ; UE2.B67 245.87,66.85 v2(245.85,66.88) ; CE12.1 249.27,71.66 v1(248.87,72.06)
  IN1 w0.084: v2(248.59,68.43) 248.21,68.43 246.66,66.88 v2(245.85,66.88)
PROC_OPI_RCOMP: length 4
  BOTTOM w0.152: UC1.AY15 142.62,60 142.95,59.66 142.95,59.35
  BOTTOM w0.381: RC187.1 143.37,57.34 v1(143.03,57.68) 143.03,58.42 142.95,58.49 142.95,59.35
PROCHOT_GATE: length 4.9
  TOP w0.102: UE1.A50 235.23,45.65 235.31,45.58 235.83,45.58 v1(235.9,45.65) 239,45.65 RE83.2
PS8338_AUX: length 39.1
  TOP w0.102: RV554.2 224.67,90.39 224.22,89.94 223.99,89.94 v2(223.8,90.12) 223.47,89.79 223.36,89.79 223.16,89.59 223.16,89.47 223.06,89.37 222.81,89.37 222.75,89.43 UV7.55 ; UV600.24 213.5,77.09 213.4,77 213.22,77 212.81,77.41 211.89,77.41 211.43,77.86 211.08,77.86 210.08,78.85 208.89,78.85 207.94,79.81 207.94,83.41 207.15,84.2 207.15,88.72 207.53,89.1 207.53,89.13 208.28,89.88 208.73,89.88 209.06,90.21 209.06,90.35 v2(209.43,90.72)
  IN4 w0.091: v2(223.8,90.12) 223.39,89.71 222.86,89.71 222.2,90.37 218.46,90.37 217.96,90.87 215.01,90.87 214.42,90.28 209.21,90.28 209.14,90.35 209.14,90.42 209.43,90.71 v2(209.43,90.72)
PS8338_AUX#: length 39.1
  TOP w0.102: UV7.54 222.74,89.03 222.87,89.15 223.15,89.15 223.37,89.38 223.37,89.5 223.45,89.57 223.77,89.57 v2(223.8,89.54) 223.99,89.72 224.52,89.72 RV555.2 ; UV600.25 213.5,76.69 213.4,76.78 213.13,76.78 212.72,77.19 211.8,77.19 211.34,77.65 210.99,77.65 209.99,78.64 208.8,78.64 207.72,79.72 207.72,83.32 206.93,84.11 206.93,88.84 v4(207.16,89.06) 208.19,90.09 208.64,90.09 208.85,90.3 v2(208.85,90.72)
  IN4 w0.091: v2(208.85,90.72) 208.97,90.59 208.97,90.28 209.14,90.11 214.49,90.11 215.08,90.7 217.89,90.7 218.38,90.2 222.13,90.2 222.79,89.53 223.8,89.53 v2(223.8,89.54)
PS8338_CFG0: length 5.9
  TOP w0.102: UV600.59 223.93,77.89 224.5,78.46 226.26,78.46 RV601.2 226.51,78.16 226.96,77.71 227.88,77.71 228.29,78.12 v1(228.29,78.16)
PS8338_HPD: length 8.5
  TOP w0.102: UV7.32 v2(217.36,82.88) ; UV600.3 221.65,79.55 221.76,79.67 222.02,79.67 v2(222.33,79.98)
  IN1 w0.084: v2(217.36,82.88) 217.72,82.88 219.27,81.33 220.99,81.33 v2(222.33,79.98)
PS8338_N0: length 2.3
  TOP w0.102: CV607.1 220.97,82.07 220.97,82.27 220.16,83.08 UV7.39
PS8338_N0_C: length 2.4
  TOP w0.102: CV607.2 221,80.67 221,80.56 220.05,79.61 UV600.7
PS8338_N1: length 2.2
  TOP w0.102: CV609.1 219.26,82.13 219.26,82.29 219.06,82.5 219.06,82.99 218.96,83.08 UV7.36
PS8338_N1_C: length 2.2
  TOP w0.102: CV609.2 219.26,80.63 219.26,80.45 218.94,80.14 218.94,79.6 218.85,79.51 UV600.10
PS8338_N2: length 2.3
  TOP w0.102: CV611.1 217.51,82.16 217.51,82.39 217.95,82.83 217.95,83.04 217.76,83.22 UV7.33
PS8338_N2_C: length 2.3
  TOP w0.102: UV600.13 217.65,79.49 217.83,79.68 217.83,79.73 217.44,80.12 217.44,80.67 CV611.2
PS8338_N3: length 2.4
  TOP w0.102: UV7.30 216.56,83.13 215.83,82.4 215.83,82.26 CV613.1
PS8338_N3_C: length 2.4
  TOP w0.102: CV613.2 215.83,80.5 215.83,80.3 216.45,79.68 UV600.16
PS8338_P0: length 2.4
  TOP w0.102: CV606.1 221.19,82.28 221.19,82.36 220.56,82.98 UV7.40
PS8338_P0_C: length 2.4
  TOP w0.102: UV600.6 220.45,79.7 221.22,80.47 221.22,80.51 221.63,80.92 CV606.2
PS8338_P1: length 2.2
  TOP w0.102: CV608.1 219.48,82.22 219.48,82.38 219.27,82.59 219.27,82.99 219.36,83.08 UV7.37
PS8338_P1_C: length 2.3
  TOP w0.102: CV608.2 219.48,80.54 219.48,80.37 219.16,80.05 219.16,79.67 219.25,79.57 UV600.9
PS8338_P2: length 2.3
  TOP w0.102: UV7.34 218.16,82.74 217.72,82.3 217.72,82.12 218,81.84 CV610.1
PS8338_P2_C: length 2.3
  TOP w0.102: UV600.12 218.05,79.82 217.66,80.21 217.66,80.5 CV610.2
PS8338_P3: length 2.4
  TOP w0.102: CV612.1 216.05,82.09 216.05,82.31 216.96,83.22 UV7.31
PS8338_P3_C: length 2.4
  TOP w0.102: CV612.2 216.05,80.67 216.05,80.39 216.85,79.59 UV600.15
PS8338_SW: length 4.1
  TOP w0.102: UV600.18 215.65,79.56 215.14,80.06 212.49,80.06 RV602.2
PS8338B_P0: length 3.7
  TOP w0.102: UV600.60 224.01,78.29 224.4,78.69 225.1,78.69 225.5,79.1 v1(225.59,79.1) RV615.2
PS8338B_P1: length 6
  TOP w0.102: UV600.1 222.45,79.47 222.71,79.73 v1(224.33,79.73) 225.3,79.73 RV603.2 RV100.1
PS8338B_PC10: length 4.5
  TOP w0.102: UV600.56 224.54,76.69 224.61,76.61 225.21,76.61 v1(225.58,76.24) 225.72,76.1 RV614.2 RV620.1
PS8338B_PC11: length 6.5
  TOP w0.102: UV600.55 223.87,76.29 223.94,76.22 v1(224.29,76.22) 225.07,76.22 225.62,75.67 227.87,75.67 RV619.1 RV613.2
PS8338B_PC20: length 7.7
  TOP w0.102: v1(230.4,74.78) 230.19,74.98 RV612.2 RV618.1 227.84,75.44 225.53,75.44 225.08,75.89 UV600.54
PS8338B_PC21: length 4.5
  TOP w0.102: RV617.1 RV611.2 225.67,74.98 v1(225.64,74.94) 225.61,74.94 225.06,75.49 UV600.53
PS8338B_PEQ: length 14.8
  TOP w0.102: v2(229.31,80.76) 229.31,80.02 RV616.1 RV610.2 229.27,78.85 v1(230.16,77.96) ; UV600.8 219.65,79.84 v2(219.67,79.86)
  IN1 w0.084: v2(229.31,80.76) 229.3,80.77 229.3,80.96 229.03,81.23 225.49,81.23 223.8,79.54 219.98,79.54 v2(219.67,79.86)
PS8339B_DP_CFG0: length 4.9
  TOP w0.102: UV7.44 222.94,85.03 223.05,84.92 223.55,84.92 223.74,84.73 v1(223.74,84.19) 223.74,83.77 RV51.2 RV52.1
PS8339B_DP_CFG1: length 4.8
  TOP w0.102: UV7.29 216.16,83.34 216.07,83.24 215.51,83.24 214.84,82.57 214.84,81.39 RV61.1 RV54.2
PS8339B_IN_CA_DET: length 3
  TOP w0.102: UV7.11 v2(217.36,91.6)
  BOTTOM w0.102: v2(217.36,91.6) 217.35,91.62 RV68.2 217.94,92.38 v1(218.44,92.87)
PS8339B_INPUT_EQ: length 12.1
  TOP w0.102: v2(226.19,92.18) 226.19,92.71 RV58.2 RV65.1 ; UV7.8 v2(218.56,91.6)
  IN4 w0.084: v2(218.56,91.6) 218.63,91.6 219.1,91.13 222.02,91.13 223.39,92.51 225.86,92.51 v2(226.19,92.18)
  BOTTOM w0.102: v2(218.56,91.6) 218.25,91.6 v1(218.01,91.36)
PS8339B_MODE: length 3.3
  TOP w0.102: RV57.2 RV63.1 v1(223.79,88.68) 223.53,88.68 223.48,88.63 UV7.53
PS8339B_MODE_SW: length 3.7
  TOP w0.102: UV7.45 223.59,85.43 v1(223.63,85.47) 224.01,85.47 RV550.1 RV551.2
PS8339B_OUT_CA_DET: length 5.3
  TOP w0.102: UV7.42 221.36,83.38 221.49,83.25 223.34,83.25 v1(223.7,82.88) 223.7,82.89 224.11,82.49 224.11,81.5 RV67.2
PS8339B_TMDS_DDCBUF: length 4
  TOP w0.102: UV7.2 220.96,91.44 221.06,91.54 221.86,91.54 v1(222.12,91.8) 222.59,92.26 RV66.1 RV60.2
PS8339B_TMDS_PRE: length 17.2
  TOP w0.102: UV7.20 214.25,87.83 v2(214.24,87.85) ; v2(210.08,87.85) 209.41,87.85 v1(208.66,87.1) 208.39,86.83 208.39,84.85 209.27,83.97 209.27,82.87 209.92,82.22 RV56.2
  IN3 w0.122: v2(214.24,87.85) 213.16,87.85 212.5,88.51 210.75,88.51 v2(210.08,87.85)
  BOTTOM w0.102: v2(214.24,87.85) 214.24,87.86 214.68,88.3 214.68,89.51 RV64.1
PS8339B_TMDS_RT: length 15.3
  TOP w0.102: UV7.23 214.21,86.63 v2(214.19,86.65) ; RV55.2 211.46,83.09 210.82,82.45 210.01,82.45 209.5,82.96 209.5,84.07 208.62,84.94 208.62,86.38 209.68,87.44 v1(210.64,87.44) v2(211.02,87.82)
  IN3 w0.122: v2(214.19,86.65) 213.75,87.08 213.22,87.08 212.48,87.82 v2(211.02,87.82)
  BOTTOM w0.102: v2(214.19,86.65) 214.52,86.65 RV62.1
PS_ID: length 198
  TOP w0.102: UE2.B24 238.21,64.35 v2(238.87,65.02) ; PU1.4 73.23,85.64 v2(73.93,86.33) ; v1(236.58,75.89) v2(237.16,75.89)
  IN3 w0.122: v2(73.93,86.33) 73.93,86.34 74.4,86.81 82.82,86.81 84.44,88.43 91.06,88.43 93.76,91.13 98.3,91.13 99.84,92.67 107.76,92.67 109.69,94.6 112.7,94.6 113.67,95.57 122.46,95.57 123.87,96.97 129.72,96.97 130.56,96.14 145.03,96.14 145.14,96.02 152.42,96.02 152.97,95.47 164.91,95.47 170.74,89.64 182.82,89.64 184.1,90.91 192.03,90.91 193.1,91.98 198.01,91.98 198.28,92.25 204.92,92.25 205.44,91.73 209.63,91.73 213.08,88.28 216.03,88.28 217.93,86.38 220.54,86.38 221.73,85.19 223.57,85.19 224.56,84.2 226.4,84.2 226.75,83.85 226.75,81.79 227.31,81.23 229.43,81.23 230.14,80.52 235.51,80.52 237.16,78.86 v2(237.16,75.89)
  BOTTOM w0.102: v2(237.16,75.89) 236.68,75.41 236.68,74.31 237.1,73.89 237.1,72.3 236.44,71.65 236.44,69.47 237.72,68.19 237.72,66.11 238.26,65.57 238.68,65.57 238.87,65.38 v2(238.87,65.02)
PS_USBP0_D+: length 15.4
  TOP w0.102: v2(72.23,88.95) 72.03,89.14 72.03,89.45 72.36,89.77 LI3.1 ; v2(83.02,92.09) 82.85,92.26 82.51,92.26 82.37,92.12 UI3.10
  IN1 w0.091: v2(83.02,92.09) 82.81,92.3 82.38,92.3 81.44,91.36 74.85,91.36 74.66,91.17 73.57,91.17 72.02,89.61 72.02,89.15 v2(72.23,88.95)
PS_USBP0_D-: length 15.7
  TOP w0.102: LI3.4 71.51,89.75 71.81,89.45 71.81,89.12 v2(71.64,88.95) ; v2(83.02,92.67) 82.83,92.47 82.5,92.47 82.36,92.62 UI3.11
  IN1 w0.091: v2(83.02,92.67) 82.82,92.47 82.31,92.47 81.37,91.53 74.77,91.53 74.58,91.34 73.5,91.34 71.85,89.69 71.85,89.15 v2(71.64,88.95)
PSID_DISABLE#: length 255
  TOP w0.102: v2(51.97,38.4) 51.97,38.07 v1(51.59,37.69) ; v2(227.5,42.73) 227.47,42.77 UE1.A37 ; v2(74.51,86.33) 74.51,86.85 PR13.2
  IN3 w0.122: v2(51.97,38.4) 53.65,40.08 54.55,40.08 55.27,40.8 56.19,40.8 56.95,40.04 64.47,40.04 67.9,36.61 185.34,36.61 187.48,38.75 194.62,38.75 195.42,37.94 195.42,33.52 199.98,28.96 203.12,28.96 206.39,32.23 206.39,32.61 211.84,38.06 220.7,38.06 224.4,41.76 224.4,42.87 224.71,43.19 227.05,43.19 v2(227.5,42.73)
  IN4 w0.084: v2(51.97,38.4) 51.97,43.95 52.72,44.69 52.72,47.03 55.63,49.94 55.63,51.66 56.61,52.64 56.61,56.74 55.33,58.01 55.33,62.38 56.24,63.29 56.24,64.03 55.99,64.27 55.99,67.63 59.12,70.76 59.12,71.51 60.46,72.85 61.09,72.85 71.68,83.44 71.68,84.94 72.23,85.49 74.06,85.49 74.51,85.95 v2(74.51,86.33)
PWM1: length 10.3
  TOP w0.203: v2(85.81,72.52) 86.58,73.29 PU500.6
  BOTTOM w0.203: PU501.8 80.25,68.26 80.06,68.45 80.06,68.74
  BOTTOM w0.254: v2(85.81,72.52) 84.7,71.41 v1(84.25,71.41) 82.73,71.41 80.06,68.74
PWR_SRC_ON: length 5.1
  BOTTOM w0.102: RV4.2 CV11.2 62.39,65.91 RV5.1 63.66,65.91 64.45,66.7 v1(64.45,66.85) 64.45,67.04 64.28,67.22 QV1.3
RED_DOCK: length 81.9
  TOP w0.102: v2(180.95,92.84) 183.6,92.84 184.77,91.67 v1(191.57,91.67) 192.03,91.67 194.23,89.47 RV76.1 194.74,88.44 194.74,86.92 195.85,85.82 196.19,85.82 196.37,85.64 196.37,85.08 UV8.M6
  BOTTOM w0.102: JDOCK1.53 127.45,99.54 127.62,99.37 127.62,98.1 131.16,94.56 138.67,94.56 140.3,96.19 142.82,96.19 143.75,95.26 146.89,95.26 147.12,95.03 168.66,95.03 170.73,92.96 175.65,92.96 176.73,91.89 176.73,91.38 177.06,91.05 179.51,91.05 180.95,92.48 v2(180.95,92.84)
REGCTL_PNP10:
  vias: v1(233.1,88.05)
REM_DIODE1_N: length 160.3
  TOP w0.254: UE2.B13 239.91,67.31 v2(239.76,67.17) ; v2(239.7,71.67) 239.83,71.55 CE24.1 239.62,70.84 v2(239.62,70.21) ; v2(127.37,73.98) 127.41,74.02 128.14,74.02 CE35.1 128.7,73.82 128.89,73.63 QE3.3
  IN1 w0.254: v2(239.7,71.67) 239.7,70.97 238.87,70.15 238.87,69.17 236.92,67.22 235.25,67.22 233.76,65.73 233.76,62.45 232.33,61.03 232.33,59.79 232.02,59.47 232.02,59.02 229.46,56.47 229.46,54.55 228.93,54.01 224.46,54.01 223.08,52.64 222.26,52.64 221.86,52.23 221.86,51.83 220.57,50.54 220.57,48.93 219.31,47.67 219.31,46.65 218.73,46.06 218.16,46.06 215.42,43.32 213.7,43.32 211.66,41.28 208.27,41.28 207.46,40.47 203.32,40.47 202.83,39.98 199.21,39.98 198.88,39.65 192.6,39.65 190.67,41.58 190.67,44.27 186.13,48.8 183.19,48.8 180.36,51.63 180.36,53.01 177.75,55.61 163.04,55.61 160.64,58.01 155.56,58.01 155.37,58.2 153.4,58.2 152.96,57.76 151.99,57.76 149.57,60.17 146.21,60.17 144.68,61.7 142.42,61.7 141.47,62.65 141.47,66.69 140.86,67.3 140.86,67.8 140.67,68 140.04,68 139.58,67.54 136.68,67.54 130.17,74.06 127.45,74.06 v2(127.37,73.98) ; v2(239.76,67.17) 239.76,70.07 v2(239.62,70.21)
REM_DIODE1_P: length 159.2
  TOP w0.254: QE3.1 130.66,74.28 130.01,74.93 QE3.2 129.29,74.73 CE35.2 128.12,74.52 127.41,74.52 v2(127.37,74.56) ; v2(239.04,71.67) 239.04,71.17 CE24.2 238.91,70.23 v1(239.14,70) 239.66,69.48 UE2.A13
  IN1 w0.254: v2(127.37,74.56) 130.38,74.56 136.89,68.05 139.37,68.05 139.83,68.5 140.88,68.5 141.37,68.01 141.37,67.51 141.97,66.9 141.97,62.86 142.63,62.2 144.89,62.2 146.42,60.68 149.78,60.68 152.2,58.27 152.75,58.27 153.19,58.71 155.58,58.71 155.77,58.52 160.85,58.52 163.25,56.12 177.96,56.12 180.86,53.22 180.86,51.84 183.4,49.31 186.34,49.31 191.17,44.48 191.17,41.79 192.81,40.16 198.67,40.16 199,40.49 202.62,40.49 203.11,40.98 207.25,40.98 208.06,41.79 211.45,41.79 213.49,43.83 215.21,43.83 217.95,46.57 218.52,46.57 218.8,46.86 218.8,47.88 220.06,49.14 220.06,50.76 221.35,52.04 221.35,52.44 222.05,53.14 222.87,53.14 224.25,54.52 228.71,54.52 228.95,54.76 228.95,56.68 231.51,59.23 231.51,59.68 231.83,60 231.83,61.24 233.25,62.66 233.25,65.94 235.04,67.73 236.71,67.73 238.37,69.38 238.37,70.36 239.04,71.03 v2(239.04,71.67)
REM_DIODE2_N: length 318
  TOP w0.254: v2(237.07,71.7) CE26.1 237.54,70.57 v2(237.54,69.76) ; UE2.B14 239.41,67.51 v2(239.13,67.23) ; QE5.3 52.59,26.9 52.77,27.08 CE37.2 53.38,27.08 53.58,27.28 54.53,27.28 56.12,28.87 56.12,31.07 58.6,33.55 58.6,35.09 60.06,36.55 61.07,36.55 61.55,37.02 61.55,37.39 v2(61.58,37.43) ; v2(250.85,43.78) 250.85,43.51 249.66,42.32 249.66,31.75 250.76,30.64 250.76,29.72 248.84,27.8 233.51,27.8 225.15,19.44 224.07,19.44 CE46.2 223.62,19.36 QE7.1 221.47,19.36 QE7.2
  IN1 w0.254: v2(237.07,71.7) 237.07,71.15 235.21,69.29 234.78,69.29 231.66,66.17 231.66,62.87 229.66,60.87 229.66,59.47 229.21,59.03 226.09,59.03 223.3,56.24 223.25,56.24 218.07,51.05 218.07,48.94 215.04,45.91 213.6,45.91 210.74,43.06 207.5,43.06 206.79,42.35 194.13,42.35 193.21,41.43 193.21,41.05 v2(193.15,40.98)
  IN4 w0.254: v2(250.85,43.78) 250.85,44.2 251.13,44.47 251.13,46.83 251.51,47.21 255.49,51.19 255.49,56.71 254.85,57.34 254.85,63.16 254.22,63.79 249.39,63.79 248.14,65.04 248.14,66.29 249.07,67.22 249.07,68.68 248.7,69.05 247.83,69.05 247.13,69.75 245.85,69.75 244.64,68.54 239.59,68.54 238.63,69.49 238.63,70.14 v2(237.07,71.7) ; v2(239.13,67.23) 239.13,67.46 237.54,69.05 v2(237.54,69.76)
  BOTTOM w0.254: v2(193.15,40.98) 193.21,40.92 193.21,40.76 192.82,40.36 191.5,40.36 190.06,38.92 78.28,38.92 75.15,35.79 62.41,35.79 61.55,36.65 61.55,37.39 v2(61.58,37.43)
REM_DIODE2_P: length 317.3
  TOP w0.254: v2(251.45,44.06) 251.45,43.39 250.16,42.11 250.16,31.96 251.27,30.86 251.27,29.51 249.05,27.29 233.72,27.29 225.36,18.94 224.11,18.94 CE46.1 QE7.3 ; v2(61,37.43) 61.04,37.39 61.04,37.23 60.86,37.06 59.85,37.06 58.09,35.3 58.09,33.76 55.61,31.28 55.61,29.03 54.38,27.8 53.67,27.8 53.48,27.99 CE37.1 52.92,27.99 52.48,27.55 QE5.1 50.88,27.55 QE5.2 ; v2(237.8,71.73) 237.8,71.67 237.98,71.48 CE26.2 238.06,70.96 238.06,69.81 238.3,69.57 238.68,69.57 239.16,69.1 UE2.A14
  IN1 w0.254: v2(193.74,40.98) 193.72,40.99 193.72,41.22 194.34,41.85 207,41.85 207.71,42.55 210.95,42.55 213.81,45.4 215.25,45.4 218.57,48.73 218.57,50.84 223.46,55.73 223.51,55.73 226.3,58.52 229.42,58.52 230.17,59.26 230.17,60.66 232.17,62.66 232.17,65.96 234.99,68.78 235.42,68.78 237.8,71.15 v2(237.8,71.73)
  IN4 w0.254: v2(237.8,71.73) 237.8,71.7 239.14,70.35 239.14,69.71 239.8,69.04 244.42,69.04 245.64,70.26 247.34,70.26 248.04,69.56 248.91,69.56 249.58,68.89 249.58,67 248.65,66.08 248.65,65.25 249.6,64.3 254.43,64.3 255.36,63.37 255.36,57.55 255.99,56.92 255.99,50.98 251.87,46.85 251.64,46.62 251.64,44.25 v2(251.45,44.06)
  BOTTOM w0.254: v2(61,37.43) 61.04,37.39 61.04,36.44 62.2,35.28 75.36,35.28 78.49,38.41 190.27,38.41 191.71,39.85 193.03,39.85 193.72,40.55 193.72,40.97 v2(193.74,40.98)
REM_DIODE4_N: length 236.1
  TOP w0.254: v2(64.57,37.69) 64.57,38.82 65.22,39.47 70.92,39.47 73.97,42.52 73.97,46.92 80.99,53.95 86.54,53.95 88.47,55.89 89.78,57.19 90.08,57.19 CE39.1 90.54,56.73 QE6.3 ; v2(235.15,70.93) 235.24,70.84 235.73,70.84 CE27.1 236.53,70.47 236.53,69.65 237.37,68.8 UE2.A16
  IN1 w0.254: v2(235.15,70.93) 235.12,70.89 233.34,70.89 232.55,70.1 232.55,69.63 232.11,69.19 231.36,69.19 228.91,66.74 228.91,64.57 227.49,63.15 227.03,63.15 221.09,57.21 221.09,56 216.8,51.7 216.8,49.46 215.05,47.72 214.31,47.72 213.77,47.18 212.05,47.18 210.97,46.1 210.97,45.11 210.69,44.83 207.47,44.83 206.69,44.04 203.19,44.04 202.77,43.62 194.36,43.62 191.87,46.11 191.22,46.11 v2(191.19,46.08)
  BOTTOM w0.254: v2(191.19,46.08) 190.68,45.57 190.68,41.65 189.22,40.19 77.65,40.19 74.83,37.38 64.89,37.38 v2(64.57,37.69)
REM_DIODE4_P: length 239.6
  TOP w0.254: v2(235.15,70.34) 235.19,70.38 235.58,70.38 235.83,70.14 CE27.2 235.94,69.52 237.16,68.3 237.67,68.3 237.91,68.06 UE2.B17 ; v2(63.99,37.69) 64.07,37.77 64.07,39.03 65.01,39.98 70.71,39.98 73.46,42.73 73.46,47.13 80.78,54.46 86.33,54.46 v1(88.12,56.24) 89.57,57.7 90.21,57.7 CE39.2 90.54,58.03 QE6.2 92.81,58.03 QE6.1
  IN1 w0.254: v2(235.15,70.34) 235.12,70.38 233.55,70.38 233.06,69.89 233.06,69.42 232.32,68.68 231.57,68.68 229.42,66.53 229.42,64.35 227.7,62.64 227.24,62.64 221.6,57 221.6,55.79 217.3,51.49 217.3,49.25 215.26,47.21 214.52,47.21 213.98,46.67 212.26,46.67 211.48,45.89 211.48,44.9 210.9,44.32 207.68,44.32 206.9,43.54 203.4,43.54 202.98,43.12 194.15,43.12 v2(191.69,45.57)
  BOTTOM w0.254: v2(63.99,37.69) 64.07,37.62 64.07,37.48 64.68,36.87 75.04,36.87 77.86,39.68 189.43,39.68 191.19,41.44 191.19,45.25 191.5,45.57 v2(191.69,45.57)
RES_BIAS: length 3.1
  TOP w0.102: RL13.1 233.6,83.68 v1(233.6,84.39) 233.6,84.94 234.22,85.56 UL1.12
RESET_OUT#: length 205
  TOP w0.102: UC8.2 115.33,88.87 115.62,89.17 115.62,90.09 CC102.1 113.67,90.73 113.3,90.36 v1(113.3,89.89) 113.72,89.47 v2(113.72,89.06) ; RE56.2 v2(239.5,55.16) ; v2(239.85,59.41) 239.91,59.35 UE2.B39
  IN2 w0.122: v2(239.85,59.41) 239.85,58.88 240.59,58.14 240.59,56.73 239.5,55.64 v2(239.5,55.16) 239.5,54.76 239.14,54.41 239.14,52.34 239.41,52.07 239.41,50.52 238.62,49.73 238.62,49.03 237.57,47.98 236.46,47.98 234.42,45.95 234.42,45.29 233.37,44.24 229.17,44.24 228.28,43.35 226.69,43.35 226.24,42.9 226.24,41.71 224.82,40.3 224.26,40.3 220.99,37.03 211.86,37.03 206.88,32.05 205.79,32.05 204.83,33 198.73,33 198.23,33.51 197.32,33.51 196.41,34.42 193.93,34.42 193.61,34.75 166.83,34.75 155.82,45.76 155.82,51.54 154.7,52.66 154.7,54.31 153.79,55.22 152.62,55.22 150.02,57.82 v2(149.41,57.82) 149.41,58.64 146.99,61.06 146.99,66.2 146.8,66.4 145.91,66.4 145.4,65.89 142.42,65.89 141.15,67.16 140.01,67.16 139.56,67.6 138.74,67.6 138.16,68.17 138.16,77.57 134.99,80.75 134.8,80.75 133.46,82.08 133.46,86.08 131.65,87.89 122.51,87.89 121.84,88.56 114.22,88.56 v2(113.72,89.06)
  BOTTOM w0.076: UC1.AY7 147.07,60.1 147.07,59.01 147.59,58.49 147.98,58.49 148.06,58.42 148.06,58.03 148.13,57.95 148.34,57.95 148.41,58.03 148.41,58.2 148.49,58.27 148.66,58.27 148.74,58.2 148.74,58.03 148.81,57.95 148.97,57.95 149.04,58.03 149.04,58.2 149.12,58.27 149.77,58.27 150.41,57.63 152.06,57.63 152.13,57.55 152.13,56.95 152.06,56.87 151.83,56.87 151.75,56.95 151.75,57.18 151.68,57.25 151.53,57.25 151.45,57.18 151.45,56.95 151.37,56.87 151.22,56.87 151.14,56.95 151.14,57.18 151.07,57.25 150.49,57.25 150.42,57.18 150.42,57.06 150.34,56.98 149.97,56.98 149.89,57.06 149.89,57.59 149.66,57.82 v2(149.41,57.82)
RING2:
  vias: v1(261.91,41.68) v2(262.17,40.98) v2(262.81,40.98) v2(266.92,40.93) v2(267.5,40.96)
RING2_R: length 37
  TOP w0.508: LA10.2 267.3,43.23 CA4.1 267.74,43.26 268.34,42.66 DA3.2
  TOP w1.27: 279.15,57.77 279.13,57.78 270.94,57.78 270.03,56.87
  IN1 w1.27: 267.98,44.93 267.93,44.93 264.97,47.89 264.97,51.69 271.07,57.78 279.31,57.78
  vias: v1(269.13,56.7) v2(268.28,43.87) v2(268.91,43.9)
RSMRST#: length 13.9
  TOP w0.102: UZ5.3 250.48,55.67 RZ22.2 250.28,55.46 250.28,55.11 250.42,54.97 251.43,54.97 252.12,54.27 v2(252.12,53.71) 252.06,53.77 UZ6.2 ; RZ51.2 v1(257.66,55.87) 257.66,55.31 255.49,53.14 v2(254.62,53.14)
  IN2 w0.122: v2(252.12,53.71) 252.17,53.66 254.1,53.66 v2(254.62,53.14)
RUN_ON: length 123.2
  TOP w0.102: RPE10.1 236.78,73.38 236.53,73.63 236.02,73.63 235.33,72.95 235.03,72.95 234.86,73.11 232.22,73.11 231.18,72.07 231.18,70.98 231.86,70.29 232.25,70.29 232.77,69.77 232.77,69.61 233.35,69.02 v2(233.35,68.72) 233.63,68.43 QE2.2 234.67,68.43 234.92,68.69 234.92,69.23 234.62,69.53 234.16,69.53 233.95,69.75 RE279.2 ; v2(204.71,70.78) 204.95,71.01 UZ9.5 ; UZ7.3 185.29,53.75 185.41,53.63 186.17,53.63 186.72,54.18 v2(187,54.18) 187.24,54.43 190.5,54.43 190.81,54.74 193.62,54.74 RZ41.1 ; RE280.2 238.01,54.1 238.36,53.75 v2(238.53,53.75) ; UZ9.3 205.45,71.81 v2(205.35,71.92)
  IN3 w0.122: v2(187,54.18) 187,55.54 186.77,55.76 186.77,57.16 187.19,57.57 187.19,58.61 186.8,58.99 186.8,61.32 185.6,62.52 185.6,69.62 187.43,71.45 187.94,71.45 188.17,71.22 195.61,71.22 196.12,70.71 198.74,70.71 199.31,71.28 204.2,71.28 v2(204.71,70.78) ; v2(233.35,68.72) 233.35,67.79 234.16,66.98 234.16,63.87 234.42,63.61 234.75,63.61 234.75,63.62 235.1,63.62 235.28,63.44 236.17,63.44 237.4,62.2 240.3,62.2 240.94,61.56 240.94,61.25 241.5,60.69 241.82,60.69 242.08,60.42 242.08,59.87 242.08,59.87 242.08,58.24 240.3,56.46 239.48,56.46 238.38,55.36 238.38,53.91 v2(238.53,53.75)
  IN4 w0.084: v2(233.35,68.72) 232.62,67.98 224.94,67.98 222.51,70.41 218.92,70.41 218.26,69.76 216.75,69.76 216.32,69.32 215.7,69.32 214.63,70.39 212.36,70.39 210.86,71.89 209.14,71.89 208.57,72.47 205.9,72.47 v2(205.35,71.92) 205.35,71.41 v2(204.71,70.78)
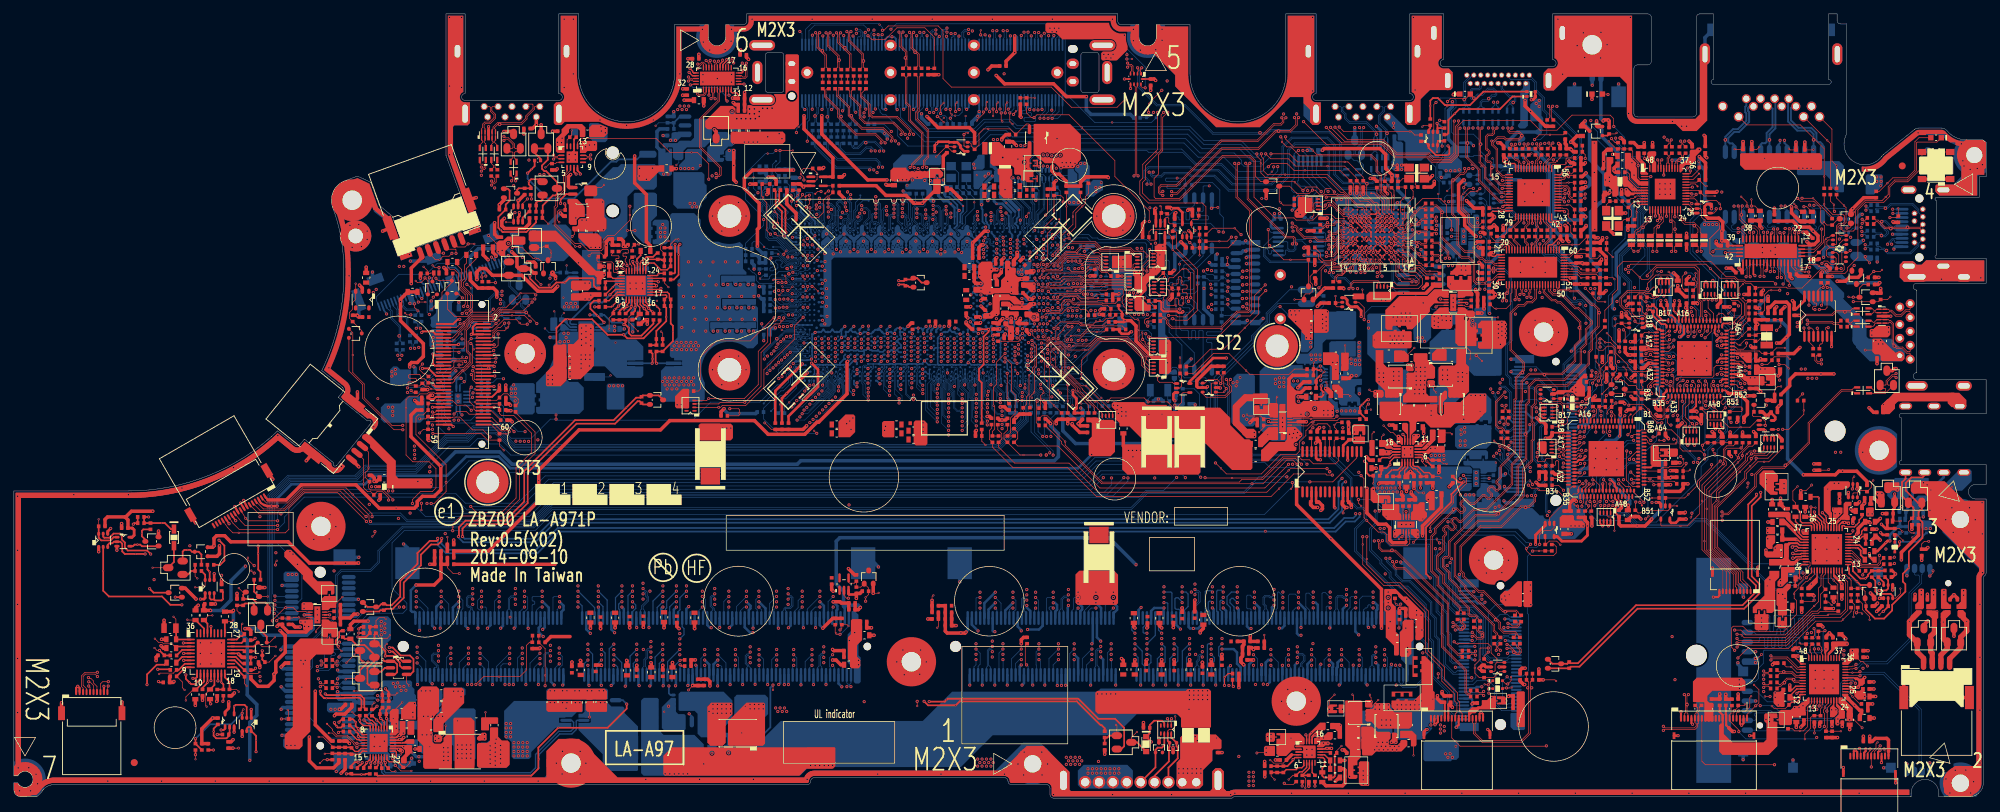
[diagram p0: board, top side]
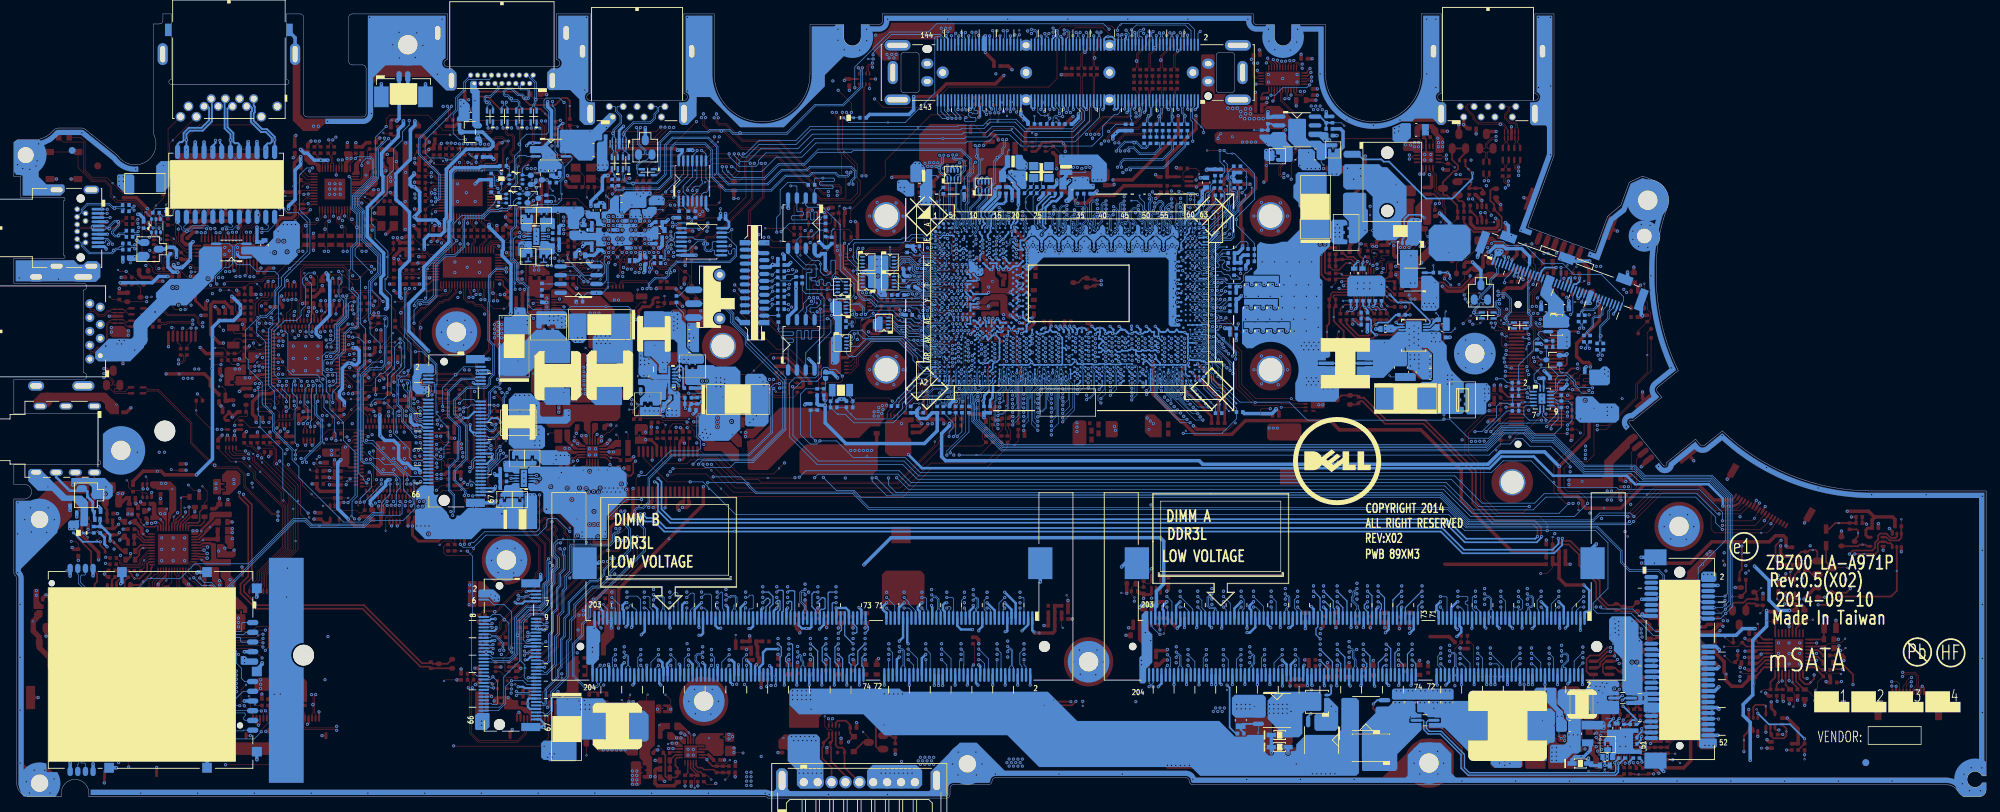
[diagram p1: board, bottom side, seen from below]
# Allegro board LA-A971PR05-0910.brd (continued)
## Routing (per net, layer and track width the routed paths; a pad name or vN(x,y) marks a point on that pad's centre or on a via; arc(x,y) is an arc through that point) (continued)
RUN_ON#: length 3.6
  TOP w0.102: RE68.2 230.8,68.42 v1(230.43,68.05) ; RE68.2 232.07,67.78 QE2.6 ; RE68.2 231.44,68.43 QE2.5
RUN_ON_EC: length 10.8
  TOP w0.102: v2(241.85,67.18) 241.91,67.24 UE2.B9 ; RE279.1 234.42,70.8 234.42,70.08 234.72,69.77 v2(234.96,69.77)
  IN2 w0.122: v2(234.96,69.77) 235.17,69.57 235.22,69.57 236.49,68.3 240.57,68.3 241.68,67.18 v2(241.85,67.18)
RUNPWROK: length 285.4
  TOP w0.102: UE1.A4 231.47,54.68 v2(231.89,55.1) ; v2(238.91,63.64) 238.49,63.22 237.8,63.22 237.67,63.35 UE2.B26 ; v2(235.98,72.38) 235.64,72.72 234.91,72.72 234.75,72.88 232.31,72.88 231.41,71.98 231.41,71.07 231.96,70.52 232.87,70.52 RE67.2 233.03,69.82 233.77,69.08 QE2.3
  IN1 w0.084: v2(62.62,53.22) 62.69,53.14 63.46,53.14 65.08,54.76 65.08,56.11 66.03,57.06 v2(66.03,57.76) ; v2(231.89,55.1) 232.63,55.1 233.74,56.21 233.74,58.62 234.43,59.3 234.43,60.93 234.71,61.21 236.3,61.21 237.54,62.46 237.54,62.84 237.86,63.16 238.43,63.16 v2(238.91,63.64)
  IN2 w0.122: v2(235.98,72.38) 235.81,72.55 235.04,72.55 231.17,76.43 224.86,76.43 221.49,79.8 221.49,80.74 220.45,81.77 215.2,81.77 214.82,82.15 214.82,82.71 212.98,84.56 209.67,84.56 207.26,86.97 201.63,86.97 201.15,87.45 199.61,87.45 197.09,89.97 192.68,89.97 192.25,89.53 185.53,89.53 184.3,88.31 171.9,88.31 165.63,94.58 152.92,94.58 151.25,96.25 151.1,96.4 145.85,96.4 144.57,97.68 144.57,98.79 143.42,99.94 139.45,99.94 138.86,99.35 138.48,99.35 138.1,98.97 138.1,98.34 137.51,97.75 135.52,97.75 134.08,96.31 126.85,96.31 126.68,96.48 124.28,96.48 122.87,95.07 113.83,95.07 112.35,93.59 112.15,93.59 111.22,92.65 109.21,92.65 109.03,92.47 104.73,92.47 104.51,92.26 104.16,91.9 94.04,91.9 90.44,88.3 83.73,88.3 82.56,87.13 77.63,87.13 75.03,84.53 74.58,84.53 71.64,81.6 70.42,81.6 61.54,72.72 61.54,72.14 57.51,68.11 57.51,65.99 56.51,64.98 56.51,62.21 56.08,61.78 56.08,59.03 v2(56.65,58.46)
  IN4 w0.084: v2(66.03,57.76) 64.82,58.96 v2(64.82,60)
  BOTTOM w0.102: v2(235.98,72.38) 235.98,69.28 237.26,68 237.26,64.53 237.75,64.04 238.47,64.04 238.87,63.64 v2(238.91,63.64) ; UC7.10 61.91,57.07 61.61,56.76 61.61,54.62 62.62,53.61 v2(62.62,53.22) ; v2(56.65,58.46) 56.77,58.34 58.2,58.34 59.37,59.51 59.37,59.86 60.38,60.87 61.52,60.87 ; UC7.1 64.19,59.54 64.38,59.73 64.55,59.73 v2(64.82,60) 65.08,60.26 65.08,61.06 v1(64.59,61.55) 64.13,62.01 62.65,62.01 61.52,60.87 ; v2(66.03,57.76) 65.84,57.57 UC7.4 ; 61.52,60.87 61.96,60.43 61.96,58.78 62.17,58.57 UC7.13
S5_1.35V: length 5.2
  TOP w0.102: v1(185.89,1.5) 185.94,1.55 185.94,2.82 PR207.2
  TOP w0.203: 186.49,5.09 186.49,4.3 PR207.2
  TOP w0.254: PR207.2 PC215.1
SATA2_PCIE6_L1: length 136.5
  TOP w0.076: 152.11,73.58 149.17,73.58 149.12,73.53 147.87,73.53 v2(147.48,73.14)
  TOP w0.102: 152.11,73.58 152.26,73.74 153.89,73.74 154.22,74.07 159.84,74.07 160.26,73.65 RPC9.8 ; UE1.A62 235.01,51.65 235.19,51.47 235.19,51.28 235.45,51.03 239.18,51.03 v1(239.28,51.13) 239.38,51.22 239.38,51.59 239.24,51.72 v2(238.92,51.72)
  IN3 w0.081: 154.08,73.74 152.27,73.74 152.17,73.63 147.97,73.63 v2(147.48,73.14)
  IN3 w0.122: 154.08,73.74 154.4,74.06 161.84,74.06 162.15,74.37 164.04,74.37 166.29,76.61 169.72,76.61 171.92,78.81 175.44,78.81 175.96,78.29 178.83,78.29 180.19,76.93 183.07,76.93 185.15,74.85 187.24,74.85 188.28,73.82 189.95,73.82 191.05,72.71 203.77,72.71 204.78,73.73 208.68,73.73 209.53,72.87 211.98,72.87 212.71,73.6 215.01,73.6 216.47,75.06 222.12,75.06 223.6,73.58 225.31,73.58 225.89,73 228.56,73 229.16,72.4 229.16,68.4 230.09,67.48 230.09,64.09 230.56,63.62 230.56,62.23 233.07,59.71 236.6,59.71 236.84,59.48 236.84,55.75 237.62,54.97 237.62,53.02 v2(238.92,51.72)
  BOTTOM w0.081: v2(147.48,73.14) 147.96,72.67 UC1.V6
SATA_ACT#: length 81.2
  IN3 w0.122: v2(153.65,74.11) 153.84,74.31 161.74,74.31 162.05,74.62 163.94,74.62 166.19,76.86 169.62,76.86 172.01,79.26 178.22,79.26 180.3,77.18 183.17,77.18 185.25,75.1 187.35,75.1 188.38,74.07 190.06,74.07 191.16,72.96 203.66,72.96 204.67,73.98 208.78,73.98 209.01,73.75 211.3,73.75 v2(211.73,73.32)
  BOTTOM w0.076: UC1.U3 150.2,73.02 151.62,73.02 151.79,73.19 152.2,73.19 152.62,73.61 153.14,73.61 v2(153.65,74.11)
  BOTTOM w0.102: QZ3.4 211.46,85.75 211.8,85.41 211.8,82.44 212.43,81.8 212.43,77.58 211.8,76.95 v1(211.8,74.24) 211.8,73.38 v2(211.73,73.32)
SATA_COMP: length 6.7
  BOTTOM w0.127: UC1.C12 144.13,82.23 143.81,82.55 143.81,83.58 144.12,83.9 144.12,84.5
  BOTTOM w0.381: 144.12,84.5 v1(142.86,85.76) 141.97,86.65 RC17.1
SATA_LED: length 16.6
  TOP w0.102: v2(206.38,100.38) 206.81,100.81 209.03,100.81 209.64,101.42 LED6.2
  BOTTOM w0.102: RZ36.2 205.61,88.7 205.3,89.01 205.29,89.01 204.9,89.41 204.85,89.46 204.85,91.49 205.64,92.28 205.64,92.87 206.01,93.24 206.01,99.38 v1(206.33,99.7) 206.33,100.34 v2(206.38,100.38)
SATA_LED#: length 3.2
  BOTTOM w0.102: QZ12.2 210.63,89.73 QZ14.6 210.68,90.72 210.23,91.17 209.94,91.17 v1(209.86,91.25)
SATA_PRX_DKTX_N0: length 7.8
  TOP w0.102: v2(127.99,110.38) 127.74,110.13 127.74,108.4 128.55,107.58 128.55,106.93 128.56,106.92 128.56,106.39 128.55,106.38 128.55,105.49 128.88,105.16 C313.2
  BOTTOM w0.102: v2(127.99,110.38) 127.8,110.19 127.8,109.75 127.95,109.6 JDOCK1.56
SATA_PRX_DKTX_N0_C: length 44.9
  TOP w0.102: v2(129.59,90.87) 129.43,91.03 129.43,91.24 130.86,92.68 130.86,95.88 129.03,97.72 129.03,99.73 128.54,100.22 128.54,103.9 C313.1
  IN2 w0.114: v2(129.59,90.87) 129.4,91.06 129.4,91.23 129.46,91.29 130.33,91.29 131.08,92.04 133.28,92.04 133.78,92.54 139.26,92.54 141.56,90.25 141.56,87.93 144,85.49 144,82.91 147.59,79.32 147.59,78.55 148.2,77.94 v2(148.2,77.84)
  BOTTOM w0.081: v2(148.2,77.84) 148.48,77.56 UC1.J5
SATA_PRX_DKTX_P0: length 7.7
  TOP w0.102: C312.2 128.33,105.5 v4(128.33,106.65) 128.33,107.5 127.53,108.3 127.53,110.26 v2(127.41,110.38)
  BOTTOM w0.102: v2(127.41,110.38) 127.6,110.19 127.6,109.75 127.45,109.6 JDOCK1.54
SATA_PRX_DKTX_P0_C: length 45
  TOP w0.102: C312.1 128.32,103.91 128.32,100.13 128.81,99.64 128.81,97.63 130.65,95.79 130.65,92.77 129.21,91.33 129.21,91.07 129.15,91.01 v2(129.01,90.87)
  IN2 w0.114: v2(129.01,90.87) 129.2,91.07 129.2,91.31 129.38,91.48 130.25,91.48 131,92.24 133.2,92.24 133.7,92.74 139.34,92.74 141.76,90.33 141.76,88.01 144.2,85.57 144.2,82.99 147.78,79.4 147.78,78.63 147.93,78.49 v2(148.18,78.49)
  BOTTOM w0.081: v2(148.18,78.49) 148.46,78.21 UC1.H5
SATA_PRX_DTX_N1: length 162.9
  TOP w0.102: CN4.2 44.93,19.11 44.69,19.35 44.41,19.35 v2(44.23,19.18)
  IN4 w0.091: v2(146.26,78.09) 146.05,78.3 145.93,78.3 145.85,78.22 145.85,77.22 145.39,76.76 138.79,76.76 137.53,78.03 137.53,79.03 135.88,80.68 116.71,80.68 115.74,81.65 114.53,81.65 110.66,85.53 110.66,86.59 106.69,90.56 98.38,90.56 96.71,88.88 84.42,88.88 82.7,87.16 77.92,87.16 76.28,85.52 75.96,85.52 71.54,81.1 71.16,81.1 62.43,72.38 62.43,71.51 59.48,68.57 59.48,61.59 58.76,60.87 58.76,56.12 57.9,55.26 57.9,51.57 57.24,50.92 57.24,48.73 55.74,47.23 55.74,43.35 53.26,40.87 53.26,37.8 50.8,35.34 49.62,35.34 47.67,33.38 47.67,23.96 45.16,21.45 45.16,19.86 44.73,19.43 44.49,19.43 v2(44.23,19.18)
  BOTTOM w0.081: UC1.J8 146.74,77.62 v2(146.26,78.09)
SATA_PRX_DTX_N1_C: length 2.8
  TOP w0.102: v2(46.53,19.16) 46.35,19.34 46.16,19.34 CN4.1
  BOTTOM w0.102: v2(46.53,19.16) 46.72,19.34 46.85,19.34 47.14,19.05 JMINI3.25
SATA_PRX_DTX_P1: length 162.8
  TOP w0.102: CN3.2 44.93,19.79 44.72,19.57 44.42,19.57 v2(44.23,19.76)
  IN4 w0.091: v2(44.23,19.76) 44.39,19.6 44.66,19.6 44.99,19.93 44.99,21.53 47.5,24.04 47.5,33.45 49.55,35.51 50.72,35.51 53.09,37.88 53.09,40.95 55.57,43.42 55.57,47.3 57.07,48.8 57.07,50.99 57.73,51.65 57.73,55.33 58.59,56.19 58.59,60.94 59.31,61.66 59.31,68.64 62.26,71.59 62.26,72.45 71.09,81.27 71.47,81.27 75.89,85.69 76.2,85.69 77.85,87.34 82.63,87.34 84.35,89.06 96.64,89.06 98.31,90.73 106.76,90.73 110.83,86.66 110.83,85.6 114.61,81.83 115.81,81.83 116.78,80.86 135.95,80.86 137.7,79.1 137.7,78.1 138.86,76.94 145.32,76.94 145.67,77.29 145.67,78.29 145.86,78.47 146.05,78.47 v2(146.26,78.68)
  BOTTOM w0.081: UC1.H8 146.73,78.21 v2(146.26,78.68)
SATA_PRX_DTX_P1_C: length 2.8
  TOP w0.102: CN3.1 46.2,19.56 46.35,19.56 v2(46.53,19.74)
  BOTTOM w0.102: v2(46.53,19.74) 46.54,19.74 46.72,19.56 46.88,19.56 47.17,19.85 JMINI3.23
SATA_PTX_DKRX_N0: length 7.7
  TOP w0.102: C315.1 130.32,105.5 130.32,107.2 130.1,107.42 130.1,107.43 129.67,107.86 129.64,107.86 129.34,108.15 129.34,110.16 v2(129.52,110.33)
  BOTTOM w0.102: v2(129.52,110.33) 129.33,110.15 129.33,109.7 129.33,109.65 129.45,109.53 JDOCK1.62
SATA_PTX_DKRX_N0_C: length 35.8
  TOP w0.102: C315.2 130.32,103.91 130.32,98.97 130.05,98.7 130.05,97.92 131.69,96.28 131.69,92.34 131.14,91.79 131.14,91.13 v2(131.39,90.88)
  IN2 w0.114: v2(131.39,90.88) 131.21,91.06 131.21,91.19 131.37,91.35 133.57,91.35 134.07,91.85 138.98,91.85 140.87,89.96 140.87,87.61 142.73,85.75 142.73,85.08 142.45,84.8 142.36,84.8 142.23,84.93 142.22,84.93 v2(142.08,85.08)
  BOTTOM w0.081: UC1.B15 141.97,82.59 141.83,82.72 141.83,82.92 141.47,83.29 141.47,84.65 141.7,84.89 141.88,84.89 v2(142.08,85.08)
SATA_PTX_DKRX_P0: length 7.7
  TOP w0.102: v2(128.93,110.33) 129.14,110.13 129.14,108.07 v4(129.72,107.48) 130.11,107.09 130.11,105.5 C314.1
  BOTTOM w0.102: JDOCK1.60 128.95,109.44 129.12,109.61 129.12,110.15 v2(128.93,110.33)
SATA_PTX_DKRX_P0_C: length 35.9
  TOP w0.102: C314.2 130.11,103.91 130.11,99.06 129.83,98.79 129.83,97.83 131.47,96.19 131.47,92.42 130.92,91.88 130.92,91 v2(130.81,90.88)
  IN2 w0.114: v2(142.08,84.5) 142.18,84.6 142.53,84.6 142.93,85 142.93,85.83 141.06,87.69 141.06,90.04 139.06,92.05 133.99,92.05 133.49,91.55 131.29,91.55 131.02,91.27 131.02,91.09 v2(130.81,90.88)
  BOTTOM w0.081: v2(142.08,84.5) 141.88,84.69 141.78,84.69 141.66,84.57 141.66,83.37 142.03,83 142.03,82.81 142.13,82.7 142.23,82.7 UC1.A15
SATA_PTX_DRX_N1: length 172.7
  TOP w0.102: CN5.2 44.93,16.73 44.67,16.46 44.3,16.46 v2(44.11,16.65)
  IN4 w0.091: v2(140.66,84.37) 140.85,84.18 141.07,84.18 141.28,83.97 141.28,81.9 140.37,80.99 140.37,77.75 140.01,77.4 139.17,77.4 138.24,78.32 138.24,81.12 137.69,81.67 116.74,81.67 116.18,82.22 114.87,82.22 111.3,85.8 111.3,87.74 107.59,91.45 90.99,91.45 89.07,89.53 83.51,89.53 82.2,88.21 78.06,88.21 76.01,86.16 75.64,86.16 71.55,82.08 71.22,82.08 61.53,72.39 61.53,72 56.67,67.14 56.67,64.54 56.88,64.33 56.88,63 55.97,62.09 55.97,58.27 57.25,57 57.25,52.13 56.27,51.15 56.27,49.53 53.44,46.7 53.44,42.91 52.62,42.09 52.62,38.19 50.59,36.16 49.26,36.16 46.67,33.57 46.67,24.25 43.02,20.6 43.02,17.1 43.7,16.42 43.87,16.42 v2(44.11,16.65)
  BOTTOM w0.081: UC1.A17 141.41,82.63 141.3,82.63 141.23,82.71 141.23,83.98 141.04,84.17 140.85,84.17 v2(140.66,84.37)
SATA_PTX_DRX_N1_C: length 2.8
  TOP w0.102: v2(46.54,16.54) 46.36,16.36 46.23,16.36 CN5.1
  BOTTOM w0.102: JMINI3.31 47.21,16.65 46.92,16.36 46.73,16.36 v2(46.54,16.54)
SATA_PTX_DRX_P1: length 172.7
  TOP w0.102: CN6.2 44.93,15.89 44.58,16.24 44.28,16.24 v2(44.11,16.07)
  IN4 w0.091: v2(44.11,16.07) 43.93,16.25 43.63,16.25 42.85,17.03 42.85,20.67 46.5,24.32 46.5,33.64 49.19,36.33 50.52,36.33 52.44,38.26 52.44,42.16 53.26,42.98 53.26,46.77 56.1,49.6 56.1,51.22 57.07,52.2 57.07,56.93 55.8,58.2 55.8,62.16 56.71,63.07 56.71,64.26 56.5,64.46 56.5,67.21 61.36,72.07 61.36,72.46 71.15,82.25 71.48,82.25 75.56,86.34 75.94,86.34 77.99,88.39 82.13,88.39 83.44,89.7 89,89.7 90.92,91.63 107.66,91.63 111.48,87.81 111.48,85.87 114.95,82.4 116.26,82.4 116.81,81.85 137.76,81.85 138.42,81.19 138.42,78.4 139.24,77.57 139.94,77.57 140.2,77.83 140.2,81.06 141.1,81.97 141.1,83.9 141,84 140.87,84 v2(140.66,83.78)
  BOTTOM w0.081: UC1.B17 141.2,82.47 141.04,82.63 141.04,83.9 140.96,83.98 140.85,83.98 v2(140.66,83.78)
SATA_PTX_DRX_P1_C: length 2.7
  TOP w0.102: v2(46.54,15.96) 46.36,16.14 46.14,16.14 CN6.1
  BOTTOM w0.102: v2(46.54,15.96) 46.73,16.14 46.87,16.14 47.17,15.85 JMINI3.33
SATACLK_REQ#: length 115.8
  IN3 w0.122: v2(226.98,73.42) 225.81,74.59 224.99,74.59 224.88,74.47 223.07,74.47 222.23,75.31 214.49,75.31 213.18,74 209.11,74 208.88,74.23 204.67,74.23 204.08,74.82 200.01,74.82 198.41,73.21 194.54,73.21 193.92,73.83 190.66,73.83 190.18,74.31 188.48,74.31 187.45,75.35 185.36,75.35 183.27,77.43 180.4,77.43 178.32,79.51 171.91,79.51 169.52,77.11 166.08,77.11 163.84,74.87 161.94,74.87 161.63,74.56 154.7,74.56 154.3,74.96 v2(154.3,75.26)
  BOTTOM w0.076: 152.77,75.26 151.97,74.46 151.55,74.46 151.53,74.44 151.52,74.44 151.43,74.35 151.12,74.35 150.83,74.06 UC1.T2
  BOTTOM w0.081: 153.82,75.26 v1(153.4,75.26) 152.77,75.26
  BOTTOM w0.102: RC68.2 155.01,75.97 v2(154.3,75.26) 153.82,75.26 ; JNGFF2.44 223.59,49.4 222.94,48.74 222.4,48.74 221.99,49.15 221.99,50.55 221.39,51.16 221.39,53.38 222.57,54.56 222.57,54.85 223.14,55.42 223.14,59.52 223,59.66 223,62.52 227.47,67 227.47,72.92 v2(226.98,73.42)
SD/MMCCD#: length 19.8
  TOP w0.102: UR1.21 261.58,13.54 261.09,13.05 261.09,12.66 v2(260.97,12.55) 261.02,12.5 261.02,10.12 260.85,9.94 CR35.1 RR11.1 v1(262.99,9.64)
  BOTTOM w0.102: v2(260.97,12.55) 260.97,12.95 260.05,13.88 252.4,13.88 250.89,15.39 JSD1.18
SD/MMCCLK: length 22.6
  TOP w0.102: v2(260.71,24.13) 260.61,24.04 CR23.1 RR1.2
  BOTTOM w0.102: v2(260.71,24.13) 260.44,23.86 260.44,21.31 260.06,20.93 256.84,20.93 256.55,21.22 256.55,22.66 256.45,22.77 256.15,22.77 256.05,22.66 256.05,21.44 255.92,21.31 251.96,21.31 251.83,21.18 251.83,19.41 251.13,18.71 251.13,17.25 250.68,16.79 JSD1.5
SD/MMCCLK_R: length 2.3
  TOP w0.102: RR1.1 260.23,21.71 v1(260.23,21.28) 260.23,20.78 260.38,20.63 UR1.43
SD/MMCCMD: length 23.7
  TOP w0.102: UR1.45 259.58,20.67 259.18,21.07 v2(259.18,21.5)
  BOTTOM w0.102: JSD1.2 251.13,22.5 251.26,22.62 251.26,23.04 251.38,23.17 251.88,23.17 251.98,23.07 251.98,21.84 252.11,21.72 252.36,21.72 252.49,21.84 252.49,23.07 252.59,23.17 252.9,23.17 253,23.07 253,21.84 253.12,21.72 253.38,21.72 253.51,21.84 253.51,23.07 253.61,23.17 253.91,23.17 254.01,23.07 254.01,21.84 254.14,21.72 254.39,21.72 254.52,21.84 254.52,23.07 254.62,23.17 254.93,23.17 255.03,23.07 255.03,21.84 255.16,21.72 255.41,21.72 255.54,21.84 255.54,23.04 255.66,23.17 256.95,23.17 257.08,23.04 257.08,22.45 257.21,22.33 259.05,22.33 259.18,22.2 v2(259.18,21.5)
SD/MMCDAT0: length 30.7
  TOP w0.089: v2(265.09,16.56) 264.65,16.99 264.21,16.99 264.15,16.93 UR1.30 ; v2(263.44,21.25) 262.82,21.25 262.38,20.81 UR1.38
  IN1 w0.084: v2(263.44,21.25) 264.09,21.25 264.53,20.81 264.53,18.17 265.09,17.61 v2(265.09,16.56)
  BOTTOM w0.089: JSD1.7 252.92,12.6 254.04,11.47 261.6,11.47 262.94,12.81 262.94,16.55 263.83,17.44 264.78,17.44 265.09,17.13 v2(265.09,16.56)
SD/MMCDAT1: length 29.8
  TOP w0.089: UR1.37 262.78,20.76 262.95,20.94 263.12,20.94 v2(263.44,20.62) ; v2(264.45,16.57) 264.41,16.53 UR1.29
  IN1 w0.084: v2(264.45,16.57) 264.71,16.82 264.71,17.45 264.15,18.01 264.15,20.65 263.93,20.87 263.69,20.87 v2(263.44,20.62)
  BOTTOM w0.089: v2(264.45,16.57) 264.77,16.89 264.77,17 264.65,17.12 263.96,17.12 263.26,16.42 263.26,12.67 261.73,11.15 253.91,11.15 252.78,12.28 250.73,12.28 250.58,12.13 250.58,11.89 250.81,11.66 250.81,11.39 250.62,11.2 JSD1.8
SD/MMCDAT2: length 3.2
  TOP w0.102: UR1.48 258.38,20.63 257.97,21.04 RR4.1 257.22,22.19 v1(257.06,22.35)
SD/MMCDAT2_R: length 23.7
  TOP w0.102: RR4.2 257.97,23.53 v2(258.16,23.72)
  BOTTOM w0.102: v2(258.16,23.72) 258.16,25.5 258.29,25.63 259.07,25.63 259.19,25.76 259.19,26.22 259.07,26.35 254.63,26.35 254.52,26.25 254.52,25.3 254.42,25.2 254.12,25.2 254.02,25.3 254.02,26.25 253.91,26.35 253.41,26.35 253.28,26.22 253.28,24.09 253.18,23.98 252.87,23.98 252.77,24.09 252.77,26.2 252.64,26.33 252.39,26.33 252.26,26.2 252.26,24.09 252.16,23.98 251.26,23.98 251.13,24.11 251.13,25.17 251,25.3 JSD1.9
SD/MMCDAT3: length 2.2
  TOP w0.102: RR3.1 258.56,21.89 v1(258.56,21.27) 258.56,21.06 258.78,20.84 UR1.47
SD/MMCDAT3_R: length 25
  TOP w0.102: RR3.2 259.19,23.44 259.19,24.36 v2(259.13,24.42)
  BOTTOM w0.102: v2(259.13,24.42) 259.32,24.23 259.32,23.15 259.19,23.02 257.67,23.02 257.54,23.15 257.54,25.81 257.42,25.94 257.02,25.94 256.91,25.84 256.91,23.68 256.81,23.58 256.43,23.58 256.33,23.68 256.33,25.81 256.2,25.94 255.95,25.94 255.82,25.81 255.82,23.68 255.72,23.58 255.41,23.58 255.31,23.68 255.31,24.26 255.18,24.38 254.93,24.38 254.8,24.26 254.8,23.68 254.7,23.58 254.4,23.58 254.29,23.68 254.29,24.28 254.17,24.4 253.91,24.4 253.79,24.28 253.79,23.68 253.68,23.58 250.83,23.58 250.51,23.9 JSD1.1
SD_REXT: length 3.1
  TOP w0.102: RR5.1 265.71,13.57 264.66,14.63 v1(264.66,14.64) 264.66,14.69 264.02,15.33 UR1.26
SD_UHS2_D0N: length 22.2
  TOP w0.089: v2(265.17,18.69) 265.16,18.71 264.79,18.71 264.69,18.61 264.27,18.61 264.19,18.53 UR1.34
  BOTTOM w0.089: JSD1.12 274.7,32.28 274.63,32.2 274.63,30.96 273.11,29.45 273.11,22.78 269.67,19.34 266.05,19.34 265.54,18.83 265.32,18.83 v2(265.17,18.69)
SD_UHS2_D0P: length 22.3
  TOP w0.089: UR1.35 264.56,18.93 264.66,19.02 264.93,19.02 v2(265.17,19.27)
  BOTTOM w0.089: JSD1.11 273.6,32.24 273.7,32.14 274.16,32.14 274.31,31.99 274.31,31.09 272.8,29.58 272.8,22.92 269.54,19.66 265.92,19.66 265.41,19.15 265.3,19.15 v2(265.17,19.27)
SD_UHS2_D1N: length 22.3
  TOP w0.089: v2(265.75,18.22) 265.6,18.08 v1(264.66,18.08) 264.12,18.08 264.07,18.13 UR1.33
  BOTTOM w0.089: v2(265.75,18.22) 265.83,18.14 269.23,18.14 274.56,12.81 274.56,5 274.7,4.86 JSD1.15
SD_UHS2_D1P: length 22.2
  TOP w0.089: UR1.32 264.07,17.73 264.12,17.68 265.7,17.68 v2(265.75,17.63)
  BOTTOM w0.089: JSD1.16 273.6,4.92 273.74,5.05 274.16,5.05 274.24,5.14 274.24,12.67 269.1,17.82 265.93,17.82 v2(265.75,17.63)
SDWP: length 15.5
  TOP w0.102: v2(260.62,10.33) 260.62,12.22 260.48,12.36 260.48,12.68 260.68,12.89 v1(260.68,13) 260.68,13.18 261.18,13.68 UR1.20
  BOTTOM w0.102: JSD1.19 250.83,9.8 250.94,9.69 259.97,9.69 v2(260.62,10.33)
SIO_EXT_SCI#: length 150.5
  TOP w0.102: RC156.1 154.79,76.19 154.27,75.66 148.93,75.66 v2(148.24,74.98) ; v2(232.46,56.62) 232.59,56.74 234.56,56.74 v1(235.32,55.98) 235.7,55.6 235.7,55.37 236.48,54.58 237.41,54.58 237.54,54.71 237.54,57.12 238.16,57.74 UE2.A33
  IN2 w0.081: 153.82,71.36 152.48,71.36 149.37,74.47 148.53,74.47 148.24,74.75 v2(148.24,74.98)
  IN2 w0.122: 153.82,71.36 160.75,71.36 161.21,70.9 162.86,70.9 164.01,69.76 164.01,63.35 168.28,59.07 168.28,54.58 170.34,52.52 170.34,46.03 175.57,40.8 192.37,40.8 193.86,42.28 205.36,42.28 207.38,44.3 211.37,44.3 214.22,47.15 216.32,47.15 216.75,47.57 216.75,56.6 217.58,57.44 v2(217.58,58.59)
  IN4 w0.084: v2(228.28,65.59) 225.93,65.59 219.53,59.18 218.17,59.18 v2(217.58,58.59)
  BOTTOM w0.081: v2(148.24,74.98) 148.24,75.12 UC1.N5
  BOTTOM w0.102: v2(228.28,65.59) 228.51,65.59 229.1,65 229.1,61.95 230.11,60.93 230.11,58.01 230.62,57.51 231.95,57.51 232.46,57 v2(232.46,56.62)
SIO_EXT_SMI#: length 115.8
  TOP w0.102: v2(235.13,75.26) 235.13,75.44 236.4,76.71 242.14,76.71 242.66,76.19 242.66,71.88 243.01,71.52 243.01,69.42 243.16,69.27 UE2.A6 ; v2(180.14,73.95) v1(179.47,73.28) 178.61,72.42 178.61,70.14 177.93,69.46 176.34,69.46 173.22,66.34 163.8,66.34 163.63,66.52 163.4,66.52 v2(163.33,66.46) 163.33,66.24 163.77,65.81 RPC5.5
  IN1 w0.084: v2(163.33,66.46) 162.7,66.46 161.35,67.81 155.71,67.81 154.74,66.84 151.75,66.84 150.25,68.34 v2(148.77,68.34)
  IN4 w0.084: v2(235.13,75.26) 234.27,75.26 232.66,73.64 230.33,73.64 228.32,71.63 226.83,71.63 225.55,72.91 224.34,72.91 222.56,74.7 215.3,74.7 214.2,73.59 213.66,73.59 212.98,74.28 209.43,74.28 209.19,74.04 204.99,74.04 203.57,72.62 195.89,72.62 194.95,71.68 188.03,71.68 187.79,71.92 182.88,71.92 180.85,73.95 v2(180.14,73.95)
  BOTTOM w0.081: UC1.AG5 148.61,68.17 148.77,68.33 v2(148.77,68.34)
SIO_EXT_WAKE#: length 151
  TOP w0.102: UE2.B5 243.91,67.45 v2(243.75,67.29)
  IN2 w0.081: 153.82,59.44 152.83,60.42 152.83,60.62 152.39,61.06 v2(152.39,62.01)
  IN2 w0.122: v2(243.75,67.29) 243.98,67.06 243.98,66.08 243.79,65.89 240.91,65.89 240.46,66.33 240.46,67.67 240.08,68.05 238.05,68.05 237.35,67.35 235.06,67.35 233.76,66.04 233.76,63.55 231.89,61.68 231.89,59.51 230.9,58.52 229.14,58.52 226.12,55.5 226.12,54.39 227.06,53.45 227.06,48.19 226.16,47.29 225.01,47.29 224.52,46.8 224.52,46.42 223.43,45.33 222.12,45.33 219.82,43.04 219.82,40.64 219.28,40.09 215.27,40.09 214.46,39.28 210.92,39.28 207.29,35.65 206.37,35.65 206.25,35.52 203.18,35.52 201.7,37 198.39,37 197.82,37.57 195.59,37.57 195.03,37 170.01,37 161.28,45.74 161.28,46.69 159.5,48.47 159.5,53.76 153.82,59.44
  BOTTOM w0.076: 153.82,63.51 153.82,62.81 153.02,62.01 v2(152.39,62.01) 151.95,62.45 150.91,62.45 UC1.AU2
  BOTTOM w0.102: 153.82,63.51 156.34,66.03 161.34,66.03 162.31,65.05 163.56,65.05 163.83,65.32 RPC7.6
SIO_PWRBTN#: length 268.6
  TOP w0.102: UE2.B58 245.06,62.35 244.72,62.01 244.72,60.85 244.51,60.64 239.71,60.64 239.43,60.36 v2(239.42,60.36) ; v2(57.37,42.46) 57.37,43.02 58.52,44.17 60.22,44.17 60.76,44.7 60.76,47.48 59.78,48.46 57.43,48.46 56.45,49.44 v1(56.45,56.17) 56.45,57.45 56.91,57.91 58.1,57.91 58.43,58.24 59.5,58.24 59.74,58.48 60.43,58.48 60.59,58.32 JXDP1.41
  IN2 w0.122: v2(147.45,66.47) 147.24,66.25 147.24,62.58 151.18,58.64 151.18,58.08 152.23,57.03 153.4,57.03 155.71,54.72 155.71,53.08 156.82,51.96 v2(156.82,46.17) 167.25,35.75 194.03,35.75 194.14,35.64 200.93,35.64 202.3,34.27 204.99,34.27 206.15,33.11 206.52,33.11 211.44,38.03 220.19,38.03 223.7,41.54 223.7,43.41 224.65,44.36 227.87,44.36 228.3,44.79 228.3,46.04 228.97,46.71 231.51,46.71 232.59,47.79 234.27,47.79 235.3,48.82 235.3,50.38 236.4,51.47 236.4,54.46 237.1,55.16 237.1,56.93 239.26,59.09 239.26,60.19 v2(239.42,60.36)
  BOTTOM w0.081: UC1.AL7 147.51,66.42 v2(147.45,66.47)
  BOTTOM w0.102: v2(57.37,42.46) 59.26,40.57 74.18,40.57 78.11,44.5 155.15,44.5 v2(156.82,46.17)
SIO_RCIN#: length 146.8
  TOP w0.102: v2(148.9,73) 149.2,72.69 153.52,72.69 154.01,73.19 157.3,73.19 157.47,73.35 v1(159.16,73.35) 159.54,73.35 159.69,73.2 159.69,72.41 159.54,72.25 159.54,71.32 159.77,71.09 159.77,70.87 160.29,70.34 RPC15.4 ; UE2.A27 235.64,62.1 v2(235.56,62.02)
  IN2 w0.081: 153.82,67.83 153.02,67.83 152.48,68.37 151.39,68.37 150.91,68.84 150.91,72.12 150.32,72.72 149.18,72.72 148.9,73 v2(148.9,73)
  IN2 w0.122: v2(219.19,55.66) 218.79,55.26 218.79,54.59 219.14,54.23 219.14,53.43 218.76,53.04 218.76,48.86 219.32,48.3 219.32,46.46 218.43,45.57 217.73,45.57 216.14,43.98 214.21,43.98 211.85,41.63 209.4,41.63 206.67,38.9 198.87,38.9 198.33,39.44 195.92,39.44 195,38.52 173.59,38.52 166.45,45.66 166.45,50.05 165.9,50.61 165.9,52.61 160.84,57.67 160.84,58.18 160.32,58.7 157.03,58.7 155.16,60.56 155.16,66.69 154.03,67.83 153.82,67.83
  IN4 w0.084: v2(235.56,62.02) 234.95,62.63 232.49,62.63 231.74,63.38 230.76,63.38 230.17,63.98 228.26,63.98 227.74,63.46 226.36,63.46 220.55,57.64 219.39,57.64 218.49,56.74 218.49,56.11 218.94,55.66 v2(219.19,55.66)
  BOTTOM w0.081: UC1.V4 149.29,72.6 v2(148.9,73)
SIO_SLP_A#: length 285.8
  TOP w0.102: v2(164.64,60.81) 164.64,60.17 164.9,59.92 166.75,59.92 166.93,59.74 UC6.1 ; UE2.B28 237.8,62.35 237.88,62.27 238.36,62.27 v2(238.78,62.69) ; v2(38.44,40.96) 35.26,40.96 JAPS1.6
  IN1 w0.084: v2(185.6,51.18) 185.14,51.18 184.85,51.47 183.88,51.47 183.06,52.3 183.06,54.91 182.72,55.25 181.98,55.25 179.29,57.94 172.95,57.94 172.68,58.21 169.57,58.21 166.72,61.06 164.9,61.06 v2(164.64,60.81) 164.64,61.28 159.66,66.27 156.56,66.27 153.19,62.9 150.99,62.9 149.72,61.63 148.61,61.63 147.57,62.68 147.57,65.74 148.17,66.34 v2(148.17,66.49)
  IN4 w0.084: v2(238.78,62.69) 238.78,63.03 238.65,63.16 237.05,63.16 236.95,63.05 235.34,63.05 235.34,63.34 235.07,63.62 234.7,63.62 234.55,63.47 232.49,63.47 232.1,63.85 230.96,63.85 230.31,64.49 228.11,64.49 227.54,63.92 226.17,63.92 220.5,58.25 218.84,58.25 218.03,57.44 218.03,55.04 214.36,51.37 214.36,50.07 214.17,49.88 214.17,49.58 212.56,47.97 207.76,47.97 205.54,45.76 197.6,45.76 196.98,46.37 195.25,46.37 194.2,47.42 191.73,47.42 190.01,49.14 187.36,49.14 185.6,50.91 v2(185.6,51.18)
  BOTTOM w0.081: v2(148.17,66.49) 148.17,66.17 UC1.AL5
  BOTTOM w0.102: v2(38.44,40.96) 38.7,40.96 41.6,43.86 63.63,43.86 64.99,42.5 72.55,42.5 76.48,46.43 153.64,46.43 155.78,48.58 168.09,48.58 171.76,52.24 171.76,58.77 170.46,60.07 168.32,60.07 168.28,60.11 168.26,60.11 167.63,60.74 167.63,61.76 167.31,62.08 166.8,62.08 166.48,61.76 165.6,61.76 v2(164.64,60.81)
SIO_SLP_LAN#: length 134.8
  TOP w0.102: v2(238.68,60.93) 238.94,60.68 238.94,59.88 238.82,59.75 238.82,59.16 238.91,59.06 UE2.B37 ; UL3.3 200,37.83 v2(199.83,37.66) 199.71,37.66 v1(199.39,37.34)
  IN2 w0.081: v2(146.98,67.36) 146.98,67.79 147.05,67.86 148.77,67.86 149.06,67.56 149.06,67.37 149.4,67.03 150.55,67.03 151.18,66.39 151.18,65.19 152.26,64.11 152.26,63.15 153.14,62.27 153.14,60.46 153.82,59.79
  IN2 w0.122: v2(230.64,59.14) 228.25,59.14 227.03,57.92 227.03,56.76 225.87,55.6 225.87,54.29 226.81,53.35 226.81,48.3 226.05,47.54 224.91,47.54 224.27,46.9 224.27,46.52 223.33,45.58 222.01,45.58 219.57,43.14 219.57,40.81 219.11,40.34 215.16,40.34 214.35,39.53 210.82,39.53 207.57,36.29 205.74,36.29 205.67,36.36 202.91,36.36 201.6,37.66 v2(199.83,37.66) 199.41,37.66 199,37.25 198.49,37.25 197.92,37.82 195.49,37.82 194.92,37.25 170.11,37.25 161.52,45.84 161.52,46.79 159.75,48.57 159.75,53.86 153.82,59.79
  IN4 w0.084: v2(238.68,60.93) 238.28,60.53 237.43,60.53 235.8,58.9 234.94,58.9 234.7,59.14 v2(230.64,59.14)
  BOTTOM w0.081: v2(146.98,67.36) 147.31,67.04 UC1.AJ7
SIO_SLP_S0#: length 181.7
  TOP w0.102: v2(50.75,39.86) 50.75,39.86 46.6,44.02 41.84,44.02 39.58,41.76 39.58,38.74 39.07,38.23 v1(32.37,38.23) 31.52,38.23 30.79,38.96 30.47,39.42 JAPS1.15
  IN2 w0.122: v2(167.37,46.2) 167.37,50.2 166.65,50.92 166.65,52.92 162.16,57.41 162.16,63.32 159.35,66.13 157.14,66.13 154.34,68.93 152.31,68.93 v2(151.76,69.47)
  BOTTOM w0.076: v2(151.76,69.47) 151.39,69.11 151.12,69.11 150.95,68.93 150.95,68.76 150.72,68.52 150.2,68.52 UC1.AF3
  BOTTOM w0.102: v2(50.75,39.86) 51.21,39.4 74.67,39.4 78.6,43.33 161.94,43.33 162.95,44.34 165.51,44.34 v2(167.37,46.2)
SIO_SLP_S3#: length 287.1
  TOP w0.102: JAPS1.2 36.09,42.8 36.36,42.53 39.39,42.53 41.56,44.7 47.82,44.7 v1(48.77,43.75) 51.56,40.96 v2(51.56,40.55) ; RE280.1 238.01,56.24 v2(238.86,57.09) 239.16,57.39 UE2.A35
  IN1 w0.084: v2(179.86,16.41) 180.58,17.13 200.56,17.13 204.27,20.84 204.27,29.59 207.75,33.07 207.75,35.69 210.41,38.35 219.37,38.35 223.49,42.47 223.49,43.3 222.56,44.23 222.56,44.93 223.07,45.45 224.26,45.45 224.9,46.09 226.7,46.09 227.42,46.81 227.83,46.81 228.75,47.73 231.23,47.73 231.52,48.02 234.83,48.02 237.1,50.29 237.1,51.79 237.67,52.36 237.67,54.84 238.86,56.03 v2(238.86,57.09)
  IN2 w0.081: 153.82,58.03 153.81,58.04 152.11,58.04 151.82,58.33 151.82,58.9 149.14,61.58 149.14,62.47 v2(148.81,62.8)
  IN2 w0.122: 153.82,58.03 158.5,53.34 158.5,48.05 159.78,46.78 v2(159.78,46.17)
  IN4 w0.084: v2(179.86,16.41) 177.98,18.29 177.98,22.64 174.61,26.01 165.53,26.01 163.63,27.91 163.63,36.36 159.78,40.21 v2(159.78,46.17)
  BOTTOM w0.081: v2(148.81,62.8) 148.83,62.78 UC1.AT4
  BOTTOM w0.102: v2(159.78,46.17) 159.78,46.17 157.4,43.79 78.41,43.79 74.48,39.86 56.54,39.86 55.67,40.73 51.73,40.73 v2(51.56,40.55)
SIO_SLP_S4#: length 310.2
  TOP w0.076: v2(147.53,67.42) 147.35,67.6 T9.1
  TOP w0.102: v2(50.7,40.57) 50.66,40.57 46.99,44.25 41.75,44.25 38.94,41.44 35.46,41.44 JAPS1.5 ; RE282.1 234.18,72.08 234.75,71.51 v2(234.94,71.51) ; UE2.B36 v2(238.41,59.42)
  IN1 w0.084: v2(178.73,16.37) 178.73,16.73 179.55,17.55 200.38,17.55 203.58,20.75 203.58,29.74 207.33,33.49 207.33,36.33 209.78,38.77 216.28,38.77 221.82,44.31 221.82,46.63 222.24,47.04 223.48,47.04 223.99,47.56 226.01,47.56 227.06,48.61 227.06,48.92 227.75,49.61 230.89,49.61 231.93,50.65 233.58,50.65 234.28,51.35 234.28,54.01 235.01,54.74 235.01,57.26 235.57,57.82 236.54,57.82 238.13,59.42 v2(238.41,59.42)
  IN2 w0.081: 153.82,57.33 153.71,57.43 152.21,57.43 151.44,58.2 151.44,58.74 147.46,62.71 147.46,65.72 147.81,66.07 147.81,66.72 147.53,67 v2(147.53,67.42)
  IN2 w0.122: 153.82,57.33 157.66,53.49 157.66,46.47 v2(158,46.13)
  IN4 w0.084: v2(178.73,16.37) 178.73,16.66 177.77,17.62 177.77,22.56 174.53,25.8 165.44,25.8 163.42,27.83 163.42,36.27 158,41.69 v2(158,46.13)
  BOTTOM w0.081: UC1.AJ6 147.96,66.98 147.53,67.41 v2(147.53,67.42)
  BOTTOM w0.102: v2(238.41,59.42) 237.92,59.42 237.44,59.9 237.44,61.16 237.63,61.35 237.86,61.35 237.86,61.35 238.2,61.35 238.2,61.35 239.01,61.35 239.28,61.62 239.28,63 239.09,63.19 238.13,63.19 237.03,64.29 237.03,67.91 235.76,69.18 235.76,71.25 235.49,71.51 v2(234.94,71.51) ; v2(50.7,40.57) 51.21,41.08 55.64,41.08 56.64,40.08 74.38,40.08 78.31,44.02 156.89,44.02 158,45.13 v2(158,46.13)
SIO_SLP_S5#: length 266.9
  TOP w0.081: v2(147.97,64.34) 148.34,63.96 148.34,60.47 T8.1
  TOP w0.102: v2(235.7,66.54) 235.76,66.6 UE2.A18 ; JAPS1.4 35.91,41.67 38.85,41.67 41.65,44.47 47.41,44.47 51.12,40.77 51.12,40.07 v2(51.33,39.85)
  IN2 w0.081: v2(147.97,64.34) 148.57,63.73 150.16,63.73 150.55,63.35 150.55,61.29 152.07,59.77 152.07,58.58 152.32,58.33 153.82,58.33
  IN2 w0.122: 153.82,58.33 153.87,58.33 158.75,53.45 158.75,48.16 160.36,46.55 v2(160.36,46.14) 160.36,45.59 169.7,36.26 194.23,36.26 194.35,36.14 201.5,36.14 202.87,34.78 206.56,34.78 206.68,34.9 207.6,34.9 211.23,38.54 219.98,38.54 223.2,41.75 223.2,43.67 224.39,44.86 227.66,44.86 227.79,45 227.79,46.59 228.63,47.42 228.63,51.77 229.29,52.43 229.29,54.77 229.1,54.97 229.1,56.01 234.5,61.41 234.5,62.15 235.51,63.16 235.89,63.16 236.12,63.39 236.12,66.12 v2(235.7,66.54)
  BOTTOM w0.081: UC1.AP5 148.25,64.05 v2(147.97,64.34)
  BOTTOM w0.102: v2(160.36,46.14) 160.36,45.69 158.23,43.56 78.5,43.56 74.57,39.63 51.56,39.63 v2(51.33,39.85)
SIO_SLP_SUS#: length 144.1
  TOP w0.102: v2(249.21,58.75) 247.4,58.75 246.8,59.35 UE2.B52
  IN1 w0.084: v2(148.81,64.11) 150.56,64.11 151.07,64.62 152.31,64.62 152.88,65.19 154.52,65.19 156.28,66.96 159.93,66.96 164.95,61.93 166.8,61.93 169.85,58.89 172.96,58.89 173.23,58.62 179.57,58.62 182.26,55.92 183,55.92 184,54.93 184,54.46 186.6,51.86 187.98,51.86 193.76,46.07 194.29,46.07 194.69,46.47 196.75,46.47 197.51,45.71 205.42,45.71 207.24,47.53 209.62,47.53 210.02,47.93 210.88,47.93 211.43,48.49 213.22,48.49 214.37,49.64 214.37,51.13 216.97,53.72 216.97,55.92 219.44,58.39 220.41,58.39 225.44,63.42 225.44,66.99 231.17,72.73 231.43,72.73 231.65,72.95 235.29,72.95 235.53,73.2 238.59,73.2 239.02,72.77 240.22,72.77 240.67,72.32 240.72,72.32 242.25,70.79 242.25,65.65 244.43,63.47 247.14,63.47 247.76,62.84 249.61,62.84 251.32,61.12 251.32,60.11 249.97,58.75 v2(249.21,58.75)
  BOTTOM w0.081: v2(148.81,64.11) 149.29,63.63 UC1.AP4
SIO_SLP_WLAN#: length 115.7
  TOP w0.102: v2(227.42,55.76) 226.72,55.76 226.3,55.34 226.3,54.88 226.47,54.71 UE1.A14
  IN2 w0.081: 153.82,58.73 152.46,60.09 152.34,60.09 150.93,61.51 150.93,64.68 150.4,65.21 v2(148.79,65.21)
  IN2 w0.122: v2(227.42,55.76) 228.05,55.13 228.05,53.44 228.38,53.11 228.38,47.53 227.52,46.67 227.22,46.67 226.65,46.11 224.91,46.11 223.64,44.83 222.32,44.83 220.32,42.83 220.32,40.37 218.73,38.79 211.13,38.79 207.49,35.15 206.58,35.15 206.45,35.03 202.97,35.03 201.6,36.39 194.45,36.39 194.34,36.5 169.8,36.5 160.78,45.53 160.78,46.48 159,48.26 159,53.55 153.82,58.73
  BOTTOM w0.081: v2(148.79,65.21) 148.49,65.21 UC1.AM5
SKIP#: length 2.9
  TOP w0.203: PR520.2 85.66,71.67 v1(86.25,72.27) 86.88,72.89 PU500.7
SKIP#1: length 5.8
  TOP w0.254: v2(84.95,68.55) v1(84,69.51) 82.98,70.52 82.98,71.16 83.5,71.67 PR520.1
  BOTTOM w0.203: PU501.1 84.65,68.26 v2(84.95,68.55)
SL_BAT_PRES#: length 5
  TOP w0.102: v1(35.34,18.17) 35.13,17.96 33.69,17.96 PR854.1
  TOP w0.254: PR854.1 31.79,19.85 PU800.21
SLATE_MODE: length 19.4
  TOP w0.081: v2(148.97,66.26) 148.99,66.26 149.59,65.66 150.72,65.66 151.81,64.57 153.82,64.57
  TOP w0.102: RPC10.7 163.31,61.76 162.61,62.46 162.61,63.51 160.1,66.03 156.12,66.03 154.66,64.57 v1(154.24,64.57) 153.82,64.57
  BOTTOM w0.081: UC1.AL4 148.97,66.1 v2(148.97,66.26)
SLEEVE: length 17.2
  IN4 w1.27: 274.32,39.09 273.85,39.56 273.85,43.07 270.14,46.77 262.69,46.77 262.43,46.52
  vias: v1(261.1,44.53) v2(262.04,45.36) v2(262.68,45.36) v2(275.25,38.84) v2(275.87,38.84)
SLEEVE_R:
  vias: v1(279.01,44.86)
SLEWA: length 4.9
  TOP w0.203: v2(91.36,70.59) 90.92,71.03 90.79,71.03 90.55,71.27 PU500.15
  TOP w0.254: PR500.1 92.06,69.89 v2(91.36,70.59)
  BOTTOM w0.102: PR510.2 v1(92.58,71.66)
  BOTTOM w0.254: PR510.2 91.48,70.7 v2(91.36,70.59)
SLICE_BAT_ON: length 228
  TOP w0.102: UE1.A31 223.38,45.65 223.36,45.63 222.81,45.63 v2(222.41,46.04) 221.48,46.04 RE17.2 ; v2(130.04,13.94) v1(130.04,13.27)
  TOP w0.254: PR845.2 34.45,22.76 v2(34.72,23.02)
  IN1 w0.084: v2(130.04,13.94) 130.75,14.66 132.55,14.66 135.67,17.79 176.74,17.79 178.63,15.9 178.89,15.9 179.15,16.15 179.15,16.71 179.77,17.34 200.47,17.34 204.06,20.93 204.06,29.67 207.54,33.16 207.54,35.78 210.33,38.56 219.18,38.56 223.25,42.63 223.25,43.22 222.17,44.3 222.17,45.8 v2(222.41,46.04)
  IN3 w0.254: v2(130.04,13.94) 124.42,13.94 118.92,19.44 118.92,22.26 117.86,23.32 117.86,25.33 117.25,25.95 52.31,25.95 51.38,25.01 47.76,25.01 44.32,21.58 41.09,21.58 39.93,20.42 37.33,20.42 v2(34.72,23.02)
SLICE_BAT_PRES#: length 450.1
  TOP w0.102: v2(225.35,45.63) 225.12,45.4 UE1.B33 ; v2(223.06,44.36) 222.36,45.06 RE5.2
  TOP w0.254: PR854.2 34.51,18.44 v2(34.77,18.71) ; v2(131.02,13.94) 131.6,13.37 v1(135.59,13.37) 136.16,13.94 152.99,13.94 156.42,10.52 156.58,10.52 157.02,10.07 PR6.1
  IN1 w0.084: v2(131.02,13.94) 131.53,14.45 132.64,14.45 135.76,17.58 176.6,17.58 178.7,15.48 180.28,15.48 181.71,16.92 200.64,16.92 204.48,20.75 204.48,29.5 207.96,32.98 207.96,35.6 210.5,38.14 219.46,38.14 223.7,42.38 223.7,43.41 223.06,44.04 v2(223.06,44.36) 223.06,44.68 223.38,45 224.71,45 v2(225.35,45.63)
  IN1 w0.254: v2(34.77,18.71) 34.66,18.71 33.58,19.79 33.58,22.71 35.17,24.29 35.17,30.14 35.87,30.84 35.87,40.11 v2(35.42,40.55)
  IN2 w0.122: v2(149.45,97.95) 149.45,97.56 148.79,96.9 146.55,96.9 145.76,97.69 145.76,98.4 145.31,98.85 145.31,99.82 143.02,102.11 137.66,102.11 136.86,101.31 136.86,100.27 137.56,99.57 137.56,98.67 137.16,98.26 135.19,98.26 134.97,98.48 134.53,98.48 132.85,96.81 127.06,96.81 126.89,96.97 124.02,96.97 122.67,95.62 113.68,95.62 112.15,94.08 111.94,94.08 111.66,93.8 109.6,93.8 108.77,92.98 104.47,92.98 103.9,92.4 93.83,92.4 90.65,89.22 83.94,89.22 82.35,87.63 77.42,87.63 74.82,85.03 74.19,85.03 71.31,82.15 70.27,82.15 61.3,73.18 58.31,73.18 56.25,71.11 56.25,65.5 54.84,64.09 54.84,62.77 55.58,62.04 55.58,58.38 55.83,58.13 55.83,54.58 54.96,53.7 54.96,50.94 48.2,44.18 39.05,44.18 v2(35.42,40.55)
  IN3 w0.254: v2(34.77,18.71) 34.77,16.42 35.12,16.06 37.5,16.06 38.09,16.65 42.62,16.65 43.64,17.67 44.78,17.67 45.4,18.29 45.4,20.02 46.27,20.88 47.14,20.88 48.37,22.11 50.79,22.11 51.54,22.86 53.23,22.86 55.93,25.57 117.09,25.57 117.48,25.17 117.48,23.16 118.54,22.1 118.54,19.28 124.36,13.46 130.54,13.46 v2(131.02,13.94)
  BOTTOM w0.102: JDOCK1.141 150.45,98.94 v2(149.45,97.95) 150.27,97.95 150.95,98.63 JDOCK1.143
SM_RCOMP0: length 11.4
  TOP w0.381: v2(114.83,62.68) 115.75,61.76 v1(115.75,61.06) 115.75,59.28 111.51,55.04 RC130.1
  BOTTOM w0.229: UC1.AU60 114.83,62.25 v2(114.83,62.68)
SM_RCOMP1: length 9.3
  TOP w0.381: RC131.1 110.56,57.62 v1(111.25,58.32) v2(114.2,61.27)
  BOTTOM w0.229: UC1.AV60 114.39,61.45 v2(114.2,61.27)
SM_RCOMP2: length 10.7
  TOP w0.381: v2(113.49,62.57) v1(112.63,61.71) 109.6,58.68 RC132.1
  BOTTOM w0.229: UC1.AU61 113.69,62.38 v2(113.49,62.57)
SMART_DET#: length 2.1
  TOP w0.102: T99.1 225.97,55.99 UE1.A15
SML0_SMBCLK: length 17.9
  TOP w0.102: RC30.2 163.82,69.63 163.31,69.13 162.99,69.13 162.74,68.87 162.74,68.49 v2(163.22,68.01)
  IN4 w0.084: v2(163.22,68.01) 163.01,68.22 162.83,68.22 161.17,66.57 153.83,66.57 153.82,66.58 153.8,66.56 v2(153.8,65.95)
  BOTTOM w0.076: UC1.AN1 151.35,64.43 152.08,64.43 153.1,65.44 153.29,65.44 v2(153.8,65.95)
  BOTTOM w0.102: v2(163.22,68.01) 163.39,68.19 163.79,68.19 RC33.2
SML0_SMBDATA: length 15.4
  TOP w0.102: RC32.2 163.37,68.74 v2(163.22,68.59)
  IN4 w0.084: v2(163.22,68.59) 163.05,68.43 162.74,68.43 161.09,66.78 153.92,66.78 153.86,66.84 v2(153.28,67.42)
  BOTTOM w0.076: UC1.AK1 151.33,66.65 152.42,66.65 153.19,67.42 v2(153.28,67.42)
  BOTTOM w0.102: v2(163.22,68.59) 163.39,68.41 163.79,68.41 RC32.2
SML1_SMBCLK: length 135
  TOP w0.102: UE2.B6 243.41,67.59 243.32,67.5 243.32,67.07 v2(242.92,66.67)
  IN1 w0.084: v2(162.58,69.66) 162.8,69.44 162.8,69.23 163.04,68.99 163.38,68.99 164.2,68.17 164.2,67.41 164.96,66.65 170.04,66.65 177.2,59.49 179.64,59.49 182.54,56.6 183.28,56.6 184.67,55.21 184.67,54.74 186.88,52.53 188.26,52.53 191.69,49.1 192.18,49.1 194.34,46.93 196.94,46.93 197.7,46.18 205.23,46.18 207.04,47.99 209.43,47.99 209.83,48.4 210.68,48.4 211.24,48.95 212.11,48.95 213.46,50.31 213.46,50.87 216.5,53.91 216.5,56.12 219.33,58.95 219.8,58.95 224.82,63.96 224.82,67.77 230.57,73.52 231.36,73.52 231.46,73.42 232.34,73.42 232.89,73.97 235.21,73.97 235.51,73.66 238.78,73.66 239.21,73.24 240.41,73.24 240.86,72.78 242.48,72.78 242.6,72.66 242.6,71.64 242.85,71.39 242.85,69.63 243.13,69.36 243.13,66.88 v2(242.92,66.67)
  IN4 w0.084: v2(162.58,69.66) 160.78,67.86 153.02,67.86 152.77,67.61 152.77,65.07 152.29,64.59 152.29,64.14 v2(152.79,63.64)
  BOTTOM w0.076: UC1.AU3 150.1,62.13 150.5,62.53 150.75,62.53 150.88,62.66 150.88,62.93 151.05,63.1 152.25,63.1 v2(152.79,63.64)
  BOTTOM w0.102: RPC14.2 163.65,70.46 163.52,70.33 163.05,70.33 162.76,70.04 162.76,69.83 v2(162.58,69.66)
SML1_SMBDATA: length 127.5
  TOP w0.102: v2(243.56,69.54) 243.66,69.44 UE2.A5
  IN1 w0.084: v2(243.56,69.54) 243.29,69.54 243.07,69.77 243.07,71.48 242.81,71.73 242.81,72.75 242.56,72.99 240.95,72.99 240.5,73.45 239.3,73.45 238.87,73.87 235.6,73.87 235.29,74.18 232.8,74.18 232.26,73.63 231.55,73.63 231.44,73.73 230.49,73.73 224.61,67.86 224.61,64.05 219.72,59.16 219.24,59.16 216.29,56.2 216.29,54 213.25,50.96 213.25,50.39 212.02,49.17 211.15,49.17 210.6,48.61 209.74,48.61 209.34,48.2 206.96,48.2 205.14,46.39 197.79,46.39 197.03,47.15 194.43,47.15 192.26,49.31 191.78,49.31 188.34,52.74 186.97,52.74 184.88,54.83 184.88,55.29 183.37,56.81 182.63,56.81 179.73,59.7 177.28,59.7 170.13,66.86 165.05,66.86 164.41,67.5 164.41,68.26 163.47,69.2 163.13,69.2 163.01,69.32 163.01,69.5 v2(163.17,69.66)
  BOTTOM w0.076: 153.82,68.01 153.1,68.01 152.11,67.02 150.2,67.02 UC1.AH3
  BOTTOM w0.102: 153.82,68.01 154.37,68.01 154.94,68.58 156.07,68.58 v1(156.32,68.83) 156.62,68.83 157.61,69.82 159.67,69.82 160.03,69.46 160.57,69.46 160.83,69.19 162.7,69.19 v2(163.17,69.66) 162.99,69.83 162.99,69.95 163.14,70.1 163.52,70.1 163.65,69.96 RPC14.1
SNB_1.05V: length 1.9
  TOP w0.102: PR305.2 v1(191.63,65.25)
SNUB_1.35V: length 1.8
  TOP w0.102: PC208.1 v1(201.47,6.16)
SNUB_3V: length 6.3
  TOP w0.102: PR111.2 205.66,64.74 205.85,64.93 209.13,64.93 209.64,64.43 v1(209.64,63.26)
SNUB_5V: length 1.9
  TOP w0.102: v1(201.6,64.87) 200.46,63.73 PC114.1
SOFT_START_GC: length 120.2
  TOP w0.102: PR17.2 78.47,84.75 78.23,84.51 78.23,83.25 v1(78.51,82.97)
  TOP w0.254: PR17.2 79.39,84.79 79.39,85.52 v2(79.28,85.64) ; PU800.2 v2(24.4,22.35)
  IN3 w0.254: v2(24.4,22.35) 24.4,23.57 20.69,27.28 20.69,32.49 22.02,33.82 29.77,33.82 31.79,35.84 37.91,35.84 39.61,34.14 42.28,34.14 43.36,35.22 46.06,35.22 48.98,38.14 48.98,40.93 51.25,43.19 51.71,43.19 54.34,45.82 54.34,47.25 54.66,47.57 54.66,53.95 55.55,54.85 55.55,57 54.72,57.82 53.26,57.82 51.91,59.18 51.91,70.59 58.57,77.25 65.81,77.25 70.59,82.03 72.73,82.03 74.81,84.11 77.39,84.11 78.41,85.13 79.05,85.13 79.28,85.36 v2(79.28,85.64)
SPI_CLK32: length 13.3
  TOP w0.102: RPC12.7 166.29,73.88 RC61.2 166.73,74 166.82,74.1 167.5,74.1 167.61,74.2 167.61,75.01 167.73,75.13 167.99,75.13 168.11,75.01 v1(168.11,74.46) 168.11,74.08 168.24,73.95 168.76,73.95 168.89,73.82 168.89,73.49 168.76,73.36 168.3,73.36 168.2,73.26 168.2,72.95 168.3,72.85 168.76,72.85 168.89,72.72 168.89,72.23 v2(168.79,72.13)
  BOTTOM w0.102: UC3.6 169.91,69.95 169.78,70.09 169.78,70.72 169.34,71.16 168.9,71.16 168.64,71.41 168.64,71.84 168.79,71.98 v2(168.79,72.13)
SPI_CLK64: length 19.6
  BOTTOM w0.102: RC62.2 168.06,81.84 169.02,80.87 170.74,80.87 171.18,80.43 UC2.6 171.18,78.12 169.91,76.85 168.54,76.85 168.41,76.72 168.41,75.14 168.53,75.03 169.06,75.03 v3(169.18,74.91) 169.18,74.66 169.05,74.53 168.52,74.53 168.41,74.43 168.41,74.01 168.29,73.88 168.01,73.88 167.91,73.99 167.91,74.65 167.78,74.78 167.53,74.78 167.4,74.65 167.4,73.99 167.3,73.88 166.99,73.88 166.89,73.99 166.89,74.17 166.76,74.29 166.51,74.29 166.38,74.17 166.38,73.99 166.28,73.88 RPC11.6
SPI_CLKTPM: length 3
  TOP w0.102: RZ26.2 RZ35.2 190.05,51.49 UZ1.21
SPI_DIN32: length 21.7
  TOP w0.102: RPC12.5 165.67,72.88 165.81,72.75 165.81,72.48 165.51,72.17 v1(165.51,71.74) 165.51,70.67 165.7,70.48 v2(167.83,70.48)
  BOTTOM w0.102: v2(167.83,70.48) 167.83,67.64 168.05,67.41 168.95,67.41 169.05,67.31 169.05,66.24 169.16,66.14 169.46,66.14 169.56,66.24 169.56,67.31 169.66,67.41 169.97,67.41 170.07,67.31 170.07,66.24 170.17,66.14 170.48,66.14 170.58,66.24 170.58,67.31 170.68,67.41 171.06,67.41 171.18,67.28 UC3.2
SPI_DIN64: length 22.1
  BOTTOM w0.102: RPC11.8 165.6,72.88 165.72,72.76 165.72,72.49 165.25,72.01 163.39,72.01 162.96,72.45 162.96,74.08 164.96,76.09 v3(164.96,78.27) 164.96,82.64 167.46,85.14 169.61,85.14 169.91,85.45 UC2.2
SPI_DINTPM: length 2
  TOP w0.102: RZ30.2 186.8,51.71 UZ1.26
SPI_DO32: length 13.4
  TOP w0.102: v2(168.21,72.1) 168.33,71.98 v1(168.33,71.35) 168.33,71.16 168.2,71.03 167.77,71.03 167.64,71.16 167.64,71.9 167.51,72.03 167.26,72.03 167.13,71.9 167.13,71.09 167.01,70.97 166.12,70.97 165.99,71.09 165.99,71.97 166.29,72.28 166.29,73.13 166.04,73.38 RPC12.6
  BOTTOM w0.102: v2(168.21,72.1) 167.77,71.67 167.77,71.22 168.34,70.65 169.17,70.65 169.29,70.52 169.29,70.14 169.17,70.01 168.79,70.01 168.64,69.87 UC3.5
SPI_DO64: length 13.1
  BOTTOM w0.102: UC2.5 172.45,78.52 170.17,76.24 169.13,76.24 169.02,76.14 169.02,75.83 169.13,75.73 169.66,75.73 169.79,75.6 169.79,73.38 169.66,73.25 v3(166.87,73.25) 165.79,73.25 165.66,73.38 RPC11.7
SPI_DOTPM: length 2
  TOP w0.102: UZ1.23 188.75,51.67 RZ29.2
SPI_PCH_CLK: length 15.2
  TOP w0.102: v2(163.44,73.89) 163.44,73.88 RPC12.2
  IN1 w0.084: v2(163.44,73.89) 164.26,73.89 164.64,73.51 170.58,73.51 171.09,73 174.64,73 v2(174.68,73.04)
  BOTTOM w0.102: RPC12.2 163.44,73.88 v2(163.44,73.89) ; JSPI1.7 175.21,72.52 v2(174.68,73.04) 174.01,73.04 RC227.1
SPI_PCH_CS0#: length 22
  IN4 w0.084: v2(174.09,81.55) 174.09,78.94 175.6,77.43 175.6,74.44 v2(174.78,73.62)
  BOTTOM w0.102: RC228.1 174.38,74.02 v2(174.78,73.62) 174.88,73.52 JSPI1.9 ; v2(174.09,81.55) 174.09,83.68 173.6,84.18 173.6,87.63 172.53,88.7 169.88,88.7 RC35.1
SPI_PCH_CS0#_R: length 12.9
  BOTTOM w0.102: UC2.1 168.64,87.69 168.52,87.81 166.1,87.81 165.98,87.94 165.98,88.19 166.1,88.32 167.82,88.32 167.95,88.45 167.95,88.7 167.82,88.83 165.91,88.83 165.79,88.96 165.79,89.21 165.91,89.34 v3(167.45,89.34) 168.5,89.34 168.63,89.21 RC35.2
SPI_PCH_CS1#: length 3
  BOTTOM w0.102: JSPI1.1 174.37,69.52 174.37,69.52 RC50.1 173.85,70.38 RC224.1
SPI_PCH_CS1#_R: length 12.8
  BOTTOM w0.102: RC50.2 v1(173.85,67.58) 173.85,67.31 173.72,67.18 171.79,67.18 171.67,67.06 171.67,66.8 171.79,66.68 173.28,66.68 173.41,66.55 173.41,66.29 173.28,66.17 171.79,66.17 171.67,66.04 171.67,65.79 171.79,65.66 172.33,65.66 172.45,65.53 UC3.1
SPI_PCH_DIN: length 14.4
  TOP w0.102: v2(164.92,72.43) 164.46,72.88 RPC12.4
  IN1 w0.084: v2(164.92,72.43) 165.07,72.58 170.17,72.58 170.67,72.07 174.53,72.07 v2(174.74,71.86)
  BOTTOM w0.102: RPC12.4 164.46,72.88 v2(164.92,72.43) ; JSPI1.5 175.08,71.52 v2(174.74,71.86) 174.36,72.24 RC226.1
SPI_PCH_DO: length 17.5
  TOP w0.102: RPC12.3 163.76,73.38 163.56,73.19 v2(163.56,72.51)
  IN1 w0.084: v2(174.74,71.17) 174.31,71.6 170.04,71.6 169.53,71.09 168.58,71.09 168.33,71.35 165.34,71.35 164.18,72.51 v2(163.56,72.51)
  BOTTOM w0.102: RC225.1 174.1,71.17 v2(174.74,71.17) 174.74,70.9 175.12,70.52 JSPI1.3 ; v2(163.56,72.51) 163.56,72.51 163.44,72.64 163.44,73.29 163.53,73.38 RPC12.3
SPI_PCH_DO2: length 21
  IN4 w0.084: v2(173.46,81.62) 173.46,78.91 175.14,77.24 175.14,74.86 v2(174.77,74.49)
  BOTTOM w0.102: RC55.1 RC29.2 171.51,74.9 171.76,74.9 172.14,74.52 173.42,74.52 RC229.1 174.23,75.03 v2(174.77,74.49) 174.8,74.52 JSPI1.11 ; v2(173.46,81.62) 172.25,82.83 RC38.1
SPI_PCH_DO2_32: length 16.1
  BOTTOM w0.102: UC3.3 169.91,64.17 167.29,66.79 v1(167.29,70.97) 167.29,72.16 167.82,72.68 169.91,72.68 170.42,73.19 RC55.2
SPI_PCH_DO2_64: length 17.2
  BOTTOM w0.102: v3(172.07,88.21) 171.31,88.21 171.18,88.09 UC2.3 171.18,84.62 171.06,84.49 170.38,84.49 170.25,84.37 170.25,84.05 170.38,83.92 171.82,83.92 171.95,83.79 171.95,83.44 171.82,83.31 169.84,83.31 169.74,83.41 169.74,84.33 169.61,84.45 169.36,84.45 169.23,84.33 169.23,83.41 169.13,83.31 168.83,83.31 168.72,83.41 168.72,84.33 168.6,84.45 168.34,84.45 168.22,84.33 168.22,83.41 168.11,83.31 167.81,83.31 167.71,83.41 167.71,83.62 167.58,83.74 RC38.2
SPI_PCH_DO3: length 16.6
  TOP w0.102: v2(165.62,75.01) 165.62,75.5 RC31.2 164.71,74.92 164.71,74.52 164.57,74.38 RPC12.1
  IN1 w0.084: v2(165.62,75.01) 165.96,75.35 167.69,75.35 168.01,75.67 170.17,75.67 170.74,75.09 173.13,75.09 173.39,75.36 v2(174.74,75.36)
  BOTTOM w0.102: RC230.1 174.18,75.92 v2(174.74,75.36) 174.9,75.52 JSPI1.13 ; RPC12.1 164.6,74.38 165.22,75.01 v2(165.62,75.01)
SPI_PCH_DO3_32: length 12.8
  TOP w0.102: v2(169.41,72.11) 169.37,72.14 169.37,75.7 168.8,76.27 v1(168.33,76.27) 168.18,76.27 166.9,74.98 166.36,74.98 166.23,74.85 166.23,74.51 166.1,74.38 RPC12.8
  BOTTOM w0.102: UC3.7 171.18,69.65 170.26,70.57 170.26,71.26 v2(169.41,72.11)
SPI_PCH_DO3_64: length 12.8
  BOTTOM w0.102: RPC11.5 165.74,74.38 166.12,74.76 166.12,75.2 165.66,75.66 165.66,77.38 165.79,77.51 166.17,77.51 166.29,77.38 166.29,75.78 166.71,75.36 167.34,75.36 167.81,75.83 v3(167.81,76.94) 167.81,77.24 168.02,77.46 168.97,77.46 169.91,78.4 UC2.7
SPKR: length 178.9
  TOP w0.102: v2(153.98,72.63) 153.98,72.46 154.27,72.17 155.42,72.17 155.85,72.61 RC180.2 ; RA12.2 264.47,26.89 v1(263.3,25.73) 263.07,25.5 259.37,25.5 255.42,21.55 249.53,21.55 v2(248.17,20.19)
  IN4 w0.084: v2(153.98,72.63) 155.61,71 163.68,71 164.27,70.42 164.27,61.89 162.61,60.24 162.61,56.87 165.29,54.19 168.68,54.19 170.38,52.49 170.38,49.31 187.16,32.53 196.59,32.53 196.82,32.76 197.6,32.76 197.83,32.53 199.33,32.53 200.93,34.14 205.18,34.14 206.28,35.23 206.28,36.53 209.58,39.84 214.67,39.84 215.35,40.53 217.43,40.53 221.91,45.01 224.18,45.01 225.16,44.02 244.05,44.02 247.41,40.67 247.41,28.4 249.36,26.45 249.36,21.39 v2(248.17,20.19)
  BOTTOM w0.076: 153.82,72.63 151.99,72.63 151.63,72.27 151.02,72.27 150.73,72.56 UC1.V2
  BOTTOM w0.102: 153.82,72.63 153.97,72.63 v2(153.98,72.63)
SRCDET: length 7.7
  TOP w0.102: UV8.C2 199.58,78.62 200.56,78.62 201.66,77.52 201.66,76.94 201.85,76.75 202.43,76.75 203.26,75.92 v1(203.81,75.92) 204.9,75.92 RV84.1
SRTCRST#: length 31.7
  IN4 w0.084: v2(147.53,61.14) 148.12,60.55 151.37,60.55 152.97,58.95 152.97,58.59 159.78,51.79 166.68,51.79 167.41,51.06 168.09,51.06 v2(168.5,51.47)
  BOTTOM w0.081: UC1.AV6 147.87,61.45 147.56,61.14 v2(147.53,61.14)
  BOTTOM w0.102: RC10.2 CC3.2 169.22,52.19 v2(168.5,51.47)
STSTART_DCBLOCK_GC: length 104.1
  TOP w0.102: v2(109.27,16.29) v1(109.27,15.58)
  TOP w0.254: PU800.16 v2(29.36,16.89)
  IN3 w0.254: v2(29.36,16.89) 31.76,16.89 34.13,14.52 47.26,14.52 47.96,15.21 47.96,18.74 51.69,22.48 53.38,22.48 54.07,23.16 74.72,23.16 75.21,22.67 80.47,22.67 80.9,23.1 93.15,23.1 95.24,25.19 96.28,25.19 98.34,23.13 107.68,23.13 108.94,21.87 108.94,16.62 v2(109.27,16.29)
  BOTTOM w0.254: v2(109.27,16.29) 108.89,15.91 108.89,10.2 108,9.31 PR811.2
SUS_ON: length 300.4
  TOP w0.102: v2(37.21,25.55) 37.21,25.63 39.03,27.44 v3(39.13,27.44) 40.22,27.44 40.77,26.9 42.02,26.9 42.12,26.8 UZ8.3 ; RPE10.2 237.28,72.8 236.83,72.35 v2(236.57,72.35) 236.19,71.97 235.69,71.97 235.5,72.16 RE282.2 234.59,72.66 233.83,72.66 RE281.2
  TOP w0.254: v2(185.45,1.75) 185.47,1.78 PR207.1
  IN3 w0.122: 185.41,1.75 187.5,3.85 193.03,3.85 193.66,4.48 202.02,4.48 202.97,5.44 202.97,11.01 206.01,14.05 206.01,16.97 205.92,17.06 205.92,30.02 206.89,30.99 206.89,32.4 212.05,37.56 221.08,37.56 223.85,40.33 229.26,40.33 230.66,41.74 230.66,42.88 230.94,43.16 232.67,43.16 232.81,43.03 232.81,42.39 233.31,41.88 235.11,41.88 v2(235.81,42.58)
  IN3 w0.254: v2(185.45,1.75) 184.84,1.75 182.04,4.55 176.14,4.55 175.44,5.24 175.44,14.13 173.6,15.98 173.6,16.81 172.33,18.08 136.47,18.08 123.76,30.78 120.72,30.78 120.07,31.44 56.05,31.44 54.62,30.01 49.74,30.01 43.35,23.62 38.07,23.62 37.21,24.49 v2(37.21,25.55)
  BOTTOM w0.102: v2(235.81,42.58) 234.79,43.6 234.79,49.86 236.46,51.54 236.46,54.14 238.41,56.09 238.41,58.08 238.94,58.61 238.94,60.57 239.51,61.14 239.51,63.66 238.91,64.27 237.84,64.27 237.49,64.62 237.49,68.1 236.21,69.37 236.21,72 v2(236.57,72.35)
SUS_ON_EC: length 11.9
  TOP w0.102: v2(231.93,71.61) 232.42,72.11 RE281.1 ; UE2.B23 238.1,64.85 v2(238.24,65)
  IN3 w0.122: v2(238.24,65) 238.24,65.11 236.32,67.04 234.9,67.04 234.04,67.89 234.04,69.67 232.09,71.61 v2(231.93,71.61)
SUS_STAT#/LPCPD#: length 10.6
  TOP w0.102: v2(149.72,67.69) 150.65,68.62 153.38,68.62 153.71,68.29 155.37,68.29 v1(155.77,68.69) 156.79,68.69 157.24,69.14 158.11,69.14 RC82.2
  BOTTOM w0.081: v2(149.72,67.69) 149.72,67.73 149.34,68.1 UC1.AG4
SUSACK#: length 136
  TOP w0.102: UE2.A23 236.09,64.1 235.87,64.32 235.27,64.32 234.98,64.03 v2(234.93,64.03) ; RC81.2 157.26,68.62 156.71,68.06 153.57,68.06 153.24,68.39 151.69,68.39 151.09,67.79 v1(151.09,67.49) 150.31,66.71 v2(150.31,66.19)
  IN2 w0.081: v2(150.31,66.19) 150.61,65.89 150.61,65.25 151.27,64.59 151.27,61.6 152.58,60.3
  IN2 w0.122: v2(234.93,64.03) 234.93,63.92 232.14,61.14 232.14,59.41 230.14,57.41 228.39,57.41 226.37,55.39 226.37,54.77 228.13,53.01 228.13,47.63 227.53,47.03 227.22,47.03 226.55,46.36 224.81,46.36 223.53,45.08 222.22,45.08 220.07,42.93 220.07,40.48 218.63,39.03 211.03,39.03 207.39,35.4 206.47,35.4 206.35,35.27 203.07,35.27 201.7,36.64 194.55,36.64 194.44,36.75 169.91,36.75 161.03,45.63 161.03,46.59 159.25,48.36 159.25,53.65 152.61,60.3 152.58,60.3
  BOTTOM w0.081: UC1.AK2 150.59,66.47 v2(150.31,66.19)
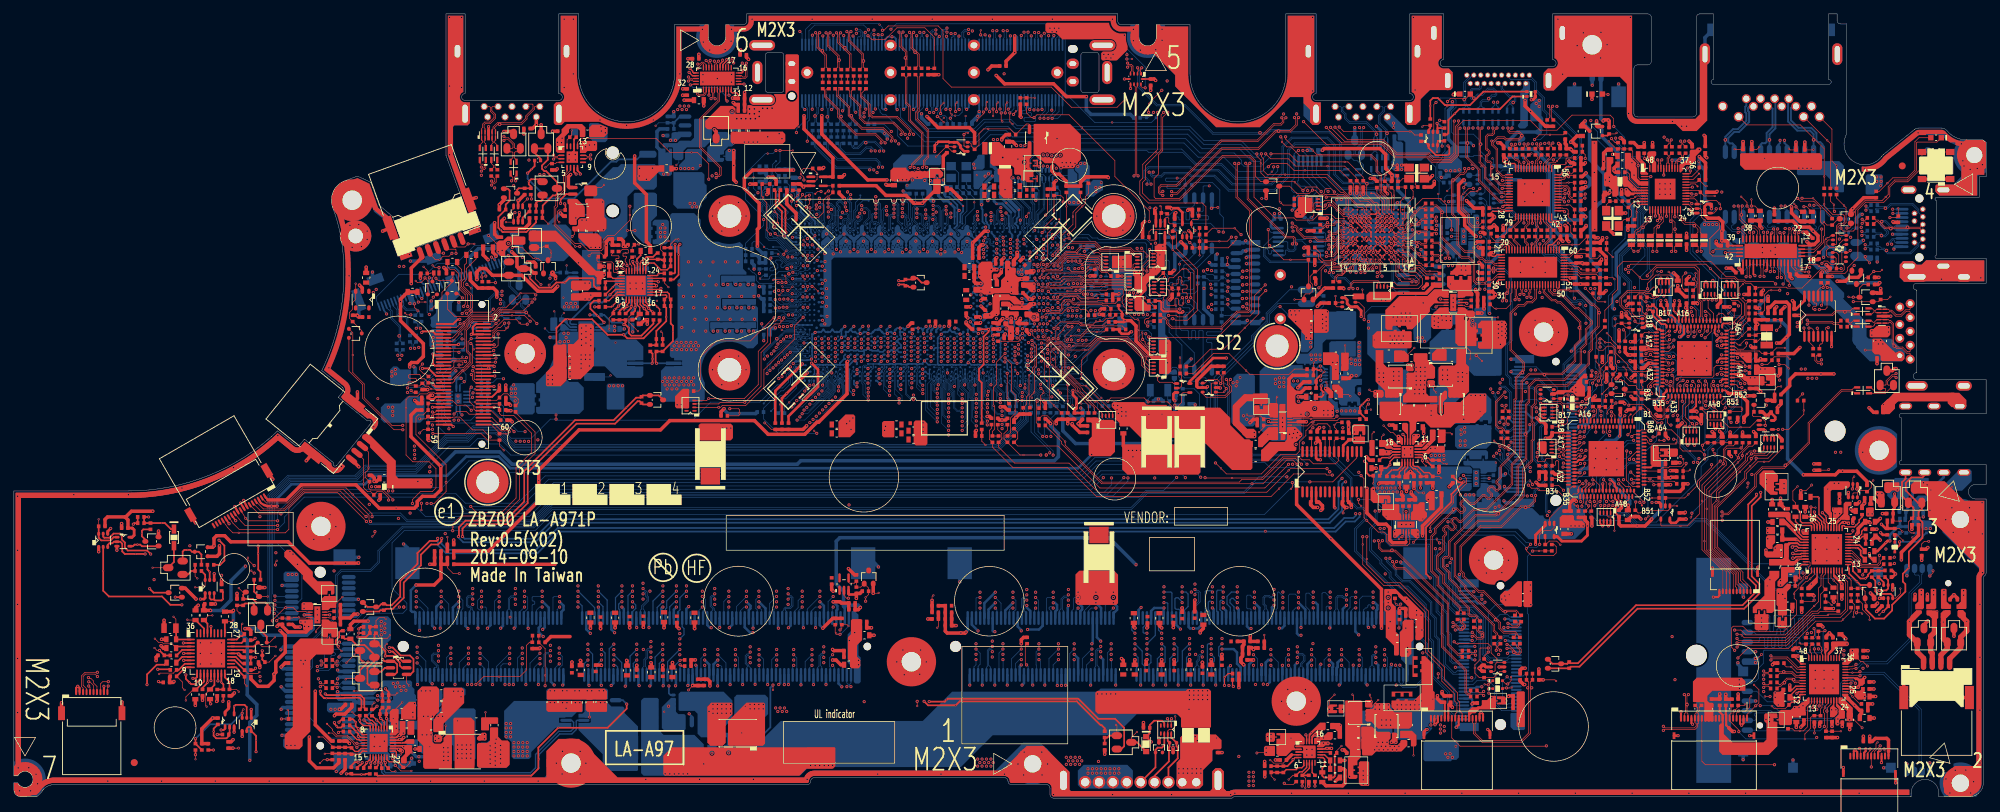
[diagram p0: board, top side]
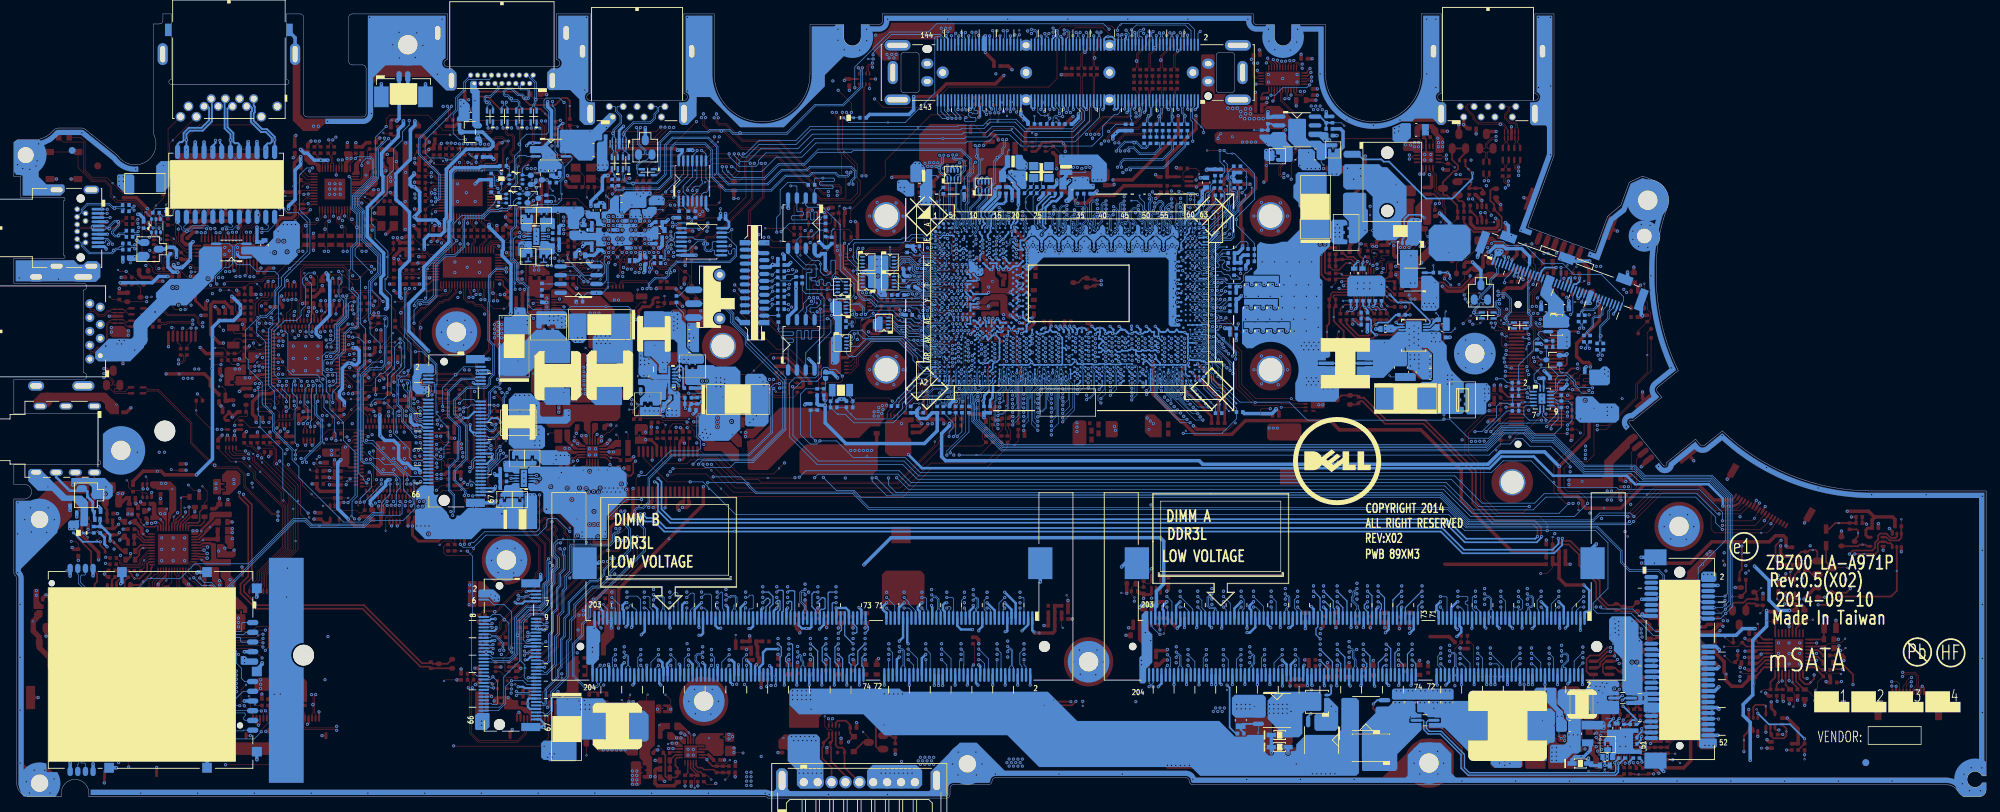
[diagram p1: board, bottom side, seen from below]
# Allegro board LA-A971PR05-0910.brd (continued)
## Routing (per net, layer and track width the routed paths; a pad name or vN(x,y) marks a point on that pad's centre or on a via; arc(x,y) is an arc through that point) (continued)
SUSCLK: length 100.6
  TOP w0.102: v2(155.68,70.26) 155.59,70.17 RC136.2 ; v2(218.33,36.58) v3(217.72,35.97) 217.72,35.66 218.43,34.95 221.64,34.95 222.02,35.33 222.02,36.23 221.72,36.54 RZ56.1
  IN2 w0.122: v2(208.22,43.69) 208.22,43.69 206.32,41.78 195.76,41.78 194.28,40.29 174.66,40.29 169.34,45.61 169.34,52.81 167.78,54.37 167.78,58.84 163.5,63.12 163.5,63.92 161.66,65.76 161.66,68.62 160.83,69.44 160.83,70.21 160.52,70.52 158.86,70.52 158.56,70.83 155.98,70.83 155.68,70.52 v2(155.68,70.26)
  BOTTOM w0.102: v2(208.22,43.69) 208.22,38.82 208.66,38.38 216.14,38.38 217.68,36.84 218.06,36.84 v2(218.33,36.58)
SUSCLK_R: length 8.5
  TOP w0.102: v2(148.03,69.3) 148.56,69.83 150.87,69.83 151.72,70.69 v1(152.18,70.69) 153.25,70.69 153.52,70.41 154.31,70.41 154.67,70.05 RC136.1
  BOTTOM w0.081: v2(148.03,69.3) 147.96,69.23 UC1.AE6
SW1: length 9.4
  IN1 w1.016: 196.9,50.65 196.9,56.11 199,58.2 199,59.22
  vias: v1(196.33,61.89) v2(196.52,61.25) v2(196.52,60.62) v2(196.52,59.98) v2(197.16,61.25) v2(197.16,60.62) v2(197.16,59.98) v2(197.6,49.89) v2(198.23,49.89) v2(198.62,61.44) v2(198.62,60.81) v2(198.62,60.17) v2(199.38,61.44) v2(199.38,60.81) v2(199.38,60.17)
SW2: length 8.9
  IN1 w1.016: 205.35,51.09 207.32,53.06 207.32,58.08 208.08,58.84
  vias: v1(209.16,61.18) v2(203.95,50.39) v2(204.58,50.39) v2(205.66,61.7) v2(205.66,60.93) v2(205.66,60.3) v2(206.36,61.7) v2(206.36,60.93) v2(206.36,60.3) v2(207.89,61.32) v2(207.89,60.68) v2(207.89,60.05) v2(208.52,61.32) v2(208.52,60.68) v2(208.52,60.05)
SW_1.35V: length 8.2
  TOP w0.102: v2(195.95,13.44) 195.95,13.69 v1(196.39,14.13)
  IN4 w1.016: 195.89,10.83 193.85,10.83 193.09,10.07 189.85,10.07 189.15,9.37
  vias: v2(187.88,8.67) v2(188.52,8.67) v2(195.95,12.8) v2(196.58,13.44) v2(196.58,12.8) v2(196.9,11.26) v2(196.9,10.5) v2(197.22,13.44) v2(197.22,12.8) v2(197.54,11.26) v2(197.54,10.5) v2(197.85,13.44) v2(197.85,12.8) v2(198.17,11.26) v2(198.17,10.5)
SW_10_GRN#: length 23.5
  TOP w0.102: v2(263.03,76.3) RL30.2 262.36,76.77 262.69,77.1 262.69,78.27 262.34,78.61 QL2.1 ; v2(246.37,78.6) v1(247,78.6) UL4.41
  IN4 w0.084: v2(246.37,78.6) 249.72,78.6 251.35,76.97 259.67,76.97 260.21,76.43 262.9,76.43 v2(263.03,76.3)
SW_100_ORG#: length 6.3
  TOP w0.102: QL1.4 261.58,81.08 261.28,80.77 261.05,80.77 v1(260.88,80.61) 260.69,80.41 260.69,79.47 RL29.2 259.32,78.1 UL4.18
SW_+V1.05SP:
  vias: v1(190.3,61.76) v2(189.85,62.78) v2(190.49,62.78)
SW_ACTLED_YEL#: length 12.1
  TOP w0.102: UL4.17 256.89,76.71 257.16,76.44 257.83,76.44 258.25,76.86 259.65,76.86 v1(259.81,76.7) 260.06,76.45 260.62,76.45 260.99,76.09 260.99,75.97 261.11,75.84 263.17,75.84 263.47,76.15 263.47,76.68 263.13,77.02 263.13,79.51 263.4,79.78 QL1.1
SW_DPB_AUX: length 8.6
  TOP w0.102: RV75.1 188.05,82.61 188.36,82.3 188.44,82.3 188.82,82.68 188.85,82.68 v2(189.09,82.92) 189.28,82.73 189.95,82.73 190.37,83.16 191.57,83.16 191.89,82.84 UV8.J13
  BOTTOM w0.102: CV119.2 186.54,83.65 186.4,83.52 186.4,83.16 186.6,82.97 188.33,82.97 188.56,82.74 188.91,82.74 v2(189.09,82.92)
SW_DPB_AUX#: length 8.6
  TOP w0.102: RV82.1 188.39,82.08 188.52,82.08 188.9,82.46 188.97,82.46 v2(189.09,82.34) 189.27,82.52 190.04,82.52 190.46,82.94 190.96,82.94 191.37,82.53 191.44,82.53 191.5,82.6 191.5,82.8 UV8.J14
  BOTTOM w0.102: CV120.2 186.07,83.65 186.19,83.53 186.19,83.07 186.51,82.75 188.24,82.75 188.47,82.52 188.91,82.52 v2(189.09,82.34)
SW_DPB_AUX#_C: length 1.8
  BOTTOM w0.102: CV120.1 185.79,84.75 185.94,84.9 185.94,85.04 185.84,85.14 185.66,85.14 185.58,85.22 UV11.5
SW_DPB_AUX_C: length 1.8
  BOTTOM w0.102: CV119.1 187.53,85.3 UV11.2
SW_DPC_AUX: length 7.8
  TOP w0.102: RV74.1 190.16,74.65 190.16,75.11 190.55,75.5 191.07,75.5 v4(191.36,75.79) 191.9,76.33 192.33,76.33 v2(192.39,76.39) 192.39,76.39 192.62,76.62 192.62,76.68 193,77.06 193,77.1 193.13,77.23 193.13,77.75 193.41,78.03 UV8.B11
  BOTTOM w0.102: CV122.2 192.39,77.29 v2(192.39,76.39)
SW_DPC_AUX#: length 7.8
  TOP w0.102: UV8.A11 193.54,77.51 193.54,77.33 193.22,77.01 193.22,76.97 192.84,76.59 192.84,76.25 v2(192.39,75.81) 192.09,76.11 191.99,76.11 191.76,75.88 191.76,75.87 191.74,75.85 191.74,75.84 191.31,75.42 191.31,75.42 191.27,75.39 191.26,75.39 191.16,75.29 190.64,75.29 190.37,75.02 190.37,74.52 190.49,74.41 RV85.1
  BOTTOM w0.102: v2(192.39,75.81) 191.99,76.21 191.99,76.56 192.14,76.71 192.14,77 192.05,77.09 CV123.2
SW_DPC_AUX#_C: length 6.1
  BOTTOM w0.102: UV12.5 188.71,79.52 188.77,79.59 188.77,80.05 189.08,80.35 189.42,80.35 189.78,80 v4(189.78,79.41) 189.78,79.17 190.07,78.88 190.07,77.67 190.26,77.48 190.4,77.48 CV123.1
SW_DPC_AUX_C: length 6.2
  BOTTOM w0.102: UV12.2 188.68,81.47 188.84,81.32 188.84,80.68 188.94,80.58 v4(189.15,80.58) 189.5,80.58 190,80.07 190,79.25 190.28,78.97 190.28,77.76 190.35,77.69 190.51,77.69 CV122.1
SW_LAN_TX0+: length 5.1
  TOP w0.089: UL4.38 248.89,81.27 248.46,81.7 248.4,81.7 v2(248.21,81.51)
  BOTTOM w0.089: v2(248.21,81.51) 248.08,81.64 247.35,81.64 246.37,82.61 TL1.12
SW_LAN_TX0-: length 5.1
  TOP w0.089: v2(248.21,82.09) 248.29,82.02 248.59,82.02 249.39,81.22 UL4.37
  BOTTOM w0.089: v2(248.21,82.09) 248.07,81.95 247.48,81.95 247.26,82.17 247.26,82.46 247.38,82.59 247.51,82.59 247.64,82.71 TL1.11
SW_LAN_TX1+: length 16.2
  TOP w0.089: v2(248.22,85.32) 248.35,85.18 248.35,83.4 249.61,82.14 250.55,82.14 251,81.69 251,81.32 250.89,81.21 250.89,81.02 UL4.34
  IN4 w0.084: v2(254.39,85.31) 254.5,85.41 254.5,85.6 254.34,85.76 251.66,85.76 250.44,84.54 248.68,84.54 248.32,84.91 248.32,85.22 v2(248.22,85.32)
  BOTTOM w0.089: v2(254.39,85.31) 254.5,85.21 254.5,84.98 254.38,84.87 254.11,84.87 253.99,84.75 TL1.6
SW_LAN_TX1-: length 16.2
  TOP w0.089: UL4.33 251.39,81.2 251.32,81.27 251.32,81.83 250.69,82.46 249.74,82.46 248.67,83.53 v4(248.67,84.04) 248.67,85.18 v2(248.8,85.32)
  IN4 w0.084: v2(254.98,85.31) 254.88,85.41 254.88,85.76 254.5,86.14 251.5,86.14 250.28,84.92 248.84,84.92 248.7,85.06 248.7,85.22 v2(248.8,85.32)
  BOTTOM w0.089: TL1.5 255.26,84.81 255.19,84.87 254.88,84.87 254.81,84.94 254.81,85.14 v2(254.98,85.31)
SW_LAN_TX2+: length 4.8
  TOP w0.089: v2(253.3,82.02) 253.48,81.84 253.48,81.22 253.39,81.14 UL4.29
  BOTTOM w0.089: v2(253.3,82.02) 253.23,81.94 252.38,81.94 251.79,82.54 251.63,82.54 251.45,82.71 TL1.8
SW_LAN_TX2-: length 4.8
  TOP w0.089: UL4.28 253.89,81.09 253.8,81.19 253.8,81.93 v2(253.89,82.02)
  BOTTOM w0.089: v2(253.89,82.02) 253.49,82.42 253.12,82.42 252.96,82.26 252.51,82.26 252.4,82.37 252.4,82.46 252.72,82.78 TL1.7
SW_LAN_TX3+: length 7.6
  TOP w0.089: UL4.25 255.39,81.2 255.51,81.32 255.51,81.99 v2(255.57,82.04)
  BOTTOM w0.089: v2(255.57,82.04) 255.99,82.46 258.18,82.46 258.64,82 259.32,82 259.45,82.13 259.45,82.33 259.07,82.71 TL1.2
SW_LAN_TX3-: length 7.6
  TOP w0.089: v2(256.15,82.04) 255.83,81.72 255.83,81.3 255.89,81.23 UL4.24
  BOTTOM w0.089: TL1.1 260.34,82.83 259.77,82.26 259.77,82 259.45,81.69 v4(259,81.69) 258.5,81.69 258.05,82.14 256.25,82.14 v2(256.15,82.04)
SW_MDP_AUX#_C: length 2.1
  TOP w0.102: UV502.5 260.35,65.58 260.21,65.44 260.08,65.44 259.89,65.25 CV513.1
SW_MDP_AUX_C: length 2
  TOP w0.102: UV502.2 258.4,65.73 259,65.13 CV512.1
SW_USB3RN1: length 52.4
  TOP w0.102: LI1.4 67.08,91.48 67.21,91.35 67.49,91.35 67.71,91.13 67.71,90.85 67.64,90.78 67.45,90.78 v2(67.3,90.93) ; v2(98.45,105.77) 98.73,105.77 98.99,106.03 99.29,106.03 99.66,105.66 UI4.26
  IN4 w0.091: v2(98.45,105.77) 98.25,105.57 98.02,105.57 97.8,105.34 97.8,102.62 97.5,102.33 97.5,101.36 98.23,100.62 98.23,95.58 95.25,92.6 90.98,92.6 88.73,90.35 83.18,90.35 81.86,89.03 77.5,89.03 75.45,86.98 69.32,86.98 68,88.3 68,90.5 67.78,90.72 67.51,90.72 v2(67.3,90.93)
SW_USB3RP1: length 52.1
  TOP w0.102: UI4.27 99.26,105.76 99.2,105.82 99.08,105.82 98.82,105.55 98.82,105.55 98.45,105.18 v2(98.45,105.16) ; v2(67.3,90.34) 67.52,90.56 67.73,90.56 67.93,90.76 LI1.1
  IN4 w0.091: v2(98.45,105.16) 98.21,105.4 98.1,105.4 97.97,105.27 97.97,102.55 97.67,102.25 97.67,101.43 98.41,100.69 98.41,95.51 95.32,92.42 91.05,92.42 88.8,90.17 83.25,90.17 81.93,88.86 77.57,88.86 75.52,86.81 69.25,86.81 67.82,88.23 67.82,90.43 67.71,90.54 67.5,90.54 v2(67.3,90.34)
SW_USB3TN1: length 44.3
  TOP w0.102: v2(97.1,103.9) 97.29,103.72 97.47,103.72 97.6,103.59 97.67,103.59 97.76,103.68 UI4.30 ; CI4.2 68.8,89.63 69.22,89.22 69.22,88.86 69.09,88.73 68.94,88.73 v2(68.76,88.91)
  IN4 w0.091: v2(97.1,103.9) 96.89,103.69 96.74,103.69 96.5,103.45 96.5,102.82 96.83,102.49 96.83,101.05 97.56,100.32 97.56,96.1 94.75,93.29 90.76,93.29 88.46,90.99 79.38,90.99 78.5,90.11 77.67,90.11 75.19,87.63 70.64,87.63 69.48,88.79 68.89,88.79 v2(68.76,88.91)
SW_USB3TP1: length 44.6
  TOP w0.102: CI5.2 69.43,89.46 69.43,88.77 69.18,88.52 68.95,88.52 v2(68.76,88.33) ; v2(97.1,103.32) 97.29,103.5 97.36,103.5 97.49,103.37 97.7,103.37 97.79,103.28 UI4.31
  IN4 w0.091: v2(97.1,103.32) 97.1,103.39 96.98,103.52 96.81,103.52 96.67,103.37 96.67,102.89 97,102.56 97,101.12 97.73,100.39 97.73,96.03 94.82,93.12 90.83,93.12 88.53,90.82 79.45,90.82 78.57,89.94 77.74,89.94 75.26,87.45 70.57,87.45 69.41,88.61 69.04,88.61 v2(68.76,88.33)
SW_USBP0+: length 40.2
  TOP w0.102: v2(77.69,92.07) 77.87,92.26 78.26,92.26 78.4,92.12 UI3.3 ; v2(103.42,106.62) 102.92,106.12 102.91,106.12 102.46,105.67 UI4.19
  IN1 w0.091: v2(103.42,106.62) 103.68,106.35 104.05,106.35 104.41,105.99 104.41,100.22 103.62,99.43 101.99,99.43 99.37,96.82 94.1,96.82 92.21,94.92 86.17,94.92 84.5,93.24 79.48,93.24 78.54,92.3 77.92,92.3 v2(77.69,92.07)
SW_USBP0-: length 39.3
  TOP w0.102: v2(103.61,105.93) 103.61,106.06 103.46,106.21 103.3,106.21 102.81,105.71 102.81,105.69 102.86,105.64 UI4.18 ; v2(77.69,92.66) 77.87,92.47 78.26,92.47 78.4,92.62 UI3.2
  IN1 w0.091: v2(103.61,105.93) 103.85,106.18 103.98,106.18 104.23,105.92 104.23,100.29 103.55,99.61 101.92,99.61 99.3,96.99 94.03,96.99 92.13,95.09 86.1,95.09 84.42,93.42 79.41,93.42 78.47,92.48 77.87,92.48 v2(77.69,92.66)
SW_USBP3+: length 41.6
  TOP w0.102: v2(162.34,105.23) 162.15,105.04 162.15,104.7 162.26,104.59 UI5.1
  BOTTOM w0.102: v2(162.34,105.23) 161.99,104.88 161.99,102.55 164.58,99.96 168.58,99.96 172.67,95.87 v4(179.38,95.87) 180.34,95.87 180.81,96.34 181.74,96.34 181.76,96.35 182.35,96.35 182.37,96.34 183.74,96.34 184.02,96.06 189.49,96.06 191.05,94.5 191.05,90.41 191.1,90.36 191.24,90.36 191.49,90.62 LI4.1
SW_USBP3-: length 41.9
  TOP w0.102: v2(161.76,105.23) 161.94,105.05 161.94,104.83 161.74,104.63 UI5.2
  BOTTOM w0.102: LI4.4 191.33,89.77 190.83,90.27 190.83,94.41 189.4,95.85 183.93,95.85 183.65,96.13 v4(182.05,96.13) 180.9,96.13 180.43,95.66 179.67,95.66 179.65,95.64 179.1,95.64 179.08,95.66 172.58,95.66 170.57,97.67 168.49,99.75 164.49,99.75 161.77,102.46 161.77,105.22 v2(161.76,105.23)
SYS_LED_MASK#: length 124.2
  TOP w0.102: v1(239.41,42.11) UZ10.1 238.38,41.7 238.11,41.44 234.52,41.44 234.18,41.09 233.8,41.09 RE21.2 233.41,42.6 v2(233.47,42.66) ; 261.38,79.36 262.42,79.36 262.78,79.72 262.78,79.88 263.32,80.43 QL1.2 ; 261.38,79.36 260.91,78.89 260.91,78.19 261.14,77.96 QL2.2 262.13,77.96 262.31,77.79 262.31,77.16 262.06,76.91 261.54,76.91 261.07,77.38 260.59,77.38 v2(260.26,77.05) ; 261.38,79.36 260.97,79.77 260.97,80.2 261.2,80.43 QL1.5 ; v2(231,45.29) 231.07,45.29 231.72,44.64 UE1.B48
  IN3 w0.122: v2(231,45.29) 231.93,45.29 232.27,45.63 232.27,47.1 233.68,48.51 233.68,53.56 232.72,54.53 231.21,54.53 230.75,54.99 230.75,55.86 227.9,58.71 227.69,58.71 225.39,61.01 225.39,65.01 225.86,65.48 225.86,70.56 v2(226.26,70.97)
  IN4 w0.084: v2(260.26,77.05) 260.13,77.18 251.64,77.18 249.81,79.02 246.03,79.02 245.84,79.21 244.53,79.21 243.41,80.33 240.37,80.33 240.02,80.68 233.56,80.68 231.95,79.07 225.42,79.07 224.76,78.41 223.06,78.41 222.59,78.88 221.61,78.88 220.18,80.31 v2(220.15,80.31)
  BOTTOM w0.102: v2(226.26,70.97) 226.26,71.3 225.74,71.82 225.08,71.82 224.89,71.63 224.32,71.63 223.53,72.41 223.53,76.94 v2(220.15,80.31) 220.58,80.74 220.58,82.81 219.44,83.96 216.51,83.96 216.32,84.15 214.68,85.78 214.68,85.98 214.43,86.23 213.7,86.23 213.54,86.4 QZ3.2 ; v2(231,45.29) 231,45.13 v2(233.47,42.66)
SYS_PWROK: length 270.7
  TOP w0.102: v2(60.06,42.46) 60.5,42.46 62.22,44.17 v3(62.22,45.5) 62.22,48.04 57.87,52.39 57.87,54.88 58.22,55.22 58.93,55.22 RC120.1 CC22.1 60.64,56.87 60.69,56.82 JXDP1.47 ; v2(242.67,67.26) 242.91,67.5 UE2.B7
  IN2 w0.122: v2(218.36,61.7) 218.36,61.26 219.13,60.49 219.13,57.57 217.75,56.19 217.75,47.01 216.3,45.56 214.05,45.56 211.13,42.63 207.88,42.63 206.52,41.28 201.37,41.28 200.79,40.69 195.4,40.69 194.48,39.77 174.47,39.77 168.63,45.61 v2(168.63,46.18) 168.63,50 167.4,51.23 167.4,53.24 162.92,57.72 162.92,63.63 159.42,67.13 157.26,67.13 155.04,69.35 v2(155.04,70.28)
  IN4 w0.084: v2(242.67,67.26) 242.67,67.14 242.43,66.9 242.43,66.01 242.18,65.76 241.73,65.76 240.53,64.55 237.9,64.55 237.47,64.99 237.47,65.42 235.9,66.99 232.59,66.99 232.19,66.59 225.5,66.59 222.75,63.83 221.09,63.83 219.57,62.31 219.57,61.51 219.3,61.23 218.83,61.23 v2(218.36,61.7)
  BOTTOM w0.076: 150.75,68.06 151.05,68.36 152.4,68.36
  BOTTOM w0.081: 153.09,68.76 152.8,68.76 152.4,68.36
  BOTTOM w0.084: UC1.AG2 150.75,68.06
  BOTTOM w0.102: v2(155.04,70.28) 154.57,69.81 CC108.1 154.01,69.06 153.53,69.06 153.23,68.76 153.09,68.76 ; v2(168.63,46.18) 168.12,46.68 156.65,46.68 154.95,44.98 77.91,44.98 73.98,41.05 61.46,41.05 v2(60.06,42.46)
SYS_RESET#: length 215.4
  TOP w0.102: v2(37.96,38.71) 32.44,38.71 31.55,39.6 31.35,39.88 JAPS1.13 ; UC4.4 164.39,80.49 164.3,80.4 163.49,80.4 163.39,80.5 CC106.1 163.39,81.58 163.72,81.92 166,81.92 166.27,81.65 166.27,81.29 RC77.2 166.8,79.03 v1(166.79,79.02) 169.88,75.93 169.88,70.59 168.63,69.34 167.55,69.34 167.34,69.56 v2(166.21,69.56)
  IN2 w0.122: v2(170.84,46.24) 170.84,52.73 168.79,54.79 168.79,59.28 164.52,63.55 164.52,67.6 166.21,69.29 v2(166.21,69.56) 166.14,69.56 164.2,71.49 162.42,71.49 161.76,72.15 v2(161.76,72.82)
  BOTTOM w0.081: 152.73,71.03 152.48,70.78 151.42,70.78 151.31,70.67 151.19,70.67 150.95,70.43 150.95,70.26 150.72,70.02 150.2,70.02 UC1.AC3
  BOTTOM w0.102: 152.73,71.03 153.2,71.5 159.5,71.5 160.41,72.4 161.34,72.4 v2(161.76,72.82) ; v2(37.96,38.71) 38.93,39.67 38.93,40.5 41.8,43.37 63.36,43.37 65.2,41.53 73.78,41.53 77.71,45.47 154.75,45.47 156.45,47.17 169.91,47.17 v2(170.84,46.24)
TDI_IREF: length 6.6
  BOTTOM w0.127: 143.54,84.41 143.54,82.51 143.78,82.27 UC1.B12
  BOTTOM w0.381: RC186.2 141.08,86.02 v1(141.47,85.64) 142.31,85.64 143.54,84.41
TDI_XDP_R: length 3.2
  BOTTOM w0.102: RC99.2 RC118.1 66.9,57.07 v1(66.37,57.07) UC7.5
TDO_XDP: length 11.8
  TOP w0.102: RC117.2 68.72,55.82 JXDP1.52 66.44,55.82 66.22,56.04 66.22,56.49 65.62,57.09 65.62,59 v2(65.84,59.22)
  BOTTOM w0.102: RC98.2 RC115.1 v1(66.38,58.91) 66.15,58.91 v2(65.84,59.22) 65.71,59.09 65.71,58.65 65.63,58.57 UC7.2
THERMATRIP2#: length 7.8
  TOP w0.102: QE4.1 231.88,58.65 232.01,58.52 233.3,58.52 RE69.2 234.24,57.52 CE36.1 v1(235.39,57.49) 236.58,57.49 236.91,57.82 236.91,59.23 237.03,59.35 UE2.B34
THERMATRIP3#: length 18
  TOP w0.102: v2(246.88,69.24) 246.59,69.24 246.01,69.81 v1(245.45,69.81) 245.44,69.81 245.16,69.53 UE2.A2 ; RPE6.1 245.71,55.6 v2(246.35,56.24)
  BOTTOM w0.102: v2(246.88,69.24) 246.62,68.98 246.62,68.23 247.26,67.6 247.26,59.47 246.35,58.57 v2(246.35,56.24)
THSEL_STRAP: length 5.3
  TOP w0.102: v2(234.91,60.81) 234.72,61.01 RE78.1 ; UE2.B29 237.57,61.85 237.67,61.76 v2(238.22,61.76)
  IN1 w0.084: v2(234.91,60.81) 236.47,60.81 237.42,61.76 v2(238.22,61.76)
TMDS_CON_CLK: length 5.9
  BOTTOM w0.102: JHDMI1.10 214.08,102.54 214.08,102.15 215.25,100.98 215.91,100.98 215.99,100.9 215.99,100.51 215.94,100.46 215.51,100.46 215.26,100.2 215.26,99.98 214.94,99.66 LV3.2
TMDS_CON_CLK#: length 5.9
  BOTTOM w0.102: LV3.3 215.79,99.66 215.47,99.98 215.47,100.11 215.59,100.23 v4(215.82,100.23) 216.01,100.23 216.21,100.42 216.21,100.99 216,101.19 215.34,101.19 214.3,102.24 214.3,102.62 JHDMI1.12
TMDS_CON_N0: length 12.4
  IN4 w0.091: v2(213.59,100.28) 213.38,100.48 213.38,100.67 212.62,101.44 210.27,101.44 209.05,102.66 209.05,103.12 209.43,103.5 209.87,103.5 209.95,103.42 210.35,103.42 210.43,103.5 210.87,103.5 210.94,103.43 211.36,103.43 211.43,103.5 211.87,103.5 211.93,103.44 212.37,103.44 212.43,103.5 212.52,103.5 212.76,103.74 212.76,104.04 212.9,104.17 JHDMI1.9
  BOTTOM w0.102: v2(213.59,100.28) 213.4,100.09 213.4,99.84 213.7,99.55 LV12.3
TMDS_CON_N1: length 12.4
  BOTTOM w0.102: LV10.3 211.6,99.38 211.28,99.7 211.28,100.21 211.48,100.41 212.23,100.41 212.67,100.85 212.67,100.96 212.83,101.12 213.23,101.12 213.46,101.35 213.46,101.85 213,102.31 212.17,102.31 211.3,101.45 210.67,101.45 210.46,101.24 210.46,100.95 210.37,100.86 v4(210.16,100.86) 209.93,100.86 209.86,100.93 209.86,101.93 209.99,102.06 210.97,102.06 211.21,102.3 211.21,102.53 JHDMI1.6
TMDS_CON_N2: length 6
  BOTTOM w0.102: LV6.3 209.5,99.36 209.21,99.66 209.21,99.95 209,100.16 209,100.95 208.92,101.03 208.92,103.05 209.66,103.8 209.66,103.87 209.96,104.17 JHDMI1.3
TMDS_CON_P0: length 12.4
  IN4 w0.091: v2(213,100.28) 213.21,100.48 213.21,100.6 212.54,101.27 210.2,101.27 208.88,102.59 208.88,103.19 209.36,103.67 209.94,103.67 210.02,103.59 210.28,103.59 210.36,103.67 210.94,103.67 211.01,103.6 211.29,103.6 211.36,103.67 211.94,103.67 212,103.61 212.3,103.61 212.36,103.67 212.45,103.67 212.59,103.81 212.59,104.02 212.44,104.17 JHDMI1.7
  BOTTOM w0.102: v2(213,100.28) 213.18,100.1 213.18,99.88 212.85,99.55 LV12.2
TMDS_CON_P1: length 12.4
  BOTTOM w0.102: JHDMI1.4 211,102.62 211,102.39 210.88,102.27 209.9,102.27 209.65,102.02 209.65,100.84 209.86,100.63 210.46,100.63 210.68,100.85 210.68,101.15 210.76,101.23 211.39,101.23 212.26,102.09 212.91,102.09 213.25,101.76 213.25,101.44 213.14,101.33 212.74,101.33 212.46,101.05 212.46,100.96 v4(212.3,100.8) 212.12,100.62 211.39,100.62 211.07,100.3 211.07,99.72 210.75,99.4 LV10.2
TMDS_CON_P2: length 5.9
  BOTTOM w0.102: JHDMI1.1 209.33,104.17 209.45,104.05 209.45,103.89 208.7,103.14 208.7,100.94 208.77,100.87 v4(208.77,100.65) 208.77,100.08 208.99,99.86 208.99,99.67 208.65,99.33 LV6.2
TOUCH_PANEL_INTR#: length 122.5
  TOP w0.102: v2(153.27,76.31) 153.72,76.75 153.94,76.75 154.11,76.92 156.08,76.92 156.28,76.72 156.28,76.39 156.72,75.95 160.98,75.95 161.34,76.31 161.34,76.43 161.42,76.5 RPC3.5 ; v2(68.76,77.95) 68.8,77.95 v1(69.19,77.56)
  IN2 w0.081: v2(153.27,76.31) 152.83,75.86 151.43,75.86 151.24,76.05 151.24,81.51 149.47,83.29 148.31,83.29 147.88,83.72 147.88,85.06
  IN2 w0.122: 147.88,85.06 147.88,86.52 145.74,88.67 145.74,89.52 140.12,95.14 139.85,95.14 138.74,96.26 136.14,96.26 134.7,94.81 130.69,94.81 129.39,93.51 128.43,93.51 128,93.08 127.85,92.93 125.92,92.93 125.55,92.57 112.54,92.57 111.63,91.66 109.64,91.66 109.44,91.45 105.13,91.45 104.58,90.91 99.56,90.91 97.44,88.78 92.33,88.78 90.83,87.29 84.12,87.29 82.96,86.12 78.53,86.12 78.28,85.87 78.28,85.21 77.11,84.04 75.95,84.04 72.51,80.6 70.85,80.6 68.76,78.52 v2(68.76,77.95)
  BOTTOM w0.076: UC1.P3 150.2,74.52 150.72,74.52 150.95,74.75 150.95,74.93 151.12,75.1 151.82,75.1 152.59,75.86 152.83,75.86 v2(153.27,76.31)
  BOTTOM w0.102: JEDP1.5 68.76,77.51 v2(68.76,77.95)
TOUCH_SCREEN_PD#: length 7
  TOP w0.102: v2(234.05,42.62) 234.35,42.32 T96.1 ; UE1.B55 233.33,46.4 v2(232.75,46.98)
  BOTTOM w0.102: v2(232.75,46.98) 232.45,46.68 232.45,44.76 234.05,43.15 v2(234.05,42.62)
TOUCHPAD_INTR#: length 14.3
  TOP w0.076: 149.4,73.91 149.26,73.91 149.05,73.7 147.82,73.7 v2(147.46,74.05)
  TOP w0.102: 149.4,73.91 v1(149.68,73.91) 150.87,73.91 151.49,74.53 153.8,74.53 154.04,74.29 160.05,74.29 160.2,74.15 RPC9.7
  BOTTOM w0.081: v2(147.46,74.05) 147.31,73.9 UC1.U7
TP_DC_TEST_B2: length 6
  BOTTOM w0.081: UC1.B2 150.74,82.94 150.61,83.07 150.61,85.54
  BOTTOM w0.102: 150.61,85.54 150.62,85.55 v1(150.62,86.21) 150.62,87.48 RC192.2
TP_LAN_JTAG_TCK: length 3.5
  TOP w0.102: UL1.35 241.54,89.56 242.59,90.61 RL2.2 242.59,91.63 v1(242.49,91.73)
TP_LAN_JTAG_TDI: length 1.9
  TOP w0.102: UL1.32 241.24,88.36 241.39,88.5 242.01,88.5 T88.1
TP_LAN_JTAG_TDO: length 2.2
  TOP w0.102: UL1.34 241.75,89.16 T89.1
TP_LAN_JTAG_TMS: length 3.5
  TOP w0.102: UL1.33 242.28,88.76 RL1.2 242.59,89.07 243.47,88.19 v1(243.66,88.19)
TPM_PIRQ#: length 92.4
  TOP w0.102: UZ1.20 190.7,48.64 190.23,48.17 187.06,48.17 186.49,48.74 185.41,48.74 184.99,49.16 182.68,49.16 179.64,46.12 v1(175.37,46.12) 171.52,46.12 v2(171.46,46.18)
  IN4 w0.076: 152.86,73.67 152.91,73.72 153.95,73.72 154,73.67
  IN4 w0.084: v2(171.46,46.18) 169.12,48.52 169.12,51.96 168.15,52.93 160.39,52.93 152.32,61 151.94,61 150.29,62.65 150.29,63.47 149.36,64.41 149.36,65.45 149.02,65.79 148.77,65.79 148.58,65.98 148.58,66.59 149.1,67.11 149.1,67.67 148.9,67.87 146.34,67.87 146.06,68.15 146.06,69.21 146.66,69.81 146.96,69.81 147.18,70.03 147.18,71.42 147.45,71.69 149.73,71.69 149.86,71.82 150.77,71.82 151.46,72.5 151.69,72.5 152.86,73.67 ; v2(156.48,75.2) 158.19,73.48 159.28,73.48 159.57,73.18 159.57,72.34 159.37,72.14 157.16,72.14 155.63,73.67 154,73.67
  BOTTOM w0.076: UC1.T3 150.29,73.75 151.51,73.75 151.56,73.7 152.01,73.7 152.19,73.88 152.19,74.3 152.83,74.94
  BOTTOM w0.081: 152.83,74.94 153.6,74.94
  BOTTOM w0.102: 153.6,74.94 153.63,74.98 154,74.98 154.19,74.79 155.58,74.79 RC247.2 156.46,75.2 v2(156.48,75.2)
TRST#_XDP: length 15.2
  TOP w0.102: JXDP1.54 65.52,55.32 65.14,55.7 63.71,55.7 v2(63.36,55.35)
  IN4 w0.084: v2(63.36,55.35) 61.77,56.93 61.77,59.85 61.38,60.25 v2(60.34,60.25)
  BOTTOM w0.102: v2(60.34,60.25) 61.2,60.25 v1(61.46,59.99) 61.73,59.71 61.73,58.68 62.35,58.07 UC7.12
UG_3V: length 4.3
  TOP w0.102: v2(203.25,51.47) 203.25,52.02 v1(203.19,52.08)
  IN1 w1.016: 203.82,52.3 205.16,53.63 205.16,55.35 205.22,55.41
  vias: v2(202.74,51.09) v2(205.47,56.24) v2(205.47,55.6)
UG_5V: length 7.1
  TOP w0.102: v2(195.95,58.58) 195.38,58.58 v1(195.12,58.84)
  IN2 w1.016: 197.22,51.35 196.84,51.73 196.84,56.36 196.14,57.06
  vias: v2(195.95,57.95) v2(198.11,51.6) v2(198.49,51.09)
UIM_CLK: length 93.5
  TOP w0.102: CZ65.1 227.75,62.88 v1(228.19,62.43) 228.19,61.2 228.04,61.05 228.04,60.65 227.25,59.87 v2(227.25,59.79) ; v2(265.67,7.16) 265.85,6.98 JSH1.4
  IN4 w0.084: v2(265.67,7.16) 265.37,7.47 257.61,7.47 254.69,10.39 254.69,21.66 253.45,22.9 253.45,27.79 250.44,30.8 250.44,41.92 249.75,42.61 249.75,44.68 250.03,44.96 250.03,45.55 243.47,52.1 240.59,52.1 239.34,53.36 237.36,53.36 236.89,53.82 236.08,53.82 235.45,54.46 234.35,54.46 234.11,54.22 229.56,54.22 228.87,54.92 228.87,55.96 227.19,57.63 227.19,59.73 v2(227.25,59.79)
  BOTTOM w0.102: v2(227.25,59.79) 227.25,58.83 226.95,58.53 226.95,56.31 226.05,55.41 226.05,54.77 225.73,54.46 225.21,54.46 225.15,54.4 JNGFF2.24
UIM_DATA: length 97.6
  TOP w0.102: JSH1.8 267.85,6.72 v2(268.66,7.53) ; CZ63.1 229.27,61.87 228.78,61.38 228.78,60.44 228.54,60.2 v1(228.54,59.55) 228.5,59.51 v2(227.83,59.51)
  IN4 w0.084: v2(268.66,7.53) 267.85,6.72 267.85,6.6 267.37,6.12 266.22,6.12 266.12,6.22 266.12,7.4 265.82,7.7 257.75,7.7 254.94,10.52 254.94,21.7 253.66,22.98 253.66,27.88 250.65,30.89 250.65,42.01 249.96,42.7 249.96,44.59 250.24,44.87 250.24,45.63 250,45.87 243.56,52.31 240.68,52.31 238.84,54.15 237.69,54.15 237.37,54.47 235.88,54.47 235.64,54.71 234.29,54.71 234.05,54.47 229.61,54.47 229.08,55.01 229.08,57.08 227.83,58.33 v2(227.83,59.51)
  BOTTOM w0.102: v2(227.83,59.51) 227.83,59.03 227.18,58.38 227.18,56.22 226.28,55.32 226.28,54.62 225.86,54.2 225.29,54.2 224.98,53.9 JNGFF2.26
UIM_DET: length 86
  TOP w0.102: v1(268.28,8.04) 268.05,7.81 268.05,7.24 267.35,6.55 JSH1.7 v2(267.38,4.49)
  IN4 w0.084: v2(267.38,4.49) 265.88,5.99 258.69,5.99 254.43,10.25 254.43,21.61 253.24,22.81 253.24,27.7 250.22,30.72 250.22,41.83 249.42,42.64 249.42,44.2 243.68,49.94 240.34,49.94 239.19,51.09 234.56,51.09 234.09,51.55 v2(233.16,51.55)
  BOTTOM w0.102: v2(233.16,51.55) 232.23,51.55 231.32,50.65 231.32,50.41 229.4,48.5 228.98,48.5 226.81,46.32 225.28,46.32 224.86,45.9 JNGFF2.58
UIM_RESET: length 97.1
  TOP w0.102: v2(267.2,7.09) 267.2,6.83 266.85,6.49 JSH1.6 ; v2(228.09,60.11) 228.41,60.43 v1(228.41,60.82) 228.44,60.85 228.44,61.94 229.43,62.93 229.43,63.83 CZ64.1
  IN4 w0.084: v2(267.2,7.09) 266.37,7.91 257.92,7.91 255.19,10.64 255.19,21.75 253.87,23.07 253.87,27.99 251.5,30.36 251.5,34.27 250.86,34.91 250.86,42.1 250.17,42.79 250.17,44.5 250.45,44.78 250.45,45.76 247.63,48.57 247.63,49.79 247.21,50.2 246,50.2 243.68,52.52 240.77,52.52 238.93,54.36 237.77,54.36 237.45,54.68 235.98,54.68 235.7,54.97 234.2,54.97 233.92,54.68 229.7,54.68 229.48,54.9 229.48,57.12 228.39,58.21 228.39,59.81 v2(228.09,60.11)
  BOTTOM w0.102: v2(228.09,60.11) 227.93,60.27 227.1,60.27 226.81,59.98 226.81,58.74 226.72,58.65 226.72,56.41 225.82,55.51 225.82,54.93 225.58,54.69 225.16,54.69 224.94,54.9 JNGFF2.22
USB3RN1: length 55.5
  TOP w0.102: v2(100.94,100.77) 100.76,100.95 100.76,101.61 100.86,101.71 UI4.5
  IN4 w0.091: v2(139.59,78.49) 139.44,78.33 139.24,78.33 139.12,78.46 139.12,81.69 138.15,82.65 116.87,82.65 116.45,83.08 115.13,83.08 113.27,84.94 113.27,85.57 112.45,86.39 112.45,87.85 108.02,92.29 105.75,92.29 100.75,97.28 100.75,100.58 v2(100.94,100.77)
  BOTTOM w0.081: v2(139.59,78.49) 139.7,78.49 UC1.G20
USB3RN1_D-: length 8.4
  TOP w0.102: JUSB1.5 68.48,99.64 68.58,99.54 68.58,98.97 69.11,98.44 69.11,98.04 68.48,97.41 67.77,97.41 67.47,97.11 67.47,96.62 67.33,96.48 DI1.9 DI1.1 67.33,94.81 67.46,94.68 67.46,94.5 67.08,94.11 LI1.3
USB3RN2: length 147.8
  TOP w0.102: LI6.4 264.67,70.57 264.38,70.27 263.85,70.27 263.84,70.28 263.31,70.28 263.3,70.27 262.24,70.27 261.7,69.73 257.84,69.73 257.26,69.15 257.26,68.58 257.05,68.36 256.87,68.36 v2(256.72,68.51)
  IN1 w0.091: v2(139.78,80.8) 139.78,80.65 139.96,80.47 140.44,80.47 140.66,80.69 140.66,82.19 139.37,83.48 139.37,84.42 141.77,86.82 145.04,86.82 145.57,87.36 148,87.36 148.25,87.11 153.16,87.11 155.24,89.19 156.97,89.19 157.17,89 161.84,89 162.56,89.71 167.19,89.71 171.33,85.57 173.16,85.57 173.62,85.11 182.8,85.11 183.25,85.57 188.08,85.57 188.6,86.08 189.29,86.08 190.05,86.84 191.81,86.84 192.15,86.51 195.57,86.51 196.14,85.94 198,85.94 199.25,84.68 207.62,84.68 210.22,82.08 213.04,82.08 217.65,77.47 219.03,77.47 219.9,76.6 223.89,76.6 224.97,75.53 232.09,75.53 232.8,74.82 235.56,74.82 235.86,74.52 240.34,74.52 241.1,73.75 242.73,73.75 243.13,73.36 249.66,73.36 254.71,68.31 256.51,68.31 v2(256.72,68.51)
  BOTTOM w0.081: UC1.E18 141.02,79.98 140.9,79.86 140.71,79.86 140.58,79.98 140.58,80.48 140.42,80.64 139.95,80.64 v2(139.78,80.8)
USB3RN2_D-: length 7.6
  TOP w0.102: JUSB3.5 272.97,70.48 272.85,70.36 272.31,70.36 271.61,69.66 270.97,69.66 270.33,70.3 269.98,70.3 269.84,70.44 DI4.9 DI4.1 268.13,70.44 267.96,70.27 267.77,70.27 267.47,70.57 LI6.3
USB3RN4: length 80.8
  IN1 w0.091: v2(163.11,88.47) 163.4,88.75 163.4,88.85 163.36,88.89 162.92,88.89 162.21,88.18 156.69,88.18 156.5,88.38 155.58,88.38 153.49,86.29 147.91,86.29 147.66,86.54 145.91,86.54 145.28,85.91 142.18,85.91 141.66,85.38 141.66,82.65 141.82,82.49 141.82,82.25 141.66,82.08 141.66,81.92 141.82,81.76 141.82,81.53 141.66,81.36 141.66,81.13 142.02,80.77 142.02,79.42 142.11,79.33 142.34,79.33 142.47,79.46 v2(142.47,79.71)
  BOTTOM w0.081: UC1.F15 142.67,79.51 v2(142.47,79.71)
  BOTTOM w0.102: LI9.1 195.38,90.14 195.6,89.92 195.85,89.92 196.02,89.75 196.02,89.25 195.52,88.75 195.05,88.75 195.03,88.76 194.5,88.76 194.49,88.75 191.38,88.75 190.22,89.9 190.22,94.15 189.13,95.24 183.88,95.24 182.54,93.89 182.54,90.11 181,88.57 175.44,88.57 173.42,90.59 169.81,90.59 169.38,91.02 163.3,91.02 162.67,90.4 162.67,89.44 163.21,88.91 163.21,88.56 v2(163.11,88.47)
USB3RN4_D-: length 11.8
  BOTTOM w0.102: LI9.2 195.38,92.75 195.82,93.19 195.82,93.32 195.76,93.38 DI6.9 DI6.1 195.76,95.16 195.92,95.32 195.92,95.96 194.65,97.23 192.24,97.23 191.54,97.93 191.54,98.5 191.08,98.96 191.08,99.54 190.98,99.64 JUSB2.5
USB3RP1: length 55.8
  TOP w0.102: v2(100.36,100.79) 100.55,100.98 100.55,101.62 100.46,101.71 UI4.4
  IN4 w0.091: v2(139.6,77.94) 139.38,78.16 139.17,78.16 138.94,78.39 138.94,81.62 138.08,82.48 116.8,82.48 116.37,82.91 115.06,82.91 113.1,84.87 113.1,85.5 112.28,86.32 112.28,87.78 107.95,92.11 105.67,92.11 100.58,97.21 100.58,100.57 v2(100.36,100.79)
  BOTTOM w0.081: UC1.H20 139.8,77.94 v2(139.6,77.94)
USB3RP1_D+: length 8.4
  TOP w0.102: LI1.2 67.93,94.28 67.68,94.53 67.68,94.63 67.83,94.78 DI1.2 DI1.8 67.83,96.48 67.69,96.62 67.69,97.02 67.86,97.19 68.57,97.19 69.33,97.95 69.33,98.53 68.8,99.06 68.8,99.54 68.9,99.64 JUSB1.6
USB3RP2: length 147.8
  TOP w0.102: LI6.1 264.67,69.72 264.34,70.05 v4(263.58,70.05) 262.33,70.05 261.79,69.51 257.93,69.51 257.48,69.06 257.48,68.49 257.14,68.15 256.94,68.15 v2(256.72,67.93)
  IN1 w0.091: v2(256.72,67.93) 256.51,68.13 254.64,68.13 249.59,73.18 243.05,73.18 242.66,73.58 241.03,73.58 240.26,74.34 235.79,74.34 235.49,74.65 232.73,74.65 232.02,75.35 224.9,75.35 223.82,76.43 219.82,76.43 218.96,77.3 217.58,77.3 212.97,81.91 210.15,81.91 207.55,84.51 199.18,84.51 197.93,85.76 196.07,85.76 195.5,86.33 192.08,86.33 191.74,86.67 190.12,86.67 189.36,85.91 188.67,85.91 188.16,85.4 183.33,85.4 182.87,84.94 173.55,84.94 173.09,85.4 171.26,85.4 167.12,89.54 162.63,89.54 161.92,88.82 157.1,88.82 156.9,89.02 155.31,89.02 153.23,86.94 148.18,86.94 147.93,87.19 145.65,87.19 145.11,86.65 141.85,86.65 139.54,84.35 139.54,83.55 140.83,82.26 140.83,80.62 140.51,80.3 v2(139.58,80.3)
  BOTTOM w0.081: v2(139.58,80.3) 139.72,80.44 140.34,80.44 140.39,80.4 140.39,79.9 140.63,79.66 140.87,79.66 UC1.F18
USB3RP2_D+: length 7.6
  TOP w0.102: JUSB3.6 272.97,70.02 272.85,70.14 272.4,70.14 271.7,69.44 270.88,69.44 270.24,70.09 269.98,70.09 269.84,69.94 DI4.8 DI4.2 268.07,69.94 267.96,70.05 267.74,70.05 267.41,69.72 LI6.2
USB3RP4: length 80.7
  IN1 w0.091: v2(142.47,78.98) 142.3,79.16 142.04,79.16 141.84,79.35 141.84,80.69 141.48,81.06 141.48,85.45 142.11,86.08 145.2,86.08 145.84,86.72 147.73,86.72 147.99,86.46 153.42,86.46 155.51,88.55 156.57,88.55 156.77,88.35 162.14,88.35 162.85,89.06 163.43,89.06 163.57,88.92 163.57,88.59 v2(163.7,88.47)
  BOTTOM w0.081: UC1.G15 142.6,78.86 v2(142.47,78.98)
  BOTTOM w0.102: v2(163.7,88.47) 163.42,88.74 163.42,89 162.89,89.53 162.89,90.31 163.39,90.8 169.29,90.8 169.72,90.37 173.33,90.37 175.35,88.35 181.09,88.35 182.75,90.02 182.75,93.8 183.97,95.02 189.04,95.02 190,94.06 190,89.81 191.29,88.53 v4(194.77,88.53) 195.61,88.53 196.23,89.16 LI9.4
USB3RP4_D+: length 11.8
  BOTTOM w0.102: JUSB2.6 191.4,99.64 191.3,99.54 191.3,99.05 191.76,98.59 191.76,98.02 192.33,97.45 194.74,97.45 196.15,96.04 v4(196.15,95.67) 196.15,95.27 196.26,95.16 DI6.2 DI6.8 196.26,93.51 196.04,93.29 196.04,93.19 196.23,93 LI9.3
USB3TN1: length 50.4
  TOP w0.102: v2(98.13,101.83) 98.26,101.7 98.26,101.41 98.48,101.19 99.34,101.19 99.61,101.46 99.61,101.69 99.66,101.74 UI4.2
  IN4 w0.091: v2(129.97,84.29) 129.37,84.29 128.38,83.3 117.02,83.3 116.59,83.73 115.35,83.73 114.01,85.08 114.01,85.75 113.1,86.65 113.1,88.12 108.24,92.98 106.08,92.98 101.57,97.48 101.57,101.07 100.14,102.51 98.59,102.51 98.32,102.24 98.32,102.02 v2(98.13,101.83)
  BOTTOM w0.081: UC1.C33 131.52,81.65 131.23,81.94 131.23,82.34 130.9,82.68 130.9,83.91 130.54,84.26 130,84.26 v2(129.97,84.29)
USB3TN1_C: length 1.7
  TOP w0.102: LI2.4 68.73,91.44 69.04,91.13 69.04,90.88 CI4.1
USB3TN1_D-: length 12.1
  TOP w0.102: JUSB1.8 74.06,100 74.63,100 74.73,99.9 74.73,99.35 73.65,98.27 73.65,97.94 73.02,97.32 69.6,97.32 68.97,96.69 68.97,96.43 68.83,96.29 DI1.7 DI1.4 68.83,94.72 68.99,94.56 68.99,94.44 68.73,94.18 LI2.3
USB3TN2: length 153.9
  TOP w0.102: v2(258.15,68.87) 258.35,68.67 261.8,68.67 261.98,68.49 262.67,68.49 CI16.2
  IN1 w0.091: v2(258.15,68.87) 257.95,68.67 257.56,68.67 257.07,69.16 256.11,69.16 255.56,69.71 255.56,71.01 252.56,74 243.39,74 243,74.4 241.37,74.4 240.56,75.21 238.65,75.21 238.37,75.49 236.19,75.49 235.73,75.95 234.64,75.95 233.4,77.19 231.39,77.19 230.37,76.17 225.24,76.17 223.14,78.27 217.84,78.27 213.71,82.4 213.71,84.02 212.4,85.33 204.88,85.33 203.85,86.36 198.95,86.36 198.68,86.63 196.36,86.63 195.38,87.61 193.92,87.61 193.52,88.01 187.91,88.01 186.11,86.21 182.23,86.21 181.95,85.94 174.18,85.94 173.9,86.21 171.6,86.21 166.28,91.54 160.12,91.54 159.86,91.28 154.55,91.28 152.86,89.59 145.58,89.59 145.21,89.96 141.68,89.96 140.05,88.33 132.82,88.33 131.32,86.83 131.32,85.37 131.64,85.06 131.64,84.06 131.52,83.94 131.45,83.94 v2(131.26,84.14)
  BOTTOM w0.081: UC1.B33 131.52,82.3 131.83,82.61 131.83,83.74 131.64,83.93 131.46,83.93 v2(131.26,84.14)
USB3TN2_C: length 1.6
  TOP w0.102: LI5.4 264.79,68.79 264.47,68.47 264.24,68.47 CI16.1
USB3TN2_D-: length 10.7
  TOP w0.102: LI5.3 267.41,68.79 267.64,68.55 267.78,68.55 268.17,68.94 DI4.4 DI4.7 269.84,68.94 269.98,68.8 270.17,68.8 270.59,68.38 270.59,65.54 270.62,65.52 270.62,65.52 271.04,65.1 271.04,65.08 271.13,64.99 271.89,64.99 272.56,64.32 272.87,64.32 272.97,64.43 272.97,65.25 JUSB3.8
USB3TN4: length 86.5
  IN1 w0.091: v2(164.01,90.19) 163.8,90.4 163.8,90.71 163.62,90.89 160.41,90.89 160.15,90.63 154.85,90.63 152.62,88.4 148.79,88.4 148.24,88.95 141.59,88.95 140.21,87.57 133.7,87.57 132.91,86.79 132.91,85.58 132.73,85.4 v2(132.32,85.4)
  BOTTOM w0.081: v2(132.32,85.4) 133.08,85.4 133.38,85.11 133.38,82.41 133.17,82.2 132.97,82.2 UC1.B31
  BOTTOM w0.102: v2(164.01,90.19) 163.82,90.01 163.82,89.83 163.93,89.71 165.12,89.71 165.57,90.16 169.06,90.16 169.46,89.76 172.86,89.76 174.94,87.68 181.43,87.68 183.36,89.61 183.36,93.42 184.35,94.41 188.77,94.41 189.4,93.79 189.4,89.56 191.03,87.92 196.14,87.92 196.34,87.73 197.19,87.73 197.32,87.86 197.32,88.25 197.21,88.37 197.02,88.37 CI28.2
USB3TN4_C: length 1.8
  BOTTOM w0.102: LI8.1 196.97,90.2 197.26,89.92 197.26,89.52 CI28.1
USB3TN4_D-: length 9.1
  BOTTOM w0.102: JUSB2.8 196.98,99.64 197.08,99.54 197.08,99.02 196.43,98.37 196.43,97.23 197.45,96.21 197.45,96.11 197.43,96.09 197.43,95.49 197.45,95.48 197.45,95.26 197.26,95.08 DI6.4 DI6.7 197.26,93.47 197.34,93.39 197.34,93.25 196.97,92.88 LI8.2
USB3TP1: length 50.2
  TOP w0.102: UI4.1 99.26,101.74 99.39,101.61 99.39,101.55 99.25,101.41 98.57,101.41 98.48,101.5 98.48,101.59 v2(98.71,101.83)
  IN4 w0.091: v2(98.71,101.83) 98.67,101.83 98.5,102 98.5,102.17 98.67,102.34 100.06,102.34 101.4,101 101.4,97.41 106.01,92.8 108.17,92.8 112.93,88.04 112.93,86.58 113.83,85.68 113.83,85 115.28,83.56 116.51,83.56 116.95,83.13 128.45,83.13 128.57,83.24 128.84,83.24 128.92,83.33 128.92,83.6 129.04,83.71 129.29,83.71 129.37,83.79 129.37,84.04 129.44,84.12 129.59,84.12 129.97,83.73 v2(129.97,83.65)
  BOTTOM w0.081: v2(129.97,83.65) 129.97,83.77 130.27,84.07 130.46,84.07 130.7,83.83 130.7,82.6 131.04,82.26 131.04,82.17 130.99,82.12 130.74,82.12 130.65,82.03 130.65,81.87 130.82,81.7 130.88,81.7 130.95,81.78 UC1.B34
USB3TP1_C: length 1.7
  TOP w0.102: LI2.1 69.58,91.47 69.26,91.15 69.26,90.88 CI5.1
USB3TP1_D+: length 11.3
  TOP w0.102: JUSB1.9 75.01,99.64 74.94,99.57 74.94,99.26 73.86,98.18 73.86,97.85 73.11,97.1 70.21,97.1 70.19,97.09 v4(69.91,97.09) 69.67,97.09 69.19,96.6 69.19,96.49 69.33,96.35 DI1.6 DI1.5 69.33,94.78 69.2,94.65 69.2,94.46 69.58,94.09 LI2.2
USB3TP2: length 153.9
  TOP w0.102: v2(258.15,68.29) 258.32,68.45 261.71,68.45 261.89,68.27 262.64,68.27 CI13.2
  IN1 w0.091: v2(131.26,83.55) 131.44,83.74 131.56,83.74 131.81,83.99 131.81,85.13 131.5,85.45 131.5,86.76 132.89,88.15 140.13,88.15 141.76,89.78 145.14,89.78 145.5,89.42 152.93,89.42 154.62,91.11 159.93,91.11 160.19,91.36 166.21,91.36 171.53,86.04 173.83,86.04 174.1,85.76 182.02,85.76 182.3,86.04 186.18,86.04 187.98,87.83 193.44,87.83 193.84,87.43 195.31,87.43 196.29,86.46 198.61,86.46 198.88,86.19 203.78,86.19 204.81,85.16 212.33,85.16 213.54,83.94 213.54,82.33 217.77,78.1 223.07,78.1 225.16,76 230.44,76 231.46,77.02 233.33,77.02 234.57,75.78 235.66,75.78 236.12,75.32 238.3,75.32 238.58,75.03 240.48,75.03 241.3,74.22 242.93,74.22 243.32,73.83 252.49,73.83 255.38,70.93 255.38,69.63 256.03,68.98 257,68.98 257.49,68.49 257.95,68.49 v2(258.15,68.29)
  BOTTOM w0.081: UC1.A33 131.52,82.57 131.45,82.51 131.32,82.51 131.17,82.66 131.17,82.83 131.45,83.1 131.58,83.1 131.64,83.17 131.64,83.67 131.56,83.74 131.45,83.74 v2(131.26,83.55)
USB3TP2_C: length 1.6
  TOP w0.102: CI13.1 264.24,68.26 264.47,68.26 264.79,67.94 LI5.1
USB3TP2_D+: length 10.7
  TOP w0.102: JUSB3.9 272.97,63.25 272.97,64.01 272.87,64.11 272.47,64.11 271.8,64.78 271.04,64.78 v4(270.67,65.14) 270.37,65.44 270.37,68.29 270.08,68.59 269.98,68.59 269.84,68.44 DI4.6 DI4.5 267.97,68.44 267.83,68.3 267.83,68.17 267.6,67.94 LI5.2
USB3TP4: length 86.6
  IN1 w0.091: v2(132.32,84.82) 132.32,84.89 132.67,85.23 132.8,85.23 133.08,85.51 133.08,86.72 133.77,87.4 140.28,87.4 141.66,88.77 148.17,88.77 148.72,88.23 152.69,88.23 154.93,90.46 160.22,90.46 160.48,90.72 163.55,90.72 163.63,90.64 163.63,90.4 v2(163.42,90.19)
  BOTTOM w0.081: UC1.A31 132.84,82.72 132.84,82.53 132.97,82.4 133.09,82.4 133.18,82.49 133.18,85.02 133,85.21 132.64,85.21 132.32,84.9 v2(132.32,84.82)
  BOTTOM w0.102: v2(163.42,90.19) 163.6,90.01 163.6,89.74 163.84,89.5 165.21,89.5 165.66,89.95 168.97,89.95 169.37,89.55 172.77,89.55 174.85,87.46 181.52,87.46 183.58,89.52 183.58,93.33 184.44,94.2 188.68,94.2 189.18,93.7 189.18,89.47 190.94,87.71 196.05,87.71 196.25,87.51 197.28,87.51 197.54,87.77 197.54,87.99 197.54,87.99 CI27.2
USB3TP4_C: length 1.8
  BOTTOM w0.102: LI8.4 197.82,90.3 197.47,89.96 197.47,89.45 CI27.1
USB3TP4_D+: length 9.1
  BOTTOM w0.102: JUSB2.9 197.4,99.64 197.3,99.54 197.3,98.93 196.65,98.28 196.65,97.32 197.66,96.3 v4(197.66,95.8) 197.66,95.26 197.76,95.16 DI6.5 DI6.6 197.76,93.48 197.55,93.27 197.55,93.11 197.82,92.84 LI8.3
USB_DB_DET#: length 1.1
  TOP w0.102: T98.1 232.47,55.02 UE1.A2
USB_OC0#: length 117.4
  TOP w0.102: UI3.13 81.13,94.5 81.65,95.02 92.47,95.02 94.45,93.04 v1(97.55,93.04) 98.37,93.04 100.03,91.39 v2(100.03,89.18)
  IN2 w0.081: 147.24,85.13 147.24,83.8 148.2,82.84 149.09,82.84 150.22,81.71 150.22,80.25 149.9,79.93 149.9,79.55 149.94,79.51 149.94,77.71 150.67,76.97 150.67,76.24 150.43,76 149.28,76 148.66,75.38 146.8,75.38 146.43,75.01 146.43,71.86 146.62,71.67 148.98,71.67 149.28,71.37 149.28,71.03 149.11,70.87 149.11,70.46 149.23,70.34 149.23,68.98 149.91,68.3 150.31,68.3 152.24,66.37 v2(152.24,66.02)
  IN2 w0.122: 147.24,85.13 145.24,87.13 145.24,89.31 139.98,94.56 130.84,94.56 129.53,93.26 128.53,93.26 128.25,92.97 128.25,92.97 127.95,92.67 126.01,92.67 125.66,92.32 113.66,92.32 112.74,91.41 109.78,91.41 109.56,91.19 105.85,91.19 104.45,89.78 103.63,89.78 102.65,88.8 100.41,88.8 v2(100.03,89.18)
  BOTTOM w0.076: 153.82,67.3 153.67,67.3 153.15,66.78 152.78,66.78 152.24,66.24 v2(152.24,66.02) 151.86,66.4 151.48,66.4 151.19,66.11 151.12,66.11 150.95,65.94 150.95,65.76 150.72,65.52 150.2,65.52 UC1.AL3
  BOTTOM w0.102: RPC19.3 157.53,68.74 156.66,67.87 155.54,67.87 154.97,67.3 153.82,67.3
USB_OC1#: length 135.5
  IN1 w0.084: v2(162.93,66.9) 162.55,66.9 160.81,68.65 160.81,69.99 161.05,70.23 163.53,70.23 165.42,68.34 166.09,68.34 166.79,67.64 177.43,67.64 179.14,69.36 179.14,70.12 182.69,73.67 v2(183.92,73.67)
  IN4 w0.084: v2(254.68,74.08) 255,74.4 255,75.43 253.88,76.55 251.17,76.55 249.73,77.99 244.39,77.99 243.9,78.47 243.9,78.99 242.98,79.91 240.18,79.91 239.83,80.26 233.81,80.26 232.16,78.61 227.38,78.61 227.38,78.62 225.57,78.62 224.94,77.99 222.89,77.99 222.41,78.46 215.44,78.46 215.02,78.04 208.57,78.04 207.86,78.75 205.85,78.75 205.58,78.47 203.14,78.47 198.48,73.81 195.3,73.81 194.34,72.85 188.51,72.85 188.27,73.09 184.49,73.09 v2(183.92,73.67)
  BOTTOM w0.081: UC1.AT1 151.25,62.77 152.52,62.77 153.82,64.07
  BOTTOM w0.102: UI1.5 252.87,79.88 252.4,79.41 252.4,77 252.91,76.49 253.54,76.49 254.88,75.16 254.88,74.27 v2(254.68,74.08) ; RPC7.7 163.69,65.82 163.56,65.95 163.18,65.95 162.93,66.2 v2(162.93,66.9) 162.34,66.9 161.69,66.25 156.06,66.25 153.98,64.17 153.92,64.17 153.82,64.07
USB_OC2#: length 117.9
  TOP w0.081: 153.82,65.44 152.83,65.44 152.64,65.63 151.5,65.63 151.31,65.82 151.31,66.65 152.31,67.65 v2(152.31,67.96)
  TOP w0.102: RPC10.5 163.53,62.76 163.07,63.22 163.07,63.7 160.29,66.48 155.9,66.48 154.86,65.44 153.82,65.44
  IN1 w0.084: v2(209.09,69.13) 208.27,69.13 205.87,71.52 198.41,71.52 197.32,70.44 194.15,70.44 193.15,71.44 188.71,71.44 186.01,74.14 182.87,74.14 178.93,70.21 178.93,69.44 177.34,67.86 166.88,67.86 166.18,68.55 165.51,68.55 163.62,70.44 160.96,70.44 160.6,70.08 160.6,68.87 160.1,68.37 152.72,68.37 v2(152.31,67.96)
  BOTTOM w0.076: UC1.AH2 150.6,67.32 151.06,67.77 151.33,67.77 151.56,67.54 152.01,67.54 152.31,67.84 v2(152.31,67.96)
  BOTTOM w0.102: v2(209.09,69.13) 209.99,70.03 209.99,73.47 210.66,74.13 211.07,74.13 211.57,74.62 211.57,77.04 212.2,77.68 212.2,81.71 211.54,82.37 211.54,84.84 211.19,85.19 209.44,85.19 209.12,85.51 205.73,85.51 205.04,86.19 v1(205.04,87.06) 205.16,87.17 205.16,88.83 204.62,89.36 204.62,90.93 203.57,91.99 203.57,92.3 203.74,92.47 UI2.5
USB_OC3#: length 18.4
  BOTTOM w0.081: 153.82,62.43 152.83,61.44 151.78,61.44 151.43,61.79 151.11,61.79 151.1,61.79 150.33,61.79 150.01,61.47 UC1.AV3
  BOTTOM w0.102: RPC7.5 164.07,64.05 163.67,63.65 v1(163.28,63.65) 162.69,63.65 160.54,65.8 156.59,65.8 154.48,63.69 154.48,63.09 153.82,62.43
USB_PWR_EN1#: length 74.5
  TOP w0.102: UE1.B44 229.72,45.22 v2(229.76,45.26) ; v2(229.6,42.2) 229.34,41.95 RPE9.2 229.34,40.7 229.53,40.51 230.23,40.51 230.39,40.35 v1(230.39,38.53)
  IN1 w0.084: v2(229.6,42.2) 229.78,42.39 229.78,45.24 v2(229.76,45.26)
  BOTTOM w0.102: UI1.4 251.75,79.88 252.11,79.52 252.11,77.22 251.77,76.87 249.92,76.87 248.91,75.86 246.3,75.86 245.8,75.35 245.8,73.77 246.43,73.14 246.43,70.67 247.61,69.49 248.44,69.49 250.56,67.38 250.56,63.54 250.18,63.16 250.18,61.91 248.16,59.89 248.16,56.77 246.67,55.28 246.67,52.91 243.86,50.1 243.86,48.78 242.88,47.79 242.88,46.2 236.45,39.78 233.63,39.78 232.24,41.17 231.03,41.17 230.97,41.23 230.97,42.55 229.76,43.76 v2(229.76,45.26)
USB_PWR_EN2#: length 81.8
  TOP w0.102: v2(229.01,42.19) 228.84,42.02 RPE9.3 ; v2(225.54,42.73) 225.47,42.8 UE1.A33
  IN1 w0.084: v2(229.01,42.19) 228.86,42.34 228.86,42.95 228.52,43.28 226.09,43.28 v2(225.54,42.73)
  IN4 w0.084: v2(230.49,69.06) 230.3,69.25 229.84,69.25 229.02,68.43 v2(226.3,68.43)
  BOTTOM w0.102: v2(229.01,42.19) 228.85,42.35 228.85,44.17 228.31,44.7 228.31,45.99 229.23,46.91 230.94,46.91 232.43,48.4 233.39,48.4 233.79,48.8 233.79,60.87 232.65,62.01 231.05,62.01 230.58,62.48 230.58,68.97 v2(230.49,69.06) ; UI2.4 210.07,92.47 210.19,92.59 211.17,92.59 v1(211.25,92.51) 211.63,92.13 211.63,88.67 212.4,87.91 212.4,85.46 212.88,84.97 213.98,84.97 214.13,84.82 215.32,84.82 216.16,83.99 216.41,83.73 218.87,83.73 219.25,83.35 219.25,79.51 220.45,78.31 221.76,78.31 223.23,76.84 223.23,72.39 224.22,71.4 224.98,71.4 225.17,71.59 225.59,71.59 225.86,71.32 225.86,70.76 226.3,70.32 v2(226.3,68.43)
USB_PWR_SHR_EN#: length 239.5
  TOP w0.102: v2(228.43,42.18) 228.34,42.09 RPE9.4 ; v2(88.67,85.28) v1(88.67,84.02) 88.67,83.27 86.49,81.09 85.47,81.09 84.82,80.44 84.82,79.13 84.56,78.87 82.7,78.87 81.67,79.9 80.78,79.9 78,82.68 78,84.99 78.26,85.24 78.26,86.36 79.36,87.46 79.36,89.7 80.13,90.47 UI3.6 ; UE2.B38 239.41,59.63 239.78,59.99 240.08,59.99 v2(240.28,60.2)
  IN2 w0.122: v2(228.43,42.18) 228.43,42.19 228.84,42.6 228.84,43.19 229.38,43.73 236.41,43.73 237.35,44.68 237.35,47.05 239.12,48.83 239.12,49.52 239.91,50.31 239.91,52.28 239.64,52.54 239.64,54.2 240,54.55 240,55.4 241.09,56.5 241.09,58.35 240.35,59.09 240.35,60.13 v2(240.28,60.2)
  IN3 w0.122: v2(240.28,60.2) 240.28,60.51 239.99,60.81 239.19,60.81 238.9,60.52 237.83,60.52 236.97,61.38 234.81,61.38 233.41,62.78 233.41,65.65 232.49,66.58 232.49,67.77 230.7,69.56 230.7,70.18 230.84,70.32 230.84,70.74 230.16,71.41 230.16,71.71 230.9,72.44 230.9,73.74 231.97,74.81 232.49,74.81 233.19,75.51 233.19,76.78 232.69,77.28 232.14,77.28 231.38,76.53 228.3,76.53 226.76,78.07 226.76,78.22 225.11,79.87 224.82,79.87 223.64,81.05 222.08,81.05 221.23,81.9 216.96,81.9 215.55,83.31 211.92,83.31 210.77,84.46 207.68,84.46 206.98,85.16 205.99,85.16 205.19,85.95 199.93,85.95 199.42,86.45 199.21,86.45 197.49,88.18 187.79,88.18 187.63,88.02 185.08,88.02 183.9,86.84 169.65,86.84 163.8,92.68 151.55,92.68 151.1,93.13 147.94,93.13 147.24,92.43 143.37,92.43 143.14,92.66 134,92.66 133.16,91.82 112.23,91.82 109.45,89.04 108.41,89.04 107.59,89.85 103.73,89.85 100.66,86.78 94.21,86.78 92.71,85.28 v2(88.67,85.28)
USB_PWR_SHR_VBUS_EN: length 269.1
  TOP w0.102: v2(81.46,79.48) v1(80.82,79.48) 77.78,82.52 77.78,85.18 78,85.4 78,86.44 79.12,87.57 79.12,89.8 79.63,90.31 UI3.5 ; UE1.B50 232.72,44.77 232.58,44.9 232.02,44.9 231.05,45.87 v2(231,45.87) ; RPE9.1 229.84,41.84 v2(230.18,42.18)
  IN1 w0.084: v2(59.46,42.46) 59.46,48.05 67.02,55.61 67.02,59.7 66.4,60.33 65.7,60.33 64.51,61.51 64.41,61.51 63.67,62.25 63.67,62.73 65.5,64.55 66.41,64.55 67.57,65.72 69.67,65.72 75.53,71.58 75.53,73.83 81.18,79.48 v2(81.46,79.48) ; v2(231,45.87) 230.61,45.48 230.61,42.38 230.41,42.18 v2(230.18,42.18)
  IN3 w0.122: v2(231,45.87) 230.07,46.8 230.07,50.54 228.15,52.47 228.15,52.9 227.86,53.19 226.68,53.19 226.23,53.64 224.32,53.64 223.57,54.39 223.57,55.69 222.39,56.87 222,56.87 220.55,55.42 220.55,54.84 218.83,53.12 218.83,48.97 217.47,47.61 217.47,46.42 217.03,45.98 217.03,43.05 214.3,40.33 209.29,40.33 207.56,38.59 205.6,38.59 204.61,37.6 203.76,37.6 202.99,38.37 202.99,38.41 201.16,40.24 186.18,40.24 184.59,38.65 67.98,38.65 65,41.63 60.29,41.63 v2(59.46,42.46)
USBP0+: length 77.5
  TOP w0.102: UI4.6 101.26,101.7 101.36,101.6 101.36,100.55 98.69,97.88 98.69,93.73 101.6,90.82 101.6,89.88 101.49,89.76 101.31,89.76 v2(101.09,89.99)
  IN4 w0.091: v2(101.09,89.99) 101.26,89.81 102.09,89.81 102.36,90.08 106.49,90.08 110.19,86.39 110.19,85.28 114.3,81.17 115.38,81.17 116.78,79.78 136.07,79.78 137.07,78.78 137.07,77.59 138.61,76.05 138.61,75.16 138.94,74.82 139.45,74.82 139.86,74.41 139.86,72.82 141.97,70.7 141.97,68.87 142.16,68.68 143.69,68.68 144.03,68.34 144.03,66.05 144.2,65.89 144.96,65.89 145.34,65.51 145.34,65.04 145.76,64.62 146.38,64.62 v2(146.48,64.72)
  BOTTOM w0.081: UC1.AM8 146.64,64.72 v2(146.48,64.72)
USBP0-: length 77.9
  TOP w0.102: UI4.7 101.66,101.68 101.57,101.59 101.57,100.46 98.91,97.79 98.91,93.82 101.82,90.91 101.82,89.79 101.57,89.55 101.24,89.55 101.23,89.53 101.21,89.53 v2(101.09,89.41)
  IN4 w0.091: v2(146.45,64.13) 146.14,64.44 145.69,64.44 145.17,64.97 145.17,65.43 144.89,65.71 144.12,65.71 143.86,65.98 143.86,68.26 143.62,68.51 142.09,68.51 141.8,68.8 141.8,70.63 139.69,72.75 139.69,74.34 139.38,74.65 138.87,74.65 138.44,75.09 138.44,75.98 136.89,77.52 136.89,78.71 136,79.6 116.71,79.6 115.31,81 114.22,81 110.01,85.21 110.01,86.32 106.42,89.91 102.43,89.91 102.16,89.64 101.32,89.64 v2(101.09,89.41)
  BOTTOM w0.081: v2(146.45,64.13) 146.69,64.38 UC1.AN8
USBP0_R_D+: length 11
  TOP w0.102: LI3.2 72.36,91.94 72.05,92.25 72.05,93 72.17,93.13 72.42,93.13 DI2.3 72.16,93.61 72.06,93.72 72.06,94.27 71.18,95.15 70.73,95.15 v2(70.54,95.34)
  IN1 w0.091: v2(70.54,95.34) 70.66,95.22 71.24,95.22 72.01,95.99 72.01,97.25 71.6,97.66 71.6,98.05 71.51,98.14 JUSB1.3
USBP0_R_D-: length 11
  TOP w0.102: LI3.3 71.51,91.94 71.83,92.26 71.83,93.02 71.74,93.11 71.47,93.11 DI2.2 71.73,93.61 71.84,93.73 71.84,94.18 71.09,94.93 70.71,94.93 v2(70.54,94.76)
  IN1 w0.091: v2(70.54,94.76) 70.83,95.05 71.32,95.05 72.19,95.92 72.19,97.32 71.78,97.73 71.78,98.05 71.87,98.14 JUSB1.2
USBP1+: length 154
  TOP w0.102: v2(245.88,40.65) 246.06,40.84 246.8,40.84 250.81,44.85 250.81,46.59 251.73,47.51 254.86,47.51 255.16,47.8 255.37,48.02 258.5,51.14 258.5,53.99 263.16,58.65 264.67,58.65 264.99,58.33 LI7.1
  IN4 w0.091: v2(147.93,62.97) 147.99,63.03 148.2,63.03 148.28,62.95 148.28,62.59 148.14,62.46 147.44,62.46 146.93,61.94 146.93,60.94 147.87,60 149.83,60 152.32,57.51 153.15,57.51 159.51,51.15 164.46,51.15 171.15,44.46 171.7,44.46 185.69,30.47 192.18,30.47 192.44,30.22 198.24,30.22 198.65,30.63 205.77,30.63 208.25,33.11 208.25,36.7 210.11,38.57 217.01,38.57 220.28,41.84 221.18,41.84 221.39,41.63 222.45,41.63 222.59,41.77 223.34,41.77 224.74,43.17 242.46,43.17 244.57,41.07 245.47,41.07 v2(245.88,40.65)
  BOTTOM w0.081: v2(147.93,62.97) 147.64,62.97 147.51,62.84 UC1.AT7
USBP1-: length 154
  TOP w0.102: v2(245.88,41.24) 246.06,41.06 246.71,41.06 250.59,44.94 250.59,46.68 251.64,47.73 254.75,47.73 v4(254.99,47.96) 255.2,48.17 255.22,48.17 258.28,51.23 258.28,54.08 263.07,58.86 264.61,58.86 264.92,59.18 LI7.4
  IN4 w0.091: v2(147.93,63.62) 147.93,63.55 148.45,63.02 148.45,62.52 148.21,62.29 147.52,62.29 147.1,61.87 147.1,61.02 147.94,60.17 149.9,60.17 152.4,57.68 153.22,57.68 159.58,51.32 164.54,51.32 171.22,44.63 171.77,44.63 185.76,30.64 192.26,30.64 192.51,30.39 198.17,30.39 198.58,30.8 205.69,30.8 208.08,33.18 208.08,36.78 210.04,38.74 216.93,38.74 220.21,42.01 221.25,42.01 221.46,41.8 222.38,41.8 222.52,41.95 223.27,41.95 224.67,43.34 242.54,43.34 244.64,41.24 v2(245.88,41.24)
  BOTTOM w0.081: v2(147.93,63.62) 147.71,63.4 UC1.AR7
USBP1_R_D+: length 16.3
  TOP w0.102: v2(270.94,60.6) 270.76,60.78 270.46,60.78 269.72,60.04 269.72,59.61 269.82,59.51 DI5.3 269.39,58.33 LI7.2
  IN1 w0.091: JUSB3.3 271.47,67.56 271.38,67.46 270.75,67.46 269.88,66.59 269.88,61.31 270.38,60.81 270.73,60.81 v2(270.94,60.6)
USBP1_R_D-: length 16.3
  TOP w0.102: LI7.3 267.31,59.18 267.94,58.55 269.3,58.55 269.44,58.68 269.44,58.95 269.35,59.03 269.13,59.03 DI5.2 269.4,59.51 269.5,59.61 269.5,60.13 270.37,61 270.76,61 v2(270.94,61.18)
  IN1 w0.091: JUSB3.2 271.47,67.2 271.38,67.29 270.82,67.29 270.05,66.52 270.05,61.38 270.45,60.98 270.74,60.98 v2(270.94,61.18)
USBP2+: length 88.9
  IN4 w0.091: v2(146.48,63.59) 146.74,63.33 146.88,63.33 147.05,63.16 147.05,62.71 146.55,62.2 146.55,59.73 147.75,58.52 149.72,58.52 152.53,55.71 153.61,55.71 159.62,49.7 165.24,49.7 167.95,46.99 167.95,46.29 170.25,43.99 171.51,43.99 185.58,29.91 185.58,27.82 186.8,26.6 200.42,26.6 202.87,29.04 211.11,29.04 v2(211.32,29.24)
  BOTTOM w0.081: v2(146.48,63.59) 146.62,63.73 UC1.AP8
  BOTTOM w0.102: v2(211.32,29.24) 211.13,29.06 210.47,29.06 210.32,29.21 209.76,29.21 209.62,29.35 JNGFF1.3
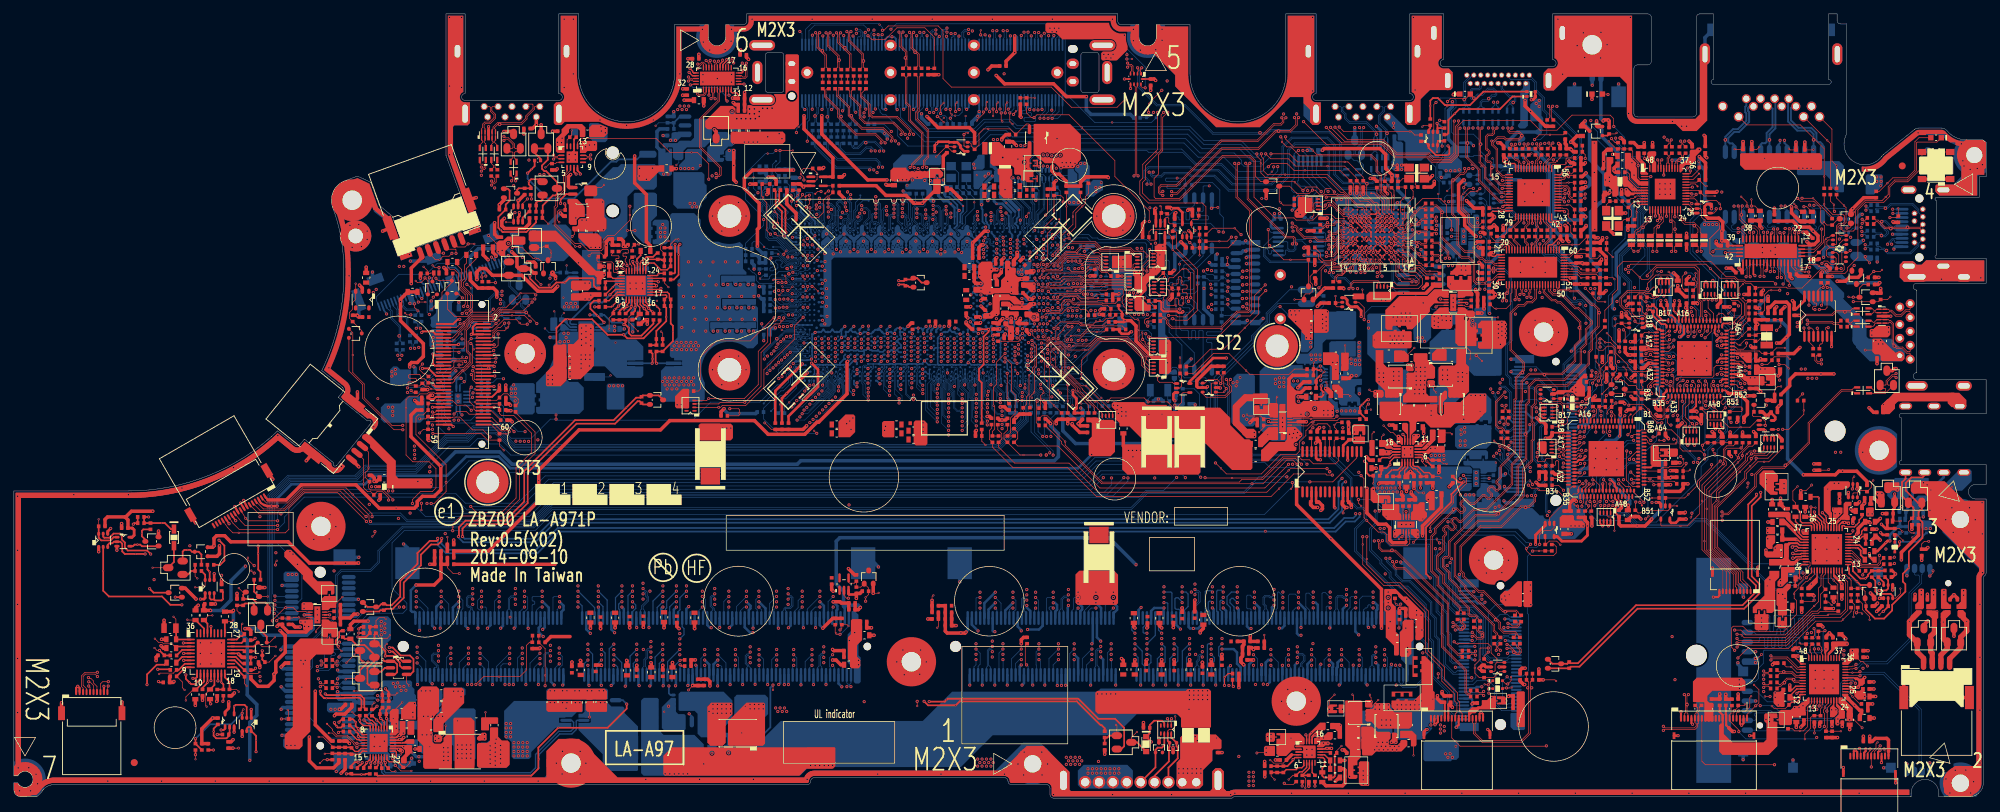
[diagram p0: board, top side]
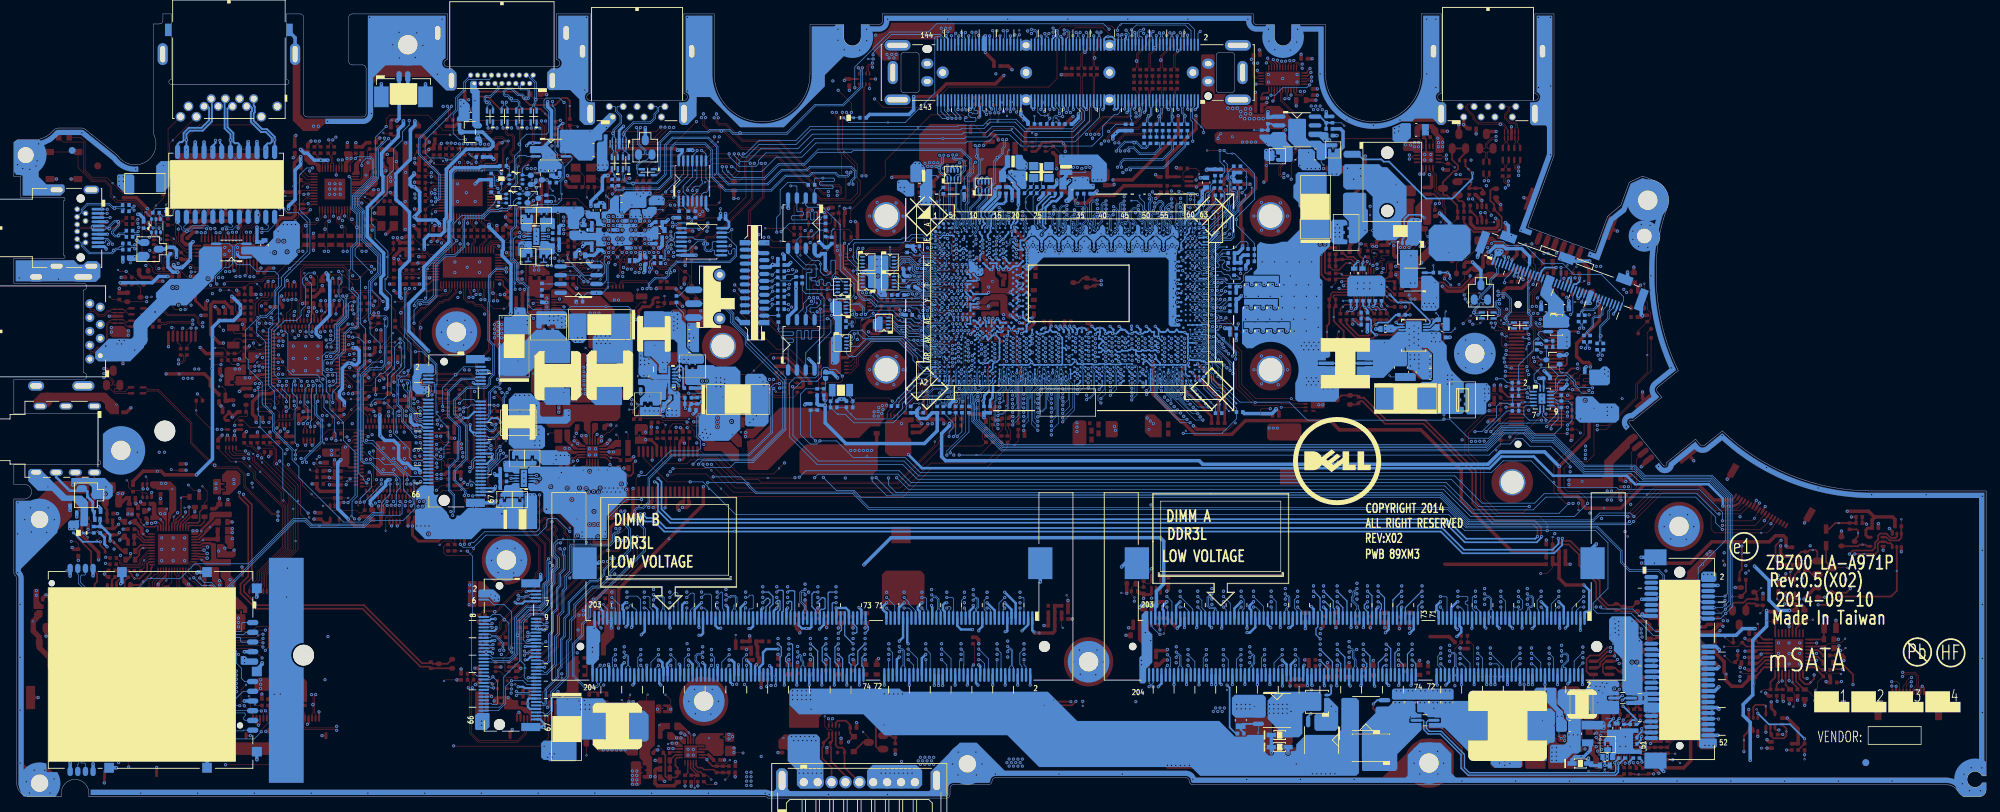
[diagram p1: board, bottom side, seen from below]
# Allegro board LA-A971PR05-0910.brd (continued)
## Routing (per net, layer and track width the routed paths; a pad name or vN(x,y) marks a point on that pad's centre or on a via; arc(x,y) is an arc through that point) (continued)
USBP2-: length 88.9
  IN4 w0.091: v2(211.32,28.66) 211.11,28.87 202.94,28.87 200.49,26.42 186.73,26.42 185.41,27.75 185.41,29.84 171.43,43.82 170.18,43.82 167.77,46.22 167.77,46.92 165.17,49.52 159.55,49.52 153.54,55.54 152.46,55.54 149.65,58.35 147.68,58.35 146.37,59.66 146.37,62.27 146.88,62.78 146.88,63.08 146.8,63.16 146.68,63.16 v2(146.48,62.97)
  BOTTOM w0.081: v2(146.48,62.97) 146.59,63.08 UC1.AR8
  BOTTOM w0.102: v2(211.32,28.66) 211.13,28.84 210.38,28.84 210.23,28.99 209.76,28.99 209.62,28.85 JNGFF1.5
USBP3+: length 78.8
  TOP w0.102: UI5.8 161.74,102.56 161.63,102.46 161.63,89.85 v2(161.83,89.66)
  IN1 w0.091: v2(146.01,62.35) 145.9,62.46 145.53,62.46 145.29,62.69 145.29,65.83 145.61,66.15 145.61,73.44 143.77,75.28 143.77,76.28 143.42,76.64 138.54,76.64 137.97,77.2 137.97,81.38 136.83,82.52 133.98,82.52 133.66,82.85 133.66,86.58 134,86.93 140.48,86.93 141.84,88.28 147.99,88.28 148.52,87.75 152.89,87.75 155.12,89.99 160.47,89.99 160.73,90.25 161.43,90.25 161.62,90.06 161.62,89.87 v2(161.83,89.66)
  BOTTOM w0.081: v2(146.01,62.35) 145.6,62.75 UC1.AT10
USBP3-: length 78.7
  TOP w0.102: v2(161.24,89.66) 161.42,89.84 161.42,102.5 161.24,102.68 UI5.7
  IN1 w0.091: v2(145.95,63.07) 145.98,63.07 146.04,63.02 146.04,62.89 145.78,62.63 145.6,62.63 145.47,62.77 145.47,64.19 145.67,64.4 145.67,64.56 145.47,64.76 145.47,64.93 145.66,65.12 145.66,65.28 145.47,65.47 145.47,65.76 145.78,66.08 145.78,73.51 143.94,75.35 143.94,76.35 143.49,76.81 138.61,76.81 138.15,77.27 138.15,81.45 136.9,82.7 134.05,82.7 133.83,82.92 133.83,86.51 134.07,86.75 140.55,86.75 141.91,88.11 147.92,88.11 148.45,87.58 152.96,87.58 155.19,89.82 160.54,89.82 160.8,90.07 161.36,90.07 161.45,89.98 161.45,89.87 v2(161.24,89.66)
  BOTTOM w0.076: v2(145.95,63.07) 145.68,63.07 145.55,63.19 145.55,63.37 UC1.AR10
USBP3_D+: length 11.4
  IN4 w0.091: JUSB2.3 194.01,98.14 194.1,98.05 194.1,97.69 193.92,97.5 193.92,96.83 v2(193.71,96.62)
  BOTTOM w0.102: v2(193.71,96.62) 193.89,96.44 193.89,94.3 192.91,93.31 192.91,92.83 192.8,92.73 DI3.3 192.92,91.86 193.36,91.86 194.08,91.13 194.08,90.75 193.95,90.62 LI4.2
USBP3_D-: length 11.5
  IN4 w0.091: JUSB2.2 194.37,98.14 194.28,98.05 194.28,97.62 194.09,97.43 194.09,96.82 v2(194.29,96.62)
  BOTTOM w0.102: v2(194.29,96.62) 194.11,96.44 194.11,94.21 193.12,93.22 193.12,92.83 193.22,92.73 DI3.2 193.98,91.99 193.85,91.86 193.85,91.67 194.3,91.22 194.3,90.66 194.17,90.54 194.17,90.02 193.92,89.77 LI4.3
USBP4+: length 102.5
  IN4 w0.091: v2(70.04,71.82) 70.26,71.6 71.62,71.6 72.28,72.27 72.28,77.83 73.3,78.84 73.3,81.28 76.24,84.22 77.77,84.22 78.47,84.92 79.35,84.92 80.41,85.97 83.09,85.97 84.88,87.77 99.16,87.77 99.42,88.03 104.73,88.03 107.84,84.92 108.72,84.92 113.13,80.52 113.13,79.36 113.34,79.14 114.87,79.14 115.63,78.38 116.2,78.38 116.58,78 116.91,78 117.72,77.19 135.11,77.19 137.04,75.26 137.04,70.7 138.35,69.38 138.35,68.7 138.94,68.11 140.56,68.11 141.61,67.06 141.61,66.53 142.04,66.1 142.04,65.44 142.37,65.11 142.47,65.11 v2(142.71,65.35)
  BOTTOM w0.081: v2(142.71,65.35) 142.78,65.35 UC1.AL15
  BOTTOM w0.102: v2(70.04,71.82) 70.18,71.68 70.45,71.68 70.68,71.45 70.68,70.85 70.14,70.32 70.14,69.71 70.21,69.64 70.31,69.64 70.64,69.97 LV27.3
USBP4-: length 102.5
  IN4 w0.091: v2(70.04,71.24) 70.23,71.43 71.69,71.43 72.46,72.2 72.46,77.75 73.47,78.77 73.47,81.21 76.31,84.05 77.84,84.05 78.54,84.75 79.43,84.75 80.48,85.8 83.16,85.8 84.95,87.59 99.23,87.59 99.49,87.86 104.66,87.86 107.77,84.75 108.65,84.75 112.95,80.44 112.95,79.29 113.27,78.97 114.8,78.97 115.56,78.21 116.13,78.21 116.51,77.83 116.84,77.83 117.64,77.02 135.03,77.02 136.86,75.19 136.86,70.63 138.18,69.31 138.18,68.62 138.86,67.94 140.48,67.94 141.43,66.99 141.43,66.46 141.86,66.03 141.86,65.37 142.3,64.94 142.48,64.94 v2(142.71,64.7)
  BOTTOM w0.081: v2(142.71,64.7) 143.03,65.03 UC1.AM15
  BOTTOM w0.102: LV27.2 70.62,69.12 70.32,69.42 70.13,69.42 69.93,69.62 69.93,70.41 70.46,70.94 70.46,71.36 70.36,71.46 70.27,71.46 v2(70.04,71.24)
USBP4_D+: length 11.3
  BOTTOM w0.102: JEDP1.3 70.24,76.33 70.24,75.61 71.26,74.59 71.26,73.71 72.72,72.25 72.72,72.04 72.51,71.83 DV4.3 72.2,71.39 72.83,71.39 72.93,71.28 72.93,70.88 73.52,70.29 73.52,70.27 73.52,70.26 73.52,69.86 73.44,69.79 73,69.79 72.82,69.97 LV27.4
USBP4_D-: length 11.3
  BOTTOM w0.102: JEDP1.2 70.69,76.56 70.62,76.41 70.45,76.25 70.45,75.7 71.48,74.68 71.48,73.8 72.94,72.34 72.94,72.02 73.13,71.83 DV4.2 73.69,71.82 73.15,71.28 73.15,70.97 73.75,70.37 v4(73.75,69.99) 73.75,69.78 73.53,69.57 72.89,69.57 72.59,69.28 LV27.1
USBP5+: length 108.1
  IN4 w0.091: v2(70.26,72.45) 70.49,72.68 70.8,72.68 71.81,73.69 71.81,78.02 72.83,79.04 72.83,81.47 76.04,84.69 76.44,84.69 76.77,85.02 77.9,85.02 78.23,85.35 78.23,86.28 78.47,86.52 82.97,86.52 84.69,88.24 98.96,88.24 99.22,88.5 102.35,88.5 103.04,89.19 104.24,89.19 107.42,86.01 108.3,86.01 113.61,80.7 113.61,80.41 113.94,80.08 115.28,80.08 116.46,78.9 116.84,78.9 117.23,78.52 117.23,78.32 117.85,77.7 135.51,77.7 137.62,75.58 137.62,74.82 138.5,73.94 138.5,70.77 138.98,70.29 140.46,70.29 140.89,69.85 140.89,68.63 141.46,68.06 142.05,68.06 142.27,67.85 142.27,67.32 142.12,67.17 142.12,66.47 143.19,65.4 143.19,64.86 143.5,64.55 143.88,64.55 v2(144.11,64.32)
  BOTTOM w0.081: UC1.AN13 143.72,64.7 v2(144.11,64.32)
  BOTTOM w0.102: v2(70.26,72.45) 70.12,72.59 69.28,72.59 68.55,71.87 68.55,70.13 69.2,69.48 v4(69.2,69.15) 69.2,68.83 68.97,68.6 68.97,68.25 68.71,67.99 68.59,67.99 68.27,67.67 LZ1.1
USBP5-: length 108.1
  IN4 w0.091: v2(144.11,64.96) 143.87,64.72 143.58,64.72 143.36,64.93 143.36,65.47 142.29,66.54 142.29,67.1 142.44,67.25 142.44,67.92 142.12,68.24 141.53,68.24 141.06,68.7 141.06,69.92 140.53,70.46 139.05,70.46 138.67,70.84 138.67,74.02 137.8,74.89 137.8,75.65 135.58,77.87 117.92,77.87 117.4,78.4 117.4,78.59 116.91,79.08 116.53,79.08 115.35,80.25 114.01,80.25 113.78,80.48 113.78,80.78 108.37,86.19 107.49,86.19 104.31,89.36 102.97,89.36 102.28,88.67 99.15,88.67 98.89,88.41 84.61,88.41 82.89,86.69 78.4,86.69 78.06,86.35 78.06,85.42 77.83,85.19 76.7,85.19 76.37,84.86 75.97,84.86 72.65,81.55 72.65,79.11 71.64,78.09 71.64,73.77 70.73,72.85 70.44,72.85 v2(70.26,73.04)
  BOTTOM w0.081: UC1.AM13 143.71,65.35 v2(144.11,64.96)
  BOTTOM w0.102: LZ1.4 68.18,68.52 68.5,68.2 68.62,68.2 68.76,68.34 68.76,68.69 68.97,68.91 68.97,69.4 68.34,70.04 68.34,71.96 69.19,72.81 70.03,72.81 v2(70.26,73.04)
USBP5_D+: length 8.7
  BOTTOM w0.102: LZ1.2 66.03,67.67 65.82,67.88 65.6,67.88 65.41,68.07 65.41,69.52 65.81,69.93 v4(65.81,70.18) 65.81,74.27 65.58,74.5 JEDP1.13
USBP5_D-: length 8.7
  BOTTOM w0.102: LZ1.3 66.27,68.35 66.01,68.1 65.69,68.1 65.62,68.16 65.62,69.43 66.04,69.85 66.04,70.45 66.03,70.46 66.03,74.36 65.9,74.49 65.9,74.56 66.01,74.79 JEDP1.12
USBP6+: length 133.8
  TOP w0.102: v2(241.05,14.92) 240.84,14.71 240.84,13.75 240.85,13.73 v4(240.85,13.47) 240.85,13.14 240.84,13.13 240.84,12.29 240.98,12.14 JUSH1.3
  IN2 w0.114: v2(144.61,64.71) 144.78,64.54 145.19,64.54 145.47,64.25 145.47,61.5 146.69,60.28 146.69,56.69 147.96,55.41 150.82,55.41 151.33,54.9 151.33,51.03 153.34,49.02 153.34,45.18 165.69,32.84 192.84,32.84 195.29,30.39 197.99,30.39 199.32,29.06 208.96,29.06 213.86,24.16 239.25,24.16 239.77,23.64 239.77,18.02 240.85,16.94 240.85,15.12 v2(241.05,14.92)
  BOTTOM w0.081: UC1.AN11 144.94,64.38 v2(144.61,64.71)
USBP6-: length 133.6
  TOP w0.102: JUSH1.2 240.48,12.14 240.62,12.29 240.62,14.76 v2(240.46,14.92)
  IN2 w0.114: v2(240.46,14.92) 240.65,15.11 240.65,16.86 239.57,17.94 239.57,23.56 239.17,23.96 213.78,23.96 208.88,28.87 199.24,28.87 197.91,30.2 195.21,30.2 192.76,32.64 165.61,32.64 153.15,45.1 153.15,48.94 151.13,50.95 151.13,54.82 150.74,55.22 147.88,55.22 146.49,56.6 146.49,60.2 145.28,61.42 145.28,64.17 145.11,64.34 144.68,64.34 144.61,64.27 v2(144.61,64.01)
  BOTTOM w0.081: v2(144.61,64.01) 144.89,63.73 UC1.AP11
USBP7+: length 138
  IN4 w0.091: v2(144.1,63.74) 144.32,63.52 144.65,63.52 145.09,63.08 145.09,61.75 145.64,61.2 145.64,59.75 147.5,57.89 148.63,57.89 151.57,54.95 153.38,54.95 159.28,49.05 164.7,49.05 166.97,46.78 166.97,46.04 169.66,43.34 171.24,43.34 184.14,30.44 184.14,27.58 185.77,25.95 203.57,25.95 204.97,27.34 211.71,27.34 212.2,27.83 212.2,29.43 208.78,32.86 208.78,36.54 210.33,38.09 217.24,38.09 220.4,41.25 220.97,41.25 v2(221,41.28)
  BOTTOM w0.081: UC1.AP13 143.98,63.74 v2(144.1,63.74)
  BOTTOM w0.102: JNGFF2.7 217.4,60.65 217.54,60.51 219.54,60.51 221.48,58.57 221.48,55.01 219.86,53.4 219.86,51.62 220.08,51.41 220.08,48.93 221.36,47.65 221.36,44.31 220.68,43.62 220.68,41.34 220.74,41.28 v2(221,41.28)
USBP7-: length 138
  IN4 w0.091: v2(220.74,40.73) 220.74,40.96 220.62,41.08 220.47,41.08 217.31,37.92 210.4,37.92 208.95,36.47 208.95,32.93 212.38,29.5 212.38,27.76 211.79,27.17 205.04,27.17 203.65,25.78 185.7,25.78 183.97,27.51 183.97,30.37 171.17,43.17 169.59,43.17 166.8,45.96 166.8,46.71 164.63,48.88 159.21,48.88 153.31,54.77 151.5,54.77 148.56,57.71 147.43,57.71 145.47,59.68 145.47,61.12 144.91,61.68 144.91,63.01 144.58,63.35 144.33,63.35 v2(144.1,63.12)
  BOTTOM w0.081: v2(144.1,63.12) 143.82,63.4 UC1.AR13
  BOTTOM w0.102: JNGFF2.9 217.41,60.15 217.55,60.29 219.45,60.29 221.26,58.48 221.26,55.1 219.65,53.49 219.65,51.54 219.86,51.32 219.86,48.84 221.15,47.56 221.15,44.4 220.46,43.71 220.46,41.25 220.74,40.97 v2(220.74,40.73)
USBRBIAS: length 5.4
  TOP w0.102: v2(145.19,66.96) 144.8,66.57 v1(144.8,65.98) 144.62,65.8 142.21,65.8 142.16,65.84 RC152.1
  BOTTOM w0.254: UC1.AJ11 144.87,66.65 v2(145.19,66.96) 145.5,66.65 UC1.AJ10
USH_DET#: length 179.1
  TOP w0.102: RPC15.2 160.52,71.34 160.26,71.61 160.26,71.97 160.58,72.29 v2(160.58,72.81) ; JUSH1.20 249.48,12.05 v2(250.74,13.31) 250.79,13.31 251.19,13.72 251.19,15.62 v1(250.5,16.32)
  IN2 w0.081: 153.82,72.16 153.36,72.63 151.96,72.63 150.86,73.72 150.86,79.37 150.54,79.69 v2(150.26,79.69)
  IN2 w0.122: 153.82,72.16 156.22,72.16 157.52,73.47 159.92,73.47 v2(160.58,72.81)
  IN4 w0.084: v2(160.58,72.81) 160.58,71.66 161.02,71.21 163.77,71.21 164.48,70.51 164.48,61.81 162.82,60.15 162.82,56.96 165.38,54.4 168.76,54.4 170.64,52.53 170.64,49.36 187.25,32.75 196.51,32.75 196.73,32.97 197.68,32.97 197.91,32.75 199.24,32.75 200.84,34.35 205.1,34.35 206.07,35.32 206.07,36.62 209.5,40.05 214.58,40.05 215.27,40.74 217.34,40.74 221.82,45.22 224.27,45.22 225.25,44.23 244.14,44.23 247.62,40.75 247.62,28.49 249.61,26.5 249.61,14.44 v2(250.74,13.31)
  BOTTOM w0.081: UC1.E3 149.94,80.01 v2(150.26,79.69)
USH_PWR_STATE#: length 55
  TOP w0.102: UE1.A34 225.95,43.43 225.95,42.56 225.71,42.32 v2(225.71,42.05) ; v1(249.19,13.5) 249.05,13.36 RZ10.2 248.21,13.12 v2(247.68,12.59) 247.48,12.39 JUSH1.16
  IN4 w0.084: v2(225.71,42.05) 226.07,41.69 237.78,41.69 238.43,42.34 242.63,42.34 246.99,37.98 246.99,28.23 248.93,26.29 248.93,21.94 247.55,20.56 247.55,12.71 v2(247.68,12.59)
USH_SMBCLK: length 66.7
  TOP w0.102: v2(248.57,59.72) 248.19,60.1 UE2.A50 ; v2(237.44,10.35) 237.67,10.12 241.89,10.12 242.16,10.39 242.16,10.72 241.98,10.9 JUSH1.5 241.98,12.09 242.16,12.28 242.16,12.47 242.37,12.68 242.37,13.02 RZ8.2
  IN1 w0.084: v2(248.57,59.72) 247.84,59.72 247.4,59.28 247.4,57.87 249.63,55.64 249.63,52.66 246.68,49.72 246.68,28.38 237.02,18.71 237.02,10.3 237.16,10.15 237.24,10.15 v2(237.44,10.35)
USH_SMBDAT: length 66.7
  TOP w0.102: RZ9.2 242.6,13.04 242.6,12.58 242.39,12.38 242.39,12.28 242.48,12.19 JUSH1.6 242.48,10.8 242.39,10.72 242.39,10.3 241.99,9.89 237.57,9.89 v2(237.44,9.76) ; v2(245.87,59.49) 246.23,59.85 UE2.B53
  IN1 w0.084: v2(245.87,59.49) 246.92,59.49 247.19,59.22 247.19,57.78 249.42,55.56 249.42,52.75 246.47,49.81 246.47,28.47 236.8,18.8 236.8,10.21 237.07,9.94 237.26,9.94 v2(237.44,9.76)
VCI_IN2#: length 14.7
  TOP w0.102: UE2.B63 246.32,64.85 246.25,64.78 245.62,64.78 v2(245.21,65.2) ; RPE5.4 247.74,72.43 247.83,72.34 248.25,72.34 248.34,72.43 v2(248.34,72.58) 248.34,73.51 v1(248.89,74.07)
  IN1 w0.084: v2(245.21,65.2) 244.58,65.2 244.27,65.51 244.27,69.51 246.94,72.17 248.08,72.17 248.34,72.43 v2(248.34,72.58)
VCT_LAN_R1: length 4.2
  TOP w0.102: RL3.2 232.3,90.18 232.56,89.92 232.56,89.15 233.76,87.96 UL1.6
VFB: length 2.2
  TOP w0.203: PR531.2 92.89,75.61 v1(92.74,75.47) 92.57,75.29 PU500.24
VGA_ID: length 12.1
  TOP w0.102: v1(241.27,47.32) 241.08,47.12 RE85.1 ; RE85.1 240.28,47.54 240.71,47.97 v2(240.71,48.23) ; RE85.1 RE87.1 ; v2(233.16,48.81) 233.16,48.8 233.56,48.4 UE1.B59
  IN4 w0.084: v2(240.71,48.23) 240.42,47.93 239.66,47.93 239.26,48.33 234.35,48.33 233.87,48.81 v2(233.16,48.81)
VIDALERT_N: length 34.4
  TOP w0.102: PR528.2 86.16,78.46 86.04,78.34 86.04,78.2 86.09,78.14 87.04,78.14 87.1,78.08 87.1,77.83 87.04,77.76 86.73,77.76 86.66,77.69 86.66,77.52 86.73,77.44 87.24,77.44 87.3,77.38 87.3,77.22 87.24,77.16 87.01,77.16 86.93,77.07 86.93,76.78 87.4,76.3 v2(87.68,76.3) 87.68,76.24 87.99,75.93 PU500.32
  IN1 w0.084: v2(107.32,75.6) 106.58,75.6 106.07,76.11 91.56,76.11 91.48,76.2 91.48,77.29 91.35,77.42 91.11,77.42 90.99,77.29 90.99,76.08 90.86,75.95 90.62,75.95 90.5,76.08 90.5,76.68 90.37,76.81 89.97,76.81 89.84,76.68 89.84,76.08 89.71,75.95 88.9,75.95 88.77,76.08 88.77,77.06 88.57,77.27 88.57,77.44 88.44,77.56 87.5,77.56 87.24,77.3 87.24,76.56 87.5,76.3 v2(87.68,76.3)
  BOTTOM w0.102: RC207.2 107.78,76.25 107.76,76.23 RC204.2 v2(107.32,75.6)
VIDSCLK: length 32.8
  TOP w0.102: PU500.31 88.55,76.44 v2(88.25,76.74) 88.25,77.07 88,77.32 88,77.66 88.19,77.85 88.19,78.02 88.13,78.08 87.74,78.08 87.68,78.14 87.68,78.46 87.74,78.52 v1(88.06,78.52) 88.38,78.52 88.44,78.59 88.44,78.97 88.38,79.03 87.55,79.03 87.29,78.76 PR527.2
  IN1 w0.076: 109.88,76.27 110.45,76.27 110.8,75.92 111.98,75.92 v2(112.13,75.77)
  IN1 w0.084: 109.88,76.27 108.51,76.27 108.32,76.08 108.32,75.22 108.15,75.06 106.58,75.06 106.07,75.57 88.67,75.57 88.38,75.86 88.38,76.62 v2(88.25,76.74)
  BOTTOM w0.102: v2(112.13,75.77) 112.3,75.6 UC1.N63
VIDSOUT: length 42.7
  TOP w0.102: PR529.2 83.93,77.84 83.93,77.44 84.12,77.26 86.08,77.26 86.33,77 86.33,75.81 86.41,75.73 v2(86.98,75.73) 87.08,75.73 PU500.1
  IN1 w0.084: v2(111.94,76.52) 111.78,76.68 92.63,76.68 91.36,77.95 87.11,77.95 86.35,77.19 86.35,75.92 86.54,75.73 v2(86.98,75.73)
  BOTTOM w0.102: RC208.2 109.33,76.91 109.33,76.68 109.08,76.43 108.93,76.43 108.83,76.33 108.83,76.07 108.93,75.97 109.28,75.97 109.48,76.18 109.72,76.18 109.97,76.43 109.97,76.87 109.59,77.25 109.59,77.38 109.74,77.53 110.33,77.53 110.6,77.25 110.6,77.06 110.41,76.87 110.41,76.56 110.54,76.43 110.72,76.43 111,76.7 111.54,76.7 111.72,76.52 v2(111.94,76.52) 112.23,76.52 112.41,76.35 UC1.L63
VMM2320_AUX: length 19.2
  TOP w0.102: UV600.28 213.6,75.49 212.76,74.65 212.44,74.65 RV608.2 211.79,74.26 210.58,74.26 210.29,74.55 210.29,77.22 209.5,78 208.47,78 205.59,80.88 v4(205.59,84.4) 205.59,84.68 204.81,85.47 204.34,85.47 CV110.1
VMM2320_AUX#: length 19.2
  TOP w0.102: UV600.29 213.5,75.09 212.36,73.95 RV604.2 212.22,74.04 210.49,74.04 210.07,74.46 210.07,77.13 209.41,77.79 208.38,77.79 205.38,80.79 205.38,84.07 205.37,84.08 205.37,84.61 204.72,85.25 204.59,85.25 CV111.1
VMM2320_AUX#_C: length 5.8
  TOP w0.102: UV8.H2 199.56,81.89 200.08,81.89 200.33,82.14 200.33,82.4 201.24,83.31 201.24,83.69 202.49,84.94 203.07,84.94 CV111.2
VMM2320_AUX_C: length 5.8
  TOP w0.102: UV8.H1 199.61,82.19 199.53,82.27 199.53,82.4 199.69,82.56 200.19,82.56 201.02,83.4 201.02,83.78 v4(201.69,84.44) 202.4,85.15 202.68,85.15 CV110.2
VMM2320_HPD: length 29.3
  TOP w0.102: UV8.J1 199.91,83.05 200.46,83.6 200.46,84.08 202.78,86.4 205.31,86.4 v1(205.41,86.3) 206.24,85.47 206.24,83.9 206.96,83.17 v2(206.96,81.88) ; UV600.38 v2(217.65,73.13)
  IN2 w0.122: v2(217.65,73.13) 217.65,73.5 213.53,77.62 209.5,77.62 206.49,80.64 206.49,81.41 v2(206.96,81.88)
VMM2320_N0: length 24.1
  TOP w0.102: v2(204.77,83.14) 204.56,83.35 204.46,83.35 CV103.1 ; v2(217.81,72.15) 217.99,72.33 217.99,72.79 218.14,72.94 218.14,73.25 218.05,73.35 UV600.39
  IN1 w0.091: v2(204.77,83.14) 205.18,83.55 205.51,83.55 205.75,83.31 205.75,82.3 206.15,81.9 206.15,80.88 208.36,78.66 211.84,78.66 212.53,77.98 214.64,77.98 216.32,76.29 216.89,76.29 218.05,75.12 218.05,72.39 v2(217.81,72.15)
VMM2320_N0_C: length 5.2
  TOP w0.102: CV103.2 202.97,83.26 202.75,83.26 v4(202.25,82.75) 202.02,82.52 201.25,82.52 200.77,82.05 200.77,81.76 200.43,81.42 200.19,81.42 200.03,81.26 199.71,81.26 199.43,81.54 UV8.G2
VMM2320_N1: length 20.5
  TOP w0.102: v2(204.77,81.33) 204.58,81.51 204.4,81.51 CV105.1 ; v2(216.79,72.56) 216.97,72.75 216.97,73.19 216.85,73.31 UV600.36
  IN1 w0.091: v2(216.79,72.56) 216.98,72.75 216.98,74.65 214.33,77.3 211.98,77.3 211.33,77.95 208.16,77.95 205.49,80.62 205.49,81.63 205.38,81.74 205.18,81.74 v2(204.77,81.33)
VMM2320_N1_C: length 4.5
  TOP w0.102: CV105.2 202.97,81.48 v4(202.25,81.48) 201.83,81.48 200.95,80.61 199.71,80.61 199.43,80.89 UV8.F2
VMM2320_N2: length 20.6
  TOP w0.102: CV107.1 204.13,79.81 204.2,79.89 205.06,79.89 206.32,78.63 206.32,78.06 v2(206.05,77.79) ; UV600.34 216.05,73.38 216.1,73.33 216.1,72.3 216.22,72.19 216.22,71.98 216.21,71.97 216.21,71.93 v2(216.09,71.82)
  IN1 w0.091: v2(206.05,77.79) 206.03,77.79 206.39,77.43 206.41,77.43 206.6,77.24 209.8,77.24 210.06,76.98 210.06,75.67 210.54,75.2 214.05,75.2 216.11,73.13 216.11,72.29 216.27,72.13 216.27,72 216.24,71.97 216.24,71.96 v2(216.09,71.82)
VMM2320_N2_C: length 4.3
  TOP w0.102: CV107.2 202.97,79.7 202.53,79.7 202.27,79.96 v4(201.93,79.96) 199.54,79.96 UV8.E2
VMM2320_N3: length 17.7
  TOP w0.102: UV600.31 214.85,73.56 214.94,73.47 214.94,73.08 214.46,72.6 214.46,71.83 v2(214.27,71.65) ; v2(204.86,77.38) 205.19,77.71 205.19,77.93 205.01,78.11 204.26,78.11 204.13,77.98 CV109.1
  IN1 w0.091: v2(204.86,77.38) 205.05,77.2 205.05,76.93 206.71,75.26 208.61,75.26 209.93,73.94 213.25,73.94 214.43,72.76 214.43,71.8 v2(214.27,71.65)
VMM2320_N3_C: length 4.7
  TOP w0.102: CV109.2 202.97,77.92 202.44,77.92 201.1,79.27 199.82,79.27 199.5,79.59 UV8.D2
VMM2320_P0: length 24.2
  TOP w0.102: v2(218.39,72.15) 218.21,72.33 218.21,72.7 218.36,72.85 218.36,73.25 218.45,73.35 UV600.40 ; CV102.1 204.47,83.57 204.61,83.57 v2(204.77,83.72)
  IN1 w0.091: v2(204.77,83.72) 205.58,83.72 205.93,83.38 205.93,82.37 206.32,81.97 206.32,80.95 208.43,78.84 211.91,78.84 212.6,78.15 214.71,78.15 216.4,76.46 216.96,76.46 218.22,75.2 218.22,72.31 v2(218.39,72.15)
VMM2320_P0_C: length 5.1
  TOP w0.102: CV102.2 203.47,83.65 203.47,83.53 203.41,83.47 202.66,83.47 202.37,83.18 202.35,83.18 201.9,82.74 201.16,82.74 200.56,82.14 200.56,81.85 200.34,81.64 200.2,81.64 200.14,81.7 200.01,81.7 199.91,81.6 UV8.G1
VMM2320_P1: length 20.6
  TOP w0.102: v2(204.77,81.91) 204.62,81.76 204.49,81.76 CV104.1 ; v2(217.37,72.56) 217.19,72.75 217.19,73.32 217.25,73.38 UV600.37
  IN1 w0.091: v2(217.37,72.56) 217.15,72.79 217.15,74.72 214.4,77.48 212.05,77.48 211.4,78.12 208.23,78.12 205.66,80.69 205.66,81.7 205.45,81.91 v2(204.77,81.91)
VMM2320_P1_C: length 4.5
  TOP w0.102: UV8.F1 200.02,81 200.09,81 200.27,80.82 200.86,80.82 201.74,81.7 201.9,81.7 201.91,81.71 202.51,81.71 202.53,81.7 203.37,81.7 203.47,81.79 203.47,81.87 CV104.2
VMM2320_P2: length 20.6
  TOP w0.102: v2(216.68,71.82) 216.43,72.06 216.43,72.28 216.32,72.39 216.32,73.34 216.45,73.47 UV600.35 ; CV106.1 204.37,80.11 205.15,80.11 206.55,78.7 206.55,77.87 v2(206.64,77.79)
  IN1 w0.091: v2(216.68,71.82) 216.45,72.05 216.45,72.2 216.29,72.36 216.29,73.21 214.12,75.37 210.61,75.37 210.24,75.75 210.24,77.05 209.87,77.41 206.68,77.41 206.57,77.52 206.57,77.72 v2(206.64,77.79)
VMM2320_P2_C: length 4.3
  TOP w0.102: CV106.2 203.34,80.22 203.34,79.98 203.27,79.92 202.62,79.92 202.36,80.17 202.21,80.17 202.2,80.19 201.76,80.19 201.75,80.17 200.33,80.17 200.24,80.26 200.24,80.34 200.17,80.42 200.01,80.42 199.91,80.32 UV8.E1
VMM2320_P3: length 17.7
  TOP w0.102: UV600.32 215.25,73.47 215.16,73.38 215.16,72.97 v4(214.94,72.75) 214.67,72.49 214.67,71.83 v2(214.86,71.65) ; CV108.1 204.37,78.33 205.1,78.33 205.41,78.02 205.41,77.42 v2(205.45,77.38)
  IN1 w0.091: v2(214.86,71.65) 214.6,71.91 214.6,72.83 213.32,74.11 210,74.11 208.68,75.44 206.78,75.44 205.22,77 205.22,77.15 v2(205.45,77.38)
VMM2320_P3_C: length 4.8
  TOP w0.102: CV108.2 203.4,78.38 203.4,78.21 203.34,78.14 202.55,78.14 v4(202.3,78.4) 202.09,78.61 202.06,78.61 201.19,79.49 200.27,79.49 200.2,79.55 200.2,79.67 200.14,79.73 200,79.73 199.91,79.64 UV8.D1
VMM2320_VGA_DET: length 3.3
  TOP w0.102: UV8.M3 198.67,84.84 v1(198.67,86.82) 198.67,87.59 RV88.2
VMM2320_VGA_IREF: length 3.6
  TOP w0.102: RV89.1 196.2,87.18 v1(196.59,86.79) 197.31,86.07 UV8.M5
VMM2320_VGA_NC: length 4
  TOP w0.102: T108.1 195.76,87.16 196.99,85.93 196.99,84.46 UV8.L5
VMM_DPB_CTRLCLK: length 14.8
  TOP w0.102: RPV1.1 188.78,84.82 v2(189.41,85.45) 189.74,85.45 191.35,83.83 191.91,83.83 192.11,83.63 UV8.K13
  IN4 w0.091: v2(189.17,87.43) 188.65,86.91 188.07,86.91 187.88,86.72 187.88,86.21 188.01,86.08 188.77,86.08 v2(189.41,85.45)
  BOTTOM w0.102: UV11.12 186.88,89.72 v2(189.17,87.43)
VMM_DPB_CTRLDAT: length 14.2
  TOP w0.102: RPV1.2 188.14,85.32 188.3,85.16 188.7,85.16 188.81,85.26 188.81,85.41 v2(188.77,85.45) 189.18,85.85 189.64,85.85 191.35,84.14 UV8.L14
  IN4 w0.091: v2(186.23,87.54) 186.74,87.03 187.39,87.03 187.71,86.72 187.71,86.14 187.94,85.91 188.65,85.91 188.77,85.78 v2(188.77,85.45)
  BOTTOM w0.102: UV11.9 184.93,89.04 184.81,88.92 184.81,88.58 185.22,88.18 185.84,88.18 186.23,87.79 v2(186.23,87.54)
VMM_DPC_CTRLCLK: length 30.3
  TOP w0.102: v2(189.35,75.73) 189.41,75.79 189.41,76.23 189.59,76.41 190.86,76.41 191.43,76.98 191.85,76.98 192.39,77.52 192.39,77.92 UV8.B12 ; v2(192.18,73.41) 192.37,73.6 192.37,74.12 192.79,74.54 196.38,74.54 196.58,74.33 196.58,74.21 196.71,74.07 RPV2.3
  BOTTOM w0.102: UV12.12 181.17,80.82 179.87,79.53 179.87,78.09 180.8,77.16 188.43,77.16 189.35,76.24 v2(189.35,75.73) 189.54,75.55 189.54,75.3 190.02,74.82 191.57,74.82 192.37,74.02 192.37,73.6 v2(192.18,73.41)
VMM_DPC_CTRLDAT: length 29.5
  TOP w0.102: v2(192.77,73.41) 192.58,73.6 192.58,74.03 192.88,74.32 196.29,74.32 196.37,74.24 196.37,74.18 196.21,74.03 RPV2.4 ; v2(189.94,75.73) 189.62,76.04 189.62,76.14 189.68,76.19 190.95,76.19 191.52,76.76 191.94,76.76 192.49,77.32 192.65,77.32 192.74,77.23 192.85,77.23 192.94,77.32 192.94,77.57 192.88,77.64 UV8.A12
  BOTTOM w0.102: v2(192.77,73.41) 192.58,73.6 192.58,74.1 191.66,75.03 190.11,75.03 189.75,75.39 189.75,75.55 v2(189.94,75.73) 189.57,76.1 189.57,76.33 188.52,77.38 180.89,77.38 180.09,78.18 180.09,79.1 180.19,79.2 180.32,79.2 180.58,78.93 180.58,78.52 180.71,78.4 180.9,78.4 181.03,78.52 181.03,78.81 181.09,78.87 UV12.9
VMM_GPIO4: length 5.7
  TOP w0.102: RV518.2 188.06,78.55 188.06,77.96 188.56,77.47 189.56,77.47 v1(189.69,77.6) 189.75,77.66 190.08,77.66 190.55,78.13 191.3,78.13 191.46,78.29 UV8.B14
VMM_GPIO5: length 6.1
  TOP w0.102: UV8.B13 192.08,78.29 191.73,77.94 190.63,77.94 190.16,77.47 190.04,77.47 189.81,77.24 v1(188.28,77.24) 187.83,77.69 187.83,78.23 187.6,78.46 RV519.2
VMM_GPIO6: length 4.4
  TOP w0.102: RV83.1 202.82,76.79 202.54,77.08 v1(202.25,77.08) 202.25,77.25 200.69,78.81 200.04,78.81 UV8.C1
VMM_GPIO7: length 8.8
  TOP w0.102: v1(186.8,83.67) 187.12,83.98 187.12,85.64 187.31,85.82 RPV1.3 188.38,85.82 188.71,86.14 189.71,86.14 191.42,84.43 192.4,84.43 UV8.M12
VMM_GPIO8: length 10
  TOP w0.102: RV14.1 184.82,86.84 186.17,86.84 186.3,86.72 188.46,86.72 188.74,86.99 189.38,86.99 189.41,86.96 v1(190.53,86.96) 191.41,86.96 192.11,86.27 UV8.M13
VMM_GPIO9: length 6.3
  TOP w0.102: v1(197.54,89.83) 197.35,89.64 RV73.1 197.82,88.41 197.82,87.64 198.29,87.17 198.29,84.46 UV8.L3
VMM_SPI_CLK: length 9.7
  TOP w0.102: UV8.B3 198.61,78.26 198.94,77.94 198.94,77.5 199.25,77.19 199.25,75.79 200.23,74.81 v1(200.91,74.81) 201.43,74.81 v2(201.84,74.4)
  BOTTOM w0.102: UV9.6 202.79,75.35 v2(201.84,74.4)
VMM_SPI_CS#: length 9.1
  TOP w0.102: UV8.A4 197.96,77.48 v2(198.3,77.14)
  BOTTOM w0.102: RV86.2 202.03,72.19 201.41,72.81 UV9.1 199.14,72.81 v1(198.38,73.57) 198.38,77.06 v2(198.3,77.14)
VMM_SPI_DIN: length 6.3
  TOP w0.102: UV8.B4 v2(198.29,77.96)
  BOTTOM w0.102: v2(198.29,77.96) 198.39,78.07 v1(198.81,78.07) 198.92,77.95 198.92,77.14 198.61,76.82 198.61,74.6 199.13,74.08 UV9.2
VMM_SPI_DO: length 10.1
  TOP w0.102: UV8.A3 198.61,77.56 198.93,77.24 198.93,75.26 v1(199.45,74.74) 199.8,74.4 v2(201.26,74.4)
  BOTTOM w0.102: UV9.5 203.48,76.62 v2(201.26,74.4)
VMM_SPI_HOLD: length 2.7
  BOTTOM w0.102: UV9.7 v1(206.79,74.08) 207.81,74.08 RV87.2
VMM_SPI_WP#: length 17.1
  TOP w0.076: 201.76,76.49 201.53,76.49 v2(200.65,77.37)
  TOP w0.102: RV517.2 205.22,74.78 204.48,75.51 203.3,75.51 202.32,76.49 201.76,76.49 ; UV8.B1 200.1,78.29 200.65,77.74 v2(200.65,77.37)
  BOTTOM w0.102: v2(200.65,77.37) 199.48,77.37 198.83,76.73 198.83,75.73 199.21,75.35 UV9.3 201.89,75.35 204.2,77.67 v1(204.2,78.19)
VR_HOT#: length 2.3
  TOP w0.102: PR534.2 88.63,77.58 88.63,77.05 v1(88.7,76.99) 88.7,76.96 88.95,76.71 88.95,75.93 PU500.30
VREF: length 31
  TOP w0.203: PU500.27 90.15,77.06 v2(90.41,77.32)
  TOP w0.254: PR504.2 PR503.2 PR502.2 88.06,68.54 87.82,68.3 v2(87.82,68.22) 88.04,68.22 v1(88.52,67.74) 88.52,66.99 88.87,66.64 90.34,66.64 92.06,68.36 PR500.2 ; PR521.2 92.56,78.54 92,77.99 91.08,77.99 v2(90.41,77.32)
  IN3 w0.254: v2(87.82,68.22) 87.82,68.54 86.41,69.95 86.41,74.02 88.19,75.79 90.03,75.79 90.41,76.17 v2(90.41,77.32)
  BOTTOM w0.254: PH500.1 84.96,69.63 86.08,68.52 87.53,68.52 v2(87.82,68.22) ; PC507.2 90.98,76.75 v2(90.41,77.32)
VSET_5085: length 3.2
  TOP w0.102: UE2.A17 v1(235.36,67.1) 234.75,67.1 CE38.1 RE77.1
VSYNC_DOCK: length 75.8
  TOP w0.102: v2(178.92,92.82) 178.92,92.51 179.5,91.93 v1(179.5,91.46) 179.5,90.1 180.16,89.44 188.85,89.44 191.03,87.25 191.39,87.25 193.52,85.13 194.12,85.13 194.42,84.83 194.42,84.43 UV8.L9
  BOTTOM w0.102: v2(178.92,92.82) 178.57,92.82 176.64,94.75 171.3,94.75 169.31,96.75 148.13,96.75 147.99,96.89 144.42,96.89 143.5,97.81 139.62,97.81 138.25,96.44 131.58,96.44 130.21,97.81 130.21,98.8 130.95,99.54 JDOCK1.67
WIGIG_32KHZ: length 22.5
  TOP w0.102: RZ56.2 RZ57.2 v1(219.55,35.62) 218.64,35.62 v2(218.62,35.6)
  BOTTOM w0.102: JNGFF1.42 217.26,17.6 218.05,18.39 218.05,26.45 217.86,26.64 217.86,34.84 v2(218.62,35.6)
WIGIG_32KHZ_R: length 3.8
  TOP w0.102: UZ11.4 220.43,37.67 RZ57.1 220.52,36.54 221.02,37.03 222.09,37.03 v1(222.62,36.5)
WIGIG_AUX: length 72.4
  TOP w0.102: CV149.1 216.89,26.34 216.54,26.69 216.54,26.82 216.28,27.08 214.41,27.08 211.6,29.88 210.89,29.88 208.79,31.98 208.79,32.41 208.38,32.82 208.38,36.21 211.18,39.01 214.16,39.01 217.03,41.88 v4(217.6,41.88) 218.17,41.88 219.04,42.75 v2(219.04,43.6) ; RV609.2 212.64,76.2 212.81,76.2 v2(213,76.38) 213.18,76.2 213.4,76.2 213.5,76.29 UV600.26
  BOTTOM w0.102: v2(219.04,43.6) 219.04,44.23 220.54,45.72 220.54,47.27 218.88,48.92 218.88,53.59 220.59,55.29 220.59,57.37 218.71,59.24 215.99,59.24 215.51,59.72 215.51,60.53 214.97,61.07 214.97,65.23 215.67,65.93 215.67,71.51 215.58,71.6 215.58,75.29 214.48,76.38 v2(213,76.38)
WIGIG_AUX#: length 72.3
  TOP w0.102: UV600.27 213.5,75.89 213.4,75.98 213.18,75.98 v2(213,75.8) 212.81,75.98 212.63,75.98 RV605.2 ; v2(218.46,43.6) 218.83,43.24 218.83,42.84 218.1,42.11 216.95,42.11 215.82,40.98 214.07,39.23 211.09,39.23 208.17,36.3 208.17,32.73 208.57,32.32 208.57,31.89 210.8,29.67 211.51,29.67 214.33,26.85 v4(214.68,26.85) 215.01,26.85 215.02,26.86 216.19,26.86 216.32,26.73 216.32,26.58 CV150.1
  BOTTOM w0.102: v2(213,75.8) 213.36,76.17 214.39,76.17 215.37,75.2 215.37,71.51 215.46,71.42 215.46,66.01 214.76,65.32 214.76,60.98 215.3,60.45 215.3,59.63 215.9,59.03 218.62,59.03 220.37,57.28 220.37,55.38 218.67,53.68 218.67,48.83 220.32,47.18 220.32,45.81 218.83,44.32 218.83,43.97 v2(218.46,43.6)
WIGIG_AUX#_C: length 3.8
  TOP w0.102: CV150.2 216.38,25.42 216.51,25.3 216.51,24.97 216.36,24.82 215.68,24.82 215.32,25.18 v2(215.06,25.18)
  BOTTOM w0.102: JNGFF1.12 215.55,25.1 215.44,24.99 215.25,24.99 v2(215.06,25.18)
WIGIG_AUX_C: length 3.8
  TOP w0.102: v2(215.06,24.6) 216.45,24.6 216.73,24.88 216.73,25.18 CV149.2
  BOTTOM w0.102: JNGFF1.14 215.52,24.6 215.34,24.78 215.24,24.78 v2(215.06,24.6)
WIGIG_HPD: length 74.6
  TOP w0.102: v2(205.22,36.77) 204.82,37.17 v1(204.82,37.38) ; v2(221.81,73.13) 221.65,73.28 UV600.48
  IN2 w0.122: v2(221.81,73.13) 221.63,72.95 221.63,71.15 224.63,68.15 224.63,62.45 222.09,59.91 222.09,57.31 220.82,56.04 220.82,53.49 219.98,52.66 219.98,51.71 220.31,51.38 220.31,48.99 221.23,48.07 221.23,45.14 219.33,43.24 219.33,40.96 218.96,40.59 215.06,40.59 214.25,39.78 210.72,39.78 207.47,36.53 205.84,36.53 205.6,36.77 v2(205.22,36.77)
  BOTTOM w0.102: JNGFF1.23 209.58,22.35 209.61,22.32 210.09,22.32 210.53,22.76 210.53,25.35 209.5,26.39 207.58,26.39 206.43,27.55 206.43,30.53 206.03,30.93 206.03,32.6 205.38,33.25 205.38,34.6 206.01,35.22 206.01,36.39 205.63,36.77 v2(205.22,36.77)
WIGIG_LANE_N0: length 72.6
  TOP w0.102: UV600.49 222.05,73.62 222.14,73.53 222.14,73.36 222.4,73.1 223.85,73.1 223.99,72.96 225.12,72.96 227.09,70.99 227.38,70.99 227.98,70.39 227.98,70.23 227.97,70.22 227.97,69.69 227.98,69.67 227.98,68.02 227.03,67.07 227.03,64.71 226.61,64.29 226.61,62.64 223.54,59.57 219.35,59.57 218.91,59.13 218.91,56.9 218.4,56.39 218.4,54.22 218.63,53.99 218.63,51.73 218.39,51.49 218.39,48.64 217.19,47.43 217.19,43.57 213.68,40.06 210.75,40.06 207.34,36.64 207.34,31.96 208.81,30.49 208.81,30.2 v4(213.31,25.7) 213.77,25.24 213.77,24.42 214.41,23.77 216.04,23.77 216.15,23.66 216.15,23.42 CV156.1
WIGIG_LANE_N0_C: length 5.6
  TOP w0.102: v2(214.92,22.14) 215.13,22.14 215.9,21.37 215.9,21.36 216.27,20.99 216.27,20.97 216.35,20.89 216.57,20.89 216.76,21.08 216.76,21.35 216.33,21.78 216.33,22.02 216.1,22.25 CV156.2
  BOTTOM w0.102: v2(214.92,22.14) 215.11,21.96 215.38,21.96 215.52,22.1 JNGFF1.24
WIGIG_LANE_N1: length 70.9
  TOP w0.102: UV600.46 220.85,73.34 220.94,73.25 220.94,73.05 221.52,72.48 222.19,72.48 222.44,72.22 222.99,72.22 224.7,70.51 225.13,70.51 227,68.64 227,68.39 226.2,67.59 226.2,65.48 225.46,64.74 225.46,62.69 223.17,60.4 218.97,60.4 217.99,59.41 217.99,57.14 217.57,56.72 v4(217.57,52.45) 217.57,48.98 216.37,47.78 216.37,43.97 213.7,41.31 213.68,41.31 213.25,40.88 210.41,40.88 206.52,36.99 206.52,34.94 206.37,34.8 205.89,34.8 205.62,34.52 205.62,33.35 206.52,32.45 206.52,31.61 207.98,30.15 207.98,29.85 212.94,24.89 212.94,24.08 213.35,23.67 213.35,23.42 CV152.1
WIGIG_LANE_N1_C: length 5.5
  TOP w0.102: v2(213.39,21.3) 213.39,21.96 CV152.2
  BOTTOM w0.102: v2(213.39,21.3) 213.39,22.35 214.49,23.46 215.18,23.46 215.32,23.6 JNGFF1.18
WIGIG_LANE_N2: length 70.1
  TOP w0.102: UV600.44 220.05,73.34 220.14,73.25 220.14,72.85 221.34,71.65 221.83,71.65 222.15,71.34 222.55,71.34 225.35,68.54 v4(225.35,67.77) 225.35,65.99 224.61,65.25 224.61,63.04 222.79,61.22 220.69,61.22 220.68,61.24 219.97,61.24 219.96,61.22 218.09,61.22 216.96,60.09 216.96,57.28 216.74,57.07 216.74,49.32 215.54,48.12 215.54,45.27 211.97,41.71 210.07,41.71 208.28,39.92 208.14,39.92 207.6,40.45 207.24,40.45 206.86,40.07 206.86,39.72 207.4,39.18 207.4,39.04 207.11,38.75 206.97,38.75 206.43,39.28 206.07,39.28 205.7,38.91 205.7,38.55 206.02,38.22 206.02,38.04 205.69,37.71 205.69,35.77 204.79,34.87 204.79,33.01 205.69,32.11 205.69,30.97 209.32,27.34 209.32,26.42 209.56,26.17 210.4,26.17 210.53,26.05 210.53,25.87 CV147.1
WIGIG_LANE_N2_C: length 5.4
  TOP w0.102: CV147.2 210.5,24.6 210.6,24.5 210.6,24.12 210.93,23.79 211.33,23.79 211.38,23.74 v4(211.38,23.47) 211.38,23.24 211.25,23.11 210.7,23.11 v2(209.92,23.89)
  BOTTOM w0.102: JNGFF1.17 209.47,23.85 209.62,23.71 209.74,23.71 v2(209.92,23.89)
WIGIG_LANE_N3: length 64.7
  TOP w0.102: CV145.1 208.08,26.92 208.08,27.41 204.86,30.63 204.86,31.77 203.96,32.67 203.96,37.75 204.5,38.28 204.5,38.87 v4(207.25,41.62) 207.43,41.81 207.75,41.81 208.29,41.27 208.47,41.27 208.72,41.53 208.72,41.71 208.17,42.25 208.17,42.61 208.69,43.13 209.05,43.13 209.65,42.53 210.2,42.53 211.42,43.76 211.75,43.76 212.21,43.29 212.35,43.29 212.64,43.58 212.64,43.72 212.13,44.23 212.13,44.59 212.51,44.97 212.87,44.97 213.38,44.46 213.52,44.46 213.81,44.75 213.81,44.89 213.35,45.36 213.35,45.68 213.93,46.27 213.93,47.84 215.92,49.83 215.92,57.41 216.13,57.62 216.13,60.59 216.78,61.24 216.78,61.26 217.18,61.67 217.21,61.67 217.22,61.68 217.22,62.67 215.37,64.53 215.37,69.94 216.53,71.11 217.33,71.11 217.8,71.58 218.48,71.58 218.94,72.04 218.94,73.25 218.85,73.34 UV600.41
WIGIG_LANE_N3_C: length 5.4
  TOP w0.102: v2(207.16,25.29) 207.36,25.08 207.54,25.08 208.24,24.38 208.42,24.38 v4(208.57,24.54) 208.72,24.68 208.72,24.86 208.25,25.32 208.25,25.64 208.15,25.74 CV145.2
  BOTTOM w0.102: v2(207.16,25.29) 207.34,25.1 207.68,25.1 207.93,25.35 JNGFF1.11
WIGIG_LANE_P0: length 72.7
  TOP w0.102: UV600.50 222.45,73.61 222.36,73.51 222.36,73.45 222.49,73.32 223.94,73.32 224.08,73.18 225.21,73.18 227.18,71.21 227.47,71.21 228.19,70.48 v4(228.19,69.95) 228.19,67.93 227.24,66.98 227.24,64.62 226.82,64.2 226.82,62.55 223.63,59.36 219.44,59.36 219.13,59.04 219.13,56.81 218.62,56.3 218.62,54.31 218.85,54.08 218.85,51.64 218.61,51.4 218.61,48.55 217.41,47.34 217.41,43.48 213.77,39.84 210.84,39.84 207.56,36.56 207.56,32.05 209.02,30.58 209.02,30.29 213.26,26.05 213.28,26.05 213.66,25.68 213.66,25.66 213.98,25.33 213.98,24.51 214.5,23.99 216.13,23.99 216.37,23.75 216.37,23.58 CV157.1
WIGIG_LANE_P0_C: length 5.6
  TOP w0.102: CV157.2 216.55,22.01 216.55,21.87 216.98,21.44 216.98,20.99 216.66,20.68 216.26,20.68 v4(215.92,21.01) 215.38,21.56 v2(214.92,21.56)
  BOTTOM w0.102: JNGFF1.26 215.46,21.6 215.32,21.74 215.11,21.74 v2(214.92,21.56)
WIGIG_LANE_P1: length 71
  TOP w0.102: CV153.1 213.56,23.58 213.56,23.76 213.16,24.17 213.16,24.98 208.2,29.94 208.2,30.24 206.73,31.7 206.73,32.54 205.83,33.44 205.83,34.43 205.98,34.58 206.46,34.58 206.73,34.85 206.73,36.9 210.5,40.66 213.36,40.66 v4(213.66,40.96) 216.58,43.89 216.58,47.69 217.78,48.89 217.78,52.1 217.81,52.12 217.81,52.72 217.78,52.74 217.78,56.64 218.2,57.05 218.2,59.32 219.06,60.18 223.26,60.18 225.68,62.6 225.68,64.66 226.42,65.39 226.42,67.5 227.22,68.3 227.22,68.73 225.22,70.73 224.79,70.73 223.08,72.44 222.53,72.44 222.28,72.69 221.61,72.69 221.16,73.14 221.16,73.25 221.25,73.34 UV600.47
WIGIG_LANE_P1_C: length 5.5
  TOP w0.102: CV153.2 213.6,21.87 213.6,21.67 v2(213.97,21.3)
  BOTTOM w0.102: JNGFF1.20 215.32,23.1 215.18,23.24 214.58,23.24 213.6,22.26 213.6,21.67 v2(213.97,21.3)
WIGIG_LANE_P2: length 70
  TOP w0.102: UV600.45 220.45,73.34 220.36,73.25 220.36,72.94 221.43,71.87 221.92,71.87 222.24,71.55 222.64,71.55 225.56,68.63 225.56,68.05 225.58,68.03 225.58,67.5 225.56,67.49 225.56,65.9 224.83,65.16 224.83,62.95 222.88,61.01 v4(220.32,61.01) 218.18,61.01 217.17,60 217.17,57.19 216.96,56.98 216.96,49.23 215.76,48.03 215.76,45.18 212.06,41.49 210.16,41.49 208.37,39.7 208.05,39.7 207.51,40.24 207.33,40.24 207.08,39.98 207.08,39.81 207.61,39.27 207.61,38.95 207.2,38.53 206.88,38.53 206.34,39.07 206.16,39.07 205.91,38.82 205.91,38.64 206.24,38.31 206.24,37.95 205.91,37.62 205.91,35.68 205.01,34.78 205.01,33.1 205.91,32.2 205.91,31.06 209.54,27.43 209.54,26.51 209.65,26.39 210.49,26.39 210.74,26.14 210.74,25.83 CV148.1
WIGIG_LANE_P2_C: length 5.5
  TOP w0.102: CV148.2 210.82,24.36 210.82,24.21 211.02,24 211.42,24 211.61,23.81 211.61,23.16 211.34,22.9 210.61,22.9 210.1,23.41 210.02,23.41 v2(209.92,23.31)
  BOTTOM w0.102: v2(209.92,23.31) 209.74,23.49 209.62,23.49 209.48,23.35 JNGFF1.19
WIGIG_LANE_P3: length 64.7
  TOP w0.102: UV600.42 219.25,73.34 219.16,73.25 219.16,71.95 218.57,71.36 217.89,71.36 217.42,70.89 216.62,70.89 215.58,69.85 215.58,64.62 217.44,62.76 217.44,61.59 v4(217.15,61.31) 216.35,60.5 216.35,57.53 216.13,57.32 216.13,49.74 214.15,47.75 214.15,46.18 213.56,45.59 213.56,45.45 214.03,44.98 214.03,44.66 213.61,44.24 213.29,44.24 212.78,44.76 212.6,44.76 212.35,44.5 212.35,44.32 212.86,43.81 212.86,43.49 212.44,43.08 212.12,43.08 211.66,43.54 211.51,43.54 210.29,42.32 209.56,42.32 208.96,42.92 208.78,42.92 208.39,42.52 208.39,42.34 208.93,41.79 208.93,41.44 208.56,41.06 208.2,41.06 207.66,41.59 207.54,41.59 207.22,41.27 207.2,41.27 204.71,38.78 204.71,38.19 204.18,37.66 204.18,32.76 205.08,31.86 205.08,30.72 208.3,27.5 208.3,27.07 CV146.1
WIGIG_LANE_P3_C: length 5.5
  TOP w0.102: v2(207.16,24.7) 207.32,24.87 207.45,24.87 207.95,24.37 208.16,24.15 208.52,24.15 208.95,24.59 208.95,24.93 208.47,25.41 208.47,25.5 CV146.2
  BOTTOM w0.102: JNGFF1.13 207.76,24.85 207.72,24.89 207.34,24.89 v2(207.16,24.7)
WIGIGCLK_REQ#: length 127.8
  TOP w0.102: RPC9.6 159.94,74.65 159.82,74.52 154.13,74.52 153.86,74.8 151.15,74.8 v1(150.89,74.54) 150.6,74.26 149.02,74.26 v2(148.81,74.05)
  IN2 w0.081: 151.83,68.88 151.32,69.39 151.32,72.16 149.43,74.05 v2(148.81,74.05)
  IN2 w0.122: 151.83,68.88 152.03,68.68 154.24,68.68 157.04,65.88 159.25,65.88 161.91,63.22 161.91,57.31 166.4,52.82 166.4,50.82 166.96,50.26 166.96,45.87 173.8,39.02 194.79,39.02 195.71,39.94 206.32,39.94 v2(206.44,39.83)
  BOTTOM w0.081: UC1.U5 148.61,73.85 v2(148.81,74.05)
  BOTTOM w0.102: v2(206.44,39.83) 206.46,39.8 206.46,34.99 205.86,34.4 205.86,33.41 206.48,32.79 206.48,31.12 207.06,30.55 207.06,27.93 207.32,27.66 207.99,27 208.17,27 208.18,27 209.69,27 211.13,25.56 211.13,19.72 213.39,17.46 213.39,13.7 213.99,13.1 JNGFF1.60
WIRELESS_LED#: length 145.3
  TOP w0.102: 213.49,19.55 QZ2.3 ; 213.49,19.55 213.22,19.28 213.22,18.39 213.08,18.25 QZ2.6 ; 213.49,19.55 213.49,20.09 212.65,20.93 212.65,21.82 212.2,22.26 v1(207.82,22.26) 207.59,22.26 v2(207.33,22.53) ; v2(226.31,56.87) 226.16,56.72 225.47,56.72 225.38,56.81 223,56.81 222.68,57.12 220.9,57.12 220.47,57.55 QZ11.6 ; UE1.A47 232.47,42.97 232.33,42.84 232.19,42.84 v2(231.86,42.51)
  IN2 w0.122: v2(264.4,80.81) 264.24,80.97 262.14,80.97 259.03,77.86 259.03,74.14 258.76,73.86 258.76,72.91 255.64,69.8 255.64,59.02 251.4,54.78 251.4,52.84 249.85,51.28 246.88,51.28 244.46,48.87 v2(243.38,48.87) 243.38,47.09 237.82,41.54 232.36,41.54 231.86,42.04 v2(231.86,42.51)
  IN3 w0.122: v2(231.86,42.51) 231.86,41.69 230.25,40.08 223.99,40.08 221.22,37.31 212.15,37.31 207.14,32.3 207.14,30.88 206.55,30.3 206.55,23.3 v2(207.33,22.53)
  IN4 w0.084: v2(226.31,56.87) 226.37,56.82 226.37,54.01 226.97,53.41 226.97,52.58 227.83,51.73 231.44,51.73 232.64,50.52 233.67,50.52 234.03,50.15 236.35,50.15 237.04,50.84 239.07,50.84 240.27,49.63 242.62,49.63 v2(243.38,48.87)
  BOTTOM w0.102: v2(264.4,80.81) 264.1,81.11 QZ7.1 264.71,82.13 RZ31.2
WLAN_DISBL#: length 56.8
  TOP w0.102: UE1.B68 234.08,52.9 234.24,53.06 238.62,53.06 239.83,51.85 239.83,50.43 240.25,50.01 v1(241.27,50.01) 242.82,50.01 v2(243.38,49.45) ; UL2.4 244.71,84.29 245.05,84.63 v2(245.05,84.92)
  BOTTOM w0.102: v2(243.38,49.45) 243.38,49.95 246.37,52.93 246.37,53.08 246.44,53.15 246.44,55.37 247.66,56.59 247.66,65.76 249,67.09 249,68.62 248.35,69.27 247.51,69.27 246.2,70.57 246.2,73.04 245.37,73.87 245.37,75.06 241.69,78.74 241.69,83.06 243,84.37 244.49,84.37 v2(245.05,84.92)
WLAN_LED: length 45.9
  TOP w0.102: LED5.2 229.41,101.45 v2(229.48,101.38) ; v2(257.4,86.43) v1(259,86.43) 261.73,83.69 RZ33.2
  IN4 w0.084: v2(229.48,101.38) 229.48,99.29 232.72,96.05 240.79,96.05 241.71,95.14 241.71,90.69 241.94,90.46 241.94,89.22 244.62,86.54 249.45,86.54 250.28,87.37 256.45,87.37 v2(257.4,86.43)
WLAN_LED#: length 19.9
  TOP w0.102: v2(212.24,21.63) 211.13,21.63 211.04,21.54 211.04,19.95 210.3,19.21 v1(210.3,18.76) 210.3,18.01 210.95,17.36 RZ14.1 213.02,17.36 213.9,18.25 QZ2.1
  BOTTOM w0.102: JNGFF1.6 215.56,28.6 214.87,27.91 213.35,27.91 212.24,26.81 v2(212.24,21.63)
WLAN_WIGIG60GHZ_DIS#: length 62.3
  TOP w0.102: v2(212.27,15.72) 212.32,15.78 DZ1.1 ; v2(237.2,54.07) v1(236.59,54.07) 234.49,56.17 RE8.2 232.97,55.01 UE1.A1
  IN3 w0.122: v2(212.27,15.72) 212.59,15.72 216.34,19.48 216.34,31.74 220.84,36.23 227.89,36.23 232.74,41.08 236.29,41.08 237.32,42.11 237.32,50.36 236.97,50.71 236.97,53.84 v2(237.2,54.07)
WLAN_WIGIG60GHZ_DIS#_R: length 3
  TOP w0.102: v1(215.66,15.96) 215.57,15.87 v2(214.86,15.87) 214.38,15.87 DZ1.2
  BOTTOM w0.102: v2(214.86,15.87) 215.23,15.87 215.46,16.1 JNGFF1.48
WLANCLK_REQ#: length 119.7
  TOP w0.102: v2(193.55,43.02) 193.55,42.51 v1(193.95,42.1)
  IN2 w0.122: v2(193.55,43.02) 193.55,42.32 192.27,41.05 186.56,41.05 184.2,43.41 184.2,45.04 184.45,45.29 184.45,45.63 184.2,45.88 174.56,45.88 171.59,48.85 171.59,53.04 169.54,55.1 169.54,59.98 166.74,62.78 166.74,66.08 167.56,66.9 167.56,69.57 166.93,70.21 166.93,71.87 164.22,74.58 161.02,74.58 159.64,75.96 154.21,75.96 v2(153.84,76.33)
  BOTTOM w0.076: 153.45,76.73 152.61,76.73 152.32,76.44 152.32,76.11 151.77,75.56 UC1.N1
  BOTTOM w0.081: 153.45,76.73 153.82,76.35
  BOTTOM w0.102: 153.82,76.35 v2(153.84,76.33) 154.06,76.55 154.06,76.84 154.99,77.76 156.1,77.76 156.91,76.95 RPC17.6 ; JNGFF1.45 209.93,16.85 210.44,17.36 210.44,19.26 210.9,19.72 210.9,25.35 209.63,26.62 207.71,26.62 206.68,27.65 206.68,30.6 206.26,31.03 206.26,32.7 205.64,33.32 205.64,34.49 206.24,35.09 206.24,36.61 205.6,37.25 198.39,37.25 198.34,37.31 198.34,40.43 195.75,43.02 v2(193.55,43.02)
WWAN_LED#: length 5.1
  TOP w0.102: v2(223.74,58.08) 223.74,58.08 223.32,58.08 222.8,57.56 RZ37.1 222.55,57.55 QZ11.1
  BOTTOM w0.102: v2(223.74,58.08) 223.37,58.46 223.37,59.82 223.44,59.9 JNGFF2.10
WWAN_PWR_EN: length 12
  TOP w0.102: v2(227.74,61.33) 227.74,60.67 227.35,60.29 226.7,60.29 RZ50.2
  IN3 w0.122: v2(226.1,64.31) 226.1,64.29 227.74,62.65 v2(227.74,61.33)
  BOTTOM w0.102: v2(226.1,64.31) 225.12,64.31 223.23,62.43 223.23,61.12 223.45,60.9 JNGFF2.6
WWAN_RADIO_DIS#: length 30.1
  TOP w0.102: v2(225.77,57.13) 225.67,57.04 224.11,57.04 DZ5.1 ; UE1.A53 235.06,47.15 235.09,47.12 RE10.2 236.83,47.14 237.29,47.6 238.18,47.6 238.37,47.79 240.02,47.79 240.3,48.08 v1(240.3,48.85) v2(239.94,49.21)
  IN4 w0.084: v2(239.94,49.21) 239.94,49.58 238.94,50.58 237.08,50.58 236.44,49.94 233.93,49.94 233.56,50.31 232.55,50.31 231.35,51.52 227.74,51.52 226.76,52.5 226.76,53.32 226.11,53.97 226.11,56.51 225.77,56.85 v2(225.77,57.13)
WWAN_RADIO_DIS#_R: length 5.5
  TOP w0.102: DZ5.2 224.81,57.51 v2(224.34,57.98)
  BOTTOM w0.102: JNGFF2.8 225.05,60.4 225.22,60.22 225.22,59.7 225.1,59.57 224.11,59.57 223.83,59.28 223.83,58.58 224.34,58.07 v2(224.34,57.98)
WWAN_WAKE#: length 52.6
  TOP w0.102: RE276.2 225.23,41.94 v2(225.1,42.07) 224.84,42.07 v1(224.57,42.34) ; UE1.B43 229.22,45.49 v2(228.84,45.87)
  IN1 w0.084: v2(228.84,45.87) 229.33,45.38 229.33,44.49 228.99,44.15 224.91,44.15 224.17,43.42 224.17,42.55 224.65,42.07 v2(225.1,42.07)
  IN4 w0.084: v2(219.14,56.25) 219.38,56.49 220.02,56.49 220.21,56.68 220.24,56.68 226.56,62.99 227.93,62.99 228.38,63.45 230.04,63.45 230.59,62.9 v2(230.99,62.9)
  BOTTOM w0.102: v2(230.99,62.9) 231.05,62.84 232.21,62.84 234.02,61.02 234.02,48.71 233.49,48.17 232.53,48.17 231.03,46.68 229.32,46.68 228.84,46.19 v2(228.84,45.87) ; v2(219.14,56.25) 218.54,56.25 218.14,56.65 JNGFF2.15
XDP_DBRESET#: length 181
  TOP w0.102: v2(166.81,69.08) 167,69.08 167.22,68.86 168.95,68.86 170.36,70.27 v1(170.36,73.95) 170.36,76.2 167.36,79.2 167.36,81.47 167.16,81.67 RC77.1 166.8,81.93 167.09,82.22 CC105.1 166.87,82.75 166.43,82.75 166.24,82.94 166.24,83.54 166.14,83.64 165.82,83.64 165.69,83.51 UC4.1 ; v2(65.76,42.02) 65.76,42 66.62,41.15 70.2,41.15 72.29,43.24 72.29,47.62 74.52,49.85 74.52,52.58 71.96,55.14 70.17,55.14 69.9,55.41 RC122.2 CC21.1 69.9,56.82 JXDP1.48
  BOTTOM w0.102: v2(65.76,42.02) 73.06,42.02 77,45.95 153.84,45.95 155.98,48.09 168.29,48.09 172.26,52.07 172.26,59.79 171.5,60.55 168.52,60.55 168.14,60.93 168.14,65.27 166.29,67.11 166.29,68.81 166.57,69.08 v2(166.81,69.08)
XDP_OBS0_R: length 73.4
  TOP w0.076: v1(111.2,78.88) 110.83,78.51 v2(110.83,78.36)
  TOP w0.102: JXDP1.21 61.85,63.32 65,63.32 v2(65.15,63.47)
  IN4 w0.084: v2(110.83,78.36) 108.36,80.83 101.12,80.83 95.46,86.49 85.41,86.49 83.3,84.38 80.77,84.38 79.33,82.94 76.77,82.94 74.57,80.75 74.57,77.02 73.56,76 73.56,71.19 72.49,70.12 69.98,70.12 69.28,69.43 68.97,69.43 66.94,67.39 66.94,65.33 65.15,63.54 v2(65.15,63.47)
  BOTTOM w0.076: v2(110.83,78.36) 110.83,78.05 111.31,77.57 111.51,77.57 111.69,77.39 112.81,77.39 112.98,77.56 113.75,77.56 113.8,77.52 114.27,77.52 UC1.J60
XDP_OBS1_R: length 75.8
  TOP w0.076: v2(114.27,78.22) v1(114.27,77.55)
  TOP w0.102: JXDP1.23 62.96,62.82 63.23,63.09 64.81,63.09 v2(65.01,62.9)
  IN4 w0.084: v2(114.27,78.22) 113.75,77.7 113.02,77.7 109.86,80.85 108.75,80.85 106.45,83.15 106.45,84.8 104.29,86.96 100.5,86.96 100.24,86.7 85.32,86.7 83.21,84.59 80.68,84.59 79.25,83.16 76.68,83.16 74.36,80.84 74.36,77.11 73.35,76.09 73.35,71.29 73.1,71.04 72.39,70.33 69.89,70.33 69.2,69.64 68.88,69.64 66.73,67.48 66.73,65.42 65.72,64.41 65.53,64.41 64.74,63.62 64.74,63.17 v2(65.01,62.9)
  BOTTOM w0.081: UC1.H60 114.57,78.52 v2(114.27,78.22)
XDP_OBS2_R: length 15.5
  BOTTOM w0.076: 111.55,78.54 112.27,78.54 112.5,78.32 112.73,78.32 112.94,78.53 112.94,78.67 113.15,78.87 113.68,78.87 UC1.H61
  BOTTOM w0.102: 111.55,78.54 109.73,80.37 108.69,80.37 108.26,80.8 108.26,81.95 108.52,82.21 108.52,83.64 107.58,84.58 107.58,85.2 105.72,87.07 T10.1
XDP_OBS3_R: length 4.7
  BOTTOM w0.076: 111.41,78.36 112.22,78.36 112.43,78.15 112.82,78.15 UC1.H62
  BOTTOM w0.102: T11.1 110.35,79.41 111.41,78.36
XDP_OBS4_R: length 13.1
  TOP w0.102: T12.1 115.7,87.41 v2(116.19,87.41)
  IN2 w0.122: v2(116.19,87.41) 115.18,86.4 115.18,86.33 114.19,85.34 114.19,83.09 115.57,81.71 115.57,79.67 115.36,79.46 115.36,77.76 v2(115.63,77.49)
  BOTTOM w0.081: UC1.K59 115.27,77.13 v2(115.63,77.49)
XDP_OBS5_R: length 12.1
  BOTTOM w0.076: UC1.H63 112.49,78.72 111.71,78.72
  BOTTOM w0.102: T13.1 106.63,86.48 107.81,85.3 107.81,84.68 108.75,83.74 108.75,82.12 108.48,81.85 108.48,80.9 108.78,80.6 109.83,80.6 111.71,78.72
XDP_OBS6_R: length 12.6
  TOP w0.102: T14.1 114.15,86.87 v2(114.51,86.87)
  IN2 w0.122: v2(114.26,76.71) 114.26,76.96 112.92,78.3 112.92,84.42 113.62,85.11 113.62,85.98 v2(114.51,86.87)
  BOTTOM w0.081: UC1.K60 114.57,77.01 v2(114.26,76.71)
XDP_OBS7_R: length 10.8
  TOP w0.102: v2(114.54,86.28) 114.54,85.65 T15.1
  IN2 w0.122: v2(113.62,78.22) 113.18,78.66 113.18,84.2 113.87,84.9 113.87,85.62 v2(114.54,86.28)
  BOTTOM w0.081: v2(113.62,78.22) 113.92,77.92 UC1.J61
XDP_RST#_R: length 6.8
  TOP w0.102: RC106.2 72.59,56.95 72.59,57.49 72.3,57.78 v1(72.14,57.78) 71.56,57.78 71.09,58.25 70.45,58.25 CC111.1 69.51,57.32 JXDP1.46
XTAL24_IN: length 9.8
  BOTTOM w0.102: YC2.3 135.03,91.06 136,90.08 136,88.32 RC63.2 135.76,88.05 CC8.2 137.19,86.62 137.19,84.58 136.53,83.92 UC1.A25
XTAL24_OUT: length 7.3
  BOTTOM w0.102: RC63.1 136.65,88.02 RC65.1 138.24,86.44 v1(138.24,85.85) 138.24,85 136.96,83.72 136.96,82.7 136.53,82.27 UC1.B25
XTAL24_OUT_R: length 2.8
  BOTTOM w0.102: YC2.1 137.1,88.46 CC11.2 137.54,88.05 RC65.2
XTALI: length 6.8
  TOP w0.102: YL1.1 231.01,82.6 231.78,83.36 CL14.2 232.84,83.87 232.84,84.67 RL11.2 233.03,85.75 233.12,85.75 233.73,86.36 UL1.10
XTALO: length 3.5
  TOP w0.102: RL10.2 231.53,86.03 RL11.1 232.77,86.4 233.16,86.4 v1(233.38,86.62) 233.52,86.76 UL1.9
XTALO_R: length 2.5
  TOP w0.102: RL10.1 CL13.2 229.21,85.48 YL1.3
Z2805: length 3.8
  TOP w0.102: v1(259.07,93.45) 259.02,93.4 RL18.1
  TOP w0.508: v2(257.8,94.53) RL18.1
  BOTTOM w0.508: v2(257.8,94.53) TL1.22
Z2806: length 3.8
  TOP w0.102: RL16.1 250.89,93.46 v1(251.26,93.83)
  TOP w0.508: v2(250.18,94.59) RL16.1
  BOTTOM w0.508: TL1.16 v2(250.18,94.59)
Z2807: length 3.6
  TOP w0.102: v1(255.51,93.57) 255.69,93.4 RL17.1
  TOP w0.508: v2(256.53,94.53) RL17.1
  BOTTOM w0.508: TL1.21 v2(256.53,94.53)
Z2808: length 3.8
  TOP w0.102: v1(247.7,93.51) 247.75,93.46 RL15.1
  TOP w0.508: RL15.1 248.92,94.59 v2(248.91,94.59)
  BOTTOM w0.508: TL1.15 v2(248.91,94.59)
N15115: length 1.3
  TOP w0.076: v2(149.61,69.19) 149.15,68.73 T16.1
  BOTTOM w0.081: v2(149.61,69.19) 149.29,69.5 UC1.AD4
N19253: length 7.6
  BOTTOM w0.102: T28.1 109.41,56.18 109.41,57.07 110.35,58.01 111.01,58.01 112.09,59.09 112.09,61 112.54,61.44 UC1.AV63
N19255: length 7.5
  BOTTOM w0.081: 111.48,60.81 111.48,61.04 112.55,62.11 UC1.AU63
  BOTTOM w0.102: 111.48,60.81 111.48,59.94 110.64,59.09 110.13,59.09 107.94,56.91 T29.1
N19263: length 12.4
  BOTTOM w0.102: T30.1 109.23,91.33 109.23,89.94 109.28,89.89 109.28,89.12 108.94,88.78 108.94,85.46 109.03,85.37 109.03,84.75 112.32,81.46 UC1.C63
N19267: length 8.9
  BOTTOM w0.081: 112.03,82.13 112.38,81.79 112.87,81.79 UC1.C62
  BOTTOM w0.102: T31.1 109.17,88.12 109.17,85.56 109.41,85.32 109.41,84.76 112.03,82.13
N19275: length 4.7
  BOTTOM w0.081: UC1.A51 120.36,82.94 120.89,83.48 120.89,84.62
  BOTTOM w0.102: 120.89,84.62 121.17,84.9 121.17,85.86 121.84,86.53 T33.1
N19277: length 5.6
  BOTTOM w0.081: 121.08,84.43 121.08,83.41 120.65,82.98 120.65,82.42 UC1.B51
  BOTTOM w0.102: T34.1 122.18,86.08 121.4,85.3 121.4,84.75 121.08,84.43
N19281: length 4.7
  BOTTOM w0.081: UC1.L60 114.25,75.99 113.77,75.99 113.66,75.88 113.15,75.88 112.98,75.71 112.98,75.54 112.76,75.32 111.97,75.32
  BOTTOM w0.102: 111.97,75.32 111.75,75.09 111.43,75.09 111.25,75.28 110.68,75.28 T35.1
N21871: length 10.8
  BOTTOM w0.076: UC1.P60 114.24,74.49 113.83,74.49 113.73,74.39 112.44,74.39 112.24,74.19 112.24,74.19 112.23,74.18 111.78,74.18
  BOTTOM w0.081: 111.78,74.18 111.26,74.7 110.82,74.7
  BOTTOM w0.102: T74.1 106.38,75.69 106.55,75.69 106.92,75.32 106.92,74.55 107.3,74.17 109.32,74.17 109.86,74.7 110.82,74.7
N21873: length 5.1
  BOTTOM w0.076: 111.46,74.74 111.84,74.36 112.18,74.36 112.24,74.43 112.25,74.43 112.37,74.55 113.66,74.55 UC1.P61
  BOTTOM w0.081: 111.46,74.74 111.26,74.94 110.82,74.94
  BOTTOM w0.102: 110.82,74.94 109.57,74.94 T75.1
N21875: length 13.4
  TOP w0.102: T76.1 117.13,87.48 v2(117.27,87.48)
  IN2 w0.122: v2(117.27,87.48) 116.57,86.78 116.57,83.86 116.19,83.48 116.19,77.18 115.65,76.64 v2(115.65,76.01)
  BOTTOM w0.081: v2(115.65,76.01) 115.28,75.64 UC1.N59
N21877: length 14.6
  TOP w0.102: T77.1 113.52,86.8 v2(113.52,86.96)
  IN2 w0.122: v2(113.52,86.96) 113.36,86.8 113.36,85.28 112.67,84.58 112.67,76.96 113.58,76.06 113.58,75.87 v2(114.22,75.22)
  BOTTOM w0.081: UC1.N61 113.92,75.57 114.22,75.26 v2(114.22,75.22)
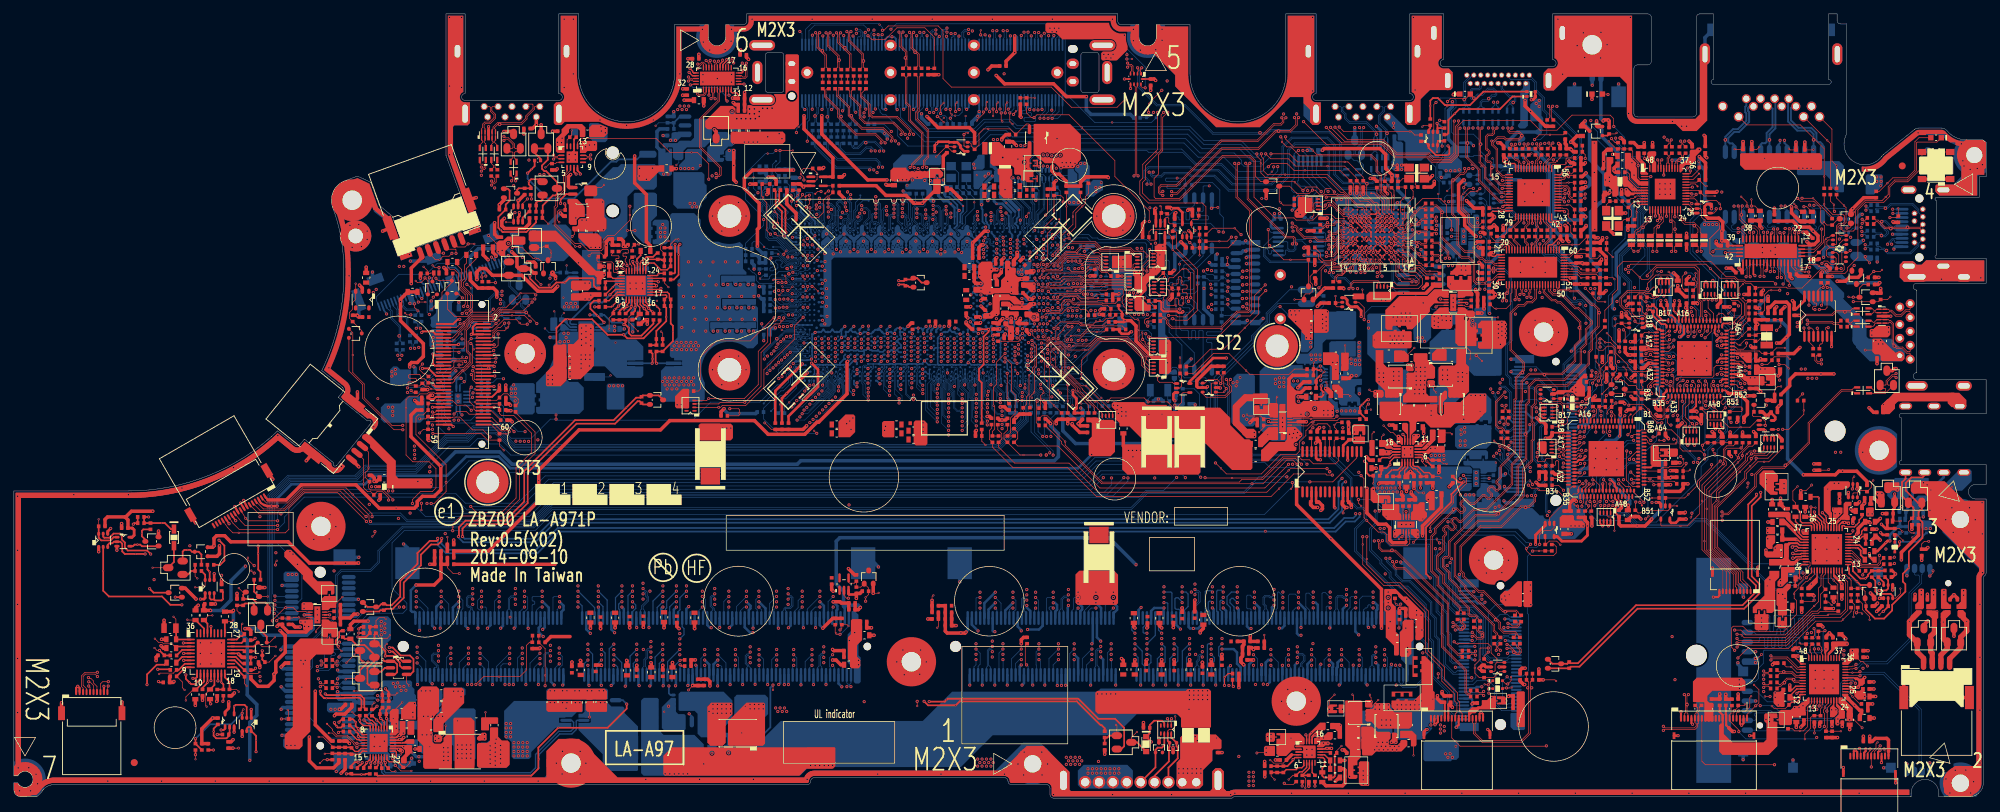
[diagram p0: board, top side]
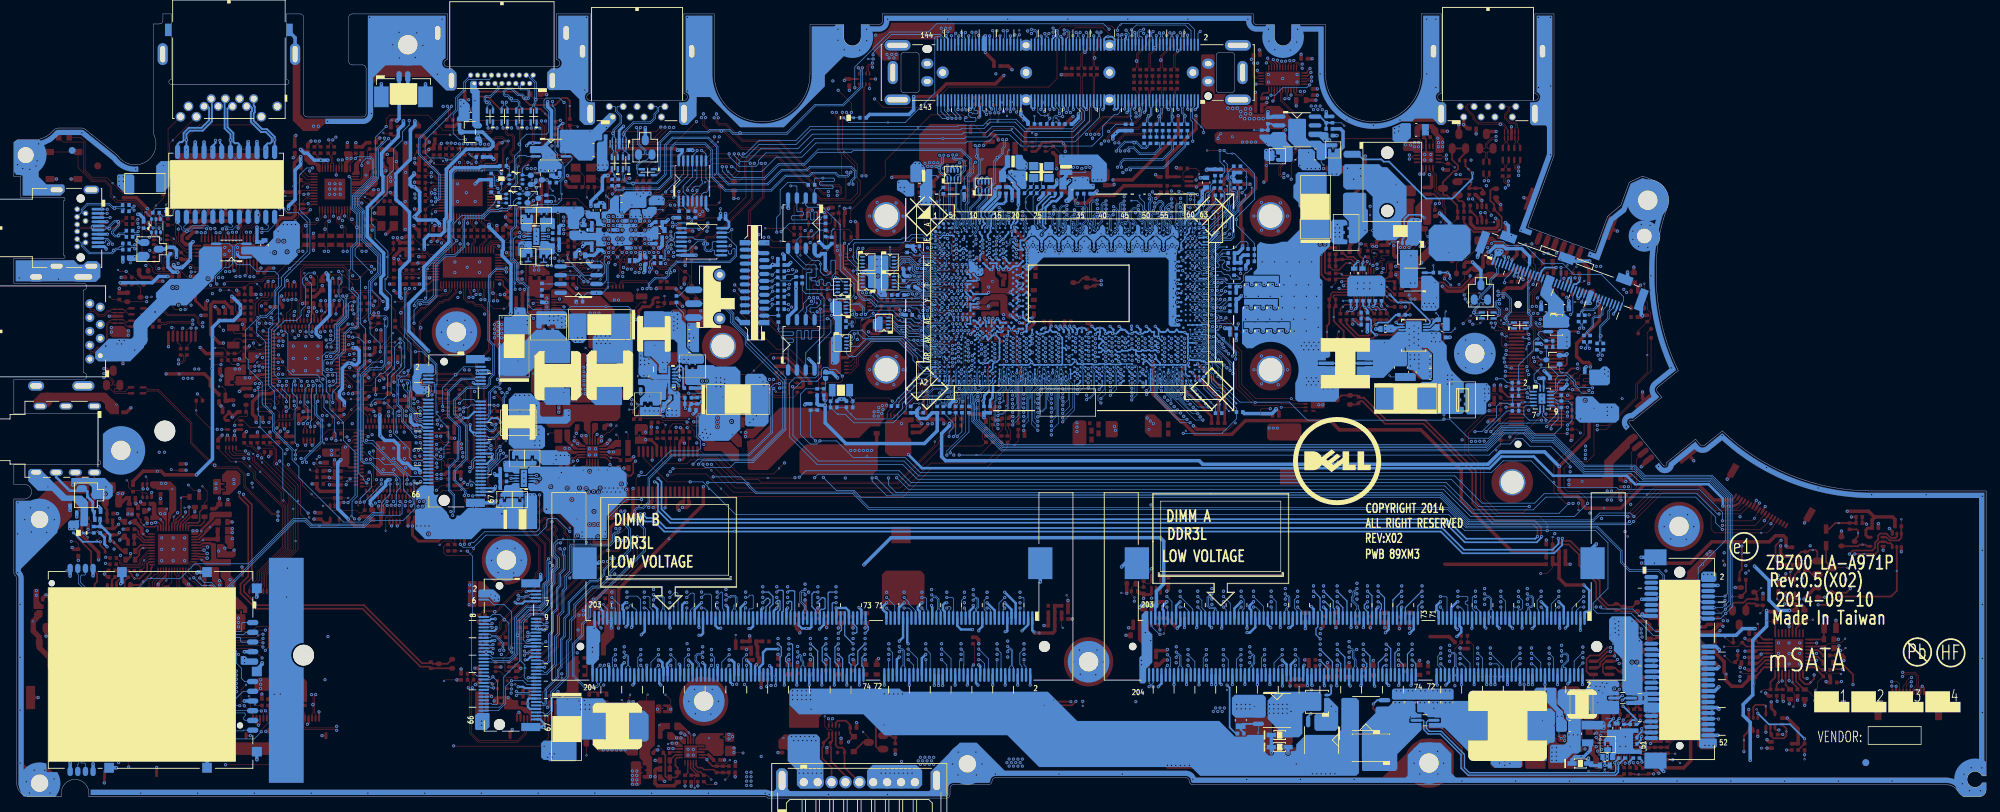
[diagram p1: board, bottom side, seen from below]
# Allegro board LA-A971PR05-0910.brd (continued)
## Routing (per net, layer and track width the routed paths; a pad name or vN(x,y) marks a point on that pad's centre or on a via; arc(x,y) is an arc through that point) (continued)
N29827: length 3.7
  TOP w0.102: v1(120.14,24.79) 119.95,24.98 RD15.2 119.18,24.49 v2(118.92,24.23)
  BOTTOM w0.102: JDIMM1.197 119,24.31 v2(118.92,24.23)
N29829: length 4.8
  TOP w0.102: v2(118.92,23.6) 118.49,23.6 v1(118.37,23.72) 118.23,23.86 RD16.2
  BOTTOM w0.102: v2(118.92,23.6) 118.99,23.6 120.2,24.82 JDIMM1.201
N33048: length 1.9
  TOP w0.127: v1(180,23.51) CD36.2
  TOP w0.508: CD36.2 RD21.1
N33050: length 2.3
  TOP w0.102: v1(132.92,24.55) 133.08,24.71 RD25.1
  TOP w0.508: CD54.2 RD25.1
N33054: length 4.4
  TOP w0.102: RD28.1 198.81,28.13 v1(199.02,27.91) 199.15,27.79 199.46,27.79 v2(199.63,27.95)
  BOTTOM w0.102: JDIMM2.197 198.5,27.28 199.17,27.95 v2(199.63,27.95)
N33058: length 2.8
  TOP w0.102: v2(199.38,24.51) 199.38,25.68 RD27.1
  BOTTOM w0.102: JDIMM2.201 199.7,24.83 v2(199.38,24.51)
N40459: length 3.3
  BOTTOM w0.102: RV5.2 63.31,64.49 63.29,64.47 QV2.1 64.12,63.16 v1(64.57,63.6)
N70739: length 27.5
  TOP w0.102: RE71.2 254.5,50.33 252.63,48.46 v1(251.96,48.46) 251.05,48.46 249.39,46.8 249.39,46.03 245.22,41.87 245.22,36.21 248.89,32.54 248.89,31.48 250,30.38 JDEG1.1
N70745: length 12
  TOP w0.102: v1(255.63,63.28) 255.32,63.59 253.4,63.59 253.07,63.26 RE64.1 253.07,63.09 252.46,62.48 v2(251.64,62.48) ; UE2.B61 245.82,63.85 v2(245.81,63.87)
  IN1 w0.084: v2(245.81,63.87) 247.48,63.87 247.76,64.15 248.99,64.15 250.66,62.48 v2(251.64,62.48)
N70747: length 3.2
  TOP w0.102: RE66.2 232.68,60.05 232.09,60.64 CE34.1 232.09,61.75 v1(231.7,62.14)
N70757: length 8.3
  TOP w0.102: v1(254.94,64.87) 253.73,64.87 253.07,64.21 RE57.1 253.06,64.07 RE58.1 252.12,64.05 251.62,64.05 251.26,64.42 248.52,64.42 247.95,64.42 247.76,64.6 UE2.A59
N73962: length 1.6
  TOP w0.102: CZ45.1 209.7,71.81 UZ9.12
N73964: length 1.6
  TOP w0.102: CZ46.1 208.96,70.84 208.79,71.01 UZ9.10
N75571: length 7
  BOTTOM w0.102: QZ3.1 213.93,87.05 DZ3.2 214.13,87.34 213.73,87.74 DZ4.2 213.73,88.68 212.63,89.78 QZ14.1 212.58,90.66 RZ24.2 213.02,92 v1(212.84,92.18)
N75591: length 3.3
  BOTTOM w0.102: QZ4.1 207.92,86.88 RZ27.1 206.29,86.88 205.97,86.56 v1(205.97,86.02)
N75595: length 1.1
  BOTTOM w0.102: DZ3.1 214.03,85.75 QZ3.3
N75597: length 5.9
  BOTTOM w0.102: QZ4.2 210.54,87.09 210.58,87.05 QZ3.6 211.48,87.05 211.76,87.32 211.76,88.22 211.4,88.58 211.4,90.89 v1(211.25,91.05)
N75599: length 2.9
  TOP w0.102: QZ9.1 262.64,83.48 RZ33.1 260.99,82.57 v1(260.53,83.03)
N75603: length 3.9
  TOP w0.102: v2(263.86,82.14) 264.24,82.14 264.44,82.35 QZ9.2
  BOTTOM w0.102: v2(263.86,82.14) 264.1,82.39 QZ7.6 264.1,83.62 v1(264.91,84.43)
N5261056: length 99.2
  TOP w0.102: v2(123.7,29.52) 124.42,29.52 v1(124.49,29.58)
  TOP w0.508: v2(176.34,15.93) RD13.1 RD12.1 ; RD11.1 RD10.1 v2(98.1,19.92) ; QD1.3 v2(123.7,29.52)
  IN2 w0.508: v2(176.34,15.93) 176.34,16.22 176.29,16.27 176.29,16.58 174.8,18.07 137,18.07 125.56,29.52 v2(123.7,29.52)
  IN4 w0.508: v2(98.1,19.92) 98.29,19.92 98.79,19.41 98.79,18.71 99.29,18.21 118.24,18.21 119.69,19.66 119.69,24.04 123.7,28.06 v2(123.7,29.52)
N10757881: length 2
  TOP w0.102: v1(62.4,37.62) RD7.1
  TOP w0.508: RD7.1 62.4,36.55 CD21.2
N15438178: length 55.7
  IN1 w0.508: v2(58.31,5.97) 59.77,5.97 61.67,4.06 73.91,4.06 78.52,8.67 81.97,8.67 83.44,7.2 102.2,7.2 v2(102.89,6.51)
  BOTTOM w0.457: PR708.1 56.96,7.58 56.96,6.92 v1(57.35,6.53) 57.91,5.97 v2(58.31,5.97)
  BOTTOM w0.508: v2(102.89,6.51) PD704.1 PD705.1 ; PD702.1 59.61,5.5 59.14,5.97 v2(58.31,5.97)
N15438627: length 9.2
  TOP w0.102: v1(51.91,13.75) 51.55,13.4 PR710.1
  TOP w0.203: PU700.6 51.7,10.55 51.47,10.78 50.86,10.78 50.39,11.25 v2(50.38,11.25)
  TOP w0.254: PR710.1 51.8,12.78 v2(52.27,13.25)
  BOTTOM w0.254: v2(52.27,13.25) 52.24,13.25 50.38,11.39 v2(50.38,11.25) 50.95,11.25 51.25,10.96 PR711.1 PC711.1
N15439163: length 2.6
  TOP w0.203: PU700.5 52.1,10.66 51.55,11.21 51.32,11.21 50.67,11.86 PR714.2
N15439291: length 5.3
  TOP w0.102: v1(48.72,12.39) 49.23,11.88 PR716.2
  TOP w0.203: PU700.7 51.3,10.35 51.2,10.45 50.28,10.45 49.79,10.95 v2(49.79,11.21)
  TOP w0.254: v2(49.79,11.21) PR716.2
  BOTTOM w0.254: v2(49.79,11.21) 49.79,11.01 50.16,10.64 PC718.2
N15439295: length 5.1
  TOP w0.203: PU700.8 50.25,9.15 49.58,9.82 v2(49.58,10.01)
  TOP w0.254: v2(49.58,10.01) 49.2,10.39 v1(49.2,10.96) 48.78,11.38 PR718.2
  BOTTOM w0.254: PC719.2 50.27,8.89 49.58,9.58 v2(49.58,10.01)
N15439512: length 4.4
  TOP w0.203: PU700.9 49.94,8.75 49.8,8.89 v2(49.58,8.89)
  TOP w0.254: v2(49.58,8.89) 49.58,9.25 v1(49.26,9.56) 49.26,9.6 48.37,10.49 PR720.2
  BOTTOM w0.254: PR788.2 50.24,7.82 49.7,8.37 49.7,8.78 v2(49.58,8.89)
N15440461: length 2.7
  TOP w0.203: PR717.2 48.34,9.49 49.39,8.43 49.7,8.43 49.78,8.35 PU700.10
N15441413: length 1.7
  TOP w0.203: PR722.1 52.41,4.7 52.41,5.21 52.5,5.3 PU700.18
N15441884: length 8.9
  TOP w0.102: v1(57.23,3.91) 55.72,3.91 54.92,4.71 v2(54.9,4.71)
  TOP w0.203: PU700.17 52.1,5.37 51.96,5.22 v2(51.96,5.03)
  IN4 w0.254: v2(51.96,5.03) 52.44,4.55 54.29,4.55 54.46,4.71 v2(54.9,4.71)
  BOTTOM w0.305: PR723.1 v2(54.9,4.71) 54.89,4.72 54.89,5.26 55.22,5.59 PC729.1
N15442134: length 38.5
  TOP w0.102: v1(54.92,3.85) 54.34,3.85 PC727.1
  TOP w0.203: PU700.20 53.3,5.27 v2(53.47,5.1) 53.47,4.72 PC727.1
  BOTTOM w0.203: PR721.3 80.28,11.21 80.57,10.92 80.57,10.04 80.16,9.63 78.42,9.63 75.1,6.3 75.1,4.37 74.38,3.66 53.52,3.66 53.33,3.85 53.33,4.9 53.47,5.04 v2(53.47,5.1)
  BOTTOM w0.254: PC726.2 52.88,5.74 52.96,5.64 53.45,5.14 53.45,5.12 v2(53.47,5.1)
N15442185: length 38.6
  TOP w0.203: PC727.2 52.87,4.41 v2(52.87,5.03) 52.9,5.06 PU700.19
  BOTTOM w0.203: v2(52.87,5.03) 52.95,4.95 52.95,3.72 53.35,3.31 74.57,3.31 75.59,4.33 v1(75.59,5.6) 75.59,6.26 78.57,9.25 80.32,9.25 80.95,9.88 80.95,11.09 81.08,11.21 PR721.2
  BOTTOM w0.254: PC728.1 51.99,5.75 52.72,5.03 v2(52.87,5.03)
N17156946: length 8.9
  BOTTOM w0.102: v1(85.86,79.86) 85.59,80.14 84.71,80.14 84.56,79.99 PQ4.4
  BOTTOM w0.254: v2(80.89,83.6) 81.33,84.05 83.11,84.05 83.74,83.41 83.74,80.81 84.02,80.53 PQ4.4
N17156948: length 2.1
  TOP w0.102: PQ6.1 84.57,87.98 v1(84.95,88.37)
N17639884: length 3.2
  TOP w0.203: PU500.2 86.23,74.89 PR519.2
  TOP w0.254: PR519.2 PC505.2
N17640254: length 6.9
  TOP w0.203: PU500.25 90.95,76.65 91.4,77.1 v1(91.62,77.1) 92.15,77.1 93.13,76.12 94.03,76.12 PC506.1
  TOP w0.254: PR535.1 94.54,78.38 PR523.1 PC506.1
N17640267: length 2.9
  TOP w0.102: v1(95.67,80.52) 95.64,80.55 95.26,80.55 94.53,79.82 PR535.2
  TOP w0.254: PC512.1 PR535.2
N17640270: length 9
  TOP w0.102: v1(94.25,80.28) 93.8,80.28 93.09,79.56 93.09,79.03 93.64,78.49 PC512.2
  TOP w0.203: PR521.1 91.37,77.63 90.55,76.81 PU500.26
  TOP w0.254: PR523.2 93.64,77.53 PC512.2 ; PR523.2 PC506.2 ; PR523.2 93.26,77.52 93.14,77.63 PR521.1
N17645088: length 4.2
  TOP w0.254: PR512.2 91.94,64.03 v1(91.94,63.28) 91.94,62.72 v2(91.87,62.66)
  BOTTOM w0.254: PL500.3 v2(91.87,62.66)
N17680637: length 3.6
  TOP w0.203: PU500.8 86.94,72.49 86.73,72.28 86.73,71.48 v1(86.19,70.94) 86.04,70.78 PR536.2
N17680665: length 3.3
  TOP w0.203: PU500.3 85.29,74.49 PR516.1
  TOP w0.254: PR516.1 PR539.1
N18325201: length 3
  TOP w0.102: CL16.1 258.08,85.23 v2(257.67,85.23)
  BOTTOM w0.102: TL1.3 257.8,85.1 v2(257.67,85.23)
N18325205: length 3.3
  TOP w0.102: CL17.1 257.23,84.49 v2(256.53,85.19) 256.53,85.38 v1(256.27,85.64)
  BOTTOM w0.102: TL1.4 v2(256.53,85.19)
N18325209: length 4
  TOP w0.102: CL20.1 250.62,85.32 v2(250.11,85.32) v1(250.11,86.26)
  BOTTOM w0.102: TL1.9 250.18,85.25 v2(250.11,85.32)
N18325213: length 4.5
  TOP w0.102: CL21.1 250.05,84.75 v2(249.48,85.32) 249.48,85.83 v1(248.64,86.66)
  BOTTOM w0.102: TL1.10 248.91,84.85 249.37,85.32 v2(249.48,85.32)
N18328616: length 1.6
  TOP w0.102: UL3.10 200.8,40.83 200.85,40.88 CL24.1
N18328720: length 1.6
  TOP w0.102: UL3.12 200,40.88 199.96,40.92 CZ37.1
N18609334: length 4.4
  TOP w0.102: QV8.2 76.06,79.34 76.25,79.53 RV6.2 77.33,78.89 v1(77.33,78.59) 77.33,77.95 QV7.1
N18731939: length 2.6
  TOP w0.102: YV2.3 199.91,89.25 199.53,88.87 RV81.1 199.14,88.98 CV113.1
N19516037: length 2.4
  TOP w0.102: RZ35.1 190.41,53.11 190.09,53.43 v1(190.09,53.77) 190.46,54.14 CZ9.1
N19540333: length 1.5
  BOTTOM w0.102: CZ23.1 212.25,46.52 212.2,46.48 UZ2.10
N19540335: length 1.5
  BOTTOM w0.102: UZ2.12 212.03,45.68 212.08,45.63 CZ49.1
N19544058: length 2.2
  BOTTOM w0.102: v1(165.91,82.02) 166.17,81.76 CC10.2 166.56,80.82 166.66,80.92 RC62.1
N19544059: length 0.9
  TOP w0.102: CC9.2 167.65,73.43 RC61.1
N19638635: length 2.9
  TOP w0.203: PU100.19 198.54,49.49 198.11,49.06 v1(197.96,49.06) 196.96,49.06 PR114.1
N19651849: length 0.9
  TOP w0.102: CE9.1 219.58,47.89 RE27.2
N19651850: length 6
  TOP w0.102: v2(225.45,52.78) 225.07,52.4 UE1.B19 ; v1(222.68,53.17) 222.36,53.49 v2(222.36,53.63) 222.24,53.5 RE24.1
  IN3 w0.122: v2(225.45,52.78) 225.1,53.12 222.87,53.12 v2(222.36,53.63)
N20106358: length 3.1
  TOP w0.102: UV7.27 214.79,85.03 214.59,84.84 214.12,84.84 213.94,85.01 v1(213.63,85.01) RV50.1
N20106372: length 4.6
  TOP w0.102: UV7.1 221.36,91.12 221.52,91.28 223.26,91.28 223.43,91.44 v1(223.43,91.48) 223.43,92.09 223.58,92.24 CV60.1
N20249193: length 8.4
  TOP w0.102: CA29.1 256.46,42.56 256.08,42.94 256.08,44.25 v1(256.76,44.92)
  TOP w0.203: UA1.35 259.17,39.37 258.88,39.66 257.42,39.66 257.16,39.92 257.16,41.25 CA29.1
N20249194: length 3.6
  TOP w0.203: UA1.36 258.77,39.19 258.69,39.28 257.04,39.28 256.46,39.85 CA29.2
N20249196: length 6
  TOP w0.203: UA1.31 260.77,39.46 260.56,39.67 260.56,40.16 259.84,40.88 v1(259.84,43.27) 259.7,43.41 CA25.1
N20249200: length 3.4
  TOP w0.102: CA27.1 RA12.1 264.47,28.36 264.92,27.9 264.92,26.98 264.82,26.88 v1(264.82,26.1)
N20249201: length 4.5
  TOP w0.102: v1(267.13,25.69) 267.13,26.14 266.12,27.15 266.12,27.98 265.72,28.37 RA13.1 CA28.1
N20249202: length 5.4
  TOP w0.102: 265.37,43.98 264.85,43.98 264.72,43.85 264.72,43.35 ; 265.37,43.98 265.71,44.32 266.59,44.32 RA21.2 267.37,44.78 267.37,45.5 v1(267.65,45.78) ; 265.37,43.98 QA2.6
N20249205: length 2
  TOP w0.102: RA17.2 CA33.1 261.24,28.24 v1(261.67,27.81)
N20249232: length 2.5
  BOTTOM w0.102: v1(273.27,37.55) 273.91,38.2 DA5.1 RA25.2
N20249233: length 2.6
  TOP w0.102: RA24.2 271.12,37.93 v1(271.96,37.1)
  TOP w0.254: DA4.1 RA24.2
N20249314: length 7.5
  TOP w0.102: v1(271.55,30.19) 271.55,29.46 270.89,28.81 QA3.3
  TOP w0.254: RA27.2 267.95,31.34 267.95,29.81 268.33,29.42 270.17,29.42 270.45,29.15 QA3.3
N20249315: length 1.4
  TOP w0.254: QA3.6 269.15,31.09 RA28.2
N20360585: length 2.7
  TOP w0.203: UA1.34 259.57,39.45 258.47,40.55 CA49.2
N20361305: length 4.4
  TOP w0.203: CA35.2 266.04,40.5 265.62,40.08 265.62,39.75 v1(265.2,39.33) 264.96,39.09 263.64,39.09 263.46,39.27 263.25,39.27 263.17,39.19 UA1.25
N20363962: length 4
  TOP w0.203: CA51.1 266.1,37.69 265.26,36.85 UA1.21
  TOP w0.254: CA51.1 266.57,37.05 266.56,37.03 RA44.1
N20363967:
  vias: v1(255.7,39.03)
N20363972: length 2.8
  TOP w0.102: CA53.1 261.17,31.08 UA1.7
N20711035: length 0.9
  BOTTOM w0.254: PC304.2 186.39,57.71 PR309.1
N20813044: length 117.6
  TOP w0.254: v2(19.38,40.51) PC809.2 PR818.1 18.75,39.64 PR822.1 v1(21.23,39.64) 21.73,39.64 22.6,38.77 PD813.1
  IN3 w0.254: v2(19.38,40.51) 18.36,39.5 18.36,18.57 21.3,15.63 32.48,15.63 33.98,14.13 47.41,14.13 51.87,18.59 92.09,18.59 94.29,16.4 v2(94.29,16.17)
  IN4 w0.254: v2(97.21,12.15) 97.21,13.25 v2(94.29,16.17)
  BOTTOM w0.254: PQ815.4 97.59,11.77 v2(97.21,12.15) ; PQ826.4 94.53,14.86 94.29,15.1 v2(94.29,16.17)
N20813052: length 106.6
  TOP w0.254: v2(17.2,39.47) 17.35,39.62 PR818.2 PC809.1
  IN3 w0.254: v2(94.25,13.25) 92.91,14.58 92.91,17.23 91.93,18.21 52.03,18.21 47.57,13.75 32.45,13.75 31.12,15.09 21.31,15.09 17.64,18.75 17.64,39.03 v2(17.2,39.47)
  vias: v1(93.61,12.45)
N20813067: length 4
  TOP w0.102: v1(36.54,29.04) PQ832.2
  TOP w0.254: PQ832.2 34.58,29.75 PR828.2
N20813069: length 7.1
  TOP w0.102: v1(32.37,30.26) 32.94,29.69 PQ832.1
  TOP w0.254: PQ832.1 33.01,29.31 PR830.2 34.39,28.69 34.91,28.17 36.25,28.17 36.51,27.9 PQ829.2
N20813073: length 4.4
  TOP w0.102: v1(37.57,23.18) 36.81,22.42 PD815.2
  TOP w0.254: PD815.2 36.4,23.28 35.55,24.13 PQ829.1
N20813075: length 4.7
  TOP w0.102: PR895.2 32.12,27.03 v1(32.5,26.64)
  TOP w0.254: PR895.2 PR830.1 33.27,28.04 34.4,28.04 34.58,27.86 PQ829.3
N20813085: length 5.2
  BOTTOM w0.102: v1(104.77,9.4) PQ810.4
  BOTTOM w0.254: PR811.1 106.85,9.44 107.3,9.89 PC807.2 106.96,10.71 PQ810.4
N20813089: length 2.3
  TOP w0.254: PR853.2 27.86,32.94 v1(28.18,32.61) PQ813.5
N20826302: length 3
  TOP w0.203: PR204.1 PC209.2 188.68,6.24 PU200.12
N20857922: length 11.5
  TOP w0.102: v2(32.87,12.23) 32.87,12.61 v1(33.05,12.79)
  TOP w0.254: PQ806.3 v2(32.87,12.23) ; PR815.2 PR816.1 v2(26.14,8.56)
  BOTTOM w0.254: v2(26.14,8.56) 28.22,10.64 31.28,10.64 v2(32.87,12.23)
N20862119: length 3.3
  BOTTOM w0.102: PR524.1 PR518.2 PR525.1 90.4,68.21 v1(91.16,68.97)
N20899585: length 3.2
  TOP w0.102: UV600.20 214.85,79.43 214.78,79.5 214.67,79.5 214.27,79.1 213.95,79.1 213.76,79.29 RV600.1
N20899609: length 5
  TOP w0.102: UV600.17 216.05,79.48 215.24,80.29 213.21,80.29 212.64,80.87 CV605.1
N20935195: length 4.5
  TOP w0.102: v1(57,5.23) 57,5.04 56.4,4.44 PR799.1
  TOP w0.203: PU700.21 53.7,5.54 54.01,5.23 55.26,5.23 PR799.1
N20987678: length 5.9
  TOP w0.254: PR827.2 27,35.11 26.61,35.5 PD817.1 25.64,35.5 25.37,35.76 v1(24.96,35.76) 24.54,35.76 24.3,35.52 PQ814.3
N20987955: length 12
  TOP w0.254: PQ806.5 33.52,10.03 33.72,10.24 34.04,10.24 34.17,10.11 PQ806.6 34.86,8.97 v1(34.86,8.33) v2(34.86,6.7) ; PR813.2 v2(28.71,6.93)
  IN3 w0.254: v2(34.86,6.7) 34.62,6.45 29.2,6.45 v2(28.71,6.93)
N20988471: length 5.6
  TOP w0.102: v1(12.2,40.17) PR819.1
  TOP w0.254: PU806.1 14.37,37.59 13.91,37.13 12.57,37.13 12.2,37.5 PQ817.6 PR819.1
N21132814: length 2.7
  BOTTOM w0.102: v1(206.32,87.49) 206.74,87.91 RZ36.1 207.12,89.08 QZ12.1
N21281743: length 1.4
  BOTTOM w0.102: CV116.1 207.12,81.42 207.2,81.34 UV13.12
N21281745: length 1.4
  BOTTOM w0.102: CV117.1 207.1,80.53 207.11,80.54 UV13.10
N21390508: length 2.1
  TOP w0.102: v1(146.95,100.9) R273.2 145.77,100.9 C319.1
N21390510: length 2
  BOTTOM w0.102: R41.2 C43.1 v1(137,98.28)
N21390512: length 1.9
  BOTTOM w0.102: C42.1 132.6,97.13 R6.2 133.44,97.6 v1(133.87,98.03)
N21414338: length 10.5
  TOP w0.102: v1(273.51,38.21) 273.11,38.21 272.72,38.61 272.72,39.8 RA1.2
  TOP w0.254: RA1.2 273.43,40.51 273.43,41.86 272.73,42.56 DA2.2 272.71,42.61 271.79,43.52 271.79,45.51 272.3,46.02 JHP1.5
N21423939: length 85
  TOP w0.081: RC2.2 148,55.09 148.76,55.09 149.65,54.2 149.65,53.05 v1(151.33,51.37)
  TOP w0.102: v2(185.34,48.11) 184.52,48.93 182.8,48.93 179.76,45.89 176.75,45.89 176.38,45.53 156.67,45.53 151.33,50.87 v1(151.33,51.37)
  BOTTOM w0.102: SW1.2 181.94,71.24 180.49,69.79 180.49,68.61 178.4,66.52 178.4,65.61 173,60.21 173,53.15 177.54,48.62 184.84,48.62 v2(185.34,48.11)
N21533765: length 4.3
  TOP w0.102: LV1.1 v2(61.2,76.45) 60.58,76.45 v1(60.26,76.77)
  BOTTOM w0.102: JEDP1.21 61.2,74.65 v2(61.2,76.45)
N21656651: length 1.4
  TOP w0.102: UZ8.12 45.22,26.8 45.33,26.91 CZ41.1
N21656676: length 1.4
  TOP w0.102: UZ8.10 45.33,26 45.38,25.96 CZ42.1
N21889651: length 3
  TOP w0.102: UZ7.12 181.14,53.75 181.09,53.7 CZ62.1 179.9,53.38 v1(179.24,52.72)
N21889653: length 4.5
  TOP w0.102: v1(177.51,55.26) 177.71,55.05 179.49,55.05 179.9,54.65 CZ60.1 180.02,54.71 180.73,54.71 180.9,54.54 UZ7.10
N22916358: length 3.4
  TOP w0.203: UA1.22 264.49,37.25 264.54,37.2 265.13,37.2 265.99,38.06 265.99,38.44 266.29,38.75 RA45.1
N23299527: length 2.6
  TOP w0.102: v1(80.3,96.2) 80.3,95.52 RI14.2 79.63,94.84 UI3.16
N24321023: length 14.1
  TOP w0.102: RE284.2 227.85,66.71 227.85,64.82 228.14,64.53 228.77,64.53 229.36,65.12 230.02,65.12 230.37,64.78 230.37,63.99 230.56,63.8 230.56,62.6 230.68,62.47 230.68,61.56 RE70.2 230.19,60.67 229.98,60.46 QE4.2 229.96,59.59 v1(228.59,58.22)
N24368370: length 1.1
  TOP w0.102: RV702.2 v1(194.11,73.27)
N24544483: length 17.8
  TOP w0.102: PR10.2 v1(76.94,82.74)
  TOP w0.254: PL3.1 75.81,92.12 74.93,93 PD5.2 PD5.3 76.86,91.99 76.02,91.15 76.02,90.66 76.34,90.35 76.61,90.35 78.18,88.77 PQ2.1 78.18,87.06 77.97,86.84 77.58,86.84 76.12,85.38 76.12,84.54 PR7.1 PR10.2
N24571981: length 4.3
  TOP w0.102: v1(158.65,10.55) 158.78,10.43 PQ1.2
  TOP w0.254: PC4.1 PR6.2 157.4,8.72 157.68,9 PQ1.2
N24571998: length 4.5
  TOP w0.102: v1(161.66,9.54) 160.86,8.74 PQ1.1
  TOP w0.254: PQ1.1 161.67,8.04 PD4.2
N24573405: length 2.3
  BOTTOM w0.102: v1(79.57,76.76) PR700.1
  BOTTOM w0.254: PR700.1 79.59,75.7 PQ700.4
N24606174: length 3.7
  TOP w0.254: PC309.1 188.24,57.82 188.49,58.08 v1(188.49,58.32) 188.49,58.52 188.19,58.83 v2(188.19,59.4)
  BOTTOM w0.254: PU300.5 188.59,60 188.19,59.6 v2(188.19,59.4)
N48705653: length 3
  TOP w0.254: PR7.2 75.18,84.51 PR9.1 75.18,85.78 75.42,86.02 75.84,86.02 76.1,86.27 PQ2.3
N48705663: length 13.9
  TOP w0.254: PQ3.2 71.09,87.81 71.36,87.54 71.36,86.08 70.8,85.52 PR12.2 69.74,83.74 69.74,82.18 v1(70.05,81.86) 70.35,81.57 73.77,81.57 75.16,82.96 PR10.1
N48705665: length 5.9
  TOP w0.254: PQ2.2 75.74,89.18 74.46,89.18 v1(74.12,88.84) 74.12,88.44 74.41,88.15 PR13.1 PR11.2 72.67,87.87 72.44,87.64 PQ3.1
N48708367: length 4
  TOP w0.102: v1(183.5,2.68) 184.11,3.29 PR210.2
  TOP w0.203: PU200.7 186.09,4.41 185.46,3.78 185.08,3.78 PR210.2
N48708425: length 2
  TOP w0.203: PR206.2 186.89,3.69 PU200.9
N48716673: length 3
  TOP w0.102: PR838.1 31.39,25.48 v1(31.55,25.63)
  TOP w0.254: PR838.1 30.36,25.46 PU800.28
N48716693: length 2.1
  TOP w0.254: PR845.1 32.77,22.35 PU800.26
N49522072: length 15
  TOP w0.102: PQ701.2 51.9,15.63 51.7,15.43 v1(48.93,15.43)
  TOP w0.254: PQ701.2 51.11,16.29 50.88,16.52 50.88,18.74 51.9,19.76 PQ702.2 51.9,20.64 50.48,22.06 49.34,22.06 PC700.2 47.6,22.96 PR702.2
N49522215: length 16.5
  TOP w0.102: PR706.2 52.12,25.56 52.57,26.01 53.33,26.01 v1(53.52,25.82)
  TOP w0.254: v2(53.07,19.98) 53.33,19.72 PQ703.1 54.73,19.72 55.17,19.28 55.17,18.14 54.85,17.82 PQ703.3 ; PR706.2 52.11,24.68 PR709.2 PR707.2 50.67,23.22 v2(49.52,23.22)
  IN1 w0.254: v2(53.07,19.98) 52.54,20.51 51.13,20.51 49.4,22.24 49.4,23.1 v2(49.52,23.22)
N49522242: length 5.5
  TOP w0.203: PU700.1 53.7,11.4 v2(53.64,11.47)
  TOP w0.254: v2(53.64,11.47) 53.61,11.5 PC702.2 53.61,12.71 PR705.1
  BOTTOM w0.102: v2(53.64,11.47) v1(54.61,11.47)
  BOTTOM w0.254: v2(53.64,11.47) 54.23,10.88 PC703.1
N49522275: length 4.3
  TOP w0.203: PU700.2 53.3,10.99 v1(53.21,11.07) v2(52.82,11.47)
  TOP w0.254: PR704.1 52.69,12.69 PC702.1 52.69,11.59 v2(52.82,11.47)
  BOTTOM w0.254: PC701.2 53.2,11.09 v2(52.82,11.47)
N49522729: length 11.9
  TOP w0.102: PQ701.1 47.89,17.26 v1(47.75,17.12)
  TOP w0.254: PQ701.1 49.82,18.43 v2(50.98,19.6)
  IN4 w0.254: v2(50.98,19.6) 50.86,19.48 50.86,16.26 v2(52.35,14.77)
  BOTTOM w0.254: PR701.2 52.83,14.41 52.48,14.77 v2(52.35,14.77)
N49522731: length 12.5
  TOP w0.102: PQ702.1 49.62,21.26 v1(47.87,19.51)
  TOP w0.254: PQ702.1 49.82,20.06 v2(50.28,19.6)
  IN4 w0.254: v2(50.28,19.6) 50.28,19.56 50.48,19.35 50.48,16.1 51.85,14.73 51.85,14.46 52.2,14.12 v2(52.39,14.12)
  BOTTOM w0.254: v2(52.39,14.12) 52.38,14.13 52.25,14.13 51.97,14.41 PR701.3
N61500733: length 3
  TOP w0.203: PR513.1 v1(86.22,73.64) 86.67,74.09 PU500.4
N61500909: length 5.1
  TOP w0.203: PU500.28 89.75,77.15 v2(89.69,77.22)
  TOP w0.254: PR526.1 90.22,78.21 89.69,77.67 v2(89.69,77.22)
  BOTTOM w0.102: v2(89.69,77.22) 89.65,77.25 89.65,77.79 v1(89.4,78.04)
  BOTTOM w0.254: v2(89.69,77.22) 89.69,77.15 89.78,77.06 PC510.2
N61500999: length 2.1
  TOP w0.102: v1(93.17,67.23) 93.4,67.01 PH501.2
  TOP w0.254: PR515.1 93.4,65.29 PH501.2
N61501245: length 13.9
  TOP w0.203: v2(90.74,70.52) 90.15,71.11 PU500.14
  TOP w0.254: PC501.1 91.17,70.09 v2(90.74,70.52)
  IN1 w0.254: v2(90.74,70.52) 89.86,69.63 v2(82.92,69.63)
  BOTTOM w0.102: v2(90.74,70.52) 90.81,70.52 91.21,70.12 v1(91.95,70.12)
  BOTTOM w0.254: v2(90.74,70.52) 90.59,70.68 PR505.2 ; PH500.2 v2(82.92,69.63)
N61501462: length 3.5
  TOP w0.203: PU500.16 90.95,71.46 91.32,71.09 92.3,71.09 v1(92.6,70.8) 92.95,70.45 PR511.2
N66971793: length 5.2
  TOP w0.102: PR105.2 205.24,46.35 v1(205.46,46.13)
  TOP w0.203: PR105.2 203.7,46.9 203,46.9 202.11,47.79 201.6,47.79 201.42,47.97 PU100.5
N66972075: length 3.5
  TOP w0.203: PU100.1 199.82,47.89 199.23,47.29 v1(198.48,47.29) 198.36,47.29 197.65,46.58 PR106.2
N78957489: length 3.1
  TOP w0.254: PQ816.1 18.92,37.24 18.43,37.73 v1(18.43,38.18) 18.43,38.52 18.63,38.72 PR822.2
N78967043: length 4.3
  TOP w0.254: PU806.4 17.13,36.29 17.36,36.52 v1(17.78,36.52) 18.2,36.52 18.43,36.29 20.78,36.29 PQ816.2
N78985854: length 5.7
  TOP w0.254: PU804.2 31.05,9.42 30.94,9.31 PR812.2 30.94,8.95 30.61,8.62 29.12,8.62 28.75,8.99 v1(28.75,9.6) 28.75,10.01 PR810.2
N79002827: length 4.6
  TOP w0.254: PU804.4 v1(31.7,13.22) 31.92,13.44 33.2,13.44 33.52,13.12 PQ806.2
N79023703: length 4
  TOP w0.102: v1(33.52,16.17) 33.2,16.48 PR863.1
  TOP w0.254: PU800.19 31.97,18.85 32.44,18.39 32.44,18.26 PR863.1
N79030038: length 5
  TOP w0.254: PQ813.2 28.18,28.8 28.37,28.61 28.83,28.61 ; 28.83,28.61 PQ813.3 ; 28.83,28.61 28.96,28.49 29.9,28.49 v1(30.09,28.68) 30.09,29.68 PR829.2
N79030087: length 3.8
  TOP w0.102: v1(26.1,30.38) 27.25,30.38 27.53,30.66 PQ813.6
  TOP w0.254: PQ813.6 27.53,32.19 PR826.2
N79030091: length 4.1
  TOP w0.102: PR826.1 26.08,31.98 v1(26.4,31.66)
  TOP w0.254: PQ814.2 25.06,32.23 25.55,32.73 PR826.1 PR827.1
N79030745: length 5.8
  TOP w0.102: v1(19.96,33.2) PQ814.1
  TOP w0.254: PD813.2 23.04,34.02 PQ814.1
N80905978: length 5.7
  BOTTOM w0.102: v1(92.38,96.88) 92.81,97.31 PC402.1
  BOTTOM w0.254: PR401.1 94.98,96.45 PR400.2 ; PR401.1 95.88,98.2 PU400.8 ; PR401.1 PC402.1
N80906026: length 4.6
  BOTTOM w0.102: PC403.2 v1(105.39,96.25)
  BOTTOM w0.254: PU400.2 102.62,96.93 102.86,97.17 PR403.1 PR402.2 PC403.2

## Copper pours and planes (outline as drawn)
1.5VSP on BOTTOM (solid shape): 103.05,95.61 104.51,95.61 104.57,95.54 104.57,95.1 103.37,93.89 102.86,93.89 102.22,93.26 102.22,92.81 102.16,92.75 101.65,92.75 101.65,92.24 102.22,92.24 102.22,91.86 102.03,91.67 100,91.67 99.81,91.86 99.81,93.76 100.76,94.72 100.76,95.71 101.04,95.99 102.67,95.99
1.35V_B+ on TOP (solid shape): 194.11,13.88 194.11,10.64 193.85,10.39 193.85,5.82 193.41,5.37 193.41,4.74 192.84,4.74 192.84,3.4 192.9,3.34 193.41,3.34 193.41,2.96 193.22,2.77 192.24,2.77 192.02,2.98 192.02,5.91 192.31,6.2 192.31,6.95 191.63,7.62 191.63,14.01 191.69,14.07 193.92,14.07
+0.9V_LAN on TOP (solid shape): 232.84,87.29 235.19,87.29 235.26,87.22 235.26,87.1 235.19,87.03 233.35,87.03 233.16,86.84 232.72,86.84 232.52,86.65 232.14,86.65 231.83,86.97 231.83,87.79 231.95,87.92 232.21,87.92
+0.9V_LAN on TOP (solid shape): 236.41,93.1 236.41,92.62 236.18,92.39 236.18,91.86 236.41,91.63 236.41,90.24 236.34,90.16 235.82,90.16 235.78,90.2 235.78,91.43 235.13,92.08 235.13,92.98 235.35,93.21 236.31,93.21
+0.9V_LAN on TOP (solid shape): 242.94,93.57 242.94,93.32 242.11,92.49 242.11,91.92 241.41,91.22 240.65,91.22 240.34,90.91 240.34,90.53 239.95,90.14 239.83,90.14 239.75,90.22 239.75,91.27 240.03,91.55 240.31,91.55 240.55,91.8 241.22,92.46 241.22,93.26 241.41,93.45 242.05,93.45 242.37,93.76 242.75,93.76
+0.9V_LAN on TOP (solid shape): 230.25,92.29 230.25,91.54 229.93,91.23 229.93,90.02 230.28,89.67 230.63,89.67 230.96,89.35 230.96,86.88 230.87,86.79 230.13,86.79 230.1,86.81 230.1,87.21 230.11,87.29 230.1,87.36 230.1,87.57 229.55,88.13 229.09,88.13 228.9,88.32 228.9,89.98 229.26,90.34 229.26,92.31 229.32,92.38 230.16,92.38
+0.9V_LAN on IN3 (solid shape): outline of 241 points within 229.41,80.96 241.18,92.47
+0.675V_DDR_VTT on TOP (solid shape): 181.53,9.31 181.53,8.29 181.34,8.1 180.39,8.1 180.2,8.29 180.2,9.25 180.39,9.44 181.41,9.44
+0.675V_DDR_VTT on TOP (solid shape): 201.47,25.65 201.47,22.8 201.16,22.49 201.16,20.77 200.75,20.36 199.7,20.36 199.5,20.55 199.5,23.92 199.88,24.3 199.88,25.38 200.21,25.71 201.41,25.71
+0.675V_DDR_VTT on TOP (solid shape): 122.11,25.64 122.11,22.77 121.37,22.03 121.37,20.39 121.85,19.92 121.85,18.96 121.59,18.7 120.58,18.7 120.35,18.93 120.35,19.69 120.05,19.99 120.05,23.16 120.48,23.6 120.48,25.59 120.68,25.8 121.95,25.8
+0.675V_DDR_VTT on BOTTOM (solid shape): 201.5,24.68 201.5,19.4 201.31,19.21 200.45,19.21 199.67,19.99 199.67,22.33 199.48,22.52 199.48,23.97 200.31,24.8 201.38,24.8
+0.675V_DDR_VTT on BOTTOM (solid shape): 121.58,26.43 121.58,20.57 121.9,20.25 121.9,16.74 121.67,16.51 121.13,16.51 120.91,16.74 120.91,18.64 120.02,19.53 120.02,23.6 120.6,24.18 120.6,26.9 120.67,26.97 121.04,26.97
+0.675V_DDR_VTT on IN2 (solid shape): 181.35,10.82 181.35,8.23 181.15,8.03 179.6,8.03 179.01,8.62 179.01,10.84 179.31,11.14 181.03,11.14
+0.675V_DDR_VTT on IN2 (solid shape): 121.96,24.17 121.96,21.42 123.76,19.62 123.76,18.67 123.35,18.26 121.91,18.26 119.92,20.25 119.92,24.14 120.18,24.4 121.73,24.4
+0.675V_DDR_VTT on IN3 (solid shape): 182,11.61 182,8.34 181.77,8.11 180.09,8.11 179.6,8.59 179.6,11.48 179.92,11.8 181.81,11.8
+0.675V_DDR_VTT on IN3 (solid shape): 201.51,24.41 201.51,21.07 201.77,20.81 201.77,19.37 201.62,19.21 200.37,19.21 199.68,19.89 199.68,24.18 200.3,24.8 201.12,24.8
+0.675V_P on TOP (solid shape): 185.79,8.67 185.79,7.85 185.66,7.72 184.46,7.72 184.33,7.59 184.33,7.28 184.46,7.15 185.34,7.15 185.41,7.09 185.41,6.96 185.34,6.9 183.99,6.9 183.16,6.07 182.04,6.07 181.72,6.39 181.72,8.55 182.3,8.55 182.3,9.05 181.72,9.05 181.72,9.31 181.79,9.37 185.09,9.37
+1.2V_LDO on TOP (solid shape): 256.02,14.71 256.15,14.58 256.46,14.58 256.59,14.45 256.59,14.2 256.46,14.07 255.32,14.07 255.32,14.96 256.02,14.96
+1.2V_LDO on TOP (solid shape): 264.13,22.4 264.13,22.08 263.94,21.89 262.61,21.89 261.28,20.56 261.28,19.77 261.23,19.72 261.12,19.72 261.07,19.77 261.07,20.91 261.59,21.43 261.59,22.46 261.72,22.59 263.94,22.59
+1.2V_LDO on TOP (solid shape): 265.54,21.5 265.54,20.04 265.51,20.01 264.85,20.01 264.06,19.21 263.26,19.21 263.2,19.28 263.2,19.56 263.28,19.64 263.37,19.64 264.22,20.49 264.22,21.17 264.21,21.18 264.21,21.44 264.34,21.56 265.48,21.56
+1.2V_LDO on TOP (solid shape): 266.67,17.51 266.67,17.32 266.42,17.06 266.42,16.49 266.1,16.17 265.85,16.17 265.72,16.05 265.72,15.86 265.59,15.73 265.14,15.73 264.91,15.96 264.12,15.96 264.04,16.03 263.23,16.03 263.18,16.09 263.18,16.19 263.23,16.24 264.17,16.24 264.22,16.19 265.29,16.19 265.49,16.39 265.49,16.82 265.31,17 265.06,17 264.83,17.23 263.23,17.23 263.18,17.28 263.18,17.36 263.26,17.43 265.44,17.43 265.62,17.25 265.98,17.25 266.36,17.63 266.55,17.63
+1.2V_LDO on IN2 (solid shape): outline of 325 points within 255.75,13.95 266.79,22.65
+1.05V_M on TOP (solid shape): 97.21,58.9 97.21,56.26 97.1,56.16 95.4,56.16 95.17,56.39 95.17,57.9 96.25,58.98 97.12,58.98
+1.05V_M on TOP (solid shape): 143.31,70.14 144.58,70.14 144.64,70.08 144.64,69.51 144.45,69.32 144.45,69.01 144.33,68.88 144.06,68.88 143.94,69 143.94,69.44 143.82,69.57 143.37,69.57 143.18,69.38 143.18,69 143.05,68.87 142.86,68.87 142.74,69 142.74,69.32 142.55,69.51 142.16,69.51 142.1,69.57 142.1,70.14 142.23,70.27 143.18,70.27
+1.05V_M on TOP (solid shape): 185.47,52.53 185.47,52.17 184.62,51.32 184.62,51.32 184.23,50.96 184.62,50.61 184.62,50.2 184.43,50.01 182.06,50.01 180.58,48.53 179.6,48.53 179.54,48.59 179.54,50.11 180.76,51.33 182.92,51.33 183.25,51.66 183.25,53.38 183.38,53.5 184.5,53.5
+1.05V_M on TOP (solid shape): outline of 177 points within 146.77,90.74 153.6,97.15
+1.05V_M on BOTTOM (solid shape): outline of 260 points within 179.31,51.47 187.31,62.39
+1.05V_M on IN2 (solid shape): outline of 1954 points within 150.61,58.58 183.34,91.9
+1.05V_M on IN3 (solid shape): 96.48,56.89 96.48,55.65 96.35,55.52 95.33,55.52 95.12,55.73 95.12,56.92 95.2,57.01 96.36,57.01
+1.05V_M on IN3 (solid shape): 185.47,52.46 185.47,52.11 184.84,51.47 184.2,51.47 183.69,50.96 182.93,50.96 182.23,51.66 183.94,53.37 184.56,53.37
+1.05V_M on IN3 (solid shape): outline of 2534 points within 142.71,56.46 183.06,72.68
+1.05V_MODPHY on TOP (solid shape): outline of 81 points within 140.57,88.75 146.77,94.63
+1.05V_MODPHY_PCH on BOTTOM (solid shape): 146.46,77.59 146.46,77.57 146.46,77.51 146.48,77.44 146.48,76.66 146.38,76.44 146.48,76.22 146.48,75.93 146.43,75.88 146.43,75.87 146.23,75.67 146.03,75.67 145.67,75.79 145.45,75.49 145.45,75.47 145.21,75.22 144.64,75.22 144.32,75.54 144.32,76.3 144.45,76.43 144.52,76.46 144.6,76.42 144.96,76.34 145.15,76.66 145.18,76.74 145.27,76.76 145.55,76.87 145.62,77.16 145.64,77.25 145.73,77.28 145.97,77.35 146.06,77.59 146.09,77.66 146.16,77.7 146.36,77.7
+1.05V_MODPHY_PCH on TOP: 144.58,75.22 144.34,75.46 144.34,76.31 145.64,77.61 145.64,77.86 145.61,78.07 145.47,78.22 145.47,79.55 145.5,79.56 145.73,79.81 145.6,80.13 145.57,80.16 145.55,80.21 145.73,80.55 145.49,80.86 145.47,80.86 145.47,83.29 145.67,83.49 145.69,83.48 145.98,83.57 146.07,83.85 146.06,83.88 146.25,84.07 146.25,88.59 146.27,88.61 146.9,88.61 146.91,88.62 146.91,89.14 146.9,89.15 146.37,89.15 146.36,89.17 146.36,89.34 146.86,89.34 146.9,89.38 146.9,89.83 148.16,89.83 148.2,89.79 148.2,82.62 147.91,82.33 147.91,81.79 147.89,81.78 147.69,81.49 147.88,81.2 147.91,81.19 147.91,80.65 147.91,80.64 147.89,80.52 147.91,80.4 147.91,80.39 147.91,79.24 147.9,79.17 147.91,79.11 147.91,78.65 147.9,78.64 147.87,78.49 147.9,78.34 147.91,78.33 147.91,77.96 147.91,77.95 147.89,77.84 147.91,77.72 147.91,77.72 147.91,77.54 147.66,77.29 146.7,77.29 146.45,77.04 146.45,76.65 146.04,76.24 145.54,76.24 145.4,76.24 145.34,76.17 145.34,75.41 145.15,75.22
+1.05V_MP on TOP (solid shape): 189.28,70.14 189.28,67.28 189.03,67.03 187.25,67.03 187.12,67.16 187.12,70.33 187.25,70.46 188.96,70.46
+1.05V_MP on BOTTOM (solid shape): 193.22,70 193.22,66.49 192.81,66.08 188.9,66.08 188.39,65.57 188.39,62.9 188.22,62.73 187.84,62.73 187.69,62.59 184.77,62.59 184.55,62.81 184.55,63.63 184.96,64.05 186.26,64.05 187.15,64.93 187.15,68.33 187.76,68.94 187.76,69.7 188.16,70.1 193.12,70.1
+1.05V_MP on IN1 (solid shape): 190.04,69.63 190.04,64.83 188.16,62.94 186.74,62.94 186.49,63.2 186.49,64.11 187.5,65.13 187.5,69.76 187.88,70.14 189.54,70.14
+1.5V_RUN on TOP (solid shape): 253.52,39.04 253.52,38.09 253.45,38.02 252.31,38.02 252.26,38.07 252.26,39.02 252.33,39.09 253.47,39.09
+1.05V_RUN on TOP (solid shape): 147.05,76.11 147.05,75.73 146.8,75.48 145.59,75.48 145.53,75.54 145.53,76.05 145.59,76.11 146.1,76.11 146.23,76.24 146.93,76.24
+1.05V_RUN on TOP (solid shape): 144.7,78.78 144.7,77.89 144.26,77.44 144.26,76.68 144.2,76.62 143.69,76.62 143.62,76.68 143.62,77.57 144.13,78.08 144.13,78.78 144.26,78.9 144.58,78.9
+1.05V_RUN on TOP (solid shape): 163.1,56.66 165.89,56.66 166.77,55.78 167.47,55.78 167.96,56.27 173.63,56.27 175.09,54.8 175.09,53.77 177.16,51.7 177.85,51.7 178.3,51.26 178.3,47.54 178.04,47.28 175.35,47.28 172.74,49.89 170.72,51.9 162.23,51.9 160.59,53.55 159.25,53.55 159.13,53.68 159.13,54.05 158.62,54.56 158.62,54.92 158.63,54.93 158.65,55.01 158.66,55.1 158.66,55.54 158.66,55.72 158.02,56.36 158.02,56.82 158.27,57.07 162.69,57.07
+1.05V_RUN on TOP (solid shape): 128.45,90.81 128.76,90.37 129.3,90.39 129.4,90.34 129.5,90.32 129.73,90.33 129.94,90.43 130.19,90.36 130.42,90.47 130.75,90.33 131.1,90.41 131.63,90.38 131.94,90.8 131.95,90.84 133.06,90.84 133.77,90.13 133.77,89.67 133.45,89.36 133.11,89.36 133.11,89.9 132.68,89.9 132.68,89.36 130.92,89.36 130.76,89.2 129.67,89.2 129.65,89.23 129.26,89.41 128.98,89.08 128.77,88.87 126.42,88.87 126.17,89.12 126.17,90.45 126.57,90.84 128.45,90.84
+1.5V_RUN on BOTTOM (solid shape): 103.94,93.38 103.94,92.11 103.62,91.8 102.6,91.8 102.41,91.99 102.41,93.19 102.79,93.57 103.75,93.57
+1.05V_RUN on BOTTOM (solid shape): 139.74,92.63 139.74,90.85 139.43,90.54 138.09,90.54 137.95,90.68 137.95,91.54 138.64,92.23 138.64,92.48 138.88,92.72 139.65,92.72
+1.05V_RUN on BOTTOM (solid shape): 209.54,83.6 210.05,83.6 210.11,83.67 210.11,84.11 210.74,84.11 210.93,83.92 210.93,81.95 210.62,81.64 209.41,81.64 209.35,81.7 209.35,82.71 209.16,82.91 209.16,83.98 209.28,84.11 209.54,84.11
+1.05V_RUN on BOTTOM (solid shape): 154.86,91.1 154.86,88.94 154.67,88.75 153.34,88.75 153.24,88.84 153.24,89.95 152.71,90.49 152.71,90.84 152.94,91.07 152.95,91.08 153.08,91.16 153.17,91.3 153.17,91.31 153.59,91.73 154.23,91.73
+1.05V_RUN on BOTTOM (solid shape): 133.47,92.62 133.47,91.39 133.28,91.2 131.6,91.2 131.59,91.19 131.57,91.19 131.4,91.24 131.22,91.2 131.21,91.19 130.99,91.19 130.97,91.2 130.81,91.24 130.64,91.2 130.63,91.19 129.74,91.19 129.73,91.2 129.54,91.22 129.36,91.14 129.3,91.12 129.23,91.14 128.72,91.08 128.82,90.56 128.87,90.49 128.84,90.41 128.81,90.38 128.81,88.82 128.72,88.73 126.8,88.73 126.56,88.98 126.56,91.43 127.88,92.75 133.34,92.75
+1.05V_RUN on IN2 (solid shape): outline of 2159 points within 137.93,67.42 147.12,91.42
+1.05V_RUN on IN3 (solid shape): 210.91,83.53 210.91,81.83 210.71,81.63 209.7,81.63 208.86,82.48 208.86,83.74 209.08,83.96 210.47,83.96
+1.5V_RUN on IN3 (solid shape): 253.87,39.18 253.87,38.03 253.76,37.93 252.34,37.93 252.2,38.07 252.2,39.2 252.3,39.31 253.74,39.31
+1.5V_RUN on IN3 (solid shape): 105.02,93.93 105.02,93.12 104.79,92.89 102.71,92.89 102.64,92.95 102.64,93.99 102.72,94.06 104.89,94.06
+1.05V_RUN on IN3 (solid shape): outline of 473 points within 185.57,84.89 196.58,87.73
+1.05V_RUN on IN3 (solid shape): outline of 1899 points within 112.74,77.5 154.64,91.78
+1.05V_RUN on TOP: 146.41,92.14 147.33,92.14 147.64,91.83 147.86,91.83 148,91.69 148,90.64 147.66,90.31 146.92,90.31 146.38,90.85 146.38,92.11
+1.05V_RUN on VCC: 148.83,54.46 148.83,55.96 142.93,61.86 142.93,65.48 141.13,67.28 138.54,67.28 138.54,79.22 150.63,79.22 162.55,67.31 162.55,54.75 162.25,54.46
+1.5V_RUN_AUDIO on TOP (solid shape): 257.21,36.96 258.31,36.96 258.36,36.91 258.36,36.8 258.31,36.75 257.11,36.75 256.86,37.01 256.43,37.01 256.25,37.19 256.25,37.44 256.32,37.52 256.65,37.52
+1.05V_RUN_UZ7 on TOP (solid shape): 181.98,53.38 181.98,51.65 181.92,51.59 180.72,51.59 179.69,50.57 179.24,50.57 179.11,50.7 179.11,51.97 180.58,53.44 181.92,53.44
+1.05V_RUN_VMM on BOTTOM (solid shape): 209.35,84.98 210.26,84.98 210.36,84.87 210.36,84.35 210.34,84.33 204.6,84.33 204.18,83.91 204.18,83.07 204.19,83.06 204.19,82.31 203.87,82 202.65,82 202.53,82.13 202.53,83.23 201.85,83.91 201.85,85.01 202.09,85.25 209.08,85.25
+1.05V_VCCST on TOP (solid shape): 133.41,89.2 133.41,87.18 133.26,87.04 132.44,87.04 132.33,87.16 132.33,89.18 132.37,89.22 133.39,89.22
+1.5V_VIN on BOTTOM (solid shape): 100.45,97.76 100.45,94.78 99.43,93.76 96.89,93.76 96.38,93.26 96.38,92.18 96.13,91.92 95.24,91.92 94.86,92.3 94.86,93.69 94.79,93.76 93.52,93.76 93.4,93.88 93.4,94.28 93.5,94.38 95.48,94.38 95.81,94.72 97.46,94.72 97.9,95.16 97.9,97.76 98.03,97.89 100.32,97.89
+1.05V_VMM_UV10 on BOTTOM (solid shape): 208.16,83.56 208.16,82.61 208.07,82.52 208.07,81.69 208.02,81.64 207.32,81.64 207.3,81.66 207.3,81.76 207.33,81.79 207.33,82.08 207.18,82.23 206.71,82.23 206.45,81.97 206.1,81.97 206.02,82.04 206.02,83.44 206.2,83.62 208.11,83.62
+1.05V_VMM_VDD on BOTTOM (solid shape): outline of 333 points within 191.1,79.5 203.95,82.77
+1.05V_VMM_VDD on IN1 (solid shape): outline of 709 points within 192.13,77.53 199.64,83.4
+1.05V_VMM_VDD on IN3: 200.18,77.66 198.57,76.04 197.11,76.04 197.1,76.09 196.93,76.34 196.63,76.37 196.54,76.38 196.49,76.46 196.21,76.81 195.81,76.61 195.8,76.57 195.6,76.58 195.34,76.58 195.02,76.58 194.97,76.57 194.12,76.57 194.03,76.62 194.02,76.71 193.7,77.22 193.38,76.71 193.37,76.62 193.28,76.57 192.7,76.57 192.39,76.75 192.09,76.57 191.15,76.57 190.03,77.7 190.03,80.47 190.06,80.48 190.2,80.6 190.27,80.78 190.26,80.92 190.19,81.04 190.13,81.1 190.06,81.14 190.03,81.15 190.03,83.02 190.15,83.29 190.03,83.55 190.03,84.58 190.49,85.05 191.53,85.05 192.31,85.83 192.45,85.96 195.35,85.96 196.33,84.98 196.36,84.88 196.28,84.81 196,84.57 196.09,84.21 196.11,84.14 196.09,84.07 195.98,83.81 196.09,83.56 196.11,83.49 196.09,83.42 196.08,82.91 196.59,82.91 196.66,82.94 196.73,82.91 196.99,82.81 197.24,82.91 197.31,82.94 197.38,82.91 197.39,82.91 197.41,82.86 197.41,82.8 197.99,82.8 198.72,83.53 199.8,83.53 200.18,83.14
+1.05V_VMM_VDDTX on BOTTOM (solid shape): 195.28,84.61 195.28,83.69 195.13,83.53 194.14,83.53 194.03,83.43 194.03,82.95 193.97,82.9 193.55,82.9 193.46,82.98 193.46,84.02 193.67,84.23 193.67,84.7 193.83,84.86 195.04,84.86
+1.05V_VMM_VDDTX on BOTTOM (solid shape): 201.57,84.65 201.57,83.71 201.32,83.46 200.36,83.46 200.09,83.19 200.09,82.51 200,82.42 199.27,82.42 199.15,82.3 198.79,82.3 198.67,82.42 198.67,82.66 198.79,82.78 198.99,82.78 199.17,82.89 199.19,82.91 199.28,83.08 199.28,83.27 199.54,83.53 199.54,84.35 199.67,84.48 200.54,84.48 200.54,84.48 200.84,84.48 201.05,84.69 201.54,84.69
+1.05V_VMM_VDDTX on IN2: outline of 117 points within 190.06,76.35 201,85.95
+1.8V_RUN_CARD on TOP (solid shape): 264.72,13 264.72,11.21 264.59,11.09 263.96,11.09 263.83,11.21 263.83,12.55 262.67,13.7 262.67,14.46 262.74,14.52 263.2,14.52
+1.35V_MEM on TOP: outline of 239 points within 76.92,13.94 202.43,72.3 ; 7 cut-outs
+1.35V_MEN_P on TOP (solid shape): 191.5,13.37 191.5,12.36 191.38,12.23 190.81,12.23 190.68,12.36 190.68,13.44 190.74,13.5 191.38,13.5
+1.35V_MEN_P on TOP (solid shape): 204.29,19.31 204.29,15.49 204.53,15.25 204.53,12.81 204.27,12.55 198.87,12.55 198.3,13.12 198.3,14.07 201.54,14.07 202.62,15.15 202.62,20.41 202.68,20.47 203.14,20.47
+1.35V_MEN_P on BOTTOM (solid shape): outline of 87 points within 198.68,8.42 205.79,14.39
+3.3V_ALW on TOP (solid shape): 43.1,27.98 43.1,27.22 42.98,27.09 41.45,27.09 41.39,27.15 41.39,28.04 41.58,28.23 42.85,28.23
+3.3V_ALW on TOP (solid shape): 202.29,38.6 202.29,37.57 202.2,37.48 201.68,37.48 201.09,38.08 201.09,38.71 201.16,38.77 202.11,38.77
+3.3V_ALW on TOP (solid shape): 199.7,38.71 199.7,38.07 199.65,38.03 199.54,38.03 199.03,37.53 198.64,37.53 198.55,37.62 198.55,38.46 198.87,38.77 199.63,38.77
+3.3V_ALW on TOP (solid shape): 206.55,70.65 206.55,70.14 207.06,69.63 207.06,67.86 206.81,67.6 204.33,67.6 204.01,67.92 204.01,69.51 205.22,70.71 206.49,70.71
+3.3V_ALW on TOP (solid shape): 239.53,50.26 239.53,49.41 239.3,49.18 236.97,49.18 236.94,49.21 236.94,49.47 236.96,49.49 237.49,49.49 237.52,49.51 237.52,49.98 237.51,49.99 236.99,49.99 236.95,50.03 236.95,50.33 236.99,50.38 239.41,50.38
+3.3V_ALW on TOP (solid shape): 251.48,62.13 253.33,62.13 253.59,61.86 253.59,59.54 253.47,59.42 252.2,59.42 252.2,59.67 252.77,59.67 252.77,60.18 252.2,60.18 252.2,60.75 251.94,61.01 250.48,61.01 250.48,62.4 250.48,62.44 250.56,62.51 251.1,62.51
+3.3V_ALW on TOP (solid shape): outline of 136 points within 183.25,54.84 190.04,59.73
+3.3V_ALW on BOTTOM (solid shape): 208.71,70.01 208.71,67.86 208.52,67.67 207.95,67.67 207.95,68.24 205.98,68.24 205.92,68.17 205.92,67.67 204.58,67.67 204.27,67.98 204.27,69.89 204.55,70.17 208.56,70.17
+3.3V_ALW on BOTTOM (solid shape): 189.73,60.17 189.73,59.17 189.73,59.17 189.73,58.84 189.74,58.83 189.74,58.27 189.63,58.16 189.05,58.16 188.95,58.07 188.95,57.35 189.04,57.26 189.06,57.26 189.79,56.53 189.79,56.2 190.09,55.9 190.09,55.01 190.07,54.98 190.01,54.92 188.17,54.92 187.96,55.13 187.96,58.34 188.25,58.63 188.94,58.63 189.41,59.09 189.41,60.17 189.47,60.24 189.66,60.24
+3.3V_ALW on BOTTOM (solid shape): 59.11,57.63 59.11,55.32 59.09,55.28 59.08,55.23 59.07,55.18 59.07,55.13 59.08,55.08 59.09,55.03 59.11,54.99 59.11,54.71 58.48,54.09 53.3,54.09 52.82,54.57 52.82,56.3 53.39,56.87 55.61,56.87 56.08,57.34 57.35,57.34 57.35,57.29 57.36,57.24 57.38,57.18 57.4,57.14 57.43,57.09 57.47,57.05 57.51,57.02 57.55,56.99 57.6,56.97 57.66,56.96 57.71,56.96 57.76,56.96 57.81,56.97 57.86,56.99 57.91,57.02 57.95,57.05 57.99,57.09 58.02,57.14 58.04,57.18 58.06,57.24 58.06,57.29 58.06,57.34 58.06,57.39 58.04,57.44 58.02,57.49 57.99,57.54 57.95,57.58 57.91,57.61 57.86,57.64 57.81,57.66 57.76,57.67 57.71,57.67 57.66,57.67 57.6,57.66 57.55,57.64 57.51,57.61 57.47,57.58 57.43,57.54 57.4,57.49 57.38,57.44 57.36,57.39 57.35,57.34 56.08,57.34 56.63,57.89 58.85,57.89
+3.3V_ALW on BOTTOM (solid shape): outline of 788 points within 195.69,37.43 209.92,47.79
+3.3V_ALW on IN4 (solid shape): 55.46,56.35 55.46,53.03 55.26,52.84 53.47,52.84 53.23,53.08 53.23,56.47 53.44,56.68 55.12,56.68
+3.3V_ALW on IN4 (solid shape): 112.07,12.67 112.07,10.77 110.35,9.05 108.13,9.05 107.81,9.37 107.81,11.66 109.4,13.25 111.49,13.25
+3.3V_ALW on IN4 (solid shape): outline of 2022 points within 28.15,6.83 66.6,46.6
+3.3V_ALW on TOP: 49.11,71.18 51.5,71.18 51.87,70.81 51.87,68.82 52.37,68.32 52.37,58.77 54.79,56.35 54.79,54.88 54.65,54.74 54.14,54.74 50.79,58.09 50.79,69.79 50.42,70.15 49.03,70.15 48.92,70.27 48.92,70.99
+3.3V_ALW on VCC: outline of 93 points within 107.68,1.22 282.88,74.65
+3.3V_ALW_PCH on TOP (solid shape): 178.85,52.85 178.85,52.03 178.66,51.84 177.42,51.84 176.79,52.47 176.79,52.97 177.04,53.22 178.47,53.22
+3.3V_ALW_PCH on TOP (solid shape): 180.52,58.19 180.52,56.94 180.36,56.78 178.54,56.78 178.38,56.94 178.38,58.3 178.4,58.32 180.39,58.32
+3.3V_ALW_PCH on TOP (solid shape): 166.61,65.76 166.61,61.5 166.23,61.12 164.96,61.12 164.82,61.26 164.82,65.94 164.95,66.07 166.29,66.07
+3.3V_ALW_PCH on TOP (solid shape): 143.5,72.36 144.14,72.36 144.85,71.65 145.3,71.65 145.37,71.58 145.37,71.18 145.29,71.09 144.73,71.09 144.73,71.11 143.99,71.11 143.37,71.73 142.04,71.73 141.91,71.6 141.91,69.75 141.61,69.45 141.2,69.45 140.82,69.07 139.57,69.07 139.52,69.12 139.52,69.71 139.7,69.9 140.43,69.9 140.86,70.32 140.86,72.27 141.21,72.62 141.97,72.62 143.24,72.62
+3.3V_ALW_PCH on BOTTOM (solid shape): 159.85,69.02 160.13,69.02 160.26,68.9 160.26,67.73 160.01,67.47 158.98,67.47 158.84,67.61 158.84,69.3 158.93,69.39 159.49,69.39
+3.3V_ALW_PCH on BOTTOM (solid shape): 166.07,71.77 166.07,71.75 166.17,71.54 166.38,71.44 166.4,71.44 166.44,71.4 166.44,70.34 166.31,70.21 166.31,70.01 166.28,69.94 166.21,69.91 165.87,69.67 165.99,69.27 166.03,69.2 166,69.12 165.74,68.87 165.74,66.83 166.31,66.26 166.31,62.65 166.13,62.47 165.99,62.47 165.99,62.47 165.46,62.47 165.06,62.86 165.06,64.07 164.71,64.42 164.71,71.39 164.9,71.58 165.43,71.58 165.7,71.86 165.98,71.86
+3.3V_ALW_PCH on IN3 (solid shape): 152.63,55.31 152.63,53.63 152.52,53.53 148.86,53.53 148.57,53.82 148.57,55.28 148.84,55.55 152.39,55.55
+3.3V_ALW_PCH on IN3 (solid shape): 178.99,52.8 178.99,51.95 178.85,51.8 177.11,51.8 176.83,52.08 176.83,52.92 176.93,53.02 178.78,53.02
+3.3V_ALW_PCH on IN3 (solid shape): 166.95,65.48 166.95,62.49 166.8,62.34 165.28,62.34 165,62.61 165,65.14 165.69,65.82 166.6,65.82
+3.3V_ALW_PCH on IN3 (solid shape): outline of 87 points within 140.27,66.59 143.07,70.09
+3.3V_ALW_PCH_UZ7 on TOP (solid shape): 181.98,56.74 181.98,54.9 181.92,54.84 180.9,54.84 180.51,55.23 178.54,55.23 178.49,55.28 178.49,56.49 178.61,56.62 179.31,56.62 179.31,56.04 179.82,56.04 179.82,56.62 180.52,56.62 180.84,56.93 181.79,56.93
+3.3V_ALW_UE1 on TOP (solid shape): 236.81,50.58 236.81,49.27 236.81,49.26 236.81,49.16 236.82,49.15 236.82,49.1 236.87,49.1 236.92,49.05 237.02,49.05 237.1,48.98 237.1,47.8 237.03,47.73 236,47.73 235.59,48.14 235.59,50.6 235.83,50.84 236.55,50.84
+3.3V_ALW_UE2 on TOP (solid shape): 248.45,64.24 250.1,64.24 250.16,64.18 250.16,62.78 250.1,62.72 249.4,62.72 248.29,63.83 247.91,63.83 247.79,63.95 247.05,63.95 247,64 247,64.18 247.06,64.24 248.45,64.24
+3.3V_ALW_UE2 on TOP (solid shape): 234.61,65.2 234.91,65.2 235.08,65.14 235.25,65.17 235.6,64.82 236.71,64.82 236.84,64.69 236.84,64.56 236.74,64.46 235.98,64.46 235.95,64.5 235.19,64.5 235.16,64.46 235.04,64.46 234.96,64.39 234.89,64.39 234.82,64.37 234.14,64.37 233.94,64.57 233.94,65.09 234.05,65.2 234.61,65.2
+3.3V_ALW_UE2 on TOP (solid shape): 248.39,61.2 249,61.2 249.38,60.81 251.88,60.81 252.01,60.69 252.01,59.48 249.66,59.48 249.53,59.61 249.53,59.65 249.51,59.67 249.51,59.69 249.43,59.97 249.16,60.09 249.14,60.09 248.44,60.78 248.4,60.78 248.37,60.81 247.88,60.81 247.75,60.94 247.05,60.94 246.99,61.01 246.99,61.2 247.05,61.26 248.32,61.26
+3.3V_ALWP on BOTTOM (solid shape): 210.33,65.86 213.25,65.86 214.17,64.93 214.17,61.06 213.97,60.85 210.19,60.85 208.39,62.65 204.08,62.65 203.8,62.93 203.8,65.73 205.54,67.47 208.71,67.47
+3.3V_HDD on TOP (solid shape): 46.05,22.93 46.05,21.02 45.71,20.68 43.51,20.68 42.68,19.85 42.68,9.58 41.57,8.47 41.57,7.52 41.07,7.02 39.29,7.02 38.98,7.34 38.98,9.12 40.14,10.28 40.14,21.94 41.21,23.01 45.98,23.01
+3.3V_HDD on BOTTOM (solid shape): 41.03,32.34 41.03,31.32 40.84,31.14 39.08,31.14 38.82,31.4 38.82,32.39 39.07,32.64 40.73,32.64
+3.3V_HDD on BOTTOM (solid shape): 41.32,8.4 41.32,7.43 41.06,7.18 39.02,7.18 38.75,7.45 38.75,8.45 38.89,8.58 41.14,8.58
+3.3V_HDD on BOTTOM (solid shape): 49.3,13.52 49.3,12.54 49.09,12.33 45.33,12.33 45.06,12.61 45.06,13.58 45.24,13.76 49.06,13.76
+3.3V_HDD on BOTTOM (solid shape): 42.18,19.92 42.18,19.31 41.94,19.07 41.42,19.07 41.36,19.13 39.08,19.13 38.95,19.26 38.95,19.68 39.04,19.77 40.91,19.77 41.22,20.08 42.03,20.08
+3.3V_HDD on IN2 (solid shape): 41.37,32.66 41.37,30.04 41.23,29.9 39.36,29.9 39.13,30.12 39.13,32.59 39.32,32.78 41.25,32.78
+3.3V_HDD on IN2 (solid shape): 42.21,20.85 42.21,19.11 41.95,18.85 39.31,18.85 38.67,19.49 38.67,20.86 39.1,21.29 41.78,21.29
+3.3V_HDD on IN3 (solid shape): outline of 179 points within 37.78,7.07 47.19,13.08
+3.3V_HDD_UZ8 on TOP (solid shape): 45.58,25.44 46.34,25.44 46.53,25.25 46.53,23.34 46.34,23.15 45.71,23.15 45.71,23.72 45.2,23.72 45.2,23.15 44.56,23.15 44.31,23.41 44.31,25.69 44.37,25.76 45.26,25.76
+3.3V_LAN on TOP (solid shape): 195.95,44.74 195.95,44.17 196.5,43.62 198.03,43.62 198.18,43.48 198.18,42.58 198.1,42.5 197.74,42.5 197.7,42.54 197.7,43.03 197.65,43.08 197.24,43.08 197.21,43.04 197.21,42.56 197.16,42.52 195.69,42.52 195.28,42.92 195.28,44.61 195.54,44.87 195.82,44.87
+3.3V_LAN on IN2 (solid shape): 250.31,77.85 255.99,77.85 256.28,77.57 256.28,76.27 256.02,76.01 253.83,76.01 253.51,76.34 252.64,76.34 252.47,76.16 252.47,75.86 252.33,75.73 251.52,75.73 251.31,75.52 251.3,75.52 251.1,75.42 251,75.22 251,75.21 250.83,75.04 250.48,75.04 250.27,75.25 250.27,75.26 250.07,75.46 249.78,75.45 249.77,75.44 249.52,75.44 249.51,75.45 249.19,75.45 249,75.19 249,75.18 248.71,74.89 248.25,74.89 248.08,75.06 248.08,76.34 246.35,78.07 246.32,78.18 246.41,78.24 246.62,78.85 246.01,78.64 245.95,78.55 245.84,78.58 245.56,78.86 245.56,80.61 245.83,80.87 247.28,80.87
+3.3V_LAN on IN2 (solid shape): outline of 878 points within 229.75,86.91 243.97,96.39
+3.3V_LAN_OUT on TOP (solid shape): 232.81,92.84 232.81,92.27 233.55,91.54 233.58,91.47 233.55,91.39 233.46,91.1 233.64,90.85 233.64,89.36 234.02,88.98 234.12,88.88 235.21,88.88 235.28,88.81 235.28,88.3 235.24,88.25 233.88,88.25 232.75,89.38 232.75,90.25 232.4,90.6 232.07,90.6 231.9,90.76 231.9,92.95 231.95,92.99 232.67,92.99
+3.3V_LAN_OUT on BOTTOM: 232.69,91.91 233.29,91.91 233.49,91.71 233.49,90.86 233.55,90.79 234.1,90.79 234.65,91.34 236.4,91.34 236.75,90.98 236.75,88.62 236.59,88.45 236.59,85.88 236.84,85.62 239.05,85.62 240.83,87.4 242.24,87.4 242.42,87.22 242.42,85.57 239.5,82.65 235.51,82.65 235.1,83.06 235.1,84.09 235.56,84.54 235.56,88.76 235.88,89.08 235.88,89.94 235.72,90.09 235.42,90.09 234.9,89.57 232.91,89.57 232.6,89.88 232.6,91.82
+3.3V_LAN_UL3 on TOP (solid shape): 197.55,42.89 197.55,42.37 197.57,42.35 199.35,42.35 199.43,42.27 199.43,41.16 199.7,40.88 199.7,40.11 199.64,40.05 197.69,40.05 196.96,40.78 196.96,42.35 196.98,42.37 197.32,42.37 197.38,42.42 197.38,42.89 197.4,42.91 197.54,42.91
+3.3V_M on TOP (solid shape): 204.53,44.05 204.53,41.55 204.44,41.46 203.76,41.46 203.67,41.54 203.67,42.52 203.23,42.96 203.23,43.72 203.73,44.23 204.36,44.23
+3.3V_M on TOP (solid shape): 194.54,53.69 194.54,52.4 194.43,52.29 194.13,52.29 194.1,52.31 194.1,52.83 194.07,52.85 193.62,52.85 193.58,52.81 193.58,52.37 193.53,52.32 192.77,52.32 192.64,52.46 192.64,53.66 192.89,53.91 194.32,53.91
+3.3V_M on IN3 (solid shape): outline of 228 points within 146.45,71.54 152.41,73.19
+3.3V_M_TPM on TOP (solid shape): 194.49,52.02 194.49,51.08 194.46,51.05 192.9,51.05 192.76,51.19 192.76,51.85 193.04,52.12 194.39,52.12
+3.3V_M_UL3 on TOP (solid shape): 203.09,42.58 203.09,42.2 203.08,42.2 203.08,41.45 203.42,41.12 203.42,40.5 202.77,39.85 202.31,39.85 202.11,40.05 201.14,40.05 201.09,40.1 201.09,41.12 201.41,41.43 201.41,42.31 201.44,42.34 202.07,42.34 202.38,42.65 203.02,42.65
+3.3V_MMI on TOP (solid shape): 261.26,22.4 261.26,21.37 260.9,21.01 260.9,19.79 260.83,19.73 260.7,19.73 260.67,19.77 260.67,20.81 260.59,20.89 260.59,22.43 260.61,22.46 261.2,22.46
+3.3V_MMI on TOP (solid shape): 262.48,14.46 262.48,13.63 263.58,12.53 263.58,11.54 263.45,11.42 262.92,11.42 262.75,11.25 262.75,10.58 262.62,10.45 262.37,10.45 262.18,10.64 262.18,11.57 262.66,12.05 262.66,12.86 262.28,13.25 262.28,14.46 262.33,14.52 262.43,14.52
+3.3V_MMI on TOP (solid shape): 258.47,14.49 258.47,13.66 257.92,13.12 257.92,11.92 257.49,11.92 257.49,11.92 257.36,11.92 257.05,11.6 256.13,11.6 255.96,11.43 255.96,10.71 255.77,10.52 254.24,10.52 254.05,10.71 254.05,12.42 254.34,12.71 255.77,12.71 256.35,13.3 256.85,13.3 257.37,13.82 257.57,13.82 258.29,14.54 258.42,14.54
+3.3V_MMI on TOP (solid shape): 266.42,15.22 266.62,15.02 266.62,14.33 266.62,14.33 266.5,14.21 265.41,14.21 264.93,14.68 264.93,14.99 264.3,15.63 263.23,15.63 263.18,15.68 263.18,15.78 263.23,15.83 264.76,15.83 265.11,15.48 265.72,15.48 265.91,15.67 265.91,15.98 266.42,15.98
+3.3V_MMI on IN1 (solid shape): outline of 574 points within 255.32,9.69 266.94,22.58
+3.3V_RUN on TOP (solid shape): 147.08,74.14 147.08,73 146.96,72.87 146.45,72.87 145.81,73.51 145.11,73.51 144.99,73.63 144.99,74.27 145.05,74.33 146.89,74.33
+3.3V_RUN on TOP (solid shape): 220.65,51.28 220.65,49.76 220.52,49.63 219.89,49.63 219.76,49.76 219.76,49.89 219.32,50.33 219.32,51.22 219.51,51.41 220.52,51.41
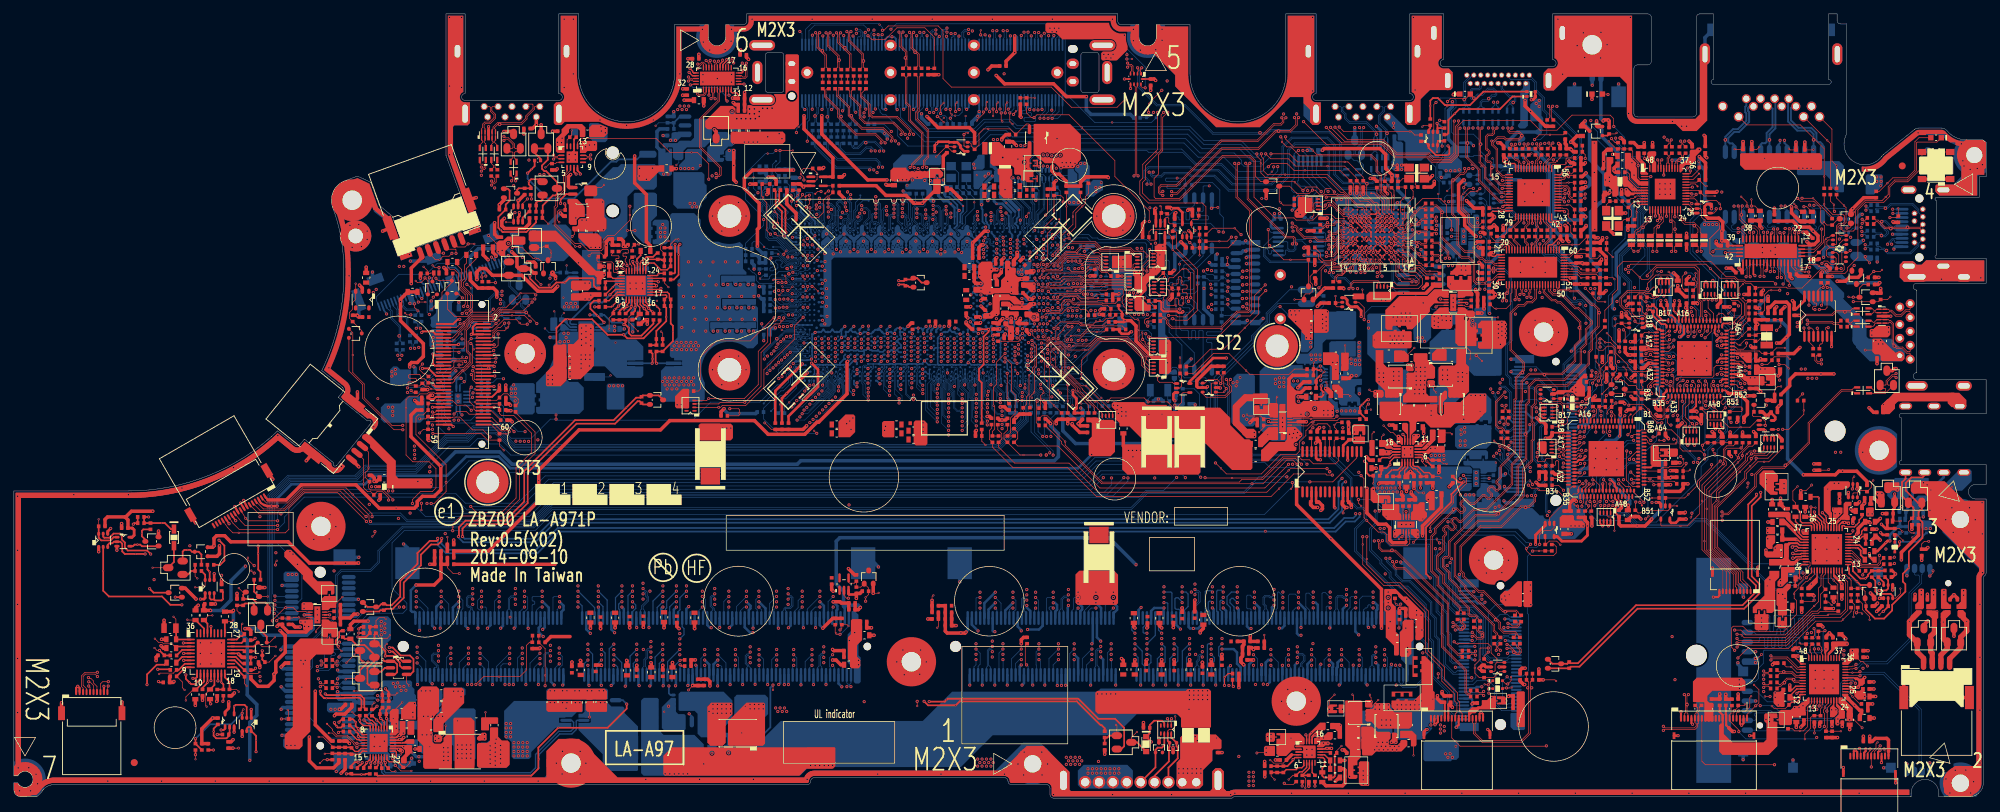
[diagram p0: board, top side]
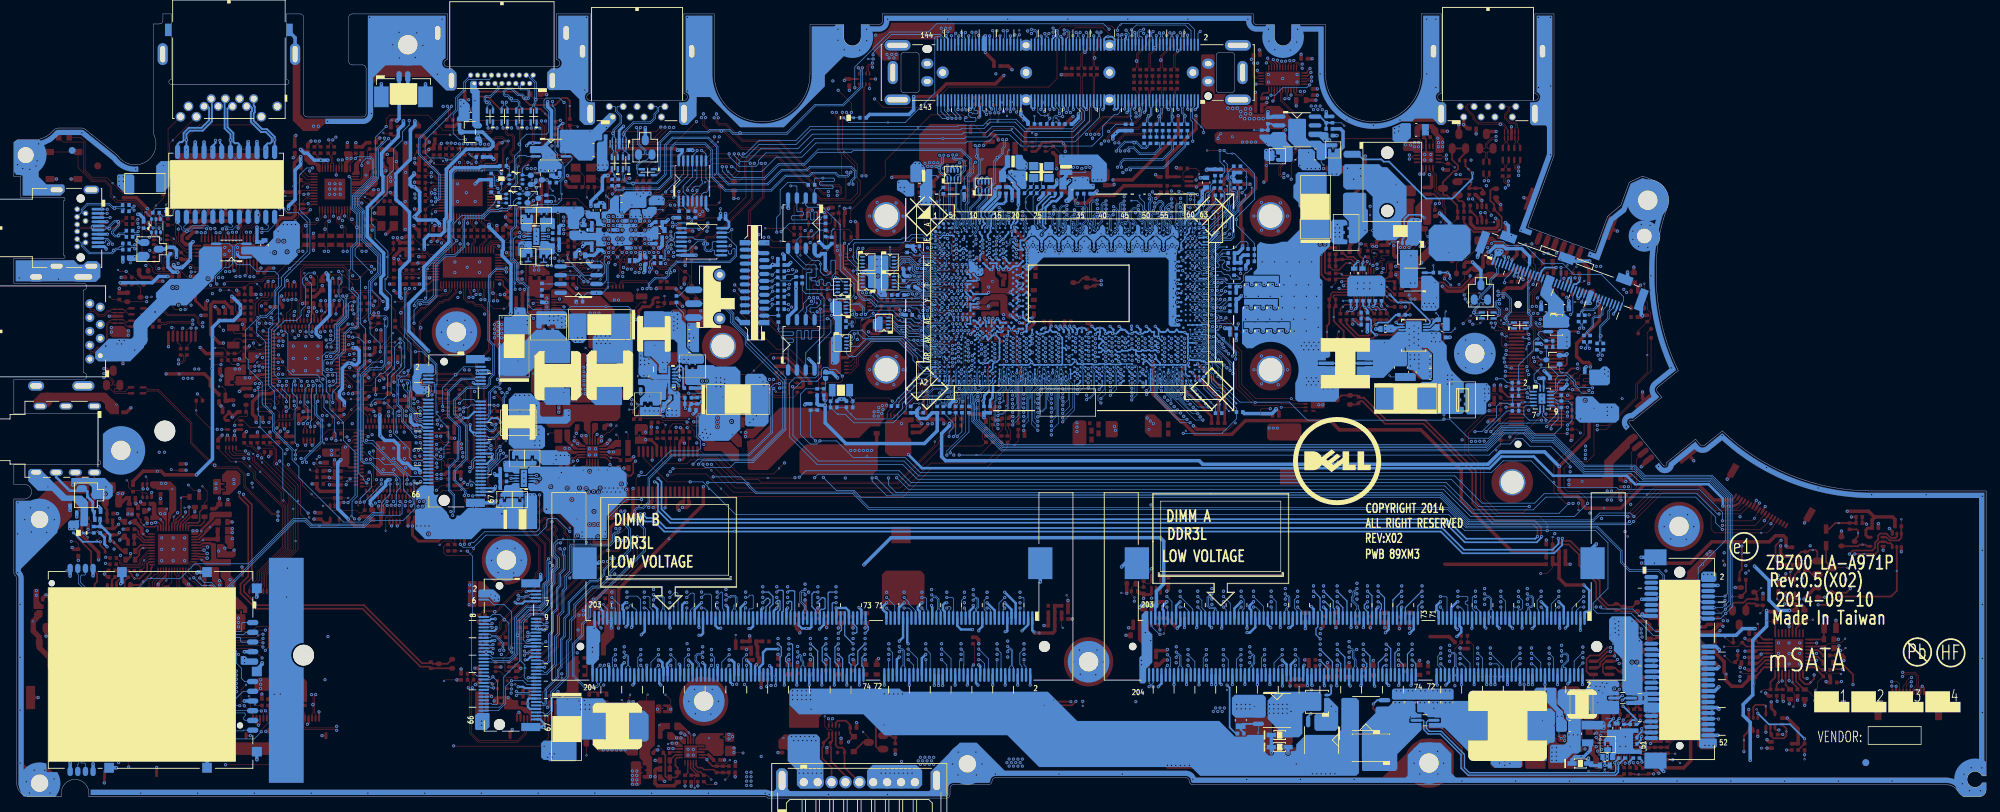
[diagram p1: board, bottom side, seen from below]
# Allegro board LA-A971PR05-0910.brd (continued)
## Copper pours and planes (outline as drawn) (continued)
+3.3V_RUN on TOP (solid shape): 160.93,78.25 160.93,76.91 160.92,76.91 160.92,76.61 160.67,76.36 158.13,76.36 158.07,76.43 158.07,78.08 158.13,78.14 159.85,78.14 160.04,78.33 160.84,78.33
+3.3V_RUN on TOP (solid shape): 254.36,25.55 254.87,25.55 254.87,26.12 255.19,26.12 255.25,26.06 255.25,24.73 255,24.47 254.04,24.47 253.85,24.66 253.85,25.93 254.04,26.12 254.36,26.12
+3.3V_RUN on TOP (solid shape): 43.04,25.69 43.04,24.42 42.85,24.23 41.7,24.23 41.62,24.31 41.62,24.92 41.47,25.07 41.19,25.07 41.06,25.2 41.06,25.68 41.14,25.76 42.98,25.76
+3.3V_RUN on TOP (solid shape): 214.81,68.59 214.81,65.38 214.17,64.74 210.93,64.74 210.74,64.93 210.74,65.7 211.32,65.7 211.32,67.73 210.74,67.73 210.74,68.3 211.25,68.81 214.59,68.81
+3.3V_RUN on TOP (solid shape): 214.92,14.31 214.92,13.55 214.88,13.51 213.5,13.51 213.5,13.75 213.51,13.77 214.06,13.77 214.06,14.25 213.49,14.25 213.49,14.68 214.55,14.68
+3.3V_RUN on TOP (solid shape): 83.81,75.98 85.01,75.98 85.2,75.79 85.2,75.29 84.57,74.65 84.57,74.08 84.51,74.02 84,74.02 83.87,74.14 83.87,75.03 83.55,75.35 82.73,75.35 77.9,80.17 74.35,80.17 74.09,80.43 74.09,81.51 74.35,81.76 78.03,81.76
+3.3V_RUN on TOP (solid shape): 253.86,12.1 253.86,11.53 253.29,11.53 253.29,11.02 253.31,11 253.82,11 253.86,10.96 253.86,10.62 253.86,10.62 253.86,7.49 252.59,6.22 245.96,6.22 245.47,6.72 245.47,10.55 245.68,10.76 246.02,10.76 246.14,10.65 246.14,9.27 247.37,8.04 251.87,8.04 252.27,8.44 252.27,10.77 251.96,11.09 251.96,12.04 252.15,12.23 253.73,12.23
+3.3V_RUN on TOP (solid shape): outline of 95 points within 161.11,70.21 165.89,79.87
+3.3V_RUN on BOTTOM (solid shape): 93.78,93.03 94.29,93.03 94.29,93.6 94.67,93.6 94.73,93.53 94.73,89.91 94.45,89.63 93.17,89.63 92.75,90.06 92.75,93.44 92.9,93.6 93.78,93.6
+3.3V_RUN on BOTTOM (solid shape): 211.31,79.92 211.31,78.27 210.93,77.89 210.13,77.89 210.13,78.44 210.11,78.46 209.6,78.46 209.6,77.89 209.35,77.89 209.22,78.02 209.22,78.9 209.35,79.03 209.35,79.43 210.43,79.43 210.43,79.37 210.43,79.32 210.45,79.27 210.47,79.22 210.5,79.18 210.54,79.14 210.58,79.11 210.63,79.08 210.68,79.06 210.73,79.05 210.78,79.04 210.84,79.05 210.89,79.06 210.94,79.08 210.98,79.11 211.02,79.14 211.06,79.18 211.09,79.22 211.11,79.27 211.13,79.32 211.14,79.37 211.14,79.43 211.13,79.48 211.11,79.53 211.09,79.58 211.06,79.62 211.02,79.66 210.98,79.69 210.94,79.72 210.89,79.74 210.84,79.75 210.78,79.76 210.73,79.75 210.68,79.74 210.63,79.72 210.58,79.69 210.54,79.66 210.5,79.62 210.47,79.58 210.45,79.53 210.43,79.48 210.43,79.43 209.35,79.43 209.35,80.17 209.41,80.24 210.99,80.24
+3.3V_RUN on BOTTOM (solid shape): 160.95,78.1 160.95,76.32 161.04,76.23 161.39,76.23 161.41,76.21 161.45,76.17 161.49,76.14 161.54,76.11 161.59,76.09 161.64,76.08 161.7,76.07 161.73,76.07 162.03,76.07 162.06,76.02 162.09,75.97 162.11,75.95 162.11,75.63 161.89,75.41 161.22,75.41 160.95,75.14 160.95,73.66 160.78,73.49 159.87,73.49 159.64,73.26 159.64,72.64 159.17,72.17 158.36,72.17 158.32,72.22 158.32,73.19 158.01,73.5 158.01,75.25 159.17,75.25 159.17,75.2 159.18,75.14 159.2,75.09 159.22,75.04 159.25,75 159.29,74.96 159.33,74.93 159.37,74.9 159.42,74.88 159.48,74.87 159.53,74.87 159.58,74.87 159.63,74.88 159.68,74.9 159.73,74.93 159.77,74.96 159.81,75 159.84,75.04 159.86,75.09 159.88,75.14 159.88,75.2 159.88,75.25 159.88,75.3 159.86,75.35 159.84,75.4 159.81,75.44 159.77,75.48 159.73,75.52 159.68,75.54 159.63,75.56 159.58,75.57 159.53,75.58 159.48,75.57 159.42,75.56 159.37,75.54 159.33,75.52 159.29,75.48 159.25,75.44 159.22,75.4 159.2,75.35 159.18,75.3 159.17,75.25 158.01,75.25 158.01,78.05 158.15,78.2 160.86,78.2
+3.3V_RUN on IN1 (solid shape): 259.84,60.82 259.84,59.73 259.51,59.4 256.43,59.4 256.17,59.66 256.17,60.58 256.57,60.98 259.68,60.98
+3.3V_RUN on IN1 (solid shape): outline of 281 points within 251.96,10.34 255.19,27.15
+3.3V_RUN on IN4 (solid shape): outline of 573 points within 141.88,72.55 156.8,76.34
+3.3V_RUN on IN2: 41.87,24.36 41.57,24.65 41.57,24.87 41.42,25.02 41.15,25.02 41.06,25.1 41.06,27.29 41.84,28.07 41.84,33.53 47.19,38.87 47.19,41.84 56.6,51.25 57.98,51.25 58.41,50.82 58.41,49.32 57,47.91 57,45 52.93,40.93 52.93,40.51 47.26,34.84 47.26,27.44 44.18,24.36
+3.3V_RUN on IN3: 57.53,50.99 69.82,50.99 70.62,51.79 74.1,51.79 74.41,51.48 74.41,48.54 73.34,47.47 57.88,47.47 57.39,47.96 57.39,50.84 ; 1 cut-out
+3.3V_RUN on VCC: 160.26,18.39 160.26,35 148.83,46.43 148.83,53.95 162.46,53.95 163.06,54.54 163.06,67.52 150.84,79.73 138.54,79.73 138.54,80.72 136.85,82.42 117.35,82.42 116.74,83.03 94.37,83.03 89.9,78.57 89.9,58.39 84.72,58.39 77.48,51.16 70.54,51.16 70.54,63.5 72.86,65.82 77.88,65.82 82.41,70.35 82.41,71.83 81.82,72.43 77.78,72.43 77.78,76.7 91.28,90.21 97.69,90.21 98.26,90.78 104.99,90.78 110.96,96.75 122.9,96.75 126.78,100.62 143.58,100.62 145.42,98.78 153.98,98.78 153.98,97.21 154.89,96.3 166.89,96.3 171.21,91.98 178.9,91.98 186.74,84.13 186.74,70.04 188.99,67.79 201.26,67.79 201.85,68.39 201.85,75.16 209.82,75.16 210.45,75.79 210.45,78.54 209.79,79.2 209.79,82.55 211.29,84.05 221.37,84.05 223.78,81.64 230.77,81.64 233.69,78.71 263.15,78.71 265.86,76.01 265.86,60.4 264.97,59.51 255.97,59.51 255.7,59.78 255.7,71.52 252.06,75.16 235.02,75.16 225.69,65.82 213.07,65.82 208.12,70.78 204.35,70.78 203.63,70.06 203.63,67.12 204.58,66.16 204.58,64.91 202.89,63.22 191.4,63.22 187.76,59.58 187.76,21.03 185.11,18.39
+3.3V_RUN_AUDIO on TOP (solid shape): 255.76,30.25 255.25,29.74 255.25,26.44 255.12,26.31 254.04,26.31 253.92,26.44 253.92,27.63 253.7,27.84 253.7,30.06 253.89,30.25 254.62,30.25 255.25,30.88 255.76,30.88
+3.3V_RUN_AUDIO on TOP (solid shape): 259.68,33.2 259.68,31.06 258.58,29.97 258.03,29.97 258.03,30.44 259.45,31.87 259.45,32.04 259.47,32.07 259.47,33.2 259.52,33.25 259.63,33.25
+3.3V_RUN_AUDIO on TOP (solid shape): 262.09,33.2 262.09,32.26 263.41,30.94 263.41,30 263.39,29.97 262.98,29.97 262.97,29.97 262.92,29.97 262.84,30.05 262.84,30.92 261.86,31.9 261.86,33.2 261.91,33.25 262.04,33.25
+3.3V_RUN_AUDIO on IN3 (solid shape): 265.29,31.22 265.29,30.72 264.27,29.69 256.4,29.69 255.1,28.39 254.3,28.39 254.1,28.6 254.1,29.86 255.5,31.26 258.68,31.26 259.16,31.74 264.77,31.74
+3.3V_RUN_CARD on TOP (solid shape): 262.08,14.46 262.08,13.22 262.51,12.79 262.51,12.13 262.05,11.67 261.44,11.67 261.44,13.04 261.87,13.47 261.87,14.46 261.93,14.52 262.03,14.52
+3.3V_RUN_CARD on BOTTOM (solid shape): 251.25,20.36 251.25,19.36 251.1,19.2 248.93,19.2 248.79,19.34 248.79,19.99 248.92,20.12 250.26,20.12 250.62,20.48 251.13,20.48
+3.3V_RUN_CARD on IN3 (solid shape): 251.29,20.1 251.29,18.12 251.16,17.99 250.26,17.99 250.09,18.16 250.09,20.2 250.25,20.35 251.04,20.35
+3.3V_RUN_CARD on IN3 (solid shape): 262.55,12.88 262.55,11.76 262.5,11.76 262.28,11.62 262.21,11.37 262.21,11.34 261.83,10.96 261.48,10.96 261.48,10.96 260.85,10.96 260.59,11.21 260.59,11.55 261.37,12.33 261.37,12.83 261.51,12.97 262.45,12.97
+3.3V_RUN_UZ9 on TOP (solid shape): outline of 123 points within 207.51,65.13 210.55,70.71
+3.3V_RUN_VDDA on BOTTOM (solid shape): 198.11,86.14 198.11,84.95 198.52,84.54 199.15,84.54 199.3,84.4 199.3,83.52 199.23,83.45 199.14,83.45 198.91,83.52 198.68,83.41 198.58,83.22 198.61,83 198.61,82.92 198.58,82.88 198.12,82.88 198.01,83 198.01,83.37 198.09,83.46 198.25,83.46 198.27,83.46 198.64,83.8 198.29,84.17 198.27,84.17 198.25,84.18 197.43,84.18 197.25,84 197.25,83.64 197.14,83.54 196.61,83.54 196.57,83.57 196.23,83.57 196.08,83.72 196.08,84.03 196.13,84.11 196.22,84.13 196.42,84.12 196.59,84.22 196.8,84.42 196.8,86.78 196.85,86.83 197.42,86.83
+3.3V_RUN_VDDA on IN1: 193.38,79.3 193.39,79.18 193.44,79.07 193.45,79.05 193.45,78.96 193.48,78.93 193.61,78.93 193.62,78.93 193.72,78.91 193.82,78.92 193.85,78.92 193.99,78.78 193.99,77.91 193.76,77.68 193.11,77.68 192.81,77.38 191.17,77.38 190.54,78.02 190.2,78.02 190.2,80.6 190.27,80.81 190.2,81.02 190.2,85.28 190.74,85.82 194.56,85.82 194.65,85.76 194.64,85.65 194.93,85.09 195.22,85.65 195.21,85.76 195.3,85.82 195.41,85.82 195.89,85.34 197.75,85.34 198.7,84.38 198.7,83.67 198.55,83.51 198.55,83.1 198.39,82.93 198.11,82.93 197.89,82.71 197.89,81.67 197.59,81.37 192.09,81.37 191.94,81.22 191.94,79.81 192.45,79.3
+3.3V_RUN_VDDIO on BOTTOM (solid shape): 192.88,84.87 193.41,84.87 193.49,84.78 193.49,84.31 193.32,84.14 193.32,83.63 193.24,83.54 192.16,83.54 191.37,84.33 191.37,85.12 191.43,85.18 192.57,85.18
+3.3V_RUN_VDDIO on IN4: 197.82,75.57 196.81,76.58 196.48,76.58 196.46,76.61 196.15,76.82 195.83,76.64 195.76,76.62 195.62,76.65 195.47,76.63 195.4,76.64 195.33,76.65 195.02,76.65 194.82,76.6 194.66,76.46 194.09,76.46 194.06,76.52 194.01,76.57 194.13,76.86 194.02,77.15 193.73,77.29 193.43,77.2 193.39,77.17 193.17,77.39 191.43,77.39 190.66,77.39 190.23,77.82 190.23,79.69 190.02,79.9 190.02,80.47 190.05,80.48 190.21,80.6 190.27,80.79 190.27,80.81 190.42,80.96 190.42,83.91 192.4,85.89 194.63,85.89 194.72,85.83 194.7,85.71 194.93,85.09 195.17,85.71 195.14,85.83 195.24,85.89 196.01,85.89 197.03,84.87 197.75,84.87 198.47,84.15 200.28,84.15 200.36,84.23 200.47,84.25 200.53,84.16 200.53,77.71 200.5,77.7 200.29,77.37 200.5,77.05 200.53,77.04 200.53,76.34 199.76,75.57
+3.3V_RUN_VMM on TOP (solid shape): 186.11,86.52 186.8,86.52 186.93,86.4 186.93,84.62 186.8,84.49 186.36,84.49 185.47,83.6 184.58,83.6 184.33,83.86 184.33,84.56 184.84,85.06 184.84,86.52 184.96,86.65 185.98,86.65
+3.3V_RUN_VMM on TOP (solid shape): 205.58,74.22 205.58,73.63 205.46,73.52 204.46,73.52 203.44,72.5 199.14,72.5 198.11,71.48 194.84,71.48 194.69,71.62 194.69,72.51 195.14,72.96 203.1,72.96 203.78,73.65 203.81,73.65 203.81,73.67 203.97,73.84 203.97,74.28 203.99,74.29 205.5,74.29
+3.3V_RUN_VMM on BOTTOM (solid shape): 192.16,86.67 192.18,86.67 192.52,86.33 192.52,85.52 192.43,85.43 190.3,85.43 190.23,85.5 190.23,86.4 190.68,86.84 191.99,86.84
+3.3V_RUN_VMM on IN2 (solid shape): outline of 491 points within 180.77,71.54 207.42,85.06
+3.3V_RUN_VMM on IN4 (solid shape): 186.41,85.04 186.41,83.96 186.24,83.8 185.13,83.8 184.48,84.44 184.48,84.89 184.77,85.18 186.27,85.18
+3.3V_RUN_VMM on IN4 (solid shape): 191.5,86.32 191.5,85.33 191.04,84.87 190.23,84.87 189.96,85.14 189.96,86.09 190.48,86.6 191.22,86.6
+3.3V_RUN_VMM on TOP: 203.96,77.06 204.78,77.06 204.95,76.89 206.16,76.89 206.27,77 207.23,77 207.33,76.9 207.33,76.59 206.86,76.12 204.13,76.12 203.9,76.35 203.9,77
+3.3V_RUN_VMM on BOTTOM: 196.61,75.8 196.42,76.05 196.36,76.12 196.39,76.21 196.34,76.75 195.82,76.62 195.77,76.57 195.7,76.56 195.58,76.58 195.47,76.55 195.41,76.57 195.35,76.58 195.28,76.61 195.25,76.68 195.25,78.16 195.3,78.21 197.64,78.21 197.64,78.21 197.83,78.21 197.94,78.1 197.94,77.87 197.95,77.86 198.02,77.73 198.14,77.64 198.17,77.63 198.17,77.47 198.14,77.46 197.94,77.14 198.14,76.82 198.17,76.81 198.17,71.79 197.66,71.28 196.08,71.28 195.57,71.79 195.57,74.36 195.95,74.74 196,74.83 196.1,74.83 196.34,74.8 196.54,74.93 196.61,74.97 196.69,74.95 197.29,75.26 196.62,75.37 196.58,75.35 196.54,75.37 196.53,75.38 196.51,75.44 196.53,75.5
+3.3V_RUN_VMM on BOTTOM: 209.75,72.02 207.67,72.02 207.53,72.16 207.52,72.17 207.32,72.38 207.04,72.37 207.03,72.36 204.23,72.36 203.44,71.58 203.44,71.35 203.25,71.16 202.68,71.16 202.62,71.22 202.62,72.67 203.51,73.56 208.26,73.56 208.46,73.76 208.46,74.46 208.33,74.59 207.64,74.59 207,75.23 207,75.81 206.32,76.48 206.32,77.1 206.67,77.45 207,77.45 207.12,77.57 208.52,77.57 208.65,77.7 210.36,77.7 210.55,77.51 210.55,74.49 209.97,73.91 209.97,72.23
+3.3V_SUS on TOP (solid shape): 249.26,16.84 249.26,15.54 249.19,15.47 244.5,15.47 243.77,14.74 243.77,14.04 244.07,13.74 244.56,13.74 244.65,13.65 244.65,11.09 244.61,11.05 243.44,11.05 243.35,11.14 243.35,13.72 243.25,13.82 241.8,13.82 241.69,13.93 241.69,16.8 242.25,17.36 248.74,17.36
+3.3V_SUS on TOP (solid shape): 43.04,32.61 43.04,31.91 43.71,31.25 45.68,31.25 46.15,30.77 46.15,29.5 45.96,29.31 45.64,29.31 45.64,29.88 45.14,29.88 45.14,29.31 43.87,29.31 41.58,31.6 41.58,32.11 38.91,34.77 38.91,35.41 39.29,35.79 39.87,35.79
+3.3V_SUS on IN2 (solid shape): 249.61,18 249.61,15.77 249.39,15.56 248.3,15.56 248.15,15.71 248.15,17.97 248.29,18.11 249.49,18.11
+3.3V_SUS on IN2 (solid shape): 258.16,61.98 258.16,60.94 257.57,60.35 257.02,60.35 256.49,60.89 256.49,61.59 257.05,62.16 257.98,62.16
+3.3V_SUS on IN3 (solid shape): 40.75,37.19 40.75,35.28 40.37,34.9 39.99,34.9 39.48,35.41 39.48,37.12 39.74,37.38 40.56,37.38
+3.3V_SUS on IN3 (solid shape): 56.38,76.81 56.38,76.49 55.11,75.22 54.6,75.22 54.22,75.6 54.22,75.98 55.17,76.94 56.25,76.94
+3.3V_SUS on IN3 (solid shape): 258.32,63.72 258.32,61.47 258.18,61.33 256.99,61.33 256.77,61.55 256.77,63.69 256.92,63.84 258.2,63.84
+3.3V_SUS on IN3 (solid shape): 76.89,90.21 76.89,89.83 77.46,89.26 77.46,88.62 77.27,88.43 76.06,88.43 75.49,89 75.49,90.27 75.62,90.4 76.7,90.4
+3.3V_SUS on IN4 (solid shape): 57.46,76.75 57.46,76.17 57.26,75.98 55.42,75.98 55.23,76.17 55.23,76.75 55.42,76.94 57.26,76.94
+3.3V_SUS on IN4 (solid shape): 76.63,90.65 76.63,89.81 76.44,89.62 75.51,89.62 75.38,89.75 75.38,90.13 74.66,90.84 74.66,91.1 75.11,91.54 75.74,91.54
+3.3V_SUS on IN3: 98.9,107.54 99.96,106.49 102.27,106.49 103.81,108.03 105.27,108.03 106.02,107.28 106.02,101.5 104.8,100.28 96.23,100.28 96.06,100.44 96.06,102.5 96.76,103.2 96.76,107.1 97.2,107.54
+3.3V_SUS_UZ8 on TOP (solid shape): 46.41,28.99 46.41,27.47 46.34,27.41 45.58,27.41 45.26,27.09 44.37,27.09 44.31,27.15 44.31,28.74 44.69,29.12 46.28,29.12
+3.3V_TP on TOP (solid shape): 213.35,14.71 213.35,12.89 213.23,12.78 210.95,12.78 210.39,12.22 209.92,12.22 209.64,11.94 209.64,11.09 209.55,11 209.4,11 209.32,11.07 209.32,12.53 209.9,13.11 210.56,13.11 210.69,13.25 211.13,13.25 211.3,13.42 211.3,14.06 211.37,14.13 212.05,14.13 212.65,14.73 213.32,14.73
+3.3V_TSP on TOP (solid shape): 73.65,80.75 73.65,79.92 73.46,79.73 71.62,79.73 70.73,78.84 70.73,78.14 70.6,78.02 70.16,78.02 69.46,78.71 69.46,79.96 70.82,79.96 70.82,79.91 70.82,79.85 70.84,79.8 70.86,79.75 70.89,79.71 70.93,79.67 70.97,79.64 71.02,79.61 71.07,79.59 71.12,79.58 71.17,79.58 71.22,79.58 71.28,79.59 71.33,79.61 71.37,79.64 71.41,79.67 71.45,79.71 71.48,79.75 71.5,79.8 71.52,79.85 71.53,79.91 71.53,79.96 71.52,80.01 71.5,80.06 71.48,80.11 71.45,80.16 71.41,80.19 71.37,80.23 71.33,80.25 71.28,80.27 71.22,80.29 71.17,80.29 71.12,80.29 71.07,80.27 71.02,80.25 70.97,80.23 70.93,80.19 70.89,80.16 70.86,80.11 70.84,80.06 70.82,80.01 70.82,79.96 69.46,79.96 69.46,79.99 69.84,80.37 70.47,80.37 70.55,80.44 70.56,80.44 70.56,80.45 71.04,80.94 73.46,80.94
+3.3V_TSP on BOTTOM (solid shape): 70.79,78.84 70.79,78.14 71.26,76.92 71.23,76.87 71.07,76.82 70.96,76.87 70.85,77.13 70.54,78.02 70.47,78.08 69.93,78.08 69.48,78.52 69.48,78.65 69.48,78.66 69.48,78.92 69.72,79.16 70.47,79.16
+3.3V_VMM_UV10 on BOTTOM (solid shape): 208.13,80.13 208.13,79.61 208.27,79.48 208.27,77.89 208.14,77.76 207.89,77.76 207.89,77.77 207.89,78.33 207.38,78.33 207.38,77.77 207.38,77.76 207.07,77.76 207.06,77.77 207.06,78.03 206.74,78.35 206.2,78.35 206.05,78.5 206.05,79.9 206.1,79.96 206.72,79.96 207.02,80.26 208,80.26
+3.3V_WLAN on TOP (solid shape): 217.5,15.26 217.5,10.34 217.41,10.24 216.48,10.24 216.31,10.41 216.31,15.27 216.44,15.4 217.37,15.4
+3.3V_WLAN on TOP (solid shape): 217.09,31.18 217.09,27.69 216.97,27.56 216.63,27.56 216.56,27.64 214.64,27.64 213.95,28.32 213.95,29.26 214.57,29.88 215.09,29.88 216.45,31.24 217.03,31.24
+3.3V_WLAN on BOTTOM (solid shape): 217.53,11.9 217.53,9.98 217.35,9.81 215.87,9.81 215.43,10.25 215.43,12.16 215.55,12.28 217.14,12.28
+3.3V_WLAN on BOTTOM (solid shape): 217.03,29.88 217.03,29.04 216.92,28.93 215.43,28.93 214.8,28.3 214.09,28.3 213.91,28.48 213.91,29.12 214.87,30.07 216.84,30.07
+3.3V_WLAN on BOTTOM (solid shape): 212.2,49.89 212.2,48.93 212.08,48.81 211.76,48.81 211.76,49.38 211.25,49.38 211.25,48.81 209.54,48.81 209.54,49.38 209.03,49.38 209.03,48.81 208.65,48.81 207.82,47.98 204.08,47.98 203.8,48.25 203.8,49.46 204.28,49.93 205.52,49.93 205.73,50.14 211.95,50.14
+3.3V_WLAN on IN3 (solid shape): outline of 611 points within 204.97,9.09 216.98,29.56
+3.3V_WLAN on VCC: 201.35,8.17 201.35,49.84 201.64,50.14 206.05,50.14 206.05,9.03 205.22,8.21 205.26,8.17
+3.3V_WLAN_UZ2 on BOTTOM (solid shape): 213.46,48.44 213.46,47.79 213.41,47.74 213.41,47.15 213.22,46.96 212.14,46.96 211.95,46.77 211.19,46.77 211.13,46.84 211.13,47.37 211,47.5 210.09,47.5 209.66,47.92 208.84,47.92 208.65,48.11 208.65,48.55 208.71,48.62 213.28,48.62
+3.3V_WWAN on TOP (solid shape): 224.58,40.65 224.58,40.14 224.75,39.98 225.79,39.98 225.79,39.89 226.14,39.54 226.14,39.22 226.14,39.17 226.15,39.1 226.02,38.96 222.62,38.96 222.49,39.09 222.49,40.39 222.87,40.77 224.46,40.77
+3.3V_WWAN on TOP (solid shape): 226.27,61.15 226.41,61.15 226.47,61.1 226.47,60.53 226.4,60.46 225.9,60.46 225.76,60.32 225.76,59.7 226.16,59.29 226.16,57.94 226.07,57.85 224.96,57.85 224.64,58.17 224.61,58.21 224.58,58.25 224.38,58.44 223.36,58.44 223.08,58.17 222.08,58.17 221.89,57.98 221.19,57.98 221.13,58.04 221.13,58.35 221.27,58.49 221.92,58.49 222.22,58.8 223.86,58.8 224.9,59.84 224.9,60.02 226.04,61.16 226.26,61.16
+3.3V_WWAN on BOTTOM (solid shape): 226.34,62.42 226.34,61.02 226.56,60.81 226.56,58.84 225.89,58.17 224.66,58.17 224.51,58.33 224.33,58.34 224.02,58.65 224.02,59.09 224.31,59.39 225.17,59.39 225.4,59.62 225.4,59.65 225.41,59.66 225.41,60.43 225.22,60.62 225.22,61.06 225.06,61.22 223.54,61.22 223.44,61.32 223.44,62.29 223.74,62.59 226.17,62.59
+3.3V_WWAN on BOTTOM (solid shape): outline of 265 points within 210.55,37.31 226.17,45.07
+3.3V_WWAN on IN3 (solid shape): 224.98,59.61 225.1,59.49 225.1,58.39 224.91,58.2 224.65,58.2 224.65,58.2 224.4,58.46 223.06,58.46 222.49,59.03 222.49,59.41 223.13,60.05 224.54,60.05
+3.3V_WWAN on IN3 (solid shape): outline of 153 points within 211.57,41.06 216.52,48.71
+3.3V_WWAN_UZ2 on BOTTOM (solid shape): 212.33,45.12 213.16,45.12 213.35,44.93 213.35,44.36 213.89,43.82 213.89,43.5 213.79,43.41 210.55,43.41 210.55,44.23 211.02,44.7 211.06,44.7 211.06,44.74 211.13,44.81 211.13,45.31 211.19,45.38 212.08,45.38
+3V5V_PWR_SRC on TOP (solid shape): 211.95,58.25 211.95,55.66 210.33,54.04 207.51,54.04 206.84,53.38 203.95,53.38 203.06,54.27 202.04,54.27 201.85,54.08 201.85,53.06 201.16,52.36 201.16,50.96 201.09,50.9 200.97,50.9 200.9,50.96 200.9,54.14 200.71,54.33 197.09,54.33 196.58,54.84 196.58,57 196.71,57.12 199.63,57.12 200.01,56.74 204.52,56.74 204.52,56.74 204.87,56.74 204.91,56.7 204.91,55.46 205.16,55.22 205.66,55.22 205.85,55.41 205.85,57 205.92,57.06 208.22,57.06 209.45,58.29 211.91,58.29
+3V5V_PWR_SRC on BOTTOM (solid shape): 212.67,57.45 212.67,54.05 212.57,53.95 212.2,53.95 212.2,54.41 212.15,54.46 209.6,54.46 209.6,53.95 204.27,53.95 203.76,54.46 203.76,55.92 203.89,56.04 204.58,56.04 204.78,55.85 204.78,55.16 204.97,54.97 207.89,54.97 208.14,55.22 208.14,57 209.46,58.32 211.81,58.32
+5V_ALW on TOP (solid shape): 82.28,96.65 82.28,95.39 82.12,95.22 81.56,95.22 81.45,95.34 81.45,96.18 81.14,96.48 80.07,96.48 79.92,96.32 79.92,95.93 79.27,95.28 79.27,93.03 79.21,92.98 78.22,92.98 78.01,93.19 78.01,95.02 78.83,95.83 78.83,96.37 79.59,97.13 81.8,97.13
+5V_ALW on TOP (solid shape): 206.55,73.21 206.55,72.17 206.49,72.11 205.69,72.11 205.62,72.18 205.59,72.18 205.35,72.28 205.1,72.18 205.09,72.18 204.9,71.98 204.9,71.73 205.09,71.54 206.49,71.54 206.55,71.48 206.55,71.35 206.49,71.28 204.46,71.28 203.84,70.67 203.84,70.1 201.28,67.54 200.52,67.54 200.52,67.98 200.46,68.05 198.43,68.05 198.43,67.47 197.66,67.47 197.41,67.73 197.41,70.33 199.43,72.35 203.48,72.35 204.46,73.33 206.44,73.33
+5V_ALW on TOP (solid shape): 157.65,111.68 158.25,110.6 159.4,110.18 160,110.18 160.08,110.15 160.1,110.07 160.08,109.36 160.23,108.66 160.27,108.53 160.33,108.4 160.33,107.84 158.76,106.27 157.74,106.27 157.38,106.35 157.02,106.28 157.01,106.27 156.72,106.27 156.52,106.48 156.52,107.35 156.75,107.59 157.82,107.59 158.71,108.48 157.82,109.36 155.58,109.36 155.45,109.35 155.31,109.32 150.92,109.32 150.02,110.22 149.83,110.22 149.82,110.23 149.7,110.25 149.57,110.23 149.56,110.22 148.68,110.22 148.68,110.27 148.64,110.37 148.57,110.46 148.53,110.5 148.48,110.53 148.48,111.52 148.68,111.72 157.64,111.72
+5V_ALW on BOTTOM (solid shape): 97.54,95.88 97.54,95.45 97.32,95.23 96.03,95.23 95.35,94.55 94.31,94.55 94.27,94.59 94.27,94.95 94.39,95.06 94.54,95.06 94.66,95.18 94.66,95.75 94.86,95.95 95.54,95.95 95.63,96.04 97.38,96.04
+5V_ALW on BOTTOM (solid shape): 209.64,93.87 209.64,93.03 209.54,92.94 208.08,92.94 207.87,92.73 207.87,92.28 208.46,91.7 208.46,90.33 208.27,90.14 206.98,90.14 206.98,90.15 206.1,90.15 205.74,90.51 205.73,90.52 205.66,90.59 205.16,90.59 205.03,90.72 205.03,91.33 205.83,92.14 205.83,92.82 206.97,93.95 209.55,93.95
+5V_ALW on BOTTOM (solid shape): outline of 216 points within 242.73,76.87 251.19,83.16
+5V_ALW on IN3 (solid shape): 157.66,111.63 158.27,110.59 159.4,110.18 159.72,110.18 159.72,110.18 159.98,110.18 160.2,109.96 160.2,107.86 158.67,106.34 157.55,106.34 157.37,106.35 157.2,106.34 156.83,106.34 156.52,106.65 156.52,107.35 156.75,107.59 157.82,107.59 157.91,107.59 158.01,107.61 158.23,107.61 158.74,108.11 158.74,108.81 158.23,109.32 158.09,109.32 157.95,109.35 157.82,109.36 155.58,109.36 155.52,109.36 155.45,109.35 155.36,109.34 154.48,110.21 151.03,110.21 151.01,110.21 150.86,110.25 150.71,110.21 150.7,110.21 149.86,110.21 149.85,110.21 149.7,110.25 149.55,110.21 149.54,110.21 149.02,110.21 148.95,110.22 148.83,110.21 148.51,110.53 148.51,111.48 148.7,111.67 157.65,111.67
+5V_ALW on IN3: 83.36,91.35 81.65,89.64 80.63,89.64 80.53,89.74 80.53,90 80.32,90.21 80.11,90.21 78.13,90.21 77.52,90.82 77.52,95.16 78.79,96.43 83.9,96.43 84.21,96.11 84.21,96.09 84.37,95.82 84.69,95.78 84.76,95.77 84.81,95.72 84.84,95.67 85.24,95.52 85.5,95.87 85.48,95.98 85.42,96.08 85.49,96.23 85.48,96.4 85.49,96.45 85.5,96.52 85.48,96.59 85.53,96.62 85.58,96.61 90.92,96.65 95.1,99.98 97.59,99.98 97.96,99.62 97.96,95.69 96.33,94.07 92.56,94.07 90.48,91.99 88.95,91.99 88.32,91.35
+5V_ALW on VCC: 189.2,68.3 187.25,70.25 187.25,84.34 179.1,92.49 171.42,92.49 167.1,96.81 155.1,96.81 154.48,97.42 154.48,106.12 153.51,107.1 108.02,107.1 99.7,98.78 93.83,98.78 95.52,101.34 96.12,104.35 96.12,110.43 98.93,110.43 98.93,109.65 101.2,107.38 103.47,109.65 103.47,110.43 105,110.43 106.07,110.88 106.52,111.95 106.52,111.98 157.88,111.98 157.88,111.95 158.33,110.88 159.4,110.43 160.93,110.43 160.93,109.65 163.2,107.38 165.47,109.65 165.47,110.43 168.28,110.43 168.28,104.35 173.06,97.08 181.62,98.58 184.1,96.11 203.17,96.11 207.61,100.56 232.18,100.56 232.18,98.65 232.63,97.58 233.7,97.13 241.7,97.13 241.88,97.14 242.05,97.17 242.05,95.25 243.45,93.85 243.45,91.18 244.08,90.55 244.08,90.39 244.03,90.32 244.08,89.87 244.08,87.6 247.64,87.6 247.64,83.45 246.39,82.21 243.3,82.21 242.98,82.52 236.57,82.52 230.41,88.68 226.26,88.68 225.5,87.92 223.04,87.92 222.79,88.18 206.77,88.18 201.35,82.76 201.35,68.6 201.05,68.3
+5V_ALW2 on TOP (solid shape): 200.71,53.89 200.71,50.96 200.65,50.9 200.58,50.9 200.52,50.96 200.52,52.43 199.82,53.12 199.82,53.95 199.95,54.08 200.52,54.08
+5V_ALWP on TOP (solid shape): 201.22,67.16 201.22,65 201.03,64.81 195.89,64.81 195.57,65.13 195.57,66.65 196.2,67.28 201.09,67.28
+5V_ALWP on BOTTOM (solid shape): 198.04,69.51 198.04,68.94 200.58,66.4 200.58,63.28 200.01,62.71 196.08,62.71 194.81,63.98 194.81,69.57 195.06,69.82 197.73,69.82
+5V_RUN on TOP (solid shape): 209.79,76.81 209.79,75.42 209.77,75.4 206.79,75.4 206.74,75.45 206.74,75.69 207.56,76.5 207.56,76.86 207.73,77.04 209.56,77.04
+5V_RUN on TOP (solid shape): 50.85,52.47 51.42,52.17 54.98,48.61 54.98,46.46 55.36,46.08 60.12,46.08 60.25,45.95 60.25,44.81 60.06,44.62 53.78,44.62 53.67,44.74 53.67,48.13 51.28,50.52 51.28,50.92 50.11,51.87 50.1,51.96 50.68,52.55
+5V_RUN on TOP (solid shape): 251.33,27.04 251.33,26.53 251.35,26.52 251.88,26.52 251.88,27.06 252.12,27.04 252.12,26.53 252.15,26.5 252.58,26.5 252.59,26.49 252.59,24.34 252.43,24.18 250.8,24.18 250.57,24.4 250.57,26.49 250.58,26.5 251.05,26.5 251.08,26.53 251.08,27.05 251.09,27.06 251.31,27.06
+5V_RUN on BOTTOM (solid shape): 86.73,68.05 86.73,67.22 86.6,67.09 85.27,67.09 84.63,67.73 83.74,67.73 83.68,67.79 83.68,67.92 83.74,67.98 85.14,67.98 85.4,68.24 86.54,68.24
+5V_RUN on IN2 (solid shape): 209.83,76.83 209.83,74.36 209.3,73.82 207.89,73.82 207.57,74.14 207.57,76.89 207.75,77.06 209.6,77.06
+5V_RUN on IN2 (solid shape): 185.03,61.63 185.03,59.98 184.9,59.85 184.07,59.85 183.95,59.98 183.95,61 183.69,61.25 183.69,61.82 184.01,62.14 184.52,62.14
+5V_RUN on IN3 (solid shape): 86.73,68.05 86.73,67.22 86.6,67.09 85.59,67.09 85.33,66.84 85.14,67.03 85.14,67.92 85.46,68.24 86.54,68.24
+5V_RUN on IN3 (solid shape): 186.3,60.24 186.3,59.35 186.17,59.22 185.28,59.22 185.28,59.66 185.15,59.79 184.14,59.79 183.95,59.98 183.95,60.74 184.2,61 185.53,61
+5V_RUN on IN4 (solid shape): 61.2,45.88 61.2,45.12 61.01,44.93 59.93,44.93 59.8,45.06 59.8,45.95 59.93,46.08 61.01,46.08
+5V_RUN on IN4 (solid shape): 87.05,68.17 87.05,66.14 86.67,65.76 86.54,65.76 85.9,66.4 86.03,66.52 86.03,68.11 86.22,68.3 86.92,68.3
+5V_RUN on VCC: 248.95,23.72 247.32,25.35 247.32,32.46 246.94,32.85 246.94,40.64 247.96,41.65 247.96,45.33 253.52,50.9 255.3,50.9 255.7,51.31 255.7,58.66 256.03,58.99 265.17,58.99 266.37,60.19 266.37,76.22 263.36,79.22 233.9,79.22 230.98,82.14 223.99,82.14 221.58,84.56 211.08,84.56 209.28,82.76 209.28,78.99 209.94,78.34 209.94,75.98 209.62,75.67 201.85,75.67 201.85,82.55 206.98,87.67 222.58,87.67 222.83,87.41 225.71,87.41 226.47,88.18 230.2,88.18 236.36,82.02 242.77,82.02 243.09,81.7 246.6,81.7 248.15,83.24 248.15,87.6 258.45,87.6 261.18,84.87 264.51,84.87 265.99,86.36 265.99,90.26 268.08,90.58 269.72,91.92 274.21,95.53 277.47,95.53 279.07,94.28 281.05,93.83 282.88,93.83 282.88,90.57 281.88,90.57 281.88,89.57 271.66,89.57 269.99,87.9 269.99,58.71 269.97,58.67 263.7,52.4 263.7,49.16 262.52,47.98 255.72,47.98 253.8,46.05 253.8,44.28 253.37,43.85 252.61,43.85 251.83,43.07 251.83,36.89 252.34,36.38 252.34,24.46 251.6,23.72
+5V_RUN_AUDIO on TOP (solid shape): 254.11,31.79 253.54,31.22 253.54,27.11 253.1,26.67 252.3,26.67 252.27,26.69 252.27,27.22 250.93,27.22 250.93,26.67 250.91,26.66 250.38,26.66 250.3,26.73 250.3,27.52 251.97,29.19 251.97,31.36 252.72,32.11 252.72,32.74 254.11,32.74
+5V_RUN_PVDD on TOP (solid shape): 257.11,36.55 258.31,36.55 258.36,36.5 258.36,36.4 258.31,36.35 256.96,36.35 256.73,36.58 255.79,36.58 255.51,36.3 255.51,34.44 255.79,34.16 256.27,34.16 256.65,34.54 258.33,34.54 258.38,34.49 258.38,34.42 258.31,34.34 257.1,34.34 256.26,33.5 254.77,33.5 254.76,33.51 252.7,33.51 252.65,33.57 252.65,34.39 252.72,34.45 254.56,34.45 254.81,34.71 254.81,36.61 254.94,36.74 255.32,36.74 255.46,36.88 256.78,36.88
+5V_RUN_UZ9 on TOP (solid shape): 209.84,73.04 210.12,72.76 210.12,72.41 210.02,72.31 208.99,72.31 208.79,72.11 207.84,72.11 207.82,72.12 207.82,73.01 207.65,73.18 206.83,73.18 206.3,73.71 206.3,75.15 206.4,75.25 207.32,75.25 207.32,74.69 208.06,74.69 208.06,75.23 208.51,75.23 208.51,74.69 209.26,74.69 209.26,75.26 209.84,75.26
+5V_USB_CHG_PWR on TOP (solid shape): 83.96,94.51 83.96,93.45 83.74,93.23 82.56,93.23 82.29,92.97 81.51,92.97 81.48,93 81.48,94.59 81.59,94.7 83.77,94.7
+5V_USB_CHG_PWR on BOTTOM: 74.47,98.4 74.79,98.72 75.46,98.72 77.73,96.44 79.03,96.44 79.98,97.4 81.39,97.4 81.71,97.08 81.71,95.7 83.07,94.34 83.07,93.5 82.85,93.28 79.7,93.28 79.49,93.06 79.49,91.73 79,91.25 75.52,91.25 74.85,91.92 74.85,94.48 74.47,94.86
+GND_CHASSIS on TOP (solid shape): 260.3,92.59 260.3,90.79 260.03,90.52 259.39,90.52 259.39,90.53 249.15,90.53 248.48,91.19 248.48,92.8 248.63,92.94 259.95,92.94
+GND_CHASSIS on BOTTOM (solid shape): 263.43,91.12 263.43,87.38 263.33,87.29 262.37,87.29 261.47,88.19 261.47,89.14 260.84,89.76 256.85,89.76 256.67,89.94 256.67,91.65 256.81,91.8 262.75,91.8
+V1.05S_APLLOPI on BOTTOM (solid shape): 152.58,90.58 152.58,90.44 153.09,89.93 153.09,88.56 153.47,88.18 153.47,85.57 153.28,85.38 151.94,85.38 151.7,85.63 151.7,90.6 151.75,90.65 152.55,90.65
+V1.05S_APLLOPI on IN3 (solid shape): outline of 1670 points within 138.19,71.48 153.47,86.14
+V1.05SP_B+ on BOTTOM (solid shape): 194.04,60.36 194.04,59.6 193.98,59.54 193.35,59.54 193.03,59.22 193.03,58.33 193.79,57.57 193.79,56.68 193.66,56.55 193.35,56.55 193.35,57.12 191.95,57.12 191.95,56.55 191.06,56.55 190.74,56.87 190.74,57.31 190.68,57.37 190.14,57.37 190.01,57.5 190.01,59.08 189.85,59.24 189.85,60.17 189.92,60.24 192.14,60.24 192.33,60.43 193.98,60.43
+VCC_CORE on BOTTOM (solid shape): outline of 318 points within 93.14,57.11 107.11,84.3
+VCC_CORE on BOTTOM (solid shape): outline of 1310 points within 115.98,67.92 138.47,80.94
+VCC_CORE on TOP: outline of 121 points within 93.14,58.65 137.59,83.38
+VCC_CORE on IN1: 93.59,62.08 93.59,74.14 94.6,75.16 105.97,75.16 106.48,74.65 108.45,74.65 109.02,75.22 111.75,75.22 111.98,75.46 112.01,75.45 112.36,75.51 112.46,75.85 112.43,75.93 112.38,76 112.38,77.76 113.61,78.99 113.78,78.99 114.2,79.41 114.22,79.4 114.49,79.49 114.58,79.76 114.58,79.79 114.8,80.01 115.25,80.01 115.6,80.36 115.6,80.98 116.26,81.64 116.26,81.64 116.4,81.78 128.48,81.78 128.51,81.75 136.32,81.75 137.55,80.53 137.55,77.52 137.08,77.06 123.3,77.06 123.18,76.94 123.18,69.06 122.8,68.68 119.24,68.68 118.57,68.01 115.46,68.01 113.4,70.08 108.89,70.08 107.43,68.61 107.3,68.49 107.3,68.34 107.3,68.28 107.3,67.97 105.79,66.46 100.76,66.46 98.16,63.86 98.16,58.78 97.46,58.08 93.59,58.08 93.14,58.52 93.14,61.63
+VCC_CORE on IN2: 106.79,76.49 106.79,76.49 106.2,76.22 106.79,75.96 106.79,65.76 105.78,64.74 101.02,64.74 99.68,63.41 99.68,59.6 98.67,58.58 93.84,58.58 93.14,59.28 93.14,61.76 93.65,62.27 93.65,76.56 94.56,77.47 105.82,77.47
+VCC_CORE on VCC: 90.41,58.39 90.41,78.35 94.58,82.52 116.53,82.52 117.14,81.91 136.64,81.91 138.04,80.51 138.04,67.28 132.24,67.28 131.54,67.98 115.22,67.98 114.52,68.68 109.42,68.68 105.52,64.79 105.52,60.79 103.13,58.39
+VCC_CORE on IN4: 106.25,75.52 106.3,75.44 106.38,75.38 106.79,74.97 106.79,65.76 105.78,64.74 101.02,64.74 99.68,63.41 99.68,59.6 98.67,58.58 93.52,58.58 93.14,58.97 93.14,61.63 93.65,62.14 93.65,76.56 94.64,77.55 104.22,77.55
+VCC_PWR_SRC on TOP (solid shape): 79.55,65.29 79.55,60.17 78.73,59.35 76.76,59.35 76.57,59.54 76.57,61.32 77.65,62.39 77.65,65.12 77.89,65.36 79.48,65.36
+VCC_PWR_SRC on BOTTOM (solid shape): 81.14,67.16 81.14,65 81.01,64.87 80.44,64.87 79.62,64.05 79.62,60.3 79.93,59.98 81.2,59.98 82.03,59.16 82.03,55.98 81.39,55.35 75.43,55.35 75.17,55.6 75.17,56.36 75.74,56.36 75.74,58.39 75.17,58.39 75.17,59.85 76.98,61.66 77.65,63.28 77.65,65.25 78.41,66.01 78.41,66.9 78.73,67.22 81.08,67.22
+VCC_PWR_SRC on IN4 (solid shape): 80.32,66.78 80.32,64.55 79.55,63.79 79.55,60.17 78.73,59.35 76.76,59.35 76.57,59.54 76.57,61.25 77.71,62.39 77.71,66.4 78.35,67.03 80.06,67.03
+VDDA_AVDD1 on TOP (solid shape): 264.53,42.65 264.53,42.18 264.45,42.11 264.17,42.11 264.04,41.98 264.04,40.85 264.27,40.61 264.27,40.11 264.21,40.04 263.7,40.04 263.64,40.11 263.07,40.11 262.5,39.53 262.5,38.52 262.43,38.46 262.32,38.46 262.27,38.51 262.27,39.88 263.38,40.99 263.38,42.44 263.66,42.71 264.47,42.71
+VDDA_PVDD on TOP (solid shape): 255.77,41 255.77,40.08 257.14,38.71 257.14,38.15 257.54,37.74 258.31,37.74 258.36,37.69 258.36,37.59 258.31,37.54 257.44,37.54 256.73,38.25 256.73,38.57 255.08,40.22 255.08,40.33 254.96,40.45 254.8,40.45 252.65,40.45 252.52,40.58 252.52,41.18 252.61,41.26 255.51,41.26
GND on TOP (solid shape): 227.94,81.64 227.09,81.64 227.09,94.73 227.94,94.73
GND on TOP (solid shape): 84.6,80.8 84.6,79.24 84.47,79.11 82.92,79.11 81.25,80.77 81.25,81.34 81.29,81.38 84.02,81.38
GND on TOP (solid shape): 103.5,53.65 103.5,51.86 103.18,51.54 98.7,51.54 98.57,51.66 98.57,53.76 98.78,53.96 103.19,53.96
GND on TOP (solid shape): 131.5,53.97 131.5,51.05 131.26,50.81 129.81,50.81 129.52,51.1 129.52,54.16 129.79,54.43 131.05,54.43
GND on TOP (solid shape): 181.53,7.47 181.53,6.13 181.47,6.07 180.14,6.07 179.95,6.26 179.95,7.34 180.14,7.53 181.47,7.53
GND on TOP (solid shape): 126.74,54.27 126.74,52.07 126.65,51.98 125.2,51.98 124.97,52.21 124.97,54.11 125.2,54.33 126.68,54.33
GND on TOP (solid shape): 57.88,13.77 57.88,11.37 57.81,11.31 55.91,11.31 55.74,11.48 55.74,12.76 56.85,13.87 57.77,13.87
GND on TOP (solid shape): 85.4,15.4 85.4,14.33 85.27,14.2 76.82,14.2 76.7,14.33 76.7,15.4 77.08,15.79 85.01,15.79
GND on TOP (solid shape): 111.05,95.67 111.05,94.65 110.67,94.27 103.47,94.27 103.18,94.56 103.18,95.86 103.37,96.05 110.67,96.05
GND on TOP (solid shape): 121.11,55.04 121.11,52.74 120.36,52 118.74,52 118.67,52.06 118.67,54.25 119.72,55.29 120.86,55.29
GND on TOP (solid shape): 189.92,7.28 189.92,7.09 189.79,6.96 187.63,6.96 187.57,7.02 187.57,7.15 187.63,7.21 188.65,7.21 188.84,7.4 189.79,7.4
GND on TOP (solid shape): 218.55,31.23 218.55,27.68 218.38,27.51 217.47,27.51 217.28,27.69 217.28,31.21 217.36,31.28 218.5,31.28
GND on TOP (solid shape): 270.12,67.92 270.12,66.78 269.74,66.4 267.26,66.4 267.13,66.52 267.13,67.41 267.32,67.6 267.7,67.6 268.15,68.05 269.99,68.05
GND on TOP (solid shape): 183.06,56.68 183.06,51.79 182.87,51.6 182.36,51.6 182.36,52.62 182.17,52.81 182.17,56.68 182.3,56.81 182.93,56.81
GND on TOP (solid shape): 255,15.34 254.88,15.21 254.88,13.18 253.8,13.18 253.29,13.69 253.29,15.21 253.42,15.34 254.24,15.34 254.43,15.53 254.43,15.91 255,15.91
GND on TOP (solid shape): 84.56,97.04 85,96.83 85.46,96.65 85.46,95.76 84.93,95.22 82.94,95.22 82.8,95.36 82.8,96.61 83.23,97.04
GND on TOP (solid shape): 170.82,50.02 170.82,46.93 170.5,46.61 160.28,46.61 159.54,47.35 159.54,50.57 159.95,50.98 169.85,50.98
GND on TOP (solid shape): 84.61,72.83 84.61,72.3 84.53,72.22 83.52,72.22 82.97,71.67 80.31,71.67 80.19,71.79 80.19,72.59 80.37,72.77 81.65,72.77 81.78,72.89 84.54,72.89
GND on TOP (solid shape): 256.34,33.18 256.34,32.61 256.21,32.49 255.45,32.49 255.38,32.42 255.38,31.28 254.56,30.45 253.99,30.45 253.86,30.58 253.86,31.22 254.37,31.72 254.37,33.18 254.5,33.31 256.21,33.31
GND on TOP (solid shape): 83.49,68.05 83.49,62.27 81.59,60.36 79.93,60.36 79.74,60.55 79.74,65.33 79.83,65.42 80.55,65.42 81.27,66.14 81.27,68.17 81.46,68.36 83.17,68.36
GND on TOP (solid shape): 271.43,45.42 271.43,44.53 271.43,44.53 271.43,44.35 271.24,44.16 270.95,44.16 270.79,44.32 270.34,44.32 269.98,43.95 269.51,43.95 269.25,44.22 269.25,45.37 269.39,45.51 271.34,45.51
GND on TOP (solid shape): 253.94,46.54 253.94,45.64 253.86,45.57 253.42,45.57 253.37,45.52 253.37,44.23 253.42,44.18 253.86,44.18 253.91,44.14 253.91,43.78 253.82,43.7 252.84,43.7 251.27,45.27 251.27,46.67 251.82,47.23 253.25,47.23
GND on TOP (solid shape): 187,70.21 187,66.14 186.87,66.01 185.98,66.01 185.85,66.14 185.85,66.65 185.34,67.16 185.34,67.41 183.44,69.32 183.44,70.33 183.57,70.46 186.74,70.46
GND on TOP (solid shape): 187.38,7.53 187.38,5.82 187.31,5.75 185.66,5.75 185.6,5.82 185.6,6.39 185.47,6.51 184.52,6.51 184.46,6.58 184.46,6.71 184.52,6.77 185.47,6.77 185.6,6.9 185.6,7.21 185.47,7.34 184.52,7.34 184.46,7.4 184.46,7.53 184.52,7.59 187.31,7.59
GND on TOP (solid shape): 64.82,15.6 64.82,13.69 61.84,10.71 61.84,9.69 61.65,9.5 60.44,9.5 60.38,9.56 60.38,11.29 60.63,11.54 60.63,11.62 61.56,12.55 61.56,14.18 61.84,14.45 61.84,15.79 61.96,15.91 64.5,15.91
GND on TOP (solid shape): 69.71,10.13 69.71,8.83 70.23,8.31 71.08,8.31 71.37,8.02 71.37,4.81 70.92,4.36 66.92,4.36 66.66,4.61 66.66,7.78 66.85,7.98 68.19,7.98 68.52,8.31 68.52,10.13 68.59,10.2 69.64,10.2
GND on TOP (solid shape): 143.88,70.97 143.95,70.97 143.95,70.96 144.32,70.96 144.33,70.96 145.34,70.96 145.34,70.97 145.66,70.97 146.16,71.48 147.05,71.48 147.18,71.35 147.18,71.09 146.99,70.9 146.67,70.9 146.1,70.33 143.5,70.33 142.99,70.84 142.16,70.84 142.1,70.9 142.1,71.48 142.16,71.54 143.31,71.54
GND on TOP (solid shape): 254.69,36.49 254.69,34.77 254.56,34.65 252.27,34.65 251.96,34.96 251.96,35.85 252.08,35.98 252.27,35.98 252.4,35.85 252.4,35.65 252.52,35.53 253.17,35.53 253.29,35.65 253.29,36.11 253.8,36.61 254.56,36.61
GND on TOP (solid shape): 276.75,77.5 276.79,77.5 283.65,77.5 283.65,74.45 273.9,74.45 273.75,74.44 273.61,74.4 272.73,74.4 272.09,74.4 271.45,75.03 271.45,76.87 271.96,77.38 273.36,77.38 273.86,76.87 274.63,76.87 275.26,77.51 276.71,77.51
GND on TOP (solid shape): 196.27,9.56 197.98,9.56 198.17,9.37 198.17,8.61 197.92,8.36 197.92,7.78 198.04,7.66 199.19,7.66 199.57,8.04 199.57,8.23 199.7,8.36 200.46,8.36 200.58,8.23 200.58,7.56 199.73,6.71 196.08,6.71 195.5,6.13 194.17,6.13 194.07,6.23 194.07,6.96 193.98,7.06 193.98,10.2 194.11,10.32 195.5,10.32
GND on TOP (solid shape): 203.51,63.98 203.51,63.16 204.58,62.08 204.58,60.62 204.39,60.43 203.51,60.43 203.31,60.24 203.31,58.33 203.69,57.95 204.8,57.95 204.92,57.84 204.92,57.14 204.77,57 200.01,57 199.95,57.06 199.95,57.95 200.46,58.46 200.46,61.12 200.65,61.32 201.47,61.32 201.66,61.51 201.66,62.78 201.47,62.97 201.47,63.98 201.6,64.11 203.38,64.11
GND on TOP (solid shape): 64.7,102.15 64.7,101.73 64.21,100.89 64.95,100.27 65.65,100.27 65.65,97.26 65.33,96.94 63.42,96.94 63.22,96.73 63.22,92.79 67.26,81.67 65.58,81.06 65.32,81.77 66.29,82.12 62.45,92.66 62.45,112.75 64.7,112.75
GND on TOP (solid shape): 143.43,77.32 143.43,76.62 143.62,76.43 144.13,76.43 144.22,76.34 144.22,75.4 144.52,75.09 145.2,75.09 145.32,75.21 146.09,75.21 146.16,75.14 146.16,74.65 146.04,74.52 144.83,74.52 144.61,74.3 144.61,74.24 144.61,74.23 144.61,72.55 143.53,72.55 143.34,72.75 141.85,72.75 141.08,72.75 140.89,72.55 139.62,72.55 139.37,72.81 139.29,72.81 139.28,72.81 139.19,72.82 139.1,72.81 139.09,72.81 138.29,72.81 138.1,73 138.1,73.57 138.23,73.7 139.37,73.7 139.56,73.89 139.56,74.27 138.8,75.03 138.8,76.81 139.31,77.32 140.64,77.32 140.89,77.06 140.89,76.56 141.02,76.43 141.59,76.43 141.72,76.3 141.72,75.98 141.59,75.86 140.96,75.86 140.77,75.67 140.77,73.7 140.96,73.51 141.91,73.51 142.1,73.7 142.1,74.65 142.67,75.22 142.67,77.32 142.8,77.44 143.31,77.44
GND on TOP (solid shape): 205.55,106.61 205.06,105.77 205.8,105.15 206.56,105.15 207.12,104.58 207.12,102.34 206.81,102.02 203.82,102.02 202.49,100.69 202.49,97.7 201.79,97 200.58,97 200.27,97.32 200.27,100.27 200.95,100.27 201.55,100.56 201.68,101.21 201.67,101.23 201.5,101.54 201.2,101.73 201.2,112.75 205.55,112.75
GND on TOP (solid shape): 280.75,42.85 283.65,42.85 283.65,32.46 283.62,32.35 283.33,32 283.25,31.66 283.25,2.2 282.73,0.97 281.5,0.45 278.19,0.45 277.84,0.81 277.84,3.06 279.4,4.63 282.17,4.63 282.49,4.94 282.49,31.66 282.59,32.21 282.89,32.69 282.89,33.21 275.52,40.58 275.52,43.4 275.05,43.87 273.41,43.87 273.04,44.24 273.04,45.12 273.41,45.49 273.43,45.49 273.61,45.67 277.93,45.67
GND on TOP (solid shape): 232.95,98.65 233.17,98.12 233.7,97.9 239.06,97.9 239.06,97.89 242.04,97.89 242.68,98.53 242.68,108.17 243,108.5 243.45,108.5 243.76,108.18 243.76,97.64 242.24,96.11 240.21,96.11 239.19,97.13 233.7,97.13 232.63,97.58 232.18,98.65 232.18,102.91 231.17,103.92 223.63,103.92 221.67,101.96 220.52,101.96 220.21,102.27 220.21,104.52 220.84,105.15 221.5,105.15 222.24,105.77 221.75,106.61 221.75,112.75 232.95,112.75
GND on TOP (solid shape): outline of 129 points within 197.25,20.55 202.93,30.14
GND on TOP (solid shape): outline of 144 points within 152.81,27.84 158.94,32.77
GND on TOP (solid shape): 277.48,96.3 277.8,96.22 279.39,94.97 281.05,94.6 282.82,94.6 283.29,94.24 283.65,93.77 283.65,89.81 282.62,89.81 282.62,86.81 277.18,86.81 276.59,87.39 276.59,88.24 276.78,88.43 279.57,88.43 280.33,89.19 280.33,93.89 279.9,93.98 279.47,94.11 279.47,94.47 278.71,94.47 278.41,94.67 278.12,94.89 278.12,95.68 277.08,95.68 276.62,95.68 275.58,95.68 275.25,95.68 275.25,95.53 274.21,95.53 269.72,91.92 268.08,90.58 265.99,90.26 265.99,90.91 266.02,90.99 266.1,91.01 267.78,91.28 269.1,92.36 269.17,92.44 269.24,92.51 273.73,96.13 273.95,96.25 274.2,96.3
GND on TOP (solid shape): 51.18,88.54 52.45,85.06 54.3,83.52 54.61,82.74 56.18,78.44 57.13,78.79 57.39,78.07 55.72,77.47 53.97,82.29 53.73,82.96 53.63,83.25 51.72,84.82 50.57,87.98 49.41,88.52 48.02,88.01 46.9,86.98 46.84,85.45 47.43,83.69 47.89,81.89 47.9,81.89 50.09,81.89 50.41,81.57 50.41,80.24 50.03,79.86 48.25,79.86 48.44,78.1 48.5,76.33 48.5,75.26 47.76,68.42 45.57,61.89 47.89,60.02 48.44,59.01 48.12,57.9 51.11,55.48 52.31,54.73 52.14,53.33 51.86,52.98 51.3,53.5 51.55,53.81 51.57,54.49 50.93,54.68 50.9,54.67 47.05,57.79 47.52,58.37 47.68,58.92 47.41,59.43 44.63,61.68 44.65,61.71 46.95,68.31 47.73,75.26 47.73,76.33 47.67,78.18 47.46,80.02 47.23,80.66 47.23,81.33 46.76,83.28 46.13,85.19 46.21,87.3 47.76,88.73 49.45,89.34
GND on TOP (solid shape): outline of 95 points within 0.25,0.25 272.84,52.58
GND on TOP (solid shape): outline of 95 points within 0.25,0.25 272.84,52.58
GND on TOP (solid shape): outline of 85 points within 77.71,96.66 188.14,112.75
GND on BOTTOM (solid shape): 80.25,81.84 80.25,78.45 79.18,77.37 75.4,77.37 74.21,78.57 74.21,81.92 74.93,82.65 79.44,82.65
GND on BOTTOM (solid shape): 85.53,15.55 85.53,14.34 85.4,14.21 76.75,14.21 76.64,14.31 76.64,15.55 76.87,15.78 85.3,15.78
GND on BOTTOM (solid shape): 87.87,59.54 87.87,56.11 87.74,55.98 85.46,55.98 85.33,56.11 85.33,59.54 85.52,59.73 87.68,59.73
GND on BOTTOM (solid shape): 91.97,74.88 91.97,72.46 91.81,72.3 86.6,72.3 86.47,72.43 86.47,74.78 86.98,75.29 91.56,75.29
GND on BOTTOM (solid shape): 161.09,3.97 161.09,1.88 160.58,1.37 153.66,1.37 153.15,1.88 153.15,3.97 153.98,4.8 160.26,4.8
GND on BOTTOM (solid shape): 187,68.3 187,65 186.23,64.24 185.34,64.24 185.28,64.3 185.28,68.17 185.6,68.49 186.8,68.49
GND on BOTTOM (solid shape): 204.01,69.7 204.01,66.33 203.25,65.57 201.98,65.57 201.47,66.08 201.47,69.7 201.6,69.82 203.89,69.82
GND on BOTTOM (solid shape): 269.04,89.7 269.04,88.24 267.77,86.97 266.69,86.97 266.56,87.1 266.56,89.64 266.81,89.89 268.85,89.89
GND on BOTTOM (solid shape): 178.64,60.81 178.64,53.83 178.36,53.55 175.83,53.55 175.25,54.13 175.25,59.92 175.52,60.19 175.52,60.58 176.09,61.15 178.31,61.15
GND on BOTTOM (solid shape): 210.39,43.86 210.39,39.12 210.05,38.77 208.65,38.77 208.59,38.84 208.59,43.63 208.89,43.93 210.32,43.93
GND on BOTTOM (solid shape): 219.9,100.66 219.9,98.24 220.15,97.99 220.15,97.58 220.07,97.5 218.49,97.5 218.28,97.72 218.28,99.94 219.13,100.79 219.77,100.79
GND on BOTTOM (solid shape): 71.31,7.92 71.31,4.92 70.75,4.36 67.07,4.36 66.82,4.6 66.82,7.57 67.25,8 68.09,8 68.34,8.25 70.97,8.25
GND on BOTTOM (solid shape): 94.29,83.1 94.29,80.24 93.84,79.79 92.06,79.79 91.94,79.92 91.94,80.49 92.51,80.49 92.51,82.52 91.94,82.52 91.94,83.03 92.25,83.35 94.03,83.35
GND on BOTTOM (solid shape): 99.05,93.49 99.05,91.1 98.42,90.46 95.87,90.46 95.75,90.59 95.75,90.97 95.75,91.22 96.61,92.09 96.61,93.17 97,93.56 98.98,93.56
GND on BOTTOM (solid shape): 208.01,7.92 208.01,5.87 207.63,5.5 207.02,5.5 206.83,5.31 203.12,5.31 202.93,5.5 202.93,8.04 203.19,8.29 207.63,8.29
GND on BOTTOM (solid shape): 84.13,97.27 84.78,96.93 85.46,96.65 85.46,94.84 85.13,94.51 83.48,94.51 82.8,95.19 82.8,97.13 82.94,97.27
GND on BOTTOM (solid shape): 99.4,89.85 99.4,88.63 99.72,88.3 99.72,86.52 98.98,85.78 98.98,85.25 98.67,84.94 95.49,84.94 94.92,85.51 94.92,90.21 99.04,90.21
GND on BOTTOM (solid shape): 140.78,90.38 140.78,90.02 140.72,89.95 140.67,89.95 139.56,88.84 139.56,88.46 138.91,87.81 138.91,87.75 138.45,87.75 138.13,88.07 138.13,90.35 138.2,90.42 139.48,90.42 139.53,90.46 140.7,90.46
GND on BOTTOM (solid shape): 211.89,70.62 211.89,69.72 212.24,69.37 213.2,69.37 213.33,69.24 213.33,67.02 213.14,66.83 209.79,66.83 209.5,67.13 209.5,69.14 210.21,69.85 210.21,70.5 210.43,70.72 211.79,70.72
GND on BOTTOM (solid shape): 54.98,6.67 54.77,6.46 54.77,5.59 54.62,5.44 54.4,5.44 54.32,5.53 54.32,6.42 53.96,6.77 53.96,7.33 53.98,7.34 54.98,7.34
GND on BOTTOM (solid shape): 198.99,95.57 198.99,94.79 199.16,94.62 199.71,94.62 199.99,94.34 199.99,90.5 199.82,90.33 198.68,90.33 198.3,90.72 198.3,91.76 198.46,91.93 198.46,95.59 198.51,95.65 198.92,95.65
GND on BOTTOM (solid shape): 65.01,15.66 65.01,14.9 63.87,13.75 63.2,13.75 61.9,12.45 61.9,9.69 61.77,9.56 60.5,9.56 60.38,9.69 60.38,11.09 60.79,11.5 60.79,11.94 60.91,12.05 60.91,12.46 61.85,13.41 61.85,15.76 62,15.91 64.76,15.91
GND on BOTTOM (solid shape): 156.79,88.81 156.79,87.63 156.71,87.55 156.04,87.18 155.45,86.68 155.44,86.67 154.52,86.67 154.29,86.9 154.29,88.53 154.31,88.55 154.81,88.55 155.35,89.09 156.51,89.09
GND on BOTTOM (solid shape): 276.75,77.5 276.79,77.5 283.65,77.5 283.65,74.45 273.9,74.45 273.75,74.44 273.61,74.4 272.73,74.4 272.09,74.4 271.45,75.03 271.45,76.87 271.96,77.38 273.36,77.38 273.86,76.87 274.63,76.87 275.26,77.51 276.71,77.51
GND on BOTTOM (solid shape): 193.98,65.81 193.98,61.06 193.54,60.62 192.33,60.62 192.08,60.36 189.47,60.36 189.41,60.43 189.41,62.27 189.47,62.33 189.73,62.33 189.73,61.06 191.31,61.06 191.31,62.46 192.35,63.49 193.22,63.49 193.3,63.57 193.3,65.32 193.3,65.74 193.46,65.9 193.9,65.9
GND on BOTTOM (solid shape): 83.55,68.62 83.55,67.67 83.62,67.6 84.57,67.6 84.63,67.54 84.63,67.41 84.57,67.35 83.62,67.35 83.55,67.28 83.55,64.62 83.24,64.3 83.24,61.89 83.05,61.7 82.54,61.7 81.14,60.3 80.06,60.3 79.78,60.58 79.78,63.95 80.44,64.62 81.14,64.62 81.27,64.74 81.27,68.68 83.49,68.68
GND on BOTTOM (solid shape): 106.71,75.25 106.71,74.46 106.67,74.42 106.07,74.42 105.98,74.33 105.98,73.89 105.84,73.75 105.58,73.75 105.45,73.88 105.45,74.36 105.4,74.41 104.25,74.41 104.19,74.35 104.19,73.9 104.05,73.76 103.77,73.76 103.52,74.02 103.52,74.33 103.44,74.41 102.5,74.41 102.37,74.28 102.37,73.88 102.27,73.77 101.94,73.77 101.8,73.91 101.8,75.25 101.84,75.29 106.67,75.29
GND on BOTTOM (solid shape): 196.64,86.63 196.64,84.44 196.39,84.24 196.26,84.25 196.16,84.26 196.06,84.22 196.04,84.21 195.99,84.21 195.16,85.04 193.05,85.04 192.84,85.24 192.84,86.54 192.59,86.8 192.21,86.8 192.09,86.92 192.09,87.33 192.19,87.43 195.84,87.43
GND on BOTTOM (solid shape): 106.79,71.09 106.16,71.09 106.03,70.97 106.03,70.52 105.91,70.4 105.65,70.4 105.52,70.52 105.52,71.03 105.46,71.09 104.45,71.09 104.32,70.97 104.32,70.52 104.19,70.4 103.94,70.4 103.81,70.52 103.81,70.97 103.68,71.09 102.73,71.09 102.6,70.97 102.6,70.52 102.48,70.4 102.22,70.4 101.96,70.66 101.96,71.9 101.98,71.92 106.79,71.92
GND on BOTTOM (solid shape): 131.54,89.3 131.54,88.76 132.15,88.15 132.15,86.69 132.55,86.28 132.7,86.28 132.7,85.94 132.53,85.78 131.98,85.78 131.36,86.4 131.36,87.56 131.21,87.7 130.71,87.7 130.71,87.71 129.36,87.71 129.36,87.71 128.47,87.71 128.3,87.87 128.3,88.41 128.42,88.53 129,88.53 129.08,88.61 129.08,89.36 129.26,89.53 131.3,89.53
GND on BOTTOM (solid shape): 106.86,68.52 106.86,67.76 106.83,67.73 106.16,67.73 106.03,67.6 106.03,67.16 105.91,67.03 105.72,67.03 105.52,67.22 105.52,67.6 105.4,67.73 104.51,67.73 104.32,67.54 104.32,67.16 104.19,67.03 103.94,67.03 103.81,67.16 103.81,67.6 103.68,67.73 102.79,67.73 102.6,67.54 102.6,67.16 102.48,67.03 102.29,67.03 102.16,67.16 102.16,67.6 102.03,67.73 101.02,67.73 100.89,67.6 100.89,67.16 100.76,67.03 100.57,67.03 100.25,67.35 100.25,68.52 100.29,68.55 106.83,68.55
GND on BOTTOM (solid shape): 64.7,102.15 64.7,101.73 64.21,100.89 64.95,100.27 65.65,100.27 65.65,97.26 65.33,96.94 63.42,96.94 63.22,96.73 63.22,92.79 67.26,81.67 65.58,81.06 65.32,81.77 66.29,82.12 62.45,92.66 62.45,112.75 64.7,112.75
GND on BOTTOM (solid shape): 247.2,2.2 242.18,2.2 242.18,18.84 243.96,20.6 242.18,22.36 242.18,34.63 247.2,34.63
GND on BOTTOM (solid shape): 275.65,46.05 275.65,45.01 275.51,44.87 275.13,44.87 274.69,45.32 273.22,45.32 272.69,44.78 272.69,43.38 272.36,43.06 270.15,43.06 269.66,43.56 269.66,43.85 270.38,43.85 270.38,43.8 270.39,43.75 270.41,43.7 270.43,43.65 270.46,43.61 270.5,43.57 270.54,43.53 270.58,43.51 270.63,43.49 270.69,43.48 270.74,43.47 270.79,43.48 270.84,43.49 270.89,43.51 270.94,43.53 270.98,43.57 271.02,43.61 271.05,43.65 271.07,43.7 271.09,43.75 271.09,43.8 271.09,43.85 271.09,43.91 271.07,43.96 271.05,44.01 271.02,44.05 270.98,44.09 270.94,44.12 270.89,44.15 270.84,44.17 270.79,44.18 270.74,44.18 270.69,44.18 270.63,44.17 270.58,44.15 270.54,44.12 270.5,44.09 270.46,44.05 270.43,44.01 270.41,43.96 270.39,43.91 270.38,43.85 269.66,43.85 269.66,44.99 270.81,46.14 275.56,46.14
GND on BOTTOM (solid shape): 205.55,106.61 205.06,105.77 205.8,105.15 206.56,105.15 207.12,104.58 207.12,102.34 206.81,102.02 203.82,102.02 202.49,100.69 202.49,97.7 201.8,97.01 200.65,97.01 200.27,97.39 200.27,100.27 200.95,100.27 201.55,100.56 201.68,101.21 201.67,101.23 201.5,101.54 201.2,101.73 201.2,112.75 205.55,112.75
GND on BOTTOM (solid shape): 283.65,32.46 283.62,32.35 283.33,32 283.25,31.66 283.25,2.2 282.73,0.97 281.5,0.45 278.19,0.45 278.19,1.21 281.5,1.21 282.2,1.5 282.49,2.2 282.49,31.66 282.59,32.21 282.89,32.69 282.89,33.02 277.62,38.29 277.62,41.43 279.04,42.85 283.65,42.85
GND on BOTTOM (solid shape): 232.95,98.65 233.17,98.12 233.7,97.9 239.06,97.9 239.06,97.13 233.7,97.13 232.63,97.58 232.18,98.65 232.18,103.82 230.43,105.57 225.29,105.57 221.67,101.96 220.52,101.96 220.21,102.27 220.21,104.52 220.84,105.15 221.5,105.15 222.24,105.77 221.75,106.61 221.75,112.75 232.95,112.75
GND on BOTTOM (solid shape): 277.48,96.3 277.8,96.22 279.39,94.97 281.05,94.6 282.82,94.6 283.29,94.24 283.65,93.77 283.65,89.81 282.65,89.81 282.65,86.81 277.18,86.81 276.59,87.39 276.59,88.24 276.78,88.43 279.2,88.43 280.33,89.56 280.33,93.89 279.9,93.98 279.47,94.11 278.71,94.47 278.41,94.67 278.12,94.89 277.45,95.53 274.21,95.53 269.72,91.92 268.08,90.58 265.99,90.26 265.99,90.91 266.02,90.99 266.1,91.01 267.78,91.28 269.1,92.36 269.17,92.44 269.24,92.51 273.73,96.13 273.95,96.25 274.2,96.3
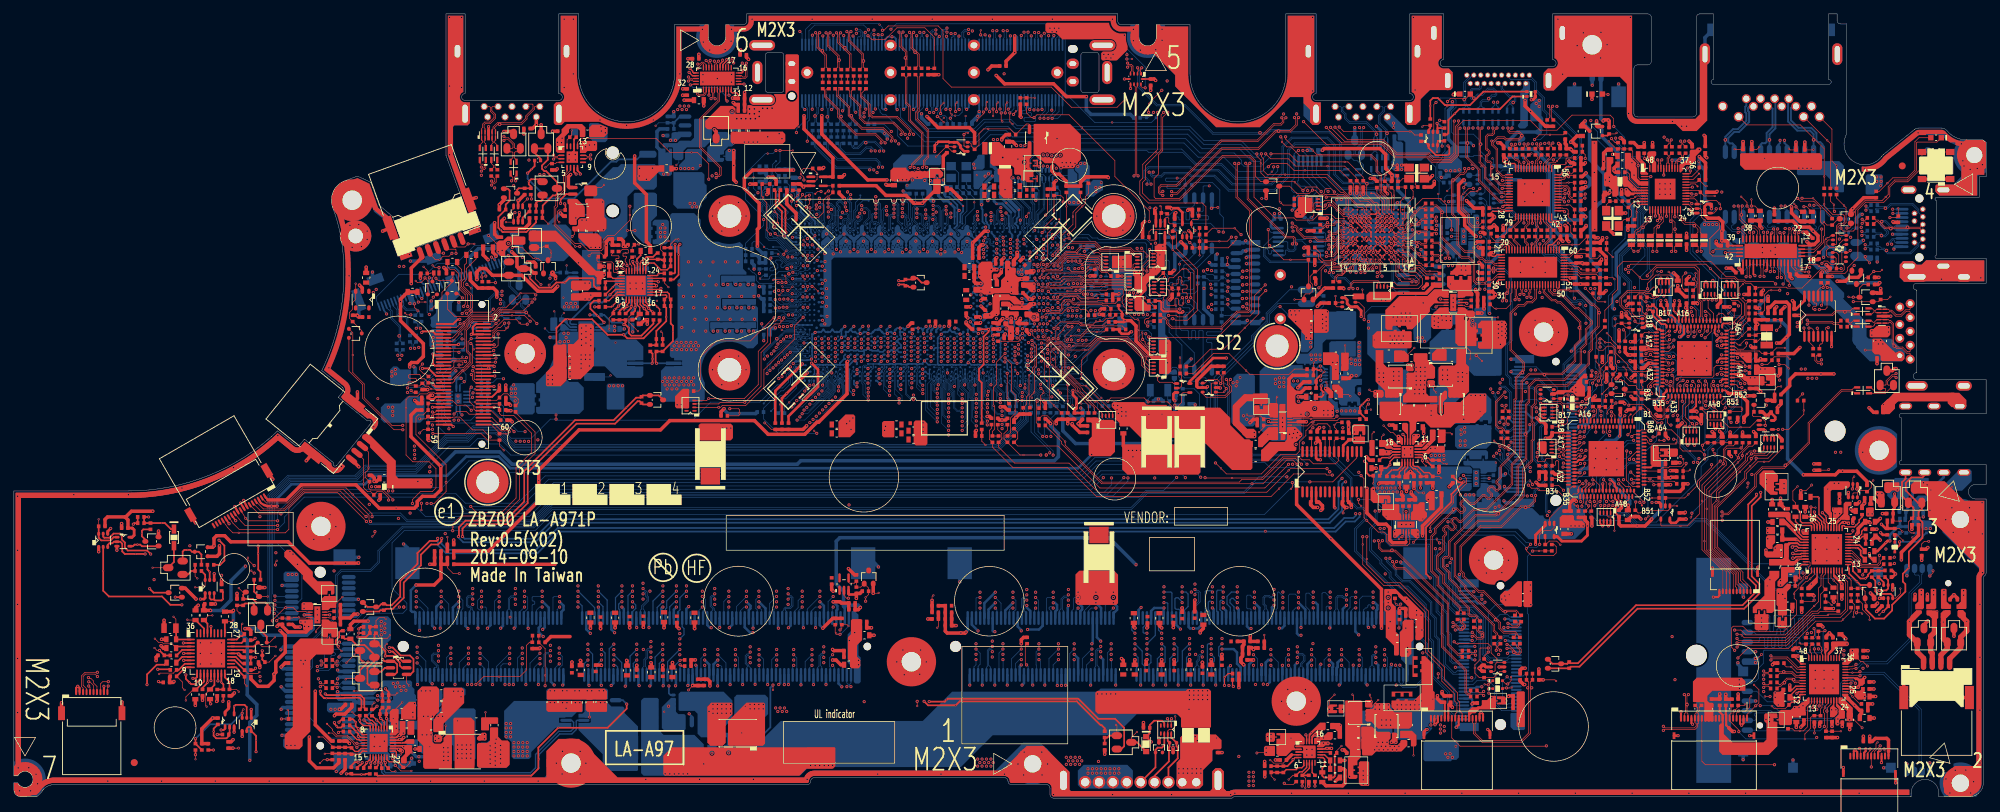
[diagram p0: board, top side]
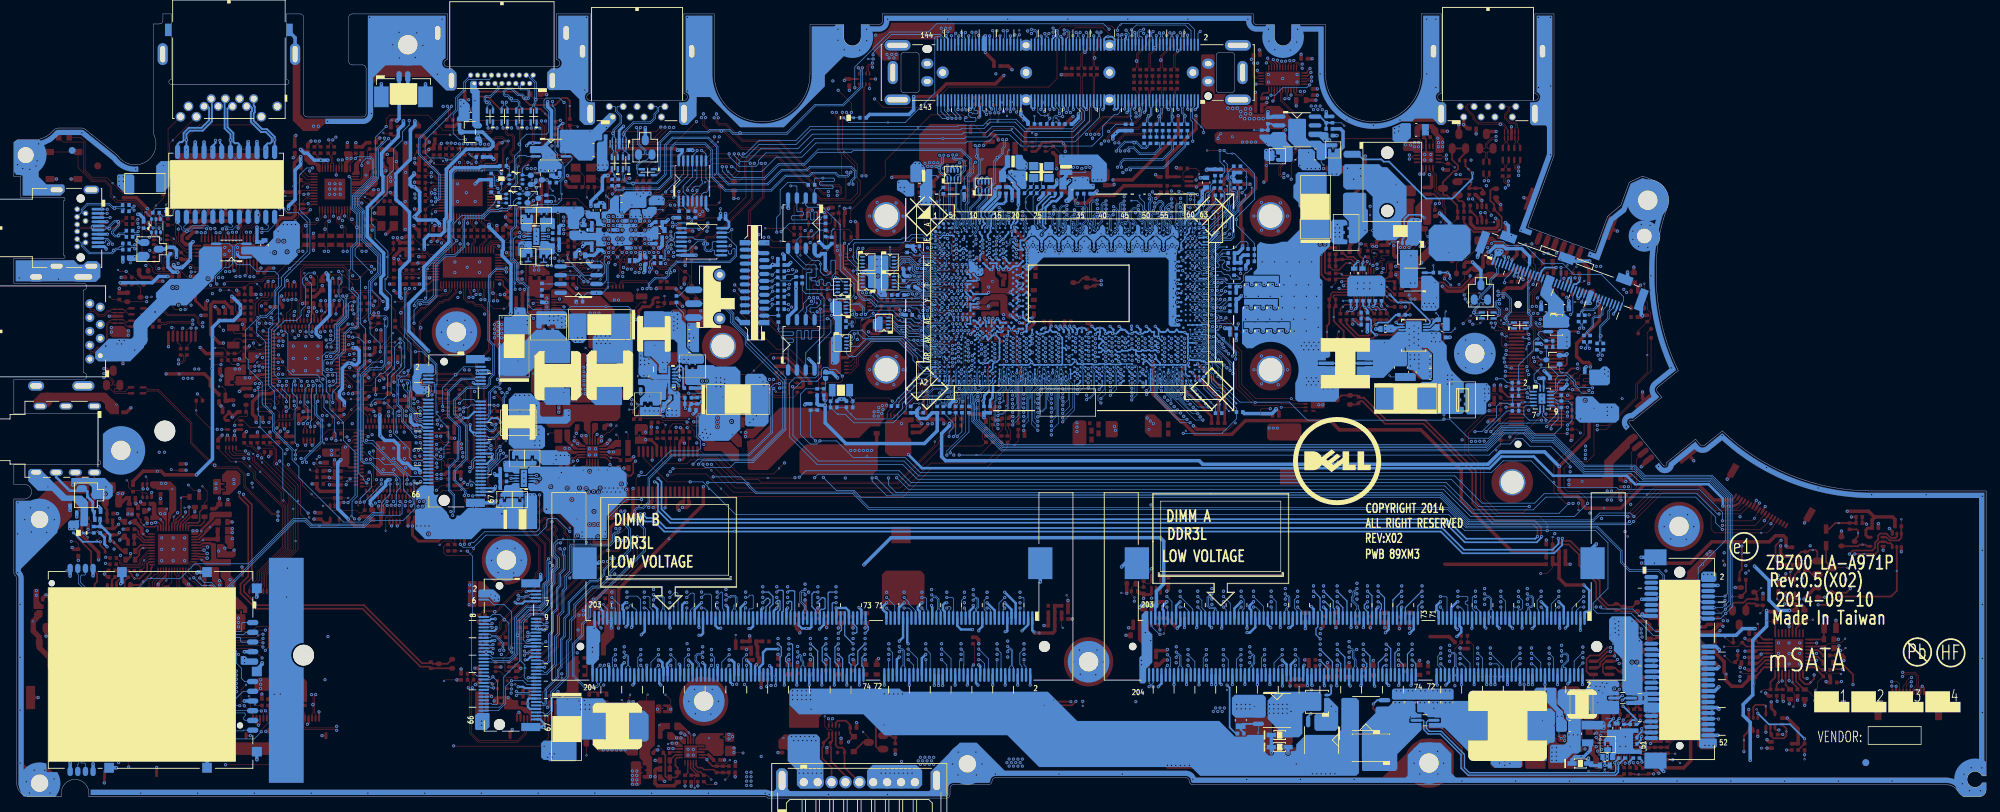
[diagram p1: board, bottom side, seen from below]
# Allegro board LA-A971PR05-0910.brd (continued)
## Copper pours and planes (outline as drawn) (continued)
GND on BOTTOM (solid shape): 51.18,88.54 52.45,85.04 54.27,83.54 54.61,82.74 56.18,78.44 57.13,78.79 57.39,78.07 55.72,77.47 53.97,82.29 53.95,82.3 53.58,83.16 51.85,84.47 50.57,87.98 49.41,88.52 48.02,88.01 46.9,86.98 46.84,85.45 47.43,83.69 47.89,81.89 47.9,81.89 50.09,81.89 50.41,81.57 50.41,80.24 50.03,79.86 48.25,79.86 48.44,78.1 48.5,76.33 48.5,75.26 48.48,74.29 48.44,73.32 48.31,73.19 48.31,73.13 48.42,73.02 47.5,67.33 45.57,61.89 47.89,60.02 48.44,59.01 48.12,57.9 51.11,55.48 52.31,54.73 52.14,53.33 51.86,52.98 51.3,53.5 51.55,53.81 51.57,54.49 50.93,54.68 50.9,54.67 47.05,57.79 47.52,58.37 47.68,58.92 47.41,59.43 44.63,61.68 44.65,61.71 46.95,68.31 47.73,75.26 47.73,76.33 47.67,78.18 47.46,80.02 47.23,80.66 47.23,81.33 46.76,83.28 46.13,85.19 46.21,87.3 47.76,88.73 49.45,89.34
GND on BOTTOM (solid shape): outline of 98 points within 0.25,0.25 272.84,52.58
GND on BOTTOM (solid shape): outline of 86 points within 77.71,96.66 188.14,112.75
GND on BOTTOM (solid shape): outline of 376 points within 116.23,79.97 138.05,82.63
GND on IN1 (solid shape): 70.41,8.05 70.41,4.74 70.15,4.49 68.18,4.49 67.93,4.74 67.93,7.85 68.38,8.29 70.17,8.29
GND on IN1 (solid shape): 83.49,68.05 83.49,63.09 80.89,60.49 79.81,60.49 79.74,60.55 79.74,63.73 81.27,65.25 81.27,68.17 81.46,68.36 83.17,68.36
GND on IN1 (solid shape): 276.75,77.5 276.79,77.5 283.65,77.5 283.65,74.45 273.9,74.45 273.75,74.44 273.61,74.4 272.73,74.4 272.09,74.4 271.45,75.03 271.45,76.87 271.96,77.38 273.36,77.38 273.86,76.87 274.63,76.87 275.26,77.51 276.71,77.51
GND on IN1 (solid shape): 64.7,102.15 64.7,101.73 64.21,100.89 64.95,100.27 65.65,100.27 65.65,97.26 65.33,96.94 63.42,96.94 63.22,96.73 63.22,92.79 67.26,81.67 65.58,81.06 65.32,81.77 66.29,82.12 62.45,92.66 62.45,112.75 64.7,112.75
GND on IN1 (solid shape): 235.44,112.49 235.44,106.22 235.13,105.91 233.37,105.91 232.95,105.49 232.95,103.92 223.63,103.92 221.67,101.96 220.52,101.96 220.21,102.27 220.21,104.52 220.84,105.15 221.5,105.15 222.24,105.77 221.75,106.61 221.75,112.75 235.17,112.75
GND on IN1 (solid shape): 283.65,32.46 283.62,32.35 283.33,32 283.25,31.66 283.25,2.2 282.73,0.97 281.5,0.45 278.08,0.45 277.86,0.67 277.86,3.05 279.43,4.62 282.24,4.62 282.49,4.87 282.49,31.66 282.59,32.21 282.89,32.69 282.89,33 277.76,38.12 277.76,41.61 278.99,42.85 283.65,42.85
GND on IN1 (solid shape): 205.55,106.61 205.06,105.77 205.8,105.15 206.56,105.15 207.12,104.58 207.12,102.34 206.81,102.02 203.82,102.02 202.49,100.69 202.49,97.7 201.79,97 200.58,97 200.27,97.32 200.27,100.27 200.95,100.27 201.55,100.56 201.68,101.21 201.67,101.23 201.5,101.54 201.2,101.73 201.2,112.75 205.55,112.75
GND on IN1 (solid shape): 277.48,96.3 277.8,96.22 279.39,94.97 281.05,94.6 282.82,94.6 283.29,94.24 283.65,93.77 283.65,89.83 282.64,89.83 282.64,86.81 277.18,86.81 276.59,87.39 276.59,88.24 276.78,88.43 279.2,88.43 280.33,89.56 280.33,93.89 279.9,93.98 279.47,94.11 278.71,94.47 278.41,94.67 278.12,94.89 277.45,95.53 274.21,95.53 269.72,91.92 268.08,90.58 265.99,90.26 265.99,90.91 266.02,90.99 266.1,91.01 267.78,91.28 269.1,92.36 269.17,92.44 269.24,92.51 273.73,96.13 273.95,96.25 274.2,96.3
GND on IN1 (solid shape): 51.18,88.54 52.38,85.22 54.31,83.59 54.37,83.43 54.61,82.74 56.18,78.44 57.13,78.79 57.39,78.07 55.72,77.47 53.97,82.29 53.97,82.29 53.48,83.29 51.7,84.88 50.57,87.98 49.41,88.52 48.02,88.01 46.9,86.98 46.84,85.45 47.43,83.69 47.89,81.89 47.9,81.89 50.09,81.89 50.41,81.57 50.41,80.24 50.03,79.86 48.25,79.86 48.44,78.1 48.5,76.33 48.5,75.26 47.76,68.42 45.57,61.89 47.89,60.02 48.44,59.01 48.12,57.9 51.11,55.48 52.31,54.73 52.14,53.33 51.86,52.98 51.3,53.5 51.55,53.81 51.57,54.49 50.93,54.68 50.9,54.67 47.05,57.79 47.52,58.37 47.68,58.92 47.41,59.43 44.63,61.68 44.65,61.71 46.95,68.31 47.73,75.26 47.73,76.33 47.67,78.18 47.46,80.02 47.23,80.66 47.23,81.33 46.76,83.28 46.13,85.19 46.21,87.3 47.76,88.73 49.45,89.34
GND on IN1 (solid shape): outline of 94 points within 0.25,0.25 272.84,52.58
GND on IN1 (solid shape): outline of 87 points within 77.71,96.66 188.14,112.75
GND on IN2 (solid shape): 70.27,8.09 70.27,4.67 69.95,4.36 68.31,4.36 67.93,4.74 67.93,7.85 68.38,8.29 70.07,8.29
GND on IN2 (solid shape): 83.49,68.05 83.49,63.09 80.89,60.49 79.87,60.49 79.78,60.58 79.78,63.76 81.27,65.25 81.27,68.17 81.46,68.36 83.17,68.36
GND on IN2 (solid shape): 276.75,77.5 276.79,77.5 283.65,77.5 283.65,74.45 273.9,74.45 273.75,74.44 273.61,74.4 272.73,74.4 272.09,74.4 271.45,75.03 271.45,76.87 271.96,77.38 273.36,77.38 273.86,76.87 274.63,76.87 275.26,77.51 276.71,77.51
GND on IN2 (solid shape): 64.7,102.15 64.7,101.73 64.21,100.89 64.95,100.27 65.65,100.27 65.65,97.26 65.33,96.94 63.42,96.94 63.22,96.73 63.22,92.79 67.26,81.67 65.58,81.06 65.32,81.77 66.29,82.12 62.45,92.66 62.45,112.75 64.7,112.75
GND on IN2 (solid shape): 283.65,32.46 283.62,32.35 283.33,32 283.25,31.66 283.25,2.2 282.73,0.97 281.5,0.45 278.19,0.45 277.91,0.74 277.91,3.18 279.19,4.46 281.98,4.46 282.49,4.97 282.49,31.66 282.59,32.21 282.89,32.69 282.89,33.2 277.64,38.44 277.64,41.5 278.99,42.85 283.65,42.85
GND on IN2 (solid shape): 205.55,106.61 205.06,105.77 205.8,105.15 206.56,105.15 207.12,104.58 207.12,102.34 206.81,102.02 203.82,102.02 202.49,100.69 202.49,97.7 201.79,97 200.58,97 200.27,97.32 200.27,100.27 200.95,100.27 201.55,100.56 201.68,101.21 201.67,101.23 201.5,101.54 201.2,101.73 201.2,112.75 205.55,112.75
GND on IN2 (solid shape): 232.95,98.65 233.17,98.12 233.7,97.9 239.06,97.9 239.06,97.13 233.7,97.13 232.63,97.58 232.18,98.65 232.18,102.91 231.17,103.92 223.63,103.92 221.67,101.96 220.52,101.96 220.21,102.27 220.21,104.52 220.84,105.15 221.5,105.15 222.24,105.77 221.75,106.61 221.75,112.75 232.95,112.75
GND on IN2 (solid shape): 277.48,96.3 277.8,96.22 279.39,94.97 281.05,94.6 282.82,94.6 283.29,94.24 283.65,93.77 283.65,89.83 282.64,89.83 282.64,86.81 277.18,86.81 276.59,87.39 276.59,88.24 276.78,88.43 279.2,88.43 280.33,89.56 280.33,93.89 279.9,93.98 279.47,94.11 278.71,94.47 278.41,94.67 278.12,94.89 277.45,95.53 274.21,95.53 269.72,91.92 268.08,90.58 265.99,90.26 265.99,90.91 266.02,90.99 266.1,91.01 267.78,91.28 269.1,92.36 269.17,92.44 269.24,92.51 273.73,96.13 273.95,96.25 274.2,96.3
GND on IN2 (solid shape): 51.18,88.54 52.45,85.06 54.3,83.53 54.61,82.74 56.18,78.44 57.13,78.79 57.39,78.07 55.72,77.47 53.97,82.29 53.97,82.29 53.64,83.23 52.98,83.79 51.71,84.86 50.57,87.98 49.41,88.52 48.02,88.01 46.9,86.98 46.84,85.45 47.43,83.69 47.89,81.89 47.9,81.89 50.09,81.89 50.41,81.57 50.41,80.24 50.03,79.86 48.25,79.86 48.44,78.1 48.5,76.33 48.5,75.26 47.76,68.42 45.57,61.89 47.89,60.02 48.44,59.01 48.12,57.9 51.11,55.48 52.31,54.73 52.14,53.33 51.86,52.98 51.3,53.5 51.55,53.81 51.57,54.49 50.93,54.68 50.9,54.67 47.05,57.79 47.52,58.37 47.68,58.92 47.41,59.43 44.63,61.68 44.65,61.71 46.95,68.31 47.73,75.26 47.73,76.33 47.67,78.18 47.46,80.02 47.23,80.66 47.23,81.33 46.76,83.28 46.13,85.19 46.21,87.3 47.76,88.73 49.45,89.34
GND on IN2 (solid shape): outline of 100 points within 0.25,0.25 272.84,52.58
GND on IN2 (solid shape): outline of 91 points within 77.71,96.66 188.14,112.75
GND on IN2 (solid shape): outline of 5900 points within 57.44,15.18 119.31,31.5
GND on IN3 (solid shape): 70.28,8.09 70.28,4.69 69.94,4.36 68.31,4.36 67.93,4.74 67.93,7.85 68.38,8.29 70.08,8.29
GND on IN3 (solid shape): 83.49,68.05 83.49,63.09 80.89,60.49 79.87,60.49 79.71,60.65 79.71,63.7 81.27,65.25 81.27,68.17 81.46,68.36 83.17,68.36
GND on IN3 (solid shape): 276.75,77.5 276.79,77.5 283.65,77.5 283.65,74.45 273.9,74.45 273.75,74.44 273.61,74.4 272.73,74.4 272.09,74.4 271.45,75.03 271.45,76.87 271.96,77.38 273.36,77.38 273.86,76.87 274.63,76.87 275.26,77.51 276.71,77.51
GND on IN3 (solid shape): 64.7,102.15 64.7,101.73 64.21,100.89 64.95,100.27 65.65,100.27 65.65,97.26 65.33,96.94 63.42,96.94 63.22,96.73 63.22,92.79 67.26,81.67 65.58,81.06 65.32,81.77 66.29,82.12 62.45,92.66 62.45,112.75 64.7,112.75
GND on IN3 (solid shape): 283.65,32.46 283.62,32.35 283.33,32 283.25,31.66 283.25,2.2 282.73,0.97 281.5,0.45 278.19,0.45 277.91,0.74 277.91,3.2 279.19,4.48 281.95,4.48 282.49,5.02 282.49,31.66 282.59,32.21 282.89,32.69 282.89,33.02 277.64,38.26 277.64,41.5 278.99,42.85 283.65,42.85
GND on IN3 (solid shape): 205.55,106.61 205.06,105.77 205.8,105.15 206.56,105.15 207.12,104.58 207.12,102.34 206.81,102.02 203.82,102.02 202.49,100.69 202.49,97.7 201.79,97 200.58,97 200.27,97.32 200.27,100.27 200.95,100.27 201.55,100.56 201.68,101.21 201.67,101.23 201.5,101.54 201.2,101.73 201.2,112.75 205.55,112.75
GND on IN3 (solid shape): 232.95,98.65 233.17,98.12 233.7,97.9 239.06,97.9 239.06,97.13 233.7,97.13 232.63,97.58 232.18,98.65 232.18,102.91 231.17,103.92 223.63,103.92 221.67,101.96 220.52,101.96 220.21,102.27 220.21,104.52 220.84,105.15 221.5,105.15 222.24,105.77 221.75,106.61 221.75,112.75 232.95,112.75
GND on IN3 (solid shape): 277.48,96.3 277.8,96.22 279.39,94.97 281.05,94.6 282.82,94.6 283.29,94.24 283.65,93.77 283.65,89.82 282.64,89.82 282.64,86.81 277.18,86.81 276.59,87.39 276.59,88.24 276.78,88.43 279.2,88.43 280.33,89.56 280.33,93.89 279.9,93.98 279.47,94.11 278.71,94.47 278.41,94.67 278.12,94.89 277.45,95.53 274.21,95.53 269.72,91.92 268.08,90.58 265.99,90.26 265.99,90.91 266.02,90.99 266.1,91.01 267.78,91.28 269.1,92.36 269.17,92.44 269.24,92.51 273.73,96.13 273.95,96.25 274.2,96.3
GND on IN3 (solid shape): 51.18,88.54 52.37,85.27 54.27,83.65 54.61,82.74 56.18,78.44 57.13,78.79 57.39,78.07 55.72,77.47 53.97,82.29 53.58,83.15 51.85,84.46 50.57,87.98 49.41,88.52 48.02,88.01 46.9,86.98 46.84,85.45 47.43,83.69 47.89,81.89 47.9,81.89 50.09,81.89 50.41,81.57 50.41,80.24 50.03,79.86 48.25,79.86 48.44,78.1 48.5,76.33 48.5,75.26 47.76,68.42 45.57,61.89 47.89,60.02 48.44,59.01 48.12,57.9 51.11,55.48 52.31,54.73 52.14,53.33 51.86,52.98 51.3,53.5 51.55,53.81 51.57,54.49 50.93,54.68 50.9,54.67 47.05,57.79 47.52,58.37 47.68,58.92 47.41,59.43 44.63,61.68 44.65,61.71 46.95,68.31 47.73,75.26 47.73,76.33 47.67,78.18 47.46,80.02 47.23,80.66 47.23,81.33 46.76,83.28 46.13,85.19 46.21,87.3 47.76,88.73 49.45,89.34
GND on IN3 (solid shape): outline of 94 points within 0.25,0.25 272.84,52.58
GND on IN3 (solid shape): outline of 83 points within 77.71,96.66 188.14,112.75
GND on IN4 (solid shape): 70.39,7.91 70.39,4.71 70.03,4.36 68.44,4.36 68.19,4.61 68.19,7.85 68.51,8.17 70.13,8.17
GND on IN4 (solid shape): 83.49,68.05 83.49,63.09 80.89,60.49 79.87,60.49 79.74,60.62 79.74,63.73 81.27,65.25 81.27,68.17 81.46,68.36 83.17,68.36
GND on IN4 (solid shape): 276.75,77.5 276.79,77.5 283.65,77.5 283.65,74.45 273.9,74.45 273.75,74.44 273.61,74.4 272.73,74.4 272.09,74.4 271.45,75.03 271.45,76.87 271.96,77.38 273.36,77.38 273.86,76.87 274.63,76.87 275.26,77.51 276.71,77.51
GND on IN4 (solid shape): 64.7,102.15 64.7,101.73 64.21,100.89 64.95,100.27 65.65,100.27 65.65,97.26 65.33,96.94 63.42,96.94 63.22,96.73 63.22,92.79 67.26,81.67 65.58,81.06 65.32,81.77 66.29,82.12 62.45,92.66 62.45,112.75 64.7,112.75
GND on IN4 (solid shape): 283.65,32.46 283.62,32.35 283.33,32 283.25,31.66 283.25,2.2 282.73,0.97 281.5,0.45 278.55,0.45 277.96,1.04 277.96,3.48 279.03,4.55 281.81,4.55 282.49,5.23 282.49,31.66 282.59,32.21 282.89,32.69 282.89,33.02 277.62,38.29 277.62,41.43 279.04,42.85 283.65,42.85
GND on IN4 (solid shape): 205.55,106.61 205.06,105.77 205.8,105.15 206.56,105.15 207.12,104.58 207.12,102.34 206.81,102.02 203.82,102.02 202.49,100.69 202.49,97.7 201.79,97 200.58,97 200.27,97.32 200.27,100.27 200.95,100.27 201.55,100.56 201.68,101.21 201.67,101.23 201.5,101.54 201.2,101.73 201.2,112.75 205.55,112.75
GND on IN4 (solid shape): 232.95,98.65 233.17,98.12 233.7,97.9 239.06,97.9 239.06,97.13 233.7,97.13 232.63,97.58 232.18,98.65 232.18,102.91 231.17,103.92 223.63,103.92 221.67,101.96 220.52,101.96 220.21,102.27 220.21,104.52 220.84,105.15 221.5,105.15 222.24,105.77 221.75,106.61 221.75,112.75 232.95,112.75
GND on IN4 (solid shape): 277.48,96.3 277.8,96.22 279.39,94.97 281.05,94.6 282.82,94.6 283.29,94.24 283.65,93.77 283.65,89.81 282.65,89.81 282.65,86.81 277.18,86.81 276.59,87.39 276.59,88.24 276.78,88.43 279.2,88.43 280.33,89.56 280.33,93.89 279.9,93.98 279.47,94.11 278.71,94.47 278.41,94.67 278.12,94.89 277.45,95.53 274.21,95.53 269.72,91.92 268.08,90.58 265.99,90.26 265.99,90.91 266.02,90.99 266.1,91.01 267.78,91.28 269.1,92.36 269.17,92.44 269.24,92.51 273.73,96.13 273.95,96.25 274.2,96.3
GND on IN4 (solid shape): 51.18,88.54 52.44,85.06 54.29,83.54 54.61,82.74 56.18,78.44 57.13,78.79 57.39,78.07 55.72,77.47 53.97,82.29 53.64,83.26 51.7,84.88 50.57,87.98 49.41,88.52 48.02,88.01 46.9,86.98 46.84,85.45 47.43,83.69 47.89,81.89 47.9,81.89 50.09,81.89 50.41,81.57 50.41,80.24 50.03,79.86 48.25,79.86 48.44,78.1 48.5,76.33 48.5,75.26 47.76,68.42 45.57,61.89 47.89,60.02 48.44,59.01 48.12,57.9 51.11,55.48 52.31,54.73 52.14,53.33 51.86,52.98 51.3,53.5 51.55,53.81 51.57,54.49 50.93,54.68 50.9,54.67 47.05,57.79 47.52,58.37 47.68,58.92 47.41,59.43 44.63,61.68 44.65,61.71 46.95,68.31 47.73,75.26 47.73,76.33 47.67,78.18 47.46,80.02 47.23,80.66 47.23,81.33 46.76,83.28 46.13,85.19 46.21,87.3 47.76,88.73 49.45,89.34
GND on IN4 (solid shape): outline of 492 points within 113.36,67.64 118.64,76.87
GND on IN4 (solid shape): outline of 94 points within 0.25,0.25 272.84,52.58
GND on IN4 (solid shape): outline of 83 points within 77.71,96.66 188.14,112.75
GND on TOP: 142.52,83.62 142.52,83.78 142.53,83.79 142.56,83.93 142.53,84.07 142.52,84.08 142.52,85.19 142.3,85.41 140.55,85.41 140.01,85.95 140.01,86.21 140.51,86.72 140.51,89.06 140.2,89.38 139.69,89.38 139.56,89.51 139.56,89.76 140.07,90.27 141.02,90.27 141.71,89.58 141.71,86.91 142.34,86.29 144.01,86.29 144.22,86.5 144.22,88.72 144.35,88.85 145.62,88.85 146.08,88.38 146.08,84.52 145.66,84.1 145.65,84.09 145.53,84.02 145.45,83.9 145.45,83.89 145.25,83.69 145.25,83.06 145.07,82.87 143.27,82.87 ; 1 cut-out
GND on TOP: 58.52,29.54 60.91,29.54 62.39,31.02 76.57,31.02 77.16,30.43 77.16,24.63 76.67,24.14 74.19,24.14 72.58,22.53 72.58,18.66 72.28,18.37 59.6,18.37 58.71,19.26 58.71,20.24 58.78,20.3 58.78,20.76 56.89,22.65 56.89,29.68 57.24,30.03 58.03,30.03
GND on BOTTOM: 178.01,15.95 177.57,16.39 177.57,24.43 177.32,24.69 177.32,26.99 198.1,26.99 198.1,19.95 198.52,19.53 198.52,18.99 198.38,18.85 198.38,16.51 197.93,16.06 188.17,16.06 187.54,16.68 181.35,16.68 180.62,15.95
GND on BOTTOM: 61.61,16.15 61.44,16.32 58.5,16.32 58.35,16.17 57.97,16.17 57.87,16.26 57.87,16.94 56.56,18.26 56.56,26.14 56.96,26.54 56.96,26.96 79.55,26.96 79.55,16.15
GND on BOTTOM: 109.86,15.79 109.86,16.65 109.77,16.74 109,16.74 108.73,16.47 108.73,16.19 108.43,15.89 98.96,15.89 98.07,16.77 98.07,23.82 97.73,24.16 97.73,26.97 118.69,26.97 118.64,26.91 118.64,20.73 118.89,20.48 118.89,16.76 119.4,16.24 119.4,15.89 119.3,15.79
GND on GND1: outline of 230 points within 0.26,0.26 283.65,112.75 ; 4 cut-outs
GND on IN1: 57.1,31.69 96.78,31.69 97.19,31.27 97.19,19.69 96.92,19.43 95.04,19.43 94.55,18.94 89.21,18.94 88.73,19.43 85.34,19.43 84.83,18.91 82.36,18.91 81.84,19.43 58.73,19.43 58.53,19.63 58.53,23.04 56.9,24.68 56.9,31.48
GND on GND2: outline of 229 points within 0.26,0.26 283.65,112.75
GND on IN3: 93.42,57.42 92.89,57.95 92.89,61.76 93.59,62.46 93.59,79.87 94.88,81.17 101.75,81.17 103.36,80.92 104.85,81.55 105.07,81.73 105.26,81.94 108.37,81.94 108.38,81.96 137.01,81.96 137.65,81.32 137.65,73.25 136.83,72.43 136.83,70.08 135.31,68.55 119.18,68.55 117.46,66.84 113.13,66.84 103.7,57.42
GND on IN3: 135.55,33.24 193.32,33.24 196.41,30.15 196.41,27.59 195.85,27.03 178.9,27.03 174.57,22.7 174.57,20.58 173.6,19.61 171.58,19.61 171.23,19.95 170.22,19.95 169.88,19.61 139.58,19.61 134.96,24.23 134.96,32.64
GND on VCC: 3.13,4.24 1.02,4.79 1.02,43.24 16.48,43.24 24.67,44.31 32.31,47.43 32.31,11.87 33.73,10.45 54.68,10.45 56.14,8.99 78.3,8.99 80.89,6.41 80.89,2.96 5.77,2.96 4.65,2.74 3.69,2.13
GND on VCC: 270.5,58.97 270.5,87.69 271.87,89.06 281.88,89.06 281.88,87.57 276.79,87.57 275.66,86.87 275.77,85.55 275.77,78.76 275.66,77.44 276.79,76.74 282.88,76.74 282.88,75.22 273.9,75.22 272.48,74.24 272.88,72.57 272.88,61.93 272.39,60.92 272.72,59.85 282.88,59.85 282.88,58.97
GND on VCC: 58.07,15.47 54.92,18.62 54.92,22.41 56.12,23.62 56.12,32.63 65.46,41.97 65.46,45.72 70.39,50.65 77.69,50.65 84.93,57.89 103.34,57.89 106.03,60.57 106.03,64.58 109.63,68.17 114.31,68.17 115.01,67.47 131.33,67.47 132.03,66.78 140.92,66.78 142.42,65.27 142.42,61.65 148.32,55.75 148.32,46.22 159.75,34.79 159.75,18.3 158.25,16.8 108.66,16.8 107.32,15.47
GND on VCC: 63.22,96.05 63.22,111.98 63.93,111.98 63.93,102.15 63.53,100.48 64.95,99.5 78.45,99.5 79.87,100.48 79.47,102.15 79.47,111.98 80.28,111.98 80.28,104.35 81,101.05 83.03,98.36 80.72,96.05
GND on VCC: 184.31,96.62 181.98,98.94 183.56,101.44 184.12,104.35 184.12,111.98 186.43,111.98 186.43,102.15 186.03,100.48 187.45,99.5 200.95,99.5 202.37,100.48 201.97,102.15 201.97,111.98 204.78,111.98 204.78,107.03 204.38,105.36 205.8,104.38 221.5,104.38 222.92,105.36 222.52,107.03 222.52,111.98 234.68,111.98 234.68,106.67 233.7,106.67 232.63,106.22 232.18,105.15 232.18,101.07 207.4,101.07 202.96,96.62
GND on GND3: outline of 227 points within 0.26,0.26 283.65,112.75
GNDA on TOP (solid shape): 253.54,37.76 253.54,36.8 253.16,36.42 253.16,35.98 253.1,35.92 252.53,35.92 252.21,36.23 252.21,37.63 252.46,37.88 253.42,37.88
GNDA on TOP (solid shape): 263.69,39.87 264.23,39.87 264.31,39.79 264.31,39.48 264.19,39.36 263.96,39.36 263.79,39.53 263.08,39.53 262.88,39.33 262.88,38.52 262.81,38.46 262.75,38.46 262.66,38.55 262.66,39.43 263.17,39.95 263.61,39.95
GNDA on TOP (solid shape): 255.24,45.84 255.24,43.89 255.13,43.77 254.15,43.77 254.08,43.85 254.08,44.32 254.05,44.36 253.55,44.36 253.54,44.37 253.54,44.57 253.56,44.59 254.07,44.59 254.1,44.62 254.1,45.1 254.04,45.15 253.59,45.15 253.55,45.19 253.55,45.35 253.6,45.39 254.08,45.39 254.1,45.41 254.1,45.94 254.16,45.99 255.09,45.99
GNDA on GND1: 266.34,34.26 265.74,34.87 265.74,35.5 265.33,35.92 263.55,35.92 263.51,35.96 263.51,37.99 263.11,38.39 258.77,38.39 258.43,38.05 258.43,36.78 258.39,36.74 252.7,36.74 252.34,37.1 252.34,42.86 252.82,43.34 253.58,43.34 254.31,44.06 254.31,45.84 255.93,47.47 262.73,47.47 264.21,48.95 264.21,52.19 270.48,58.46 283.65,58.46 283.65,57.44 283.65,55.65 271.68,55.65 271.14,55.23 271.43,54.61 271.43,48.82 271.14,48.2 271.68,47.78 283.65,47.78 283.65,46.28 283.65,45.46 282.4,45.46 281.38,44.96 281.13,43.85 278.58,43.85 276.85,42.12 276.85,36.46 276.17,35.79 268.35,35.79 267.83,35.27 267.83,34.29 267.81,34.26 ; 1 cut-out
GNDA on GND2: 266.34,34.26 265.73,34.88 265.73,35.51 265.33,35.92 263.55,35.92 263.51,35.96 263.51,37.99 263.11,38.39 258.77,38.39 258.43,38.05 258.43,36.78 258.39,36.74 252.7,36.74 252.34,37.1 252.34,42.86 252.82,43.34 253.58,43.34 254.31,44.06 254.31,45.84 255.93,47.47 262.73,47.47 264.21,48.95 264.21,52.19 270.48,58.46 283.65,58.46 283.65,56.55 283.65,55.65 271.68,55.65 271.14,55.23 271.43,54.61 271.43,48.82 271.14,48.2 271.68,47.78 283.65,47.78 283.65,46.51 283.65,45.46 282.4,45.46 281.38,44.96 281.13,43.85 278.58,43.85 276.85,42.12 276.85,36.46 276.17,35.79 268.36,35.79 267.83,35.25 267.83,34.29 267.81,34.26
GNDA on VCC: 263.55,35.92 263.51,35.96 263.51,37.99 263.11,38.39 258.77,38.39 258.43,38.05 258.43,37.59 258.43,36.78 258.39,36.74 252.7,36.74 252.34,37.1 252.34,42.86 252.82,43.34 253.58,43.34 254.31,44.06 254.31,45.84 255.93,47.47 262.73,47.47 264.21,48.95 264.21,52.19 270.48,58.46 282.88,58.46 282.88,56.48 271.68,56.48 270.49,55.72 270.66,54.32 270.66,49.07 270.49,47.67 271.68,46.91 282.88,46.91 282.88,46.22 282.4,46.22 280.84,45.5 280.35,43.85 278.58,43.85 276.85,42.12 276.85,36.46 276.17,35.79 268.36,35.79 267.83,35.26 267.83,34.31 267.79,34.27 266.35,34.27 265.74,34.89 265.74,35.51 265.33,35.92
GNDA on GND3: 266.35,34.27 265.74,34.88 265.74,35.51 265.33,35.92 263.55,35.92 263.51,35.96 263.51,37.99 263.11,38.39 258.77,38.39 258.43,38.05 258.43,36.82 258.36,36.74 252.7,36.74 252.34,37.1 252.34,42.86 252.82,43.34 253.58,43.34 254.31,44.06 254.31,45.84 255.93,47.47 262.73,47.47 264.21,48.95 264.21,52.19 270.48,58.46 283.65,58.46 283.65,56.55 283.65,55.65 271.68,55.65 271.14,55.23 271.43,54.61 271.43,48.82 271.14,48.2 271.68,47.78 283.65,47.78 283.65,46.62 283.65,45.46 282.4,45.46 281.38,44.96 281.13,43.85 278.58,43.85 276.85,42.12 276.85,36.46 276.17,35.79 269.01,35.79 269,35.79 268.36,35.79 267.83,35.26 267.83,34.27 267.82,34.27
GNDA_CHG on BOTTOM (solid shape): 52.72,9.87 54.47,9.87 54.56,9.78 54.56,8.93 55.04,8.45 55.04,7.59 54.98,7.53 54.78,7.53 54.72,7.59 54.72,8.1 54.22,8.1 54.2,8.09 54.2,7.53 53.93,7.53 53.83,7.43 53.83,6.67 54.08,6.41 54.08,6.41 54.15,6.34 54.15,5.52 54.1,5.48 53.51,5.48 53.4,5.59 53.4,6.19 53.2,6.38 51.75,6.38 49.59,6.38 49.55,6.42 49.55,6.97 49.62,7.03 50.64,7.03 50.82,7.22 50.82,9.08 50.82,9.08 50.82,9.24 50.66,9.4 50.13,9.4 50.05,9.48 50.05,9.95 50.15,10.05 52.54,10.05
+BL_PWR_SRC on BOTTOM (solid shape): 63.28,75.37 64.18,72.89 64.18,72.44 63.07,71.33 63.07,70.15 63.79,69.42 63.79,67.88 63.67,67.76 60.24,67.76 60.04,67.96 60.04,69.18 60.76,69.89 60.76,71.49 62.01,72.75 62.55,73.67 62.07,74.99 62.15,75.07 63.08,75.41
+DC_IN on TOP (solid shape): 85.01,86.03 85.01,83.72 85.31,83.42 85.31,82.05 84.9,81.64 80.57,81.64 80.38,81.83 80.38,82.33 80.44,82.4 81.01,82.4 81.2,82.59 81.2,83.29 81.46,83.54 82.28,83.54 82.41,83.67 82.41,85.64 82.22,85.83 82.22,86.21 82.41,86.4 84.65,86.4
+DC_IN on BOTTOM (solid shape): 83.36,83.1 83.36,80.56 83.62,80.3 83.62,79.73 83.55,79.66 83.5,79.63 83.47,79.6 83.31,79.6 83.07,79.7 82.83,79.6 81.9,79.6 81.27,80.24 81.27,83.22 81.65,83.6 82.86,83.6
+DC_IN_SS on TOP (solid shape): 83.11,74.33 83.11,73.57 82.66,73.13 80.51,73.13 80.19,73.44 80.19,74.4 80.38,74.59 82.86,74.59
+DC_IN_SS on BOTTOM (solid shape): 84.38,78.9 84.38,73.7 84.19,73.51 81.97,73.51 81.78,73.7 81.78,78.91 81.86,78.99 84.3,78.99
+DCIN on TOP (solid shape): 55.36,12.61 55.36,9.44 54.98,9.05 54.15,9.05 54.09,9.12 54.09,9.31 54.28,9.5 54.28,10.9 54.09,11.09 54.09,12.46 54.49,12.86 55.11,12.86
+DCIN on BOTTOM (solid shape): 58.21,11.12 58.21,9.95 58.13,9.88 54.92,9.88 54.79,10.01 54.79,10.83 55.1,11.14 58.18,11.14
+DCIN_JACK on TOP (solid shape): 93.65,91.11 93.65,90.32 93.6,90.27 92.86,90.27 91.53,88.93 90.02,88.93 89.76,89.19 89.76,91.01 89.91,91.16 93.6,91.16
+DCIN_JACK on BOTTOM (solid shape): outline of 95 points within 83.43,80.37 92.55,91.35
+DCPRRTC on TOP (solid shape): 146.5,70.09 146.54,70.05 146.57,70.02 146.61,69.99 146.66,69.97 146.71,69.96 146.76,69.95 146.81,69.95 146.86,69.96 146.88,69.97 147.39,69.97 147.6,69.76 147.6,69.37 147.6,69.34 147.59,69.29 147.6,69.23 147.61,69.18 147.63,69.12 147.64,69.1 147.64,68.83 147.48,68.66 146.93,68.66 146.87,68.66 146.64,68.66 146.04,69.27 145.6,69.27 145.55,69.32 146.52,69.32 146.52,69.27 146.53,69.22 146.54,69.17 146.56,69.13 146.59,69.09 146.63,69.05 146.67,69.03 146.71,69 146.76,68.99 146.81,68.98 146.86,68.98 146.91,68.99 146.96,69 147,69.03 147.04,69.05 147.08,69.09 147.11,69.13 147.13,69.17 147.14,69.22 147.15,69.27 147.15,69.32 147.14,69.37 147.13,69.42 147.11,69.46 147.08,69.5 147.04,69.54 147,69.57 146.96,69.59 146.91,69.61 146.86,69.61 146.81,69.61 146.76,69.61 146.71,69.59 146.67,69.57 146.63,69.54 146.59,69.5 146.56,69.46 146.54,69.42 146.53,69.37 146.52,69.32 145.55,69.32 145.46,69.41 145.46,70.07 145.53,70.14 146.48,70.14
+DOCK_PWR_BAR on TOP (solid shape): 103.43,13.63 103.43,12.1 102.48,11.15 102.48,7.98 102.03,7.53 100.25,7.53 99.81,7.98 99.81,13.18 100.38,13.75 103.3,13.75
+DOCK_PWR_BAR on TOP (solid shape): outline of 189 points within 99.52,96.38 113.01,107.18
+DOCK_PWR_BAR on BOTTOM (solid shape): 103.43,14.07 103.43,11.4 101.46,9.43 101.46,8.96 101.26,8.76 98.93,8.76 98.41,9.27 98.41,12.15 98.01,12.56 95.82,12.56 95.68,12.7 95.68,15.02 96,15.34 102.16,15.34
+DOCK_PWR_BAR on VCC: outline of 91 points within 32.82,2.96 153.98,106.59
+LCDVDD on BOTTOM (solid shape): 55.61,61.76 57.07,61.76 57.14,61.7 57.14,59.73 56.88,59.47 54.47,59.47 54.15,59.79 54.15,61.76 54.6,62.2 55.17,62.2
+LCDVDD on BOTTOM (solid shape): 57.19,73.12 57.61,71.98 57.63,71.82 57.86,71.44 57.86,71.43 57.88,71.35 57.92,71.28 57.93,71.27 57.93,71.12 57.86,71.06 56.84,71.06 56.7,71.31 56.72,71.4 56.88,71.51 56.89,71.65 56.46,72.87 56.51,73.04 57.05,73.21
+LCDVDD on IN4 (solid shape): 55.16,63.13 55.16,60.68 54.85,60.37 54.16,60.37 53.75,60.77 53.75,63.1 53.89,63.24 55.06,63.24
+LCDVDD on IN4 (solid shape): 57.88,71.37 57.9,71.31 57.9,70.78 57.52,70.4 55.74,70.4 55.44,70.7 55.44,71.86 54.86,72.43 51.75,72.43 51.33,72.85 51.33,73.43 51.63,73.72 55.52,73.72
+LCDVDD on TOP: 50.38,74.7 52.24,74.7 52.44,74.5 52.44,72.81 52.24,72.61 50.9,72.61 50.76,72.75 50.76,73.46 50.25,73.96 50.25,74.57
+LOM_VCT on BOTTOM (solid shape): 144.58,109.7 144.58,107.72 144.51,107.65 143.85,107.65 143.82,107.69 143.82,109.92 143.92,110.02 144.26,110.02
+PBATT on TOP (solid shape): 172.33,15.4 172.33,10.26 172.2,10.13 168.14,10.13 168.01,10.26 168.01,11.54 167.41,12.14 156.06,12.14 155.67,12.53 155.67,15.18 155.94,15.45 168.69,15.45 168.96,15.72 172.01,15.72
+PBATT on TOP (solid shape): outline of 101 points within 93.49,3.22 118.24,7.35
+PBATT on BOTTOM (solid shape): 172.26,15.47 172.26,13.44 170.9,12.07 161.61,12.07 158.6,9.05 140.89,9.05 136.32,4.48 114.41,4.48 113.15,3.21 90.67,3.21 90.28,3.59 90.28,14.07 90.66,14.45 92.63,14.45 92.82,14.25 92.82,9.82 93.52,9.12 97.94,9.12 99.31,7.75 99.31,6.96 99.5,6.78 100.02,6.78 100.11,6.69 100.11,6.31 100.33,6.09 100.65,6.09 100.87,6.31 100.87,6.58 101.07,6.78 102.35,6.78 102.51,6.62 102.51,6.36 102.73,6.13 103.27,6.13 103.89,6.75 103.89,8.99 104.01,9.12 106.29,9.12 106.54,8.86 108.13,8.86 110.38,11.12 130.83,11.12 135.05,15.34 155.97,15.34 156.41,15.79 171.95,15.79
+PCH_ASATA3PLL on TOP (solid shape): 143.72,90.57 143.72,89.73 143.69,89.72 143.46,89.38 143.69,89.05 143.72,89.04 143.72,86.47 143.68,86.43 142.47,86.43 141.84,87.06 141.84,89.72 141.6,89.96 141.6,90.58 141.8,90.78 143.51,90.78
+PCH_AUSB3PLL on TOP: 138.77,84.87 138.73,84.83 138.71,84.83 138.48,84.74 138.39,84.51 138.39,84.49 138.04,84.14 135.8,84.14 135.47,84.46 135.47,85.36 135.88,85.76 137.09,85.76 138.16,86.84 138.16,90.32 138.2,90.4 138.27,90.42 138.62,90.65 138.51,91.06 138.47,91.12 138.48,91.19 138.48,91.52 138.21,91.7 138.16,91.71 138.16,92.25 139.17,93.26 139.17,94.51 139.35,94.68 140.15,94.68 140.23,94.6 140.23,90.65 139.43,89.85 139.43,89.82 139.43,89.46 139.43,89.45 139.63,89.25 140,89.25 140.23,89.01 140.23,86.78 140.23,86.78 140.23,86.61 140,86.38 139.96,86.35 139.88,86.26 139.88,86.23 139.87,86.22 139.85,86.09 139.87,85.97 139.88,85.96 139.88,85.9 140.23,85.55 140.23,83.91 140.02,83.7 139.5,83.7 139.33,83.87 139.33,84.62 139.08,84.87
+PCH_RTC_VCCSUS3_3 on IN3 (solid shape): outline of 132 points within 143.89,65.19 145.61,67.27
+PCH_VCCDSW3_3 on TOP (solid shape): 156.32,54.5 158.2,54.5 158.5,54.2 158.5,52.89 158.5,52.89 158.5,49.89 157.87,49.26 154.92,49.26 154.71,49.47 154.71,51.66 155.15,52.1 155.15,54.04 155.06,54.12 154.42,54.12 154.37,54.17 154.37,54.82 154.4,54.85 155.97,54.85
+PCH_VCCDSW3_3 on IN3 (solid shape): outline of 235 points within 145.88,65 151.27,67.09
+PWR_SRC on TOP (solid shape): 81.84,13.75 81.84,12.55 81.71,12.42 76.89,12.42 76.63,12.67 76.63,13.88 76.76,14.01 81.59,14.01
+PWR_SRC on TOP (solid shape): 195.09,5.15 195.09,1.85 195,1.75 193.92,1.75 193.6,2.07 193.6,5.12 193.79,5.31 194.93,5.31
+PWR_SRC on BOTTOM (solid shape): 193.79,56.24 193.79,55.25 193.67,55.13 191.04,55.13 190.86,55.31 190.86,56.23 191,56.36 193.66,56.36
+PWR_SRC on BOTTOM (solid shape): 61.77,67.22 61.77,64.81 61.65,64.68 60.25,64.68 59.8,65.13 59.8,67.22 60.19,67.6 61.39,67.6
+PWR_SRC on BOTTOM (solid shape): 74.98,59.6 74.98,55.6 74.66,55.28 72.23,55.28 71.94,55.57 71.94,56.9 71.37,57.47 71.37,59.3 71.87,59.79 74.79,59.79
+PWR_SRC on BOTTOM (solid shape): 212.37,53.73 212.64,53.73 212.69,53.68 212.69,51.07 211.95,50.33 207.82,50.33 207.44,50.71 207.44,53.25 207.93,53.74 212.36,53.74
+PWR_SRC on BOTTOM (solid shape): 81.9,13.82 81.9,12.48 81.78,12.36 81.01,12.36 80.32,11.66 78.54,11.66 78.47,11.59 78.47,10.9 78.54,10.83 80.19,10.83 80.25,10.77 80.25,10.26 80.12,10.13 77.97,10.13 74.47,6.64 74.47,5.94 74.16,5.63 71.95,5.63 71.63,5.94 71.63,8.07 71.23,8.47 70.89,8.47 70.57,8.79 70.57,12.58 72,14.01 81.71,14.01
+PWR_SRC on IN2 (solid shape): outline of 219 points within 65.08,51.6 73.01,59.85
+PWR_SRC on IN2 (solid shape): outline of 1556 points within 49.58,4.1 154.04,29.22
+PWR_SRC on IN3 (solid shape): outline of 1045 points within 60.1,55.22 72.5,67.77
+PWR_SRC on IN4 (solid shape): 194.87,56.04 194.87,55.35 194.62,55.09 191.06,55.09 190.87,55.28 190.87,56.17 191.12,56.43 194.49,56.43
+PWR_SRC on IN4 (solid shape): 209.09,53.44 209.09,52.55 208.71,52.17 206.74,52.17 206.3,52.62 206.3,53.31 206.62,53.63 208.9,53.63
+PWR_SRC on IN4 (solid shape): outline of 239 points within 177.09,1.5 195.12,4.17
+PWR_SRC on VCC: 150.16,1.02 150.16,1.44 149.72,2.51 148.65,2.96 144.03,2.96 143.47,3.68 142.6,3.96 138.23,3.96 138.23,9.2 139.98,10.96 150.82,10.96 153.43,8.36 179.59,8.36 183.33,4.61 187.29,4.61 190.34,7.66 205.05,7.66 205.22,7.49 206.55,8.82 206.55,52.57 207.48,53.5 212.48,53.5 215.06,50.92 215.06,41.14 218.75,37.46 218.75,1.22 175.76,1.22 175.37,1.17 175,1.02
+PWR_SRC_AC on TOP (solid shape): 108.13,13.56 108.13,7.85 107.81,7.53 102.92,7.53 102.79,7.66 102.79,11.09 105.46,13.75 107.94,13.75
+PWR_SRC_AC on BOTTOM (solid shape): 108.57,14.45 108.57,12.1 108.06,11.59 103.94,11.59 103.68,11.85 103.68,14.52 104.06,14.9 108.13,14.9
+PWR_SRC_AC on BOTTOM (solid shape): 57.32,16.72 57.32,16.06 57.65,15.72 57.65,15.04 57.88,14.82 57.88,12.88 57.73,12.73 57.17,12.73 57.04,12.6 57.04,12.19 56.94,12.1 52.98,12.1 52.83,12.25 52.83,13.93 52.91,14.01 54.39,14.01 54.59,14.21 54.59,14.64 54.42,14.8 52.86,14.8 52.79,14.87 52.79,15.28 52.81,15.31 52.84,15.33 52.89,15.34 53,15.39 53.1,15.47 53.17,15.52 53.25,15.49 53.64,15.42 53.85,15.77 53.59,16.09 53.2,15.96 53.13,15.92 53.05,15.94 52.95,16.01 52.84,16.04 52.81,16.06 52.79,16.09 52.79,16.62 53.13,16.96 57.08,16.96
+PWR_SRC_AC on IN1 (solid shape): 58.15,15.09 63.14,15.09 63.15,15.08 63.3,15.05 63.45,15.08 63.46,15.09 63.77,15.09 63.78,15.08 63.93,15.05 64.08,15.08 64.09,15.09 64.41,15.09 64.42,15.08 64.57,15.05 64.72,15.08 64.73,15.09 73.71,15.09 75.55,13.25 84.42,13.25 86,11.66 103.24,11.66 105.59,14.01 108.13,14.01 108.57,13.56 108.57,11.47 104.95,7.85 83.63,7.85 82.36,9.12 74.35,9.12 71.55,11.91 62.04,11.91 62.03,11.94 61.77,12.14 61.46,12.04 61.39,12.01 61.32,12.04 61.01,12.14 60.75,11.94 60.74,11.91 60.58,11.91 60.57,11.94 60.31,12.14 60,12.04 59.93,12.01 59.61,12.14 59.3,12.01 59.23,12.04 58.92,12.14 58.66,11.94 58.64,11.91 57.71,11.91 57.64,11.98 57.56,12.03 57.43,12.71 57.3,12.03 57.22,11.98 57.15,11.91 55.36,11.91 53.45,13.82 53.45,15.39 53.85,15.75 53.45,16.1 54.28,16.93 56.31,16.93
+RSVD_VCC3P3_1 on TOP (solid shape): 234.18,93.13 234.18,92.18 234.94,91.41 234.94,90.33 235.26,90.02 235.26,89.89 235.19,89.83 234.24,89.83 234.11,89.95 234.11,90.27 234.24,90.4 234.24,91.35 233.48,92.11 233.48,93.19 234.11,93.19
+RTC_CELL on TOP (solid shape): 143.15,68.65 143.15,68.2 143.22,68.14 143.76,68.14 143.98,67.92 143.98,66.17 143.77,65.96 143.18,65.96 143.09,66.04 143.09,67.48 143.1,67.49 143.07,67.79 142.8,67.94 142.59,67.94 142.42,68.11 142.42,68.61 142.52,68.71 143.09,68.71
+SD_IO_LDO on TOP (solid shape): 264.07,14.97 264.07,14.75 264.39,14.43 264.39,14.14 264.31,14.07 263.88,14.07 263.18,14.77 263.18,14.97 263.24,15.03 264.01,15.03
+SDC_IN on BOTTOM (solid shape): 81.33,75.09 81.33,70.52 81.01,70.21 79.2,70.21 78.72,70.68 78.72,74.21 79.8,75.29 81.14,75.29
+SDC_IN on BOTTOM (solid shape): outline of 105 points within 49.45,13.42 54.28,26.2
+SDC_IN on VCC: 50.58,22.77 49.64,23.7 49.64,33.33 60.69,44.32 60.69,47.62 66.03,52.95 66.03,65.02 71.78,70.78 76.48,70.78 77.63,71.92 81.61,71.92 81.9,71.62 81.9,70.56 77.67,66.33 72.65,66.33 70.03,63.71 70.03,51.01 64.95,45.93 64.95,42.18 55.61,32.85 55.61,23.83 54.56,22.77
+SM_VREF_CA on IN2 (solid shape): outline of 135 points within 120.79,61.94 122.84,64.19
+USB_RIGHT_PWR on BOTTOM (solid shape): 200.6,96.31 205.18,96.31 205.34,96.16 205.34,94.2 205.24,93.95 205.34,93.71 205.34,93.11 205.15,92.92 203.67,92.92 202.61,91.85 200.7,91.85 200.3,92.25 200.3,94.48 200.02,94.75 199.31,94.75 199.19,94.87 199.19,95.7 197.21,97.69 197.21,98.05 197.88,98.73 198.19,98.73
+USB_SIDE_PWR on TOP (solid shape): 270.5,64.49 270.53,64.49 270.81,64.22 271.57,64.22 272.15,63.64 272.15,63.28 271.83,62.97 268.91,62.97 268.72,63.16 268.72,63.73 268.53,63.92 267.89,63.92 267.51,64.3 267.51,66.08 267.64,66.2 268.78,66.2
+USB_SIDE_PWR on BOTTOM (solid shape): 272.2,64.24 272.2,63.39 271.74,62.93 268.33,62.93 268.32,62.93 268.2,62.95 268.07,62.93 268.07,62.93 267.17,62.93 265.16,64.93 265.16,65.76 265.61,66.2 270.24,66.2
+USB_SIDE_PWR on BOTTOM (solid shape): outline of 153 points within 253.92,70.98 263.47,79.48
+VCHGR on TOP (solid shape): 85.4,13.88 85.4,12.55 85.27,12.42 82.6,12.42 82.28,12.74 82.28,13.75 82.54,14.01 85.27,14.01
+VCHGR on BOTTOM (solid shape): 86.02,13.19 87.68,13.19 87.9,12.98 87.9,12.27 89.84,10.32 89.84,4.04 89.71,3.91 85.01,3.91 84.76,4.17 84.76,6.32 81.27,9.82 81.27,10.83 82.92,10.83 83.05,10.96 83.05,11.4 82.86,11.59 81.27,11.59 81.27,12.1 81.33,12.17 81.84,12.17 82.16,12.48 82.16,13.82 82.35,14.01 85.2,14.01
+VDISPLAY_VCC on BOTTOM (solid shape): 266.37,78.21 267.58,78.21 267.64,78.14 267.64,77.57 267.45,77.38 264.86,77.38 264.4,77.84 264.4,78.4 264.72,78.71 265.86,78.71
+VHDMI_VCC on BOTTOM (solid shape): 218.24,103.16 218.24,101.71 217.94,101.42 217.94,96.88 217.55,96.49 216.78,96.49 216.51,96.76 216.51,96.99 216.74,97.22 216.74,97.23 216.83,97.32 216.83,101.89 217.24,102.31 217.24,103.21 217.4,103.36 218.04,103.36
+VLDOIN_1.35V on TOP (solid shape): 190.49,13.44 190.49,13.18 189.92,13.18 189.92,12.67 190.49,12.67 190.49,12.36 190.36,12.23 189.22,12.23 189.09,12.36 189.09,13.12 189.47,13.5 190.42,13.5
-DCIN_JACK on BOTTOM (solid shape): 92.57,86.97 92.57,83.92 91.75,83.1 91.75,80.03 91.67,79.95 90.59,79.95 88.98,81.56 88.98,84.74 89.22,84.98 89.22,87.05 89.4,87.22 92.32,87.22
BOOT_1.35V on TOP (solid shape): 188.84,10.83 188.84,9.94 188.65,9.75 187.38,9.75 186.61,8.99 186.61,7.85 186.55,7.78 186.42,7.78 186.36,7.85 186.36,9.25 188.01,10.9 188.77,10.9
BOOT_1.35V_C on TOP (solid shape): 191.19,10.53 191.19,8.61 191.12,8.55 190.61,8.55 190.55,8.61 190.55,9.56 190.17,9.94 189.54,9.94 189.47,10.01 189.47,10.77 189.54,10.83 190.88,10.83
BQ24770_REGN on TOP (solid shape): 56.62,7.65 57.21,7.65 57.33,7.53 57.33,6.64 56.57,5.87 56.57,5.12 56.44,4.99 55.85,4.99 55.7,5.14 55.7,5.79 56.3,6.39 56.3,6.91 55.8,7.4 54.15,7.4 54.09,7.47 54.09,7.59 54.15,7.66 56.62,7.66
BST_3V on TOP (solid shape): 204.65,53 204.65,51.6 203.25,50.2 201.66,50.2 201.6,50.27 201.6,50.33 201.66,50.39 202.68,50.39 203.82,51.54 203.82,53.06 203.89,53.12 204.52,53.12
BST_3V_C on TOP (solid shape): 206.1,53.06 206.1,51.34 205.92,51.16 205.03,51.16 204.97,51.22 204.97,53.06 205.03,53.12 206.04,53.12
BST_5V on TOP (solid shape): 198.55,50.46 199.57,50.46 199.63,50.39 199.63,50.27 199.57,50.2 198.43,50.2 198.3,50.33 197.54,50.33 197.28,50.58 196.58,50.58 196.52,50.65 196.52,51.54 196.58,51.6 197.41,51.6
BST_5V_C on TOP (solid shape): 195.89,51.54 195.89,49.38 195.82,49.31 195.19,49.31 195.12,49.38 195.12,51.54 195.19,51.6 195.82,51.6
BST_+V1.05SP on TOP (solid shape): 189.92,58.58 189.92,57.7 189.85,57.63 189.34,57.63 189.28,57.7 189.28,58.14 188.58,58.84 188.58,59.09 188.71,59.22 189.28,59.22
BST_+V1.05SP_C on TOP (solid shape): 191.31,58.97 191.31,57.7 190.68,57.7 190.61,57.76 190.61,58.08 189.79,58.9 189.79,59.54 189.85,59.6 190.68,59.6
CHAGER_SRC on TOP (solid shape): 61.2,15.75 61.2,12.48 60.44,11.72 60.44,11.65 60.19,11.39 60.19,9.56 60.25,9.5 60.25,8.1 60.5,7.85 61.52,7.85 61.84,8.17 61.84,8.67 62.34,9.18 62.98,9.18 63.04,9.12 63.04,4.29 62.98,4.23 60.52,4.23 59.13,4.23 58.92,4.44 58.92,7.53 58.09,8.36 58.09,15.47 58.73,16.1 60.85,16.1
CHAGER_SRC on BOTTOM (solid shape): 61.68,15.38 61.68,13.52 60.76,12.6 60.76,12.3 60.5,12.04 60.5,11.4 60.19,11.09 60.19,9.56 60.31,9.44 60.31,8.8 60.31,8.1 60.71,7.7 62.52,7.7 62.76,7.46 62.76,5.19 62.65,5.08 60.89,5.08 59.56,6.42 58.72,6.42 58.47,6.66 58.47,6.67 58.34,6.8 58.34,11.52 58.03,11.83 58.03,13.06 58.05,13.08 58.58,13.08 58.58,13.08 58.58,13.6 58.57,13.61 58.05,13.61 58.05,13.88 58.57,13.88 58.6,13.91 58.6,14.42 58.59,14.43 58.06,14.43 58.02,14.47 58.02,15.18 58.52,15.68 61.38,15.68
CHG_BTS on TOP (solid shape): 57.65,8.42 57.65,7.9 57.58,7.84 54.16,7.84 54.09,7.91 54.09,8.04 54.15,8.1 56.19,8.1 56.57,8.48 57.58,8.48
CHG_BTS_C on TOP (solid shape): 57.65,11.09 57.65,9.18 57.58,9.12 56.69,9.12 56.63,9.18 56.63,10.96 56.82,11.15 57.58,11.15
CHG_LGATE on TOP (solid shape): 68.06,9.25 68.06,8.42 67.93,8.29 66.85,8.29 66.66,8.48 66.66,8.74 67.36,9.44 67.87,9.44
CHG_LGATE on TOP (solid shape): 56.12,6.9 56.12,6.64 56.02,6.54 55.84,6.54 55.78,6.6 55.47,6.6 55.04,7.02 54.15,7.02 54.09,7.09 54.09,7.21 54.15,7.28 55.74,7.28
CHG_LGATE on IN4 (solid shape): 68,9.31 68,8.42 67.74,8.17 67.74,7.21 67.49,7.21 67.42,7.15 66.73,7.15 66.73,8.67 67.49,9.44 67.87,9.44
CHG_LGATE on IN4 (solid shape): 56.19,6.77 56.19,5.05 56.25,4.99 56.25,4.67 55.93,4.36 55.49,4.36 55.29,4.55 55.29,6.52 55.11,6.71 55.11,7.09 55.3,7.28 55.68,7.28
CHG_SNUB on TOP (solid shape): 69.71,11.56 69.71,10.78 69.64,10.7 68.52,10.7 68.4,10.58 68.4,9.8 68.34,9.74 67.34,9.74 67.25,9.83 67.25,11.56 67.34,11.65 69.62,11.65
CHG_SW on TOP (solid shape): 66.31,11.08 66.31,4.39 66.15,4.23 63.49,4.23 63.42,4.29 63.42,9.12 63.26,9.29 63.26,11.44 63.41,11.59 65.8,11.59
CHG_SW on TOP (solid shape): 56.38,11.02 56.38,9.25 56.25,9.12 55.99,9.12 55.74,8.86 55.42,8.86 55.17,8.61 54.15,8.61 54.09,8.67 54.09,8.8 54.15,8.86 54.98,8.86 55.55,9.44 55.55,11.02 55.61,11.09 56.31,11.09
CHG_SW on BOTTOM (solid shape): 66.47,12.67 66.47,5.69 66.15,5.37 63.3,5.37 63.23,5.44 63.23,7.52 62.78,7.98 62.26,7.98 62.09,8.15 62.09,12.38 62.64,12.93 66.22,12.93
CHG_SW on IN1 (solid shape): 64.1,8.69 64.1,6.89 63.99,6.77 63.54,6.77 63.37,6.94 63.37,7.94 63,8.3 63,8.66 63.4,9.06 63.73,9.06
CHG_SW on IN1 (solid shape): 57.07,10.32 57.07,9.82 56.38,9.12 55.99,9.12 55.74,8.86 55.36,8.86 55.23,8.99 55.23,9.25 56.57,10.58 56.82,10.58
CHG_UGATE on TOP (solid shape): 61.65,8.86 61.65,8.29 61.39,8.04 60.63,8.04 60.44,8.23 60.44,8.99 60.63,9.18 61.33,9.18
CHG_UGATE on TOP (solid shape): 56.38,8.86 56.38,8.67 55.93,8.23 54.15,8.23 54.09,8.29 54.09,8.42 54.15,8.48 55.23,8.48 55.42,8.67 55.74,8.67 56.06,8.99 56.25,8.99
CHG_UGATE on IN4 (solid shape): 57.14,8.93 57.33,8.93 57.39,8.86 57.39,8.04 57.33,7.98 56.88,7.98 56.76,8.1 55.49,8.1 55.3,8.29 55.3,8.55 55.42,8.67 55.74,8.67 56.06,8.99 57.07,8.99
CHG_UGATE on IN4 (solid shape): 61.01,9.02 61.01,7.81 60.69,7.49 59.94,7.49 59.85,7.58 59.85,8.39 59.94,8.48 60.12,8.48 60.44,8.8 60.44,8.98 60.63,9.18 60.86,9.18
CORE_BOOT on BOTTOM (solid shape): 79.74,68.68 79.74,68.43 80.19,67.98 81.01,67.98 81.08,67.92 81.08,67.79 81.01,67.73 80.06,67.73 79.17,68.62 78.54,68.62 78.47,68.68 78.47,69.19 78.54,69.25 79.17,69.25
CORE_BOOT_C on BOTTOM (solid shape): 78.22,69.19 78.22,67.47 78.09,67.35 77.27,67.35 77.2,67.41 77.2,69.13 77.33,69.25 78.16,69.25
CORE_BOOT_R on BOTTOM (solid shape): 80,67.6 81.01,67.6 81.08,67.54 81.08,67.41 81.01,67.35 80.1,67.35 80.08,67.37 79.02,67.37 79.02,67.37 78.71,67.37 78.66,67.41 78.66,68.24 78.73,68.3 79.3,68.3
CORE_SNUB on BOTTOM (solid shape): 85.08,61.19 85.08,60.17 85.01,60.11 82.16,60.11 82.09,60.17 82.09,61 82.35,61.25 85.01,61.25
CORE_SW on BOTTOM (solid shape): 85.9,66.08 89.59,66.08 90.6,65.06 90.6,63.09 88.25,63.09 88.25,62.2 90.6,62.2 90.6,60.87 90.28,60.55 86.73,60.55 85.08,62.2 83.55,62.2 83.36,62.39 83.36,64.17 83.68,64.49 83.68,67.16 83.74,67.22 84.76,67.22
DH_1.35V on TOP (solid shape): 195.57,14.01 195.57,13.18 195.44,13.06 194.62,13.06 194.49,13.18 194.49,14.01 194.62,14.13 195.44,14.13
DH_1.35V on TOP (solid shape): 188.2,9.44 188.2,9.25 188.07,9.12 187.63,9.12 187.38,8.86 187.19,8.86 187,8.67 187,7.85 186.93,7.78 186.8,7.78 186.74,7.85 186.74,8.93 187.44,9.63 188.01,9.63
DH_1.35V on IN4 (solid shape): 188.77,9.94 187.95,9.12 187.63,9.12 187.38,8.86 187.19,8.86 187.06,8.99 187.06,9.63 188.07,10.64
DH_1.35V on IN4 (solid shape): 195.63,14.01 195.63,13.82 194.55,12.74 193.73,12.74 193.54,12.93 193.54,13.18 194.49,14.13 195.5,14.13
DL_1.35V on TOP (solid shape): 189.41,8.04 189.41,7.72 189.28,7.59 188.77,7.59 188.52,7.34 187.63,7.34 187.57,7.4 187.57,7.53 188.2,8.17 189.28,8.17
DL_1.35V on TOP (solid shape): 199.19,9.25 199.19,7.98 199.06,7.85 198.11,7.85 198.04,7.91 198.04,8.23 198.36,8.55 198.36,9.37 198.43,9.44 199,9.44
DL_1.35V on IN4 (solid shape): 190.61,7.4 190.04,7.4 189.85,7.59 188.46,7.59 188.27,7.78 188.27,7.98 188.46,8.17 189.79,8.17 190.04,8.42 190.61,8.42
DL_1.35V on IN4 (solid shape): 199.19,8.86 199.19,7.98 199.06,7.85 198.17,7.85 198.04,7.98 198.04,8.17 197.54,8.67 197.54,9.18 197.79,9.44 198.62,9.44
INT_SPK_L+ on TOP (solid shape): 274.96,30.06 274.96,27.39 274.76,27.2 273.69,27.2 273.69,27.9 274.13,28.35 274.13,30 274.32,30.19 274.83,30.19
INT_SPK_L+ on IN4 (solid shape): 274.94,30.07 274.94,28.23 274.5,27.79 273.99,28.3 274.18,28.49 274.18,30.07 274.31,30.2 274.82,30.2
INT_SPK_L+ on IN4 (solid shape): 258.95,36 258.95,35.8 258.73,35.57 258.16,35.57 257.6,36.13 256.39,36.13 256.16,35.9 255.88,35.9 255.78,36 255.78,36.37 256.12,36.71 258.25,36.71
INT_SPK_L- on TOP (solid shape): 276.73,30.06 276.73,27.39 276.54,27.2 275.34,27.2 275.27,27.27 275.27,27.9 275.34,27.96 275.72,27.96 275.91,28.16 275.91,30.06 276.03,30.19 276.61,30.19
INT_SPK_L- on IN4 (solid shape): 257.69,35.63 257.69,35.19 257.63,35.14 256.76,35.14 256.29,35.61 256.29,35.82 256.43,35.97 257.35,35.97
INT_SPK_L- on IN4 (solid shape): 276.7,30.1 276.7,27.62 276.25,27.18 275.74,27.69 275.74,27.75 275.93,27.94 275.93,30.1 276.06,30.23 276.57,30.23
INT_SPK_R+ on TOP (solid shape): 278.23,30.03 278.23,28.31 278.61,27.93 278.8,27.93 278.86,27.87 278.86,27.34 278.78,27.26 277.5,27.26 277.4,27.36 277.4,30.03 277.53,30.16 278.1,30.16
INT_SPK_R+ on IN4 (solid shape): 278.19,30.06 278.19,28.03 277.88,27.71 277.62,27.71 277.43,27.9 277.43,30.06 277.56,30.19 278.07,30.19
INT_SPK_R- on TOP (solid shape): 281.08,30.03 281.08,27.36 280.97,27.25 279.7,27.25 279.62,27.33 279.62,27.87 279.69,27.93 279.88,27.93 280.26,28.31 280.26,30.03 280.38,30.16 280.96,30.16
INT_SPK_R- on IN4 (solid shape): 281.06,30 281.06,28.28 280.94,28.16 280.37,28.16 280.3,28.22 280.3,30 280.43,30.12 280.94,30.12
INT_SPKR_L+ on TOP (solid shape): 274.66,26.96 274.66,26.66 273.72,25.72 273.37,25.72 273.01,26.09 273.01,26.22 273.84,27.06 274.57,27.06
INT_SPKR_L- on TOP (solid shape): 275.36,27.06 276.93,27.06 277.01,26.97 277.01,25.96 276.67,25.62 276.34,25.62 275.68,26.28 275.46,26.28 275.32,26.42 275.32,26.99 275.32,27.05 275.33,27.06
INT_SPKR_R+ on TOP (solid shape): 278.81,27 278.81,26.52 278.22,25.94 277.43,25.94 277.35,26.01 277.35,26.65 277.77,27.07 278.75,27.07
INT_SPKR_R- on TOP (solid shape): 280.99,26.69 280.99,26.04 280.85,25.9 280.09,25.9 279.77,26.21 279.77,26.93 279.94,27.1 280.57,27.1
LG_3V on TOP (solid shape): 204.55,60.08 204.55,59.35 204.36,59.16 203.6,59.16 203.47,59.28 203.47,60.08 203.6,60.2 204.43,60.2
LG_3V on TOP (solid shape): 202.43,52.3 202.43,52.11 201.92,51.6 201.92,51.35 201.47,50.9 201.35,50.9 201.28,50.96 201.28,52.3 201.47,52.49 202.24,52.49
LG_3V on IN1 (solid shape): 204.58,59.47 204.58,57.44 203.89,56.74 203.25,56.74 203.12,56.87 203.12,57.44 203.44,57.76 203.44,59.47 203.63,59.66 204.39,59.66
LG_3V on IN1 (solid shape): 202.36,54.36 202.36,52.14 202.24,52.01 201.44,52.01 201.28,52.17 201.28,52.62 201.35,52.68 201.35,54.49 201.6,54.74 201.98,54.74
LG_5V on TOP (solid shape): 201.47,62.52 201.47,61.63 201.35,61.51 200.58,61.51 200.39,61.7 200.39,62.46 200.58,62.65 201.35,62.65
LG_5V on TOP (solid shape): 199.95,51.85 199.95,50.96 199.89,50.9 199.76,50.9 199.57,51.09 199.31,51.09 199.06,51.35 199.06,52.23 199.19,52.36 199.44,52.36
LG_5V on IN1 (solid shape): 201.47,62.52 201.47,61.51 201.16,61.19 200.71,61.19 200.39,61.51 200.39,62.46 200.58,62.65 201.35,62.65
LG_5V on IN1 (solid shape): 199.44,53 199.44,52.43 199.57,52.3 199.57,51.41 199.38,51.22 199.25,51.22 198.43,52.04 198.43,53 198.68,53.25 199.19,53.25
NB_PSID on BOTTOM (solid shape): 92.47,93.05 92.47,92.46 92.29,92.27 90.16,92.27 90.01,92.43 90.01,93.12 90.18,93.28 92.24,93.28
PBATT+_C on TOP (solid shape): 173.85,8.36 173.85,7.21 173.66,7.02 172.71,7.02 172.52,6.83 172.52,5.37 171.18,4.04 171.18,1.88 170.68,1.37 167.82,1.37 167.37,1.82 167.37,5.12 167.88,5.63 167.88,8.74 168.33,9.18 173.03,9.18
PBATT+_C on BOTTOM (solid shape): 172.52,8.86 172.52,5.37 171.18,4.04 171.18,1.88 170.68,1.37 167.82,1.37 167.37,1.82 167.37,5.12 167.88,5.63 167.88,8.74 168.33,9.18 172.2,9.18
REGCTL_PNP10 on TOP (solid shape): 232.33,89.45 232.33,89.1 233.75,87.68 235.21,87.68 235.25,87.64 235.25,87.47 235.2,87.43 232.93,87.43 232.22,88.14 231.82,88.14 231.5,88.47 231.5,89.49 231.6,89.6 232.19,89.6
RING2 on TOP (solid shape): 263.23,41.07 262.09,39.93 262.09,38.51 262.04,38.46 261.91,38.46 261.86,38.51 261.86,41.2 261.71,41.35 261.71,41.86 261.73,41.88 263.23,41.88
RING2 on TOP (solid shape): 267.72,41.79 267.72,40.64 267.64,40.56 266.75,40.56 266.61,40.7 266.61,41.76 266.72,41.86 267.65,41.86
RING2 on IN2 (solid shape): 267.73,41.76 267.73,40.56 267.27,40.11 264.25,40.11 264.25,40.11 261.99,40.11 261.86,40.23 261.86,41.06 262.05,41.25 264.94,41.25 265.57,41.87 267.61,41.87
RING2_R on TOP (solid shape): 270.79,57.15 270.79,56.12 269.99,55.32 268.86,55.32 268.77,55.42 268.77,56.58 269.69,57.51 270.43,57.51
RING2_R on TOP (solid shape): 281.08,57.36 281.08,56.55 280.86,56.34 278.92,56.34 278.36,56.89 278.36,58.16 278.62,58.42 280.02,58.42
RING2_R on TOP (solid shape): 269.29,43.86 269.29,42.03 269.15,41.89 268.5,41.89 268.32,42.07 268.32,43.41 267.89,43.84 267.89,44.17 267.95,44.23 268.92,44.23
RING2_R on IN1 (solid shape): 269.14,44.77 269.14,43.78 269.03,43.67 268.03,43.67 267.46,44.24 267.46,45.08 267.95,45.57 268.34,45.57
RING2_R on IN1: 278.85,56.37 280.9,56.37 281.08,56.55 281.08,57.39 279.98,58.48 278.44,58.48 278.24,58.29 278.24,56.98
SLEEVE on TOP (solid shape): 264.3,45.46 264.3,44.93 263.98,44.61 263.53,44.61 263.33,44.41 261.73,44.41 261.54,44.22 261.54,42.18 261.54,42.18 261.54,41.31 261.73,41.12 261.73,39.41 261.67,39.34 261.67,38.52 261.61,38.46 261.54,38.46 261.48,38.52 261.48,38.71 261.53,38.75 261.53,39.67 261.42,39.78 261.42,40.15 261.25,40.32 261.25,40.71 260.52,41.43 260.52,44.79 261.38,45.65 264.12,45.65
SLEEVE on BOTTOM (solid shape): 276.1,39.74 276.1,38.74 275.96,38.6 274.87,38.6 274.53,38.93 274.53,39.91 274.53,39.97 274.58,40.02 275.83,40.02
SLEEVE on IN4 (solid shape): 263.01,47.08 263.01,45.28 262.78,45.06 261.79,45.06 261.48,45.37 261.48,47.07 261.69,47.28 262.8,47.28
SLEEVE on IN4 (solid shape): 276.1,39.21 276.1,38.68 275.59,38.18 274.24,38.18 274.14,38.27 274.14,39.44 274.28,39.57 275.74,39.57
SLEEVE_R on BOTTOM (solid shape): 281.84,47.13 281.84,45.69 280.43,44.28 278.44,44.28 276.98,42.82 275.34,42.82 274.32,41.79 274.32,39.27 274.2,39.16 273.42,39.16 273.21,39.36 273.21,42.7 274.12,43.61 276.32,43.61 280.14,47.43 281.53,47.43
SNB_1.05V on TOP (solid shape): 192.1,64.14 192.1,62.78 192.14,62.74 192.14,61.76 191.95,61.57 191.06,61.57 191.06,64.11 191.12,64.17 192.07,64.17
SNUB_1.35V on TOP (solid shape): 201.92,9.05 201.92,7.66 201.74,7.49 201.09,7.49 201.09,8.29 200.71,8.67 199.57,8.67 199.57,9.69 201.28,9.69
SNUB_3V on TOP (solid shape): 206.24,64.62 206.24,63.09 206.17,63.03 204.27,63.03 204.14,63.16 204.14,64.05 204.84,64.74 206.11,64.74
SNUB_5V on TOP (solid shape): 200.77,63.86 200.77,62.97 200.65,62.84 198.74,62.84 198.68,62.9 198.68,64.43 198.74,64.49 200.14,64.49
SW1 on TOP (solid shape): 197.16,64.49 197.16,62.59 197.66,62.08 199.82,62.08 199.95,61.95 199.95,58.39 199.25,57.7 197.47,57.7 197.35,57.82 197.35,58.71 196.01,60.05 196.01,64.49 196.08,64.55 197.09,64.55
SW1 on TOP (solid shape): 197.41,50.14 198.3,50.14 198.43,50.01 199.57,50.01 199.63,49.95 199.63,49.82 199.57,49.76 198.43,49.76 198.04,49.38 196.58,49.38 196.52,49.44 196.52,50.27 196.58,50.33 197.22,50.33
SW1 on BOTTOM (solid shape): 200.84,61.32 200.84,57.25 200.2,56.62 196.46,56.62 196.39,56.68 196.39,59.6 196.14,59.85 196.14,61.32 196.58,61.76 200.39,61.76
SW1 on IN1 (solid shape): 199.63,60.3 199.63,59.09 199.31,58.78 198.62,58.78 198.43,58.97 198.43,60.3 198.55,60.43 199.5,60.43
SW1 on IN1 (solid shape): 197.35,50.84 197.47,50.84 197.98,50.33 198.11,50.33 198.43,50.01 198.43,49.76 198.3,49.63 197.09,49.63 196.46,50.27 196.46,50.77 196.71,51.03 197.16,51.03
SW2 on TOP (solid shape): 205.98,50.65 205.98,49.89 205.88,49.79 203.93,49.79 203.71,49.57 202.93,49.57 202.74,49.76 201.66,49.76 201.6,49.82 201.6,49.95 201.66,50.01 203.25,50.01 204.01,50.77 205.85,50.77
SW2 on TOP (solid shape): 209.03,64.62 209.03,62.59 209.47,62.14 209.47,58.58 208.59,57.7 206.68,57.7 206.49,57.89 206.49,58.97 205.98,59.47 205.28,59.47 205.09,59.66 205.09,62.01 205.41,62.33 207.38,62.33 207.63,62.59 207.63,64.55 207.82,64.74 208.9,64.74
SW2 on BOTTOM (solid shape): 209,61.22 209,58.49 207.19,56.68 203.82,56.68 203.81,56.69 203.81,58.99 203.85,59.03 204.58,59.03 204.97,59.41 204.97,61.76 205.22,62.01 208.2,62.01
SW2 on IN1 (solid shape): 208.78,60.17 208.78,58.9 208.33,58.46 207.63,58.46 207.44,58.65 207.44,59.92 207.82,60.3 208.65,60.3
SW2 on IN1 (solid shape): 205.73,51.47 205.73,51.35 205.79,51.35 205.79,50.84 205.09,50.14 203.89,50.14 203.7,50.33 203.7,50.77 203.89,50.96 204.46,50.96 205.09,51.6 205.6,51.6
SW_1.35V on TOP (solid shape): 189.85,9.44 189.85,8.61 189.6,8.36 188.2,8.36 187.63,7.78 187.25,7.78 187.19,7.85 187.19,8.61 187.25,8.67 187.44,8.67 187.69,8.93 188.52,8.93 189.09,9.5 189.79,9.5
